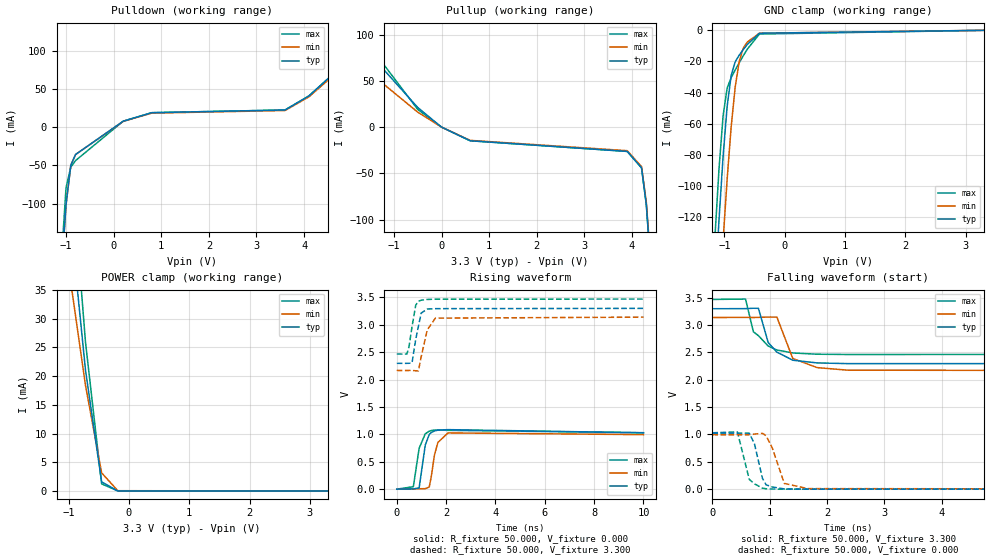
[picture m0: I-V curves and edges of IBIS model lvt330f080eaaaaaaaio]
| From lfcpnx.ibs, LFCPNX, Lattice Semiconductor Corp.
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[Model] lvt330f080eaaaaaaaio
Model_type I/O
Polarity   Non-Inverting
Enable   Active-Low
Vinl =  0.800V
Vinh =  2.000V
Vmeas =  1.650V
Cref =  0.0F
Rref =  1.000M
Vref =  0.0V
C_comp   5.000pF   4.000pF   5.500pF
[Temperature Range]   25.000   0.125k   -40.000
[Voltage Range]   3.300V   3.140V   3.470V
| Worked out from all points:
|   slope of the pulldown table from 0 to 0.495 V, typ, clamps not added: 31.5 ohm
|   slope of the pullup table from 0 to 0.495 V, typ, clamps not added: 39 ohm
|   GND clamp passes 1 mA (typ) near -0.37 V on its own axis
|   POWER clamp passes 1 mA (typ) near -0.42 V on its own axis
|   rising waveform, R_fixture 50.000, V_fixture 0.000: 20-80 % time 189ps typ, 233ps min, 215ps max; typ from 0 V to 1.03 V
|   rising waveform, R_fixture 50.000, V_fixture 3.300: 20-80 % time 231ps typ, 297ps min, 205ps max; typ from 2.3 V to 3.3 V
|   falling waveform, R_fixture 50.000, V_fixture 3.300: 20-80 % time 274ps typ, 223ps min, 282ps max; typ from 3.3 V to 2.3 V
|   falling waveform, R_fixture 50.000, V_fixture 0.000: 20-80 % time 135ps typ, 175ps min, 139ps max; typ from 1.02 V to 0 V
[GND_clamp]
|Voltage   I(typ)   I(min)   I(max)
-3.3V     -1.887A    -1.873A    -1.902A
-1.156V   -166.9mA   -224mA     -132.1mA
-1.089V   -121.5mA   -178.4mA   -88.64mA
-1.022V   -81.05mA   -135.2mA   -54.94mA
-955mV    -48.98mA   -95.79mA   -37.15mA
-888mV    -28.98mA   -62.05mA   -30.42mA
-821mV    -20.23mA   -36.35mA   -25.49mA
-754mV    -15.89mA   -19.89mA   -20.81mA
-687mV    -12.34mA   -11.44mA   -16.31mA
-620mV    -9.094mA   -7.515mA   -12.09mA
-419mV    -1.869mA   -1.836mA   -2.383mA
3.3V      0A         0A         0A
[POWER_clamp]
|Voltage   I(typ)   I(min)   I(max)
-3.3V     170.3mA    115.9mA    227.4mA
-2.998V   139.6mA    100.3mA    196.3mA
-2.797V   125.9mA    92.2mA     179.4mA
-2.596V   123.5mA    86.45mA    171.5mA
-1.993V   123.5mA    84.93mA    171.5mA
-1.792V   123.5mA    84.93mA    159.6mA
-1.658V   116.4mA    83.68mA    147.1mA
-1.457V   98.28mA    72.65mA    124.1mA
-720mV    21.08mA    18.41mA    25.96mA
-452mV    1.573mA    3.148mA    1.229mA
-184mV    5.589uA    37.85uA    1.612uA
3.3V      0A         0A         0A
[Pulldown]
|Voltage   I(typ)   I(min)   I(max)
-3.3V     -3.025A    -3.025A    -3.918A
-1.1V     -192.9mA   -192.9mA   -175.3mA
-1V       -101.2mA   -101.2mA   -78.95mA
-900mV    -49.86mA   -49.86mA   -52.21mA
-800mV    -35.81mA   -35.81mA   -43.74mA
200mV     7.775mA    7.542mA    7.775mA
800mV     18.91mA    18.34mA    18.91mA
3.6V      22.45mA    21.77mA    22.45mA
4.1V      40.8mA     39.58mA    40.8mA
5.4V      113.7mA    110.3mA    113.7mA
6.1V      131.6mA    127.7mA    131.6mA
6.6V      184.5mA    179mA      184.5mA
[Pullup]
|Voltage   I(typ)   I(min)   I(max)
-3.3V     161.3mA    100.5mA    206.1mA
-2.7V     107.3mA    82.8mA     139.1mA
-2.1V     105.4mA    77.74mA    116.8mA
-1.8V     95.7mA     71.14mA    107.4mA
-500mV    21.21mA    16.16mA    19.08mA
0V        28.62nA    228.6nA    28.62nA
600mV     -14.73mA   -14.29mA   -14.73mA
3.9V      -26.24mA   -25.45mA   -26.24mA
4.2V      -44.05mA   -42.73mA   -44.05mA
4.3V      -83.6mA    -81.1mA    -83.6mA
4.4V      -155.9mA   -151.2mA   -155.9mA
6.6V      -2.415A    -2.343A    -2.415A
[Ramp]
| variable   typ   min   max
dV/dt_r   0.619/0.189n   0.598/0.239n   0.634/0.215n
dV/dt_f   0.602/0.274n   0.584/0.222n   0.602/0.283n
R_load = 50.000
[Rising Waveform]
R_fixture = 50.000
V_fixture = 0.000
V_fixture_min = 0.000
V_fixture_max = 0.000
|  time   V(typ)   V(min)   V(max)
0s        488.9uV    1.198mV    488.9uV
672ps     5.302mV    1.318mV    45.99mV
906ps     23.45mV    8.626mV    746.7mV
1.155ns   806.3mV    9.222mV    1.011V
1.316ns   998.5mV    38.7mV     1.059V
1.396ns   1.034V     225.5mV    1.07V
1.526ns   1.063V     621.8mV    1.078V
1.666ns   1.077V     852.9mV    1.081V
2.076ns   1.087V     1.027V     1.074V
10ns      1.029V     995.8mV    1.031V
[Rising Waveform]
R_fixture = 50.000
V_fixture = 3.300
V_fixture_min = 3.140
V_fixture_max = 3.470
|  time   V(typ)   V(min)   V(max)
0s        2.297V     2.167V     2.467V
409ps     2.297V     2.166V     2.466V
497ps     2.298V     2.167V     2.603V
618ps     2.305V     2.168V     2.966V
768ps     2.735V     2.161V     3.359V
876ps     2.969V     2.159V     3.429V
988ps     3.213V     2.413V     3.449V
1.236ns   3.288V     2.909V     3.463V
1.566ns   3.295V     3.122V     3.468V
10ns      3.3V       3.14V      3.47V
[Falling Waveform]
R_fixture = 50.000
V_fixture = 3.300
V_fixture_min = 3.140
V_fixture_max = 3.470
|  time   V(typ)   V(min)   V(max)
0s        3.3V       3.14V      3.47V
579ps     3.302V     3.141V     3.477V
716ps     3.309V     3.14V      2.878V
804ps     3.307V     3.142V     2.807V
974ps     2.682V     3.148V     2.618V
1.126ns   2.507V     3.147V     2.545V
1.404ns   2.358V     2.389V     2.491V
1.829ns   2.309V     2.223V     2.468V
2.368ns   2.296V     2.176V     2.463V
10ns      2.297V     2.167V     2.467V
[Falling Waveform]
R_fixture = 50.000
V_fixture = 0.000
V_fixture_min = 0.000
V_fixture_max = 0.000
|  time   V(typ)   V(min)   V(max)
0s        1.024V     995.8mV    1.031V
437ps     1.024V     995.3mV    1.047V
644ps     1.024V     995.7mV    177.8mV
735ps     827.8mV    1.007V     97.26mV
874ps     198.8mV    1.021V     18.01mV
936ps     80.74mV    978.4mV    7.393mV
1.042ns   39.99mV    763.6mV    1.796mV
1.256ns   3.849mV    104.5mV    -164.9uV
1.666ns   265.6uV    9.589mV    -511.1uV
10ns      342.9uV    1.198mV    488.9uV
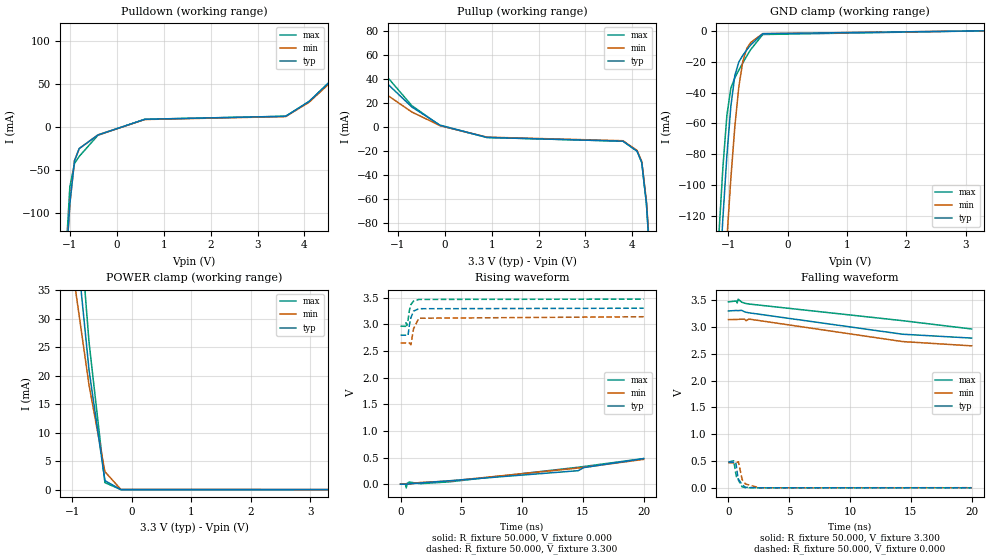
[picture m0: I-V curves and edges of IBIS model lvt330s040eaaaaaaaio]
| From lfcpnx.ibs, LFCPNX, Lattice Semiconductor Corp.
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[Model] lvt330s040eaaaaaaaio
Model_type I/O
Polarity   Non-Inverting
Enable   Active-Low
Vinl =  0.800V
Vinh =  2.000V
Vmeas =  1.650V
Cref =  0.0F
Rref =  1.000M
Vref =  0.0V
C_comp   5.000pF   4.000pF   5.500pF
[Temperature Range]   25.000   0.125k   -40.000
[Voltage Range]   3.300V   3.140V   3.470V
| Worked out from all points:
|   slope of the pulldown table from 0 to 0.495 V, typ, clamps not added: 60 ohm
|   slope of the pullup table from 0 to 0.495 V, typ, clamps not added: 81.7 ohm
|   GND clamp passes 1 mA (typ) near -0.37 V on its own axis
|   POWER clamp passes 1 mA (typ) near -0.42 V on its own axis
|   rising waveform, R_fixture 50.000, V_fixture 0.000: 20-80 % time 10.6ns typ, 11.1ns min, 10.8ns max; typ from 0.001 V to 0.481 V
|   rising waveform, R_fixture 50.000, V_fixture 3.300: 20-80 % time 278ps typ, 325ps min, 243ps max; typ from 2.79 V to 3.3 V
|   falling waveform, R_fixture 50.000, V_fixture 3.300: 20-80 % time 9.24ns typ, 8.7ns min, 11.8ns max; typ from 3.3 V to 2.79 V
|   falling waveform, R_fixture 50.000, V_fixture 0.000: 20-80 % time 340ps typ, 298ps min, 354ps max; typ from 0.481 V to 0.001 V
[GND_clamp]
|Voltage   I(typ)   I(min)   I(max)
-3.3V     -1.887A    -1.873A    -1.902A
-1.156V   -166.9mA   -224mA     -132.1mA
-1.089V   -121.5mA   -178.4mA   -88.64mA
-1.022V   -81.05mA   -135.2mA   -54.94mA
-955mV    -48.98mA   -95.79mA   -37.15mA
-888mV    -28.98mA   -62.05mA   -30.42mA
-821mV    -20.23mA   -36.35mA   -25.49mA
-754mV    -15.89mA   -19.89mA   -20.81mA
-687mV    -12.34mA   -11.44mA   -16.31mA
-620mV    -9.094mA   -7.515mA   -12.09mA
-419mV    -1.869mA   -1.836mA   -2.383mA
3.3V      0A         0A         0A
[POWER_clamp]
|Voltage   I(typ)   I(min)   I(max)
-3.3V     170.3mA    115.9mA    227.4mA
-2.998V   139.6mA    100.3mA    196.3mA
-2.797V   125.9mA    92.2mA     179.4mA
-2.596V   123.5mA    86.45mA    171.5mA
-1.993V   123.5mA    84.93mA    171.5mA
-1.792V   123.5mA    84.93mA    159.6mA
-1.658V   116.4mA    83.68mA    147.1mA
-1.457V   98.28mA    72.65mA    124.1mA
-720mV    21.08mA    18.41mA    25.96mA
-452mV    1.573mA    3.148mA    1.229mA
-184mV    5.589uA    37.85uA    1.612uA
3.3V      0A         0A         0A
[Pulldown]
|Voltage   I(typ)   I(min)   I(max)
-3.3V     -2.819A    -2.819A    -3.761A
-1.1V     -176.5mA   -176.5mA   -165mA
-1V       -89.5mA    -89.5mA    -70.05mA
-900mV    -39.31mA   -39.31mA   -42.55mA
-800mV    -25.23mA   -25.23mA   -34.36mA
-400mV    -9.281mA   -9.281mA   -9.631mA
600mV     8.924mA    8.657mA    8.924mA
3.6V      12.44mA    12.06mA    12.44mA
4.1V      29.71mA    28.82mA    29.71mA
5.4V      97.6mA     94.7mA     97.6mA
6.2V      121.3mA    117.7mA    121.3mA
6.6V      164mA      159.1mA    164mA
[Pullup]
|Voltage   I(typ)   I(min)   I(max)
-3.3V     109.3mA    67.7mA     140.2mA
-3V       86.1mA     60.5mA     117.8mA
-2V       65.1mA     47.62mA    77.3mA
-700mV    16.69mA    12.48mA    17.82mA
-100mV    1.509mA    1.116mA    1.148mA
900mV     -8.797mA   -8.533mA   -8.797mA
3.8V      -11.91mA   -11.55mA   -11.91mA
4.1V      -20.24mA   -19.64mA   -20.24mA
4.2V      -29.72mA   -28.83mA   -29.72mA
4.3V      -64.2mA    -62.3mA    -64.2mA
4.4V      -124.9mA   -121.2mA   -124.9mA
6.6V      -1.98A     -1.92A     -1.98A
[Ramp]
| variable   typ   min   max
dV/dt_r   0.288/10.429n   0.278/11.102n   0.288/10.769n
dV/dt_f   0.304/9.264n   0.295/8.716n   0.304/11.811n
R_load = 50.000
[Rising Waveform]
R_fixture = 50.000
V_fixture = 0.000
V_fixture_min = 0.000
V_fixture_max = 0.000
|  time   V(typ)   V(min)   V(max)
0s        707.6uV    2.066mV    707.6uV
395ps     834.9uV    1.474mV    3.679mV
474ps     984.1uV    1.992mV    -67.5mV
548ps     2.012mV    2.189mV    18.51mV
716ps     6.953mV    2.83mV     41.63mV
1.616ns   23.71mV    33.92mV    10.96mV
4.056ns   66.05mV    60.85mV    45.64mV
14.61ns   254.4mV    303.7mV    318.9mV
15.09ns   313.3mV    317.3mV    333.4mV
20ns      481mV      466.2mV    481.4mV
[Rising Waveform]
R_fixture = 50.000
V_fixture = 3.300
V_fixture_min = 3.140
V_fixture_max = 3.470
|  time   V(typ)   V(min)   V(max)
0s        2.794V     2.649V     2.964V
403ps     2.794V     2.648V     2.959V
454ps     2.794V     2.649V     3.028V
517ps     2.793V     2.649V     2.975V
617ps     2.788V     2.649V     3.071V
727ps     2.982V     2.65V      3.258V
856ps     3.123V     2.615V     3.369V
1.072ns   3.246V     2.915V     3.434V
1.506ns   3.29V      3.112V     3.464V
20ns      3.3V       3.14V      3.47V
[Falling Waveform]
R_fixture = 50.000
V_fixture = 3.300
V_fixture_min = 3.140
V_fixture_max = 3.470
|  time   V(typ)   V(min)   V(max)
0s        3.3V       3.14V      3.47V
669ps     3.31V      3.141V     3.487V
718ps     3.308V     3.141V     3.45V
799ps     3.306V     3.143V     3.521V
1.088ns   3.312V     3.147V     3.465V
1.339ns   3.283V     3.146V     3.445V
1.446ns   3.276V     3.118V     3.439V
1.686ns   3.266V     3.149V     3.43V
14.32ns   2.866V     2.729V     3.119V
20ns      2.794V     2.649V     2.964V
[Falling Waveform]
R_fixture = 50.000
V_fixture = 0.000
V_fixture_min = 0.000
V_fixture_max = 0.000
|  time   V(typ)   V(min)   V(max)
0s        481mV      466.2mV    481.4mV
433ps     476.6mV    465.6mV    503.8mV
587ps     485.1mV    465.4mV    290.4mV
653ps     399.2mV    466.5mV    208.5mV
750ps     240.2mV    480.1mV    208.8mV
826ps     160.9mV    486.9mV    140.3mV
1.124ns   57.76mV    154.8mV    18.67mV
1.398ns   9.89mV     70.36mV    1.886mV
2.569ns   -5.161uV   372.8uV    -949.1uV
20ns      707.6uV    2.066mV    707.6uV
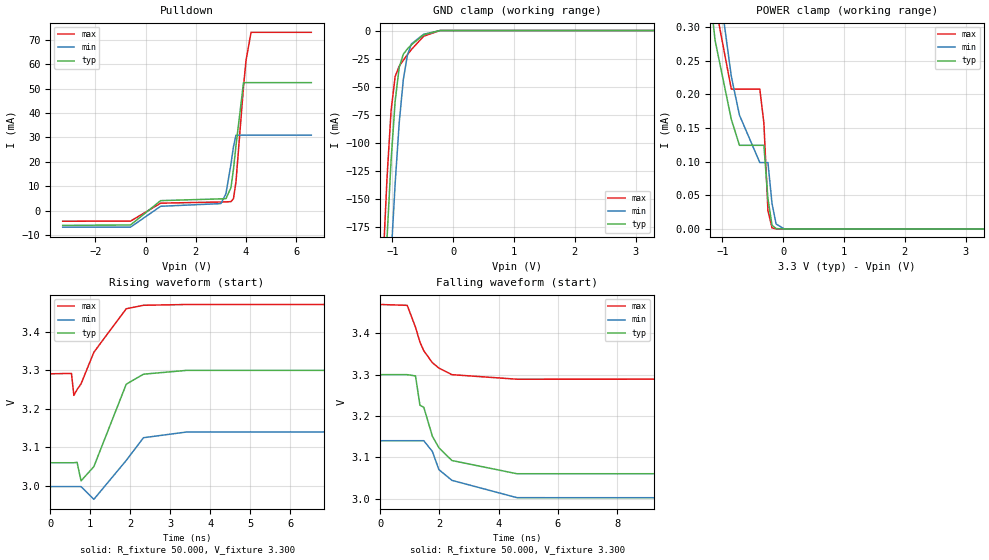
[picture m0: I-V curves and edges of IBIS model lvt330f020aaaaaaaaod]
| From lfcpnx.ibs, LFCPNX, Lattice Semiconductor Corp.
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[Model] lvt330f020aaaaaaaaod
Model_type I/O_open_drain
Polarity   Non-Inverting
Enable   Active-Low
Vinl =  0.800V
Vinh =  2.000V
Vmeas =  1.650V
Cref =  0.0F
Rref = 10.00k
Vref = 3.30V
C_comp   5.000pF   4.000pF   5.500pF
[Temperature Range]   25.000   0.125k   -40.000
[Voltage Range]   3.300V   3.140V   3.470V
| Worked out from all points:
|   slope of the pulldown table from 0 to 0.495 V, typ, clamps not added: 109 ohm
|   GND clamp passes 1 mA (typ) near -0.37 V on its own axis
|   POWER clamp passes 1 mA (typ) near -1.97 V on its own axis
|   rising waveform, R_fixture 50.000, V_fixture 3.300: 20-80 % time 481ps typ, 398ps min, 476ps max; typ from 3.06 V to 3.3 V
|   falling waveform, R_fixture 50.000, V_fixture 3.300: 20-80 % time 877ps typ, 983ps min, 662ps max; typ from 3.3 V to 3.06 V
[Pulldown]
|Voltage   I(typ)   I(min)   I(max)
-3.3V     -6.1mA     -6.828mA   -4.397mA
-600mV    -5.938mA   -6.828mA   -4.356mA
600mV     4.055mA    1.736mA    3.013mA
3V        4.784mA    2.841mA    3.498mA
3.2V      4.869mA    6.91mA     3.547mA
3.4V      9.372mA    19.03mA    3.637mA
3.5V      16.94mA    26.16mA    4.859mA
3.6V      26.54mA    30.91mA    11.78mA
3.9V      52.48mA    30.91mA    50.88mA
4V        52.48mA    30.91mA    61.61mA
4.2V      52.48mA    30.91mA    73.11mA
6.6V      52.48mA    30.91mA    73.11mA
[GND_clamp]
|Voltage   I(typ)   I(min)   I(max)
-3.3V     -3.196A    -3.085A    -3.285A
-1.156V   -263.4mA   -349.2mA   -208.8mA
-1.089V   -185mA     -273mA     -131.1mA
-1.022V   -115.6mA   -200.9mA   -71.22mA
-955mV    -62.66mA   -135.8mA   -40.8mA
-888mV    -32.65mA   -81.84mA   -31.68mA
-821mV    -21.14mA   -43.74mA   -26.44mA
-754mV    -16.35mA   -21.98mA   -21.55mA
-687mV    -12.66mA   -11.95mA   -16.87mA
-486mV    -3.804mA   -3.298mA   -5.059mA
-218mV    -16.55uA   -69.58uA   -6.785uA
3.3V      0A         0A         0A
[POWER_clamp]
|Voltage   I(typ)   I(min)   I(max)
-3.3V     35.46mA    6.588mA    71.29mA
-1.256V   395.7uA    489.5uA    429.4uA
-1.122V   280.6uA    406.7uA    335.7uA
-854mV    162.9uA    226.8uA    207.8uA
-720mV    124.3uA    169.1uA    207.8uA
-385mV    124.3uA    98.63uA    207.8uA
-318mV    124.3uA    98.63uA    157.6uA
-251mV    44.78uA    98.63uA    27.33uA
-184mV    5.589uA    37.86uA    1.613uA
-117mV    514.3nA    7.403uA    125nA
17mV      25.29nA    128.2nA    39.1nA
3.3V      0A         0A         0A
[Ramp]
| variable   typ   min   max
dV/dt_r   0.144/0.483n   85.097m/0.400n   0.107/0.480n
dV/dt_f   0.144/0.877n   85.101m/0.983n   0.107/0.673n
R_load = 50.000
[Rising Waveform]
R_fixture= 50.000
V_fixture= 3.300
V_fixture_min= 3.140
V_fixture_max= 3.470
|time   V(typ)   V(min)   V(max)
0s        3.06V      2.998V     3.291V
530ps     3.06V      2.998V     3.292V
590ps     3.06V      2.998V     3.235V
670ps     3.061V     2.998V     3.25V
770ps     3.013V     2.998V     3.265V
1.09ns    3.05V      2.965V     3.347V
1.9ns     3.264V     3.066V     3.46V
2.33ns    3.29V      3.125V     3.469V
3.42ns    3.3V       3.14V      3.471V
200ns     3.3V       3.14V      3.47V
[Falling Waveform]
R_fixture= 50.000
V_fixture= 3.300
V_fixture_min= 3.140
V_fixture_max= 3.470
|time   V(typ)   V(min)   V(max)
0s        3.3V       3.14V      3.47V
910ps     3.3V       3.14V      3.468V
1.19ns    3.297V     3.14V      3.415V
1.34ns    3.226V     3.14V      3.379V
1.47ns    3.221V     3.14V      3.358V
1.76ns    3.151V     3.114V     3.329V
1.98ns    3.123V     3.07V      3.316V
2.42ns    3.092V     3.044V     3.3V
4.62ns    3.06V      3.002V     3.289V
200ns     3.06V      2.998V     3.291V
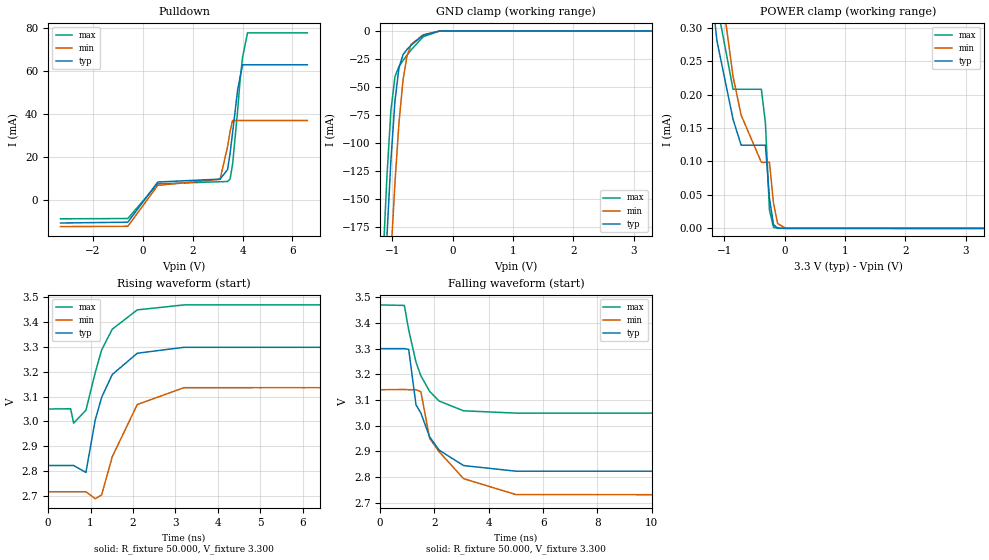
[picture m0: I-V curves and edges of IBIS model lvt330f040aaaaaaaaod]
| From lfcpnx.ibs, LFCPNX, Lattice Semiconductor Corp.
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[Model] lvt330f040aaaaaaaaod
Model_type I/O_open_drain
Polarity   Non-Inverting
Enable   Active-Low
Vinl =  0.800V
Vinh =  2.000V
Vmeas =  1.650V
Cref =  0.0F
Rref = 10.00k
Vref = 3.30V
C_comp   5.000pF   4.000pF   5.500pF
[Temperature Range]   25.000   0.125k   -40.000
[Voltage Range]   3.300V   3.140V   3.470V
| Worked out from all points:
|   slope of the pulldown table from 0 to 0.495 V, typ, clamps not added: 58.8 ohm
|   GND clamp passes 1 mA (typ) near -0.37 V on its own axis
|   POWER clamp passes 1 mA (typ) near -1.97 V on its own axis
|   rising waveform, R_fixture 50.000, V_fixture 3.300: 20-80 % time 553ps typ, 632ps min, 530ps max; typ from 2.82 V to 3.3 V
|   falling waveform, R_fixture 50.000, V_fixture 3.300: 20-80 % time 932ps typ, 1.33ns min, 830ps max; typ from 3.3 V to 2.82 V
[Pulldown]
|Voltage   I(typ)   I(min)   I(max)
-3.3V     -10.75mA   -12.42mA   -8.803mA
-600mV    -10.38mA   -12.29mA   -8.676mA
600mV     8.285mA    6.713mA    7.445mA
3.1V      9.636mA    9.533mA    8.415mA
3.4V      14.05mA    24.72mA    8.529mA
3.5V      21.55mA    31.81mA    9.666mA
3.6V      31.11mA    36.84mA    16.44mA
3.8V      50.78mA    36.84mA    40.96mA
3.9V      56.98mA    36.84mA    55.4mA
4V        62.74mA    36.84mA    66.09mA
4.2V      62.74mA    36.84mA    77.58mA
6.6V      62.74mA    36.84mA    77.58mA
[GND_clamp]
|Voltage   I(typ)   I(min)   I(max)
-3.3V     -3.196A    -3.085A    -3.285A
-1.156V   -263.4mA   -349.2mA   -208.8mA
-1.089V   -185mA     -273mA     -131.1mA
-1.022V   -115.6mA   -200.9mA   -71.22mA
-955mV    -62.66mA   -135.8mA   -40.8mA
-888mV    -32.65mA   -81.84mA   -31.68mA
-821mV    -21.14mA   -43.74mA   -26.44mA
-754mV    -16.35mA   -21.98mA   -21.55mA
-687mV    -12.66mA   -11.95mA   -16.87mA
-486mV    -3.804mA   -3.298mA   -5.059mA
-218mV    -16.55uA   -69.58uA   -6.785uA
3.3V      0A         0A         0A
[POWER_clamp]
|Voltage   I(typ)   I(min)   I(max)
-3.3V     35.46mA    6.588mA    71.29mA
-1.256V   395.7uA    489.5uA    429.4uA
-1.122V   280.6uA    406.7uA    335.7uA
-854mV    162.9uA    226.8uA    207.8uA
-720mV    124.3uA    169.1uA    207.8uA
-385mV    124.3uA    98.63uA    207.8uA
-318mV    124.3uA    98.63uA    157.6uA
-251mV    44.78uA    98.63uA    27.33uA
-184mV    5.589uA    37.86uA    1.613uA
-117mV    514.3nA    7.403uA    125nA
17mV      25.29nA    128.2nA    39.1nA
3.3V      0A         0A         0A
[Ramp]
| variable   typ   min   max
dV/dt_r   0.287/0.551n   0.254/0.629n   0.252/0.533n
dV/dt_f   0.287/0.938n   0.254/1.339n   0.252/0.833n
R_load = 50.000
[Rising Waveform]
R_fixture= 50.000
V_fixture= 3.300
V_fixture_min= 3.140
V_fixture_max= 3.470
|time   V(typ)   V(min)   V(max)
0s        2.822V     2.716V     3.05V
530ps     2.822V     2.716V     3.051V
600ps     2.822V     2.716V     2.993V
890ps     2.794V     2.716V     3.045V
1.11ns    3.006V     2.688V     3.197V
1.26ns    3.097V     2.703V     3.288V
1.51ns    3.189V     2.857V     3.372V
2.1ns     3.275V     3.068V     3.45V
3.2ns     3.299V     3.136V     3.47V
200ns     3.3V       3.14V      3.47V
[Falling Waveform]
R_fixture= 50.000
V_fixture= 3.300
V_fixture_min= 3.140
V_fixture_max= 3.470
|time   V(typ)   V(min)   V(max)
0s        3.3V       3.14V      3.47V
890ps     3.3V       3.141V     3.468V
1.05ns    3.297V     3.14V      3.373V
1.32ns    3.081V     3.14V      3.247V
1.5ns     3.049V     3.132V     3.194V
1.82ns    2.957V     2.951V     3.134V
2.17ns    2.905V     2.899V     3.096V
3.07ns    2.845V     2.794V     3.058V
5ns       2.823V     2.732V     3.049V
200ns     2.822V     2.716V     3.05V
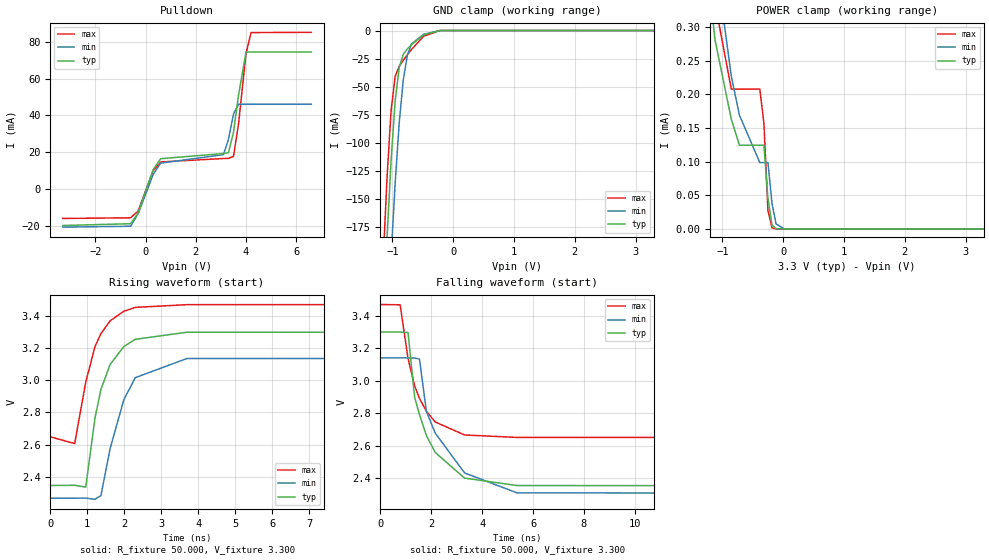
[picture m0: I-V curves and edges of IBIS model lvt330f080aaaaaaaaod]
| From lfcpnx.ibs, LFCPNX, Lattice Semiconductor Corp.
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[Model] lvt330f080aaaaaaaaod
Model_type I/O_open_drain
Polarity   Non-Inverting
Enable   Active-Low
Vinl =  0.800V
Vinh =  2.000V
Vmeas =  1.650V
Cref =  0.0F
Rref = 10.00k
Vref = 3.30V
C_comp   5.000pF   4.000pF   5.500pF
[Temperature Range]   25.000   0.125k   -40.000
[Voltage Range]   3.300V   3.140V   3.470V
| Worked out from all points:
|   slope of the pulldown table from 0 to 0.495 V, typ, clamps not added: 31.5 ohm
|   GND clamp passes 1 mA (typ) near -0.37 V on its own axis
|   POWER clamp passes 1 mA (typ) near -1.97 V on its own axis
|   rising waveform, R_fixture 50.000, V_fixture 3.300: 20-80 % time 554ps typ, 641ps min, 608ps max; typ from 2.35 V to 3.3 V
|   falling waveform, R_fixture 50.000, V_fixture 3.300: 20-80 % time 1.06ns typ, 1.55ns min, 918ps max; typ from 3.3 V to 2.35 V
[Pulldown]
|Voltage   I(typ)   I(min)   I(max)
-3.3V     -19.92mA   -20.81mA   -16.08mA
-600mV    -18.94mA   -20.31mA   -15.72mA
-300mV    -13.23mA   -13.68mA   -12.11mA
300mV     10.36mA    7.766mA    9.808mA
600mV     16.42mA    13.99mA    14.64mA
3.1V      19.21mA    18.6mA     16.51mA
3.3V      19.71mA    26.92mA    16.57mA
3.5V      30.71mA    40.56mA    17.63mA
3.7V      50.79mA    46mA       35.14mA
4V        74.37mA    46mA       73.51mA
4.2V      74.37mA    46mA       84.98mA
6.6V      74.37mA    46mA       85.11mA
[GND_clamp]
|Voltage   I(typ)   I(min)   I(max)
-3.3V     -3.196A    -3.085A    -3.285A
-1.156V   -263.4mA   -349.2mA   -208.8mA
-1.089V   -185mA     -273mA     -131.1mA
-1.022V   -115.6mA   -200.9mA   -71.22mA
-955mV    -62.66mA   -135.8mA   -40.8mA
-888mV    -32.65mA   -81.84mA   -31.68mA
-821mV    -21.14mA   -43.74mA   -26.44mA
-754mV    -16.35mA   -21.98mA   -21.55mA
-687mV    -12.66mA   -11.95mA   -16.87mA
-486mV    -3.804mA   -3.298mA   -5.059mA
-218mV    -16.55uA   -69.58uA   -6.785uA
3.3V      0A         0A         0A
[POWER_clamp]
|Voltage   I(typ)   I(min)   I(max)
-3.3V     35.46mA    6.588mA    71.29mA
-1.256V   395.9uA    489.5uA    429.4uA
-1.122V   280.8uA    406.7uA    335.7uA
-854mV    163uA      226.8uA    207.8uA
-720mV    124.4uA    169.1uA    207.8uA
-385mV    124.4uA    98.63uA    207.8uA
-318mV    124.4uA    98.63uA    157.6uA
-251mV    44.78uA    98.63uA    27.33uA
-184mV    5.589uA    37.86uA    1.613uA
-117mV    514.3nA    7.403uA    125nA
17mV      25.29nA    128.2nA    39.1nA
3.3V      0A         0A         0A
[Ramp]
| variable   typ   min   max
dV/dt_r   0.572/0.555n   0.523/0.639n   0.493/0.609n
dV/dt_f   0.572/1.070n   0.523/1.557n   0.493/0.921n
R_load = 50.000
[Rising Waveform]
R_fixture= 50.000
V_fixture= 3.300
V_fixture_min= 3.140
V_fixture_max= 3.470
|time   V(typ)   V(min)   V(max)
0s        2.347V     2.268V     2.649V
660ps     2.348V     2.268V     2.607V
960ps     2.337V     2.269V     2.988V
1.21ns    2.766V     2.261V     3.209V
1.37ns    2.943V     2.284V     3.289V
1.62ns    3.098V     2.577V     3.369V
1.99ns    3.209V     2.879V     3.428V
2.3ns     3.254V     3.016V     3.452V
3.7ns     3.298V     3.135V     3.469V
200ns     3.3V       3.14V      3.47V
[Falling Waveform]
R_fixture= 50.000
V_fixture= 3.300
V_fixture_min= 3.140
V_fixture_max= 3.470
|time   V(typ)   V(min)   V(max)
0s        3.3V       3.14V      3.47V
780ps     3.3V       3.141V     3.468V
1.09ns    3.297V     3.14V      3.137V
1.35ns    2.897V     3.14V      2.968V
1.54ns    2.791V     3.133V     2.891V
1.81ns    2.662V     2.811V     2.811V
2.16ns    2.557V     2.676V     2.745V
3.31ns    2.399V     2.431V     2.665V
5.37ns    2.353V     2.308V     2.65V
200ns     2.347V     2.268V     2.649V
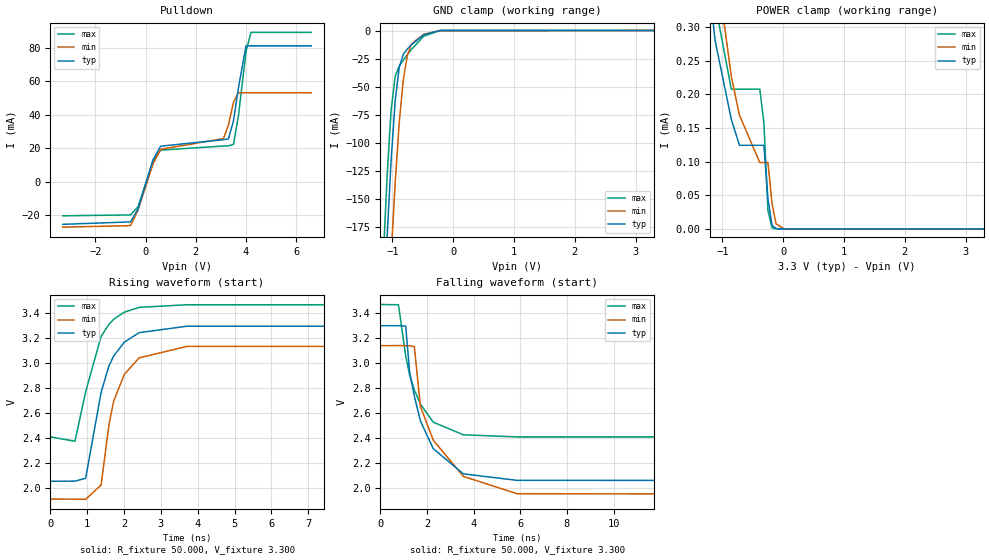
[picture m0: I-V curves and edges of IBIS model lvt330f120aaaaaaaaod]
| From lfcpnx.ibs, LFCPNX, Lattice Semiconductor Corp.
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[Model] lvt330f120aaaaaaaaod
Model_type I/O_open_drain
Polarity   Non-Inverting
Enable   Active-Low
Vinl =  0.800V
Vinh =  2.000V
Vmeas =  1.650V
Cref =  0.0F
Rref = 10.00k
Vref = 3.30V
C_comp   5.000pF   4.000pF   5.500pF
[Temperature Range]   25.000   0.125k   -40.000
[Voltage Range]   3.300V   3.140V   3.470V
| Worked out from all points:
|   slope of the pulldown table from 0 to 0.495 V, typ, clamps not added: 24.7 ohm
|   GND clamp passes 1 mA (typ) near -0.37 V on its own axis
|   POWER clamp passes 1 mA (typ) near -1.97 V on its own axis
|   rising waveform, R_fixture 50.000, V_fixture 3.300: 20-80 % time 609ps typ, 520ps min, 631ps max; typ from 2.05 V to 3.3 V
|   falling waveform, R_fixture 50.000, V_fixture 3.300: 20-80 % time 1.12ns typ, 1.56ns min, 970ps max; typ from 3.3 V to 2.05 V
[Pulldown]
|Voltage   I(typ)   I(min)   I(max)
-3.3V     -25.53mA   -27.22mA   -20.43mA
-600mV    -24.06mA   -26.3mA    -19.89mA
-300mV    -16.33mA   -16.99mA   -14.99mA
300mV     13.22mA    10.79mA    12.5mA
600mV     21.26mA    19.4mA     18.89mA
3.1V      25.16mA    25.81mA    21.38mA
3.3V      25.62mA    33.97mA    21.44mA
3.5V      36.41mA    47.57mA    22.42mA
3.7V      56.4mA     53.26mA    39.7mA
4V        81.32mA    53.26mA    77.97mA
4.2V      81.32mA    53.26mA    89.43mA
6.6V      81.32mA    53.26mA    89.43mA
[GND_clamp]
|Voltage   I(typ)   I(min)   I(max)
-3.3V     -3.196A    -3.085A    -3.285A
-1.156V   -263.4mA   -349.2mA   -208.8mA
-1.089V   -185mA     -273mA     -131.1mA
-1.022V   -115.6mA   -200.9mA   -71.22mA
-955mV    -62.66mA   -135.8mA   -40.8mA
-888mV    -32.65mA   -81.84mA   -31.68mA
-821mV    -21.14mA   -43.74mA   -26.44mA
-754mV    -16.35mA   -21.98mA   -21.55mA
-687mV    -12.66mA   -11.95mA   -16.87mA
-486mV    -3.804mA   -3.298mA   -5.059mA
-218mV    -16.55uA   -69.58uA   -6.785uA
3.3V      0A         0A         0A
[POWER_clamp]
|Voltage   I(typ)   I(min)   I(max)
-3.3V     35.46mA    6.588mA    71.29mA
-1.256V   395.7uA    489.5uA    429.4uA
-1.122V   280.6uA    406.7uA    335.7uA
-854mV    162.9uA    226.8uA    207.8uA
-720mV    124.3uA    169.1uA    207.8uA
-385mV    124.3uA    98.63uA    207.8uA
-318mV    124.3uA    98.63uA    157.6uA
-251mV    44.78uA    98.63uA    27.33uA
-184mV    5.589uA    37.86uA    1.613uA
-117mV    514.3nA    7.403uA    125nA
17mV      25.29nA    128.2nA    39.1nA
3.3V      0A         0A         0A
[Ramp]
| variable   typ   min   max
dV/dt_r   0.749/0.610n   0.739/0.520n   0.638/0.630n
dV/dt_f   0.749/1.123n   0.739/1.556n   0.637/0.973n
R_load = 50.000
[Rising Waveform]
R_fixture= 50.000
V_fixture= 3.300
V_fixture_min= 3.140
V_fixture_max= 3.470
|time   V(typ)   V(min)   V(max)
0s        2.052V     1.909V     2.408V
670ps     2.053V     1.908V     2.373V
960ps     2.076V     1.907V     2.77V
1.38ns    2.766V     2.022V     3.215V
1.59ns    2.976V     2.501V     3.31V
1.72ns    3.057V     2.695V     3.351V
2.01ns    3.168V     2.91V      3.409V
2.41ns    3.244V     3.042V     3.447V
3.71ns    3.296V     3.134V     3.468V
200ns     3.3V       3.14V      3.47V
[Falling Waveform]
R_fixture= 50.000
V_fixture= 3.300
V_fixture_min= 3.140
V_fixture_max= 3.470
|time   V(typ)   V(min)   V(max)
0s        3.3V       3.14V      3.47V
780ps     3.3V       3.141V     3.468V
1.09ns    3.297V     3.14V      3.057V
1.26ns    2.924V     3.14V      2.904V
1.46ns    2.736V     3.132V     2.785V
1.72ns    2.537V     2.653V     2.672V
2.27ns    2.315V     2.383V     2.527V
3.56ns    2.113V     2.093V     2.426V
5.86ns    2.061V     1.954V     2.409V
200ns     2.052V     1.909V     2.408V
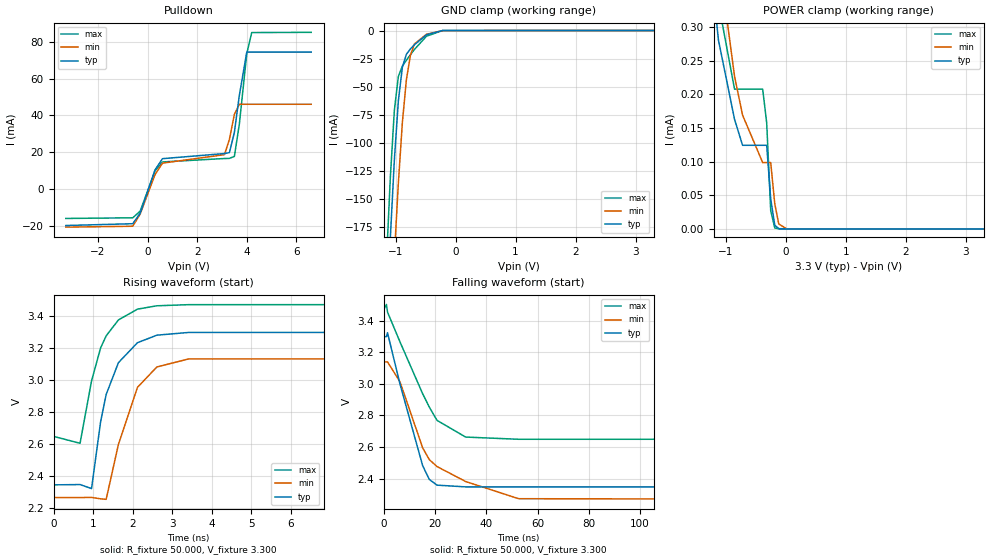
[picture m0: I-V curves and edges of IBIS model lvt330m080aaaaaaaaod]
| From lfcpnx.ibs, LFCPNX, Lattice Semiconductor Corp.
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[Model] lvt330m080aaaaaaaaod
Model_type I/O_open_drain
Polarity   Non-Inverting
Enable   Active-Low
Vinl =  0.800V
Vinh =  2.000V
Vmeas =  1.650V
Cref =  0.0F
Rref = 10.00k
Vref = 3.30V
C_comp   5.000pF   4.000pF   5.500pF
[Temperature Range]   25.000   0.125k   -40.000
[Voltage Range]   3.300V   3.140V   3.470V
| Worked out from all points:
|   slope of the pulldown table from 0 to 0.495 V, typ, clamps not added: 31.5 ohm
|   GND clamp passes 1 mA (typ) near -0.37 V on its own axis
|   POWER clamp passes 1 mA (typ) near -1.97 V on its own axis
|   rising waveform, R_fixture 50.000, V_fixture 3.300: 20-80 % time 553ps typ, 635ps min, 601ps max; typ from 2.35 V to 3.3 V
|   falling waveform, R_fixture 50.000, V_fixture 3.300: 20-80 % time 9.41ns typ, 17.1ns min, 13.8ns max; typ from 3.3 V to 2.35 V
[Pulldown]
|Voltage   I(typ)   I(min)   I(max)
-3.3V     -19.92mA   -20.81mA   -16.08mA
-600mV    -18.94mA   -20.31mA   -15.72mA
-300mV    -13.23mA   -13.68mA   -12.11mA
300mV     10.36mA    7.766mA    9.808mA
600mV     16.42mA    13.99mA    14.64mA
3.1V      19.21mA    18.6mA     16.51mA
3.3V      19.71mA    26.92mA    16.57mA
3.5V      30.71mA    40.56mA    17.63mA
3.7V      50.79mA    46mA       35.14mA
4V        74.37mA    46mA       73.51mA
4.2V      74.37mA    46mA       84.98mA
6.6V      74.37mA    46mA       85.11mA
[GND_clamp]
|Voltage   I(typ)   I(min)   I(max)
-3.3V     -3.196A    -3.085A    -3.285A
-1.156V   -263.4mA   -349.2mA   -208.8mA
-1.089V   -185mA     -273mA     -131.1mA
-1.022V   -115.6mA   -200.9mA   -71.22mA
-955mV    -62.66mA   -135.8mA   -40.8mA
-888mV    -32.65mA   -81.84mA   -31.68mA
-821mV    -21.14mA   -43.74mA   -26.44mA
-754mV    -16.35mA   -21.98mA   -21.55mA
-687mV    -12.66mA   -11.95mA   -16.87mA
-486mV    -3.804mA   -3.298mA   -5.059mA
-218mV    -16.55uA   -69.58uA   -6.785uA
3.3V      0A         0A         0A
[POWER_clamp]
|Voltage   I(typ)   I(min)   I(max)
-3.3V     35.46mA    6.588mA    71.29mA
-1.256V   395.7uA    489.5uA    429.4uA
-1.122V   280.6uA    406.7uA    335.7uA
-854mV    162.9uA    226.8uA    207.8uA
-720mV    124.3uA    169.1uA    207.8uA
-385mV    124.3uA    98.63uA    207.8uA
-318mV    124.3uA    98.63uA    157.6uA
-251mV    44.78uA    98.63uA    27.33uA
-184mV    5.589uA    37.86uA    1.613uA
-117mV    514.3nA    7.403uA    125nA
17mV      25.29nA    128.2nA    39.1nA
3.3V      0A         0A         0A
[Ramp]
| variable   typ   min   max
dV/dt_r   0.572/0.555n   0.523/0.635n   0.493/0.603n
dV/dt_f   0.572/9.521n   0.523/17.002n   0.493/13.795n
R_load = 50.000
[Rising Waveform]
R_fixture= 50.000
V_fixture= 3.300
V_fixture_min= 3.140
V_fixture_max= 3.470
|time   V(typ)   V(min)   V(max)
0s        2.347V     2.268V     2.649V
670ps     2.349V     2.268V     2.606V
960ps     2.324V     2.269V     2.994V
1.19ns    2.741V     2.26V      3.2V
1.33ns    2.91V      2.257V     3.275V
1.64ns    3.108V     2.6V       3.374V
2.12ns    3.232V     2.954V     3.441V
2.61ns    3.279V     3.081V     3.462V
3.41ns    3.296V     3.131V     3.469V
200ns     3.3V       3.14V      3.47V
[Falling Waveform]
R_fixture= 50.000
V_fixture= 3.300
V_fixture_min= 3.140
V_fixture_max= 3.470
|time   V(typ)   V(min)   V(max)
0s        3.3V       3.14V      3.47V
1.09ns    3.3V       3.14V      3.504V
1.5ns     3.325V     3.14V      3.456V
6.36ns    3V         3.014V     3.267V
15.2ns    2.482V     2.595V     2.938V
17.8ns    2.394V     2.52V      2.853V
20.8ns    2.358V     2.476V     2.769V
31.97ns   2.347V     2.381V     2.663V
52.63ns   2.347V     2.272V     2.649V
200ns     2.347V     2.268V     2.649V
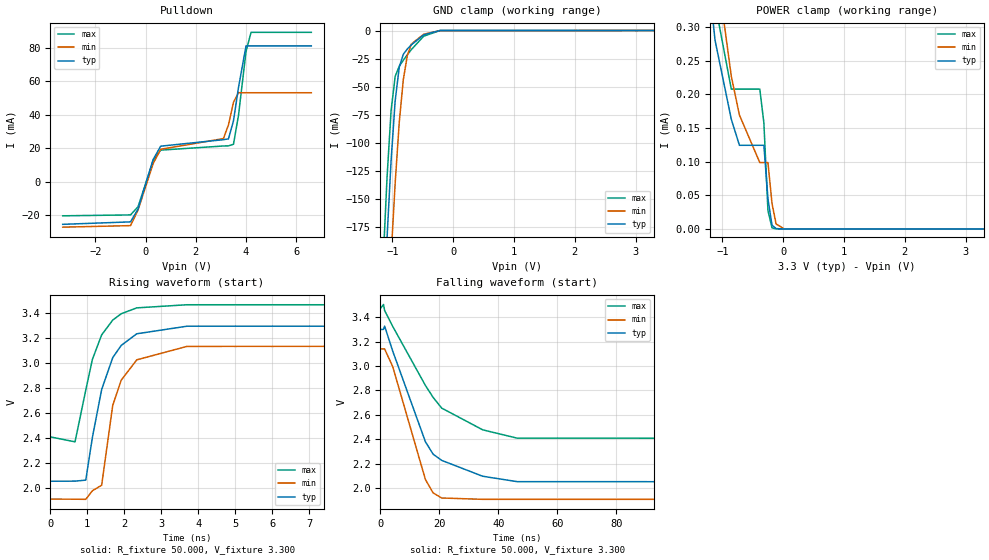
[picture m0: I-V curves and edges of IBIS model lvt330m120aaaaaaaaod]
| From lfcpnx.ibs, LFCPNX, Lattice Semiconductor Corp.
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[Model] lvt330m120aaaaaaaaod
Model_type I/O_open_drain
Polarity   Non-Inverting
Enable   Active-Low
Vinl =  0.800V
Vinh =  2.000V
Vmeas =  1.650V
Cref =  0.0F
Rref = 10.00k
Vref = 3.30V
C_comp   5.000pF   4.000pF   5.500pF
[Temperature Range]   25.000   0.125k   -40.000
[Voltage Range]   3.300V   3.140V   3.470V
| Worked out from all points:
|   slope of the pulldown table from 0 to 0.495 V, typ, clamps not added: 24.7 ohm
|   GND clamp passes 1 mA (typ) near -0.37 V on its own axis
|   POWER clamp passes 1 mA (typ) near -1.97 V on its own axis
|   rising waveform, R_fixture 50.000, V_fixture 3.300: 20-80 % time 605ps typ, 516ps min, 621ps max; typ from 2.05 V to 3.3 V
|   falling waveform, R_fixture 50.000, V_fixture 3.300: 20-80 % time 11.9ns typ, 8.5ns min, 16.9ns max; typ from 3.3 V to 2.05 V
[Pulldown]
|Voltage   I(typ)   I(min)   I(max)
-3.3V     -25.53mA   -27.22mA   -20.43mA
-600mV    -24.06mA   -26.3mA    -19.89mA
-300mV    -16.33mA   -16.99mA   -14.99mA
300mV     13.22mA    10.79mA    12.5mA
600mV     21.26mA    19.4mA     18.89mA
3.1V      25.16mA    25.81mA    21.38mA
3.3V      25.62mA    33.97mA    21.44mA
3.5V      36.41mA    47.56mA    22.42mA
3.7V      56.4mA     53.26mA    39.7mA
4V        81.32mA    53.26mA    77.97mA
4.2V      81.32mA    53.26mA    89.43mA
6.6V      81.32mA    53.26mA    89.43mA
[GND_clamp]
|Voltage   I(typ)   I(min)   I(max)
-3.3V     -3.196A    -3.085A    -3.285A
-1.156V   -263.4mA   -349.2mA   -208.8mA
-1.089V   -185mA     -273mA     -131.1mA
-1.022V   -115.6mA   -200.9mA   -71.22mA
-955mV    -62.66mA   -135.8mA   -40.8mA
-888mV    -32.65mA   -81.84mA   -31.68mA
-821mV    -21.14mA   -43.74mA   -26.44mA
-754mV    -16.35mA   -21.98mA   -21.55mA
-687mV    -12.66mA   -11.95mA   -16.87mA
-486mV    -3.804mA   -3.298mA   -5.059mA
-218mV    -16.55uA   -69.58uA   -6.785uA
3.3V      0A         0A         0A
[POWER_clamp]
|Voltage   I(typ)   I(min)   I(max)
-3.3V     35.46mA    6.588mA    71.29mA
-1.256V   395.7uA    489.5uA    429.4uA
-1.122V   280.6uA    406.7uA    335.7uA
-854mV    162.9uA    226.8uA    207.8uA
-720mV    124.3uA    169.1uA    207.8uA
-385mV    124.3uA    98.63uA    207.8uA
-318mV    124.3uA    98.63uA    157.6uA
-251mV    44.78uA    98.63uA    27.33uA
-184mV    5.589uA    37.86uA    1.613uA
-117mV    514.3nA    7.403uA    125nA
17mV      25.29nA    128.2nA    39.1nA
3.3V      0A         0A         0A
[Ramp]
| variable   typ   min   max
dV/dt_r   0.749/0.605n   0.739/0.520n   0.638/0.621n
dV/dt_f   0.749/12.049n   0.739/8.642n   0.637/16.948n
R_load = 50.000
[Rising Waveform]
R_fixture= 50.000
V_fixture= 3.300
V_fixture_min= 3.140
V_fixture_max= 3.470
|time   V(typ)   V(min)   V(max)
0s        2.052V     1.909V     2.408V
670ps     2.053V     1.908V     2.368V
960ps     2.061V     1.907V     2.783V
1.14ns    2.404V     1.976V     3.03V
1.39ns    2.788V     2.02V      3.226V
1.69ns    3.044V     2.661V     3.345V
1.92ns    3.142V     2.863V     3.396V
2.34ns    3.235V     3.026V     3.443V
3.7ns     3.296V     3.134V     3.468V
200ns     3.3V       3.14V      3.47V
[Falling Waveform]
R_fixture= 50.000
V_fixture= 3.300
V_fixture_min= 3.140
V_fixture_max= 3.470
|time   V(typ)   V(min)   V(max)
0s        3.3V       3.14V      3.47V
1.09ns    3.3V       3.14V      3.504V
1.47ns    3.327V     3.14V      3.455V
4.21ns    3.123V     2.996V     3.325V
15.3ns    2.38V      2.071V     2.841V
17.9ns    2.279V     1.962V     2.744V
20.8ns    2.228V     1.92V      2.656V
34.7ns    2.098V     1.909V     2.478V
46.34ns   2.054V     1.909V     2.41V
200ns     2.052V     1.909V     2.408V
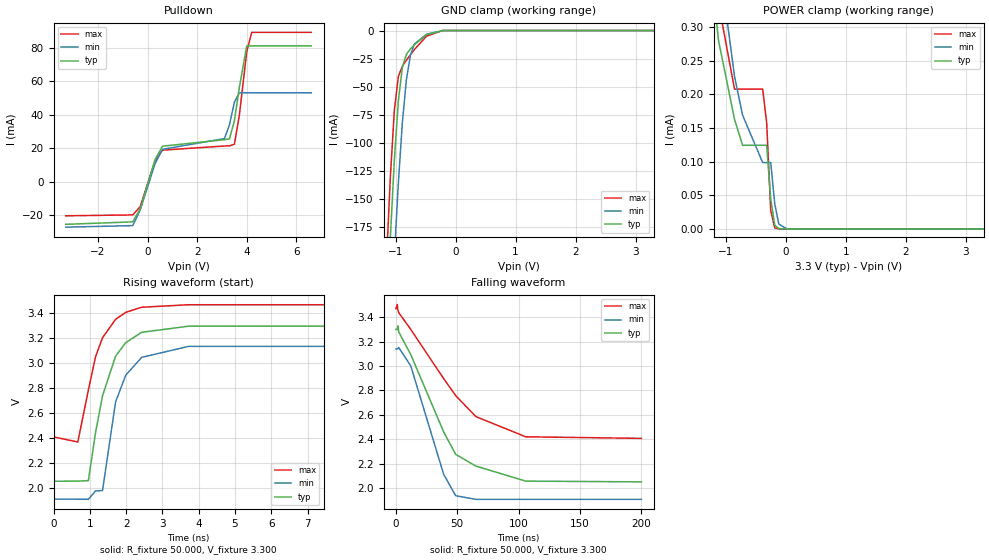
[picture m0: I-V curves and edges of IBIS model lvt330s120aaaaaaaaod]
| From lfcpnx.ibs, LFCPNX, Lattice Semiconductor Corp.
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[Model] lvt330s120aaaaaaaaod
Model_type I/O_open_drain
Polarity   Non-Inverting
Enable   Active-Low
Vinl =  0.800V
Vinh =  2.000V
Vmeas =  1.650V
Cref =  0.0F
Rref = 10.00k
Vref = 3.30V
C_comp   5.000pF   4.000pF   5.500pF
[Temperature Range]   25.000   0.125k   -40.000
[Voltage Range]   3.300V   3.140V   3.470V
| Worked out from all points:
|   slope of the pulldown table from 0 to 0.495 V, typ, clamps not added: 24.7 ohm
|   GND clamp passes 1 mA (typ) near -0.37 V on its own axis
|   POWER clamp passes 1 mA (typ) near -1.97 V on its own axis
|   rising waveform, R_fixture 50.000, V_fixture 3.300: 20-80 % time 606ps typ, 516ps min, 621ps max; typ from 2.05 V to 3.3 V
|   falling waveform, R_fixture 50.000, V_fixture 3.300: 20-80 % time 33ns typ, 21.8ns min, 45.5ns max; typ from 3.3 V to 2.05 V
[Pulldown]
|Voltage   I(typ)   I(min)   I(max)
-3.3V     -25.53mA   -27.22mA   -20.43mA
-600mV    -24.06mA   -26.3mA    -19.89mA
-300mV    -16.33mA   -16.99mA   -14.99mA
300mV     13.22mA    10.79mA    12.5mA
600mV     21.26mA    19.39mA    18.89mA
3.1V      25.16mA    25.81mA    21.38mA
3.3V      25.62mA    33.97mA    21.44mA
3.5V      36.4mA     47.56mA    22.42mA
3.7V      56.4mA     53.25mA    39.7mA
4V        81.32mA    53.25mA    77.97mA
4.2V      81.32mA    53.25mA    89.43mA
6.6V      81.32mA    53.25mA    89.43mA
[GND_clamp]
|Voltage   I(typ)   I(min)   I(max)
-3.3V     -3.196A    -3.085A    -3.285A
-1.156V   -263.4mA   -349.2mA   -208.8mA
-1.089V   -185mA     -273mA     -131.1mA
-1.022V   -115.6mA   -200.9mA   -71.22mA
-955mV    -62.66mA   -135.8mA   -40.8mA
-888mV    -32.65mA   -81.84mA   -31.68mA
-821mV    -21.14mA   -43.74mA   -26.44mA
-754mV    -16.35mA   -21.98mA   -21.55mA
-687mV    -12.66mA   -11.95mA   -16.87mA
-486mV    -3.804mA   -3.298mA   -5.059mA
-218mV    -16.55uA   -69.58uA   -6.785uA
3.3V      0A         0A         0A
[POWER_clamp]
|Voltage   I(typ)   I(min)   I(max)
-3.3V     35.46mA    6.588mA    71.29mA
-1.256V   395.7uA    489.5uA    429.4uA
-1.122V   280.6uA    406.7uA    335.7uA
-854mV    162.9uA    226.8uA    207.8uA
-720mV    124.3uA    169.1uA    207.8uA
-385mV    124.3uA    98.63uA    207.8uA
-318mV    124.3uA    98.63uA    157.6uA
-251mV    44.78uA    98.63uA    27.33uA
-184mV    5.589uA    37.86uA    1.613uA
-117mV    514.3nA    7.403uA    125nA
17mV      25.29nA    128.2nA    39.1nA
3.3V      0A         0A         0A
[Ramp]
| variable   typ   min   max
dV/dt_r   0.749/0.605n   0.739/0.521n   0.637/0.621n
dV/dt_f   0.749/33.231n   0.739/21.831n   0.637/46.124n
R_load = 50.000
[Rising Waveform]
R_fixture= 50.000
V_fixture= 3.300
V_fixture_min= 3.140
V_fixture_max= 3.470
|time   V(typ)   V(min)   V(max)
0s        2.052V     1.909V     2.408V
670ps     2.053V     1.908V     2.367V
960ps     2.057V     1.907V     2.784V
1.16ns    2.446V     1.975V     3.053V
1.35ns    2.737V     1.977V     3.203V
1.71ns    3.055V     2.688V     3.351V
1.99ns    3.164V     2.903V     3.407V
2.43ns    3.247V     3.046V     3.448V
3.72ns    3.296V     3.134V     3.468V
200ns     3.3V       3.14V      3.47V
[Falling Waveform]
R_fixture= 50.000
V_fixture= 3.300
V_fixture_min= 3.140
V_fixture_max= 3.470
|time   V(typ)   V(min)   V(max)
0s        3.3V       3.14V      3.47V
1.09ns    3.3V       3.14V      3.504V
1.48ns    3.329V     3.14V      3.462V
2.3ns     3.279V     3.152V     3.437V
12.1ns    3.094V     3.001V     3.3V
38.9ns    2.461V     2.114V     2.897V
48.72ns   2.277V     1.938V     2.758V
65.19ns   2.181V     1.909V     2.586V
105.8ns   2.058V     1.909V     2.421V
200ns     2.052V     1.909V     2.408V
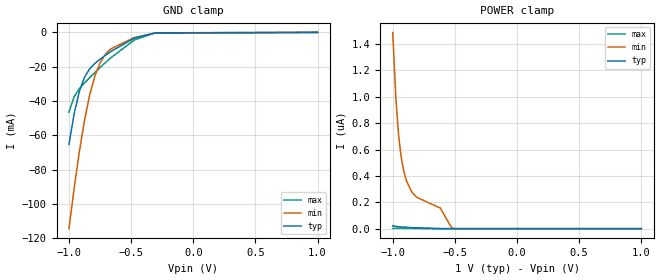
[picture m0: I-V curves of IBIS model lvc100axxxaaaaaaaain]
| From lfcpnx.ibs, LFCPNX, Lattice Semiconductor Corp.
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|Model lvc100axxxaaaaaaaain
[Model] lvc100axxxaaaaaaaain
Model_type Input
Polarity   Non-Inverting
Enable   Active-High
Vinl =  0.350V
Vinh =  0.650V
C_comp   5.000pF   4.000pF   5.500pF
[Temperature Range]   25.000   0.125k   -40.000
[Voltage Range]   1.000V   0.950V   1.050V
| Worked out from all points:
|   GND clamp passes 1 mA (typ) near -0.37 V on its own axis
[GND_clamp]
|Voltage   I(typ)   I(min)   I(max)
-1V       -65.29mA   -114.4mA   -46.53mA
-958mV    -47.33mA   -90.74mA   -37.49mA
-916mV    -34.35mA   -69.33mA   -32.76mA
-874mV    -25.96mA   -50.88mA   -29.34mA
-832mV    -21.09mA   -36.06mA   -26.28mA
-790mV    -18.03mA   -25.11mA   -23.3mA
-748mV    -15.55mA   -17.6mA    -20.39mA
-706mV    -13.31mA   -12.71mA   -17.56mA
-664mV    -11.19mA   -9.645mA   -14.83mA
-475mV    -3.389mA   -2.995mA   -4.475mA
-307mV    -272.9uA   -446.7uA   -266.9uA
1V        0A         0A         0A
[POWER_clamp]
|Voltage   I(typ)   I(min)   I(max)
-1V       21.59nA    1.488uA    2.331nA
-974mV    16.87nA    978.8nA    2.331nA
-953mV    14.48nA    712.4nA    2.331nA
-932mV    12.9nA     543.4nA    2.331nA
-911mV    11.73nA    435.4nA    2.036nA
-890mV    10.67nA    364.2nA    1.767nA
-848mV    6.947nA    279.9nA    1.531nA
-806mV    6.283nA    236.9nA    1.371nA
-617mV    0A         156nA      0A
-533mV    0A         17.85nA    0A
-512mV    0A         0A         0A
1V        0A         0A         0A
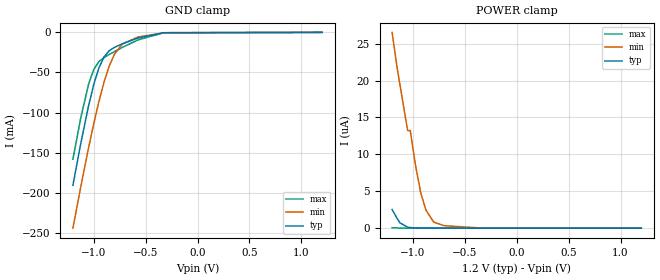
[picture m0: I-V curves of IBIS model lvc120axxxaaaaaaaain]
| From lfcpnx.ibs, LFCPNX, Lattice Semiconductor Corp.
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|Model lvc120axxxaaaaaaaain
[Model] lvc120axxxaaaaaaaain
Model_type Input
Polarity   Non-Inverting
Enable   Active-High
Vinl =  0.420V
Vinh =  0.780V
C_comp   5.000pF   4.000pF   5.500pF
[Temperature Range]   25.000   0.125k   -40.000
[Voltage Range]   1.200V   1.140V   1.260V
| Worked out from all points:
|   GND clamp passes 1 mA (typ) near -0.37 V on its own axis
[GND_clamp]
|Voltage   I(typ)   I(min)   I(max)
-1.2V     -190.9mA   -244.3mA   -158.3mA
-1.125V   -139.1mA   -193.3mA   -107.1mA
-1.05V    -92.03mA   -144.7mA   -65.21mA
-1V       -65.29mA   -114.4mA   -46.54mA
-950mV    -44.47mA   -86.47mA   -36.37mA
-900mV    -30.66mA   -61.91mA   -31.37mA
-850mV    -22.86mA   -41.94mA   -27.58mA
-800mV    -18.69mA   -27.38mA   -24.01mA
-725mV    -14.31mA   -14.65mA   -18.84mA
-575mV    -7.105mA   -5.826mA   -9.469mA
-325mV    -411.3uA   -593.4uA   -433.8uA
1.2V      0A         0A         0A
[POWER_clamp]
|Voltage   I(typ)   I(min)   I(max)
-1.2V     2.524uA    26.52uA    60.55nA
-1.15V    1.275uA    21.56uA    25.67nA
-1.125V   727.4nA    19.49uA    13.64nA
-1.05V    128.5nA    13.22uA    5.223nA
-1.025V   76.57nA    13.22uA    5.223nA
-975mV    32.93nA    8.539uA    5.223nA
-925mV    19.45nA    4.838uA    5.223nA
-875mV    19.45nA    2.468uA    3.5nA
-800mV    19.45nA    827.1nA    1.692nA
-700mV    10.45nA    333.9nA    1.692nA
-325mV    0A         0A         0A
1.2V      0A         0A         0A
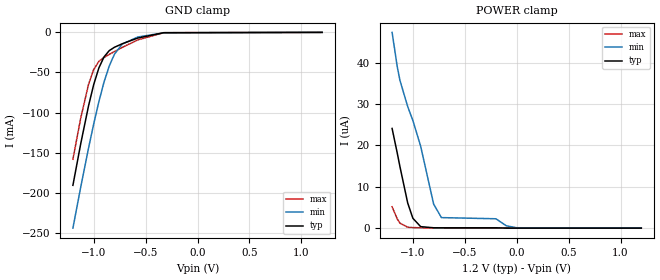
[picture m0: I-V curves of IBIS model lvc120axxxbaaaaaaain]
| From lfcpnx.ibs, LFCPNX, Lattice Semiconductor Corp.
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|Model lvc120axxxbaaaaaaain
[Model] lvc120axxxbaaaaaaain
Model_type Input
Polarity   Non-Inverting
Enable   Active-High
Vinl =  0.420V
Vinh =  0.780V
C_comp   5.000pF   4.000pF   5.500pF
[Temperature Range]   25.000   0.125k   -40.000
[Voltage Range]   1.200V   1.140V   1.260V
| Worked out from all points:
|   GND clamp passes 1 mA (typ) near -0.37 V on its own axis
[GND_clamp]
|Voltage   I(typ)   I(min)   I(max)
-1.2V     -190.8mA   -244.2mA   -158.3mA
-1.125V   -139.1mA   -193.2mA   -107.1mA
-1.05V    -91.98mA   -144.7mA   -65.1mA
-1V       -65.23mA   -114.4mA   -46.39mA
-950mV    -44.39mA   -86.42mA   -36.2mA
-900mV    -30.57mA   -61.86mA   -31.24mA
-850mV    -22.75mA   -41.88mA   -27.47mA
-800mV    -18.58mA   -27.31mA   -23.91mA
-725mV    -14.24mA   -14.57mA   -18.75mA
-575mV    -7.057mA   -5.776mA   -9.405mA
-325mV    -407.1uA   -583.9uA   -420.7uA
1.2V      0A         0A         0A
[POWER_clamp]
|Voltage   I(typ)   I(min)   I(max)
-1.2V     24.08uA    47.28uA    5.158uA
-1.15V    18.09uA    38.94uA    2.209uA
-1.125V   14.92uA    35.74uA    1.224uA
-1.05V    6.097uA    29.38uA    214nA
-1V       2.383uA    26uA       133.7nA
-925mV    359.9nA    19.8uA     85.67nA
-800mV    86.14nA    5.822uA    43.59nA
-725mV    82.4nA     2.543uA    39.97nA
-200mV    82.4nA     2.262uA    3.424nA
-100mV    6.781nA    564.2nA    331.9pA
0V        3.203nA    95.23nA    267.8pA
1.2V      0A         0A         0A
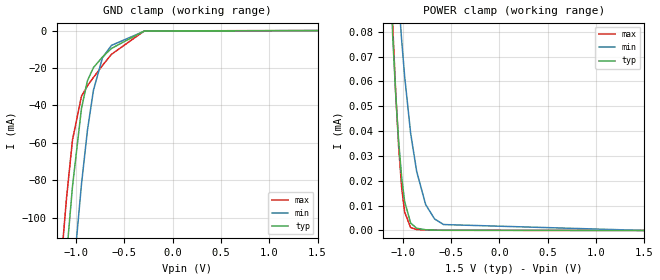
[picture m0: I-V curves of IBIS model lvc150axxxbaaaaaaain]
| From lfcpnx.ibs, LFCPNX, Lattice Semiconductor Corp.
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|Model lvc150axxxbaaaaaaain
[Model] lvc150axxxbaaaaaaain
Model_type Input
Polarity   Non-Inverting
Enable   Active-High
Vinl =  0.375V
Vinh =  1.125V
C_comp   5.000pF   4.000pF   5.500pF
[Temperature Range]   25.000   0.125k   -40.000
[Voltage Range]   1.500V   1.430V   1.580V
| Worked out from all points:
|   GND clamp passes 1 mA (typ) near -0.37 V on its own axis
[GND_clamp]
|Voltage   I(typ)   I(min)   I(max)
-1.5V     -416.3mA   -460.6mA   -390mA
-1.159V   -162.1mA   -216.1mA   -129.5mA
-1.128V   -141mA     -195.2mA   -108.9mA
-1.097V   -120.7mA   -174.8mA   -89.83mA
-1.035V   -83.41mA   -135.4mA   -58.52mA
-942mV    -41.65mA   -82.21mA   -35.1mA
-880mV    -26.75mA   -53.22mA   -29.54mA
-818mV    -19.78mA   -31.88mA   -25.05mA
-725mV    -14.16mA   -14.53mA   -18.66mA
-632mV    -9.547mA   -7.912mA   -12.7mA
-291mV    -178.2uA   -331.1uA   -151.3uA
1.5V      0A         0A         0A
[POWER_clamp]
|Voltage   I(typ)   I(min)   I(max)
-1.5V     548.1uA    538.3uA    707.6uA
-1.104V   78.51uA    131.5uA    82.99uA
-1.073V   54.93uA    111.5uA    55.72uA
-1.042V   35.78uA    93.15uA    33.51uA
-1.011V   21.35uA    76.53uA    17.25uA
-980mV    11.61uA    61.87uA    7.385uA
-918mV    2.956uA    39.08uA    1.129uA
-856mV    895.1nA    23.8uA     384.5nA
-763mV    287.4nA    10.43uA    204.2nA
-670mV    148.8nA    4.611uA    122.8nA
-577mV    102.4nA    2.382uA    73.01nA
1.5V      0A         0A         0A
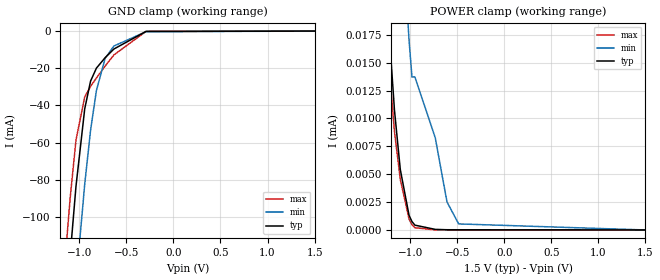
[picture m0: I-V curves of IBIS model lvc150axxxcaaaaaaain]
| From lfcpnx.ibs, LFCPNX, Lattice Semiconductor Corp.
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|Model lvc150axxxcaaaaaaain
[Model] lvc150axxxcaaaaaaain
Model_type Input
Polarity   Non-Inverting
Enable   Active-High
Vinl =  0.375V
Vinh =  1.125V
C_comp   5.000pF   4.000pF   5.500pF
[Temperature Range]   25.000   0.125k   -40.000
[Voltage Range]   1.500V   1.430V   1.580V
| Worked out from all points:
|   GND clamp passes 1 mA (typ) near -0.37 V on its own axis
[GND_clamp]
|Voltage   I(typ)   I(min)   I(max)
-1.5V     -416.3mA   -460.6mA   -390mA
-1.159V   -162.1mA   -216.1mA   -129.6mA
-1.128V   -141.1mA   -195.3mA   -109mA
-1.097V   -120.8mA   -174.8mA   -89.93mA
-1.035V   -83.48mA   -135.4mA   -58.66mA
-942mV    -41.76mA   -82.26mA   -35.32mA
-880mV    -26.88mA   -53.29mA   -29.74mA
-818mV    -19.92mA   -31.96mA   -25.23mA
-725mV    -14.28mA   -14.63mA   -18.8mA
-632mV    -9.633mA   -8.012mA   -12.81mA
-291mV    -181.2uA   -338.3uA   -163.3uA
1.5V      0A         0A         0A
[POWER_clamp]
|Voltage   I(typ)   I(min)   I(max)
-1.5V     341.9uA    354.3uA    93.22uA
-1.259V   23.26uA    233.1uA    19.29uA
-1.228V   18.43uA    54.17uA    15.15uA
-1.166V   10.74uA    40.45uA    8.83uA
-1.104V   5.42uA     30.03uA    4.534uA
-1.011V   1.312uA    17.01uA    973.3nA
-980mV    752.1nA    13.72uA    461.6nA
-949mV    431.7nA    13.72uA    200nA
-732mV    52.04nA    8.245uA    6.282nA
-608mV    20.6nA     2.515uA    6.282nA
-484mV    18.16nA    543.3nA    1.662nA
1.5V      0A         0A         0A
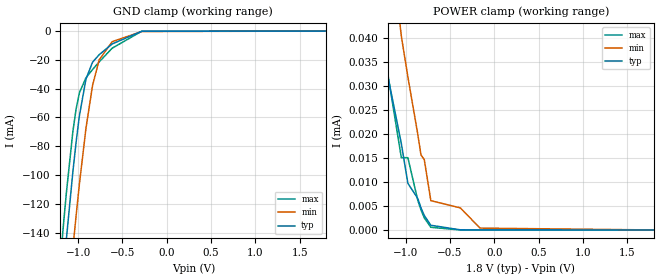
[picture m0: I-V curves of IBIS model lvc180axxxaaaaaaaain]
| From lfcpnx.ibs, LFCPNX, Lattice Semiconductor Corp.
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|Model lvc180axxxaaaaaaaain
[Model] lvc180axxxaaaaaaaain
Model_type Input
Polarity   Non-Inverting
Enable   Active-High
Vinl =  0.630V
Vinh =  1.170V
C_comp   5.000pF   4.000pF   5.500pF
[Temperature Range]   25.000   0.125k   -40.000
[Voltage Range]   1.800V   1.710V   1.890V
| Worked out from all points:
|   GND clamp passes 1 mA (typ) near -0.37 V on its own axis
[GND_clamp]
|Voltage   I(typ)   I(min)   I(max)
-1.8V     -652.3mA   -685.9mA   -633.8mA
-1.171V   -170.5mA   -224.3mA   -137.9mA
-1.134V   -145.1mA   -199.3mA   -112.9mA
-1.06V    -97.91mA   -151mA     -69.95mA
-1.023V   -76.98mA   -128.1mA   -54.07mA
-986mV    -58.78mA   -106.3mA   -42.86mA
-912mV    -33.37mA   -67.44mA   -32.41mA
-838mV    -21.65mA   -37.94mA   -26.72mA
-764mV    -16.46mA   -20.11mA   -21.5mA
-616mV    -8.914mA   -7.355mA   -11.86mA
-283mV    -145.5uA   -292.8uA   -123.1uA
1.8V      0A         0A         0A
[POWER_clamp]
|Voltage   I(typ)   I(min)   I(max)
-1.8V     142.4uA    1.634mA    133.9uA
-1.308V   42.14uA    84.88uA    43.83uA
-1.271V   38.47uA    77.3uA     40.47uA
-1.049V   18uA       40.4uA     15.06uA
-975mV    9.72uA     31.88uA    15.06uA
-864mV    6.581uA    20.03uA    6.229uA
-827mV    4.624uA    15.62uA    4.184uA
-790mV    3.018uA    14.67uA    2.521uA
-716mV    977.7nA    6.105uA    559.9nA
-383mV    28.79nA    4.603uA    3.535nA
-161mV    13.99nA    386.6nA    1.391nA
1.8V      0A         0A         0A
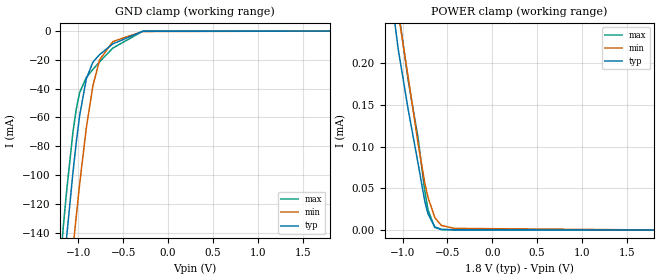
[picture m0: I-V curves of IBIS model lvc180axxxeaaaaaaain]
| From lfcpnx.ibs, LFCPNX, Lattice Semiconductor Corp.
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|Model lvc180axxxeaaaaaaain
[Model] lvc180axxxeaaaaaaain
Model_type Input
Polarity   Non-Inverting
Enable   Active-High
Vinl =  0.630V
Vinh =  1.170V
C_comp   5.000pF   4.000pF   5.500pF
[Temperature Range]   25.000   0.125k   -40.000
[Voltage Range]   1.800V   1.710V   1.890V
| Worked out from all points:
|   GND clamp passes 1 mA (typ) near -0.37 V on its own axis
|   POWER clamp passes 1 mA (typ) near -1.56 V on its own axis
[GND_clamp]
|Voltage   I(typ)   I(min)   I(max)
-1.8V     -652.3mA   -685.9mA   -633.8mA
-1.171V   -170.4mA   -224.3mA   -137.8mA
-1.134V   -145.1mA   -199.2mA   -112.9mA
-1.06V    -97.86mA   -151mA     -69.84mA
-1.023V   -76.92mA   -128.1mA   -53.94mA
-986mV    -58.71mA   -106.3mA   -42.7mA
-912mV    -33.28mA   -67.39mA   -32.22mA
-838mV    -21.54mA   -37.88mA   -26.6mA
-764mV    -16.38mA   -20.04mA   -21.4mA
-616mV    -8.858mA   -7.274mA   -11.79mA
-283mV    -142.7uA   -286.3uA   -113.6uA
1.8V      0A         0A         0A
[POWER_clamp]
|Voltage   I(typ)   I(min)   I(max)
-1.8V     1.554mA    1.148mA    2.094mA
-1.123V   284.8uA    318.9uA    338.4uA
-1.086V   248.6uA    289.4uA    300.3uA
-1.049V   217.4uA    261.6uA    266uA
-938mV    145uA      183.8uA    180.1uA
-827mV    79.82uA    103.7uA    110.3uA
-753mV    34.74uA    56.72uA    47.26uA
-716mV    19.14uA    38.85uA    24.03uA
-642mV    3.76uA     15.15uA    3.031uA
-568mV    706.6nA    5.347uA    491.7nA
-420mV    172.8nA    1.883uA    168.2nA
1.8V      0A         0A         0A
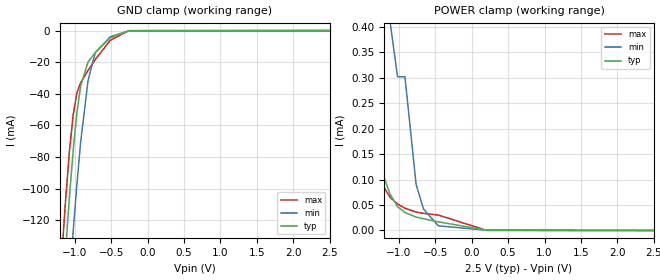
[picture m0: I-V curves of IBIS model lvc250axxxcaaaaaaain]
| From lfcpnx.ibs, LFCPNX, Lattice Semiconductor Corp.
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|Model lvc250axxxcaaaaaaain
[Model] lvc250axxxcaaaaaaain
Model_type Input
Polarity   Non-Inverting
Enable   Active-High
Vinl =  0.700V
Vinh =  1.700V
C_comp   5.000pF   4.000pF   5.500pF
[Temperature Range]   25.000   0.125k   -40.000
[Voltage Range]   2.500V   2.380V   2.630V
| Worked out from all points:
|   GND clamp passes 1 mA (typ) near -0.37 V on its own axis
[GND_clamp]
|Voltage   I(typ)   I(min)   I(max)
-2.5V     -1.215A    -1.224A    -1.214A
-1.174V   -172.5mA   -226.4mA   -139.9mA
-1.123V   -137.8mA   -191.9mA   -105.9mA
-1.072V   -105.1mA   -158.6mA   -76.04mA
-1.021V   -75.92mA   -126.9mA   -53.34mA
-970mV    -51.97mA   -97.29mA   -39.48mA
-919mV    -35.11mA   -70.77mA   -33.03mA
-817mV    -19.88mA   -31.71mA   -25.21mA
-715mV    -13.78mA   -13.58mA   -18.16mA
-511mV    -4.597mA   -3.899mA   -6.109mA
-256mV    -63.68uA   -169.7uA   -45.7uA
2.5V      0A         0A         0A
[POWER_clamp]
|Voltage   I(typ)   I(min)   I(max)
-2.5V     814.9uA    2.966mA    966.4uA
-1.886V   402.3uA    2.034mA    453.8uA
-1.784V   347.7uA    1.898mA    385.3uA
-1.223V   111.1uA    542.9uA    89.01uA
-1.121V   71.3uA     409.6uA    65.31uA
-1.019V   46.94uA    302.1uA    52.17uA
-917mV    35.26uA    302.1uA    43.61uA
-764mV    26.4uA     90.67uA    36.35uA
-662mV    23.03uA    42.2uA     33.46uA
-458mV    17uA       9.1uA      30.27uA
205mV     405.5nA    495.7nA    145.2nA
2.5V      0A         0A         0A
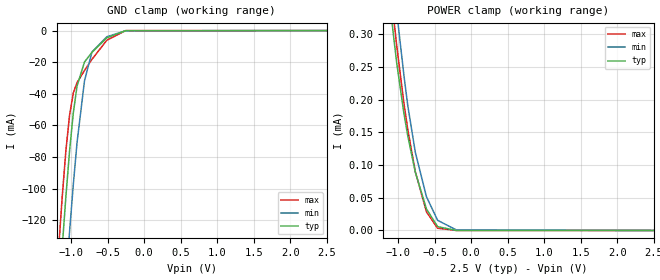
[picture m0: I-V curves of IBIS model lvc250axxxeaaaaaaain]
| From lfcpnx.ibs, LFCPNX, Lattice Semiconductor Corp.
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|Model lvc250axxxeaaaaaaain
[Model] lvc250axxxeaaaaaaain
Model_type Input
Polarity   Non-Inverting
Enable   Active-High
Vinl =  0.700V
Vinh =  1.700V
C_comp   5.000pF   4.000pF   5.500pF
[Temperature Range]   25.000   0.125k   -40.000
[Voltage Range]   2.500V   2.380V   2.630V
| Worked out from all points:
|   GND clamp passes 1 mA (typ) near -0.37 V on its own axis
|   POWER clamp passes 1 mA (typ) near -1.55 V on its own axis
[GND_clamp]
|Voltage   I(typ)   I(min)   I(max)
-2.5V     -1.215A    -1.224A    -1.214A
-1.174V   -172.5mA   -226.4mA   -139.9mA
-1.123V   -137.8mA   -191.9mA   -105.8mA
-1.072V   -105.1mA   -158.6mA   -76.01mA
-1.021V   -75.9mA    -126.9mA   -53.29mA
-970mV    -51.94mA   -97.28mA   -39.42mA
-919mV    -35.08mA   -70.75mA   -32.96mA
-817mV    -19.84mA   -31.68mA   -25.2mA
-715mV    -13.77mA   -13.54mA   -18.16mA
-511mV    -4.595mA   -3.896mA   -6.102mA
-256mV    -62.28uA   -167.8uA   -38.13uA
2.5V      0A         0A         0A
[POWER_clamp]
|Voltage   I(typ)   I(min)   I(max)
-2.5V     2.999mA    2.874mA    3.804mA
-1.172V   428.2uA    481.5uA    457.9uA
-1.121V   362.3uA    433.3uA    393.9uA
-1.07V    305.8uA    385uA      336.1uA
-1.019V   257.2uA    335.3uA    283.6uA
-917mV    177.4uA    235uA      192.6uA
-866mV    144.3uA    190.6uA    154uA
-764mV    89.39uA    120.1uA    90.33uA
-611mV    32.96uA    51.71uA    28.47uA
-458mV    5.876uA    15.5uA     3.488uA
-203mV    36nA       915.5nA    20.37nA
2.5V      0A         0A         0A
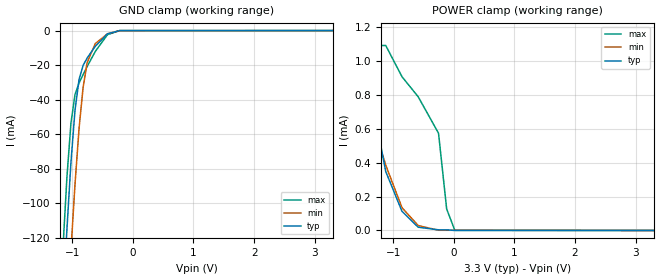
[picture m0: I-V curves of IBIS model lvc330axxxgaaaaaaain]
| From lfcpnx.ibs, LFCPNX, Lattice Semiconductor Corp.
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|Model lvc330axxxgaaaaaaain
[Model] lvc330axxxgaaaaaaain
Model_type Input
Polarity   Non-Inverting
Enable   Active-High
Vinl =  0.800V
Vinh =  2.000V
C_comp   5.000pF   4.000pF   5.500pF
[Temperature Range]   25.000   0.125k   -40.000
[Voltage Range]   3.300V   3.140V   3.470V
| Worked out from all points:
|   GND clamp passes 1 mA (typ) near -0.37 V on its own axis
|   POWER clamp passes 1 mA (typ) near -1.47 V on its own axis
[GND_clamp]
|Voltage   I(typ)   I(min)   I(max)
-3.3V     -1.865A    -1.847A    -1.883A
-1.156V   -160.1mA   -214.1mA   -127.6mA
-1.089V   -115.7mA   -169.6mA   -85.35mA
-1.022V   -76.45mA   -127.5mA   -53.7mA
-955mV    -46.24mA   -89.13mA   -37.05mA
-888mV    -28.3mA    -56.66mA   -30.41mA
-821mV    -20.19mA   -32.82mA   -25.49mA
-754mV    -15.89mA   -18.49mA   -20.81mA
-620mV    -9.094mA   -7.515mA   -12.09mA
-419mV    -1.868mA   -1.846mA   -2.383mA
-218mV    -16.48uA   -78.61uA   -6.639uA
3.3V      0A         0A         0A
[POWER_clamp]
|Voltage   I(typ)   I(min)   I(max)
-3.3V     37.53mA    9.364mA    73.7mA
-1.792V   1.823mA    1.318mA    2.466mA
-1.591V   1.29mA     991.8uA    1.714mA
-1.457V   981.8uA    795.4uA    1.299mA
-1.39V    843.7uA    703.6uA    1.091mA
-1.122V   347.7uA    385.2uA    1.091mA
-854mV    112.9uA    134.5uA    907uA
-586mV    19.15uA    28.85uA    788.2uA
-251mV    3.861uA    1.254uA    573.3uA
-117mV    3.861uA    1.254uA    126.7uA
17mV      69.96nA    1.254uA    1.636uA
3.3V      0A         0A         0A
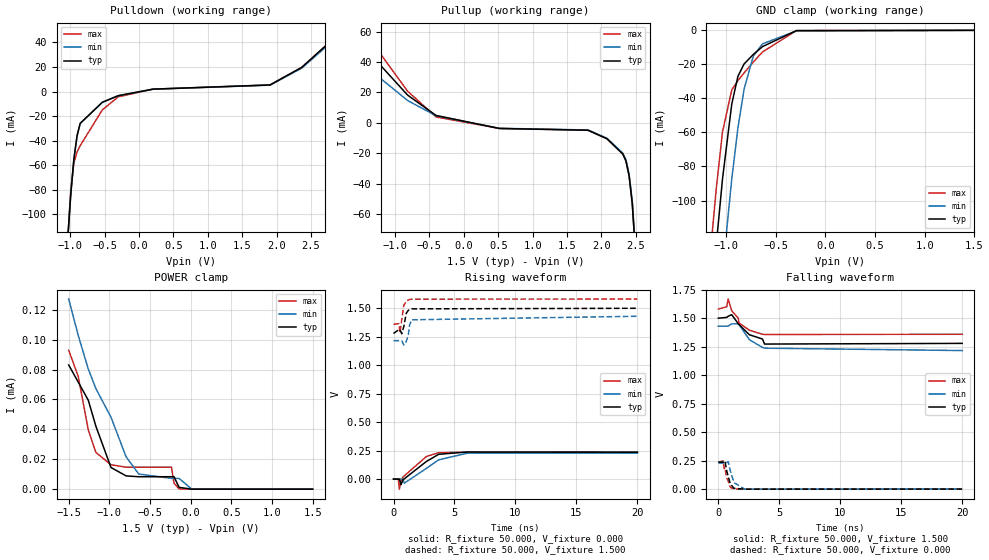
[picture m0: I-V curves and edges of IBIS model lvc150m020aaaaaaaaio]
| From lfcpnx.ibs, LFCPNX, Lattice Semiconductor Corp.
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[Model] lvc150m020aaaaaaaaio
Model_type I/O
Polarity   Non-Inverting
Enable   Active-Low
Vinl =  0.375V
Vinh =  1.125V
Vmeas =  0.750V
Cref =  0.0F
Rref =  1.000M
Vref =  0.0V
C_comp   5.000pF   4.000pF   5.500pF
[Temperature Range]   25.000   0.125k   -40.000
[Voltage Range]   1.500V   1.430V   1.580V
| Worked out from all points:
|   slope of the pulldown table from 0 to 0.225 V, typ, clamps not added: 104 ohm
|   slope of the pullup table from 0 to 0.225 V, typ, clamps not added: 113 ohm
|   GND clamp passes 1 mA (typ) near -0.37 V on its own axis
|   rising waveform, R_fixture 50.000, V_fixture 0.000: 20-80 % time 1.55ns typ, 1.9ns min, 1.48ns max; typ from 0 V to 0.236 V
|   rising waveform, R_fixture 50.000, V_fixture 1.500: 20-80 % time 225ps typ, 228ps min, 206ps max; typ from 1.28 V to 1.5 V
|   falling waveform, R_fixture 50.000, V_fixture 1.500: 20-80 % time 1.72ns typ, 1.24ns min, 1.13ns max; typ from 1.5 V to 1.28 V
|   falling waveform, R_fixture 50.000, V_fixture 0.000: 20-80 % time 381ps typ, 376ps min, 376ps max; typ from 0.236 V to 0 V
[GND_clamp]
|Voltage   I(typ)   I(min)   I(max)
-1.5V     -426.4mA   -473.4mA   -397.9mA
-1.159V   -167.8mA   -224.7mA   -133.2mA
-1.128V   -146.3mA   -203.3mA   -112.2mA
-1.097V   -125.6mA   -182.4mA   -92.52mA
-1.035V   -87.33mA   -142.1mA   -59.66mA
-942mV    -43.38mA   -87.52mA   -35.08mA
-880mV    -27.07mA   -57.47mA   -29.54mA
-818mV    -19.78mA   -34.65mA   -25.05mA
-725mV    -14.16mA   -15.11mA   -18.65mA
-632mV    -9.546mA   -7.937mA   -12.69mA
-291mV    -178.2uA   -331.3uA   -151.3uA
1.5V      0A         0A         0A
[POWER_clamp]
|Voltage   I(typ)   I(min)   I(max)
-1.5V     83.04uA    127.1uA    92.85uA
-1.383V   71.55uA    102.8uA    75.37uA
-1.259V   59.42uA    80.29uA    39.53uA
-1.166V   42.09uA    67.25uA    24.57uA
-980mV    14.48uA    48.12uA    16.31uA
-794mV    8.868uA    21.59uA    14.7uA
-639mV    8.318uA    10.13uA    14.7uA
-236mV    8.318uA    7.207uA    14.7uA
-205mV    8.318uA    7.207uA    4.033uA
-143mV    1.253uA    7.207uA    225nA
12mV      3.591nA    119.8nA    333.5pA
1.5V      0A         0A         0A
[Pulldown]
|Voltage   I(typ)   I(min)   I(max)
-1.5V     -652.2mA   -652.2mA   -999mA
-1.04V    -122.4mA   -122.4mA   -124.8mA
-994mV    -84.5mA    -84.5mA    -80.91mA
-948mV    -55.33mA   -55.33mA   -58.34mA
-902mV    -36.2mA    -36.2mA    -49.34mA
-856mV    -25.95mA   -25.95mA   -44.08mA
-534mV    -8.758mA   -8.758mA   -14.93mA
-304mV    -3.384mA   -3.384mA   -4.335mA
202mV     1.974mA    1.915mA    1.974mA
1.904V    5.384mA    5.223mA    5.384mA
2.364V    19.67mA    19.08mA    19.67mA
3V        51.84mA    50.28mA    51.84mA
[Pullup]
|Voltage   I(typ)   I(min)   I(max)
-1.5V     52.08mA    39.77mA    63.11mA
-818mV    18.17mA    14.6mA     20.75mA
-404mV    4.77mA     4.559mA    3.77mA
516mV     -3.782mA   -3.668mA   -3.782mA
1.804V    -4.928mA   -4.781mA   -4.928mA
2.08V     -10.53mA   -10.21mA   -10.53mA
2.31V     -20.54mA   -19.93mA   -20.54mA
2.356V    -25.06mA   -24.31mA   -25.06mA
2.402V    -34.81mA   -33.76mA   -34.81mA
2.448V    -53.02mA   -51.42mA   -53.02mA
2.54V     -117mA     -113.5mA   -117mA
3V        -622.5mA   -603.8mA   -622.5mA
[Ramp]
| variable   typ   min   max
dV/dt_r   0.142/1.595n   0.137/1.942n   0.141/1.516n
dV/dt_f   0.132/1.282n   0.128/1.486n   0.133/1.305n
R_load = 50.000
[Rising Waveform]
R_fixture = 50.000
V_fixture = 0.000
V_fixture_min = 0.000
V_fixture_max = 0.000
|  time   V(typ)   V(min)   V(max)
0s        33.82uV    750.8uV    1.217mV
390ps     14.96uV    576.6uV    3.108mV
482ps     116.7uV    710.2uV    -88.21mV
616ps     -48.93mV   798uV      -11.22mV
784ps     -4.554mV   -1.932mV   19.28mV
884ps     2.896mV    -35.96mV   28.85mV
2.698ns   155.2mV    94.69mV    198.6mV
3.705ns   218mV      169.4mV    232.1mV
6.07ns    238.1mV    228mV      237.1mV
20ns      236.3mV    229.1mV    236.5mV
[Rising Waveform]
R_fixture = 50.000
V_fixture = 1.500
V_fixture_min = 1.430
V_fixture_max = 1.580
|  time   V(typ)   V(min)   V(max)
0s        1.279V     1.216V     1.359V
446ps     1.313V     1.216V     1.365V
527ps     1.314V     1.216V     1.284V
675ps     1.276V     1.216V     1.399V
844ps     1.339V     1.177V     1.525V
1.045ns   1.456V     1.209V     1.562V
1.204ns   1.481V     1.26V      1.573V
1.324ns   1.489V     1.355V     1.577V
1.494ns   1.495V     1.399V     1.58V
20ns      1.5V       1.43V      1.581V
[Falling Waveform]
R_fixture = 50.000
V_fixture = 1.500
V_fixture_min = 1.430
V_fixture_max = 1.580
|  time   V(typ)   V(min)   V(max)
0s        1.5V       1.43V      1.581V
688ps     1.507V     1.43V      1.6V
806ps     1.517V     1.431V     1.668V
1.098ns   1.531V     1.45V      1.566V
1.653ns   1.449V     1.451V     1.498V
1.682ns   1.446V     1.447V     1.459V
2.543ns   1.355V     1.312V     1.395V
3.625ns   1.317V     1.243V     1.359V
3.792ns   1.273V     1.237V     1.357V
20ns      1.279V     1.216V     1.359V
[Falling Waveform]
R_fixture = 50.000
V_fixture = 0.000
V_fixture_min = 0.000
V_fixture_max = 0.000
|  time   V(typ)   V(min)   V(max)
0s        236.3mV    229.1mV    236.5mV
397ps     236mV      228.9mV    247mV
490ps     245mV      229mV      179.9mV
537ps     248.3mV    229mV      188.3mV
678ps     166.1mV    231.3mV    98.87mV
808ps     111.1mV    241.7mV    71.35mV
978ps     48.42mV    164.5mV    16.01mV
1.28ns    6.725mV    57.64mV    98.75uV
2.138ns   -749.2uV   381.8uV    -510.6uV
20ns      33.82uV    750.8uV    1.217mV
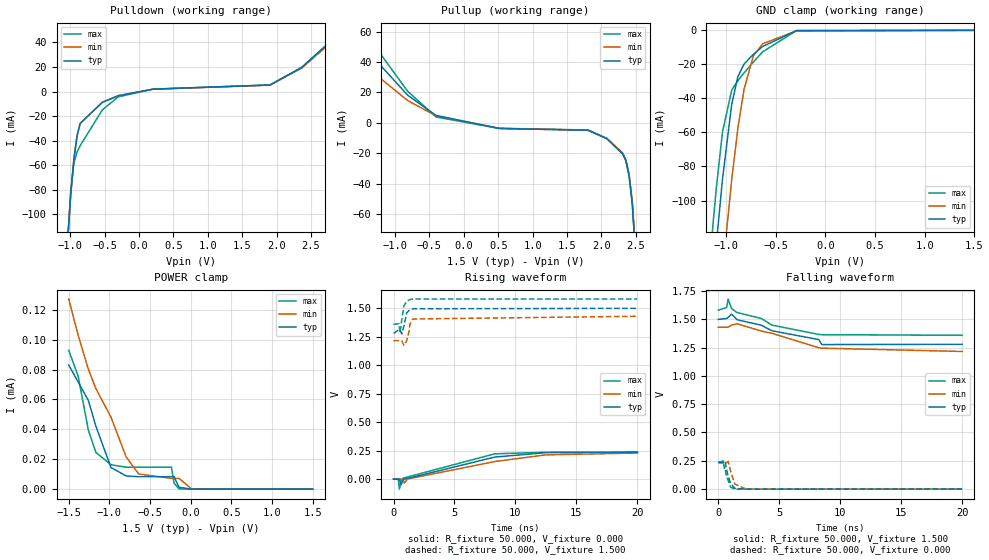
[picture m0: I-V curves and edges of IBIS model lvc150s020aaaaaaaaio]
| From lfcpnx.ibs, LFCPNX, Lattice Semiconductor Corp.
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[Model] lvc150s020aaaaaaaaio
Model_type I/O
Polarity   Non-Inverting
Enable   Active-Low
Vinl =  0.375V
Vinh =  1.125V
Vmeas =  0.750V
Cref =  0.0F
Rref =  1.000M
Vref =  0.0V
C_comp   5.000pF   4.000pF   5.500pF
[Temperature Range]   25.000   0.125k   -40.000
[Voltage Range]   1.500V   1.430V   1.580V
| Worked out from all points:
|   slope of the pulldown table from 0 to 0.225 V, typ, clamps not added: 104 ohm
|   slope of the pullup table from 0 to 0.225 V, typ, clamps not added: 113 ohm
|   GND clamp passes 1 mA (typ) near -0.37 V on its own axis
|   rising waveform, R_fixture 50.000, V_fixture 0.000: 20-80 % time 4.36ns typ, 5.38ns min, 3.84ns max; typ from 0 V to 0.236 V
|   rising waveform, R_fixture 50.000, V_fixture 1.500: 20-80 % time 243ps typ, 243ps min, 225ps max; typ from 1.28 V to 1.5 V
|   falling waveform, R_fixture 50.000, V_fixture 1.500: 20-80 % time 4.8ns typ, 3.85ns min, 3.83ns max; typ from 1.5 V to 1.28 V
|   falling waveform, R_fixture 50.000, V_fixture 0.000: 20-80 % time 422ps typ, 384ps min, 321ps max; typ from 0.236 V to 0 V
[GND_clamp]
|Voltage   I(typ)   I(min)   I(max)
-1.5V     -426.4mA   -473.4mA   -397.9mA
-1.159V   -167.8mA   -224.7mA   -133.2mA
-1.128V   -146.3mA   -203.3mA   -112.2mA
-1.097V   -125.6mA   -182.4mA   -92.52mA
-1.035V   -87.33mA   -142.1mA   -59.66mA
-942mV    -43.38mA   -87.52mA   -35.08mA
-880mV    -27.07mA   -57.47mA   -29.54mA
-818mV    -19.78mA   -34.65mA   -25.05mA
-725mV    -14.16mA   -15.11mA   -18.65mA
-632mV    -9.546mA   -7.937mA   -12.69mA
-291mV    -178.2uA   -331.3uA   -151.3uA
1.5V      0A         0A         0A
[POWER_clamp]
|Voltage   I(typ)   I(min)   I(max)
-1.5V     83.04uA    127.1uA    92.85uA
-1.383V   71.55uA    102.8uA    75.37uA
-1.259V   59.42uA    80.29uA    39.53uA
-1.166V   42.09uA    67.25uA    24.57uA
-980mV    14.48uA    48.12uA    16.31uA
-794mV    8.868uA    21.59uA    14.7uA
-639mV    8.318uA    10.13uA    14.7uA
-236mV    8.318uA    7.207uA    14.7uA
-205mV    8.318uA    7.207uA    4.033uA
-143mV    1.253uA    7.207uA    225nA
12mV      3.591nA    119.8nA    333.5pA
1.5V      0A         0A         0A
[Pulldown]
|Voltage   I(typ)   I(min)   I(max)
-1.5V     -652.2mA   -652.2mA   -999mA
-1.04V    -122.4mA   -122.4mA   -124.8mA
-994mV    -84.5mA    -84.5mA    -80.91mA
-948mV    -55.33mA   -55.33mA   -58.34mA
-902mV    -36.2mA    -36.2mA    -49.34mA
-856mV    -25.95mA   -25.95mA   -44.08mA
-534mV    -8.758mA   -8.758mA   -14.93mA
-304mV    -3.384mA   -3.384mA   -4.335mA
202mV     1.974mA    1.915mA    1.974mA
1.904V    5.384mA    5.223mA    5.384mA
2.364V    19.67mA    19.08mA    19.67mA
3V        51.84mA    50.28mA    51.84mA
[Pullup]
|Voltage   I(typ)   I(min)   I(max)
-1.5V     52.08mA    39.77mA    63.11mA
-818mV    18.17mA    14.6mA     20.75mA
-404mV    4.77mA     4.559mA    3.77mA
516mV     -3.782mA   -3.668mA   -3.782mA
1.804V    -4.928mA   -4.781mA   -4.928mA
2.08V     -10.53mA   -10.21mA   -10.53mA
2.31V     -20.54mA   -19.93mA   -20.54mA
2.356V    -25.06mA   -24.31mA   -25.06mA
2.402V    -34.81mA   -33.76mA   -34.81mA
2.448V    -53.02mA   -51.42mA   -53.02mA
2.54V     -117mA     -113.5mA   -117mA
3V        -622.5mA   -603.8mA   -622.5mA
[Ramp]
| variable   typ   min   max
dV/dt_r   0.142/4.376n   0.137/5.392n   0.141/3.839n
dV/dt_f   0.132/4.046n   0.128/4.463n   0.133/4.421n
R_load = 50.000
[Rising Waveform]
R_fixture = 50.000
V_fixture = 0.000
V_fixture_min = 0.000
V_fixture_max = 0.000
|  time   V(typ)   V(min)   V(max)
0s        33.82uV    750.8uV    1.217mV
390ps     14.96uV    575.7uV    3.108mV
482ps     116.7uV    710uV      -88.07mV
617ps     -48.91mV   799.3uV    -12.89mV
795ps     -3.649mV   -5.2mV     8.069mV
884ps     1.09mV     -36.1mV    11.39mV
1.134ns   5.412mV    669.3uV    18.47mV
8.3ns     193.6mV    154.5mV    222.2mV
12.48ns   232.3mV    213.1mV    236.2mV
20ns      236.3mV    229.1mV    236.5mV
[Rising Waveform]
R_fixture = 50.000
V_fixture = 1.500
V_fixture_min = 1.430
V_fixture_max = 1.580
|  time   V(typ)   V(min)   V(max)
0s        1.279V     1.216V     1.359V
446ps     1.313V     1.216V     1.365V
527ps     1.314V     1.216V     1.284V
675ps     1.275V     1.216V     1.396V
854ps     1.345V     1.174V     1.522V
1.078ns   1.459V     1.215V     1.561V
1.304ns   1.485V     1.312V     1.575V
1.334ns   1.487V     1.357V     1.576V
1.574ns   1.495V     1.406V     1.581V
20ns      1.5V       1.43V      1.581V
[Falling Waveform]
R_fixture = 50.000
V_fixture = 1.500
V_fixture_min = 1.430
V_fixture_max = 1.580
|  time   V(typ)   V(min)   V(max)
0s        1.5V       1.43V      1.581V
688ps     1.507V     1.43V      1.604V
805ps     1.517V     1.431V     1.679V
1.088ns   1.546V     1.449V     1.595V
1.543ns   1.496V     1.461V     1.56V
3.532ns   1.448V     1.396V     1.507V
4.387ns   1.399V     1.377V     1.449V
8.241ns   1.321V     1.249V     1.366V
8.49ns    1.277V     1.245V     1.364V
20ns      1.279V     1.216V     1.359V
[Falling Waveform]
R_fixture = 50.000
V_fixture = 0.000
V_fixture_min = 0.000
V_fixture_max = 0.000
|  time   V(typ)   V(min)   V(max)
0s        236.3mV    229.1mV    236.5mV
397ps     235.9mV    228.9mV    248.5mV
495ps     246.6mV    229mV      184mV
545ps     249.1mV    228.9mV    191.8mV
675ps     173.6mV    231.1mV    105.1mV
808ps     115mV      244.2mV    79.55mV
998ps     54.89mV    161.8mV    17.97mV
1.348ns   6.169mV    44.98mV    -69.51uV
2.268ns   -975.2uV   148.4uV    -825.5uV
20ns      33.82uV    750.8uV    1.217mV
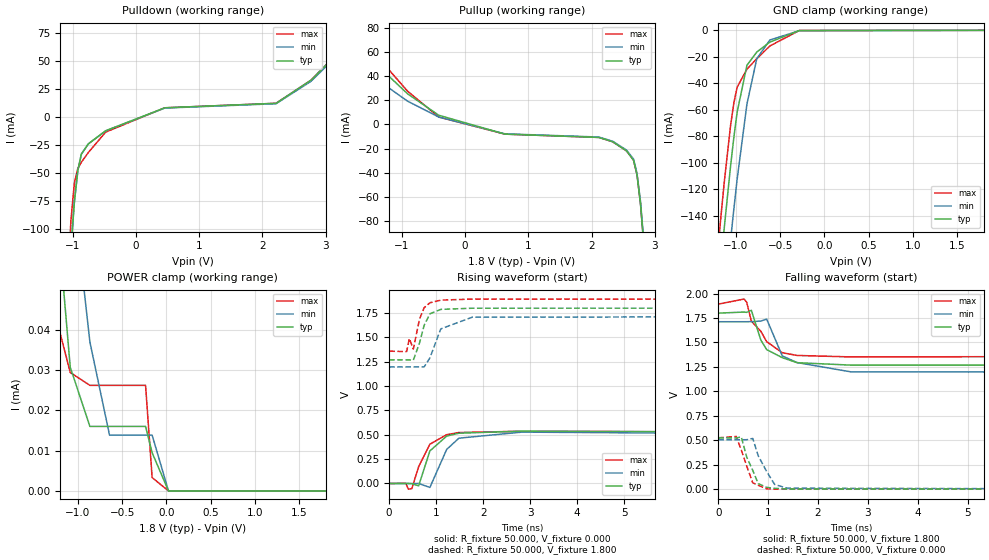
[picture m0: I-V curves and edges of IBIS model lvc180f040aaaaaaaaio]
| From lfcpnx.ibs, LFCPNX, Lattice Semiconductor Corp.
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[Model] lvc180f040aaaaaaaaio
Model_type I/O
Polarity   Non-Inverting
Enable   Active-Low
Vinl =  0.630V
Vinh =  1.170V
Vmeas =  0.900V
Cref =  0.0F
Rref =  1.000M
Vref =  0.0V
C_comp   5.000pF   4.000pF   5.500pF
[Temperature Range]   25.000   0.125k   -40.000
[Voltage Range]   1.800V   1.710V   1.890V
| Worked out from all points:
|   slope of the pulldown table from 0 to 0.27 V, typ, clamps not added: 46.9 ohm
|   slope of the pullup table from 0 to 0.27 V, typ, clamps not added: 66.8 ohm
|   GND clamp passes 1 mA (typ) near -0.37 V on its own axis
|   rising waveform, R_fixture 50.000, V_fixture 0.000: 20-80 % time 281ps typ, 290ps min, 311ps max; typ from 0 V to 0.523 V
|   rising waveform, R_fixture 50.000, V_fixture 1.800: 20-80 % time 199ps typ, 247ps min, 162ps max; typ from 1.27 V to 1.8 V
|   falling waveform, R_fixture 50.000, V_fixture 1.800: 20-80 % time 449ps typ, 311ps min, 414ps max; typ from 1.8 V to 1.27 V
|   falling waveform, R_fixture 50.000, V_fixture 0.000: 20-80 % time 224ps typ, 282ps min, 206ps max; typ from 0.523 V to 0 V
[GND_clamp]
|Voltage   I(typ)   I(min)   I(max)
-1.8V     -665.5mA   -701.9mA   -644.7mA
-1.208V   -203.2mA   -259.3mA   -168.6mA
-1.171V   -176.5mA   -233.3mA   -141.8mA
-1.134V   -150.7mA   -207.7mA   -116.3mA
-1.06V    -102.3mA   -158.3mA   -71.8mA
-1.023V   -80.78mA   -134.8mA   -54.83mA
-986mV    -61.78mA   -112.4mA   -42.93mA
-875mV    -26.33mA   -55.53mA   -29.29mA
-764mV    -16.38mA   -21.41mA   -21.4mA
-616mV    -8.858mA   -7.288mA   -11.79mA
-283mV    -142.7uA   -287uA     -113.6uA
1.8V      1.806nA    0A         -451.7pA
[POWER_clamp]
|Voltage   I(typ)   I(min)   I(max)
-1.8V     186.1uA    259.3uA    183.5uA
-1.382V   94.44uA    136.9uA    91.49uA
-1.345V   89.56uA    127.8uA    77.5uA
-1.308V   84.02uA    119.2uA    62.8uA
-1.234V   68.87uA    103.6uA    41.99uA
-1.086V   30.66uA    80.57uA    29.36uA
-864mV    15.99uA    36.92uA    26.17uA
-642mV    15.99uA    13.83uA    26.17uA
-235mV    15.99uA    13.83uA    26.17uA
-161mV    9.477uA    13.83uA    3.316uA
24mV      0A         0A         261.1pA
1.8V      0A         0A         0A
[Pulldown]
|Voltage   I(typ)   I(min)   I(max)
-1.8V     -1.035A    -1.035A    -1.293A
-1.085V   -169.1mA   -169.1mA   -149.3mA
-1.03V    -117.3mA   -117.3mA   -92.67mA
-975mV    -75.6mA    -75.6mA    -58.7mA
-920mV    -47.57mA   -47.57mA   -45.7mA
-865mV    -33.08mA   -33.08mA   -40.28mA
-755mV    -23.91mA   -23.91mA   -31.62mA
-480mV    -12.22mA   -12.22mA   -13.37mA
455mV     8.3mA      8.051mA    8.3mA
2.215V    12.31mA    11.94mA    12.31mA
2.765V    32.84mA    31.85mA    32.84mA
3.6V      80.37mA    77.96mA    80.37mA
[Pullup]
|Voltage   I(typ)   I(min)   I(max)
-1.8V     69.64mA    52.58mA    81.3mA
-910mV    25.55mA    19.41mA    27.74mA
-415mV    7.654mA    6.149mA    6.163mA
630mV     -8.033mA   -7.792mA   -8.033mA
2.115V    -10.77mA   -10.45mA   -10.77mA
2.335V    -14.38mA   -13.95mA   -14.38mA
2.555V    -22.02mA   -21.36mA   -22.02mA
2.665V    -29.69mA   -28.8mA    -29.69mA
2.72V     -41.99mA   -40.73mA   -41.99mA
2.775V    -65.96mA   -63.98mA   -65.96mA
2.83V     -101.9mA   -98.8mA    -101.9mA
3.6V      -893.2mA   -866.4mA   -893.2mA
[Ramp]
| variable   typ   min   max
dV/dt_r   0.314/0.280n   0.310/0.291n   0.315/0.315n
dV/dt_f   0.319/0.451n   0.309/0.311n   0.320/0.417n
R_load = 50.000
[Rising Waveform]
R_fixture = 50.000
V_fixture = 0.000
V_fixture_min = 0.000
V_fixture_max = 0.000
|  time   V(typ)   V(min)   V(max)
0s        56.24uV    -512.3uV   108.6uV
354ps     176.9nV    -777.7uV   1.71mV
407ps     201.1uV    -814.5uV   -58.47mV
482ps     -2.363mV   -582.1uV   -53.51mV
627ps     -24.06mV   -282.3uV   172.8mV
866ps     333.9mV    -40.81mV   403.3mV
1.224ns   486.7mV    349.9mV    500.9mV
1.484ns   515.8mV    465.1mV    523mV
2.825ns   537.5mV    527.1mV    536mV
10ns      522.7mV    504.7mV    524.5mV
[Rising Waveform]
R_fixture = 50.000
V_fixture = 1.800
V_fixture_min = 1.710
V_fixture_max = 1.890
|  time   V(typ)   V(min)   V(max)
0s        1.269V     1.196V     1.358V
371ps     1.269V     1.196V     1.354V
429ps     1.269V     1.196V     1.487V
514ps     1.266V     1.196V     1.381V
647ps     1.444V     1.197V     1.69V
744ps     1.623V     1.197V     1.804V
867ps     1.742V     1.289V     1.855V
1.098ns   1.787V     1.587V     1.882V
1.768ns   1.799V     1.707V     1.893V
10ns      1.8V       1.712V     1.892V
[Falling Waveform]
R_fixture = 50.000
V_fixture = 1.800
V_fixture_min = 1.710
V_fixture_max = 1.890
|  time   V(typ)   V(min)   V(max)
0s        1.8V       1.712V     1.892V
519ps     1.811V     1.712V     1.944V
571ps     1.808V     1.712V     1.912V
665ps     1.829V     1.713V     1.718V
855ps     1.524V     1.719V     1.614V
972ps     1.427V     1.739V     1.508V
1.285ns   1.344V     1.362V     1.395V
1.582ns   1.293V     1.294V     1.367V
2.662ns   1.268V     1.199V     1.352V
10ns      1.269V     1.196V     1.358V
[Falling Waveform]
R_fixture = 50.000
V_fixture = 0.000
V_fixture_min = 0.000
V_fixture_max = 0.000
|  time   V(typ)   V(min)   V(max)
0s        522.7mV    504.7mV    524.5mV
360ps     522.4mV    504.3mV    538.2mV
463ps     533.5mV    504.4mV    399.1mV
572ps     326.4mV    504.7mV    234.9mV
693ps     190.9mV    517.7mV    63.85mV
803ps     55.08mV    340.2mV    38.04mV
973ps     17.12mV    178.1mV    2.295mV
1.132ns   7.228mV    46.76mV    -963.9uV
1.382ns   -163.9uV   8.685mV    -1.301mV
10ns      56.24uV    -512.3uV   108.6uV
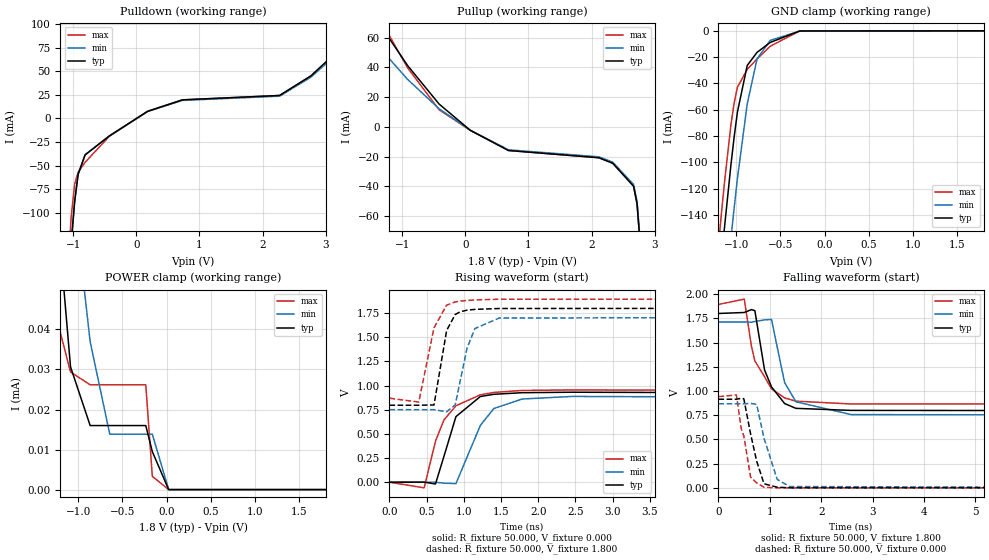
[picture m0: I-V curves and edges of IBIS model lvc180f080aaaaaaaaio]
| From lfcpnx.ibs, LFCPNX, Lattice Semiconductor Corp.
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[Model] lvc180f080aaaaaaaaio
Model_type I/O
Polarity   Non-Inverting
Enable   Active-Low
Vinl =  0.630V
Vinh =  1.170V
Vmeas =  0.900V
Cref =  0.0F
Rref =  1.000M
Vref =  0.0V
C_comp   5.000pF   4.000pF   5.500pF
[Temperature Range]   25.000   0.125k   -40.000
[Voltage Range]   1.800V   1.710V   1.890V
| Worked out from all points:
|   slope of the pulldown table from 0 to 0.27 V, typ, clamps not added: 25.1 ohm
|   slope of the pullup table from 0 to 0.27 V, typ, clamps not added: 36.3 ohm
|   GND clamp passes 1 mA (typ) near -0.37 V on its own axis
|   rising waveform, R_fixture 50.000, V_fixture 0.000: 20-80 % time 227ps typ, 289ps min, 291ps max; typ from 0 V to 0.915 V
|   rising waveform, R_fixture 50.000, V_fixture 1.800: 20-80 % time 130ps typ, 175ps min, 166ps max; typ from 0.796 V to 1.8 V
|   falling waveform, R_fixture 50.000, V_fixture 1.800: 20-80 % time 328ps typ, 278ps min, 385ps max; typ from 1.8 V to 0.796 V
|   falling waveform, R_fixture 50.000, V_fixture 0.000: 20-80 % time 210ps typ, 271ps min, 184ps max; typ from 0.915 V to 0 V
[GND_clamp]
|Voltage   I(typ)   I(min)   I(max)
-1.8V     -665.5mA   -701.9mA   -644.7mA
-1.208V   -203.2mA   -259.3mA   -168.6mA
-1.171V   -176.5mA   -233.3mA   -141.8mA
-1.134V   -150.7mA   -207.7mA   -116.3mA
-1.06V    -102.3mA   -158.3mA   -71.8mA
-1.023V   -80.78mA   -134.8mA   -54.83mA
-986mV    -61.78mA   -112.4mA   -42.93mA
-875mV    -26.33mA   -55.53mA   -29.29mA
-764mV    -16.38mA   -21.41mA   -21.4mA
-616mV    -8.858mA   -7.288mA   -11.79mA
-283mV    -142.7uA   -287uA     -113.6uA
1.8V      1.806nA    0A         -451.7pA
[POWER_clamp]
|Voltage   I(typ)   I(min)   I(max)
-1.8V     186.1uA    259.3uA    183.5uA
-1.382V   94.44uA    136.9uA    91.49uA
-1.345V   89.56uA    127.8uA    77.5uA
-1.308V   84.02uA    119.2uA    62.8uA
-1.234V   68.87uA    103.6uA    41.99uA
-1.086V   30.66uA    80.57uA    29.36uA
-864mV    15.99uA    36.92uA    26.17uA
-642mV    15.99uA    13.83uA    26.17uA
-235mV    15.99uA    13.83uA    26.17uA
-161mV    9.477uA    13.83uA    3.316uA
24mV      0A         0A         261.1pA
1.8V      0A         0A         0A
[Pulldown]
|Voltage   I(typ)   I(min)   I(max)
-1.8V     -1.123A    -1.123A    -1.379A
-1.085V   -187mA     -187mA     -163mA
-1.03V    -131.9mA   -131.9mA   -104mA
-975mV    -88.04mA   -88.04mA   -69.67mA
-920mV    -59.22mA   -59.22mA   -56.86mA
-810mV    -38.63mA   -38.63mA   -46.55mA
-425mV    -18.55mA   -18.55mA   -18.85mA
180mV     7.522mA    7.296mA    7.522mA
730mV     19.66mA    19.07mA    19.66mA
2.27V     24.3mA     23.57mA    24.3mA
2.765V    45.03mA    43.68mA    45.03mA
3.6V      96.4mA     93.5mA     96.4mA
[Pullup]
|Voltage   I(typ)   I(min)   I(max)
-1.8V     97mA       74.36mA    106.2mA
-1.68V    89.47mA    68.72mA    97.1mA
-910mV    41.1mA     31.86mA    39.59mA
-415mV    15.43mA    12.27mA    11.56mA
80mV      -2.292mA   -2.223mA   -2.292mA
685mV     -15.85mA   -15.38mA   -15.85mA
2.115V    -20.71mA   -20.09mA   -20.71mA
2.335V    -24.39mA   -23.66mA   -24.39mA
2.665V    -39.85mA   -38.65mA   -39.85mA
2.72V     -51.63mA   -50.09mA   -51.63mA
2.83V     -111.9mA   -108.5mA   -111.9mA
3.6V      -942.2mA   -913.9mA   -942.2mA
[Ramp]
| variable   typ   min   max
dV/dt_r   0.549/0.227n   0.517/0.288n   0.565/0.291n
dV/dt_f   0.602/0.326n   0.576/0.278n   0.614/0.387n
R_load = 50.000
[Rising Waveform]
R_fixture = 50.000
V_fixture = 0.000
V_fixture_min = 0.000
V_fixture_max = 0.000
|  time   V(typ)   V(min)   V(max)
0s        66.63uV    -485.3uV   428.6uV
466ps     1.261mV    -537.8uV   -58.18mV
619ps     -18.33mV   -250.8uV   423.9mV
734ps     270.9mV    -9.504mV   645.6mV
894ps     678.2mV    -14.32mV   790.7mV
1.222ns   886.2mV    586.8mV    903.9mV
1.404ns   909.1mV    762.2mV    928.4mV
1.784ns   925.6mV    860.5mV    949mV
2.454ns   930.6mV    886.8mV    954.3mV
10ns      914.5mV    866.9mV    941.3mV
[Rising Waveform]
R_fixture = 50.000
V_fixture = 1.800
V_fixture_min = 1.710
V_fixture_max = 1.890
|  time   V(typ)   V(min)   V(max)
0s        796mV      750.1mV    868.6mV
394ps     796.1mV    749.7mV    828.8mV
599ps     798.8mV    750.3mV    1.596V
769ps     1.569V     728.2mV    1.831V
884ps     1.734V     799.4mV    1.864V
954ps     1.763V     1.057V     1.873V
1.044ns   1.779V     1.388V     1.879V
1.15ns    1.787V     1.589V     1.885V
1.474ns   1.796V     1.697V     1.892V
10ns      1.8V       1.712V     1.893V
[Falling Waveform]
R_fixture = 50.000
V_fixture = 1.800
V_fixture_min = 1.710
V_fixture_max = 1.890
|  time   V(typ)   V(min)   V(max)
0s        1.8V       1.712V     1.893V
502ps     1.81V      1.712V     1.948V
642ps     1.84V      1.71V      1.46V
708ps     1.829V     1.717V     1.311V
897ps     1.216V     1.734V     1.146V
1.032ns   1.042V     1.738V     1.022V
1.287ns   870.1mV    1.086V     928.2mV
1.507ns   820.4mV    888.3mV    894.6mV
2.582ns   799.2mV    756.2mV    865.5mV
10ns      796mV      750.1mV    868.6mV
[Falling Waveform]
R_fixture = 50.000
V_fixture = 0.000
V_fixture_min = 0.000
V_fixture_max = 0.000
|  time   V(typ)   V(min)   V(max)
0s        914.5mV    866.9mV    941.3mV
349ps     914.4mV    866.7mV    959mV
440ps     924mV      866.8mV    618mV
493ps     919.6mV    866.7mV    534.8mV
625ps     556.8mV    872mV      110.6mV
743ps     275.9mV    861.7mV    50.68mV
887ps     41.44mV    510.6mV    5.746mV
1.143ns   6.087mV    87.09mV    -293.8uV
1.383ns   454.4uV    13.23mV    -486.8uV
10ns      66.63uV    -485.3uV   428.6uV
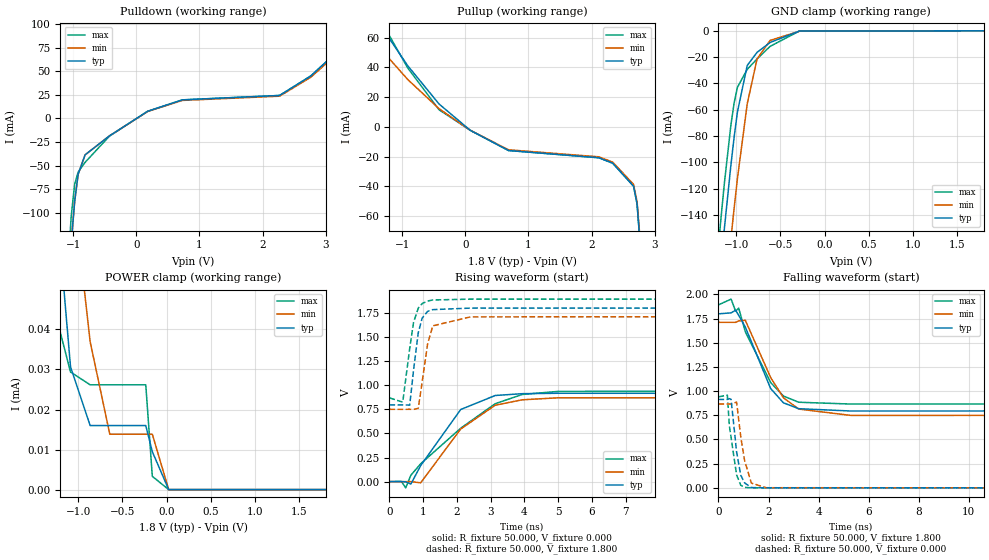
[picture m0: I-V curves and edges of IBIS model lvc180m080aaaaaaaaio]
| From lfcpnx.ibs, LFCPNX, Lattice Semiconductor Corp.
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[Model] lvc180m080aaaaaaaaio
Model_type I/O
Polarity   Non-Inverting
Enable   Active-Low
Vinl =  0.630V
Vinh =  1.170V
Vmeas =  0.900V
Cref =  0.0F
Rref =  1.000M
Vref =  0.0V
C_comp   5.000pF   4.000pF   5.500pF
[Temperature Range]   25.000   0.125k   -40.000
[Voltage Range]   1.800V   1.710V   1.890V
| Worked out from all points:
|   slope of the pulldown table from 0 to 0.27 V, typ, clamps not added: 25.1 ohm
|   slope of the pullup table from 0 to 0.27 V, typ, clamps not added: 36.3 ohm
|   GND clamp passes 1 mA (typ) near -0.37 V on its own axis
|   rising waveform, R_fixture 50.000, V_fixture 0.000: 20-80 % time 1.11ns typ, 1.28ns min, 1.93ns max; typ from 0 V to 0.915 V
|   rising waveform, R_fixture 50.000, V_fixture 1.800: 20-80 % time 215ps typ, 245ps min, 255ps max; typ from 0.796 V to 1.8 V
|   falling waveform, R_fixture 50.000, V_fixture 1.800: 20-80 % time 997ps typ, 1.13ns min, 1.14ns max; typ from 1.8 V to 0.796 V
|   falling waveform, R_fixture 50.000, V_fixture 0.000: 20-80 % time 278ps typ, 308ps min, 261ps max; typ from 0.915 V to 0 V
[GND_clamp]
|Voltage   I(typ)   I(min)   I(max)
-1.8V     -665.5mA   -701.9mA   -644.7mA
-1.208V   -203.2mA   -259.3mA   -168.6mA
-1.171V   -176.5mA   -233.3mA   -141.8mA
-1.134V   -150.7mA   -207.7mA   -116.3mA
-1.06V    -102.3mA   -158.3mA   -71.8mA
-1.023V   -80.78mA   -134.8mA   -54.83mA
-986mV    -61.78mA   -112.4mA   -42.93mA
-875mV    -26.33mA   -55.53mA   -29.29mA
-764mV    -16.38mA   -21.41mA   -21.4mA
-616mV    -8.858mA   -7.288mA   -11.79mA
-283mV    -142.7uA   -287uA     -113.6uA
1.8V      1.806nA    0A         -451.7pA
[POWER_clamp]
|Voltage   I(typ)   I(min)   I(max)
-1.8V     186.1uA    259.3uA    183.5uA
-1.382V   94.44uA    136.9uA    91.49uA
-1.345V   89.56uA    127.8uA    77.5uA
-1.308V   84.02uA    119.2uA    62.8uA
-1.234V   68.87uA    103.6uA    41.99uA
-1.086V   30.66uA    80.57uA    29.36uA
-864mV    15.99uA    36.92uA    26.17uA
-642mV    15.99uA    13.83uA    26.17uA
-235mV    15.99uA    13.83uA    26.17uA
-161mV    9.477uA    13.83uA    3.316uA
24mV      0A         0A         261.1pA
1.8V      0A         0A         0A
[Pulldown]
|Voltage   I(typ)   I(min)   I(max)
-1.8V     -1.123A    -1.123A    -1.379A
-1.085V   -187mA     -187mA     -163mA
-1.03V    -131.9mA   -131.9mA   -104mA
-975mV    -88.04mA   -88.04mA   -69.67mA
-920mV    -59.22mA   -59.22mA   -56.86mA
-810mV    -38.63mA   -38.63mA   -46.55mA
-425mV    -18.55mA   -18.55mA   -18.85mA
180mV     7.522mA    7.296mA    7.522mA
730mV     19.66mA    19.07mA    19.66mA
2.27V     24.3mA     23.57mA    24.3mA
2.765V    45.03mA    43.68mA    45.03mA
3.6V      96.4mA     93.5mA     96.4mA
[Pullup]
|Voltage   I(typ)   I(min)   I(max)
-1.8V     97mA       74.36mA    106.2mA
-1.68V    89.47mA    68.72mA    97.1mA
-910mV    41.1mA     31.86mA    39.59mA
-415mV    15.43mA    12.27mA    11.56mA
80mV      -2.292mA   -2.223mA   -2.292mA
685mV     -15.85mA   -15.38mA   -15.85mA
2.115V    -20.71mA   -20.09mA   -20.71mA
2.335V    -24.39mA   -23.66mA   -24.39mA
2.665V    -39.85mA   -38.65mA   -39.85mA
2.72V     -51.63mA   -50.09mA   -51.63mA
2.83V     -111.9mA   -108.5mA   -111.9mA
3.6V      -942.2mA   -913.9mA   -942.2mA
[Ramp]
| variable   typ   min   max
dV/dt_r   0.549/1.109n   0.513/1.282n   0.565/1.934n
dV/dt_f   0.602/0.994n   0.576/1.126n   0.614/1.145n
R_load = 50.000
[Rising Waveform]
R_fixture = 50.000
V_fixture = 0.000
V_fixture_min = 0.000
V_fixture_max = 0.000
|  time   V(typ)   V(min)   V(max)
0s        66.63uV    -485.3uV   428.6uV
355ps     61.17uV    -769.4uV   2.147mV
480ps     -1.959mV   -507.1uV   -64.87mV
634ps     -25.77mV   -238.6uV   66.11mV
924ps     165.7mV    -12.63mV   184.8mV
2.111ns   747.8mV    545.5mV    553.9mV
3.134ns   893.3mV    792.5mV    807.8mV
3.931ns   912.1mV    848.5mV    903.8mV
5.01ns    916.6mV    869.7mV    936mV
20ns      914.5mV    866.9mV    941.3mV
[Rising Waveform]
R_fixture = 50.000
V_fixture = 1.800
V_fixture_min = 1.710
V_fixture_max = 1.890
|  time   V(typ)   V(min)   V(max)
0s        796mV      750.1mV    868.6mV
393ps     796.1mV    749.7mV    824.2mV
600ps     793.3mV    750.3mV    1.382V
713ps     1.155V     748.9mV    1.651V
853ps     1.544V     760.1mV    1.799V
970ps     1.697V     1.036V     1.847V
1.13ns    1.766V     1.427V     1.873V
1.284ns   1.784V     1.616V     1.884V
2.403ns   1.8V       1.709V     1.893V
20ns      1.8V       1.712V     1.893V
[Falling Waveform]
R_fixture = 50.000
V_fixture = 1.800
V_fixture_min = 1.710
V_fixture_max = 1.890
|  time   V(typ)   V(min)   V(max)
0s        1.8V       1.712V     1.893V
505ps     1.81V      1.712V     1.952V
684ps     1.837V     1.712V     1.827V
807ps     1.784V     1.727V     1.859V
1.072ns   1.663V     1.733V     1.614V
2.083ns   1.027V     1.141V     1.089V
2.594ns   879.3mV    931.6mV    949.4mV
3.202ns   818.6mV    814.8mV    885.3mV
5.297ns   794.4mV    748.6mV    866.4mV
20ns      796mV      750.1mV    868.6mV
[Falling Waveform]
R_fixture = 50.000
V_fixture = 0.000
V_fixture_min = 0.000
V_fixture_max = 0.000
|  time   V(typ)   V(min)   V(max)
0s        914.5mV    866.9mV    941.3mV
354ps     914.3mV    866.7mV    958.2mV
434ps     922.3mV    866.8mV    642.2mV
502ps     915.7mV    866.7mV    521.9mV
723ps     372.8mV    886.2mV    133.9mV
887ps     132.1mV    532.9mV    27.42mV
1.042ns   51.01mV    283.1mV    4.015mV
1.313ns   2.605mV    48.97mV    23.75uV
1.903ns   157.2uV    875.7uV    -155.6uV
20ns      66.63uV    -485.3uV   428.6uV
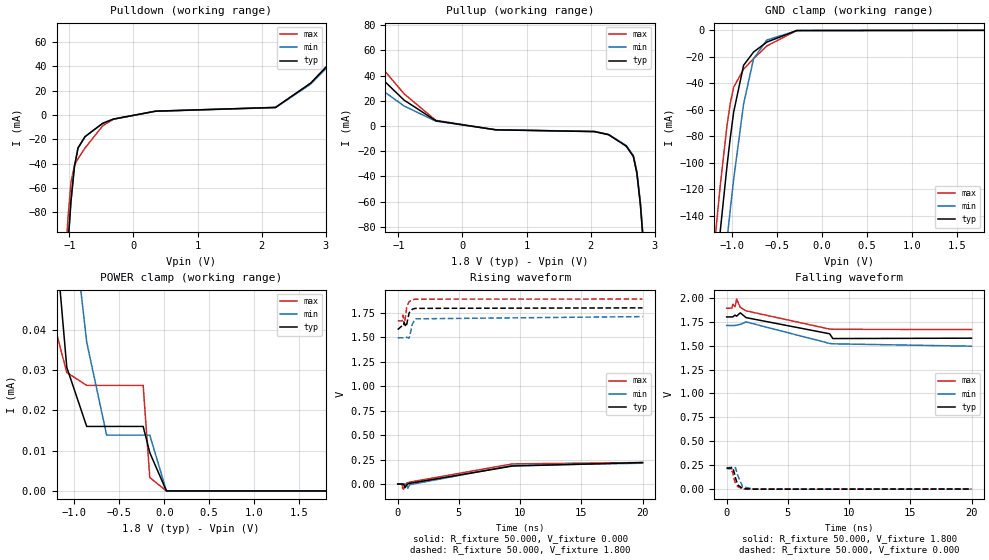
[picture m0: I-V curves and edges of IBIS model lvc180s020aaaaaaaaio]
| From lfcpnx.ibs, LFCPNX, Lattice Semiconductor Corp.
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[Model] lvc180s020aaaaaaaaio
Model_type I/O
Polarity   Non-Inverting
Enable   Active-Low
Vinl =  0.630V
Vinh =  1.170V
Vmeas =  0.900V
Cref =  0.0F
Rref =  1.000M
Vref =  0.0V
C_comp   5.000pF   4.000pF   5.500pF
[Temperature Range]   25.000   0.125k   -40.000
[Voltage Range]   1.800V   1.710V   1.890V
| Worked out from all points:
|   slope of the pulldown table from 0 to 0.27 V, typ, clamps not added: 107 ohm
|   slope of the pullup table from 0 to 0.27 V, typ, clamps not added: 152 ohm
|   GND clamp passes 1 mA (typ) near -0.37 V on its own axis
|   rising waveform, R_fixture 50.000, V_fixture 0.000: 20-80 % time 5.47ns typ, 4.91ns min, 5.21ns max; typ from 0 V to 0.22 V
|   rising waveform, R_fixture 50.000, V_fixture 1.800: 20-80 % time 243ps typ, 239ps min, 206ps max; typ from 1.58 V to 1.8 V
|   falling waveform, R_fixture 50.000, V_fixture 1.800: 20-80 % time 5.28ns typ, 3.94ns min, 3.91ns max; typ from 1.8 V to 1.58 V
|   falling waveform, R_fixture 50.000, V_fixture 0.000: 20-80 % time 323ps typ, 359ps min, 330ps max; typ from 0.22 V to 0 V
[GND_clamp]
|Voltage   I(typ)   I(min)   I(max)
-1.8V     -665.5mA   -701.9mA   -644.7mA
-1.208V   -203.2mA   -259.3mA   -168.6mA
-1.171V   -176.5mA   -233.3mA   -141.8mA
-1.134V   -150.7mA   -207.7mA   -116.3mA
-1.06V    -102.3mA   -158.3mA   -71.8mA
-1.023V   -80.78mA   -134.8mA   -54.83mA
-986mV    -61.78mA   -112.4mA   -42.93mA
-875mV    -26.33mA   -55.53mA   -29.29mA
-764mV    -16.38mA   -21.41mA   -21.4mA
-616mV    -8.858mA   -7.288mA   -11.79mA
-283mV    -142.7uA   -287uA     -113.6uA
1.8V      1.806nA    0A         -451.7pA
[POWER_clamp]
|Voltage   I(typ)   I(min)   I(max)
-1.8V     186.1uA    259.3uA    183.5uA
-1.382V   94.44uA    136.9uA    91.49uA
-1.345V   89.56uA    127.8uA    77.5uA
-1.308V   84.02uA    119.2uA    62.8uA
-1.234V   68.87uA    103.6uA    41.99uA
-1.086V   30.66uA    80.57uA    29.36uA
-864mV    15.99uA    36.92uA    26.17uA
-642mV    15.99uA    13.83uA    26.17uA
-235mV    15.99uA    13.83uA    26.17uA
-161mV    9.477uA    13.83uA    3.316uA
24mV      0A         0A         261.1pA
1.8V      0A         0A         0A
[Pulldown]
|Voltage   I(typ)   I(min)   I(max)
-1.8V     -1.023A    -1.023A    -1.31A
-1.03V    -113.2mA   -113.2mA   -90.97mA
-975mV    -71.04mA   -71.04mA   -55.48mA
-920mV    -42.35mA   -42.35mA   -41.66mA
-865mV    -27.27mA   -27.27mA   -36.05mA
-755mV    -17.88mA   -17.88mA   -27.26mA
-480mV    -6.982mA   -6.982mA   -9.028mA
-315mV    -3.511mA   -3.511mA   -3.643mA
345mV     3.015mA    2.925mA    3.015mA
2.215V    6.102mA    5.919mA    6.102mA
2.765V    26.08mA    25.3mA     26.08mA
3.6V      72.13mA    69.96mA    72.13mA
[Pullup]
|Voltage   I(typ)   I(min)   I(max)
-1.8V     64.13mA    48.54mA    78.9mA
-910mV    20.55mA    15.86mA    25.57mA
-415mV    4.154mA    3.826mA    4.468mA
520mV     -3.053mA   -2.961mA   -3.053mA
2.06V     -4.457mA   -4.323mA   -4.457mA
2.28V     -6.921mA   -6.713mA   -6.921mA
2.555V    -16.01mA   -15.53mA   -16.01mA
2.665V    -24.11mA   -23.39mA   -24.11mA
2.72V     -37.19mA   -36.07mA   -37.19mA
2.775V    -62.11mA   -60.25mA   -62.11mA
2.83V     -98.7mA    -95.7mA    -98.7mA
3.6V      -890.9mA   -864.2mA   -890.9mA
[Ramp]
| variable   typ   min   max
dV/dt_r   0.132/5.478n   0.128/4.907n   0.132/5.203n
dV/dt_f   0.133/4.050n   0.130/4.479n   0.133/4.437n
R_load = 50.000
[Rising Waveform]
R_fixture = 50.000
V_fixture = 0.000
V_fixture_min = 0.000
V_fixture_max = 0.000
|  time   V(typ)   V(min)   V(max)
0s        42.3uV     -225.7uV   288.9uV
354ps     -15.16uV   -355.1uV   1.497mV
407ps     97.38uV    -388.3uV   -45.75mV
478ps     -1.262mV   -282.6uV   -51.84mV
596ps     -36.81mV   -159uV     -10.21mV
705ps     -12.08mV   -60.04uV   8.118mV
824ps     1.786mV    -41.5mV    14.73mV
984ps     8.087mV    -5.929mV   20.17mV
9.376ns   184.3mV    191mV      206.3mV
20ns      220.1mV    213.4mV    220.2mV
[Rising Waveform]
R_fixture = 50.000
V_fixture = 1.800
V_fixture_min = 1.710
V_fixture_max = 1.890
|  time   V(typ)   V(min)   V(max)
0s        1.578V     1.494V     1.668V
363ps     1.618V     1.494V     1.667V
444ps     1.619V     1.494V     1.726V
530ps     1.649V     1.494V     1.626V
676ps     1.608V     1.494V     1.75V
734ps     1.632V     1.501V     1.813V
934ps     1.75V      1.491V     1.864V
1.204ns   1.787V     1.637V     1.884V
1.434ns   1.795V     1.688V     1.889V
20ns      1.8V       1.711V     1.89V
[Falling Waveform]
R_fixture = 50.000
V_fixture = 1.800
V_fixture_min = 1.710
V_fixture_max = 1.890
|  time   V(typ)   V(min)   V(max)
0s        1.8V       1.711V     1.89V
435ps     1.8V       1.711V     1.893V
501ps     1.801V     1.711V     1.933V
681ps     1.819V     1.711V     1.906V
811ps     1.808V     1.714V     1.987V
1.109ns   1.843V     1.722V     1.9V
1.581ns   1.793V     1.748V     1.864V
8.408ns   1.624V     1.523V     1.673V
8.67ns    1.574V     1.519V     1.671V
20ns      1.578V     1.494V     1.668V
[Falling Waveform]
R_fixture = 50.000
V_fixture = 0.000
V_fixture_min = 0.000
V_fixture_max = 0.000
|  time   V(typ)   V(min)   V(max)
0s        220.1mV    213.4mV    220.2mV
367ps     219.9mV    213.3mV    227.2mV
444ps     226.3mV    213.3mV    178.4mV
492ps     226.3mV    213.3mV    181.2mV
623ps     169.5mV    215.8mV    91.62mV
717ps     116.1mV    225.3mV    65.26mV
908ps     42.54mV    141.1mV    24.12mV
1.303ns   5.931mV    24.47mV    -180.5uV
2.197ns   -983.4uV   -984.7uV   -1.151mV
20ns      42.3uV     -225.7uV   288.9uV
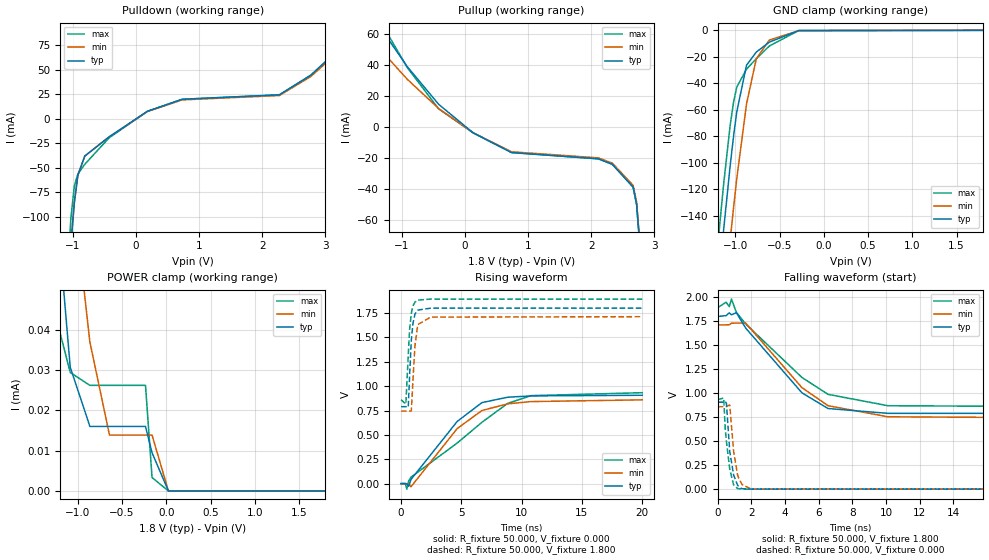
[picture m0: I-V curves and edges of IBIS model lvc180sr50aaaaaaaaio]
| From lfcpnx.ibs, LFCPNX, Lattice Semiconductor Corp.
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[Model] lvc180sr50aaaaaaaaio
Model_type I/O
Polarity   Non-Inverting
Enable   Active-Low
Vinl =  0.630V
Vinh =  1.170V
Vmeas =  0.900V
Cref =  0.0F
Rref =  1.000M
Vref =  0.0V
C_comp   5.000pF   4.000pF   5.500pF
[Temperature Range]   25.000   0.125k   -40.000
[Voltage Range]   1.800V   1.710V   1.890V
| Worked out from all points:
|   slope of the pulldown table from 0 to 0.27 V, typ, clamps not added: 25 ohm
|   slope of the pullup table from 0 to 0.27 V, typ, clamps not added: 36.9 ohm
|   GND clamp passes 1 mA (typ) near -0.37 V on its own axis
|   rising waveform, R_fixture 50.000, V_fixture 0.000: 20-80 % time 3.66ns typ, 3.83ns min, 5.66ns max; typ from 0 V to 0.906 V
|   rising waveform, R_fixture 50.000, V_fixture 1.800: 20-80 % time 266ps typ, 284ps min, 278ps max; typ from 0.789 V to 1.8 V
|   falling waveform, R_fixture 50.000, V_fixture 1.800: 20-80 % time 3.02ns typ, 3.23ns min, 3.87ns max; typ from 1.8 V to 0.789 V
|   falling waveform, R_fixture 50.000, V_fixture 0.000: 20-80 % time 323ps typ, 325ps min, 342ps max; typ from 0.906 V to 0 V
[GND_clamp]
|Voltage   I(typ)   I(min)   I(max)
-1.8V     -665.5mA   -701.9mA   -644.7mA
-1.208V   -203.2mA   -259.3mA   -168.6mA
-1.171V   -176.5mA   -233.3mA   -141.8mA
-1.134V   -150.7mA   -207.7mA   -116.3mA
-1.06V    -102.3mA   -158.3mA   -71.8mA
-1.023V   -80.78mA   -134.8mA   -54.83mA
-986mV    -61.78mA   -112.4mA   -42.93mA
-875mV    -26.33mA   -55.53mA   -29.29mA
-764mV    -16.38mA   -21.41mA   -21.4mA
-616mV    -8.858mA   -7.288mA   -11.79mA
-283mV    -142.7uA   -287uA     -113.6uA
1.8V      1.806nA    0A         -451.7pA
[POWER_clamp]
|Voltage   I(typ)   I(min)   I(max)
-1.8V     186.1uA    259.3uA    183.5uA
-1.382V   94.44uA    136.9uA    91.5uA
-1.345V   89.56uA    127.8uA    77.5uA
-1.308V   84.02uA    119.2uA    62.8uA
-1.234V   68.87uA    103.6uA    41.99uA
-1.086V   30.66uA    80.57uA    29.36uA
-864mV    15.99uA    36.92uA    26.17uA
-642mV    15.99uA    13.83uA    26.17uA
-235mV    15.99uA    13.83uA    26.17uA
-161mV    9.477uA    13.83uA    3.316uA
24mV      0A         0A         261.1pA
1.8V      0A         0A         0A
[Pulldown]
|Voltage   I(typ)   I(min)   I(max)
-1.8V     -1.08A     -1.08A     -1.33A
-1.085V   -180.2mA   -180.2mA   -157.9mA
-1.03V    -127.4mA   -127.4mA   -101.4mA
-975mV    -85.32mA   -85.32mA   -68.58mA
-920mV    -57.77mA   -57.77mA   -56.42mA
-810mV    -38.12mA   -38.12mA   -46.5mA
-425mV    -18.55mA   -18.55mA   -19.56mA
180mV     7.533mA    7.307mA    7.533mA
730mV     19.82mA    19.22mA    19.82mA
2.27V     24.38mA    23.65mA    24.38mA
2.765V    44.29mA    42.96mA    44.29mA
3.6V      93.7mA     90.9mA     93.7mA
[Pullup]
|Voltage   I(typ)   I(min)   I(max)
-1.8V     91.5mA     70.91mA    100.9mA
-1.68V    84.4mA     65.64mA    92.4mA
-910mV    39.09mA    30.91mA    38.48mA
-415mV    14.81mA    12.09mA    11.85mA
135mV     -3.76mA    -3.647mA   -3.76mA
740mV     -16.41mA   -15.92mA   -16.41mA
2.115V    -20.46mA   -19.85mA   -20.46mA
2.335V    -23.98mA   -23.26mA   -23.98mA
2.665V    -38.74mA   -37.57mA   -38.74mA
2.72V     -49.95mA   -48.45mA   -49.95mA
2.83V     -107.4mA   -104.1mA   -107.4mA
3.6V      -902.3mA   -875.2mA   -902.3mA
[Ramp]
| variable   typ   min   max
dV/dt_r   0.544/3.664n   0.533/3.830n   0.561/5.668n
dV/dt_f   0.606/3.024n   0.580/3.238n   0.618/3.871n
R_load = 50.000
[Rising Waveform]
R_fixture = 50.000
V_fixture = 0.000
V_fixture_min = 0.000
V_fixture_max = 0.000
|  time   V(typ)   V(min)   V(max)
0s        66.03uV    -537.3uV   750.2uV
351ps     55.25uV    -847uV     2.818mV
480ps     -1.887mV   -564.7uV   -56.64mV
634ps     -27.09mV   -255.6uV   27.17mV
824ps     42.32mV    -31.89mV   66.31mV
4.662ns   638.5mV    565.5mV    416.9mV
6.71ns    831.3mV    750.1mV    629.4mV
8.84ns    886.2mV    818.5mV    823.1mV
10.76ns   899.7mV    841.5mV    902.4mV
20ns      906.4mV    859.4mV    932.6mV
[Rising Waveform]
R_fixture = 50.000
V_fixture = 1.800
V_fixture_min = 1.710
V_fixture_max = 1.890
|  time   V(typ)   V(min)   V(max)
0s        789.2mV    744.2mV    861.1mV
401ps     789.4mV    743.7mV    815.2mV
600ps     783.6mV    744.4mV    1.316V
714ps     1.112V     743.1mV    1.583V
853ps     1.471V     745.6mV    1.748V
984ps     1.64V      1.045V     1.821V
1.154ns   1.739V     1.411V     1.861V
1.384ns   1.78V      1.631V     1.882V
2.463ns   1.8V       1.708V     1.893V
20ns      1.8V       1.712V     1.892V
[Falling Waveform]
R_fixture = 50.000
V_fixture = 1.800
V_fixture_min = 1.710
V_fixture_max = 1.890
|  time   V(typ)   V(min)   V(max)
0s        1.8V       1.712V     1.892V
494ps     1.808V     1.712V     1.948V
684ps     1.837V     1.713V     1.902V
814ps     1.817V     1.729V     1.981V
1.105ns   1.839V     1.731V     1.842V
1.661ns   1.678V     1.73V      1.721V
5ns       1.004V     1.058V     1.164V
6.554ns   839.9mV    869.2mV    987.7mV
10.12ns   789.9mV    753.8mV    869.1mV
20ns      789.2mV    744.2mV    861.1mV
[Falling Waveform]
R_fixture = 50.000
V_fixture = 0.000
V_fixture_min = 0.000
V_fixture_max = 0.000
|  time   V(typ)   V(min)   V(max)
0s        906.4mV    859.4mV    932.6mV
354ps     906.1mV    859.1mV    949.4mV
441ps     915.9mV    859.3mV    634.8mV
514ps     893.7mV    859.2mV    499.3mV
711ps     392.8mV    876.8mV    208mV
941ps     148mV      395mV      44.67mV
1.182ns   37.98mV    141.6mV    5.471mV
1.432ns   4.512mV    49.14mV    585.3uV
1.971ns   60.21uV    1.921mV    -51.46uV
20ns      66.03uV    -537.3uV   750.2uV
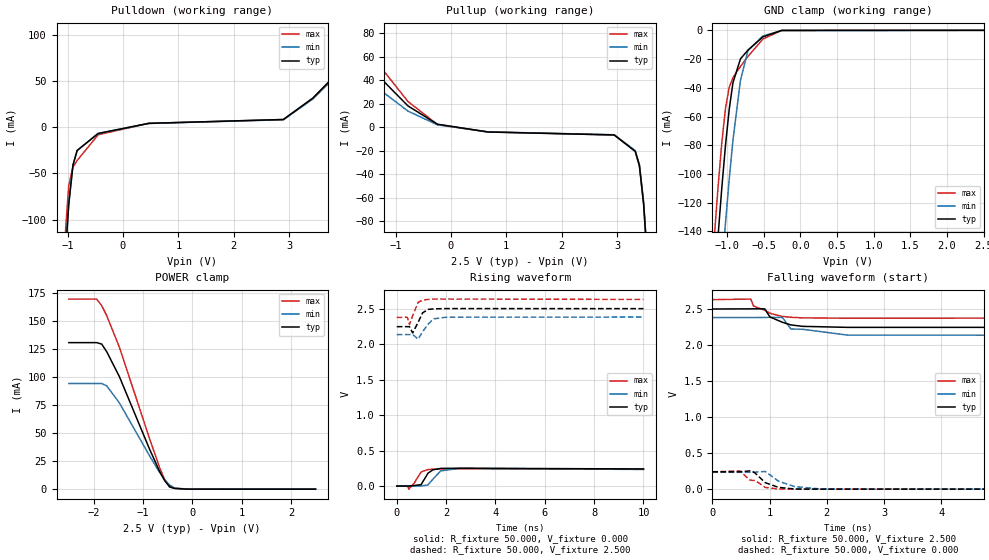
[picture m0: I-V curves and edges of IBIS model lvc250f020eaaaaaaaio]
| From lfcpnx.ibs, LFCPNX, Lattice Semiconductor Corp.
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[Model] lvc250f020eaaaaaaaio
Model_type I/O
Polarity   Non-Inverting
Enable   Active-Low
Vinl =  0.700V
Vinh =  1.700V
Vmeas =  1.250V
Cref =  0.0F
Rref =  1.000M
Vref =  0.0V
C_comp   5.000pF   4.000pF   5.500pF
[Temperature Range]   25.000   0.125k   -40.000
[Voltage Range]   2.500V   2.380V   2.630V
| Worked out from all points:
|   slope of the pulldown table from 0 to 0.375 V, typ, clamps not added: 103 ohm
|   slope of the pullup table from 0 to 0.375 V, typ, clamps not added: 135 ohm
|   GND clamp passes 1 mA (typ) near -0.37 V on its own axis
|   POWER clamp passes 1 mA (typ) near -0.40 V on its own axis
|   rising waveform, R_fixture 50.000, V_fixture 0.000: 20-80 % time 250ps typ, 288ps min, 245ps max; typ from 0 V to 0.24 V
|   rising waveform, R_fixture 50.000, V_fixture 2.500: 20-80 % time 218ps typ, 297ps min, 169ps max; typ from 2.25 V to 2.5 V
|   falling waveform, R_fixture 50.000, V_fixture 2.500: 20-80 % time 326ps typ, 485ps min, 355ps max; typ from 2.5 V to 2.25 V
|   falling waveform, R_fixture 50.000, V_fixture 0.000: 20-80 % time 295ps typ, 350ps min, 278ps max; typ from 0.24 V to 0 V
[GND_clamp]
|Voltage   I(typ)   I(min)   I(max)
-2.5V     -1.233A    -1.246A    -1.23A
-1.174V   -179.1mA   -235.9mA   -144.4mA
-1.123V   -143.6mA   -200.7mA   -109.5mA
-1.072V   -110.2mA   -166.6mA   -78.57mA
-1.021V   -80.08mA   -134.1mA   -54.34mA
-970mV    -54.89mA   -103.7mA   -39.63mA
-919mV    -36.41mA   -76.3mA    -32.99mA
-817mV    -19.89mA   -34.81mA   -25.2mA
-715mV    -13.78mA   -14.11mA   -18.16mA
-511mV    -4.596mA   -3.904mA   -6.102mA
-256mV    -63.21uA   -177.9uA   -38.32uA
2.5V      -23.56nA   0A         -150.9nA
[POWER_clamp]
|Voltage   I(typ)   I(min)   I(max)
-2.5V     130.9mA    94.41mA    169.8mA
-1.937V   130.9mA    94.41mA    169.8mA
-1.835V   129.6mA    94.41mA    163.9mA
-1.733V   122.8mA    92.29mA    155mA
-1.478V   100.7mA    77.18mA    127mA
-866mV    35.87mA    29.9mA     45.33mA
-662mV    16.03mA    15.02mA    19.46mA
-560mV    7.73mA     8.668mA    8.662mA
-458mV    2.143mA    3.687mA    1.896mA
-356mV    647.1uA    1.015mA    754.8uA
-101mV    23.95uA    66.65uA    14.28uA
2.5V      0A         0A         0A
[Pulldown]
|Voltage   I(typ)   I(min)   I(max)
-2.5V     -2.133A    -2.133A    -2.742A
-1.056V   -153.2mA   -153.2mA   -127.1mA
-980mV    -83.55mA   -83.55mA   -63.14mA
-904mV    -41.24mA   -41.24mA   -43.39mA
-828mV    -25.25mA   -25.25mA   -36.06mA
-448mV    -6.819mA   -6.819mA   -8.226mA
464mV     4.094mA    3.971mA    4.094mA
2.896V    8.243mA    7.995mA    8.243mA
3.428V    31.33mA    30.39mA    31.33mA
4.568V    100.7mA    97.7mA     100.7mA
4.796V    109.3mA    106mA      109.3mA
5V        113.2mA    109.8mA    113.2mA
[Pullup]
|Voltage   I(typ)   I(min)   I(max)
-2.5V     86.2mA     66.76mA    107.5mA
-2.22V    82.8mA     62.52mA    103.2mA
-1.84V    68.85mA    51.8mA     85mA
-776mV    18.05mA    13.65mA    21.79mA
-244mV    2.496mA    1.95mA     2.315mA
668mV     -4.11mA    -3.987mA   -4.11mA
2.948V    -6.657mA   -6.457mA   -6.657mA
3.328V    -20.53mA   -19.92mA   -20.53mA
3.404V    -32.88mA   -31.89mA   -32.88mA
3.48V     -65.7mA    -63.73mA   -65.7mA
3.556V    -120mA     -116.4mA   -120mA
5V        -1.665A    -1.615A    -1.665A
[Ramp]
| variable   typ   min   max
dV/dt_r   0.144/0.256n   0.142/0.294n   0.144/0.251n
dV/dt_f   0.152/0.325n   0.143/0.493n   0.153/0.355n
R_load = 50.000
[Rising Waveform]
R_fixture = 50.000
V_fixture = 0.000
V_fixture_min = 0.000
V_fixture_max = 0.000
|  time   V(typ)   V(min)   V(max)
0s        57.57uV    336.8uV    159.8uV
434ps     72.86uV    164.9uV    2.234mV
487ps     102.9uV    269.6uV    -44.25mV
705ps     6.996mV    301.1uV    40.89mV
986ps     19.87mV    584.2uV    198.6mV
1.265ns   180.9mV    15.79mV    232.6mV
1.464ns   228.3mV    96.56mV    237.8mV
1.784ns   248.5mV    213.8mV    240.1mV
2.554ns   251.2mV    249.2mV    241.7mV
10ns      240.5mV    233.7mV    240.5mV
[Rising Waveform]
R_fixture = 50.000
V_fixture = 2.500
V_fixture_min = 2.380
V_fixture_max = 2.630
|  time   V(typ)   V(min)   V(max)
0s        2.246V     2.134V     2.376V
425ps     2.246V     2.134V     2.379V
515ps     2.246V     2.134V     2.275V
644ps     2.157V     2.135V     2.401V
865ps     2.307V     2.071V     2.59V
1.046ns   2.441V     2.173V     2.62V
1.275ns   2.489V     2.284V     2.631V
1.495ns   2.497V     2.356V     2.634V
1.996ns   2.501V     2.379V     2.635V
10ns      2.5V       2.381V     2.63V
[Falling Waveform]
R_fixture = 50.000
V_fixture = 2.500
V_fixture_min = 2.380
V_fixture_max = 2.630
|  time   V(typ)   V(min)   V(max)
0s        2.5V       2.381V     2.63V
670ps     2.502V     2.381V     2.638V
720ps     2.503V     2.381V     2.541V
915ps     2.502V     2.383V     2.483V
1.005ns   2.39V      2.384V     2.441V
1.222ns   2.316V     2.383V     2.397V
1.372ns   2.279V     2.222V     2.385V
1.582ns   2.259V     2.218V     2.377V
2.37ns    2.245V     2.137V     2.372V
10ns      2.246V     2.134V     2.376V
[Falling Waveform]
R_fixture = 50.000
V_fixture = 0.000
V_fixture_min = 0.000
V_fixture_max = 0.000
|  time   V(typ)   V(min)   V(max)
0s        240.5mV    233.7mV    240.5mV
487ps     239.7mV    233.6mV    251.6mV
647ps     252.3mV    233.3mV    127.6mV
684ps     252.2mV    233.4mV    121.4mV
747ps     222.1mV    235.2mV    119.8mV
924ps     88.99mV    244.1mV    23.14mV
1.155ns   23.86mV    109.7mV    1.621mV
1.434ns   1.319mV    35.21mV    -1.066mV
1.894ns   -595.3uV   1.097mV    -1.1mV
10ns      57.57uV    336.8uV    159.8uV
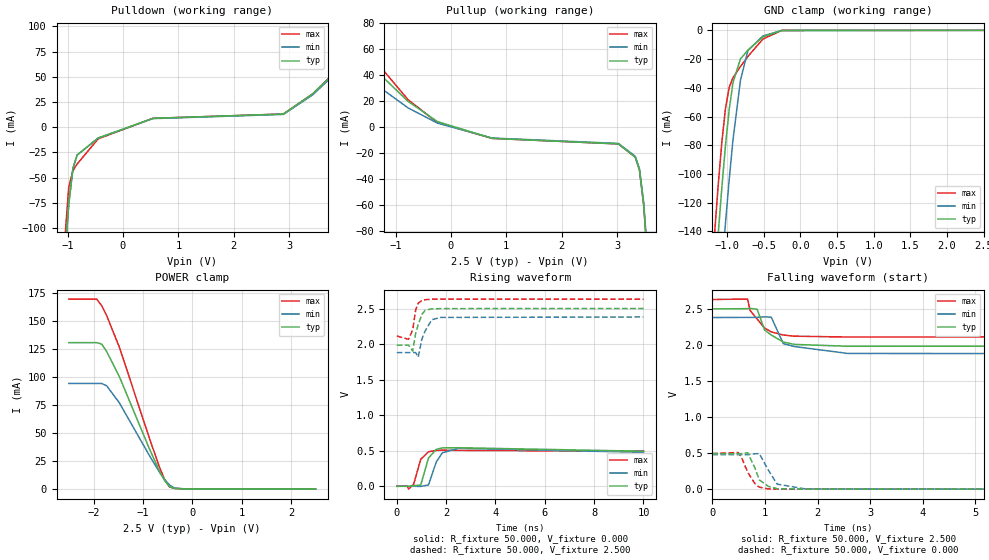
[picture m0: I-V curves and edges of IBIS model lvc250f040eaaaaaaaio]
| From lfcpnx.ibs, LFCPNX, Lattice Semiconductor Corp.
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[Model] lvc250f040eaaaaaaaio
Model_type I/O
Polarity   Non-Inverting
Enable   Active-Low
Vinl =  0.700V
Vinh =  1.700V
Vmeas =  1.250V
Cref =  0.0F
Rref =  1.000M
Vref =  0.0V
C_comp   5.000pF   4.000pF   5.500pF
[Temperature Range]   25.000   0.125k   -40.000
[Voltage Range]   2.500V   2.380V   2.630V
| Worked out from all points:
|   slope of the pulldown table from 0 to 0.375 V, typ, clamps not added: 52.7 ohm
|   slope of the pullup table from 0 to 0.375 V, typ, clamps not added: 69.7 ohm
|   GND clamp passes 1 mA (typ) near -0.37 V on its own axis
|   POWER clamp passes 1 mA (typ) near -0.40 V on its own axis
|   rising waveform, R_fixture 50.000, V_fixture 0.000: 20-80 % time 228ps typ, 265ps min, 242ps max; typ from 0 V to 0.492 V
|   rising waveform, R_fixture 50.000, V_fixture 2.500: 20-80 % time 262ps typ, 325ps min, 146ps max; typ from 1.98 V to 2.5 V
|   falling waveform, R_fixture 50.000, V_fixture 2.500: 20-80 % time 306ps typ, 212ps min, 324ps max; typ from 2.5 V to 1.98 V
|   falling waveform, R_fixture 50.000, V_fixture 0.000: 20-80 % time 162ps typ, 211ps min, 205ps max; typ from 0.492 V to 0 V
[GND_clamp]
|Voltage   I(typ)   I(min)   I(max)
-2.5V     -1.233A    -1.246A    -1.23A
-1.174V   -179.1mA   -235.9mA   -144.4mA
-1.123V   -143.6mA   -200.7mA   -109.5mA
-1.072V   -110.2mA   -166.6mA   -78.57mA
-1.021V   -80.08mA   -134.1mA   -54.34mA
-970mV    -54.89mA   -103.7mA   -39.63mA
-919mV    -36.41mA   -76.3mA    -32.99mA
-817mV    -19.89mA   -34.81mA   -25.2mA
-715mV    -13.78mA   -14.11mA   -18.16mA
-511mV    -4.596mA   -3.904mA   -6.102mA
-256mV    -63.21uA   -177.9uA   -38.32uA
2.5V      -23.56nA   0A         -150.9nA
[POWER_clamp]
|Voltage   I(typ)   I(min)   I(max)
-2.5V     130.9mA    94.41mA    169.8mA
-1.937V   130.9mA    94.41mA    169.8mA
-1.835V   129.6mA    94.41mA    163.9mA
-1.733V   122.8mA    92.29mA    155mA
-1.478V   100.7mA    77.18mA    127mA
-866mV    35.87mA    29.9mA     45.33mA
-662mV    16.03mA    15.02mA    19.46mA
-560mV    7.73mA     8.668mA    8.662mA
-458mV    2.143mA    3.687mA    1.896mA
-356mV    647.1uA    1.015mA    754.8uA
-101mV    23.95uA    66.65uA    14.28uA
2.5V      0A         0A         0A
[Pulldown]
|Voltage   I(typ)   I(min)   I(max)
-2.5V     -1.868A    -1.868A    -2.434A
-1.056V   -136.7mA   -136.7mA   -115.2mA
-980mV    -76.7mA    -76.7mA    -59.83mA
-904mV    -40.93mA   -40.93mA   -43.08mA
-828mV    -27.68mA   -27.68mA   -36.64mA
-448mV    -10.81mA   -10.81mA   -11.6mA
540mV     8.73mA     8.468mA    8.73mA
2.896V    13.01mA    12.62mA    13.01mA
3.428V    33.12mA    32.13mA    33.12mA
4.568V    93.8mA     91mA       93.8mA
4.72V     99.4mA     96.4mA     99.4mA
5V        105mA      101.8mA    105mA
[Pullup]
|Voltage   I(typ)   I(min)   I(max)
-2.5V     75.5mA     58.83mA    92.7mA
-2.22V    74.5mA     56.29mA    90.2mA
-1.84V    63.7mA     47.92mA    75.2mA
-776mV    19.95mA    14.88mA    21.25mA
-244mV    4.29mA     3.122mA    3.448mA
744mV     -8.658mA   -8.398mA   -8.658mA
3.024V    -12.92mA   -12.53mA   -12.92mA
3.328V    -23.07mA   -22.38mA   -23.07mA
3.404V    -32.83mA   -31.85mA   -32.83mA
3.48V     -59.56mA   -57.78mA   -59.56mA
3.556V    -104.9mA   -101.8mA   -104.9mA
5V        -1.421A    -1.378A    -1.421A
[Ramp]
| variable   typ   min   max
dV/dt_r   0.295/0.228n   0.286/0.265n   0.296/0.242n
dV/dt_f   0.309/0.309n   0.297/0.213n   0.310/0.324n
R_load = 50.000
[Rising Waveform]
R_fixture = 50.000
V_fixture = 0.000
V_fixture_min = 0.000
V_fixture_max = 0.000
|  time   V(typ)   V(min)   V(max)
0s        57.33uV    -144.2uV   134uV
434ps     110.5uV    -371.6uV   2.088mV
477ps     154.3uV    -222uV     -40.68mV
686ps     7.391mV    -99.61uV   30.39mV
970ps     16.91mV    -2.428mV   379.2mV
1.285ns   396.7mV    18.77mV    485.6mV
1.599ns   518.5mV    339.8mV    504.7mV
1.845ns   540.7mV    471mV      507.3mV
2.504ns   542.2mV    533.5mV    504.8mV
10ns      492.3mV    477.6mV    492.8mV
[Rising Waveform]
R_fixture = 50.000
V_fixture = 2.500
V_fixture_min = 2.380
V_fixture_max = 2.630
|  time   V(typ)   V(min)   V(max)
0s        1.984V     1.88V      2.114V
477ps     1.985V     1.88V      2.067V
646ps     1.903V     1.881V     2.201V
766ps     2.155V     1.88V      2.482V
869ps     2.275V     1.817V     2.576V
1.019ns   2.418V     2.072V     2.614V
1.15ns    2.476V     2.185V     2.624V
1.419ns   2.495V     2.343V     2.631V
1.779ns   2.499V     2.375V     2.633V
10ns      2.5V       2.381V     2.631V
[Falling Waveform]
R_fixture = 50.000
V_fixture = 2.500
V_fixture_min = 2.380
V_fixture_max = 2.630
|  time   V(typ)   V(min)   V(max)
0s        2.5V       2.381V     2.631V
668ps     2.504V     2.382V     2.637V
716ps     2.508V     2.382V     2.481V
852ps     2.495V     2.384V     2.359V
992ps     2.209V     2.39V      2.235V
1.119ns   2.138V     2.386V     2.181V
1.349ns   2.04V      2.018V     2.138V
1.56ns    2.008V     1.978V     2.122V
2.579ns   1.982V     1.882V     2.11V
10ns      1.984V     1.88V      2.114V
[Falling Waveform]
R_fixture = 50.000
V_fixture = 0.000
V_fixture_min = 0.000
V_fixture_max = 0.000
|  time   V(typ)   V(min)   V(max)
0s        492.3mV    477.6mV    492.8mV
488ps     491.6mV    477.5mV    509mV
548ps     491.9mV    477.5mV    449.8mV
672ps     504.6mV    477.3mV    232.7mV
811ps     290.6mV    490.4mV    73.93mV
892ps     128.7mV    492.5mV    27.22mV
1.062ns   38.76mV    265.8mV    3.625mV
1.232ns   5.797mV    68.93mV    115.7uV
1.772ns   -112.8uV   2.518mV    -669.7uV
10ns      57.33uV    -144.2uV   134uV
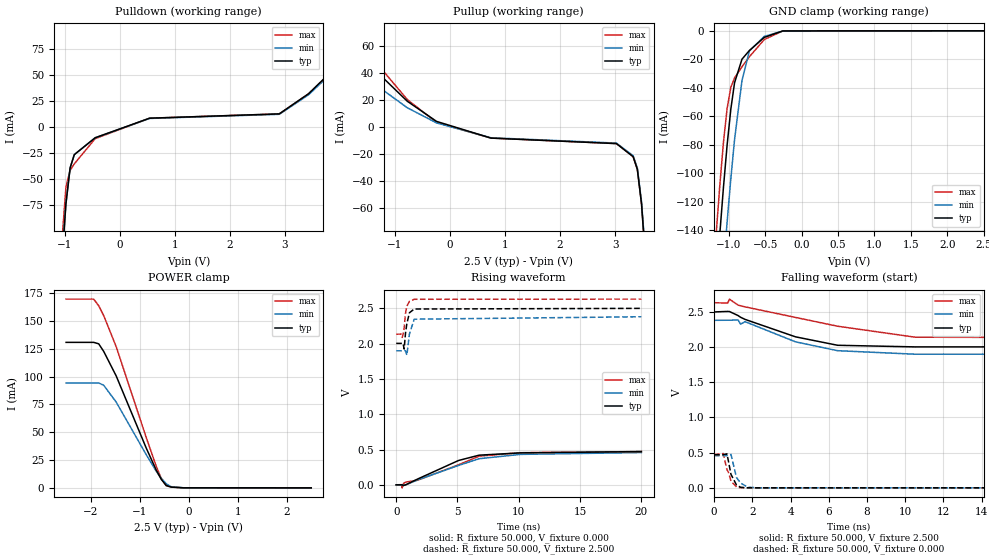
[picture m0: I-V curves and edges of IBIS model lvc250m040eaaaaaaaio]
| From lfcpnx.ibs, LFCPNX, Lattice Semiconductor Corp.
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[Model] lvc250m040eaaaaaaaio
Model_type I/O
Polarity   Non-Inverting
Enable   Active-Low
Vinl =  0.700V
Vinh =  1.700V
Vmeas =  1.250V
Cref =  0.0F
Rref =  1.000M
Vref =  0.0V
C_comp   5.000pF   4.000pF   5.500pF
[Temperature Range]   25.000   0.125k   -40.000
[Voltage Range]   2.500V   2.380V   2.630V
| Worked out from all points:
|   slope of the pulldown table from 0 to 0.375 V, typ, clamps not added: 54.8 ohm
|   slope of the pullup table from 0 to 0.375 V, typ, clamps not added: 72.8 ohm
|   GND clamp passes 1 mA (typ) near -0.37 V on its own axis
|   POWER clamp passes 1 mA (typ) near -0.40 V on its own axis
|   rising waveform, R_fixture 50.000, V_fixture 0.000: 20-80 % time 3.65ns typ, 4.48ns min, 4.05ns max; typ from 0 V to 0.471 V
|   rising waveform, R_fixture 50.000, V_fixture 2.500: 20-80 % time 273ps typ, 326ps min, 218ps max; typ from 2 V to 2.5 V
|   falling waveform, R_fixture 50.000, V_fixture 2.500: 20-80 % time 3.24ns typ, 3.34ns min, 5.31ns max; typ from 2.5 V to 2 V
|   falling waveform, R_fixture 50.000, V_fixture 0.000: 20-80 % time 304ps typ, 319ps min, 303ps max; typ from 0.471 V to 0 V
[GND_clamp]
|Voltage   I(typ)   I(min)   I(max)
-2.5V     -1.233A    -1.246A    -1.23A
-1.174V   -179.1mA   -235.9mA   -144.4mA
-1.123V   -143.6mA   -200.7mA   -109.5mA
-1.072V   -110.2mA   -166.6mA   -78.57mA
-1.021V   -80.08mA   -134.1mA   -54.34mA
-970mV    -54.89mA   -103.7mA   -39.63mA
-919mV    -36.41mA   -76.3mA    -32.99mA
-817mV    -19.89mA   -34.81mA   -25.2mA
-715mV    -13.78mA   -14.11mA   -18.16mA
-511mV    -4.596mA   -3.904mA   -6.102mA
-256mV    -63.21uA   -177.9uA   -38.32uA
2.5V      -23.56nA   0A         -150.9nA
[POWER_clamp]
|Voltage   I(typ)   I(min)   I(max)
-2.5V     130.9mA    94.41mA    169.8mA
-1.937V   130.9mA    94.41mA    169.8mA
-1.835V   129.6mA    94.41mA    163.9mA
-1.733V   122.8mA    92.29mA    155mA
-1.478V   100.7mA    77.18mA    127mA
-866mV    35.87mA    29.9mA     45.33mA
-662mV    16.03mA    15.02mA    19.46mA
-560mV    7.73mA     8.668mA    8.662mA
-458mV    2.143mA    3.687mA    1.896mA
-356mV    647.1uA    1.015mA    754.8uA
-101mV    23.95uA    66.65uA    14.28uA
2.5V      0A         0A         0A
[Pulldown]
|Voltage   I(typ)   I(min)   I(max)
-2.5V     -1.797A    -1.797A    -2.358A
-1.056V   -131.5mA   -131.5mA   -111.6mA
-980mV    -73.79mA   -73.79mA   -57.97mA
-904mV    -39.38mA   -39.38mA   -41.75mA
-828mV    -26.63mA   -26.63mA   -35.5mA
-448mV    -10.4mA    -10.4mA    -11.24mA
540mV     8.398mA    8.146mA    8.398mA
2.896V    12.52mA    12.14mA    12.52mA
3.428V    31.86mA    30.9mA     31.86mA
4.568V    90.2mA     87.5mA     90.2mA
4.72V     95.6mA     92.7mA     95.6mA
5V        101mA      98mA       101mA
[Pullup]
|Voltage   I(typ)   I(min)   I(max)
-2.5V     72.2mA     56.29mA    88.7mA
-2.144V   70mA       52.74mA    84.1mA
-1.84V    61mA       45.84mA    71.9mA
-776mV    19.08mA    14.23mA    20.33mA
-244mV    4.104mA    2.987mA    3.299mA
744mV     -8.283mA   -8.035mA   -8.283mA
3.024V    -12.36mA   -11.99mA   -12.36mA
3.328V    -22.07mA   -21.41mA   -22.07mA
3.404V    -31.41mA   -30.47mA   -31.41mA
3.48V     -56.99mA   -55.28mA   -56.99mA
3.556V    -100.3mA   -97.3mA    -100.3mA
5V        -1.359A    -1.318A    -1.359A
[Ramp]
| variable   typ   min   max
dV/dt_r   0.283/3.655n   0.274/4.514n   0.291/4.056n
dV/dt_f   0.298/3.245n   0.295/3.345n   0.298/5.313n
R_load = 50.000
[Rising Waveform]
R_fixture = 50.000
V_fixture = 0.000
V_fixture_min = 0.000
V_fixture_max = 0.000
|  time   V(typ)   V(min)   V(max)
0s        55.81uV    -180.2uV   158.6uV
434ps     110uV      -404.9uV   2.261mV
486ps     143uV      -237.9uV   -42.96mV
588ps     -10.37mV   -127.1uV   19.51mV
775ps     708.8uV    -2.164mV   39.13mV
1.745ns   81.96mV    69.52mV    65.14mV
5.09ns    345.3mV    275mV      284.2mV
6.77ns    420.4mV    370.3mV    406.7mV
10.15ns   452.8mV    431.4mV    455.3mV
20ns      471.1mV    457.1mV    471.6mV
[Rising Waveform]
R_fixture = 50.000
V_fixture = 2.500
V_fixture_min = 2.380
V_fixture_max = 2.630
|  time   V(typ)   V(min)   V(max)
0s        2.004V     1.899V     2.134V
425ps     2.004V     1.899V     2.136V
487ps     2.004V     1.899V     2.089V
557ps     2.004V     1.899V     2.125V
648ps     1.924V     1.9V       2.224V
761ps     2.154V     1.9V       2.431V
869ps     2.282V     1.835V     2.531V
1.079ns   2.438V     2.137V     2.6V
1.468ns   2.491V     2.347V     2.629V
20ns      2.5V       2.381V     2.631V
[Falling Waveform]
R_fixture = 50.000
V_fixture = 2.500
V_fixture_min = 2.380
V_fixture_max = 2.630
|  time   V(typ)   V(min)   V(max)
0s        2.5V       2.381V     2.631V
714ps     2.507V     2.382V     2.626V
804ps     2.506V     2.382V     2.682V
1.252ns   2.449V     2.386V     2.598V
1.389ns   2.424V     2.326V     2.587V
1.621ns   2.394V     2.362V     2.572V
4.261ns   2.146V     2.075V     2.422V
6.463ns   2.026V     1.949V     2.297V
10.52ns   2.003V     1.899V     2.141V
20ns      2.004V     1.899V     2.134V
[Falling Waveform]
R_fixture = 50.000
V_fixture = 0.000
V_fixture_min = 0.000
V_fixture_max = 0.000
|  time   V(typ)   V(min)   V(max)
0s        471.1mV    457.1mV    471.6mV
487ps     470.4mV    456.9mV    487.6mV
672ps     483.4mV    456.8mV    257.2mV
748ps     384.1mV    460.1mV    225.1mV
884ps     191.6mV    474.8mV    95.32mV
1.172ns   40.67mV    147.6mV    11.51mV
1.384ns   7.514mV    67.73mV    1.779mV
1.764ns   392.6uV    9.166mV    -736.4uV
2.251ns   -178.9uV   -12.61uV   -678.8uV
20ns      55.81uV    -180.2uV   158.6uV
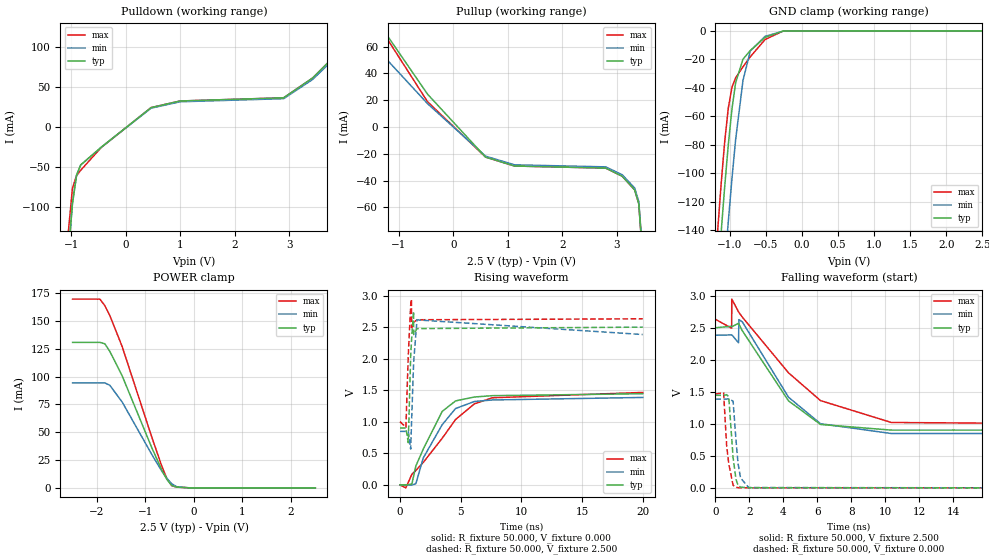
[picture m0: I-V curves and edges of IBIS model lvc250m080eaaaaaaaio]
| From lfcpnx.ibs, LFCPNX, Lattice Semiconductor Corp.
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[Model] lvc250m080eaaaaaaaio
Model_type I/O
Polarity   Non-Inverting
Enable   Active-Low
Vinl =  0.700V
Vinh =  1.700V
Vmeas =  1.250V
Cref =  0.0F
Rref =  1.000M
Vref =  0.0V
C_comp   5.000pF   4.000pF   5.500pF
[Temperature Range]   25.000   0.125k   -40.000
[Voltage Range]   2.500V   2.380V   2.630V
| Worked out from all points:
|   slope of the pulldown table from 0 to 0.375 V, typ, clamps not added: 18.1 ohm
|   slope of the pullup table from 0 to 0.375 V, typ, clamps not added: 23.8 ohm
|   GND clamp passes 1 mA (typ) near -0.37 V on its own axis
|   POWER clamp passes 1 mA (typ) near -0.40 V on its own axis
|   rising waveform, R_fixture 50.000, V_fixture 0.000: 20-80 % time 2.16ns typ, 2.44ns min, 3.67ns max; typ from 0 V to 1.45 V
|   rising waveform, R_fixture 50.000, V_fixture 2.500: 20-80 % time 160ps typ, 186ps min, 172ps max; typ from 0.901 V to 2.5 V
|   falling waveform, R_fixture 50.000, V_fixture 2.500: 20-80 % time 2.57ns typ, 2.59ns min, 3.75ns max; typ from 2.5 V to 0.901 V
|   falling waveform, R_fixture 50.000, V_fixture 0.000: 20-80 % time 246ps typ, 258ps min, 268ps max; typ from 1.45 V to 0 V
[GND_clamp]
|Voltage   I(typ)   I(min)   I(max)
-2.5V     -1.233A    -1.246A    -1.23A
-1.174V   -179.1mA   -235.9mA   -144.4mA
-1.123V   -143.6mA   -200.7mA   -109.5mA
-1.072V   -110.2mA   -166.6mA   -78.57mA
-1.021V   -80.08mA   -134.1mA   -54.34mA
-970mV    -54.89mA   -103.7mA   -39.63mA
-919mV    -36.41mA   -76.3mA    -32.99mA
-817mV    -19.89mA   -34.81mA   -25.2mA
-715mV    -13.78mA   -14.11mA   -18.16mA
-511mV    -4.596mA   -3.904mA   -6.102mA
-256mV    -63.21uA   -177.9uA   -38.32uA
2.5V      -23.56nA   0A         -150.9nA
[POWER_clamp]
|Voltage   I(typ)   I(min)   I(max)
-2.5V     130.9mA    94.41mA    169.8mA
-1.937V   130.9mA    94.41mA    169.8mA
-1.835V   129.6mA    94.41mA    163.9mA
-1.733V   122.8mA    92.29mA    155mA
-1.478V   100.7mA    77.18mA    127mA
-866mV    35.87mA    29.9mA     45.33mA
-662mV    16.03mA    15.02mA    19.46mA
-560mV    7.73mA     8.668mA    8.662mA
-458mV    2.143mA    3.687mA    1.896mA
-356mV    647.1uA    1.015mA    754.8uA
-101mV    23.95uA    66.65uA    14.28uA
2.5V      0A         0A         0A
[Pulldown]
|Voltage   I(typ)   I(min)   I(max)
-2.5V     -2.07A     -2.07A     -2.62A
-1.056V   -159.5mA   -159.5mA   -132.1mA
-980mV    -96.2mA    -96.2mA    -76.81mA
-904mV    -60.38mA   -60.38mA   -61.04mA
-828mV    -47.63mA   -47.63mA   -54.22mA
-448mV    -25.25mA   -25.25mA   -25.53mA
464mV     24.25mA    23.53mA    24.25mA
996mV     32.5mA     31.53mA    32.5mA
2.896V    36.5mA     35.41mA    36.5mA
3.428V    61.28mA    59.44mA    61.28mA
4.34V     123.3mA    119.6mA    123.3mA
5V        151.4mA    146.9mA    151.4mA
[Pullup]
|Voltage   I(typ)   I(min)   I(max)
-2.5V     108.7mA    81.9mA     123.6mA
-1.992V   106.8mA    79.5mA     113.9mA
-1.536V   87.4mA     64.19mA    86.3mA
-472mV    24.44mA    17.38mA    18.79mA
592mV     -22.51mA   -21.83mA   -22.51mA
1.124V    -29.18mA   -28.3mA    -29.18mA
2.796V    -30.74mA   -29.82mA   -30.74mA
3.1V      -36.78mA   -35.68mA   -36.78mA
3.328V    -46.98mA   -45.57mA   -46.98mA
3.404V    -57.33mA   -55.61mA   -57.33mA
3.556V    -142.2mA   -137.9mA   -142.2mA
5V        -1.817A    -1.762A    -1.817A
[Ramp]
| variable   typ   min   max
dV/dt_r   0.867/2.166n   0.832/2.491n   0.879/3.674n
dV/dt_f   0.949/2.995n   0.921/2.987n   0.977/4.337n
R_load = 50.000
[Rising Waveform]
R_fixture = 50.000
V_fixture = 0.000
V_fixture_min = 0.000
V_fixture_max = 0.000
|  time   V(typ)   V(min)   V(max)
0s        64.19uV    -979.5uV   -305.7uV
479ps     184.7uV    -985.6uV   -46.97mV
976ps     13.97mV    -3.56mV    167.9mV
1.304ns   300.4mV    19.25mV    228.8mV
1.915ns   567.6mV    427.3mV    356.5mV
3.474ns   1.165V     953.9mV    739.1mV
4.575ns   1.331V     1.21V      1.036V
6.13ns    1.393V     1.322V     1.285V
7.616ns   1.414V     1.346V     1.381V
20ns      1.445V     1.386V     1.465V
[Rising Waveform]
R_fixture = 50.000
V_fixture = 2.500
V_fixture_min = 2.380
V_fixture_max = 2.630
|  time   V(typ)   V(min)   V(max)
0s        901.2mV    848.2mV    1.003V
483ps     901.4mV    847.9mV    911.5mV
678ps     668.5mV    848.5mV    2.048V
877ps     2.037V     567.7mV    2.846V
947ps     2.292V     980.3mV    2.944V
957ps     2.321V     1.041V     2.492V
1.116ns   2.748V     1.92V      2.575V
1.127ns   2.382V     1.96V      2.578V
1.397ns   2.477V     2.615V     2.617V
20ns      2.5V       2.383V     2.632V
[Falling Waveform]
R_fixture = 50.000
V_fixture = 2.500
V_fixture_min = 2.380
V_fixture_max = 2.630
|  time   V(typ)   V(min)   V(max)
0s        2.5V       2.383V     2.632V
958ps     2.522V     2.388V     2.493V
968ps     2.515V     2.389V     2.947V
1.365ns   2.57V      2.265V     2.748V
1.384ns   2.559V     2.627V     2.74V
1.584ns   2.454V     2.593V     2.667V
4.306ns   1.358V     1.415V     1.796V
6.189ns   989.3mV    1.001V     1.362V
10.36ns   901mV      847.7mV    1.02V
20ns      901.2mV    848.2mV    1.003V
[Falling Waveform]
R_fixture = 50.000
V_fixture = 0.000
V_fixture_min = 0.000
V_fixture_max = 0.000
|  time   V(typ)   V(min)   V(max)
0s        1.445V     1.386V     1.465V
486ps     1.444V     1.386V     1.484V
661ps     1.455V     1.386V     672.9mV
788ps     1.422V     1.39V      376.7mV
1.044ns   475mV      1.353V     40.98mV
1.214ns   132.3mV    746.2mV    8.106mV
1.334ns   40.6mV     383.3mV    2.36mV
1.485ns   10.31mV    152.4mV    100uV
1.964ns   722.8uV    3.967mV    -702.9uV
20ns      64.19uV    -979.5uV   -305.7uV
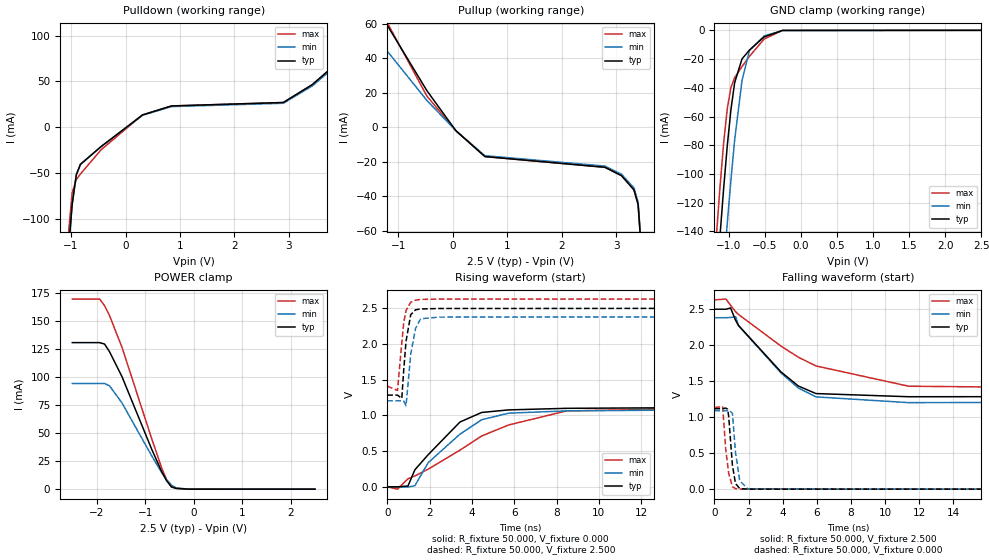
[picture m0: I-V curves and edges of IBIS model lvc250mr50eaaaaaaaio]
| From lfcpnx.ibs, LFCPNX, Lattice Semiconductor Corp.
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[Model] lvc250mr50eaaaaaaaio
Model_type I/O
Polarity   Non-Inverting
Enable   Active-Low
Vinl =  0.700V
Vinh =  1.700V
Vmeas =  1.250V
Cref =  0.0F
Rref =  1.000M
Vref =  0.0V
C_comp   5.000pF   4.000pF   5.500pF
[Temperature Range]   25.000   0.125k   -40.000
[Voltage Range]   2.500V   2.380V   2.630V
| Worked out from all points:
|   slope of the pulldown table from 0 to 0.375 V, typ, clamps not added: 24.3 ohm
|   slope of the pullup table from 0 to 0.375 V, typ, clamps not added: 31.3 ohm
|   GND clamp passes 1 mA (typ) near -0.37 V on its own axis
|   POWER clamp passes 1 mA (typ) near -0.40 V on its own axis
|   rising waveform, R_fixture 50.000, V_fixture 0.000: 20-80 % time 2.11ns typ, 2.43ns min, 4.34ns max; typ from 0 V to 1.12 V
|   rising waveform, R_fixture 50.000, V_fixture 2.500: 20-80 % time 247ps typ, 289ps min, 258ps max; typ from 1.28 V to 2.5 V
|   falling waveform, R_fixture 50.000, V_fixture 2.500: 20-80 % time 2.91ns typ, 2.83ns min, 5.03ns max; typ from 2.5 V to 1.28 V
|   falling waveform, R_fixture 50.000, V_fixture 0.000: 20-80 % time 242ps typ, 254ps min, 273ps max; typ from 1.12 V to 0 V
[GND_clamp]
|Voltage   I(typ)   I(min)   I(max)
-2.5V     -1.233A    -1.246A    -1.23A
-1.174V   -179.1mA   -235.9mA   -144.4mA
-1.123V   -143.6mA   -200.7mA   -109.5mA
-1.072V   -110.2mA   -166.6mA   -78.57mA
-1.021V   -80.08mA   -134.1mA   -54.34mA
-970mV    -54.89mA   -103.7mA   -39.63mA
-919mV    -36.41mA   -76.3mA    -32.99mA
-817mV    -19.89mA   -34.81mA   -25.2mA
-715mV    -13.78mA   -14.11mA   -18.16mA
-511mV    -4.596mA   -3.904mA   -6.102mA
-256mV    -63.21uA   -177.9uA   -38.32uA
2.5V      -23.56nA   0A         -150.9nA
[POWER_clamp]
|Voltage   I(typ)   I(min)   I(max)
-2.5V     130.9mA    94.41mA    169.8mA
-1.937V   130.9mA    94.41mA    169.8mA
-1.835V   129.6mA    94.41mA    163.9mA
-1.733V   122.8mA    92.29mA    155mA
-1.478V   100.7mA    77.18mA    127mA
-866mV    35.87mA    29.9mA     45.33mA
-662mV    16.03mA    15.02mA    19.46mA
-560mV    7.73mA     8.668mA    8.662mA
-458mV    2.143mA    3.687mA    1.896mA
-356mV    647.1uA    1.015mA    754.8uA
-101mV    23.95uA    66.65uA    14.28uA
2.5V      0A         0A         0A
[Pulldown]
|Voltage   I(typ)   I(min)   I(max)
-2.5V     -1.843A    -1.843A    -2.4A
-1.056V   -141.1mA   -141.1mA   -121.9mA
-980mV    -84.5mA    -84.5mA    -71.68mA
-904mV    -52.18mA   -52.18mA   -57.43mA
-828mV    -40.67mA   -40.67mA   -51.18mA
-448mV    -21.22mA   -21.22mA   -24.67mA
312mV     13.36mA    12.96mA    13.36mA
844mV     23.15mA    22.45mA    23.15mA
2.896V    26.91mA    26.1mA     26.91mA
3.428V    46.46mA    45.06mA    46.46mA
4.644V    109.3mA    106mA      109.3mA
5V        117.5mA    114mA      117.5mA
[Pullup]
|Voltage   I(typ)   I(min)   I(max)
-2.5V     97.92mA    74.3mA     113.9mA
-1.84V    90.8mA     68.13mA    97.7mA
-1.688V   84.5mA     63.28mA    89.2mA
-472mV    21.14mA    15.46mA    17.98mA
60mV      -2.1mA     -2.037mA   -2.1mA
592mV     -17.07mA   -16.56mA   -17.07mA
2.796V    -23.3mA    -22.6mA    -23.3mA
3.1V      -28.17mA   -27.33mA   -28.17mA
3.328V    -36.4mA    -35.3mA    -36.4mA
3.404V    -44.88mA   -43.53mA   -44.88mA
3.556V    -113.7mA   -110.3mA   -113.7mA
5V        -1.462A    -1.418A    -1.462A
[Ramp]
| variable   typ   min   max
dV/dt_r   0.677/2.111n   0.654/2.454n   0.680/4.340n
dV/dt_f   0.728/2.909n   0.711/2.829n   0.754/5.030n
R_load = 50.000
[Rising Waveform]
R_fixture = 50.000
V_fixture = 0.000
V_fixture_min = 0.000
V_fixture_max = 0.000
|  time   V(typ)   V(min)   V(max)
0s        62.93uV    -264.9uV   1.024mV
479ps     177.4uV    -273.6uV   -31.99mV
977ps     12.17mV    -2.565mV   113.2mV
1.305ns   239.4mV    16.36mV    152.8mV
1.934ns   451mV      339.5mV    247.8mV
3.435ns   908.3mV    738.2mV    514.5mV
4.46ns    1.042V     939.8mV    712.3mV
5.73ns    1.078V     1.032V     866.6mV
8.459ns   1.1V       1.064V     1.063V
20ns      1.118V     1.09V      1.134V
[Rising Waveform]
R_fixture = 50.000
V_fixture = 2.500
V_fixture_min = 2.380
V_fixture_max = 2.630
|  time   V(typ)   V(min)   V(max)
0s        1.285V     1.206V     1.411V
483ps     1.285V     1.205V     1.35V
687ps     1.239V     1.206V     2.021V
777ps     1.634V     1.203V     2.298V
887ps     2.039V     1.135V     2.47V
1.108ns   2.411V     1.857V     2.586V
1.337ns   2.48V      2.221V     2.615V
1.577ns   2.491V     2.354V     2.625V
2.437ns   2.498V     2.377V     2.63V
20ns      2.5V       2.381V     2.63V
[Falling Waveform]
R_fixture = 50.000
V_fixture = 2.500
V_fixture_min = 2.380
V_fixture_max = 2.630
|  time   V(typ)   V(min)   V(max)
0s        2.5V       2.381V     2.63V
679ps     2.5V       2.382V     2.641V
949ps     2.518V     2.385V     2.554V
1.244ns   2.344V     2.396V     2.464V
1.414ns   2.274V     2.271V     2.427V
3.904ns   1.628V     1.614V     1.987V
4.919ns   1.433V     1.405V     1.833V
5.95ns    1.328V     1.282V     1.712V
11.38ns   1.284V     1.202V     1.43V
20ns      1.285V     1.206V     1.411V
[Falling Waveform]
R_fixture = 50.000
V_fixture = 0.000
V_fixture_min = 0.000
V_fixture_max = 0.000
|  time   V(typ)   V(min)   V(max)
0s        1.118V     1.09V      1.134V
486ps     1.118V     1.09V      1.146V
661ps     1.127V     1.09V      560.2mV
778ps     1.11V      1.092V     333.8mV
838ps     1.011V     1.099V     220mV
1.055ns   332.4mV    1.054V     34.32mV
1.235ns   79.63mV    516mV      7.283mV
1.484ns   7.978mV    117.2mV    1.57mV
1.955ns   648uV      3.692mV    726.9uV
20ns      62.93uV    -264.9uV   1.024mV
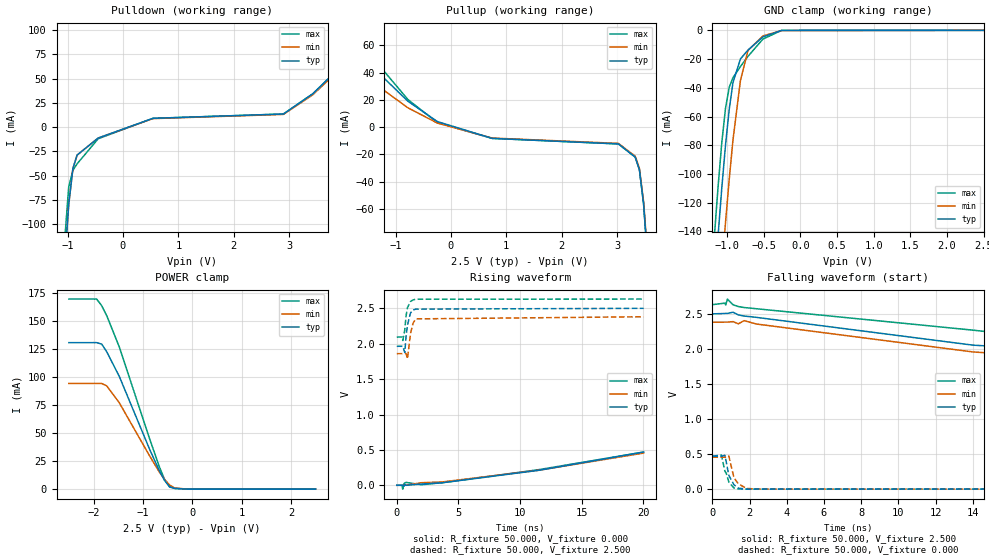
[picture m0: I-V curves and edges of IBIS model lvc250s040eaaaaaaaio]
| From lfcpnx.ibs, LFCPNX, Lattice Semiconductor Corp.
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[Model] lvc250s040eaaaaaaaio
Model_type I/O
Polarity   Non-Inverting
Enable   Active-Low
Vinl =  0.700V
Vinh =  1.700V
Vmeas =  1.250V
Cref =  0.0F
Rref =  1.000M
Vref =  0.0V
C_comp   5.000pF   4.000pF   5.500pF
[Temperature Range]   25.000   0.125k   -40.000
[Voltage Range]   2.500V   2.380V   2.630V
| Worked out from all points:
|   slope of the pulldown table from 0 to 0.375 V, typ, clamps not added: 50.7 ohm
|   slope of the pullup table from 0 to 0.375 V, typ, clamps not added: 73.2 ohm
|   GND clamp passes 1 mA (typ) near -0.37 V on its own axis
|   POWER clamp passes 1 mA (typ) near -0.40 V on its own axis
|   rising waveform, R_fixture 50.000, V_fixture 0.000: 20-80 % time 10.1ns typ, 10.7ns min, 11.1ns max; typ from 0 V to 0.469 V
|   rising waveform, R_fixture 50.000, V_fixture 2.500: 20-80 % time 282ps typ, 328ps min, 237ps max; typ from 1.96 V to 2.5 V
|   falling waveform, R_fixture 50.000, V_fixture 2.500: 20-80 % time 9.19ns typ, 8.71ns min, 11.8ns max; typ from 2.5 V to 1.96 V
|   falling waveform, R_fixture 50.000, V_fixture 0.000: 20-80 % time 337ps typ, 365ps min, 312ps max; typ from 0.469 V to 0 V
[GND_clamp]
|Voltage   I(typ)   I(min)   I(max)
-2.5V     -1.233A    -1.246A    -1.23A
-1.174V   -179.1mA   -235.9mA   -144.4mA
-1.123V   -143.6mA   -200.7mA   -109.5mA
-1.072V   -110.2mA   -166.6mA   -78.57mA
-1.021V   -80.08mA   -134.1mA   -54.34mA
-970mV    -54.89mA   -103.7mA   -39.63mA
-919mV    -36.41mA   -76.3mA    -32.99mA
-817mV    -19.89mA   -34.81mA   -25.2mA
-715mV    -13.78mA   -14.11mA   -18.16mA
-511mV    -4.596mA   -3.904mA   -6.102mA
-256mV    -63.21uA   -177.9uA   -38.32uA
2.5V      -23.56nA   0A         -150.9nA
[POWER_clamp]
|Voltage   I(typ)   I(min)   I(max)
-2.5V     130.9mA    94.41mA    169.8mA
-1.937V   130.9mA    94.41mA    169.8mA
-1.835V   129.6mA    94.41mA    163.9mA
-1.733V   122.8mA    92.29mA    155mA
-1.478V   100.7mA    77.18mA    127mA
-866mV    35.87mA    29.9mA     45.33mA
-662mV    16.03mA    15.02mA    19.46mA
-560mV    7.73mA     8.668mA    8.662mA
-458mV    2.143mA    3.687mA    1.896mA
-356mV    647.1uA    1.015mA    754.8uA
-101mV    23.95uA    66.65uA    14.28uA
2.5V      0A         0A         0A
[Pulldown]
|Voltage   I(typ)   I(min)   I(max)
-2.5V     -1.943A    -1.943A    -2.512A
-1.056V   -142.2mA   -142.2mA   -118.9mA
-980mV    -79.77mA   -79.77mA   -61.74mA
-904mV    -42.57mA   -42.57mA   -44.46mA
-828mV    -28.79mA   -28.79mA   -37.81mA
-448mV    -11.24mA   -11.24mA   -11.97mA
540mV     9.079mA    8.807mA    9.079mA
2.896V    13.53mA    13.13mA    13.53mA
3.428V    34.44mA    33.41mA    34.44mA
4.568V    97.6mA     94.7mA     97.6mA
4.72V     103.4mA    100.3mA    103.4mA
5V        109.2mA    105.9mA    109.2mA
[Pullup]
|Voltage   I(typ)   I(min)   I(max)
-2.5V     71.9mA     56.02mA    88.3mA
-2.22V    70.9mA     53.6mA     85.9mA
-1.84V    60.7mA     45.63mA    71.6mA
-776mV    18.99mA    14.17mA    20.23mA
-244mV    4.085mA    2.973mA    3.283mA
744mV     -8.244mA   -7.997mA   -8.244mA
3.024V    -12.3mA    -11.93mA   -12.3mA
3.328V    -21.97mA   -21.31mA   -21.97mA
3.404V    -31.26mA   -30.33mA   -31.26mA
3.48V     -56.72mA   -55.02mA   -56.72mA
3.556V    -99.9mA    -96.9mA    -99.9mA
5V        -1.353A    -1.312A    -1.353A
[Ramp]
| variable   typ   min   max
dV/dt_r   0.281/10.134n   0.273/10.740n   0.282/11.110n
dV/dt_f   0.322/9.225n   0.313/8.722n   0.322/11.833n
R_load = 50.000
[Rising Waveform]
R_fixture = 50.000
V_fixture = 0.000
V_fixture_min = 0.000
V_fixture_max = 0.000
|  time   V(typ)   V(min)   V(max)
0s        58.25uV    -109.7uV   105.9uV
434ps     122.2uV    -418uV     2.777mV
478ps     175.7uV    -212uV     -54.92mV
588ps     -12.25mV   -36.77uV   24.52mV
659ps     11.89mV    44.7uV     32.6mV
754ps     -315.5uV   564.1uV    40.89mV
1.987ns   17.8mV     36.16mV    7.161mV
3.664ns   34.85mV    46.51mV    36.22mV
11.55ns   212.5mV    213.4mV    221.9mV
20ns      468.9mV    454.9mV    469.3mV
[Rising Waveform]
R_fixture = 50.000
V_fixture = 2.500
V_fixture_min = 2.380
V_fixture_max = 2.630
|  time   V(typ)   V(min)   V(max)
0s        1.964V     1.86V      2.094V
425ps     1.964V     1.86V      2.096V
487ps     1.964V     1.86V      2.045V
648ps     1.876V     1.861V     2.192V
751ps     2.104V     1.863V     2.391V
869ps     2.264V     1.788V     2.511V
1.112ns   2.435V     2.144V     2.597V
1.323ns   2.476V     2.292V     2.619V
1.539ns   2.489V     2.351V     2.629V
20ns      2.5V       2.381V     2.631V
[Falling Waveform]
R_fixture = 50.000
V_fixture = 2.500
V_fixture_min = 2.380
V_fixture_max = 2.630
|  time   V(typ)   V(min)   V(max)
0s        2.5V       2.381V     2.631V
677ps     2.505V     2.382V     2.653V
717ps     2.508V     2.382V     2.626V
807ps     2.507V     2.382V     2.711V
1.116ns   2.523V     2.389V     2.629V
1.399ns   2.485V     2.358V     2.604V
1.709ns   2.469V     2.403V     2.59V
2.369ns   2.45V      2.355V     2.573V
14.03ns   2.053V     1.956V     2.267V
20ns      1.964V     1.86V      2.094V
[Falling Waveform]
R_fixture = 50.000
V_fixture = 0.000
V_fixture_min = 0.000
V_fixture_max = 0.000
|  time   V(typ)   V(min)   V(max)
0s        468.9mV    454.9mV    469.3mV
487ps     468.2mV    454.8mV    485.8mV
672ps     482.5mV    454.6mV    256.8mV
747ps     386.4mV    457.9mV    227.3mV
884ps     197mV      473.5mV    101mV
1.161ns   61.28mV    160.9mV    15.59mV
1.404ns   12.6mV     75mV       2.214mV
1.824ns   715.5uV    10.38mV    -917.8uV
2.364ns   -288.5uV   62.2uV     -876.4uV
20ns      58.25uV    -109.7uV   105.9uV
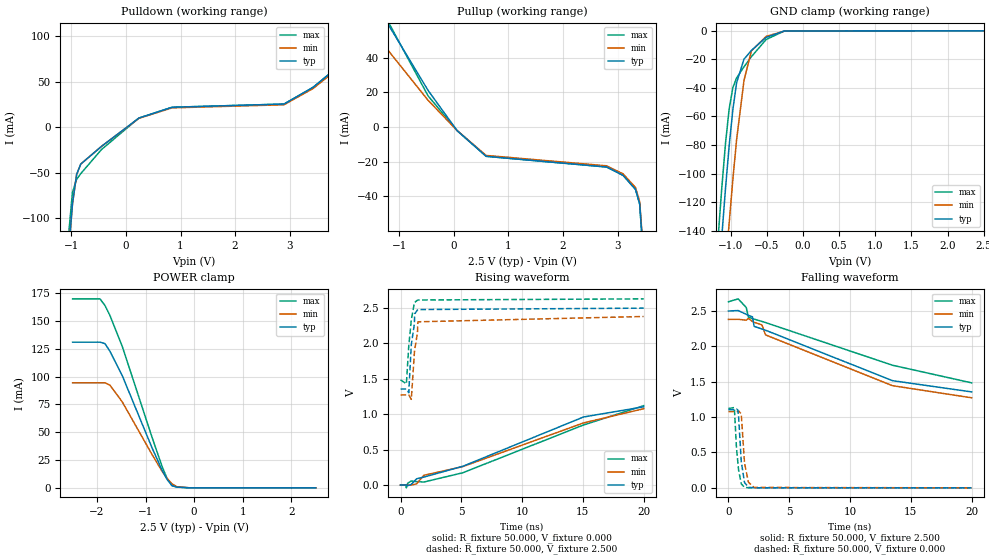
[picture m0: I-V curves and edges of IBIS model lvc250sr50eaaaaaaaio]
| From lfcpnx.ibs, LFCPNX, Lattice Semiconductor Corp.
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[Model] lvc250sr50eaaaaaaaio
Model_type I/O
Polarity   Non-Inverting
Enable   Active-Low
Vinl =  0.700V
Vinh =  1.700V
Vmeas =  1.250V
Cref =  0.0F
Rref =  1.000M
Vref =  0.0V
C_comp   5.000pF   4.000pF   5.500pF
[Temperature Range]   25.000   0.125k   -40.000
[Voltage Range]   2.500V   2.380V   2.630V
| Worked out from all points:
|   slope of the pulldown table from 0 to 0.375 V, typ, clamps not added: 25.8 ohm
|   slope of the pullup table from 0 to 0.375 V, typ, clamps not added: 31.6 ohm
|   GND clamp passes 1 mA (typ) near -0.37 V on its own axis
|   POWER clamp passes 1 mA (typ) near -0.40 V on its own axis
|   rising waveform, R_fixture 50.000, V_fixture 0.000: 20-80 % time 9.37ns typ, 10.6ns min, 9.7ns max; typ from 0 V to 1.11 V
|   rising waveform, R_fixture 50.000, V_fixture 2.500: 20-80 % time 364ps typ, 401ps min, 418ps max; typ from 1.36 V to 2.5 V
|   falling waveform, R_fixture 50.000, V_fixture 2.500: 20-80 % time 10ns typ, 9.58ns min, 12ns max; typ from 2.5 V to 1.36 V
|   falling waveform, R_fixture 50.000, V_fixture 0.000: 20-80 % time 277ps typ, 297ps min, 292ps max; typ from 1.11 V to 0 V
[GND_clamp]
|Voltage   I(typ)   I(min)   I(max)
-2.5V     -1.233A    -1.246A    -1.23A
-1.174V   -179.1mA   -235.9mA   -144.4mA
-1.123V   -143.6mA   -200.7mA   -109.5mA
-1.072V   -110.2mA   -166.6mA   -78.57mA
-1.021V   -80.08mA   -134.1mA   -54.34mA
-970mV    -54.89mA   -103.7mA   -39.63mA
-919mV    -36.41mA   -76.3mA    -32.99mA
-817mV    -19.89mA   -34.81mA   -25.2mA
-715mV    -13.78mA   -14.11mA   -18.16mA
-511mV    -4.596mA   -3.904mA   -6.102mA
-256mV    -63.21uA   -177.9uA   -38.32uA
2.5V      -23.56nA   0A         -150.9nA
[POWER_clamp]
|Voltage   I(typ)   I(min)   I(max)
-2.5V     130.9mA    94.41mA    169.8mA
-1.937V   130.9mA    94.41mA    169.8mA
-1.835V   129.6mA    94.41mA    163.9mA
-1.733V   122.8mA    92.29mA    155mA
-1.478V   100.7mA    77.18mA    127mA
-866mV    35.87mA    29.9mA     45.33mA
-662mV    16.03mA    15.02mA    19.46mA
-560mV    7.73mA     8.668mA    8.662mA
-458mV    2.143mA    3.687mA    1.896mA
-356mV    647.1uA    1.015mA    754.8uA
-101mV    23.95uA    66.65uA    14.28uA
2.5V      0A         0A         0A
[Pulldown]
|Voltage   I(typ)   I(min)   I(max)
-2.5V     -1.843A    -1.843A    -2.4A
-1.056V   -141.1mA   -141.1mA   -121.9mA
-980mV    -84.5mA    -84.5mA    -71.68mA
-904mV    -52.18mA   -52.18mA   -57.43mA
-828mV    -40.67mA   -40.67mA   -51.18mA
-448mV    -21.22mA   -21.22mA   -24.67mA
236mV     9.883mA    9.587mA    9.883mA
844mV     21.76mA    21.1mA     21.76mA
2.896V    25.29mA    24.53mA    25.29mA
3.428V    43.67mA    42.36mA    43.67mA
4.568V    99.9mA     96.9mA     99.9mA
5V        110.4mA    107.1mA    110.4mA
[Pullup]
|Voltage   I(typ)   I(min)   I(max)
-2.5V     97.92mA    74.3mA     113.9mA
-2.068V   97.1mA     73.2mA     108.5mA
-1.688V   84.5mA     63.28mA    89.2mA
-472mV    21.14mA    15.46mA    17.98mA
60mV      -2.076mA   -2.014mA   -2.076mA
592mV     -16.88mA   -16.37mA   -16.88mA
2.796V    -23.04mA   -22.35mA   -23.04mA
3.1V      -27.85mA   -27.02mA   -27.85mA
3.328V    -35.98mA   -34.9mA    -35.98mA
3.404V    -44.37mA   -43.04mA   -44.37mA
3.556V    -112.4mA   -109mA     -112.4mA
5V        -1.445A    -1.402A    -1.445A
[Ramp]
| variable   typ   min   max
dV/dt_r   0.669/9.369n   0.647/10.550n   0.672/9.703n
dV/dt_f   0.686/8.733n   0.698/8.218n   0.688/10.584n
R_load = 50.000
[Rising Waveform]
R_fixture = 50.000
V_fixture = 0.000
V_fixture_min = 0.000
V_fixture_max = 0.000
|  time   V(typ)   V(min)   V(max)
0s        62.93uV    50.33uV    1.293mV
436ps     146uV      -130.4uV   3.131mV
478ps     181.3uV    38.81uV    -39.95mV
586ps     -9.085mV   138.5uV    23.37mV
875ps     6.972mV    -1.451mV   56.52mV
1.324ns   88.19mV    16.73mV    48.33mV
1.924ns   112.3mV    137.3mV    42.1mV
5.13ns    265.1mV    260.5mV    173.6mV
15.05ns   961.1mV    877.4mV    848mV
20ns      1.105V     1.078V     1.121V
[Rising Waveform]
R_fixture = 50.000
V_fixture = 2.500
V_fixture_min = 2.380
V_fixture_max = 2.630
|  time   V(typ)   V(min)   V(max)
0s        1.356V     1.273V     1.484V
483ps     1.356V     1.273V     1.431V
678ps     1.305V     1.273V     1.964V
887ps     1.983V     1.21V      2.333V
1.144ns   2.28V      1.879V     2.577V
1.158ns   2.416V     1.903V     2.58V
1.395ns   2.474V     2.152V     2.611V
1.418ns   2.476V     2.292V     2.612V
1.445ns   2.479V     2.306V     2.614V
20ns      2.499V     2.381V     2.63V
[Falling Waveform]
R_fixture = 50.000
V_fixture = 2.500
V_fixture_min = 2.380
V_fixture_max = 2.630
|  time   V(typ)   V(min)   V(max)
0s        2.499V     2.381V     2.63V
800ps     2.506V     2.382V     2.671V
1.464ns   2.453V     2.37V      2.549V
1.644ns   2.438V     2.394V     2.411V
1.974ns   2.417V     2.352V     2.393V
2.114ns   2.282V     2.34V      2.385V
2.758ns   2.245V     2.303V     2.352V
3.05ns    2.228V     2.162V     2.336V
13.49ns   1.515V     1.444V     1.733V
20ns      1.356V     1.273V     1.484V
[Falling Waveform]
R_fixture = 50.000
V_fixture = 0.000
V_fixture_min = 0.000
V_fixture_max = 0.000
|  time   V(typ)   V(min)   V(max)
0s        1.105V     1.078V     1.121V
486ps     1.105V     1.078V     1.135V
661ps     1.115V     1.078V     565.9mV
778ps     1.099V     1.081V     355mV
838ps     1.003V     1.088V     247.3mV
1.055ns   372.3mV    1.045V     56.95mV
1.321ns   76.37mV    352.9mV    8.174mV
1.644ns   8.043mV    79.83mV    1.493mV
2.112ns   653.4uV    5.399mV    839.7uV
20ns      62.93uV    50.33uV    1.293mV
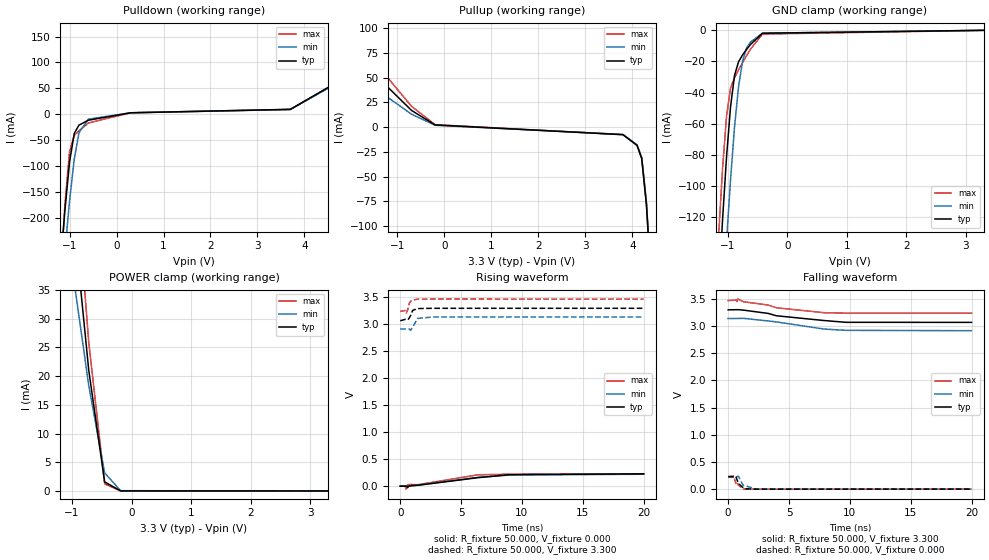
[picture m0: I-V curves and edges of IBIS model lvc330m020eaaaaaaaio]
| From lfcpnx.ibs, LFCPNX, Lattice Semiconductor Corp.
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[Model] lvc330m020eaaaaaaaio
Model_type I/O
Polarity   Non-Inverting
Enable   Active-Low
Vinl =  0.800V
Vinh =  2.000V
Vmeas =  1.650V
Cref =  0.0F
Rref =  1.000M
Vref =  0.0V
C_comp   5.000pF   4.000pF   5.500pF
[Temperature Range]   25.000   0.125k   -40.000
[Voltage Range]   3.300V   3.140V   3.470V
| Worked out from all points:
|   slope of the pulldown table from 0 to 0.495 V, typ, clamps not added: 128 ohm
|   slope of the pullup table from 0 to 0.495 V, typ, clamps not added: 157 ohm
|   GND clamp passes 1 mA (typ) near -0.37 V on its own axis
|   POWER clamp passes 1 mA (typ) near -0.42 V on its own axis
|   rising waveform, R_fixture 50.000, V_fixture 0.000: 20-80 % time 4.54ns typ, 4.56ns min, 3.49ns max; typ from 0.001 V to 0.23 V
|   rising waveform, R_fixture 50.000, V_fixture 3.300: 20-80 % time 270ps typ, 270ps min, 193ps max; typ from 3.07 V to 3.3 V
|   falling waveform, R_fixture 50.000, V_fixture 3.300: 20-80 % time 4.48ns typ, 3.97ns min, 3.96ns max; typ from 3.3 V to 3.07 V
|   falling waveform, R_fixture 50.000, V_fixture 0.000: 20-80 % time 424ps typ, 568ps min, 378ps max; typ from 0.23 V to 0.001 V
[GND_clamp]
|Voltage   I(typ)   I(min)   I(max)
-3.3V     -1.887A    -1.873A    -1.902A
-1.156V   -166.9mA   -224mA     -132.1mA
-1.089V   -121.5mA   -178.4mA   -88.64mA
-1.022V   -81.05mA   -135.2mA   -54.94mA
-955mV    -48.98mA   -95.79mA   -37.15mA
-888mV    -28.98mA   -62.05mA   -30.42mA
-821mV    -20.23mA   -36.35mA   -25.49mA
-754mV    -15.89mA   -19.89mA   -20.81mA
-687mV    -12.34mA   -11.44mA   -16.31mA
-620mV    -9.094mA   -7.515mA   -12.09mA
-419mV    -1.869mA   -1.836mA   -2.383mA
3.3V      0A         0A         0A
[POWER_clamp]
|Voltage   I(typ)   I(min)   I(max)
-3.3V     170.3mA    115.9mA    227.4mA
-2.998V   139.6mA    100.3mA    196.3mA
-2.797V   125.9mA    92.2mA     179.4mA
-2.596V   123.5mA    86.45mA    171.5mA
-1.993V   123.5mA    84.93mA    171.5mA
-1.792V   123.5mA    84.93mA    159.6mA
-1.658V   116.4mA    83.68mA    147.1mA
-1.457V   98.28mA    72.65mA    124.1mA
-720mV    21.08mA    18.41mA    25.96mA
-452mV    1.573mA    3.148mA    1.229mA
-184mV    5.589uA    37.85uA    1.612uA
3.3V      0A         0A         0A
[Pulldown]
|Voltage   I(typ)   I(min)   I(max)
-3.3V     -3.023A    -2.882A    -4.076A
-1.2V     -299.4mA   -373.4mA   -326mA
-1.1V     -186.9mA   -266.3mA   -176.8mA
-1V       -92.5mA    -167.9mA   -72.23mA
-900mV    -37.01mA   -86.9mA    -41.16mA
-800mV    -21.11mA   -36.05mA   -32.24mA
-600mV    -11.54mA   -9.523mA   -16.85mA
300mV     2.82mA     2.735mA    2.82mA
3.7V      9.428mA    9.145mA    9.428mA
5.3V      93.4mA     90.7mA     93.4mA
6.1V      115.7mA    112.2mA    115.7mA
6.6V      168.4mA    163.3mA    168.4mA
[Pullup]
|Voltage   I(typ)   I(min)   I(max)
-3.3V     139.8mA    86.3mA     180mA
-2.9V     101.3mA    74.5mA     141.2mA
-2.7V     91.2mA     69.71mA    121.2mA
-2.1V     82mA       60.12mA    100.7mA
-700mV    16.87mA    13.06mA    20.99mA
-200mV    2.224mA    1.901mA    2.518mA
3.8V      -7.608mA   -7.38mA    -7.608mA
4.1V      -18.4mA    -17.85mA   -18.4mA
4.2V      -31.66mA   -30.71mA   -31.66mA
4.3V      -78.1mA    -75.8mA    -78.1mA
4.4V      -157.4mA   -152.7mA   -157.4mA
6.6V      -2.541A    -2.465A    -2.541A
[Ramp]
| variable   typ   min   max
dV/dt_r   0.137/4.537n   0.132/4.570n   0.137/3.489n
dV/dt_f   0.139/4.121n   0.140/4.439n   0.139/4.430n
R_load = 50.000
[Rising Waveform]
R_fixture = 50.000
V_fixture = 0.000
V_fixture_min = 0.000
V_fixture_max = 0.000
|  time   V(typ)   V(min)   V(max)
0s        974.6uV    2.808mV    974.6uV
395ps     1.014mV    2.541mV    3.245mV
474ps     1.094mV    2.743mV    -54mV
551ps     18.37uV    2.846mV    10.16mV
600ps     -28.6mV    2.882mV    23.28mV
694ps     4.479mV    2.82mV     32.36mV
1.471ns   19.01mV    22.34mV    28.71mV
6.379ns   159mV      165.3mV    212.4mV
9.019ns   214.7mV    208.7mV    223.8mV
20ns      230mV      223mV      230mV
[Rising Waveform]
R_fixture = 50.000
V_fixture = 3.300
V_fixture_min = 3.140
V_fixture_max = 3.470
|  time   V(typ)   V(min)   V(max)
0s        3.069V     2.916V     3.239V
438ps     3.096V     2.916V     3.261V
500ps     3.096V     2.916V     3.213V
631ps     3.087V     2.917V     3.282V
730ps     3.117V     2.917V     3.386V
852ps     3.166V     2.891V     3.43V
1.022ns   3.261V     2.951V     3.453V
1.422ns   3.295V     3.112V     3.469V
2.752ns   3.3V       3.14V      3.471V
20ns      3.3V       3.14V      3.47V
[Falling Waveform]
R_fixture = 50.000
V_fixture = 3.300
V_fixture_min = 3.140
V_fixture_max = 3.470
|  time   V(typ)   V(min)   V(max)
0s        3.3V       3.14V      3.47V
670ps     3.302V     3.14V      3.48V
720ps     3.302V     3.14V      3.453V
800ps     3.303V     3.141V     3.498V
1.265ns   3.294V     3.143V     3.448V
3.287ns   3.234V     3.095V     3.388V
3.956ns   3.191V     3.078V     3.338V
7.877ns   3.103V     2.946V     3.247V
9.69ns    3.07V      2.922V     3.239V
20ns      3.069V     2.916V     3.239V
[Falling Waveform]
R_fixture = 50.000
V_fixture = 0.000
V_fixture_min = 0.000
V_fixture_max = 0.000
|  time   V(typ)   V(min)   V(max)
0s        230mV      223mV      230mV
440ps     229.7mV    222.7mV    240.8mV
596ps     241.2mV    222.5mV    132.5mV
650ps     221.4mV    222.9mV    101.4mV
750ps     159.3mV    231mV      126.2mV
840ps     106mV      238.6mV    74.79mV
1.241ns   22.21mV    65.97mV    3.745mV
1.412ns   6.578mV    61.12mV    468.3uV
2.312ns   -351.9uV   520.9uV    -691.9uV
20ns      974.6uV    2.808mV    974.6uV
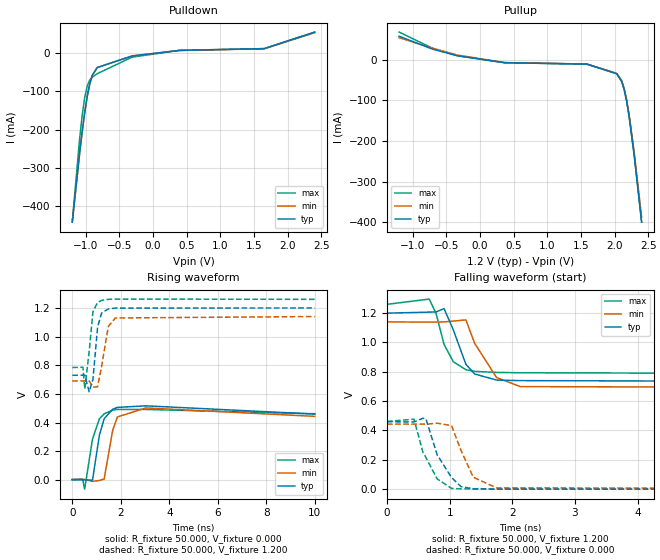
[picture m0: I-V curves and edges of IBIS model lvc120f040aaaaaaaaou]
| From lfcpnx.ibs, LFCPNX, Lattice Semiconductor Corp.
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[Model] lvc120f040aaaaaaaaou
Model_type Output
Polarity   Non-Inverting
Enable   Active-High
Vmeas =  0.600V
Cref =  0.0F
Rref =  1.000M
Vref =  0.0V
C_comp   5.000pF   4.000pF   5.500pF
[Temperature Range]   25.000   0.125k   -40.000
[Voltage Range]   1.200V   1.140V   1.260V
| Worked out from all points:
|   slope of the pulldown table from 0 to 0.18 V, typ, clamps not added: 45.6 ohm
|   slope of the pullup table from 0 to 0.18 V, typ, clamps not added: 43.3 ohm
|   rising waveform, R_fixture 50.000, V_fixture 0.000: 20-80 % time 246ps typ, 243ps min, 274ps max; typ from 0 V to 0.459 V
|   rising waveform, R_fixture 50.000, V_fixture 1.200: 20-80 % time 156ps typ, 259ps min, 149ps max; typ from 0.731 V to 1.2 V
|   falling waveform, R_fixture 50.000, V_fixture 1.200: 20-80 % time 264ps typ, 350ps min, 232ps max; typ from 1.2 V to 0.731 V
|   falling waveform, R_fixture 50.000, V_fixture 0.000: 20-80 % time 286ps typ, 251ps min, 271ps max; typ from 0.459 V to 0 V
[Pulldown]
|Voltage   I(typ)   I(min)   I(max)
-1.2V     -441.6mA   -441.6mA   -440.6mA
-1.089V   -258.3mA   -258.3mA   -220.2mA
-1.052V   -203.6mA   -203.6mA   -161.2mA
-1.015V   -154.4mA   -154.4mA   -115.5mA
-978mV    -112.8mA   -112.8mA   -85.62mA
-941mV    -80.57mA   -80.57mA   -70.15mA
-904mV    -58.3mA    -58.3mA    -62.79mA
-830mV    -37.55mA   -37.55mA   -53.63mA
-312mV    -7.356mA   -7.356mA   -10.35mA
391mV     7.266mA    7.048mA    7.266mA
1.649V    11.87mA    11.51mA    11.87mA
2.4V      55.07mA    53.42mA    55.07mA
[Pullup]
|Voltage   I(typ)   I(min)   I(max)
-1.2V     57.93mA    54.4mA     68.11mA
-708mV    26.38mA    28.5mA     28.67mA
-338mV    9.973mA    11.7mA     10.05mA
365mV     -7.17mA    -6.955mA   -7.17mA
1.586V    -10.69mA   -10.37mA   -10.69mA
2.03V     -34.23mA   -33.21mA   -34.23mA
2.104V    -52.91mA   -51.32mA   -52.91mA
2.141V    -73.01mA   -70.82mA   -73.01mA
2.178V    -102.1mA   -99.05mA   -102.1mA
2.215V    -139.7mA   -135.5mA   -139.7mA
2.289V    -233.6mA   -226.6mA   -233.6mA
2.4V      -399.4mA   -387.4mA   -399.4mA
[Ramp]
| variable   typ   min   max
dV/dt_r   0.275/0.246n   0.275/0.244n   0.275/0.276n
dV/dt_f   0.282/0.265n   0.267/0.351n   0.285/0.237n
R_load = 50.000
[Rising Waveform]
R_fixture = 50.000
V_fixture = 0.000
V_fixture_min = 0.000
V_fixture_max = 0.000
|  time   V(typ)   V(min)   V(max)
0s        37.02uV    2.187mV    2.165mV
430ps     71.45uV    2.079mV    4.903mV
510ps     14.78uV    2.196mV    -65.43mV
835ps     -2.479mV   -11.13mV   285.2mV
1.117ns   310.6mV    -4.695mV   425.2mV
1.313ns   426.1mV    4.965mV    460.6mV
1.667ns   492.6mV    345.5mV    486.3mV
1.857ns   505.5mV    438.6mV    491.4mV
3.03ns    516.5mV    501.8mV    491.2mV
10ns      458.9mV    442.9mV    461mV
[Rising Waveform]
R_fixture = 50.000
V_fixture = 1.200
V_fixture_min = 1.140
V_fixture_max = 1.260
|  time   V(typ)   V(min)   V(max)
0s        730.5mV    690.3mV    784.2mV
437ps     730.5mV    690.2mV    786mV
517ps     730.5mV    690.3mV    635.7mV
697ps     614.1mV    690.2mV    895.3mV
853ps     701.5mV    647.6mV    1.175V
1.043ns   1.065V     649.8mV    1.238V
1.207ns   1.164V     789.1mV    1.252V
1.487ns   1.193V     1.071V     1.26V
1.777ns   1.199V     1.13V      1.262V
10ns      1.2V       1.14V      1.26V
[Falling Waveform]
R_fixture = 50.000
V_fixture = 1.200
V_fixture_min = 1.140
V_fixture_max = 1.260
|  time   V(typ)   V(min)   V(max)
0s        1.2V       1.14V      1.26V
673ps     1.207V     1.139V     1.296V
783ps     1.208V     1.139V     1.198V
910ps     1.231V     1.14V      986.9mV
1.059ns   1.085V     1.146V     868.1mV
1.259ns   850.8mV    1.154V     814.1mV
1.399ns   784.7mV    994.1mV    802.8mV
1.749ns   743.4mV    760.5mV    795.5mV
2.129ns   739.6mV    698.7mV    793.3mV
10ns      730.5mV    690.3mV    784.2mV
[Falling Waveform]
R_fixture = 50.000
V_fixture = 0.000
V_fixture_min = 0.000
V_fixture_max = 0.000
|  time   V(typ)   V(min)   V(max)
0s        458.9mV    442.9mV    461mV
431ps     457.6mV    442.8mV    476.6mV
573ps     482.8mV    442.7mV    249.8mV
620ps     480.2mV    442.3mV    215.6mV
800ps     234.2mV    449.2mV    68.79mV
1.03ns    78.3mV     433mV      4.543mV
1.179ns   17.01mV    265.5mV    1.624mV
1.377ns   1.122mV    80.43mV    1.049mV
1.747ns   -887.5uV   8.022mV    1.054mV
10ns      37.02uV    2.187mV    2.165mV
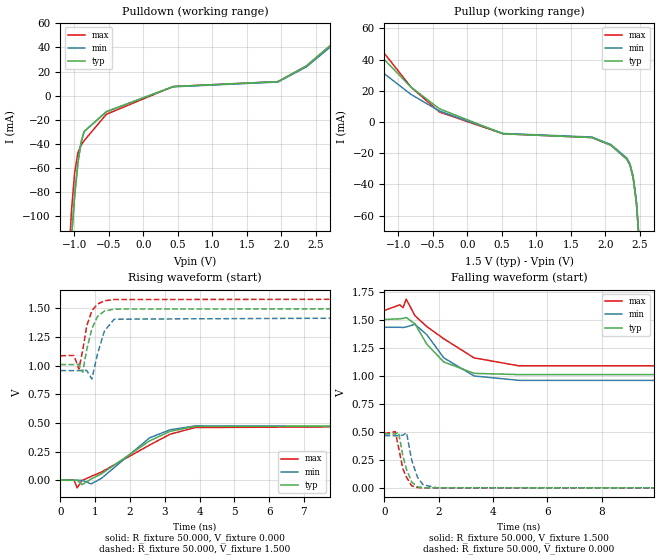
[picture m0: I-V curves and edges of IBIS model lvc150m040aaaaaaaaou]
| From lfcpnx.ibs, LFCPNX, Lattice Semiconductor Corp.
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[Model] lvc150m040aaaaaaaaou
Model_type Output
Polarity   Non-Inverting
Enable   Active-High
Vmeas =  0.750V
Cref =  0.0F
Rref =  1.000M
Vref =  0.0V
C_comp   5.000pF   4.000pF   5.500pF
[Temperature Range]   25.000   0.125k   -40.000
[Voltage Range]   1.500V   1.430V   1.580V
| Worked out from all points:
|   slope of the pulldown table from 0 to 0.225 V, typ, clamps not added: 48.6 ohm
|   slope of the pullup table from 0 to 0.225 V, typ, clamps not added: 58 ohm
|   rising waveform, R_fixture 50.000, V_fixture 0.000: 20-80 % time 1.4ns typ, 1.12ns min, 1.68ns max; typ from 0 V to 0.481 V
|   rising waveform, R_fixture 50.000, V_fixture 1.500: 20-80 % time 276ps typ, 288ps min, 248ps max; typ from 1.01 V to 1.5 V
|   falling waveform, R_fixture 50.000, V_fixture 1.500: 20-80 % time 1.02ns typ, 1.05ns min, 1.75ns max; typ from 1.5 V to 1.01 V
|   falling waveform, R_fixture 50.000, V_fixture 0.000: 20-80 % time 283ps typ, 298ps min, 319ps max; typ from 0.481 V to 0 V
[Pulldown]
|Voltage   I(typ)   I(min)   I(max)
-1.5V     -615.2mA   -615.2mA   -743.9mA
-1.086V   -159.1mA   -159.1mA   -141.6mA
-1.04V    -117.9mA   -117.9mA   -95.39mA
-994mV    -82.8mA    -82.8mA    -63.6mA
-948mV    -56.07mA   -56.07mA   -47.52mA
-902mV    -38.79mA   -38.79mA   -41.1mA
-856mV    -29.67mA   -29.67mA   -37.24mA
-534mV    -13.27mA   -13.27mA   -15.4mA
432mV     7.547mA    7.32mA     7.547mA
1.95V     11.62mA    11.28mA    11.62mA
2.364V    24.62mA    23.88mA    24.62mA
3V        55.78mA    54.1mA     55.78mA
[Pullup]
|Voltage   I(typ)   I(min)   I(max)
-1.5V     53.63mA    41.21mA    60.73mA
-818mV    22.45mA    17.76mA    22.46mA
-404mV    8.467mA    7.042mA    6.425mA
516mV     -7.537mA   -7.311mA   -7.537mA
1.804V    -9.941mA   -9.642mA   -9.941mA
2.08V     -14.9mA    -14.45mA   -14.9mA
2.31V     -23.81mA   -23.09mA   -23.81mA
2.356V    -27.64mA   -26.81mA   -27.64mA
2.402V    -35.88mA   -34.81mA   -35.88mA
2.448V    -51.56mA   -50.02mA   -51.56mA
2.54V     -107.9mA   -104.7mA   -107.9mA
3V        -561.8mA   -544.9mA   -561.8mA
[Ramp]
| variable   typ   min   max
dV/dt_r   0.289/1.410n   0.279/1.145n   0.287/1.713n
dV/dt_f   0.294/1.016n   0.285/1.052n   0.296/1.752n
R_load = 50.000
[Rising Waveform]
R_fixture = 50.000
V_fixture = 0.000
V_fixture_min = 0.000
V_fixture_max = 0.000
|  time   V(typ)   V(min)   V(max)
0s        47.12uV    -564uV     138.4uV
390ps     56.83uV    -866.2uV   1.651mV
481ps     214.3uV    -600.4uV   -66.85mV
620ps     -38.64mV   -467uV     -2.971mV
885ps     10.43mV    -32.25mV   33.24mV
1.174ns   55.17mV    15.24mV    70.44mV
2.562ns   343.1mV    370mV      306.7mV
3.152ns   426.9mV    440.3mV    401.5mV
3.871ns   469.2mV    474.1mV    459.8mV
20ns      481.4mV    464.8mV    483.4mV
[Rising Waveform]
R_fixture = 50.000
V_fixture = 1.500
V_fixture_min = 1.430
V_fixture_max = 1.580
|  time   V(typ)   V(min)   V(max)
0s        1.01V      957.2mV    1.087V
390ps     1.01V      956.9mV    1.089V
530ps     1.012V     957.2mV    969.8mV
640ps     942.8mV    957.3mV    1.134V
754ps     1.139V     959mV      1.346V
904ps     1.323V     883.3mV    1.479V
1.064ns   1.429V     1.101V     1.538V
1.265ns   1.477V     1.303V     1.566V
1.545ns   1.494V     1.406V     1.578V
20ns      1.5V       1.431V     1.581V
[Falling Waveform]
R_fixture = 50.000
V_fixture = 1.500
V_fixture_min = 1.430
V_fixture_max = 1.580
|  time   V(typ)   V(min)   V(max)
0s        1.5V       1.431V     1.581V
562ps     1.507V     1.431V     1.631V
686ps     1.51V      1.429V     1.606V
800ps     1.518V     1.434V     1.682V
1.124ns   1.461V     1.457V     1.534V
1.56ns    1.28V      1.365V     1.437V
2.183ns   1.122V     1.159V     1.329V
3.303ns   1.02V      996.7mV    1.158V
4.961ns   1.009V     957.7mV    1.087V
20ns      1.01V      957.2mV    1.087V
[Falling Waveform]
R_fixture = 50.000
V_fixture = 0.000
V_fixture_min = 0.000
V_fixture_max = 0.000
|  time   V(typ)   V(min)   V(max)
0s        481.4mV    464.8mV    483.4mV
397ps     480.8mV    464.5mV    500.1mV
516ps     496.3mV    464.6mV    362.1mV
680ps     282mV      469.2mV    167.4mV
813ps     161.7mV    490mV      92.73mV
1.004ns   51.26mV    244.6mV    16.98mV
1.213ns   8.558mV    94.72mV    1.807mV
1.423ns   900.6uV    26.79mV    -650uV
1.923ns   -165.3uV   405uV      -899.4uV
20ns      47.12uV    -564uV     138.4uV
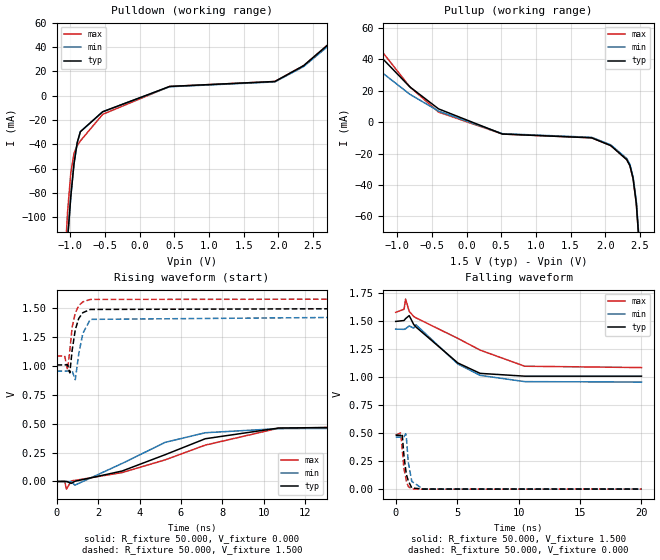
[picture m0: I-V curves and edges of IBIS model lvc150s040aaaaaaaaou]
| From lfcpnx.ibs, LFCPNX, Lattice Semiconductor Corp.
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[Model] lvc150s040aaaaaaaaou
Model_type Output
Polarity   Non-Inverting
Enable   Active-High
Vmeas =  0.750V
Cref =  0.0F
Rref =  1.000M
Vref =  0.0V
C_comp   5.000pF   4.000pF   5.500pF
[Temperature Range]   25.000   0.125k   -40.000
[Voltage Range]   1.500V   1.430V   1.580V
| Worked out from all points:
|   slope of the pulldown table from 0 to 0.225 V, typ, clamps not added: 48.6 ohm
|   slope of the pullup table from 0 to 0.225 V, typ, clamps not added: 58 ohm
|   rising waveform, R_fixture 50.000, V_fixture 0.000: 20-80 % time 4.19ns typ, 3.37ns min, 4.77ns max; typ from 0 V to 0.481 V
|   rising waveform, R_fixture 50.000, V_fixture 1.500: 20-80 % time 309ps typ, 328ps min, 283ps max; typ from 1.01 V to 1.5 V
|   falling waveform, R_fixture 50.000, V_fixture 1.500: 20-80 % time 3.18ns typ, 3.37ns min, 5.31ns max; typ from 1.5 V to 1.01 V
|   falling waveform, R_fixture 50.000, V_fixture 0.000: 20-80 % time 322ps typ, 318ps min, 331ps max; typ from 0.481 V to 0 V
[Pulldown]
|Voltage   I(typ)   I(min)   I(max)
-1.5V     -615.2mA   -615.2mA   -743.9mA
-1.086V   -159.1mA   -159.1mA   -141.6mA
-1.04V    -117.9mA   -117.9mA   -95.39mA
-994mV    -82.8mA    -82.8mA    -63.6mA
-948mV    -56.07mA   -56.07mA   -47.52mA
-902mV    -38.79mA   -38.79mA   -41.1mA
-856mV    -29.67mA   -29.67mA   -37.24mA
-534mV    -13.27mA   -13.27mA   -15.4mA
432mV     7.547mA    7.32mA     7.547mA
1.95V     11.62mA    11.28mA    11.62mA
2.364V    24.62mA    23.88mA    24.62mA
3V        55.78mA    54.1mA     55.78mA
[Pullup]
|Voltage   I(typ)   I(min)   I(max)
-1.5V     53.63mA    41.21mA    60.73mA
-818mV    22.45mA    17.76mA    22.46mA
-404mV    8.467mA    7.042mA    6.425mA
516mV     -7.537mA   -7.311mA   -7.537mA
1.804V    -9.941mA   -9.642mA   -9.941mA
2.08V     -14.9mA    -14.45mA   -14.9mA
2.31V     -23.81mA   -23.09mA   -23.81mA
2.356V    -27.64mA   -26.81mA   -27.64mA
2.402V    -35.88mA   -34.81mA   -35.88mA
2.448V    -51.56mA   -50.02mA   -51.56mA
2.54V     -107.9mA   -104.7mA   -107.9mA
3V        -561.8mA   -544.9mA   -561.8mA
[Ramp]
| variable   typ   min   max
dV/dt_r   0.289/4.203n   0.279/3.402n   0.287/4.772n
dV/dt_f   0.294/3.184n   0.285/3.387n   0.296/5.306n
R_load = 50.000
[Rising Waveform]
R_fixture = 50.000
V_fixture = 0.000
V_fixture_min = 0.000
V_fixture_max = 0.000
|  time   V(typ)   V(min)   V(max)
0s        47.12uV    -564uV     138.4uV
390ps     56.86uV    -866.7uV   1.65mV
481ps     214.2uV    -599.1uV   -66.69mV
712ps     -16.46mV   -394uV     5.226mV
884ps     1.537mV    -32.24mV   9.374mV
3.162ns   90.52mV    156.2mV    77.18mV
5.24ns    232.4mV    339.2mV    187.5mV
7.17ns    370.3mV    422.4mV    315.2mV
10.7ns    463mV      458.1mV    461.7mV
20ns      481.4mV    464.8mV    483.4mV
[Rising Waveform]
R_fixture = 50.000
V_fixture = 1.500
V_fixture_min = 1.430
V_fixture_max = 1.580
|  time   V(typ)   V(min)   V(max)
0s        1.01V      957.2mV    1.087V
390ps     1.01V      956.9mV    1.089V
530ps     1.012V     957.2mV    968.6mV
640ps     941mV      957.3mV    1.133V
754ps     1.138V     959mV      1.337V
904ps     1.315V     881.6mV    1.461V
1.071ns   1.413V     1.106V     1.524V
1.269ns   1.463V     1.284V     1.557V
1.629ns   1.491V     1.405V     1.578V
20ns      1.5V       1.431V     1.581V
[Falling Waveform]
R_fixture = 50.000
V_fixture = 1.500
V_fixture_min = 1.430
V_fixture_max = 1.580
|  time   V(typ)   V(min)   V(max)
0s        1.5V       1.431V     1.581V
680ps     1.508V     1.429V     1.609V
806ps     1.525V     1.434V     1.7V
1.1ns     1.552V     1.46V      1.59V
1.463ns   1.473V     1.44V      1.545V
1.65ns    1.45V      1.47V      1.532V
5.06ns    1.128V     1.119V     1.348V
6.875ns   1.035V     1.017V     1.243V
10.5ns    1.01V      961.3mV    1.099V
20ns      1.01V      957.2mV    1.087V
[Falling Waveform]
R_fixture = 50.000
V_fixture = 0.000
V_fixture_min = 0.000
V_fixture_max = 0.000
|  time   V(typ)   V(min)   V(max)
0s        481.4mV    464.8mV    483.4mV
397ps     480.7mV    464.5mV    501.9mV
526ps     494.4mV    464.6mV    364.3mV
670ps     300.2mV    467.4mV    184.1mV
814ps     174.4mV    494.7mV    107.1mV
874ps     129.1mV    453.6mV    69.54mV
1.024ns   73.15mV    239.7mV    22.51mV
1.31ns    9.743mV    68.36mV    1.514mV
2.23ns    -383.2uV   -546.5uV   -1.129mV
20ns      47.12uV    -564uV     138.4uV
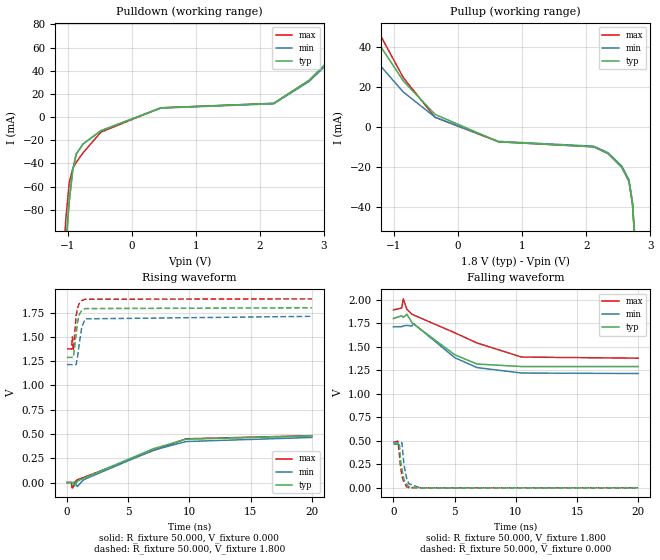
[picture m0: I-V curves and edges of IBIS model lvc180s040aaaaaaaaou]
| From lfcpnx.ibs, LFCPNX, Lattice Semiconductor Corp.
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[Model] lvc180s040aaaaaaaaou
Model_type Output
Polarity   Non-Inverting
Enable   Active-High
Vmeas =  0.900V
Cref =  0.0F
Rref =  1.000M
Vref =  0.0V
C_comp   5.000pF   4.000pF   5.500pF
[Temperature Range]   25.000   0.125k   -40.000
[Voltage Range]   1.800V   1.710V   1.890V
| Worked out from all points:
|   slope of the pulldown table from 0 to 0.27 V, typ, clamps not added: 48.7 ohm
|   slope of the pullup table from 0 to 0.27 V, typ, clamps not added: 72.3 ohm
|   rising waveform, R_fixture 50.000, V_fixture 0.000: 20-80 % time 5.14ns typ, 5.06ns min, 5.46ns max; typ from 0 V to 0.481 V
|   rising waveform, R_fixture 50.000, V_fixture 1.800: 20-80 % time 317ps typ, 338ps min, 247ps max; typ from 1.29 V to 1.8 V
|   falling waveform, R_fixture 50.000, V_fixture 1.800: 20-80 % time 3.23ns typ, 3.42ns min, 5.34ns max; typ from 1.8 V to 1.29 V
|   falling waveform, R_fixture 50.000, V_fixture 0.000: 20-80 % time 309ps typ, 328ps min, 349ps max; typ from 0.481 V to 0 V
[Pulldown]
|Voltage   I(typ)   I(min)   I(max)
-1.8V     -995.9mA   -995.9mA   -1.252A
-1.085V   -162.7mA   -162.7mA   -144.5mA
-1.03V    -112.8mA   -112.8mA   -89.71mA
-975mV    -72.73mA   -72.73mA   -56.82mA
-920mV    -45.76mA   -45.76mA   -44.24mA
-865mV    -31.82mA   -31.82mA   -38.99mA
-755mV    -23mA      -23mA      -30.61mA
-480mV    -11.76mA   -11.76mA   -12.95mA
455mV     7.985mA    7.745mA    7.985mA
2.215V    11.84mA    11.48mA    11.84mA
2.765V    31.59mA    30.64mA    31.59mA
3.6V      77.31mA    74.99mA    77.31mA
[Pullup]
|Voltage   I(typ)   I(min)   I(max)
-1.8V     69.64mA    52.58mA    81.3mA
-1.735V   66.34mA    50.11mA    77.3mA
-855mV    23.18mA    17.63mA    24.82mA
-360mV    6.378mA    4.991mA    4.895mA
630mV     -7.391mA   -7.169mA   -7.391mA
2.115V    -9.908mA   -9.611mA   -9.908mA
2.335V    -13.23mA   -12.83mA   -13.23mA
2.555V    -20.26mA   -19.65mA   -20.26mA
2.665V    -27.31mA   -26.49mA   -27.31mA
2.72V     -38.63mA   -37.47mA   -38.63mA
2.83V     -93.7mA    -90.9mA    -93.7mA
3.6V      -821.7mA   -797.1mA   -821.7mA
[Ramp]
| variable   typ   min   max
dV/dt_r   0.289/5.142n   0.279/5.063n   0.291/5.456n
dV/dt_f   0.306/3.233n   0.292/3.426n   0.308/5.337n
R_load = 50.000
[Rising Waveform]
R_fixture = 50.000
V_fixture = 0.000
V_fixture_min = 0.000
V_fixture_max = 0.000
|  time   V(typ)   V(min)   V(max)
0s        55.76uV    -564.8uV   143.9uV
354ps     -420nV     -834.2uV   1.606mV
407ps     201.3uV    -871.5uV   -53.55mV
481ps     -1.77mV    -638uV     -54.74mV
609ps     -35.92mV   -368.2uV   -460.2uV
844ps     14.13mV    -41.7mV    28.53mV
1.355ns   43.91mV    29mV       52.36mV
7ns       345.3mV    331.5mV    326.3mV
9.719ns   446.7mV    422.3mV    450.6mV
20ns      480.9mV    464.3mV    482.5mV
[Rising Waveform]
R_fixture = 50.000
V_fixture = 1.800
V_fixture_min = 1.710
V_fixture_max = 1.890
|  time   V(typ)   V(min)   V(max)
0s        1.289V     1.215V     1.378V
371ps     1.289V     1.215V     1.375V
429ps     1.289V     1.215V     1.501V
520ps     1.29V      1.215V     1.362V
744ps     1.527V     1.215V     1.716V
859ps     1.652V     1.291V     1.798V
998ps     1.73V      1.427V     1.845V
1.214ns   1.775V     1.608V     1.875V
1.504ns   1.792V     1.686V     1.888V
20ns      1.8V       1.712V     1.892V
[Falling Waveform]
R_fixture = 50.000
V_fixture = 1.800
V_fixture_min = 1.710
V_fixture_max = 1.890
|  time   V(typ)   V(min)   V(max)
0s        1.8V       1.712V     1.892V
674ps     1.829V     1.713V     1.912V
811ps     1.812V     1.721V     2.009V
1.1ns     1.846V     1.727V     1.898V
1.492ns   1.761V     1.72V      1.848V
1.652ns   1.741V     1.745V     1.837V
5.003ns   1.415V     1.384V     1.649V
6.83ns    1.316V     1.278V     1.54V
10.47ns   1.289V     1.22V      1.39V
20ns      1.289V     1.215V     1.378V
[Falling Waveform]
R_fixture = 50.000
V_fixture = 0.000
V_fixture_min = 0.000
V_fixture_max = 0.000
|  time   V(typ)   V(min)   V(max)
0s        480.9mV    464.3mV    482.5mV
367ps     480.5mV    463.9mV    496.8mV
472ps     488.2mV    464.1mV    373.3mV
580ps     295.4mV    464.4mV    225.3mV
694ps     197mV      480.1mV    124.7mV
872ps     80.55mV    233.3mV    55.26mV
1.082ns   39.62mV    102.3mV    10.01mV
1.262ns   9.259mV    42.69mV    1.339mV
2.193ns   -442.4uV   -866.6uV   -1.267mV
20ns      55.76uV    -564.8uV   143.9uV
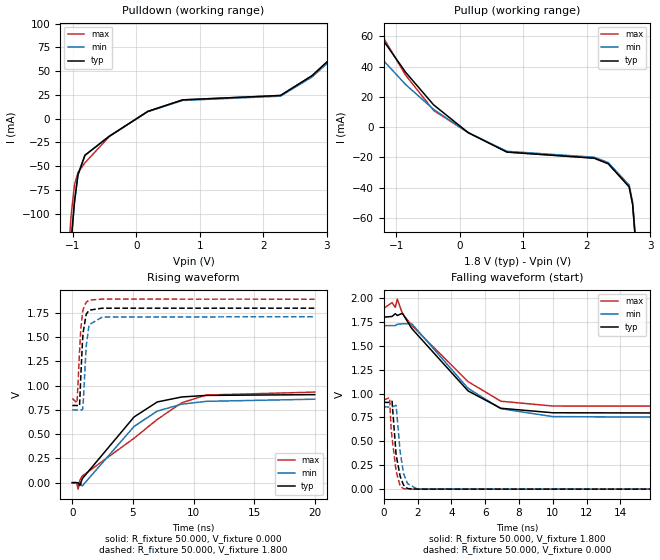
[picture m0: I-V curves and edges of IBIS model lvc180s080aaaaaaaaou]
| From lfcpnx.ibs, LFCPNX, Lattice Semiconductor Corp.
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|Model lvc180s080aaaaaaaaou
[Model] lvc180s080aaaaaaaaou
Model_type Output
Polarity   Non-Inverting
Enable   Active-High
Vmeas =  0.900V
Cref =  0.0F
Rref =  1.000M
Vref =  0.0V
C_comp   5.000pF   4.000pF   5.500pF
[Temperature Range]   25.000   0.125k   -40.000
[Voltage Range]   1.800V   1.710V   1.890V
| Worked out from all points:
|   slope of the pulldown table from 0 to 0.27 V, typ, clamps not added: 25.1 ohm
|   slope of the pullup table from 0 to 0.27 V, typ, clamps not added: 36.8 ohm
|   rising waveform, R_fixture 50.000, V_fixture 0.000: 20-80 % time 3.79ns typ, 4.1ns min, 5.83ns max; typ from 0 V to 0.908 V
|   rising waveform, R_fixture 50.000, V_fixture 1.800: 20-80 % time 267ps typ, 286ps min, 290ps max; typ from 0.796 V to 1.8 V
|   falling waveform, R_fixture 50.000, V_fixture 1.800: 20-80 % time 3.13ns typ, 3.18ns min, 3.55ns max; typ from 1.8 V to 0.796 V
|   falling waveform, R_fixture 50.000, V_fixture 0.000: 20-80 % time 324ps typ, 330ps min, 330ps max; typ from 0.908 V to 0 V
[Pulldown]
|Voltage   I(typ)   I(min)   I(max)
-1.8V     -1.123A    -1.123A    -1.379A
-1.085V   -187mA     -187mA     -163mA
-1.03V    -131.9mA   -131.9mA   -104mA
-975mV    -88.04mA   -88.04mA   -69.67mA
-920mV    -59.22mA   -59.22mA   -56.86mA
-810mV    -38.63mA   -38.63mA   -46.55mA
-425mV    -18.55mA   -18.55mA   -18.85mA
180mV     7.522mA    7.296mA    7.522mA
730mV     19.66mA    19.07mA    19.66mA
2.27V     24.3mA     23.57mA    24.3mA
2.765V    45.03mA    43.68mA    45.03mA
3.6V      96.4mA     93.5mA     96.4mA
[Pullup]
|Voltage   I(typ)   I(min)   I(max)
-1.8V     92.7mA     71.09mA    101.5mA
-1.735V   88.8mA     68.19mA    96.8mA
-855mV    36.27mA    28.13mA    34.32mA
-415mV    14.75mA    11.73mA    11.05mA
135mV     -3.78mA    -3.666mA   -3.78mA
740mV     -16.47mA   -15.97mA   -16.47mA
2.115V    -20.5mA    -19.88mA   -20.5mA
2.335V    -24.14mA   -23.41mA   -24.14mA
2.665V    -39.44mA   -38.25mA   -39.44mA
2.72V     -51.1mA    -49.57mA   -51.1mA
2.83V     -110.7mA   -107.4mA   -110.7mA
3.6V      -932.5mA   -904.6mA   -932.5mA
[Ramp]
| variable   typ   min   max
dV/dt_r   0.545/3.795n   0.512/4.120n   0.560/5.831n
dV/dt_f   0.602/3.125n   0.577/3.181n   0.614/3.556n
R_load = 50.000
[Rising Waveform]
R_fixture = 50.000
V_fixture = 0.000
V_fixture_min = 0.000
V_fixture_max = 0.000
|  time   V(typ)   V(min)   V(max)
0s        66.63uV    -485.3uV   428.6uV
355ps     61.52uV    -758.3uV   2.171mV
480ps     -1.914mV   -506.2uV   -66.96mV
634ps     -28.46mV   -249.5uV   27.42mV
824ps     40.97mV    -33.58mV   69.27mV
5.1ns     678.2mV    580.4mV    458.9mV
7.01ns    832.7mV    738.6mV    652.5mV
9.034ns   884.1mV    809.9mV    824.6mV
11.06ns   900.2mV    839mV      904mV
20ns      908.2mV    861.1mV    934.4mV
[Rising Waveform]
R_fixture = 50.000
V_fixture = 1.800
V_fixture_min = 1.710
V_fixture_max = 1.890
|  time   V(typ)   V(min)   V(max)
0s        796mV      750.1mV    868.6mV
393ps     796.1mV    749.7mV    822mV
600ps     792.6mV    750.3mV    1.349V
704ps     1.1V       751.2mV    1.586V
844ps     1.462V     751.5mV    1.75V
904ps     1.555V     826.2mV    1.79V
1.145ns   1.736V     1.405V     1.861V
1.384ns   1.779V     1.629V     1.883V
2.474ns   1.8V       1.708V     1.894V
20ns      1.8V       1.712V     1.892V
[Falling Waveform]
R_fixture = 50.000
V_fixture = 1.800
V_fixture_min = 1.710
V_fixture_max = 1.890
|  time   V(typ)   V(min)   V(max)
0s        1.8V       1.712V     1.892V
495ps     1.808V     1.712V     1.953V
685ps     1.837V     1.712V     1.903V
804ps     1.818V     1.726V     1.99V
1.107ns   1.841V     1.731V     1.839V
1.657ns   1.682V     1.732V     1.713V
4.985ns   1.029V     1.056V     1.126V
6.927ns   846.6mV    841.9mV    920.3mV
10ns      799.4mV    759.3mV    870mV
20ns      796mV      750.1mV    868.6mV
[Falling Waveform]
R_fixture = 50.000
V_fixture = 0.000
V_fixture_min = 0.000
V_fixture_max = 0.000
|  time   V(typ)   V(min)   V(max)
0s        908.2mV    861.1mV    934.4mV
349ps     907.9mV    860.9mV    956.2mV
434ps     915.9mV    860.9mV    639.5mV
493ps     919.7mV    860.9mV    536.3mV
733ps     359.7mV    877.2mV    188.4mV
974ps     132.8mV    388.5mV    30.77mV
1.173ns   42.03mV    162.1mV    4.979mV
1.415ns   5.455mV    56.42mV    51.32uV
1.972ns   39.8uV     2.083mV    -551.5uV
20ns      66.63uV    -485.3uV   428.6uV
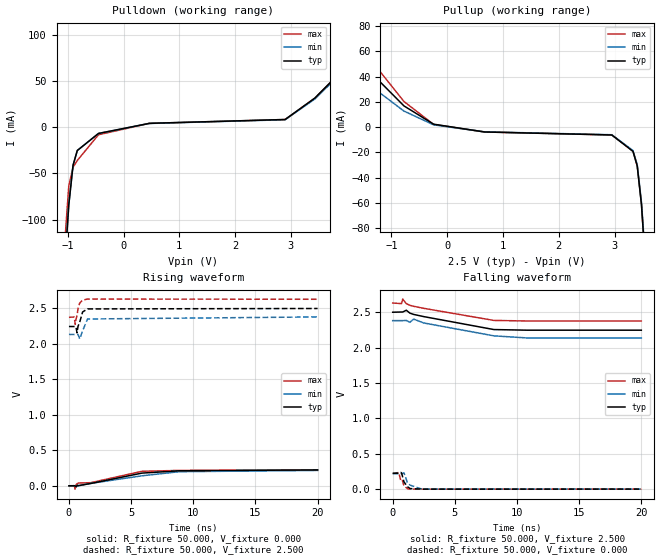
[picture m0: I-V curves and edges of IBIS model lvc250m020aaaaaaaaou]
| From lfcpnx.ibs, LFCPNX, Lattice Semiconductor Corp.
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[Model] lvc250m020aaaaaaaaou
Model_type Output
Polarity   Non-Inverting
Enable   Active-High
Vmeas =  1.250V
Cref =  0.0F
Rref =  1.000M
Vref =  0.0V
C_comp   5.000pF   4.000pF   5.500pF
[Temperature Range]   25.000   0.125k   -40.000
[Voltage Range]   2.500V   2.380V   2.630V
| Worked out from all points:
|   slope of the pulldown table from 0 to 0.375 V, typ, clamps not added: 103 ohm
|   slope of the pullup table from 0 to 0.375 V, typ, clamps not added: 145 ohm
|   rising waveform, R_fixture 50.000, V_fixture 0.000: 20-80 % time 3.61ns typ, 4.57ns min, 3.04ns max; typ from 0 V to 0.224 V
|   rising waveform, R_fixture 50.000, V_fixture 2.500: 20-80 % time 243ps typ, 302ps min, 209ps max; typ from 2.25 V to 2.5 V
|   falling waveform, R_fixture 50.000, V_fixture 2.500: 20-80 % time 4.11ns typ, 4.45ns min, 4.41ns max; typ from 2.5 V to 2.25 V
|   falling waveform, R_fixture 50.000, V_fixture 0.000: 20-80 % time 364ps typ, 460ps min, 341ps max; typ from 0.224 V to 0 V
[Pulldown]
|Voltage   I(typ)   I(min)   I(max)
-2.5V     -2.133A    -2.133A    -2.742A
-1.056V   -153.2mA   -153.2mA   -127.1mA
-980mV    -83.55mA   -83.55mA   -63.14mA
-904mV    -41.24mA   -41.24mA   -43.39mA
-828mV    -25.25mA   -25.25mA   -36.06mA
-448mV    -6.819mA   -6.819mA   -8.226mA
464mV     4.094mA    3.971mA    4.094mA
2.896V    8.243mA    7.995mA    8.243mA
3.428V    31.33mA    30.39mA    31.33mA
4.568V    100.7mA    97.7mA     100.7mA
4.796V    109.3mA    106mA      109.3mA
5V        113.2mA    109.8mA    113.2mA
[Pullup]
|Voltage   I(typ)   I(min)   I(max)
-2.5V     80.2mA     62.08mA    100mA
-2.22V    77mA       58.13mA    96mA
-1.84V    64.02mA    48.16mA    79mA
-776mV    16.78mA    12.7mA     20.26mA
-244mV    2.321mA    1.813mA    2.153mA
668mV     -3.822mA   -3.707mA   -3.822mA
2.948V    -6.19mA    -6.005mA   -6.19mA
3.328V    -19.09mA   -18.52mA   -19.09mA
3.404V    -30.57mA   -29.66mA   -30.57mA
3.48V     -61.09mA   -59.26mA   -61.09mA
3.556V    -111.5mA   -108.2mA   -111.5mA
5V        -1.548A    -1.502A    -1.548A
[Ramp]
| variable   typ   min   max
dV/dt_r   0.134/3.609n   0.134/4.601n   0.139/3.045n
dV/dt_f   0.152/4.110n   0.142/4.459n   0.153/4.415n
R_load = 50.000
[Rising Waveform]
R_fixture = 50.000
V_fixture = 0.000
V_fixture_min = 0.000
V_fixture_max = 0.000
|  time   V(typ)   V(min)   V(max)
0s        57.57uV    7.968uV    153.9uV
434ps     71.13uV    -159.9uV   2.384mV
486ps     99.73uV    -58.94uV   -47.58mV
598ps     -14.38mV   31.07uV    20.99mV
667ps     9.797mV    65.67uV    30.94mV
765ps     2.681mV    -540.8uV   39.46mV
1.765ns   32.96mV    34.22mV    44.06mV
5.88ns    179mV      141.1mV    204.6mV
8.89ns    211.7mV    198.9mV    216.7mV
20ns      223.6mV    216.8mV    223.7mV
[Rising Waveform]
R_fixture = 50.000
V_fixture = 2.500
V_fixture_min = 2.380
V_fixture_max = 2.630
|  time   V(typ)   V(min)   V(max)
0s        2.246V     2.134V     2.376V
425ps     2.246V     2.134V     2.379V
505ps     2.246V     2.134V     2.275V
566ps     2.24V      2.134V     2.345V
647ps     2.157V     2.134V     2.405V
731ps     2.25V      2.135V     2.498V
865ps     2.307V     2.07V      2.576V
1.098ns   2.451V     2.186V     2.619V
1.495ns   2.494V     2.352V     2.633V
20ns      2.5V       2.381V     2.63V
[Falling Waveform]
R_fixture = 50.000
V_fixture = 2.500
V_fixture_min = 2.380
V_fixture_max = 2.630
|  time   V(typ)   V(min)   V(max)
0s        2.5V       2.381V     2.63V
714ps     2.503V     2.381V     2.622V
804ps     2.503V     2.381V     2.686V
1.095ns   2.528V     2.384V     2.621V
1.385ns   2.487V     2.357V     2.598V
1.682ns   2.469V     2.403V     2.584V
2.501ns   2.438V     2.348V     2.555V
8.14ns    2.255V     2.166V     2.384V
10.86ns   2.246V     2.136V     2.376V
20ns      2.246V     2.134V     2.376V
[Falling Waveform]
R_fixture = 50.000
V_fixture = 0.000
V_fixture_min = 0.000
V_fixture_max = 0.000
|  time   V(typ)   V(min)   V(max)
0s        223.6mV    216.8mV    223.7mV
487ps     223mV      216.7mV    234.1mV
647ps     234.8mV    216.5mV    122.6mV
694ps     232.5mV    216.7mV    129.8mV
757ps     199.9mV    218.9mV    133.8mV
904ps     102.9mV    230.6mV    48.31mV
1.194ns   32.75mV    85.2mV     4.975mV
1.405ns   7.179mV    55.8mV     3.432uV
2.355ns   -582.3uV   -593.8uV   -985.6uV
20ns      57.57uV    7.968uV    153.9uV
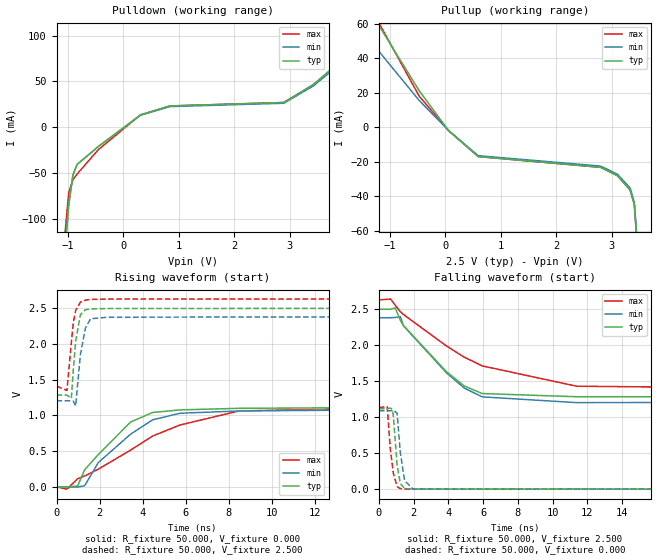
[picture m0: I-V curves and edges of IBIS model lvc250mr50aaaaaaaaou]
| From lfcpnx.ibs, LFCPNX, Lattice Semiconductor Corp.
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[Model] lvc250mr50aaaaaaaaou
Model_type Output
Polarity   Non-Inverting
Enable   Active-High
Vmeas =  1.250V
Cref =  0.0F
Rref =  1.000M
Vref =  0.0V
C_comp   5.000pF   4.000pF   5.500pF
[Temperature Range]   25.000   0.125k   -40.000
[Voltage Range]   2.500V   2.380V   2.630V
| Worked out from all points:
|   slope of the pulldown table from 0 to 0.375 V, typ, clamps not added: 24.3 ohm
|   slope of the pullup table from 0 to 0.375 V, typ, clamps not added: 31.3 ohm
|   rising waveform, R_fixture 50.000, V_fixture 0.000: 20-80 % time 2.11ns typ, 2.43ns min, 4.34ns max; typ from 0 V to 1.12 V
|   rising waveform, R_fixture 50.000, V_fixture 2.500: 20-80 % time 247ps typ, 289ps min, 258ps max; typ from 1.28 V to 2.5 V
|   falling waveform, R_fixture 50.000, V_fixture 2.500: 20-80 % time 2.91ns typ, 2.83ns min, 5.03ns max; typ from 2.5 V to 1.28 V
|   falling waveform, R_fixture 50.000, V_fixture 0.000: 20-80 % time 242ps typ, 254ps min, 273ps max; typ from 1.12 V to 0 V
[Pulldown]
|Voltage   I(typ)   I(min)   I(max)
-2.5V     -1.843A    -1.843A    -2.4A
-1.056V   -141.1mA   -141.1mA   -121.9mA
-980mV    -84.5mA    -84.5mA    -71.68mA
-904mV    -52.18mA   -52.18mA   -57.43mA
-828mV    -40.67mA   -40.67mA   -51.18mA
-448mV    -21.22mA   -21.22mA   -24.67mA
312mV     13.36mA    12.96mA    13.36mA
844mV     23.15mA    22.45mA    23.15mA
2.896V    26.91mA    26.1mA     26.91mA
3.428V    46.46mA    45.06mA    46.46mA
4.644V    109.3mA    106mA      109.3mA
5V        117.5mA    114mA      117.5mA
[Pullup]
|Voltage   I(typ)   I(min)   I(max)
-2.5V     97.92mA    74.3mA     113.9mA
-1.84V    90.8mA     68.13mA    97.7mA
-1.688V   84.5mA     63.28mA    89.2mA
-472mV    21.14mA    15.46mA    17.98mA
60mV      -2.1mA     -2.037mA   -2.1mA
592mV     -17.07mA   -16.56mA   -17.07mA
2.796V    -23.3mA    -22.6mA    -23.3mA
3.1V      -28.17mA   -27.33mA   -28.17mA
3.328V    -36.4mA    -35.3mA    -36.4mA
3.404V    -44.88mA   -43.53mA   -44.88mA
3.556V    -113.7mA   -110.3mA   -113.7mA
5V        -1.462A    -1.418A    -1.462A
[Ramp]
| variable   typ   min   max
dV/dt_r   0.677/2.111n   0.653/2.454n   0.680/4.340n
dV/dt_f   0.728/2.909n   0.711/2.829n   0.754/5.030n
R_load = 50.000
[Rising Waveform]
R_fixture = 50.000
V_fixture = 0.000
V_fixture_min = 0.000
V_fixture_max = 0.000
|  time   V(typ)   V(min)   V(max)
0s        62.93uV    -430.5uV   1.022mV
479ps     177.4uV    -439.2uV   -31.99mV
977ps     12.17mV    -2.73mV    113.2mV
1.305ns   239.4mV    16.19mV    152.8mV
1.934ns   451mV      339.2mV    247.8mV
3.435ns   908.3mV    737.8mV    514.5mV
4.46ns    1.042V     939.4mV    712.3mV
5.73ns    1.078V     1.031V     866.6mV
8.459ns   1.1V       1.063V     1.063V
20ns      1.118V     1.089V     1.134V
[Rising Waveform]
R_fixture = 50.000
V_fixture = 2.500
V_fixture_min = 2.380
V_fixture_max = 2.630
|  time   V(typ)   V(min)   V(max)
0s        1.285V     1.205V     1.411V
483ps     1.285V     1.205V     1.35V
687ps     1.239V     1.205V     2.021V
777ps     1.634V     1.202V     2.298V
887ps     2.039V     1.134V     2.47V
1.108ns   2.411V     1.856V     2.586V
1.337ns   2.48V      2.221V     2.615V
1.577ns   2.491V     2.354V     2.625V
2.437ns   2.498V     2.377V     2.63V
20ns      2.5V       2.381V     2.63V
[Falling Waveform]
R_fixture = 50.000
V_fixture = 2.500
V_fixture_min = 2.380
V_fixture_max = 2.630
|  time   V(typ)   V(min)   V(max)
0s        2.5V       2.381V     2.63V
679ps     2.5V       2.382V     2.641V
949ps     2.518V     2.385V     2.554V
1.244ns   2.344V     2.396V     2.464V
1.414ns   2.274V     2.271V     2.427V
3.904ns   1.628V     1.613V     1.987V
4.919ns   1.433V     1.404V     1.833V
5.95ns    1.328V     1.282V     1.712V
11.38ns   1.284V     1.202V     1.43V
20ns      1.285V     1.205V     1.411V
[Falling Waveform]
R_fixture = 50.000
V_fixture = 0.000
V_fixture_min = 0.000
V_fixture_max = 0.000
|  time   V(typ)   V(min)   V(max)
0s        1.118V     1.089V     1.134V
486ps     1.118V     1.089V     1.146V
661ps     1.127V     1.089V     560.2mV
778ps     1.11V      1.092V     333.8mV
838ps     1.011V     1.098V     220mV
1.055ns   332.4mV    1.054V     34.32mV
1.235ns   79.63mV    515.7mV    7.281mV
1.484ns   7.978mV    117mV      1.567mV
1.955ns   648uV      3.526mV    724.4uV
20ns      62.93uV    -430.5uV   1.022mV
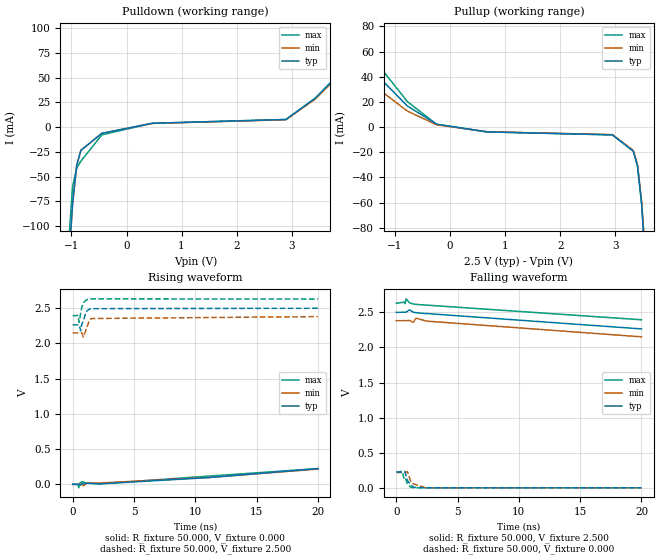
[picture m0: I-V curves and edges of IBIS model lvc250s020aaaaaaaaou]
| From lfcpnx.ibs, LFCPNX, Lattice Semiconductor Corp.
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[Model] lvc250s020aaaaaaaaou
Model_type Output
Polarity   Non-Inverting
Enable   Active-High
Vmeas =  1.250V
Cref =  0.0F
Rref =  1.000M
Vref =  0.0V
C_comp   5.000pF   4.000pF   5.500pF
[Temperature Range]   25.000   0.125k   -40.000
[Voltage Range]   2.500V   2.380V   2.630V
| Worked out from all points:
|   slope of the pulldown table from 0 to 0.375 V, typ, clamps not added: 111 ohm
|   slope of the pullup table from 0 to 0.375 V, typ, clamps not added: 145 ohm
|   rising waveform, R_fixture 50.000, V_fixture 0.000: 20-80 % time 10.8ns typ, 11.3ns min, 10.3ns max; typ from 0 V to 0.224 V
|   rising waveform, R_fixture 50.000, V_fixture 2.500: 20-80 % time 254ps typ, 308ps min, 222ps max; typ from 2.26 V to 2.5 V
|   falling waveform, R_fixture 50.000, V_fixture 2.500: 20-80 % time 10.7ns typ, 10.2ns min, 11.5ns max; typ from 2.5 V to 2.26 V
|   falling waveform, R_fixture 50.000, V_fixture 0.000: 20-80 % time 379ps typ, 499ps min, 353ps max; typ from 0.224 V to 0 V
[Pulldown]
|Voltage   I(typ)   I(min)   I(max)
-2.5V     -1.982A    -1.982A    -2.608A
-1.056V   -142.3mA   -142.3mA   -120.9mA
-980mV    -77.62mA   -77.62mA   -60.04mA
-904mV    -38.32mA   -38.32mA   -41.27mA
-828mV    -23.46mA   -23.46mA   -34.29mA
-448mV    -6.335mA   -6.335mA   -7.822mA
464mV     3.803mA    3.689mA    3.803mA
2.896V    7.658mA    7.428mA    7.658mA
3.428V    29.11mA    28.24mA    29.11mA
4.568V    93.6mA     90.8mA     93.6mA
4.796V    101.5mA    98.5mA     101.5mA
5V        105.2mA    102mA      105.2mA
[Pullup]
|Voltage   I(typ)   I(min)   I(max)
-2.5V     80.2mA     62.08mA    100mA
-2.22V    77mA       58.13mA    96mA
-1.84V    64.02mA    48.16mA    79mA
-776mV    16.78mA    12.7mA     20.26mA
-244mV    2.321mA    1.813mA    2.153mA
668mV     -3.822mA   -3.707mA   -3.822mA
2.948V    -6.19mA    -6.005mA   -6.19mA
3.328V    -19.09mA   -18.52mA   -19.09mA
3.404V    -30.57mA   -29.66mA   -30.57mA
3.48V     -61.09mA   -59.26mA   -61.09mA
3.556V    -111.5mA   -108.2mA   -111.5mA
5V        -1.548A    -1.502A    -1.548A
[Ramp]
| variable   typ   min   max
dV/dt_r   0.134/10.814n   0.130/11.291n   0.133/10.332n
dV/dt_f   0.141/10.704n   0.138/10.193n   0.142/11.462n
R_load = 50.000
[Rising Waveform]
R_fixture = 50.000
V_fixture = 0.000
V_fixture_min = 0.000
V_fixture_max = 0.000
|  time   V(typ)   V(min)   V(max)
0s        57.57uV    -153.7uV   207.6uV
434ps     73.42uV    -388.4uV   2.547mV
487ps     104.5uV    -245.5uV   -49.45mV
587ps     -14.09mV   -129.5uV   18.31mV
735ps     3.713mV    835.5uV    36.54mV
845ps     10.74mV    -19.15mV   33.77mV
1.154ns   15.81mV    16.53mV    17.9mV
2.188ns   6.472mV    19.36mV    7.793mV
11.11ns   96.83mV    97.69mV    117.3mV
20ns      223.6mV    216.8mV    223.7mV
[Rising Waveform]
R_fixture = 50.000
V_fixture = 2.500
V_fixture_min = 2.380
V_fixture_max = 2.630
|  time   V(typ)   V(min)   V(max)
0s        2.264V     2.151V     2.394V
425ps     2.264V     2.151V     2.397V
515ps     2.264V     2.151V     2.3V
648ps     2.181V     2.151V     2.422V
733ps     2.268V     2.153V     2.506V
868ps     2.323V     2.092V     2.577V
1.096ns   2.451V     2.199V     2.617V
1.325ns   2.485V     2.312V     2.63V
1.505ns   2.494V     2.354V     2.633V
20ns      2.5V       2.381V     2.63V
[Falling Waveform]
R_fixture = 50.000
V_fixture = 2.500
V_fixture_min = 2.380
V_fixture_max = 2.630
|  time   V(typ)   V(min)   V(max)
0s        2.5V       2.381V     2.63V
675ps     2.502V     2.381V     2.645V
714ps     2.503V     2.381V     2.623V
804ps     2.503V     2.381V     2.692V
1.085ns   2.536V     2.385V     2.635V
1.382ns   2.502V     2.356V     2.619V
1.592ns   2.495V     2.414V     2.614V
1.709ns   2.492V     2.413V     2.612V
2.462ns   2.483V     2.375V     2.603V
20ns      2.264V     2.151V     2.394V
[Falling Waveform]
R_fixture = 50.000
V_fixture = 0.000
V_fixture_min = 0.000
V_fixture_max = 0.000
|  time   V(typ)   V(min)   V(max)
0s        223.6mV    216.8mV    223.7mV
487ps     223mV      216.7mV    234.4mV
647ps     235.2mV    216.5mV    123mV
698ps     231.9mV    216.7mV    132.2mV
757ps     200.7mV    218.9mV    136.9mV
904ps     103.5mV    231.1mV    52.64mV
1.194ns   37.52mV    85.49mV    6.42mV
1.435ns   7.762mV    52.39mV    99.88uV
2.424ns   -693.6uV   -853.7uV   -1.074mV
20ns      57.57uV    -153.7uV   207.6uV
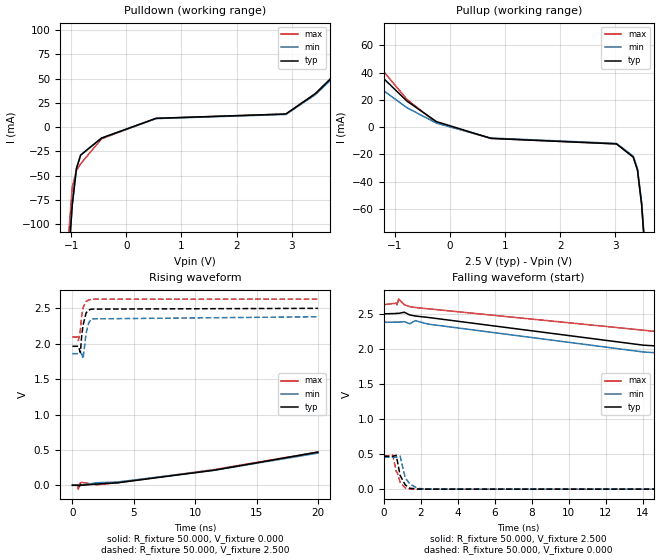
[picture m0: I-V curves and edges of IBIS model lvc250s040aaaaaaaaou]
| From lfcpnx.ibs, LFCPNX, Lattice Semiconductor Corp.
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[Model] lvc250s040aaaaaaaaou
Model_type Output
Polarity   Non-Inverting
Enable   Active-High
Vmeas =  1.250V
Cref =  0.0F
Rref =  1.000M
Vref =  0.0V
C_comp   5.000pF   4.000pF   5.500pF
[Temperature Range]   25.000   0.125k   -40.000
[Voltage Range]   2.500V   2.380V   2.630V
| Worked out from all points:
|   slope of the pulldown table from 0 to 0.375 V, typ, clamps not added: 50.7 ohm
|   slope of the pullup table from 0 to 0.375 V, typ, clamps not added: 73.2 ohm
|   rising waveform, R_fixture 50.000, V_fixture 0.000: 20-80 % time 10.1ns typ, 10.7ns min, 11.1ns max; typ from 0 V to 0.469 V
|   rising waveform, R_fixture 50.000, V_fixture 2.500: 20-80 % time 282ps typ, 328ps min, 237ps max; typ from 1.96 V to 2.5 V
|   falling waveform, R_fixture 50.000, V_fixture 2.500: 20-80 % time 9.19ns typ, 8.71ns min, 11.8ns max; typ from 2.5 V to 1.96 V
|   falling waveform, R_fixture 50.000, V_fixture 0.000: 20-80 % time 337ps typ, 365ps min, 312ps max; typ from 0.469 V to 0 V
[Pulldown]
|Voltage   I(typ)   I(min)   I(max)
-2.5V     -1.943A    -1.943A    -2.512A
-1.056V   -142.2mA   -142.2mA   -118.9mA
-980mV    -79.77mA   -79.77mA   -61.74mA
-904mV    -42.57mA   -42.57mA   -44.46mA
-828mV    -28.79mA   -28.79mA   -37.81mA
-448mV    -11.24mA   -11.24mA   -11.97mA
540mV     9.079mA    8.807mA    9.079mA
2.896V    13.53mA    13.13mA    13.53mA
3.428V    34.44mA    33.41mA    34.44mA
4.568V    97.6mA     94.7mA     97.6mA
4.72V     103.4mA    100.3mA    103.4mA
5V        109.2mA    105.9mA    109.2mA
[Pullup]
|Voltage   I(typ)   I(min)   I(max)
-2.5V     71.9mA     56.02mA    88.3mA
-2.22V    70.9mA     53.6mA     85.9mA
-1.84V    60.7mA     45.63mA    71.6mA
-776mV    18.99mA    14.17mA    20.23mA
-244mV    4.085mA    2.973mA    3.283mA
744mV     -8.244mA   -7.997mA   -8.244mA
3.024V    -12.3mA    -11.93mA   -12.3mA
3.328V    -21.97mA   -21.31mA   -21.97mA
3.404V    -31.26mA   -30.33mA   -31.26mA
3.48V     -56.72mA   -55.02mA   -56.72mA
3.556V    -99.9mA    -96.9mA    -99.9mA
5V        -1.353A    -1.312A    -1.353A
[Ramp]
| variable   typ   min   max
dV/dt_r   0.281/10.134n   0.273/10.740n   0.282/11.110n
dV/dt_f   0.322/9.225n   0.313/8.722n   0.322/11.833n
R_load = 50.000
[Rising Waveform]
R_fixture = 50.000
V_fixture = 0.000
V_fixture_min = 0.000
V_fixture_max = 0.000
|  time   V(typ)   V(min)   V(max)
0s        58.25uV    -361.3uV   101.6uV
434ps     122.2uV    -669.5uV   2.773mV
478ps     175.7uV    -463.6uV   -54.92mV
588ps     -12.25mV   -288.5uV   24.52mV
659ps     11.89mV    -207uV     32.6mV
754ps     -315.5uV   312.1uV    40.88mV
1.987ns   17.8mV     35.89mV    7.157mV
3.664ns   34.85mV    46.23mV    36.21mV
11.55ns   212.5mV    213mV      221.9mV
20ns      468.9mV    454.4mV    469.3mV
[Rising Waveform]
R_fixture = 50.000
V_fixture = 2.500
V_fixture_min = 2.380
V_fixture_max = 2.630
|  time   V(typ)   V(min)   V(max)
0s        1.964V     1.86V      2.094V
425ps     1.964V     1.859V     2.096V
487ps     1.964V     1.86V      2.045V
648ps     1.876V     1.86V      2.192V
751ps     2.104V     1.862V     2.391V
869ps     2.264V     1.788V     2.511V
1.112ns   2.435V     2.144V     2.597V
1.323ns   2.476V     2.291V     2.619V
1.539ns   2.489V     2.351V     2.629V
20ns      2.5V       2.381V     2.631V
[Falling Waveform]
R_fixture = 50.000
V_fixture = 2.500
V_fixture_min = 2.380
V_fixture_max = 2.630
|  time   V(typ)   V(min)   V(max)
0s        2.5V       2.381V     2.631V
677ps     2.505V     2.382V     2.653V
717ps     2.508V     2.382V     2.626V
807ps     2.507V     2.382V     2.711V
1.116ns   2.523V     2.389V     2.629V
1.399ns   2.485V     2.358V     2.604V
1.709ns   2.469V     2.403V     2.59V
2.369ns   2.45V      2.355V     2.573V
14.03ns   2.053V     1.956V     2.267V
20ns      1.964V     1.86V      2.094V
[Falling Waveform]
R_fixture = 50.000
V_fixture = 0.000
V_fixture_min = 0.000
V_fixture_max = 0.000
|  time   V(typ)   V(min)   V(max)
0s        468.9mV    454.4mV    469.3mV
487ps     468.2mV    454.3mV    485.8mV
672ps     482.5mV    454.1mV    256.7mV
747ps     386.4mV    457.4mV    227.3mV
884ps     197mV      472.9mV    101mV
1.161ns   61.28mV    160.6mV    15.58mV
1.404ns   12.6mV     74.71mV    2.21mV
1.824ns   715.5uV    10.12mV    -922.1uV
2.364ns   -288.5uV   -189.5uV   -880.7uV
20ns      58.25uV    -361.3uV   101.6uV
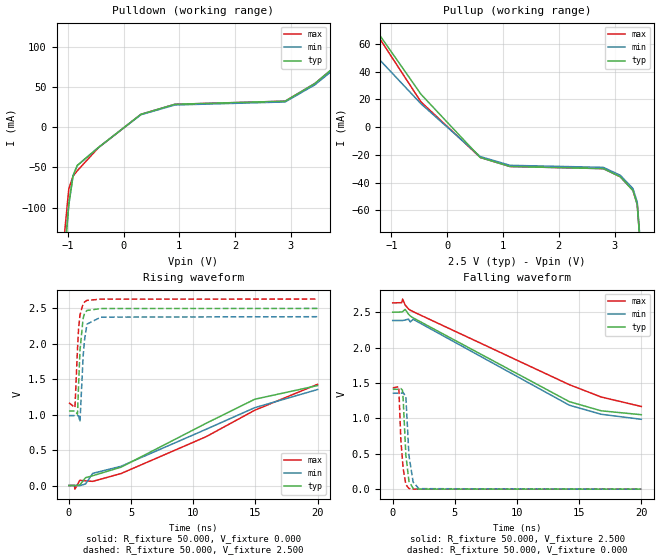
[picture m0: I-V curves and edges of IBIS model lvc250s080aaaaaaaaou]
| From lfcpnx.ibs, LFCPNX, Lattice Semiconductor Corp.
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[Model] lvc250s080aaaaaaaaou
Model_type Output
Polarity   Non-Inverting
Enable   Active-High
Vmeas =  1.250V
Cref =  0.0F
Rref =  1.000M
Vref =  0.0V
C_comp   5.000pF   4.000pF   5.500pF
[Temperature Range]   25.000   0.125k   -40.000
[Voltage Range]   2.500V   2.380V   2.630V
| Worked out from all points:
|   slope of the pulldown table from 0 to 0.375 V, typ, clamps not added: 20.3 ohm
|   slope of the pullup table from 0 to 0.375 V, typ, clamps not added: 24.5 ohm
|   rising waveform, R_fixture 50.000, V_fixture 0.000: 20-80 % time 9.28ns typ, 10.6ns min, 10ns max; typ from 0 V to 1.41 V
|   rising waveform, R_fixture 50.000, V_fixture 2.500: 20-80 % time 263ps typ, 298ps min, 275ps max; typ from 1.05 V to 2.5 V
|   falling waveform, R_fixture 50.000, V_fixture 2.500: 20-80 % time 8.81ns typ, 8.29ns min, 10.6ns max; typ from 2.5 V to 1.05 V
|   falling waveform, R_fixture 50.000, V_fixture 0.000: 20-80 % time 281ps typ, 298ps min, 288ps max; typ from 1.41 V to 0 V
[Pulldown]
|Voltage   I(typ)   I(min)   I(max)
-2.5V     -2.07A     -2.07A     -2.62A
-1.056V   -159.5mA   -159.5mA   -132.1mA
-980mV    -96.2mA    -96.2mA    -76.81mA
-904mV    -60.38mA   -60.38mA   -61.04mA
-828mV    -47.63mA   -47.63mA   -54.22mA
-448mV    -25.25mA   -25.25mA   -25.53mA
312mV     15.95mA    15.47mA    15.95mA
920mV     28.42mA    27.56mA    28.42mA
2.896V    32.3mA     31.33mA    32.3mA
3.428V    54.23mA    52.6mA     54.23mA
4.644V    124.9mA    121.2mA    124.9mA
5V        134mA      130mA      134mA
[Pullup]
|Voltage   I(typ)   I(min)   I(max)
-2.5V     105.7mA    79.6mA     120.1mA
-1.992V   103.8mA    77.3mA     110.7mA
-1.536V   85mA       62.39mA    83.9mA
-472mV    23.75mA    16.9mA     18.26mA
592mV     -21.87mA   -21.22mA   -21.87mA
1.124V    -28.36mA   -27.51mA   -28.36mA
2.796V    -29.88mA   -28.99mA   -29.88mA
3.1V      -35.75mA   -34.68mA   -35.75mA
3.328V    -45.66mA   -44.29mA   -45.66mA
3.404V    -55.72mA   -54.05mA   -55.72mA
3.556V    -138.2mA   -134.1mA   -138.2mA
5V        -1.766A    -1.713A    -1.766A
[Ramp]
| variable   typ   min   max
dV/dt_r   0.847/9.273n   0.813/10.559n   0.857/10.016n
dV/dt_f   0.868/8.811n   0.837/8.301n   0.878/10.585n
R_load = 50.000
[Rising Waveform]
R_fixture = 50.000
V_fixture = 0.000
V_fixture_min = 0.000
V_fixture_max = 0.000
|  time   V(typ)   V(min)   V(max)
0s        64.19uV    -418.3uV   347.1uV
436ps     151.5uV    -603.6uV   2.676mV
479ps     187.8uV    -424.7uV   -51.51mV
874ps     8.061mV    -2.062mV   74.2mV
1.334ns   110.4mV    21.76mV    65.41mV
1.914ns   138.3mV    171.9mV    58.59mV
4.194ns   259.4mV    271.6mV    169.3mV
11.03ns   877.9mV    793.5mV    688.8mV
14.95ns   1.218V     1.099V     1.063V
20ns      1.411V     1.355V     1.429V
[Rising Waveform]
R_fixture = 50.000
V_fixture = 2.500
V_fixture_min = 2.380
V_fixture_max = 2.630
|  time   V(typ)   V(min)   V(max)
0s        1.052V     986.9mV    1.168V
483ps     1.052V     986.7mV    1.101V
688ps     1.007V     987.1mV    1.935V
777ps     1.435V     984.2mV    2.221V
887ps     1.908V     899.4mV    2.408V
1.139ns   2.36V      1.82V      2.565V
1.257ns   2.433V     2.059V     2.591V
1.447ns   2.471V     2.278V     2.613V
2.567ns   2.498V     2.377V     2.631V
20ns      2.5V       2.383V     2.632V
[Falling Waveform]
R_fixture = 50.000
V_fixture = 2.500
V_fixture_min = 2.380
V_fixture_max = 2.630
|  time   V(typ)   V(min)   V(max)
0s        2.5V       2.383V     2.632V
721ps     2.503V     2.383V     2.635V
800ps     2.509V     2.383V     2.686V
998ps     2.54V      2.39V      2.603V
1.274ns   2.472V     2.403V     2.546V
1.414ns   2.447V     2.362V     2.529V
1.644ns   2.42V      2.4V       2.508V
14.21ns   1.236V     1.186V     1.476V
16.77ns   1.107V     1.058V     1.302V
20ns      1.052V     986.9mV    1.168V
[Falling Waveform]
R_fixture = 50.000
V_fixture = 0.000
V_fixture_min = 0.000
V_fixture_max = 0.000
|  time   V(typ)   V(min)   V(max)
0s        1.411V     1.355V     1.429V
486ps     1.411V     1.355V     1.449V
657ps     1.421V     1.355V     685.4mV
778ps     1.4V       1.358V     428.4mV
838ps     1.285V     1.367V     297.2mV
1.058ns   482.1mV    1.304V     63.92mV
1.308ns   110.5mV    473.6mV    9.182mV
1.644ns   10.41mV    100.6mV    402uV
2.104ns   775.5uV    6.737mV    -244uV
20ns      64.19uV    -418.3uV   347.1uV
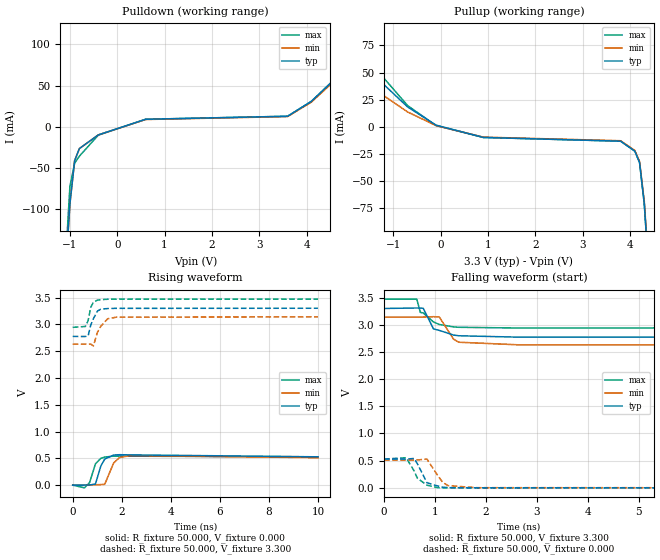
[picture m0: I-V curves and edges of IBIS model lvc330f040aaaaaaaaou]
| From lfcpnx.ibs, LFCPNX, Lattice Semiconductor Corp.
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[Model] lvc330f040aaaaaaaaou
Model_type Output
Polarity   Non-Inverting
Enable   Active-High
Vmeas =  1.650V
Cref =  0.0F
Rref =  1.000M
Vref =  0.0V
C_comp   5.000pF   4.000pF   5.500pF
[Temperature Range]   25.000   0.125k   -40.000
[Voltage Range]   3.300V   3.140V   3.470V
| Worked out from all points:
|   slope of the pulldown table from 0 to 0.495 V, typ, clamps not added: 57.8 ohm
|   slope of the pullup table from 0 to 0.495 V, typ, clamps not added: 74.3 ohm
|   rising waveform, R_fixture 50.000, V_fixture 0.000: 20-80 % time 214ps typ, 246ps min, 234ps max; typ from 0.001 V to 0.529 V
|   rising waveform, R_fixture 50.000, V_fixture 3.300: 20-80 % time 265ps typ, 329ps min, 159ps max; typ from 2.77 V to 3.3 V
|   falling waveform, R_fixture 50.000, V_fixture 3.300: 20-80 % time 297ps typ, 204ps min, 296ps max; typ from 3.3 V to 2.77 V
|   falling waveform, R_fixture 50.000, V_fixture 0.000: 20-80 % time 168ps typ, 215ps min, 246ps max; typ from 0.529 V to 0.001 V
[Pulldown]
|Voltage   I(typ)   I(min)   I(max)
-3.3V     -2.931A    -2.931A    -3.873A
-1.1V     -183.5mA   -183.5mA   -169.9mA
-1V       -93mA      -93mA      -72.14mA
-900mV    -40.86mA   -40.86mA   -43.82mA
-800mV    -26.23mA   -26.23mA   -35.39mA
-400mV    -9.648mA   -9.648mA   -9.919mA
600mV     9.277mA    8.999mA    9.277mA
3.6V      12.93mA    12.54mA    12.93mA
4.1V      30.88mA    29.96mA    30.88mA
5.4V      101.5mA    98.5mA     101.5mA
6.2V      126.1mA    122.3mA    126.1mA
6.6V      170.5mA    165.4mA    170.5mA
[Pullup]
|Voltage   I(typ)   I(min)   I(max)
-3.3V     120.2mA    74.4mA     154.2mA
-3V       94.6mA     66.6mA     129.5mA
-2V       71.5mA     52.35mA    84.9mA
-700mV    18.35mA    13.73mA    19.59mA
-100mV    1.659mA    1.227mA    1.262mA
900mV     -9.672mA   -9.382mA   -9.672mA
3.8V      -13.09mA   -12.7mA    -13.09mA
4.1V      -22.26mA   -21.59mA   -22.26mA
4.2V      -32.68mA   -31.7mA    -32.68mA
4.3V      -70.6mA    -68.5mA    -70.6mA
4.4V      -137.3mA   -133.2mA   -137.3mA
6.6V      -2.177A    -2.111A    -2.177A
[Ramp]
| variable   typ   min   max
dV/dt_r   0.317/0.218n   0.306/0.253n   0.317/0.238n
dV/dt_f   0.316/0.297n   0.296/0.206n   0.316/0.299n
R_load = 50.000
[Rising Waveform]
R_fixture = 50.000
V_fixture = 0.000
V_fixture_min = 0.000
V_fixture_max = 0.000
|  time   V(typ)   V(min)   V(max)
0s        693.3uV    2.025mV    693.3uV
479ps     904uV      1.983mV    -49.98mV
688ps     3.465mV    2.112mV    47.99mV
926ps     21.68mV    7.432mV    397.1mV
1.146ns   357.2mV    10.83mV    499.9mV
1.306ns   486.6mV    17.28mV    524.9mV
1.669ns   562mV      413.3mV    541.4mV
1.906ns   568.4mV    515mV      542.7mV
2.356ns   565.1mV    552.8mV    540.6mV
10ns      528.7mV    512.4mV    529.1mV
[Rising Waveform]
R_fixture = 50.000
V_fixture = 3.300
V_fixture_min = 3.140
V_fixture_max = 3.470
|  time   V(typ)   V(min)   V(max)
0s        2.774V     2.63V      2.944V
517ps     2.773V     2.63V      2.96V
628ps     2.782V     2.63V      3.068V
736ps     2.988V     2.631V     3.316V
846ps     3.107V     2.597V     3.415V
1.006ns   3.246V     2.85V      3.45V
1.146ns   3.283V     2.964V     3.46V
1.426ns   3.295V     3.104V     3.468V
1.776ns   3.298V     3.133V     3.47V
10ns      3.3V       3.14V      3.47V
[Falling Waveform]
R_fixture = 50.000
V_fixture = 3.300
V_fixture_min = 3.140
V_fixture_max = 3.470
|  time   V(typ)   V(min)   V(max)
0s        3.3V       3.14V      3.47V
643ps     3.309V     3.141V     3.472V
713ps     3.308V     3.141V     3.228V
769ps     3.304V     3.142V     3.218V
970ps     2.925V     3.149V     3.052V
1.084ns   2.897V     3.144V     3.006V
1.364ns   2.811V     2.736V     2.961V
1.464ns   2.798V     2.679V     2.954V
2.646ns   2.772V     2.631V     2.94V
10ns      2.774V     2.63V      2.944V
[Falling Waveform]
R_fixture = 50.000
V_fixture = 0.000
V_fixture_min = 0.000
V_fixture_max = 0.000
|  time   V(typ)   V(min)   V(max)
0s        528.7mV    512.4mV    529.1mV
434ps     528.2mV    511.8mV    553.5mV
592ps     540.5mV    511.6mV    310.2mV
654ps     444.7mV    512.8mV    176.9mV
842ps     93.92mV    528.7mV    48.96mV
1.045ns   35.94mV    238.6mV    4.025mV
1.152ns   12.07mV    99.77mV    769.3uV
1.256ns   3.956mV    40.14mV    -275.9uV
1.826ns   139.5uV    2.479mV    -755.3uV
10ns      693.3uV    2.025mV    693.3uV
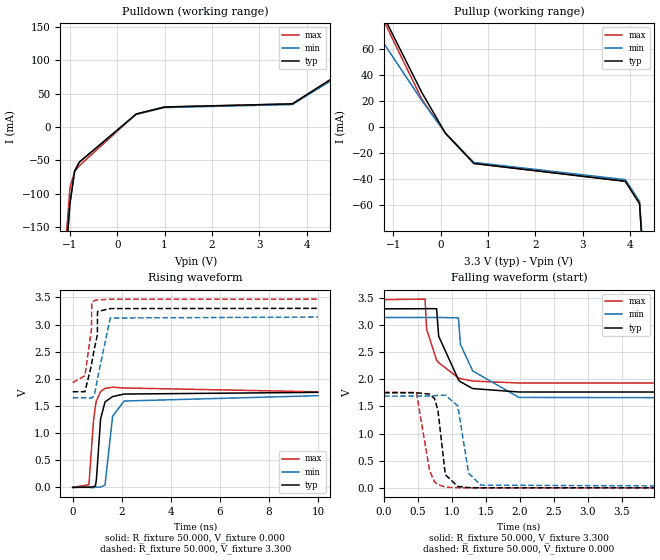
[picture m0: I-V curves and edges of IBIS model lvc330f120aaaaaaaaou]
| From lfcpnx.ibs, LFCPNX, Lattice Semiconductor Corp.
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[Model] lvc330f120aaaaaaaaou
Model_type Output
Polarity   Non-Inverting
Enable   Active-High
Vmeas =  1.650V
Cref =  0.0F
Rref =  1.000M
Vref =  0.0V
C_comp   5.000pF   4.000pF   5.500pF
[Temperature Range]   25.000   0.125k   -40.000
[Voltage Range]   3.300V   3.140V   3.470V
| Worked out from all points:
|   slope of the pulldown table from 0 to 0.495 V, typ, clamps not added: 22 ohm
|   slope of the pullup table from 0 to 0.495 V, typ, clamps not added: 22.6 ohm
|   rising waveform, R_fixture 50.000, V_fixture 0.000: 20-80 % time 189ps typ, 251ps min, 174ps max; typ from 0 V to 1.75 V
|   rising waveform, R_fixture 50.000, V_fixture 3.300: 20-80 % time 290ps typ, 396ps min, 220ps max; typ from 1.76 V to 3.3 V
|   falling waveform, R_fixture 50.000, V_fixture 3.300: 20-80 % time 234ps typ, 281ps min, 222ps max; typ from 3.3 V to 1.76 V
|   falling waveform, R_fixture 50.000, V_fixture 0.000: 20-80 % time 90.5ps typ, 118ps min, 122ps max; typ from 1.75 V to 0 V
[Pulldown]
|Voltage   I(typ)   I(min)   I(max)
-3.3V     -3.149A    -3.149A    -4.032A
-1.1V     -207.3mA   -207.3mA   -186.1mA
-1V       -114.9mA   -114.9mA   -91.33mA
-900mV    -65.88mA   -65.88mA   -66.67mA
-800mV    -52.62mA   -52.62mA   -57.94mA
400mV     19.3mA     18.72mA    19.3mA
1V        29.84mA    28.94mA    29.84mA
3.7V      34.51mA    33.48mA    34.51mA
5.3V      106.6mA    103.4mA    106.6mA
6.1V      125.5mA    121.7mA    125.5mA
6.4V      149.6mA    145.1mA    149.6mA
6.6V      170.1mA    165mA      170.1mA
[Pullup]
|Voltage   I(typ)   I(min)   I(max)
-3.3V     173.5mA    109mA      220.2mA
-2.9V     127.5mA    95.5mA     173.1mA
-2.6V     115.3mA    89.3mA     137.7mA
-1.8V     115.3mA    88.3mA     125.3mA
-1.5V     106.3mA    80.61mA    103.8mA
-400mV    26.44mA    20.22mA    21.27mA
100mV     -4.967mA   -4.818mA   -4.967mA
700mV     -28.11mA   -27.27mA   -28.11mA
3.9V      -41.84mA   -40.58mA   -41.84mA
4.2V      -59.09mA   -57.32mA   -59.09mA
4.4V      -170.2mA   -165.1mA   -170.2mA
6.6V      -2.549A    -2.472A    -2.549A
[Ramp]
| variable   typ   min   max
dV/dt_r   1.051/0.188n   1.042/0.252n   1.057/0.173n
dV/dt_f   0.922/0.258n   0.894/0.280n   0.905/0.268n
R_load = 50.000
[Rising Waveform]
R_fixture = 50.000
V_fixture = 0.000
V_fixture_min = 0.000
V_fixture_max = 0.000
|  time   V(typ)   V(min)   V(max)
0s        336.5uV    1.162mV    390.3uV
661ps     6.761mV    1.318mV    51.1mV
839ps     10.17mV    -7.738mV   1.181V
925ps     28.57mV    8.978mV    1.506V
965ps     137.8mV    4.899mV    1.594V
1.136ns   1.258V     5.912mV    1.768V
1.318ns   1.577V     43.46mV    1.825V
1.627ns   1.674V     1.31V      1.847V
2.095ns   1.721V     1.592V     1.833V
10ns      1.752V     1.691V     1.762V
[Rising Waveform]
R_fixture = 50.000
V_fixture = 3.300
V_fixture_min = 3.140
V_fixture_max = 3.470
|  time   V(typ)   V(min)   V(max)
0s        1.764V     1.651V     1.933V
498ps     1.764V     1.651V     2.059V
766ps     2.256V     1.647V     2.923V
776ps     2.292V     1.645V     3.398V
886ps     2.566V     1.709V     3.444V
1.006ns   2.809V     1.983V     3.455V
1.011ns   3.23V      1.998V     3.455V
1.021ns   3.242V     2.03V      3.456V
1.531ns   3.296V     3.122V     3.468V
10ns      3.3V       3.14V      3.47V
[Falling Waveform]
R_fixture = 50.000
V_fixture = 3.300
V_fixture_min = 3.140
V_fixture_max = 3.470
|  time   V(typ)   V(min)   V(max)
0s        3.3V       3.14V      3.47V
604ps     3.302V     3.141V     3.479V
628ps     3.304V     3.141V     2.922V
774ps     3.302V     3.14V      2.354V
805ps     2.795V     3.141V     2.308V
1.096ns   1.993V     3.134V     2.026V
1.125ns   1.956V     2.647V     2.015V
1.306ns   1.83V      2.155V     1.969V
1.986ns   1.767V     1.667V     1.933V
10ns      1.764V     1.651V     1.933V
[Falling Waveform]
R_fixture = 50.000
V_fixture = 0.000
V_fixture_min = 0.000
V_fixture_max = 0.000
|  time   V(typ)   V(min)   V(max)
0s        1.752V     1.691V     1.762V
477ps     1.753V     1.692V     1.759V
672ps     1.728V     1.692V     311.6mV
744ps     1.645V     1.698V     111.7mV
794ps     1.429V     1.706V     61.59mV
903ps     243.6mV    1.71V      12.64mV
1.086ns   25.89mV    1.512V     1.582mV
1.246ns   5mV        268mV      383.2uV
1.426ns   1.516mV    50.2mV     -67.51uV
10ns      336.5uV    1.162mV    390.3uV
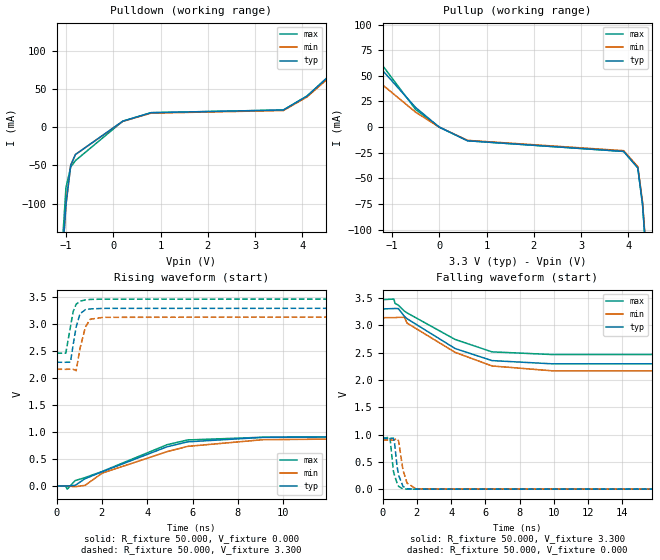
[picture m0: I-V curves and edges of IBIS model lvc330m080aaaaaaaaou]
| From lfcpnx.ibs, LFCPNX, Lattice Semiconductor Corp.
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|Model lvc330m080aaaaaaaaou
[Model] lvc330m080aaaaaaaaou
Model_type Output
Polarity   Non-Inverting
Enable   Active-High
Vmeas =  1.650V
Cref =  0.0F
Rref =  1.000M
Vref =  0.0V
C_comp   5.000pF   4.000pF   5.500pF
[Temperature Range]   25.000   0.125k   -40.000
[Voltage Range]   3.300V   3.140V   3.470V
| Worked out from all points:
|   slope of the pulldown table from 0 to 0.495 V, typ, clamps not added: 31.5 ohm
|   slope of the pullup table from 0 to 0.495 V, typ, clamps not added: 43.2 ohm
|   rising waveform, R_fixture 50.000, V_fixture 0.000: 20-80 % time 3.47ns typ, 3.91ns min, 3.27ns max; typ from 0 V to 0.929 V
|   rising waveform, R_fixture 50.000, V_fixture 3.300: 20-80 % time 248ps typ, 295ps min, 236ps max; typ from 2.3 V to 3.3 V
|   falling waveform, R_fixture 50.000, V_fixture 3.300: 20-80 % time 3.22ns typ, 3.2ns min, 3.51ns max; typ from 3.3 V to 2.3 V
|   falling waveform, R_fixture 50.000, V_fixture 0.000: 20-80 % time 273ps typ, 284ps min, 288ps max; typ from 0.929 V to 0 V
[Pulldown]
|Voltage   I(typ)   I(min)   I(max)
-3.3V     -3.025A    -3.025A    -3.918A
-1.1V     -192.9mA   -192.9mA   -175.3mA
-1V       -101.2mA   -101.2mA   -78.95mA
-900mV    -49.86mA   -49.86mA   -52.21mA
-800mV    -35.81mA   -35.81mA   -43.74mA
200mV     7.775mA    7.542mA    7.775mA
800mV     18.91mA    18.34mA    18.91mA
3.6V      22.45mA    21.77mA    22.45mA
4.1V      40.8mA     39.58mA    40.8mA
5.4V      113.7mA    110.3mA    113.7mA
6.1V      131.6mA    127.7mA    131.6mA
6.6V      184.5mA    179mA      184.5mA
[Pullup]
|Voltage   I(typ)   I(min)   I(max)
-3.3V     145.5mA    90.7mA     185.8mA
-2.7V     96.8mA     74.7mA     125.4mA
-2.1V     95.1mA     70.11mA    105.4mA
-1.8V     86.3mA     64.15mA    96.9mA
-500mV    19.13mA    14.57mA    17.21mA
0V        28.62nA    228.6nA    28.62nA
600mV     -13.29mA   -12.89mA   -13.29mA
3.9V      -23.67mA   -22.96mA   -23.67mA
4.2V      -39.73mA   -38.54mA   -39.73mA
4.3V      -75.4mA    -73.1mA    -75.4mA
4.4V      -140.5mA   -136.3mA   -140.5mA
6.6V      -2.178A    -2.113A    -2.178A
[Ramp]
| variable   typ   min   max
dV/dt_r   0.558/3.474n   0.540/3.936n   0.559/3.276n
dV/dt_f   0.602/3.253n   0.584/3.212n   0.602/3.516n
R_load = 50.000
[Rising Waveform]
R_fixture = 50.000
V_fixture = 0.000
V_fixture_min = 0.000
V_fixture_max = 0.000
|  time   V(typ)   V(min)   V(max)
0s        488.9uV    1.198mV    488.9uV
395ps     637.6uV    952.2uV    3.238mV
475ps     718.1uV    1.204mV    -58.62mV
816ps     11.39mV    -13.02mV   99.9mV
1.256ns   135.1mV    11.8mV     155.5mV
2.016ns   265mV      239.2mV    270.5mV
4.885ns   729.4mV    638.7mV    767.7mV
5.78ns    819.5mV    735.4mV    854.8mV
9.109ns   902.9mV    859.8mV    905.4mV
20ns      929.1mV    899.7mV    931mV
[Rising Waveform]
R_fixture = 50.000
V_fixture = 3.300
V_fixture_min = 3.140
V_fixture_max = 3.470
|  time   V(typ)   V(min)   V(max)
0s        2.297V     2.167V     2.467V
409ps     2.297V     2.166V     2.466V
616ps     2.299V     2.168V     2.961V
734ps     2.622V     2.168V     3.237V
866ps     2.953V     2.141V     3.375V
1.036ns   3.197V     2.555V     3.43V
1.276ns   3.274V     2.953V     3.455V
1.486ns   3.287V     3.096V     3.463V
2.077ns   3.297V     3.131V     3.469V
20ns      3.3V       3.14V      3.47V
[Falling Waveform]
R_fixture = 50.000
V_fixture = 3.300
V_fixture_min = 3.140
V_fixture_max = 3.470
|  time   V(typ)   V(min)   V(max)
0s        3.3V       3.14V      3.47V
666ps     3.307V     3.141V     3.481V
726ps     3.309V     3.14V      3.403V
924ps     3.306V     3.147V     3.369V
1.275ns   3.165V     3.146V     3.261V
1.436ns   3.12V      3.04V      3.227V
4.236ns   2.575V     2.505V     2.741V
6.39ns    2.354V     2.256V     2.514V
9.897ns   2.295V     2.167V     2.465V
20ns      2.297V     2.167V     2.467V
[Falling Waveform]
R_fixture = 50.000
V_fixture = 0.000
V_fixture_min = 0.000
V_fixture_max = 0.000
|  time   V(typ)   V(min)   V(max)
0s        929.1mV    899.7mV    931mV
432ps     928.7mV    899.2mV    951mV
635ps     935.9mV    899.2mV    328.3mV
704ps     834.8mV    904.4mV    247.5mV
846ps     423.4mV    926.9mV    115mV
936ps     256.3mV    884.1mV    51.1mV
1.193ns   51.59mV    350.2mV    4.707mV
1.432ns   6.847mV    110.5mV    217.4uV
1.966ns   398.9uV    3.886mV    -527.1uV
20ns      488.9uV    1.198mV    488.9uV
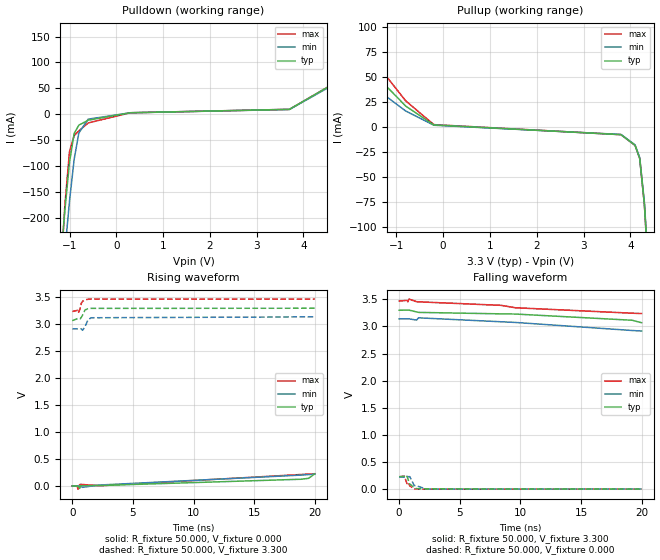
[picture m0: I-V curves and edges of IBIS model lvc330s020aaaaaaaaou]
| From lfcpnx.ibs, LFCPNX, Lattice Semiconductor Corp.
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|Model lvc330s020aaaaaaaaou
[Model] lvc330s020aaaaaaaaou
Model_type Output
Polarity   Non-Inverting
Enable   Active-High
Vmeas =  1.650V
Cref =  0.0F
Rref =  1.000M
Vref =  0.0V
C_comp   5.000pF   4.000pF   5.500pF
[Temperature Range]   25.000   0.125k   -40.000
[Voltage Range]   3.300V   3.140V   3.470V
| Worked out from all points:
|   slope of the pulldown table from 0 to 0.495 V, typ, clamps not added: 128 ohm
|   slope of the pullup table from 0 to 0.495 V, typ, clamps not added: 158 ohm
|   rising waveform, R_fixture 50.000, V_fixture 0.000: 20-80 % time 12.3ns typ, 11.2ns min, 10.8ns max; typ from 0.001 V to 0.227 V
|   rising waveform, R_fixture 50.000, V_fixture 3.300: 20-80 % time 308ps typ, 269ps min, 201ps max; typ from 3.07 V to 3.3 V
|   falling waveform, R_fixture 50.000, V_fixture 3.300: 20-80 % time 16.5ns typ, 9.07ns min, 10.1ns max; typ from 3.3 V to 3.07 V
|   falling waveform, R_fixture 50.000, V_fixture 0.000: 20-80 % time 433ps typ, 586ps min, 391ps max; typ from 0.227 V to 0.001 V
[Pulldown]
|Voltage   I(typ)   I(min)   I(max)
-3.3V     -3.023A    -2.882A    -4.076A
-1.2V     -299.4mA   -373.4mA   -326mA
-1.1V     -186.9mA   -266.3mA   -176.8mA
-1V       -92.5mA    -167.9mA   -72.23mA
-900mV    -37.01mA   -86.9mA    -41.16mA
-800mV    -21.11mA   -36.05mA   -32.24mA
-600mV    -11.54mA   -9.523mA   -16.85mA
300mV     2.818mA    2.733mA    2.818mA
3.7V      9.422mA    9.139mA    9.422mA
5.3V      93.3mA     90.5mA     93.3mA
6.1V      115.6mA    112.2mA    115.6mA
6.6V      168.3mA    163.3mA    168.3mA
[Pullup]
|Voltage   I(typ)   I(min)   I(max)
-3.3V     139.8mA    86.3mA     180mA
-2.9V     101.3mA    74.5mA     141.2mA
-2.7V     91.2mA     69.71mA    121.2mA
-2V       78.6mA     57.94mA    97.4mA
-800mV    21.01mA    16.14mA    26.23mA
-200mV    2.224mA    1.901mA    2.518mA
3.8V      -7.525mA   -7.299mA   -7.525mA
4.1V      -18.2mA    -17.66mA   -18.2mA
4.2V      -31.31mA   -30.37mA   -31.31mA
4.3V      -77.3mA    -75mA      -77.3mA
4.4V      -155.6mA   -151mA     -155.6mA
6.6V      -2.513A    -2.438A    -2.513A
[Ramp]
| variable   typ   min   max
dV/dt_r   0.136/10.320n   0.131/11.213n   0.136/10.796n
dV/dt_f   0.138/10.696n   0.134/10.128n   0.139/11.426n
R_load = 50.000
[Rising Waveform]
R_fixture = 50.000
V_fixture = 0.000
V_fixture_min = 0.000
V_fixture_max = 0.000
|  time   V(typ)   V(min)   V(max)
0s        978.4uV    2.777mV    974.6uV
395ps     1.028mV    2.399mV    3.382mV
474ps     1.15mV     2.686mV    -57.42mV
605ps     -43.88mV   2.886mV    25.48mV
693ps     6.116mV    2.778mV    33.22mV
823ps     10.02mV    -23.42mV   29.09mV
2.297ns   10.54mV    19.74mV    6.25mV
18.86ns   126.7mV    203.9mV    214.4mV
19.5ns    143.8mV    213.2mV    222.6mV
20ns      227.4mV    220.6mV    227.5mV
[Rising Waveform]
R_fixture = 50.000
V_fixture = 3.300
V_fixture_min = 3.140
V_fixture_max = 3.470
|  time   V(typ)   V(min)   V(max)
0s        3.069V     2.916V     3.239V
438ps     3.108V     2.916V     3.261V
507ps     3.108V     2.917V     3.215V
631ps     3.1V       2.917V     3.282V
743ps     3.13V      2.917V     3.391V
852ps     3.173V     2.891V     3.428V
1.051ns   3.268V     2.957V     3.454V
1.292ns   3.29V      3.082V     3.466V
1.547ns   3.297V     3.123V     3.47V
20ns      3.3V       3.14V      3.47V
[Falling Waveform]
R_fixture = 50.000
V_fixture = 3.300
V_fixture_min = 3.140
V_fixture_max = 3.470
|  time   V(typ)   V(min)   V(max)
0s        3.3V       3.14V      3.47V
671ps     3.302V     3.141V     3.481V
721ps     3.302V     3.141V     3.455V
802ps     3.303V     3.142V     3.506V
1.429ns   3.269V     3.118V     3.458V
1.599ns   3.26V      3.16V      3.455V
8.417ns   3.233V     3.087V     3.39V
9.565ns   3.23V      3.075V     3.346V
19.23ns   3.115V     2.926V     3.245V
20ns      3.069V     2.916V     3.239V
[Falling Waveform]
R_fixture = 50.000
V_fixture = 0.000
V_fixture_min = 0.000
V_fixture_max = 0.000
|  time   V(typ)   V(min)   V(max)
0s        227.4mV    220.6mV    227.5mV
433ps     237.8mV    220.3mV    239.4mV
577ps     258.5mV    220.1mV    143.9mV
649ps     236.1mV    220.4mV    100.8mV
759ps     163.2mV    229.7mV    125.5mV
877ps     93.8mV     229.8mV    61.15mV
1.239ns   28.69mV    66.64mV    4.887mV
1.421ns   8.792mV    62.65mV    766.3uV
2.261ns   5.129mV    823.2uV    -880.9uV
20ns      978.4uV    2.777mV    974.6uV
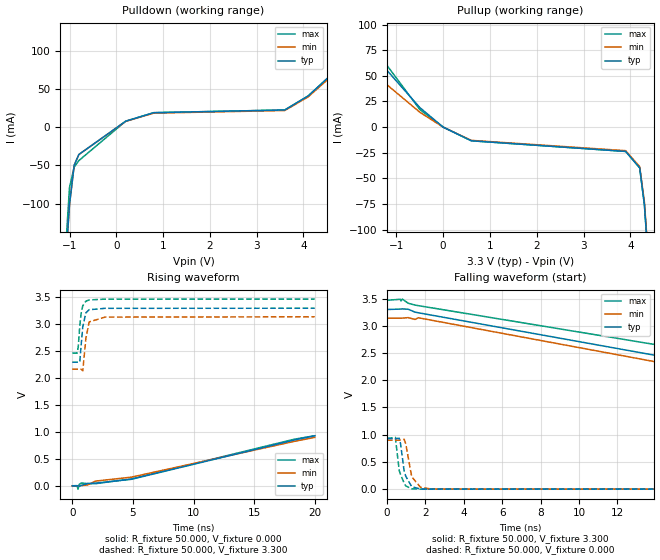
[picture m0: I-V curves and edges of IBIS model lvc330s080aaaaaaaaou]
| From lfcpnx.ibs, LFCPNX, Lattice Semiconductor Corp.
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[Model] lvc330s080aaaaaaaaou
Model_type Output
Polarity   Non-Inverting
Enable   Active-High
Vmeas =  1.650V
Cref =  0.0F
Rref =  1.000M
Vref =  0.0V
C_comp   5.000pF   4.000pF   5.500pF
[Temperature Range]   25.000   0.125k   -40.000
[Voltage Range]   3.300V   3.140V   3.470V
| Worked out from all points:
|   slope of the pulldown table from 0 to 0.495 V, typ, clamps not added: 31.5 ohm
|   slope of the pullup table from 0 to 0.495 V, typ, clamps not added: 43.2 ohm
|   rising waveform, R_fixture 50.000, V_fixture 0.000: 20-80 % time 10.1ns typ, 10.8ns min, 10.1ns max; typ from 0 V to 0.929 V
|   rising waveform, R_fixture 50.000, V_fixture 3.300: 20-80 % time 265ps typ, 295ps min, 259ps max; typ from 2.3 V to 3.3 V
|   falling waveform, R_fixture 50.000, V_fixture 3.300: 20-80 % time 9.12ns typ, 8.53ns min, 10.2ns max; typ from 3.3 V to 2.3 V
|   falling waveform, R_fixture 50.000, V_fixture 0.000: 20-80 % time 306ps typ, 322ps min, 315ps max; typ from 0.929 V to 0 V
[Pulldown]
|Voltage   I(typ)   I(min)   I(max)
-3.3V     -3.025A    -3.025A    -3.918A
-1.1V     -192.9mA   -192.9mA   -175.3mA
-1V       -101.2mA   -101.2mA   -78.95mA
-900mV    -49.86mA   -49.86mA   -52.21mA
-800mV    -35.81mA   -35.81mA   -43.74mA
200mV     7.775mA    7.542mA    7.775mA
800mV     18.91mA    18.34mA    18.91mA
3.6V      22.45mA    21.77mA    22.45mA
4.1V      40.8mA     39.58mA    40.8mA
5.4V      113.7mA    110.3mA    113.7mA
6.1V      131.6mA    127.7mA    131.6mA
6.6V      184.5mA    179mA      184.5mA
[Pullup]
|Voltage   I(typ)   I(min)   I(max)
-3.3V     145.5mA    90.7mA     185.8mA
-2.7V     96.8mA     74.7mA     125.4mA
-2.1V     95.1mA     70.11mA    105.4mA
-1.8V     86.3mA     64.15mA    96.9mA
-500mV    19.13mA    14.57mA    17.21mA
0V        28.62nA    228.6nA    28.62nA
600mV     -13.29mA   -12.89mA   -13.29mA
3.9V      -23.67mA   -22.96mA   -23.67mA
4.2V      -39.73mA   -38.54mA   -39.73mA
4.3V      -75.4mA    -73.1mA    -75.4mA
4.4V      -140.5mA   -136.3mA   -140.5mA
6.6V      -2.178A    -2.113A    -2.178A
[Ramp]
| variable   typ   min   max
dV/dt_r   0.558/10.154n   0.540/10.738n   0.559/10.105n
dV/dt_f   0.602/9.145n   0.584/8.567n   0.602/10.251n
R_load = 50.000
[Rising Waveform]
R_fixture = 50.000
V_fixture = 0.000
V_fixture_min = 0.000
V_fixture_max = 0.000
|  time   V(typ)   V(min)   V(max)
0s        488.9uV    1.198mV    488.9uV
395ps     658.9uV    831.3uV    3.42mV
476ps     748.1uV    1.21mV     -62.3mV
567ps     -8.091mV   1.352mV    25.37mV
756ps     7.909mV    3.31mV     52.67mV
1.276ns   44.04mV    15.94mV    39.37mV
1.915ns   50.23mV    87.65mV    39.47mV
4.871ns   120.6mV    160.8mV    128.3mV
18.34ns   852.8mV    827.3mV    867.3mV
20ns      929.1mV    899.7mV    931mV
[Rising Waveform]
R_fixture = 50.000
V_fixture = 3.300
V_fixture_min = 3.140
V_fixture_max = 3.470
|  time   V(typ)   V(min)   V(max)
0s        2.297V     2.167V     2.467V
409ps     2.297V     2.166V     2.466V
495ps     2.298V     2.167V     2.59V
617ps     2.297V     2.168V     2.964V
732ps     2.615V     2.168V     3.208V
866ps     2.954V     2.137V     3.345V
1.122ns   3.215V     2.737V     3.43V
1.393ns   3.272V     3.045V     3.454V
2.705ns   3.298V     3.135V     3.469V
20ns      3.3V       3.14V      3.47V
[Falling Waveform]
R_fixture = 50.000
V_fixture = 3.300
V_fixture_min = 3.140
V_fixture_max = 3.470
|  time   V(typ)   V(min)   V(max)
0s        3.3V       3.14V      3.47V
688ps     3.308V     3.14V      3.488V
728ps     3.309V     3.14V      3.458V
798ps     3.311V     3.142V     3.492V
1.104ns   3.305V     3.151V     3.415V
1.456ns   3.252V     3.118V     3.382V
1.635ns   3.24V      3.148V     3.371V
14.38ns   2.432V     2.313V     2.632V
17.15ns   2.336V     2.218V     2.518V
20ns      2.297V     2.167V     2.467V
[Falling Waveform]
R_fixture = 50.000
V_fixture = 0.000
V_fixture_min = 0.000
V_fixture_max = 0.000
|  time   V(typ)   V(min)   V(max)
0s        929.1mV    899.7mV    931mV
432ps     928.7mV    899.2mV    951mV
635ps     936mV      899.2mV    340.2mV
704ps     834.9mV    904.4mV    270.4mV
894ps     325.7mV    914.7mV    106.7mV
976ps     235.8mV    831.3mV    58.85mV
1.286ns   44.1mV     226.5mV    5.371mV
1.736ns   2.356mV    37.35mV    -635.9uV
2.289ns   60.46uV    1.945mV    -757.1uV
20ns      488.9uV    1.198mV    488.9uV
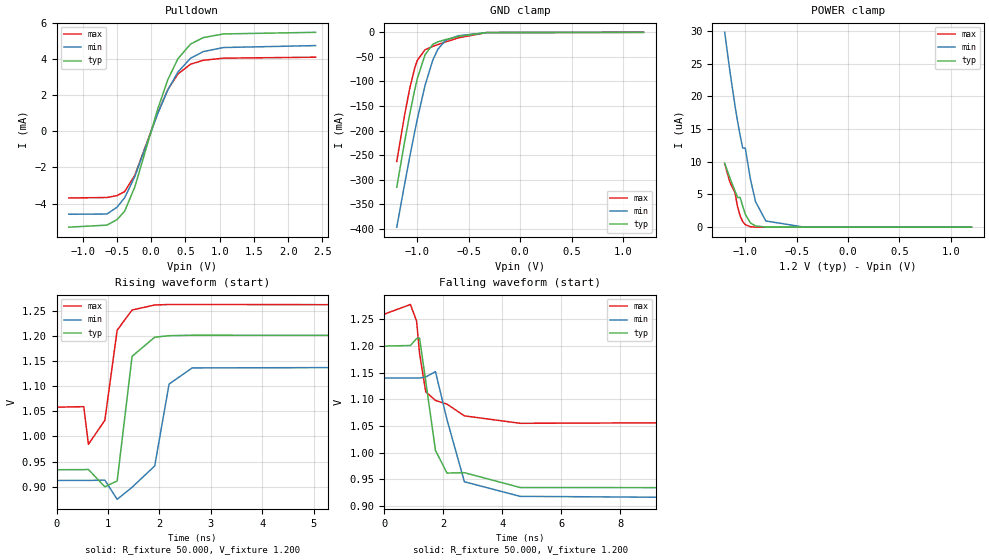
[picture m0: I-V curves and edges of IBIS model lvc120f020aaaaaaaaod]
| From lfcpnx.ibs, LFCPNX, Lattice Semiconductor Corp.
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[Model] lvc120f020aaaaaaaaod
Model_type I/O_open_drain
Polarity   Non-Inverting
Enable   Active-Low
Vinl =  0.420V
Vinh =  0.780V
Vmeas =  0.600V
Cref =  0.0F
Rref =  1.000M
Vref =  0.0V
C_comp   5.000pF   4.000pF   5.500pF
[Temperature Range]   25.000   0.125k   -40.000
[Voltage Range]   1.200V   1.140V   1.260V
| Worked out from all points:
|   slope of the pulldown table from 0 to 0.18 V, typ, clamps not added: 82 ohm
|   GND clamp passes 1 mA (typ) near -0.37 V on its own axis
|   rising waveform, R_fixture 50.000, V_fixture 1.200: 20-80 % time 147ps typ, 223ps min, 189ps max; typ from 0.934 V to 1.2 V
|   falling waveform, R_fixture 50.000, V_fixture 1.200: 20-80 % time 455ps typ, 595ps min, 472ps max; typ from 1.2 V to 0.934 V
[Pulldown]
|Voltage   I(typ)   I(min)   I(max)
-1.2V     -5.304mA   -4.589mA   -3.689mA
-645mV    -5.193mA   -4.579mA   -3.665mA
-497mV    -4.885mA   -4.199mA   -3.558mA
-386mV    -4.42mA    -3.677mA   -3.338mA
-238mV    -3.087mA   -2.512mA   -2.436mA
95mV      1.21mA     963.4uA    990uA
243mV     2.844mA    2.282mA    2.298mA
391mV     4.013mA    3.279mA    3.168mA
576mV     4.825mA    4.039mA    3.711mA
761mV     5.181mA    4.409mA    3.927mA
1.057V    5.385mA    4.633mA    4.045mA
2.4V      5.474mA    4.74mA     4.098mA
[GND_clamp]
|Voltage   I(typ)   I(min)   I(max)
-1.2V     -315.4mA   -396.6mA   -262.8mA
-1.125V   -224.2mA   -310.4mA   -169.7mA
-1.075V   -167.6mA   -254.9mA   -115.2mA
-1.025V   -116.7mA   -201.7mA   -72.28mA
-1V       -94.37mA   -176.3mA   -57.02mA
-925mV    -45.51mA   -108mA     -35.44mA
-850mV    -24.46mA   -56.69mA   -28.64mA
-800mV    -19.33mA   -34.4mA    -24.9mA
-725mV    -14.7mA    -16.27mA   -19.51mA
-600mV    -8.382mA   -6.838mA   -11.25mA
-325mV    -419.5uA   -603.2uA   -451.4uA
1.2V      0A         0A         0A
[POWER_clamp]
|Voltage   I(typ)   I(min)   I(max)
-1.2V     9.784uA    29.78uA    9.705uA
-1.15V    7.557uA    23.92uA    6.902uA
-1.1V     5.547uA    18.58uA    5.27uA
-1.075V   4.536uA    16.2uA     3.145uA
-1.05V    4.536uA    14.04uA    1.723uA
-1.025V   3.208uA    12.09uA    859.7nA
-1V       1.992uA    12.09uA    392.6nA
-950mV    645.9nA    7.363uA    69.77nA
-900mV    183.2nA    3.898uA    12.64nA
-800mV    21.08nA    947nA      1.102nA
-425mV    0A         0A         0A
1.2V      0A         0A         0A
[Ramp]
| variable   typ   min   max
dV/dt_r   0.161/37.864n   0.138/0.327n   0.123/22.577n
dV/dt_f   0.160/0.316n   0.137/0.390n   0.121/0.305n
R_load = 50.000
[Rising Waveform]
R_fixture= 50.000
V_fixture= 1.200
V_fixture_min= 1.140
V_fixture_max= 1.260
|time   V(typ)   V(min)   V(max)
0s        933.7mV    912.4mV    1.058V
530ps     933.9mV    912.5mV    1.059V
620ps     934.3mV    912.4mV    984.1mV
940ps     899.8mV    913.1mV    1.032V
1.18ns    911.5mV    874.9mV    1.211V
1.47ns    1.159V     898.9mV    1.251V
1.91ns    1.197V     941.2mV    1.261V
2.19ns    1.2V       1.104V     1.262V
2.64ns    1.201V     1.136V     1.262V
20ns      1.2V       1.14V      1.26V
[Falling Waveform]
R_fixture= 50.000
V_fixture= 1.200
V_fixture_min= 1.140
V_fixture_max= 1.260
|time   V(typ)   V(min)   V(max)
0s        1.2V       1.14V      1.26V
880ps     1.201V     1.14V      1.278V
1.09ns    1.214V     1.14V      1.247V
1.19ns    1.215V     1.14V      1.186V
1.4ns     1.134V     1.142V     1.114V
1.73ns    1.004V     1.152V     1.098V
2.12ns    961.6mV    1.062V     1.091V
2.71ns    962.3mV    945.3mV    1.069V
4.6ns     934.5mV    917.9mV    1.055V
20ns      933.7mV    912.3mV    1.058V
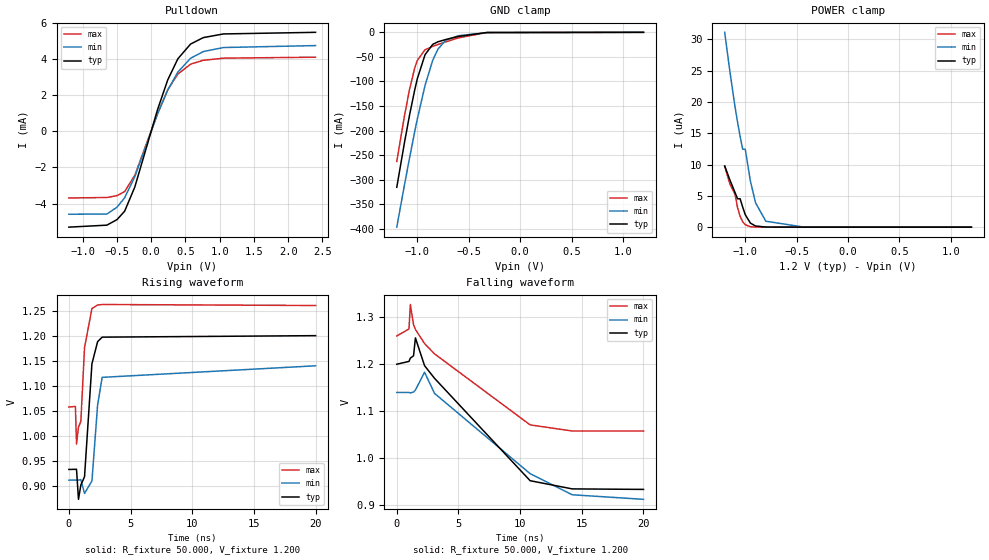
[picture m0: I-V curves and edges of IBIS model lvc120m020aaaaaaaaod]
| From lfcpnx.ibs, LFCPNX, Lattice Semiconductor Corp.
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|Model lvc120m020aaaaaaaaod
[Model] lvc120m020aaaaaaaaod
Model_type I/O_open_drain
Polarity   Non-Inverting
Enable   Active-Low
Vinl =  0.420V
Vinh =  0.780V
Vmeas =  0.600V
Cref =  0.0F
Rref =  1.000M
Vref =  0.0V
C_comp   5.000pF   4.000pF   5.500pF
[Temperature Range]   25.000   0.125k   -40.000
[Voltage Range]   1.200V   1.140V   1.260V
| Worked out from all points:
|   slope of the pulldown table from 0 to 0.18 V, typ, clamps not added: 82 ohm
|   GND clamp passes 1 mA (typ) near -0.37 V on its own axis
|   rising waveform, R_fixture 50.000, V_fixture 1.200: 20-80 % time 466ps typ, 430ps min, 365ps max; typ from 0.934 V to 1.2 V
|   falling waveform, R_fixture 50.000, V_fixture 1.200: 20-80 % time 5.25ns typ, 5.98ns min, 5.8ns max; typ from 1.2 V to 0.934 V
[Pulldown]
|Voltage   I(typ)   I(min)   I(max)
-1.2V     -5.304mA   -4.589mA   -3.689mA
-645mV    -5.193mA   -4.579mA   -3.664mA
-497mV    -4.885mA   -4.198mA   -3.558mA
-386mV    -4.42mA    -3.677mA   -3.338mA
-238mV    -3.087mA   -2.512mA   -2.436mA
95mV      1.21mA     963.4uA    990uA
243mV     2.844mA    2.282mA    2.298mA
391mV     4.013mA    3.278mA    3.168mA
576mV     4.825mA    4.039mA    3.711mA
761mV     5.181mA    4.408mA    3.927mA
1.057V    5.385mA    4.633mA    4.045mA
2.4V      5.474mA    4.741mA    4.098mA
[GND_clamp]
|Voltage   I(typ)   I(min)   I(max)
-1.2V     -315.4mA   -396.6mA   -262.8mA
-1.125V   -224.2mA   -310.4mA   -169.7mA
-1.075V   -167.6mA   -254.9mA   -115.2mA
-1.025V   -116.7mA   -201.7mA   -72.28mA
-1V       -94.37mA   -176.3mA   -57.02mA
-925mV    -45.51mA   -108mA     -35.44mA
-850mV    -24.46mA   -56.69mA   -28.64mA
-800mV    -19.33mA   -34.4mA    -24.9mA
-725mV    -14.7mA    -16.27mA   -19.51mA
-600mV    -8.382mA   -6.838mA   -11.25mA
-325mV    -419.5uA   -603.2uA   -451.4uA
1.2V      0A         0A         0A
[POWER_clamp]
|Voltage   I(typ)   I(min)   I(max)
-1.2V     9.784uA    31.12uA    9.705uA
-1.15V    7.557uA    24.91uA    6.902uA
-1.1V     5.547uA    19.28uA    5.27uA
-1.075V   4.536uA    16.78uA    3.145uA
-1.05V    4.536uA    14.51uA    1.723uA
-1.025V   3.208uA    12.45uA    859.7nA
-1V       1.992uA    12.45uA    392.6nA
-950mV    645.9nA    7.363uA    69.77nA
-900mV    183.2nA    3.898uA    12.8nA
-800mV    21.08nA    947nA      1.102nA
-425mV    0A         0A         0A
1.2V      0A         0A         0A
[Ramp]
| variable   typ   min   max
dV/dt_r   0.161/37.743n   0.138/0.331n   0.123/22.526n
dV/dt_f   0.160/17.655n   0.137/20.001n   0.121/19.358n
R_load = 50.000
[Rising Waveform]
R_fixture = 50.000
V_fixture = 1.200
V_fixture_min = 1.140
V_fixture_max = 1.260
|  time   V(typ)   V(min)   V(max)
0s        933.7mV    912.4mV    1.058V
530ps     933.9mV    912.5mV    1.059V
620ps     934.2mV    912.4mV    984.1mV
780ps     874.2mV    912.5mV    1.018V
970ps     902.5mV    913.5mV    1.029V
1.27ns    919.2mV    886mV      1.176V
1.87ns    1.144V     910.7mV    1.254V
2.33ns    1.188V     1.062V     1.261V
2.7ns     1.197V     1.117V     1.262V
20ns      1.2V       1.14V      1.26V
[Falling Waveform]
R_fixture= 50.000
V_fixture= 1.200
V_fixture_min= 1.140
V_fixture_max= 1.260
|time   V(typ)   V(min)   V(max)
0s        1.2V       1.14V      1.26V
990ps     1.206V     1.14V      1.275V
1.1ns     1.213V     1.139V     1.327V
1.36ns    1.218V     1.141V     1.284V
1.51ns    1.256V     1.145V     1.274V
2.25ns    1.197V     1.183V     1.244V
3.06ns    1.17V      1.138V     1.222V
10.81ns   952.3mV    967.3mV    1.071V
14.22ns   934.9mV    922.4mV    1.058V
20ns      933.8mV    912.7mV    1.058V
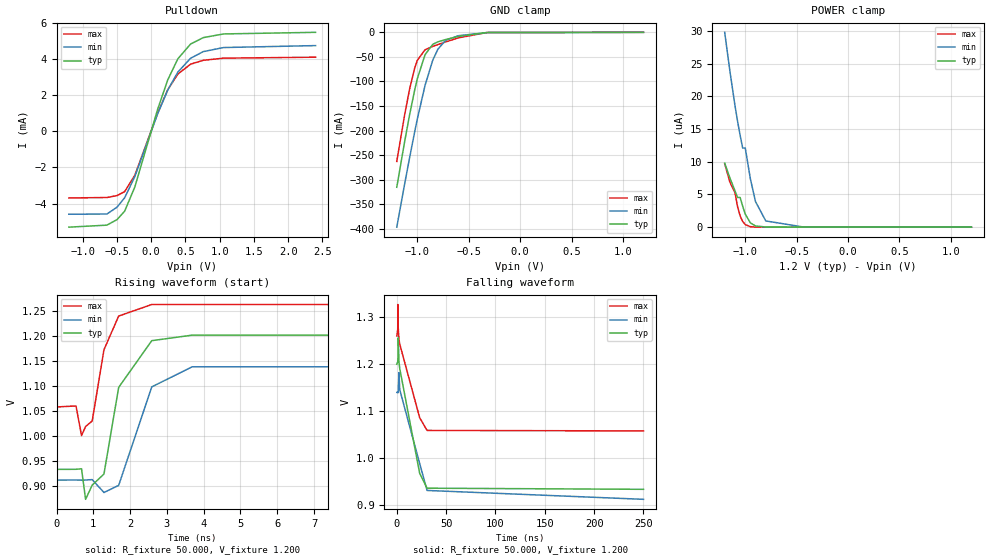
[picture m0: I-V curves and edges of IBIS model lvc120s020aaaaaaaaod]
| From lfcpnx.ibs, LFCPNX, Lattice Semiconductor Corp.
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|Model lvc120s020aaaaaaaaod
[Model] lvc120s020aaaaaaaaod
Model_type I/O_open_drain
Polarity   Non-Inverting
Enable   Active-Low
Vinl =  0.420V
Vinh =  0.780V
Vmeas =  0.600V
Cref =  0.0F
Rref =  1.000M
Vref =  0.0V
C_comp   5.000pF   4.000pF   5.500pF
[Temperature Range]   25.000   0.125k   -40.000
[Voltage Range]   1.200V   1.140V   1.260V
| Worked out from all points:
|   slope of the pulldown table from 0 to 0.18 V, typ, clamps not added: 82 ohm
|   GND clamp passes 1 mA (typ) near -0.37 V on its own axis
|   rising waveform, R_fixture 50.000, V_fixture 1.200: 20-80 % time 532ps typ, 503ps min, 415ps max; typ from 0.934 V to 1.2 V
|   falling waveform, R_fixture 50.000, V_fixture 1.200: 20-80 % time 13.5ns typ, 15.3ns min, 14.9ns max; typ from 1.2 V to 0.934 V
[Pulldown]
|Voltage   I(typ)   I(min)   I(max)
-1.2V     -5.304mA   -4.589mA   -3.689mA
-645mV    -5.193mA   -4.578mA   -3.664mA
-497mV    -4.885mA   -4.198mA   -3.558mA
-386mV    -4.42mA    -3.677mA   -3.338mA
-238mV    -3.087mA   -2.512mA   -2.436mA
95mV      1.21mA     963.3uA    990uA
243mV     2.844mA    2.281mA    2.298mA
391mV     4.013mA    3.278mA    3.168mA
576mV     4.825mA    4.038mA    3.711mA
761mV     5.181mA    4.407mA    3.927mA
1.057V    5.385mA    4.632mA    4.045mA
2.4V      5.474mA    4.74mA     4.098mA
[GND_clamp]
|Voltage   I(typ)   I(min)   I(max)
-1.2V     -315.4mA   -396.6mA   -262.8mA
-1.125V   -224.2mA   -310.4mA   -169.7mA
-1.075V   -167.6mA   -254.9mA   -115.2mA
-1.025V   -116.7mA   -201.7mA   -72.28mA
-1V       -94.37mA   -176.3mA   -57.02mA
-925mV    -45.51mA   -108mA     -35.44mA
-850mV    -24.46mA   -56.69mA   -28.64mA
-800mV    -19.33mA   -34.4mA    -24.9mA
-725mV    -14.7mA    -16.27mA   -19.51mA
-600mV    -8.382mA   -6.838mA   -11.25mA
-325mV    -419.5uA   -603.2uA   -451.4uA
1.2V      0A         0A         0A
[POWER_clamp]
|Voltage   I(typ)   I(min)   I(max)
-1.2V     9.784uA    29.78uA    9.705uA
-1.15V    7.557uA    23.92uA    6.902uA
-1.1V     5.547uA    18.58uA    5.27uA
-1.075V   4.536uA    16.2uA     3.145uA
-1.05V    4.536uA    14.04uA    1.723uA
-1.025V   3.208uA    12.09uA    859.7nA
-1V       1.992uA    12.09uA    392.6nA
-950mV    645.9nA    7.363uA    69.77nA
-900mV    183.2nA    3.898uA    12.8nA
-800mV    21.08nA    947nA      1.102nA
-425mV    0A         0A         0A
1.2V      0A         0A         0A
[Ramp]
| variable   typ   min   max
dV/dt_r   0.161/37.720n   0.138/0.335n   0.123/22.475n
dV/dt_f   0.160/45.851n   0.137/51.867n   0.121/50.511n
R_load = 50.000
[Rising Waveform]
R_fixture= 50.000
V_fixture= 1.200
V_fixture_min= 1.140
V_fixture_max= 1.260
|time   V(typ)   V(min)   V(max)
0s        933.7mV    912.4mV    1.058V
530ps     933.9mV    912.5mV    1.06V
680ps     934.9mV    912.3mV    1.001V
790ps     874.1mV    912.5mV    1.019V
970ps     902.4mV    913.4mV    1.03V
1.29ns    924.5mV    887.7mV    1.172V
1.69ns    1.097V     901.9mV    1.239V
2.59ns    1.19V      1.098V     1.262V
3.69ns    1.201V     1.138V     1.262V
250ns     1.2V       1.14V      1.26V
[Falling Waveform]
R_fixture= 50.000
V_fixture= 1.200
V_fixture_min= 1.140
V_fixture_max= 1.260
|time   V(typ)   V(min)   V(max)
0s        1.2V       1.14V      1.26V
980ps     1.205V     1.14V      1.274V
1.11ns    1.213V     1.139V     1.327V
1.34ns    1.216V     1.14V      1.287V
1.51ns    1.256V     1.145V     1.276V
2.23ns    1.205V     1.182V     1.253V
2.97ns    1.191V     1.146V     1.243V
23.2ns    967.7mV    988.6mV    1.086V
30.7ns    936.1mV    931.3mV    1.059V
250ns     933.7mV    912.4mV    1.058V
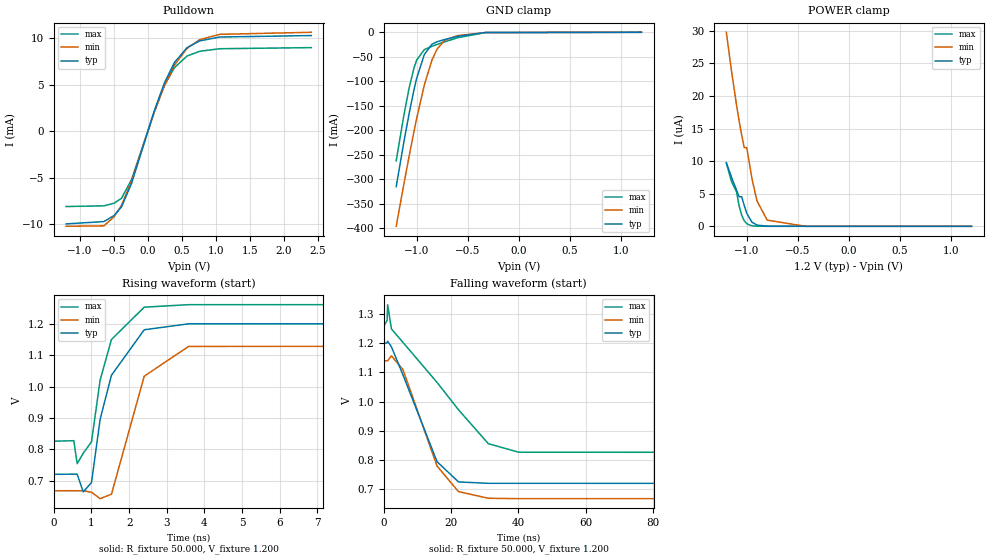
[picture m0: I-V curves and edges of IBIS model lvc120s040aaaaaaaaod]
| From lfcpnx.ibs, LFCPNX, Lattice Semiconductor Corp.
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|Model lvc120s040aaaaaaaaod
[Model] lvc120s040aaaaaaaaod
Model_type I/O_open_drain
Polarity   Non-Inverting
Enable   Active-Low
Vinl =  0.420V
Vinh =  0.780V
Vmeas =  0.600V
Cref =  0.0F
Rref =  1.000M
Vref =  0.0V
C_comp   5.000pF   4.000pF   5.500pF
[Temperature Range]   25.000   0.125k   -40.000
[Voltage Range]   1.200V   1.140V   1.260V
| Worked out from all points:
|   slope of the pulldown table from 0 to 0.18 V, typ, clamps not added: 45.2 ohm
|   GND clamp passes 1 mA (typ) near -0.37 V on its own axis
|   rising waveform, R_fixture 50.000, V_fixture 1.200: 20-80 % time 641ps typ, 758ps min, 522ps max; typ from 0.721 V to 1.2 V
|   falling waveform, R_fixture 50.000, V_fixture 1.200: 20-80 % time 9.68ns typ, 9.52ns min, 18.2ns max; typ from 1.2 V to 0.721 V
[Pulldown]
|Voltage   I(typ)   I(min)   I(max)
-1.2V     -9.962mA   -10.22mA   -8.095mA
-645mV    -9.711mA   -10.17mA   -8.018mA
-497mV    -9.07mA    -9.211mA   -7.744mA
-386mV    -8.128mA   -7.961mA   -7.209mA
-238mV    -5.598mA   -5.347mA   -5.183mA
95mV      2.188mA    2.044mA    2.096mA
243mV     5.18mA     4.881mA    4.907mA
391mV     7.388mA    7.108mA    6.837mA
576mV     8.988mA    8.912mA    8.087mA
761mV     9.714mA    9.844mA    8.596mA
1.057V    10.13mA    10.42mA    8.873mA
2.4V      10.29mA    10.64mA    8.992mA
[GND_clamp]
|Voltage   I(typ)   I(min)   I(max)
-1.2V     -315.4mA   -396.6mA   -262.8mA
-1.125V   -224.2mA   -310.4mA   -169.7mA
-1.075V   -167.6mA   -254.9mA   -115.2mA
-1.025V   -116.7mA   -201.7mA   -72.28mA
-1V       -94.37mA   -176.3mA   -57.02mA
-925mV    -45.51mA   -108mA     -35.44mA
-850mV    -24.46mA   -56.69mA   -28.64mA
-800mV    -19.33mA   -34.4mA    -24.9mA
-725mV    -14.7mA    -16.27mA   -19.51mA
-600mV    -8.382mA   -6.838mA   -11.25mA
-325mV    -419.5uA   -603.2uA   -451.4uA
1.2V      0A         0A         0A
[POWER_clamp]
|Voltage   I(typ)   I(min)   I(max)
-1.2V     9.784uA    29.78uA    9.705uA
-1.15V    7.557uA    23.92uA    6.902uA
-1.1V     5.547uA    18.58uA    5.27uA
-1.075V   4.536uA    16.2uA     3.145uA
-1.05V    4.536uA    14.04uA    1.723uA
-1.025V   3.208uA    12.09uA    859.7nA
-1V       1.992uA    12.09uA    392.6nA
-950mV    645.9nA    7.363uA    69.77nA
-900mV    183.2nA    3.898uA    12.64nA
-800mV    21.08nA    947nA      1.102nA
-425mV    0A         0A         0A
1.2V      0A         0A         0A
[Ramp]
| variable   typ   min   max
dV/dt_r   0.289/0.261n   0.285/0.280n   0.262/22.567n
dV/dt_f   0.288/33.377n   0.284/33.127n   0.261/63.340n
R_load = 50.000
[Rising Waveform]
R_fixture= 50.000
V_fixture= 1.200
V_fixture_min= 1.140
V_fixture_max= 1.260
|time   V(typ)   V(min)   V(max)
0s        720.6mV    668.1mV    825.9mV
530ps     721mV      668.2mV    827.6mV
620ps     721.1mV    668mV      754.4mV
780ps     664.5mV    668.2mV    787.5mV
1ns       694.3mV    663.4mV    824mV
1.23ns    896.2mV    642.8mV    1.021V
1.53ns    1.036V     657mV      1.15V
2.4ns     1.181V     1.033V     1.253V
3.58ns    1.2V       1.128V     1.261V
250ns     1.2V       1.14V      1.26V
[Falling Waveform]
R_fixture= 50.000
V_fixture= 1.200
V_fixture_min= 1.140
V_fixture_max= 1.260
|time   V(typ)   V(min)   V(max)
0s        1.2V       1.14V      1.26V
950ps     1.201V     1.14V      1.278V
1.1ns     1.207V     1.14V      1.332V
2.22ns    1.188V     1.157V     1.249V
5.65ns    1.092V     1.11V      1.203V
15.8ns    794.9mV    779.9mV    1.066V
22.2ns    725.4mV    692.2mV    972.2mV
31.09ns   720.7mV    669.5mV    856.2mV
40.14ns   720.7mV    668.2mV    827.1mV
250ns     720.6mV    668.1mV    825.9mV
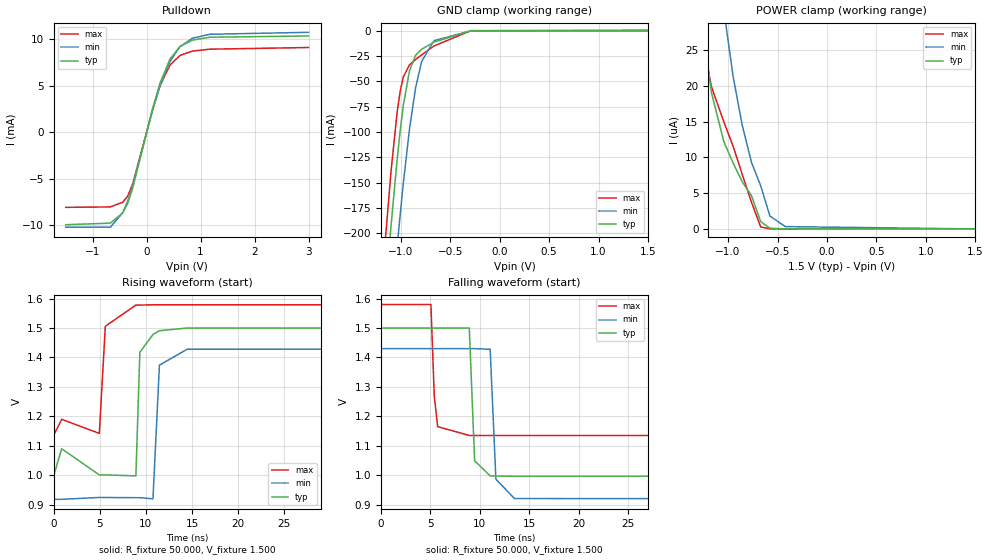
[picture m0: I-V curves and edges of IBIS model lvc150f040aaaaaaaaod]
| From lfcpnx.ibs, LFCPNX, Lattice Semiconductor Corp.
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[Model] lvc150f040aaaaaaaaod
Model_type I/O_open_drain
Polarity   Non-Inverting
Enable   Active-Low
Vinl =  0.375V
Vinh =  1.125V
Vmeas =  0.750V
Cref =  0.0F
Rref =  1.000M
Vref =  0.0V
C_comp   5.000pF   4.000pF   5.500pF
[Temperature Range]   25.000   0.125k   -40.000
[Voltage Range]   1.500V   1.430V   1.580V
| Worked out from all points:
|   slope of the pulldown table from 0 to 0.225 V, typ, clamps not added: 46.4 ohm
|   GND clamp passes 1 mA (typ) near -0.37 V on its own axis
|   rising waveform, R_fixture 50.000, V_fixture 1.500: 20-80 % time 272ps typ, 377ps min, 326ps max; typ from 0.996 V to 1.5 V
|   falling waveform, R_fixture 50.000, V_fixture 1.500: 20-80 % time 259ps typ, 335ps min, 283ps max; typ from 1.5 V to 0.996 V
[Pulldown]
|Voltage   I(typ)   I(min)   I(max)
-1.5V     -9.959mA   -10.22mA   -8.095mA
-672mV    -9.786mA   -10.22mA   -8.043mA
-442mV    -8.681mA   -8.665mA   -7.536mA
-350mV    -7.654mA   -7.425mA   -6.885mA
-258mV    -6.025mA   -5.762mA   -5.557mA
110mV     2.518mA    2.354mA    2.412mA
248mV     5.268mA    4.969mA    4.987mA
432mV     7.845mA    7.602mA    7.208mA
616mV     9.2mA      9.178mA    8.239mA
846mV     9.89mA     10.09mA    8.712mA
1.168V    10.2mA     10.52mA    8.917mA
3V        10.34mA    10.73mA    9.098mA
[GND_clamp]
|Voltage   I(typ)   I(min)   I(max)
-1.5V     -708.3mA   -763.4mA   -675.9mA
-1.159V   -265.1mA   -350.4mA   -211mA
-1.097V   -192.2mA   -279.7mA   -138.3mA
-1.035V   -126.5mA   -212.4mA   -79.79mA
-1.004V   -97.99mA   -180.6mA   -59.26mA
-973mV    -73.59mA   -150.5mA   -45.64mA
-911mV    -39.79mA   -97.15mA   -33.84mA
-849mV    -24.33mA   -56.34mA   -28.56mA
-787mV    -18.41mA   -30.2mA    -23.94mA
-663mV    -11.42mA   -9.983mA   -15.26mA
-291mV    -183uA     -342.4uA   -164.8uA
1.5V      0A         0A         0A
[POWER_clamp]
|Voltage   I(typ)   I(min)   I(max)
-1.5V     59.32uA    98.32uA    59.13uA
-1.321V   34.73uA    66.64uA    31.85uA
-1.29V    31.3uA     61.54uA    28.52uA
-1.166V   18.95uA    42.82uA    19.79uA
-1.042V   12.18uA    30.57uA    14.95uA
-949mV    9.218uA    21.32uA    11.56uA
-856mV    6.569uA    14.45uA    7.618uA
-763mV    4.659uA    9.303uA    3.739uA
-670mV    1.028uA    6.028uA    280.6nA
-577mV    100.2nA    1.816uA    11.26nA
-422mV    7.758nA    331.2nA    690.6pA
1.5V      0A         0A         0A
[Ramp]
| variable   typ   min   max
dV/dt_r   0.302/0.273n   0.307/0.387n   0.267/4.873n
dV/dt_f   0.302/0.264n   0.307/0.331n   0.267/0.284n
R_load = 50.000
[Rising Waveform]
R_fixture= 50.000
V_fixture= 1.500
V_fixture_min= 1.430
V_fixture_max= 1.580
|time   V(typ)   V(min)   V(max)
0s        996mV      918.1mV    1.135V
880ps     1.09V      918.1mV    1.19V
4.96ns    1.001V     924.5mV    1.142V
5.61ns    1.001V     924.3mV    1.506V
8.92ns    997.8mV    923.7mV    1.578V
9.35ns    1.418V     923.7mV    1.578V
10.77ns   1.478V     919.8mV    1.579V
11.47ns   1.491V     1.374V     1.579V
14.47ns   1.5V       1.428V     1.579V
200ns     1.5V       1.43V      1.58V
[Falling Waveform]
R_fixture= 50.000
V_fixture= 1.500
V_fixture_min= 1.430
V_fixture_max= 1.580
|time   V(typ)   V(min)   V(max)
0s        1.5V       1.43V      1.58V
5.06ns    1.5V       1.43V      1.58V
5.4ns     1.5V       1.43V      1.268V
5.74ns    1.5V       1.43V      1.165V
8.94ns    1.5V       1.43V      1.135V
9.48ns    1.049V     1.43V      1.135V
11.05ns   997.8mV    1.428V     1.135V
11.63ns   997.2mV    986.3mV    1.135V
13.51ns   996.4mV    920.7mV    1.135V
200ns     996mV      918mV      1.135V
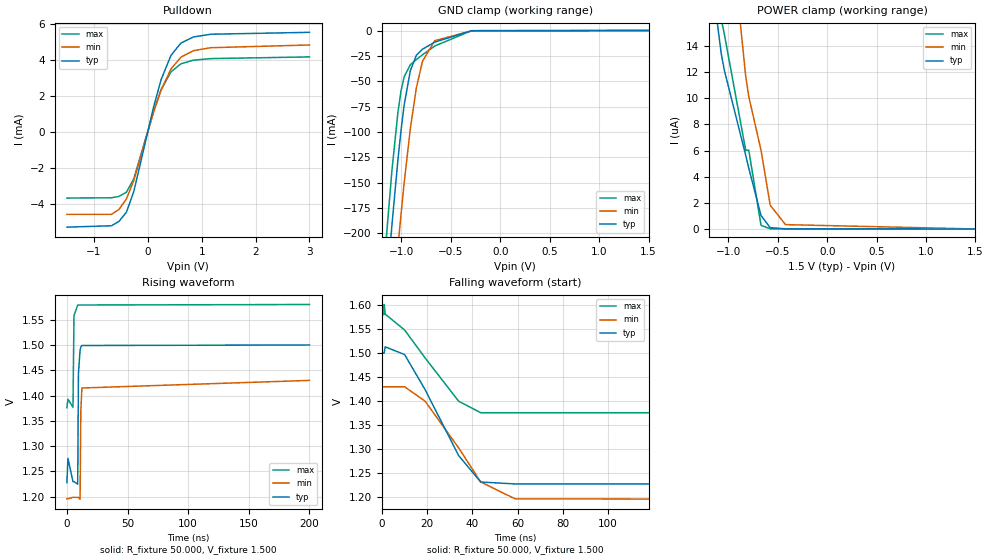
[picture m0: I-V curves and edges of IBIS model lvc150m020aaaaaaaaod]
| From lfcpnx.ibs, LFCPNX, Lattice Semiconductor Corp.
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[Model] lvc150m020aaaaaaaaod
Model_type I/O_open_drain
Polarity   Non-Inverting
Enable   Active-Low
Vinl =  0.375V
Vinh =  1.125V
Vmeas =  0.750V
Cref =  0.0F
Rref =  1.000M
Vref =  0.0V
C_comp   5.000pF   4.000pF   5.500pF
[Temperature Range]   25.000   0.125k   -40.000
[Voltage Range]   1.500V   1.430V   1.580V
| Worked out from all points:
|   slope of the pulldown table from 0 to 0.225 V, typ, clamps not added: 84.5 ohm
|   GND clamp passes 1 mA (typ) near -0.37 V on its own axis
|   rising waveform, R_fixture 50.000, V_fixture 1.500: 20-80 % time 402ps typ, 430ps min, 435ps max; typ from 1.23 V to 1.5 V
|   falling waveform, R_fixture 50.000, V_fixture 1.500: 20-80 % time 17.7ns typ, 19.9ns min, 19.4ns max; typ from 1.5 V to 1.23 V
[Pulldown]
|Voltage   I(typ)   I(min)   I(max)
-1.5V     -5.306mA   -4.593mA   -3.688mA
-672mV    -5.228mA   -4.593mA   -3.673mA
-534mV    -4.985mA   -4.325mA   -3.596mA
-396mV    -4.477mA   -3.736mA   -3.367mA
-258mV    -3.318mA   -2.702mA   -2.608mA
110mV     1.392mA    1.109mA    1.138mA
248mV     2.892mA    2.321mA    2.334mA
432mV     4.249mA    3.491mA    3.33mA
616mV     4.929mA    4.145mA    3.774mA
846mV     5.266mA    4.502mA    3.975mA
1.168V    5.418mA    4.669mA    4.063mA
3V        5.524mA    4.821mA    4.158mA
[GND_clamp]
|Voltage   I(typ)   I(min)   I(max)
-1.5V     -708.3mA   -763.4mA   -675.9mA
-1.159V   -265.1mA   -350.4mA   -211mA
-1.097V   -192.2mA   -279.7mA   -138.3mA
-1.035V   -126.5mA   -212.4mA   -79.79mA
-1.004V   -97.99mA   -180.6mA   -59.26mA
-973mV    -73.59mA   -150.5mA   -45.64mA
-911mV    -39.79mA   -97.15mA   -33.84mA
-849mV    -24.33mA   -56.34mA   -28.56mA
-787mV    -18.41mA   -30.2mA    -23.94mA
-663mV    -11.42mA   -9.983mA   -15.26mA
-291mV    -183uA     -342.4uA   -164.8uA
1.5V      0A         0A         0A
[POWER_clamp]
|Voltage   I(typ)   I(min)   I(max)
-1.5V     59.32uA    98.32uA    59.13uA
-1.29V    31.3uA     61.54uA    28.52uA
-1.259V   27.72uA    56.58uA    25.68uA
-1.166V   18.95uA    42.82uA    19.79uA
-1.073V   13.45uA    31.2uA     16.06uA
-1.042V   12.18uA    27.88uA    14.95uA
-825mV    5.639uA    11.69uA    6.03uA
-794mV    4.659uA    10.14uA    6.03uA
-670mV    1.028uA    6.028uA    280.6nA
-577mV    100.2nA    1.816uA    11.26nA
-422mV    7.758nA    331.2nA    690.7pA
1.5V      0A         0A         0A
[Ramp]
| variable   typ   min   max
dV/dt_r   0.163/0.404n   0.140/0.437n   0.123/0.439n
dV/dt_f   0.163/17.726n   0.140/20.016n   0.123/19.383n
R_load = 50.000
[Rising Waveform]
R_fixture= 50.000
V_fixture= 1.500
V_fixture_min= 1.430
V_fixture_max= 1.580
|time   V(typ)   V(min)   V(max)
0s        1.228V     1.196V     1.376V
850ps     1.276V     1.196V     1.393V
5ns       1.23V      1.199V     1.377V
5.85ns    1.23V      1.199V     1.558V
8.91ns    1.225V     1.199V     1.579V
9.52ns    1.444V     1.199V     1.579V
10.87ns   1.49V      1.195V     1.579V
11.46ns   1.496V     1.369V     1.579V
12.37ns   1.499V     1.415V     1.579V
200ns     1.5V       1.43V      1.58V
[Falling Waveform]
R_fixture= 50.000
V_fixture= 1.500
V_fixture_min= 1.430
V_fixture_max= 1.580
|time   V(typ)   V(min)   V(max)
0s        1.5V       1.43V      1.58V
960ps     1.5V       1.43V      1.58V
1.08ns    1.5V       1.43V      1.601V
1.53ns    1.513V     1.43V      1.581V
10.1ns    1.497V     1.43V      1.548V
19.15ns   1.424V     1.4V       1.49V
33.95ns   1.287V     1.303V     1.4V
43.7ns    1.232V     1.232V     1.376V
58.88ns   1.228V     1.197V     1.376V
200ns     1.228V     1.196V     1.376V
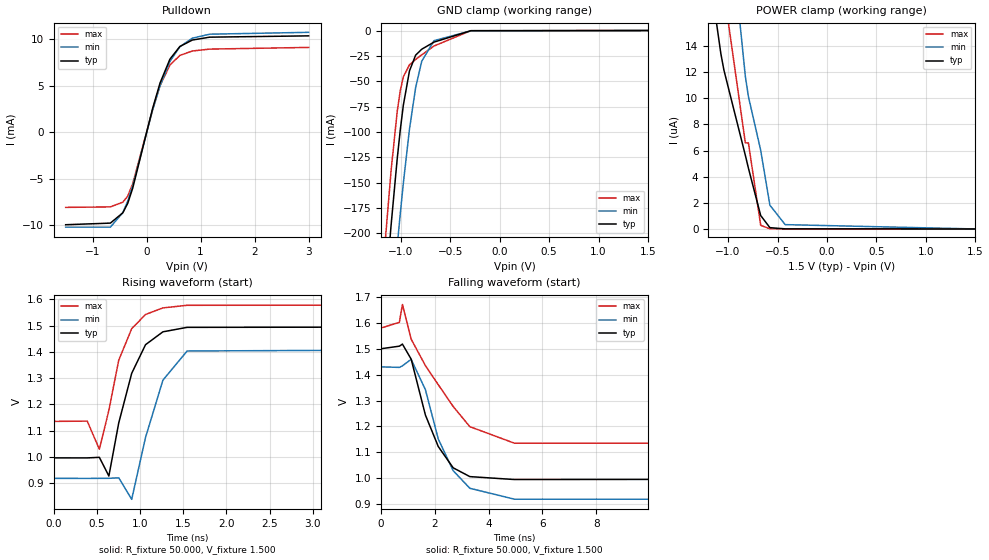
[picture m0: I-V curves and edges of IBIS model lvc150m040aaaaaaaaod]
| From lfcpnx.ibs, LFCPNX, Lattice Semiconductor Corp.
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[Model] lvc150m040aaaaaaaaod
Model_type I/O_open_drain
Polarity   Non-Inverting
Enable   Active-Low
Vinl =  0.375V
Vinh =  1.125V
Vmeas =  0.750V
Cref =  0.0F
Rref =  1.000M
Vref =  0.0V
C_comp   5.000pF   4.000pF   5.500pF
[Temperature Range]   25.000   0.125k   -40.000
[Voltage Range]   1.500V   1.430V   1.580V
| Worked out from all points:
|   slope of the pulldown table from 0 to 0.225 V, typ, clamps not added: 46.4 ohm
|   GND clamp passes 1 mA (typ) near -0.37 V on its own axis
|   rising waveform, R_fixture 50.000, V_fixture 1.500: 20-80 % time 276ps typ, 288ps min, 247ps max; typ from 0.996 V to 1.5 V
|   falling waveform, R_fixture 50.000, V_fixture 1.500: 20-80 % time 1.02ns typ, 1.05ns min, 1.75ns max; typ from 1.5 V to 0.996 V
[Pulldown]
|Voltage   I(typ)   I(min)   I(max)
-1.5V     -9.959mA   -10.22mA   -8.095mA
-672mV    -9.786mA   -10.22mA   -8.043mA
-442mV    -8.681mA   -8.664mA   -7.536mA
-350mV    -7.654mA   -7.425mA   -6.885mA
-258mV    -6.025mA   -5.762mA   -5.557mA
110mV     2.518mA    2.353mA    2.412mA
248mV     5.268mA    4.968mA    4.987mA
432mV     7.845mA    7.601mA    7.208mA
616mV     9.2mA      9.177mA    8.239mA
846mV     9.89mA     10.09mA    8.712mA
1.168V    10.2mA     10.52mA    8.917mA
3V        10.34mA    10.72mA    9.098mA
[GND_clamp]
|Voltage   I(typ)   I(min)   I(max)
-1.5V     -708.3mA   -763.4mA   -675.9mA
-1.159V   -265.1mA   -350.4mA   -211mA
-1.097V   -192.2mA   -279.7mA   -138.3mA
-1.035V   -126.5mA   -212.4mA   -79.79mA
-1.004V   -97.99mA   -180.6mA   -59.26mA
-973mV    -73.59mA   -150.5mA   -45.64mA
-911mV    -39.79mA   -97.15mA   -33.84mA
-849mV    -24.33mA   -56.34mA   -28.56mA
-787mV    -18.41mA   -30.2mA    -23.94mA
-663mV    -11.42mA   -9.983mA   -15.26mA
-291mV    -183uA     -342.4uA   -164.8uA
1.5V      0A         0A         0A
[POWER_clamp]
|Voltage   I(typ)   I(min)   I(max)
-1.5V     59.32uA    98.32uA    59.13uA
-1.29V    31.3uA     61.54uA    28.52uA
-1.259V   27.72uA    56.58uA    25.68uA
-1.135V   16.77uA    38.68uA    18.43uA
-1.073V   13.45uA    31.2uA     18.43uA
-1.042V   12.18uA    27.88uA    18.25uA
-825mV    5.639uA    11.69uA    6.592uA
-794mV    4.659uA    10.14uA    6.592uA
-670mV    1.028uA    6.028uA    280.6nA
-577mV    100.2nA    1.816uA    11.26nA
-422mV    7.758nA    331.2nA    690.6pA
1.5V      0A         0A         0A
[Ramp]
| variable   typ   min   max
dV/dt_r   0.302/0.271n   0.307/0.361n   0.267/4.860n
dV/dt_f   0.302/11.806n   0.307/12.699n   0.267/24.159n
R_load = 50.000
[Rising Waveform]
R_fixture = 50.000
V_fixture = 1.500
V_fixture_min = 1.430
V_fixture_max = 1.580
|  time   V(typ)   V(min)   V(max)
0s        996.1mV    918.2mV    1.135V
390ps     996mV      917.9mV    1.136V
530ps     998.2mV    918.2mV    1.029V
640ps     927mV      918.3mV    1.177V
754ps     1.129V     920.2mV    1.368V
904ps     1.318V     838.3mV    1.488V
1.064ns   1.427V     1.074V     1.542V
1.265ns   1.476V     1.292V     1.567V
1.545ns   1.493V     1.403V     1.577V
20ns      1.5V       1.43V      1.58V
[Falling Waveform]
R_fixture = 50.000
V_fixture = 1.500
V_fixture_min = 1.430
V_fixture_max = 1.580
|  time   V(typ)   V(min)   V(max)
0s        1.5V       1.43V      1.58V
686ps     1.51V      1.428V     1.602V
800ps     1.518V     1.434V     1.671V
1.124ns   1.46V      1.459V     1.537V
1.653ns   1.244V     1.342V     1.435V
2.132ns   1.122V     1.151V     1.361V
2.684ns   1.04V      1.029V     1.277V
3.303ns   1.006V     960.9mV    1.199V
4.961ns   994.7mV    918.7mV    1.135V
20ns      996.1mV    918.2mV    1.135V
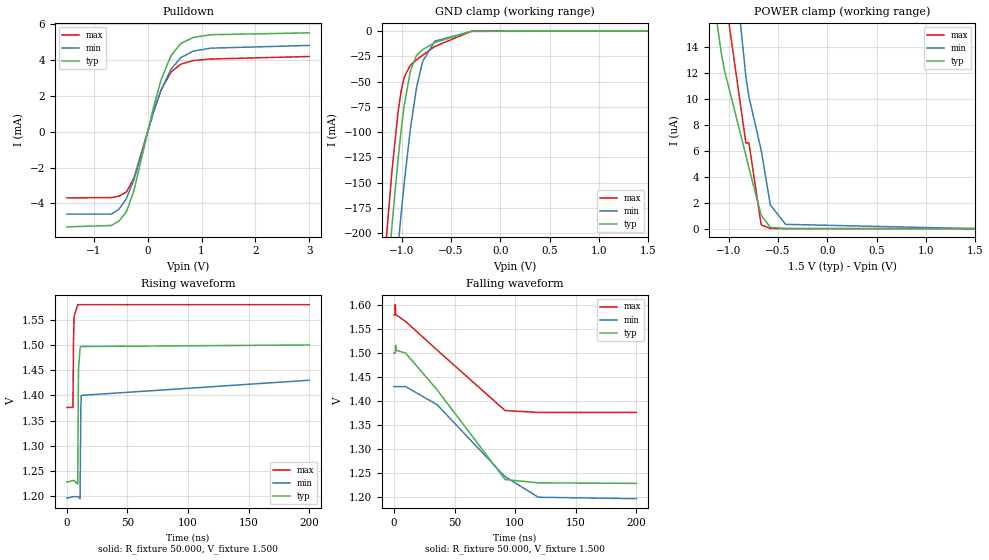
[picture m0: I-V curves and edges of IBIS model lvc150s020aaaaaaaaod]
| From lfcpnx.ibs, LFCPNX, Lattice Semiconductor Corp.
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|Model lvc150s020aaaaaaaaod
[Model] lvc150s020aaaaaaaaod
Model_type I/O_open_drain
Polarity   Non-Inverting
Enable   Active-Low
Vinl =  0.375V
Vinh =  1.125V
Vmeas =  0.750V
Cref =  0.0F
Rref =  1.000M
Vref =  0.0V
C_comp   5.000pF   4.000pF   5.500pF
[Temperature Range]   25.000   0.125k   -40.000
[Voltage Range]   1.500V   1.430V   1.580V
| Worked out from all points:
|   slope of the pulldown table from 0 to 0.225 V, typ, clamps not added: 84.5 ohm
|   GND clamp passes 1 mA (typ) near -0.37 V on its own axis
|   rising waveform, R_fixture 50.000, V_fixture 1.500: 20-80 % time 380ps typ, 433ps min, 514ps max; typ from 1.23 V to 1.5 V
|   falling waveform, R_fixture 50.000, V_fixture 1.500: 20-80 % time 46ns typ, 51.7ns min, 50.6ns max; typ from 1.5 V to 1.23 V
[Pulldown]
|Voltage   I(typ)   I(min)   I(max)
-1.5V     -5.306mA   -4.592mA   -3.688mA
-672mV    -5.228mA   -4.592mA   -3.673mA
-534mV    -4.985mA   -4.325mA   -3.596mA
-396mV    -4.477mA   -3.736mA   -3.367mA
-258mV    -3.318mA   -2.701mA   -2.608mA
110mV     1.392mA    1.108mA    1.138mA
248mV     2.892mA    2.321mA    2.334mA
432mV     4.248mA    3.49mA     3.33mA
616mV     4.929mA    4.144mA    3.774mA
846mV     5.266mA    4.501mA    3.975mA
1.168V    5.418mA    4.668mA    4.063mA
3V        5.524mA    4.82mA     4.204mA
[GND_clamp]
|Voltage   I(typ)   I(min)   I(max)
-1.5V     -708.3mA   -763.4mA   -675.9mA
-1.159V   -265.1mA   -350.4mA   -211mA
-1.097V   -192.2mA   -279.7mA   -138.3mA
-1.035V   -126.5mA   -212.4mA   -79.79mA
-1.004V   -97.99mA   -180.6mA   -59.26mA
-973mV    -73.59mA   -150.5mA   -45.64mA
-911mV    -39.79mA   -97.15mA   -33.84mA
-849mV    -24.33mA   -56.34mA   -28.56mA
-787mV    -18.41mA   -30.2mA    -23.94mA
-663mV    -11.42mA   -9.983mA   -15.26mA
-291mV    -183uA     -342.4uA   -164.8uA
1.5V      0A         0A         0A
[POWER_clamp]
|Voltage   I(typ)   I(min)   I(max)
-1.5V     59.32uA    98.32uA    59.13uA
-1.29V    31.3uA     61.54uA    28.52uA
-1.259V   27.72uA    56.58uA    25.68uA
-1.135V   16.77uA    38.68uA    18.43uA
-1.073V   13.45uA    31.2uA     18.43uA
-1.042V   12.18uA    27.88uA    18.25uA
-825mV    5.639uA    11.69uA    6.592uA
-794mV    4.659uA    10.14uA    6.592uA
-670mV    1.028uA    6.028uA    280.6nA
-577mV    100.2nA    1.816uA    11.26nA
-422mV    7.758nA    331.2nA    690.6pA
1.5V      0A         0A         0A
[Ramp]
| variable   typ   min   max
dV/dt_r   0.163/0.380n   0.140/0.440n   0.123/0.440n
dV/dt_f   0.163/46.101n   0.140/51.911n   0.123/50.684n
R_load = 50.000
[Rising Waveform]
R_fixture= 50.000
V_fixture= 1.500
V_fixture_min= 1.430
V_fixture_max= 1.580
|time   V(typ)   V(min)   V(max)
0s        1.228V     1.196V     1.376V
5ns       1.231V     1.199V     1.376V
5.44ns    1.231V     1.199V     1.507V
5.97ns    1.231V     1.199V     1.557V
8.91ns    1.224V     1.199V     1.58V
9.57ns    1.451V     1.199V     1.58V
10.87ns   1.494V     1.195V     1.58V
11.47ns   1.497V     1.371V     1.58V
11.86ns   1.497V     1.4V       1.58V
200ns     1.5V       1.43V      1.58V
[Falling Waveform]
R_fixture= 50.000
V_fixture= 1.500
V_fixture_min= 1.430
V_fixture_max= 1.580
|time   V(typ)   V(min)   V(max)
0s        1.5V       1.43V      1.58V
960ps     1.5V       1.43V      1.58V
1.08ns    1.5V       1.43V      1.601V
1.49ns    1.516V     1.43V      1.581V
1.63ns    1.506V     1.43V      1.58V
9.63ns    1.5V       1.43V      1.566V
35.71ns   1.423V     1.392V     1.506V
91.68ns   1.236V     1.242V     1.38V
119.2ns   1.229V     1.199V     1.376V
200ns     1.228V     1.196V     1.376V
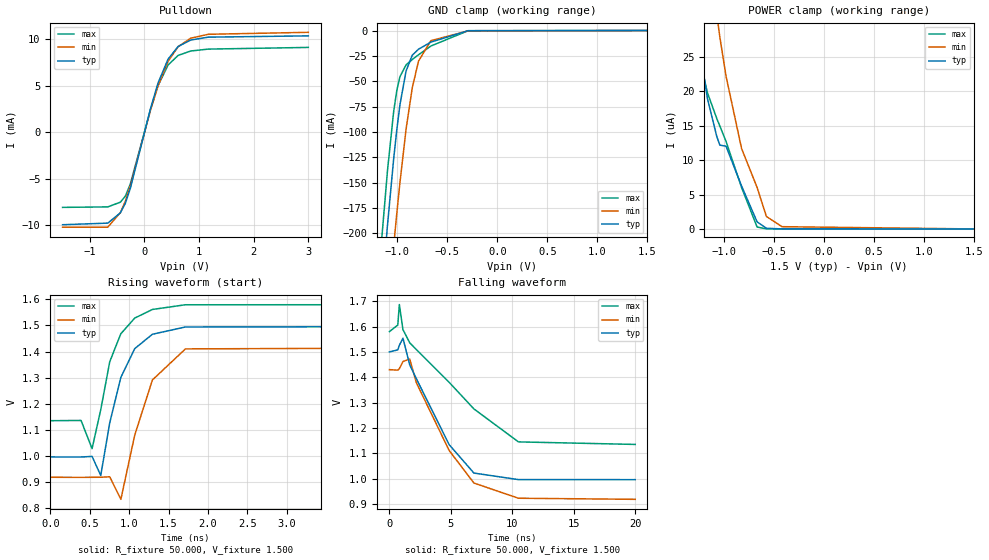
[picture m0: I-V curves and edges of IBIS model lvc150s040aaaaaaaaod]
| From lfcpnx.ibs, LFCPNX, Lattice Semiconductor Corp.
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[Model] lvc150s040aaaaaaaaod
Model_type I/O_open_drain
Polarity   Non-Inverting
Enable   Active-Low
Vinl =  0.375V
Vinh =  1.125V
Vmeas =  0.750V
Cref =  0.0F
Rref =  1.000M
Vref =  0.0V
C_comp   5.000pF   4.000pF   5.500pF
[Temperature Range]   25.000   0.125k   -40.000
[Voltage Range]   1.500V   1.430V   1.580V
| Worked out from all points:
|   slope of the pulldown table from 0 to 0.225 V, typ, clamps not added: 46.4 ohm
|   GND clamp passes 1 mA (typ) near -0.37 V on its own axis
|   rising waveform, R_fixture 50.000, V_fixture 1.500: 20-80 % time 309ps typ, 328ps min, 283ps max; typ from 0.996 V to 1.5 V
|   falling waveform, R_fixture 50.000, V_fixture 1.500: 20-80 % time 3.18ns typ, 3.37ns min, 5.31ns max; typ from 1.5 V to 0.996 V
[Pulldown]
|Voltage   I(typ)   I(min)   I(max)
-1.5V     -9.959mA   -10.22mA   -8.095mA
-672mV    -9.786mA   -10.22mA   -8.042mA
-442mV    -8.681mA   -8.663mA   -7.536mA
-350mV    -7.654mA   -7.424mA   -6.885mA
-258mV    -6.025mA   -5.761mA   -5.557mA
110mV     2.518mA    2.353mA    2.412mA
248mV     5.268mA    4.967mA    4.987mA
432mV     7.845mA    7.6mA      7.208mA
616mV     9.199mA    9.174mA    8.238mA
846mV     9.89mA     10.09mA    8.712mA
1.168V    10.2mA     10.51mA    8.917mA
3V        10.34mA    10.72mA    9.098mA
[GND_clamp]
|Voltage   I(typ)   I(min)   I(max)
-1.5V     -708.3mA   -763.4mA   -675.9mA
-1.159V   -265.1mA   -350.4mA   -211mA
-1.097V   -192.2mA   -279.7mA   -138.3mA
-1.035V   -126.5mA   -212.4mA   -79.79mA
-1.004V   -97.99mA   -180.6mA   -59.26mA
-973mV    -73.59mA   -150.5mA   -45.64mA
-911mV    -39.79mA   -97.15mA   -33.84mA
-849mV    -24.33mA   -56.34mA   -28.56mA
-787mV    -18.41mA   -30.2mA    -23.94mA
-663mV    -11.42mA   -9.983mA   -15.26mA
-291mV    -183uA     -342.4uA   -164.8uA
1.5V      0A         0A         0A
[POWER_clamp]
|Voltage   I(typ)   I(min)   I(max)
-1.5V     59.32uA    98.32uA    59.13uA
-1.29V    31.3uA     61.54uA    28.52uA
-1.259V   27.72uA    56.58uA    25.68uA
-1.166V   18.95uA    42.82uA    19.79uA
-1.073V   13.45uA    31.2uA     16.06uA
-1.042V   12.18uA    27.88uA    14.95uA
-980mV    12.02uA    22.18uA    12.71uA
-825mV    6.239uA    11.69uA    6.03uA
-670mV    1.028uA    6.028uA    280.6nA
-577mV    100.2nA    1.816uA    11.26nA
-422mV    7.758nA    331.2nA    690.7pA
1.5V      0A         0A         0A
[Ramp]
| variable   typ   min   max
dV/dt_r   0.302/0.271n   0.307/0.365n   0.267/4.892n
dV/dt_f   0.302/34.234n   0.307/35.148n   0.267/63.309n
R_load = 50.000
[Rising Waveform]
R_fixture = 50.000
V_fixture = 1.500
V_fixture_min = 1.430
V_fixture_max = 1.580
|  time   V(typ)   V(min)   V(max)
0s        996.1mV    918.4mV    1.135V
390ps     996mV      918mV      1.136V
530ps     998.2mV    918.3mV    1.028V
640ps     925.1mV    918.5mV    1.177V
754ps     1.127V     920.3mV    1.361V
895ps     1.301V     833.9mV    1.468V
1.071ns   1.411V     1.08V      1.528V
1.295ns   1.466V     1.291V     1.561V
1.714ns   1.494V     1.41V      1.579V
20ns      1.5V       1.43V      1.58V
[Falling Waveform]
R_fixture = 50.000
V_fixture = 1.500
V_fixture_min = 1.430
V_fixture_max = 1.580
|  time   V(typ)   V(min)   V(max)
0s        1.5V       1.43V      1.58V
680ps     1.508V     1.428V     1.606V
806ps     1.526V     1.434V     1.687V
1.1ns     1.554V     1.462V     1.588V
1.65ns    1.449V     1.472V     1.536V
2.194ns   1.394V     1.378V     1.509V
4.86ns    1.134V     1.111V     1.38V
6.875ns   1.022V     982.7mV    1.275V
10.5ns    996.2mV    922.7mV    1.145V
20ns      996.1mV    918.4mV    1.135V
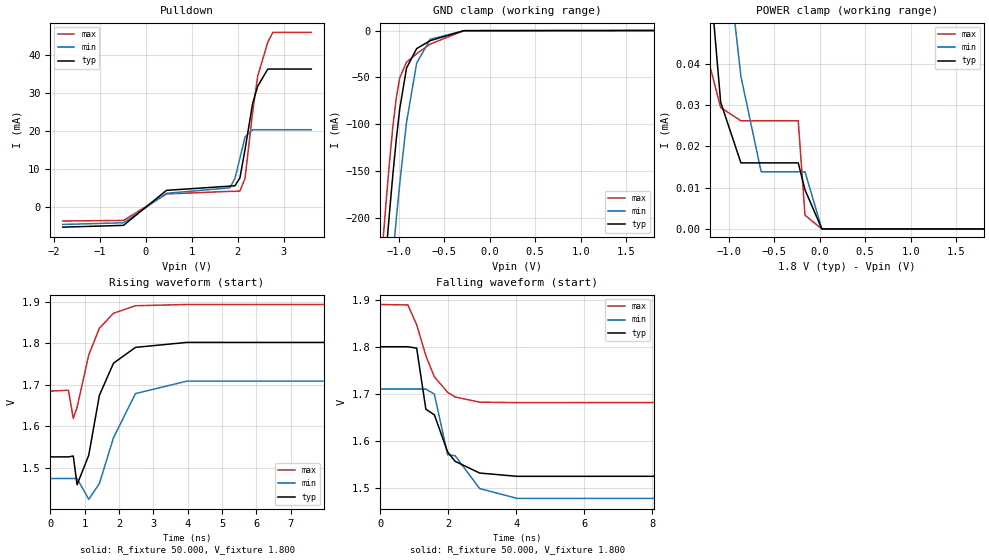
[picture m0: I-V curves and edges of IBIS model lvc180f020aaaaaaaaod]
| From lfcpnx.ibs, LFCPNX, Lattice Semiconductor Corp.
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|Model lvc180f020aaaaaaaaod
[Model] lvc180f020aaaaaaaaod
Model_type I/O_open_drain
Polarity   Non-Inverting
Enable   Active-Low
Vinl =  0.630V
Vinh =  1.170V
Vmeas =  0.900V
Cref =  0.0F
Rref = 10.00k
Vref = 1.80V
C_comp   5.000pF   4.000pF   5.500pF
[Temperature Range]   25.000   0.125k   -40.000
[Voltage Range]   1.800V   1.710V   1.890V
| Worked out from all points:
|   slope of the pulldown table from 0 to 0.27 V, typ, clamps not added: 87.4 ohm
|   GND clamp passes 1 mA (typ) near -0.37 V on its own axis
|   rising waveform, R_fixture 50.000, V_fixture 1.800: 20-80 % time 565ps typ, 578ps min, 542ps max; typ from 1.53 V to 1.8 V
|   falling waveform, R_fixture 50.000, V_fixture 1.800: 20-80 % time 777ps typ, 916ps min, 537ps max; typ from 1.8 V to 1.53 V
[Pulldown]
|Voltage   I(typ)   I(min)   I(max)
-1.8V     -5.304mA   -4.596mA   -3.689mA
-480mV    -4.834mA   -4.152mA   -3.535mA
455mV     4.364mA    3.581mA    3.408mA
1.83V     5.465mA    5.015mA    4.098mA
1.94V     5.548mA    7.447mA    4.098mA
2.05V     7.66mA     12.83mA    4.171mA
2.16V     15.07mA    18.38mA    7.503mA
2.325V    27.18mA    20.28mA    24.86mA
2.435V    31.69mA    20.28mA    34.3mA
2.655V    36.21mA    20.28mA    43.29mA
2.765V    36.21mA    20.28mA    45.85mA
3.6V      36.21mA    20.28mA    45.85mA
[GND_clamp]
|Voltage   I(typ)   I(min)   I(max)
-1.8V     -1.116A    -1.143A    -1.105A
-1.171V   -280mA     -364.7mA   -226.1mA
-1.134V   -235.4mA   -321.9mA   -180.7mA
-1.097V   -192.5mA   -280mA     -138.5mA
-1.06V    -152mA     -239.3mA   -101.1mA
-1.023V   -115.2mA   -200.2mA   -71.04mA
-986mV    -83.38mA   -163.2mA   -50.46mA
-912mV    -40.17mA   -98.13mA   -33.79mA
-801mV    -19.32mA   -34.94mA   -24.84mA
-653mV    -10.85mA   -9.3mA     -14.51mA
-283mV    -143.1uA   -288.3uA   -113.9uA
1.8V      0A         0A         0A
[POWER_clamp]
|Voltage   I(typ)   I(min)   I(max)
-1.8V     186.1uA    259.4uA    183.5uA
-1.382V   94.45uA    136.9uA    91.51uA
-1.345V   89.56uA    127.8uA    77.52uA
-1.308V   84.02uA    119.2uA    62.81uA
-1.234V   68.87uA    103.7uA    42uA
-1.086V   30.66uA    80.58uA    29.36uA
-864mV    15.99uA    36.93uA    26.17uA
-642mV    15.99uA    13.83uA    26.17uA
-235mV    15.99uA    13.83uA    26.17uA
-161mV    9.478uA    13.83uA    3.316uA
24mV      0A         0A         323.9pA
1.8V      0A         0A         0A
[Ramp]
| variable   typ   min   max
dV/dt_r   0.164/0.566n   0.141/0.581n   0.123/0.546n
dV/dt_f   0.164/0.781n   0.141/0.922n   0.123/0.764n
R_load = 50.000
[Rising Waveform]
R_fixture= 50.000
V_fixture= 1.800
V_fixture_min= 1.710
V_fixture_max= 1.890
|time   V(typ)   V(min)   V(max)
0s        1.527V     1.475V     1.685V
530ps     1.527V     1.475V     1.687V
670ps     1.529V     1.475V     1.619V
780ps     1.46V      1.475V     1.646V
1.12ns    1.531V     1.425V     1.772V
1.43ns    1.675V     1.463V     1.836V
1.84ns    1.752V     1.573V     1.872V
2.48ns    1.79V      1.679V     1.89V
3.98ns    1.802V     1.709V     1.893V
200ns     1.8V       1.71V      1.89V
[Falling Waveform]
R_fixture= 50.000
V_fixture= 1.800
V_fixture_min= 1.710
V_fixture_max= 1.890
|time   V(typ)   V(min)   V(max)
0s        1.8V       1.71V      1.89V
810ps     1.8V       1.71V      1.889V
1.07ns    1.797V     1.71V      1.847V
1.34ns    1.667V     1.71V      1.781V
1.59ns    1.655V     1.699V     1.736V
1.98ns    1.576V     1.57V      1.703V
2.2ns     1.556V     1.568V     1.693V
2.92ns    1.531V     1.498V     1.682V
4.02ns    1.524V     1.477V     1.681V
200ns     1.527V     1.475V     1.685V
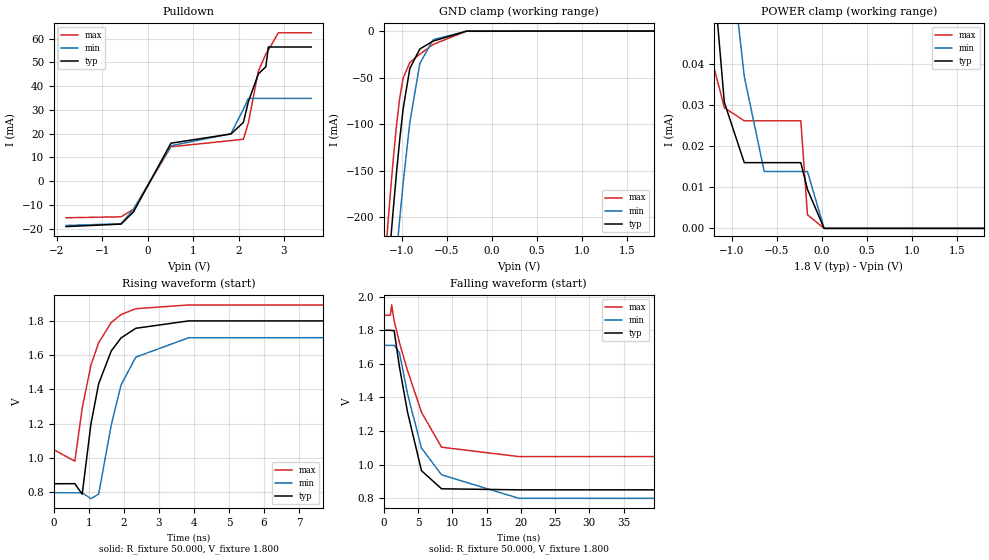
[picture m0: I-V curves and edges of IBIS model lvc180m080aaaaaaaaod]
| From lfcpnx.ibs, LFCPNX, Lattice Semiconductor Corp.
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[Model] lvc180m080aaaaaaaaod
Model_type I/O_open_drain
Polarity   Non-Inverting
Enable   Active-Low
Vinl =  0.630V
Vinh =  1.170V
Vmeas =  0.900V
Cref =  0.0F
Rref = 10.00k
Vref = 1.80V
C_comp   5.000pF   4.000pF   5.500pF
[Temperature Range]   25.000   0.125k   -40.000
[Voltage Range]   1.800V   1.710V   1.890V
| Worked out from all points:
|   slope of the pulldown table from 0 to 0.27 V, typ, clamps not added: 26.3 ohm
|   GND clamp passes 1 mA (typ) near -0.37 V on its own axis
|   rising waveform, R_fixture 50.000, V_fixture 1.800: 20-80 % time 635ps typ, 703ps min, 655ps max; typ from 0.85 V to 1.8 V
|   falling waveform, R_fixture 50.000, V_fixture 1.800: 20-80 % time 2.75ns typ, 4.31ns min, 4.14ns max; typ from 1.8 V to 0.85 V
[Pulldown]
|Voltage   I(typ)   I(min)   I(max)
-1.8V     -19.09mA   -18.61mA   -15.37mA
-590mV    -18.04mA   -17.89mA   -14.98mA
-315mV    -12.91mA   -11.86mA   -11.8mA
510mV     16.01mA    14.93mA    14.49mA
1.83V     19.86mA    19.99mA    17.09mA
2.105V    24.72mA    30.28mA    17.66mA
2.215V    33.46mA    34.85mA    24.58mA
2.435V    45.16mA    34.85mA    46.27mA
2.6V      48.16mA    34.85mA    53.54mA
2.655V    56.47mA    34.85mA    55.18mA
2.875V    56.47mA    34.85mA    62.44mA
3.6V      56.47mA    34.85mA    62.44mA
[GND_clamp]
|Voltage   I(typ)   I(min)   I(max)
-1.8V     -1.116A    -1.143A    -1.105A
-1.171V   -280mA     -364.7mA   -226.1mA
-1.134V   -235.4mA   -321.9mA   -180.7mA
-1.097V   -192.5mA   -280mA     -138.5mA
-1.06V    -152mA     -239.3mA   -101.1mA
-1.023V   -115.2mA   -200.2mA   -71.04mA
-986mV    -83.38mA   -163.2mA   -50.46mA
-912mV    -40.17mA   -98.13mA   -33.79mA
-801mV    -19.32mA   -34.94mA   -24.84mA
-653mV    -10.85mA   -9.3mA     -14.51mA
-283mV    -143.1uA   -288.3uA   -113.9uA
1.8V      0A         0A         0A
[POWER_clamp]
|Voltage   I(typ)   I(min)   I(max)
-1.8V     186.1uA    259.4uA    183.5uA
-1.382V   94.45uA    136.9uA    91.51uA
-1.345V   89.56uA    127.8uA    77.52uA
-1.308V   84.02uA    119.2uA    62.81uA
-1.234V   68.87uA    103.7uA    42uA
-1.086V   30.66uA    80.58uA    29.36uA
-864mV    15.99uA    36.93uA    26.17uA
-642mV    15.99uA    13.83uA    26.17uA
-235mV    15.99uA    13.83uA    26.17uA
-161mV    9.478uA    13.83uA    3.316uA
24mV      0A         0A         323.9pA
1.8V      0A         0A         0A
[Ramp]
| variable   typ   min   max
dV/dt_r   0.570/0.634n   0.548/0.704n   0.505/0.655n
dV/dt_f   0.570/2.740n   0.548/4.299n   0.505/4.138n
R_load = 50.000
[Rising Waveform]
R_fixture= 50.000
V_fixture= 1.800
V_fixture_min= 1.710
V_fixture_max= 1.890
|time   V(typ)   V(min)   V(max)
0s        849.9mV    797.2mV    1.048V
600ps     850.4mV    797.1mV    981.3mV
810ps     789.2mV    797.4mV    1.29V
1.06ns    1.198V     762.9mV    1.541V
1.28ns    1.432V     789.9mV    1.671V
1.64ns    1.623V     1.192V     1.789V
1.92ns    1.699V     1.425V     1.835V
2.34ns    1.755V     1.587V     1.869V
3.85ns    1.798V     1.7V       1.891V
200ns     1.8V       1.71V      1.89V
[Falling Waveform]
R_fixture= 50.000
V_fixture= 1.800
V_fixture_min= 1.710
V_fixture_max= 1.890
|time   V(typ)   V(min)   V(max)
0s        1.8V       1.71V      1.89V
940ps     1.8V       1.71V      1.89V
1.13ns    1.799V     1.71V      1.951V
1.49ns    1.798V     1.71V      1.856V
2.26ns    1.583V     1.667V     1.726V
3.44ns    1.314V     1.423V     1.561V
5.48ns    964.2mV    1.099V     1.312V
8.41ns    856.2mV    939.6mV    1.104V
19.7ns    850mV      799.5mV    1.048V
200ns     849.9mV    797.2mV    1.048V
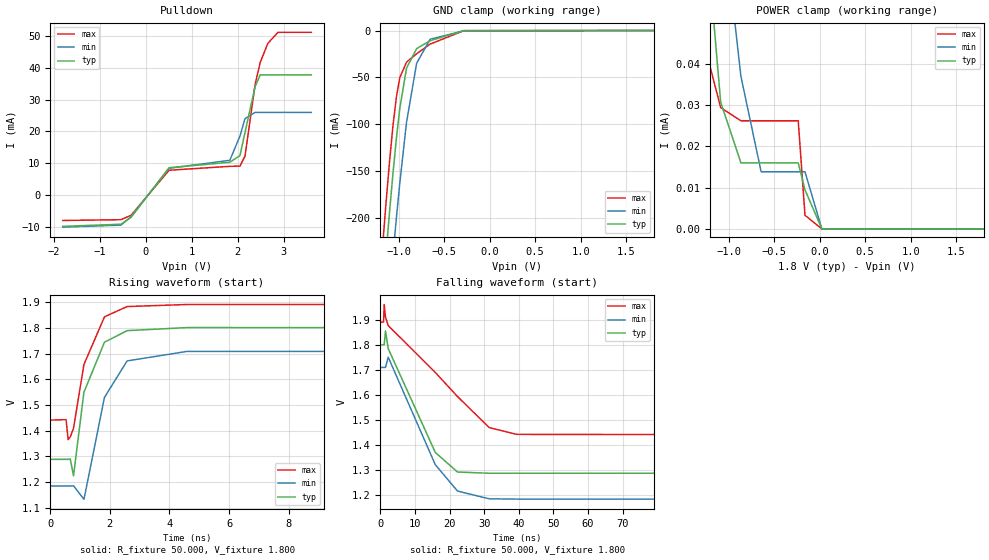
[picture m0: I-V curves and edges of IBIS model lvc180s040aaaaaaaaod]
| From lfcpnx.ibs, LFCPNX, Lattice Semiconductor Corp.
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[Model] lvc180s040aaaaaaaaod
Model_type I/O_open_drain
Polarity   Non-Inverting
Enable   Active-Low
Vinl =  0.630V
Vinh =  1.170V
Vmeas =  0.900V
Cref =  0.0F
Rref = 10.00k
Vref = 1.80V
C_comp   5.000pF   4.000pF   5.500pF
[Temperature Range]   25.000   0.125k   -40.000
[Voltage Range]   1.800V   1.710V   1.890V
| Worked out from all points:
|   slope of the pulldown table from 0 to 0.27 V, typ, clamps not added: 47.9 ohm
|   GND clamp passes 1 mA (typ) near -0.37 V on its own axis
|   rising waveform, R_fixture 50.000, V_fixture 1.800: 20-80 % time 617ps typ, 711ps min, 584ps max; typ from 1.29 V to 1.8 V
|   falling waveform, R_fixture 50.000, V_fixture 1.800: 20-80 % time 9.9ns typ, 10.4ns min, 18.5ns max; typ from 1.8 V to 1.29 V
[Pulldown]
|Voltage   I(typ)   I(min)   I(max)
-1.8V     -9.951mA   -10.2mA    -8.096mA
-535mV    -9.284mA   -9.549mA   -7.845mA
-315mV    -7.107mA   -6.858mA   -6.464mA
510mV     8.544mA    8.371mA    7.755mA
1.83V     10.28mA    10.89mA    8.991mA
2.05V     12.37mA    18.55mA    9.057mA
2.16V     19.68mA    24.04mA    12.22mA
2.38V     34.2mA     26.02mA    34.88mA
2.49V     37.85mA    26.02mA    41.76mA
2.655V    37.85mA    26.02mA    47.77mA
2.875V    37.85mA    26.02mA    51.27mA
3.6V      37.85mA    26.02mA    51.27mA
[GND_clamp]
|Voltage   I(typ)   I(min)   I(max)
-1.8V     -1.116A    -1.143A    -1.105A
-1.171V   -280mA     -364.7mA   -226.1mA
-1.134V   -235.4mA   -321.9mA   -180.7mA
-1.097V   -192.5mA   -280mA     -138.5mA
-1.06V    -152mA     -239.3mA   -101.1mA
-1.023V   -115.2mA   -200.2mA   -71.04mA
-986mV    -83.38mA   -163.2mA   -50.46mA
-912mV    -40.17mA   -98.13mA   -33.79mA
-801mV    -19.32mA   -34.94mA   -24.84mA
-653mV    -10.85mA   -9.3mA     -14.51mA
-283mV    -143.1uA   -288.3uA   -113.9uA
1.8V      0A         0A         0A
[POWER_clamp]
|Voltage   I(typ)   I(min)   I(max)
-1.8V     186.1uA    259.4uA    183.5uA
-1.382V   94.45uA    136.9uA    91.51uA
-1.345V   89.56uA    127.8uA    77.52uA
-1.308V   84.02uA    119.2uA    62.81uA
-1.234V   68.87uA    103.7uA    42uA
-1.086V   30.66uA    80.58uA    29.36uA
-864mV    15.99uA    36.93uA    26.17uA
-642mV    15.99uA    13.83uA    26.17uA
-235mV    15.99uA    13.83uA    26.17uA
-161mV    9.478uA    13.83uA    3.316uA
24mV      0A         0A         323.9pA
1.8V      0A         0A         0A
[Ramp]
| variable   typ   min   max
dV/dt_r   0.307/0.616n   0.315/0.712n   0.269/0.583n
dV/dt_f   0.307/9.948n   0.315/10.463n   0.269/18.468n
R_load = 50.000
[Rising Waveform]
R_fixture= 50.000
V_fixture= 1.800
V_fixture_min= 1.710
V_fixture_max= 1.890
|time   V(typ)   V(min)   V(max)
0s        1.288V     1.184V     1.441V
530ps     1.288V     1.184V     1.443V
600ps     1.288V     1.184V     1.365V
670ps     1.29V      1.184V     1.375V
780ps     1.224V     1.185V     1.409V
1.13ns    1.55V      1.132V     1.658V
1.82ns    1.745V     1.53V      1.844V
2.58ns    1.79V      1.672V     1.884V
4.59ns    1.802V     1.709V     1.892V
200ns     1.8V       1.71V      1.89V
[Falling Waveform]
R_fixture= 50.000
V_fixture= 1.800
V_fixture_min= 1.710
V_fixture_max= 1.890
|time   V(typ)   V(min)   V(max)
0s        1.8V       1.71V      1.89V
950ps     1.8V       1.71V      1.891V
1.13ns    1.8V       1.71V      1.961V
1.51ns    1.855V     1.71V      1.911V
2.29ns    1.785V     1.751V     1.877V
15.9ns    1.371V     1.322V     1.69V
22.3ns    1.293V     1.217V     1.594V
31.48ns   1.288V     1.186V     1.47V
39.5ns    1.288V     1.185V     1.443V
200ns     1.288V     1.184V     1.441V
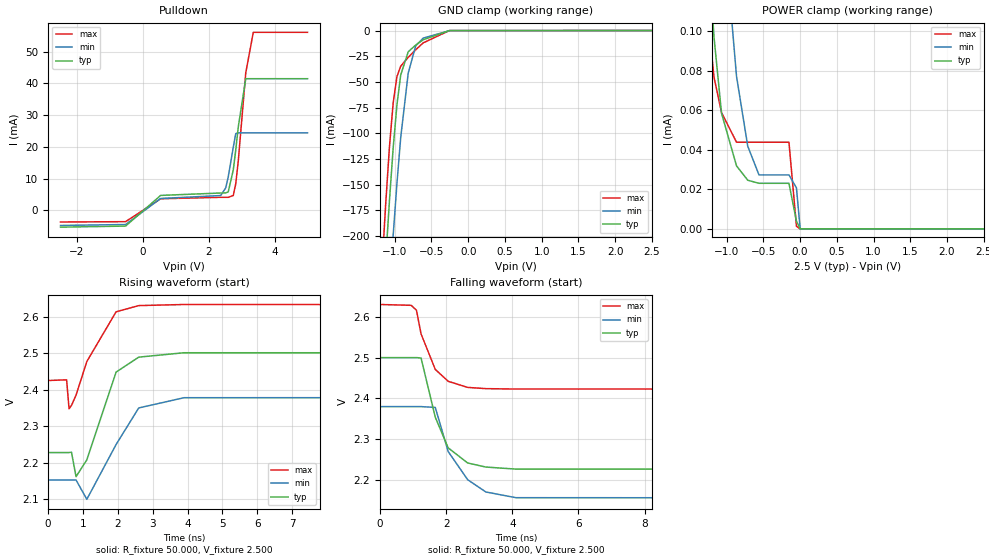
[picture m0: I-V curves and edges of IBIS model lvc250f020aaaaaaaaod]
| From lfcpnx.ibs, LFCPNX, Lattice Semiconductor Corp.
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[Model] lvc250f020aaaaaaaaod
Model_type I/O_open_drain
Polarity   Non-Inverting
Enable   Active-Low
Vinl =  0.700V
Vinh =  1.700V
Vmeas =  1.250V
Cref =  0.0F
Rref = 10.00k
Vref = 2.50V
C_comp   5.000pF   4.000pF   5.500pF
[Temperature Range]   25.000   0.125k   -40.000
[Voltage Range]   2.500V   2.380V   2.630V
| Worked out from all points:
|   slope of the pulldown table from 0 to 0.375 V, typ, clamps not added: 96.1 ohm
|   GND clamp passes 1 mA (typ) near -0.37 V on its own axis
|   rising waveform, R_fixture 50.000, V_fixture 2.500: 20-80 % time 543ps typ, 584ps min, 526ps max; typ from 2.23 V to 2.5 V
|   falling waveform, R_fixture 50.000, V_fixture 2.500: 20-80 % time 667ps typ, 856ps min, 550ps max; typ from 2.5 V to 2.23 V
[Pulldown]
|Voltage   I(typ)   I(min)   I(max)
-2.5V     -5.323mA   -4.785mA   -3.693mA
-524mV    -4.982mA   -4.494mA   -3.592mA
540mV     4.69mA     3.724mA    3.631mA
2.364V    5.449mA    4.651mA    4.093mA
2.516V    5.475mA    7.085mA    4.094mA
2.592V    5.808mA    10.53mA    4.095mA
2.744V    12.67mA    19.82mA    4.649mA
2.82V     19.03mA    24.18mA    8.358mA
2.896V    26.26mA    24.42mA    15.48mA
3.124V    41.51mA    24.42mA    43.36mA
3.352V    41.51mA    24.42mA    56.14mA
5V        41.51mA    24.42mA    56.14mA
[GND_clamp]
|Voltage   I(typ)   I(min)   I(max)
-2.5V     -2.083A    -2.046A    -2.12A
-1.174V   -284.5mA   -369.1mA   -230.6mA
-1.123V   -223.1mA   -310.2mA   -168.4mA
-1.072V   -165.5mA   -253.2mA   -113.1mA
-1.021V   -114mA     -199mA     -70.14mA
-970mV    -72.1mA    -148.7mA   -44.84mA
-919mV    -43.36mA   -104.3mA   -34.74mA
-817mV    -20.74mA   -41.58mA   -26.14mA
-715mV    -14.15mA   -15.01mA   -18.79mA
-613mV    -8.979mA   -7.374mA   -12.03mA
-256mV    -63.28uA   -178.3uA   -38.35uA
2.5V      0A         0A         0A
[POWER_clamp]
|Voltage   I(typ)   I(min)   I(max)
-2.5V     883.5uA    947.3uA    1.04mA
-1.376V   201.4uA    282.2uA    185.4uA
-1.274V   155.2uA    239.1uA    113.4uA
-1.172V   96.76uA    201.8uA    76.65uA
-1.07V    58.5uA     166.3uA    58.8uA
-866mV    31.91uA    77.15uA    43.85uA
-713mV    24.63uA    41.8uA     43.85uA
-560mV    23.08uA    27.31uA    43.85uA
-152mV    23.08uA    27.31uA    43.85uA
-50mV     3.959uA    20.74uA    1.391uA
1mV       0A         1.294nA    0A
2.5V      0A         0A         0A
[Ramp]
| variable   typ   min   max
dV/dt_r   0.163/0.546n   0.136/0.588n   0.123/0.529n
dV/dt_f   0.163/0.672n   0.136/0.858n   0.123/0.556n
R_load = 50.000
[Rising Waveform]
R_fixture= 50.000
V_fixture= 2.500
V_fixture_min= 2.380
V_fixture_max= 2.630
|time   V(typ)   V(min)   V(max)
0s        2.228V     2.153V     2.425V
530ps     2.228V     2.153V     2.427V
600ps     2.228V     2.153V     2.348V
670ps     2.229V     2.153V     2.357V
800ps     2.162V     2.153V     2.385V
1.11ns    2.208V     2.1V       2.477V
1.95ns    2.448V     2.25V      2.613V
2.6ns     2.489V     2.35V      2.63V
3.9ns     2.501V     2.378V     2.633V
200ns     2.5V       2.38V      2.63V
[Falling Waveform]
R_fixture= 50.000
V_fixture= 2.500
V_fixture_min= 2.380
V_fixture_max= 2.630
|time   V(typ)   V(min)   V(max)
0s        2.5V       2.38V      2.63V
940ps     2.5V       2.38V      2.628V
1.1ns     2.5V       2.38V      2.616V
1.24ns    2.499V     2.38V      2.558V
1.67ns    2.354V     2.378V     2.471V
2.06ns    2.279V     2.27V      2.442V
2.65ns    2.242V     2.201V     2.427V
3.2ns     2.232V     2.171V     2.424V
4.11ns    2.227V     2.157V     2.423V
200ns     2.228V     2.153V     2.425V
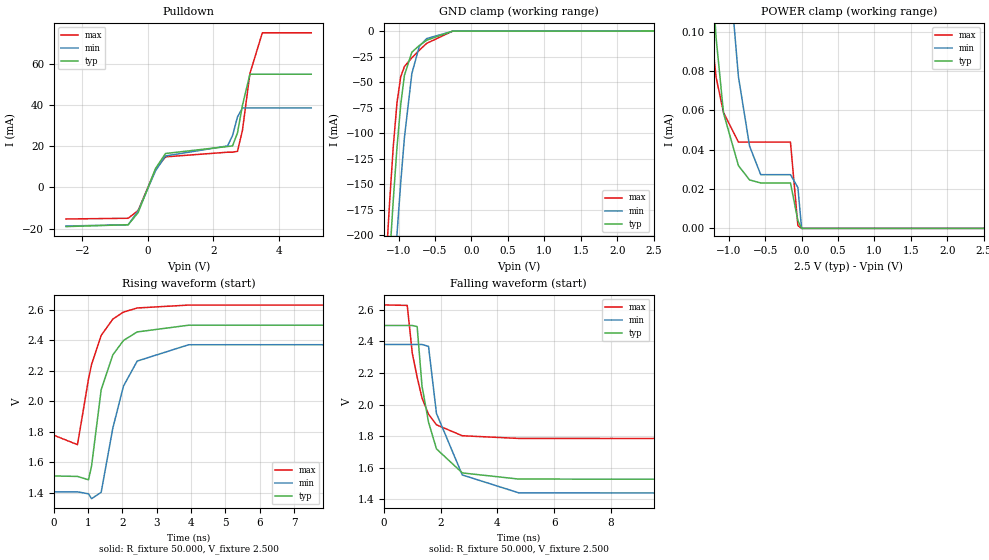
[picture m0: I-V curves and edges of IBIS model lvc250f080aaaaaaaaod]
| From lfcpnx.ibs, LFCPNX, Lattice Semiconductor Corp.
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[Model] lvc250f080aaaaaaaaod
Model_type I/O_open_drain
Polarity   Non-Inverting
Enable   Active-Low
Vinl =  0.700V
Vinh =  1.700V
Vmeas =  1.250V
Cref =  0.0F
Rref = 10.00k
Vref = 2.50V
C_comp   5.000pF   4.000pF   5.500pF
[Temperature Range]   25.000   0.125k   -40.000
[Voltage Range]   2.500V   2.380V   2.630V
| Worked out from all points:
|   slope of the pulldown table from 0 to 0.375 V, typ, clamps not added: 28.4 ohm
|   GND clamp passes 1 mA (typ) near -0.37 V on its own axis
|   rising waveform, R_fixture 50.000, V_fixture 2.500: 20-80 % time 561ps typ, 656ps min, 607ps max; typ from 1.51 V to 2.5 V
|   falling waveform, R_fixture 50.000, V_fixture 2.500: 20-80 % time 637ps typ, 864ps min, 631ps max; typ from 2.5 V to 1.51 V
[Pulldown]
|Voltage   I(typ)   I(min)   I(max)
-2.5V     -19.07mA   -18.79mA   -15.38mA
-600mV    -18.15mA   -18.19mA   -15.02mA
-296mV    -12.29mA   -11.42mA   -11.28mA
236mV     9.129mA    8.011mA    8.694mA
540mV     16.45mA    15.25mA    14.82mA
2.44V     19.85mA    20.13mA    17.08mA
2.592V    20.13mA    25.16mA    17.09mA
2.744V    26.51mA    34.27mA    17.51mA
2.896V    39.9mA     38.58mA    27.75mA
3.124V    54.98mA    38.58mA    55.37mA
3.504V    54.98mA    38.58mA    75.1mA
5V        54.98mA    38.58mA    75.1mA
[GND_clamp]
|Voltage   I(typ)   I(min)   I(max)
-2.5V     -2.083A    -2.046A    -2.12A
-1.174V   -284.5mA   -369.1mA   -230.6mA
-1.123V   -223.1mA   -310.2mA   -168.4mA
-1.072V   -165.5mA   -253.2mA   -113.1mA
-1.021V   -114mA     -199mA     -70.14mA
-970mV    -72.1mA    -148.7mA   -44.84mA
-919mV    -43.36mA   -104.3mA   -34.74mA
-817mV    -20.74mA   -41.58mA   -26.14mA
-715mV    -14.15mA   -15.01mA   -18.79mA
-613mV    -8.979mA   -7.374mA   -12.03mA
-256mV    -63.28uA   -178.3uA   -38.35uA
2.5V      0A         0A         0A
[POWER_clamp]
|Voltage   I(typ)   I(min)   I(max)
-2.5V     883.5uA    947.3uA    1.04mA
-1.376V   201.4uA    282.2uA    185.5uA
-1.274V   155.2uA    239.1uA    113.4uA
-1.172V   96.76uA    201.8uA    76.69uA
-1.07V    58.5uA     166.3uA    58.84uA
-866mV    31.91uA    77.15uA    43.87uA
-713mV    24.63uA    41.8uA     43.87uA
-560mV    23.08uA    27.31uA    43.87uA
-152mV    23.08uA    27.31uA    43.87uA
-50mV     3.959uA    20.74uA    1.391uA
1mV       0A         1.294nA    0A
2.5V      0A         0A         0A
[Ramp]
| variable   typ   min   max
dV/dt_r   0.595/0.561n   0.585/0.656n   0.512/0.608n
dV/dt_f   0.595/0.640n   0.585/0.865n   0.512/0.635n
R_load = 50.000
[Rising Waveform]
R_fixture= 50.000
V_fixture= 2.500
V_fixture_min= 2.380
V_fixture_max= 2.630
|time   V(typ)   V(min)   V(max)
0s        1.509V     1.405V     1.776V
690ps     1.506V     1.405V     1.714V
1.01ns    1.484V     1.392V     2.143V
1.1ns     1.574V     1.36V      2.24V
1.38ns    2.074V     1.402V     2.43V
1.72ns    2.303V     1.823V     2.537V
2.03ns    2.397V     2.098V     2.583V
2.43ns    2.453V     2.262V     2.61V
3.93ns    2.497V     2.369V     2.629V
200ns     2.5V       2.38V      2.63V
[Falling Waveform]
R_fixture= 50.000
V_fixture= 2.500
V_fixture_min= 2.380
V_fixture_max= 2.630
|time   V(typ)   V(min)   V(max)
0s        2.5V       2.38V      2.63V
820ps     2.5V       2.38V      2.627V
1ns       2.5V       2.38V      2.323V
1.17ns    2.493V     2.38V      2.173V
1.34ns    2.118V     2.38V      2.042V
1.57ns    1.889V     2.368V     1.939V
1.85ns    1.72V      1.944V     1.872V
2.76ns    1.568V     1.555V     1.803V
4.75ns    1.529V     1.442V     1.786V
200ns     1.509V     1.405V     1.776V
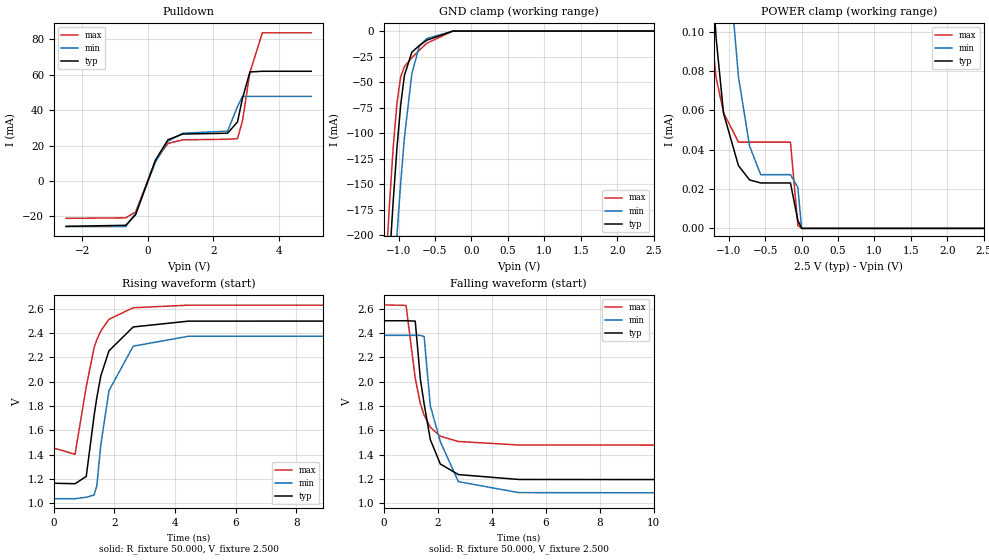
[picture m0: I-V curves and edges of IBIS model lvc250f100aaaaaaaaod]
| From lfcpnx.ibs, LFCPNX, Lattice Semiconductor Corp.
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[Model] lvc250f100aaaaaaaaod
Model_type I/O_open_drain
Polarity   Non-Inverting
Enable   Active-Low
Vinl =  0.700V
Vinh =  1.700V
Vmeas =  1.250V
Cref =  0.0F
Rref = 10.00k
Vref = 2.50V
C_comp   5.000pF   4.000pF   5.500pF
[Temperature Range]   25.000   0.125k   -40.000
[Voltage Range]   2.500V   2.380V   2.630V
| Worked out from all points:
|   slope of the pulldown table from 0 to 0.375 V, typ, clamps not added: 21.6 ohm
|   GND clamp passes 1 mA (typ) near -0.37 V on its own axis
|   rising waveform, R_fixture 50.000, V_fixture 2.500: 20-80 % time 618ps typ, 567ps min, 620ps max; typ from 1.17 V to 2.5 V
|   falling waveform, R_fixture 50.000, V_fixture 2.500: 20-80 % time 572ps typ, 782ps min, 616ps max; typ from 2.5 V to 1.17 V
[Pulldown]
|Voltage   I(typ)   I(min)   I(max)
-2.5V     -25.71mA   -25.85mA   -21.18mA
-676mV    -25.12mA   -25.85mA   -20.89mA
-372mV    -19.11mA   -18.27mA   -17.57mA
236mV     11.85mA    10.67mA    11.57mA
616mV     23.26mA    22.44mA    21.17mA
1.072V    26.51mA    26.97mA    23.23mA
2.44V     26.96mA    28.15mA    23.55mA
2.744V    33.36mA    42.02mA    23.93mA
2.896V    46.65mA    47.8mA     33.86mA
3.124V    61.63mA    47.8mA     61.35mA
3.504V    62.02mA    47.8mA     83.77mA
5V        62.02mA    47.8mA     83.77mA
[GND_clamp]
|Voltage   I(typ)   I(min)   I(max)
-2.5V     -2.083A    -2.046A    -2.12A
-1.174V   -284.5mA   -369.1mA   -230.6mA
-1.123V   -223.1mA   -310.2mA   -168.4mA
-1.072V   -165.5mA   -253.2mA   -113.1mA
-1.021V   -114mA     -199mA     -70.14mA
-970mV    -72.1mA    -148.7mA   -44.84mA
-919mV    -43.36mA   -104.3mA   -34.74mA
-817mV    -20.74mA   -41.58mA   -26.14mA
-715mV    -14.15mA   -15.01mA   -18.79mA
-613mV    -8.979mA   -7.374mA   -12.03mA
-256mV    -63.28uA   -178.3uA   -38.35uA
2.5V      0A         0A         0A
[POWER_clamp]
|Voltage   I(typ)   I(min)   I(max)
-2.5V     883.5uA    947.3uA    1.04mA
-1.376V   201.4uA    282.2uA    185.4uA
-1.274V   155.2uA    239.1uA    113.4uA
-1.172V   96.76uA    201.8uA    76.65uA
-1.07V    58.5uA     166.3uA    58.8uA
-866mV    31.91uA    77.15uA    43.85uA
-713mV    24.63uA    41.8uA     43.85uA
-560mV    23.08uA    27.31uA    43.85uA
-152mV    23.08uA    27.31uA    43.85uA
-50mV     3.959uA    20.74uA    1.391uA
1mV       0A         1.294nA    0A
2.5V      0A         0A         0A
[Ramp]
| variable   typ   min   max
dV/dt_r   0.801/0.617n   0.805/0.571n   0.706/0.621n
dV/dt_f   0.801/0.575n   0.805/0.783n   0.706/0.620n
R_load = 50.000
[Rising Waveform]
R_fixture= 50.000
V_fixture= 2.500
V_fixture_min= 2.380
V_fixture_max= 2.630
|time   V(typ)   V(min)   V(max)
0s        1.165V     1.038V     1.454V
700ps     1.161V     1.038V     1.403V
1.07ns    1.221V     1.05V      1.958V
1.33ns    1.722V     1.068V     2.279V
1.42ns    1.87V      1.145V     2.344V
1.55ns    2.046V     1.48V      2.416V
1.82ns    2.253V     1.926V     2.512V
2.62ns    2.449V     2.291V     2.607V
4.45ns    2.497V     2.373V     2.628V
200ns     2.5V       2.38V      2.63V
[Falling Waveform]
R_fixture= 50.000
V_fixture= 2.500
V_fixture_min= 2.380
V_fixture_max= 2.630
|time   V(typ)   V(min)   V(max)
0s        2.5V       2.38V      2.63V
820ps     2.5V       2.38V      2.626V
1.16ns    2.497V     2.38V      2.028V
1.35ns    2.021V     2.38V      1.819V
1.49ns    1.817V     2.37V      1.724V
1.72ns    1.523V     1.8V       1.625V
2.09ns    1.323V     1.507V     1.551V
2.76ns    1.236V     1.178V     1.508V
5ns       1.196V     1.088V     1.479V
200ns     1.165V     1.038V     1.454V
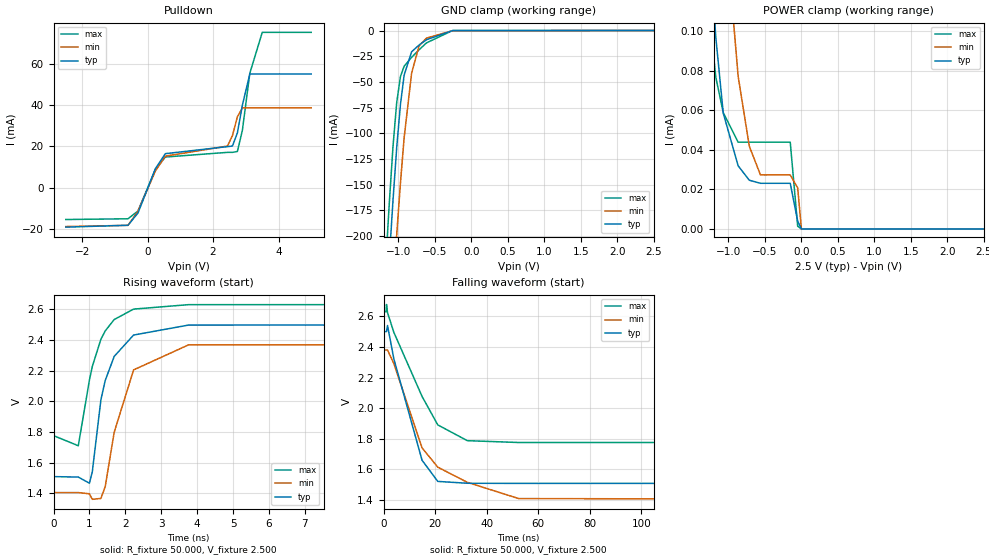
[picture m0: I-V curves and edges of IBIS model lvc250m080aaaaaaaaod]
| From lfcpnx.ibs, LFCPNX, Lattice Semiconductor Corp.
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[Model] lvc250m080aaaaaaaaod
Model_type I/O_open_drain
Polarity   Non-Inverting
Enable   Active-Low
Vinl =  0.700V
Vinh =  1.700V
Vmeas =  1.250V
Cref =  0.0F
Rref = 10.00k
Vref = 2.50V
C_comp   5.000pF   4.000pF   5.500pF
[Temperature Range]   25.000   0.125k   -40.000
[Voltage Range]   2.500V   2.380V   2.630V
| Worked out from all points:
|   slope of the pulldown table from 0 to 0.375 V, typ, clamps not added: 28.4 ohm
|   GND clamp passes 1 mA (typ) near -0.37 V on its own axis
|   rising waveform, R_fixture 50.000, V_fixture 2.500: 20-80 % time 562ps typ, 651ps min, 600ps max; typ from 1.51 V to 2.5 V
|   falling waveform, R_fixture 50.000, V_fixture 2.500: 20-80 % time 9.68ns typ, 16.5ns min, 14.1ns max; typ from 2.5 V to 1.51 V
[Pulldown]
|Voltage   I(typ)   I(min)   I(max)
-2.5V     -19.07mA   -18.79mA   -15.38mA
-600mV    -18.15mA   -18.19mA   -15.02mA
-296mV    -12.29mA   -11.42mA   -11.28mA
236mV     9.129mA    8.011mA    8.694mA
540mV     16.45mA    15.25mA    14.82mA
2.44V     19.85mA    20.13mA    17.08mA
2.592V    20.13mA    25.16mA    17.09mA
2.744V    26.51mA    34.27mA    17.51mA
2.896V    39.9mA     38.58mA    27.75mA
3.124V    54.98mA    38.58mA    55.37mA
3.504V    54.98mA    38.58mA    75.1mA
5V        54.98mA    38.58mA    75.1mA
[GND_clamp]
|Voltage   I(typ)   I(min)   I(max)
-2.5V     -2.083A    -2.046A    -2.12A
-1.174V   -284.5mA   -369.1mA   -230.6mA
-1.123V   -223.1mA   -310.2mA   -168.4mA
-1.072V   -165.5mA   -253.2mA   -113.1mA
-1.021V   -114mA     -199mA     -70.14mA
-970mV    -72.1mA    -148.7mA   -44.84mA
-919mV    -43.36mA   -104.3mA   -34.74mA
-817mV    -20.74mA   -41.58mA   -26.14mA
-715mV    -14.15mA   -15.01mA   -18.79mA
-613mV    -8.979mA   -7.374mA   -12.03mA
-256mV    -63.28uA   -178.3uA   -38.35uA
2.5V      0A         0A         0A
[POWER_clamp]
|Voltage   I(typ)   I(min)   I(max)
-2.5V     883.5uA    947.3uA    1.04mA
-1.376V   201.4uA    282.2uA    185.4uA
-1.274V   155.2uA    239.1uA    113.4uA
-1.172V   96.76uA    201.8uA    76.65uA
-1.07V    58.5uA     166.3uA    58.8uA
-866mV    31.91uA    77.15uA    43.85uA
-713mV    24.63uA    41.8uA     43.85uA
-560mV    23.08uA    27.31uA    43.85uA
-152mV    23.08uA    27.31uA    43.85uA
-50mV     3.959uA    20.74uA    1.391uA
1mV       0A         1.294nA    0A
2.5V      0A         0A         0A
[Ramp]
| variable   typ   min   max
dV/dt_r   0.595/0.562n   0.585/0.651n   0.512/0.600n
dV/dt_f   0.595/9.750n   0.585/16.410n   0.512/14.137n
R_load = 50.000
[Rising Waveform]
R_fixture= 50.000
V_fixture= 2.500
V_fixture_min= 2.380
V_fixture_max= 2.630
|time   V(typ)   V(min)   V(max)
0s        1.509V     1.405V     1.776V
690ps     1.506V     1.405V     1.71V
1ns       1.466V     1.397V     2.138V
1.08ns    1.54V      1.361V     2.226V
1.32ns    2.01V      1.367V     2.404V
1.44ns    2.135V     1.444V     2.458V
1.69ns    2.292V     1.798V     2.532V
2.23ns    2.431V     2.204V     2.6V
3.76ns    2.496V     2.367V     2.629V
200ns     2.5V       2.38V      2.63V
[Falling Waveform]
R_fixture= 50.000
V_fixture= 2.500
V_fixture_min= 2.380
V_fixture_max= 2.630
|time   V(typ)   V(min)   V(max)
0s        2.5V       2.38V      2.63V
960ps     2.5V       2.38V      2.63V
1.11ns    2.5V       2.38V      2.677V
1.5ns     2.54V      2.38V      2.624V
3.96ns    2.322V     2.291V     2.495V
14.9ns    1.66V      1.741V     2.077V
21ns      1.522V     1.615V     1.891V
32.46ns   1.51V      1.516V     1.788V
52.37ns   1.509V     1.41V      1.776V
200ns     1.509V     1.405V     1.776V
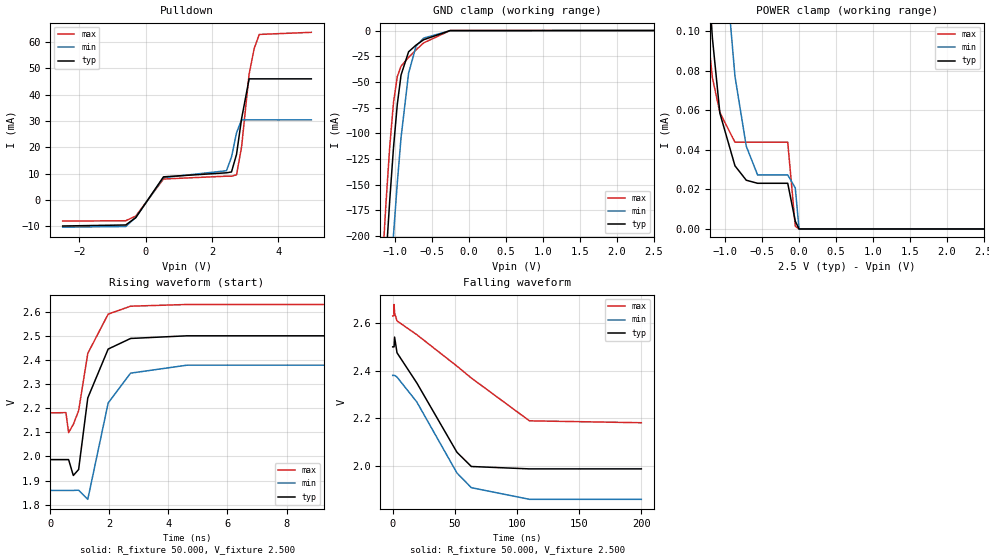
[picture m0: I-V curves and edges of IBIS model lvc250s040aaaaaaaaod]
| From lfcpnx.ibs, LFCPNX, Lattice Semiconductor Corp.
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[Model] lvc250s040aaaaaaaaod
Model_type I/O_open_drain
Polarity   Non-Inverting
Enable   Active-Low
Vinl =  0.700V
Vinh =  1.700V
Vmeas =  1.250V
Cref =  0.0F
Rref = 10.00k
Vref = 2.50V
C_comp   5.000pF   4.000pF   5.500pF
[Temperature Range]   25.000   0.125k   -40.000
[Voltage Range]   2.500V   2.380V   2.630V
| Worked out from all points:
|   slope of the pulldown table from 0 to 0.375 V, typ, clamps not added: 52.3 ohm
|   GND clamp passes 1 mA (typ) near -0.37 V on its own axis
|   rising waveform, R_fixture 50.000, V_fixture 2.500: 20-80 % time 573ps typ, 679ps min, 549ps max; typ from 1.99 V to 2.5 V
|   falling waveform, R_fixture 50.000, V_fixture 2.500: 20-80 % time 33.8ns typ, 34.1ns min, 63.3ns max; typ from 2.5 V to 1.99 V
[Pulldown]
|Voltage   I(typ)   I(min)   I(max)
-2.5V     -9.968mA   -10.41mA   -8.099mA
-600mV    -9.584mA   -10.17mA   -7.969mA
-296mV    -6.793mA   -6.699mA   -6.199mA
540mV     8.739mA    8.437mA    7.912mA
2.44V     10.27mA    11.06mA    8.988mA
2.592V    10.6mA     16.27mA    8.989mA
2.744V    17.3mA     25.49mA    9.493mA
2.896V    30.83mA    30.42mA    20.1mA
3.124V    46.02mA    30.42mA    47.88mA
3.276V    46.02mA    30.42mA    57.54mA
3.428V    46.02mA    30.42mA    62.93mA
5V        46.02mA    30.42mA    63.73mA
[GND_clamp]
|Voltage   I(typ)   I(min)   I(max)
-2.5V     -2.083A    -2.046A    -2.12A
-1.174V   -284.5mA   -369.1mA   -230.6mA
-1.123V   -223.1mA   -310.2mA   -168.4mA
-1.072V   -165.5mA   -253.2mA   -113.1mA
-1.021V   -114mA     -199mA     -70.14mA
-970mV    -72.1mA    -148.7mA   -44.84mA
-919mV    -43.36mA   -104.3mA   -34.74mA
-817mV    -20.74mA   -41.58mA   -26.14mA
-715mV    -14.15mA   -15.01mA   -18.79mA
-613mV    -8.979mA   -7.374mA   -12.03mA
-256mV    -63.28uA   -178.3uA   -38.35uA
2.5V      0A         0A         0A
[POWER_clamp]
|Voltage   I(typ)   I(min)   I(max)
-2.5V     883.5uA    947.3uA    1.04mA
-1.376V   201.4uA    282.2uA    185.4uA
-1.274V   155.2uA    239.1uA    113.4uA
-1.172V   96.76uA    201.8uA    76.65uA
-1.07V    58.5uA     166.3uA    58.8uA
-866mV    31.91uA    77.15uA    43.85uA
-713mV    24.63uA    41.8uA     43.85uA
-560mV    23.08uA    27.31uA    43.85uA
-152mV    23.08uA    27.31uA    43.85uA
-50mV     3.959uA    20.74uA    1.391uA
1mV       0A         1.294nA    0A
2.5V      0A         0A         0A
[Ramp]
| variable   typ   min   max
dV/dt_r   0.308/0.570n   0.312/0.679n   0.270/0.554n
dV/dt_f   0.308/33.939n   0.312/34.763n   0.270/63.363n
R_load = 50.000
[Rising Waveform]
R_fixture= 50.000
V_fixture= 2.500
V_fixture_min= 2.380
V_fixture_max= 2.630
|time   V(typ)   V(min)   V(max)
0s        1.987V     1.859V     2.181V
530ps     1.987V     1.859V     2.182V
620ps     1.987V     1.859V     2.099V
780ps     1.921V     1.859V     2.133V
960ps     1.946V     1.86V      2.19V
1.27ns    2.243V     1.822V     2.428V
1.96ns    2.446V     2.222V     2.591V
2.72ns    2.49V      2.346V     2.624V
4.63ns    2.501V     2.379V     2.631V
200ns     2.5V       2.38V      2.63V
[Falling Waveform]
R_fixture= 50.000
V_fixture= 2.500
V_fixture_min= 2.380
V_fixture_max= 2.630
|time   V(typ)   V(min)   V(max)
0s        2.5V       2.38V      2.63V
970ps     2.5V       2.38V      2.631V
1.1ns     2.5V       2.38V      2.678V
1.51ns    2.541V     2.38V      2.643V
3.47ns    2.475V     2.373V     2.609V
19.42ns   2.348V     2.268V     2.551V
51.65ns   2.057V     1.97V      2.419V
63.24ns   1.997V     1.908V     2.369V
110ns     1.987V     1.859V     2.189V
200ns     1.987V     1.859V     2.181V
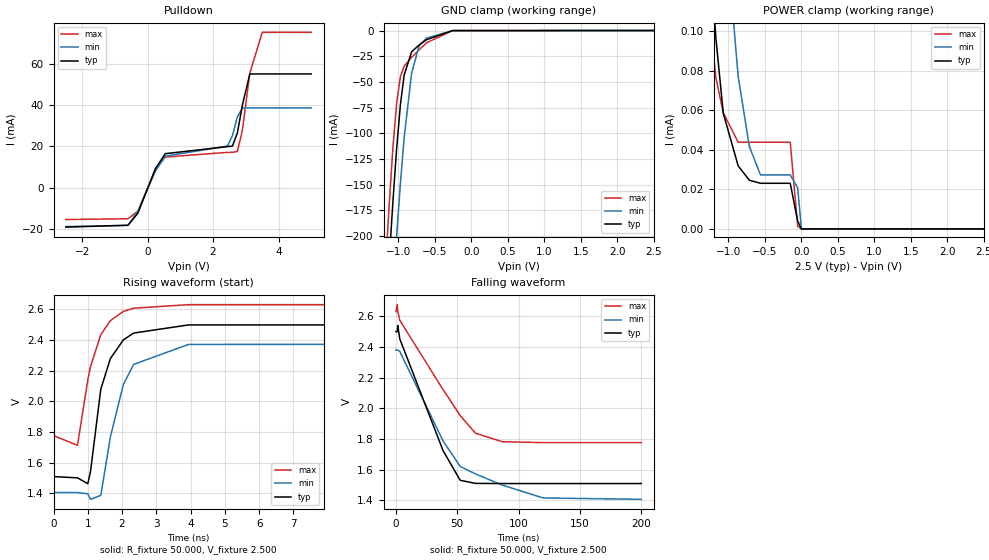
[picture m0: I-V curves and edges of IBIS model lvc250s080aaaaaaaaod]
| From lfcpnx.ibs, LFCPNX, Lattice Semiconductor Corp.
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[Model] lvc250s080aaaaaaaaod
Model_type I/O_open_drain
Polarity   Non-Inverting
Enable   Active-Low
Vinl =  0.700V
Vinh =  1.700V
Vmeas =  1.250V
Cref =  0.0F
Rref = 10.00k
Vref = 2.50V
C_comp   5.000pF   4.000pF   5.500pF
[Temperature Range]   25.000   0.125k   -40.000
[Voltage Range]   2.500V   2.380V   2.630V
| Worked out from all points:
|   slope of the pulldown table from 0 to 0.375 V, typ, clamps not added: 28.4 ohm
|   GND clamp passes 1 mA (typ) near -0.37 V on its own axis
|   rising waveform, R_fixture 50.000, V_fixture 2.500: 20-80 % time 560ps typ, 650ps min, 598ps max; typ from 1.51 V to 2.5 V
|   falling waveform, R_fixture 50.000, V_fixture 2.500: 20-80 % time 27.9ns typ, 40.1ns min, 40.2ns max; typ from 2.5 V to 1.51 V
[Pulldown]
|Voltage   I(typ)   I(min)   I(max)
-2.5V     -19.07mA   -18.79mA   -15.38mA
-600mV    -18.15mA   -18.19mA   -15.02mA
-296mV    -12.29mA   -11.42mA   -11.28mA
236mV     9.129mA    8.01mA     8.694mA
540mV     16.45mA    15.25mA    14.82mA
2.44V     19.85mA    20.13mA    17.08mA
2.592V    20.13mA    25.15mA    17.09mA
2.744V    26.51mA    34.26mA    17.51mA
2.896V    39.9mA     38.57mA    27.75mA
3.124V    54.98mA    38.57mA    55.37mA
3.504V    54.98mA    38.57mA    75.1mA
5V        54.98mA    38.57mA    75.1mA
[GND_clamp]
|Voltage   I(typ)   I(min)   I(max)
-2.5V     -2.083A    -2.046A    -2.12A
-1.174V   -284.5mA   -369.1mA   -230.6mA
-1.123V   -223.1mA   -310.2mA   -168.4mA
-1.072V   -165.5mA   -253.2mA   -113.1mA
-1.021V   -114mA     -199mA     -70.14mA
-970mV    -72.1mA    -148.7mA   -44.84mA
-919mV    -43.36mA   -104.3mA   -34.74mA
-817mV    -20.74mA   -41.58mA   -26.14mA
-715mV    -14.15mA   -15.01mA   -18.79mA
-613mV    -8.979mA   -7.374mA   -12.03mA
-256mV    -63.28uA   -178.3uA   -38.35uA
2.5V      0A         0A         0A
[POWER_clamp]
|Voltage   I(typ)   I(min)   I(max)
-2.5V     883.5uA    947.3uA    1.04mA
-1.376V   201.4uA    282.2uA    185.4uA
-1.274V   155.2uA    239.1uA    113.4uA
-1.172V   96.76uA    201.8uA    76.65uA
-1.07V    58.5uA     166.3uA    58.8uA
-866mV    31.91uA    77.15uA    43.85uA
-713mV    24.63uA    41.8uA     43.85uA
-560mV    23.08uA    27.31uA    43.85uA
-152mV    23.08uA    27.31uA    43.85uA
-50mV     3.959uA    20.74uA    1.391uA
1mV       0A         1.294nA    0A
2.5V      0A         0A         0A
[Ramp]
| variable   typ   min   max
dV/dt_r   0.595/0.563n   0.585/0.651n   0.512/0.599n
dV/dt_f   0.595/27.970n   0.585/39.614n   0.512/40.204n
R_load = 50.000
[Rising Waveform]
R_fixture= 50.000
V_fixture= 2.500
V_fixture_min= 2.380
V_fixture_max= 2.630
|time   V(typ)   V(min)   V(max)
0s        1.509V     1.406V     1.776V
700ps     1.501V     1.405V     1.713V
1ns       1.463V     1.397V     2.139V
1.08ns    1.542V     1.361V     2.227V
1.38ns    2.079V     1.387V     2.433V
1.66ns    2.278V     1.768V     2.525V
2.04ns    2.4V       2.11V      2.585V
2.34ns    2.444V     2.24V      2.606V
3.94ns    2.497V     2.37V      2.629V
200ns     2.5V       2.38V      2.63V
[Falling Waveform]
R_fixture= 50.000
V_fixture= 2.500
V_fixture_min= 2.380
V_fixture_max= 2.630
|time   V(typ)   V(min)   V(max)
0s        2.5V       2.38V      2.63V
1.1ns     2.5V       2.38V      2.677V
1.49ns    2.54V      2.38V      2.634V
3.13ns    2.453V     2.371V     2.574V
38.46ns   1.723V     1.786V     2.121V
52.41ns   1.53V      1.62V      1.952V
64.87ns   1.51V      1.572V     1.837V
86.57ns   1.509V     1.499V     1.782V
119.9ns   1.509V     1.415V     1.776V
200ns     1.509V     1.406V     1.776V
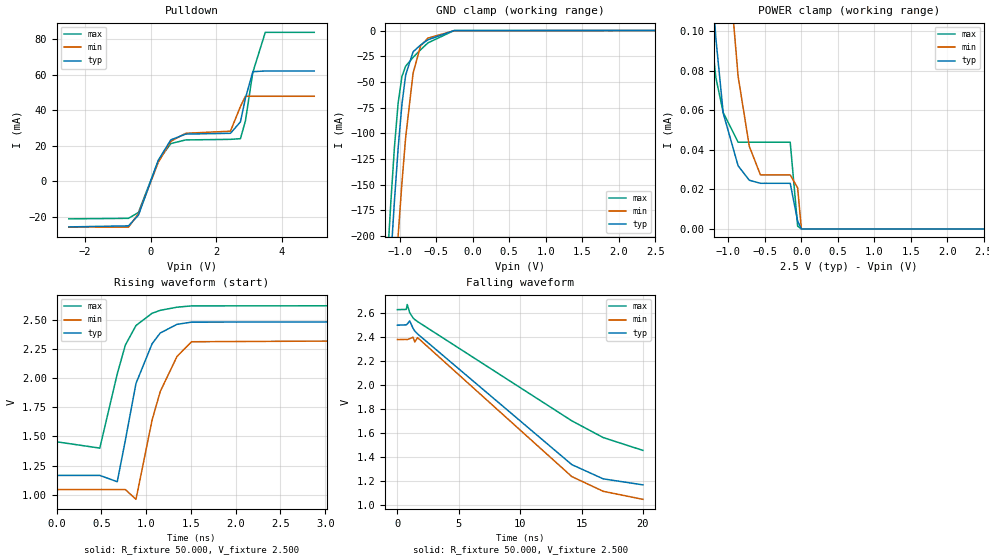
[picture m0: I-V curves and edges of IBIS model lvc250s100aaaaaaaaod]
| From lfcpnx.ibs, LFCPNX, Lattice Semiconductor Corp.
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[Model] lvc250s100aaaaaaaaod
Model_type I/O_open_drain
Polarity   Non-Inverting
Enable   Active-Low
Vinl =  0.700V
Vinh =  1.700V
Vmeas =  1.250V
Cref =  0.0F
Rref = 10.00k
Vref = 2.50V
C_comp   5.000pF   4.000pF   5.500pF
[Temperature Range]   25.000   0.125k   -40.000
[Voltage Range]   2.500V   2.380V   2.630V
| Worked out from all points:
|   slope of the pulldown table from 0 to 0.375 V, typ, clamps not added: 21.6 ohm
|   GND clamp passes 1 mA (typ) near -0.37 V on its own axis
|   rising waveform, R_fixture 50.000, V_fixture 2.500: 20-80 % time 263ps typ, 298ps min, 275ps max; typ from 1.17 V to 2.5 V
|   falling waveform, R_fixture 50.000, V_fixture 2.500: 20-80 % time 8.81ns typ, 8.29ns min, 10.6ns max; typ from 2.5 V to 1.17 V
[Pulldown]
|Voltage   I(typ)   I(min)   I(max)
-2.5V     -25.71mA   -25.85mA   -21.18mA
-676mV    -25.12mA   -25.85mA   -20.89mA
-372mV    -19.11mA   -18.27mA   -17.57mA
236mV     11.85mA    10.67mA    11.57mA
616mV     23.26mA    22.44mA    21.17mA
1.072V    26.51mA    26.97mA    23.23mA
2.44V     26.96mA    28.14mA    23.55mA
2.744V    33.36mA    42.02mA    23.93mA
2.896V    46.65mA    47.79mA    33.86mA
3.124V    61.63mA    47.79mA    61.35mA
3.504V    62.02mA    47.79mA    83.77mA
5V        62.02mA    47.79mA    83.77mA
[GND_clamp]
|Voltage   I(typ)   I(min)   I(max)
-2.5V     -2.083A    -2.046A    -2.12A
-1.174V   -284.5mA   -369.1mA   -230.6mA
-1.123V   -223.1mA   -310.2mA   -168.4mA
-1.072V   -165.5mA   -253.2mA   -113.1mA
-1.021V   -114mA     -199mA     -70.14mA
-970mV    -72.1mA    -148.7mA   -44.84mA
-919mV    -43.36mA   -104.3mA   -34.74mA
-817mV    -20.74mA   -41.58mA   -26.14mA
-715mV    -14.15mA   -15.01mA   -18.79mA
-613mV    -8.979mA   -7.374mA   -12.03mA
-256mV    -63.28uA   -178.3uA   -38.35uA
2.5V      0A         0A         0A
[POWER_clamp]
|Voltage   I(typ)   I(min)   I(max)
-2.5V     883.5uA    947.3uA    1.04mA
-1.376V   201.4uA    282.2uA    185.4uA
-1.274V   155.2uA    239.1uA    113.4uA
-1.172V   96.76uA    201.8uA    76.65uA
-1.07V    58.5uA     166.3uA    58.8uA
-866mV    31.91uA    77.15uA    43.85uA
-713mV    24.63uA    41.8uA     43.85uA
-560mV    23.08uA    27.31uA    43.85uA
-152mV    23.08uA    27.31uA    43.85uA
-50mV     3.959uA    20.74uA    1.391uA
1mV       0A         1.294nA    0A
2.5V      0A         0A         0A
[Ramp]
| variable   typ   min   max
dV/dt_r   0.801/0.613n   0.805/0.565n   0.706/0.610n
dV/dt_f   0.801/34.433n   0.805/23.436n   0.706/48.243n
R_load = 50.000
[Rising Waveform]
R_fixture = 50.000
V_fixture = 2.500
V_fixture_min = 2.380
V_fixture_max = 2.630
|  time   V(typ)   V(min)   V(max)
0s        1.166V     1.045V     1.454V
483ps     1.166V     1.045V     1.4V
678ps     1.112V     1.045V     2.036V
768ps     1.466V     1.045V     2.282V
887ps     1.954V     961.1mV    2.45V
1.067ns   2.294V     1.641V     2.555V
1.158ns   2.386V     1.885V     2.58V
1.345ns   2.46V      2.185V     2.607V
1.507ns   2.479V     2.311V     2.618V
20ns      2.5V       2.38V      2.63V
[Falling Waveform]
R_fixture = 50.000
V_fixture = 2.500
V_fixture_min = 2.380
V_fixture_max = 2.630
|  time   V(typ)   V(min)   V(max)
0s        2.5V       2.38V      2.63V
721ps     2.503V     2.381V     2.632V
800ps     2.509V     2.38V      2.673V
998ps     2.537V     2.387V     2.606V
1.274ns   2.474V     2.4V       2.561V
1.414ns   2.451V     2.36V      2.547V
1.644ns   2.427V     2.396V     2.53V
14.21ns   1.335V     1.235V     1.701V
16.77ns   1.216V     1.112V     1.561V
20ns      1.166V     1.045V     1.454V
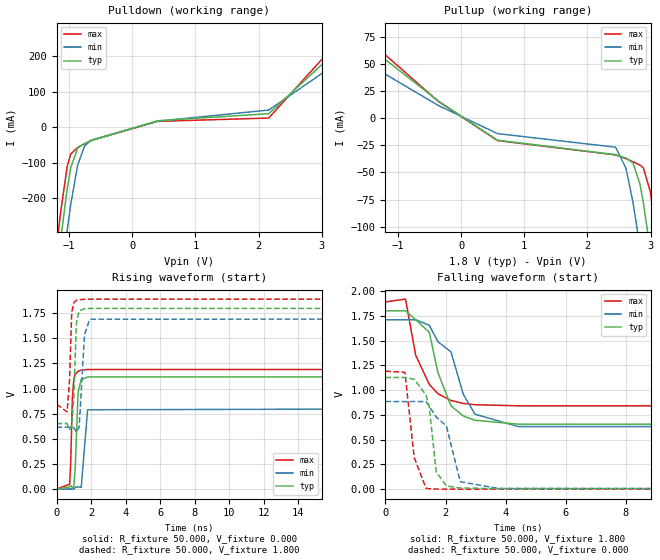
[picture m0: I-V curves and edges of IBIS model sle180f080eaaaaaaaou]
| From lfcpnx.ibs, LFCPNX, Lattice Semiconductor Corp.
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|Model sle180f080eaaaaaaaou
[Model] sle180f080eaaaaaaaou
Model_type Output
Polarity   Non-Inverting
Enable   Active-High
Vmeas =  0.900V
Cref =  0.0F
Rref =  1.000M
Vref =  0.0V
C_comp   5.000pF   4.000pF   5.500pF
[Temperature Range]   25.000   0.125k   -40.000
[Voltage Range]   1.800V   1.710V   1.890V
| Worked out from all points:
|   slope of the pulldown table from 0 to 0.27 V, typ, clamps not added: 20.4 ohm
|   slope of the pullup table from 0 to 0.27 V, typ, clamps not added: 25.3 ohm
|   rising waveform, R_fixture 50.000, V_fixture 0.000: 20-80 % time 143ps typ, 190ps min, 114ps max; typ from 0 V to 1.13 V
|   rising waveform, R_fixture 50.000, V_fixture 1.800: 20-80 % time 135ps typ, 169ps min, 103ps max; typ from 0.651 V to 1.8 V
|   falling waveform, R_fixture 50.000, V_fixture 1.800: 20-80 % time 620ps typ, 1.05ns min, 669ps max; typ from 1.8 V to 0.651 V
|   falling waveform, R_fixture 50.000, V_fixture 0.000: 20-80 % time 246ps typ, 551ps min, 290ps max; typ from 1.13 V to 0 V
[Pulldown]
|Voltage   I(typ)   I(min)   I(max)
-1.8V     -1.453A    -1.526A    -1.407A
-1.195V   -410.7mA   -532.7mA   -332.7mA
-1.14V    -324.5mA   -448.2mA   -246.4mA
-1.03V    -171.6mA   -288.8mA   -109.4mA
-975mV    -114.3mA   -217.4mA   -75.6mA
-865mV    -58.51mA   -106.6mA   -57.09mA
-755mV    -45.79mA   -52.77mA   -46.73mA
-645mV    -37.44mA   -36.2mA    -36.95mA
400mV     17.91mA    16.79mA    16.23mA
2.16V     37.85mA    48.01mA    25.58mA
3.37V     236.2mA    195.9mA    262.7mA
3.6V      265.9mA    213.4mA    300mA
[Pullup]
|Voltage   I(typ)   I(min)   I(max)
-1.8V     73.3mA     54.1mA     84.1mA
-1.295V   58.3mA     43.8mA     63.2mA
-360mV    15.84mA    11.66mA    15.32mA
575mV     -20.27mA   -14.21mA   -20.67mA
2.445V    -33.69mA   -26.75mA   -33.81mA
2.61V     -36.8mA    -46.2mA    -37.4mA
2.72V     -41.2mA    -77.4mA    -40.1mA
2.83V     -60.6mA    -118mA     -43.2mA
2.885V    -78mA      -140mA     -45.8mA
2.995V    -121.6mA   -186mA     -67.6mA
3.16V     -195.6mA   -257.3mA   -136.6mA
3.6V      -405.1mA   -453.4mA   -354.5mA
[Ramp]
| variable   typ   min   max
dV/dt_r   0.676/0.150n   0.531/0.194n   0.715/0.122n
dV/dt_f   0.689/0.623n   0.657/1.050n   0.628/0.671n
R_load = 50.000
[Rising Waveform]
R_fixture = 50.000
V_fixture = 0.000
V_fixture_min = 0.000
V_fixture_max = 0.000
|  time   V(typ)   V(min)   V(max)
0s        87.6uV     444.9uV    43.64uV
760ps     21.26mV    448.2uV    48.36mV
820ps     35.43mV    610.3uV    258.7mV
920ps     14.82mV    648.3uV    913mV
1ns       19.88mV    -1.24mV    1.095V
1.08ns    206.9mV    16.87mV    1.14V
1.25ns    966mV      21.19mV    1.172V
1.43ns    1.088V     16.75mV    1.183V
1.8ns     1.115V     788.4mV    1.189V
200ns     1.127V     884.8mV    1.191V
[Rising Waveform]
R_fixture = 50.000
V_fixture = 1.800
V_fixture_min = 1.710
V_fixture_max = 1.890
|  time   V(typ)   V(min)   V(max)
0s        651mV      615mV      843.6mV
610ps     652.2mV    615mV      768.3mV
750ps     592.6mV    614.9mV    1.067V
880ps     634.1mV    615.7mV    1.756V
1ns       910.5mV    610.3mV    1.854V
1.15ns    1.654V     566.4mV    1.878V
1.31ns    1.773V     615.1mV    1.884V
1.62ns    1.794V     1.534V     1.888V
1.92ns    1.797V     1.689V     1.889V
200ns     1.8V       1.71V      1.89V
[Falling Waveform]
R_fixture = 50.000
V_fixture = 1.800
V_fixture_min = 1.710
V_fixture_max = 1.890
|  time   V(typ)   V(min)   V(max)
0s        1.8V       1.71V      1.89V
670ps     1.8V       1.71V      1.919V
1.01ns    1.71V      1.71V      1.35V
1.46ns    1.584V     1.655V     1.058V
1.75ns    1.174V     1.487V     962.3mV
2.18ns    842mV      1.387V     895.3mV
2.59ns    738.8mV    958.5mV    865.8mV
2.98ns    695.6mV    756.8mV    852.4mV
4.41ns    656.2mV    632.4mV    841.5mV
200ns     651mV      615mV      843.6mV
[Falling Waveform]
R_fixture = 50.000
V_fixture = 0.000
V_fixture_min = 0.000
V_fixture_max = 0.000
|  time   V(typ)   V(min)   V(max)
0s        1.127V     884.8mV    1.191V
650ps     1.128V     884.7mV    1.18V
960ps     1.11V      885mV      318.7mV
1.35ns    951.4mV    883.6mV    9.998mV
1.46ns    829.4mV    837mV      4.511mV
1.69ns    175.1mV    728.8mV    737.7uV
2.03ns    31.84mV    637.1mV    116.7uV
2.49ns    12mV       75.01mV    111.8uV
3.75ns    5.244mV    8.007mV    551.4uV
200ns     87.6uV     444.9uV    43.64uV
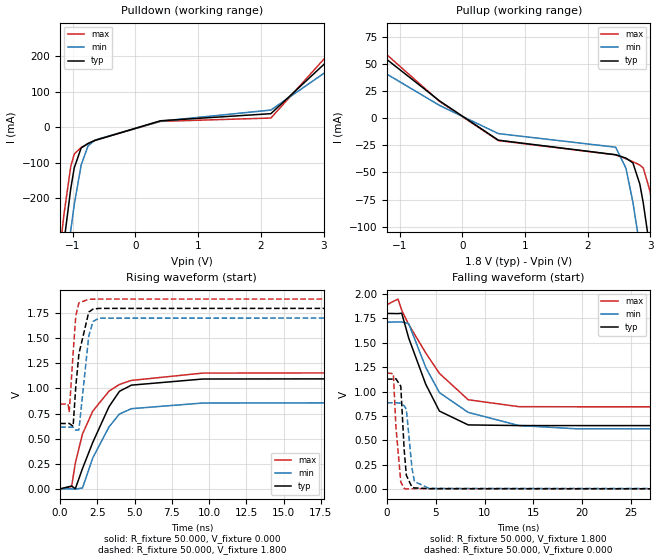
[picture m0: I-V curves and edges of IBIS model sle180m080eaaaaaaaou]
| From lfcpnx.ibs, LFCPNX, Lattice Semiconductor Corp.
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[Model] sle180m080eaaaaaaaou
Model_type Output
Polarity   Non-Inverting
Enable   Active-High
Vmeas =  0.900V
Cref =  0.0F
Rref =  1.000M
Vref =  0.0V
C_comp   5.000pF   4.000pF   5.500pF
[Temperature Range]   25.000   0.125k   -40.000
[Voltage Range]   1.800V   1.710V   1.890V
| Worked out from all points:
|   slope of the pulldown table from 0 to 0.27 V, typ, clamps not added: 20.4 ohm
|   slope of the pullup table from 0 to 0.27 V, typ, clamps not added: 25.3 ohm
|   rising waveform, R_fixture 50.000, V_fixture 0.000: 20-80 % time 2.05ns typ, 1.84ns min, 2.13ns max; typ from 0 V to 1.13 V
|   rising waveform, R_fixture 50.000, V_fixture 1.800: 20-80 % time 532ps typ, 438ps min, 265ps max; typ from 0.651 V to 1.8 V
|   falling waveform, R_fixture 50.000, V_fixture 1.800: 20-80 % time 2.72ns typ, 4.2ns min, 4.17ns max; typ from 1.8 V to 0.651 V
|   falling waveform, R_fixture 50.000, V_fixture 0.000: 20-80 % time 362ps typ, 417ps min, 456ps max; typ from 1.13 V to 0 V
[Pulldown]
|Voltage   I(typ)   I(min)   I(max)
-1.8V     -1.453A    -1.526A    -1.407A
-1.195V   -410.7mA   -532.7mA   -332.7mA
-1.14V    -324.5mA   -448.2mA   -246.4mA
-1.03V    -171.6mA   -288.8mA   -109.4mA
-975mV    -114.3mA   -217.4mA   -75.6mA
-865mV    -58.51mA   -106.6mA   -57.09mA
-755mV    -45.79mA   -52.77mA   -46.73mA
-645mV    -37.44mA   -36.2mA    -36.95mA
400mV     17.91mA    16.79mA    16.23mA
2.16V     37.85mA    48.01mA    25.58mA
3.37V     236.2mA    195.9mA    262.7mA
3.6V      265.9mA    213.4mA    300mA
[Pullup]
|Voltage   I(typ)   I(min)   I(max)
-1.8V     73.3mA     54.1mA     84.1mA
-1.295V   58.3mA     43.8mA     63.2mA
-360mV    15.84mA    11.66mA    15.32mA
575mV     -20.27mA   -14.21mA   -20.67mA
2.445V    -33.69mA   -26.75mA   -33.81mA
2.61V     -36.8mA    -46.2mA    -37.4mA
2.72V     -41.2mA    -77.4mA    -40.1mA
2.83V     -60.6mA    -118mA     -43.2mA
2.885V    -78mA      -140mA     -45.8mA
2.995V    -121.6mA   -186mA     -67.6mA
3.16V     -195.6mA   -257.3mA   -136.6mA
3.6V      -405.1mA   -453.4mA   -354.5mA
[Ramp]
| variable   typ   min   max
dV/dt_r   0.676/2.048n   0.531/1.846n   0.715/2.133n
dV/dt_f   0.689/2.726n   0.657/4.205n   0.628/4.172n
R_load = 50.000
[Rising Waveform]
R_fixture = 50.000
V_fixture = 0.000
V_fixture_min = 0.000
V_fixture_max = 0.000
|  time   V(typ)   V(min)   V(max)
0s        87.6uV     444.9uV    43.64uV
770ps     28.43mV    474.7uV    24.15mV
1.02ns    1.74mV     -2.62mV    259.2mV
1.5ns     202.9mV    10mV       547.2mV
2.19ns    463.5mV    308.4mV    774.4mV
3.28ns    818.9mV    617.7mV    973.7mV
3.98ns    971.6mV    745.6mV    1.04V
4.78ns    1.033V     798.7mV    1.08V
9.57ns    1.094V     855mV      1.153V
200ns     1.127V     884.8mV    1.191V
[Rising Waveform]
R_fixture = 50.000
V_fixture = 1.800
V_fixture_min = 1.710
V_fixture_max = 1.890
|  time   V(typ)   V(min)   V(max)
0s        651mV      615mV      843.6mV
530ps     651.3mV    615.1mV    845.5mV
610ps     652.2mV    614.9mV    763.9mV
870ps     622.9mV    615.6mV    1.352V
1.05ns    1.02V      583.9mV    1.724V
1.26ns    1.345V     588.4mV    1.853V
1.92ns    1.76V      1.523V     1.888V
2.21ns    1.79V      1.667V     1.889V
2.61ns    1.797V     1.7V       1.89V
200ns     1.8V       1.71V      1.89V
[Falling Waveform]
R_fixture = 50.000
V_fixture = 1.800
V_fixture_min = 1.710
V_fixture_max = 1.890
|  time   V(typ)   V(min)   V(max)
0s        1.8V       1.71V      1.89V
1.12ns    1.798V     1.713V     1.947V
1.51ns    1.802V     1.713V     1.831V
2.22ns    1.548V     1.695V     1.687V
3.97ns    1.074V     1.247V     1.395V
5.37ns    799.8mV    988.8mV    1.186V
8.32ns    658.1mV    786.5mV    915.9mV
13.5ns    651.5mV    652mV      845.2mV
19.5ns    651.2mV    617.9mV    843.7mV
200ns     651mV      615mV      843.6mV
[Falling Waveform]
R_fixture = 50.000
V_fixture = 0.000
V_fixture_min = 0.000
V_fixture_max = 0.000
|  time   V(typ)   V(min)   V(max)
0s        1.127V     884.8mV    1.191V
650ps     1.127V     884.7mV    1.182V
910ps     1.131V     885mV      640.9mV
1.41ns    1.054V     880.3mV    74.17mV
1.76ns    399.7mV    853.2mV    7.357mV
1.98ns    142.3mV    818.5mV    2.532mV
2.56ns    19.62mV    214mV      4.428mV
2.81ns    13.11mV    77.9mV     6.01mV
4.31ns    4.854mV    8.092mV    4.984mV
200ns     87.6uV     444.9uV    43.64uV
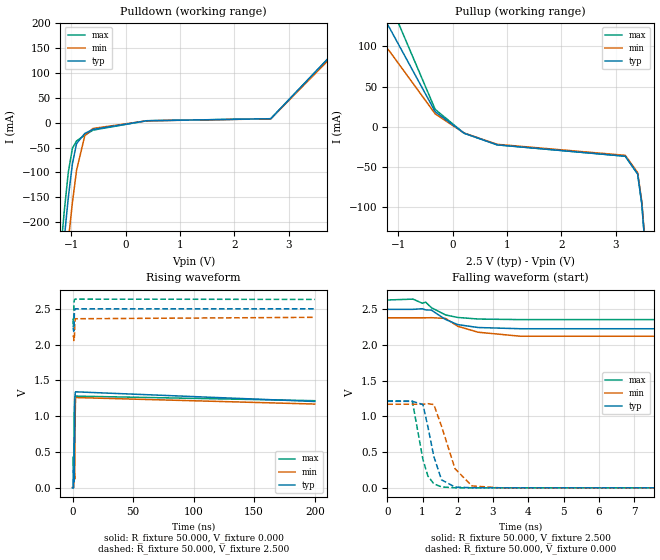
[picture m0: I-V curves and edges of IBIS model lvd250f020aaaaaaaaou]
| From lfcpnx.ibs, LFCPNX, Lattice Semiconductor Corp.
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|Model lvd250f020aaaaaaaaou
[Model] lvd250f020aaaaaaaaou
Model_type Output
Polarity   Non-Inverting
Enable   Active-High
Vmeas =  1.250V
Cref =  0.0F
Rref =  1.000M
Vref =  0.0V
C_comp   5.000pF   4.000pF   5.500pF
[Temperature Range]   25.000   0.125k   -40.000
[Voltage Range]   2.500V   2.380V   2.630V
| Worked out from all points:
|   slope of the pulldown table from 0 to 0.375 V, typ, clamps not added: 96.1 ohm
|   slope of the pullup table from 0 to 0.375 V, typ, clamps not added: 28.8 ohm
|   rising waveform, R_fixture 50.000, V_fixture 0.000: 20-80 % time 236ps typ, 271ps min, 287ps max; typ from 0.001 V to 1.21 V
|   rising waveform, R_fixture 50.000, V_fixture 2.500: 20-80 % time 168ps typ, 228ps min, 186ps max; typ from 2.23 V to 2.5 V
|   falling waveform, R_fixture 50.000, V_fixture 2.500: 20-80 % time 696ps typ, 865ps min, 581ps max; typ from 2.5 V to 2.23 V
|   falling waveform, R_fixture 50.000, V_fixture 0.000: 20-80 % time 318ps typ, 464ps min, 285ps max; typ from 1.21 V to 0.001 V
[Pulldown]
|Voltage   I(typ)   I(min)   I(max)
-2.5V     -2.085A    -2.048A    -2.121A
-1.208V   -328.9mA   -411.4mA   -275.6mA
-1.132V   -236mA     -322.8mA   -180.6mA
-1.056V   -151.3mA   -238.4mA   -100.1mA
-980mV    -82.88mA   -161mA     -51.45mA
-904mV    -42.13mA   -96.03mA   -36.78mA
-752mV    -21.55mA   -25.93mA   -25.1mA
-600mV    -13.52mA   -11.55mA   -14.88mA
388mV     3.97mA     3.851mA    3.97mA
2.668V    8.053mA    7.811mA    8.053mA
4.112V    174.1mA    168.9mA    174.1mA
5V        192.3mA    186.5mA    192.3mA
[Pullup]
|Voltage   I(typ)   I(min)   I(max)
-2.5V     187.4mA    139.6mA    231.6mA
-1.84V    183.8mA    137.8mA    227.4mA
-1.46V    156.9mA    119mA      196mA
-1.156V   122.6mA    93.72mA    154.4mA
-320mV    18.94mA    16.29mA    21.79mA
212mV     -7.802mA   -7.568mA   -7.802mA
820mV     -22.24mA   -21.58mA   -22.24mA
3.176V    -36.35mA   -35.26mA   -36.35mA
3.404V    -58.44mA   -56.69mA   -58.44mA
3.48V     -95.35mA   -92.49mA   -95.35mA
3.556V    -160.8mA   -156mA     -160.8mA
5V        -2.091A    -2.029A    -2.091A
[Ramp]
| variable   typ   min   max
dV/dt_r   0.723/0.837n   0.698/0.988n   0.730/0.695n
dV/dt_f   0.163/0.697n   0.159/0.871n   0.164/0.589n
R_load = 50.000
[Rising Waveform]
R_fixture = 50.000
V_fixture = 0.000
V_fixture_min = 0.000
V_fixture_max = 0.000
|  time   V(typ)   V(min)   V(max)
0s        704.3uV    7.036mV    151.9uV
570ps     811.1uV    7.115mV    1.896mV
680ps     1.329mV    6.854mV    434.7mV
830ps     246.7mV    7.132mV    310.3mV
990ps     193.6mV    5.122mV    206.7mV
1.36ns    88.11mV    217.9mV    1.039V
1.78ns    1.138V     122.7mV    1.255V
2.19ns    1.326V     1.024V     1.284V
2.48ns    1.341V     1.261V     1.281V
200ns     1.206V     1.17V      1.217V
[Rising Waveform]
R_fixture = 50.000
V_fixture = 2.500
V_fixture_min = 2.380
V_fixture_max = 2.630
|  time   V(typ)   V(min)   V(max)
0s        2.228V     2.116V     2.358V
540ps     2.228V     2.116V     2.358V
630ps     2.228V     2.116V     2.25V
930ps     2.187V     2.116V     2.333V
1.09ns    2.205V     2.056V     2.528V
1.24ns    2.223V     2.074V     2.594V
1.54ns    2.459V     2.105V     2.626V
1.96ns    2.496V     2.32V      2.634V
2.18ns    2.499V     2.361V     2.635V
200ns     2.5V       2.381V     2.631V
[Falling Waveform]
R_fixture = 50.000
V_fixture = 2.500
V_fixture_min = 2.380
V_fixture_max = 2.630
|  time   V(typ)   V(min)   V(max)
0s        2.5V       2.381V     2.631V
730ps     2.5V       2.381V     2.643V
990ps     2.508V     2.381V     2.586V
1.09ns    2.492V     2.381V     2.6V
1.25ns    2.489V     2.383V     2.523V
1.65ns    2.358V     2.373V     2.422V
2ns       2.286V     2.262V     2.386V
2.58ns    2.245V     2.179V     2.364V
3.78ns    2.228V     2.123V     2.356V
200ns     2.228V     2.116V     2.358V
[Falling Waveform]
R_fixture = 50.000
V_fixture = 0.000
V_fixture_min = 0.000
V_fixture_max = 0.000
|  time   V(typ)   V(min)   V(max)
0s        1.211V     1.17V      1.217V
710ps     1.211V     1.17V      1.214V
1.01ns    1.167V     1.17V      396.2mV
1.15ns    857.8mV    1.178V     166.3mV
1.32ns    437.7mV    1.166V     54.08mV
1.54ns    110.2mV    859mV      11.83mV
1.92ns    9.534mV    267.5mV    -417.5uV
2.4ns     389.2uV    25.89mV    -1.566mV
3.18ns    -404.3uV   -599.2uV   -1.253mV
200ns     704.5uV    7.036mV    151.9uV
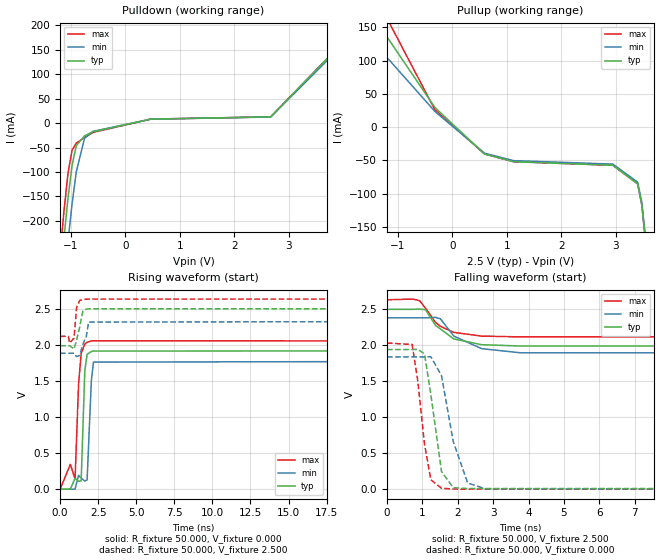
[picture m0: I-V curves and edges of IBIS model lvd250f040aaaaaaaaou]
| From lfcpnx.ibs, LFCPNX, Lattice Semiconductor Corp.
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[Model] lvd250f040aaaaaaaaou
Model_type Output
Polarity   Non-Inverting
Enable   Active-High
Vmeas =  1.250V
Cref =  0.0F
Rref =  1.000M
Vref =  0.0V
C_comp   5.000pF   4.000pF   5.500pF
[Temperature Range]   25.000   0.125k   -40.000
[Voltage Range]   2.500V   2.380V   2.630V
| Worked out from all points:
|   slope of the pulldown table from 0 to 0.375 V, typ, clamps not added: 52.3 ohm
|   slope of the pullup table from 0 to 0.375 V, typ, clamps not added: 13.2 ohm
|   rising waveform, R_fixture 50.000, V_fixture 0.000: 20-80 % time 154ps typ, 188ps min, 208ps max; typ from 0.001 V to 1.93 V
|   rising waveform, R_fixture 50.000, V_fixture 2.500: 20-80 % time 311ps typ, 383ps min, 114ps max; typ from 1.99 V to 2.5 V
|   falling waveform, R_fixture 50.000, V_fixture 2.500: 20-80 % time 658ps typ, 802ps min, 631ps max; typ from 2.5 V to 1.99 V
|   falling waveform, R_fixture 50.000, V_fixture 0.000: 20-80 % time 309ps typ, 504ps min, 275ps max; typ from 1.94 V to 0.001 V
[Pulldown]
|Voltage   I(typ)   I(min)   I(max)
-2.5V     -2.087A    -2.05A     -2.122A
-1.208V   -330.7mA   -414.1mA   -277.2mA
-1.132V   -238.1mA   -325.6mA   -182.4mA
-1.056V   -153.6mA   -241.4mA   -102.6mA
-980mV    -86mA      -164.4mA   -55.18mA
-904mV    -46.21mA   -100mA     -41.14mA
-752mV    -26.2mA    -31.37mA   -29.5mA
-600mV    -17.96mA   -17.01mA   -19.2mA
464mV     8.134mA    7.89mA     8.134mA
2.668V    12.76mA    12.38mA    12.76mA
4.112V    178.7mA    173.3mA    178.7mA
5V        197.1mA    191.2mA    197.1mA
[Pullup]
|Voltage   I(typ)   I(min)   I(max)
-2.5V     189.4mA    141.7mA    232mA
-1.84V    186.8mA    140.8mA    228.1mA
-1.384V   155.4mA    119.1mA    188.3mA
-1.156V   130.2mA    100.6mA    156.5mA
-320mV    29.46mA    23.51mA    26.02mA
592mV     -40.38mA   -39.17mA   -40.38mA
1.124V    -51.9mA    -50.35mA   -51.9mA
2.948V    -57.25mA   -55.53mA   -57.25mA
3.404V    -85.21mA   -82.65mA   -85.21mA
3.48V     -116.2mA   -112.7mA   -116.2mA
3.556V    -176.5mA   -171.2mA   -176.5mA
5V        -2.101A    -2.038A    -2.101A
[Ramp]
| variable   typ   min   max
dV/dt_r   1.158/0.155n   1.103/0.189n   1.219/0.211n
dV/dt_f   0.308/0.662n   0.313/0.805n   0.310/0.626n
R_load = 50.000
[Rising Waveform]
R_fixture = 50.000
V_fixture = 0.000
V_fixture_min = 0.000
V_fixture_max = 0.000
|  time   V(typ)   V(min)   V(max)
0s        531.4uV    878.7uV    348.5uV
670ps     1.336mV    603.3uV    344.7mV
980ps     151.8mV    327.6uV    141.3mV
1.21ns    110mV      192.6mV    1.456V
1.38ns    115.9mV    152.5mV    1.878V
1.62ns    1.643V     113.4mV    2.01V
1.77ns    1.866V     127.6mV    2.035V
2.05ns    1.907V     1.506V     2.052V
2.19ns    1.913V     1.76V      2.055V
200ns     1.931V     1.839V     2.032V
[Rising Waveform]
R_fixture = 50.000
V_fixture = 2.500
V_fixture_min = 2.380
V_fixture_max = 2.630
|  time   V(typ)   V(min)   V(max)
0s        1.987V     1.882V     2.117V
540ps     1.987V     1.882V     2.117V
620ps     1.987V     1.882V     2.024V
910ps     1.942V     1.883V     2.093V
1.08ns    2.065V     1.836V     2.516V
1.28ns    2.243V     1.853V     2.612V
1.49ns    2.465V     2.005V     2.628V
1.72ns    2.494V     2.118V     2.632V
1.87ns    2.498V     2.314V     2.633V
200ns     2.5V       2.382V     2.633V
[Falling Waveform]
R_fixture = 50.000
V_fixture = 2.500
V_fixture_min = 2.380
V_fixture_max = 2.630
|  time   V(typ)   V(min)   V(max)
0s        2.5V       2.382V     2.633V
730ps     2.5V       2.382V     2.643V
920ps     2.504V     2.382V     2.621V
1.09ns    2.495V     2.382V     2.514V
1.37ns    2.277V     2.389V     2.319V
1.51ns    2.227V     2.368V     2.264V
1.89ns    2.088V     2.128V     2.18V
2.67ns    2.009V     1.954V     2.128V
3.77ns    1.99V      1.896V     2.117V
200ns     1.987V     1.882V     2.117V
[Falling Waveform]
R_fixture = 50.000
V_fixture = 0.000
V_fixture_min = 0.000
V_fixture_max = 0.000
|  time   V(typ)   V(min)   V(max)
0s        1.941V     1.839V     2.032V
710ps     1.941V     1.839V     2.011V
870ps     1.944V     1.839V     1.502V
1.06ns    1.881V     1.839V     622.8mV
1.24ns    1.312V     1.841V     130.1mV
1.54ns    245.8mV    1.579V     12.98mV
1.87ns    20.74mV    665.2mV    1.572mV
2.28ns    8.326mV    85.14mV    86.95uV
2.8ns     8.377mV    2.445mV    -21.68uV
200ns     531.9uV    878.7uV    348.5uV
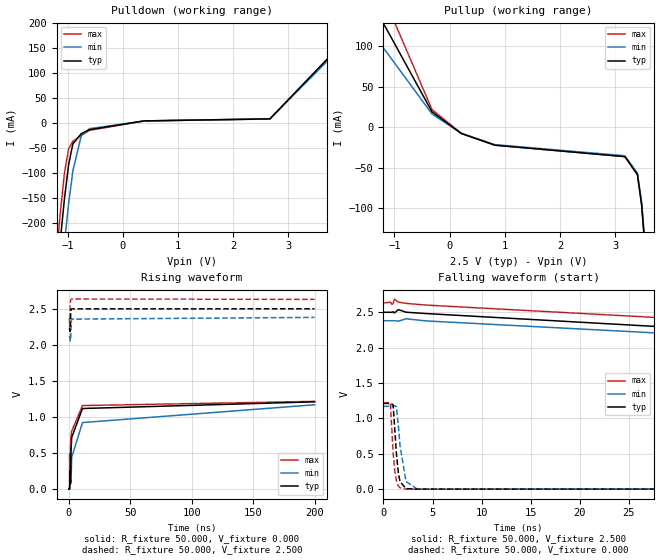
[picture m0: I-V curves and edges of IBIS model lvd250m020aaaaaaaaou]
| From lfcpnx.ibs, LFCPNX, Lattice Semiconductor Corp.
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[Model] lvd250m020aaaaaaaaou
Model_type Output
Polarity   Non-Inverting
Enable   Active-High
Vmeas =  1.250V
Cref =  0.0F
Rref =  1.000M
Vref =  0.0V
C_comp   5.000pF   4.000pF   5.500pF
[Temperature Range]   25.000   0.125k   -40.000
[Voltage Range]   2.500V   2.380V   2.630V
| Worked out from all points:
|   slope of the pulldown table from 0 to 0.375 V, typ, clamps not added: 96.1 ohm
|   slope of the pullup table from 0 to 0.375 V, typ, clamps not added: 28.8 ohm
|   rising waveform, R_fixture 50.000, V_fixture 0.000: 20-80 % time 5.04ns typ, 9.61ns min, 3.52ns max; typ from 0.001 V to 1.21 V
|   rising waveform, R_fixture 50.000, V_fixture 2.500: 20-80 % time 205ps typ, 276ps min, 214ps max; typ from 2.23 V to 2.5 V
|   falling waveform, R_fixture 50.000, V_fixture 2.500: 20-80 % time 17.8ns typ, 19.6ns min, 19.5ns max; typ from 2.5 V to 2.23 V
|   falling waveform, R_fixture 50.000, V_fixture 0.000: 20-80 % time 402ps typ, 600ps min, 357ps max; typ from 1.21 V to 0.001 V
[Pulldown]
|Voltage   I(typ)   I(min)   I(max)
-2.5V     -2.085A    -2.048A    -2.121A
-1.208V   -328.9mA   -411.4mA   -275.6mA
-1.132V   -236mA     -322.8mA   -180.6mA
-1.056V   -151.3mA   -238.4mA   -100.1mA
-980mV    -82.88mA   -161mA     -51.45mA
-904mV    -42.13mA   -96.03mA   -36.78mA
-752mV    -21.55mA   -25.93mA   -25.1mA
-600mV    -13.52mA   -11.55mA   -14.88mA
388mV     3.97mA     3.851mA    3.97mA
2.668V    8.053mA    7.811mA    8.053mA
4.112V    174.1mA    168.9mA    174.1mA
5V        192.3mA    186.5mA    192.3mA
[Pullup]
|Voltage   I(typ)   I(min)   I(max)
-2.5V     187.4mA    139.6mA    231.6mA
-1.84V    183.8mA    137.8mA    227.4mA
-1.46V    156.9mA    119mA      196mA
-1.156V   122.6mA    93.72mA    154.4mA
-320mV    18.94mA    16.29mA    21.79mA
212mV     -7.802mA   -7.568mA   -7.802mA
820mV     -22.24mA   -21.58mA   -22.24mA
3.176V    -36.35mA   -35.26mA   -36.35mA
3.404V    -58.44mA   -56.69mA   -58.44mA
3.48V     -95.35mA   -92.49mA   -95.35mA
3.556V    -160.8mA   -156mA     -160.8mA
5V        -2.091A    -2.029A    -2.091A
[Ramp]
| variable   typ   min   max
dV/dt_r   0.726/5.753n   0.698/10.480n   0.730/4.019n
dV/dt_f   0.163/17.826n   0.159/19.839n   0.164/19.520n
R_load = 50.000
[Rising Waveform]
R_fixture = 50.000
V_fixture = 0.000
V_fixture_min = 0.000
V_fixture_max = 0.000
|  time   V(typ)   V(min)   V(max)
0s        733.4uV    7.04mV     151.9uV
570ps     846.2uV    7.12mV     1.278mV
680ps     1.393mV    6.854mV    491.8mV
830ps     261mV      7.137mV    349.9mV
1.04ns    172.5mV    25.87mV    188.7mV
1.4ns     75.4mV     204.6mV    597.8mV
1.83ns    551.2mV    104.6mV    740.1mV
2.31ns    715mV      437.6mV    802.4mV
11.1ns    1.118V     923.1mV    1.159V
200ns     1.211V     1.17V      1.217V
[Rising Waveform]
R_fixture = 50.000
V_fixture = 2.500
V_fixture_min = 2.380
V_fixture_max = 2.630
|  time   V(typ)   V(min)   V(max)
0s        2.228V     2.116V     2.358V
540ps     2.228V     2.116V     2.358V
630ps     2.228V     2.116V     2.25V
930ps     2.187V     2.116V     2.333V
1.11ns    2.204V     2.054V     2.527V
1.27ns    2.233V     2.077V     2.591V
1.56ns    2.451V     2.105V     2.624V
1.94ns    2.493V     2.298V     2.633V
2.24ns    2.499V     2.357V     2.635V
200ns     2.5V       2.381V     2.631V
[Falling Waveform]
R_fixture = 50.000
V_fixture = 2.500
V_fixture_min = 2.380
V_fixture_max = 2.630
|  time   V(typ)   V(min)   V(max)
0s        2.5V       2.381V     2.631V
720ps     2.5V       2.381V     2.643V
860ps     2.5V       2.381V     2.612V
990ps     2.508V     2.381V     2.623V
1.12ns    2.49V      2.381V     2.687V
1.52ns    2.538V     2.374V     2.644V
2.3ns     2.501V     2.408V     2.626V
4.34ns    2.482V     2.378V     2.602V
36.51ns   2.231V     2.144V     2.361V
200ns     2.228V     2.116V     2.358V
[Falling Waveform]
R_fixture = 50.000
V_fixture = 0.000
V_fixture_min = 0.000
V_fixture_max = 0.000
|  time   V(typ)   V(min)   V(max)
0s        1.211V     1.17V      1.217V
700ps     1.211V     1.17V      1.225V
990ps     1.193V     1.17V      512.3mV
1.15ns    861.1mV    1.179V     263.8mV
1.33ns    493.2mV    1.163V     114.9mV
1.53ns    220.2mV    879.9mV    43mV
1.69ns    106.9mV    614.3mV    18.7mV
2.3ns     6.696mV    107.4mV    -1.098mV
3.44ns    -449.5uV   -108.2uV   -1.47mV
200ns     704.6uV    7.04mV     151.9uV
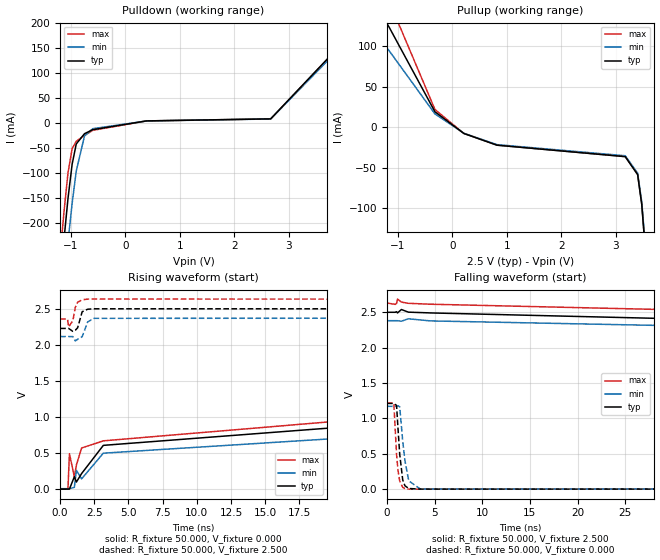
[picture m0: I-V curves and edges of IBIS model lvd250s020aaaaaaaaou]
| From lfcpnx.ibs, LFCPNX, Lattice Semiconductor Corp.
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[Model] lvd250s020aaaaaaaaou
Model_type Output
Polarity   Non-Inverting
Enable   Active-High
Vmeas =  1.250V
Cref =  0.0F
Rref =  1.000M
Vref =  0.0V
C_comp   5.000pF   4.000pF   5.500pF
[Temperature Range]   25.000   0.125k   -40.000
[Voltage Range]   2.500V   2.380V   2.630V
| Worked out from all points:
|   slope of the pulldown table from 0 to 0.375 V, typ, clamps not added: 96.1 ohm
|   slope of the pullup table from 0 to 0.375 V, typ, clamps not added: 28.8 ohm
|   rising waveform, R_fixture 50.000, V_fixture 0.000: 20-80 % time 25.4ns typ, 40.1ns min, 18.5ns max; typ from 0.001 V to 1.21 V
|   rising waveform, R_fixture 50.000, V_fixture 2.500: 20-80 % time 217ps typ, 290ps min, 224ps max; typ from 2.23 V to 2.5 V
|   falling waveform, R_fixture 50.000, V_fixture 2.500: 20-80 % time 46ns typ, 50.5ns min, 50.6ns max; typ from 2.5 V to 2.23 V
|   falling waveform, R_fixture 50.000, V_fixture 0.000: 20-80 % time 402ps typ, 598ps min, 357ps max; typ from 1.21 V to 0.001 V
[Pulldown]
|Voltage   I(typ)   I(min)   I(max)
-2.5V     -2.085A    -2.048A    -2.121A
-1.208V   -328.9mA   -411.4mA   -275.6mA
-1.132V   -236mA     -322.8mA   -180.6mA
-1.056V   -151.3mA   -238.4mA   -100.1mA
-980mV    -82.88mA   -161mA     -51.45mA
-904mV    -42.13mA   -96.03mA   -36.78mA
-752mV    -21.55mA   -25.93mA   -25.1mA
-600mV    -13.52mA   -11.55mA   -14.88mA
388mV     3.97mA     3.851mA    3.97mA
2.668V    8.053mA    7.811mA    8.053mA
4.112V    174.1mA    168.9mA    174.1mA
5V        192.3mA    186.5mA    192.3mA
[Pullup]
|Voltage   I(typ)   I(min)   I(max)
-2.5V     187.4mA    139.6mA    231.6mA
-1.84V    183.8mA    137.8mA    227.4mA
-1.46V    156.9mA    119mA      196mA
-1.156V   122.6mA    93.72mA    154.4mA
-320mV    18.94mA    16.29mA    21.79mA
212mV     -7.802mA   -7.568mA   -7.802mA
820mV     -22.24mA   -21.58mA   -22.24mA
3.176V    -36.35mA   -35.26mA   -36.35mA
3.404V    -58.44mA   -56.69mA   -58.44mA
3.48V     -95.35mA   -92.49mA   -95.35mA
3.556V    -160.8mA   -156mA     -160.8mA
5V        -2.091A    -2.029A    -2.091A
[Ramp]
| variable   typ   min   max
dV/dt_r   0.726/26.132n   0.698/41.082n   0.730/19.062n
dV/dt_f   0.163/46.010n   0.159/51.582n   0.164/50.583n
R_load = 50.000
[Rising Waveform]
R_fixture = 50.000
V_fixture = 0.000
V_fixture_min = 0.000
V_fixture_max = 0.000
|  time   V(typ)   V(min)   V(max)
0s        733.4uV    7.04mV     151.9uV
570ps     846.4uV    7.12mV     2.099mV
680ps     1.394mV    6.854mV    492.2mV
1.04ns    172.9mV    25.93mV    170.2mV
1.19ns    99.11mV    262mV      335.9mV
1.57ns    216.4mV    143.2mV    570.4mV
3.16ns    607.4mV    499.2mV    670mV
33.15ns   1.042V     857.2mV    1.147V
74.52ns   1.188V     1.129V     1.196V
200ns     1.211V     1.17V      1.217V
[Rising Waveform]
R_fixture = 50.000
V_fixture = 2.500
V_fixture_min = 2.380
V_fixture_max = 2.630
|  time   V(typ)   V(min)   V(max)
0s        2.228V     2.116V     2.358V
540ps     2.228V     2.116V     2.358V
620ps     2.228V     2.116V     2.249V
930ps     2.187V     2.116V     2.334V
1.11ns    2.203V     2.054V     2.521V
1.28ns    2.237V     2.078V     2.591V
1.61ns    2.459V     2.112V     2.625V
2.01ns    2.494V     2.317V     2.634V
2.44ns    2.5V       2.368V     2.635V
200ns     2.5V       2.381V     2.631V
[Falling Waveform]
R_fixture = 50.000
V_fixture = 2.500
V_fixture_min = 2.380
V_fixture_max = 2.630
|  time   V(typ)   V(min)   V(max)
0s        2.5V       2.381V     2.631V
860ps     2.5V       2.381V     2.612V
990ps     2.508V     2.381V     2.623V
1.1ns     2.491V     2.381V     2.687V
1.51ns    2.539V     2.374V     2.644V
2.24ns    2.502V     2.408V     2.627V
4.57ns    2.491V     2.378V     2.614V
83.06ns   2.237V     2.168V     2.371V
111.8ns   2.228V     2.119V     2.358V
200ns     2.228V     2.116V     2.358V
[Falling Waveform]
R_fixture = 50.000
V_fixture = 0.000
V_fixture_min = 0.000
V_fixture_max = 0.000
|  time   V(typ)   V(min)   V(max)
0s        1.211V     1.17V      1.217V
710ps     1.211V     1.17V      1.218V
1ns       1.183V     1.17V      493.4mV
1.15ns    862.3mV    1.179V     263.8mV
1.33ns    494mV      1.163V     114.9mV
1.65ns    128.3mV    674.8mV    23.91mV
1.88ns    46.86mV    403.1mV    6.488mV
2.28ns    7.788mV    116.2mV    -944.1uV
3.5ns     -455uV     -207.8uV   -1.486mV
200ns     704.6uV    7.04mV     151.9uV
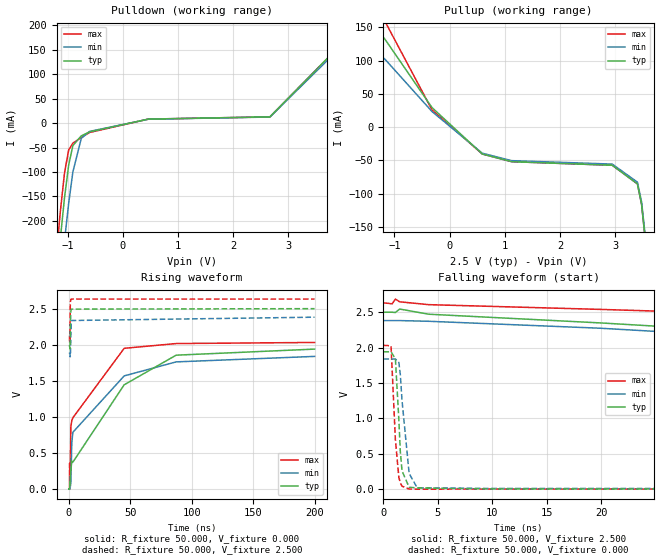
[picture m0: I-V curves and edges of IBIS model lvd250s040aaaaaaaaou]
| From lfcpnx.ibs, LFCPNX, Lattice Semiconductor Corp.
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[Model] lvd250s040aaaaaaaaou
Model_type Output
Polarity   Non-Inverting
Enable   Active-High
Vmeas =  1.250V
Cref =  0.0F
Rref =  1.000M
Vref =  0.0V
C_comp   5.000pF   4.000pF   5.500pF
[Temperature Range]   25.000   0.125k   -40.000
[Voltage Range]   2.500V   2.380V   2.630V
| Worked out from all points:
|   slope of the pulldown table from 0 to 0.375 V, typ, clamps not added: 52.3 ohm
|   slope of the pullup table from 0 to 0.375 V, typ, clamps not added: 13.2 ohm
|   rising waveform, R_fixture 50.000, V_fixture 0.000: 20-80 % time 42.6ns typ, 34ns min, 25.1ns max; typ from 0.001 V to 1.94 V
|   rising waveform, R_fixture 50.000, V_fixture 2.500: 20-80 % time 362ps typ, 420ps min, 166ps max; typ from 1.99 V to 2.5 V
|   falling waveform, R_fixture 50.000, V_fixture 2.500: 20-80 % time 33.9ns typ, 34ns min, 63.3ns max; typ from 2.5 V to 1.99 V
|   falling waveform, R_fixture 50.000, V_fixture 0.000: 20-80 % time 408ps typ, 636ps min, 378ps max; typ from 1.94 V to 0.001 V
[Pulldown]
|Voltage   I(typ)   I(min)   I(max)
-2.5V     -2.087A    -2.05A     -2.122A
-1.208V   -330.7mA   -414.1mA   -277.2mA
-1.132V   -238.1mA   -325.6mA   -182.4mA
-1.056V   -153.6mA   -241.4mA   -102.6mA
-980mV    -86mA      -164.4mA   -55.18mA
-904mV    -46.21mA   -100mA     -41.14mA
-752mV    -26.2mA    -31.37mA   -29.5mA
-600mV    -17.96mA   -17.01mA   -19.2mA
464mV     8.134mA    7.89mA     8.134mA
2.668V    12.76mA    12.38mA    12.76mA
4.112V    178.7mA    173.3mA    178.7mA
5V        197.1mA    191.2mA    197.1mA
[Pullup]
|Voltage   I(typ)   I(min)   I(max)
-2.5V     189.4mA    141.7mA    232mA
-1.84V    186.8mA    140.8mA    228.1mA
-1.384V   155.4mA    119.1mA    188.3mA
-1.156V   130.2mA    100.6mA    156.5mA
-320mV    29.46mA    23.51mA    26.02mA
592mV     -40.38mA   -39.17mA   -40.38mA
1.124V    -51.9mA    -50.35mA   -51.9mA
2.948V    -57.25mA   -55.53mA   -57.25mA
3.404V    -85.21mA   -82.65mA   -85.21mA
3.48V     -116.2mA   -112.7mA   -116.2mA
3.556V    -176.5mA   -171.2mA   -176.5mA
5V        -2.101A    -2.038A    -2.101A
[Ramp]
| variable   typ   min   max
dV/dt_r   1.152/48.065n   1.103/34.028n   1.219/24.825n
dV/dt_f   0.308/34.177n   0.312/34.805n   0.310/63.354n
R_load = 50.000
[Rising Waveform]
R_fixture = 50.000
V_fixture = 0.000
V_fixture_min = 0.000
V_fixture_max = 0.000
|  time   V(typ)   V(min)   V(max)
0s        571.8uV    878.3uV    348.5uV
570ps     742.5uV    911uV      1.708mV
670ps     1.384mV    601.6uV    358.2mV
1.03ns    132.1mV    7.335mV    110mV
1.7ns     272.9mV    97.64mV    869.3mV
2.41ns    390.9mV    641.9mV    947.3mV
3.3ns     374.8mV    788.3mV    989.6mV
45.06ns   1.446V     1.569V     1.951V
87.36ns   1.856V     1.763V     2.017V
200ns     1.94V      1.839V     2.032V
[Rising Waveform]
R_fixture = 50.000
V_fixture = 2.500
V_fixture_min = 2.380
V_fixture_max = 2.630
|  time   V(typ)   V(min)   V(max)
0s        1.987V     1.882V     2.117V
540ps     1.987V     1.882V     2.117V
620ps     1.987V     1.882V     2.023V
900ps     1.941V     1.883V     2.093V
970ps     1.946V     1.883V     2.155V
1.11ns    2.1V       1.833V     2.475V
1.28ns    2.242V     1.847V     2.588V
1.57ns    2.452V     2.046V     2.625V
2ns       2.494V     2.336V     2.633V
200ns     2.5V       2.382V     2.633V
[Falling Waveform]
R_fixture = 50.000
V_fixture = 2.500
V_fixture_min = 2.380
V_fixture_max = 2.630
|  time   V(typ)   V(min)   V(max)
0s        2.5V       2.382V     2.633V
800ps     2.5V       2.382V     2.619V
1.1ns     2.496V     2.382V     2.686V
1.49ns    2.545V     2.382V     2.647V
4.16ns    2.472V     2.372V     2.607V
19.9ns    2.349V     2.274V     2.54V
52.44ns   2.056V     1.986V     2.387V
63.78ns   1.997V     1.928V     2.331V
110.1ns   1.987V     1.882V     2.126V
200ns     1.987V     1.882V     2.117V
[Falling Waveform]
R_fixture = 50.000
V_fixture = 0.000
V_fixture_min = 0.000
V_fixture_max = 0.000
|  time   V(typ)   V(min)   V(max)
0s        1.941V     1.839V     2.032V
700ps     1.941V     1.839V     2.026V
1.1ns     1.841V     1.839V     699.5mV
1.42ns    973.6mV    1.79V      163.1mV
1.55ns    534mV      1.621V     88.49mV
1.71ns    257.2mV    1.25V      42.05mV
2.36ns    27.48mV    221.8mV    1.804mV
3.1ns     17.32mV    19.57mV    163.8uV
9.42ns    3.757mV    10.98mV    2.388mV
200ns     531.9uV    878.3uV    348.5uV
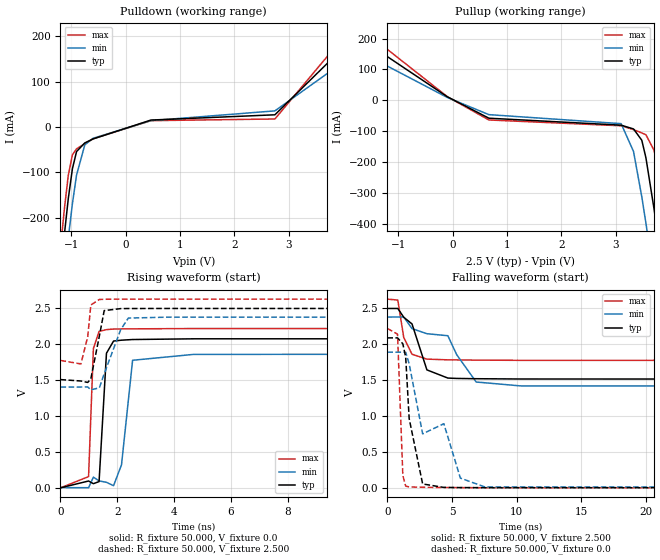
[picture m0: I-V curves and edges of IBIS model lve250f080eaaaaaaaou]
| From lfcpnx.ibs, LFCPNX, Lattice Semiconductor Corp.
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[Model] lve250f080eaaaaaaaou
Model_type Output
Polarity   Non-Inverting
Enable   Active-High
Vmeas =  1.250V
Cref =  0.0F
Rref =  1.000M
Vref =  0.0V
C_comp   5.000pF   4.000pF   5.500pF
[Temperature Range]   25.000   0.125k   -40.000
[Voltage Range]   2.500V   2.380V   2.630V
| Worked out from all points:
|   slope of the pulldown table from 0 to 0.375 V, typ, clamps not added: 28.4 ohm
|   slope of the pullup table from 0 to 0.375 V, typ, clamps not added: 9.65 ohm
|   rising waveform, R_fixture 50.000, V_fixture 0.0: 20-80 % time 136ps typ, 230ps min, 100ps max; typ from 0 V to 2.09 V
|   rising waveform, R_fixture 50.000, V_fixture 2.500: 20-80 % time 262ps typ, 562ps min, 189ps max; typ from 1.51 V to 2.5 V
|   falling waveform, R_fixture 50.000, V_fixture 2.500: 20-80 % time 1.28ns typ, 3.84ns min, 629ps max; typ from 2.5 V to 1.51 V
|   falling waveform, R_fixture 50.000, V_fixture 0.0: 20-80 % time 802ps typ, 2.95ns min, 252ps max; typ from 2.09 V to 0 V
[Pulldown]
|Voltage   I(typ)   I(min)   I(max)
-2.5V     -2.09A     -2.054A    -2.124A
-1.208V   -334.4mA   -418.2mA   -279.9mA
-1.132V   -242.1mA   -329.9mA   -185.5mA
-1.056V   -158.5mA   -246mA     -106.9mA
-980mV    -92.29mA   -169.5mA   -61.46mA
-904mV    -54.37mA   -106.2mA   -48.38mA
-752mV    -35.3mA    -39.58mA   -36.74mA
-600mV    -26.52mA   -25.04mA   -26.25mA
464mV     15.18mA    13.86mA    13.87mA
2.744V    26.8mA     35.45mA    17.54mA
4.112V    187.9mA    152.6mA    213.6mA
5V        206.7mA    158.7mA    248.4mA
[Pullup]
|Voltage   I(typ)   I(min)   I(max)
-2.5V     194.2mA    148.2mA    234mA
-1.536V   181.3mA    142mA      211.9mA
-92mV     10.98mA    8.759mA    11.26mA
668mV     -58.06mA   -46.51mA   -63.83mA
3.1V      -80.66mA   -75.75mA   -82.66mA
3.328V    -92.94mA   -166mA     -95.03mA
3.48V     -129.5mA   -312.9mA   -105.9mA
3.556V    -186.4mA   -398.4mA   -111.8mA
3.708V    -355.1mA   -579.2mA   -163mA
3.784V    -450.5mA   -672.4mA   -238.3mA
3.936V    -649.5mA   -861.8mA   -431.6mA
5V        -2.107A    -2.224A    -1.953A
[Ramp]
| variable   typ   min   max
dV/dt_r   1.252/0.141n   1.132/0.232n   1.333/0.109n
dV/dt_f   0.595/1.289n   0.585/3.846n   0.512/0.630n
R_load = 50.000
[Rising Waveform]
R_fixture= 50.000
V_fixture= 0.0
V_fixture_min= 0.0
V_fixture_max= 0.0
|time   V(typ)   V(min)   V(max)
0s        369.2uV    3.659mV    105.5uV
990ps     95.65mV    2.224mV    156.9mV
1.16ns    58.41mV    149.7mV    1.943V
1.36ns    87.56mV    97.16mV    2.18V
1.62ns    1.876V     77.53mV    2.205V
1.87ns    2.046V     29.96mV    2.213V
2.15ns    2.058V     322mV      2.215V
2.54ns    2.067V     1.778V     2.216V
4.69ns    2.077V     1.86V      2.22V
200ns     2.088V     1.889V     2.222V
[Rising Waveform]
R_fixture= 50.000
V_fixture= 2.500
V_fixture_min= 2.380
V_fixture_max= 2.630
|time   V(typ)   V(min)   V(max)
0s        1.509V     1.405V     1.776V
720ps     1.489V     1.405V     1.727V
960ps     1.469V     1.407V     2.106V
1.07ns    1.52V      1.366V     2.549V
1.37ns    2.115V     1.394V     2.625V
1.54ns    2.47V      1.589V     2.628V
2.12ns    2.498V     2.204V     2.63V
2.39ns    2.499V     2.366V     2.63V
3.81ns    2.5V       2.379V     2.63V
200ns     2.5V       2.38V      2.63V
[Falling Waveform]
R_fixture= 50.000
V_fixture= 2.500
V_fixture_min= 2.380
V_fixture_max= 2.630
|time   V(typ)   V(min)   V(max)
0s        2.5V       2.38V      2.63V
810ps     2.5V       2.381V     2.617V
1.27ns    2.377V     2.381V     2.095V
1.91ns    2.284V     2.219V     1.862V
3.06ns    1.644V     2.148V     1.794V
4.68ns    1.53V      2.12V      1.784V
5.36ns    1.525V     1.857V     1.783V
6.87ns    1.521V     1.475V     1.78V
10.3ns    1.517V     1.421V     1.777V
200ns     1.509V     1.405V     1.776V
[Falling Waveform]
R_fixture= 50.000
V_fixture= 0.0
V_fixture_min= 0.0
V_fixture_max= 0.0
|time   V(typ)   V(min)   V(max)
0s        2.09V      1.891V     2.222V
790ps     2.09V      1.891V     2.142V
1.2ns     2.007V     1.891V     170.6mV
1.42ns    1.821V     1.888V     24.94mV
1.69ns    963.8mV    1.728V     12.8mV
2.73ns    54.64mV    752.7mV    8.185mV
4.37ns    6.167mV    894.1mV    5.032mV
5.65ns    4.013mV    135.6mV    3.466mV
7.55ns    2.693mV    12.6mV     1.981mV
200ns     369.6uV    3.659mV    105.7uV
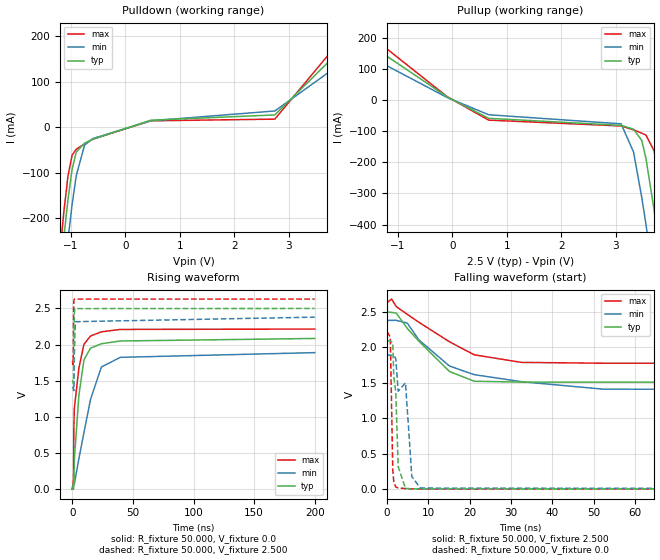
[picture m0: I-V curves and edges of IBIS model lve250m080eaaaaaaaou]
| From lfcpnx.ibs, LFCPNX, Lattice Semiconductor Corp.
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|Model lve250m080eaaaaaaaou
[Model] lve250m080eaaaaaaaou
Model_type Output
Polarity   Non-Inverting
Enable   Active-High
Vmeas =  1.250V
Cref =  0.0F
Rref =  1.000M
Vref =  0.0V
C_comp   5.000pF   4.000pF   5.500pF
[Temperature Range]   25.000   0.125k   -40.000
[Voltage Range]   2.500V   2.380V   2.630V
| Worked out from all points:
|   slope of the pulldown table from 0 to 0.375 V, typ, clamps not added: 28.4 ohm
|   slope of the pullup table from 0 to 0.375 V, typ, clamps not added: 9.65 ohm
|   rising waveform, R_fixture 50.000, V_fixture 0.0: 20-80 % time 6.45ns typ, 14.4ns min, 5.09ns max; typ from 0 V to 2.08 V
|   rising waveform, R_fixture 50.000, V_fixture 2.500: 20-80 % time 354ps typ, 646ps min, 234ps max; typ from 1.51 V to 2.5 V
|   falling waveform, R_fixture 50.000, V_fixture 2.500: 20-80 % time 9.79ns typ, 16.2ns min, 14.1ns max; typ from 2.5 V to 1.51 V
|   falling waveform, R_fixture 50.000, V_fixture 0.0: 20-80 % time 1.04ns typ, 1.27ns min, 377ps max; typ from 2.09 V to 0 V
[Pulldown]
|Voltage   I(typ)   I(min)   I(max)
-2.5V     -2.09A     -2.054A    -2.124A
-1.208V   -334.4mA   -418.2mA   -279.9mA
-1.132V   -242.1mA   -329.9mA   -185.5mA
-1.056V   -158.5mA   -246mA     -106.9mA
-980mV    -92.29mA   -169.5mA   -61.46mA
-904mV    -54.37mA   -106.2mA   -48.38mA
-752mV    -35.3mA    -39.58mA   -36.74mA
-600mV    -26.52mA   -25.04mA   -26.25mA
464mV     15.18mA    13.86mA    13.87mA
2.744V    26.8mA     35.45mA    17.54mA
4.112V    187.9mA    152.6mA    213.6mA
5V        206.7mA    158.7mA    248.4mA
[Pullup]
|Voltage   I(typ)   I(min)   I(max)
-2.5V     194.2mA    148.2mA    234mA
-1.536V   181.3mA    142mA      211.9mA
-92mV     10.98mA    8.759mA    11.26mA
668mV     -58.06mA   -46.51mA   -63.83mA
3.1V      -80.66mA   -75.75mA   -82.66mA
3.328V    -92.94mA   -166mA     -95.03mA
3.48V     -129.5mA   -312.9mA   -105.9mA
3.556V    -186.4mA   -398.4mA   -111.8mA
3.708V    -355.1mA   -579.2mA   -163mA
3.784V    -450.5mA   -672.4mA   -238.3mA
3.936V    -649.5mA   -861.8mA   -431.6mA
5V        -2.107A    -2.224A    -1.953A
[Ramp]
| variable   typ   min   max
dV/dt_r   1.251/6.428n   1.131/14.378n   1.329/5.081n
dV/dt_f   0.595/9.884n   0.585/16.042n   0.512/14.171n
R_load = 50.000
[Rising Waveform]
R_fixture= 50.000
V_fixture= 0.0
V_fixture_min= 0.0
V_fixture_max= 0.0
|time   V(typ)   V(min)   V(max)
0s        369.2uV    3.659mV    105.5uV
1.01ns    86.19mV    1.606mV    131.3mV
1.3ns     59.88mV    111.7mV    838.8mV
1.69ns    402.7mV    71.37mV    1.118V
5.46ns    1.3V       422.3mV    1.676V
9.62ns    1.789V     783mV      2.004V
15ns      1.95V      1.238V     2.118V
24ns      2.012V     1.69V      2.177V
39.6ns    2.05V      1.824V     2.21V
200ns     2.085V     1.889V     2.215V
[Rising Waveform]
R_fixture= 50.000
V_fixture= 2.500
V_fixture_min= 2.380
V_fixture_max= 2.630
|time   V(typ)   V(min)   V(max)
0s        1.509V     1.405V     1.776V
720ps     1.489V     1.405V     1.722V
960ps     1.461V     1.407V     2.095V
1.05ns    1.492V     1.374V     2.376V
1.16ns    1.71V      1.364V     2.56V
1.35ns    2.042V     1.372V     2.613V
1.7ns     2.434V     1.798V     2.628V
2.17ns    2.493V     2.174V     2.63V
2.62ns    2.498V     2.317V     2.63V
200ns     2.5V       2.38V      2.63V
[Falling Waveform]
R_fixture= 50.000
V_fixture= 2.500
V_fixture_min= 2.380
V_fixture_max= 2.630
|time   V(typ)   V(min)   V(max)
0s        2.5V       2.38V      2.63V
1.11ns    2.493V     2.38V      2.681V
2.25ns    2.482V     2.381V     2.574V
4.92ns    2.265V     2.341V     2.465V
7.66ns    2.09V      2.108V     2.356V
15.1ns    1.66V      1.737V     2.079V
21.1ns    1.522V     1.615V     1.895V
32.52ns   1.51V      1.516V     1.788V
52.41ns   1.509V     1.41V      1.776V
200ns     1.509V     1.405V     1.776V
[Falling Waveform]
R_fixture= 50.000
V_fixture= 0.0
V_fixture_min= 0.0
V_fixture_max= 0.0
|time   V(typ)   V(min)   V(max)
0s        2.09V      1.891V     2.222V
790ps     2.09V      1.891V     2.145V
1.39ns    2.064V     1.89V      267.6mV
1.64ns    1.589V     1.889V     98.14mV
2.12ns    1.37V      1.84V      29.68mV
2.7ns     318.9mV    1.381V     17.82mV
4.47ns    10.61mV    1.5V       8.272mV
6ns       5.539mV    178.5mV    4.764mV
8.07ns    3.226mV    15.51mV    2.348mV
200ns     369.6uV    3.659mV    105.7uV
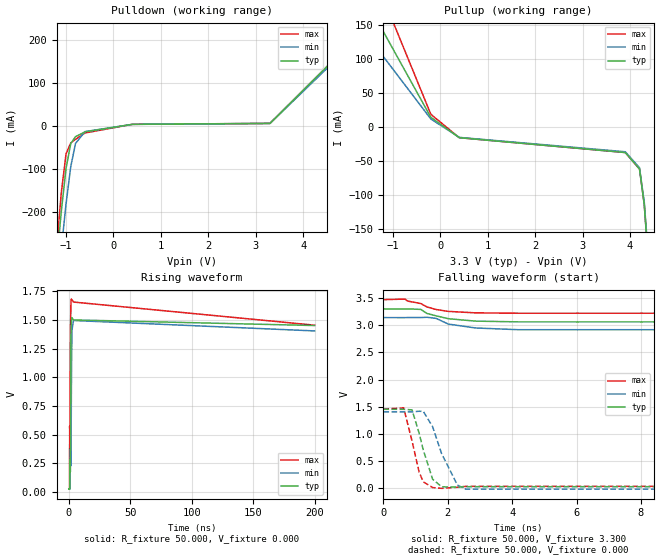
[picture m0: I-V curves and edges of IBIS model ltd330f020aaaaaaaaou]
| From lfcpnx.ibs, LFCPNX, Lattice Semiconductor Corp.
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|Model ltd330f020aaaaaaaaou
[Model] ltd330f020aaaaaaaaou
Model_type Output
Polarity   Non-Inverting
Enable   Active-High
Vmeas =  1.650V
Cref =  0.0F
Rref =  1.000M
Vref =  0.0V
C_comp   5.000pF   4.000pF   5.500pF
[Temperature Range]   25.000   0.125k   -40.000
[Voltage Range]   3.300V   3.140V   3.470V
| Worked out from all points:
|   slope of the pulldown table from 0 to 0.495 V, typ, clamps not added: 109 ohm
|   slope of the pullup table from 0 to 0.495 V, typ, clamps not added: 26.9 ohm
|   rising waveform, R_fixture 50.000, V_fixture 0.000: 20-80 % time 265ps typ, 338ps min, 579ps max; typ from 0.025 V to 1.45 V
|   falling waveform, R_fixture 50.000, V_fixture 3.300: 20-80 % time 891ps typ, 991ps min, 687ps max; typ from 3.3 V to 3.06 V
|   falling waveform, R_fixture 50.000, V_fixture 0.000: 20-80 % time 398ps typ, 587ps min, 321ps max; typ from 1.45 V to 0.025 V
[Pulldown]
|Voltage   I(typ)   I(min)   I(max)
-3.3V     -3.198A    -3.088A    -3.549A
-1.2V     -320.1mA   -403.9mA   -287.6mA
-1.1V     -200.2mA   -288.6mA   -156.7mA
-1V       -99.68mA   -182.4mA   -65.99mA
-900mV    -41.7mA    -95.18mA   -40.08mA
-800mV    -25.46mA   -41.35mA   -31.63mA
-600mV    -14.31mA   -13.67mA   -16.83mA
400mV     3.234mA    3.137mA    3.234mA
3.3V      5.419mA    5.256mA    5.419mA
5V        192.3mA    186.5mA    192.3mA
6.3V      201.8mA    195.7mA    201.8mA
6.6V      230.5mA    223.6mA    230.5mA
[Pullup]
|Voltage   I(typ)   I(min)   I(max)
-3.3V     225.4mA    159.1mA    312.7mA
-3.1V     202.4mA    147.4mA    288.4mA
-2.7V     172mA      129.2mA    248.8mA
-1.5V     172mA      124.8mA    232.2mA
-1.3V     152.6mA    112.6mA    206mA
-200mV    14.46mA    11.99mA    18.87mA
400mV     -15.49mA   -15.03mA   -15.49mA
3.9V      -37.26mA   -36.14mA   -37.26mA
4.2V      -61.49mA   -59.65mA   -61.49mA
4.3V      -113.5mA   -110.1mA   -113.5mA
4.4V      -210.4mA   -204.1mA   -210.4mA
6.6V      -3.205A    -3.109A    -3.205A
[Ramp]
| variable   typ   min   max
dV/dt_r   0.856/0.272n   0.828/1.071n   0.858/0.634n
dV/dt_f   0.144/0.899n   0.139/0.993n   0.150/0.841n
R_load = 50.000
[Rising Waveform]
R_fixture = 50.000
V_fixture = 0.000
V_fixture_min = 0.000
V_fixture_max = 0.000
|  time   V(typ)   V(min)   V(max)
0s        25.4mV     24.93mV    25.4mV
560ps     25.53mV    25.01mV    26.51mV
700ps     23.99mV    24.63mV    575mV
950ps     286.2mV    25.43mV    416.3mV
1.27ns    175.3mV    372.7mV    1.376V
1.8ns     1.41V      229.4mV    1.678V
2.09ns    1.498V     907.7mV    1.683V
2.5ns     1.521V     1.407V     1.677V
3.78ns    1.501V     1.496V     1.657V
200ns     1.452V     1.405V     1.455V
[Falling Waveform]
R_fixture = 50.000
V_fixture = 3.300
V_fixture_min = 3.140
V_fixture_max = 3.470
|  time   V(typ)   V(min)   V(max)
0s        3.3V       3.14V      3.47V
670ps     3.3V       3.139V     3.481V
750ps     3.3V       3.141V     3.444V
1.16ns    3.291V     3.141V     3.399V
1.35ns    3.217V     3.146V     3.337V
1.64ns    3.172V     3.125V     3.288V
2.02ns    3.119V     3.02V      3.254V
2.86ns    3.075V     2.949V     3.227V
4.2ns     3.061V     2.917V     3.22V
200ns     3.06V      2.909V     3.221V
[Falling Waveform]
R_fixture = 50.000
V_fixture = 0.000
V_fixture_min = 0.000
V_fixture_max = 0.000
|  time   V(typ)   V(min)   V(max)
0s        1.452V     1.405V     1.455V
630ps     1.452V     1.405V     1.478V
890ps     1.441V     1.405V     865.9mV
1.11ns    1.012V     1.416V     294.7mV
1.24ns    699.4mV    1.413V     116.1mV
1.53ns    164.6mV    1.131V     11.27mV
1.81ns    25.39mV    634mV      -4.001mV
2.3ns     17.99mV    57.15mV    16.91mV
2.56ns    26.97mV    -18.44mV   33.52mV
200ns     25.15mV    24.93mV    25.4mV
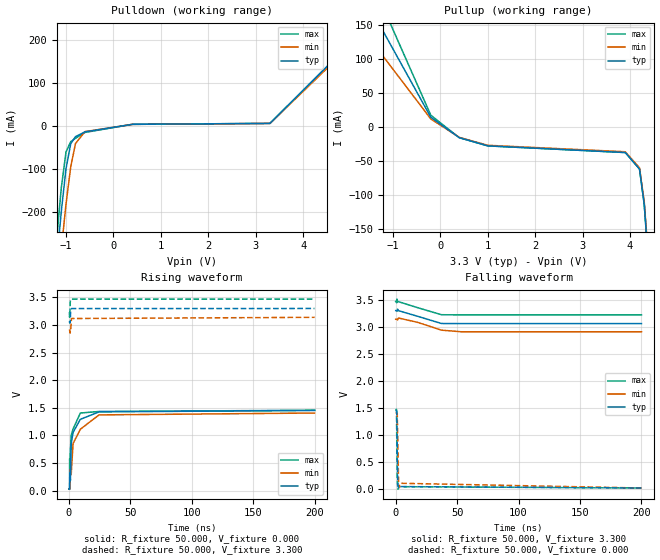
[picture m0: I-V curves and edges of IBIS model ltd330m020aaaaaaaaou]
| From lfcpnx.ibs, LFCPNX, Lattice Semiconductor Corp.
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[Model] ltd330m020aaaaaaaaou
Model_type Output
Polarity   Non-Inverting
Enable   Active-High
Vmeas =  1.650V
Cref =  0.0F
Rref =  1.000M
Vref =  0.0V
C_comp   5.000pF   4.000pF   5.500pF
[Temperature Range]   25.000   0.125k   -40.000
[Voltage Range]   3.300V   3.140V   3.470V
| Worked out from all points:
|   slope of the pulldown table from 0 to 0.495 V, typ, clamps not added: 109 ohm
|   slope of the pullup table from 0 to 0.495 V, typ, clamps not added: 26.9 ohm
|   rising waveform, R_fixture 50.000, V_fixture 0.000: 20-80 % time 4.88ns typ, 8ns min, 3.83ns max; typ from 0.025 V to 1.45 V
|   rising waveform, R_fixture 50.000, V_fixture 3.300: 20-80 % time 205ps typ, 288ps min, 211ps max; typ from 3.06 V to 3.3 V
|   falling waveform, R_fixture 50.000, V_fixture 3.300: 20-80 % time 16.6ns typ, 19.3ns min, 18.2ns max; typ from 3.3 V to 3.06 V
|   falling waveform, R_fixture 50.000, V_fixture 0.000: 20-80 % time 480ps typ, 680ps min, 393ps max; typ from 1.45 V to 0.025 V
[Pulldown]
|Voltage   I(typ)   I(min)   I(max)
-3.3V     -3.198A    -3.088A    -3.286A
-1.2V     -320.1mA   -403.9mA   -266.3mA
-1.1V     -200.2mA   -288.6mA   -145.1mA
-1V       -99.68mA   -182.4mA   -61.1mA
-900mV    -41.7mA    -95.18mA   -37.11mA
-800mV    -25.46mA   -41.35mA   -29.28mA
-600mV    -14.31mA   -13.67mA   -15.59mA
400mV     3.234mA    3.137mA    3.234mA
3.3V      5.419mA    5.256mA    5.419mA
5V        192.3mA    186.5mA    192.3mA
6.3V      201.8mA    195.7mA    201.8mA
6.6V      230.5mA    223.6mA    230.5mA
[Pullup]
|Voltage   I(typ)   I(min)   I(max)
-3.3V     225.4mA    159.1mA    289.5mA
-2.6V     172mA      126.4mA    227.2mA
-1.5V     172mA      124.8mA    215mA
-1.3V     152.6mA    112.6mA    190.7mA
-200mV    14.46mA    11.99mA    17.47mA
400mV     -15.49mA   -15.03mA   -15.49mA
1V        -27.48mA   -26.65mA   -27.48mA
3.9V      -37.26mA   -36.14mA   -37.26mA
4.2V      -61.49mA   -59.65mA   -61.49mA
4.3V      -113.5mA   -110.1mA   -113.5mA
4.4V      -210.4mA   -204.1mA   -210.4mA
6.6V      -3.205A    -3.109A    -3.205A
[Ramp]
| variable   typ   min   max
dV/dt_r   0.842/5.486n   0.828/8.917n   0.858/3.822n
dV/dt_f   0.144/16.628n   0.139/19.850n   0.150/18.188n
R_load = 50.000
[Rising Waveform]
R_fixture = 50.000
V_fixture = 0.000
V_fixture_min = 0.000
V_fixture_max = 0.000
|  time   V(typ)   V(min)   V(max)
0s        25.4mV     24.93mV    25.4mV
560ps     25.54mV    25.02mV    26.54mV
690ps     24.52mV    24.63mV    578.5mV
850ps     319.7mV    25.29mV    486.4mV
1.29ns    181.6mV    381.5mV    734.9mV
1.93ns    844.2mV    288.4mV    999.9mV
3.45ns    1.052V     851.1mV    1.114V
9.37ns    1.291V     1.111V     1.405V
24.6ns    1.426V     1.371V     1.433V
200ns     1.452V     1.405V     1.455V
[Rising Waveform]
R_fixture = 50.000
V_fixture = 3.300
V_fixture_min = 3.140
V_fixture_max = 3.470
|  time   V(typ)   V(min)   V(max)
0s        3.06V      2.909V     3.221V
530ps     3.06V      2.909V     3.223V
610ps     3.06V      2.909V     3.142V
910ps     3.034V     2.909V     3.213V
1.08ns    3.046V     2.854V     3.375V
1.23ns    3.077V     2.882V     3.433V
1.4ns     3.219V     2.892V     3.456V
1.54ns    3.269V     2.905V     3.464V
2.18ns    3.299V     3.118V     3.471V
200ns     3.3V       3.14V      3.47V
[Falling Waveform]
R_fixture = 50.000
V_fixture = 3.300
V_fixture_min = 3.140
V_fixture_max = 3.470
|  time   V(typ)   V(min)   V(max)
0s        3.3V       3.14V      3.47V
680ps     3.3V       3.139V     3.48V
770ps     3.3V       3.141V     3.443V
1.08ns    3.289V     3.14V      3.513V
1.49ns    3.328V     3.126V     3.472V
2.24ns    3.299V     3.164V     3.465V
18ns      3.194V     3.082V     3.353V
37.24ns   3.062V     2.939V     3.224V
53.38ns   3.06V      2.909V     3.221V
200ns     3.06V      2.909V     3.221V
[Falling Waveform]
R_fixture = 50.000
V_fixture = 0.000
V_fixture_min = 0.000
V_fixture_max = 0.000
|  time   V(typ)   V(min)   V(max)
0s        1.452V     1.405V     1.455V
630ps     1.452V     1.405V     1.479V
880ps     1.449V     1.406V     915.8mV
1.26ns    741.9mV    1.407V     205.3mV
1.58ns    239.4mV    1.054V     39.38mV
1.91ns    55.78mV    666.7mV    3.847mV
2.34ns    32.57mV    138.2mV    26.71mV
2.7ns     46.01mV    30.29mV    53.87mV
4.83ns    51.3mV     112.1mV    49.63mV
200ns     25.15mV    24.93mV    25.4mV
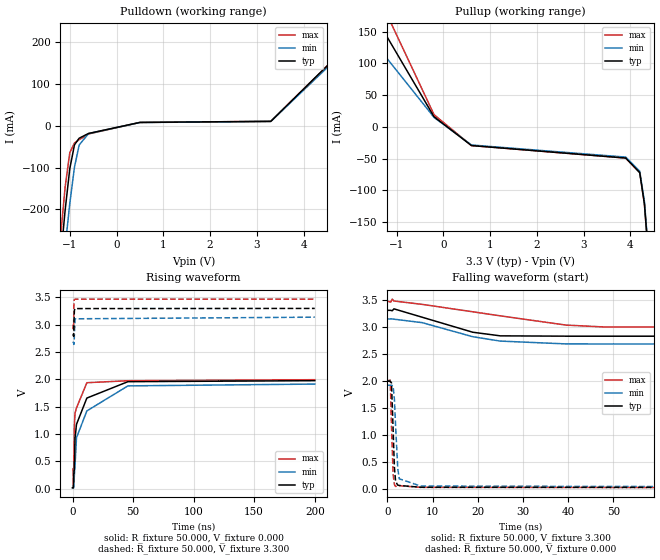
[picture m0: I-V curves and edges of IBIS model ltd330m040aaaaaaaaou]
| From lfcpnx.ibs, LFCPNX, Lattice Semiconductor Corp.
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[Model] ltd330m040aaaaaaaaou
Model_type Output
Polarity   Non-Inverting
Enable   Active-High
Vmeas =  1.650V
Cref =  0.0F
Rref =  1.000M
Vref =  0.0V
C_comp   5.000pF   4.000pF   5.500pF
[Temperature Range]   25.000   0.125k   -40.000
[Voltage Range]   3.300V   3.140V   3.470V
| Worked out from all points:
|   slope of the pulldown table from 0 to 0.495 V, typ, clamps not added: 58.8 ohm
|   slope of the pullup table from 0 to 0.495 V, typ, clamps not added: 19.5 ohm
|   rising waveform, R_fixture 50.000, V_fixture 0.000: 20-80 % time 8.61ns typ, 12.9ns min, 4.03ns max; typ from 0.019 V to 1.98 V
|   rising waveform, R_fixture 50.000, V_fixture 3.300: 20-80 % time 337ps typ, 467ps min, 150ps max; typ from 2.82 V to 3.3 V
|   falling waveform, R_fixture 50.000, V_fixture 3.300: 20-80 % time 11.4ns typ, 12.2ns min, 23.1ns max; typ from 3.3 V to 2.82 V
|   falling waveform, R_fixture 50.000, V_fixture 0.000: 20-80 % time 462ps typ, 671ps min, 403ps max; typ from 1.99 V to 0.019 V
[Pulldown]
|Voltage   I(typ)   I(min)   I(max)
-3.3V     -3.199A    -3.09A     -3.287A
-1.2V     -321.9mA   -406.6mA   -267.9mA
-1.1V     -202.3mA   -291.4mA   -147.1mA
-1V       -102.6mA   -185.6mA   -64.5mA
-900mV    -45.82mA   -99.21mA   -41.48mA
-800mV    -30.11mA   -46.44mA   -33.69mA
-600mV    -18.75mA   -19.13mA   -19.91mA
500mV     7.634mA    7.405mA    7.634mA
3.3V      10.2mA     9.896mA    10.2mA
5V        196.9mA    191mA      196.9mA
6.3V      206.6mA    200.4mA    206.6mA
6.6V      235mA      227.9mA    235mA
[Pullup]
|Voltage   I(typ)   I(min)   I(max)
-3.3V     225.4mA    159.2mA    289.5mA
-3V       191.7mA    142.3mA    256.1mA
-2.6V     172mA      126.6mA    227.2mA
-1.5V     172mA      125.1mA    215.9mA
-1.3V     153.8mA    116.5mA    191.8mA
-200mV    15.97mA    14.98mA    19.28mA
600mV     -29.35mA   -28.47mA   -29.35mA
3.9V      -49.03mA   -47.55mA   -49.03mA
4.2V      -72.01mA   -69.85mA   -72.01mA
4.3V      -121mA     -117.4mA   -121mA
4.4V      -215.8mA   -209.3mA   -215.8mA
6.6V      -3.209A    -3.112A    -3.209A
[Ramp]
| variable   typ   min   max
dV/dt_r   1.175/8.616n   1.196/12.969n   1.169/4.030n
dV/dt_f   0.287/11.473n   0.277/12.250n   0.288/23.130n
R_load = 50.000
[Rising Waveform]
R_fixture = 50.000
V_fixture = 0.000
V_fixture_min = 0.000
V_fixture_max = 0.000
|  time   V(typ)   V(min)   V(max)
0s        18.98mV    18.96mV    17.33mV
560ps     19.31mV    18.99mV    18.21mV
680ps     19.25mV    18.63mV    375.8mV
960ps     249.3mV    19.16mV    230.2mV
1.45ns    354.9mV    233.2mV    1.126V
2.04ns    923.2mV    436mV      1.385V
3.25ns    1.18V      933.4mV    1.479V
11.8ns    1.66V      1.425V     1.941V
45.74ns   1.96V      1.883V     1.977V
200ns     1.978V     1.916V     1.996V
[Rising Waveform]
R_fixture = 50.000
V_fixture = 3.300
V_fixture_min = 3.140
V_fixture_max = 3.470
|  time   V(typ)   V(min)   V(max)
0s        2.822V     2.678V     2.99V
530ps     2.822V     2.678V     2.992V
600ps     2.822V     2.678V     2.925V
880ps     2.79V      2.678V     2.982V
940ps     2.808V     2.679V     3.039V
1.08ns    2.972V     2.642V     3.341V
1.28ns    3.125V     2.661V     3.441V
1.52ns    3.265V     2.83V      3.463V
2.07ns    3.297V     3.11V      3.47V
200ns     3.3V       3.14V      3.47V
[Falling Waveform]
R_fixture = 50.000
V_fixture = 3.300
V_fixture_min = 3.140
V_fixture_max = 3.470
|  time   V(typ)   V(min)   V(max)
0s        3.3V       3.14V      3.47V
760ps     3.3V       3.141V     3.451V
1.08ns    3.292V     3.141V     3.507V
1.47ns    3.327V     3.136V     3.472V
7.72ns    3.172V     3.072V     3.41V
18.9ns    2.895V     2.812V     3.273V
25ns      2.828V     2.731V     3.198V
39.52ns   2.822V     2.679V     3.027V
48ns      2.822V     2.678V     2.992V
200ns     2.822V     2.678V     2.99V
[Falling Waveform]
R_fixture = 50.000
V_fixture = 0.000
V_fixture_min = 0.000
V_fixture_max = 0.000
|  time   V(typ)   V(min)   V(max)
0s        1.99V      1.916V     1.996V
640ps     1.99V      1.915V     2.01V
910ps     1.961V     1.916V     1.188V
1.28ns    1.106V     1.9V       272.7mV
1.56ns    402.6mV    1.663V     80.14mV
1.83ns    136.9mV    1.163V     42.88mV
2.32ns    66.57mV    364.4mV    53.2mV
2.65ns    61.9mV     184.1mV    56.76mV
7.37ns    27.55mV    50.35mV    26.64mV
200ns     18.98mV    18.96mV    17.12mV
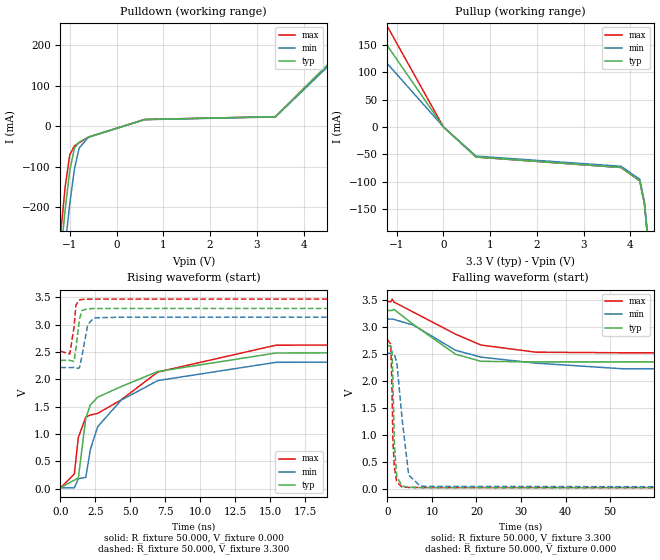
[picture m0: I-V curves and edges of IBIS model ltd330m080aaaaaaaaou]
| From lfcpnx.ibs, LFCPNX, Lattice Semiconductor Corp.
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[Model] ltd330m080aaaaaaaaou
Model_type Output
Polarity   Non-Inverting
Enable   Active-High
Vmeas =  1.650V
Cref =  0.0F
Rref =  1.000M
Vref =  0.0V
C_comp   5.000pF   4.000pF   5.500pF
[Temperature Range]   25.000   0.125k   -40.000
[Voltage Range]   3.300V   3.140V   3.470V
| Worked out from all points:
|   slope of the pulldown table from 0 to 0.495 V, typ, clamps not added: 31.5 ohm
|   slope of the pullup table from 0 to 0.495 V, typ, clamps not added: 11.4 ohm
|   rising waveform, R_fixture 50.000, V_fixture 0.000: 20-80 % time 5.08ns typ, 5.29ns min, 6.4ns max; typ from 0.013 V to 2.63 V
|   rising waveform, R_fixture 50.000, V_fixture 3.300: 20-80 % time 271ps typ, 398ps min, 255ps max; typ from 2.35 V to 3.3 V
|   falling waveform, R_fixture 50.000, V_fixture 3.300: 20-80 % time 9.58ns typ, 17.1ns min, 13.8ns max; typ from 3.3 V to 2.35 V
|   falling waveform, R_fixture 50.000, V_fixture 0.000: 20-80 % time 496ps typ, 1.93ns min, 496ps max; typ from 2.64 V to 0.013 V
[Pulldown]
|Voltage   I(typ)   I(min)   I(max)
-3.3V     -3.202A    -3.094A    -3.289A
-1.2V     -325.6mA   -410.7mA   -270.5mA
-1.1V     -206.6mA   -295.8mA   -150.6mA
-1V       -108.4mA   -190.7mA   -70.24mA
-900mV    -54.05mA   -105.4mA   -48.72mA
-800mV    -39.28mA   -54.19mA   -40.96mA
-600mV    -27.31mA   -27.15mA   -26.95mA
600mV     16.42mA    15.92mA    16.42mA
3.4V      23.34mA    22.64mA    23.34mA
5V        206.2mA    200mA      206.2mA
6.3V      216.2mA    209.7mA    216.2mA
6.6V      244mA      236.7mA    244mA
[Pullup]
|Voltage   I(typ)   I(min)   I(max)
-3.3V     225.6mA    159.7mA    289.7mA
-3.1V     202.7mA    148mA      267.2mA
-2.6V     172.3mA    127.2mA    227.5mA
-1.5V     172.3mA    125.7mA    221.3mA
-1.3V     160.6mA    125.2mA    198.8mA
0V        28.05nA    235.1nA    28.05nA
700mV     -54.91mA   -53.26mA   -54.91mA
3.8V      -74.02mA   -71.8mA    -74.02mA
4.2V      -98.35mA   -95.4mA    -98.35mA
4.3V      -140.1mA   -135.9mA   -140.1mA
4.4V      -229.4mA   -222.5mA   -229.4mA
6.6V      -3.218A    -3.121A    -3.218A
[Ramp]
| variable   typ   min   max
dV/dt_r   1.569/5.088n   1.495/5.287n   1.649/6.386n
dV/dt_f   0.572/9.650n   0.554/17.012n   0.572/13.848n
R_load = 50.000
[Rising Waveform]
R_fixture = 50.000
V_fixture = 0.000
V_fixture_min = 0.000
V_fixture_max = 0.000
|  time   V(typ)   V(min)   V(max)
0s        13.18mV    13.25mV    13.38mV
990ps     153.2mV    12.3mV     262.7mV
1.28ns    194.6mV    179.9mV    938.1mV
1.81ns    1.288V     203.8mV    1.308V
2.14ns    1.532V     718mV      1.347V
2.66ns    1.673V     1.132V     1.376V
4.34ns    1.868V     1.619V     1.625V
6.96ns    2.144V     1.978V     2.135V
15.4ns    2.483V     2.312V     2.626V
200ns     2.628V     2.505V     2.762V
[Rising Waveform]
R_fixture = 50.000
V_fixture = 3.300
V_fixture_min = 3.140
V_fixture_max = 3.470
|  time   V(typ)   V(min)   V(max)
0s        2.347V     2.217V     2.516V
670ps     2.349V     2.216V     2.465V
970ps     2.327V     2.217V     2.959V
1.11ns    2.577V     2.199V     3.364V
1.36ns    3.1V       2.211V     3.454V
1.54ns    3.262V     2.433V     3.464V
1.95ns    3.294V     3.002V     3.469V
2.38ns    3.298V     3.127V     3.47V
4.38ns    3.3V       3.139V     3.47V
200ns     3.3V       3.14V      3.47V
[Falling Waveform]
R_fixture = 50.000
V_fixture = 3.300
V_fixture_min = 3.140
V_fixture_max = 3.470
|  time   V(typ)   V(min)   V(max)
0s        3.3V       3.14V      3.47V
740ps     3.3V       3.141V     3.458V
1.1ns     3.302V     3.141V     3.51V
1.49ns    3.32V      3.134V     3.456V
5.87ns    3.039V     3.027V     3.268V
15.3ns    2.489V     2.562V     2.861V
21ns      2.358V     2.435V     2.659V
33.33ns   2.347V     2.324V     2.527V
52.68ns   2.347V     2.22V      2.516V
200ns     2.347V     2.217V     2.516V
[Falling Waveform]
R_fixture = 50.000
V_fixture = 0.000
V_fixture_min = 0.000
V_fixture_max = 0.000
|  time   V(typ)   V(min)   V(max)
0s        2.643V     2.505V     2.762V
780ps     2.647V     2.506V     2.674V
1.06ns    2.524V     2.505V     1.809V
1.24ns    2.059V     2.505V     912.5mV
1.58ns    812.5mV    2.481V     394.9mV
2.13ns    221.3mV    2.341V     119.3mV
3.31ns    44.53mV    1.291V     29.98mV
4.79ns    24.62mV    250mV      21.42mV
7.47ns    18.16mV    41.44mV    18.12mV
200ns     13.18mV    13.25mV    13.38mV
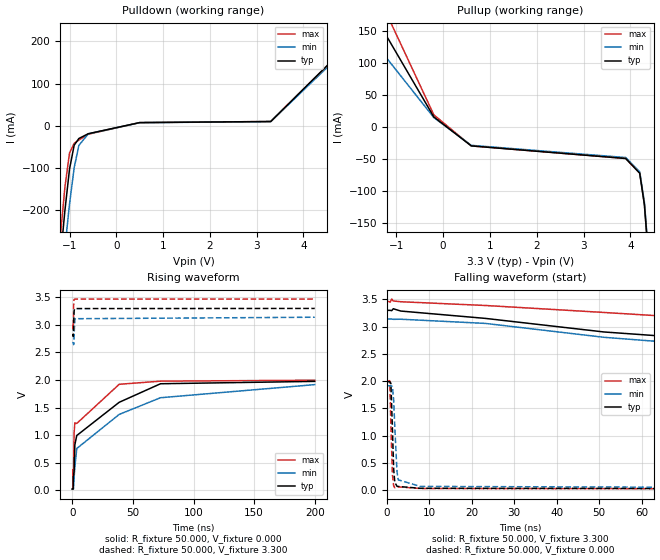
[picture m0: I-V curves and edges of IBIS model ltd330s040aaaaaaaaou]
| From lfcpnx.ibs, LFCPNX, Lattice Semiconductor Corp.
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[Model] ltd330s040aaaaaaaaou
Model_type Output
Polarity   Non-Inverting
Enable   Active-High
Vmeas =  1.650V
Cref =  0.0F
Rref =  1.000M
Vref =  0.0V
C_comp   5.000pF   4.000pF   5.500pF
[Temperature Range]   25.000   0.125k   -40.000
[Voltage Range]   3.300V   3.140V   3.470V
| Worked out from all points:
|   slope of the pulldown table from 0 to 0.495 V, typ, clamps not added: 58.8 ohm
|   slope of the pullup table from 0 to 0.495 V, typ, clamps not added: 19.5 ohm
|   rising waveform, R_fixture 50.000, V_fixture 0.000: 20-80 % time 36.3ns typ, 50.6ns min, 20.3ns max; typ from 0.019 V to 1.98 V
|   rising waveform, R_fixture 50.000, V_fixture 3.300: 20-80 % time 351ps typ, 473ps min, 162ps max; typ from 2.82 V to 3.3 V
|   falling waveform, R_fixture 50.000, V_fixture 3.300: 20-80 % time 32.1ns typ, 30.7ns min, 60.1ns max; typ from 3.3 V to 2.82 V
|   falling waveform, R_fixture 50.000, V_fixture 0.000: 20-80 % time 463ps typ, 672ps min, 403ps max; typ from 1.99 V to 0.019 V
[Pulldown]
|Voltage   I(typ)   I(min)   I(max)
-3.3V     -3.199A    -3.09A     -3.287A
-1.2V     -321.9mA   -406.6mA   -267.9mA
-1.1V     -202.3mA   -291.4mA   -147.1mA
-1V       -102.6mA   -185.6mA   -64.5mA
-900mV    -45.82mA   -99.21mA   -41.48mA
-800mV    -30.11mA   -46.43mA   -33.69mA
-600mV    -18.75mA   -19.13mA   -19.91mA
500mV     7.634mA    7.405mA    7.634mA
3.3V      10.2mA     9.896mA    10.2mA
5V        196.9mA    191mA      196.9mA
6.3V      206.6mA    200.4mA    206.6mA
6.6V      235mA      227.9mA    235mA
[Pullup]
|Voltage   I(typ)   I(min)   I(max)
-3.3V     225.4mA    159.2mA    289.5mA
-3V       191.7mA    142.3mA    256.1mA
-2.6V     172mA      126.6mA    227.2mA
-1.5V     172mA      125.1mA    215.9mA
-1.3V     153.8mA    116.5mA    191.8mA
-200mV    15.97mA    14.98mA    19.28mA
600mV     -29.35mA   -28.47mA   -29.35mA
3.9V      -49.03mA   -47.55mA   -49.03mA
4.2V      -72.01mA   -69.85mA   -72.01mA
4.3V      -121mA     -117.4mA   -121mA
4.4V      -215.8mA   -209.3mA   -215.8mA
6.6V      -3.209A    -3.112A    -3.209A
[Ramp]
| variable   typ   min   max
dV/dt_r   1.174/36.367n   1.192/50.762n   1.169/20.269n
dV/dt_f   0.287/32.212n   0.277/31.637n   0.288/60.120n
R_load = 50.000
[Rising Waveform]
R_fixture = 50.000
V_fixture = 0.000
V_fixture_min = 0.000
V_fixture_max = 0.000
|  time   V(typ)   V(min)   V(max)
0s        18.98mV    18.96mV    17.33mV
560ps     19.31mV    18.99mV    18.21mV
680ps     19.26mV    18.63mV    376mV
990ps     260.4mV    17.68mV    236.5mV
1.5ns     339.2mV    230.4mV    1.036V
2.12ns    823.7mV    414.2mV    1.222V
3.71ns    991.8mV    755.8mV    1.211V
38.69ns   1.595V     1.375V     1.922V
72.78ns   1.932V     1.678V     1.979V
200ns     1.975V     1.916V     1.996V
[Rising Waveform]
R_fixture = 50.000
V_fixture = 3.300
V_fixture_min = 3.140
V_fixture_max = 3.470
|  time   V(typ)   V(min)   V(max)
0s        2.822V     2.678V     2.99V
530ps     2.822V     2.678V     2.992V
600ps     2.822V     2.678V     2.925V
880ps     2.789V     2.678V     2.983V
940ps     2.808V     2.679V     3.036V
1.09ns    2.981V     2.643V     3.338V
1.28ns    3.121V     2.66V      3.437V
1.54ns    3.264V     2.839V     3.463V
2.12ns    3.297V     3.113V     3.47V
200ns     3.3V       3.14V      3.47V
[Falling Waveform]
R_fixture = 50.000
V_fixture = 3.300
V_fixture_min = 3.140
V_fixture_max = 3.470
|  time   V(typ)   V(min)   V(max)
0s        3.3V       3.14V      3.47V
760ps     3.3V       3.141V     3.451V
1.1ns     3.294V     3.141V     3.507V
1.48ns    3.329V     3.135V     3.472V
3.24ns    3.287V     3.137V     3.458V
23.2ns    3.152V     3.06V      3.389V
51.14ns   2.903V     2.805V     3.261V
63.95ns   2.832V     2.728V     3.2V
110.8ns   2.822V     2.678V     2.998V
200ns     2.822V     2.678V     2.99V
[Falling Waveform]
R_fixture = 50.000
V_fixture = 0.000
V_fixture_min = 0.000
V_fixture_max = 0.000
|  time   V(typ)   V(min)   V(max)
0s        1.99V      1.916V     1.996V
640ps     1.99V      1.915V     2.01V
910ps     1.961V     1.916V     1.188V
1.27ns    1.129V     1.902V     285.2mV
1.57ns    385.9mV    1.646V     76.7mV
1.82ns    145.9mV    1.18V      44.59mV
2.35ns    69.94mV    335.3mV    55.59mV
2.66ns    66.32mV    187.7mV    58.93mV
7.86ns    32.93mV    67.66mV    29.41mV
200ns     18.98mV    18.96mV    17.12mV
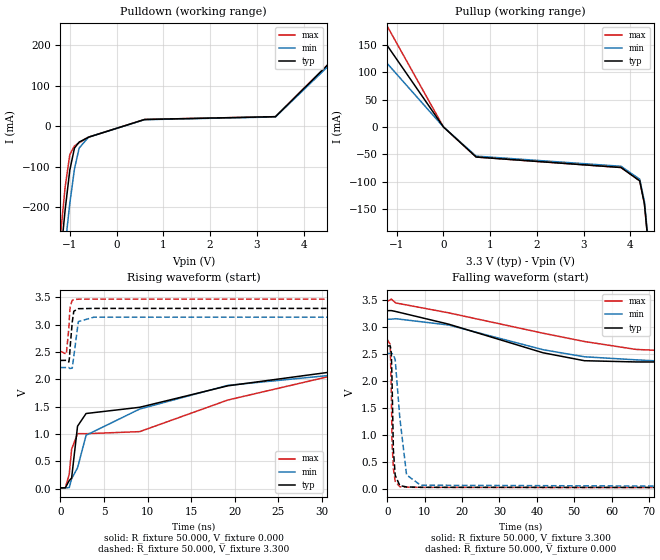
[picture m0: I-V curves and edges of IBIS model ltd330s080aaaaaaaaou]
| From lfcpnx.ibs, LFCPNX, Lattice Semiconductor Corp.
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[Model] ltd330s080aaaaaaaaou
Model_type Output
Polarity   Non-Inverting
Enable   Active-High
Vmeas =  1.650V
Cref =  0.0F
Rref =  1.000M
Vref =  0.0V
C_comp   5.000pF   4.000pF   5.500pF
[Temperature Range]   25.000   0.125k   -40.000
[Voltage Range]   3.300V   3.140V   3.470V
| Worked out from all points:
|   slope of the pulldown table from 0 to 0.495 V, typ, clamps not added: 31.5 ohm
|   slope of the pullup table from 0 to 0.495 V, typ, clamps not added: 11.4 ohm
|   rising waveform, R_fixture 50.000, V_fixture 0.000: 20-80 % time 24.5ns typ, 21.4ns min, 29.7ns max; typ from 0.013 V to 2.63 V
|   rising waveform, R_fixture 50.000, V_fixture 3.300: 20-80 % time 289ps typ, 420ps min, 274ps max; typ from 2.35 V to 3.3 V
|   falling waveform, R_fixture 50.000, V_fixture 3.300: 20-80 % time 27.2ns typ, 40.9ns min, 39.2ns max; typ from 3.3 V to 2.35 V
|   falling waveform, R_fixture 50.000, V_fixture 0.000: 20-80 % time 505ps typ, 2.08ns min, 498ps max; typ from 2.64 V to 0.013 V
[Pulldown]
|Voltage   I(typ)   I(min)   I(max)
-3.3V     -3.202A    -3.094A    -3.289A
-1.2V     -325.6mA   -410.7mA   -270.5mA
-1.1V     -206.6mA   -295.8mA   -150.6mA
-1V       -108.4mA   -190.7mA   -70.24mA
-900mV    -54.05mA   -105.4mA   -48.72mA
-800mV    -39.28mA   -54.19mA   -40.96mA
-600mV    -27.31mA   -27.15mA   -26.95mA
600mV     16.42mA    15.92mA    16.42mA
3.4V      23.34mA    22.64mA    23.34mA
5V        206.2mA    200mA      206.2mA
6.3V      216.2mA    209.7mA    216.2mA
6.6V      244mA      236.7mA    244mA
[Pullup]
|Voltage   I(typ)   I(min)   I(max)
-3.3V     225.6mA    159.7mA    289.7mA
-3.1V     202.7mA    148mA      267.2mA
-2.6V     172.3mA    127.2mA    227.5mA
-1.5V     172.3mA    125.7mA    221.3mA
-1.3V     160.6mA    125.2mA    198.8mA
0V        28.05nA    235.1nA    28.05nA
700mV     -54.91mA   -53.26mA   -54.91mA
3.8V      -74.02mA   -71.8mA    -74.02mA
4.2V      -98.35mA   -95.4mA    -98.35mA
4.3V      -140.1mA   -135.9mA   -140.1mA
4.4V      -229.4mA   -222.5mA   -229.4mA
6.6V      -3.218A    -3.121A    -3.218A
[Ramp]
| variable   typ   min   max
dV/dt_r   1.568/24.424n   1.495/21.478n   1.649/29.663n
dV/dt_f   0.572/27.275n   0.554/40.741n   0.572/39.237n
R_load = 50.000
[Rising Waveform]
R_fixture = 50.000
V_fixture = 0.000
V_fixture_min = 0.000
V_fixture_max = 0.000
|  time   V(typ)   V(min)   V(max)
0s        13.18mV    13.25mV    13.38mV
560ps     13.46mV    13.31mV    14.84mV
1.01ns    147.9mV    17.83mV    264mV
1.28ns    191.6mV    181.1mV    719.8mV
1.96ns    1.143V     379.1mV    1.006V
2.94ns    1.375V     976.9mV    1.005V
9.09ns    1.489V     1.457V     1.043V
19.2ns    1.882V     1.891V     1.622V
43.13ns   2.394V     2.264V     2.511V
200ns     2.626V     2.505V     2.762V
[Rising Waveform]
R_fixture = 50.000
V_fixture = 3.300
V_fixture_min = 3.140
V_fixture_max = 3.470
|  time   V(typ)   V(min)   V(max)
0s        2.347V     2.217V     2.516V
670ps     2.349V     2.216V     2.463V
960ps     2.318V     2.218V     2.93V
1.03ns    2.391V     2.201V     3.152V
1.12ns    2.605V     2.201V     3.342V
1.35ns    3.045V     2.205V     3.447V
1.53ns    3.248V     2.418V     3.461V
2.05ns    3.295V     3.058V     3.469V
3.82ns    3.3V       3.139V     3.47V
200ns     3.3V       3.14V      3.47V
[Falling Waveform]
R_fixture = 50.000
V_fixture = 3.300
V_fixture_min = 3.140
V_fixture_max = 3.470
|  time   V(typ)   V(min)   V(max)
0s        3.3V       3.14V      3.47V
1.08ns    3.3V       3.141V     3.513V
2.21ns    3.284V     3.15V      3.443V
16.4ns    3.049V     3.033V     3.259V
41.67ns   2.518V     2.575V     2.881V
52.73ns   2.371V     2.444V     2.727V
66.58ns   2.348V     2.387V     2.58V
85.06ns   2.347V     2.322V     2.524V
120.9ns   2.347V     2.226V     2.516V
200ns     2.347V     2.217V     2.516V
[Falling Waveform]
R_fixture = 50.000
V_fixture = 0.000
V_fixture_min = 0.000
V_fixture_max = 0.000
|  time   V(typ)   V(min)   V(max)
0s        2.643V     2.505V     2.762V
780ps     2.647V     2.506V     2.674V
1.06ns    2.524V     2.505V     1.819V
1.26ns    2.009V     2.505V     864.6mV
1.62ns    719.5mV    2.481V     367.4mV
2.11ns    246.1mV    2.389V     134.7mV
3.34ns    54.61mV    1.314V     33.91mV
5.15ns    30.43mV    253mV      24.96mV
8.91ns    23.52mV    62.07mV    22.09mV
200ns     13.18mV    13.25mV    13.38mV
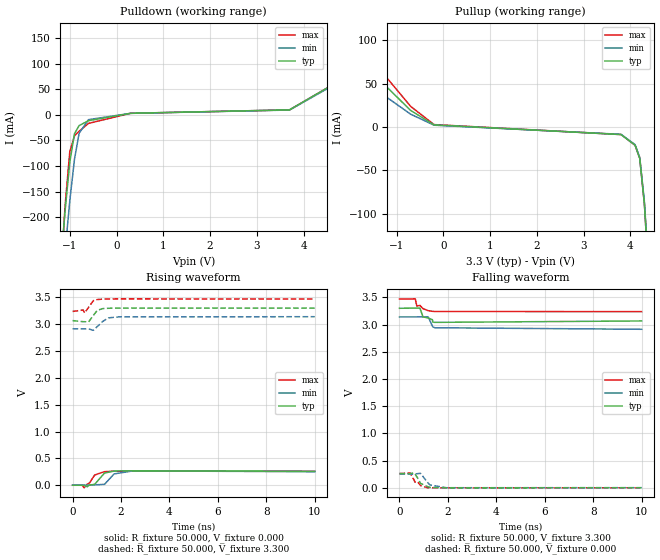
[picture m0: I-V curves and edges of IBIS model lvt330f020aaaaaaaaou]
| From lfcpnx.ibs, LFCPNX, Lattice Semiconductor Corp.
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|Model lvt330f020aaaaaaaaou
[Model] lvt330f020aaaaaaaaou
Model_type Output
Polarity   Non-Inverting
Enable   Active-High
Vmeas =  1.650V
Cref =  0.0F
Rref =  1.000M
Vref =  0.0V
C_comp   5.000pF   4.000pF   5.500pF
[Temperature Range]   25.000   0.125k   -40.000
[Voltage Range]   3.300V   3.140V   3.470V
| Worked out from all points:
|   slope of the pulldown table from 0 to 0.495 V, typ, clamps not added: 127 ohm
|   slope of the pullup table from 0 to 0.495 V, typ, clamps not added: 138 ohm
|   rising waveform, R_fixture 50.000, V_fixture 0.000: 20-80 % time 254ps typ, 268ps min, 250ps max; typ from 0.001 V to 0.261 V
|   rising waveform, R_fixture 50.000, V_fixture 3.300: 20-80 % time 228ps typ, 326ps min, 175ps max; typ from 3.07 V to 3.3 V
|   falling waveform, R_fixture 50.000, V_fixture 3.300: 20-80 % time 316ps typ, 113ps min, 325ps max; typ from 3.3 V to 3.07 V
|   falling waveform, R_fixture 50.000, V_fixture 0.000: 20-80 % time 354ps typ, 267ps min, 316ps max; typ from 0.261 V to 0.001 V
[Pulldown]
|Voltage   I(typ)   I(min)   I(max)
-3.3V     -3.023A    -2.882A    -4.076A
-1.2V     -299.4mA   -373.4mA   -326mA
-1.1V     -186.9mA   -266.3mA   -176.8mA
-1V       -92.5mA    -167.9mA   -72.23mA
-900mV    -37.01mA   -86.9mA    -41.16mA
-800mV    -21.11mA   -36.05mA   -32.24mA
-600mV    -11.54mA   -9.523mA   -16.85mA
300mV     2.85mA     2.764mA    2.85mA
3.7V      9.528mA    9.243mA    9.528mA
5.3V      94.4mA     91.6mA     94.4mA
6.1V      116.9mA    113.4mA    116.9mA
6.6V      170.2mA    165.1mA    170.2mA
[Pullup]
|Voltage   I(typ)   I(min)   I(max)
-3.3V     158.5mA    97.7mA     204mA
-2.9V     114.8mA    84.4mA     160mA
-2.7V     103.4mA    79.01mA    137.4mA
-2.1V     93mA       68.14mA    114.2mA
-700mV    19.13mA    14.81mA    23.79mA
-200mV    2.521mA    2.155mA    2.855mA
3.8V      -8.624mA   -8.365mA   -8.624mA
4.1V      -20.86mA   -20.24mA   -20.86mA
4.2V      -35.88mA   -34.81mA   -35.88mA
4.3V      -88.6mA    -85.9mA    -88.6mA
4.4V      -178.3mA   -173mA     -178.3mA
6.6V      -2.881A    -2.794A    -2.881A
[Ramp]
| variable   typ   min   max
dV/dt_r   0.156/0.256n   0.150/0.277n   0.156/0.254n
dV/dt_f   0.140/0.317n   0.141/0.117n   0.140/0.324n
R_load = 50.000
[Rising Waveform]
R_fixture = 50.000
V_fixture = 0.000
V_fixture_min = 0.000
V_fixture_max = 0.000
|  time   V(typ)   V(min)   V(max)
0s        974.6uV    2.808mV    974.6uV
395ps     1.011mV    2.543mV    3.01mV
478ps     1.088mV    2.751mV    -47.37mV
605ps     -26.6mV    2.884mV    21.56mV
696ps     4.413mV    2.843mV    41.88mV
913ps     17.84mV    7.737mV    191.8mV
1.318ns   227.7mV    18.06mV    254.2mV
1.718ns   266.6mV    212.4mV    262.5mV
2.488ns   270.3mV    268.3mV    263.9mV
10ns      260.7mV    252.8mV    260.7mV
[Rising Waveform]
R_fixture = 50.000
V_fixture = 3.300
V_fixture_min = 3.140
V_fixture_max = 3.470
|  time   V(typ)   V(min)   V(max)
0s        3.067V     2.914V     3.238V
438ps     3.047V     2.913V     3.264V
497ps     3.047V     2.914V     3.208V
658ps     3.041V     2.914V     3.313V
858ps     3.162V     2.886V     3.438V
1.018ns   3.257V     2.956V     3.459V
1.248ns   3.291V     3.052V     3.468V
1.478ns   3.297V     3.118V     3.471V
1.907ns   3.3V       3.136V     3.472V
10ns      3.3V       3.14V      3.47V
[Falling Waveform]
R_fixture = 50.000
V_fixture = 3.300
V_fixture_min = 3.140
V_fixture_max = 3.470
|  time   V(typ)   V(min)   V(max)
0s        3.3V       3.14V      3.47V
654ps     3.303V     3.14V      3.473V
718ps     3.303V     3.141V     3.341V
845ps     3.301V     3.142V     3.353V
974ps     3.142V     3.143V     3.293V
1.188ns   3.122V     3.141V     3.256V
1.365ns   3.089V     2.969V     3.244V
1.378ns   3.047V     2.959V     3.244V
1.458ns   3.041V     2.942V     3.241V
10ns      3.067V     2.914V     3.238V
[Falling Waveform]
R_fixture = 50.000
V_fixture = 0.000
V_fixture_min = 0.000
V_fixture_max = 0.000
|  time   V(typ)   V(min)   V(max)
0s        260.7mV    252.8mV    260.7mV
434ps     260.3mV    252.4mV    274.2mV
595ps     273.5mV    252.1mV    150.1mV
644ps     254.4mV    252.5mV    103.8mV
744ps     184.8mV    260.9mV    114.4mV
871ps     81.68mV    265mV      40.71mV
1.161ns   22.21mV    99.2mV     2.172mV
1.261ns   8.519mV    52.22mV    397.9uV
1.931ns   -388.5uV   1.553mV    -744uV
10ns      974.6uV    2.808mV    974.6uV
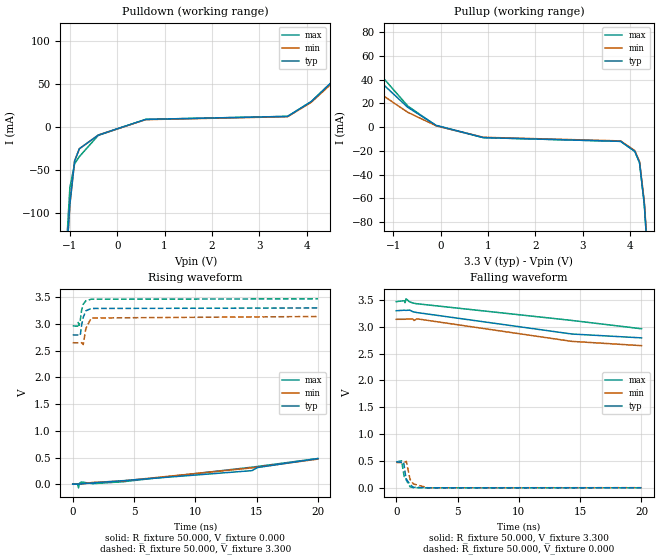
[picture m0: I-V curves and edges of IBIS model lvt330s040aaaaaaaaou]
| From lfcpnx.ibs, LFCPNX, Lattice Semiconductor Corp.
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|Model lvt330s040aaaaaaaaou
[Model] lvt330s040aaaaaaaaou
Model_type Output
Polarity   Non-Inverting
Enable   Active-High
Vmeas =  1.650V
Cref =  0.0F
Rref =  1.000M
Vref =  0.0V
C_comp   5.000pF   4.000pF   5.500pF
[Temperature Range]   25.000   0.125k   -40.000
[Voltage Range]   3.300V   3.140V   3.470V
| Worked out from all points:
|   slope of the pulldown table from 0 to 0.495 V, typ, clamps not added: 60 ohm
|   slope of the pullup table from 0 to 0.495 V, typ, clamps not added: 80.9 ohm
|   rising waveform, R_fixture 50.000, V_fixture 0.000: 20-80 % time 10.6ns typ, 11.1ns min, 10.8ns max; typ from 0.001 V to 0.481 V
|   rising waveform, R_fixture 50.000, V_fixture 3.300: 20-80 % time 278ps typ, 325ps min, 243ps max; typ from 2.79 V to 3.3 V
|   falling waveform, R_fixture 50.000, V_fixture 3.300: 20-80 % time 9.24ns typ, 8.7ns min, 11.8ns max; typ from 3.3 V to 2.79 V
|   falling waveform, R_fixture 50.000, V_fixture 0.000: 20-80 % time 340ps typ, 298ps min, 354ps max; typ from 0.481 V to 0.001 V
[Pulldown]
|Voltage   I(typ)   I(min)   I(max)
-3.3V     -2.819A    -2.819A    -3.761A
-1.1V     -176.5mA   -176.5mA   -165mA
-1V       -89.5mA    -89.5mA    -70.05mA
-900mV    -39.31mA   -39.31mA   -42.55mA
-800mV    -25.23mA   -25.23mA   -34.36mA
-400mV    -9.281mA   -9.281mA   -9.631mA
600mV     8.924mA    8.657mA    8.924mA
3.6V      12.44mA    12.06mA    12.44mA
4.1V      29.71mA    28.82mA    29.71mA
5.4V      97.6mA     94.7mA     97.6mA
6.2V      121.3mA    117.7mA    121.3mA
6.6V      164mA      159.1mA    164mA
[Pullup]
|Voltage   I(typ)   I(min)   I(max)
-3.3V     109.3mA    67.7mA     140.2mA
-3V       86.1mA     60.5mA     117.8mA
-2V       65.1mA     47.62mA    77.3mA
-700mV    16.69mA    12.48mA    17.82mA
-100mV    1.509mA    1.116mA    1.148mA
900mV     -8.885mA   -8.618mA   -8.885mA
3.8V      -12.03mA   -11.67mA   -12.03mA
4.1V      -20.45mA   -19.83mA   -20.45mA
4.2V      -30.02mA   -29.12mA   -30.02mA
4.3V      -64.8mA    -62.9mA    -64.8mA
4.4V      -126.1mA   -122.4mA   -126.1mA
6.6V      -2A        -1.94A     -2A
[Ramp]
| variable   typ   min   max
dV/dt_r   0.291/10.429n   0.281/11.102n   0.291/10.769n
dV/dt_f   0.304/9.264n   0.295/8.716n   0.304/11.811n
R_load = 50.000
[Rising Waveform]
R_fixture = 50.000
V_fixture = 0.000
V_fixture_min = 0.000
V_fixture_max = 0.000
|  time   V(typ)   V(min)   V(max)
0s        707.6uV    2.066mV    707.6uV
395ps     834.9uV    1.468mV    3.679mV
474ps     984.1uV    1.991mV    -67.5mV
548ps     2.012mV    2.19mV     18.51mV
716ps     6.953mV    2.838mV    41.63mV
1.616ns   23.71mV    34.24mV    10.96mV
4.056ns   66.05mV    61.44mV    45.64mV
14.61ns   254.4mV    306.8mV    318.9mV
15.09ns   313.3mV    320.4mV    333.4mV
20ns      481mV      470.8mV    481.4mV
[Rising Waveform]
R_fixture = 50.000
V_fixture = 3.300
V_fixture_min = 3.140
V_fixture_max = 3.470
|  time   V(typ)   V(min)   V(max)
0s        2.794V     2.649V     2.964V
403ps     2.794V     2.648V     2.959V
454ps     2.794V     2.649V     3.028V
517ps     2.793V     2.649V     2.975V
617ps     2.788V     2.649V     3.071V
727ps     2.982V     2.65V      3.258V
856ps     3.123V     2.615V     3.369V
1.072ns   3.246V     2.915V     3.434V
1.506ns   3.29V      3.112V     3.464V
20ns      3.3V       3.14V      3.47V
[Falling Waveform]
R_fixture = 50.000
V_fixture = 3.300
V_fixture_min = 3.140
V_fixture_max = 3.470
|  time   V(typ)   V(min)   V(max)
0s        3.3V       3.14V      3.47V
669ps     3.31V      3.141V     3.487V
718ps     3.308V     3.141V     3.45V
799ps     3.306V     3.143V     3.521V
1.088ns   3.312V     3.147V     3.465V
1.339ns   3.283V     3.146V     3.445V
1.446ns   3.276V     3.118V     3.439V
1.686ns   3.266V     3.149V     3.43V
14.32ns   2.866V     2.729V     3.119V
20ns      2.794V     2.649V     2.964V
[Falling Waveform]
R_fixture = 50.000
V_fixture = 0.000
V_fixture_min = 0.000
V_fixture_max = 0.000
|  time   V(typ)   V(min)   V(max)
0s        481mV      470.8mV    481.4mV
433ps     476.6mV    470.3mV    503.8mV
587ps     485.1mV    470.1mV    290.4mV
653ps     399.2mV    471.1mV    208.5mV
750ps     240.2mV    484.9mV    208.8mV
826ps     160.9mV    491.8mV    140.3mV
1.124ns   57.76mV    156.3mV    18.67mV
1.398ns   9.89mV     71.04mV    1.886mV
2.569ns   -5.161uV   355.9uV    -949.1uV
20ns      707.6uV    2.066mV    707.6uV
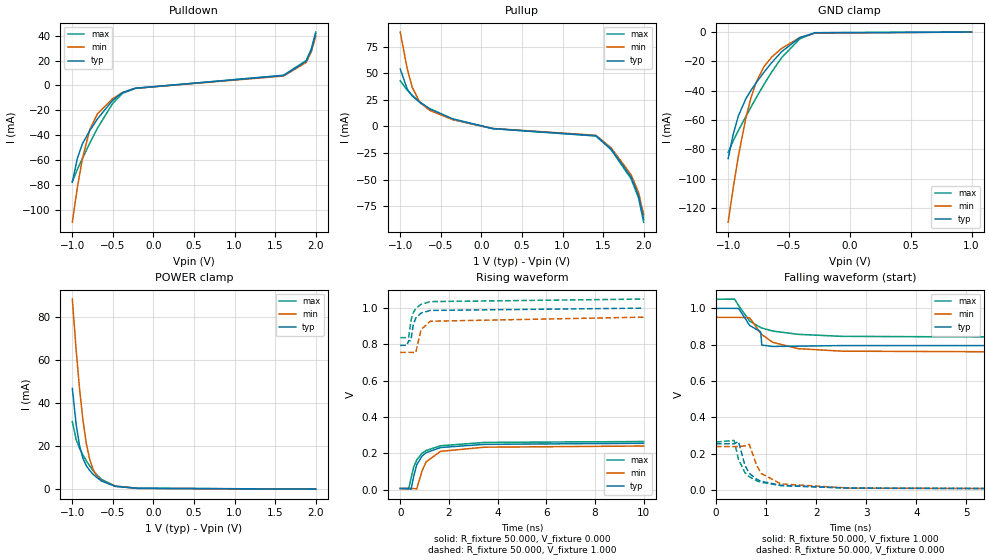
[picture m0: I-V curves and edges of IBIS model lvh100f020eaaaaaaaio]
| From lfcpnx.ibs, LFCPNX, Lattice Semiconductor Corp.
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[Model] lvh100f020eaaaaaaaio
Model_type I/O
Polarity   Non-Inverting
Enable   Active-Low
Vinl =  0.350V
Vinh =  0.650V
Vmeas =  0.500V
Cref =  0.0F
Rref =  1.000M
Vref =  0.0V
C_comp   5.000pF   4.000pF   5.500pF
[Temperature Range]   25.000   0.125k   -40.000
[Voltage Range]   1.000V   0.950V   1.050V
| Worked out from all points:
|   slope of the pulldown table from 0 to 0.15 V, typ, clamps not added: 112 ohm
|   slope of the pullup table from 0 to 0.15 V, typ, clamps not added: 70.6 ohm
|   GND clamp passes 1 mA (typ) near -0.32 V on its own axis
|   POWER clamp passes 1 mA (typ) near -0.46 V on its own axis
|   rising waveform, R_fixture 50.000, V_fixture 0.000: 20-80 % time 556ps typ, 572ps min, 594ps max; typ from 0.006 V to 0.255 V
|   rising waveform, R_fixture 50.000, V_fixture 1.000: 20-80 % time 262ps typ, 317ps min, 313ps max; typ from 0.795 V to 1 V
|   falling waveform, R_fixture 50.000, V_fixture 1.000: 20-80 % time 367ps typ, 552ps min, 590ps max; typ from 1 V to 0.795 V
|   falling waveform, R_fixture 50.000, V_fixture 0.000: 20-80 % time 330ps typ, 348ps min, 350ps max; typ from 0.255 V to 0.006 V
[GND_clamp]
|Voltage   I(typ)   I(min)   I(max)
-1V       -86.39mA   -129.8mA   -82.1mA
-958mV    -69.62mA   -106.1mA   -74.12mA
-916mV    -57.21mA   -84.7mA    -67.22mA
-853mV    -45.26mA   -58.07mA   -57.38mA
-811mV    -39.58mA   -44.43mA   -50.99mA
-769mV    -34.5mA    -34.04mA   -44.75mA
-706mV    -27.42mA   -23.61mA   -35.76mA
-643mV    -20.91mA   -17.14mA   -27.32mA
-559mV    -13.28mA   -11.04mA   -17.29mA
-412mV    -3.804mA   -3.723mA   -4.655mA
-286mV    -477.7uA   -703.7uA   -396.2uA
1V        0A         0A         0A
[POWER_clamp]
|Voltage   I(typ)   I(min)   I(max)
-1V       46.74mA    88.29mA    31.25mA
-953mV    29.96mA    64.69mA    22.99mA
-911mV    20.02mA    46.58mA    18.81mA
-869mV    14.14mA    31.9mA     15.73mA
-827mV    10.71mA    20.96mA    13.03mA
-785mV    8.459mA    13.56mA    10.59mA
-743mV    6.733mA    8.952mA    8.425mA
-701mV    5.305mA    6.142mA    6.561mA
-638mV    3.604mA    3.771mA    4.35mA
-470mV    1.11mA     1.202mA    1.272mA
-197mV    214.8uA    168.4uA    281.4uA
2V        -171.9uA   -171.2uA   -177.1uA
[Pulldown]
|Voltage   I(typ)   I(min)   I(max)
-1V       -77.67mA   -109.7mA   -77.1mA
-938mV    -58.53mA   -81.92mA   -67.33mA
-876mV    -46.89mA   -58.86mA   -58.63mA
-783mV    -36mA      -35.1mA    -46.09mA
-690mV    -26.86mA   -22.73mA   -34.26mA
-504mV    -11.96mA   -10.67mA   -14.5mA
-380mV    -5.675mA   -5.627mA   -6.286mA
-225mV    -2.256mA   -2.289mA   -2.368mA
1.604V    7.952mA    7.555mA    8.191mA
1.883V    19.44mA    18.47mA    20.03mA
1.945V    28.4mA     26.98mA    29.25mA
2V        41.56mA    39.48mA    42.8mA
[Pullup]
|Voltage   I(typ)   I(min)   I(max)
-1V       54.04mA    88.72mA    42.94mA
-914mV    35.21mA    54.31mA    34.1mA
-852mV    28.59mA    36.79mA    29.36mA
-759mV    22.7mA     22.67mA    23.02mA
-635mV    16.68mA    15.09mA    16.17mA
-356mV    7.228mA    6.497mA    6.54mA
140mV     -2.013mA   -1.912mA   -2.073mA
1.411V    -8.732mA   -8.296mA   -8.994mA
1.597V    -21.07mA   -20.01mA   -21.7mA
1.845V    -47.73mA   -45.34mA   -49.16mA
1.938V    -65.56mA   -62.28mA   -67.52mA
2V        -87.4mA    -83.03mA   -90.02mA
[Ramp]
| variable   typ   min   max
dV/dt_r   0.151/0.565n   0.141/0.577n   0.155/0.602n
dV/dt_f   0.123/0.532n   0.117/0.548n   0.128/0.585n
R_load = 50.000
[Rising Waveform]
R_fixture = 50.000
V_fixture = 0.000
V_fixture_min = 0.000
V_fixture_max = 0.000
|  time   V(typ)   V(min)   V(max)
0s        6.149mV    5.918mV    6.362mV
345ps     6.418mV    6.026mV    3.527mV
446ps     2.401mV    5.953mV    63.26mV
548ps     70.42mV    6.272mV    122.2mV
675ps     136.6mV    2.815mV    163.3mV
895ps     184.7mV    102.9mV    199.9mV
1.065ns   203.7mV    153.2mV    215.8mV
1.656ns   231.8mV    210.8mV    241.7mV
3.469ns   249.5mV    233.8mV    260mV
10ns      255.2mV    240.2mV    265mV
[Rising Waveform]
R_fixture = 50.000
V_fixture = 1.000
V_fixture_min = 0.950
V_fixture_max = 1.050
|  time   V(typ)   V(min)   V(max)
0s        794.7mV    756.1mV    837.4mV
273ps     794.8mV    756.3mV    837.6mV
346ps     820.3mV    756.2mV    839.4mV
430ps     820.6mV    756.2mV    919.9mV
465ps     846.8mV    756.2mV    944.3mV
534ps     907.3mV    755.9mV    973.9mV
635ps     944.6mV    755mV      997.6mV
855ps     972.8mV    881.6mV    1.021V
1.234ns   987.4mV    927.8mV    1.036V
10ns      1V         950.4mV    1.05V
[Falling Waveform]
R_fixture = 50.000
V_fixture = 1.000
V_fixture_min = 0.950
V_fixture_max = 1.050
|  time   V(typ)   V(min)   V(max)
0s        1V         950.4mV    1.05V
370ps     999.8mV    950.3mV    1.051V
452ps     999.6mV    950.4mV    1.015V
673ps     905.8mV    948.3mV    929.8mV
893ps     870.7mV    862.4mV    894.2mV
914ps     798mV      856.1mV    892mV
1.134ns   790.4mV    812.9mV    875.1mV
1.641ns   792.1mV    778.3mV    857.1mV
2.514ns   795.4mV    764.6mV    846mV
10ns      794.7mV    756.1mV    837.4mV
[Falling Waveform]
R_fixture = 50.000
V_fixture = 0.000
V_fixture_min = 0.000
V_fixture_max = 0.000
|  time   V(typ)   V(min)   V(max)
0s        255.2mV    240.2mV    265mV
362ps     255.3mV    239.9mV    273.7mV
449ps     267.6mV    240.1mV    169.9mV
577ps     137.9mV    243.8mV    97.02mV
664ps     93.41mV    252.4mV    74.32mV
814ps     59.94mV    136mV      52mV
904ps     48.9mV     92.05mV    43.79mV
1.297ns   26.69mV    34.69mV    25.8mV
2.673ns   11.72mV    11.71mV    11.16mV
10ns      6.149mV    5.918mV    6.362mV
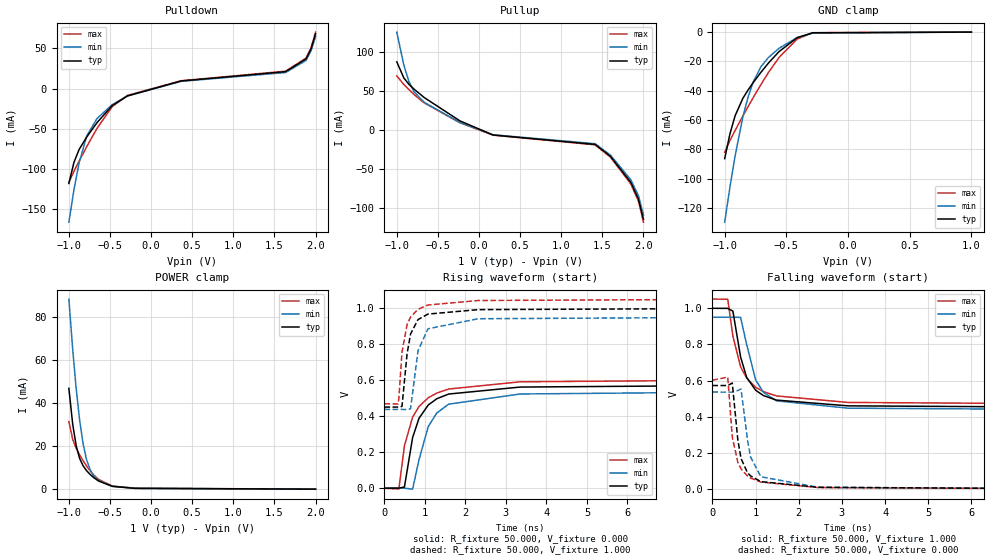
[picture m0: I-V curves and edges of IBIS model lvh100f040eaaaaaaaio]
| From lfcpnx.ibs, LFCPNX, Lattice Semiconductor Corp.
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[Model] lvh100f040eaaaaaaaio
Model_type I/O
Polarity   Non-Inverting
Enable   Active-Low
Vinl =  0.350V
Vinh =  0.650V
Vmeas =  0.500V
Cref =  0.0F
Rref =  1.000M
Vref =  0.0V
C_comp   5.000pF   4.000pF   5.500pF
[Temperature Range]   25.000   0.125k   -40.000
[Voltage Range]   1.000V   0.950V   1.050V
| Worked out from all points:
|   slope of the pulldown table from 0 to 0.15 V, typ, clamps not added: 34.6 ohm
|   slope of the pullup table from 0 to 0.15 V, typ, clamps not added: 26.2 ohm
|   GND clamp passes 1 mA (typ) near -0.32 V on its own axis
|   POWER clamp passes 1 mA (typ) near -0.46 V on its own axis
|   rising waveform, R_fixture 50.000, V_fixture 0.000: 20-80 % time 496ps typ, 533ps min, 542ps max; typ from 0 V to 0.573 V
|   rising waveform, R_fixture 50.000, V_fixture 1.000: 20-80 % time 210ps typ, 247ps min, 226ps max; typ from 0.451 V to 1 V
|   falling waveform, R_fixture 50.000, V_fixture 1.000: 20-80 % time 403ps typ, 408ps min, 468ps max; typ from 1 V to 0.451 V
|   falling waveform, R_fixture 50.000, V_fixture 0.000: 20-80 % time 229ps typ, 255ps min, 244ps max; typ from 0.573 V to 0 V
[GND_clamp]
|Voltage   I(typ)   I(min)   I(max)
-1V       -86.39mA   -129.8mA   -82.1mA
-958mV    -69.62mA   -106.1mA   -74.12mA
-916mV    -57.21mA   -84.7mA    -67.22mA
-853mV    -45.26mA   -58.07mA   -57.38mA
-811mV    -39.58mA   -44.43mA   -50.99mA
-769mV    -34.5mA    -34.04mA   -44.75mA
-706mV    -27.42mA   -23.61mA   -35.76mA
-643mV    -20.91mA   -17.14mA   -27.32mA
-559mV    -13.28mA   -11.04mA   -17.29mA
-412mV    -3.804mA   -3.723mA   -4.655mA
-286mV    -477.7uA   -703.7uA   -396.2uA
1V        0A         0A         0A
[POWER_clamp]
|Voltage   I(typ)   I(min)   I(max)
-1V       46.74mA    88.29mA    31.25mA
-953mV    29.96mA    64.69mA    22.99mA
-911mV    20.02mA    46.58mA    18.81mA
-869mV    14.14mA    31.9mA     15.73mA
-827mV    10.71mA    20.96mA    13.03mA
-785mV    8.459mA    13.56mA    10.59mA
-743mV    6.733mA    8.952mA    8.425mA
-701mV    5.305mA    6.142mA    6.561mA
-638mV    3.604mA    3.771mA    4.35mA
-470mV    1.11mA     1.202mA    1.272mA
-197mV    214.8uA    168.4uA    281.4uA
2V        -171.9uA   -171.2uA   -177.1uA
[Pulldown]
|Voltage   I(typ)   I(min)   I(max)
-1V       -118.4mA   -166.7mA   -117mA
-938mV    -92.07mA   -126.1mA   -103.2mA
-876mV    -76.13mA   -92.99mA   -90.66mA
-783mV    -60.46mA   -59.19mA   -72.49mA
-659mV    -42.67mA   -37.52mA   -49.88mA
-473mV    -21.27mA   -20.11mA   -22.48mA
-287mV    -9.194mA   -9.165mA   -8.478mA
364mV     9.452mA    8.98mA     9.736mA
1.635V    21.06mA    20.01mA    21.69mA
1.883V    36.89mA    35.04mA    37.99mA
1.945V    49.53mA    47.05mA    51.01mA
2V        68.4mA     64.98mA    70.45mA
[Pullup]
|Voltage   I(typ)   I(min)   I(max)
-1V       87.31mA    125.4mA    69.34mA
-914mV    66.65mA    82.99mA    58.26mA
-852mV    58.48mA    61.88mA    51.68mA
-790mV    52.34mA    48.88mA    45.52mA
-666mV    41.58mA    35.46mA    34.69mA
-232mV    11.7mA     9.634mA    9.279mA
171mV     -6.377mA   -6.059mA   -6.569mA
1.411V    -18.41mA   -17.49mA   -18.96mA
1.597V    -33.62mA   -31.94mA   -34.63mA
1.845V    -66.87mA   -63.52mA   -68.87mA
1.938V    -88.23mA   -83.82mA   -90.87mA
2V        -114.5mA   -108.8mA   -118mA
[Ramp]
| variable   typ   min   max
dV/dt_r   0.345/0.491n   0.323/0.534n   0.363/0.551n
dV/dt_f   0.327/0.404n   0.305/0.408n   0.346/0.474n
R_load = 50.000
[Rising Waveform]
R_fixture = 50.000
V_fixture = 0.000
V_fixture_min = 0.000
V_fixture_max = 0.000
|  time   V(typ)   V(min)   V(max)
0s        21.62uV    62.96uV    -269.4uV
356ps     673.8uV    120.9uV    -4.097mV
493ps     6.372mV    343.8uV    235.5mV
695ps     281mV      -5.183mV   395.2mV
853ps     388.6mV    158.4mV    454mV
1.082ns   462.5mV    342.9mV    502.6mV
1.293ns   497.3mV    418mV      528.8mV
1.585ns   523.3mV    467mV      551.1mV
3.35ns    562.1mV    523.6mV    591.3mV
10ns      573mV      536.7mV    602.2mV
[Rising Waveform]
R_fixture = 50.000
V_fixture = 1.000
V_fixture_min = 0.950
V_fixture_max = 1.050
|  time   V(typ)   V(min)   V(max)
0s        450.7mV    438mV      469.5mV
336ps     451mV      438.1mV    468.1mV
355ps     450.7mV    438.1mV    496.1mV
433ps     454.8mV    438.1mV    755.3mV
559ps     747.6mV    436.6mV    909.4mV
645ps     857.3mV    441.7mV    951.2mV
829ps     937mV      764.4mV    994.2mV
1.075ns   967.6mV    885.9mV    1.018V
2.317ns   992.3mV    941.8mV    1.043V
10ns      999.9mV    950.8mV    1.051V
[Falling Waveform]
R_fixture = 50.000
V_fixture = 1.000
V_fixture_min = 0.950
V_fixture_max = 1.050
|  time   V(typ)   V(min)   V(max)
0s        999.9mV    950.8mV    1.051V
356ps     999.5mV    950.7mV    1.05V
475ps     984.4mV    950.8mV    847mV
654ps     730.5mV    949.6mV    675.8mV
795ps     617.2mV    798.2mV    613.6mV
1.004ns   546.5mV    603.4mV    563.3mV
1.184ns   517.1mV    534.7mV    538.9mV
1.484ns   492.3mV    488.1mV    515.4mV
3.142ns   460.5mV    447.5mV    479.3mV
10ns      450.7mV    438mV      469.5mV
[Falling Waveform]
R_fixture = 50.000
V_fixture = 0.000
V_fixture_min = 0.000
V_fixture_max = 0.000
|  time   V(typ)   V(min)   V(max)
0s        573mV      536.7mV    602.2mV
356ps     572.8mV    536.3mV    619.3mV
461ps     586.7mV    536.4mV    288.4mV
590ps     271.8mV    545.4mV    147.1mV
664ps     169mV      553.7mV    112.1mV
814ps     90.53mV    271.1mV    72.48mV
884ps     72.89mV    178mV      61.35mV
1.124ns   41.35mV    68.25mV    38.83mV
2.453ns   9.833mV    10.03mV    8.633mV
10ns      21.62uV    62.96uV    -269.4uV
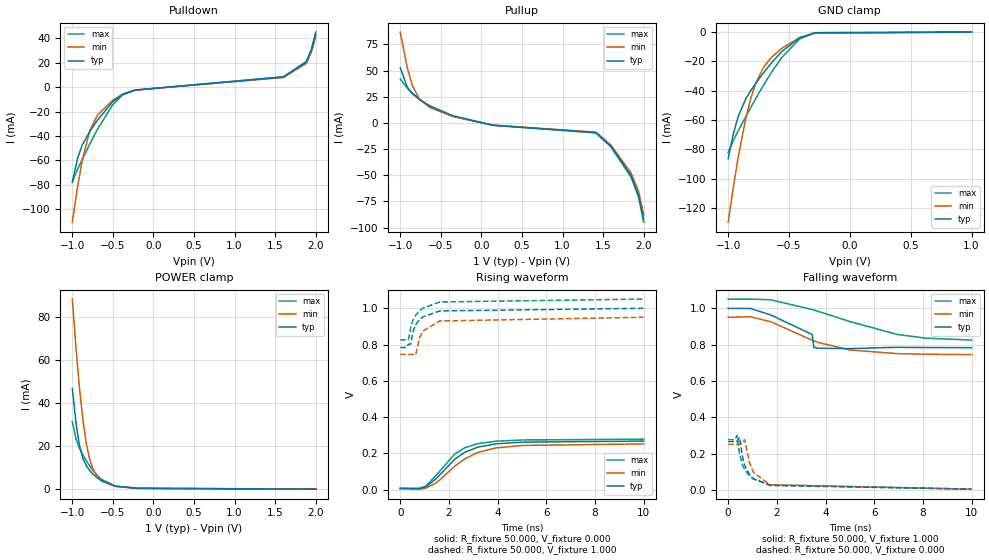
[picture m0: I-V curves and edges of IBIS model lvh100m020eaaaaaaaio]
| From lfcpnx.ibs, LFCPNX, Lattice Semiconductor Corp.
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[Model] lvh100m020eaaaaaaaio
Model_type I/O
Polarity   Non-Inverting
Enable   Active-Low
Vinl =  0.350V
Vinh =  0.650V
Vmeas =  0.500V
Cref =  0.0F
Rref =  1.000M
Vref =  0.0V
C_comp   5.000pF   4.000pF   5.500pF
[Temperature Range]   25.000   0.125k   -40.000
[Voltage Range]   1.000V   0.950V   1.050V
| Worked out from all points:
|   slope of the pulldown table from 0 to 0.15 V, typ, clamps not added: 107 ohm
|   slope of the pullup table from 0 to 0.15 V, typ, clamps not added: 67.4 ohm
|   GND clamp passes 1 mA (typ) near -0.32 V on its own axis
|   POWER clamp passes 1 mA (typ) near -0.46 V on its own axis
|   rising waveform, R_fixture 50.000, V_fixture 0.000: 20-80 % time 1.33ns typ, 1.5ns min, 1.17ns max; typ from 0.006 V to 0.267 V
|   rising waveform, R_fixture 50.000, V_fixture 1.000: 20-80 % time 519ps typ, 523ps min, 587ps max; typ from 0.783 V to 1 V
|   falling waveform, R_fixture 50.000, V_fixture 1.000: 20-80 % time 1.62ns typ, 2.32ns min, 3.3ns max; typ from 1 V to 0.783 V
|   falling waveform, R_fixture 50.000, V_fixture 0.000: 20-80 % time 532ps typ, 525ps min, 613ps max; typ from 0.267 V to 0.006 V
[GND_clamp]
|Voltage   I(typ)   I(min)   I(max)
-1V       -86.39mA   -129.8mA   -82.1mA
-958mV    -69.62mA   -106.1mA   -74.12mA
-916mV    -57.21mA   -84.7mA    -67.22mA
-853mV    -45.26mA   -58.07mA   -57.38mA
-811mV    -39.58mA   -44.43mA   -50.99mA
-769mV    -34.5mA    -34.04mA   -44.75mA
-706mV    -27.42mA   -23.61mA   -35.76mA
-643mV    -20.91mA   -17.14mA   -27.32mA
-559mV    -13.28mA   -11.04mA   -17.29mA
-412mV    -3.804mA   -3.723mA   -4.655mA
-286mV    -477.7uA   -703.7uA   -396.2uA
1V        0A         0A         0A
[POWER_clamp]
|Voltage   I(typ)   I(min)   I(max)
-1V       46.74mA    88.29mA    31.25mA
-953mV    29.96mA    64.69mA    22.99mA
-911mV    20.02mA    46.58mA    18.81mA
-869mV    14.14mA    31.9mA     15.73mA
-827mV    10.71mA    20.96mA    13.03mA
-785mV    8.459mA    13.56mA    10.59mA
-743mV    6.733mA    8.952mA    8.425mA
-701mV    5.305mA    6.142mA    6.561mA
-638mV    3.604mA    3.771mA    4.35mA
-470mV    1.11mA     1.202mA    1.272mA
-197mV    214.8uA    168.4uA    281.4uA
2V        -171.9uA   -171.2uA   -177.1uA
[Pulldown]
|Voltage   I(typ)   I(min)   I(max)
-1V       -78.05mA   -110.7mA   -77.47mA
-938mV    -58.82mA   -82.64mA   -67.66mA
-876mV    -47.13mA   -59.37mA   -58.92mA
-783mV    -36.18mA   -35.41mA   -46.31mA
-690mV    -27mA      -22.92mA   -34.43mA
-504mV    -12.02mA   -10.77mA   -14.57mA
-380mV    -5.703mA   -5.676mA   -6.316mA
-225mV    -2.268mA   -2.309mA   -2.379mA
1.604V    8.407mA    7.987mA    8.659mA
1.883V    20.55mA    19.53mA    21.17mA
1.945V    30.02mA    28.52mA    30.92mA
2V        43.93mA    41.74mA    45.25mA
[Pullup]
|Voltage   I(typ)   I(min)   I(max)
-1V       52.89mA    86.84mA    42.03mA
-914mV    34.47mA    53.16mA    33.37mA
-852mV    27.99mA    36.01mA    28.73mA
-759mV    22.22mA    22.19mA    22.53mA
-635mV    16.33mA    14.77mA    15.82mA
-356mV    7.075mA    6.36mA     6.402mA
140mV     -2.119mA   -2.013mA   -2.182mA
1.411V    -9.193mA   -8.733mA   -9.468mA
1.597V    -22.18mA   -21.07mA   -22.84mA
1.845V    -50.24mA   -47.73mA   -51.75mA
1.938V    -69.01mA   -65.56mA   -71.08mA
2V        -92.01mA   -87.41mA   -94.77mA
[Ramp]
| variable   typ   min   max
dV/dt_r   0.151/1.333n   0.148/1.513n   0.163/1.189n
dV/dt_f   0.130/2.036n   0.123/2.409n   0.135/3.308n
R_load = 50.000
[Rising Waveform]
R_fixture = 50.000
V_fixture = 0.000
V_fixture_min = 0.000
V_fixture_max = 0.000
|  time   V(typ)   V(min)   V(max)
0s        5.967mV    5.746mV    6.173mV
784ps     5.458mV    1.853mV    6.362mV
1.055ns   14.33mV    7.815mV    18.43mV
1.485ns   60.66mV    36.7mV     79.88mV
2.244ns   167.7mV    128.9mV    196.6mV
2.662ns   206.1mV    170.3mV    231.2mV
3.189ns   233.9mV    204.6mV    253.4mV
3.933ns   251.9mV    229.5mV    266.6mV
4.991ns   261.1mV    243mV      273.2mV
10ns      267.5mV    251.8mV    277.9mV
[Rising Waveform]
R_fixture = 50.000
V_fixture = 1.000
V_fixture_min = 0.950
V_fixture_max = 1.050
|  time   V(typ)   V(min)   V(max)
0s        783.5mV    745.6mV    825.6mV
263ps     783.6mV    745.9mV    825.8mV
336ps     801.6mV    745.7mV    825.8mV
435ps     803.4mV    745.7mV    895.2mV
519ps     869.7mV    745.6mV    932.9mV
632ps     909.5mV    743.2mV    961.3mV
795ps     937.7mV    838.1mV    986.4mV
934ps     952.7mV    874.3mV    1.001V
1.622ns   985.5mV    930.1mV    1.035V
10ns      1V         950.6mV    1.051V
[Falling Waveform]
R_fixture = 50.000
V_fixture = 1.000
V_fixture_min = 0.950
V_fixture_max = 1.050
|  time   V(typ)   V(min)   V(max)
0s        1V         950.6mV    1.051V
904ps     999.5mV    954.2mV    1.051V
1.744ns   964mV      926.8mV    1.047V
3.45ns    856.2mV    824.6mV    993.8mV
3.522ns   784.8mV    820.9mV    990.8mV
3.691ns   780.8mV    812.8mV    983.7mV
5ns       778.6mV    771mV      927.4mV
6.944ns   785.7mV    751.1mV    856.4mV
8.137ns   784.3mV    747.6mV    835.9mV
10ns      783.5mV    745.6mV    825.6mV
[Falling Waveform]
R_fixture = 50.000
V_fixture = 0.000
V_fixture_min = 0.000
V_fixture_max = 0.000
|  time   V(typ)   V(min)   V(max)
0s        267.5mV    251.8mV    277.9mV
283ps     267.4mV    251.4mV    277.4mV
362ps     267.5mV    251.4mV    300.9mV
466ps     291.7mV    251.5mV    202.1mV
586ps     185.6mV    259.3mV    140mV
676ps     137mV      278.1mV    113.8mV
874ps     86.36mV    153.2mV    78.91mV
1.036ns   63.35mV    98.01mV    62.03mV
1.724ns   25.64mV    30.1mV     29.27mV
10ns      5.967mV    5.746mV    6.173mV
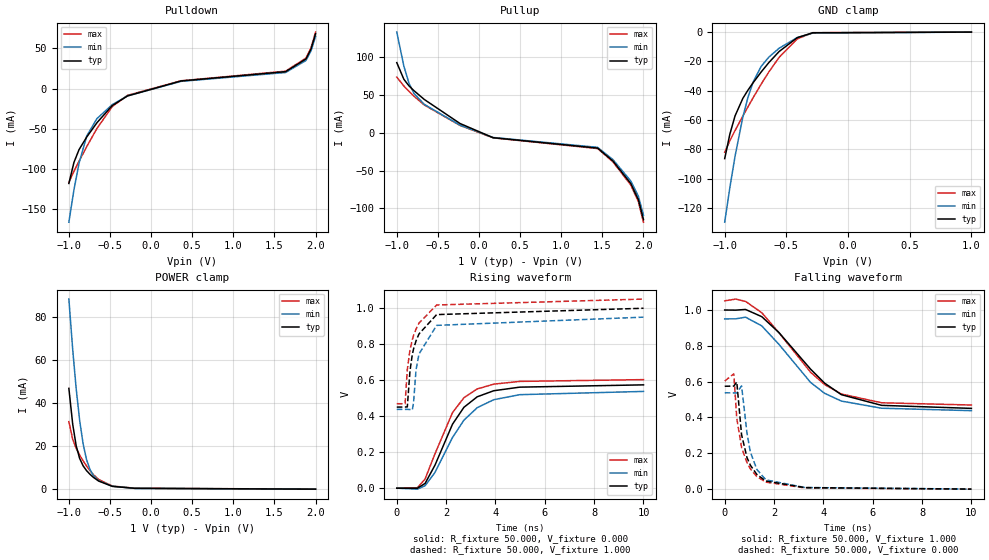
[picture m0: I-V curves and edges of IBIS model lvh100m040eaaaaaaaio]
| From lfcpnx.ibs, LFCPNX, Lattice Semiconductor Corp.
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[Model] lvh100m040eaaaaaaaio
Model_type I/O
Polarity   Non-Inverting
Enable   Active-Low
Vinl =  0.350V
Vinh =  0.650V
Vmeas =  0.500V
Cref =  0.0F
Rref =  1.000M
Vref =  0.0V
C_comp   5.000pF   4.000pF   5.500pF
[Temperature Range]   25.000   0.125k   -40.000
[Voltage Range]   1.000V   0.950V   1.050V
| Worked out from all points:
|   slope of the pulldown table from 0 to 0.15 V, typ, clamps not added: 34.6 ohm
|   slope of the pullup table from 0 to 0.15 V, typ, clamps not added: 26 ohm
|   GND clamp passes 1 mA (typ) near -0.32 V on its own axis
|   POWER clamp passes 1 mA (typ) near -0.46 V on its own axis
|   rising waveform, R_fixture 50.000, V_fixture 0.000: 20-80 % time 1.28ns typ, 1.47ns min, 1.22ns max; typ from 0 V to 0.574 V
|   rising waveform, R_fixture 50.000, V_fixture 1.000: 20-80 % time 550ps typ, 509ps min, 584ps max; typ from 0.451 V to 1 V
|   falling waveform, R_fixture 50.000, V_fixture 1.000: 20-80 % time 2.25ns typ, 2.03ns min, 2.19ns max; typ from 1 V to 0.451 V
|   falling waveform, R_fixture 50.000, V_fixture 0.000: 20-80 % time 544ps typ, 498ps min, 565ps max; typ from 0.574 V to 0 V
[GND_clamp]
|Voltage   I(typ)   I(min)   I(max)
-1V       -86.39mA   -129.8mA   -82.1mA
-958mV    -69.62mA   -106.1mA   -74.12mA
-916mV    -57.21mA   -84.7mA    -67.22mA
-853mV    -45.26mA   -58.07mA   -57.38mA
-811mV    -39.58mA   -44.43mA   -50.99mA
-769mV    -34.5mA    -34.04mA   -44.75mA
-706mV    -27.42mA   -23.61mA   -35.76mA
-643mV    -20.91mA   -17.14mA   -27.32mA
-559mV    -13.28mA   -11.04mA   -17.29mA
-412mV    -3.804mA   -3.723mA   -4.655mA
-286mV    -477.7uA   -703.7uA   -396.2uA
1V        0A         0A         0A
[POWER_clamp]
|Voltage   I(typ)   I(min)   I(max)
-1V       46.74mA    88.29mA    31.25mA
-953mV    29.96mA    64.69mA    22.99mA
-911mV    20.02mA    46.58mA    18.81mA
-869mV    14.14mA    31.9mA     15.73mA
-827mV    10.71mA    20.96mA    13.03mA
-785mV    8.459mA    13.56mA    10.59mA
-743mV    6.733mA    8.952mA    8.425mA
-701mV    5.305mA    6.142mA    6.561mA
-638mV    3.604mA    3.771mA    4.35mA
-470mV    1.11mA     1.202mA    1.272mA
-197mV    214.8uA    168.4uA    281.4uA
2V        -171.9uA   -171.2uA   -177.1uA
[Pulldown]
|Voltage   I(typ)   I(min)   I(max)
-1V       -118.4mA   -166.7mA   -117mA
-938mV    -92.07mA   -126.1mA   -103.2mA
-876mV    -76.13mA   -92.99mA   -90.66mA
-783mV    -60.46mA   -59.19mA   -72.49mA
-659mV    -42.67mA   -37.52mA   -49.88mA
-473mV    -21.27mA   -20.11mA   -22.48mA
-287mV    -9.194mA   -9.165mA   -8.478mA
364mV     9.452mA    8.98mA     9.736mA
1.635V    21.06mA    20.01mA    21.69mA
1.883V    36.89mA    35.04mA    37.99mA
1.945V    49.53mA    47.05mA    51.01mA
2V        68.4mA     64.98mA    70.45mA
[Pullup]
|Voltage   I(typ)   I(min)   I(max)
-1V       93.11mA    133.6mA    73.95mA
-914mV    71.08mA    88.51mA    62.13mA
-852mV    62.37mA    66mA       55.11mA
-790mV    55.82mA    52.13mA    48.55mA
-666mV    44.34mA    37.82mA    36.99mA
-232mV    12.48mA    10.27mA    9.896mA
171mV     -6.399mA   -6.079mA   -6.591mA
1.442V    -20.2mA    -19.19mA   -20.81mA
1.628V    -37.23mA   -35.37mA   -38.34mA
1.845V    -67.09mA   -63.73mA   -69.1mA
1.938V    -88.52mA   -84.09mA   -91.17mA
2V        -114.9mA   -109.2mA   -118.4mA
[Ramp]
| variable   typ   min   max
dV/dt_r   0.346/1.289n   0.323/1.487n   0.363/1.225n
dV/dt_f   0.327/2.344n   0.305/2.071n   0.346/2.247n
R_load = 50.000
[Rising Waveform]
R_fixture = 50.000
V_fixture = 0.000
V_fixture_min = 0.000
V_fixture_max = 0.000
|  time   V(typ)   V(min)   V(max)
0s        21.62uV    59.92uV    -269.4uV
837ps     -107uV     -5.361mV   2.623mV
1.147ns   26.51mV    13.79mV    51.11mV
1.548ns   128mV      87.46mV    191.2mV
2.258ns   355.5mV    281.7mV    419.6mV
2.721ns   449.5mV    378.1mV    502.8mV
3.261ns   508mV      447.5mV    551.6mV
3.93ns    541.6mV    491.7mV    578.2mV
4.981ns   561.5mV    519.7mV    593.4mV
10ns      574.3mV    537.8mV    603.4mV
[Rising Waveform]
R_fixture = 50.000
V_fixture = 1.000
V_fixture_min = 0.950
V_fixture_max = 1.050
|  time   V(typ)   V(min)   V(max)
0s        450.7mV    438mV      469.5mV
336ps     451.1mV    438.1mV    469.2mV
427ps     451.9mV    438.1mV    659mV
534ps     650.5mV    437.3mV    768.6mV
630ps     743.5mV    434.7mV    825.5mV
681ps     774.4mV    477mV      848.4mV
781ps     819.3mV    658.6mV    884.3mV
901ps     857.4mV    745.9mV    917.5mV
1.615ns   964.7mV    904.8mV    1.018V
10ns      999.9mV    950.5mV    1.051V
[Falling Waveform]
R_fixture = 50.000
V_fixture = 1.000
V_fixture_min = 0.950
V_fixture_max = 1.050
|  time   V(typ)   V(min)   V(max)
0s        999.9mV    950.5mV    1.051V
449ps     999.2mV    950.6mV    1.061V
844ps     1.003V     960mV      1.048V
1.501ns   962.9mV    911.5mV    985mV
2.2ns     873.8mV    807.9mV    872.7mV
3.481ns   669.8mV    595.6mV    652.6mV
4.051ns   591.5mV    534.7mV    583.4mV
4.73ns    527.2mV    491.5mV    531mV
6.36ns    467.6mV    451.6mV    482mV
10ns      450.7mV    438mV      469.5mV
[Falling Waveform]
R_fixture = 50.000
V_fixture = 0.000
V_fixture_min = 0.000
V_fixture_max = 0.000
|  time   V(typ)   V(min)   V(max)
0s        574.3mV    537.8mV    603.4mV
369ps     575.1mV    537.3mV    643.6mV
490ps     597.9mV    536.8mV    394.5mV
684ps     303.5mV    576.4mV    232.7mV
904ps     175.7mV    311.7mV    147.3mV
1.041ns   133.4mV    206.7mV    112.9mV
1.304ns   81.53mV    109.5mV    70.15mV
1.671ns   44.97mV    51.7mV     38.92mV
3.251ns   8.542mV    8.873mV    6.532mV
10ns      21.62uV    59.92uV    -269.4uV
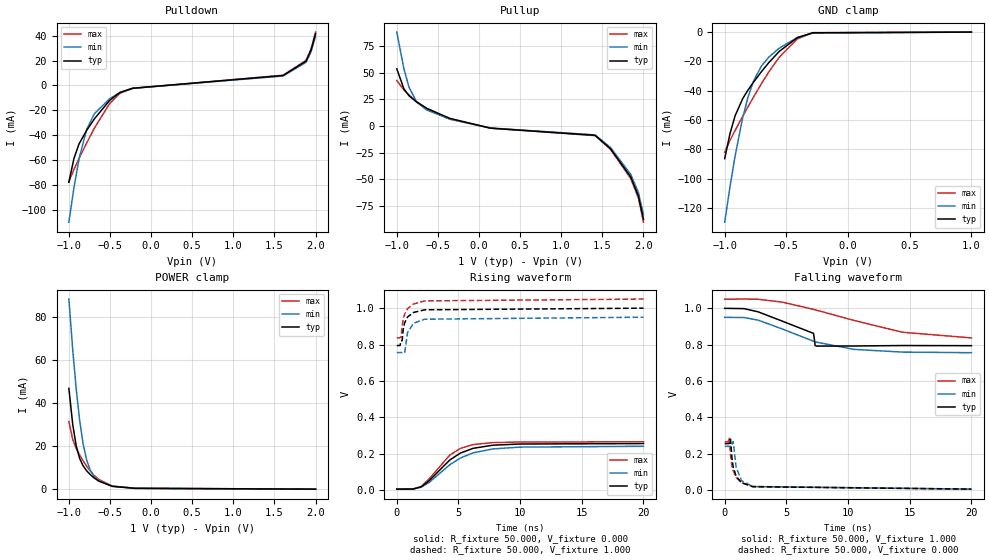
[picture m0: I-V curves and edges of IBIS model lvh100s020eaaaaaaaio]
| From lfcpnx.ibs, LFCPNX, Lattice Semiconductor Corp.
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[Model] lvh100s020eaaaaaaaio
Model_type I/O
Polarity   Non-Inverting
Enable   Active-Low
Vinl =  0.350V
Vinh =  0.650V
Vmeas =  0.500V
Cref =  0.0F
Rref =  1.000M
Vref =  0.0V
C_comp   5.000pF   4.000pF   5.500pF
[Temperature Range]   25.000   0.125k   -40.000
[Voltage Range]   1.000V   0.950V   1.050V
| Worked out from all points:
|   slope of the pulldown table from 0 to 0.15 V, typ, clamps not added: 112 ohm
|   slope of the pullup table from 0 to 0.15 V, typ, clamps not added: 70.3 ohm
|   GND clamp passes 1 mA (typ) near -0.32 V on its own axis
|   POWER clamp passes 1 mA (typ) near -0.46 V on its own axis
|   rising waveform, R_fixture 50.000, V_fixture 0.000: 20-80 % time 2.54ns typ, 2.91ns min, 2.16ns max; typ from 0.006 V to 0.256 V
|   rising waveform, R_fixture 50.000, V_fixture 1.000: 20-80 % time 512ps typ, 548ps min, 614ps max; typ from 0.795 V to 1 V
|   falling waveform, R_fixture 50.000, V_fixture 1.000: 20-80 % time 3.64ns typ, 4.79ns min, 7.14ns max; typ from 1 V to 0.795 V
|   falling waveform, R_fixture 50.000, V_fixture 0.000: 20-80 % time 571ps typ, 561ps min, 616ps max; typ from 0.256 V to 0.006 V
[GND_clamp]
|Voltage   I(typ)   I(min)   I(max)
-1V       -86.39mA   -129.8mA   -82.1mA
-958mV    -69.62mA   -106.1mA   -74.12mA
-916mV    -57.21mA   -84.7mA    -67.22mA
-853mV    -45.26mA   -58.07mA   -57.38mA
-811mV    -39.58mA   -44.43mA   -50.99mA
-769mV    -34.5mA    -34.04mA   -44.75mA
-706mV    -27.42mA   -23.61mA   -35.76mA
-643mV    -20.91mA   -17.14mA   -27.32mA
-559mV    -13.28mA   -11.04mA   -17.29mA
-412mV    -3.804mA   -3.723mA   -4.655mA
-286mV    -477.7uA   -703.7uA   -396.2uA
1V        0A         0A         0A
[POWER_clamp]
|Voltage   I(typ)   I(min)   I(max)
-1V       46.74mA    88.29mA    31.25mA
-953mV    29.96mA    64.69mA    22.99mA
-911mV    20.02mA    46.58mA    18.81mA
-869mV    14.14mA    31.9mA     15.73mA
-827mV    10.71mA    20.96mA    13.03mA
-785mV    8.459mA    13.56mA    10.59mA
-743mV    6.733mA    8.952mA    8.425mA
-701mV    5.305mA    6.142mA    6.561mA
-638mV    3.604mA    3.771mA    4.35mA
-470mV    1.11mA     1.202mA    1.272mA
-197mV    214.8uA    168.4uA    281.4uA
2V        -171.9uA   -171.2uA   -177.1uA
[Pulldown]
|Voltage   I(typ)   I(min)   I(max)
-1V       -77.67mA   -109.7mA   -77.1mA
-938mV    -58.53mA   -81.92mA   -67.33mA
-876mV    -46.89mA   -58.86mA   -58.63mA
-783mV    -36mA      -35.1mA    -46.09mA
-690mV    -26.86mA   -22.73mA   -34.26mA
-504mV    -11.96mA   -10.67mA   -14.5mA
-380mV    -5.675mA   -5.626mA   -6.286mA
-225mV    -2.256mA   -2.289mA   -2.368mA
1.604V    7.952mA    7.554mA    8.191mA
1.883V    19.44mA    18.47mA    20.03mA
1.945V    28.4mA     26.98mA    29.25mA
2V        41.56mA    39.48mA    42.8mA
[Pullup]
|Voltage   I(typ)   I(min)   I(max)
-1V       53.82mA    88.35mA    42.77mA
-914mV    35.07mA    54.09mA    33.96mA
-852mV    28.48mA    36.64mA    29.23mA
-759mV    22.61mA    22.58mA    22.92mA
-635mV    16.61mA    15.03mA    16.1mA
-356mV    7.199mA    6.471mA    6.513mA
140mV     -2.023mA   -1.922mA   -2.084mA
1.411V    -8.779mA   -8.34mA    -9.042mA
1.597V    -21.18mA   -20.12mA   -21.81mA
1.845V    -47.98mA   -45.58mA   -49.42mA
1.938V    -65.9mA    -62.61mA   -67.88mA
2V        -87.86mA   -83.47mA   -90.5mA
[Ramp]
| variable   typ   min   max
dV/dt_r   0.152/2.514n   0.141/2.889n   0.156/2.208n
dV/dt_f   0.123/4.122n   0.117/4.816n   0.128/7.146n
R_load = 50.000
[Rising Waveform]
R_fixture = 50.000
V_fixture = 0.000
V_fixture_min = 0.000
V_fixture_max = 0.000
|  time   V(typ)   V(min)   V(max)
0s        6.149mV    5.918mV    6.362mV
1.325ns   6.647mV    6.245mV    6.88mV
1.979ns   18.85mV    16.61mV    20.73mV
2.6ns     50.69mV    41.63mV    60.52mV
4.301ns   166.3mV    140.1mV    193.3mV
5.159ns   204.3mV    177.1mV    229.7mV
6.191ns   230.3mV    205.4mV    250.8mV
7.787ns   247.3mV    226.9mV    261.6mV
9.95ns    253.9mV    236.9mV    264.9mV
20ns      256.4mV    241.4mV    266.3mV
[Rising Waveform]
R_fixture = 50.000
V_fixture = 1.000
V_fixture_min = 0.950
V_fixture_max = 1.050
|  time   V(typ)   V(min)   V(max)
0s        794.7mV    756.1mV    837.4mV
263ps     794.9mV    756.3mV    837.6mV
346ps     820.4mV    756.2mV    839.7mV
433ps     821.3mV    756.2mV    902mV
523ps     884mV      756mV      940.2mV
640ps     919.8mV    754.7mV    967.3mV
869ps     951mV      865.3mV    996.7mV
1.353ns   976.4mV    917mV      1.023V
2.264ns   991mV      939.4mV    1.04V
20ns      1V         950.4mV    1.05V
[Falling Waveform]
R_fixture = 50.000
V_fixture = 1.000
V_fixture_min = 0.950
V_fixture_max = 1.050
|  time   V(typ)   V(min)   V(max)
0s        1V         950.4mV    1.05V
1.564ns   998.4mV    949.5mV    1.051V
2.71ns    980.8mV    935.2mV    1.05V
4.681ns   929.2mV    886.2mV    1.034V
7.205ns   862.3mV    819.1mV    994.3mV
7.335ns   795mV      816.3mV    991.9mV
7.465ns   792.5mV    813.7mV    989.5mV
10.47ns   793mV      774.4mV    933.7mV
14.39ns   795.5mV    759.5mV    868.7mV
20ns      794.7mV    756.1mV    837.4mV
[Falling Waveform]
R_fixture = 50.000
V_fixture = 0.000
V_fixture_min = 0.000
V_fixture_max = 0.000
|  time   V(typ)   V(min)   V(max)
0s        256.4mV    241.4mV    266.3mV
283ps     256.4mV    241mV      265.9mV
369ps     257.1mV    241mV      289.5mV
470ps     280.7mV    241mV      192.6mV
593ps     174.7mV    250.6mV    133.1mV
684ps     129.7mV    267.8mV    108.3mV
929ps     76.6mV     126mV      70.2mV
1.36ns    41.68mV    53.06mV    41.35mV
2.274ns   19.42mV    20.32mV    20.65mV
20ns      6.149mV    5.918mV    6.362mV
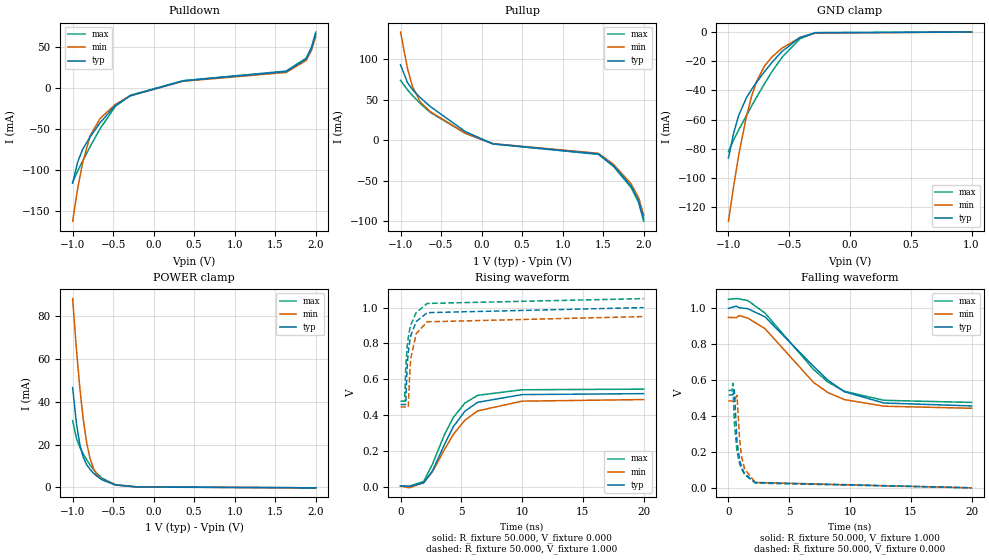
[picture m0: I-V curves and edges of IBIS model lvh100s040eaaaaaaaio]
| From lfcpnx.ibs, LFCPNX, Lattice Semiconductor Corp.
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[Model] lvh100s040eaaaaaaaio
Model_type I/O
Polarity   Non-Inverting
Enable   Active-Low
Vinl =  0.350V
Vinh =  0.650V
Vmeas =  0.500V
Cref =  0.0F
Rref =  1.000M
Vref =  0.0V
C_comp   5.000pF   4.000pF   5.500pF
[Temperature Range]   25.000   0.125k   -40.000
[Voltage Range]   1.000V   0.950V   1.050V
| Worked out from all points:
|   slope of the pulldown table from 0 to 0.15 V, typ, clamps not added: 35.4 ohm
|   slope of the pullup table from 0 to 0.15 V, typ, clamps not added: 30.4 ohm
|   GND clamp passes 1 mA (typ) near -0.32 V on its own axis
|   POWER clamp passes 1 mA (typ) near -0.46 V on its own axis
|   rising waveform, R_fixture 50.000, V_fixture 0.000: 20-80 % time 2.46ns typ, 2.83ns min, 2.32ns max; typ from 0.003 V to 0.519 V
|   rising waveform, R_fixture 50.000, V_fixture 1.000: 20-80 % time 572ps typ, 545ps min, 614ps max; typ from 0.458 V to 1 V
|   falling waveform, R_fixture 50.000, V_fixture 1.000: 20-80 % time 4.79ns typ, 4.26ns min, 4.61ns max; typ from 1 V to 0.458 V
|   falling waveform, R_fixture 50.000, V_fixture 0.000: 20-80 % time 570ps typ, 558ps min, 612ps max; typ from 0.519 V to 0.003 V
[GND_clamp]
|Voltage   I(typ)   I(min)   I(max)
-1V       -86.39mA   -129.8mA   -82.1mA
-958mV    -69.62mA   -106.1mA   -74.12mA
-916mV    -57.21mA   -84.7mA    -67.22mA
-853mV    -45.26mA   -58.07mA   -57.38mA
-811mV    -39.58mA   -44.43mA   -50.99mA
-769mV    -34.5mA    -34.04mA   -44.75mA
-706mV    -27.42mA   -23.61mA   -35.76mA
-643mV    -20.91mA   -17.14mA   -27.32mA
-559mV    -13.28mA   -11.04mA   -17.29mA
-412mV    -3.804mA   -3.723mA   -4.655mA
-286mV    -477.7uA   -703.7uA   -396.2uA
1V        0A         0A         0A
[POWER_clamp]
|Voltage   I(typ)   I(min)   I(max)
-1V       46.74mA    88.29mA    31.25mA
-953mV    29.96mA    64.69mA    22.99mA
-911mV    20.02mA    46.58mA    18.81mA
-869mV    14.14mA    31.9mA     15.73mA
-827mV    10.71mA    20.96mA    13.03mA
-785mV    8.459mA    13.56mA    10.59mA
-743mV    6.733mA    8.952mA    8.425mA
-701mV    5.305mA    6.142mA    6.561mA
-638mV    3.604mA    3.771mA    4.35mA
-470mV    1.11mA     1.202mA    1.272mA
-197mV    214.8uA    168.4uA    281.4uA
2V        -171.9uA   -171.2uA   -177.1uA
[Pulldown]
|Voltage   I(typ)   I(min)   I(max)
-1V       -115.6mA   -162mA     -114.4mA
-938mV    -89.86mA   -122.5mA   -100.9mA
-876mV    -74.31mA   -90.37mA   -88.63mA
-783mV    -59mA      -57.52mA   -70.87mA
-659mV    -41.64mA   -36.46mA   -48.76mA
-473mV    -20.76mA   -19.54mA   -21.98mA
-287mV    -8.973mA   -8.905mA   -8.289mA
364mV     9.225mA    8.764mA    9.502mA
1.635V    20.55mA    19.53mA    21.17mA
1.883V    36mA       34.2mA     37.08mA
1.945V    48.34mA    45.92mA    49.79mA
2V        66.76mA    63.42mA    68.76mA
[Pullup]
|Voltage   I(typ)   I(min)   I(max)
-1V       93.11mA    133.6mA    73.95mA
-914mV    71.08mA    88.51mA    62.13mA
-852mV    62.37mA    66mA       55.11mA
-759mV    52.81mA    47.45mA    45.45mA
-635mV    41.68mA    35.34mA    34.45mA
-201mV    10.63mA    8.725mA    8.452mA
140mV     -4.601mA   -4.371mA   -4.739mA
1.442V    -17.12mA   -16.26mA   -17.63mA
1.628V    -31.55mA   -29.97mA   -32.49mA
1.845V    -56.85mA   -54.01mA   -58.56mA
1.938V    -75.02mA   -71.27mA   -77.27mA
2V        -97.38mA   -92.51mA   -100.3mA
[Ramp]
| variable   typ   min   max
dV/dt_r   0.298/2.439n   0.290/2.812n   0.325/2.332n
dV/dt_f   0.321/4.811n   0.300/4.274n   0.340/4.620n
R_load = 50.000
[Rising Waveform]
R_fixture = 50.000
V_fixture = 0.000
V_fixture_min = 0.000
V_fixture_max = 0.000
|  time   V(typ)   V(min)   V(max)
0s        3.471mV    3.33mV     3.303mV
725ps     1.45mV     -6.898mV   1.865mV
1.901ns   20.79mV    22.52mV    28.83mV
2.62ns    87.09mV    82.3mV     124mV
3.624ns   236.6mV    208.1mV    291.9mV
4.351ns   335.7mV    292.3mV    387.3mV
5.3ns     421.4mV    371.3mV    466.9mV
6.35ns    470.9mV    422.9mV    509.8mV
9.999ns   513.9mV    477.3mV    540.9mV
20ns      519.2mV    486.1mV    544.2mV
[Rising Waveform]
R_fixture = 50.000
V_fixture = 1.000
V_fixture_min = 0.950
V_fixture_max = 1.050
|  time   V(typ)   V(min)   V(max)
0s        458.1mV    445mV      477.5mV
336ps     458.5mV    445.1mV    477.1mV
426ps     458.9mV    445.2mV    662.5mV
538ps     660.8mV    444.1mV    775mV
636ps     751.3mV    443.4mV    831mV
768ps     817mV      647mV      881.4mV
845ps     843.1mV    716.6mV    902.8mV
1.288ns   921.4mV    853.9mV    971.7mV
2.195ns   971.5mV    920.6mV    1.023V
20ns      999.9mV    949.6mV    1.05V
[Falling Waveform]
R_fixture = 50.000
V_fixture = 1.000
V_fixture_min = 0.950
V_fixture_max = 1.050
|  time   V(typ)   V(min)   V(max)
0s        999.9mV    949.6mV    1.05V
643ps     1.012V     948.4mV    1.054V
894ps     1.003V     959.8mV    1.052V
1.591ns   998.1mV    946mV      1.043V
3.003ns   952.8mV    887.4mV    974.1mV
6.985ns   679mV      589.6mV    661.7mV
8.166ns   601.9mV    532.8mV    591.3mV
9.535ns   537.1mV    493.4mV    539.3mV
12.79ns   474.3mV    456.6mV    489.2mV
20ns      458.1mV    445mV      477.5mV
[Falling Waveform]
R_fixture = 50.000
V_fixture = 0.000
V_fixture_min = 0.000
V_fixture_max = 0.000
|  time   V(typ)   V(min)   V(max)
0s        519.2mV    486.1mV    544.2mV
283ps     519.2mV    485.8mV    543.6mV
370ps     520.2mV    485.6mV    583.4mV
482ps     547.5mV    485.3mV    370.3mV
704ps     261.3mV    516.7mV    204.7mV
914ps     159.5mV    276.9mV    138.6mV
1.072ns   119.9mV    179.7mV    108.9mV
1.334ns   81.91mV    107mV      77.09mV
2.214ns   33.28mV    32.81mV    29.54mV
20ns      3.471mV    3.33mV     3.303mV
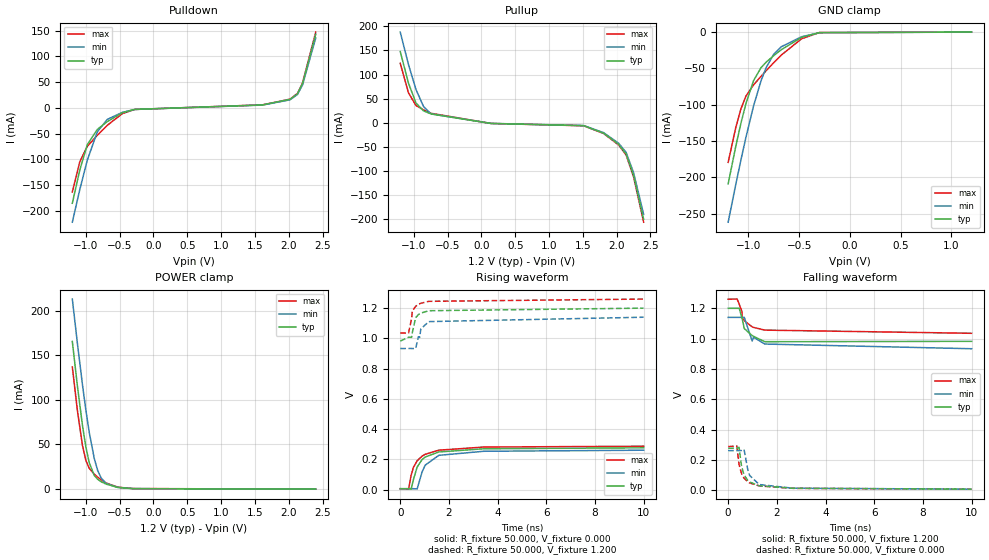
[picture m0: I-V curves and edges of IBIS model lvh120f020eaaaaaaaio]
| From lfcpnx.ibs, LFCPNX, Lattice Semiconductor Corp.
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[Model] lvh120f020eaaaaaaaio
Model_type I/O
Polarity   Non-Inverting
Enable   Active-Low
Vinl =  0.420V
Vinh =  0.780V
Vmeas =  0.600V
Cref =  0.0F
Rref =  1.000M
Vref =  0.0V
C_comp   5.000pF   4.000pF   5.500pF
[Temperature Range]   25.000   0.125k   -40.000
[Voltage Range]   1.200V   1.140V   1.260V
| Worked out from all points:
|   slope of the pulldown table from 0 to 0.18 V, typ, clamps not added: 111 ohm
|   slope of the pullup table from 0 to 0.18 V, typ, clamps not added: 83.3 ohm
|   GND clamp passes 1 mA (typ) near -0.32 V on its own axis
|   POWER clamp passes 1 mA (typ) near -0.45 V on its own axis
|   rising waveform, R_fixture 50.000, V_fixture 0.000: 20-80 % time 558ps typ, 540ps min, 580ps max; typ from 0.006 V to 0.277 V
|   rising waveform, R_fixture 50.000, V_fixture 1.200: 20-80 % time 257ps typ, 328ps min, 261ps max; typ from 0.982 V to 1.2 V
|   falling waveform, R_fixture 50.000, V_fixture 1.200: 20-80 % time 384ps typ, 574ps min, 478ps max; typ from 1.2 V to 0.982 V
|   falling waveform, R_fixture 50.000, V_fixture 0.000: 20-80 % time 333ps typ, 335ps min, 346ps max; typ from 0.277 V to 0.006 V
[GND_clamp]
|Voltage   I(typ)   I(min)   I(max)
-1.2V     -208.9mA   -261.7mA   -179.3mA
-1.125V   -157.4mA   -209.8mA   -131.5mA
-1.075V   -126mA     -176.6mA   -106.1mA
-1.025V   -98.42mA   -145mA     -88.28mA
-950mV    -66.96mA   -101.9mA   -72.76mA
-875mV    -48.78mA   -66.64mA   -60.78mA
-825mV    -41.38mA   -48.67mA   -53.1mA
-750mV    -32.3mA    -30.34mA   -41.99mA
-675mV    -24.14mA   -20.11mA   -31.53mA
-475mV    -7.155mA   -6.375mA   -9.116mA
-300mV    -673.7uA   -900.4uA   -619.4uA
1.2V      0A         0A         0A
[POWER_clamp]
|Voltage   I(typ)   I(min)   I(max)
-1.2V     165.7mA    213.3mA    137.1mA
-1.125V   115.8mA    163.7mA    88.19mA
-1.05V    71.42mA    117.1mA    48.87mA
-1V       47.37mA    88.79mA    32.13mA
-950mV    29.54mA    63.68mA    23.24mA
-875mV    15.17mA    34.1mA     16.62mA
-825mV    10.91mA    20.81mA    13.34mA
-775mV    8.283mA    12.48mA    10.42mA
-700mV    5.463mA    6.247mA    6.777mA
-525mV    1.711mA    1.811mA    1.978mA
-300mV    395.7uA    364.9uA    500.6uA
2.4V      -178.9uA   -186.1uA   -181.3uA
[Pulldown]
|Voltage   I(typ)   I(min)   I(max)
-1.2V     -185.3mA   -222.1mA   -163.3mA
-1.089V   -120.6mA   -158.4mA   -104.5mA
-978mV    -71.42mA   -101.4mA   -74.7mA
-830mV    -41.93mA   -46.38mA   -53.32mA
-682mV    -26.66mA   -22.43mA   -33.9mA
-460mV    -9.51mA    -8.803mA   -11.2mA
-275mV    -3.015mA   -3.114mA   -3.102mA
1.612V    5.611mA    5.331mA    5.78mA
2.019V    16.35mA    15.54mA    16.84mA
2.13V     27.3mA     25.94mA    28.12mA
2.204V    46.58mA    44.25mA    47.97mA
2.4V      142.8mA    135.7mA    147.1mA
[Pullup]
|Voltage   I(typ)   I(min)   I(max)
-1.2V     147.9mA    188.3mA    123.4mA
-1.078V   81.98mA    120.7mA    61.86mA
-967mV    40.71mA    68.74mA    35.5mA
-856mV    24.43mA    33.62mA    26.44mA
-745mV    18mA       18.14mA    19.39mA
143mV     -1.765mA   -1.677mA   -1.818mA
1.512V    -6.404mA   -6.084mA   -6.596mA
1.808V    -22.05mA   -20.95mA   -22.71mA
2.03V     -45.24mA   -42.98mA   -46.59mA
2.141V    -65.38mA   -62.11mA   -67.34mA
2.252V    -110.3mA   -104.8mA   -113.6mA
2.4V      -201.2mA   -191.1mA   -207.2mA
[Ramp]
| variable   typ   min   max
dV/dt_r   0.168/0.561n   0.149/0.547n   0.166/0.579n
dV/dt_f   0.131/0.556n   0.124/0.571n   0.135/0.621n
R_load = 50.000
[Rising Waveform]
R_fixture = 50.000
V_fixture = 0.000
V_fixture_min = 0.000
V_fixture_max = 0.000
|  time   V(typ)   V(min)   V(max)
0s        6.154mV    6.21mV     6.305mV
346ps     6.354mV    6.322mV    4.132mV
445ps     3.24mV     6.26mV     94.06mV
543ps     67.11mV    6.438mV    148.2mV
694ps     149mV      4.647mV    190.7mV
895ps     198.4mV    115.8mV    221.4mV
1.024ns   215.8mV    161.8mV    233.8mV
1.584ns   249.1mV    226.9mV    261mV
3.44ns    270.3mV    253.8mV    281.7mV
10ns      276.6mV    260.8mV    287.1mV
[Rising Waveform]
R_fixture = 50.000
V_fixture = 1.200
V_fixture_min = 1.140
V_fixture_max = 1.260
|  time   V(typ)   V(min)   V(max)
0s        981.9mV    933.1mV    1.035V
343ps     1.008V     933.2mV    1.036V
467ps     1.007V     933.2mV    1.133V
498ps     1.039V     933.1mV    1.182V
634ps     1.137V     933mV      1.212V
745ps     1.157V     1.011V     1.225V
798ps     1.163V     1.006V     1.229V
844ps     1.167V     1.062V     1.232V
1.173ns   1.183V     1.111V     1.245V
10ns      1.2V       1.14V      1.26V
[Falling Waveform]
R_fixture = 50.000
V_fixture = 1.200
V_fixture_min = 1.140
V_fixture_max = 1.260
|  time   V(typ)   V(min)   V(max)
0s        1.2V       1.14V      1.26V
370ps     1.2V       1.14V      1.261V
454ps     1.2V       1.14V      1.227V
564ps     1.138V     1.14V      1.181V
574ps     1.133V     1.14V      1.141V
663ps     1.066V     1.14V      1.118V
985ps     1.02V      984.3mV    1.078V
1.043ns   1.015V     1.009V     1.074V
1.503ns   979.6mV    964.2mV    1.056V
10ns      981.9mV    933.1mV    1.035V
[Falling Waveform]
R_fixture = 50.000
V_fixture = 0.000
V_fixture_min = 0.000
V_fixture_max = 0.000
|  time   V(typ)   V(min)   V(max)
0s        276.6mV    260.8mV    287.1mV
356ps     276.4mV    260.5mV    291.3mV
446ps     282.5mV    260.7mV    170.6mV
548ps     160mV      261.3mV    109.4mV
653ps     100.1mV    268.1mV    78.8mV
803ps     64.21mV    137.8mV    55.12mV
883ps     53.35mV    96.76mV    47.24mV
1.278ns   28.52mV    36.72mV    27.44mV
2.673ns   12.16mV    12.32mV    11.45mV
10ns      6.154mV    6.21mV     6.305mV
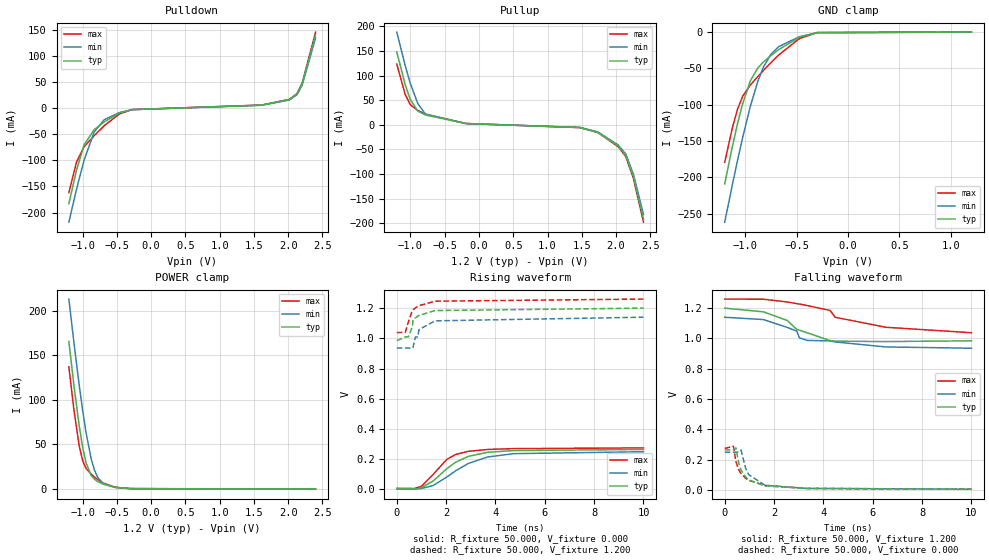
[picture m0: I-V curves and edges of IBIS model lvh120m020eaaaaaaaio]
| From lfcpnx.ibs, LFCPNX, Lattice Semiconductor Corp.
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[Model] lvh120m020eaaaaaaaio
Model_type I/O
Polarity   Non-Inverting
Enable   Active-Low
Vinl =  0.420V
Vinh =  0.780V
Vmeas =  0.600V
Cref =  0.0F
Rref =  1.000M
Vref =  0.0V
C_comp   5.000pF   4.000pF   5.500pF
[Temperature Range]   25.000   0.125k   -40.000
[Voltage Range]   1.200V   1.140V   1.260V
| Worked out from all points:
|   slope of the pulldown table from 0 to 0.18 V, typ, clamps not added: 113 ohm
|   slope of the pullup table from 0 to 0.18 V, typ, clamps not added: 87.1 ohm
|   GND clamp passes 1 mA (typ) near -0.32 V on its own axis
|   POWER clamp passes 1 mA (typ) near -0.45 V on its own axis
|   rising waveform, R_fixture 50.000, V_fixture 0.000: 20-80 % time 1.31ns typ, 1.57ns min, 962ps max; typ from 0.006 V to 0.265 V
|   rising waveform, R_fixture 50.000, V_fixture 1.200: 20-80 % time 464ps typ, 529ps min, 475ps max; typ from 0.985 V to 1.2 V
|   falling waveform, R_fixture 50.000, V_fixture 1.200: 20-80 % time 1.63ns typ, 1.47ns min, 2.85ns max; typ from 1.2 V to 0.985 V
|   falling waveform, R_fixture 50.000, V_fixture 0.000: 20-80 % time 537ps typ, 516ps min, 607ps max; typ from 0.265 V to 0.006 V
[GND_clamp]
|Voltage   I(typ)   I(min)   I(max)
-1.2V     -208.9mA   -261.7mA   -179.3mA
-1.125V   -157.4mA   -209.8mA   -131.5mA
-1.075V   -126mA     -176.6mA   -106.1mA
-1.025V   -98.42mA   -145mA     -88.28mA
-950mV    -66.96mA   -101.9mA   -72.76mA
-875mV    -48.78mA   -66.64mA   -60.78mA
-825mV    -41.38mA   -48.67mA   -53.1mA
-750mV    -32.3mA    -30.34mA   -41.99mA
-675mV    -24.14mA   -20.11mA   -31.53mA
-475mV    -7.155mA   -6.375mA   -9.116mA
-300mV    -673.7uA   -900.4uA   -619.4uA
1.2V      0A         0A         0A
[POWER_clamp]
|Voltage   I(typ)   I(min)   I(max)
-1.2V     165.7mA    213.3mA    137.1mA
-1.125V   115.8mA    163.7mA    88.19mA
-1.05V    71.42mA    117.1mA    48.87mA
-1V       47.37mA    88.79mA    32.13mA
-950mV    29.54mA    63.68mA    23.24mA
-875mV    15.17mA    34.1mA     16.62mA
-825mV    10.91mA    20.81mA    13.34mA
-775mV    8.283mA    12.48mA    10.42mA
-700mV    5.463mA    6.247mA    6.777mA
-525mV    1.711mA    1.811mA    1.978mA
-300mV    395.7uA    364.9uA    500.6uA
2.4V      -178.9uA   -186.1uA   -181.3uA
[Pulldown]
|Voltage   I(typ)   I(min)   I(max)
-1.2V     -182.9mA   -218.3mA   -161.8mA
-1.089V   -119mA     -155.7mA   -103.5mA
-978mV    -70.5mA    -99.7mA    -73.97mA
-830mV    -41.39mA   -45.59mA   -52.8mA
-682mV    -26.31mA   -22.05mA   -33.57mA
-460mV    -9.387mA   -8.653mA   -11.09mA
-275mV    -2.976mA   -3.061mA   -3.072mA
1.612V    5.539mA    5.262mA    5.705mA
2.019V    16.14mA    15.34mA    16.63mA
2.13V     26.95mA    25.6mA     27.76mA
2.204V    45.98mA    43.68mA    47.36mA
2.4V      141mA      133.9mA    145.2mA
[Pullup]
|Voltage   I(typ)   I(min)   I(max)
-1.2V     147.9mA    188.3mA    123.4mA
-1.078V   81.98mA    120.7mA    61.86mA
-1.004V   51.59mA    84.61mA    40.82mA
-893mV    27.85mA    43mA       29.06mA
-782mV    19.86mA    21.61mA    21.61mA
-190mV    2.572mA    2.372mA    2.456mA
1.475V    -5.673mA   -5.39mA    -5.843mA
1.734V    -15.38mA   -14.62mA   -15.85mA
2.03V     -43.2mA    -41.04mA   -44.5mA
2.141V    -62.44mA   -59.32mA   -64.31mA
2.252V    -105.4mA   -100.1mA   -108.6mA
2.4V      -192.2mA   -182.6mA   -198mA
[Ramp]
| variable   typ   min   max
dV/dt_r   0.155/1.318n   0.149/1.595n   0.166/1.021n
dV/dt_f   0.129/2.068n   0.123/2.485n   0.133/3.372n
R_load = 50.000
[Rising Waveform]
R_fixture = 50.000
V_fixture = 0.000
V_fixture_min = 0.000
V_fixture_max = 0.000
|  time   V(typ)   V(min)   V(max)
0s        6.178mV    6.226mV    6.334mV
695ps     5.353mV    2.131mV    6.266mV
995ps     11.65mV    6.315mV    20.06mV
1.476ns   56.37mV    26.41mV    99.81mV
2.029ns   138mV      82.85mV    199.7mV
2.39ns    180.6mV    124.3mV    231.9mV
2.903ns   219.5mV    172.7mV    252.7mV
3.684ns   246.1mV    215.1mV    264.8mV
4.731ns   257.7mV    237.1mV    270.5mV
10ns      265mV      249.9mV    275.1mV
[Rising Waveform]
R_fixture = 50.000
V_fixture = 1.200
V_fixture_min = 1.140
V_fixture_max = 1.260
|  time   V(typ)   V(min)   V(max)
0s        984.7mV    935.7mV    1.038V
346ps     1.01V      935.8mV    1.04V
475ps     1.011V     936mV      1.111V
635ps     1.079V     933.6mV    1.186V
655ps     1.118V     938.4mV    1.189V
755ps     1.135V     1.009V     1.202V
855ps     1.147V     1.01V      1.212V
901ps     1.152V     1.058V     1.216V
1.551ns   1.184V     1.116V     1.246V
10ns      1.2V       1.14V      1.26V
[Falling Waveform]
R_fixture = 50.000
V_fixture = 1.200
V_fixture_min = 1.140
V_fixture_max = 1.260
|  time   V(typ)   V(min)   V(max)
0s        1.2V       1.14V      1.26V
1.563ns   1.176V     1.125V     1.259V
2.534ns   1.119V     1.073V     1.241V
2.92ns    1.06V      1.049V     1.23V
3.031ns   1.054V     1.004V     1.227V
3.351ns   1.037V     987.1mV    1.217V
4.267ns   986.4mV    983.8mV    1.185V
4.479ns   982.5mV    977mV      1.14V
6.525ns   979.5mV    944.3mV    1.074V
10ns      984.7mV    935.7mV    1.038V
[Falling Waveform]
R_fixture = 50.000
V_fixture = 0.000
V_fixture_min = 0.000
V_fixture_max = 0.000
|  time   V(typ)   V(min)   V(max)
0s        265mV      249.9mV    275.1mV
356ps     264.6mV    249.7mV    289.1mV
454ps     278.9mV    249.9mV    188mV
563ps     182mV      251.7mV    136.2mV
663ps     132.2mV    263.9mV    108.8mV
843ps     87.29mV    146.9mV    78.27mV
973ps     67.84mV    101.8mV    64.32mV
1.633ns   27.38mV    32.23mV    30.94mV
3.31ns    10.72mV    11.31mV    11.04mV
10ns      6.178mV    6.226mV    6.334mV
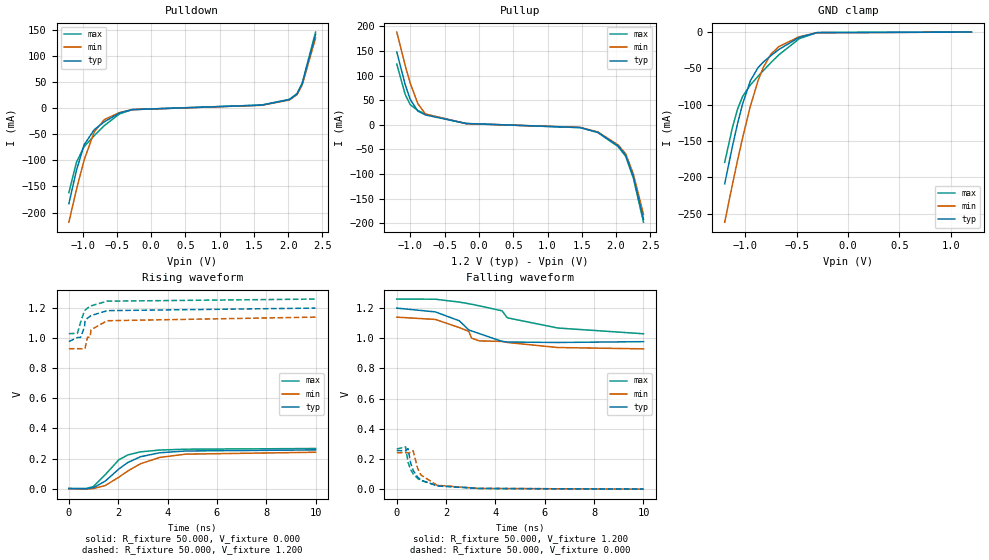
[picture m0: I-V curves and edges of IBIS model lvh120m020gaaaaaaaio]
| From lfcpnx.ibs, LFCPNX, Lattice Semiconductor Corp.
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[Model] lvh120m020gaaaaaaaio
Model_type I/O
Polarity   Non-Inverting
Enable   Active-Low
Vinl =  0.420V
Vinh =  0.780V
Vmeas =  0.600V
Cref =  0.0F
Rref =  1.000M
Vref =  0.0V
C_comp   5.000pF   4.000pF   5.500pF
[Temperature Range]   25.000   0.125k   -40.000
[Voltage Range]   1.200V   1.140V   1.260V
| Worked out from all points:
|   slope of the pulldown table from 0 to 0.18 V, typ, clamps not added: 113 ohm
|   slope of the pullup table from 0 to 0.18 V, typ, clamps not added: 87.1 ohm
|   GND clamp passes 1 mA (typ) near -0.32 V on its own axis
|   rising waveform, R_fixture 50.000, V_fixture 0.000: 20-80 % time 1.31ns typ, 1.57ns min, 962ps max; typ from 0 V to 0.257 V
|   rising waveform, R_fixture 50.000, V_fixture 1.200: 20-80 % time 464ps typ, 529ps min, 475ps max; typ from 0.978 V to 1.2 V
|   falling waveform, R_fixture 50.000, V_fixture 1.200: 20-80 % time 1.63ns typ, 1.47ns min, 2.85ns max; typ from 1.2 V to 0.978 V
|   falling waveform, R_fixture 50.000, V_fixture 0.000: 20-80 % time 537ps typ, 516ps min, 607ps max; typ from 0.255 V to 0 V
[GND_clamp]
|Voltage   I(typ)   I(min)   I(max)
-1.2V     -208.9mA   -261.7mA   -179.3mA
-1.125V   -157.4mA   -209.8mA   -131.5mA
-1.075V   -126mA     -176.6mA   -106.1mA
-1.025V   -98.42mA   -145mA     -88.28mA
-950mV    -66.96mA   -101.9mA   -72.76mA
-875mV    -48.78mA   -66.64mA   -60.78mA
-825mV    -41.38mA   -48.67mA   -53.1mA
-750mV    -32.3mA    -30.34mA   -41.99mA
-675mV    -24.14mA   -20.11mA   -31.53mA
-475mV    -7.155mA   -6.375mA   -9.116mA
-300mV    -673.7uA   -900.4uA   -619.4uA
1.2V      0A         0A         0A
[Pulldown]
|Voltage   I(typ)   I(min)   I(max)
-1.2V     -182.9mA   -218.3mA   -161.8mA
-1.089V   -119mA     -155.7mA   -103.5mA
-978mV    -70.5mA    -99.7mA    -73.97mA
-830mV    -41.39mA   -45.59mA   -52.8mA
-682mV    -26.31mA   -22.05mA   -33.57mA
-460mV    -9.387mA   -8.653mA   -11.09mA
-275mV    -2.976mA   -3.061mA   -3.072mA
1.612V    5.539mA    5.262mA    5.705mA
2.019V    16.14mA    15.34mA    16.63mA
2.13V     26.95mA    25.6mA     27.76mA
2.204V    45.98mA    43.68mA    47.36mA
2.4V      141mA      133.9mA    145.2mA
[Pullup]
|Voltage   I(typ)   I(min)   I(max)
-1.2V     147.9mA    188.3mA    123.4mA
-1.078V   81.98mA    120.7mA    61.86mA
-1.004V   51.59mA    84.61mA    40.82mA
-893mV    27.85mA    43mA       29.06mA
-782mV    19.86mA    21.61mA    21.61mA
-190mV    2.572mA    2.372mA    2.456mA
1.475V    -5.673mA   -5.39mA    -5.843mA
1.734V    -15.38mA   -14.62mA   -15.85mA
2.03V     -43.2mA    -41.04mA   -44.5mA
2.141V    -62.44mA   -59.32mA   -64.31mA
2.252V    -105.4mA   -100.1mA   -108.6mA
2.4V      -192.2mA   -182.6mA   -198mA
[Ramp]
| variable   typ   min   max
dV/dt_r   0.154/1.318n   0.149/1.595n   0.166/1.021n
dV/dt_f   0.133/2.068n   0.126/2.485n   0.138/3.372n
R_load = 50.000
[Rising Waveform]
R_fixture = 50.000
V_fixture = 0.000
V_fixture_min = 0.000
V_fixture_max = 0.000
|  time   V(typ)   V(min)   V(max)
0s        24.31uV    222uV      303.3uV
695ps     -795.8uV   -3.834mV   235.8uV
995ps     5.459mV    310.3uV    13.9mV
1.476ns   49.89mV    20.22mV    92.86mV
2.029ns   130.9mV    76.12mV    191.8mV
2.39ns    173.3mV    117.2mV    223.6mV
2.903ns   211.9mV    165.1mV    244.3mV
3.684ns   238.3mV    207.1mV    256.2mV
4.731ns   249.9mV    228.9mV    261.9mV
10ns      257.2mV    241.6mV    266.4mV
[Rising Waveform]
R_fixture = 50.000
V_fixture = 1.200
V_fixture_min = 1.140
V_fixture_max = 1.260
|  time   V(typ)   V(min)   V(max)
0s        977.7mV    930mV      1.03V
346ps     1.004V     930.1mV    1.032V
475ps     1.005V     930.3mV    1.106V
635ps     1.075V     927.9mV    1.183V
655ps     1.116V     932.8mV    1.186V
755ps     1.133V     1.006V     1.2V
855ps     1.145V     1.006V     1.211V
901ps     1.15V      1.056V     1.215V
1.551ns   1.183V     1.116V     1.246V
10ns      1.2V       1.14V      1.26V
[Falling Waveform]
R_fixture = 50.000
V_fixture = 1.200
V_fixture_min = 1.140
V_fixture_max = 1.260
|  time   V(typ)   V(min)   V(max)
0s        1.2V       1.14V      1.26V
1.563ns   1.175V     1.125V     1.259V
2.534ns   1.116V     1.071V     1.24V
2.92ns    1.055V     1.046V     1.229V
3.031ns   1.049V     1.001V     1.226V
3.351ns   1.031V     982.8mV    1.215V
4.267ns   979.4mV    979.4mV    1.182V
4.479ns   975.4mV    972.4mV    1.136V
6.525ns   972.3mV    938.9mV    1.068V
10ns      977.7mV    930mV      1.03V
[Falling Waveform]
R_fixture = 50.000
V_fixture = 0.000
V_fixture_min = 0.000
V_fixture_max = 0.000
|  time   V(typ)   V(min)   V(max)
0s        255.5mV    241.6mV    266.4mV
356ps     255mV      241.4mV    280.3mV
454ps     269.1mV    241.6mV    180.2mV
563ps     173.7mV    243.4mV    128.9mV
663ps     124.6mV    255.5mV    101.7mV
843ps     80.36mV    139.5mV    71.53mV
973ps     61.21mV    94.88mV    57.71mV
1.633ns   21.35mV    25.98mV    24.67mV
3.31ns    4.941mV    5.263mV    4.967mV
10ns      467.9uV    222uV      303.3uV
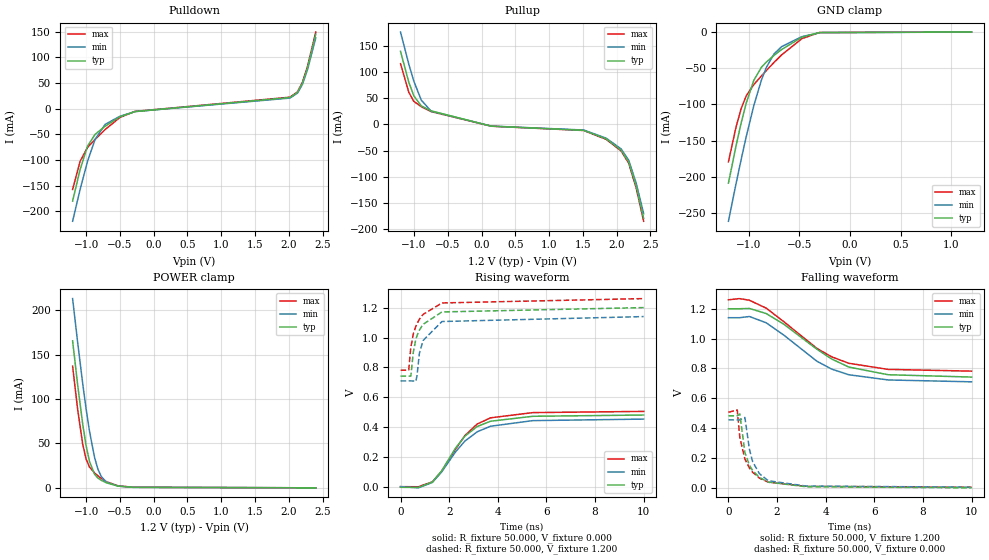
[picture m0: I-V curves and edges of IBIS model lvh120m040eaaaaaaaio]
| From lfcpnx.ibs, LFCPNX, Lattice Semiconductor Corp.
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[Model] lvh120m040eaaaaaaaio
Model_type I/O
Polarity   Non-Inverting
Enable   Active-Low
Vinl =  0.420V
Vinh =  0.780V
Vmeas =  0.600V
Cref =  0.0F
Rref =  1.000M
Vref =  0.0V
C_comp   5.000pF   4.000pF   5.500pF
[Temperature Range]   25.000   0.125k   -40.000
[Voltage Range]   1.200V   1.140V   1.260V
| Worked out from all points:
|   slope of the pulldown table from 0 to 0.18 V, typ, clamps not added: 51.8 ohm
|   slope of the pullup table from 0 to 0.18 V, typ, clamps not added: 44.8 ohm
|   GND clamp passes 1 mA (typ) near -0.32 V on its own axis
|   POWER clamp passes 1 mA (typ) near -0.45 V on its own axis
|   rising waveform, R_fixture 50.000, V_fixture 0.000: 20-80 % time 1.33ns typ, 1.44ns min, 1.34ns max; typ from 0 V to 0.483 V
|   rising waveform, R_fixture 50.000, V_fixture 1.200: 20-80 % time 551ps typ, 510ps min, 599ps max; typ from 0.742 V to 1.2 V
|   falling waveform, R_fixture 50.000, V_fixture 1.200: 20-80 % time 2.42ns typ, 2.2ns min, 2.36ns max; typ from 1.2 V to 0.742 V
|   falling waveform, R_fixture 50.000, V_fixture 0.000: 20-80 % time 543ps typ, 498ps min, 567ps max; typ from 0.483 V to 0 V
[GND_clamp]
|Voltage   I(typ)   I(min)   I(max)
-1.2V     -208.9mA   -261.7mA   -179.3mA
-1.125V   -157.4mA   -209.8mA   -131.5mA
-1.075V   -126mA     -176.6mA   -106.1mA
-1.025V   -98.42mA   -145mA     -88.28mA
-950mV    -66.96mA   -101.9mA   -72.76mA
-875mV    -48.78mA   -66.64mA   -60.78mA
-825mV    -41.38mA   -48.67mA   -53.1mA
-750mV    -32.3mA    -30.34mA   -41.99mA
-675mV    -24.14mA   -20.11mA   -31.53mA
-475mV    -7.155mA   -6.375mA   -9.116mA
-300mV    -673.7uA   -900.4uA   -619.4uA
1.2V      0A         0A         0A
[POWER_clamp]
|Voltage   I(typ)   I(min)   I(max)
-1.2V     165.7mA    213.3mA    137.1mA
-1.125V   115.8mA    163.7mA    88.19mA
-1.05V    71.42mA    117.1mA    48.87mA
-1V       47.37mA    88.79mA    32.13mA
-950mV    29.54mA    63.68mA    23.24mA
-875mV    15.17mA    34.1mA     16.62mA
-825mV    10.91mA    20.81mA    13.34mA
-775mV    8.283mA    12.48mA    10.42mA
-700mV    5.463mA    6.247mA    6.777mA
-525mV    1.711mA    1.811mA    1.978mA
-300mV    395.7uA    364.9uA    500.6uA
2.4V      -178.9uA   -186.1uA   -181.3uA
[Pulldown]
|Voltage   I(typ)   I(min)   I(max)
-1.2V     -180.2mA   -219.5mA   -157.6mA
-1.089V   -118.7mA   -157.5mA   -102.6mA
-978mV    -72.85mA   -102.3mA   -75.46mA
-867mV    -50.28mA   -60.01mA   -59.99mA
-719mV    -34.47mA   -30.88mA   -40.86mA
-497mV    -15.93mA   -14.83mA   -17.14mA
-275mV    -5.882mA   -5.85mA    -5.411mA
2.019V    21.52mA    20.44mA    22.16mA
2.13V     31.72mA    30.13mA    32.67mA
2.204V    49.93mA    47.44mA    51.43mA
2.278V    79.85mA    75.86mA    82.25mA
2.4V      144.7mA    137.5mA    149mA
[Pullup]
|Voltage   I(typ)   I(min)   I(max)
-1.2V     139.7mA    176.6mA    116.1mA
-1.078V   80.9mA     115.4mA    61.64mA
-1.004V   54.85mA    83mA       44.23mA
-893mV    35.47mA    46.56mA    33.97mA
-745mV    25.91mA    25.06mA    24.48mA
143mV     -3.287mA   -3.123mA   -3.386mA
1.512V    -11.26mA   -10.7mA    -11.6mA
1.845V    -27.67mA   -26.29mA   -28.5mA
2.067V    -49.35mA   -46.88mA   -50.83mA
2.178V    -71.98mA   -68.38mA   -74.14mA
2.289V    -118mA     -112.1mA   -121.5mA
2.4V      -179.7mA   -170.7mA   -185.1mA
[Ramp]
| variable   typ   min   max
dV/dt_r   0.289/1.340n   0.271/1.463n   0.300/1.363n
dV/dt_f   0.275/2.515n   0.258/2.303n   0.287/2.448n
R_load = 50.000
[Rising Waveform]
R_fixture = 50.000
V_fixture = 0.000
V_fixture_min = 0.000
V_fixture_max = 0.000
|  time   V(typ)   V(min)   V(max)
0s        32.99uV    4.519mV    4.157mV
735ps     -1.145mV   -3.682mV   3.468mV
1.308ns   35.06mV    32.04mV    36.29mV
1.688ns   109mV      101.6mV    106.1mV
2.268ns   262.7mV    237.6mV    256.2mV
2.65ns    341.9mV    308.9mV    345.8mV
3.15ns    405.4mV    370.3mV    421.9mV
3.7ns     441.1mV    407.7mV    463.7mV
5.44ns    474.1mV    445.2mV    498.7mV
10ns      482.6mV    455.4mV    506.8mV
[Rising Waveform]
R_fixture = 50.000
V_fixture = 1.200
V_fixture_min = 1.140
V_fixture_max = 1.260
|  time   V(typ)   V(min)   V(max)
0s        742.2mV    710.4mV    782mV
336ps     742.5mV    710.5mV    782.1mV
423ps     742.4mV    710.6mV    934.5mV
528ps     904.6mV    709.7mV    1.025V
625ps     984.8mV    706.6mV    1.073V
675ps     1.011V     740.7mV    1.092V
775ps     1.049V     893.1mV    1.122V
925ps     1.088V     979.5mV    1.154V
1.704ns   1.171V     1.107V     1.231V
10ns      1.2V       1.14V      1.26V
[Falling Waveform]
R_fixture = 50.000
V_fixture = 1.200
V_fixture_min = 1.140
V_fixture_max = 1.260
|  time   V(typ)   V(min)   V(max)
0s        1.2V       1.14V      1.26V
450ps     1.2V       1.14V      1.268V
863ps     1.202V     1.148V     1.257V
1.553ns   1.168V     1.106V     1.204V
2.28ns    1.096V     1.023V     1.113V
3.635ns   929.3mV    848.7mV    934.6mV
4.244ns   863.5mV    795.7mV    878mV
4.948ns   809.4mV    757.8mV    834.8mV
6.57ns    757.9mV    722.9mV    793.6mV
10ns      742.2mV    710.4mV    782mV
[Falling Waveform]
R_fixture = 50.000
V_fixture = 0.000
V_fixture_min = 0.000
V_fixture_max = 0.000
|  time   V(typ)   V(min)   V(max)
0s        482.6mV    455.4mV    506.8mV
362ps     482.8mV    455.1mV    521.5mV
468ps     495.1mV    455.2mV    337.8mV
677ps     236.2mV    471.6mV    193.1mV
863ps     151mV      258.2mV    133.2mV
993ps     116.4mV    176.6mV    104.7mV
1.269ns   69.99mV    95.57mV    65.27mV
1.643ns   38.22mV    47.32mV    37.65mV
3.193ns   7.396mV    11.99mV    10.03mV
10ns      32.99uV    4.519mV    4.157mV
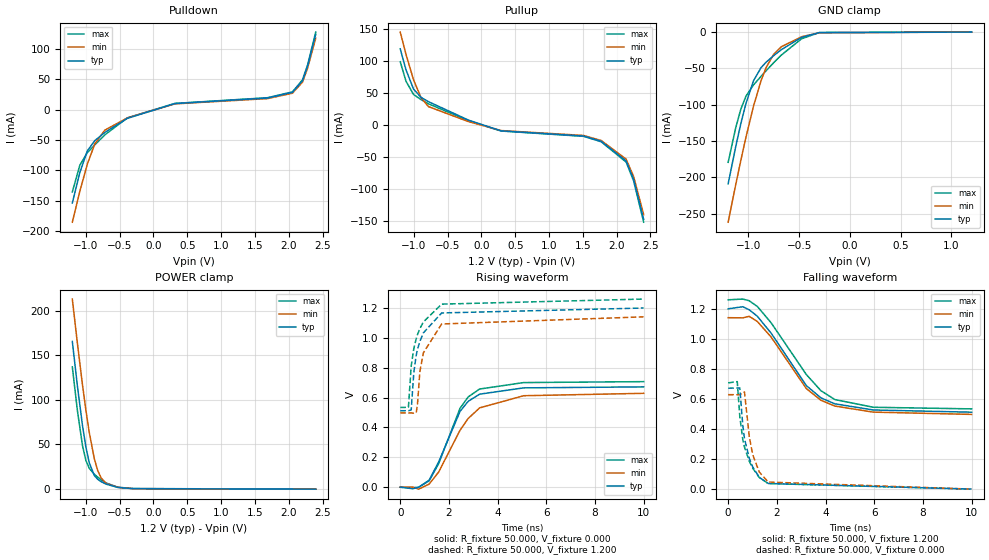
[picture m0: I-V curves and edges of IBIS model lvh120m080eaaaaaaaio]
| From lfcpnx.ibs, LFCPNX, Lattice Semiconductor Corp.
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[Model] lvh120m080eaaaaaaaio
Model_type I/O
Polarity   Non-Inverting
Enable   Active-Low
Vinl =  0.420V
Vinh =  0.780V
Vmeas =  0.600V
Cref =  0.0F
Rref =  1.000M
Vref =  0.0V
C_comp   5.000pF   4.000pF   5.500pF
[Temperature Range]   25.000   0.125k   -40.000
[Voltage Range]   1.200V   1.140V   1.260V
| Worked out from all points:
|   slope of the pulldown table from 0 to 0.18 V, typ, clamps not added: 30.5 ohm
|   slope of the pullup table from 0 to 0.18 V, typ, clamps not added: 28.8 ohm
|   GND clamp passes 1 mA (typ) near -0.32 V on its own axis
|   POWER clamp passes 1 mA (typ) near -0.45 V on its own axis
|   rising waveform, R_fixture 50.000, V_fixture 0.000: 20-80 % time 1.1ns typ, 1.38ns min, 1.06ns max; typ from 0 V to 0.672 V
|   rising waveform, R_fixture 50.000, V_fixture 1.200: 20-80 % time 536ps typ, 505ps min, 594ps max; typ from 0.512 V to 1.2 V
|   falling waveform, R_fixture 50.000, V_fixture 1.200: 20-80 % time 1.8ns typ, 1.73ns min, 1.92ns max; typ from 1.2 V to 0.512 V
|   falling waveform, R_fixture 50.000, V_fixture 0.000: 20-80 % time 502ps typ, 464ps min, 560ps max; typ from 0.672 V to 0 V
[GND_clamp]
|Voltage   I(typ)   I(min)   I(max)
-1.2V     -208.9mA   -261.7mA   -179.3mA
-1.125V   -157.4mA   -209.8mA   -131.5mA
-1.075V   -126mA     -176.6mA   -106.1mA
-1.025V   -98.42mA   -145mA     -88.28mA
-950mV    -66.96mA   -101.9mA   -72.76mA
-875mV    -48.78mA   -66.64mA   -60.78mA
-825mV    -41.38mA   -48.67mA   -53.1mA
-750mV    -32.3mA    -30.34mA   -41.99mA
-675mV    -24.14mA   -20.11mA   -31.53mA
-475mV    -7.155mA   -6.375mA   -9.116mA
-300mV    -673.7uA   -900.4uA   -619.4uA
1.2V      0A         0A         0A
[POWER_clamp]
|Voltage   I(typ)   I(min)   I(max)
-1.2V     165.7mA    213.3mA    137.1mA
-1.125V   115.8mA    163.7mA    88.19mA
-1.05V    71.42mA    117.1mA    48.87mA
-1V       47.37mA    88.79mA    32.13mA
-950mV    29.54mA    63.68mA    23.24mA
-875mV    15.17mA    34.1mA     16.62mA
-825mV    10.91mA    20.81mA    13.34mA
-775mV    8.283mA    12.48mA    10.42mA
-700mV    5.463mA    6.247mA    6.777mA
-525mV    1.711mA    1.811mA    1.978mA
-300mV    395.7uA    364.9uA    500.6uA
2.4V      -178.9uA   -186.1uA   -181.3uA
[Pulldown]
|Voltage   I(typ)   I(min)   I(max)
-1.2V     -153.9mA   -185.6mA   -135.8mA
-1.089V   -103.8mA   -134.7mA   -91.7mA
-978mV    -68.12mA   -90mA      -71.13mA
-867mV    -51.18mA   -56.52mA   -58.14mA
-719mV    -37.72mA   -33.97mA   -41.78mA
-386mV    -14.55mA   -13.79mA   -13.75mA
317mV     9.765mA    9.277mA    10.06mA
1.686V    18.86mA    17.91mA    19.42mA
2.056V    28.26mA    26.84mA    29.1mA
2.204V    47.45mA    45.08mA    48.87mA
2.278V    70.9mA     67.4mA     73mA
2.4V      123.8mA    117.6mA    127.5mA
[Pullup]
|Voltage   I(typ)   I(min)   I(max)
-1.2V     119.2mA    145.5mA    99mA
-1.115V   86.4mA     110.6mA    68.6mA
-1.004V   56.25mA    70.9mA     47.76mA
-893mV    43.25mA    42.77mA    39.77mA
-782mV    36.41mA    28.69mA    33.08mA
-190mV    7.514mA    5.174mA    6.587mA
291mV     -9.256mA   -8.793mA   -9.534mA
1.512V    -17.36mA   -16.49mA   -17.88mA
1.771V    -25.59mA   -24.31mA   -26.36mA
2.141V    -56.48mA   -53.66mA   -58.17mA
2.252V    -85.3mA    -81mA      -87.9mA
2.4V      -148mA     -140.6mA   -152.4mA
[Ramp]
| variable   typ   min   max
dV/dt_r   0.404/1.117n   0.383/1.394n   0.426/1.083n
dV/dt_f   0.410/1.839n   0.383/1.780n   0.433/1.960n
R_load = 50.000
[Rising Waveform]
R_fixture = 50.000
V_fixture = 0.000
V_fixture_min = 0.000
V_fixture_max = 0.000
|  time   V(typ)   V(min)   V(max)
0s        38.48uV    -137.9uV   -486uV
517ps     -10.63mV   221.7uV    -4.084mV
757ps     -761.6uV   -13.48mV   -262.2uV
1.187ns   46.68mV    20.5mV     42.23mV
1.576ns   168.1mV    100.6mV    156.9mV
2.457ns   507.7mV    381.4mV    528.4mV
2.791ns   574.9mV    460mV      604.4mV
3.26ns    622.9mV    531mV      657.3mV
5.07ns    665.1mV    612.5mV    700.5mV
10ns      671.8mV    628.6mV    706.9mV
[Rising Waveform]
R_fixture = 50.000
V_fixture = 1.200
V_fixture_min = 1.140
V_fixture_max = 1.260
|  time   V(typ)   V(min)   V(max)
0s        511.9mV    497.2mV    534mV
336ps     512.2mV    497.3mV    534.7mV
450ps     517.5mV    497.4mV    811.2mV
557ps     767.1mV    495.5mV    928mV
656ps     883.5mV    499.7mV    994.5mV
707ps     921.4mV    552.2mV    1.021V
807ps     977.1mV    775mV      1.062V
952ps     1.034V     900.1mV    1.107V
1.701ns   1.167V     1.093V     1.226V
10ns      1.2V       1.141V     1.26V
[Falling Waveform]
R_fixture = 50.000
V_fixture = 1.200
V_fixture_min = 1.140
V_fixture_max = 1.260
|  time   V(typ)   V(min)   V(max)
0s        1.2V       1.141V     1.26V
601ps     1.214V     1.14V      1.265V
861ps     1.194V     1.15V      1.254V
1.197ns   1.151V     1.116V     1.216V
1.761ns   1.039V     1.013V     1.108V
3.211ns   689.1mV    669.3mV    762.7mV
3.811ns   607.3mV    591.3mV    655mV
4.381ns   567.7mV    552.7mV    596.2mV
5.965ns   526.6mV    512.3mV    544.7mV
10ns      511.9mV    497.2mV    534mV
[Falling Waveform]
R_fixture = 50.000
V_fixture = 0.000
V_fixture_min = 0.000
V_fixture_max = 0.000
|  time   V(typ)   V(min)   V(max)
0s        671.8mV    628.6mV    706.9mV
374ps     672.7mV    628.2mV    715.5mV
478ps     673.1mV    628.1mV    483.3mV
598ps     430mV      638.8mV    333mV
670ps     335.8mV    647.1mV    279.9mV
871ps     203mV      345.5mV    184.1mV
1.011ns   147.1mV    228mV      138.8mV
1.277ns   78.23mV    114mV      77.63mV
1.647ns   37.42mV    46.79mV    36.86mV
10ns      38.48uV    -137.9uV   -486uV
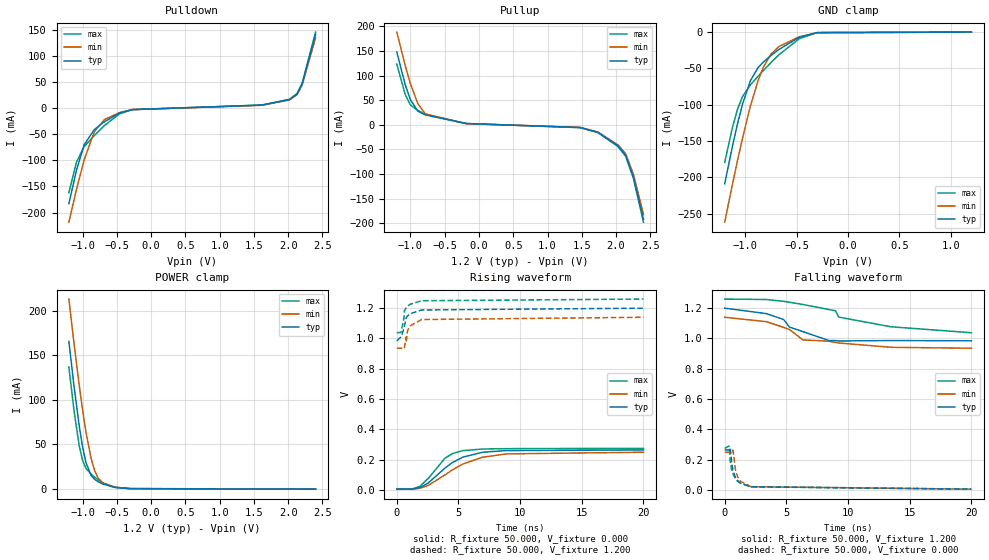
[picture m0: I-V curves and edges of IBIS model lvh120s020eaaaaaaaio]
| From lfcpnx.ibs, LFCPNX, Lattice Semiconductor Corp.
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[Model] lvh120s020eaaaaaaaio
Model_type I/O
Polarity   Non-Inverting
Enable   Active-Low
Vinl =  0.420V
Vinh =  0.780V
Vmeas =  0.600V
Cref =  0.0F
Rref =  1.000M
Vref =  0.0V
C_comp   5.000pF   4.000pF   5.500pF
[Temperature Range]   25.000   0.125k   -40.000
[Voltage Range]   1.200V   1.140V   1.260V
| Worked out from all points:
|   slope of the pulldown table from 0 to 0.18 V, typ, clamps not added: 113 ohm
|   slope of the pullup table from 0 to 0.18 V, typ, clamps not added: 87.1 ohm
|   GND clamp passes 1 mA (typ) near -0.32 V on its own axis
|   POWER clamp passes 1 mA (typ) near -0.45 V on its own axis
|   rising waveform, R_fixture 50.000, V_fixture 0.000: 20-80 % time 2.51ns typ, 3.16ns min, 1.7ns max; typ from 0.006 V to 0.265 V
|   rising waveform, R_fixture 50.000, V_fixture 1.200: 20-80 % time 477ps typ, 547ps min, 497ps max; typ from 0.985 V to 1.2 V
|   falling waveform, R_fixture 50.000, V_fixture 1.200: 20-80 % time 3.4ns typ, 4.96ns min, 6.19ns max; typ from 1.2 V to 0.985 V
|   falling waveform, R_fixture 50.000, V_fixture 0.000: 20-80 % time 571ps typ, 549ps min, 610ps max; typ from 0.265 V to 0.006 V
[GND_clamp]
|Voltage   I(typ)   I(min)   I(max)
-1.2V     -208.9mA   -261.7mA   -179.3mA
-1.125V   -157.4mA   -209.8mA   -131.5mA
-1.075V   -126mA     -176.6mA   -106.1mA
-1.025V   -98.42mA   -145mA     -88.28mA
-950mV    -66.96mA   -101.9mA   -72.76mA
-875mV    -48.78mA   -66.64mA   -60.78mA
-825mV    -41.38mA   -48.67mA   -53.1mA
-750mV    -32.3mA    -30.34mA   -41.99mA
-675mV    -24.14mA   -20.11mA   -31.53mA
-475mV    -7.155mA   -6.375mA   -9.116mA
-300mV    -673.7uA   -900.4uA   -619.4uA
1.2V      0A         0A         0A
[POWER_clamp]
|Voltage   I(typ)   I(min)   I(max)
-1.2V     165.7mA    213.3mA    137.1mA
-1.125V   115.8mA    163.7mA    88.19mA
-1.05V    71.42mA    117.1mA    48.87mA
-1V       47.37mA    88.79mA    32.13mA
-950mV    29.54mA    63.68mA    23.24mA
-875mV    15.17mA    34.1mA     16.62mA
-825mV    10.91mA    20.81mA    13.34mA
-775mV    8.283mA    12.48mA    10.42mA
-700mV    5.463mA    6.247mA    6.777mA
-525mV    1.711mA    1.811mA    1.978mA
-300mV    395.7uA    364.9uA    500.6uA
2.4V      -178.9uA   -186.1uA   -181.3uA
[Pulldown]
|Voltage   I(typ)   I(min)   I(max)
-1.2V     -182.9mA   -218.3mA   -161.8mA
-1.089V   -119mA     -155.7mA   -103.5mA
-978mV    -70.5mA    -99.7mA    -73.97mA
-830mV    -41.39mA   -45.59mA   -52.8mA
-682mV    -26.31mA   -22.05mA   -33.57mA
-460mV    -9.387mA   -8.653mA   -11.09mA
-275mV    -2.976mA   -3.061mA   -3.072mA
1.612V    5.539mA    5.262mA    5.705mA
2.019V    16.14mA    15.34mA    16.63mA
2.13V     26.95mA    25.6mA     27.76mA
2.204V    45.98mA    43.68mA    47.36mA
2.4V      141mA      133.9mA    145.2mA
[Pullup]
|Voltage   I(typ)   I(min)   I(max)
-1.2V     147.9mA    188.3mA    123.4mA
-1.078V   81.98mA    120.7mA    61.86mA
-1.004V   51.59mA    84.61mA    40.82mA
-893mV    27.85mA    43mA       29.06mA
-782mV    19.86mA    21.61mA    21.61mA
-190mV    2.572mA    2.372mA    2.456mA
1.475V    -5.673mA   -5.39mA    -5.843mA
1.734V    -15.38mA   -14.62mA   -15.85mA
2.03V     -43.2mA    -41.04mA   -44.5mA
2.141V    -62.44mA   -59.32mA   -64.31mA
2.252V    -105.4mA   -100.1mA   -108.6mA
2.4V      -192.2mA   -182.6mA   -198mA
[Ramp]
| variable   typ   min   max
dV/dt_r   0.155/2.498n   0.150/3.174n   0.167/1.768n
dV/dt_f   0.129/4.209n   0.123/4.974n   0.133/7.255n
R_load = 50.000
[Rising Waveform]
R_fixture = 50.000
V_fixture = 0.000
V_fixture_min = 0.000
V_fixture_max = 0.000
|  time   V(typ)   V(min)   V(max)
0s        6.178mV    6.226mV    6.334mV
1.275ns   6.925mV    6.487mV    7.936mV
1.87ns    16.24mV    12.07mV    24.55mV
2.578ns   48.63mV    32.18mV    79.38mV
3.911ns   145.9mV    100.7mV    210.9mV
4.49ns    180.8mV    132.4mV    240.2mV
5.33ns    216.9mV    171.3mV    260mV
6.945ns   249.7mV    216.9mV    270.8mV
8.925ns   260.9mV    238.9mV    273.5mV
20ns      265mV      249.9mV    275.1mV
[Rising Waveform]
R_fixture = 50.000
V_fixture = 1.200
V_fixture_min = 1.140
V_fixture_max = 1.260
|  time   V(typ)   V(min)   V(max)
0s        984.7mV    935.7mV    1.038V
345ps     1.01V      935.8mV    1.04V
595ps     1.069V     932.2mV    1.141V
605ps     1.072V     931.8mV    1.18V
755ps     1.135V     1.009V     1.202V
765ps     1.136V     978mV      1.203V
866ps     1.148V     1.05V      1.212V
1.064ns   1.163V     1.082V     1.225V
2.015ns   1.188V     1.125V     1.249V
20ns      1.2V       1.14V      1.26V
[Falling Waveform]
R_fixture = 50.000
V_fixture = 1.200
V_fixture_min = 1.140
V_fixture_max = 1.260
|  time   V(typ)   V(min)   V(max)
0s        1.2V       1.14V      1.26V
3.379ns   1.164V     1.111V     1.257V
4.781ns   1.125V     1.073V     1.245V
5.25ns    1.075V     1.059V     1.239V
6.351ns   1.045V     990.4mV    1.224V
8.448ns   986.3mV    982mV      1.191V
8.98ns    986.3mV    973.8mV    1.183V
9.239ns   983.8mV    970.3mV    1.141V
13.5ns    986.2mV    941.7mV    1.077V
20ns      984.7mV    935.7mV    1.038V
[Falling Waveform]
R_fixture = 50.000
V_fixture = 0.000
V_fixture_min = 0.000
V_fixture_max = 0.000
|  time   V(typ)   V(min)   V(max)
0s        265mV      249.9mV    275.1mV
356ps     264.6mV    249.7mV    290.6mV
454ps     280.4mV    249.9mV    189.2mV
562ps     184mV      251.6mV    137.3mV
673ps     129.4mV    263.4mV    107.1mV
874ps     83.4mV     134mV      74.93mV
1.043ns   62.8mV     88.47mV    58.89mV
1.273ns   46.02mV    58.43mV    44.96mV
2.123ns   21.54mV    22.68mV    22.66mV
20ns      6.178mV    6.226mV    6.334mV
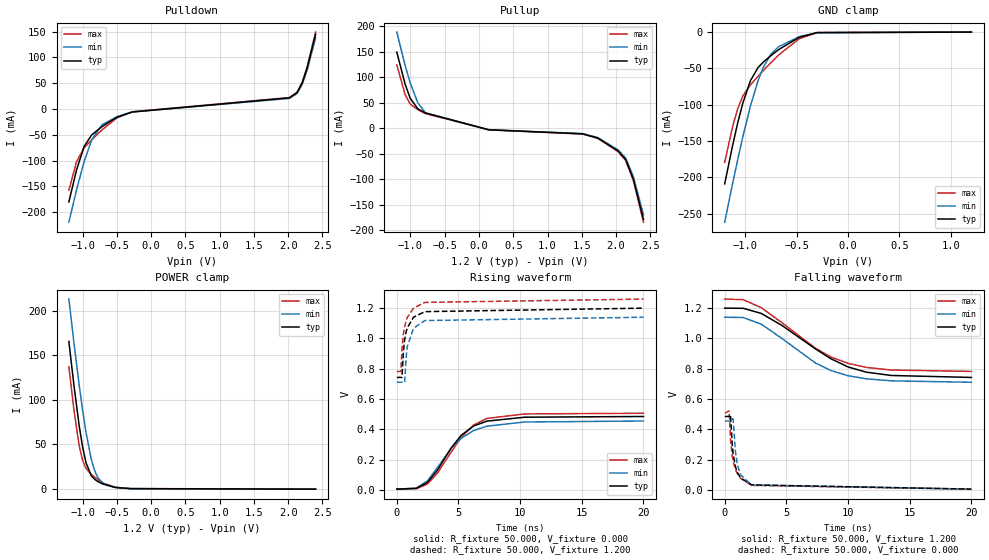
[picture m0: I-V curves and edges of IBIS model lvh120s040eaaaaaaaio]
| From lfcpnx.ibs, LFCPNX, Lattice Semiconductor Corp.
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[Model] lvh120s040eaaaaaaaio
Model_type I/O
Polarity   Non-Inverting
Enable   Active-Low
Vinl =  0.420V
Vinh =  0.780V
Vmeas =  0.600V
Cref =  0.0F
Rref =  1.000M
Vref =  0.0V
C_comp   5.000pF   4.000pF   5.500pF
[Temperature Range]   25.000   0.125k   -40.000
[Voltage Range]   1.200V   1.140V   1.260V
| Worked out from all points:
|   slope of the pulldown table from 0 to 0.18 V, typ, clamps not added: 51.8 ohm
|   slope of the pullup table from 0 to 0.18 V, typ, clamps not added: 44.9 ohm
|   GND clamp passes 1 mA (typ) near -0.32 V on its own axis
|   POWER clamp passes 1 mA (typ) near -0.45 V on its own axis
|   rising waveform, R_fixture 50.000, V_fixture 0.000: 20-80 % time 2.56ns typ, 2.79ns min, 2.63ns max; typ from 0.004 V to 0.484 V
|   rising waveform, R_fixture 50.000, V_fixture 1.200: 20-80 % time 569ps typ, 545ps min, 614ps max; typ from 0.742 V to 1.2 V
|   falling waveform, R_fixture 50.000, V_fixture 1.200: 20-80 % time 5.14ns typ, 4.6ns min, 4.94ns max; typ from 1.2 V to 0.742 V
|   falling waveform, R_fixture 50.000, V_fixture 0.000: 20-80 % time 563ps typ, 547ps min, 607ps max; typ from 0.484 V to 0.004 V
[GND_clamp]
|Voltage   I(typ)   I(min)   I(max)
-1.2V     -208.9mA   -261.7mA   -179.3mA
-1.125V   -157.4mA   -209.8mA   -131.5mA
-1.075V   -126mA     -176.6mA   -106.1mA
-1.025V   -98.42mA   -145mA     -88.28mA
-950mV    -66.96mA   -101.9mA   -72.76mA
-875mV    -48.78mA   -66.64mA   -60.78mA
-825mV    -41.38mA   -48.67mA   -53.1mA
-750mV    -32.3mA    -30.34mA   -41.99mA
-675mV    -24.14mA   -20.11mA   -31.53mA
-475mV    -7.155mA   -6.375mA   -9.116mA
-300mV    -673.7uA   -900.4uA   -619.4uA
1.2V      0A         0A         0A
[POWER_clamp]
|Voltage   I(typ)   I(min)   I(max)
-1.2V     165.7mA    213.3mA    137.1mA
-1.125V   115.8mA    163.7mA    88.19mA
-1.05V    71.42mA    117.1mA    48.87mA
-1V       47.37mA    88.79mA    32.13mA
-950mV    29.54mA    63.68mA    23.24mA
-875mV    15.17mA    34.1mA     16.62mA
-825mV    10.91mA    20.81mA    13.34mA
-775mV    8.283mA    12.48mA    10.42mA
-700mV    5.463mA    6.247mA    6.777mA
-525mV    1.711mA    1.811mA    1.978mA
-300mV    395.7uA    364.9uA    500.6uA
2.4V      -178.9uA   -186.1uA   -181.3uA
[Pulldown]
|Voltage   I(typ)   I(min)   I(max)
-1.2V     -180.2mA   -219.5mA   -157.6mA
-1.089V   -118.7mA   -157.5mA   -102.6mA
-978mV    -72.85mA   -102.3mA   -75.46mA
-867mV    -50.28mA   -60.01mA   -59.99mA
-719mV    -34.47mA   -30.88mA   -40.86mA
-497mV    -15.93mA   -14.83mA   -17.14mA
-275mV    -5.882mA   -5.85mA    -5.411mA
2.019V    21.52mA    20.44mA    22.16mA
2.13V     31.72mA    30.13mA    32.67mA
2.204V    49.93mA    47.44mA    51.43mA
2.278V    79.85mA    75.86mA    82.25mA
2.4V      144.7mA    137.5mA    149mA
[Pullup]
|Voltage   I(typ)   I(min)   I(max)
-1.2V     149.1mA    188.4mA    123.9mA
-1.078V   86.3mA     123.1mA    65.77mA
-1.004V   58.53mA    88.6mA     47.2mA
-893mV    37.85mA    49.68mA    36.25mA
-782mV    29.77mA    30.11mA    28.48mA
143mV     -3.278mA   -3.114mA   -3.376mA
1.512V    -11.23mA   -10.67mA   -11.56mA
1.734V    -19.5mA    -18.53mA   -20.09mA
2.03V     -44.92mA   -42.68mA   -46.27mA
2.141V    -61.82mA   -58.73mA   -63.67mA
2.252V    -100mA     -95mA      -103mA
2.4V      -179.1mA   -170.1mA   -184.5mA
[Ramp]
| variable   typ   min   max
dV/dt_r   0.288/2.573n   0.270/2.778n   0.301/2.658n
dV/dt_f   0.275/5.201n   0.258/4.617n   0.287/4.965n
R_load = 50.000
[Rising Waveform]
R_fixture = 50.000
V_fixture = 0.000
V_fixture_min = 0.000
V_fixture_max = 0.000
|  time   V(typ)   V(min)   V(max)
0s        4.45mV     4.519mV    4.157mV
1.585ns   9.495mV    11.23mV    6.903mV
2.478ns   48.39mV    59.11mV    37.88mV
3.275ns   127.2mV    144.2mV    107.7mV
4.391ns   274.2mV    271.9mV    246.9mV
5.23ns    360.8mV    340.9mV    347.3mV
6.234ns   421.6mV    391.3mV    428.5mV
7.305ns   453.6mV    420.4mV    471.4mV
10.37ns   479.5mV    447.9mV    501.2mV
20ns      484.3mV    454.4mV    505.6mV
[Rising Waveform]
R_fixture = 50.000
V_fixture = 1.200
V_fixture_min = 1.140
V_fixture_max = 1.260
|  time   V(typ)   V(min)   V(max)
0s        742.2mV    710.4mV    782mV
333ps     742.6mV    710.6mV    780.7mV
423ps     742.2mV    710.6mV    934.2mV
534ps     911.6mV    709.4mV    1.029V
635ps     990.5mV    708.9mV    1.077V
765ps     1.045V     882.7mV    1.119V
847ps     1.069V     944.1mV    1.138V
1.354ns   1.14V      1.067V     1.2V
2.273ns   1.177V     1.118V     1.238V
20ns      1.2V       1.14V      1.26V
[Falling Waveform]
R_fixture = 50.000
V_fixture = 1.200
V_fixture_min = 1.140
V_fixture_max = 1.260
|  time   V(typ)   V(min)   V(max)
0s        1.2V       1.14V      1.26V
1.506ns   1.199V     1.138V     1.256V
2.969ns   1.165V     1.094V     1.203V
4.673ns   1.084V     997.8mV    1.102V
7.353ns   931.1mV    837.8mV    935.2mV
8.594ns   866.5mV    788.2mV    878mV
10.01ns   811.2mV    753.2mV    835.1mV
11.47ns   777.3mV    733.2mV    808.7mV
13.5ns    755.2mV    719.7mV    791.2mV
20ns      742.2mV    710.4mV    782mV
[Falling Waveform]
R_fixture = 50.000
V_fixture = 0.000
V_fixture_min = 0.000
V_fixture_max = 0.000
|  time   V(typ)   V(min)   V(max)
0s        484.3mV    454.4mV    505.6mV
362ps     484.5mV    454.1mV    521.5mV
473ps     496mV      454.1mV    332mV
603ps     306.6mV    464.6mV    228.6mV
683ps     236mV      470.1mV    191mV
874ps     151.9mV    249.5mV    133.5mV
1.033ns   113.9mV    162.9mV    104.5mV
1.294ns   77.99mV    99.19mV    74.36mV
2.183ns   32.38mV    31.69mV    28.97mV
20ns      4.45mV     4.519mV    4.157mV
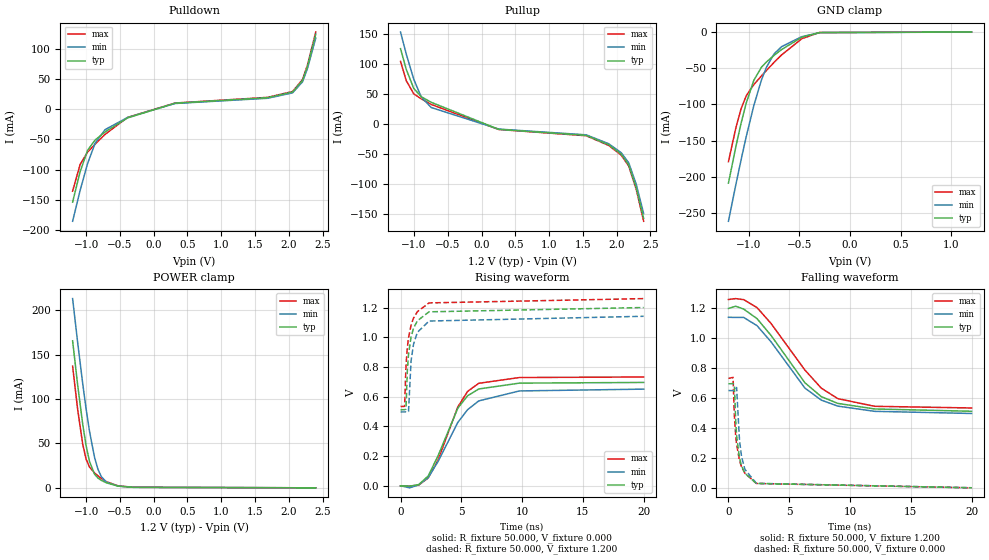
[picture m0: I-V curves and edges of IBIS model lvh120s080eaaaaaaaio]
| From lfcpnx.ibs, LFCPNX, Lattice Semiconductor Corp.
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[Model] lvh120s080eaaaaaaaio
Model_type I/O
Polarity   Non-Inverting
Enable   Active-Low
Vinl =  0.420V
Vinh =  0.780V
Vmeas =  0.600V
Cref =  0.0F
Rref =  1.000M
Vref =  0.0V
C_comp   5.000pF   4.000pF   5.500pF
[Temperature Range]   25.000   0.125k   -40.000
[Voltage Range]   1.200V   1.140V   1.260V
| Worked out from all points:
|   slope of the pulldown table from 0 to 0.18 V, typ, clamps not added: 30.5 ohm
|   slope of the pullup table from 0 to 0.18 V, typ, clamps not added: 27.2 ohm
|   GND clamp passes 1 mA (typ) near -0.32 V on its own axis
|   POWER clamp passes 1 mA (typ) near -0.45 V on its own axis
|   rising waveform, R_fixture 50.000, V_fixture 0.000: 20-80 % time 2.22ns typ, 2.74ns min, 2.13ns max; typ from 0 V to 0.696 V
|   rising waveform, R_fixture 50.000, V_fixture 1.200: 20-80 % time 569ps typ, 543ps min, 612ps max; typ from 0.512 V to 1.2 V
|   falling waveform, R_fixture 50.000, V_fixture 1.200: 20-80 % time 3.85ns typ, 3.69ns min, 4.12ns max; typ from 1.2 V to 0.512 V
|   falling waveform, R_fixture 50.000, V_fixture 0.000: 20-80 % time 561ps typ, 546ps min, 604ps max; typ from 0.696 V to 0 V
[GND_clamp]
|Voltage   I(typ)   I(min)   I(max)
-1.2V     -208.9mA   -261.7mA   -179.3mA
-1.125V   -157.4mA   -209.8mA   -131.5mA
-1.075V   -126mA     -176.6mA   -106.1mA
-1.025V   -98.42mA   -145mA     -88.28mA
-950mV    -66.96mA   -101.9mA   -72.76mA
-875mV    -48.78mA   -66.64mA   -60.78mA
-825mV    -41.38mA   -48.67mA   -53.1mA
-750mV    -32.3mA    -30.34mA   -41.99mA
-675mV    -24.14mA   -20.11mA   -31.53mA
-475mV    -7.155mA   -6.375mA   -9.116mA
-300mV    -673.7uA   -900.4uA   -619.4uA
1.2V      0A         0A         0A
[POWER_clamp]
|Voltage   I(typ)   I(min)   I(max)
-1.2V     165.7mA    213.3mA    137.1mA
-1.125V   115.8mA    163.7mA    88.19mA
-1.05V    71.42mA    117.1mA    48.87mA
-1V       47.37mA    88.79mA    32.13mA
-950mV    29.54mA    63.68mA    23.24mA
-875mV    15.17mA    34.1mA     16.62mA
-825mV    10.91mA    20.81mA    13.34mA
-775mV    8.283mA    12.48mA    10.42mA
-700mV    5.463mA    6.247mA    6.777mA
-525mV    1.711mA    1.811mA    1.978mA
-300mV    395.7uA    364.9uA    500.6uA
2.4V      -178.9uA   -186.1uA   -181.3uA
[Pulldown]
|Voltage   I(typ)   I(min)   I(max)
-1.2V     -153.9mA   -185.6mA   -135.8mA
-1.089V   -103.8mA   -134.7mA   -91.7mA
-978mV    -68.12mA   -90mA      -71.13mA
-867mV    -51.18mA   -56.52mA   -58.14mA
-719mV    -37.72mA   -33.97mA   -41.78mA
-386mV    -14.55mA   -13.79mA   -13.75mA
317mV     9.765mA    9.277mA    10.06mA
1.686V    18.86mA    17.91mA    19.42mA
2.056V    28.26mA    26.84mA    29.1mA
2.204V    47.45mA    45.08mA    48.87mA
2.278V    70.9mA     67.4mA     73mA
2.4V      123.8mA    117.6mA    127.5mA
[Pullup]
|Voltage   I(typ)   I(min)   I(max)
-1.2V     125.1mA    152.7mA    103.9mA
-1.115V   90.7mA     116.1mA    72mA
-1.004V   59.02mA    74.4mA     50.12mA
-893mV    45.38mA    44.88mA    41.74mA
-745mV    36.04mA    27.39mA    32.5mA
254mV     -8.827mA   -8.386mA   -9.092mA
1.549V    -18.85mA   -17.91mA   -19.42mA
1.882V    -34.47mA   -32.74mA   -35.5mA
2.067V    -50.02mA   -47.52mA   -51.52mA
2.178V    -67.56mA   -64.18mA   -69.59mA
2.289V    -104.9mA   -99.7mA    -108mA
2.4V      -156.7mA   -148.9mA   -161.4mA
[Ramp]
| variable   typ   min   max
dV/dt_r   0.419/2.229n   0.384/2.743n   0.441/2.141n
dV/dt_f   0.410/3.886n   0.383/3.715n   0.433/4.132n
R_load = 50.000
[Rising Waveform]
R_fixture = 50.000
V_fixture = 0.000
V_fixture_min = 0.000
V_fixture_max = 0.000
|  time   V(typ)   V(min)   V(max)
0s        38.48uV    -137.9uV   -486uV
756ps     -2.457mV   -13.65mV   -2.081mV
1.497ns   7.889mV    6.673mV    5.054mV
2.277ns   66.1mV     54.67mV    52.51mV
3.098ns   204.2mV    165.3mV    176.5mV
4.711ns   522.4mV    426.5mV    530.6mV
5.516ns   605.9mV    512.4mV    635.4mV
6.435ns   651.8mV    571.4mV    689.9mV
9.776ns   691.1mV    638.5mV    728.8mV
20ns      695.7mV    650.7mV    732.4mV
[Rising Waveform]
R_fixture = 50.000
V_fixture = 1.200
V_fixture_min = 1.140
V_fixture_max = 1.260
|  time   V(typ)   V(min)   V(max)
0s        511.9mV    497.2mV    534mV
336ps     512.2mV    497.3mV    534.6mV
449ps     516.9mV    497.5mV    809.6mV
557ps     767.3mV    495.4mV    928mV
657ps     884.7mV    500mV      995.2mV
867ps     1.002V     840.8mV    1.081V
1.069ns   1.06V      952.6mV    1.129V
1.387ns   1.111V     1.033V     1.172V
2.346ns   1.171V     1.109V     1.231V
20ns      1.2V       1.141V     1.26V
[Falling Waveform]
R_fixture = 50.000
V_fixture = 1.200
V_fixture_min = 1.140
V_fixture_max = 1.260
|  time   V(typ)   V(min)   V(max)
0s        1.2V       1.141V     1.26V
592ps     1.215V     1.14V      1.266V
1.252ns   1.196V     1.14V      1.259V
2.351ns   1.132V     1.085V     1.206V
3.509ns   1.019V     976.3mV    1.099V
6.29ns    702.7mV    667.2mV    787.8mV
7.64ns    609.7mV    586.5mV    666.5mV
8.993ns   564.7mV    546.5mV    596.6mV
12.02ns   527.4mV    511.5mV    545.2mV
20ns      511.9mV    497.2mV    534mV
[Falling Waveform]
R_fixture = 50.000
V_fixture = 0.000
V_fixture_min = 0.000
V_fixture_max = 0.000
|  time   V(typ)   V(min)   V(max)
0s        695.7mV    650.7mV    732.4mV
379ps     697.3mV    650.4mV    738.7mV
487ps     688.2mV    650mV      484.5mV
597ps     448.5mV    661.4mV    346.5mV
670ps     348.9mV    671.4mV    290.7mV
911ps     198.1mV    316.7mV    181.6mV
1.08ns    146mV      208mV      139.3mV
1.351ns   97.26mV    123.5mV    97.16mV
2.297ns   28.74mV    29.58mV    28.73mV
20ns      38.48uV    -137.9uV   -486uV
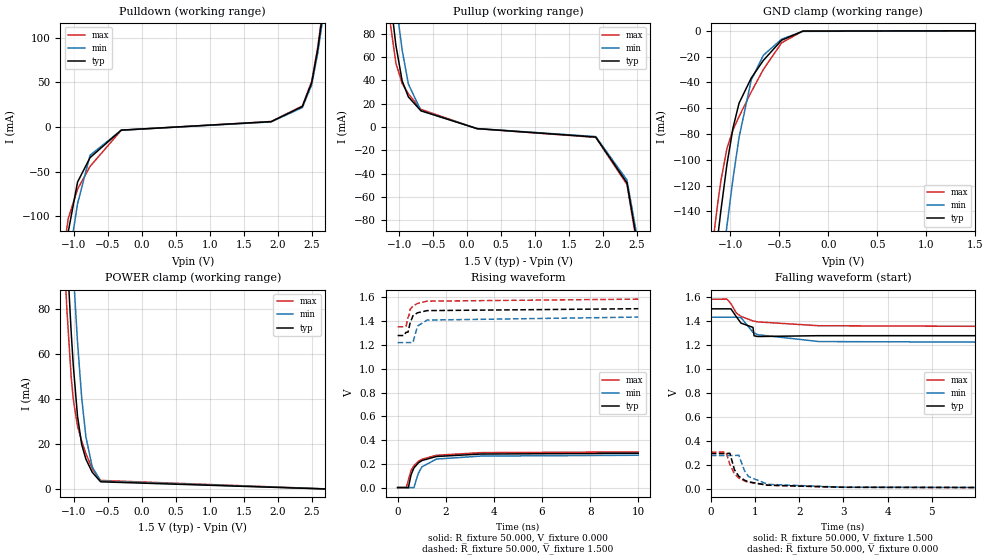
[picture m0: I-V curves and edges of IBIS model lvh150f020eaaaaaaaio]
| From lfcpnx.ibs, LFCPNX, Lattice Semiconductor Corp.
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[Model] lvh150f020eaaaaaaaio
Model_type I/O
Polarity   Non-Inverting
Enable   Active-Low
Vinl =  0.375V
Vinh =  1.125V
Vmeas =  0.750V
Cref =  0.0F
Rref =  1.000M
Vref =  0.0V
C_comp   5.000pF   4.000pF   5.500pF
[Temperature Range]   25.000   0.125k   -40.000
[Voltage Range]   1.500V   1.430V   1.580V
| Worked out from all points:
|   slope of the pulldown table from 0 to 0.225 V, typ, clamps not added: 112 ohm
|   slope of the pullup table from 0 to 0.225 V, typ, clamps not added: 106 ohm
|   GND clamp passes 1 mA (typ) near -0.32 V on its own axis
|   POWER clamp passes 1 mA (typ) near -0.45 V on its own axis
|   rising waveform, R_fixture 50.000, V_fixture 0.000: 20-80 % time 537ps typ, 524ps min, 586ps max; typ from 0.006 V to 0.293 V
|   rising waveform, R_fixture 50.000, V_fixture 1.500: 20-80 % time 266ps typ, 292ps min, 317ps max; typ from 1.28 V to 1.5 V
|   falling waveform, R_fixture 50.000, V_fixture 1.500: 20-80 % time 428ps typ, 519ps min, 533ps max; typ from 1.5 V to 1.28 V
|   falling waveform, R_fixture 50.000, V_fixture 0.000: 20-80 % time 325ps typ, 334ps min, 346ps max; typ from 0.293 V to 0.006 V
[GND_clamp]
|Voltage   I(typ)   I(min)   I(max)
-1.5V     -437mA     -482.5mA   -410.7mA
-1.159V   -180.3mA   -233.3mA   -152.2mA
-1.128V   -159.5mA   -212mA     -133.3mA
-1.097V   -139.6mA   -191.2mA   -116.5mA
-1.035V   -103.7mA   -151.3mA   -91.23mA
-973mV    -75.24mA   -114.6mA   -76.75mA
-911mV    -56.05mA   -82.58mA   -66.41mA
-787mV    -36.61mA   -38.2mA    -47.39mA
-663mV    -22.9mA    -18.92mA   -29.92mA
-477mV    -7.274mA   -6.461mA   -9.278mA
-260mV    -227.6uA   -429.8uA   -148.6uA
1.5V      0A         0A         0A
[POWER_clamp]
|Voltage   I(typ)   I(min)   I(max)
-1.5V     391.3mA    429.6mA    369.7mA
-1.166V   144.6mA    192.2mA    117.1mA
-1.135V   124.2mA    171.8mA    97.3mA
-1.104V   104.7mA    152mA      79.15mA
-1.042V   69.75mA    114.3mA    49.91mA
-1.011V   54.95mA    96.78mA    39.84mA
-949mV    32.47mA    65.46mA    28.02mA
-887mV    19.82mA    40.53mA    21.37mA
-825mV    13.31mA    23.23mA    15.79mA
-732mV    7.53mA     9.888mA    9.145mA
-608mV    3.278mA    3.592mA    3.895mA
3V        -183uA     -190.7uA   -185.3uA
[Pulldown]
|Voltage   I(typ)   I(min)   I(max)
-1.5V     -381.2mA   -398.5mA   -369.5mA
-1.224V   -198.4mA   -231.2mA   -177.7mA
-1.086V   -117.9mA   -153.6mA   -102.9mA
-948mV    -61.75mA   -86mA      -69.76mA
-764mV    -34.4mA    -31.77mA   -44.22mA
-304mV    -3.563mA   -3.619mA   -3.717mA
1.904V    5.917mA    5.621mA    6.094mA
2.364V    22.82mA    21.68mA    23.51mA
2.502V    49.56mA    47.08mA    51.05mA
2.594V    88.3mA     83.9mA     90.9mA
2.732V    165.2mA    156.9mA    170.2mA
3V        335.7mA    318.9mA    345.8mA
[Pullup]
|Voltage   I(typ)   I(min)   I(max)
-1.5V     341.5mA    374.7mA    322.6mA
-1.186V   141.4mA    182mA      117.9mA
-1.14V    115.3mA    155.9mA    92.8mA
-1.048V   69.93mA    107mA      54.61mA
-956mV    39.5mA     65.87mA    37.33mA
-864mV    25.74mA    36.76mA    28.41mA
-680mV    13.85mA    14.01mA    15.12mA
148mV     -1.462mA   -1.389mA   -1.506mA
1.896V    -8.693mA   -8.258mA   -8.954mA
2.356V    -47.92mA   -45.52mA   -49.35mA
2.586V    -126.5mA   -120.2mA   -130.3mA
3V        -409.3mA   -388.8mA   -421.6mA
[Ramp]
| variable   typ   min   max
dV/dt_r   0.172/0.547n   0.162/0.521n   0.173/0.588n
dV/dt_f   0.135/0.556n   0.128/0.590n   0.139/0.634n
R_load = 50.000
[Rising Waveform]
R_fixture = 50.000
V_fixture = 0.000
V_fixture_min = 0.000
V_fixture_max = 0.000
|  time   V(typ)   V(min)   V(max)
0s        6.269mV    6.403mV    6.427mV
361ps     6.531mV    6.49mV     5.041mV
444ps     3.728mV    6.451mV    68.57mV
558ps     112.6mV    6.606mV    148.1mV
676ps     169.6mV    5.374mV    189mV
856ps     211.5mV    123.6mV    224.4mV
1.008ns   231.7mV    178.7mV    242.5mV
1.608ns   265.6mV    244mV      275.6mV
3.442ns   286.1mV    269mV      297.8mV
10ns      292.6mV    276.2mV    303.9mV
[Rising Waveform]
R_fixture = 50.000
V_fixture = 1.500
V_fixture_min = 1.430
V_fixture_max = 1.580
|  time   V(typ)   V(min)   V(max)
0s        1.276V     1.217V     1.349V
258ps     1.276V     1.217V     1.349V
346ps     1.302V     1.217V     1.352V
434ps     1.305V     1.217V     1.427V
507ps     1.371V     1.217V     1.465V
517ps     1.378V     1.217V     1.494V
636ps     1.441V     1.217V     1.522V
827ps     1.466V     1.355V     1.544V
1.226ns   1.484V     1.405V     1.563V
10ns      1.5V       1.43V      1.58V
[Falling Waveform]
R_fixture = 50.000
V_fixture = 1.500
V_fixture_min = 1.430
V_fixture_max = 1.580
|  time   V(typ)   V(min)   V(max)
0s        1.5V       1.43V      1.58V
369ps     1.5V       1.43V      1.581V
457ps     1.5V       1.43V      1.543V
577ps     1.435V     1.43V      1.466V
684ps     1.381V     1.427V     1.437V
955ps     1.345V     1.304V     1.399V
980ps     1.275V     1.299V     1.397V
1.067ns   1.269V     1.284V     1.391V
2.446ns   1.276V     1.227V     1.359V
10ns      1.276V     1.217V     1.349V
[Falling Waveform]
R_fixture = 50.000
V_fixture = 0.000
V_fixture_min = 0.000
V_fixture_max = 0.000
|  time   V(typ)   V(min)   V(max)
0s        292.6mV    276.2mV    303.9mV
346ps     292.3mV    275.9mV    304.4mV
433ps     294.8mV    276.1mV    200.1mV
536ps     157.8mV    276.4mV    122.6mV
635ps     102.7mV    278.2mV    88.33mV
765ps     69.9mV     148.1mV    63.39mV
855ps     56.52mV    100.4mV    52.63mV
1.295ns   28.52mV    35.59mV    28.34mV
2.993ns   11.26mV    11.6mV     10.68mV
10ns      6.269mV    6.403mV    6.427mV
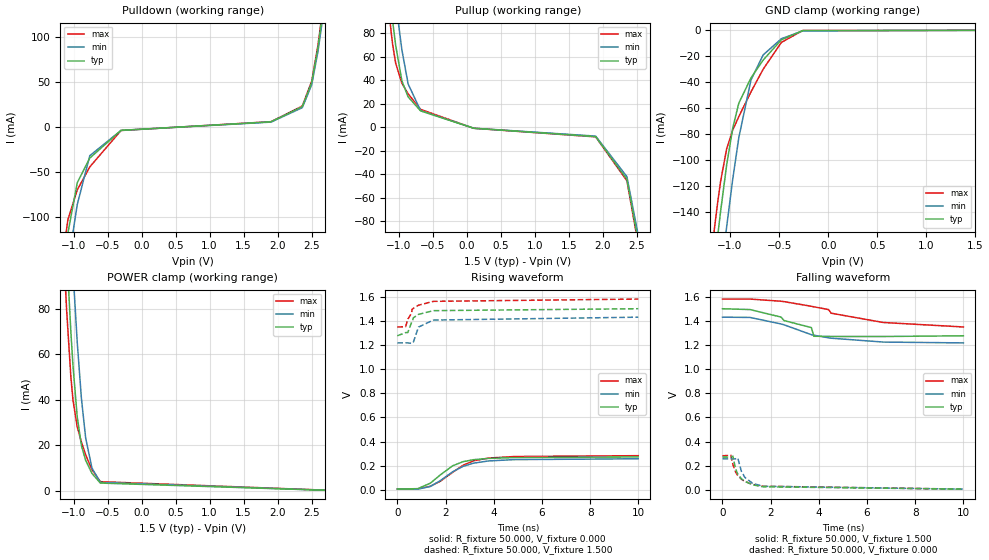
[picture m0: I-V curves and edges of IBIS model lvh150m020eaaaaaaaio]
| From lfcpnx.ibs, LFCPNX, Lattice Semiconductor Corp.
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[Model] lvh150m020eaaaaaaaio
Model_type I/O
Polarity   Non-Inverting
Enable   Active-Low
Vinl =  0.375V
Vinh =  1.125V
Vmeas =  0.750V
Cref =  0.0F
Rref =  1.000M
Vref =  0.0V
C_comp   5.000pF   4.000pF   5.500pF
[Temperature Range]   25.000   0.125k   -40.000
[Voltage Range]   1.500V   1.430V   1.580V
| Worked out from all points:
|   slope of the pulldown table from 0 to 0.225 V, typ, clamps not added: 112 ohm
|   slope of the pullup table from 0 to 0.225 V, typ, clamps not added: 114 ohm
|   GND clamp passes 1 mA (typ) near -0.32 V on its own axis
|   POWER clamp passes 1 mA (typ) near -0.45 V on its own axis
|   rising waveform, R_fixture 50.000, V_fixture 0.000: 20-80 % time 1.11ns typ, 1.27ns min, 1.27ns max; typ from 0.006 V to 0.272 V
|   rising waveform, R_fixture 50.000, V_fixture 1.500: 20-80 % time 440ps typ, 458ps min, 522ps max; typ from 1.28 V to 1.5 V
|   falling waveform, R_fixture 50.000, V_fixture 1.500: 20-80 % time 1.72ns typ, 2.2ns min, 3.05ns max; typ from 1.5 V to 1.28 V
|   falling waveform, R_fixture 50.000, V_fixture 0.000: 20-80 % time 533ps typ, 522ps min, 603ps max; typ from 0.272 V to 0.006 V
[GND_clamp]
|Voltage   I(typ)   I(min)   I(max)
-1.5V     -437mA     -482.5mA   -410.7mA
-1.159V   -180.3mA   -233.3mA   -152.2mA
-1.128V   -159.5mA   -212mA     -133.3mA
-1.097V   -139.6mA   -191.2mA   -116.5mA
-1.035V   -103.7mA   -151.3mA   -91.23mA
-973mV    -75.24mA   -114.6mA   -76.75mA
-911mV    -56.05mA   -82.58mA   -66.41mA
-787mV    -36.61mA   -38.2mA    -47.39mA
-663mV    -22.9mA    -18.92mA   -29.92mA
-477mV    -7.274mA   -6.461mA   -9.278mA
-260mV    -227.6uA   -429.8uA   -148.6uA
1.5V      0A         0A         0A
[POWER_clamp]
|Voltage   I(typ)   I(min)   I(max)
-1.5V     391.3mA    429.6mA    369.7mA
-1.166V   144.6mA    192.2mA    117.1mA
-1.135V   124.2mA    171.8mA    97.3mA
-1.104V   104.7mA    152mA      79.15mA
-1.042V   69.75mA    114.3mA    49.91mA
-1.011V   54.95mA    96.78mA    39.84mA
-949mV    32.47mA    65.46mA    28.02mA
-887mV    19.82mA    40.53mA    21.37mA
-825mV    13.31mA    23.23mA    15.79mA
-732mV    7.53mA     9.888mA    9.145mA
-608mV    3.278mA    3.592mA    3.895mA
3V        -183uA     -190.7uA   -185.3uA
[Pulldown]
|Voltage   I(typ)   I(min)   I(max)
-1.5V     -381.2mA   -398.5mA   -369.5mA
-1.224V   -198.4mA   -231.2mA   -177.7mA
-1.086V   -117.9mA   -153.6mA   -102.9mA
-948mV    -61.75mA   -86mA      -69.76mA
-764mV    -34.4mA    -31.77mA   -44.22mA
-304mV    -3.563mA   -3.619mA   -3.717mA
1.904V    5.917mA    5.621mA    6.094mA
2.364V    22.82mA    21.68mA    23.51mA
2.502V    49.56mA    47.08mA    51.05mA
2.594V    88.3mA     83.9mA     90.9mA
2.732V    165.2mA    156.9mA    170.2mA
3V        335.7mA    318.9mA    345.8mA
[Pullup]
|Voltage   I(typ)   I(min)   I(max)
-1.5V     341.5mA    374.7mA    322.6mA
-1.186V   141.4mA    182mA      117.9mA
-1.094V   91.2mA     130.7mA    71.23mA
-1.048V   69.93mA    107mA      54.61mA
-956mV    39.5mA     65.87mA    37.33mA
-864mV    25.74mA    36.76mA    28.41mA
-680mV    13.85mA    14.01mA    15.12mA
102mV     -952.9uA   -905.3uA   -981.5uA
1.896V    -8.049mA   -7.647mA   -8.291mA
2.356V    -44.37mA   -42.15mA   -45.7mA
2.586V    -117.1mA   -111.2mA   -120.6mA
3V        -379mA     -360mA     -390.4mA
[Ramp]
| variable   typ   min   max
dV/dt_r   0.160/1.150n   0.150/1.295n   0.173/1.302n
dV/dt_f   0.134/2.117n   0.128/2.528n   0.139/3.392n
R_load = 50.000
[Rising Waveform]
R_fixture = 50.000
V_fixture = 0.000
V_fixture_min = 0.000
V_fixture_max = 0.000
|  time   V(typ)   V(min)   V(max)
0s        6.269mV    6.403mV    6.427mV
848ps     9.48mV     5.281mV    7.621mV
1.367ns   54.37mV    27.52mV    28.91mV
1.777ns   122.2mV    75.04mV    69.87mV
2.297ns   199.2mV    149.5mV    144.7mV
2.729ns   233.1mV    194.2mV    203.7mV
3.16ns    249.5mV    220.6mV    239.7mV
3.781ns   260.1mV    239.1mV    263mV
4.868ns   266.9mV    250.1mV    275.7mV
10ns      272.3mV    257.1mV    282.7mV
[Rising Waveform]
R_fixture = 50.000
V_fixture = 1.500
V_fixture_min = 1.430
V_fixture_max = 1.580
|  time   V(typ)   V(min)   V(max)
0s        1.276V     1.217V     1.349V
343ps     1.302V     1.217V     1.351V
434ps     1.303V     1.217V     1.412V
596ps     1.389V     1.213V     1.465V
606ps     1.391V     1.213V     1.493V
626ps     1.396V     1.214V     1.497V
666ps     1.425V     1.224V     1.504V
877ps     1.453V     1.348V     1.529V
1.496ns   1.484V     1.406V     1.561V
10ns      1.5V       1.43V      1.58V
[Falling Waveform]
R_fixture = 50.000
V_fixture = 1.500
V_fixture_min = 1.430
V_fixture_max = 1.580
|  time   V(typ)   V(min)   V(max)
0s        1.5V       1.43V      1.58V
1.145ns   1.493V     1.428V     1.58V
2.427ns   1.431V     1.374V     1.562V
2.554ns   1.402V     1.367V     1.559V
3.691ns   1.344V     1.285V     1.52V
3.79ns    1.272V     1.281V     1.516V
4.401ns   1.272V     1.259V     1.493V
4.511ns   1.27V      1.256V     1.463V
6.674ns   1.27V      1.224V     1.386V
10ns      1.276V     1.217V     1.349V
[Falling Waveform]
R_fixture = 50.000
V_fixture = 0.000
V_fixture_min = 0.000
V_fixture_max = 0.000
|  time   V(typ)   V(min)   V(max)
0s        272.3mV    257.1mV    282.7mV
346ps     271.9mV    256.8mV    286.8mV
433ps     279.7mV    257mV      211.3mV
537ps     177.4mV    257.2mV    149.6mV
635ps     130.6mV    264.7mV    118.2mV
779ps     94.09mV    157.3mV    89.2mV
934ps     69.82mV    102.2mV    69.53mV
1.249ns   42.27mV    55.1mV     46.67mV
1.666ns   26.3mV     30.24mV    30.65mV
10ns      6.269mV    6.403mV    6.427mV
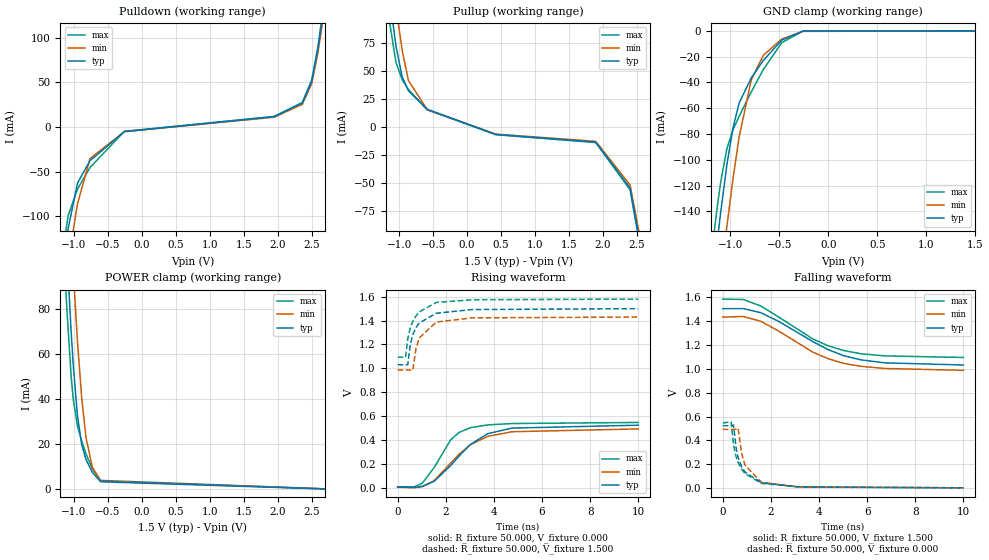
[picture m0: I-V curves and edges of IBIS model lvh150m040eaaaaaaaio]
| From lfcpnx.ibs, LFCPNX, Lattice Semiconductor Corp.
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[Model] lvh150m040eaaaaaaaio
Model_type I/O
Polarity   Non-Inverting
Enable   Active-Low
Vinl =  0.375V
Vinh =  1.125V
Vmeas =  0.750V
Cref =  0.0F
Rref =  1.000M
Vref =  0.0V
C_comp   5.000pF   4.000pF   5.500pF
[Temperature Range]   25.000   0.125k   -40.000
[Voltage Range]   1.500V   1.430V   1.580V
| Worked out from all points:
|   slope of the pulldown table from 0 to 0.225 V, typ, clamps not added: 54.3 ohm
|   slope of the pullup table from 0 to 0.225 V, typ, clamps not added: 56 ohm
|   GND clamp passes 1 mA (typ) near -0.32 V on its own axis
|   POWER clamp passes 1 mA (typ) near -0.45 V on its own axis
|   rising waveform, R_fixture 50.000, V_fixture 0.000: 20-80 % time 1.57ns typ, 1.57ns min, 1.04ns max; typ from 0.005 V to 0.524 V
|   rising waveform, R_fixture 50.000, V_fixture 1.500: 20-80 % time 551ps typ, 511ps min, 559ps max; typ from 1.03 V to 1.5 V
|   falling waveform, R_fixture 50.000, V_fixture 1.500: 20-80 % time 2.57ns typ, 2.39ns min, 2.45ns max; typ from 1.5 V to 1.03 V
|   falling waveform, R_fixture 50.000, V_fixture 0.000: 20-80 % time 546ps typ, 508ps min, 573ps max; typ from 0.524 V to 0.005 V
[GND_clamp]
|Voltage   I(typ)   I(min)   I(max)
-1.5V     -437mA     -482.5mA   -410.7mA
-1.159V   -180.3mA   -233.3mA   -152.2mA
-1.128V   -159.5mA   -212mA     -133.3mA
-1.097V   -139.6mA   -191.2mA   -116.5mA
-1.035V   -103.7mA   -151.3mA   -91.23mA
-973mV    -75.24mA   -114.6mA   -76.75mA
-911mV    -56.05mA   -82.58mA   -66.41mA
-787mV    -36.61mA   -38.2mA    -47.39mA
-663mV    -22.9mA    -18.92mA   -29.92mA
-477mV    -7.274mA   -6.461mA   -9.278mA
-260mV    -227.6uA   -429.8uA   -148.6uA
1.5V      0A         0A         0A
[POWER_clamp]
|Voltage   I(typ)   I(min)   I(max)
-1.5V     391.3mA    429.6mA    369.7mA
-1.166V   144.6mA    192.2mA    117.1mA
-1.135V   124.2mA    171.8mA    97.3mA
-1.104V   104.7mA    152mA      79.15mA
-1.042V   69.75mA    114.3mA    49.91mA
-1.011V   54.95mA    96.78mA    39.84mA
-949mV    32.47mA    65.46mA    28.02mA
-887mV    19.82mA    40.53mA    21.37mA
-825mV    13.31mA    23.23mA    15.79mA
-732mV    7.53mA     9.888mA    9.145mA
-608mV    3.278mA    3.592mA    3.895mA
3V        -183uA     -190.7uA   -185.3uA
[Pulldown]
|Voltage   I(typ)   I(min)   I(max)
-1.5V     -361.3mA   -385.8mA   -347.6mA
-1.224V   -189.2mA   -224.9mA   -168.3mA
-1.086V   -113.8mA   -150.3mA   -99.3mA
-948mV    -62.81mA   -86.1mA    -69.57mA
-764mV    -37.82mA   -35.45mA   -45.51mA
-258mV    -5.294mA   -5.21mA    -4.909mA
1.95V     11.47mA    10.89mA    11.81mA
2.364V    26.78mA    25.44mA    27.58mA
2.502V    51.05mA    48.49mA    52.58mA
2.594V    87.5mA     83.1mA     90.1mA
2.732V    160.8mA    152.8mA    165.6mA
3V        324.7mA    308.5mA    334.4mA
[Pullup]
|Voltage   I(typ)   I(min)   I(max)
-1.5V     334.2mA    366.8mA    315.2mA
-1.186V   140.5mA    179.9mA    117.2mA
-1.14V    115.6mA    154.7mA    93.3mA
-1.048V   72.68mA    107.9mA    57.95mA
-956mV    44.92mA    68.74mA    42.37mA
-864mV    32.38mA    41.6mA     33.55mA
-588mV    15.88mA    15.55mA    15.32mA
424mV     -6.746mA   -6.408mA   -6.948mA
1.896V    -13.58mA   -12.9mA    -13.99mA
2.402V    -54.62mA   -51.89mA   -56.26mA
2.586V    -116.3mA   -110.5mA   -119.8mA
3V        -369.7mA   -351.2mA   -380.8mA
[Ramp]
| variable   typ   min   max
dV/dt_r   0.311/1.614n   0.292/1.589n   0.332/1.100n
dV/dt_f   0.282/2.626n   0.266/2.486n   0.292/2.547n
R_load = 50.000
[Rising Waveform]
R_fixture = 50.000
V_fixture = 0.000
V_fixture_min = 0.000
V_fixture_max = 0.000
|  time   V(typ)   V(min)   V(max)
0s        4.644mV    4.758mV    4.325mV
696ps     3.275mV    -1.728mV   6.255mV
1.029ns   10.98mV    9.451mV    37.99mV
1.517ns   53.05mV    58.51mV    168.2mV
2.208ns   186mV      206.2mV    401.5mV
2.548ns   264mV      279.4mV    462.2mV
3.025ns   362mV      359.7mV    502.5mV
3.738ns   451.9mV    429.5mV    525.8mV
4.745ns   499.1mV    468.7mV    537.4mV
10ns      523.5mV    492.3mV    546.5mV
[Rising Waveform]
R_fixture = 50.000
V_fixture = 1.500
V_fixture_min = 1.430
V_fixture_max = 1.580
|  time   V(typ)   V(min)   V(max)
0s        1.03V      985.7mV    1.093V
333ps     1.03V      985.8mV    1.093V
419ps     1.029V     985.9mV    1.244V
527ps     1.198V     984.8mV    1.341V
626ps     1.28V      981.2mV    1.391V
768ps     1.343V     1.171V     1.44V
898ps     1.379V     1.254V     1.473V
1.607ns   1.462V     1.388V     1.552V
3.111ns   1.493V     1.423V     1.575V
10ns      1.5V       1.43V      1.58V
[Falling Waveform]
R_fixture = 50.000
V_fixture = 1.500
V_fixture_min = 1.430
V_fixture_max = 1.580
|  time   V(typ)   V(min)   V(max)
0s        1.5V       1.43V      1.58V
849ps     1.501V     1.435V     1.577V
1.578ns   1.467V     1.395V     1.523V
2.327ns   1.394V     1.313V     1.43V
3.739ns   1.226V     1.138V     1.248V
4.371ns   1.159V     1.083V     1.191V
5.02ns    1.108V     1.044V     1.151V
5.743ns   1.073V     1.019V     1.124V
6.735ns   1.048V     1.001V     1.106V
10ns      1.03V      985.7mV    1.093V
[Falling Waveform]
R_fixture = 50.000
V_fixture = 0.000
V_fixture_min = 0.000
V_fixture_max = 0.000
|  time   V(typ)   V(min)   V(max)
0s        523.5mV    492.3mV    546.5mV
346ps     523mV      492mV      555.2mV
444ps     529.3mV    492.2mV    367.1mV
547ps     348.1mV    493.3mV    268mV
637ps     256.7mV    502mV      216.3mV
787ps     179.1mV    288.4mV    159.4mV
927ps     135.9mV    192.4mV    123mV
1.607ns   46.21mV    50.54mV    41.74mV
3.169ns   12.53mV    12.71mV    10.72mV
10ns      4.644mV    4.758mV    4.325mV
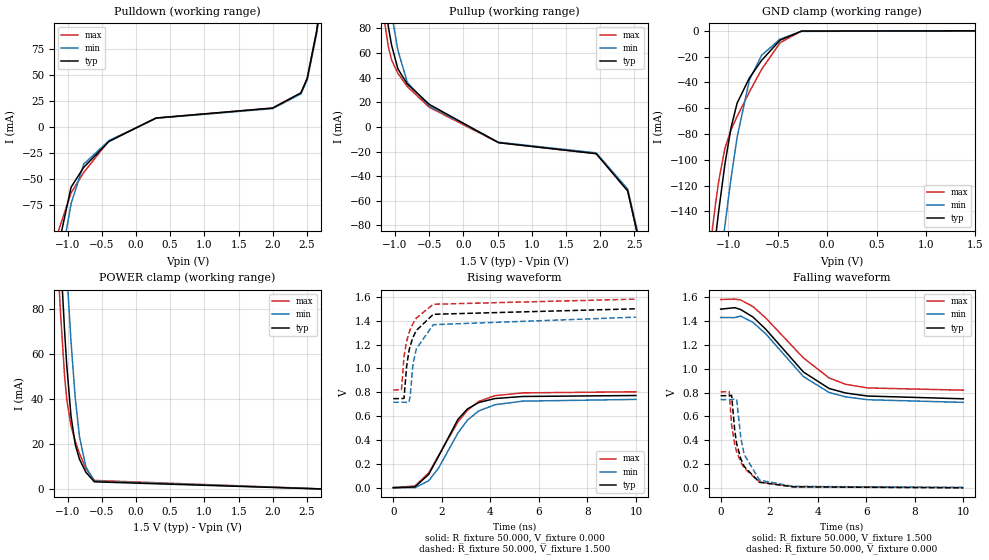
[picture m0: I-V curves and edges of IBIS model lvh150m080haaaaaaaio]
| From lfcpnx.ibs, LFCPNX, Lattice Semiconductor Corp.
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[Model] lvh150m080haaaaaaaio
Model_type I/O
Polarity   Non-Inverting
Enable   Active-Low
Vinl =  0.375V
Vinh =  1.125V
Vmeas =  0.750V
Cref =  0.0F
Rref =  1.000M
Vref =  0.0V
C_comp   5.000pF   4.000pF   5.500pF
[Temperature Range]   25.000   0.125k   -40.000
[Voltage Range]   1.500V   1.430V   1.580V
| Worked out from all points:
|   slope of the pulldown table from 0 to 0.225 V, typ, clamps not added: 33.4 ohm
|   slope of the pullup table from 0 to 0.225 V, typ, clamps not added: 34 ohm
|   GND clamp passes 1 mA (typ) near -0.32 V on its own axis
|   POWER clamp passes 1 mA (typ) near -0.45 V on its own axis
|   rising waveform, R_fixture 50.000, V_fixture 0.000: 20-80 % time 1.25ns typ, 1.36ns min, 1.45ns max; typ from 0 V to 0.774 V
|   rising waveform, R_fixture 50.000, V_fixture 1.500: 20-80 % time 538ps typ, 516ps min, 581ps max; typ from 0.747 V to 1.5 V
|   falling waveform, R_fixture 50.000, V_fixture 1.500: 20-80 % time 2.08ns typ, 1.99ns min, 2.24ns max; typ from 1.5 V to 0.747 V
|   falling waveform, R_fixture 50.000, V_fixture 0.000: 20-80 % time 512ps typ, 486ps min, 572ps max; typ from 0.774 V to 0 V
[GND_clamp]
|Voltage   I(typ)   I(min)   I(max)
-1.5V     -437mA     -482.5mA   -410.7mA
-1.159V   -180.3mA   -233.3mA   -152.2mA
-1.128V   -159.5mA   -212mA     -133.3mA
-1.097V   -139.6mA   -191.2mA   -116.5mA
-1.035V   -103.7mA   -151.3mA   -91.23mA
-973mV    -75.24mA   -114.6mA   -76.75mA
-911mV    -56.05mA   -82.58mA   -66.41mA
-787mV    -36.61mA   -38.2mA    -47.39mA
-663mV    -22.9mA    -18.92mA   -29.92mA
-477mV    -7.274mA   -6.461mA   -9.278mA
-260mV    -227.6uA   -429.8uA   -148.6uA
1.5V      0A         0A         0A
[POWER_clamp]
|Voltage   I(typ)   I(min)   I(max)
-1.5V     391.3mA    429.6mA    369.7mA
-1.166V   144.6mA    192.2mA    117.1mA
-1.135V   124.2mA    171.8mA    97.3mA
-1.104V   104.7mA    152mA      79.15mA
-1.042V   69.75mA    114.3mA    49.91mA
-1.011V   54.95mA    96.78mA    39.84mA
-949mV    32.47mA    65.46mA    28.02mA
-887mV    19.82mA    40.53mA    21.37mA
-825mV    13.31mA    23.23mA    15.79mA
-732mV    7.53mA     9.888mA    9.145mA
-608mV    3.278mA    3.592mA    3.895mA
3V        -183uA     -190.7uA   -185.3uA
[Pulldown]
|Voltage   I(typ)   I(min)   I(max)
-1.5V     -291.6mA   -309.8mA   -281.8mA
-1.27V    -176.2mA   -202.8mA   -160.3mA
-1.132V   -113.7mA   -142.2mA   -99.4mA
-948mV    -57.73mA   -73.5mA    -63.19mA
-764mV    -38.74mA   -35.69mA   -43.63mA
-396mV    -14.01mA   -13.16mA   -13.36mA
294mV     8.536mA    8.28mA     8.536mA
1.996V    18.06mA    17.52mA    18.06mA
2.41V     32.54mA    31.57mA    32.54mA
2.502V    46.35mA    44.96mA    46.35mA
2.64V     91.5mA     88.8mA     91.5mA
3V        261.8mA    253.9mA    261.8mA
[Pullup]
|Voltage   I(typ)   I(min)   I(max)
-1.5V     270.5mA    296.8mA    254.1mA
-1.186V   117.5mA    148.3mA    97.8mA
-1.094V   81mA       109.7mA    64.93mA
-1.048V   66.37mA    92mA       54.42mA
-956mV    47.16mA    62.34mA    43.5mA
-818mV    34.79mA    36.11mA    32.74mA
-496mV    18.28mA    17.11mA    15.93mA
516mV     -12.8mA    -12.42mA   -12.8mA
1.942V    -21.71mA   -21.06mA   -21.71mA
2.402V    -51.93mA   -50.37mA   -51.93mA
2.586V    -97.2mA    -94.3mA    -97.2mA
3V        -297.4mA   -288.5mA   -297.4mA
[Ramp]
| variable   typ   min   max
dV/dt_r   0.466/1.261n   0.443/1.390n   0.481/1.464n
dV/dt_f   0.447/2.122n   0.428/2.007n   0.456/2.313n
R_load = 50.000
[Rising Waveform]
R_fixture = 50.000
V_fixture = 0.000
V_fixture_min = 0.000
V_fixture_max = 0.000
|  time   V(typ)   V(min)   V(max)
0s        61.38uV    3.301mV    3.3mV
888ps     7.937mV    1.116mV    15.14mV
1.458ns   112.5mV    59.88mV    125.4mV
1.861ns   262.8mV    164.4mV    269.3mV
2.663ns   573.8mV    459.5mV    551.8mV
3.058ns   661.5mV    568.3mV    650.3mV
3.521ns   715.1mV    644.3mV    724.2mV
4.189ns   748.2mV    696.3mV    772.4mV
5.33ns    765.6mV    726.5mV    795.5mV
10ns      773.6mV    741.1mV    804.9mV
[Rising Waveform]
R_fixture = 50.000
V_fixture = 1.500
V_fixture_min = 1.430
V_fixture_max = 1.580
|  time   V(typ)   V(min)   V(max)
0s        747.4mV    717.5mV    819.9mV
336ps     747.7mV    717.6mV    822.5mV
441ps     750.2mV    717.8mV    1.1V
548ps     1.016V     715.5mV    1.227V
640ps     1.142V     715.3mV    1.295V
691ps     1.186V     760.5mV    1.324V
811ps     1.261V     1.039V     1.377V
950ps     1.319V     1.165V     1.423V
1.648ns   1.454V     1.367V     1.538V
10ns      1.5V       1.43V      1.581V
[Falling Waveform]
R_fixture = 50.000
V_fixture = 1.500
V_fixture_min = 1.430
V_fixture_max = 1.580
|  time   V(typ)   V(min)   V(max)
0s        1.5V       1.43V      1.581V
581ps     1.512V     1.429V     1.584V
821ps     1.497V     1.442V     1.577V
1.331ns   1.434V     1.389V     1.522V
1.861ns   1.331V     1.292V     1.425V
3.409ns   972.5mV    934.3mV    1.091V
4.47ns    834mV      800.3mV    922.7mV
5.148ns   796.3mV    763.8mV    869.3mV
6.054ns   770.7mV    739.8mV    838.7mV
10ns      747.4mV    717.5mV    819.9mV
[Falling Waveform]
R_fixture = 50.000
V_fixture = 0.000
V_fixture_min = 0.000
V_fixture_max = 0.000
|  time   V(typ)   V(min)   V(max)
0s        773.6mV    741.1mV    804.9mV
351ps     773.3mV    740.9mV    809mV
451ps     776.7mV    741mV      528.2mV
581ps     479.4mV    744.7mV    362mV
660ps     369.7mV    742.7mV    302mV
831ps     243.5mV    418.3mV    215.1mV
971ps     179.4mV    279.4mV    166mV
1.599ns   46.74mV    64.64mV    48.79mV
2.989ns   8.515mV    12.62mV    10.58mV
10ns      61.38uV    3.301mV    3.3mV
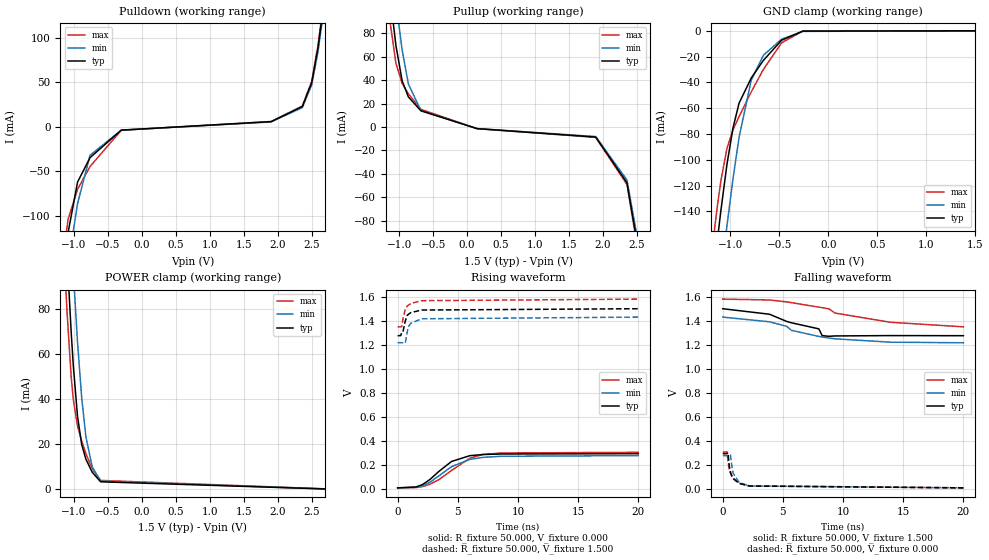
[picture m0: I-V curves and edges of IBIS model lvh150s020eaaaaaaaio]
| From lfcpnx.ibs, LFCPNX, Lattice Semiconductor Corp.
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[Model] lvh150s020eaaaaaaaio
Model_type I/O
Polarity   Non-Inverting
Enable   Active-Low
Vinl =  0.375V
Vinh =  1.125V
Vmeas =  0.750V
Cref =  0.0F
Rref =  1.000M
Vref =  0.0V
C_comp   5.000pF   4.000pF   5.500pF
[Temperature Range]   25.000   0.125k   -40.000
[Voltage Range]   1.500V   1.430V   1.580V
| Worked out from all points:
|   slope of the pulldown table from 0 to 0.225 V, typ, clamps not added: 112 ohm
|   slope of the pullup table from 0 to 0.225 V, typ, clamps not added: 106 ohm
|   GND clamp passes 1 mA (typ) near -0.32 V on its own axis
|   POWER clamp passes 1 mA (typ) near -0.45 V on its own axis
|   rising waveform, R_fixture 50.000, V_fixture 0.000: 20-80 % time 2.1ns typ, 2.46ns min, 2.5ns max; typ from 0.006 V to 0.291 V
|   rising waveform, R_fixture 50.000, V_fixture 1.500: 20-80 % time 455ps typ, 481ps min, 536ps max; typ from 1.27 V to 1.5 V
|   falling waveform, R_fixture 50.000, V_fixture 1.500: 20-80 % time 4.21ns typ, 4.55ns min, 6.63ns max; typ from 1.5 V to 1.27 V
|   falling waveform, R_fixture 50.000, V_fixture 0.000: 20-80 % time 562ps typ, 549ps min, 607ps max; typ from 0.291 V to 0.006 V
[GND_clamp]
|Voltage   I(typ)   I(min)   I(max)
-1.5V     -437mA     -482.5mA   -410.7mA
-1.159V   -180.3mA   -233.3mA   -152.2mA
-1.128V   -159.5mA   -212mA     -133.3mA
-1.097V   -139.6mA   -191.2mA   -116.5mA
-1.035V   -103.7mA   -151.3mA   -91.23mA
-973mV    -75.24mA   -114.6mA   -76.75mA
-911mV    -56.05mA   -82.58mA   -66.41mA
-787mV    -36.61mA   -38.2mA    -47.39mA
-663mV    -22.9mA    -18.92mA   -29.92mA
-477mV    -7.274mA   -6.461mA   -9.278mA
-260mV    -227.6uA   -429.8uA   -148.6uA
1.5V      0A         0A         0A
[POWER_clamp]
|Voltage   I(typ)   I(min)   I(max)
-1.5V     391.3mA    429.6mA    369.7mA
-1.166V   144.6mA    192.2mA    117.1mA
-1.135V   124.2mA    171.8mA    97.3mA
-1.104V   104.7mA    152mA      79.15mA
-1.042V   69.75mA    114.3mA    49.91mA
-1.011V   54.95mA    96.78mA    39.84mA
-949mV    32.47mA    65.46mA    28.02mA
-887mV    19.82mA    40.53mA    21.37mA
-825mV    13.31mA    23.23mA    15.79mA
-732mV    7.53mA     9.888mA    9.145mA
-608mV    3.278mA    3.592mA    3.895mA
3V        -183uA     -190.7uA   -185.3uA
[Pulldown]
|Voltage   I(typ)   I(min)   I(max)
-1.5V     -382mA     -398.8mA   -370.9mA
-1.224V   -198.8mA   -231.5mA   -178.5mA
-1.086V   -118.1mA   -153.7mA   -103.3mA
-948mV    -61.9mA    -86.2mA    -70.06mA
-764mV    -34.48mA   -31.79mA   -44.41mA
-304mV    -3.572mA   -3.622mA   -3.733mA
1.904V    5.931mA    5.634mA    6.109mA
2.364V    22.88mA    21.73mA    23.56mA
2.502V    49.68mA    47.19mA    51.17mA
2.594V    88.6mA     84.2mA     91.3mA
2.778V    193.8mA    184.1mA    199.6mA
3V        336.4mA    319.6mA    346.5mA
[Pullup]
|Voltage   I(typ)   I(min)   I(max)
-1.5V     340.1mA    373.1mA    321.3mA
-1.186V   140.8mA    181.2mA    117.4mA
-1.14V    114.9mA    155.2mA    92.3mA
-1.048V   69.63mA    106.6mA    54.37mA
-956mV    39.33mA    65.59mA    37.17mA
-864mV    25.63mA    36.6mA     28.29mA
-680mV    13.8mA     13.95mA    15.05mA
148mV     -1.455mA   -1.383mA   -1.499mA
1.896V    -8.656mA   -8.223mA   -8.916mA
2.356V    -47.71mA   -45.33mA   -49.14mA
2.586V    -125.9mA   -119.6mA   -129.7mA
3V        -407.5mA   -387.1mA   -419.7mA
[Ramp]
| variable   typ   min   max
dV/dt_r   0.171/2.142n   0.161/2.452n   0.173/2.555n
dV/dt_f   0.135/4.252n   0.128/5.059n   0.139/7.304n
R_load = 50.000
[Rising Waveform]
R_fixture = 50.000
V_fixture = 0.000
V_fixture_min = 0.000
V_fixture_max = 0.000
|  time   V(typ)   V(min)   V(max)
0s        6.265mV    6.395mV    6.428mV
1.528ns   13.71mV    11.02mV    8.857mV
2.087ns   34.92mV    24.67mV    17.24mV
2.681ns   75.61mV    52.83mV    36.11mV
3.448ns   144.9mV    107.8mV    76.31mV
4.48ns    226.4mV    183mV      151.1mV
6.001ns   274.7mV    243.8mV    254.1mV
7.104ns   284.3mV    260.7mV    284.8mV
8.605ns   288.6mV    269.6mV    297.3mV
20ns      291.4mV    275.1mV    302.6mV
[Rising Waveform]
R_fixture = 50.000
V_fixture = 1.500
V_fixture_min = 1.430
V_fixture_max = 1.580
|  time   V(typ)   V(min)   V(max)
0s        1.275V     1.216V     1.349V
257ps     1.276V     1.217V     1.349V
343ps     1.301V     1.216V     1.35V
434ps     1.303V     1.216V     1.411V
636ps     1.398V     1.214V     1.498V
786ps     1.442V     1.299V     1.52V
888ps     1.453V     1.35V      1.529V
1.116ns   1.468V     1.38V      1.544V
1.996ns   1.489V     1.416V     1.567V
20ns      1.5V       1.43V      1.58V
[Falling Waveform]
R_fixture = 50.000
V_fixture = 1.500
V_fixture_min = 1.430
V_fixture_max = 1.580
|  time   V(typ)   V(min)   V(max)
0s        1.5V       1.43V      1.58V
3.881ns   1.454V     1.391V     1.573V
5.316ns   1.394V     1.353V     1.557V
5.699ns   1.383V     1.32V      1.551V
7.986ns   1.332V     1.269V     1.513V
8.258ns   1.276V     1.264V     1.509V
8.815ns   1.27V      1.256V     1.499V
9.329ns   1.273V     1.249V     1.464V
13.93ns   1.276V     1.221V     1.387V
20ns      1.275V     1.216V     1.349V
[Falling Waveform]
R_fixture = 50.000
V_fixture = 0.000
V_fixture_min = 0.000
V_fixture_max = 0.000
|  time   V(typ)   V(min)   V(max)
0s        291.4mV    275.1mV    302.6mV
346ps     291mV      274.8mV    307.4mV
433ps     300.1mV    275mV      226.6mV
537ps     190.3mV    275.2mV    160.4mV
635ps     140mV      284mV      126.7mV
775ps     101.9mV    171.3mV    96.21mV
877ps     84.01mV    126mV      81.16mV
1.355ns   43.49mV    52.32mV    44.78mV
2.206ns   21.45mV    22.44mV    23.12mV
20ns      6.265mV    6.395mV    6.428mV
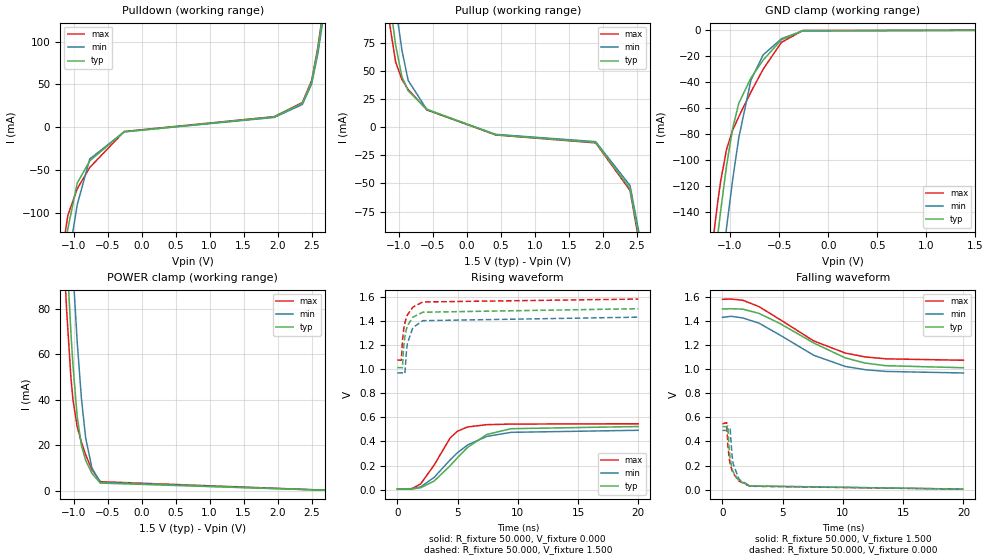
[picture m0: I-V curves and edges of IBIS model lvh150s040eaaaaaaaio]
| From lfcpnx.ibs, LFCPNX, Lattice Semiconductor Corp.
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[Model] lvh150s040eaaaaaaaio
Model_type I/O
Polarity   Non-Inverting
Enable   Active-Low
Vinl =  0.375V
Vinh =  1.125V
Vmeas =  0.750V
Cref =  0.0F
Rref =  1.000M
Vref =  0.0V
C_comp   5.000pF   4.000pF   5.500pF
[Temperature Range]   25.000   0.125k   -40.000
[Voltage Range]   1.500V   1.430V   1.580V
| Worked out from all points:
|   slope of the pulldown table from 0 to 0.225 V, typ, clamps not added: 52.2 ohm
|   slope of the pullup table from 0 to 0.225 V, typ, clamps not added: 56 ohm
|   GND clamp passes 1 mA (typ) near -0.32 V on its own axis
|   POWER clamp passes 1 mA (typ) near -0.45 V on its own axis
|   rising waveform, R_fixture 50.000, V_fixture 0.000: 20-80 % time 3.21ns typ, 3.19ns min, 1.97ns max; typ from 0.005 V to 0.524 V
|   rising waveform, R_fixture 50.000, V_fixture 1.500: 20-80 % time 568ps typ, 544ps min, 611ps max; typ from 1.01 V to 1.5 V
|   falling waveform, R_fixture 50.000, V_fixture 1.500: 20-80 % time 5.43ns typ, 4.98ns min, 5.14ns max; typ from 1.5 V to 1.01 V
|   falling waveform, R_fixture 50.000, V_fixture 0.000: 20-80 % time 559ps typ, 544ps min, 606ps max; typ from 0.524 V to 0.005 V
[GND_clamp]
|Voltage   I(typ)   I(min)   I(max)
-1.5V     -437mA     -482.5mA   -410.7mA
-1.159V   -180.3mA   -233.3mA   -152.2mA
-1.128V   -159.5mA   -212mA     -133.3mA
-1.097V   -139.6mA   -191.2mA   -116.5mA
-1.035V   -103.7mA   -151.3mA   -91.23mA
-973mV    -75.24mA   -114.6mA   -76.75mA
-911mV    -56.05mA   -82.58mA   -66.41mA
-787mV    -36.61mA   -38.2mA    -47.39mA
-663mV    -22.9mA    -18.92mA   -29.92mA
-477mV    -7.274mA   -6.461mA   -9.278mA
-260mV    -227.6uA   -429.8uA   -148.6uA
1.5V      0A         0A         0A
[POWER_clamp]
|Voltage   I(typ)   I(min)   I(max)
-1.5V     391.3mA    429.6mA    369.7mA
-1.166V   144.6mA    192.2mA    117.1mA
-1.135V   124.2mA    171.8mA    97.3mA
-1.104V   104.7mA    152mA      79.15mA
-1.042V   69.75mA    114.3mA    49.91mA
-1.011V   54.95mA    96.78mA    39.84mA
-949mV    32.47mA    65.46mA    28.02mA
-887mV    19.82mA    40.53mA    21.37mA
-825mV    13.31mA    23.23mA    15.79mA
-732mV    7.53mA     9.888mA    9.145mA
-608mV    3.278mA    3.592mA    3.895mA
3V        -183uA     -190.7uA   -185.3uA
[Pulldown]
|Voltage   I(typ)   I(min)   I(max)
-1.5V     -375.9mA   -405mA     -360mA
-1.224V   -196.9mA   -236.1mA   -174.2mA
-1.086V   -118.5mA   -157.8mA   -102.9mA
-948mV    -65.35mA   -90.4mA    -72.03mA
-764mV    -39.35mA   -37.22mA   -47.13mA
-258mV    -5.508mA   -5.47mA    -5.083mA
1.95V     11.93mA    11.34mA    12.29mA
2.364V    27.86mA    26.47mA    28.7mA
2.502V    53.11mA    50.46mA    54.71mA
2.594V    91mA       86.4mA     93.7mA
2.732V    167.3mA    158.9mA    172.3mA
3V        337.8mA    320.9mA    347.9mA
[Pullup]
|Voltage   I(typ)   I(min)   I(max)
-1.5V     334.2mA    366.8mA    315.2mA
-1.186V   140.5mA    179.9mA    117.2mA
-1.14V    115.6mA    154.7mA    93.3mA
-1.048V   72.68mA    107.9mA    57.95mA
-956mV    44.92mA    68.74mA    42.37mA
-864mV    32.38mA    41.6mA     33.55mA
-588mV    15.88mA    15.55mA    15.32mA
424mV     -6.746mA   -6.408mA   -6.948mA
1.896V    -13.58mA   -12.9mA    -13.99mA
2.402V    -54.62mA   -51.89mA   -56.26mA
2.586V    -116.3mA   -110.5mA   -119.8mA
3V        -369.7mA   -351.2mA   -380.8mA
[Ramp]
| variable   typ   min   max
dV/dt_r   0.311/3.231n   0.293/3.213n   0.333/2.014n
dV/dt_f   0.293/5.467n   0.277/4.991n   0.304/5.158n
R_load = 50.000
[Rising Waveform]
R_fixture = 50.000
V_fixture = 0.000
V_fixture_min = 0.000
V_fixture_max = 0.000
|  time   V(typ)   V(min)   V(max)
0s        4.554mV    4.705mV    4.207mV
1.227ns   5.329mV    6.233mV    9.196mV
1.946ns   16.1mV     23.79mV    48.74mV
3.051ns   70.72mV    101.5mV    203.4mV
4.381ns   198.4mV    246.6mV    428.5mV
4.989ns   264.6mV    306mV      484.4mV
5.83ns    350.4mV    370.6mV    519.9mV
7.435ns   457.8mV    441.6mV    539mV
9.441ns   505.4mV    475.3mV    543.7mV
20ns      523.5mV    492.3mV    546.5mV
[Rising Waveform]
R_fixture = 50.000
V_fixture = 1.500
V_fixture_min = 1.430
V_fixture_max = 1.580
|  time   V(typ)   V(min)   V(max)
0s        1.012V     968.4mV    1.074V
334ps     1.012V     968.5mV    1.073V
421ps     1.011V     968.6mV    1.233V
527ps     1.185V     967.4mV    1.331V
627ps     1.272V     963.5mV    1.383V
756ps     1.332V     1.146V     1.429V
837ps     1.358V     1.214V     1.449V
1.286ns   1.43V      1.343V     1.513V
2.116ns   1.471V     1.401V     1.556V
20ns      1.5V       1.43V      1.58V
[Falling Waveform]
R_fixture = 50.000
V_fixture = 1.500
V_fixture_min = 1.430
V_fixture_max = 1.580
|  time   V(typ)   V(min)   V(max)
0s        1.5V       1.43V      1.58V
727ps     1.502V     1.439V     1.582V
1.695ns   1.498V     1.425V     1.572V
3.031ns   1.463V     1.382V     1.519V
4.79ns    1.378V     1.282V     1.411V
7.583ns   1.217V     1.115V     1.234V
10.19ns   1.094V     1.023V     1.134V
11.83ns   1.051V     996mV      1.102V
13.55ns   1.029V     981.4mV    1.086V
20ns      1.012V     968.4mV    1.074V
[Falling Waveform]
R_fixture = 50.000
V_fixture = 0.000
V_fixture_min = 0.000
V_fixture_max = 0.000
|  time   V(typ)   V(min)   V(max)
0s        523.5mV    492.3mV    546.5mV
346ps     523mV      492mV      556.3mV
444ps     530mV      492.2mV    368mV
547ps     348.8mV    493.3mV    268.6mV
637ps     257.2mV    502.9mV    216.8mV
780ps     182.2mV    297.2mV    163mV
879ps     149.4mV    217.6mV    137.4mV
1.367ns   72.89mV    86.4mV     71.58mV
2.257ns   31.91mV    30.69mV    28.65mV
20ns      4.554mV    4.705mV    4.207mV
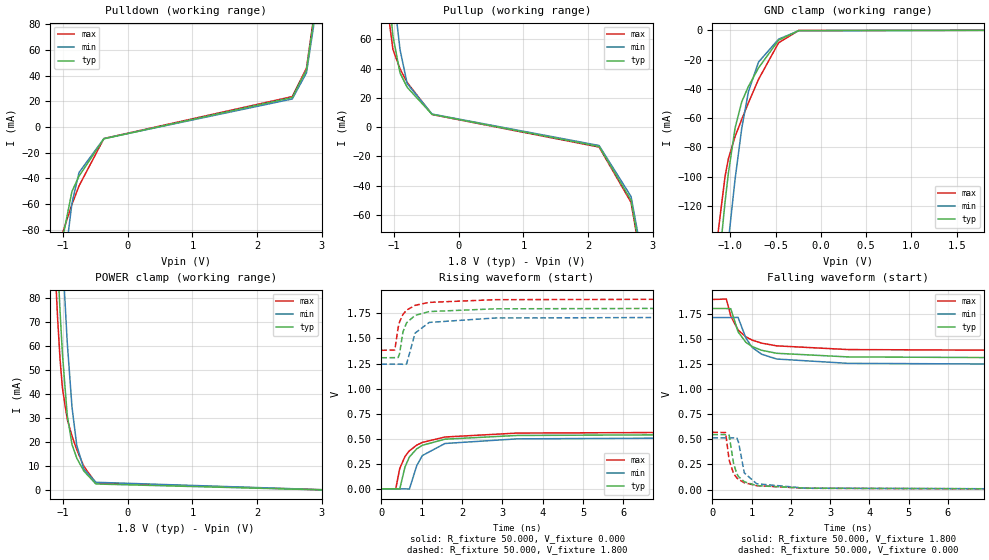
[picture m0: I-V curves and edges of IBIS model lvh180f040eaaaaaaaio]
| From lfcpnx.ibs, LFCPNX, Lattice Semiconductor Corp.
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[Model] lvh180f040eaaaaaaaio
Model_type I/O
Polarity   Non-Inverting
Enable   Active-Low
Vinl =  0.630V
Vinh =  1.170V
Vmeas =  0.900V
Cref =  0.0F
Rref =  1.000M
Vref =  0.0V
C_comp   5.000pF   4.000pF   5.500pF
[Temperature Range]   25.000   0.125k   -40.000
[Voltage Range]   1.800V   1.710V   1.890V
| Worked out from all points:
|   slope of the pulldown table from 0 to 0.27 V, typ, clamps not added: 53.8 ohm
|   slope of the pullup table from 0 to 0.27 V, typ, clamps not added: 67.5 ohm
|   GND clamp passes 1 mA (typ) near -0.32 V on its own axis
|   POWER clamp passes 1 mA (typ) near -0.38 V on its own axis
|   rising waveform, R_fixture 50.000, V_fixture 0.000: 20-80 % time 499ps typ, 474ps min, 552ps max; typ from 0.005 V to 0.547 V
|   rising waveform, R_fixture 50.000, V_fixture 1.800: 20-80 % time 258ps typ, 275ps min, 277ps max; typ from 1.31 V to 1.8 V
|   falling waveform, R_fixture 50.000, V_fixture 1.800: 20-80 % time 561ps typ, 554ps min, 608ps max; typ from 1.8 V to 1.31 V
|   falling waveform, R_fixture 50.000, V_fixture 0.000: 20-80 % time 224ps typ, 229ps min, 243ps max; typ from 0.547 V to 0.005 V
[GND_clamp]
|Voltage   I(typ)   I(min)   I(max)
-1.8V     -676.5mA   -711.8mA   -657.4mA
-1.171V   -188.8mA   -241.8mA   -160mA
-1.134V   -163.6mA   -216.3mA   -136.9mA
-1.06V    -117.6mA   -167.3mA   -100mA
-1.023V   -97.67mA   -144.1mA   -87.78mA
-949mV    -66.77mA   -101.8mA   -72.6mA
-875mV    -48.8mA    -66.89mA   -60.78mA
-801mV    -38.33mA   -41.86mA   -49.49mA
-690mV    -25.71mA   -21.72mA   -33.55mA
-468mV    -6.724mA   -6.036mA   -8.541mA
-246mV    -145.3uA   -325.1uA   -81.62uA
1.8V      0A         0A         0A
[POWER_clamp]
|Voltage   I(typ)   I(min)   I(max)
-1.8V     627.7mA    654.9mA    614.1mA
-1.16V    141.5mA    189mA      114.4mA
-1.123V   117.5mA    164.8mA    91.5mA
-1.086V   95.05mA    141.5mA    71.26mA
-1.049V   74.59mA    119.2mA    54.66mA
-1.012V   56.78mA    98.27mA    42.5mA
-938mV    31.33mA    61.69mA    29.59mA
-864mV    19.12mA    34.68mA    22.65mA
-790mV    13.42mA    18.68mA    16.91mA
-679mV    8.018mA    8.826mA    9.955mA
-494mV    2.695mA    3.4mA      3.109mA
3.6V      -185.9uA   -195.7uA   -188.2uA
[Pulldown]
|Voltage   I(typ)   I(min)   I(max)
-1.8V     -575.4mA   -586.4mA   -572mA
-1.195V   -177.9mA   -215.9mA   -156.2mA
-1.14V    -146.3mA   -184.9mA   -126.3mA
-1.03V    -92.1mA    -126.8mA   -85.63mA
-865mV    -50.17mA   -59.32mA   -60.26mA
-755mV    -38.12mA   -35.34mA   -45.76mA
-370mV    -9.091mA   -8.929mA   -8.869mA
2.545V    23.1mA     21.95mA    23.8mA
2.765V    44.6mA     42.37mA    45.94mA
2.875V    82.77mA    78.63mA    85.25mA
2.985V    139.6mA    132.6mA    143.8mA
3.6V      535.2mA    508.4mA    551.3mA
[Pullup]
|Voltage   I(typ)   I(min)   I(max)
-1.8V     534.2mA    557.6mA    522.2mA
-1.185V   140.4mA    179.7mA    117.9mA
-1.13V    110.7mA    149.4mA    89.8mA
-1.02V    62.09mA    94.5mA     52.97mA
-910mV    36.84mA    52.76mA    39.66mA
-800mV    27.16mA    29.72mA    30.5mA
-415mV    8.725mA    8.931mA    8.602mA
2.17V     -13.19mA   -12.53mA   -13.58mA
2.665V    -49.83mA   -47.34mA   -51.32mA
2.83V     -91.4mA    -86.8mA    -94.1mA
2.885V    -116.5mA   -110.7mA   -120mA
3.6V      -573.4mA   -544.7mA   -590.6mA
[Ramp]
| variable   typ   min   max
dV/dt_r   0.325/0.504n   0.306/0.476n   0.339/0.552n
dV/dt_f   0.296/0.559n   0.280/0.556n   0.305/0.601n
R_load = 50.000
[Rising Waveform]
R_fixture = 50.000
V_fixture = 0.000
V_fixture_min = 0.000
V_fixture_max = 0.000
|  time   V(typ)   V(min)   V(max)
0s        4.71mV     4.876mV    4.398mV
356ps     4.971mV    4.932mV    1.901mV
457ps     4.322mV    4.92mV     208mV
587ps     222.7mV    4.791mV    327.6mV
696ps     321.5mV    3.348mV    382.9mV
877ps     402.5mV    234.4mV    439.1mV
1.016ns   437.6mV    335.6mV    466.2mV
1.577ns   498.4mV    455.5mV    519.9mV
3.362ns   535.3mV    501.6mV    558.9mV
10ns      546.9mV    514.2mV    569.8mV
[Rising Waveform]
R_fixture = 50.000
V_fixture = 1.800
V_fixture_min = 1.710
V_fixture_max = 1.890
|  time   V(typ)   V(min)   V(max)
0s        1.307V     1.243V     1.381V
334ps     1.308V     1.244V     1.384V
419ps     1.31V      1.244V     1.611V
451ps     1.346V     1.244V     1.663V
537ps     1.565V     1.242V     1.738V
626ps     1.654V     1.245V     1.78V
837ps     1.728V     1.552V     1.828V
1.187ns   1.766V     1.658V     1.857V
2.82ns    1.793V     1.702V     1.884V
10ns      1.8V       1.71V      1.89V
[Falling Waveform]
R_fixture = 50.000
V_fixture = 1.800
V_fixture_min = 1.710
V_fixture_max = 1.890
|  time   V(typ)   V(min)   V(max)
0s        1.8V       1.71V      1.89V
356ps     1.8V       1.71V      1.894V
469ps     1.798V     1.71V      1.726V
655ps     1.569V     1.712V     1.587V
855ps     1.464V     1.506V     1.518V
1.015ns   1.422V     1.413V     1.486V
1.255ns   1.385V     1.346V     1.456V
1.639ns   1.355V     1.298V     1.429V
3.459ns   1.319V     1.255V     1.392V
10ns      1.307V     1.243V     1.381V
[Falling Waveform]
R_fixture = 50.000
V_fixture = 0.000
V_fixture_min = 0.000
V_fixture_max = 0.000
|  time   V(typ)   V(min)   V(max)
0s        546.9mV    514.2mV    569.8mV
336ps     546.5mV    513.9mV    567.4mV
428ps     542.4mV    514.1mV    294.5mV
539ps     262.5mV    514.3mV    160.4mV
625ps     156.1mV    512.3mV    115.7mV
665ps     130.2mV    474.4mV    101.6mV
815ps     77.62mV    165.8mV    68.3mV
1.129ns   39.68mV    58.3mV     39.29mV
2.395ns   14.06mV    14.01mV    13.05mV
10ns      4.71mV     4.876mV    4.398mV
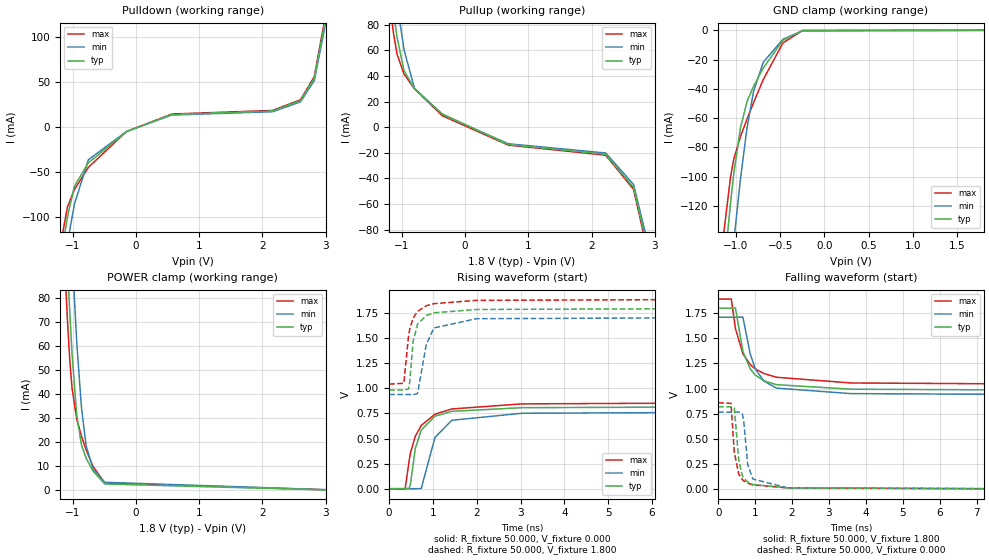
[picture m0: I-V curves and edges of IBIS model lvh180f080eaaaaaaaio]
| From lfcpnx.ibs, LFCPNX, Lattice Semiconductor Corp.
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[Model] lvh180f080eaaaaaaaio
Model_type I/O
Polarity   Non-Inverting
Enable   Active-Low
Vinl =  0.630V
Vinh =  1.170V
Vmeas =  0.900V
Cref =  0.0F
Rref =  1.000M
Vref =  0.0V
C_comp   5.000pF   4.000pF   5.500pF
[Temperature Range]   25.000   0.125k   -40.000
[Voltage Range]   1.800V   1.710V   1.890V
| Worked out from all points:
|   slope of the pulldown table from 0 to 0.27 V, typ, clamps not added: 32.7 ohm
|   slope of the pullup table from 0 to 0.27 V, typ, clamps not added: 41.7 ohm
|   GND clamp passes 1 mA (typ) near -0.32 V on its own axis
|   POWER clamp passes 1 mA (typ) near -0.38 V on its own axis
|   rising waveform, R_fixture 50.000, V_fixture 0.000: 20-80 % time 322ps typ, 360ps min, 428ps max; typ from 0 V to 0.819 V
|   rising waveform, R_fixture 50.000, V_fixture 1.800: 20-80 % time 159ps typ, 221ps min, 193ps max; typ from 0.983 V to 1.8 V
|   falling waveform, R_fixture 50.000, V_fixture 1.800: 20-80 % time 435ps typ, 422ps min, 527ps max; typ from 1.8 V to 0.983 V
|   falling waveform, R_fixture 50.000, V_fixture 0.000: 20-80 % time 141ps typ, 150ps min, 148ps max; typ from 0.819 V to 0 V
[GND_clamp]
|Voltage   I(typ)   I(min)   I(max)
-1.8V     -676.5mA   -711.8mA   -657.4mA
-1.171V   -188.8mA   -241.8mA   -160mA
-1.134V   -163.6mA   -216.3mA   -136.9mA
-1.06V    -117.6mA   -167.3mA   -100mA
-1.023V   -97.67mA   -144.1mA   -87.78mA
-949mV    -66.77mA   -101.8mA   -72.6mA
-875mV    -48.8mA    -66.89mA   -60.78mA
-801mV    -38.33mA   -41.86mA   -49.49mA
-690mV    -25.71mA   -21.72mA   -33.55mA
-468mV    -6.724mA   -6.036mA   -8.541mA
-246mV    -145.3uA   -325.1uA   -81.62uA
1.8V      0A         0A         0A
[POWER_clamp]
|Voltage   I(typ)   I(min)   I(max)
-1.8V     627.7mA    654.9mA    614.1mA
-1.16V    141.5mA    189mA      114.4mA
-1.123V   117.5mA    164.8mA    91.5mA
-1.086V   95.05mA    141.5mA    71.26mA
-1.049V   74.59mA    119.2mA    54.66mA
-1.012V   56.78mA    98.27mA    42.5mA
-938mV    31.33mA    61.69mA    29.59mA
-864mV    19.12mA    34.68mA    22.65mA
-790mV    13.42mA    18.68mA    16.91mA
-679mV    8.018mA    8.826mA    9.955mA
-494mV    2.695mA    3.4mA      3.109mA
3.6V      -185.9uA   -195.7uA   -188.2uA
[Pulldown]
|Voltage   I(typ)   I(min)   I(max)
-1.8V     -467.8mA   -473.5mA   -468.7mA
-1.195V   -147.3mA   -176.6mA   -130.8mA
-1.085V   -99.4mA    -128.3mA   -88.6mA
-975mV    -65.56mA   -85.7mA    -69.21mA
-755mV    -39.63mA   -36.22mA   -44.64mA
-150mV    -5.086mA   -4.689mA   -4.763mA
565mV     14.1mA     13.39mA    14.52mA
2.16V     17.98mA    17.08mA    18.52mA
2.6V      29.41mA    27.94mA    30.29mA
2.82V     54.39mA    51.67mA    56.02mA
2.985V    116mA      110.2mA    119.5mA
3.6V      435mA      413.3mA    448.1mA
[Pullup]
|Voltage   I(typ)   I(min)   I(max)
-1.8V     412.2mA    430.3mA    402mA
-1.185V   111.7mA    141.3mA    93.5mA
-1.13V    89.5mA     118.4mA    72.8mA
-1.075V   70.1mA     96.9mA     56.9mA
-965mV    44.06mA    60.4mA     41.47mA
-800mV    30.07mA    30.39mA    29.87mA
-360mV    10.32mA    9.758mA    8.902mA
685mV     -13.65mA   -12.97mA   -14.06mA
2.225V    -21.26mA   -20.2mA    -21.9mA
2.665V    -47.14mA   -44.79mA   -48.56mA
2.885V    -93.9mA    -89.2mA    -96.7mA
3.6V      -441.5mA   -419.4mA   -454.7mA
[Ramp]
| variable   typ   min   max
dV/dt_r   0.493/0.321n   0.462/0.360n   0.518/0.430n
dV/dt_f   0.490/0.436n   0.462/0.425n   0.509/0.532n
R_load = 50.000
[Rising Waveform]
R_fixture = 50.000
V_fixture = 0.000
V_fixture_min = 0.000
V_fixture_max = 0.000
|  time   V(typ)   V(min)   V(max)
0s        110.4uV    -89.57uV   -490.2uV
363ps     451.2uV    -69.02uV   -4.801mV
458ps     2.872mV    -48.08uV   283.4mV
489ps     56.15mV    17.34uV    360.7mV
598ps     401.8mV    -508uV     523.9mV
732ps     583.9mV    1.32mV     630mV
1.047ns   723.3mV    511.5mV    743.2mV
1.431ns   771.2mV    682.2mV    795.1mV
3.033ns   807.8mV    752.1mV    845.8mV
10ns      819.1mV    766.1mV    859.6mV
[Rising Waveform]
R_fixture = 50.000
V_fixture = 1.800
V_fixture_min = 1.710
V_fixture_max = 1.890
|  time   V(typ)   V(min)   V(max)
0s        983.4mV    939.4mV    1.043V
334ps     983.5mV    939.5mV    1.051V
441ps     993.3mV    939.7mV    1.516V
468ps     1.06V      939.7mV    1.589V
548ps     1.472V     937.2mV    1.702V
648ps     1.64V      948.4mV    1.768V
848ps     1.727V     1.439V     1.824V
1.022ns   1.754V     1.603V     1.845V
1.992ns   1.787V     1.695V     1.878V
10ns      1.8V       1.71V      1.891V
[Falling Waveform]
R_fixture = 50.000
V_fixture = 1.800
V_fixture_min = 1.710
V_fixture_max = 1.890
|  time   V(typ)   V(min)   V(max)
0s        1.8V       1.71V      1.891V
356ps     1.8V       1.71V      1.891V
466ps     1.804V     1.71V      1.599V
670ps     1.369V     1.711V     1.346V
870ps     1.195V     1.342V     1.239V
1.001ns   1.136V     1.198V     1.197V
1.24ns    1.077V     1.074V     1.15V
1.579ns   1.039V     1.005V     1.113V
3.597ns   994.2mV    950.1mV    1.056V
10ns      983.4mV    939.4mV    1.043V
[Falling Waveform]
R_fixture = 50.000
V_fixture = 0.000
V_fixture_min = 0.000
V_fixture_max = 0.000
|  time   V(typ)   V(min)   V(max)
0s        819.1mV    766.1mV    859.6mV
346ps     818.9mV    765.9mV    853.4mV
436ps     808.9mV    766mV      368.7mV
556ps     294mV      766.8mV    149.7mV
650ps     138.7mV    755mV      96.98mV
691ps     110.9mV    681.1mV    83.1mV
800ps     69.68mV    242mV      59.19mV
941ps     45.03mV    100.2mV    42.48mV
1.876ns   12.77mV    12.66mV    12.15mV
10ns      110.4uV    -89.57uV   -490.2uV
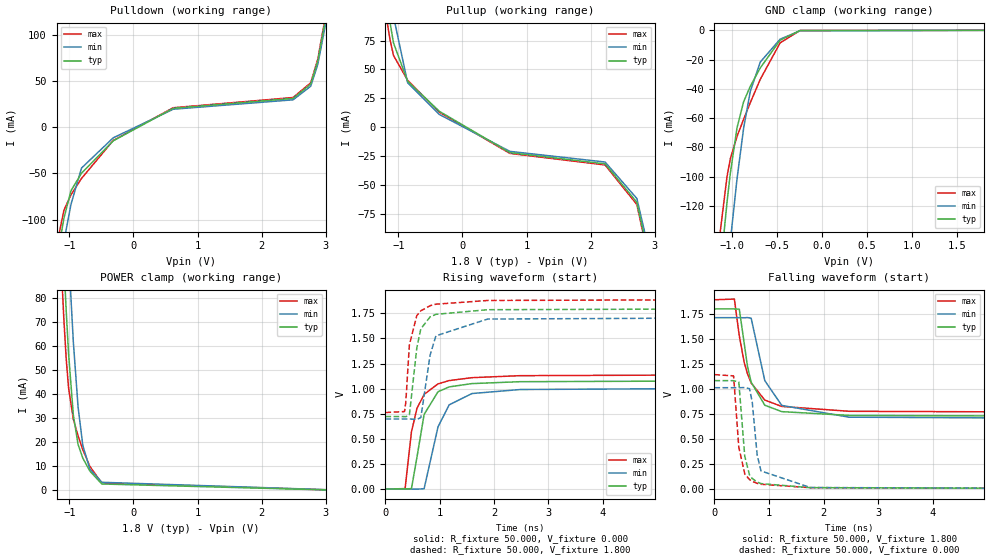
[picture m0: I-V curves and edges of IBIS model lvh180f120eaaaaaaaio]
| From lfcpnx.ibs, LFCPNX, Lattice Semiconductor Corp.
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[Model] lvh180f120eaaaaaaaio
Model_type I/O
Polarity   Non-Inverting
Enable   Active-Low
Vinl =  0.630V
Vinh =  1.170V
Vmeas =  0.900V
Cref =  0.0F
Rref =  1.000M
Vref =  0.0V
C_comp   5.000pF   4.000pF   5.500pF
[Temperature Range]   25.000   0.125k   -40.000
[Voltage Range]   1.800V   1.710V   1.890V
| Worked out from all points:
|   slope of the pulldown table from 0 to 0.27 V, typ, clamps not added: 23.9 ohm
|   slope of the pullup table from 0 to 0.27 V, typ, clamps not added: 27.3 ohm
|   GND clamp passes 1 mA (typ) near -0.32 V on its own axis
|   POWER clamp passes 1 mA (typ) near -0.38 V on its own axis
|   rising waveform, R_fixture 50.000, V_fixture 0.000: 20-80 % time 245ps typ, 320ps min, 266ps max; typ from 0 V to 1.08 V
|   rising waveform, R_fixture 50.000, V_fixture 1.800: 20-80 % time 155ps typ, 197ps min, 133ps max; typ from 0.722 V to 1.8 V
|   falling waveform, R_fixture 50.000, V_fixture 1.800: 20-80 % time 249ps typ, 350ps min, 320ps max; typ from 1.8 V to 0.722 V
|   falling waveform, R_fixture 50.000, V_fixture 0.000: 20-80 % time 101ps typ, 134ps min, 111ps max; typ from 1.08 V to 0 V
[GND_clamp]
|Voltage   I(typ)   I(min)   I(max)
-1.8V     -676.5mA   -711.8mA   -657.4mA
-1.171V   -188.8mA   -241.8mA   -160mA
-1.134V   -163.6mA   -216.3mA   -136.9mA
-1.06V    -117.6mA   -167.3mA   -100mA
-1.023V   -97.67mA   -144.1mA   -87.78mA
-949mV    -66.77mA   -101.8mA   -72.6mA
-875mV    -48.8mA    -66.89mA   -60.78mA
-801mV    -38.33mA   -41.86mA   -49.49mA
-690mV    -25.71mA   -21.72mA   -33.55mA
-468mV    -6.724mA   -6.036mA   -8.541mA
-246mV    -145.3uA   -325.1uA   -81.62uA
1.8V      0A         0A         0A
[POWER_clamp]
|Voltage   I(typ)   I(min)   I(max)
-1.8V     627.7mA    654.9mA    614.1mA
-1.16V    141.5mA    189mA      114.4mA
-1.123V   117.5mA    164.8mA    91.5mA
-1.086V   95.05mA    141.5mA    71.26mA
-1.049V   74.59mA    119.2mA    54.66mA
-1.012V   56.78mA    98.27mA    42.5mA
-938mV    31.33mA    61.69mA    29.59mA
-864mV    19.12mA    34.68mA    22.65mA
-790mV    13.42mA    18.68mA    16.91mA
-679mV    8.018mA    8.826mA    9.955mA
-494mV    2.695mA    3.4mA      3.109mA
3.6V      -185.9uA   -195.7uA   -188.2uA
[Pulldown]
|Voltage   I(typ)   I(min)   I(max)
-1.8V     -446.5mA   -453mA     -445.9mA
-1.195V   -143mA     -169.9mA   -127.2mA
-1.085V   -98.6mA    -123.8mA   -89.9mA
-975mV    -68.8mA    -83.6mA    -73.2mA
-810mV    -49.78mA   -44.19mA   -55.42mA
-315mV    -14.76mA   -11.51mA   -14.36mA
620mV     20.37mA    19.36mA    20.99mA
2.49V     31.09mA    29.54mA    32.02mA
2.765V    46.6mA     44.27mA    48mA
2.875V    71.6mA     68mA       73.7mA
2.985V    112.9mA    107.3mA    116.3mA
3.6V      415mA      394.2mA    427.4mA
[Pullup]
|Voltage   I(typ)   I(min)   I(max)
-1.8V     403.7mA    420.1mA    393.5mA
-1.24V    135.2mA    162.1mA    117.3mA
-1.185V   112.1mA    139mA      94.9mA
-1.13V    91mA       116.8mA    76mA
-1.075V   73mA       96mA       62.13mA
-855mV    39.82mA    38.56mA    40.66mA
-360mV    13.72mA    10.99mA    12.93mA
740mV     -22.11mA   -21mA      -22.77mA
2.225V    -31.84mA   -30.25mA   -32.8mA
2.72V     -65.09mA   -61.84mA   -67.04mA
2.885V    -106.4mA   -101.1mA   -109.6mA
3.6V      -483.4mA   -459.2mA   -497.9mA
[Ramp]
| variable   typ   min   max
dV/dt_r   0.651/0.244n   0.610/0.318n   0.688/0.269n
dV/dt_f   0.644/0.253n   0.605/0.355n   0.674/0.325n
R_load = 50.000
[Rising Waveform]
R_fixture = 50.000
V_fixture = 0.000
V_fixture_min = 0.000
V_fixture_max = 0.000
|  time   V(typ)   V(min)   V(max)
0s        101.1uV    -1.566mV   -180.2uV
361ps     645.1uV    -1.551mV   3.834mV
478ps     3.923mV    -1.458mV   569mV
578ps     312mV      -1.4mV     800.8mV
711ps     742.7mV    2.872mV    942.3mV
967ps     969mV      618.7mV    1.047V
1.172ns   1.017V     838.1mV    1.08V
1.592ns   1.05V      951mV      1.109V
2.479ns   1.069V     991mV      1.129V
10ns      1.084V     1.013V     1.144V
[Rising Waveform]
R_fixture = 50.000
V_fixture = 1.800
V_fixture_min = 1.710
V_fixture_max = 1.890
|  time   V(typ)   V(min)   V(max)
0s        721.7mV    697.4mV    761.9mV
351ps     721.3mV    697.5mV    771.3mV
373ps     719.7mV    697.5mV    859.4mV
440ps     738.6mV    697.7mV    1.436V
577ps     1.407V     692.8mV    1.728V
651ps     1.596V     711.5mV    1.775V
821ps     1.714V     1.333V     1.826V
928ps     1.74V      1.526V     1.841V
1.881ns   1.786V     1.693V     1.878V
10ns      1.8V       1.713V     1.892V
[Falling Waveform]
R_fixture = 50.000
V_fixture = 1.800
V_fixture_min = 1.710
V_fixture_max = 1.890
|  time   V(typ)   V(min)   V(max)
0s        1.8V       1.713V     1.892V
365ps     1.8V       1.713V     1.899V
455ps     1.798V     1.713V     1.531V
545ps     1.457V     1.712V     1.265V
604ps     1.228V     1.714V     1.154V
672ps     1.068V     1.708V     1.06V
922ps     837.7mV    1.083V     889.2mV
1.232ns   773.5mV    835.9mV    825.4mV
2.465ns   735.9mV    718.1mV    777mV
10ns      721.7mV    697.4mV    761.9mV
[Falling Waveform]
R_fixture = 50.000
V_fixture = 0.000
V_fixture_min = 0.000
V_fixture_max = 0.000
|  time   V(typ)   V(min)   V(max)
0s        1.084V     1.013V     1.144V
350ps     1.083V     1.013V     1.131V
446ps     1.07V      1.013V     417.4mV
555ps     327.2mV    1.014V     150mV
642ps     140.1mV    1.003V     94.39mV
692ps     104.6mV    868.8mV    76.71mV
782ps     69.54mV    339.4mV    56.8mV
852ps     54.1mV     180.8mV    47.13mV
1.754ns   13.65mV    15.02mV    13.16mV
10ns      101.1uV    -1.566mV   -180.2uV
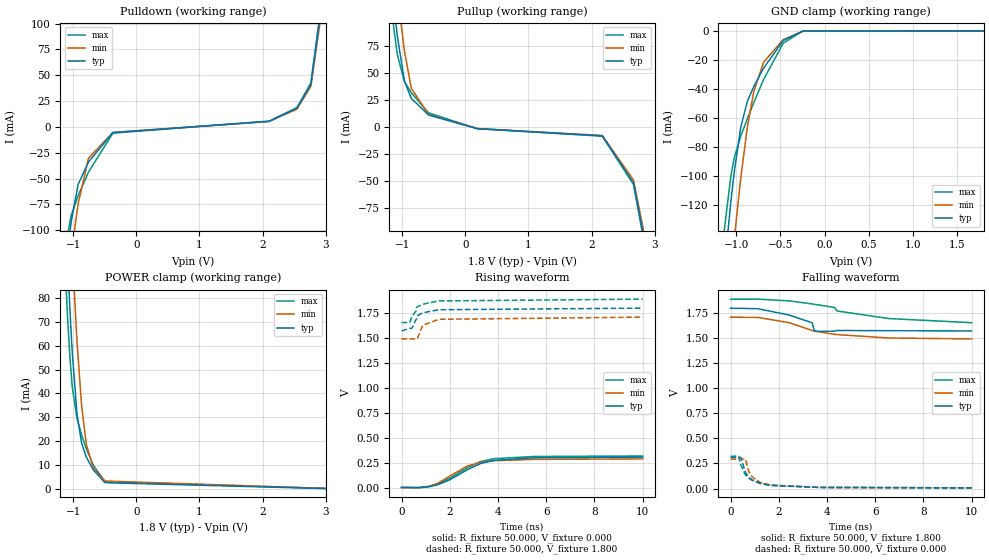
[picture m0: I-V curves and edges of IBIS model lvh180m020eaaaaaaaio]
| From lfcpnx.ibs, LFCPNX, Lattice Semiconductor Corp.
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[Model] lvh180m020eaaaaaaaio
Model_type I/O
Polarity   Non-Inverting
Enable   Active-Low
Vinl =  0.630V
Vinh =  1.170V
Vmeas =  0.900V
Cref =  0.0F
Rref =  1.000M
Vref =  0.0V
C_comp   5.000pF   4.000pF   5.500pF
[Temperature Range]   25.000   0.125k   -40.000
[Voltage Range]   1.800V   1.710V   1.890V
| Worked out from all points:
|   slope of the pulldown table from 0 to 0.27 V, typ, clamps not added: 114 ohm
|   slope of the pullup table from 0 to 0.27 V, typ, clamps not added: 125 ohm
|   GND clamp passes 1 mA (typ) near -0.32 V on its own axis
|   POWER clamp passes 1 mA (typ) near -0.38 V on its own axis
|   rising waveform, R_fixture 50.000, V_fixture 0.000: 20-80 % time 1.46ns typ, 1.27ns min, 1.44ns max; typ from 0.006 V to 0.31 V
|   rising waveform, R_fixture 50.000, V_fixture 1.800: 20-80 % time 438ps typ, 448ps min, 506ps max; typ from 1.57 V to 1.8 V
|   falling waveform, R_fixture 50.000, V_fixture 1.800: 20-80 % time 1.41ns typ, 2.17ns min, 3ns max; typ from 1.8 V to 1.57 V
|   falling waveform, R_fixture 50.000, V_fixture 0.000: 20-80 % time 534ps typ, 526ps min, 602ps max; typ from 0.31 V to 0.006 V
[GND_clamp]
|Voltage   I(typ)   I(min)   I(max)
-1.8V     -676.5mA   -711.8mA   -657.4mA
-1.171V   -188.8mA   -241.8mA   -160mA
-1.134V   -163.6mA   -216.3mA   -136.9mA
-1.06V    -117.6mA   -167.3mA   -100mA
-1.023V   -97.67mA   -144.1mA   -87.78mA
-949mV    -66.77mA   -101.8mA   -72.6mA
-875mV    -48.8mA    -66.89mA   -60.78mA
-801mV    -38.33mA   -41.86mA   -49.49mA
-690mV    -25.71mA   -21.72mA   -33.55mA
-468mV    -6.724mA   -6.036mA   -8.541mA
-246mV    -145.3uA   -325.1uA   -81.62uA
1.8V      0A         0A         0A
[POWER_clamp]
|Voltage   I(typ)   I(min)   I(max)
-1.8V     627.7mA    654.9mA    614.1mA
-1.16V    141.5mA    189mA      114.4mA
-1.123V   117.5mA    164.8mA    91.5mA
-1.086V   95.05mA    141.5mA    71.26mA
-1.049V   74.59mA    119.2mA    54.66mA
-1.012V   56.78mA    98.27mA    42.5mA
-938mV    31.33mA    61.69mA    29.59mA
-864mV    19.12mA    34.68mA    22.65mA
-790mV    13.42mA    18.68mA    16.91mA
-679mV    8.018mA    8.826mA    9.955mA
-494mV    2.695mA    3.4mA      3.109mA
3.6V      -185.9uA   -195.7uA   -188.2uA
[Pulldown]
|Voltage   I(typ)   I(min)   I(max)
-1.8V     -594.7mA   -582.9mA   -597.6mA
-1.14V    -149.2mA   -182.1mA   -130mA
-1.085V   -118.6mA   -152.1mA   -103.8mA
-1.03V    -91.8mA    -123.7mA   -85.71mA
-920mV    -55.62mA   -74.28mA   -66.5mA
-755mV    -33.8mA    -30.2mA    -43.57mA
-370mV    -5.436mA   -5.297mA   -6.016mA
2.105V    5.482mA    5.208mA    5.646mA
2.545V    18.18mA    17.27mA    18.72mA
2.765V    41.22mA    39.16mA    42.46mA
2.985V    140mA      133mA      144.2mA
3.6V      542.1mA    515mA      558.4mA
[Pullup]
|Voltage   I(typ)   I(min)   I(max)
-1.8V     556.2mA    580.5mA    544.4mA
-1.185V   144.1mA    185.3mA    121mA
-1.13V    112.6mA    153.6mA    91.2mA
-1.075V   84.2mA     123.5mA    67.08mA
-965mV    43.2mA     71.23mA    42.26mA
-855mV    26.46mA    36.03mA    31.86mA
-580mV    11mA       11.36mA    13.02mA
190mV     -1.578mA   -1.499mA   -1.625mA
2.17V     -8.31mA    -7.894mA   -8.559mA
2.665V    -51.98mA   -49.38mA   -53.54mA
2.83V     -103.2mA   -98mA      -106.3mA
3.6V      -669.1mA   -635.6mA   -689.2mA
[Ramp]
| variable   typ   min   max
dV/dt_r   0.182/1.489n   0.172/1.294n   0.189/1.457n
dV/dt_f   0.137/2.108n   0.130/2.538n   0.141/3.399n
R_load = 50.000
[Rising Waveform]
R_fixture = 50.000
V_fixture = 0.000
V_fixture_min = 0.000
V_fixture_max = 0.000
|  time   V(typ)   V(min)   V(max)
0s        6.429mV    6.572mV    6.57mV
736ps     6.044mV    2.625mV    6.731mV
1.127ns   13.28mV    15.11mV    17.21mV
1.467ns   31.22mV    43.41mV    40.12mV
1.988ns   81.75mV    118.4mV    97.51mV
2.731ns   184.3mV    221mV      203.6mV
3.259ns   244.2mV    256.8mV    264.2mV
3.821ns   277.6mV    273.8mV    294.5mV
5.476ns   303.2mV    287.3mV    316mV
10ns      310mV      292.4mV    321.6mV
[Rising Waveform]
R_fixture = 50.000
V_fixture = 1.800
V_fixture_min = 1.710
V_fixture_max = 1.890
|  time   V(typ)   V(min)   V(max)
0s        1.572V     1.493V     1.655V
343ps     1.598V     1.493V     1.657V
434ps     1.6V       1.494V     1.718V
606ps     1.688V     1.489V     1.773V
616ps     1.69V      1.489V     1.805V
636ps     1.694V     1.491V     1.809V
677ps     1.727V     1.507V     1.816V
877ps     1.753V     1.628V     1.839V
1.548ns   1.784V     1.688V     1.872V
10ns      1.8V       1.71V      1.89V
[Falling Waveform]
R_fixture = 50.000
V_fixture = 1.800
V_fixture_min = 1.710
V_fixture_max = 1.890
|  time   V(typ)   V(min)   V(max)
0s        1.8V       1.71V      1.89V
1.145ns   1.794V     1.707V     1.89V
2.434ns   1.731V     1.655V     1.872V
3.392ns   1.653V     1.576V     1.842V
3.469ns   1.573V     1.572V     1.839V
3.543ns   1.569V     1.569V     1.836V
4.309ns   1.57V      1.539V     1.807V
4.414ns   1.577V     1.536V     1.772V
6.561ns   1.575V     1.502V     1.696V
10ns      1.572V     1.493V     1.655V
[Falling Waveform]
R_fixture = 50.000
V_fixture = 0.000
V_fixture_min = 0.000
V_fixture_max = 0.000
|  time   V(typ)   V(min)   V(max)
0s        310mV      292.4mV    321.6mV
336ps     309.5mV    292.2mV    322.3mV
428ps     310mV      292.4mV    234.4mV
615ps     161.7mV    294.6mV    136.5mV
755ps     114.3mV    168.6mV    103.2mV
905ps     84.45mV    113.3mV    80.53mV
1.23ns    49.2mV     61.42mV    52.91mV
1.655ns   29.77mV    33.43mV    34.31mV
3.661ns   10.48mV    11.09mV    10.75mV
10ns      6.429mV    6.572mV    6.57mV
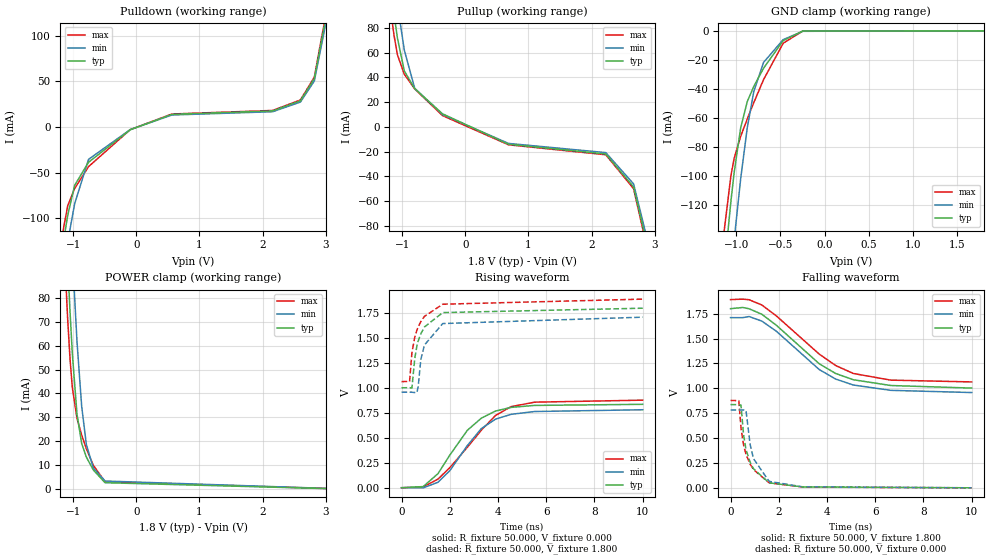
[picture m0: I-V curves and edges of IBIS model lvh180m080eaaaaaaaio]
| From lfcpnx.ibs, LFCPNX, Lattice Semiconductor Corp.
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[Model] lvh180m080eaaaaaaaio
Model_type I/O
Polarity   Non-Inverting
Enable   Active-Low
Vinl =  0.630V
Vinh =  1.170V
Vmeas =  0.900V
Cref =  0.0F
Rref =  1.000M
Vref =  0.0V
C_comp   5.000pF   4.000pF   5.500pF
[Temperature Range]   25.000   0.125k   -40.000
[Voltage Range]   1.800V   1.710V   1.890V
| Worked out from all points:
|   slope of the pulldown table from 0 to 0.27 V, typ, clamps not added: 33.5 ohm
|   slope of the pullup table from 0 to 0.27 V, typ, clamps not added: 40.5 ohm
|   GND clamp passes 1 mA (typ) near -0.32 V on its own axis
|   POWER clamp passes 1 mA (typ) near -0.38 V on its own axis
|   rising waveform, R_fixture 50.000, V_fixture 0.000: 20-80 % time 1.56ns typ, 1.52ns min, 1.89ns max; typ from 0 V to 0.836 V
|   rising waveform, R_fixture 50.000, V_fixture 1.800: 20-80 % time 531ps typ, 527ps min, 592ps max; typ from 1 V to 1.8 V
|   falling waveform, R_fixture 50.000, V_fixture 1.800: 20-80 % time 2.38ns typ, 2.27ns min, 2.45ns max; typ from 1.8 V to 1 V
|   falling waveform, R_fixture 50.000, V_fixture 0.000: 20-80 % time 525ps typ, 497ps min, 574ps max; typ from 0.836 V to 0 V
[GND_clamp]
|Voltage   I(typ)   I(min)   I(max)
-1.8V     -676.5mA   -711.8mA   -657.4mA
-1.171V   -188.8mA   -241.8mA   -160mA
-1.134V   -163.6mA   -216.3mA   -136.9mA
-1.06V    -117.6mA   -167.3mA   -100mA
-1.023V   -97.67mA   -144.1mA   -87.78mA
-949mV    -66.77mA   -101.8mA   -72.6mA
-875mV    -48.8mA    -66.89mA   -60.78mA
-801mV    -38.33mA   -41.86mA   -49.49mA
-690mV    -25.71mA   -21.72mA   -33.55mA
-468mV    -6.724mA   -6.036mA   -8.541mA
-246mV    -145.3uA   -325.1uA   -81.62uA
1.8V      0A         0A         0A
[POWER_clamp]
|Voltage   I(typ)   I(min)   I(max)
-1.8V     627.7mA    654.9mA    614.1mA
-1.16V    141.5mA    189mA      114.4mA
-1.123V   117.5mA    164.8mA    91.5mA
-1.086V   95.05mA    141.5mA    71.26mA
-1.049V   74.59mA    119.2mA    54.66mA
-1.012V   56.78mA    98.27mA    42.5mA
-938mV    31.33mA    61.69mA    29.59mA
-864mV    19.12mA    34.68mA    22.65mA
-790mV    13.42mA    18.68mA    16.91mA
-679mV    8.018mA    8.826mA    9.955mA
-494mV    2.695mA    3.4mA      3.109mA
3.6V      -185.9uA   -195.7uA   -188.2uA
[Pulldown]
|Voltage   I(typ)   I(min)   I(max)
-1.8V     -455.8mA   -464.1mA   -455.9mA
-1.195V   -143.5mA   -173.1mA   -127.2mA
-1.085V   -96.8mA    -125.7mA   -86.3mA
-975mV    -63.89mA   -84mA      -67.31mA
-755mV    -38.62mA   -35.5mA    -43.42mA
-95mV     -3.13mA    -2.89mA    -2.938mA
565mV     13.74mA    13.05mA    14.15mA
2.16V     17.52mA    16.65mA    18.05mA
2.6V      28.66mA    27.23mA    29.52mA
2.82V     53mA       50.35mA    54.59mA
2.985V    113.1mA    107.4mA    116.5mA
3.6V      423.8mA    402.6mA    436.5mA
[Pullup]
|Voltage   I(typ)   I(min)   I(max)
-1.8V     423.8mA    442.4mA    413.3mA
-1.185V   114.8mA    145.2mA    96mA
-1.13V    92.1mA     121.8mA    74.8mA
-1.075V   72.1mA     99.6mA     58.48mA
-965mV    45.28mA    62.08mA    42.62mA
-800mV    30.91mA    31.23mA    30.7mA
-360mV    10.61mA    10.03mA    9.151mA
685mV     -14.03mA   -13.33mA   -14.45mA
2.225V    -21.86mA   -20.76mA   -22.51mA
2.665V    -48.46mA   -46.04mA   -49.91mA
2.885V    -96.4mA    -91.6mA    -99.3mA
3.6V      -453.8mA   -431.1mA   -467.4mA
[Ramp]
| variable   typ   min   max
dV/dt_r   0.504/1.570n   0.471/1.567n   0.529/1.928n
dV/dt_f   0.479/2.463n   0.452/2.370n   0.497/2.551n
R_load = 50.000
[Rising Waveform]
R_fixture = 50.000
V_fixture = 0.000
V_fixture_min = 0.000
V_fixture_max = 0.000
|  time   V(typ)   V(min)   V(max)
0s        109.1uV    -50.23uV   -498.6uV
899ps     11.2mV     -1.538mV   7.638mV
1.512ns   140.7mV    54.59mV    86.45mV
2.002ns   326.5mV    170.7mV    200.6mV
2.729ns   575.5mV    422.6mV    405.1mV
3.311ns   697.6mV    593.1mV    577.4mV
3.898ns   768.8mV    687.7mV    724.1mV
4.541ns   805.3mV    735.7mV    812.7mV
5.52ns    825.2mV    764mV      857.8mV
10ns      836.2mV    781.8mV    877.9mV
[Rising Waveform]
R_fixture = 50.000
V_fixture = 1.800
V_fixture_min = 1.710
V_fixture_max = 1.890
|  time   V(typ)   V(min)   V(max)
0s        1.002V     957.3mV    1.064V
333ps     1.003V     957.4mV    1.065V
431ps     1V         957.5mV    1.353V
548ps     1.294V     954.2mV    1.508V
639ps     1.423V     954mV      1.581V
692ps     1.471V     1.016V     1.613V
798ps     1.542V     1.283V     1.665V
951ps     1.612V     1.431V     1.718V
1.709ns   1.756V     1.646V     1.84V
10ns      1.8V       1.71V      1.891V
[Falling Waveform]
R_fixture = 50.000
V_fixture = 1.800
V_fixture_min = 1.710
V_fixture_max = 1.890
|  time   V(typ)   V(min)   V(max)
0s        1.8V       1.71V      1.891V
502ps     1.812V     1.71V      1.896V
770ps     1.799V     1.721V     1.89V
1.298ns   1.744V     1.675V     1.837V
1.901ns   1.633V     1.573V     1.727V
3.68ns    1.246V     1.188V     1.343V
4.358ns   1.149V     1.093V     1.229V
5.09ns    1.086V     1.033V     1.149V
6.644ns   1.028V     979.4mV    1.082V
10ns      1.002V     957.3mV    1.064V
[Falling Waveform]
R_fixture = 50.000
V_fixture = 0.000
V_fixture_min = 0.000
V_fixture_max = 0.000
|  time   V(typ)   V(min)   V(max)
0s        836.2mV    781.8mV    877.9mV
343ps     835.8mV    781.6mV    875.5mV
433ps     831.4mV    781.8mV    603.2mV
541ps     530.8mV    782.1mV    428.2mV
641ps     384.7mV    776.9mV    336.1mV
811ps     256.9mV    436.4mV    237.8mV
951ps     191.8mV    293.2mV    183.4mV
1.599ns   49.92mV    64.81mV    49.67mV
2.989ns   9.162mV    9.755mV    7.477mV
10ns      109.1uV    -50.23uV   -498.6uV
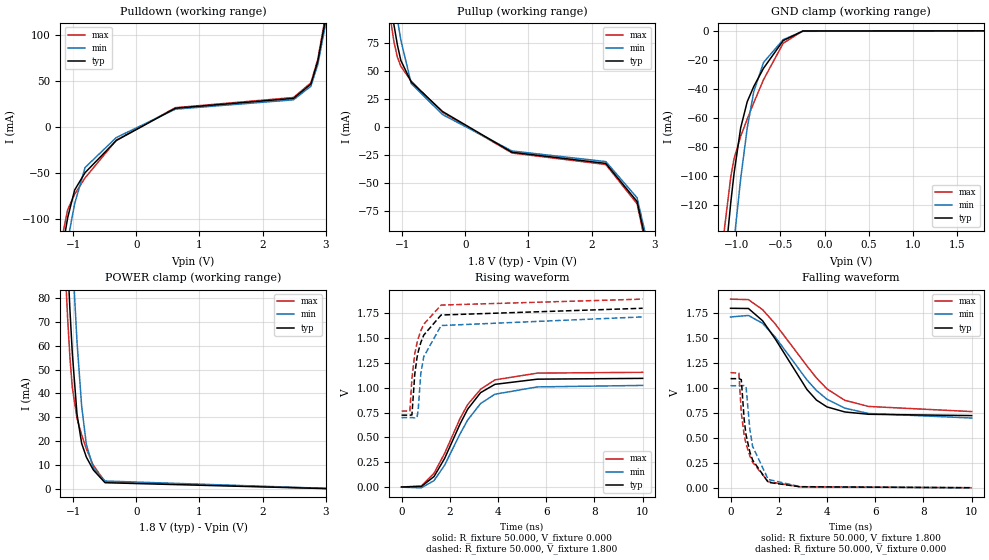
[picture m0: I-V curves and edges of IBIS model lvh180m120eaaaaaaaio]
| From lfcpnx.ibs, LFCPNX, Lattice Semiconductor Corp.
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[Model] lvh180m120eaaaaaaaio
Model_type I/O
Polarity   Non-Inverting
Enable   Active-Low
Vinl =  0.630V
Vinh =  1.170V
Vmeas =  0.900V
Cref =  0.0F
Rref =  1.000M
Vref =  0.0V
C_comp   5.000pF   4.000pF   5.500pF
[Temperature Range]   25.000   0.125k   -40.000
[Voltage Range]   1.800V   1.710V   1.890V
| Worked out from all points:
|   slope of the pulldown table from 0 to 0.27 V, typ, clamps not added: 23.9 ohm
|   slope of the pullup table from 0 to 0.27 V, typ, clamps not added: 26.8 ohm
|   GND clamp passes 1 mA (typ) near -0.32 V on its own axis
|   POWER clamp passes 1 mA (typ) near -0.38 V on its own axis
|   rising waveform, R_fixture 50.000, V_fixture 0.000: 20-80 % time 1.35ns typ, 1.44ns min, 1.46ns max; typ from 0 V to 1.09 V
|   rising waveform, R_fixture 50.000, V_fixture 1.800: 20-80 % time 545ps typ, 513ps min, 576ps max; typ from 0.723 V to 1.8 V
|   falling waveform, R_fixture 50.000, V_fixture 1.800: 20-80 % time 1.72ns typ, 2.05ns min, 2.23ns max; typ from 1.8 V to 0.723 V
|   falling waveform, R_fixture 50.000, V_fixture 0.000: 20-80 % time 505ps typ, 489ps min, 566ps max; typ from 1.09 V to 0 V
[GND_clamp]
|Voltage   I(typ)   I(min)   I(max)
-1.8V     -676.5mA   -711.8mA   -657.4mA
-1.171V   -188.8mA   -241.8mA   -160mA
-1.134V   -163.6mA   -216.3mA   -136.9mA
-1.06V    -117.6mA   -167.3mA   -100mA
-1.023V   -97.67mA   -144.1mA   -87.78mA
-949mV    -66.77mA   -101.8mA   -72.6mA
-875mV    -48.8mA    -66.89mA   -60.78mA
-801mV    -38.33mA   -41.86mA   -49.49mA
-690mV    -25.71mA   -21.72mA   -33.55mA
-468mV    -6.724mA   -6.036mA   -8.541mA
-246mV    -145.3uA   -325.1uA   -81.62uA
1.8V      0A         0A         0A
[POWER_clamp]
|Voltage   I(typ)   I(min)   I(max)
-1.8V     627.7mA    654.9mA    614.1mA
-1.16V    141.5mA    189mA      114.4mA
-1.123V   117.5mA    164.8mA    91.5mA
-1.086V   95.05mA    141.5mA    71.26mA
-1.049V   74.59mA    119.2mA    54.66mA
-1.012V   56.78mA    98.27mA    42.5mA
-938mV    31.33mA    61.69mA    29.59mA
-864mV    19.12mA    34.68mA    22.65mA
-790mV    13.42mA    18.68mA    16.91mA
-679mV    8.018mA    8.826mA    9.955mA
-494mV    2.695mA    3.4mA      3.109mA
3.6V      -185.9uA   -195.7uA   -188.2uA
[Pulldown]
|Voltage   I(typ)   I(min)   I(max)
-1.8V     -445.4mA   -451.9mA   -445.5mA
-1.195V   -142.7mA   -169.4mA   -127mA
-1.085V   -98.4mA    -123.5mA   -89.8mA
-975mV    -68.5mA    -83.4mA    -73.1mA
-810mV    -49.66mA   -44.08mA   -55.35mA
-315mV    -14.72mA   -11.48mA   -14.34mA
620mV     20.33mA    19.31mA    20.94mA
2.49V     31.02mA    29.46mA    31.95mA
2.765V    46.49mA    44.16mA    47.88mA
2.875V    71.4mA     67.8mA     73.5mA
2.985V    112.7mA    107.1mA    116.1mA
3.6V      414.1mA    393.4mA    426.5mA
[Pullup]
|Voltage   I(typ)   I(min)   I(max)
-1.8V     404.1mA    420.6mA    393.9mA
-1.24V    135.4mA    162.3mA    117.4mA
-1.13V    91.1mA     116.9mA    76mA
-1.075V   73.1mA     96.1mA     62.2mA
-1.02V    59.15mA    77.2mA     53.94mA
-855mV    39.87mA    38.6mA     40.71mA
-360mV    13.74mA    11mA       12.94mA
740mV     -22.53mA   -21.4mA    -23.2mA
2.225V    -32.45mA   -30.83mA   -33.42mA
2.72V     -66.33mA   -63.01mA   -68.32mA
2.885V    -108.4mA   -103mA     -111.7mA
3.6V      -492.6mA   -468mA     -507.4mA
[Ramp]
| variable   typ   min   max
dV/dt_r   0.658/1.362n   0.644/1.458n   0.694/1.480n
dV/dt_f   0.643/1.755n   0.605/2.076n   0.673/2.257n
R_load = 50.000
[Rising Waveform]
R_fixture = 50.000
V_fixture = 0.000
V_fixture_min = 0.000
V_fixture_max = 0.000
|  time   V(typ)   V(min)   V(max)
0s        101.8uV    -1.565mV   -169.2uV
819ps     4.995mV    -8.589mV   11.19mV
1.348ns   105.5mV    64.21mV    138.6mV
1.788ns   288.3mV    220.4mV    339.4mV
2.428ns   635.2mV    535.4mV    690.2mV
2.741ns   783.1mV    673.4mV    829.5mV
3.279ns   950.4mV    840.7mV    984.2mV
3.875ns   1.034V     934.6mV    1.079V
5.635ns   1.086V     1.008V     1.147V
10ns      1.094V     1.023V     1.155V
[Rising Waveform]
R_fixture = 50.000
V_fixture = 1.800
V_fixture_min = 1.710
V_fixture_max = 1.890
|  time   V(typ)   V(min)   V(max)
0s        723.4mV    699.1mV    763.8mV
346ps     723.3mV    699.1mV    766.1mV
431ps     725.6mV    699.4mV    1.091V
549ps     1.135V     695.6mV    1.342V
641ps     1.302V     697.5mV    1.45V
691ps     1.361V     776.3mV    1.495V
798ps     1.454V     1.138V     1.572V
922ps     1.53V      1.312V     1.639V
1.641ns   1.732V     1.626V     1.832V
10ns      1.8V       1.713V     1.892V
[Falling Waveform]
R_fixture = 50.000
V_fixture = 1.800
V_fixture_min = 1.710
V_fixture_max = 1.890
|  time   V(typ)   V(min)   V(max)
0s        1.8V       1.713V     1.892V
742ps     1.798V     1.728V     1.887V
1.325ns   1.676V     1.65V      1.787V
1.855ns   1.492V     1.511V     1.643V
3.17ns    984.9mV    1.081V     1.221V
3.561ns   879.5mV    975.8mV    1.102V
3.999ns   810.6mV    887mV      991mV
4.739ns   760mV      798.1mV    876.7mV
5.725ns   736.8mV    744.6mV    815.2mV
10ns      723.4mV    699.1mV    763.8mV
[Falling Waveform]
R_fixture = 50.000
V_fixture = 0.000
V_fixture_min = 0.000
V_fixture_max = 0.000
|  time   V(typ)   V(min)   V(max)
0s        1.094V     1.023V     1.155V
346ps     1.094V     1.023V     1.149V
446ps     1.084V     1.023V     751.7mV
565ps     684.9mV    1.025V     528.6mV
642ps     530.2mV    1.015V     440.4mV
800ps     358.1mV    587.5mV    318.1mV
915ps     277.3mV    414.5mV    255.3mV
1.562ns   53.6mV     83mV       60.56mV
2.879ns   9.383mV    10.72mV    8.852mV
10ns      101.8uV    -1.565mV   -169.2uV
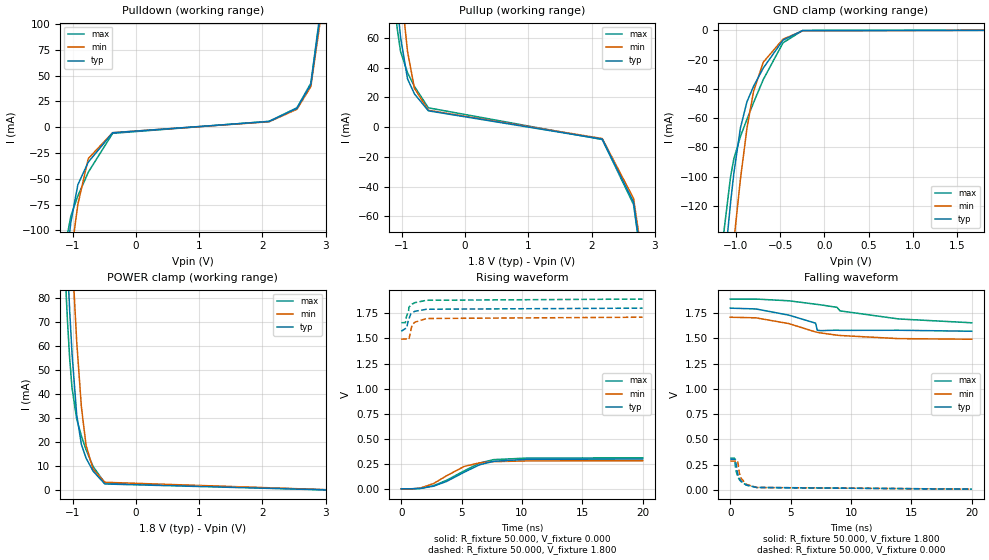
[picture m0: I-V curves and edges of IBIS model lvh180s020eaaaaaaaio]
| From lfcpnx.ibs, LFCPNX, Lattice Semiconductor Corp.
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[Model] lvh180s020eaaaaaaaio
Model_type I/O
Polarity   Non-Inverting
Enable   Active-Low
Vinl =  0.630V
Vinh =  1.170V
Vmeas =  0.900V
Cref =  0.0F
Rref =  1.000M
Vref =  0.0V
C_comp   5.000pF   4.000pF   5.500pF
[Temperature Range]   25.000   0.125k   -40.000
[Voltage Range]   1.800V   1.710V   1.890V
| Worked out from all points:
|   slope of the pulldown table from 0 to 0.27 V, typ, clamps not added: 114 ohm
|   slope of the pullup table from 0 to 0.27 V, typ, clamps not added: 128 ohm
|   GND clamp passes 1 mA (typ) near -0.32 V on its own axis
|   POWER clamp passes 1 mA (typ) near -0.38 V on its own axis
|   rising waveform, R_fixture 50.000, V_fixture 0.000: 20-80 % time 2.97ns typ, 2.5ns min, 2.94ns max; typ from 0.006 V to 0.302 V
|   rising waveform, R_fixture 50.000, V_fixture 1.800: 20-80 % time 445ps typ, 470ps min, 521ps max; typ from 1.57 V to 1.8 V
|   falling waveform, R_fixture 50.000, V_fixture 1.800: 20-80 % time 3.2ns typ, 4.47ns min, 6.51ns max; typ from 1.8 V to 1.57 V
|   falling waveform, R_fixture 50.000, V_fixture 0.000: 20-80 % time 563ps typ, 551ps min, 605ps max; typ from 0.302 V to 0.006 V
[GND_clamp]
|Voltage   I(typ)   I(min)   I(max)
-1.8V     -676.5mA   -711.8mA   -657.4mA
-1.171V   -188.8mA   -241.8mA   -160mA
-1.134V   -163.6mA   -216.3mA   -136.9mA
-1.06V    -117.6mA   -167.3mA   -100mA
-1.023V   -97.67mA   -144.1mA   -87.78mA
-949mV    -66.77mA   -101.8mA   -72.6mA
-875mV    -48.8mA    -66.89mA   -60.78mA
-801mV    -38.33mA   -41.86mA   -49.49mA
-690mV    -25.71mA   -21.72mA   -33.55mA
-468mV    -6.724mA   -6.036mA   -8.541mA
-246mV    -145.3uA   -325.1uA   -81.62uA
1.8V      0A         0A         0A
[POWER_clamp]
|Voltage   I(typ)   I(min)   I(max)
-1.8V     627.7mA    654.9mA    614.1mA
-1.16V    141.5mA    189mA      114.4mA
-1.123V   117.5mA    164.8mA    91.5mA
-1.086V   95.05mA    141.5mA    71.26mA
-1.049V   74.59mA    119.2mA    54.66mA
-1.012V   56.78mA    98.27mA    42.5mA
-938mV    31.33mA    61.69mA    29.59mA
-864mV    19.12mA    34.68mA    22.65mA
-790mV    13.42mA    18.68mA    16.91mA
-679mV    8.018mA    8.826mA    9.955mA
-494mV    2.695mA    3.4mA      3.109mA
3.6V      -185.9uA   -195.7uA   -188.2uA
[Pulldown]
|Voltage   I(typ)   I(min)   I(max)
-1.8V     -596.5mA   -588.3mA   -599.3mA
-1.14V    -149.6mA   -183.8mA   -130.4mA
-1.085V   -118.9mA   -153.6mA   -104mA
-1.03V    -92.1mA    -124.8mA   -85.94mA
-920mV    -55.8mA    -74.97mA   -66.68mA
-755mV    -33.91mA   -30.48mA   -43.69mA
-370mV    -5.454mA   -5.346mA   -6.032mA
2.105V    5.499mA    5.224mA    5.664mA
2.545V    18.24mA    17.32mA    18.78mA
2.765V    41.35mA    39.29mA    42.59mA
2.985V    140.5mA    133.5mA    144.7mA
3.6V      543.9mA    516.7mA    560.2mA
[Pullup]
|Voltage   I(typ)   I(min)   I(max)
-1.8V     556.2mA    580.5mA    544.4mA
-1.185V   144.1mA    185.3mA    121mA
-1.13V    112.6mA    153.6mA    91.2mA
-1.075V   84.2mA     123.5mA    67.08mA
-1.02V    60.53mA    95.7mA     51.03mA
-910mV    32.55mA    51.06mA    36.67mA
-800mV    22.37mA    26.11mA    27.37mA
-580mV    11mA       11.36mA    13.02mA
2.17V     -8.087mA   -7.683mA   -8.329mA
2.665V    -50.59mA   -48.06mA   -52.11mA
2.83V     -100.4mA   -95.4mA    -103.4mA
3.6V      -651.2mA   -618.6mA   -670.7mA
[Ramp]
| variable   typ   min   max
dV/dt_r   0.183/3.011n   0.167/2.520n   0.184/2.968n
dV/dt_f   0.137/4.262n   0.130/5.079n   0.141/7.314n
R_load = 50.000
[Rising Waveform]
R_fixture = 50.000
V_fixture = 0.000
V_fixture_min = 0.000
V_fixture_max = 0.000
|  time   V(typ)   V(min)   V(max)
0s        6.424mV    6.579mV    6.566mV
726ps     5.75mV     2.558mV    6.093mV
1.558ns   9.2mV      13.14mV    9.938mV
2.683ns   32.36mV    58.55mV    37.78mV
3.761ns   79.8mV     135.9mV    90.75mV
5.214ns   170.7mV    228.3mV    184.2mV
6.484ns   244.4mV    263.7mV    261.8mV
7.66ns    279.1mV    275.9mV    295.9mV
10.39ns   298.8mV    283.1mV    311.1mV
20ns      302.2mV    285.1mV    313.5mV
[Rising Waveform]
R_fixture = 50.000
V_fixture = 1.800
V_fixture_min = 1.710
V_fixture_max = 1.890
|  time   V(typ)   V(min)   V(max)
0s        1.571V     1.492V     1.655V
343ps     1.597V     1.493V     1.656V
434ps     1.599V     1.493V     1.717V
606ps     1.687V     1.488V     1.772V
636ps     1.694V     1.49V      1.808V
797ps     1.744V     1.579V     1.831V
888ps     1.753V     1.629V     1.839V
1.116ns   1.768V     1.66V      1.854V
2.096ns   1.789V     1.697V     1.878V
20ns      1.8V       1.71V      1.89V
[Falling Waveform]
R_fixture = 50.000
V_fixture = 1.800
V_fixture_min = 1.710
V_fixture_max = 1.890
|  time   V(typ)   V(min)   V(max)
0s        1.8V       1.71V      1.89V
2.125ns   1.792V     1.704V     1.89V
4.848ns   1.731V     1.647V     1.873V
7.073ns   1.651V     1.564V     1.839V
7.206ns   1.582V     1.561V     1.837V
7.471ns   1.577V     1.555V     1.833V
8.844ns   1.582V     1.532V     1.808V
9.095ns   1.58V      1.529V     1.773V
13.94ns   1.581V     1.498V     1.693V
20ns      1.571V     1.492V     1.655V
[Falling Waveform]
R_fixture = 50.000
V_fixture = 0.000
V_fixture_min = 0.000
V_fixture_max = 0.000
|  time   V(typ)   V(min)   V(max)
0s        302.2mV    285.1mV    313.5mV
336ps     301.7mV    284.8mV    314.3mV
426ps     302.8mV    285.1mV    230.5mV
499ps     242.4mV    284.7mV    178.6mV
615ps     157.8mV    287.5mV    133.4mV
745ps     114.4mV    170.8mV    102.8mV
874ps     88.7mV     118.9mV    82.72mV
1.32ns    47.15mV    54.81mV    47.34mV
2.195ns   22.44mV    23.04mV    23.86mV
20ns      6.424mV    6.579mV    6.566mV
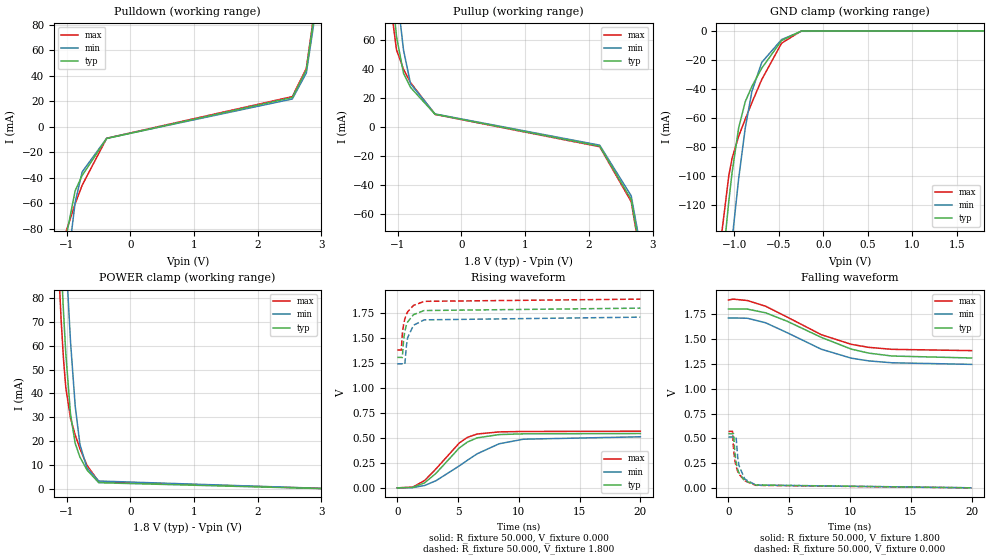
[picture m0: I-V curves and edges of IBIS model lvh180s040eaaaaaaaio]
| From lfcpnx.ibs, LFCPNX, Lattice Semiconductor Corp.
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[Model] lvh180s040eaaaaaaaio
Model_type I/O
Polarity   Non-Inverting
Enable   Active-Low
Vinl =  0.630V
Vinh =  1.170V
Vmeas =  0.900V
Cref =  0.0F
Rref =  1.000M
Vref =  0.0V
C_comp   5.000pF   4.000pF   5.500pF
[Temperature Range]   25.000   0.125k   -40.000
[Voltage Range]   1.800V   1.710V   1.890V
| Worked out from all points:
|   slope of the pulldown table from 0 to 0.27 V, typ, clamps not added: 53.9 ohm
|   slope of the pullup table from 0 to 0.27 V, typ, clamps not added: 67.5 ohm
|   GND clamp passes 1 mA (typ) near -0.32 V on its own axis
|   POWER clamp passes 1 mA (typ) near -0.38 V on its own axis
|   rising waveform, R_fixture 50.000, V_fixture 0.000: 20-80 % time 2.6ns typ, 4.02ns min, 2.54ns max; typ from 0.005 V to 0.547 V
|   rising waveform, R_fixture 50.000, V_fixture 1.800: 20-80 % time 567ps typ, 547ps min, 610ps max; typ from 1.31 V to 1.8 V
|   falling waveform, R_fixture 50.000, V_fixture 1.800: 20-80 % time 5.5ns typ, 5.11ns min, 5.17ns max; typ from 1.8 V to 1.31 V
|   falling waveform, R_fixture 50.000, V_fixture 0.000: 20-80 % time 561ps typ, 549ps min, 603ps max; typ from 0.547 V to 0.005 V
[GND_clamp]
|Voltage   I(typ)   I(min)   I(max)
-1.8V     -676.5mA   -711.8mA   -657.4mA
-1.171V   -188.8mA   -241.8mA   -160mA
-1.134V   -163.6mA   -216.3mA   -136.9mA
-1.06V    -117.6mA   -167.3mA   -100mA
-1.023V   -97.67mA   -144.1mA   -87.78mA
-949mV    -66.77mA   -101.8mA   -72.6mA
-875mV    -48.8mA    -66.89mA   -60.78mA
-801mV    -38.33mA   -41.86mA   -49.49mA
-690mV    -25.71mA   -21.72mA   -33.55mA
-468mV    -6.724mA   -6.036mA   -8.541mA
-246mV    -145.3uA   -325.1uA   -81.62uA
1.8V      0A         0A         0A
[POWER_clamp]
|Voltage   I(typ)   I(min)   I(max)
-1.8V     627.7mA    654.9mA    614.1mA
-1.16V    141.5mA    189mA      114.4mA
-1.123V   117.5mA    164.8mA    91.5mA
-1.086V   95.05mA    141.5mA    71.26mA
-1.049V   74.59mA    119.2mA    54.66mA
-1.012V   56.78mA    98.27mA    42.5mA
-938mV    31.33mA    61.69mA    29.59mA
-864mV    19.12mA    34.68mA    22.65mA
-790mV    13.42mA    18.68mA    16.91mA
-679mV    8.018mA    8.826mA    9.955mA
-494mV    2.695mA    3.4mA      3.109mA
3.6V      -185.9uA   -195.7uA   -188.2uA
[Pulldown]
|Voltage   I(typ)   I(min)   I(max)
-1.8V     -574.7mA   -585.3mA   -571.8mA
-1.195V   -177.7mA   -215.5mA   -156.2mA
-1.14V    -146.2mA   -184.6mA   -126.3mA
-1.03V    -92mA      -126.5mA   -85.59mA
-865mV    -50.11mA   -59.21mA   -60.22mA
-755mV    -38.07mA   -35.27mA   -45.74mA
-370mV    -9.08mA    -8.912mA   -8.864mA
2.545V    23.08mA    21.92mA    23.77mA
2.765V    44.55mA    42.32mA    45.88mA
2.875V    82.67mA    78.54mA    85.15mA
2.985V    139.6mA    132.6mA    143.8mA
3.6V      534.6mA    507.9mA    550.6mA
[Pullup]
|Voltage   I(typ)   I(min)   I(max)
-1.8V     534.8mA    558.2mA    522.8mA
-1.185V   140.5mA    179.8mA    117.9mA
-1.13V    110.8mA    149.6mA    89.9mA
-1.02V    62.15mA    94.7mA     53.03mA
-910mV    36.88mA    52.81mA    39.7mA
-800mV    27.18mA    29.74mA    30.53mA
-415mV    8.734mA    8.939mA    8.611mA
2.17V     -13.2mA    -12.54mA   -13.6mA
2.665V    -49.88mA   -47.38mA   -51.38mA
2.83V     -91.5mA    -86.9mA    -94.2mA
2.885V    -116.6mA   -110.8mA   -120.1mA
3.6V      -573.8mA   -545.1mA   -591mA
[Ramp]
| variable   typ   min   max
dV/dt_r   0.326/2.626n   0.306/4.025n   0.340/2.546n
dV/dt_f   0.295/5.549n   0.279/5.122n   0.305/5.194n
R_load = 50.000
[Rising Waveform]
R_fixture = 50.000
V_fixture = 0.000
V_fixture_min = 0.000
V_fixture_max = 0.000
|  time   V(typ)   V(min)   V(max)
0s        4.711mV    4.874mV    4.402mV
1.268ns   8.571mV    6.603mV    11.56mV
2.257ns   54.86mV    28mV       77.81mV
3.191ns   149.8mV    76.08mV    194.2mV
5.1ns     402.6mV    223.3mV    452.1mV
5.765ns   461.7mV    279.5mV    508.4mV
6.575ns   503.9mV    344.6mV    542.4mV
8.379ns   536.7mV    444.7mV    563.5mV
10.38ns   544.2mV    490.6mV    567.7mV
20ns      547.4mV    514.6mV    570.3mV
[Rising Waveform]
R_fixture = 50.000
V_fixture = 1.800
V_fixture_min = 1.710
V_fixture_max = 1.890
|  time   V(typ)   V(min)   V(max)
0s        1.308V     1.244V     1.382V
334ps     1.308V     1.244V     1.381V
419ps     1.306V     1.244V     1.539V
526ps     1.482V     1.243V     1.639V
627ps     1.57V      1.239V     1.692V
756ps     1.631V     1.424V     1.738V
858ps     1.662V     1.505V     1.763V
1.338ns   1.735V     1.629V     1.827V
2.217ns   1.776V     1.683V     1.868V
20ns      1.8V       1.71V      1.89V
[Falling Waveform]
R_fixture = 50.000
V_fixture = 1.800
V_fixture_min = 1.710
V_fixture_max = 1.890
|  time   V(typ)   V(min)   V(max)
0s        1.8V       1.71V      1.89V
383ps     1.8V       1.71V      1.899V
1.555ns   1.799V     1.707V     1.885V
3.05ns    1.762V     1.662V     1.828V
4.831ns   1.677V     1.562V     1.719V
7.64ns    1.515V     1.396V     1.542V
10.11ns   1.397V     1.306V     1.445V
11.54ns   1.357V     1.279V     1.415V
13.44ns   1.328V     1.26V      1.395V
20ns      1.308V     1.244V     1.382V
[Falling Waveform]
R_fixture = 50.000
V_fixture = 0.000
V_fixture_min = 0.000
V_fixture_max = 0.000
|  time   V(typ)   V(min)   V(max)
0s        547.4mV    514.6mV    570.3mV
333ps     546.9mV    514.4mV    572.5mV
421ps     550.3mV    514.6mV    389.5mV
529ps     358.3mV    514.4mV    279.3mV
629ps     259.3mV    513.9mV    220.8mV
765ps     187.6mV    309.7mV    168.7mV
859ps     155.4mV    230.5mV    143.5mV
1.339ns   76.61mV    93.17mV    75.63mV
2.245ns   33.25mV    32.37mV    29.94mV
20ns      4.711mV    4.874mV    4.402mV
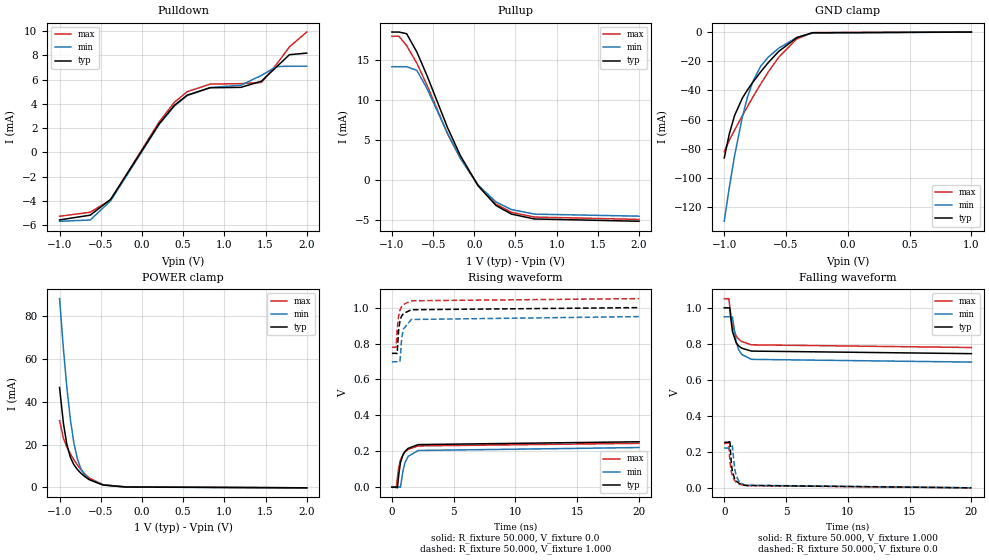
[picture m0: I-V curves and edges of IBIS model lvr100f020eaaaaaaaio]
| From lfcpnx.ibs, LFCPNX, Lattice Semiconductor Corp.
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[Model] lvr100f020eaaaaaaaio
Model_type I/O
Polarity   Non-Inverting
Enable   Active-Low
Vinl =  0.350V
Vinh =  0.650V
Vmeas =  0.500V
Cref =  0.0F
Rref =  1.000M
Vref =  0.0V
C_comp   5.000pF   4.000pF   5.500pF
[Temperature Range]   25.000   0.125k   -40.000
[Voltage Range]   1.000V   0.950V   1.050V
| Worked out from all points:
|   slope of the pulldown table from 0 to 0.15 V, typ, clamps not added: 92.9 ohm
|   slope of the pullup table from 0 to 0.15 V, typ, clamps not added: 72.1 ohm
|   GND clamp passes 1 mA (typ) near -0.32 V on its own axis
|   POWER clamp passes 1 mA (typ) near -0.46 V on its own axis
|   rising waveform, R_fixture 50.000, V_fixture 0.0: 20-80 % time 566ps typ, 582ps min, 605ps max; typ from 0 V to 0.253 V
|   rising waveform, R_fixture 50.000, V_fixture 1.000: 20-80 % time 290ps typ, 322ps min, 320ps max; typ from 0.745 V to 1 V
|   falling waveform, R_fixture 50.000, V_fixture 1.000: 20-80 % time 538ps typ, 561ps min, 601ps max; typ from 1 V to 0.745 V
|   falling waveform, R_fixture 50.000, V_fixture 0.0: 20-80 % time 337ps typ, 355ps min, 356ps max; typ from 0.253 V to 0 V
[Pulldown]
|Voltage   I(typ)   I(min)   I(max)
-1V       -5.55mA    -5.664mA   -5.252mA
-628mV    -5.162mA   -5.559mA   -4.921mA
-380mV    -3.86mA    -3.978mA   -3.898mA
209mV     2.367mA    2.32mA     2.518mA
395mV     3.894mA    3.835mA    4.146mA
550mV     4.724mA    4.688mA    5.009mA
829mV     5.331mA    5.352mA    5.632mA
1.201V    5.365mA    5.537mA    5.669mA
1.449V    5.866mA    6.347mA    5.764mA
1.635V    7.056mA    7.078mA    7.27mA
1.79V     8.055mA    7.107mA    8.699mA
2V        8.184mA    7.107mA    9.919mA
[Pullup]
|Voltage   I(typ)   I(min)   I(max)
-1V       18.53mA    14.19mA    18mA
-914mV    18.53mA    14.19mA    18mA
-821mV    18.32mA    14.19mA    16.83mA
-697mV    16.03mA    13.73mA    14.63mA
-573mV    13.06mA    11.44mA    11.86mA
-325mV    6.568mA    5.855mA    5.79mA
-170mV    3.091mA    2.731mA    2.764mA
47mV      -727.7uA   -628.1uA   -671.9uA
264mV     -3.188mA   -2.748mA   -3.005mA
450mV     -4.257mA   -3.692mA   -4.04mA
729mV     -4.871mA   -4.264mA   -4.632mA
2V        -5.161mA   -4.523mA   -4.928mA
[GND_clamp]
|Voltage   I(typ)   I(min)   I(max)
-1V       -86.39mA   -129.8mA   -82.1mA
-958mV    -69.62mA   -106.1mA   -74.12mA
-916mV    -57.21mA   -84.7mA    -67.22mA
-853mV    -45.26mA   -58.07mA   -57.38mA
-811mV    -39.58mA   -44.43mA   -50.99mA
-769mV    -34.5mA    -34.04mA   -44.75mA
-706mV    -27.42mA   -23.61mA   -35.76mA
-643mV    -20.91mA   -17.14mA   -27.32mA
-559mV    -13.28mA   -11.04mA   -17.29mA
-412mV    -3.804mA   -3.723mA   -4.655mA
-286mV    -477.7uA   -703.7uA   -396.2uA
1V        0A         0A         0A
[POWER_clamp]
|Voltage   I(typ)   I(min)   I(max)
-1V       46.74mA    88.29mA    31.25mA
-953mV    29.96mA    64.69mA    22.99mA
-911mV    20.02mA    46.58mA    18.81mA
-869mV    14.14mA    31.9mA     15.73mA
-827mV    10.71mA    20.96mA    13.03mA
-785mV    8.459mA    13.56mA    10.59mA
-743mV    6.733mA    8.952mA    8.425mA
-701mV    5.305mA    6.142mA    6.561mA
-638mV    3.604mA    3.771mA    4.35mA
-470mV    1.11mA     1.202mA    1.272mA
-197mV    214.8uA    168.4uA    281.4uA
2V        -171.9uA   -171.2uA   -177.1uA
[Ramp]
| variable   typ   min   max
dV/dt_r   0.152/0.569n   0.132/0.588n   0.146/0.610n
dV/dt_f   0.153/0.548n   0.151/0.557n   0.162/0.601n
R_load = 50.000
[Rising Waveform]
R_fixture= 50.000
V_fixture= 0.0
V_fixture_min= 0.0
V_fixture_max= 0.0
|time   V(typ)   V(min)   V(max)
0s        2.62uV     88.27uV    189.2nV
351ps     336.2uV    201.8uV    -2.238mV
449ps     -3.684mV   139.8uV    54.45mV
556ps     69.67mV    486.5uV    111mV
690ps     135.9mV    -708.4uV   150mV
900ps     180.7mV    92.15mV    182.1mV
1.064ns   199.3mV    137.4mV    196.6mV
1.314ns   216.1mV    171.6mV    210.4mV
2.133ns   237.1mV    204.3mV    229.7mV
20ns      252.8mV    220.7mV    244mV
[Rising Waveform]
R_fixture= 50.000
V_fixture= 1.000
V_fixture_min= 0.950
V_fixture_max= 1.050
|time   V(typ)   V(min)   V(max)
0s        745.1mV    698.1mV    779.2mV
336ps     745.4mV    698.3mV    778.6mV
426ps     743.9mV    698.2mV    877.8mV
544ps     874.6mV    697.7mV    955mV
645ps     923.1mV    698.4mV    983.5mV
695ps     936.1mV    734.8mV    992.8mV
785ps     951.9mV    824.9mV    1.005V
925ps     966.5mV    880.4mV    1.017V
1.575ns   988.1mV    933.8mV    1.038V
20ns      999.9mV    949.8mV    1.05V
[Falling Waveform]
R_fixture= 50.000
V_fixture= 1.000
V_fixture_min= 0.950
V_fixture_max= 1.050
|time   V(typ)   V(min)   V(max)
0s        1V         950mV      1.05V
370ps     999.5mV    949.9mV    1.051V
448ps     999.9mV    950mV      1.008V
546ps     933.9mV    949.6mV    947.8mV
663ps     869.4mV    949.3mV    900.7mV
963ps     806.4mV    811.9mV    843.8mV
1.156ns   789.1mV    769.3mV    826.6mV
1.413ns   775.9mV    741.1mV    812.8mV
2.202ns   759.5mV    713.6mV    794.3mV
20ns      745.3mV    698.4mV    779.4mV
[Falling Waveform]
R_fixture= 50.000
V_fixture= 0.0
V_fixture_min= 0.0
V_fixture_max= 0.0
|time   V(typ)   V(min)   V(max)
0s        253mV      221mV      244.2mV
362ps     253.2mV    220.7mV    252.2mV
452ps     265mV      220.8mV    151.8mV
572ps     138mV      223.9mV    88.14mV
660ps     90.94mV    233.1mV    65.89mV
839ps     52.07mV    108.8mV    41.42mV
960ps     39.03mV    66.96mV    32.25mV
1.23ns    23.73mV    32.3mV     20.7mV
1.67ns    13.71mV    14.75mV    12.07mV
20ns      171uV      268.6uV    125.2uV
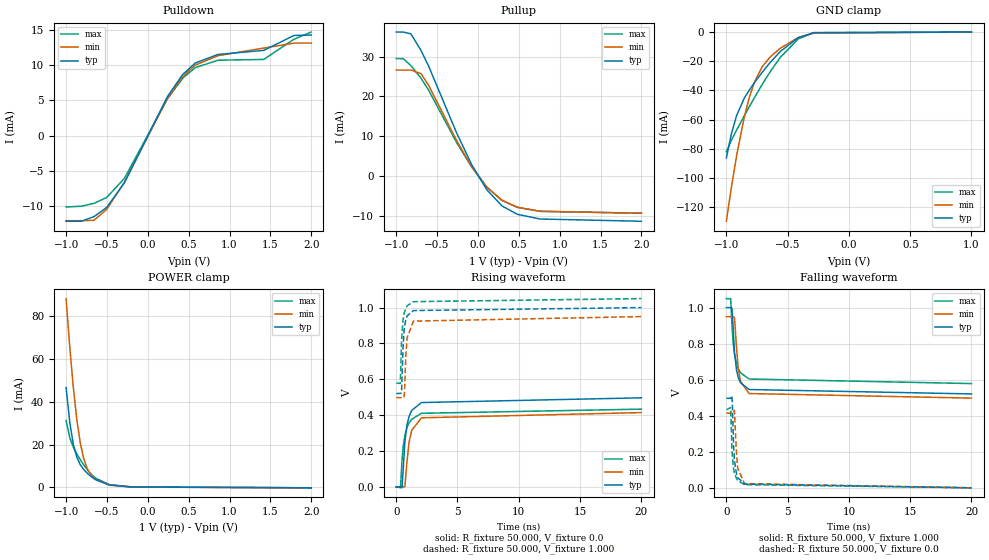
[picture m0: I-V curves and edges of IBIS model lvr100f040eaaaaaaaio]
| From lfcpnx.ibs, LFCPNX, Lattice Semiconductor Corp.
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|Model lvr100f040eaaaaaaaio
[Model] lvr100f040eaaaaaaaio
Model_type I/O
Polarity   Non-Inverting
Enable   Active-Low
Vinl =  0.350V
Vinh =  0.650V
Vmeas =  0.500V
Cref =  0.0F
Rref =  1.000M
Vref =  0.0V
C_comp   5.000pF   4.000pF   5.500pF
[Temperature Range]   25.000   0.125k   -40.000
[Voltage Range]   1.000V   0.950V   1.050V
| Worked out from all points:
|   slope of the pulldown table from 0 to 0.15 V, typ, clamps not added: 43.2 ohm
|   slope of the pullup table from 0 to 0.15 V, typ, clamps not added: 32.9 ohm
|   GND clamp passes 1 mA (typ) near -0.32 V on its own axis
|   POWER clamp passes 1 mA (typ) near -0.46 V on its own axis
|   rising waveform, R_fixture 50.000, V_fixture 0.0: 20-80 % time 503ps typ, 541ps min, 551ps max; typ from 0 V to 0.497 V
|   rising waveform, R_fixture 50.000, V_fixture 1.000: 20-80 % time 212ps typ, 250ps min, 230ps max; typ from 0.521 V to 1 V
|   falling waveform, R_fixture 50.000, V_fixture 1.000: 20-80 % time 409ps typ, 413ps min, 475ps max; typ from 1 V to 0.521 V
|   falling waveform, R_fixture 50.000, V_fixture 0.0: 20-80 % time 234ps typ, 259ps min, 249ps max; typ from 0.497 V to 0 V
[Pulldown]
|Voltage   I(typ)   I(min)   I(max)
-1V       -12.13mA   -12.05mA   -10.11mA
-814mV    -12.13mA   -12.05mA   -9.997mA
-659mV    -11.48mA   -11.99mA   -9.593mA
-504mV    -10.18mA   -10.46mA   -8.772mA
-287mV    -6.697mA   -6.622mA   -6.071mA
240mV     5.521mA    5.297mA    5.207mA
426mV     8.641mA    8.328mA    8.13mA
581mV     10.29mA    9.998mA    9.628mA
860mV     11.5mA     11.32mA    10.68mA
1.418V    12.07mA    12.4mA     10.79mA
1.79V     14.19mA    13.1mA     13.66mA
2V        14.25mA    13.1mA     14.67mA
[Pullup]
|Voltage   I(typ)   I(min)   I(max)
-1V       36.2mA     26.64mA    29.53mA
-914mV    36.2mA     26.64mA    29.5mA
-821mV    35.75mA    26.64mA    27.79mA
-697mV    31.61mA    25.76mA    24.6mA
-604mV    27.66mA    22.82mA    21.61mA
-263mV    10.94mA    9.018mA    8.495mA
-77mV     2.876mA    2.341mA    2.283mA
109mV     -3.469mA   -2.802mA   -2.801mA
295mV     -7.53mA    -6.091mA   -6.147mA
481mV     -9.618mA   -7.835mA   -7.878mA
760mV     -10.81mA   -8.885mA   -8.865mA
2V        -11.38mA   -9.351mA   -9.366mA
[GND_clamp]
|Voltage   I(typ)   I(min)   I(max)
-1V       -86.39mA   -129.8mA   -82.1mA
-958mV    -69.62mA   -106.1mA   -74.12mA
-916mV    -57.21mA   -84.7mA    -67.22mA
-853mV    -45.26mA   -58.07mA   -57.38mA
-811mV    -39.58mA   -44.43mA   -50.99mA
-769mV    -34.5mA    -34.04mA   -44.75mA
-706mV    -27.42mA   -23.61mA   -35.76mA
-643mV    -20.91mA   -17.14mA   -27.32mA
-559mV    -13.28mA   -11.04mA   -17.29mA
-412mV    -3.804mA   -3.723mA   -4.655mA
-286mV    -477.7uA   -703.7uA   -396.2uA
1V        0A         0A         0A
[POWER_clamp]
|Voltage   I(typ)   I(min)   I(max)
-1V       46.74mA    88.29mA    31.25mA
-953mV    29.96mA    64.69mA    22.99mA
-911mV    20.02mA    46.58mA    18.81mA
-869mV    14.14mA    31.9mA     15.73mA
-827mV    10.71mA    20.96mA    13.03mA
-785mV    8.459mA    13.56mA    10.59mA
-743mV    6.733mA    8.952mA    8.425mA
-701mV    5.305mA    6.142mA    6.561mA
-638mV    3.604mA    3.771mA    4.35mA
-470mV    1.11mA     1.202mA    1.272mA
-197mV    214.8uA    168.4uA    281.4uA
2V        -171.9uA   -171.2uA   -177.1uA
[Ramp]
| variable   typ   min   max
dV/dt_r   0.298/0.509n   0.249/0.546n   0.260/0.564n
dV/dt_f   0.287/0.410n   0.271/0.414n   0.283/0.482n
R_load = 50.000
[Rising Waveform]
R_fixture= 50.000
V_fixture= 0.0
V_fixture_min= 0.0
V_fixture_max= 0.0
|time   V(typ)   V(min)   V(max)
0s        1.832uV    62.7uV     140.5nV
351ps     467.7uV    130.8uV    -4.964mV
473ps     -5.581mV   166.1uV    146.6mV
567ps     94.64mV    709.5uV    223.5mV
707ps     250.5mV    -509.2uV   286.4mV
873ps     342.3mV    137.7mV    329mV
1.047ns   392mV      248mV      356.2mV
1.263ns   426.2mV    315mV      377.1mV
2.067ns   470.2mV    385.1mV    410.2mV
20ns      496.6mV    414.2mV    433.4mV
[Rising Waveform]
R_fixture= 50.000
V_fixture= 1.000
V_fixture_min= 0.950
V_fixture_max= 1.050
|time   V(typ)   V(min)   V(max)
0s        520.7mV    497.5mV    578.3mV
336ps     521mV      497.6mV    576.7mV
435ps     524.6mV    497.7mV    810.8mV
555ps     770.3mV    496.5mV    930.7mV
635ps     865.9mV    496.9mV    963.7mV
677ps     893.8mV    529.6mV    975.6mV
786ps     934.1mV    736.1mV    996.5mV
897ps     954.3mV    832.8mV    1.01V
1.407ns   983.4mV    924.4mV    1.033V
20ns      999.8mV    949.8mV    1.05V
[Falling Waveform]
R_fixture= 50.000
V_fixture= 1.000
V_fixture_min= 0.950
V_fixture_max= 1.050
|time   V(typ)   V(min)   V(max)
0s        1V         950mV      1.05V
356ps     999.7mV    949.9mV    1.049V
456ps     998mV      950mV      910.4mV
544ps     903.1mV    949.5mV    815.2mV
667ps     753mV      944.3mV    741.5mV
833ps     652mV      777.1mV    687.3mV
976ps     611.5mV    660.2mV    660.1mV
1.156ns   583.1mV    590.8mV    638.6mV
1.857ns   545.6mV    523.3mV    603.9mV
20ns      521.1mV    497.9mV    578.6mV
[Falling Waveform]
R_fixture= 50.000
V_fixture= 0.0
V_fixture_min= 0.0
V_fixture_max= 0.0
|time   V(typ)   V(min)   V(max)
0s        497mV      414.7mV    433.7mV
356ps     496.8mV    414.3mV    445.8mV
456ps     511.2mV    414.5mV    215.8mV
488ps     471.5mV    414.1mV    174.9mV
586ps     243.2mV    420.8mV    109.5mV
657ps     153.4mV    430.1mV    84.37mV
826ps     77.22mV    194.7mV    51.91mV
936ps     56.21mV    106.3mV    40.57mV
1.486ns   21.38mV    23.66mV    17.65mV
20ns      227.2uV    298.3uV    158.3uV
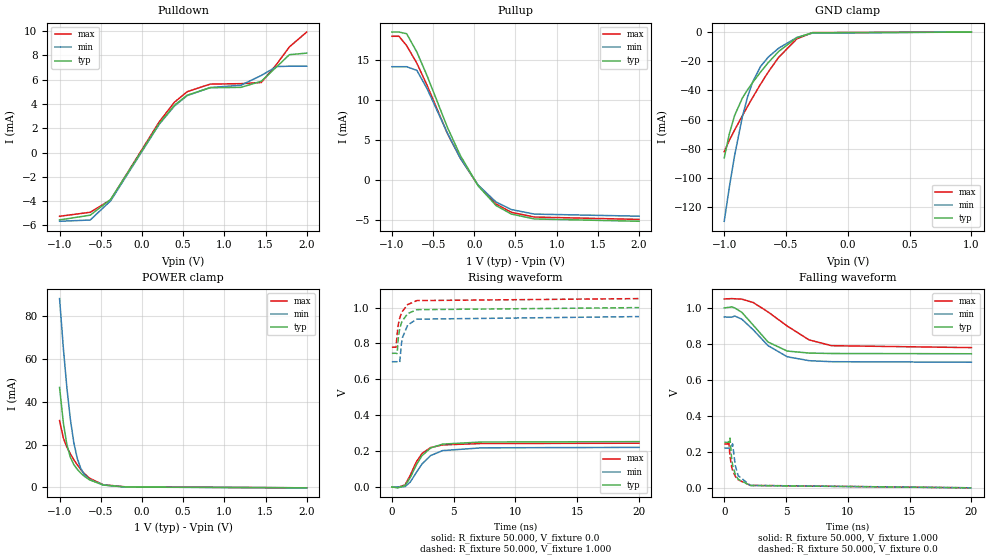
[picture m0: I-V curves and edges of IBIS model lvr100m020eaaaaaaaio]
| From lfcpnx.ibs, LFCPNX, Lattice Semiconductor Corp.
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|Model lvr100m020eaaaaaaaio
[Model] lvr100m020eaaaaaaaio
Model_type I/O
Polarity   Non-Inverting
Enable   Active-Low
Vinl =  0.350V
Vinh =  0.650V
Vmeas =  0.500V
Cref =  0.0F
Rref =  1.000M
Vref =  0.0V
C_comp   5.000pF   4.000pF   5.500pF
[Temperature Range]   25.000   0.125k   -40.000
[Voltage Range]   1.000V   0.950V   1.050V
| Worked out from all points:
|   slope of the pulldown table from 0 to 0.15 V, typ, clamps not added: 92.9 ohm
|   slope of the pullup table from 0 to 0.15 V, typ, clamps not added: 72.1 ohm
|   GND clamp passes 1 mA (typ) near -0.32 V on its own axis
|   POWER clamp passes 1 mA (typ) near -0.46 V on its own axis
|   rising waveform, R_fixture 50.000, V_fixture 0.0: 20-80 % time 1.34ns typ, 1.52ns min, 1.18ns max; typ from 0 V to 0.253 V
|   rising waveform, R_fixture 50.000, V_fixture 1.000: 20-80 % time 559ps typ, 532ps min, 596ps max; typ from 0.745 V to 1 V
|   falling waveform, R_fixture 50.000, V_fixture 1.000: 20-80 % time 2ns typ, 2.35ns min, 3.37ns max; typ from 1 V to 0.745 V
|   falling waveform, R_fixture 50.000, V_fixture 0.0: 20-80 % time 540ps typ, 534ps min, 622ps max; typ from 0.253 V to 0 V
[Pulldown]
|Voltage   I(typ)   I(min)   I(max)
-1V       -5.55mA    -5.663mA   -5.252mA
-628mV    -5.162mA   -5.559mA   -4.921mA
-380mV    -3.86mA    -3.978mA   -3.898mA
209mV     2.367mA    2.32mA     2.518mA
395mV     3.894mA    3.835mA    4.146mA
550mV     4.724mA    4.687mA    5.009mA
829mV     5.331mA    5.352mA    5.632mA
1.201V    5.365mA    5.537mA    5.669mA
1.449V    5.866mA    6.346mA    5.764mA
1.635V    7.056mA    7.077mA    7.27mA
1.79V     8.055mA    7.106mA    8.699mA
2V        8.184mA    7.106mA    9.919mA
[Pullup]
|Voltage   I(typ)   I(min)   I(max)
-1V       18.53mA    14.19mA    18mA
-914mV    18.53mA    14.19mA    18mA
-821mV    18.32mA    14.19mA    16.83mA
-697mV    16.03mA    13.73mA    14.63mA
-573mV    13.06mA    11.44mA    11.86mA
-325mV    6.568mA    5.855mA    5.79mA
-170mV    3.091mA    2.731mA    2.764mA
47mV      -727.7uA   -628.1uA   -671.9uA
264mV     -3.188mA   -2.748mA   -3.005mA
450mV     -4.257mA   -3.692mA   -4.04mA
729mV     -4.871mA   -4.264mA   -4.632mA
2V        -5.161mA   -4.523mA   -4.928mA
[GND_clamp]
|Voltage   I(typ)   I(min)   I(max)
-1V       -86.39mA   -129.8mA   -82.1mA
-958mV    -69.62mA   -106.1mA   -74.12mA
-916mV    -57.21mA   -84.7mA    -67.22mA
-853mV    -45.26mA   -58.07mA   -57.38mA
-811mV    -39.58mA   -44.43mA   -50.99mA
-769mV    -34.5mA    -34.04mA   -44.75mA
-706mV    -27.42mA   -23.61mA   -35.76mA
-643mV    -20.91mA   -17.14mA   -27.32mA
-559mV    -13.28mA   -11.04mA   -17.29mA
-412mV    -3.804mA   -3.723mA   -4.655mA
-286mV    -477.7uA   -703.7uA   -396.2uA
1V        0A         0A         0A
[POWER_clamp]
|Voltage   I(typ)   I(min)   I(max)
-1V       46.74mA    88.29mA    31.25mA
-953mV    29.96mA    64.69mA    22.99mA
-911mV    20.02mA    46.58mA    18.81mA
-869mV    14.14mA    31.9mA     15.73mA
-827mV    10.71mA    20.96mA    13.03mA
-785mV    8.459mA    13.56mA    10.59mA
-743mV    6.733mA    8.952mA    8.425mA
-701mV    5.305mA    6.142mA    6.561mA
-638mV    3.604mA    3.771mA    4.35mA
-470mV    1.11mA     1.202mA    1.272mA
-197mV    214.8uA    168.4uA    281.4uA
2V        -171.9uA   -171.2uA   -177.1uA
[Ramp]
| variable   typ   min   max
dV/dt_r   0.152/1.332n   0.132/1.532n   0.146/1.195n
dV/dt_f   0.153/2.048n   0.151/2.436n   0.162/3.378n
R_load = 50.000
[Rising Waveform]
R_fixture= 50.000
V_fixture= 0.0
V_fixture_min= 0.0
V_fixture_max= 0.0
|time   V(typ)   V(min)   V(max)
0s        2.62uV     88.27uV    189.2nV
483ps     -4.721mV   190.9uV    -2.095mV
1.069ns   8.704mV    2.249mV    11.79mV
1.487ns   52.53mV    27.66mV    65.82mV
1.99ns    124.5mV    82.22mV    141.6mV
2.439ns   174.8mV    128.5mV    186.8mV
3.141ns   217.6mV    175.4mV    220mV
4.099ns   239mV      202.8mV    234.6mV
7.276ns   250.8mV    218.3mV    242.4mV
20ns      252.7mV    220.7mV    244mV
[Rising Waveform]
R_fixture= 50.000
V_fixture= 1.000
V_fixture_min= 0.950
V_fixture_max= 1.050
|time   V(typ)   V(min)   V(max)
0s        745.1mV    698.1mV    779.2mV
336ps     745.5mV    698.3mV    779.3mV
425ps     743.6mV    698.2mV    853.1mV
524ps     834.7mV    698mV      908.9mV
635ps     883.3mV    695.3mV    941.8mV
765ps     913.3mV    793.3mV    966.8mV
845ps     926.3mV    831.1mV    978.4mV
1.284ns   966.6mV    903.1mV    1.017V
2.015ns   988.3mV    935.4mV    1.039V
20ns      999.9mV    949.8mV    1.05V
[Falling Waveform]
R_fixture= 50.000
V_fixture= 1.000
V_fixture_min= 0.950
V_fixture_max= 1.050
|time   V(typ)   V(min)   V(max)
0s        1V         950mV      1.05V
616ps     1.006V     948.9mV    1.052V
851ps     1V         955.1mV    1.051V
1.426ns   975.7mV    937.7mV    1.049V
2.351ns   904.1mV    878.3mV    1.03V
3.544ns   810.7mV    790.6mV    978.1mV
5.1ns     760.4mV    728.7mV    899.3mV
6.875ns   749.3mV    707mV      822.3mV
8.687ns   746.9mV    701.3mV    790.3mV
20ns      745.4mV    698.4mV    779.5mV
[Falling Waveform]
R_fixture= 50.000
V_fixture= 0.0
V_fixture_min= 0.0
V_fixture_max= 0.0
|time   V(typ)   V(min)   V(max)
0s        253mV      221mV      244.2mV
283ps     253mV      220.7mV    243.8mV
362ps     253.1mV    220.7mV    264.8mV
466ps     276.5mV    220.7mV    176.4mV
589ps     171.7mV    228.4mV    120.3mV
676ps     127.5mV    244.5mV    97.75mV
899ps     74.69mV    122.4mV    63.46mV
1.126ns   47.62mV    67.83mV    44.74mV
2.119ns   12.81mV    13.59mV    13.83mV
20ns      175.5uV    270.5uV    127.7uV
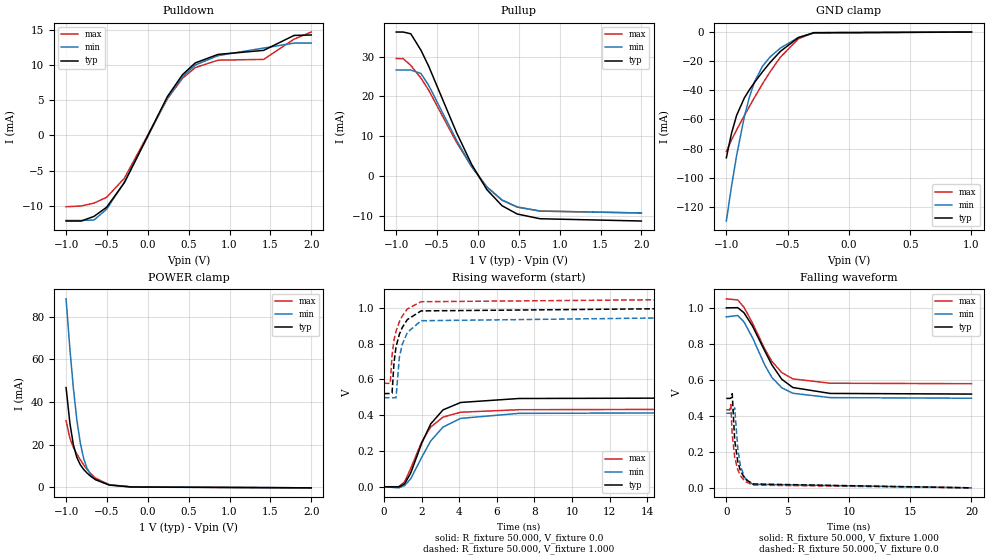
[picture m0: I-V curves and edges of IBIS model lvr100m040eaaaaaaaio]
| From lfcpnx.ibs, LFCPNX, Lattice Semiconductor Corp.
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|Model lvr100m040eaaaaaaaio
[Model] lvr100m040eaaaaaaaio
Model_type I/O
Polarity   Non-Inverting
Enable   Active-Low
Vinl =  0.350V
Vinh =  0.650V
Vmeas =  0.500V
Cref =  0.0F
Rref =  1.000M
Vref =  0.0V
C_comp   5.000pF   4.000pF   5.500pF
[Temperature Range]   25.000   0.125k   -40.000
[Voltage Range]   1.000V   0.950V   1.050V
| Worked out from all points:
|   slope of the pulldown table from 0 to 0.15 V, typ, clamps not added: 43.2 ohm
|   slope of the pullup table from 0 to 0.15 V, typ, clamps not added: 32.9 ohm
|   GND clamp passes 1 mA (typ) near -0.32 V on its own axis
|   POWER clamp passes 1 mA (typ) near -0.46 V on its own axis
|   rising waveform, R_fixture 50.000, V_fixture 0.0: 20-80 % time 1.29ns typ, 1.48ns min, 1.23ns max; typ from 0 V to 0.497 V
|   rising waveform, R_fixture 50.000, V_fixture 1.000: 20-80 % time 558ps typ, 517ps min, 592ps max; typ from 0.521 V to 1 V
|   falling waveform, R_fixture 50.000, V_fixture 1.000: 20-80 % time 2.26ns typ, 2.04ns min, 2.2ns max; typ from 1 V to 0.521 V
|   falling waveform, R_fixture 50.000, V_fixture 0.0: 20-80 % time 553ps typ, 505ps min, 573ps max; typ from 0.497 V to 0 V
[Pulldown]
|Voltage   I(typ)   I(min)   I(max)
-1V       -12.13mA   -12.05mA   -10.11mA
-814mV    -12.13mA   -12.05mA   -9.997mA
-659mV    -11.48mA   -11.99mA   -9.593mA
-504mV    -10.18mA   -10.46mA   -8.772mA
-287mV    -6.697mA   -6.622mA   -6.071mA
240mV     5.521mA    5.297mA    5.207mA
426mV     8.641mA    8.328mA    8.13mA
581mV     10.29mA    9.997mA    9.628mA
860mV     11.5mA     11.32mA    10.68mA
1.418V    12.07mA    12.4mA     10.79mA
1.79V     14.19mA    13.1mA     13.66mA
2V        14.25mA    13.1mA     14.67mA
[Pullup]
|Voltage   I(typ)   I(min)   I(max)
-1V       36.2mA     26.64mA    29.53mA
-914mV    36.2mA     26.64mA    29.5mA
-821mV    35.75mA    26.64mA    27.79mA
-697mV    31.61mA    25.76mA    24.6mA
-604mV    27.66mA    22.82mA    21.61mA
-263mV    10.94mA    9.018mA    8.495mA
-77mV     2.876mA    2.341mA    2.283mA
109mV     -3.469mA   -2.802mA   -2.801mA
295mV     -7.53mA    -6.091mA   -6.147mA
481mV     -9.618mA   -7.835mA   -7.878mA
760mV     -10.81mA   -8.885mA   -8.865mA
2V        -11.38mA   -9.351mA   -9.366mA
[GND_clamp]
|Voltage   I(typ)   I(min)   I(max)
-1V       -86.39mA   -129.8mA   -82.1mA
-958mV    -69.62mA   -106.1mA   -74.12mA
-916mV    -57.21mA   -84.7mA    -67.22mA
-853mV    -45.26mA   -58.07mA   -57.38mA
-811mV    -39.58mA   -44.43mA   -50.99mA
-769mV    -34.5mA    -34.04mA   -44.75mA
-706mV    -27.42mA   -23.61mA   -35.76mA
-643mV    -20.91mA   -17.14mA   -27.32mA
-559mV    -13.28mA   -11.04mA   -17.29mA
-412mV    -3.804mA   -3.723mA   -4.655mA
-286mV    -477.7uA   -703.7uA   -396.2uA
1V        0A         0A         0A
[POWER_clamp]
|Voltage   I(typ)   I(min)   I(max)
-1V       46.74mA    88.29mA    31.25mA
-953mV    29.96mA    64.69mA    22.99mA
-911mV    20.02mA    46.58mA    18.81mA
-869mV    14.14mA    31.9mA     15.73mA
-827mV    10.71mA    20.96mA    13.03mA
-785mV    8.459mA    13.56mA    10.59mA
-743mV    6.733mA    8.952mA    8.425mA
-701mV    5.305mA    6.142mA    6.561mA
-638mV    3.604mA    3.771mA    4.35mA
-470mV    1.11mA     1.202mA    1.272mA
-197mV    214.8uA    168.4uA    281.4uA
2V        -171.9uA   -171.2uA   -177.1uA
[Ramp]
| variable   typ   min   max
dV/dt_r   0.298/1.301n   0.248/1.498n   0.260/1.230n
dV/dt_f   0.287/2.366n   0.271/2.097n   0.283/2.266n
R_load = 50.000
[Rising Waveform]
R_fixture= 50.000
V_fixture= 0.0
V_fixture_min= 0.0
V_fixture_max= 0.0
|time   V(typ)   V(min)   V(max)
0s        1.832uV    62.7uV     140.5nV
787ps     -1.23mV    -6.12mV    409.6uV
1.095ns   16.05mV    6.609mV    27.13mV
1.427ns   77.52mV    45.13mV    103.4mV
2.008ns   243.3mV    164.6mV    251.4mV
2.485ns   351.1mV    255.6mV    333.7mV
3.141ns   429.6mV    333.9mV    389.2mV
4.081ns   471mV      382.1mV    416.5mV
7.169ns   493.2mV    410.1mV    430.6mV
20ns      496.6mV    414.2mV    433.4mV
[Rising Waveform]
R_fixture= 50.000
V_fixture= 1.000
V_fixture_min= 0.950
V_fixture_max= 1.050
|time   V(typ)   V(min)   V(max)
0s        520.7mV    497.5mV    578.3mV
336ps     521.1mV    497.6mV    577.6mV
431ps     522.8mV    497.7mV    734.9mV
534ps     692.7mV    497mV      819.2mV
641ps     781mV      497.3mV    869.3mV
821ps     852.7mV    723.9mV    922.4mV
974ps     889.7mV    796mV      953.7mV
1.243ns   934.3mV    861.9mV    993.6mV
1.971ns   982.7mV    927.8mV    1.034V
20ns      999.8mV    949.8mV    1.05V
[Falling Waveform]
R_fixture= 50.000
V_fixture= 1.000
V_fixture_min= 0.950
V_fixture_max= 1.050
|time   V(typ)   V(min)   V(max)
0s        1V         950mV      1.05V
927ps     1.001V     957.6mV    1.044V
1.433ns   973.6mV    922.5mV    1.004V
2.142ns   898.1mV    833.6mV    914.5mV
3.141ns   760.1mV    681.4mV    771.3mV
3.707ns   684.5mV    614.3mV    703.6mV
4.528ns   603mV      555.7mV    640.3mV
5.426ns   557.5mV    525.6mV    605.5mV
8.468ns   524.7mV    501.4mV    581.4mV
20ns      521.1mV    497.9mV    578.7mV
[Falling Waveform]
R_fixture= 50.000
V_fixture= 0.0
V_fixture_min= 0.0
V_fixture_max= 0.0
|time   V(typ)   V(min)   V(max)
0s        497mV      414.7mV    433.7mV
283ps     497mV      414.4mV    433.2mV
369ps     497.8mV    414.3mV    462.3mV
479ps     523mV      414.1mV    295.8mV
683ps     264.2mV    444.5mV    169.4mV
933ps     145.2mV    218.7mV    101.6mV
1.153ns   94.88mV    121.6mV    67.24mV
1.523ns   49.87mV    54.23mV    36.13mV
2.15ns    21.77mV    19.85mV    15.54mV
20ns      231.5uV    301.4uV    161.9uV
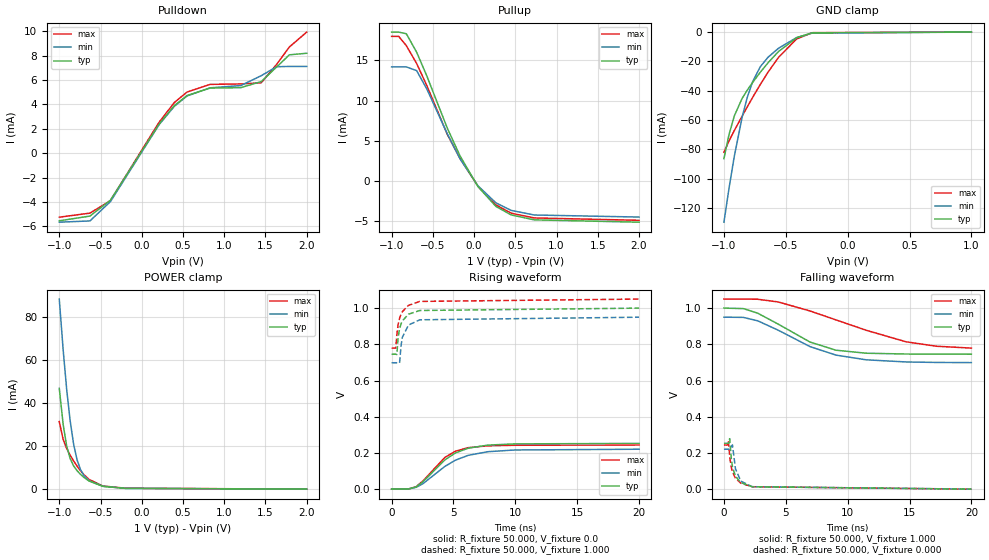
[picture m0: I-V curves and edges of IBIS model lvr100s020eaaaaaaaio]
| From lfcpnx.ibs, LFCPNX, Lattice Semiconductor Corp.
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|Model lvr100s020eaaaaaaaio
[Model] lvr100s020eaaaaaaaio
Model_type I/O
Polarity   Non-Inverting
Enable   Active-Low
Vinl =  0.350V
Vinh =  0.650V
Vmeas =  0.500V
Cref =  0.0F
Rref =  1.000M
Vref =  0.0V
C_comp   5.000pF   4.000pF   5.500pF
[Temperature Range]   25.000   0.125k   -40.000
[Voltage Range]   1.000V   0.950V   1.050V
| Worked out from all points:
|   slope of the pulldown table from 0 to 0.15 V, typ, clamps not added: 92.9 ohm
|   slope of the pullup table from 0 to 0.15 V, typ, clamps not added: 72.1 ohm
|   GND clamp passes 1 mA (typ) near -0.32 V on its own axis
|   POWER clamp passes 1 mA (typ) near -0.46 V on its own axis
|   rising waveform, R_fixture 50.000, V_fixture 0.0: 20-80 % time 2.54ns typ, 2.91ns min, 2.16ns max; typ from 0 V to 0.253 V
|   rising waveform, R_fixture 50.000, V_fixture 1.000: 20-80 % time 580ps typ, 555ps min, 620ps max; typ from 0.745 V to 1 V
|   falling waveform, R_fixture 50.000, V_fixture 1.000: 20-80 % time 4.1ns typ, 4.79ns min, 7.13ns max; typ from 1 V to 0.746 V
|   falling waveform, R_fixture 50.000, V_fixture 0.000: 20-80 % time 577ps typ, 567ps min, 622ps max; typ from 0.253 V to 0 V
[Pulldown]
|Voltage   I(typ)   I(min)   I(max)
-1V       -5.55mA    -5.663mA   -5.252mA
-628mV    -5.162mA   -5.559mA   -4.921mA
-380mV    -3.86mA    -3.977mA   -3.898mA
209mV     2.367mA    2.32mA     2.518mA
395mV     3.894mA    3.835mA    4.146mA
550mV     4.724mA    4.687mA    5.009mA
829mV     5.331mA    5.351mA    5.632mA
1.201V    5.364mA    5.536mA    5.669mA
1.449V    5.866mA    6.346mA    5.764mA
1.635V    7.056mA    7.077mA    7.27mA
1.79V     8.055mA    7.106mA    8.699mA
2V        8.184mA    7.106mA    9.919mA
[Pullup]
|Voltage   I(typ)   I(min)   I(max)
-1V       18.53mA    14.19mA    18mA
-914mV    18.53mA    14.19mA    18mA
-821mV    18.32mA    14.19mA    16.83mA
-697mV    16.03mA    13.73mA    14.63mA
-573mV    13.06mA    11.44mA    11.86mA
-325mV    6.568mA    5.855mA    5.79mA
-170mV    3.091mA    2.731mA    2.764mA
47mV      -727.7uA   -628.1uA   -671.9uA
264mV     -3.188mA   -2.748mA   -3.005mA
450mV     -4.257mA   -3.691mA   -4.04mA
729mV     -4.871mA   -4.264mA   -4.632mA
2V        -5.161mA   -4.522mA   -4.928mA
[GND_clamp]
|Voltage   I(typ)   I(min)   I(max)
-1V       -86.39mA   -129.8mA   -82.1mA
-958mV    -69.62mA   -106.1mA   -74.12mA
-916mV    -57.21mA   -84.7mA    -67.22mA
-853mV    -45.26mA   -58.07mA   -57.38mA
-811mV    -39.58mA   -44.43mA   -50.99mA
-769mV    -34.5mA    -34.04mA   -44.75mA
-706mV    -27.42mA   -23.61mA   -35.76mA
-643mV    -20.91mA   -17.14mA   -27.32mA
-559mV    -13.28mA   -11.04mA   -17.29mA
-412mV    -3.804mA   -3.723mA   -4.655mA
-286mV    -477.7uA   -703.7uA   -396.2uA
1V        0A         0A         0A
[POWER_clamp]
|Voltage   I(typ)   I(min)   I(max)
-1V       46.74mA    88.29mA    31.25mA
-953mV    29.96mA    64.69mA    22.99mA
-911mV    20.02mA    46.58mA    18.81mA
-869mV    14.14mA    31.9mA     15.73mA
-827mV    10.71mA    20.96mA    13.03mA
-785mV    8.459mA    13.56mA    10.59mA
-743mV    6.733mA    8.952mA    8.425mA
-701mV    5.305mA    6.142mA    6.561mA
-638mV    3.604mA    3.771mA    4.35mA
-470mV    1.11mA     1.202mA    1.272mA
-197mV    214.8uA    168.4uA    281.4uA
2V        -171.9uA   -171.2uA   -177.1uA
[Ramp]
| variable   typ   min   max
dV/dt_r   0.152/2.525n   0.132/2.890n   0.146/2.193n
dV/dt_f   0.153/4.124n   0.151/4.817n   0.160/7.147n
R_load = 50.000
[Rising Waveform]
R_fixture= 50.000
V_fixture= 0.0
V_fixture_min= 0.0
V_fixture_max= 0.0
|time   V(typ)   V(min)   V(max)
0s        2.62uV     88.27uV    189.2nV
1.334ns   585.4uV    482.8uV    557.1uV
1.984ns   12.88mV    10.15mV    13.54mV
2.54ns    40.87mV    30.52mV    45.91mV
4.305ns   161.7mV    125.8mV    175.4mV
5.172ns   200.4mV    160.6mV    209.8mV
6.195ns   226.3mV    186.9mV    229.3mV
7.765ns   243.3mV    206.8mV    239.4mV
9.954ns   250.1mV    216.4mV    242.5mV
20ns      252.7mV    220.6mV    243.9mV
[Rising Waveform]
R_fixture= 50.000
V_fixture= 1.000
V_fixture_min= 0.950
V_fixture_max= 1.050
|time   V(typ)   V(min)   V(max)
0s        745.1mV    698.1mV    779.2mV
336ps     745.5mV    698.3mV    779.3mV
425ps     743.5mV    698.2mV    853.1mV
526ps     836.1mV    698mV      909.7mV
642ps     885.6mV    696.5mV    943.5mV
772ps     914.6mV    797.8mV    967.8mV
871ps     929.6mV    839.3mV    980.9mV
1.361ns   966.1mV    906.4mV    1.015V
2.275ns   986.9mV    935.5mV    1.037V
20ns      999.9mV    949.8mV    1.05V
[Falling Waveform]
R_fixture = 50.000
V_fixture = 1.000
V_fixture_min = 0.950
V_fixture_max = 1.050
|  time   V(typ)   V(min)   V(max)
0s        1V         950mV      1.05V
1.567ns   997.4mV    948.8mV    1.05V
2.729ns   972mV      929.9mV    1.049V
4.391ns   911.5mV    877.9mV    1.034V
6.951ns   812.8mV    787.6mV    984.3mV
9.055ns   767.5mV    740.5mV    935mV
11.51ns   750.9mV    714.4mV    877.4mV
14.72ns   746.5mV    702.7mV    814mV
17.16ns   745.8mV    700mV      789.5mV
20ns      745.5mV    699mV      779.2mV
[Falling Waveform]
R_fixture = 50.000
V_fixture = 0.000
V_fixture_min = 0.000
V_fixture_max = 0.000
|  time   V(typ)   V(min)   V(max)
0s        253mV      221mV      244.2mV
283ps     253mV      220.7mV    243.8mV
362ps     253.1mV    220.6mV    266.8mV
464ps     278.9mV    220.7mV    179.4mV
593ps     170.3mV    229.7mV    119.8mV
688ps     124.1mV    244.8mV    95.72mV
928ps     72.14mV    113.5mV    60.68mV
1.363ns   36.23mV    44.69mV    33.1mV
2.279ns   13.58mV    13.79mV    13.55mV
20ns      176.5uV    271.8uV    133uV
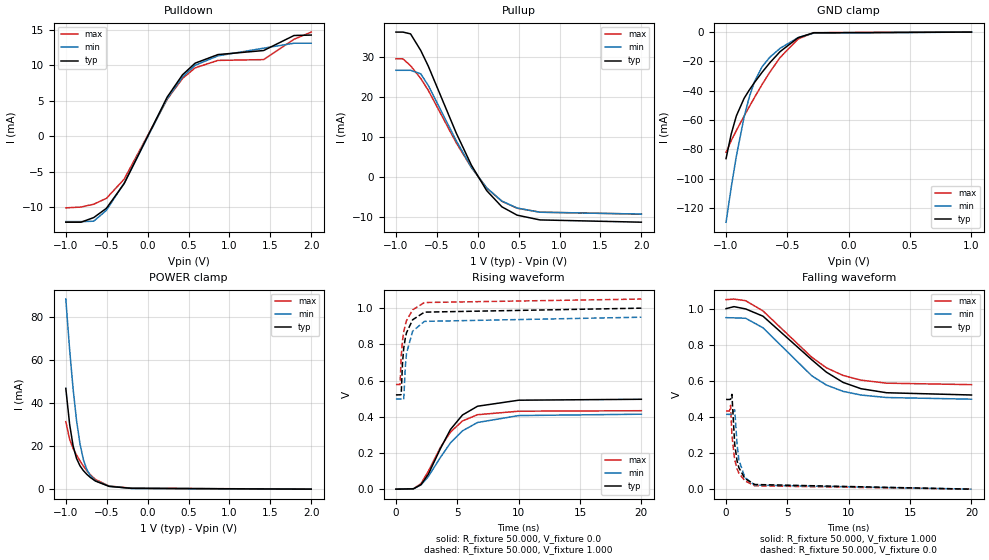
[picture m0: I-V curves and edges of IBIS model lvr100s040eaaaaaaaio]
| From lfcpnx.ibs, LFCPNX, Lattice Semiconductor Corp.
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|Model lvr100s040eaaaaaaaio
[Model] lvr100s040eaaaaaaaio
Model_type I/O
Polarity   Non-Inverting
Enable   Active-Low
Vinl =  0.350V
Vinh =  0.650V
Vmeas =  0.500V
Cref =  0.0F
Rref =  1.000M
Vref =  0.0V
C_comp   5.000pF   4.000pF   5.500pF
[Temperature Range]   25.000   0.125k   -40.000
[Voltage Range]   1.000V   0.950V   1.050V
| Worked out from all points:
|   slope of the pulldown table from 0 to 0.15 V, typ, clamps not added: 43.2 ohm
|   slope of the pullup table from 0 to 0.15 V, typ, clamps not added: 32.9 ohm
|   GND clamp passes 1 mA (typ) near -0.32 V on its own axis
|   POWER clamp passes 1 mA (typ) near -0.46 V on its own axis
|   rising waveform, R_fixture 50.000, V_fixture 0.0: 20-80 % time 2.46ns typ, 2.83ns min, 2.32ns max; typ from 0 V to 0.496 V
|   rising waveform, R_fixture 50.000, V_fixture 1.000: 20-80 % time 580ps typ, 553ps min, 623ps max; typ from 0.521 V to 1 V
|   falling waveform, R_fixture 50.000, V_fixture 1.000: 20-80 % time 4.79ns typ, 4.26ns min, 4.61ns max; typ from 1 V to 0.522 V
|   falling waveform, R_fixture 50.000, V_fixture 0.0: 20-80 % time 578ps typ, 565ps min, 619ps max; typ from 0.497 V to 0 V
[Pulldown]
|Voltage   I(typ)   I(min)   I(max)
-1V       -12.13mA   -12.05mA   -10.11mA
-814mV    -12.13mA   -12.05mA   -9.997mA
-659mV    -11.48mA   -11.99mA   -9.593mA
-504mV    -10.18mA   -10.46mA   -8.772mA
-287mV    -6.697mA   -6.622mA   -6.071mA
240mV     5.521mA    5.297mA    5.207mA
426mV     8.641mA    8.328mA    8.13mA
581mV     10.29mA    9.997mA    9.628mA
860mV     11.5mA     11.32mA    10.68mA
1.418V    12.07mA    12.4mA     10.79mA
1.79V     14.19mA    13.1mA     13.66mA
2V        14.25mA    13.1mA     14.67mA
[Pullup]
|Voltage   I(typ)   I(min)   I(max)
-1V       36.2mA     26.64mA    29.53mA
-914mV    36.2mA     26.64mA    29.5mA
-821mV    35.75mA    26.64mA    27.79mA
-697mV    31.61mA    25.76mA    24.6mA
-604mV    27.66mA    22.82mA    21.61mA
-263mV    10.94mA    9.018mA    8.495mA
-77mV     2.876mA    2.341mA    2.283mA
109mV     -3.469mA   -2.802mA   -2.801mA
295mV     -7.53mA    -6.091mA   -6.147mA
481mV     -9.618mA   -7.835mA   -7.878mA
760mV     -10.81mA   -8.885mA   -8.865mA
2V        -11.38mA   -9.351mA   -9.366mA
[GND_clamp]
|Voltage   I(typ)   I(min)   I(max)
-1V       -86.39mA   -129.8mA   -82.1mA
-958mV    -69.62mA   -106.1mA   -74.12mA
-916mV    -57.21mA   -84.7mA    -67.22mA
-853mV    -45.26mA   -58.07mA   -57.38mA
-811mV    -39.58mA   -44.43mA   -50.99mA
-769mV    -34.5mA    -34.04mA   -44.75mA
-706mV    -27.42mA   -23.61mA   -35.76mA
-643mV    -20.91mA   -17.14mA   -27.32mA
-559mV    -13.28mA   -11.04mA   -17.29mA
-412mV    -3.804mA   -3.723mA   -4.655mA
-286mV    -477.7uA   -703.7uA   -396.2uA
1V        0A         0A         0A
[POWER_clamp]
|Voltage   I(typ)   I(min)   I(max)
-1V       46.74mA    88.29mA    31.25mA
-953mV    29.96mA    64.69mA    22.99mA
-911mV    20.02mA    46.58mA    18.81mA
-869mV    14.14mA    31.9mA     15.73mA
-827mV    10.71mA    20.96mA    13.03mA
-785mV    8.459mA    13.56mA    10.59mA
-743mV    6.733mA    8.952mA    8.425mA
-701mV    5.305mA    6.142mA    6.561mA
-638mV    3.604mA    3.771mA    4.35mA
-470mV    1.11mA     1.202mA    1.272mA
-197mV    214.8uA    168.4uA    281.4uA
2V        -171.9uA   -171.2uA   -177.1uA
[Ramp]
| variable   typ   min   max
dV/dt_r   0.298/2.440n   0.248/2.814n   0.260/2.332n
dV/dt_f   0.287/4.811n   0.271/4.276n   0.283/4.621n
R_load = 50.000
[Rising Waveform]
R_fixture= 50.000
V_fixture= 0.0
V_fixture_min= 0.0
V_fixture_max= 0.0
|time   V(typ)   V(min)   V(max)
0s        1.832uV    62.7uV     140.5nV
1.431ns   2.016mV    2.546mV    2.316mV
2.044ns   25.09mV    23.63mV    30.8mV
2.63ns    81.33mV    68.47mV    97.63mV
3.631ns   224.9mV    176.1mV    231.6mV
4.449ns   330.1mV    256mV      315.7mV
5.423ns   409.6mV    322.1mV    376.7mV
6.654ns   458.2mV    368.3mV    411.3mV
10.01ns   491.4mV    406.5mV    430.6mV
20ns      496.5mV    414.1mV    433.3mV
[Rising Waveform]
R_fixture= 50.000
V_fixture= 1.000
V_fixture_min= 0.950
V_fixture_max= 1.050
|time   V(typ)   V(min)   V(max)
0s        520.7mV    497.5mV    578.3mV
336ps     521.1mV    497.7mV    577.5mV
430ps     522.4mV    497.7mV    733.8mV
534ps     693mV      497mV      819.4mV
633ps     776.9mV    495mV      866.5mV
773ps     838.3mV    682.5mV    910.3mV
864ps     864.4mV    750.4mV    930.7mV
1.363ns   935.7mV    872.4mV    990.3mV
2.324ns   977.8mV    926.8mV    1.031V
20ns      999.8mV    949.8mV    1.05V
[Falling Waveform]
R_fixture= 50.000
V_fixture= 1.000
V_fixture_min= 0.950
V_fixture_max= 1.050
|time   V(typ)   V(min)   V(max)
0s        1V         950mV      1.05V
644ps     1.011V     948.9mV    1.053V
1.595ns   998.4mV    946.7mV    1.044V
3.01ns    958.2mV    894mV      987.3mV
6.99ns    716.5mV    627.8mV    730.4mV
8.167ns   648.7mV    577.2mV    672.7mV
9.538ns   591.4mV    541.8mV    629.9mV
11ns      556.5mV    521.4mV    604mV
13.08ns   534.2mV    507.7mV    587.2mV
20ns      521.7mV    498.5mV    579mV
[Falling Waveform]
R_fixture= 50.000
V_fixture= 0.0
V_fixture_min= 0.0
V_fixture_max= 0.0
|time   V(typ)   V(min)   V(max)
0s        497mV      414.7mV    433.7mV
283ps     497mV      414.4mV    433.2mV
370ps     498mV      414.2mV    464.9mV
478ps     525.2mV    414.1mV    299mV
705ps     248.3mV    440.3mV    162.5mV
898ps     157.1mV    248.4mV    112.6mV
1.045ns   119.2mV    162.7mV    89.06mV
1.536ns   59.47mV    64.2mV     46.33mV
2.335ns   25.98mV    22.73mV    18.79mV
20ns      233.5uV    303.4uV    163.2uV
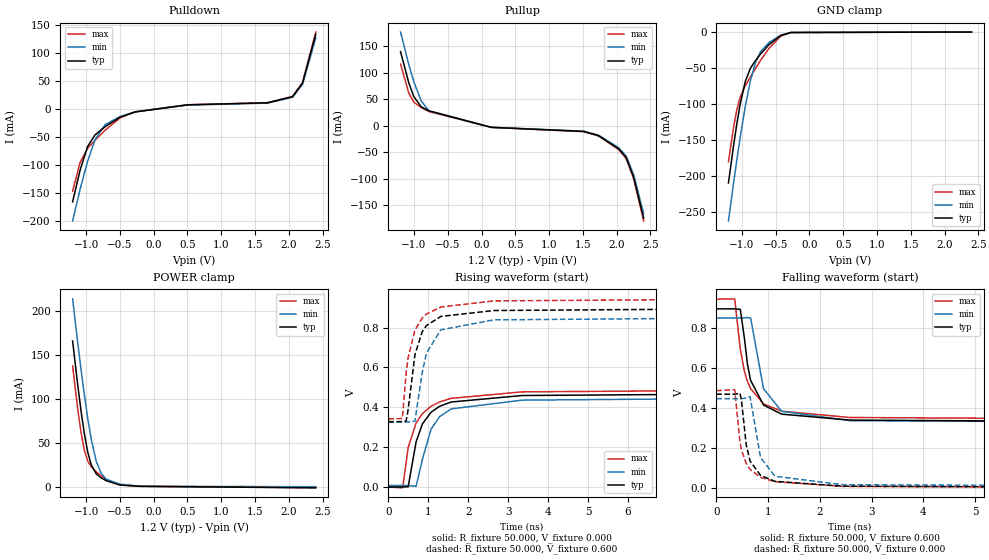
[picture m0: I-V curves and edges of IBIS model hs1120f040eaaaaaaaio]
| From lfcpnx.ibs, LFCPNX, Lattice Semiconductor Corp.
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|Model hs1120f040eaaaaaaaio
[Model] hs1120f040eaaaaaaaio
| Clamp models do not include dynamic input termination. Please refer to
| the hs1120axxxeaaaaaaain model for input termination.
Model_type I/O
Polarity   Non-Inverting
Enable   Active-Low
Vinl =  0.500V
Vinh =  0.700V
Vmeas =  0.600V
Cref =  20.000pF
Rref =  50.000
Vref =  0.600V
C_comp   5.000pF   4.000pF   5.500pF
[Temperature Range]   25.000   0.125k   -40.000
[Voltage Range]   1.200V   1.140V   1.260V
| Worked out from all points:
|   slope of the pulldown table from 0 to 0.18 V, typ, clamps not added: 56.1 ohm
|   slope of the pullup table from 0 to 0.18 V, typ, clamps not added: 46.2 ohm
|   GND clamp passes 1 mA (typ) near -0.31 V on its own axis
|   POWER clamp passes 1 mA (typ) near -0.43 V on its own axis
|   rising waveform, R_fixture 50.000, V_fixture 0.000: 20-80 % time 491ps typ, 502ps min, 533ps max; typ from 0 V to 0.469 V
|   rising waveform, R_fixture 50.000, V_fixture 0.600: 20-80 % time 334ps typ, 368ps min, 358ps max; typ from 0.328 V to 0.896 V
|   falling waveform, R_fixture 50.000, V_fixture 0.600: 20-80 % time 292ps typ, 298ps min, 332ps max; typ from 0.896 V to 0.328 V
|   falling waveform, R_fixture 50.000, V_fixture 0.000: 20-80 % time 221ps typ, 234ps min, 242ps max; typ from 0.469 V to 0 V
[Pulldown]
|Voltage   I(typ)   I(min)   I(max)
-1.2V     -166.4mA   -200.7mA   -147.3mA
-1.089V   -109.6mA   -144mA     -95.8mA
-978mV    -67.28mA   -93.6mA    -70.51mA
-867mV    -46.43mA   -54.86mA   -56.06mA
-719mV    -31.83mA   -28.23mA   -38.18mA
-497mV    -14.71mA   -13.56mA   -16.01mA
-275mV    -5.433mA   -5.348mA   -5.056mA
502mV     7.324mA    6.958mA    7.544mA
1.686V    10.94mA    10.39mA    11.26mA
2.056V    21.9mA     20.8mA     22.55mA
2.204V    46.11mA    43.81mA    47.5mA
2.4V      133.7mA    127mA      137.7mA
[Pullup]
|Voltage   I(typ)   I(min)   I(max)
-1.2V     139.5mA    176.3mA    115.9mA
-1.078V   80.7mA     115.2mA    61.56mA
-1.004V   54.78mA    82.9mA     44.18mA
-893mV    35.43mA    46.5mA     33.93mA
-782mV    27.87mA    28.19mA    26.66mA
143mV     -3.191mA   -3.031mA   -3.287mA
1.512V    -10.93mA   -10.38mA   -11.26mA
1.734V    -18.99mA   -18.04mA   -19.56mA
2.03V     -43.73mA   -41.55mA   -45.05mA
2.141V    -60.18mA   -57.17mA   -61.98mA
2.252V    -97.3mA    -92.4mA    -100.2mA
2.4V      -174.4mA   -165.7mA   -179.6mA
[GND_clamp]
|Voltage   I(typ)   I(min)   I(max)
-1.2V     -209.6mA   -262.4mA   -180.2mA
-1.125V   -158.2mA   -210.5mA   -132.7mA
-1.075V   -127mA     -177.3mA   -107.7mA
-1.025V   -99.59mA   -145.8mA   -90.14mA
-950mV    -68.44mA   -102.9mA   -74.64mA
-875mV    -50.37mA   -67.7mA    -62.38mA
-800mV    -39.61mA   -42.62mA   -50.65mA
-725mV    -30.63mA   -27.35mA   -39.46mA
-600mV    -17.53mA   -14.58mA   -22.59mA
-425mV    -4.657mA   -4.485mA   -5.636mA
-275mV    -627.9uA   -616.8uA   -678.4uA
2.4V      0A         0A         0A
[POWER_clamp]
|Voltage   I(typ)   I(min)   I(max)
-1.2V     166.3mA    214.4mA    137.7mA
-1.125V   116.5mA    164.9mA    89.12mA
-1.075V   86.21mA    133.5mA    61.64mA
-1.025V   59.86mA    104mA      41.12mA
-975mV    39.03mA    77.38mA    28.98mA
-925mV    24.95mA    54.44mA    22.72mA
-850mV    14.48mA    28.92mA    16.81mA
-775mV    9.774mA    14.73mA    11.95mA
-700mV    6.595mA    8.327mA    7.924mA
-500mV    1.71mA     2.674mA    1.891mA
-200mV    207.6uA    329.9uA    277.5uA
2.4V      -1.508mA   -253.4uA   -1.296mA
[Ramp]
| variable   typ   min   max
dV/dt_r   0.279/0.491n   0.263/0.510n   0.300/0.537n
dV/dt_f   0.259/0.471n   0.240/0.448n   0.270/0.541n
R_load = 50.000
[Rising Waveform]
R_fixture = 50.000
V_fixture = 0.000
V_fixture_min = 0.000
V_fixture_max = 0.000
|  time   V(typ)   V(min)   V(max)
0s        33.76uV    7.521mV    -284.2uV
359ps     415.6uV    7.573mV    -4.052mV
496ps     1.346mV    7.665mV    198.3mV
695ps     226.9mV    3.84mV     321.8mV
856ps     317.9mV    142.1mV    369.2mV
1.071ns   375.6mV    290.9mV    405.7mV
1.284ns   405.2mV    353.2mV    427.2mV
1.574ns   426.7mV    392.2mV    445mV
3.35ns    459.3mV    436.1mV    477.6mV
10ns      468.5mV    446.4mV    486.4mV
[Rising Waveform]
R_fixture = 50.000
V_fixture = 0.600
V_fixture_min = 0.571
V_fixture_max = 0.631
|  time   V(typ)   V(min)   V(max)
0s        328.1mV    325.8mV    341.8mV
351ps     328.3mV    325.9mV    344mV
444ps     331mV      325.9mV    569.4mV
488ps     378.7mV    326mV      643.6mV
665ps     663.4mV    330.9mV    786.8mV
845ps     778.3mV    572.6mV    847.3mV
955ps     810.6mV    672.8mV    868.3mV
1.315ns   856.2mV    788.9mV    903.4mV
2.64ns    885.8mV    839mV      934.1mV
10ns      896mV      850.2mV    944.3mV
[Falling Waveform]
R_fixture = 50.000
V_fixture = 0.600
V_fixture_min = 0.571
V_fixture_max = 0.631
|  time   V(typ)   V(min)   V(max)
0s        896mV      850.2mV    944.3mV
356ps     895.9mV    850.1mV    946mV
464ps     893.5mV    850.2mV    694.1mV
543ps     749.4mV    850.3mV    583.5mV
603ps     617.4mV    852.6mV    532.5mV
663ps     537.9mV    850.6mV    496.3mV
913ps     414.3mV    495.9mV    420.1mV
1.263ns   368.7mV    382.7mV    383.5mV
2.583ns   338.9mV    336.3mV    352mV
10ns      328.1mV    325.8mV    341.8mV
[Falling Waveform]
R_fixture = 50.000
V_fixture = 0.000
V_fixture_min = 0.000
V_fixture_max = 0.000
|  time   V(typ)   V(min)   V(max)
0s        468.5mV    446.4mV    486.4mV
356ps     468.5mV    446.1mV    491.2mV
458ps     473.9mV    446.2mV    228.2mV
488ps     433.6mV    446mV      188.2mV
578ps     216mV      449.8mV    122mV
653ps     133.7mV    456.1mV    92.13mV
854ps     62.28mV    152.1mV    52.2mV
1.133ns   32.21mV    57.65mV    30.5mV
2.437ns   8.071mV    15.57mV    6.997mV
10ns      33.76uV    7.521mV    -284.2uV
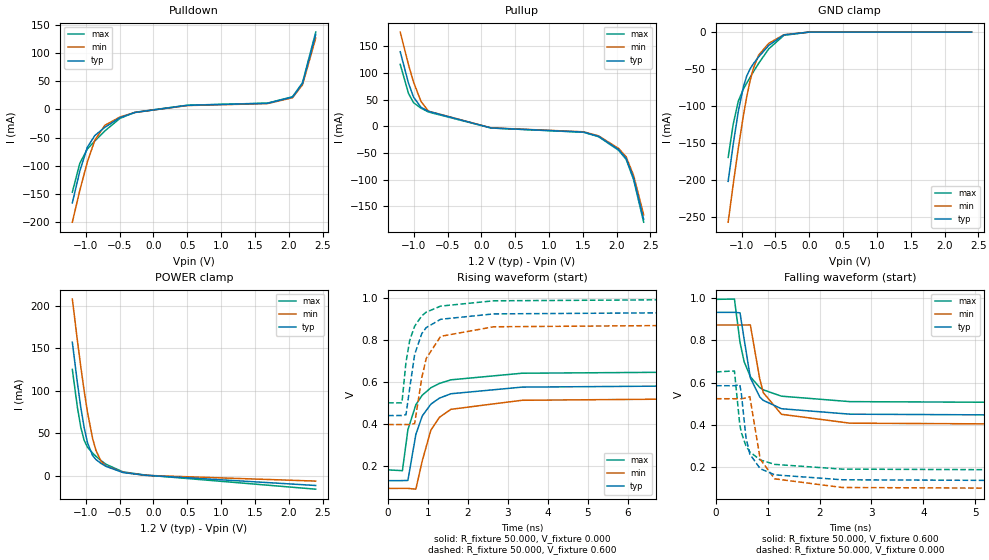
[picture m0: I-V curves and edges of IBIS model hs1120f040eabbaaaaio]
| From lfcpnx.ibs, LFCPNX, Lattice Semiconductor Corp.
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|Model hs1120f040eabbaaaaio
[Model] hs1120f040eabbaaaaio
| Clamp models do not include dynamic input termination. Please refer to
| the hs1120axxxeabbaaaain model for input termination.
Model_type I/O
Polarity   Non-Inverting
Enable   Active-Low
Vinl =  0.500V
Vinh =  0.700V
Vmeas =  0.600V
Cref =  20.000pF
Rref =  50.000
Vref =  0.600V
C_comp   5.000pF   4.000pF   5.500pF
[Temperature Range]   25.000   0.125k   -40.000
[Voltage Range]   1.200V   1.140V   1.260V
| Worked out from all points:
|   slope of the pulldown table from 0 to 0.18 V, typ, clamps not added: 56.1 ohm
|   slope of the pullup table from 0 to 0.18 V, typ, clamps not added: 46.2 ohm
|   GND clamp passes 1 mA (typ) near -0.14 V on its own axis
|   POWER clamp passes 1 mA (typ) near -0.17 V on its own axis
|   rising waveform, R_fixture 50.000, V_fixture 0.000: 20-80 % time 491ps typ, 502ps min, 533ps max; typ from 0.132 V to 0.585 V
|   rising waveform, R_fixture 50.000, V_fixture 0.600: 20-80 % time 334ps typ, 368ps min, 358ps max; typ from 0.441 V to 0.932 V
|   falling waveform, R_fixture 50.000, V_fixture 0.600: 20-80 % time 292ps typ, 298ps min, 332ps max; typ from 0.932 V to 0.441 V
|   falling waveform, R_fixture 50.000, V_fixture 0.000: 20-80 % time 221ps typ, 234ps min, 242ps max; typ from 0.585 V to 0.132 V
[Pulldown]
|Voltage   I(typ)   I(min)   I(max)
-1.2V     -166.4mA   -200.7mA   -147.3mA
-1.089V   -109.6mA   -144mA     -95.8mA
-978mV    -67.28mA   -93.6mA    -70.51mA
-867mV    -46.43mA   -54.86mA   -56.06mA
-719mV    -31.83mA   -28.23mA   -38.18mA
-497mV    -14.71mA   -13.56mA   -16.01mA
-275mV    -5.433mA   -5.348mA   -5.056mA
502mV     7.324mA    6.958mA    7.544mA
1.686V    10.94mA    10.39mA    11.26mA
2.056V    21.9mA     20.8mA     22.55mA
2.204V    46.11mA    43.81mA    47.5mA
2.4V      133.7mA    127mA      137.7mA
[Pullup]
|Voltage   I(typ)   I(min)   I(max)
-1.2V     139.5mA    176.3mA    115.9mA
-1.078V   80.7mA     115.2mA    61.56mA
-1.004V   54.78mA    82.9mA     44.18mA
-893mV    35.43mA    46.5mA     33.93mA
-782mV    27.87mA    28.19mA    26.66mA
143mV     -3.191mA   -3.031mA   -3.287mA
1.512V    -10.93mA   -10.38mA   -11.26mA
1.734V    -18.99mA   -18.04mA   -19.56mA
2.03V     -43.73mA   -41.55mA   -45.05mA
2.141V    -60.18mA   -57.17mA   -61.98mA
2.252V    -97.3mA    -92.4mA    -100.2mA
2.4V      -174.4mA   -165.7mA   -179.6mA
[GND_clamp]
|Voltage   I(typ)   I(min)   I(max)
-1.2V     -201.8mA   -257mA     -169.4mA
-1.125V   -151.4mA   -205.6mA   -124.4mA
-1.05V    -107.4mA   -157mA     -93.36mA
-975mV    -74.07mA   -112.9mA   -77.04mA
-925mV    -59.28mA   -87.24mA   -68.87mA
-875mV    -49.6mA    -65.58mA   -61.06mA
-825mV    -42.58mA   -48.49mA   -53.44mA
-750mV    -33.57mA   -31.23mA   -42.41mA
-600mV    -18.06mA   -15.21mA   -22.68mA
-375mV    -3.74mA    -3.594mA   -4.332mA
0V        0A         0A         0A
2.4V      0A         0A         0A
[POWER_clamp]
|Voltage   I(typ)   I(min)   I(max)
-1.2V     156.9mA    207.6mA    125mA
-1.125V   109.1mA    159mA      80.51mA
-1.075V   80.57mA    128.3mA    57.13mA
-1.025V   56.63mA    99.87mA    41.73mA
-975mV    38.74mA    74.4mA     33.51mA
-900mV    23.86mA    43.88mA    26.68mA
-850mV    19.08mA    29.7mA     22.97mA
-775mV    14.57mA    17.25mA    17.9mA
-700mV    11.09mA    11.42mA    13.53mA
-450mV    3.875mA    4.163mA    4.676mA
-125mV    735.3uA    624.3uA    974.1uA
2.4V      -11.3mA    -6.156mA   -15.63mA
[Ramp]
| variable   typ   min   max
dV/dt_r   0.272/0.491n   0.257/0.510n   0.280/0.537n
dV/dt_f   0.215/0.471n   0.213/0.448n   0.209/0.541n
R_load = 50.000
[Rising Waveform]
R_fixture = 50.000
V_fixture = 0.000
V_fixture_min = 0.000
V_fixture_max = 0.000
|  time   V(typ)   V(min)   V(max)
0s        131.9mV    95.13mV    183mV
359ps     132.2mV    95.18mV    179.4mV
496ps     133.1mV    95.27mV    373.6mV
695ps     351.2mV    91.54mV    492.2mV
856ps     439.2mV    226.5mV    537.7mV
1.071ns   495mV      371.7mV    572.8mV
1.284ns   523.6mV    432.5mV    593.4mV
1.574ns   544.4mV    470.6mV    610.5mV
3.35ns    575.9mV    513.4mV    641.8mV
10ns      584.9mV    523.4mV    650.2mV
[Rising Waveform]
R_fixture = 50.000
V_fixture = 0.600
V_fixture_min = 0.571
V_fixture_max = 0.631
|  time   V(typ)   V(min)   V(max)
0s        440.9mV    398.2mV    501.3mV
347ps     441.1mV    398.2mV    501.2mV
448ps     444.8mV    398.3mV    694mV
543ps     572mV      398mV      798.6mV
665ps     731mV      402.8mV    865.1mV
845ps     830.4mV    621.3mV    914.5mV
955ps     858.4mV    712mV      931.7mV
1.315ns   897.8mV    816.9mV    960.4mV
2.64ns    923.4mV    862.2mV    985.5mV
10ns      932.3mV    872.4mV    993.8mV
[Falling Waveform]
R_fixture = 50.000
V_fixture = 0.600
V_fixture_min = 0.571
V_fixture_max = 0.631
|  time   V(typ)   V(min)   V(max)
0s        932.3mV    872.4mV    993.8mV
356ps     932.2mV    872.3mV    995.2mV
464ps     930.1mV    872.3mV    789.3mV
543ps     805.5mV    872.4mV    698.9mV
663ps     622.4mV    872.7mV    627.6mV
843ps     532.5mV    618.4mV    576.7mV
913ps     515.5mV    552mV      565.3mV
1.263ns   476mV      449.6mV    535.4mV
2.583ns   450.2mV    407.6mV    509.6mV
10ns      440.9mV    398.2mV    501.3mV
[Falling Waveform]
R_fixture = 50.000
V_fixture = 0.000
V_fixture_min = 0.000
V_fixture_max = 0.000
|  time   V(typ)   V(min)   V(max)
0s        584.9mV    523.4mV    650.2mV
356ps     584.8mV    523.2mV    654.9mV
458ps     590mV      523.3mV    402.4mV
488ps     551.1mV    523.1mV    364mV
578ps     340.6mV    526.8mV    300.4mV
653ps     261.1mV    533mV      271.7mV
854ps     192mV      236.2mV    233.4mV
1.133ns   163mV      144.1mV    212.5mV
2.437ns   139.6mV    103mV      190mV
10ns      131.9mV    95.13mV    183mV
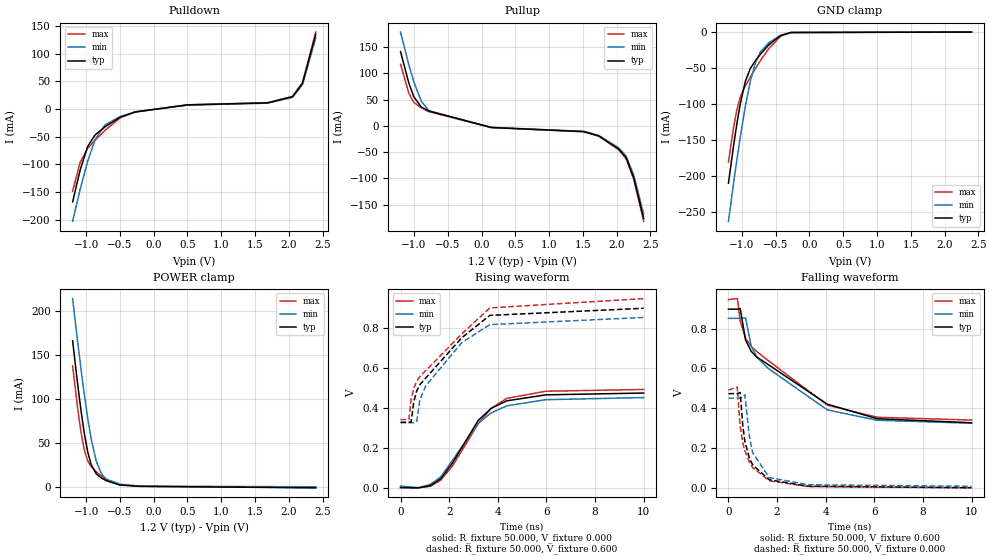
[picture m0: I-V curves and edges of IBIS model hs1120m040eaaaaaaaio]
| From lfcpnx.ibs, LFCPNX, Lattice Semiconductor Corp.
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|Model hs1120m040eaaaaaaaio
[Model] hs1120m040eaaaaaaaio
| Clamp models do not include dynamic input termination. Please refer to
| the hs1120axxxeaaaaaaain model for input termination.
Model_type I/O
Polarity   Non-Inverting
Enable   Active-Low
Vinl =  0.500V
Vinh =  0.700V
Vmeas =  0.600V
Cref =  20.000pF
Rref =  50.000
Vref =  0.600V
C_comp   5.000pF   4.000pF   5.500pF
[Temperature Range]   25.000   0.125k   -40.000
[Voltage Range]   1.200V   1.140V   1.260V
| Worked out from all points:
|   slope of the pulldown table from 0 to 0.18 V, typ, clamps not added: 55.6 ohm
|   slope of the pullup table from 0 to 0.18 V, typ, clamps not added: 45.6 ohm
|   GND clamp passes 1 mA (typ) near -0.31 V on its own axis
|   POWER clamp passes 1 mA (typ) near -0.43 V on its own axis
|   rising waveform, R_fixture 50.000, V_fixture 0.000: 20-80 % time 1.55ns typ, 1.65ns min, 1.61ns max; typ from 0 V to 0.473 V
|   rising waveform, R_fixture 50.000, V_fixture 0.600: 20-80 % time 2.18ns typ, 1.9ns min, 2.43ns max; typ from 0.327 V to 0.898 V
|   falling waveform, R_fixture 50.000, V_fixture 0.600: 20-80 % time 3.14ns typ, 2.57ns min, 2.92ns max; typ from 0.898 V to 0.327 V
|   falling waveform, R_fixture 50.000, V_fixture 0.000: 20-80 % time 556ps typ, 521ps min, 590ps max; typ from 0.473 V to 0 V
[Pulldown]
|Voltage   I(typ)   I(min)   I(max)
-1.2V     -167.5mA   -202.4mA   -148.2mA
-1.089V   -110.4mA   -145.3mA   -96.4mA
-978mV    -67.78mA   -94.4mA    -70.93mA
-867mV    -46.78mA   -55.35mA   -56.4mA
-719mV    -32.07mA   -28.48mA   -38.41mA
-497mV    -14.82mA   -13.68mA   -16.11mA
-275mV    -5.473mA   -5.396mA   -5.087mA
502mV     7.378mA    7.01mA     7.6mA
1.686V    11.02mA    10.47mA    11.35mA
2.056V    22.06mA    20.95mA    22.72mA
2.204V    46.46mA    44.13mA    47.85mA
2.4V      134.7mA    128mA      138.7mA
[Pullup]
|Voltage   I(typ)   I(min)   I(max)
-1.2V     141.2mA    178.5mA    117.3mA
-1.078V   81.8mA     116.6mA    62.3mA
-1.004V   55.44mA    83.9mA     44.71mA
-893mV    35.85mA    47.06mA    34.34mA
-782mV    28.21mA    28.53mA    26.98mA
143mV     -3.229mA   -3.068mA   -3.326mA
1.512V    -11.06mA   -10.51mA   -11.39mA
1.734V    -19.21mA   -18.25mA   -19.79mA
2.03V     -44.26mA   -42.05mA   -45.59mA
2.141V    -60.9mA    -57.86mA   -62.73mA
2.252V    -98.6mA    -93.7mA    -101.6mA
2.4V      -176.5mA   -167.7mA   -181.8mA
[GND_clamp]
|Voltage   I(typ)   I(min)   I(max)
-1.2V     -209.6mA   -262.4mA   -180.2mA
-1.125V   -158.2mA   -210.5mA   -132.7mA
-1.075V   -127mA     -177.3mA   -107.7mA
-1.025V   -99.59mA   -145.8mA   -90.14mA
-950mV    -68.44mA   -102.9mA   -74.64mA
-875mV    -50.37mA   -67.7mA    -62.38mA
-800mV    -39.61mA   -42.62mA   -50.65mA
-725mV    -30.63mA   -27.35mA   -39.46mA
-600mV    -17.53mA   -14.58mA   -22.59mA
-425mV    -4.657mA   -4.485mA   -5.636mA
-275mV    -627.9uA   -616.8uA   -678.4uA
2.4V      0A         0A         0A
[POWER_clamp]
|Voltage   I(typ)   I(min)   I(max)
-1.2V     166.3mA    214.4mA    137.7mA
-1.125V   116.5mA    164.9mA    89.12mA
-1.075V   86.21mA    133.5mA    61.64mA
-1.025V   59.86mA    104mA      41.12mA
-975mV    39.03mA    77.38mA    28.98mA
-925mV    24.95mA    54.44mA    22.72mA
-850mV    14.48mA    28.92mA    16.81mA
-775mV    9.774mA    14.73mA    11.95mA
-700mV    6.595mA    8.327mA    7.924mA
-500mV    1.71mA     2.674mA    1.891mA
-200mV    207.6uA    329.9uA    277.5uA
2.4V      -1.508mA   -253.4uA   -1.296mA
[Ramp]
| variable   typ   min   max
dV/dt_r   0.282/1.576n   0.266/1.700n   0.300/1.665n
dV/dt_f   0.261/3.062n   0.242/2.751n   0.272/3.005n
R_load = 50.000
[Rising Waveform]
R_fixture = 50.000
V_fixture = 0.000
V_fixture_min = 0.000
V_fixture_max = 0.000
|  time   V(typ)   V(min)   V(max)
0s        34.96uV    7.5mV      -291.8uV
724ps     -1.513mV   -612.4uV   -1.329mV
1.225ns   9.198mV    15.37mV    6.435mV
1.649ns   43.34mV    52.79mV    36.16mV
2.136ns   122.8mV    136.1mV    108mV
3.199ns   336.8mV    322.3mV    320.3mV
3.732ns   397mV      374.4mV    397.3mV
4.371ns   434.4mV    409.3mV    446.7mV
5.97ns    464.3mV    440.1mV    482.4mV
10ns      473.4mV    450.6mV    491.4mV
[Rising Waveform]
R_fixture = 50.000
V_fixture = 0.600
V_fixture_min = 0.571
V_fixture_max = 0.631
|  time   V(typ)   V(min)   V(max)
0s        326.9mV    324.7mV    340.5mV
343ps     327.2mV    324.8mV    340.4mV
436ps     327.9mV    324.8mV    441mV
546ps     430.7mV    324.4mV    498mV
665ps     484mV      329.2mV    532.4mV
795ps     515.1mV    440.1mV    556.9mV
1.046ns   549.9mV    511mV      586.3mV
2.515ns   749.9mV    725.6mV    768.9mV
3.671ns   862.4mV    816.2mV    899.9mV
10ns      898.1mV    852.1mV    946.5mV
[Falling Waveform]
R_fixture = 50.000
V_fixture = 0.600
V_fixture_min = 0.571
V_fixture_max = 0.631
|  time   V(typ)   V(min)   V(max)
0s        898.1mV    852.1mV    946.5mV
370ps     898.2mV    851.9mV    951.3mV
484ps     901.1mV    851.9mV    838mV
703ps     743.4mV    854.4mV    751.7mV
935ps     686.1mV    712.6mV    711.4mV
1.173ns   656.8mV    655.8mV    684mV
1.643ns   618.9mV    599.4mV    638.9mV
4.068ns   420.4mV    391.5mV    415.2mV
6.124ns   347.1mV    339.4mV    354.5mV
10ns      326.9mV    324.7mV    340.5mV
[Falling Waveform]
R_fixture = 50.000
V_fixture = 0.000
V_fixture_min = 0.000
V_fixture_max = 0.000
|  time   V(typ)   V(min)   V(max)
0s        473.4mV    450.6mV    491.4mV
362ps     473.6mV    450.3mV    506.1mV
482ps     479.4mV    450.2mV    309.9mV
591ps     312.4mV    457.9mV    225.8mV
673ps     234.6mV    468.1mV    186.4mV
863ps     148.4mV    257.2mV    128.1mV
993ps     115.3mV    177.8mV    102mV
1.683ns   39.8mV     50.93mV    35.01mV
3.281ns   7.769mV    15.31mV    5.789mV
10ns      34.96uV    7.5mV      -291.8uV
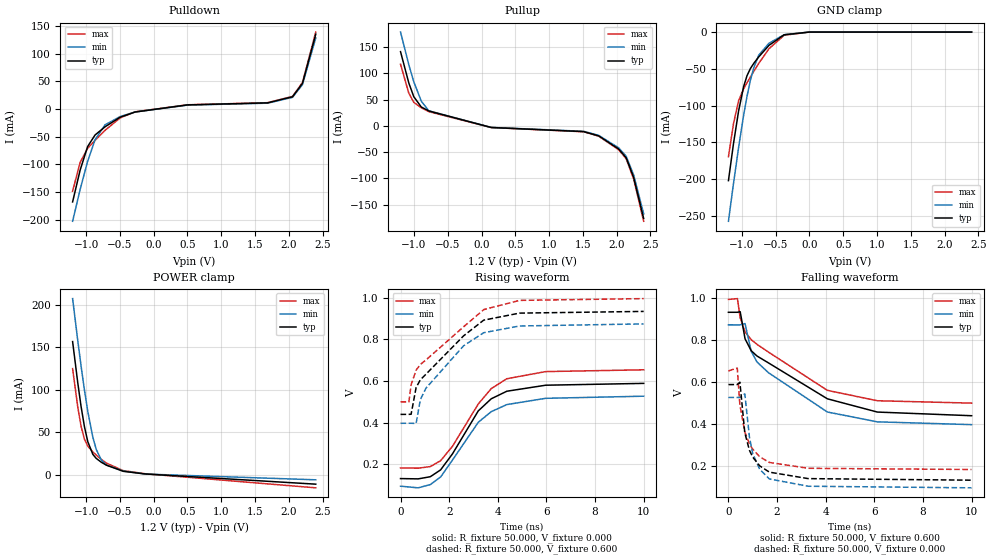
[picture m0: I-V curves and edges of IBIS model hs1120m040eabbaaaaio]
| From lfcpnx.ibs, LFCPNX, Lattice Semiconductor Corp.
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|Model hs1120m040eabbaaaaio
[Model] hs1120m040eabbaaaaio
| Clamp models do not include dynamic input termination. Please refer to
| the hs1120axxxeabbaaaain model for input termination.
Model_type I/O
Polarity   Non-Inverting
Enable   Active-Low
Vinl =  0.500V
Vinh =  0.700V
Vmeas =  0.600V
Cref =  20.000pF
Rref =  50.000
Vref =  0.600V
C_comp   5.000pF   4.000pF   5.500pF
[Temperature Range]   25.000   0.125k   -40.000
[Voltage Range]   1.200V   1.140V   1.260V
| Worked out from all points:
|   slope of the pulldown table from 0 to 0.18 V, typ, clamps not added: 55.6 ohm
|   slope of the pullup table from 0 to 0.18 V, typ, clamps not added: 45.6 ohm
|   GND clamp passes 1 mA (typ) near -0.14 V on its own axis
|   POWER clamp passes 1 mA (typ) near -0.17 V on its own axis
|   rising waveform, R_fixture 50.000, V_fixture 0.000: 20-80 % time 1.55ns typ, 1.65ns min, 1.61ns max; typ from 0.131 V to 0.588 V
|   rising waveform, R_fixture 50.000, V_fixture 0.600: 20-80 % time 2.18ns typ, 1.9ns min, 2.43ns max; typ from 0.439 V to 0.934 V
|   falling waveform, R_fixture 50.000, V_fixture 0.600: 20-80 % time 3.14ns typ, 2.57ns min, 2.92ns max; typ from 0.934 V to 0.439 V
|   falling waveform, R_fixture 50.000, V_fixture 0.000: 20-80 % time 556ps typ, 521ps min, 590ps max; typ from 0.588 V to 0.131 V
[Pulldown]
|Voltage   I(typ)   I(min)   I(max)
-1.2V     -167.5mA   -202.4mA   -148.2mA
-1.089V   -110.4mA   -145.3mA   -96.4mA
-978mV    -67.78mA   -94.4mA    -70.93mA
-867mV    -46.78mA   -55.35mA   -56.4mA
-719mV    -32.07mA   -28.48mA   -38.41mA
-497mV    -14.82mA   -13.68mA   -16.11mA
-275mV    -5.473mA   -5.396mA   -5.087mA
502mV     7.378mA    7.01mA     7.6mA
1.686V    11.02mA    10.47mA    11.35mA
2.056V    22.06mA    20.95mA    22.72mA
2.204V    46.46mA    44.13mA    47.85mA
2.4V      134.7mA    128mA      138.7mA
[Pullup]
|Voltage   I(typ)   I(min)   I(max)
-1.2V     141.2mA    178.5mA    117.3mA
-1.078V   81.8mA     116.6mA    62.3mA
-1.004V   55.44mA    83.9mA     44.71mA
-893mV    35.85mA    47.06mA    34.34mA
-782mV    28.21mA    28.53mA    26.98mA
143mV     -3.229mA   -3.068mA   -3.326mA
1.512V    -11.06mA   -10.51mA   -11.39mA
1.734V    -19.21mA   -18.25mA   -19.79mA
2.03V     -44.26mA   -42.05mA   -45.59mA
2.141V    -60.9mA    -57.86mA   -62.73mA
2.252V    -98.6mA    -93.7mA    -101.6mA
2.4V      -176.5mA   -167.7mA   -181.8mA
[GND_clamp]
|Voltage   I(typ)   I(min)   I(max)
-1.2V     -201.8mA   -257mA     -169.4mA
-1.125V   -151.4mA   -205.6mA   -124.4mA
-1.05V    -107.4mA   -157mA     -93.36mA
-975mV    -74.07mA   -112.9mA   -77.04mA
-925mV    -59.28mA   -87.24mA   -68.87mA
-875mV    -49.6mA    -65.58mA   -61.06mA
-825mV    -42.58mA   -48.49mA   -53.44mA
-750mV    -33.57mA   -31.23mA   -42.41mA
-600mV    -18.06mA   -15.21mA   -22.68mA
-375mV    -3.74mA    -3.594mA   -4.332mA
0V        0A         0A         0A
2.4V      0A         0A         0A
[POWER_clamp]
|Voltage   I(typ)   I(min)   I(max)
-1.2V     156.9mA    207.6mA    125mA
-1.125V   109.1mA    159mA      80.51mA
-1.075V   80.57mA    128.3mA    57.13mA
-1.025V   56.63mA    99.87mA    41.73mA
-975mV    38.74mA    74.4mA     33.51mA
-900mV    23.86mA    43.88mA    26.68mA
-850mV    19.08mA    29.7mA     22.97mA
-775mV    14.57mA    17.25mA    17.9mA
-700mV    11.09mA    11.42mA    13.53mA
-450mV    3.875mA    4.163mA    4.676mA
-125mV    735.3uA    624.3uA    974.1uA
2.4V      -11.3mA    -6.156mA   -15.63mA
[Ramp]
| variable   typ   min   max
dV/dt_r   0.274/1.576n   0.259/1.700n   0.283/1.665n
dV/dt_f   0.217/3.062n   0.214/2.751n   0.211/3.005n
R_load = 50.000
[Rising Waveform]
R_fixture = 50.000
V_fixture = 0.000
V_fixture_min = 0.000
V_fixture_max = 0.000
|  time   V(typ)   V(min)   V(max)
0s        131.4mV    94.82mV    182.4mV
724ps     129.9mV    86.91mV    181.4mV
1.225ns   140.3mV    102.5mV    188.8mV
1.649ns   173.2mV    139mV      217.3mV
2.136ns   249.9mV    220.2mV    286.2mV
3.199ns   456.5mV    401.8mV    489.6mV
3.732ns   514.5mV    452.6mV    563.4mV
4.371ns   550.7mV    486.6mV    610.7mV
5.97ns    579.6mV    516.7mV    645mV
10ns      588.4mV    526.9mV    653.6mV
[Rising Waveform]
R_fixture = 50.000
V_fixture = 0.600
V_fixture_min = 0.571
V_fixture_max = 0.631
|  time   V(typ)   V(min)   V(max)
0s        439.5mV    396.9mV    499.7mV
343ps     439.7mV    396.9mV    499.6mV
436ps     440.3mV    397mV      581.9mV
641ps     568.7mV    396.1mV    651.9mV
815ps     605.5mV    510.4mV    679.1mV
1.046ns   632.5mV    565.4mV    700.7mV
2.593ns   816.5mV    768.7mV    860mV
3.421ns   892mV      831.7mV    942.6mV
4.891ns   925.7mV    863.9mV    986.8mV
10ns      933.9mV    874mV      995.4mV
[Falling Waveform]
R_fixture = 50.000
V_fixture = 0.600
V_fixture_min = 0.571
V_fixture_max = 0.631
|  time   V(typ)   V(min)   V(max)
0s        933.9mV    874mV      995.4mV
370ps     934mV      873.8mV    999.3mV
484ps     936.5mV    873.8mV    906.7mV
683ps     807.2mV    879.9mV    840mV
935ps     750.4mV    747.8mV    803mV
1.173ns   725mV      696.4mV    780.7mV
1.643ns   692.2mV    645.4mV    743.8mV
4.068ns   520.4mV    457.3mV    560.8mV
6.124ns   457mV      410.2mV    511.1mV
10ns      439.5mV    396.9mV    499.7mV
[Falling Waveform]
R_fixture = 50.000
V_fixture = 0.000
V_fixture_min = 0.000
V_fixture_max = 0.000
|  time   V(typ)   V(min)   V(max)
0s        588.4mV    526.9mV    653.6mV
362ps     588.5mV    526.7mV    667.6mV
471ps     599.5mV    526.6mV    491.8mV
673ps     357.8mV    544mV      361.3mV
863ps     274.6mV    338.3mV    305.4mV
993ps     242.7mV    260.9mV    280.4mV
1.283ns   200.1mV    183.7mV    243.5mV
1.683ns   169.8mV    137.2mV    216.2mV
3.281ns   138.9mV    102.4mV    188.2mV
10ns      131.4mV    94.82mV    182.4mV
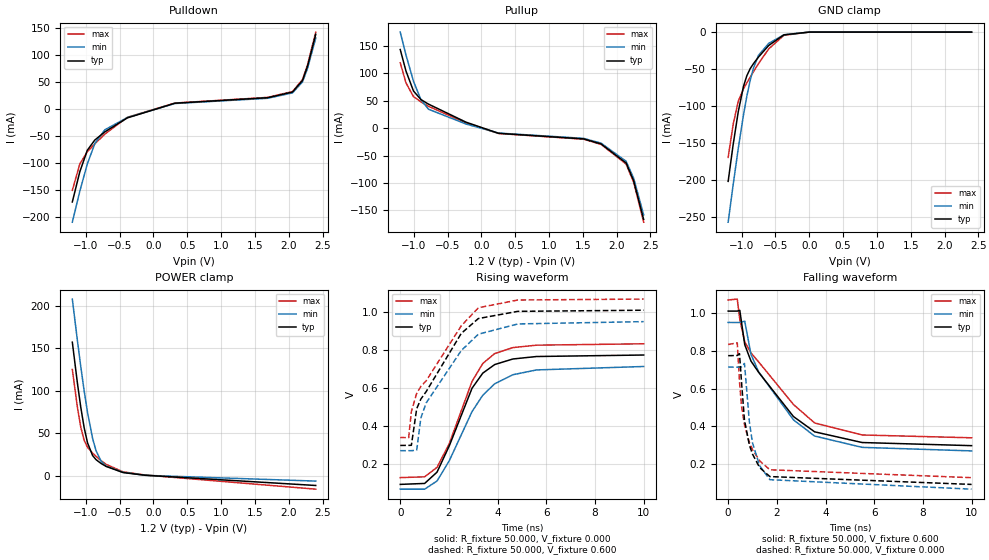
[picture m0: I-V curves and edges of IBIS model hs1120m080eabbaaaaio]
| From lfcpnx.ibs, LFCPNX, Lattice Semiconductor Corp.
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|Model hs1120m080eabbaaaaio
[Model] hs1120m080eabbaaaaio
| Clamp models do not include dynamic input termination. Please refer to
| the hs1120axxxeabbaaaain model for input termination.
Model_type I/O
Polarity   Non-Inverting
Enable   Active-Low
Vinl =  0.500V
Vinh =  0.700V
Vmeas =  0.600V
Cref =  20.000pF
Rref =  50.000
Vref =  0.600V
C_comp   5.000pF   4.000pF   5.500pF
[Temperature Range]   25.000   0.125k   -40.000
[Voltage Range]   1.200V   1.140V   1.260V
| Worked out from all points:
|   slope of the pulldown table from 0 to 0.18 V, typ, clamps not added: 27.3 ohm
|   slope of the pullup table from 0 to 0.18 V, typ, clamps not added: 25.5 ohm
|   GND clamp passes 1 mA (typ) near -0.14 V on its own axis
|   POWER clamp passes 1 mA (typ) near -0.17 V on its own axis
|   rising waveform, R_fixture 50.000, V_fixture 0.000: 20-80 % time 1.33ns typ, 1.61ns min, 1.29ns max; typ from 0.091 V to 0.775 V
|   rising waveform, R_fixture 50.000, V_fixture 0.600: 20-80 % time 1.82ns typ, 1.81ns min, 2.02ns max; typ from 0.297 V to 1.01 V
|   falling waveform, R_fixture 50.000, V_fixture 0.600: 20-80 % time 2.14ns typ, 2.02ns min, 2.37ns max; typ from 1.01 V to 0.297 V
|   falling waveform, R_fixture 50.000, V_fixture 0.000: 20-80 % time 536ps typ, 501ps min, 590ps max; typ from 0.775 V to 0.091 V
[Pulldown]
|Voltage   I(typ)   I(min)   I(max)
-1.2V     -172mA     -209.5mA   -150.5mA
-1.089V   -116mA     -152mA     -101.6mA
-978mV    -76.15mA   -101.5mA   -78.8mA
-867mV    -57.22mA   -63.79mA   -64.4mA
-719mV    -42.17mA   -38.34mA   -46.28mA
-386mV    -16.26mA   -15.56mA   -15.23mA
317mV     10.92mA    10.37mA    11.24mA
1.686V    21.08mA    20.03mA    21.71mA
2.056V    31.59mA    30.01mA    32.54mA
2.204V    53.04mA    50.39mA    54.63mA
2.278V    79.2mA     75.2mA     81.6mA
2.4V      138.5mA    131.6mA    142.7mA
[Pullup]
|Voltage   I(typ)   I(min)   I(max)
-1.2V     143.8mA    175.7mA    119.5mA
-1.115V   104.4mA    133.7mA    82.8mA
-1.004V   67.92mA    85.7mA     57.67mA
-893mV    52.22mA    51.65mA    48.03mA
-782mV    43.96mA    34.65mA    39.94mA
-227mV    10.98mA    7.588mA    9.596mA
254mV     -9.406mA   -8.935mA   -9.688mA
1.512V    -19.59mA   -18.61mA   -20.17mA
1.771V    -28.88mA   -27.43mA   -29.74mA
2.141V    -63.74mA   -60.55mA   -65.65mA
2.252V    -96.2mA    -91.4mA    -99.1mA
2.4V      -166.9mA   -158.6mA   -171.9mA
[GND_clamp]
|Voltage   I(typ)   I(min)   I(max)
-1.2V     -201.8mA   -257mA     -169.4mA
-1.125V   -151.4mA   -205.6mA   -124.4mA
-1.05V    -107.4mA   -157mA     -93.36mA
-975mV    -74.07mA   -112.9mA   -77.04mA
-925mV    -59.28mA   -87.24mA   -68.87mA
-875mV    -49.6mA    -65.58mA   -61.06mA
-825mV    -42.58mA   -48.49mA   -53.44mA
-750mV    -33.57mA   -31.23mA   -42.41mA
-600mV    -18.06mA   -15.21mA   -22.68mA
-375mV    -3.74mA    -3.594mA   -4.332mA
0V        0A         0A         0A
2.4V      0A         0A         0A
[POWER_clamp]
|Voltage   I(typ)   I(min)   I(max)
-1.2V     156.9mA    207.6mA    125mA
-1.125V   109.1mA    159mA      80.51mA
-1.075V   80.57mA    128.3mA    57.13mA
-1.025V   56.63mA    99.87mA    41.73mA
-975mV    38.74mA    74.4mA     33.51mA
-900mV    23.86mA    43.88mA    26.68mA
-850mV    19.08mA    29.7mA     22.97mA
-775mV    14.57mA    17.25mA    17.9mA
-700mV    11.09mA    11.42mA    13.53mA
-450mV    3.875mA    4.163mA    4.676mA
-125mV    735.3uA    624.3uA    974.1uA
2.4V      -11.3mA    -6.156mA   -15.63mA
[Ramp]
| variable   typ   min   max
dV/dt_r   0.411/1.352n   0.383/1.676n   0.425/1.350n
dV/dt_f   0.389/2.309n   0.376/2.319n   0.392/2.482n
R_load = 50.000
[Rising Waveform]
R_fixture = 50.000
V_fixture = 0.000
V_fixture_min = 0.000
V_fixture_max = 0.000
|  time   V(typ)   V(min)   V(max)
0s        90.58mV    65.4mV     126.4mV
1.003ns   95.62mV    65.31mV    130.6mV
1.513ns   155.7mV    108.7mV    180.9mV
2.016ns   295mV      216mV      306.6mV
2.949ns   599.2mV    475.7mV    635.3mV
3.391ns   679.2mV    562.3mV    730.3mV
3.88ns    724.5mV    622.8mV    782.6mV
4.628ns   754mV      670.7mV    814.3mV
5.6ns     767.1mV    696.1mV    827.1mV
10ns      775mV      714.3mV    834.4mV
[Rising Waveform]
R_fixture = 50.000
V_fixture = 0.600
V_fixture_min = 0.571
V_fixture_max = 0.631
|  time   V(typ)   V(min)   V(max)
0s        296.7mV    268.8mV    338.5mV
346ps     297mV      268.9mV    337.8mV
457ps     297.4mV    269mV      476.2mV
676ps     490.9mV    271.3mV    572.6mV
847ps     542.1mV    441.7mV    608.6mV
1.066ns   581.6mV    521.8mV    638.9mV
2.507ns   889.4mV    798.5mV    929.5mV
3.209ns   968mV      885.1mV    1.025V
4.83ns    1.006V     939.4mV    1.066V
10ns      1.012V     951.7mV    1.071V
[Falling Waveform]
R_fixture = 50.000
V_fixture = 0.600
V_fixture_min = 0.571
V_fixture_max = 0.631
|  time   V(typ)   V(min)   V(max)
0s        1.012V     951.7mV    1.071V
374ps     1.012V     951.5mV    1.076V
478ps     1.016V     951.6mV    968.1mV
681ps     833.7mV    958.5mV    849.1mV
938ps     746.2mV    781.8mV    789.3mV
1.25ns    687mV      689.6mV    742.3mV
2.683ns   451.4mV    433.9mV    515.5mV
3.551ns   370.3mV    347.8mV    417.5mV
5.506ns   313.3mV    287.6mV    353.5mV
10ns      296.7mV    268.8mV    338.5mV
[Falling Waveform]
R_fixture = 50.000
V_fixture = 0.000
V_fixture_min = 0.000
V_fixture_max = 0.000
|  time   V(typ)   V(min)   V(max)
0s        775mV      714.3mV    834.4mV
374ps     776mV      713.9mV    843.1mV
466ps     785.7mV    714mV      635.7mV
550ps     632.3mV    715.8mV    506.6mV
670ps     433mV      733.7mV    407.2mV
870ps     300.9mV    424.5mV    314.3mV
1ns       251.9mV    311.5mV    276.2mV
1.294ns   180.1mV    190mV      216mV
1.714ns   132.3mV    115.8mV    168.4mV
10ns      90.58mV    65.4mV     126.4mV
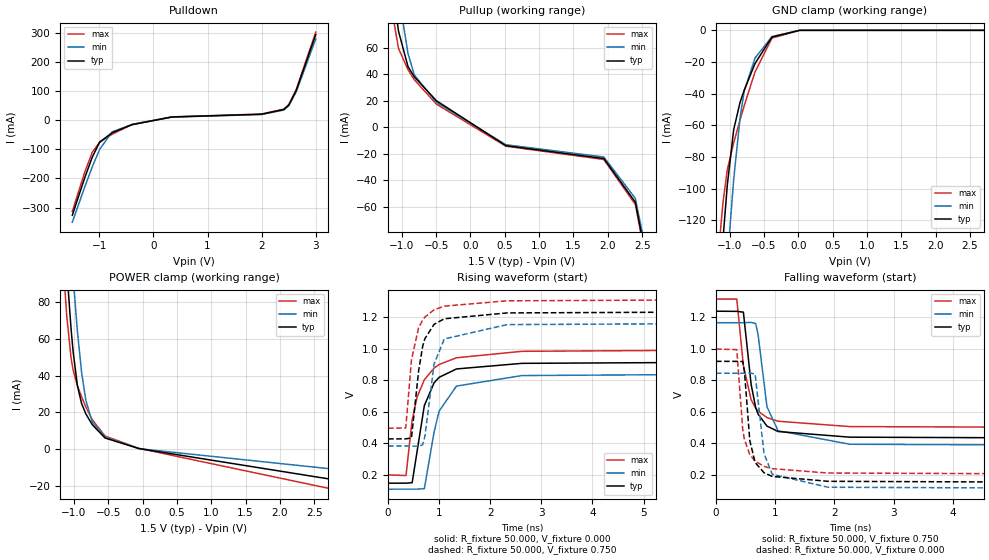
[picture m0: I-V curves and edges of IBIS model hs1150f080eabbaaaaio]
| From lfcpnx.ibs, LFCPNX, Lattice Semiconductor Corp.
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|Model hs1150f080eabbaaaaio
[Model] hs1150f080eabbaaaaio
Model_type I/O
Polarity   Non-Inverting
Enable   Active-Low
Vinl =  0.650V
Vinh =  0.850V
Vmeas =  0.750V
Cref =  30.000pF
Rref =  50.000
Vref =  0.750V
C_comp   5.000pF   4.000pF   5.500pF
[Temperature Range]   25.000   0.125k   -40.000
[Voltage Range]   1.500V   1.430V   1.580V
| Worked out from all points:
|   slope of the pulldown table from 0 to 0.225 V, typ, clamps not added: 29.8 ohm
|   slope of the pullup table from 0 to 0.225 V, typ, clamps not added: 31.2 ohm
|   GND clamp passes 1 mA (typ) near -0.15 V on its own axis
|   POWER clamp passes 1 mA (typ) near -0.17 V on its own axis
|   rising waveform, R_fixture 50.000, V_fixture 0.000: 20-80 % time 311ps typ, 333ps min, 377ps max; typ from 0.147 V to 0.92 V
|   rising waveform, R_fixture 50.000, V_fixture 0.750: 20-80 % time 217ps typ, 245ps min, 234ps max; typ from 0.428 V to 1.24 V
|   falling waveform, R_fixture 50.000, V_fixture 0.750: 20-80 % time 189ps typ, 202ps min, 215ps max; typ from 1.24 V to 0.428 V
|   falling waveform, R_fixture 50.000, V_fixture 0.000: 20-80 % time 135ps typ, 149ps min, 147ps max; typ from 0.92 V to 0.147 V
[Pulldown]
|Voltage   I(typ)   I(min)   I(max)
-1.5V     -326.3mA   -350.1mA   -313mA
-1.27V    -197.3mA   -229.2mA   -178.1mA
-1.132V   -127.3mA   -160.7mA   -110.5mA
-994mV    -75.1mA    -100.1mA   -76mA
-764mV    -43.36mA   -40.34mA   -48.47mA
-396mV    -15.68mA   -14.88mA   -14.84mA
340mV     10.77mA    10.23mA    11.09mA
1.996V    20.21mA    19.2mA     20.82mA
2.41V     36.42mA    34.6mA     37.52mA
2.502V    51.88mA    49.29mA    53.44mA
2.64V     102.4mA    97.3mA     105.5mA
3V        293.1mA    278.4mA    301.9mA
[Pullup]
|Voltage   I(typ)   I(min)   I(max)
-1.5V     294.8mA    323.3mA    276.8mA
-1.186V   128.1mA    161.6mA    106.6mA
-1.14V    107.1mA    140mA      86.9mA
-1.048V   72.31mA    100.2mA    59.29mA
-910mV    45.66mA    55.61mA    43.29mA
-818mV    37.9mA     39.34mA    35.67mA
-496mV    19.91mA    18.64mA    17.36mA
516mV     -13.95mA   -13.25mA   -14.37mA
1.942V    -23.66mA   -22.47mA   -24.37mA
2.402V    -56.58mA   -53.75mA   -58.27mA
2.586V    -105.8mA   -100.5mA   -109mA
3V        -324mA     -307.8mA   -333.7mA
[GND_clamp]
|Voltage   I(typ)   I(min)   I(max)
-1.5V     -423.6mA   -473.4mA   -391.3mA
-1.159V   -170.8mA   -226.4mA   -140.1mA
-1.128V   -150.6mA   -205.4mA   -123mA
-1.097V   -131.5mA   -185mA     -108.4mA
-1.035V   -97.76mA   -145.9mA   -88.03mA
-942mV    -62.68mA   -94.08mA   -70.99mA
-849mV    -45.44mA   -55.18mA   -56.59mA
-787mV    -37.67mA   -38mA      -47.37mA
-632mV    -20.99mA   -17.55mA   -26.32mA
-384mV    -4.202mA   -3.934mA   -4.89mA
19mV      0A         0A         0A
3V        0A         0A         0A
[POWER_clamp]
|Voltage   I(typ)   I(min)   I(max)
-1.5V     377.8mA    420.9mA    350.6mA
-1.166V   135.9mA    186.4mA    106mA
-1.104V   98.02mA    147mA      72.63mA
-1.042V   66.02mA    110.5mA    49.91mA
-1.011V   53.08mA    93.78mA    43.04mA
-949mV    34.63mA    64.31mA    34.62mA
-887mV    24.77mA    41.57mA    28.48mA
-825mV    19.16mA    26.4mA     22.89mA
-732mV    13.32mA    14.81mA    16.07mA
-546mV    6.068mA    6.58mA     7.125mA
-50mV     295.8uA    241.2uA    397.5uA
3V        -17.93mA   -11.75mA   -23.64mA
[Ramp]
| variable   typ   min   max
dV/dt_r   0.464/0.313n   0.441/0.337n   0.479/0.377n
dV/dt_f   0.400/0.334n   0.397/0.332n   0.392/0.414n
R_load = 50.000
[Rising Waveform]
R_fixture = 50.000
V_fixture = 0.000
V_fixture_min = 0.000
V_fixture_max = 0.000
|  time   V(typ)   V(min)   V(max)
0s        146.7mV    108.8mV    199.7mV
351ps     147mV      108.9mV    195.3mV
471ps     149.7mV    108.9mV    546.7mV
569ps     350.8mV    109.2mV    693.9mV
710ps     639.2mV    111.9mV    802.8mV
901ps     783.9mV    472.3mV    877.2mV
1ns       818.6mV    604.6mV    899.9mV
1.339ns   871.6mV    762.9mV    942.5mV
2.62ns    907.1mV    829.6mV    983.5mV
10ns      919.8mV    844.4mV    997.8mV
[Rising Waveform]
R_fixture = 50.000
V_fixture = 0.750
V_fixture_min = 0.713
V_fixture_max = 0.789
|  time   V(typ)   V(min)   V(max)
0s        427.7mV    382.4mV    495.6mV
346ps     427.8mV    382.4mV    497.1mV
458ps     434mV      382.5mV    929.4mV
598ps     860.2mV    380.8mV    1.133V
680ps     1.02V      391mV      1.183V
721ps     1.064V     444.3mV    1.201V
901ps     1.155V     903.4mV    1.247V
1.101ns   1.19V      1.062V     1.27V
2.33ns    1.227V     1.153V     1.304V
10ns      1.238V     1.165V     1.315V
[Falling Waveform]
R_fixture = 50.000
V_fixture = 0.750
V_fixture_min = 0.713
V_fixture_max = 0.789
|  time   V(typ)   V(min)   V(max)
0s        1.238V     1.165V     1.315V
351ps     1.237V     1.165V     1.315V
463ps     1.232V     1.165V     892.4mV
594ps     771.6mV    1.167V     675.7mV
671ps     626mV      1.159V     622.4mV
711ps     585mV      1.09V      603.9mV
861ps     509.1mV    631.6mV    562.9mV
1.049ns   474.5mV    479.6mV    539.8mV
2.261ns   438.7mV    393.7mV    505.9mV
10ns      427.7mV    382.4mV    495.6mV
[Falling Waveform]
R_fixture = 50.000
V_fixture = 0.000
V_fixture_min = 0.000
V_fixture_max = 0.000
|  time   V(typ)   V(min)   V(max)
0s        919.8mV    844.4mV    997.8mV
351ps     919.6mV    844.2mV    994.3mV
451ps     918.7mV    844.3mV    490.7mV
481ps     854.4mV    844.1mV    423.2mV
571ps     416.8mV    846.2mV    328.2mV
661ps     278.1mV    839.3mV    286.4mV
811ps     213.1mV    334.3mV    253.6mV
951ps     189.7mV    203.3mV    238.9mV
1.891ns   158.6mV    121mV      211.2mV
10ns      146.7mV    108.8mV    199.7mV
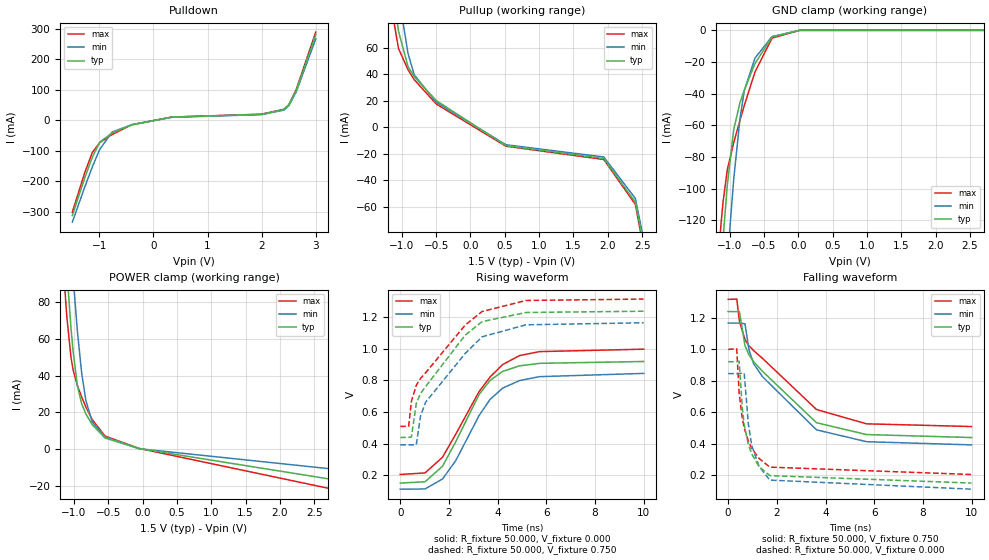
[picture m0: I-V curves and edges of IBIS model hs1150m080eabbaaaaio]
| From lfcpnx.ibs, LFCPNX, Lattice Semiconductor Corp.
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|Model hs1150m080eabbaaaaio
[Model] hs1150m080eabbaaaaio
Model_type I/O
Polarity   Non-Inverting
Enable   Active-Low
Vinl =  0.650V
Vinh =  0.850V
Vmeas =  0.750V
Cref =  30.000pF
Rref =  50.000
Vref =  0.750V
C_comp   5.000pF   4.000pF   5.500pF
[Temperature Range]   25.000   0.125k   -40.000
[Voltage Range]   1.500V   1.430V   1.580V
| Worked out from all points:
|   slope of the pulldown table from 0 to 0.225 V, typ, clamps not added: 31 ohm
|   slope of the pullup table from 0 to 0.225 V, typ, clamps not added: 31.2 ohm
|   GND clamp passes 1 mA (typ) near -0.15 V on its own axis
|   POWER clamp passes 1 mA (typ) near -0.17 V on its own axis
|   rising waveform, R_fixture 50.000, V_fixture 0.000: 20-80 % time 1.56ns typ, 1.65ns min, 1.85ns max; typ from 0.15 V to 0.92 V
|   rising waveform, R_fixture 50.000, V_fixture 0.750: 20-80 % time 2.05ns typ, 2.08ns min, 2.22ns max; typ from 0.439 V to 1.24 V
|   falling waveform, R_fixture 50.000, V_fixture 0.750: 20-80 % time 2.42ns typ, 2.23ns min, 2.7ns max; typ from 1.24 V to 0.439 V
|   falling waveform, R_fixture 50.000, V_fixture 0.000: 20-80 % time 539ps typ, 515ps min, 594ps max; typ from 0.92 V to 0.15 V
[Pulldown]
|Voltage   I(typ)   I(min)   I(max)
-1.5V     -313.3mA   -335mA     -302.1mA
-1.27V    -189.4mA   -219.3mA   -172mA
-1.132V   -122.2mA   -153.9mA   -106.6mA
-994mV    -72.1mA    -95.8mA    -73.4mA
-764mV    -41.63mA   -38.61mA   -46.78mA
-396mV    -15.05mA   -14.24mA   -14.33mA
340mV     10.34mA    9.824mA    10.65mA
1.996V    19.41mA    18.44mA    19.99mA
2.41V     34.97mA    33.22mA    36.02mA
2.502V    49.81mA    47.32mA    51.3mA
2.64V     98.3mA     93.4mA     101.2mA
3V        281.4mA    267.3mA    289.8mA
[Pullup]
|Voltage   I(typ)   I(min)   I(max)
-1.5V     294.8mA    323.3mA    276.8mA
-1.186V   128.1mA    161.6mA    106.6mA
-1.14V    107.1mA    140mA      86.9mA
-1.048V   72.31mA    100.2mA    59.29mA
-910mV    45.66mA    55.61mA    43.29mA
-818mV    37.9mA     39.34mA    35.67mA
-496mV    19.91mA    18.64mA    17.36mA
516mV     -13.95mA   -13.25mA   -14.37mA
1.942V    -23.66mA   -22.47mA   -24.37mA
2.402V    -56.58mA   -53.75mA   -58.27mA
2.586V    -105.8mA   -100.5mA   -109mA
3V        -324mA     -307.8mA   -333.7mA
[GND_clamp]
|Voltage   I(typ)   I(min)   I(max)
-1.5V     -423.6mA   -473.4mA   -391.3mA
-1.159V   -170.8mA   -226.4mA   -140.1mA
-1.128V   -150.6mA   -205.4mA   -123mA
-1.097V   -131.5mA   -185mA     -108.4mA
-1.035V   -97.76mA   -145.9mA   -88.03mA
-942mV    -62.68mA   -94.08mA   -70.99mA
-849mV    -45.44mA   -55.18mA   -56.59mA
-787mV    -37.67mA   -38mA      -47.37mA
-632mV    -20.99mA   -17.55mA   -26.32mA
-384mV    -4.202mA   -3.933mA   -4.89mA
19mV      0A         0A         0A
3V        0A         0A         0A
[POWER_clamp]
|Voltage   I(typ)   I(min)   I(max)
-1.5V     377.8mA    420.9mA    350.6mA
-1.166V   135.9mA    186.4mA    106mA
-1.104V   98.02mA    147mA      72.63mA
-1.042V   66.02mA    110.5mA    49.91mA
-1.011V   53.08mA    93.78mA    43.04mA
-949mV    34.63mA    64.31mA    34.62mA
-887mV    24.77mA    41.57mA    28.48mA
-825mV    19.16mA    26.4mA     22.89mA
-732mV    13.32mA    14.81mA    16.07mA
-546mV    6.068mA    6.58mA     7.125mA
-50mV     295.8uA    241.2uA    397.5uA
3V        -17.93mA   -11.75mA   -23.64mA
[Ramp]
| variable   typ   min   max
dV/dt_r   0.462/1.572n   0.440/1.683n   0.476/1.873n
dV/dt_f   0.386/2.673n   0.384/2.569n   0.378/2.889n
R_load = 50.000
[Rising Waveform]
R_fixture = 50.000
V_fixture = 0.000
V_fixture_min = 0.000
V_fixture_max = 0.000
|  time   V(typ)   V(min)   V(max)
0s        150.2mV    111.5mV    204.5mV
1.018ns   158.2mV    112.8mV    214.3mV
1.738ns   256.7mV    176.2mV    313.8mV
2.281ns   412.1mV    292.3mV    459.7mV
3.238ns   710.4mV    577.6mV    729.1mV
3.69ns    800mV      679.7mV    821.8mV
4.21ns    857.4mV    751.3mV    900.6mV
4.899ns   892mV      799mV      957mV
5.725ns   908.1mV    823.8mV    982.4mV
10ns      919.8mV    844.4mV    997.8mV
[Rising Waveform]
R_fixture = 50.000
V_fixture = 0.750
V_fixture_min = 0.713
V_fixture_max = 0.789
|  time   V(typ)   V(min)   V(max)
0s        438.9mV    392.3mV    508.6mV
346ps     439.2mV    392.3mV    509.6mV
458ps     441.9mV    392.4mV    667mV
661ps     655mV      393mV      769.4mV
831ps     716.3mV    572.1mV    812.3mV
1.039ns   760.5mV    661.2mV    847.6mV
2.672ns   1.087V     971.3mV    1.151V
3.361ns   1.172V     1.076V     1.236V
5.167ns   1.23V      1.152V     1.306V
10ns      1.238V     1.165V     1.315V
[Falling Waveform]
R_fixture = 50.000
V_fixture = 0.750
V_fixture_min = 0.713
V_fixture_max = 0.789
|  time   V(typ)   V(min)   V(max)
0s        1.238V     1.165V     1.315V
356ps     1.237V     1.165V     1.317V
461ps     1.239V     1.165V     1.177V
691ps     1.022V     1.16V      1.06V
851ps     964mV      998.6mV    1.022V
1.051ns   919.2mV    905.5mV    989.7mV
1.412ns   858.6mV    824.6mV    940.7mV
3.629ns   532.9mV    487.8mV    616.6mV
5.685ns   457.8mV    412.5mV    525.9mV
10ns      438.9mV    392.3mV    508.6mV
[Falling Waveform]
R_fixture = 50.000
V_fixture = 0.000
V_fixture_min = 0.000
V_fixture_max = 0.000
|  time   V(typ)   V(min)   V(max)
0s        919.8mV    844.4mV    997.8mV
351ps     919.5mV    844.2mV    1.002V
451ps     922.9mV    844.3mV    724mV
581ps     627.1mV    848mV      559.5mV
660ps     518mV      846.1mV    500.1mV
831ps     394mV      524mV      415.5mV
971ps     334.1mV    387.5mV    370.8mV
1.271ns   254.3mV    255.9mV    306.1mV
1.711ns   197.3mV    169mV      251.2mV
10ns      150.2mV    111.5mV    204.5mV
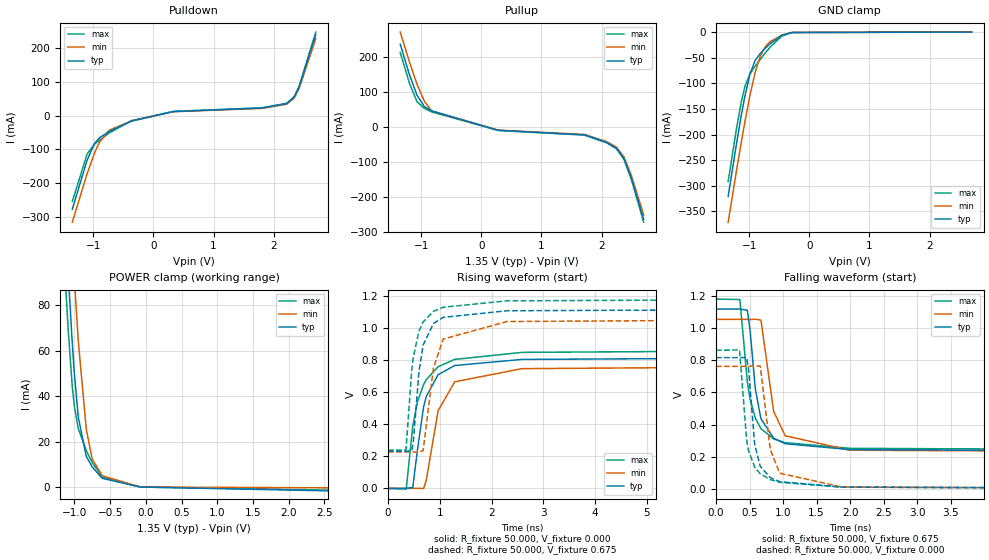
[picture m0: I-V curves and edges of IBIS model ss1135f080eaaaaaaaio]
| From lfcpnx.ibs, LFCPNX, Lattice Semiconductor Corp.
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|Model ss1135f080eaaaaaaaio
[Model] ss1135f080eaaaaaaaio
| Clamp models do not include dynamic input termination. Please refer to
| the ss1135axxxeaaaaaaain model for input termination.
Model_type I/O
Polarity   Non-Inverting
Enable   Active-Low
Vinl =  0.575V
Vinh =  0.775V
Vmeas =  0.675V
Cref =  30.000pF
Rref =  50.000
Vref =  0.675V
C_comp   5.000pF   4.000pF   5.500pF
[Temperature Range]   25.000   0.125k   -40.000
[Voltage Range]   1.350V   1.280V   1.420V
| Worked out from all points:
|   slope of the pulldown table from 0 to 0.203 V, typ, clamps not added: 25.7 ohm
|   slope of the pullup table from 0 to 0.203 V, typ, clamps not added: 25.7 ohm
|   GND clamp passes 1 mA (typ) near -0.31 V on its own axis
|   POWER clamp passes 1 mA (typ) near -0.43 V on its own axis
|   rising waveform, R_fixture 50.000, V_fixture 0.000: 20-80 % time 296ps typ, 349ps min, 353ps max; typ from 0 V to 0.816 V
|   rising waveform, R_fixture 50.000, V_fixture 0.675: 20-80 % time 203ps typ, 247ps min, 220ps max; typ from 0.231 V to 1.12 V
|   falling waveform, R_fixture 50.000, V_fixture 0.675: 20-80 % time 177ps typ, 194ps min, 200ps max; typ from 1.12 V to 0.231 V
|   falling waveform, R_fixture 50.000, V_fixture 0.000: 20-80 % time 134ps typ, 152ps min, 147ps max; typ from 0.816 V to 0 V
[Pulldown]
|Voltage   I(typ)   I(min)   I(max)
-1.35V    -277.3mA   -315.7mA   -254.1mA
-1.104V   -131.8mA   -172.2mA   -113.9mA
-981mV    -82.52mA   -110.9mA   -84.53mA
-899mV    -65.62mA   -78.8mA    -73.06mA
-735mV    -46.86mA   -43.22mA   -51.4mA
-366mV    -16.29mA   -15.7mA    -15.06mA
331mV     12.13mA    11.52mA    12.49mA
1.807V    22.48mA    21.36mA    23.16mA
2.217V    35.47mA    33.7mA     36.54mA
2.34V     54.25mA    51.54mA    55.88mA
2.422V    83.69mA    79.5mA     86.2mA
2.7V      240.2mA    228.2mA    247.4mA
[Pullup]
|Voltage   I(typ)   I(min)   I(max)
-1.35V    235.7mA    270.5mA    212.2mA
-1.195V   147.7mA    184mA      123.1mA
-1.072V   90.3mA     122mA      71.84mA
-949mV    57.71mA    72.88mA    52.16mA
-826mV    45.48mA    44.73mA    42.17mA
281mV     -10.4mA    -9.876mA   -10.71mA
1.716V    -23.3mA    -22.14mA   -24mA
2.085V    -44.85mA   -42.61mA   -46.19mA
2.249V    -61.62mA   -58.54mA   -63.47mA
2.372V    -90.7mA    -86.2mA    -93.4mA
2.495V    -146.2mA   -138.9mA   -150.6mA
2.7V      -265mA     -251.7mA   -273mA
[GND_clamp]
|Voltage   I(typ)   I(min)   I(max)
-1.35V    -320.9mA   -371mA     -291.7mA
-1.21V    -216.8mA   -269.5mA   -187.2mA
-1.126V   -159mA     -211.3mA   -133.3mA
-1.07V    -124.2mA   -174.2mA   -105.6mA
-986mV    -81.78mA   -122.8mA   -81.18mA
-902mV    -55.61mA   -79.36mA   -66.72mA
-818mV    -41.95mA   -47.73mA   -53.44mA
-734mV    -31.67mA   -28.77mA   -40.78mA
-650mV    -22.47mA   -18.69mA   -29.01mA
-454mV    -6.221mA   -5.753mA   -7.69mA
-286mV    -734.4uA   -759.2uA   -785.5uA
2.7V      0A         0A         0A
[POWER_clamp]
|Voltage   I(typ)   I(min)   I(max)
-1.35V    276.5mA    320.5mA    251mA
-1.142V   128.3mA    176.6mA    100.9mA
-1.114V   110.5mA    158.5mA    83.9mA
-1.086V   93.5mA     140.9mA    68.53mA
-1.03V    63.21mA    107.6mA    44.18mA
-1.002V   50.42mA    92.11mA    35.83mA
-946mV    30.82mA    64.28mA    25.76mA
-834mV    13.57mA    25.52mA    16.1mA
-750mV    8.839mA    12.31mA    10.8mA
-610mV    3.896mA    5.035mA    4.505mA
-78mV     75.17uA    92.3uA     98.29uA
2.7V      -1.695mA   -291.3uA   -1.333mA
[Ramp]
| variable   typ   min   max
dV/dt_r   0.489/0.296n   0.478/0.346n   0.530/0.355n
dV/dt_f   0.497/0.285n   0.462/0.289n   0.541/0.351n
R_load = 50.000
[Rising Waveform]
R_fixture = 50.000
V_fixture = 0.000
V_fixture_min = 0.000
V_fixture_max = 0.000
|  time   V(typ)   V(min)   V(max)
0s        16.67uV    -12.65uV   -188.5uV
351ps     414.8uV    13.65uV    -5.011mV
477ps     5.224mV    99.7uV     387.5mV
567ps     237.6mV    453uV      538.8mV
686ps     507.1mV    -1.03mV    646.8mV
737ps     571.5mV    48.72mV    677.3mV
967ps     708.6mV    483.9mV    758mV
1.287ns   765.6mV    664mV      803.7mV
2.587ns   803.9mV    746.2mV    847.7mV
10ns      816.4mV    762.3mV    861.8mV
[Rising Waveform]
R_fixture = 50.000
V_fixture = 0.675
V_fixture_min = 0.642
V_fixture_max = 0.710
|  time   V(typ)   V(min)   V(max)
0s        230.8mV    226.7mV    238.6mV
346ps     231mV      226.8mV    238.8mV
457ps     234.2mV    226.8mV    735.4mV
487ps     286.5mV    226.9mV    817.6mV
597ps     727.9mV    225mV      980.2mV
677ps     892.7mV    235.4mV    1.037V
877ps     1.028V     750mV      1.103V
1.065ns   1.066V     930.6mV    1.129V
2.298ns   1.107V     1.04V      1.169V
10ns      1.118V     1.054V     1.18V
[Falling Waveform]
R_fixture = 50.000
V_fixture = 0.675
V_fixture_min = 0.642
V_fixture_max = 0.710
|  time   V(typ)   V(min)   V(max)
0s        1.118V     1.054V     1.18V
356ps     1.118V     1.054V     1.177V
467ps     1.111V     1.054V     670.1mV
507ps     992.8mV    1.053V     561.2mV
587ps     621mV      1.055V     439.8mV
671ps     436.6mV    1.049V     375.3mV
860ps     316.3mV    483.1mV    312.1mV
1.033ns   282.1mV    331.2mV    288.5mV
1.997ns   245.4mV    241.5mV    253.2mV
10ns      230.8mV    226.7mV    238.6mV
[Falling Waveform]
R_fixture = 50.000
V_fixture = 0.000
V_fixture_min = 0.000
V_fixture_max = 0.000
|  time   V(typ)   V(min)   V(max)
0s        816.4mV    762.3mV    861.8mV
351ps     816.2mV    762.1mV    864.3mV
457ps     817.3mV    762.2mV    306.2mV
487ps     739.6mV    761.9mV    236.1mV
577ps     276.8mV    765.7mV    136.7mV
661ps     141.2mV    763.5mV    94.76mV
810ps     71.42mV    245mV      58.83mV
951ps     46.05mV    99mV       42.49mV
1.883ns   12.74mV    12.86mV    12.38mV
10ns      16.67uV    -12.65uV   -188.5uV
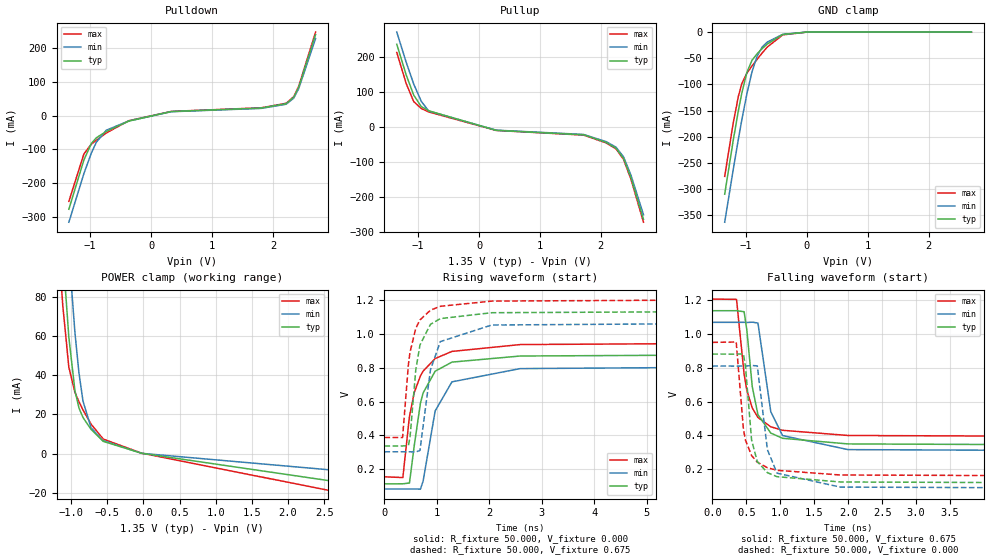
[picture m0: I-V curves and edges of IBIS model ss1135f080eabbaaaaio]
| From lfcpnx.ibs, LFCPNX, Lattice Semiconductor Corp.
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|Model ss1135f080eabbaaaaio
[Model] ss1135f080eabbaaaaio
| Clamp models do not include dynamic input termination. Please refer to
| the ss1135axxxeabbaaaain model for input termination.
Model_type I/O
Polarity   Non-Inverting
Enable   Active-Low
Vinl =  0.575V
Vinh =  0.775V
Vmeas =  0.675V
Cref =  30.000pF
Rref =  50.000
Vref =  0.675V
C_comp   5.000pF   4.000pF   5.500pF
[Temperature Range]   25.000   0.125k   -40.000
[Voltage Range]   1.350V   1.280V   1.420V
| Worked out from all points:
|   slope of the pulldown table from 0 to 0.203 V, typ, clamps not added: 25.7 ohm
|   slope of the pullup table from 0 to 0.203 V, typ, clamps not added: 25.7 ohm
|   GND clamp passes 1 mA (typ) near -0.15 V on its own axis
|   POWER clamp passes 1 mA (typ) near -0.17 V on its own axis
|   rising waveform, R_fixture 50.000, V_fixture 0.000: 20-80 % time 296ps typ, 349ps min, 353ps max; typ from 0.111 V to 0.882 V
|   rising waveform, R_fixture 50.000, V_fixture 0.675: 20-80 % time 203ps typ, 247ps min, 221ps max; typ from 0.336 V to 1.14 V
|   falling waveform, R_fixture 50.000, V_fixture 0.675: 20-80 % time 177ps typ, 194ps min, 200ps max; typ from 1.14 V to 0.336 V
|   falling waveform, R_fixture 50.000, V_fixture 0.000: 20-80 % time 134ps typ, 152ps min, 147ps max; typ from 0.882 V to 0.111 V
[Pulldown]
|Voltage   I(typ)   I(min)   I(max)
-1.35V    -277.3mA   -315.7mA   -254.1mA
-1.104V   -131.8mA   -172.2mA   -113.9mA
-981mV    -82.52mA   -110.9mA   -84.53mA
-899mV    -65.62mA   -78.8mA    -73.06mA
-735mV    -46.86mA   -43.22mA   -51.4mA
-366mV    -16.29mA   -15.7mA    -15.06mA
331mV     12.13mA    11.52mA    12.49mA
1.807V    22.48mA    21.36mA    23.16mA
2.217V    35.47mA    33.7mA     36.54mA
2.34V     54.25mA    51.54mA    55.88mA
2.422V    83.69mA    79.5mA     86.2mA
2.7V      240.2mA    228.2mA    247.4mA
[Pullup]
|Voltage   I(typ)   I(min)   I(max)
-1.35V    235.7mA    270.5mA    212.2mA
-1.195V   147.7mA    184mA      123.1mA
-1.072V   90.3mA     122mA      71.84mA
-949mV    57.71mA    72.88mA    52.16mA
-826mV    45.48mA    44.73mA    42.17mA
281mV     -10.4mA    -9.876mA   -10.71mA
1.716V    -23.3mA    -22.14mA   -24mA
2.085V    -44.85mA   -42.61mA   -46.19mA
2.249V    -61.62mA   -58.54mA   -63.47mA
2.372V    -90.7mA    -86.2mA    -93.4mA
2.495V    -146.2mA   -138.9mA   -150.6mA
2.7V      -265mA     -251.7mA   -273mA
[GND_clamp]
|Voltage   I(typ)   I(min)   I(max)
-1.35V    -309.8mA   -363.4mA   -275.8mA
-1.21V    -207.1mA   -262.8mA   -173.9mA
-1.126V   -150.5mA   -205.1mA   -123.2mA
-1.07V    -117mA     -168.5mA   -98.8mA
-986mV    -77.25mA   -118.1mA   -78.4mA
-902mV    -53.89mA   -76.04mA   -64.81mA
-818mV    -41.42mA   -46.02mA   -52mA
-734mV    -31.56mA   -28.41mA   -39.82mA
-650mV    -22.69mA   -19.03mA   -28.57mA
-398mV    -4.585mA   -4.332mA   -5.35mA
-6mV      -40.55uA   -29.88uA   -52.89uA
2.7V      0A         0A         0A
[POWER_clamp]
|Voltage   I(typ)   I(min)   I(max)
-1.35V    264.6mA    312.3mA    234.2mA
-1.17V    138mA      188.5mA    107.5mA
-1.142V   120.1mA    170.4mA    90.88mA
-1.114V   103.1mA    152.7mA    75.88mA
-1.03V    59.59mA    103.2mA    44.19mA
-946mV    32.22mA    62.05mA    31.33mA
-890mV    23.29mA    41.28mA    26.5mA
-834mV    18.42mA    26.8mA     22.3mA
-722mV    12.33mA    13.1mA     15mA
-554mV    6.226mA    6.542mA    7.404mA
-22mV     128.8uA    103.1uA    167.9uA
2.7V      -14.6mA    -8.747mA   -19.86mA
[Ramp]
| variable   typ   min   max
dV/dt_r   0.462/0.296n   0.438/0.346n   0.479/0.355n
dV/dt_f   0.432/0.285n   0.420/0.289n   0.430/0.351n
R_load = 50.000
[Rising Waveform]
R_fixture = 50.000
V_fixture = 0.000
V_fixture_min = 0.000
V_fixture_max = 0.000
|  time   V(typ)   V(min)   V(max)
0s        111.4mV    80.78mV    153.2mV
351ps     111.7mV    80.81mV    148.7mV
477ps     116.3mV    80.89mV    512mV
567ps     335.5mV    81.23mV    652mV
686ps     589.9mV    79.81mV    752mV
737ps     650.6mV    127.5mV    780.3mV
967ps     780mV      544.2mV    855mV
1.287ns   833.8mV    716.7mV    897.3mV
2.587ns   870mV      795.3mV    938mV
10ns      881.8mV    810.8mV    951.1mV
[Rising Waveform]
R_fixture = 50.000
V_fixture = 0.675
V_fixture_min = 0.642
V_fixture_max = 0.710
|  time   V(typ)   V(min)   V(max)
0s        335.9mV    301.6mV    386.3mV
346ps     336.1mV    301.7mV    386.6mV
457ps     339mV      301.7mV    820.3mV
487ps     386.3mV    301.8mV    892.1mV
597ps     786.1mV    300mV      1.034V
677ps     935.4mV    309.7mV    1.084V
877ps     1.058V     787.6mV    1.142V
1.065ns   1.092V     955.4mV    1.165V
2.045ns   1.127V     1.054V     1.196V
10ns      1.139V     1.07V      1.208V
[Falling Waveform]
R_fixture = 50.000
V_fixture = 0.675
V_fixture_min = 0.642
V_fixture_max = 0.710
|  time   V(typ)   V(min)   V(max)
0s        1.139V     1.07V      1.208V
356ps     1.139V     1.07V      1.206V
467ps     1.133V     1.07V      763.3mV
507ps     1.026V     1.069V     668.1mV
587ps     689.3mV    1.071V     562.1mV
671ps     522.3mV    1.066V     505.8mV
860ps     413.4mV    539.8mV    450.5mV
1.033ns   382.4mV    398.6mV    429.9mV
1.997ns   349.1mV    315.3mV    399.1mV
10ns      335.9mV    301.6mV    386.3mV
[Falling Waveform]
R_fixture = 50.000
V_fixture = 0.000
V_fixture_min = 0.000
V_fixture_max = 0.000
|  time   V(typ)   V(min)   V(max)
0s        881.8mV    810.8mV    951.1mV
351ps     881.6mV    810.6mV    953.4mV
457ps     882.6mV    810.7mV    436.8mV
487ps     809.3mV    810.4mV    371.9mV
577ps     372.6mV    814mV      279.9mV
661ps     244.6mV    811.9mV    241.1mV
810ps     178.7mV    315.4mV    207.8mV
951ps     154.8mV    175.6mV    192.7mV
1.883ns   123.4mV    93.11mV    164.8mV
10ns      111.4mV    80.78mV    153.2mV
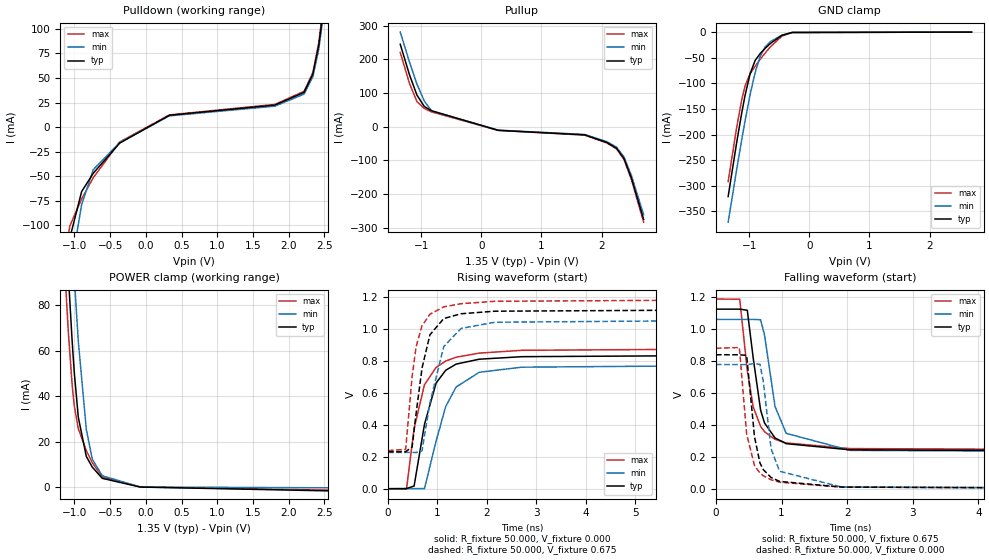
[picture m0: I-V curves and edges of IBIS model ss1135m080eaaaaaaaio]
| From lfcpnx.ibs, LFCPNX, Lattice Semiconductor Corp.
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|Model ss1135m080eaaaaaaaio
[Model] ss1135m080eaaaaaaaio
| Clamp models do not include dynamic input termination. Please refer to
| the ss1135axxxeaaaaaaain model for input termination.
Model_type I/O
Polarity   Non-Inverting
Enable   Active-Low
Vinl =  0.575V
Vinh =  0.775V
Vmeas =  0.675V
Cref =  30.000pF
Rref =  50.000
Vref =  0.675V
C_comp   5.000pF   4.000pF   5.500pF
[Temperature Range]   25.000   0.125k   -40.000
[Voltage Range]   1.350V   1.280V   1.420V
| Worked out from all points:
|   slope of the pulldown table from 0 to 0.203 V, typ, clamps not added: 25.7 ohm
|   slope of the pullup table from 0 to 0.203 V, typ, clamps not added: 24.7 ohm
|   GND clamp passes 1 mA (typ) near -0.31 V on its own axis
|   POWER clamp passes 1 mA (typ) near -0.43 V on its own axis
|   rising waveform, R_fixture 50.000, V_fixture 0.000: 20-80 % time 372ps typ, 469ps min, 375ps max; typ from 0 V to 0.839 V
|   rising waveform, R_fixture 50.000, V_fixture 0.675: 20-80 % time 282ps typ, 359ps min, 247ps max; typ from 0.231 V to 1.12 V
|   falling waveform, R_fixture 50.000, V_fixture 0.675: 20-80 % time 206ps typ, 235ps min, 218ps max; typ from 1.12 V to 0.231 V
|   falling waveform, R_fixture 50.000, V_fixture 0.000: 20-80 % time 150ps typ, 172ps min, 158ps max; typ from 0.839 V to 0 V
[Pulldown]
|Voltage   I(typ)   I(min)   I(max)
-1.35V    -276.8mA   -315.1mA   -253.5mA
-1.186V   -176.1mA   -217.7mA   -152.5mA
-1.063V   -112.3mA   -150.2mA   -100.2mA
-899mV    -65.48mA   -78.63mA   -72.91mA
-735mV    -46.76mA   -43.13mA   -51.29mA
-366mV    -16.25mA   -15.67mA   -15.03mA
331mV     12.1mA     11.5mA     12.46mA
1.807V    22.43mA    21.31mA    23.1mA
2.217V    35.4mA     33.63mA    36.46mA
2.34V     54.13mA    51.43mA    55.76mA
2.422V    83.51mA    79.33mA    86.01mA
2.7V      239.7mA    227.7mA    246.9mA
[Pullup]
|Voltage   I(typ)   I(min)   I(max)
-1.35V    245mA      281.2mA    220.6mA
-1.195V   153.6mA    191.3mA    127.9mA
-1.072V   93.9mA     126.8mA    74.67mA
-949mV    59.98mA    75.75mA    54.22mA
-826mV    47.27mA    46.49mA    43.83mA
281mV     -10.8mA    -10.26mA   -11.13mA
1.716V    -24.22mA   -23.01mA   -24.95mA
2.085V    -46.61mA   -44.28mA   -48.01mA
2.249V    -64.05mA   -60.85mA   -65.97mA
2.372V    -94.3mA    -89.6mA    -97.1mA
2.495V    -151.9mA   -144.3mA   -156.5mA
2.7V      -275.5mA   -261.7mA   -283.8mA
[GND_clamp]
|Voltage   I(typ)   I(min)   I(max)
-1.35V    -320.9mA   -371mA     -291.7mA
-1.21V    -216.8mA   -269.5mA   -187.2mA
-1.126V   -159mA     -211.3mA   -133.3mA
-1.07V    -124.2mA   -174.2mA   -105.6mA
-986mV    -81.78mA   -122.8mA   -81.18mA
-902mV    -55.61mA   -79.36mA   -66.72mA
-818mV    -41.95mA   -47.73mA   -53.44mA
-734mV    -31.67mA   -28.77mA   -40.78mA
-650mV    -22.47mA   -18.69mA   -29.01mA
-454mV    -6.221mA   -5.753mA   -7.69mA
-286mV    -734.4uA   -759.2uA   -785.5uA
2.7V      0A         0A         0A
[POWER_clamp]
|Voltage   I(typ)   I(min)   I(max)
-1.35V    276.5mA    320.5mA    251mA
-1.142V   128.3mA    176.6mA    100.9mA
-1.114V   110.5mA    158.5mA    83.9mA
-1.086V   93.5mA     140.9mA    68.53mA
-1.03V    63.21mA    107.6mA    44.18mA
-1.002V   50.42mA    92.11mA    35.83mA
-946mV    30.82mA    64.28mA    25.76mA
-834mV    13.57mA    25.52mA    16.1mA
-750mV    8.839mA    12.31mA    10.8mA
-610mV    3.896mA    5.035mA    4.505mA
-78mV     75.17uA    92.3uA     98.29uA
2.7V      -1.695mA   -291.3uA   -1.333mA
[Ramp]
| variable   typ   min   max
dV/dt_r   0.499/0.378n   0.478/0.470n   0.530/0.381n
dV/dt_f   0.497/0.328n   0.462/0.353n   0.541/0.374n
R_load = 50.000
[Rising Waveform]
R_fixture = 50.000
V_fixture = 0.000
V_fixture_min = 0.000
V_fixture_max = 0.000
|  time   V(typ)   V(min)   V(max)
0s        18.55uV    -11.93uV   -186.3uV
373ps     721.7uV    12.09uV    -3.003mV
527ps     16.52mV    405.1uV    377.5mV
737ps     402.6mV    737.9uV    650.9mV
972ps     661mV      297mV      758.9mV
1.166ns   741.2mV    514mV      798.9mV
1.377ns   779.8mV    636.3mV    822.9mV
1.847ns   810.6mV    728.9mV    848.7mV
2.71ns    826.4mV    760.6mV    866.2mV
10ns      839.2mV    778.1mV    879.8mV
[Rising Waveform]
R_fixture = 50.000
V_fixture = 0.675
V_fixture_min = 0.642
V_fixture_max = 0.710
|  time   V(typ)   V(min)   V(max)
0s        231.1mV    227.1mV    238.9mV
356ps     231.4mV    227.1mV    245.6mV
487ps     261mV      227.2mV    703.9mV
567ps     469.4mV    226.4mV    888mV
687ps     754.4mV    236.8mV    1.02V
847ps     963.2mV    538.3mV    1.092V
1.127ns   1.065V     889.5mV    1.138V
1.477ns   1.095V     1.003V     1.158V
2.157ns   1.111V     1.042V     1.173V
10ns      1.124V     1.06V      1.187V
[Falling Waveform]
R_fixture = 50.000
V_fixture = 0.675
V_fixture_min = 0.642
V_fixture_max = 0.710
|  time   V(typ)   V(min)   V(max)
0s        1.124V     1.06V      1.187V
362ps     1.124V     1.06V      1.186V
477ps     1.117V     1.06V      739.4mV
567ps     819.5mV    1.06V      513.6mV
680ps     492.9mV    1.058V     391.5mV
740ps     412.8mV    961.8mV    358.3mV
900ps     319.7mV    515.5mV    311.1mV
1.07ns    284mV      348.5mV    288.5mV
2.04ns    245.7mV    242.2mV    253.4mV
10ns      231.1mV    227.1mV    238.9mV
[Falling Waveform]
R_fixture = 50.000
V_fixture = 0.000
V_fixture_min = 0.000
V_fixture_max = 0.000
|  time   V(typ)   V(min)   V(max)
0s        839.2mV    778.1mV    879.8mV
356ps     839mV      777.8mV    884.3mV
467ps     835.5mV    777.8mV    344mV
587ps     326.4mV    783.7mV    147.1mV
670ps     163.5mV    779.2mV    100.7mV
720ps     122.3mV    675.4mV    83.55mV
840ps     72.5mV     251.1mV    58.19mV
970ps     48.08mV    111.2mV    43.23mV
1.917ns   12.94mV    13.07mV    12.41mV
10ns      18.55uV    -11.93uV   -186.3uV
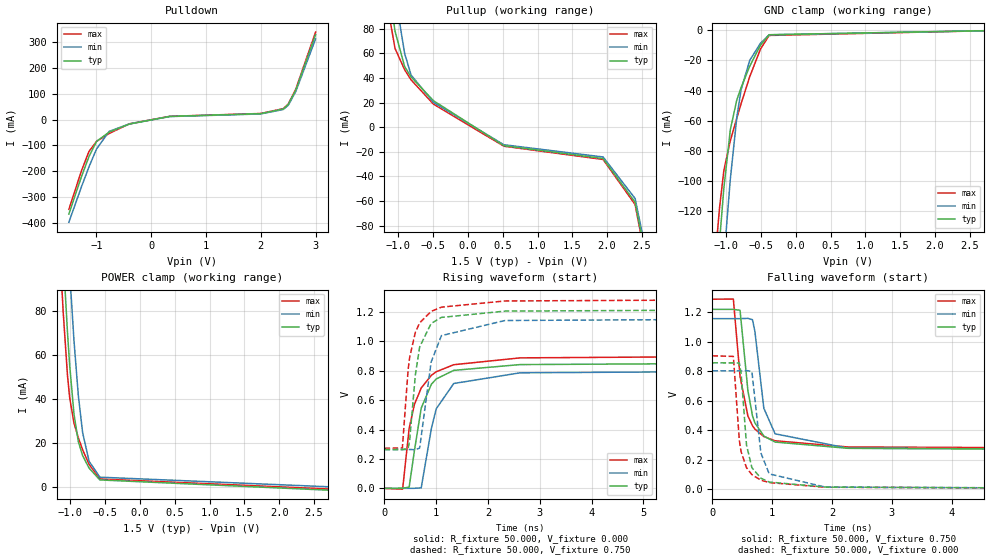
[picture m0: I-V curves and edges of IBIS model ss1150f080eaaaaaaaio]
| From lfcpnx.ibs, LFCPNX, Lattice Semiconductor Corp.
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|Model ss1150f080eaaaaaaaio
[Model] ss1150f080eaaaaaaaio
| Clamp models do not include dynamic input termination. Please refer to
| the ss1150axxxeaaaaaaain model for input termination.
Model_type I/O
Polarity   Non-Inverting
Enable   Active-Low
Vinl =  0.650V
Vinh =  0.850V
Vmeas =  0.750V
Cref =  30.000pF
Rref =  50.000
Vref =  0.750V
C_comp   5.000pF   4.000pF   5.500pF
[Temperature Range]   25.000   0.125k   -40.000
[Voltage Range]   1.500V   1.430V   1.580V
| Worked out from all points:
|   slope of the pulldown table from 0 to 0.225 V, typ, clamps not added: 26.6 ohm
|   slope of the pullup table from 0 to 0.225 V, typ, clamps not added: 28.9 ohm
|   GND clamp passes 1 mA (typ) near -0.31 V on its own axis
|   POWER clamp passes 1 mA (typ) near -0.43 V on its own axis
|   rising waveform, R_fixture 50.000, V_fixture 0.000: 20-80 % time 310ps typ, 333ps min, 377ps max; typ from 0 V to 0.857 V
|   rising waveform, R_fixture 50.000, V_fixture 0.750: 20-80 % time 217ps typ, 245ps min, 234ps max; typ from 0.264 V to 1.22 V
|   falling waveform, R_fixture 50.000, V_fixture 0.750: 20-80 % time 189ps typ, 202ps min, 215ps max; typ from 1.22 V to 0.264 V
|   falling waveform, R_fixture 50.000, V_fixture 0.000: 20-80 % time 135ps typ, 149ps min, 147ps max; typ from 0.857 V to 0 V
[Pulldown]
|Voltage   I(typ)   I(min)   I(max)
-1.5V     -365.1mA   -396.5mA   -347.3mA
-1.27V    -220.7mA   -259.6mA   -197.7mA
-1.132V   -142.4mA   -182mA     -122.7mA
-994mV    -84mA      -113.3mA   -84.4mA
-764mV    -48.51mA   -45.68mA   -53.79mA
-396mV    -17.54mA   -16.85mA   -16.47mA
340mV     12.05mA    11.45mA    12.41mA
1.996V    22.61mA    21.48mA    23.29mA
2.41V     40.75mA    38.71mA    41.97mA
2.502V    58.04mA    55.14mA    59.78mA
2.64V     114.5mA    108.8mA    117.9mA
3V        327.9mA    311.5mA    337.7mA
[Pullup]
|Voltage   I(typ)   I(min)   I(max)
-1.5V     318.1mA    348.8mA    298.7mA
-1.186V   138.2mA    174.4mA    115mA
-1.14V    115.6mA    151mA      93.7mA
-1.048V   78.01mA    108.2mA    63.97mA
-910mV    49.26mA    59.99mA    46.7mA
-818mV    40.89mA    42.44mA    38.48mA
-496mV    21.49mA    20.11mA    18.73mA
516mV     -15.05mA   -14.3mA    -15.5mA
1.942V    -25.52mA   -24.25mA   -26.29mA
2.402V    -61.04mA   -57.99mA   -62.87mA
2.586V    -114.2mA   -108.5mA   -117.6mA
3V        -349.5mA   -332mA     -360mA
[GND_clamp]
|Voltage   I(typ)   I(min)   I(max)
-1.5V     -437.6mA   -483.1mA   -411.3mA
-1.159V   -181.2mA   -234mA     -153.2mA
-1.128V   -160.4mA   -212.8mA   -134.5mA
-1.097V   -140.5mA   -192mA     -117.9mA
-1.035V   -104.9mA   -152.2mA   -93.08mA
-942mV    -66.01mA   -98.88mA   -73.31mA
-849mV    -46.26mA   -57.94mA   -58.29mA
-787mV    -38.01mA   -39.4mA    -48.69mA
-663mV    -23.84mA   -19.92mA   -30.76mA
-508mV    -9.791mA   -8.549mA   -12.41mA
-384mV    -2.92mA    -2.99mA    -3.392mA
3V        0A         0A         0A
[POWER_clamp]
|Voltage   I(typ)   I(min)   I(max)
-1.5V     391.5mA    430.3mA    369.8mA
-1.166V   144.9mA    193mA      117.4mA
-1.135V   124.5mA    172.6mA    97.69mA
-1.104V   105.1mA    152.8mA    79.63mA
-1.042V   70.22mA    115.2mA    50.64mA
-1.011V   55.5mA     97.74mA    40.7mA
-949mV    33.19mA    66.57mA    29.05mA
-887mV    20.7mA     41.83mA    22.48mA
-825mV    14.31mA    24.76mA    16.96mA
-732mV    8.589mA    11.69mA    10.31mA
-577mV    3.202mA    4.456mA    3.639mA
3V        -1.88mA    -305.7uA   -1.33mA
[Ramp]
| variable   typ   min   max
dV/dt_r   0.514/0.312n   0.482/0.337n   0.561/0.377n
dV/dt_f   0.527/0.334n   0.492/0.332n   0.584/0.414n
R_load = 50.000
[Rising Waveform]
R_fixture = 50.000
V_fixture = 0.000
V_fixture_min = 0.000
V_fixture_max = 0.000
|  time   V(typ)   V(min)   V(max)
0s        67.51uV    -31.65uV   -689.5uV
351ps     416uV      -5.961uV   -5.694mV
477ps     8.113mV    68.44uV    407.6mV
578ps     254.8mV    158.9uV    570.8mV
710ps     546.3mV    3.429mV    683.6mV
907ps     709.3mV    408.9mV    769.8mV
1ns       744.8mV    541.8mV    793.7mV
1.338ns   803.4mV    713.9mV    841.9mV
2.62ns    842.8mV    786.7mV    888.5mV
10ns      856.8mV    802.9mV    904.7mV
[Rising Waveform]
R_fixture = 50.000
V_fixture = 0.750
V_fixture_min = 0.713
V_fixture_max = 0.789
|  time   V(typ)   V(min)   V(max)
0s        263.8mV    264.4mV    273mV
346ps     263.9mV    264.5mV    274.9mV
457ps     270.5mV    264.6mV    808mV
487ps     327.7mV    264.6mV    892.3mV
597ps     772.3mV    262.7mV    1.063V
680ps     963.2mV    274.3mV    1.127V
901ps     1.123V     859.5mV    1.205V
1.1ns     1.164V     1.04V      1.234V
2.328ns   1.207V     1.143V     1.276V
10ns      1.22V      1.157V     1.289V
[Falling Waveform]
R_fixture = 50.000
V_fixture = 0.750
V_fixture_min = 0.713
V_fixture_max = 0.789
|  time   V(typ)   V(min)   V(max)
0s        1.22V      1.157V     1.289V
351ps     1.22V      1.157V     1.29V
463ps     1.214V     1.157V     764.9mV
594ps     669.4mV    1.159V     496.3mV
671ps     497.7mV    1.15V      430.2mV
711ps     449.4mV    1.071V     407.3mV
861ps     359.9mV    548.1mV    356.5mV
1.049ns   319mV      375.2mV    327.8mV
2.269ns   276.7mV    277.3mV    285.7mV
10ns      263.8mV    264.4mV    273mV
[Falling Waveform]
R_fixture = 50.000
V_fixture = 0.000
V_fixture_min = 0.000
V_fixture_max = 0.000
|  time   V(typ)   V(min)   V(max)
0s        856.8mV    802.9mV    904.7mV
351ps     856.6mV    802.7mV    900.6mV
451ps     855.6mV    802.8mV    329.2mV
481ps     784.1mV    802.6mV    252.7mV
571ps     299.1mV    804.9mV    145.1mV
661ps     145.6mV    797.3mV    97.64mV
811ps     73.69mV    245.7mV    60.47mV
951ps     47.78mV    102.9mV    43.76mV
1.891ns   13.3mV     13.28mV    12.38mV
10ns      67.51uV    -31.65uV   -689.5uV
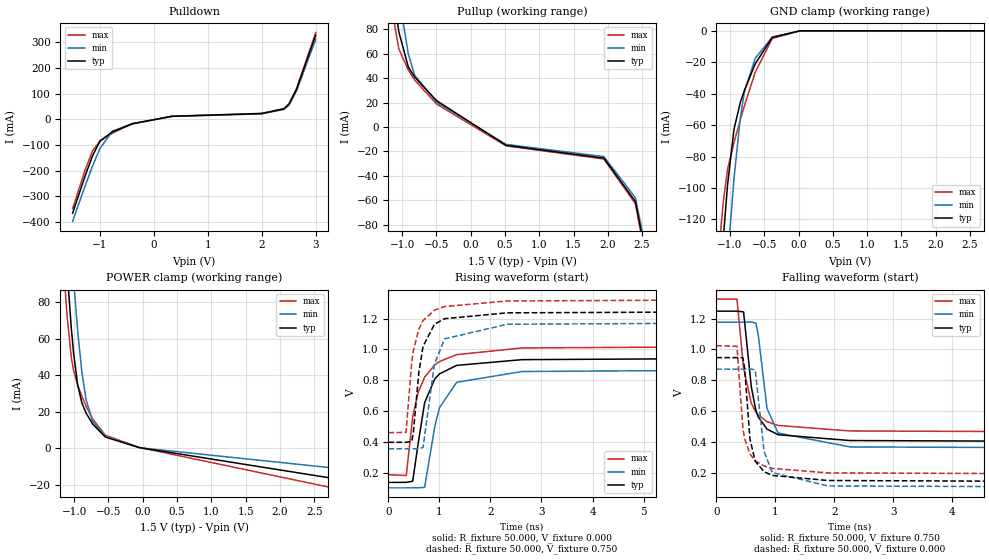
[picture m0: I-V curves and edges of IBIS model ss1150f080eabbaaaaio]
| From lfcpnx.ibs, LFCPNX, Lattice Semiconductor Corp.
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|Model ss1150f080eabbaaaaio
[Model] ss1150f080eabbaaaaio
| Clamp models do not include dynamic input termination. Please refer to
| the ss1150axxxeabbaaaain model for input termination.
Model_type I/O
Polarity   Non-Inverting
Enable   Active-Low
Vinl =  0.650V
Vinh =  0.850V
Vmeas =  0.750V
Cref =  30.000pF
Rref =  50.000
Vref =  0.750V
C_comp   5.000pF   4.000pF   5.500pF
[Temperature Range]   25.000   0.125k   -40.000
[Voltage Range]   1.500V   1.430V   1.580V
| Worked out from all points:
|   slope of the pulldown table from 0 to 0.225 V, typ, clamps not added: 26.6 ohm
|   slope of the pullup table from 0 to 0.225 V, typ, clamps not added: 28.9 ohm
|   GND clamp passes 1 mA (typ) near -0.15 V on its own axis
|   POWER clamp passes 1 mA (typ) near -0.17 V on its own axis
|   rising waveform, R_fixture 50.000, V_fixture 0.000: 20-80 % time 310ps typ, 333ps min, 377ps max; typ from 0.137 V to 0.947 V
|   rising waveform, R_fixture 50.000, V_fixture 0.750: 20-80 % time 217ps typ, 245ps min, 234ps max; typ from 0.397 V to 1.25 V
|   falling waveform, R_fixture 50.000, V_fixture 0.750: 20-80 % time 189ps typ, 202ps min, 215ps max; typ from 1.25 V to 0.397 V
|   falling waveform, R_fixture 50.000, V_fixture 0.000: 20-80 % time 135ps typ, 149ps min, 147ps max; typ from 0.947 V to 0.137 V
[Pulldown]
|Voltage   I(typ)   I(min)   I(max)
-1.5V     -365.1mA   -396.5mA   -347.3mA
-1.27V    -220.7mA   -259.6mA   -197.7mA
-1.132V   -142.4mA   -182mA     -122.7mA
-994mV    -84mA      -113.3mA   -84.4mA
-764mV    -48.51mA   -45.68mA   -53.79mA
-396mV    -17.54mA   -16.85mA   -16.47mA
340mV     12.05mA    11.45mA    12.41mA
1.996V    22.61mA    21.48mA    23.29mA
2.41V     40.75mA    38.71mA    41.97mA
2.502V    58.04mA    55.14mA    59.78mA
2.64V     114.5mA    108.8mA    117.9mA
3V        327.9mA    311.5mA    337.7mA
[Pullup]
|Voltage   I(typ)   I(min)   I(max)
-1.5V     318.1mA    348.8mA    298.7mA
-1.186V   138.2mA    174.4mA    115mA
-1.14V    115.6mA    151mA      93.7mA
-1.048V   78.01mA    108.2mA    63.97mA
-910mV    49.26mA    59.99mA    46.7mA
-818mV    40.89mA    42.44mA    38.48mA
-496mV    21.49mA    20.11mA    18.73mA
516mV     -15.05mA   -14.3mA    -15.5mA
1.942V    -25.52mA   -24.25mA   -26.29mA
2.402V    -61.04mA   -57.99mA   -62.87mA
2.586V    -114.2mA   -108.5mA   -117.6mA
3V        -349.5mA   -332mA     -360mA
[GND_clamp]
|Voltage   I(typ)   I(min)   I(max)
-1.5V     -423.6mA   -473.4mA   -391.3mA
-1.159V   -170.8mA   -226.4mA   -140.1mA
-1.128V   -150.6mA   -205.4mA   -123mA
-1.097V   -131.5mA   -185mA     -108.4mA
-1.035V   -97.76mA   -145.9mA   -88.03mA
-942mV    -62.68mA   -94.08mA   -70.99mA
-849mV    -45.44mA   -55.18mA   -56.59mA
-787mV    -37.67mA   -38mA      -47.37mA
-632mV    -20.99mA   -17.55mA   -26.32mA
-384mV    -4.202mA   -3.933mA   -4.89mA
19mV      0A         0A         0A
3V        0A         0A         0A
[POWER_clamp]
|Voltage   I(typ)   I(min)   I(max)
-1.5V     377.8mA    420.9mA    350.6mA
-1.166V   135.9mA    186.4mA    106mA
-1.104V   98.02mA    147mA      72.63mA
-1.042V   66.02mA    110.5mA    49.91mA
-1.011V   53.08mA    93.78mA    43.04mA
-949mV    34.63mA    64.31mA    34.62mA
-887mV    24.77mA    41.57mA    28.48mA
-825mV    19.16mA    26.4mA     22.89mA
-732mV    13.32mA    14.81mA    16.07mA
-546mV    6.068mA    6.58mA     7.125mA
-50mV     295.8uA    241.2uA    397.5uA
3V        -17.94mA   -11.75mA   -23.63mA
[Ramp]
| variable   typ   min   max
dV/dt_r   0.486/0.312n   0.462/0.337n   0.503/0.377n
dV/dt_f   0.439/0.334n   0.434/0.332n   0.432/0.414n
R_load = 50.000
[Rising Waveform]
R_fixture = 50.000
V_fixture = 0.000
V_fixture_min = 0.000
V_fixture_max = 0.000
|  time   V(typ)   V(min)   V(max)
0s        137.1mV    101.8mV    186.9mV
351ps     137.5mV    101.8mV    182.3mV
477ps     144.7mV    101.9mV    564.7mV
578ps     378mV      102mV      715.7mV
710ps     653.7mV    105.1mV    820.1mV
907ps     807.8mV    494.3mV    899.8mV
1ns       841.4mV    621.9mV    921.9mV
1.338ns   896.8mV    787.1mV    966.5mV
2.62ns    934.1mV    857mV      1.01V
10ns      947.3mV    872.6mV    1.025V
[Rising Waveform]
R_fixture = 50.000
V_fixture = 0.750
V_fixture_min = 0.713
V_fixture_max = 0.789
|  time   V(typ)   V(min)   V(max)
0s        397.5mV    355.8mV    460.3mV
346ps     397.6mV    355.8mV    461.9mV
457ps     403.5mV    355.9mV    916.3mV
487ps     454.4mV    355.9mV    988.1mV
597ps     850.4mV    354.2mV    1.133V
680ps     1.02V      364.9mV    1.188V
901ps     1.163V     903.1mV    1.255V
1.1ns     1.2V       1.069V     1.279V
2.328ns   1.238V     1.164V     1.315V
10ns      1.249V     1.177V     1.327V
[Falling Waveform]
R_fixture = 50.000
V_fixture = 0.750
V_fixture_min = 0.713
V_fixture_max = 0.789
|  time   V(typ)   V(min)   V(max)
0s        1.249V     1.177V     1.327V
351ps     1.249V     1.177V     1.327V
463ps     1.244V     1.177V     879.6mV
594ps     758.8mV    1.179V     650.7mV
671ps     605.9mV    1.171V     594.3mV
711ps     562.8mV    1.098V     574.8mV
861ps     483.1mV    616.7mV    531.5mV
1.049ns   446.7mV    457.7mV    507mV
2.269ns   409mV      367.6mV    471.1mV
10ns      397.5mV    355.8mV    460.3mV
[Falling Waveform]
R_fixture = 50.000
V_fixture = 0.000
V_fixture_min = 0.000
V_fixture_max = 0.000
|  time   V(typ)   V(min)   V(max)
0s        947.3mV    872.6mV    1.025V
351ps     947.1mV    872.4mV    1.021V
451ps     946.2mV    872.5mV    492.2mV
481ps     878.6mV    872.3mV    421.4mV
571ps     419.9mV    874.5mV    321.8mV
661ps     274.8mV    867.2mV    277.9mV
811ps     206.8mV    337.7mV    243.5mV
951ps     182.3mV    200.7mV    228.1mV
1.891ns   149.6mV    114.6mV    199mV
10ns      137.1mV    101.8mV    186.9mV
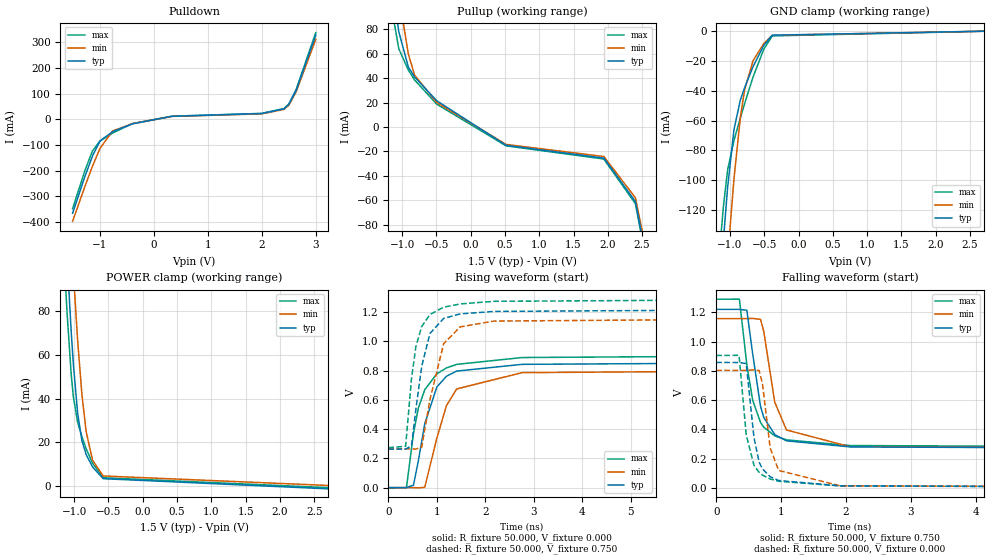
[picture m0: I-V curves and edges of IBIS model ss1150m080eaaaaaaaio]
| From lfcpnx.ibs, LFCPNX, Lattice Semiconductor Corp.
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|Model ss1150m080eaaaaaaaio
[Model] ss1150m080eaaaaaaaio
| Clamp models do not include dynamic input termination. Please refer to
| the ss1150axxxeaaaaaaain model for input termination.
Model_type I/O
Polarity   Non-Inverting
Enable   Active-Low
Vinl =  0.650V
Vinh =  0.850V
Vmeas =  0.750V
Cref =  30.000pF
Rref =  50.000
Vref =  0.750V
C_comp   5.000pF   4.000pF   5.500pF
[Temperature Range]   25.000   0.125k   -40.000
[Voltage Range]   1.500V   1.430V   1.580V
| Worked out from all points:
|   slope of the pulldown table from 0 to 0.225 V, typ, clamps not added: 26.6 ohm
|   slope of the pullup table from 0 to 0.225 V, typ, clamps not added: 28.9 ohm
|   GND clamp passes 1 mA (typ) near -0.31 V on its own axis
|   POWER clamp passes 1 mA (typ) near -0.43 V on its own axis
|   rising waveform, R_fixture 50.000, V_fixture 0.000: 20-80 % time 383ps typ, 445ps min, 399ps max; typ from 0 V to 0.857 V
|   rising waveform, R_fixture 50.000, V_fixture 0.750: 20-80 % time 290ps typ, 355ps min, 260ps max; typ from 0.264 V to 1.22 V
|   falling waveform, R_fixture 50.000, V_fixture 0.750: 20-80 % time 220ps typ, 248ps min, 235ps max; typ from 1.22 V to 0.264 V
|   falling waveform, R_fixture 50.000, V_fixture 0.000: 20-80 % time 153ps typ, 173ps min, 159ps max; typ from 0.857 V to 0 V
[Pulldown]
|Voltage   I(typ)   I(min)   I(max)
-1.5V     -365.1mA   -396.5mA   -347.3mA
-1.27V    -220.7mA   -259.6mA   -197.7mA
-1.132V   -142.4mA   -182mA     -122.7mA
-994mV    -84mA      -113.3mA   -84.4mA
-764mV    -48.51mA   -45.68mA   -53.79mA
-396mV    -17.54mA   -16.85mA   -16.47mA
340mV     12.05mA    11.45mA    12.41mA
1.996V    22.61mA    21.48mA    23.29mA
2.41V     40.75mA    38.71mA    41.97mA
2.502V    58.04mA    55.14mA    59.78mA
2.64V     114.5mA    108.8mA    117.9mA
3V        327.9mA    311.5mA    337.7mA
[Pullup]
|Voltage   I(typ)   I(min)   I(max)
-1.5V     318.1mA    348.8mA    298.7mA
-1.186V   138.2mA    174.4mA    115mA
-1.14V    115.6mA    151mA      93.7mA
-1.048V   78.01mA    108.2mA    63.97mA
-910mV    49.26mA    59.99mA    46.7mA
-818mV    40.89mA    42.44mA    38.48mA
-496mV    21.49mA    20.11mA    18.73mA
516mV     -15.05mA   -14.3mA    -15.5mA
1.942V    -25.52mA   -24.25mA   -26.29mA
2.402V    -61.04mA   -57.99mA   -62.87mA
2.586V    -114.2mA   -108.5mA   -117.6mA
3V        -349.5mA   -332mA     -360mA
[GND_clamp]
|Voltage   I(typ)   I(min)   I(max)
-1.5V     -437.6mA   -483.1mA   -411.3mA
-1.159V   -181.2mA   -234mA     -153.2mA
-1.128V   -160.4mA   -212.8mA   -134.5mA
-1.097V   -140.5mA   -192mA     -117.9mA
-1.035V   -104.9mA   -152.2mA   -93.08mA
-942mV    -66.01mA   -98.88mA   -73.31mA
-849mV    -46.26mA   -57.94mA   -58.29mA
-787mV    -38.01mA   -39.4mA    -48.69mA
-663mV    -23.84mA   -19.92mA   -30.76mA
-508mV    -9.791mA   -8.549mA   -12.41mA
-384mV    -2.92mA    -2.99mA    -3.392mA
3V        0A         0A         0A
[POWER_clamp]
|Voltage   I(typ)   I(min)   I(max)
-1.5V     391.5mA    430.3mA    369.8mA
-1.166V   144.9mA    193mA      117.4mA
-1.135V   124.5mA    172.6mA    97.69mA
-1.104V   105.1mA    152.8mA    79.63mA
-1.042V   70.22mA    115.2mA    50.64mA
-1.011V   55.5mA     97.74mA    40.7mA
-949mV    33.19mA    66.57mA    29.05mA
-887mV    20.7mA     41.83mA    22.48mA
-825mV    14.31mA    24.76mA    16.96mA
-732mV    8.589mA    11.69mA    10.31mA
-577mV    3.202mA    4.456mA    3.639mA
3V        -1.88mA    -305.7uA   -1.33mA
[Ramp]
| variable   typ   min   max
dV/dt_r   0.514/0.391n   0.482/0.443n   0.561/0.398n
dV/dt_f   0.527/0.375n   0.492/0.402n   0.584/0.438n
R_load = 50.000
[Rising Waveform]
R_fixture = 50.000
V_fixture = 0.000
V_fixture_min = 0.000
V_fixture_max = 0.000
|  time   V(typ)   V(min)   V(max)
0s        67.51uV    -31.65uV   -689.5uV
373ps     667.6uV    -8.468uV   -1.033mV
518ps     16.51mV    264.5uV    369.7mV
618ps     182mV      -1.566mV   542.9mV
751ps     436.5mV    2.144mV    669.5mV
1.001ns   688.6mV    338.9mV    778.8mV
1.198ns   761.3mV    560mV      818.4mV
1.41ns    796.9mV    674.5mV    842.8mV
2.76ns    843.1mV    786.2mV    889.6mV
10ns      856.8mV    802.9mV    904.7mV
[Rising Waveform]
R_fixture = 50.000
V_fixture = 0.750
V_fixture_min = 0.713
V_fixture_max = 0.789
|  time   V(typ)   V(min)   V(max)
0s        263.8mV    264.4mV    273mV
356ps     263.9mV    264.5mV    282.9mV
478ps     286.4mV    264.6mV    746mV
568ps     536.9mV    263.5mV    964.6mV
688ps     830mV      276.9mV    1.102V
858ps     1.054V     602mV      1.184V
1.141ns   1.157V     984.6mV    1.234V
1.481ns   1.188V     1.099V     1.256V
2.178ns   1.205V     1.139V     1.274V
10ns      1.22V      1.157V     1.289V
[Falling Waveform]
R_fixture = 50.000
V_fixture = 0.750
V_fixture_min = 0.713
V_fixture_max = 0.789
|  time   V(typ)   V(min)   V(max)
0s        1.22V      1.157V     1.289V
356ps     1.22V      1.157V     1.29V
471ps     1.214V     1.157V     841.8mV
561ps     915.3mV    1.158V     598.1mV
681ps     558.7mV    1.152V     447.5mV
732ps     480.6mV    1.069V     414mV
901ps     363.3mV    584.9mV    354.7mV
1.082ns   321mV      395.1mV    327.5mV
2.061ns   279.5mV    280.7mV    288.8mV
10ns      263.8mV    264.4mV    273mV
[Falling Waveform]
R_fixture = 50.000
V_fixture = 0.000
V_fixture_min = 0.000
V_fixture_max = 0.000
|  time   V(typ)   V(min)   V(max)
0s        856.8mV    802.9mV    904.7mV
351ps     856.5mV    802.7mV    905.7mV
461ps     849.2mV    802.7mV    363.5mV
581ps     343mV      806.3mV    153.1mV
661ps     174.2mV    801.6mV    105.4mV
711ps     129.1mV    713.1mV    86.98mV
831ps     75.47mV    271.3mV    60.09mV
961ps     49.69mV    118.2mV    44.37mV
1.91ns    13.29mV    13.42mV    12.33mV
10ns      67.51uV    -31.65uV   -689.5uV
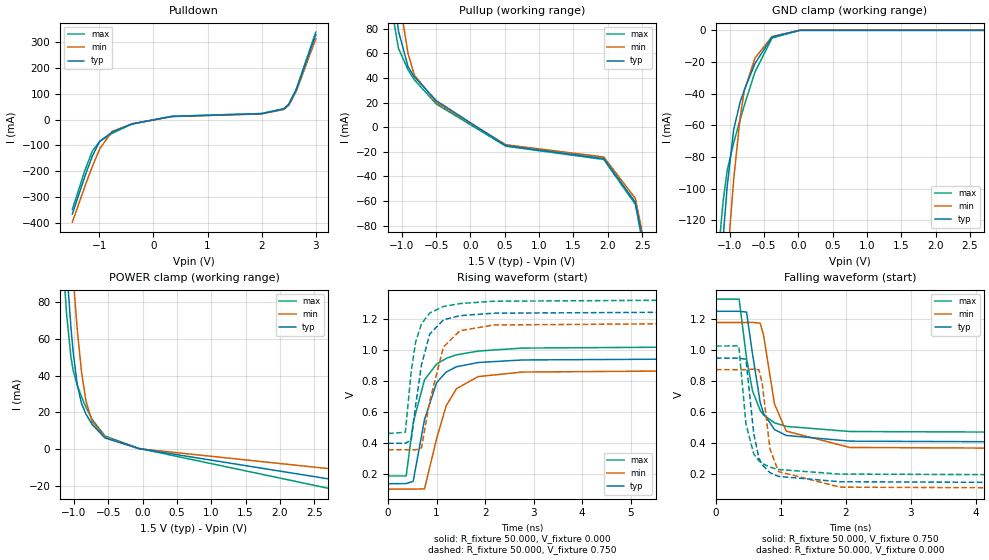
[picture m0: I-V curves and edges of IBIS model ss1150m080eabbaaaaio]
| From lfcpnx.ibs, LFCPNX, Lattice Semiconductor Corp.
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|Model ss1150m080eabbaaaaio
[Model] ss1150m080eabbaaaaio
| Clamp models do not include dynamic input termination. Please refer to
| the ss1150axxxeabbaaaain model for input termination.
Model_type I/O
Polarity   Non-Inverting
Enable   Active-Low
Vinl =  0.650V
Vinh =  0.850V
Vmeas =  0.750V
Cref =  30.000pF
Rref =  50.000
Vref =  0.750V
C_comp   5.000pF   4.000pF   5.500pF
[Temperature Range]   25.000   0.125k   -40.000
[Voltage Range]   1.500V   1.430V   1.580V
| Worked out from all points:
|   slope of the pulldown table from 0 to 0.225 V, typ, clamps not added: 26.6 ohm
|   slope of the pullup table from 0 to 0.225 V, typ, clamps not added: 28.9 ohm
|   GND clamp passes 1 mA (typ) near -0.15 V on its own axis
|   POWER clamp passes 1 mA (typ) near -0.17 V on its own axis
|   rising waveform, R_fixture 50.000, V_fixture 0.000: 20-80 % time 383ps typ, 445ps min, 399ps max; typ from 0.137 V to 0.947 V
|   rising waveform, R_fixture 50.000, V_fixture 0.750: 20-80 % time 290ps typ, 355ps min, 260ps max; typ from 0.397 V to 1.25 V
|   falling waveform, R_fixture 50.000, V_fixture 0.750: 20-80 % time 220ps typ, 248ps min, 235ps max; typ from 1.25 V to 0.397 V
|   falling waveform, R_fixture 50.000, V_fixture 0.000: 20-80 % time 153ps typ, 173ps min, 159ps max; typ from 0.947 V to 0.137 V
[Pulldown]
|Voltage   I(typ)   I(min)   I(max)
-1.5V     -365.1mA   -396.5mA   -347.3mA
-1.27V    -220.7mA   -259.6mA   -197.7mA
-1.132V   -142.4mA   -182mA     -122.7mA
-994mV    -84mA      -113.3mA   -84.4mA
-764mV    -48.51mA   -45.68mA   -53.79mA
-396mV    -17.54mA   -16.85mA   -16.47mA
340mV     12.05mA    11.45mA    12.41mA
1.996V    22.61mA    21.48mA    23.29mA
2.41V     40.75mA    38.71mA    41.97mA
2.502V    58.04mA    55.14mA    59.78mA
2.64V     114.5mA    108.8mA    117.9mA
3V        327.9mA    311.5mA    337.7mA
[Pullup]
|Voltage   I(typ)   I(min)   I(max)
-1.5V     318.1mA    348.8mA    298.7mA
-1.186V   138.2mA    174.4mA    115mA
-1.14V    115.6mA    151mA      93.7mA
-1.048V   78.01mA    108.2mA    63.97mA
-910mV    49.26mA    59.99mA    46.7mA
-818mV    40.89mA    42.44mA    38.48mA
-496mV    21.49mA    20.11mA    18.73mA
516mV     -15.05mA   -14.3mA    -15.5mA
1.942V    -25.52mA   -24.25mA   -26.29mA
2.402V    -61.04mA   -57.99mA   -62.87mA
2.586V    -114.2mA   -108.5mA   -117.6mA
3V        -349.5mA   -332mA     -360mA
[GND_clamp]
|Voltage   I(typ)   I(min)   I(max)
-1.5V     -423.6mA   -473.4mA   -391.3mA
-1.159V   -170.8mA   -226.4mA   -140.1mA
-1.128V   -150.6mA   -205.4mA   -123mA
-1.097V   -131.5mA   -185mA     -108.4mA
-1.035V   -97.76mA   -145.9mA   -88.03mA
-942mV    -62.68mA   -94.08mA   -70.99mA
-849mV    -45.44mA   -55.18mA   -56.59mA
-787mV    -37.67mA   -38mA      -47.37mA
-632mV    -20.99mA   -17.55mA   -26.32mA
-384mV    -4.202mA   -3.933mA   -4.89mA
19mV      0A         0A         0A
3V        0A         0A         0A
[POWER_clamp]
|Voltage   I(typ)   I(min)   I(max)
-1.5V     377.8mA    420.9mA    350.6mA
-1.166V   135.9mA    186.4mA    106mA
-1.104V   98.02mA    147mA      72.63mA
-1.042V   66.02mA    110.5mA    49.91mA
-1.011V   53.08mA    93.78mA    43.04mA
-949mV    34.63mA    64.31mA    34.62mA
-887mV    24.77mA    41.57mA    28.48mA
-825mV    19.16mA    26.4mA     22.89mA
-732mV    13.32mA    14.81mA    16.07mA
-546mV    6.068mA    6.58mA     7.125mA
-50mV     295.8uA    241.2uA    397.5uA
3V        -17.94mA   -11.75mA   -23.63mA
[Ramp]
| variable   typ   min   max
dV/dt_r   0.486/0.391n   0.462/0.443n   0.503/0.398n
dV/dt_f   0.439/0.375n   0.434/0.402n   0.432/0.438n
R_load = 50.000
[Rising Waveform]
R_fixture = 50.000
V_fixture = 0.000
V_fixture_min = 0.000
V_fixture_max = 0.000
|  time   V(typ)   V(min)   V(max)
0s        137.1mV    101.8mV    186.9mV
373ps     137.7mV    101.8mV    186.6mV
518ps     152.7mV    102.1mV    529.6mV
751ps     549.9mV    103.9mV    807mV
1.001ns   788.2mV    427.1mV    908.1mV
1.198ns   857mV      639.4mV    944.8mV
1.41ns    890.7mV    749.3mV    967.4mV
1.858ns   918.1mV    827.4mV    991.9mV
2.76ns    934.4mV    856.6mV    1.011V
10ns      947.3mV    872.6mV    1.025V
[Rising Waveform]
R_fixture = 50.000
V_fixture = 0.750
V_fixture_min = 0.713
V_fixture_max = 0.789
|  time   V(typ)   V(min)   V(max)
0s        397.5mV    355.8mV    460.3mV
356ps     397.6mV    355.8mV    468.7mV
478ps     417.6mV    355.9mV    863.5mV
568ps     640.8mV    355mV      1.05V
688ps     901.9mV    367.2mV    1.167V
858ps     1.101V     666.3mV    1.237V
1.141ns   1.193V     1.018V     1.279V
1.481ns   1.22V      1.123V     1.298V
2.178ns   1.236V     1.16V      1.313V
10ns      1.249V     1.177V     1.327V
[Falling Waveform]
R_fixture = 50.000
V_fixture = 0.750
V_fixture_min = 0.713
V_fixture_max = 0.789
|  time   V(typ)   V(min)   V(max)
0s        1.249V     1.177V     1.327V
356ps     1.249V     1.177V     1.328V
471ps     1.244V     1.177V     945.2mV
561ps     977.8mV    1.178V     737.4mV
681ps     660.2mV    1.172V     609mV
732ps     590.6mV    1.096V     580.5mV
901ps     486.2mV    650.6mV    529.9mV
1.082ns   448.4mV    476mV      506.7mV
2.061ns   411.5mV    370.8mV    473.8mV
10ns      397.5mV    355.8mV    460.3mV
[Falling Waveform]
R_fixture = 50.000
V_fixture = 0.000
V_fixture_min = 0.000
V_fixture_max = 0.000
|  time   V(typ)   V(min)   V(max)
0s        947.3mV    872.6mV    1.025V
351ps     947mV      872.4mV    1.026V
461ps     940.1mV    872.4mV    523.9mV
581ps     461.4mV    875.9mV    329.2mV
661ps     301.8mV    871.3mV    285mV
711ps     259.1mV    786.4mV    268mV
831ps     208.4mV    362.3mV    243.2mV
961ps     184.1mV    215.3mV    228.6mV
1.91ns    149.6mV    114.7mV    199mV
10ns      137.1mV    101.8mV    186.9mV
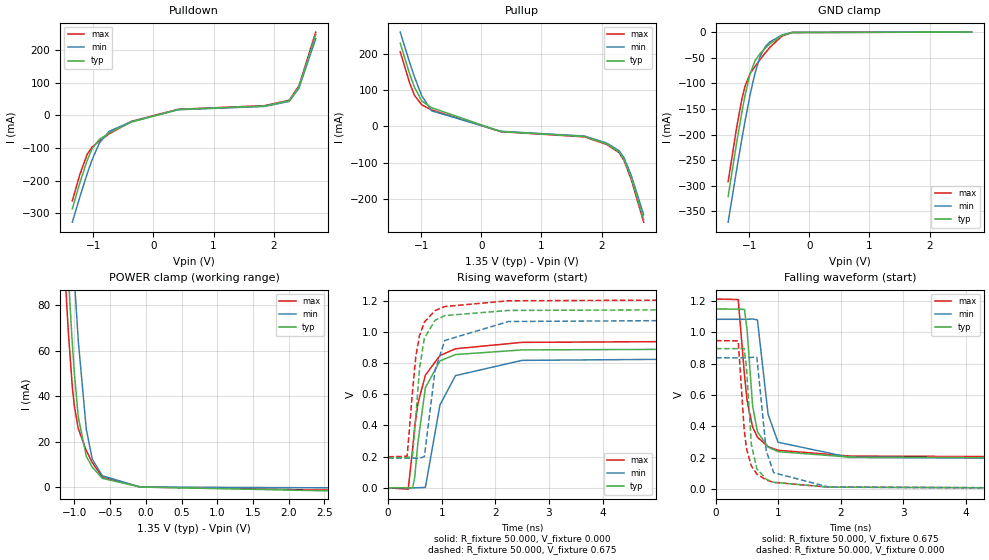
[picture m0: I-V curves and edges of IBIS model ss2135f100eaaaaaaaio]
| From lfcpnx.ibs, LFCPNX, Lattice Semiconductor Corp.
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|Model ss2135f100eaaaaaaaio
[Model] ss2135f100eaaaaaaaio
| Clamp models do not include dynamic input termination. Please refer to
| the ss1135axxxeaaaaaaain model for input termination.
Model_type I/O
Polarity   Non-Inverting
Enable   Active-Low
Vinl =  0.575V
Vinh =  0.775V
Vmeas =  0.675V
Cref =  30.000pF
Rref =  50.000
Vref =  0.675V
C_comp   5.000pF   4.000pF   5.500pF
[Temperature Range]   25.000   0.125k   -40.000
[Voltage Range]   1.350V   1.280V   1.420V
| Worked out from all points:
|   slope of the pulldown table from 0 to 0.203 V, typ, clamps not added: 20.1 ohm
|   slope of the pullup table from 0 to 0.203 V, typ, clamps not added: 21.4 ohm
|   GND clamp passes 1 mA (typ) near -0.31 V on its own axis
|   POWER clamp passes 1 mA (typ) near -0.43 V on its own axis
|   rising waveform, R_fixture 50.000, V_fixture 0.000: 20-80 % time 235ps typ, 348ps min, 299ps max; typ from 0 V to 0.895 V
|   rising waveform, R_fixture 50.000, V_fixture 0.675: 20-80 % time 170ps typ, 248ps min, 200ps max; typ from 0.193 V to 1.15 V
|   falling waveform, R_fixture 50.000, V_fixture 0.675: 20-80 % time 141ps typ, 170ps min, 173ps max; typ from 1.15 V to 0.193 V
|   falling waveform, R_fixture 50.000, V_fixture 0.000: 20-80 % time 112ps typ, 136ps min, 130ps max; typ from 0.895 V to 0 V
[Pulldown]
|Voltage   I(typ)   I(min)   I(max)
-1.35V    -286.4mA   -327.1mA   -261.6mA
-1.227V   -208mA     -251mA     -182mA
-1.104V   -138.2mA   -179.4mA   -119.2mA
-1.022V   -102.3mA   -136.2mA   -96.9mA
-899mV    -72.91mA   -84.21mA   -78.45mA
-735mV    -53.57mA   -48.43mA   -56.12mA
-366mV    -20.38mA   -18.73mA   -17.94mA
413mV     18.42mA    17.5mA     18.98mA
1.848V    29.15mA    27.69mA    30.02mA
2.258V    45.11mA    42.86mA    46.47mA
2.422V    88.6mA     84.2mA     91.3mA
2.7V      248.1mA    235.7mA    255.5mA
[Pullup]
|Voltage   I(typ)   I(min)   I(max)
-1.35V    230.2mA    261mA      206.2mA
-1.195V   146.2mA    177.5mA    121mA
-1.113V   108.3mA    136.7mA    85.9mA
-990mV    70.2mA     84.2mA     59.58mA
-826mV    51.79mA    43.14mA    45.63mA
322mV     -13.96mA   -13.26mA   -14.38mA
1.716V    -27.9mA    -26.5mA    -28.74mA
2.085V    -48.27mA   -45.86mA   -49.72mA
2.29V     -70.2mA    -66.69mA   -72.31mA
2.372V    -90.7mA    -86.2mA    -93.4mA
2.495V    -142.9mA   -135.8mA   -147.2mA
2.7V      -257mA     -244.2mA   -264.7mA
[GND_clamp]
|Voltage   I(typ)   I(min)   I(max)
-1.35V    -320.9mA   -371mA     -291.7mA
-1.21V    -216.8mA   -269.5mA   -187.2mA
-1.126V   -159mA     -211.3mA   -133.3mA
-1.07V    -124.2mA   -174.2mA   -105.6mA
-986mV    -81.78mA   -122.8mA   -81.18mA
-902mV    -55.61mA   -79.36mA   -66.72mA
-818mV    -41.95mA   -47.73mA   -53.44mA
-734mV    -31.67mA   -28.77mA   -40.78mA
-650mV    -22.47mA   -18.69mA   -29.01mA
-454mV    -6.221mA   -5.753mA   -7.69mA
-286mV    -734.4uA   -759.2uA   -785.5uA
2.7V      0A         0A         0A
[POWER_clamp]
|Voltage   I(typ)   I(min)   I(max)
-1.35V    276.5mA    320.5mA    251mA
-1.142V   128.3mA    176.6mA    100.9mA
-1.114V   110.5mA    158.5mA    83.9mA
-1.086V   93.5mA     140.9mA    68.53mA
-1.03V    63.21mA    107.6mA    44.18mA
-1.002V   50.42mA    92.11mA    35.83mA
-946mV    30.82mA    64.28mA    25.76mA
-834mV    13.57mA    25.52mA    16.1mA
-750mV    8.839mA    12.31mA    10.8mA
-610mV    3.896mA    5.035mA    4.505mA
-78mV     75.17uA    92.3uA     98.29uA
2.7V      -1.695mA   -291.3uA   -1.333mA
[Ramp]
| variable   typ   min   max
dV/dt_r   0.536/0.235n   0.478/0.348n   0.577/0.306n
dV/dt_f   0.557/0.206n   0.536/0.244n   0.586/0.289n
R_load = 50.000
[Rising Waveform]
R_fixture = 50.000
V_fixture = 0.000
V_fixture_min = 0.000
V_fixture_max = 0.000
|  time   V(typ)   V(min)   V(max)
0s        17.43uV    -116.7uV   -307.5uV
376ps     629.6uV    -98.94uV   -8.673mV
458ps     -566.9uV   -58.82uV   251.2mV
497ps     66.57mV    102.3uV    390.4mV
557ps     291.2mV    498.2uV    541.1mV
696ps     642.3mV    2.407mV    722.6mV
968ps     813.9mV    531.9mV    848.8mV
1.257ns   855.1mV    719.7mV    892.1mV
2.497ns   884.7mV    817.7mV    933.2mV
10ns      895.1mV    836.6mV    946.3mV
[Rising Waveform]
R_fixture = 50.000
V_fixture = 0.675
V_fixture_min = 0.642
V_fixture_max = 0.710
|  time   V(typ)   V(min)   V(max)
0s        192.9mV    190.2mV    198.9mV
356ps     193.2mV    190.2mV    202.9mV
456ps     204mV      190.3mV    619.2mV
518ps     459.3mV    190.2mV    845.4mV
587ps     767.6mV    188.8mV    977.4mV
677ps     959.8mV    200mV      1.063V
877ps     1.075V     754.5mV    1.137V
1.057ns   1.105V     945.2mV    1.163V
2.247ns   1.138V     1.067V     1.2V
10ns      1.148V     1.082V     1.211V
[Falling Waveform]
R_fixture = 50.000
V_fixture = 0.675
V_fixture_min = 0.642
V_fixture_max = 0.710
|  time   V(typ)   V(min)   V(max)
0s        1.148V     1.082V     1.211V
356ps     1.147V     1.082V     1.208V
457ps     1.145V     1.082V     722.7mV
498ps     1.014V     1.082V     562.4mV
587ps     529.3mV    1.084V     394.9mV
664ps     365mV      1.078V     331.2mV
834ps     267.9mV    477.3mV    270.7mV
994ps     238.7mV    298.7mV    247.7mV
2.144ns   204mV      201.9mV    210.5mV
10ns      192.9mV    190.2mV    198.9mV
[Falling Waveform]
R_fixture = 50.000
V_fixture = 0.000
V_fixture_min = 0.000
V_fixture_max = 0.000
|  time   V(typ)   V(min)   V(max)
0s        895.1mV    836.6mV    946.3mV
356ps     895mV      836.3mV    944.3mV
451ps     896.7mV    836.5mV    385.4mV
487ps     779.3mV    836.2mV    260.3mV
567ps     283.5mV    839.2mV    147.5mV
654ps     129.2mV    841mV      96.57mV
805ps     63.26mV    244.2mV    57.58mV
924ps     43.19mV    104.7mV    43.02mV
1.804ns   12.3mV     13.08mV    12.75mV
10ns      17.43uV    -116.7uV   -307.5uV
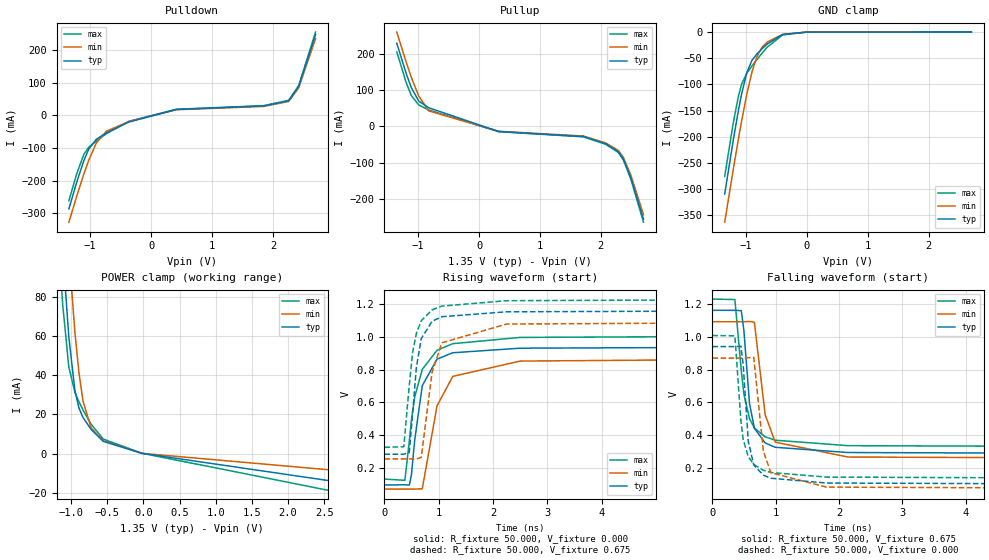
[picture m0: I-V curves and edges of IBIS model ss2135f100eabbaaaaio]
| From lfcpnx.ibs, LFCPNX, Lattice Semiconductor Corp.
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|Model ss2135f100eabbaaaaio
[Model] ss2135f100eabbaaaaio
| Clamp models do not include dynamic input termination. Please refer to
| the ss1135axxxeabbaaaain model for input termination.
Model_type I/O
Polarity   Non-Inverting
Enable   Active-Low
Vinl =  0.575V
Vinh =  0.775V
Vmeas =  0.675V
Cref =  30.000pF
Rref =  50.000
Vref =  0.675V
C_comp   5.000pF   4.000pF   5.500pF
[Temperature Range]   25.000   0.125k   -40.000
[Voltage Range]   1.350V   1.280V   1.420V
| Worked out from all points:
|   slope of the pulldown table from 0 to 0.203 V, typ, clamps not added: 20.1 ohm
|   slope of the pullup table from 0 to 0.203 V, typ, clamps not added: 21.4 ohm
|   GND clamp passes 1 mA (typ) near -0.15 V on its own axis
|   POWER clamp passes 1 mA (typ) near -0.17 V on its own axis
|   rising waveform, R_fixture 50.000, V_fixture 0.000: 20-80 % time 235ps typ, 348ps min, 299ps max; typ from 0.095 V to 0.942 V
|   rising waveform, R_fixture 50.000, V_fixture 0.675: 20-80 % time 170ps typ, 248ps min, 200ps max; typ from 0.283 V to 1.16 V
|   falling waveform, R_fixture 50.000, V_fixture 0.675: 20-80 % time 141ps typ, 170ps min, 173ps max; typ from 1.16 V to 0.283 V
|   falling waveform, R_fixture 50.000, V_fixture 0.000: 20-80 % time 112ps typ, 136ps min, 130ps max; typ from 0.942 V to 0.095 V
[Pulldown]
|Voltage   I(typ)   I(min)   I(max)
-1.35V    -286.4mA   -327.1mA   -261.6mA
-1.227V   -208mA     -251mA     -182mA
-1.104V   -138.2mA   -179.4mA   -119.2mA
-1.022V   -102.3mA   -136.2mA   -96.9mA
-899mV    -72.91mA   -84.21mA   -78.45mA
-735mV    -53.57mA   -48.43mA   -56.12mA
-366mV    -20.38mA   -18.73mA   -17.94mA
413mV     18.42mA    17.5mA     18.98mA
1.848V    29.15mA    27.69mA    30.02mA
2.258V    45.11mA    42.86mA    46.47mA
2.422V    88.6mA     84.2mA     91.3mA
2.7V      248.1mA    235.7mA    255.5mA
[Pullup]
|Voltage   I(typ)   I(min)   I(max)
-1.35V    230.2mA    261mA      206.2mA
-1.195V   146.2mA    177.5mA    121mA
-1.113V   108.3mA    136.7mA    85.9mA
-990mV    70.2mA     84.2mA     59.58mA
-826mV    51.79mA    43.14mA    45.63mA
322mV     -13.96mA   -13.26mA   -14.38mA
1.716V    -27.9mA    -26.5mA    -28.74mA
2.085V    -48.27mA   -45.86mA   -49.72mA
2.29V     -70.2mA    -66.69mA   -72.31mA
2.372V    -90.7mA    -86.2mA    -93.4mA
2.495V    -142.9mA   -135.8mA   -147.2mA
2.7V      -257mA     -244.2mA   -264.7mA
[GND_clamp]
|Voltage   I(typ)   I(min)   I(max)
-1.35V    -309.8mA   -363.4mA   -275.8mA
-1.21V    -207.1mA   -262.8mA   -173.9mA
-1.126V   -150.5mA   -205.1mA   -123.2mA
-1.07V    -117mA     -168.5mA   -98.8mA
-986mV    -77.25mA   -118.1mA   -78.4mA
-902mV    -53.89mA   -76.04mA   -64.81mA
-818mV    -41.42mA   -46.02mA   -52mA
-734mV    -31.56mA   -28.41mA   -39.82mA
-650mV    -22.69mA   -19.03mA   -28.57mA
-398mV    -4.585mA   -4.332mA   -5.35mA
-6mV      -40.55uA   -29.88uA   -52.89uA
2.7V      0A         0A         0A
[POWER_clamp]
|Voltage   I(typ)   I(min)   I(max)
-1.35V    264.6mA    312.3mA    234.2mA
-1.17V    138mA      188.5mA    107.5mA
-1.142V   120.1mA    170.4mA    90.88mA
-1.114V   103.1mA    152.7mA    75.88mA
-1.03V    59.59mA    103.2mA    44.19mA
-946mV    32.22mA    62.05mA    31.33mA
-890mV    23.29mA    41.28mA    26.5mA
-834mV    18.42mA    26.8mA     22.3mA
-722mV    12.33mA    13.1mA     15mA
-554mV    6.226mA    6.542mA    7.404mA
-22mV     128.8uA    103.1uA    167.9uA
2.7V      -14.6mA    -8.747mA   -19.86mA
[Ramp]
| variable   typ   min   max
dV/dt_r   0.508/0.235n   0.478/0.348n   0.528/0.306n
dV/dt_f   0.502/0.206n   0.483/0.244n   0.509/0.289n
R_load = 50.000
[Rising Waveform]
R_fixture = 50.000
V_fixture = 0.000
V_fixture_min = 0.000
V_fixture_max = 0.000
|  time   V(typ)   V(min)   V(max)
0s        94.9mV     68.91mV    130.7mV
376ps     95.48mV    68.93mV    122.9mV
458ps     94.35mV    68.97mV    364.4mV
497ps     157.9mV    69.12mV    493.7mV
557ps     370.5mV    69.5mV     633.7mV
696ps     702.8mV    71.33mV    802.4mV
968ps     865.2mV    579.2mV    919.6mV
1.257ns   904.2mV    759.4mV    959.8mV
2.497ns   932.2mV    853.3mV    998.1mV
10ns      942.1mV    871.5mV    1.01V
[Rising Waveform]
R_fixture = 50.000
V_fixture = 0.675
V_fixture_min = 0.642
V_fixture_max = 0.710
|  time   V(typ)   V(min)   V(max)
0s        283mV      254.5mV    325mV
356ps     283.2mV    254.6mV    328.6mV
456ps     293.2mV    254.7mV    702mV
518ps     528.8mV    254.6mV    904.9mV
587ps     813.2mV    253.3mV    1.023V
677ps     990.5mV    263.8mV    1.1V
877ps     1.097V     785.9mV    1.167V
1.057ns   1.125V     965.3mV    1.19V
2.247ns   1.155V     1.08V      1.223V
10ns      1.164V     1.094V     1.233V
[Falling Waveform]
R_fixture = 50.000
V_fixture = 0.675
V_fixture_min = 0.642
V_fixture_max = 0.710
|  time   V(typ)   V(min)   V(max)
0s        1.164V     1.094V     1.233V
356ps     1.164V     1.094V     1.23V
457ps     1.162V     1.094V     794.9mV
498ps     1.041V     1.094V     651.1mV
587ps     593.3mV    1.096V     500.8mV
664ps     441.7mV    1.091V     443.6mV
834ps     352.1mV    524.9mV    389.3mV
994ps     325.3mV    356.8mV    368.7mV
2.144ns   293.2mV    265.6mV    335.3mV
10ns      283mV      254.5mV    325mV
[Falling Waveform]
R_fixture = 50.000
V_fixture = 0.000
V_fixture_min = 0.000
V_fixture_max = 0.000
|  time   V(typ)   V(min)   V(max)
0s        942.1mV    871.5mV    1.01V
356ps     941.9mV    871.2mV    1.008V
451ps     943.6mV    871.4mV    489.1mV
487ps     832.5mV    871.1mV    372.8mV
567ps     363.2mV    874mV      268mV
654ps     217.1mV    875.7mV    220.7mV
805ps     154.8mV    303.2mV    184.5mV
924ps     135.8mV    169.5mV    170.9mV
1.804ns   106.5mV    81.57mV    142.8mV
10ns      94.9mV     68.91mV    130.7mV
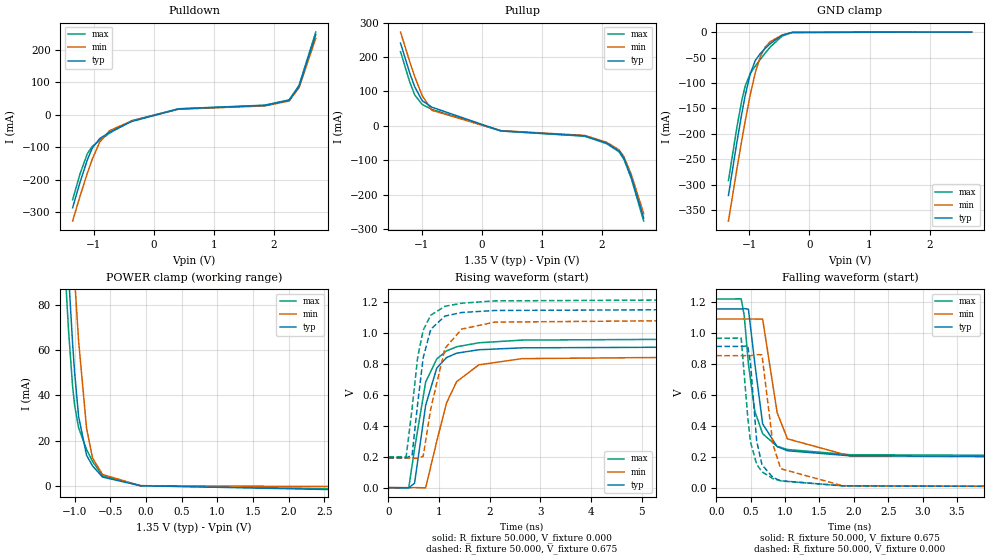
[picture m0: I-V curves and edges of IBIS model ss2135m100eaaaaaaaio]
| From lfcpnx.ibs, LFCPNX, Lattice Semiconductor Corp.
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|Model ss2135m100eaaaaaaaio
[Model] ss2135m100eaaaaaaaio
| Clamp models do not include dynamic input termination. Please refer to
| the ss1135axxxeaaaaaaain model for input termination.
Model_type I/O
Polarity   Non-Inverting
Enable   Active-Low
Vinl =  0.575V
Vinh =  0.775V
Vmeas =  0.675V
Cref =  30.000pF
Rref =  50.000
Vref =  0.675V
C_comp   5.000pF   4.000pF   5.500pF
[Temperature Range]   25.000   0.125k   -40.000
[Voltage Range]   1.350V   1.280V   1.420V
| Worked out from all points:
|   slope of the pulldown table from 0 to 0.203 V, typ, clamps not added: 20.1 ohm
|   slope of the pullup table from 0 to 0.203 V, typ, clamps not added: 20.5 ohm
|   GND clamp passes 1 mA (typ) near -0.31 V on its own axis
|   POWER clamp passes 1 mA (typ) near -0.43 V on its own axis
|   rising waveform, R_fixture 50.000, V_fixture 0.000: 20-80 % time 305ps typ, 469ps min, 344ps max; typ from 0 V to 0.912 V
|   rising waveform, R_fixture 50.000, V_fixture 0.675: 20-80 % time 238ps typ, 359ps min, 252ps max; typ from 0.193 V to 1.15 V
|   falling waveform, R_fixture 50.000, V_fixture 0.675: 20-80 % time 163ps typ, 206ps min, 191ps max; typ from 1.15 V to 0.193 V
|   falling waveform, R_fixture 50.000, V_fixture 0.000: 20-80 % time 126ps typ, 153ps min, 140ps max; typ from 0.912 V to 0 V
[Pulldown]
|Voltage   I(typ)   I(min)   I(max)
-1.35V    -286.4mA   -327.1mA   -261.6mA
-1.227V   -208mA     -251mA     -182mA
-1.104V   -138.2mA   -179.4mA   -119.2mA
-1.022V   -102.3mA   -136.2mA   -96.9mA
-899mV    -72.91mA   -84.21mA   -78.45mA
-735mV    -53.57mA   -48.43mA   -56.12mA
-366mV    -20.38mA   -18.73mA   -17.94mA
413mV     18.42mA    17.5mA     18.98mA
1.848V    29.15mA    27.69mA    30.02mA
2.258V    45.11mA    42.86mA    46.47mA
2.422V    88.6mA     84.2mA     91.3mA
2.7V      248.1mA    235.7mA    255.5mA
[Pullup]
|Voltage   I(typ)   I(min)   I(max)
-1.35V    240.6mA    272.8mA    215.6mA
-1.195V   152.8mA    185.5mA    126.5mA
-1.113V   113.2mA    142.9mA    89.8mA
-990mV    73.38mA    88mA       62.28mA
-826mV    54.13mA    45.1mA     47.69mA
322mV     -14.59mA   -13.86mA   -15.03mA
1.716V    -29.16mA   -27.7mA    -30.04mA
2.085V    -50.46mA   -47.93mA   -51.97mA
2.29V     -73.38mA   -69.71mA   -75.58mA
2.372V    -94.8mA    -90.1mA    -97.6mA
2.495V    -149.4mA   -141.9mA   -153.9mA
2.7V      -268.6mA   -255.2mA   -276.7mA
[GND_clamp]
|Voltage   I(typ)   I(min)   I(max)
-1.35V    -320.9mA   -371mA     -291.7mA
-1.21V    -216.8mA   -269.5mA   -187.2mA
-1.126V   -159mA     -211.3mA   -133.3mA
-1.07V    -124.2mA   -174.2mA   -105.6mA
-986mV    -81.78mA   -122.8mA   -81.18mA
-902mV    -55.61mA   -79.36mA   -66.72mA
-818mV    -41.95mA   -47.73mA   -53.44mA
-734mV    -31.67mA   -28.77mA   -40.78mA
-650mV    -22.47mA   -18.69mA   -29.01mA
-454mV    -6.221mA   -5.753mA   -7.69mA
-286mV    -734.4uA   -759.2uA   -785.5uA
2.7V      0A         0A         0A
[POWER_clamp]
|Voltage   I(typ)   I(min)   I(max)
-1.35V    276.5mA    320.5mA    251mA
-1.142V   128.3mA    176.6mA    100.9mA
-1.114V   110.5mA    158.5mA    83.9mA
-1.086V   93.5mA     140.9mA    68.53mA
-1.03V    63.21mA    107.6mA    44.18mA
-1.002V   50.42mA    92.11mA    35.83mA
-946mV    30.82mA    64.28mA    25.76mA
-834mV    13.57mA    25.52mA    16.1mA
-750mV    8.839mA    12.31mA    10.8mA
-610mV    3.896mA    5.035mA    4.505mA
-78mV     75.17uA    92.3uA     98.29uA
2.7V      -1.695mA   -291.3uA   -1.333mA
[Ramp]
| variable   typ   min   max
dV/dt_r   0.547/0.305n   0.511/0.481n   0.577/0.348n
dV/dt_f   0.557/0.239n   0.536/0.297n   0.586/0.316n
R_load = 50.000
[Rising Waveform]
R_fixture = 50.000
V_fixture = 0.000
V_fixture_min = 0.000
V_fixture_max = 0.000
|  time   V(typ)   V(min)   V(max)
0s        17.43uV    -116.7uV   -307.5uV
402ps     -1.127mV   -148.3uV   -1.195mV
517ps     28.51mV    285.3uV    249.7mV
736ps     531.1mV    -1.49mV    681mV
956ps     771.8mV    300.2mV    830.8mV
1.147ns   838.9mV    545.4mV    882.1mV
1.347ns   867.5mV    683.6mV    908.7mV
1.787ns   889.7mV    792.4mV    934.7mV
2.64ns    901.9mV    832.3mV    951.9mV
10ns      912.3mV    852.6mV    964.5mV
[Rising Waveform]
R_fixture = 50.000
V_fixture = 0.675
V_fixture_min = 0.642
V_fixture_max = 0.710
|  time   V(typ)   V(min)   V(max)
0s        192.9mV    190.2mV    198.9mV
351ps     193.3mV    190.2mV    199.5mV
467ps     205.5mV    190.3mV    506.1mV
578ps     541.1mV    189.1mV    839.5mV
687ps     837.8mV    201.8mV    1.016V
837ps     1.022V     509.8mV    1.113V
1.117ns   1.107V     898.5mV    1.17V
1.447ns   1.13V      1.023V     1.19V
2.099ns   1.143V     1.068V     1.205V
10ns      1.154V     1.089V     1.218V
[Falling Waveform]
R_fixture = 50.000
V_fixture = 0.675
V_fixture_min = 0.642
V_fixture_max = 0.710
|  time   V(typ)   V(min)   V(max)
0s        1.154V     1.089V     1.218V
362ps     1.154V     1.089V     1.219V
406ps     1.156V     1.089V     1.112V
467ps     1.153V     1.089V     798.7mV
559ps     805.6mV    1.089V     495.9mV
674ps     412.6mV    1.088V     348.9mV
884ps     266.2mV    486.2mV    267.8mV
1.034ns   239mV      315.9mV    247.1mV
1.944ns   206.4mV    205.3mV    213.4mV
10ns      192.9mV    190.2mV    198.9mV
[Falling Waveform]
R_fixture = 50.000
V_fixture = 0.000
V_fixture_min = 0.000
V_fixture_max = 0.000
|  time   V(typ)   V(min)   V(max)
0s        912.3mV    852.6mV    964.5mV
362ps     912.3mV    852.3mV    966.2mV
457ps     915.4mV    852.4mV    457.7mV
497ps     804.6mV    852mV      296.1mV
587ps     302.3mV    858.8mV    152.3mV
664ps     148.6mV    858mV      103.3mV
824ps     66.19mV    279.5mV    58.85mV
937ps     45.42mV    122.9mV    44.45mV
1.839ns   12.37mV    13.28mV    12.75mV
10ns      17.43uV    -116.7uV   -307.5uV
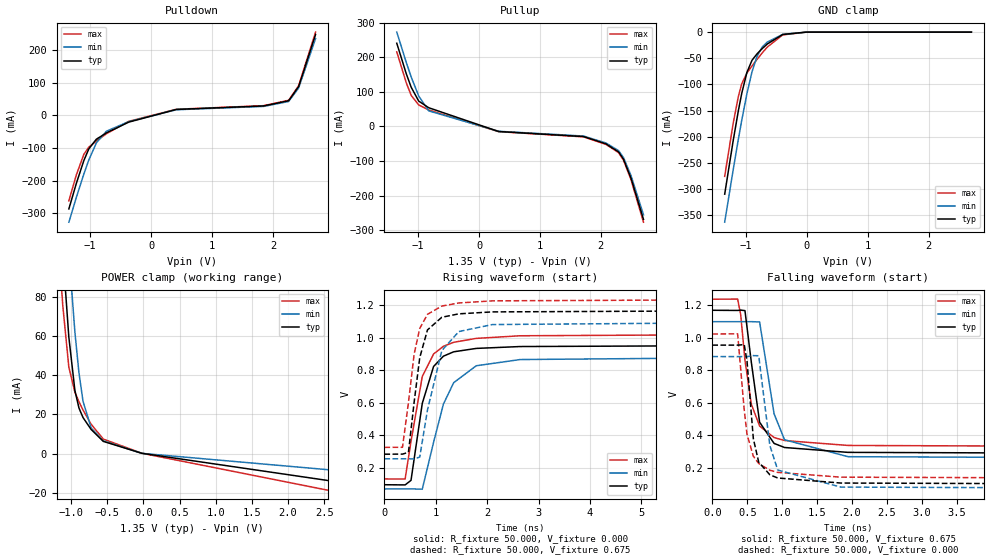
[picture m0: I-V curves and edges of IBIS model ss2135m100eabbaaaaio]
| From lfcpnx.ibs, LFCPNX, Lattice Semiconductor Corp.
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|Model ss2135m100eabbaaaaio
[Model] ss2135m100eabbaaaaio
| Clamp models do not include dynamic input termination. Please refer to
| the ss1135axxxeabbaaaain model for input termination.
Model_type I/O
Polarity   Non-Inverting
Enable   Active-Low
Vinl =  0.575V
Vinh =  0.775V
Vmeas =  0.675V
Cref =  30.000pF
Rref =  50.000
Vref =  0.675V
C_comp   5.000pF   4.000pF   5.500pF
[Temperature Range]   25.000   0.125k   -40.000
[Voltage Range]   1.350V   1.280V   1.420V
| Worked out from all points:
|   slope of the pulldown table from 0 to 0.203 V, typ, clamps not added: 20.1 ohm
|   slope of the pullup table from 0 to 0.203 V, typ, clamps not added: 20.5 ohm
|   GND clamp passes 1 mA (typ) near -0.15 V on its own axis
|   POWER clamp passes 1 mA (typ) near -0.17 V on its own axis
|   rising waveform, R_fixture 50.000, V_fixture 0.000: 20-80 % time 305ps typ, 469ps min, 344ps max; typ from 0.095 V to 0.956 V
|   rising waveform, R_fixture 50.000, V_fixture 0.675: 20-80 % time 238ps typ, 359ps min, 252ps max; typ from 0.283 V to 1.17 V
|   falling waveform, R_fixture 50.000, V_fixture 0.675: 20-80 % time 163ps typ, 206ps min, 191ps max; typ from 1.17 V to 0.283 V
|   falling waveform, R_fixture 50.000, V_fixture 0.000: 20-80 % time 126ps typ, 153ps min, 140ps max; typ from 0.956 V to 0.095 V
[Pulldown]
|Voltage   I(typ)   I(min)   I(max)
-1.35V    -286.4mA   -327.1mA   -261.6mA
-1.227V   -208mA     -251mA     -182mA
-1.104V   -138.2mA   -179.4mA   -119.2mA
-1.022V   -102.3mA   -136.2mA   -96.9mA
-899mV    -72.91mA   -84.21mA   -78.45mA
-735mV    -53.57mA   -48.43mA   -56.12mA
-366mV    -20.38mA   -18.73mA   -17.94mA
413mV     18.42mA    17.5mA     18.98mA
1.848V    29.15mA    27.69mA    30.02mA
2.258V    45.11mA    42.86mA    46.47mA
2.422V    88.6mA     84.2mA     91.3mA
2.7V      248.1mA    235.7mA    255.5mA
[Pullup]
|Voltage   I(typ)   I(min)   I(max)
-1.35V    240.6mA    272.8mA    215.6mA
-1.195V   152.8mA    185.5mA    126.5mA
-1.113V   113.2mA    142.9mA    89.8mA
-990mV    73.38mA    88mA       62.28mA
-826mV    54.13mA    45.1mA     47.69mA
322mV     -14.59mA   -13.86mA   -15.03mA
1.716V    -29.16mA   -27.7mA    -30.04mA
2.085V    -50.46mA   -47.93mA   -51.97mA
2.29V     -73.38mA   -69.71mA   -75.58mA
2.372V    -94.8mA    -90.1mA    -97.6mA
2.495V    -149.4mA   -141.9mA   -153.9mA
2.7V      -268.6mA   -255.2mA   -276.7mA
[GND_clamp]
|Voltage   I(typ)   I(min)   I(max)
-1.35V    -309.8mA   -363.4mA   -275.8mA
-1.21V    -207.1mA   -262.8mA   -173.9mA
-1.126V   -150.5mA   -205.1mA   -123.2mA
-1.07V    -117mA     -168.5mA   -98.8mA
-986mV    -77.25mA   -118.1mA   -78.4mA
-902mV    -53.89mA   -76.04mA   -64.81mA
-818mV    -41.42mA   -46.02mA   -52mA
-734mV    -31.56mA   -28.41mA   -39.82mA
-650mV    -22.69mA   -19.03mA   -28.57mA
-398mV    -4.585mA   -4.332mA   -5.35mA
-6mV      -40.55uA   -29.87uA   -52.89uA
2.7V      0A         0A         0A
[POWER_clamp]
|Voltage   I(typ)   I(min)   I(max)
-1.35V    264.6mA    312.3mA    234.2mA
-1.17V    138mA      188.5mA    107.5mA
-1.142V   120.1mA    170.4mA    90.88mA
-1.114V   103.1mA    152.7mA    75.88mA
-1.03V    59.59mA    103.2mA    44.19mA
-946mV    32.22mA    62.05mA    31.33mA
-890mV    23.29mA    41.28mA    26.5mA
-834mV    18.42mA    26.8mA     22.3mA
-722mV    12.33mA    13.1mA     15mA
-554mV    6.226mA    6.542mA    7.404mA
-22mV     128.8uA    103.1uA    167.9uA
2.7V      -14.6mA    -8.747mA   -19.86mA
[Ramp]
| variable   typ   min   max
dV/dt_r   0.516/0.305n   0.478/0.481n   0.536/0.348n
dV/dt_f   0.502/0.239n   0.483/0.297n   0.509/0.316n
R_load = 50.000
[Rising Waveform]
R_fixture = 50.000
V_fixture = 0.000
V_fixture_min = 0.000
V_fixture_max = 0.000
|  time   V(typ)   V(min)   V(max)
0s        94.9mV     68.91mV    130.7mV
402ps     93.82mV    68.88mV    129.9mV
517ps     121.8mV    69.3mV     362mV
736ps     595.9mV    67.6mV     761.1mV
956ps     823mV      356.3mV    899.7mV
1.147ns   886.3mV    591mV      947.2mV
1.347ns   913.3mV    723.3mV    971.8mV
1.787ns   934.2mV    827.4mV    995.9mV
2.64ns    945.7mV    865.6mV    1.012V
10ns      955.5mV    885mV      1.024V
[Rising Waveform]
R_fixture = 50.000
V_fixture = 0.675
V_fixture_min = 0.642
V_fixture_max = 0.710
|  time   V(typ)   V(min)   V(max)
0s        283mV      254.5mV    325mV
351ps     283.3mV    254.6mV    325.5mV
467ps     294.6mV    254.7mV    600.3mV
578ps     604mV      253.5mV    899.2mV
687ps     877.6mV    265.5mV    1.057V
837ps     1.048V     555.4mV    1.144V
1.117ns   1.126V     921.2mV    1.195V
1.447ns   1.147V     1.038V     1.214V
2.099ns   1.159V     1.081V     1.227V
10ns      1.17V      1.1V       1.238V
[Falling Waveform]
R_fixture = 50.000
V_fixture = 0.675
V_fixture_min = 0.642
V_fixture_max = 0.710
|  time   V(typ)   V(min)   V(max)
0s        1.17V      1.1V       1.238V
362ps     1.169V     1.1V       1.239V
406ps     1.171V     1.1V       1.143V
467ps     1.168V     1.1V       862.6mV
559ps     847.9mV    1.1V       591.2mV
677ps     480.8mV    1.098V     457.4mV
884ps     350.6mV    533.2mV    386.7mV
1.034ns   325.4mV    372.9mV    368.2mV
1.944ns   295.4mV    268.8mV    338mV
10ns      283mV      254.5mV    325mV
[Falling Waveform]
R_fixture = 50.000
V_fixture = 0.000
V_fixture_min = 0.000
V_fixture_max = 0.000
|  time   V(typ)   V(min)   V(max)
0s        955.5mV    885mV      1.024V
362ps     955.5mV    884.7mV    1.025V
457ps     958.5mV    884.9mV    554.5mV
497ps     854mV      884.4mV    405mV
587ps     380mV      890.9mV    271.9mV
664ps     235.1mV    890.2mV    226.6mV
824ps     157.3mV    336.5mV    185.4mV
937ps     137.7mV    186.6mV    172.1mV
1.839ns   106.6mV    81.73mV    142.8mV
10ns      94.9mV     68.91mV    130.7mV
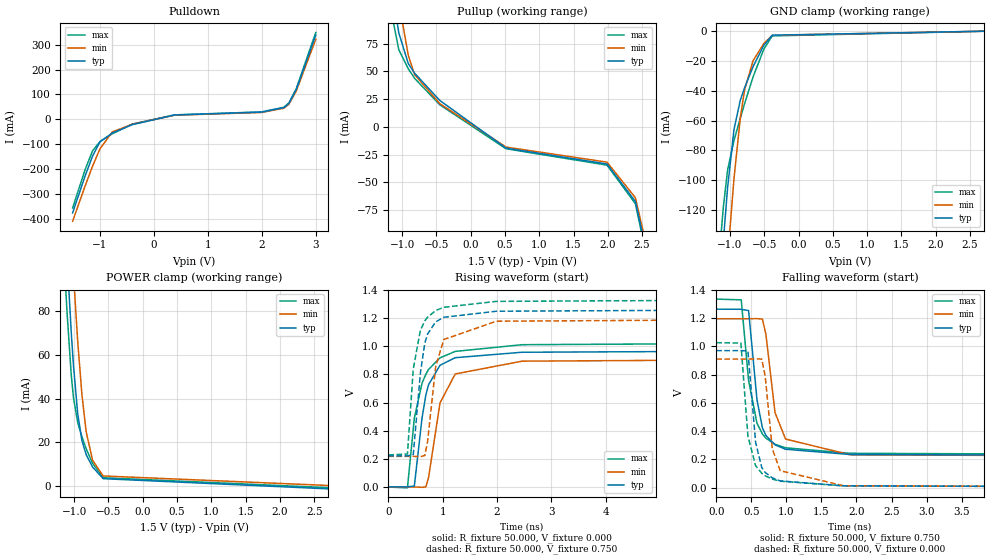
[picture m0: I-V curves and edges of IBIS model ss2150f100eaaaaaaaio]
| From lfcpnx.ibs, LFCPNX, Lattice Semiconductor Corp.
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|Model ss2150f100eaaaaaaaio
[Model] ss2150f100eaaaaaaaio
| Clamp models do not include dynamic input termination. Please refer to
| the ss1150axxxeaaaaaaain model for input termination.
Model_type I/O
Polarity   Non-Inverting
Enable   Active-Low
Vinl =  0.650V
Vinh =  0.850V
Vmeas =  0.750V
Cref =  30.000pF
Rref =  50.000
Vref =  0.750V
C_comp   5.000pF   4.000pF   5.500pF
[Temperature Range]   25.000   0.125k   -40.000
[Voltage Range]   1.500V   1.430V   1.580V
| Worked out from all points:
|   slope of the pulldown table from 0 to 0.225 V, typ, clamps not added: 20.8 ohm
|   slope of the pullup table from 0 to 0.225 V, typ, clamps not added: 22.9 ohm
|   GND clamp passes 1 mA (typ) near -0.31 V on its own axis
|   POWER clamp passes 1 mA (typ) near -0.43 V on its own axis
|   rising waveform, R_fixture 50.000, V_fixture 0.000: 20-80 % time 248ps typ, 294ps min, 311ps max; typ from 0 V to 0.97 V
|   rising waveform, R_fixture 50.000, V_fixture 0.750: 20-80 % time 181ps typ, 219ps min, 199ps max; typ from 0.22 V to 1.26 V
|   falling waveform, R_fixture 50.000, V_fixture 0.750: 20-80 % time 146ps typ, 176ps min, 187ps max; typ from 1.26 V to 0.22 V
|   falling waveform, R_fixture 50.000, V_fixture 0.000: 20-80 % time 111ps typ, 134ps min, 132ps max; typ from 0.97 V to 0 V
[Pulldown]
|Voltage   I(typ)   I(min)   I(max)
-1.5V     -377mA     -410.6mA   -356.7mA
-1.27V    -228.9mA   -269.3mA   -203.8mA
-1.132V   -149mA     -189.6mA   -127.7mA
-994mV    -90.7mA    -119.2mA   -89.9mA
-764mV    -55.28mA   -50.83mA   -58.49mA
-396mV    -21.84mA   -20.02mA   -19.45mA
386mV     17.08mA    16.22mA    17.59mA
1.996V    28.64mA    27.2mA     29.5mA
2.41V     46.69mA    44.35mA    48.09mA
2.502V    63.37mA    60.2mA     65.27mA
2.64V     119.9mA    113.9mA    123.5mA
3V        338.5mA    321.6mA    348.7mA
[Pullup]
|Voltage   I(typ)   I(min)   I(max)
-1.5V     326.9mA    357.8mA    306.3mA
-1.186V   144.3mA    180mA      119.7mA
-1.14V    121.6mA    156.3mA    98.4mA
-1.048V   84.7mA     113mA      69.57mA
-910mV    57.19mA    64.68mA    52.41mA
-818mV    48.47mA    47.23mA    43.81mA
-450mV    23.85mA    20.99mA    19.98mA
516mV     -19.1mA    -18.14mA   -19.67mA
1.988V    -33.41mA   -31.74mA   -34.41mA
2.402V    -67.17mA   -63.81mA   -69.18mA
2.586V    -119.1mA   -113.1mA   -122.7mA
3V        -358.2mA   -340.3mA   -368.9mA
[GND_clamp]
|Voltage   I(typ)   I(min)   I(max)
-1.5V     -437.6mA   -483.1mA   -411.3mA
-1.159V   -181.2mA   -234mA     -153.2mA
-1.128V   -160.4mA   -212.8mA   -134.5mA
-1.097V   -140.5mA   -192mA     -117.9mA
-1.035V   -104.9mA   -152.2mA   -93.08mA
-942mV    -66.01mA   -98.88mA   -73.31mA
-849mV    -46.26mA   -57.94mA   -58.29mA
-787mV    -38.01mA   -39.4mA    -48.69mA
-663mV    -23.84mA   -19.92mA   -30.76mA
-508mV    -9.791mA   -8.549mA   -12.41mA
-384mV    -2.92mA    -2.99mA    -3.392mA
3V        0A         0A         0A
[POWER_clamp]
|Voltage   I(typ)   I(min)   I(max)
-1.5V     391.5mA    430.3mA    369.8mA
-1.166V   144.9mA    193mA      117.4mA
-1.135V   124.5mA    172.6mA    97.69mA
-1.104V   105.1mA    152.8mA    79.63mA
-1.042V   70.22mA    115.2mA    50.64mA
-1.011V   55.5mA     97.74mA    40.7mA
-949mV    33.19mA    66.57mA    29.05mA
-887mV    20.7mA     41.83mA    22.48mA
-825mV    14.31mA    24.76mA    16.96mA
-732mV    8.589mA    11.69mA    10.31mA
-577mV    3.202mA    4.456mA    3.639mA
3V        -1.88mA    -305.7uA   -1.33mA
[Ramp]
| variable   typ   min   max
dV/dt_r   0.582/0.251n   0.573/0.299n   0.619/0.317n
dV/dt_f   0.604/0.235n   0.592/0.273n   0.640/0.344n
R_load = 50.000
[Rising Waveform]
R_fixture = 50.000
V_fixture = 0.000
V_fixture_min = 0.000
V_fixture_max = 0.000
|  time   V(typ)   V(min)   V(max)
0s        68.2uV     -446.1uV   -1.15mV
351ps     528.8uV    -427.9uV   -6.788mV
478ps     6.14mV     -325uV     489.3mV
618ps     485.2mV    -3.105mV   736mV
690ps     654.5mV    -232.7uV   801.6mV
740ps     727.2mV    68.19mV    835.2mV
950ps     864.8mV    597mV      917.7mV
1.23ns    918.7mV    803mV      963.4mV
2.46ns    957.4mV    893.9mV    1.011V
10ns      970.5mV    910.7mV    1.027V
[Rising Waveform]
R_fixture = 50.000
V_fixture = 0.750
V_fixture_min = 0.713
V_fixture_max = 0.789
|  time   V(typ)   V(min)   V(max)
0s        220mV      216.6mV    227.2mV
351ps     220.3mV    216.6mV    233.8mV
458ps     229.4mV    216.7mV    838.4mV
588ps     806mV      215.1mV    1.112V
670ps     1.022V     222.9mV    1.18V
720ps     1.086V     317.9mV    1.206V
870ps     1.173V     854.5mV    1.254V
1.02ns    1.206V     1.048V     1.277V
1.988ns   1.249V     1.178V     1.319V
10ns      1.264V     1.196V     1.335V
[Falling Waveform]
R_fixture = 50.000
V_fixture = 0.750
V_fixture_min = 0.713
V_fixture_max = 0.789
|  time   V(typ)   V(min)   V(max)
0s        1.264V     1.196V     1.335V
356ps     1.263V     1.196V     1.33V
461ps     1.254V     1.196V     757.9mV
581ps     621.5mV    1.197V     455.6mV
658ps     424.4mV    1.194V     380.4mV
708ps     369.8mV    1.086V     350.9mV
838ps     303.3mV    531.7mV    306.9mV
988ps     272.2mV    344.4mV    282.5mV
1.908ns   235.1mV    232.9mV    243.5mV
10ns      220mV      216.6mV    227.2mV
[Falling Waveform]
R_fixture = 50.000
V_fixture = 0.000
V_fixture_min = 0.000
V_fixture_max = 0.000
|  time   V(typ)   V(min)   V(max)
0s        970.5mV    910.7mV    1.027V
351ps     970.3mV    910.5mV    1.024V
451ps     967.8mV    910.6mV    366.8mV
561ps     320.8mV    912.2mV    155.8mV
649ps     142.1mV    910.7mV    101.7mV
698ps     107.7mV    789.4mV    83.97mV
799ps     69.39mV    275.9mV    60.82mV
911ps     48.09mV    120.6mV    46.07mV
1.818ns   13.21mV    13.55mV    12.71mV
10ns      68.2uV     -446.1uV   -1.15mV
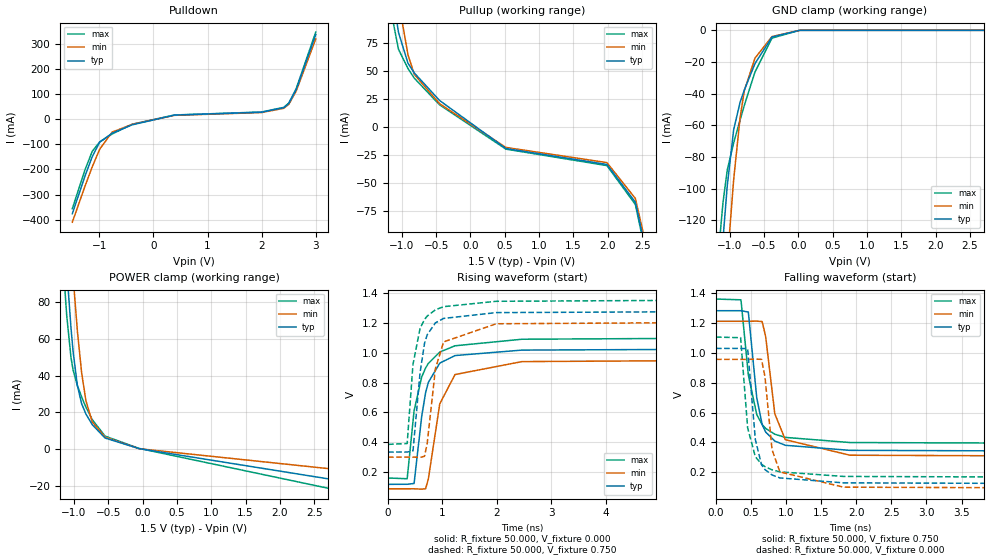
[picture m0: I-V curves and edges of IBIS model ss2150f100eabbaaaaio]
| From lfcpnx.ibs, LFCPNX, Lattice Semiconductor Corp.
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|Model ss2150f100eabbaaaaio
[Model] ss2150f100eabbaaaaio
| Clamp models do not include dynamic input termination. Please refer to
| the ss1150axxxeabbaaaain model for input termination.
Model_type I/O
Polarity   Non-Inverting
Enable   Active-Low
Vinl =  0.650V
Vinh =  0.850V
Vmeas =  0.750V
Cref =  30.000pF
Rref =  50.000
Vref =  0.750V
C_comp   5.000pF   4.000pF   5.500pF
[Temperature Range]   25.000   0.125k   -40.000
[Voltage Range]   1.500V   1.430V   1.580V
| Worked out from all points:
|   slope of the pulldown table from 0 to 0.225 V, typ, clamps not added: 20.8 ohm
|   slope of the pullup table from 0 to 0.225 V, typ, clamps not added: 22.9 ohm
|   GND clamp passes 1 mA (typ) near -0.15 V on its own axis
|   POWER clamp passes 1 mA (typ) near -0.17 V on its own axis
|   rising waveform, R_fixture 50.000, V_fixture 0.000: 20-80 % time 248ps typ, 294ps min, 311ps max; typ from 0.117 V to 1.03 V
|   rising waveform, R_fixture 50.000, V_fixture 0.750: 20-80 % time 181ps typ, 219ps min, 199ps max; typ from 0.334 V to 1.28 V
|   falling waveform, R_fixture 50.000, V_fixture 0.750: 20-80 % time 146ps typ, 176ps min, 187ps max; typ from 1.28 V to 0.334 V
|   falling waveform, R_fixture 50.000, V_fixture 0.000: 20-80 % time 111ps typ, 134ps min, 132ps max; typ from 1.03 V to 0.117 V
[Pulldown]
|Voltage   I(typ)   I(min)   I(max)
-1.5V     -377mA     -410.6mA   -356.7mA
-1.27V    -228.9mA   -269.3mA   -203.8mA
-1.132V   -149mA     -189.6mA   -127.7mA
-994mV    -90.7mA    -119.2mA   -89.9mA
-764mV    -55.28mA   -50.83mA   -58.49mA
-396mV    -21.84mA   -20.02mA   -19.45mA
386mV     17.08mA    16.22mA    17.59mA
1.996V    28.64mA    27.2mA     29.5mA
2.41V     46.69mA    44.35mA    48.09mA
2.502V    63.37mA    60.2mA     65.27mA
2.64V     119.9mA    113.9mA    123.5mA
3V        338.5mA    321.6mA    348.7mA
[Pullup]
|Voltage   I(typ)   I(min)   I(max)
-1.5V     326.9mA    357.8mA    306.3mA
-1.186V   144.3mA    180mA      119.7mA
-1.14V    121.6mA    156.3mA    98.4mA
-1.048V   84.7mA     113mA      69.57mA
-910mV    57.19mA    64.68mA    52.41mA
-818mV    48.47mA    47.23mA    43.81mA
-450mV    23.85mA    20.99mA    19.98mA
516mV     -19.1mA    -18.14mA   -19.67mA
1.988V    -33.41mA   -31.74mA   -34.41mA
2.402V    -67.17mA   -63.81mA   -69.18mA
2.586V    -119.1mA   -113.1mA   -122.7mA
3V        -358.2mA   -340.3mA   -368.9mA
[GND_clamp]
|Voltage   I(typ)   I(min)   I(max)
-1.5V     -423.6mA   -473.4mA   -391.3mA
-1.159V   -170.8mA   -226.4mA   -140.1mA
-1.128V   -150.6mA   -205.4mA   -123mA
-1.097V   -131.5mA   -185mA     -108.4mA
-1.035V   -97.76mA   -145.9mA   -88.03mA
-942mV    -62.68mA   -94.08mA   -70.99mA
-849mV    -45.44mA   -55.18mA   -56.59mA
-787mV    -37.67mA   -38mA      -47.37mA
-632mV    -20.99mA   -17.55mA   -26.32mA
-384mV    -4.202mA   -3.933mA   -4.89mA
19mV      0A         0A         0A
3V        0A         0A         0A
[POWER_clamp]
|Voltage   I(typ)   I(min)   I(max)
-1.5V     377.8mA    420.9mA    350.6mA
-1.166V   135.9mA    186.4mA    106mA
-1.104V   98.02mA    147mA      72.63mA
-1.042V   66.02mA    110.5mA    49.91mA
-1.011V   53.08mA    93.78mA    43.04mA
-949mV    34.63mA    64.31mA    34.62mA
-887mV    24.77mA    41.57mA    28.48mA
-825mV    19.16mA    26.4mA     22.89mA
-732mV    13.32mA    14.81mA    16.07mA
-546mV    6.068mA    6.58mA     7.125mA
-50mV     295.8uA    241.2uA    397.5uA
3V        -17.94mA   -11.75mA   -23.63mA
[Ramp]
| variable   typ   min   max
dV/dt_r   0.548/0.251n   0.522/0.299n   0.568/0.317n
dV/dt_f   0.528/0.235n   0.514/0.273n   0.529/0.344n
R_load = 50.000
[Rising Waveform]
R_fixture = 50.000
V_fixture = 0.000
V_fixture_min = 0.000
V_fixture_max = 0.000
|  time   V(typ)   V(min)   V(max)
0s        116.9mV    86.91mV    159.5mV
351ps     117.3mV    86.93mV    154.4mV
478ps     122.6mV    87.03mV    611.2mV
618ps     573.9mV    84.37mV    838.5mV
690ps     733.4mV    87.12mV    898.9mV
740ps     801.9mV    152.5mV    929.8mV
950ps     931.5mV    657.9mV    1.006V
1.23ns    982.3mV    854.7mV    1.048V
2.46ns    1.019V     941.7mV    1.092V
10ns      1.031V     957.7mV    1.107V
[Rising Waveform]
R_fixture = 50.000
V_fixture = 0.750
V_fixture_min = 0.713
V_fixture_max = 0.789
|  time   V(typ)   V(min)   V(max)
0s        333.7mV    299.5mV    385.4mV
351ps     333.9mV    299.6mV    391.3mV
458ps     342.2mV    299.7mV    924mV
588ps     867.6mV    298.1mV    1.165V
670ps     1.065V     305.4mV    1.225V
720ps     1.123V     394mV      1.248V
870ps     1.202V     894.2mV    1.29V
1.02ns    1.232V     1.074V     1.311V
1.988ns   1.271V     1.196V     1.347V
10ns      1.284V     1.213V     1.362V
[Falling Waveform]
R_fixture = 50.000
V_fixture = 0.750
V_fixture_min = 0.713
V_fixture_max = 0.789
|  time   V(typ)   V(min)   V(max)
0s        1.284V     1.213V     1.362V
356ps     1.284V     1.213V     1.357V
461ps     1.275V     1.213V     853.1mV
581ps     699.5mV    1.214V     586.7mV
658ps     519.9mV    1.211V     520.5mV
708ps     470.1mV    1.11V      494.4mV
838ps     409.6mV    593.3mV    455.6mV
988ps     381.2mV    418.7mV    434.2mV
1.908ns   347.4mV    314.7mV    399.8mV
10ns      333.7mV    299.5mV    385.4mV
[Falling Waveform]
R_fixture = 50.000
V_fixture = 0.000
V_fixture_min = 0.000
V_fixture_max = 0.000
|  time   V(typ)   V(min)   V(max)
0s        1.031V     957.7mV    1.107V
351ps     1.031V     957.5mV    1.103V
451ps     1.029V     957.6mV    498.4mV
561ps     419.1mV    959.1mV    304.1mV
649ps     250.7mV    957.7mV    254.3mV
698ps     218.3mV    841.8mV    237.9mV
799ps     182.2mV    351.1mV    216.6mV
911ps     162.2mV    202.6mV    203mV
1.818ns   129.3mV    100.3mV    172.3mV
10ns      116.9mV    86.91mV    159.5mV
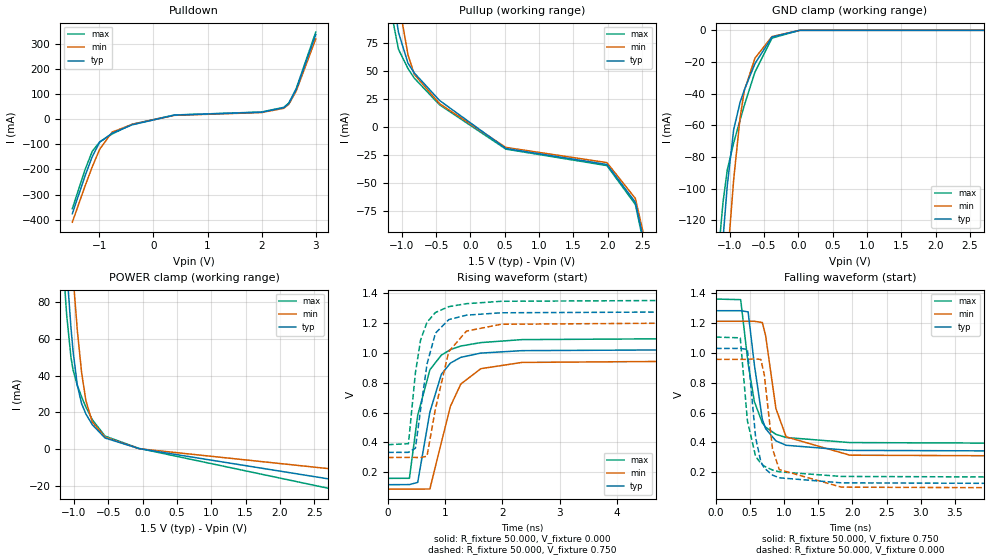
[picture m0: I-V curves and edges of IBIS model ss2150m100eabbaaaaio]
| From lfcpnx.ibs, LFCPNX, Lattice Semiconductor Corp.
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|Model ss2150m100eabbaaaaio
[Model] ss2150m100eabbaaaaio
| Clamp models do not include dynamic input termination. Please refer to
| the ss1150axxxeabbaaaain model for input termination.
Model_type I/O
Polarity   Non-Inverting
Enable   Active-Low
Vinl =  0.650V
Vinh =  0.850V
Vmeas =  0.750V
Cref =  30.000pF
Rref =  50.000
Vref =  0.750V
C_comp   5.000pF   4.000pF   5.500pF
[Temperature Range]   25.000   0.125k   -40.000
[Voltage Range]   1.500V   1.430V   1.580V
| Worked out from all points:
|   slope of the pulldown table from 0 to 0.225 V, typ, clamps not added: 20.8 ohm
|   slope of the pullup table from 0 to 0.225 V, typ, clamps not added: 22.9 ohm
|   GND clamp passes 1 mA (typ) near -0.15 V on its own axis
|   POWER clamp passes 1 mA (typ) near -0.17 V on its own axis
|   rising waveform, R_fixture 50.000, V_fixture 0.000: 20-80 % time 316ps typ, 400ps min, 332ps max; typ from 0.117 V to 1.03 V
|   rising waveform, R_fixture 50.000, V_fixture 0.750: 20-80 % time 250ps typ, 316ps min, 223ps max; typ from 0.334 V to 1.28 V
|   falling waveform, R_fixture 50.000, V_fixture 0.750: 20-80 % time 173ps typ, 218ps min, 209ps max; typ from 1.28 V to 0.334 V
|   falling waveform, R_fixture 50.000, V_fixture 0.000: 20-80 % time 126ps typ, 156ps min, 146ps max; typ from 1.03 V to 0.117 V
[Pulldown]
|Voltage   I(typ)   I(min)   I(max)
-1.5V     -377mA     -410.6mA   -356.7mA
-1.27V    -228.9mA   -269.3mA   -203.8mA
-1.132V   -149mA     -189.6mA   -127.7mA
-994mV    -90.7mA    -119.2mA   -89.9mA
-764mV    -55.28mA   -50.83mA   -58.49mA
-396mV    -21.84mA   -20.02mA   -19.45mA
386mV     17.08mA    16.22mA    17.59mA
1.996V    28.64mA    27.2mA     29.5mA
2.41V     46.69mA    44.35mA    48.09mA
2.502V    63.37mA    60.2mA     65.27mA
2.64V     119.9mA    113.9mA    123.5mA
3V        338.5mA    321.6mA    348.7mA
[Pullup]
|Voltage   I(typ)   I(min)   I(max)
-1.5V     326.9mA    357.8mA    306.3mA
-1.186V   144.3mA    180mA      119.7mA
-1.14V    121.6mA    156.3mA    98.4mA
-1.048V   84.7mA     113mA      69.57mA
-910mV    57.19mA    64.68mA    52.41mA
-818mV    48.47mA    47.23mA    43.81mA
-450mV    23.85mA    20.99mA    19.98mA
516mV     -19.1mA    -18.14mA   -19.67mA
1.988V    -33.41mA   -31.74mA   -34.41mA
2.402V    -67.17mA   -63.81mA   -69.18mA
2.586V    -119.1mA   -113.1mA   -122.7mA
3V        -358.2mA   -340.3mA   -368.9mA
[GND_clamp]
|Voltage   I(typ)   I(min)   I(max)
-1.5V     -423.6mA   -473.4mA   -391.3mA
-1.159V   -170.8mA   -226.4mA   -140.1mA
-1.128V   -150.6mA   -205.4mA   -123mA
-1.097V   -131.5mA   -185mA     -108.4mA
-1.035V   -97.76mA   -145.9mA   -88.03mA
-942mV    -62.68mA   -94.08mA   -70.99mA
-849mV    -45.44mA   -55.18mA   -56.59mA
-787mV    -37.67mA   -38mA      -47.37mA
-632mV    -20.99mA   -17.55mA   -26.32mA
-384mV    -4.202mA   -3.933mA   -4.89mA
19mV      0A         0A         0A
3V        0A         0A         0A
[POWER_clamp]
|Voltage   I(typ)   I(min)   I(max)
-1.5V     377.8mA    420.9mA    350.6mA
-1.166V   135.9mA    186.4mA    106mA
-1.104V   98.02mA    147mA      72.63mA
-1.042V   66.02mA    110.5mA    49.91mA
-1.011V   53.08mA    93.78mA    43.04mA
-949mV    34.63mA    64.31mA    34.62mA
-887mV    24.77mA    41.57mA    28.48mA
-825mV    19.16mA    26.4mA     22.89mA
-732mV    13.32mA    14.81mA    16.07mA
-546mV    6.068mA    6.58mA     7.125mA
-50mV     295.8uA    241.2uA    397.5uA
3V        -17.94mA   -11.75mA   -23.63mA
[Ramp]
| variable   typ   min   max
dV/dt_r   0.548/0.321n   0.522/0.405n   0.568/0.337n
dV/dt_f   0.528/0.272n   0.514/0.336n   0.529/0.366n
R_load = 50.000
[Rising Waveform]
R_fixture = 50.000
V_fixture = 0.000
V_fixture_min = 0.000
V_fixture_max = 0.000
|  time   V(typ)   V(min)   V(max)
0s        116.9mV    86.91mV    159.5mV
373ps     117.6mV    86.93mV    159.9mV
518ps     132.4mV    87.26mV    582.8mV
731ps     604.3mV    88.31mV    887.9mV
931ps     857.2mV    400.1mV    985.8mV
1.09ns    932.6mV    642.9mV    1.023V
1.271ns   971.1mV    791.9mV    1.047V
1.621ns   999.6mV    895mV      1.07V
2.34ns    1.016V     937mV      1.09V
10ns      1.031V     957.7mV    1.107V
[Rising Waveform]
R_fixture = 50.000
V_fixture = 0.750
V_fixture_min = 0.713
V_fixture_max = 0.789
|  time   V(typ)   V(min)   V(max)
0s        333.7mV    299.5mV    385.4mV
356ps     333.9mV    299.6mV    391.9mV
478ps     361.9mV    299.7mV    867.5mV
568ps     619mV      298.8mV    1.087V
680ps     925mV      308mV      1.206V
828ps     1.133V     625.5mV    1.272V
1.06ns    1.224V     1.009V     1.311V
1.369ns   1.254V     1.147V     1.331V
1.978ns   1.27V      1.193V     1.347V
10ns      1.284V     1.213V     1.362V
[Falling Waveform]
R_fixture = 50.000
V_fixture = 0.750
V_fixture_min = 0.713
V_fixture_max = 0.789
|  time   V(typ)   V(min)   V(max)
0s        1.284V     1.213V     1.362V
362ps     1.284V     1.213V     1.358V
471ps     1.276V     1.213V     928.7mV
562ps     923mV      1.213V     674.6mV
679ps     555.3mV    1.205V     531.9mV
728ps     492.6mV    1.115V     502.6mV
878ps     410.7mV    628.2mV    454.8mV
1.028ns   381.3mV    437.7mV    433.5mV
1.962ns   347.1mV    314.9mV    399.4mV
10ns      333.7mV    299.5mV    385.4mV
[Falling Waveform]
R_fixture = 50.000
V_fixture = 0.000
V_fixture_min = 0.000
V_fixture_max = 0.000
|  time   V(typ)   V(min)   V(max)
0s        1.031V     957.7mV    1.107V
356ps     1.031V     957.5mV    1.102V
461ps     1.024V     957.5mV    543.9mV
581ps     432.8mV    961.3mV    306.6mV
658ps     269.7mV    956.3mV    259.5mV
708ps     228.6mV    853.9mV    241.2mV
828ps     181.4mV    357.4mV    215.2mV
928ps     163.1mV    218mV      203.2mV
1.838ns   129.3mV    100.4mV    172.3mV
10ns      116.9mV    86.91mV    159.5mV
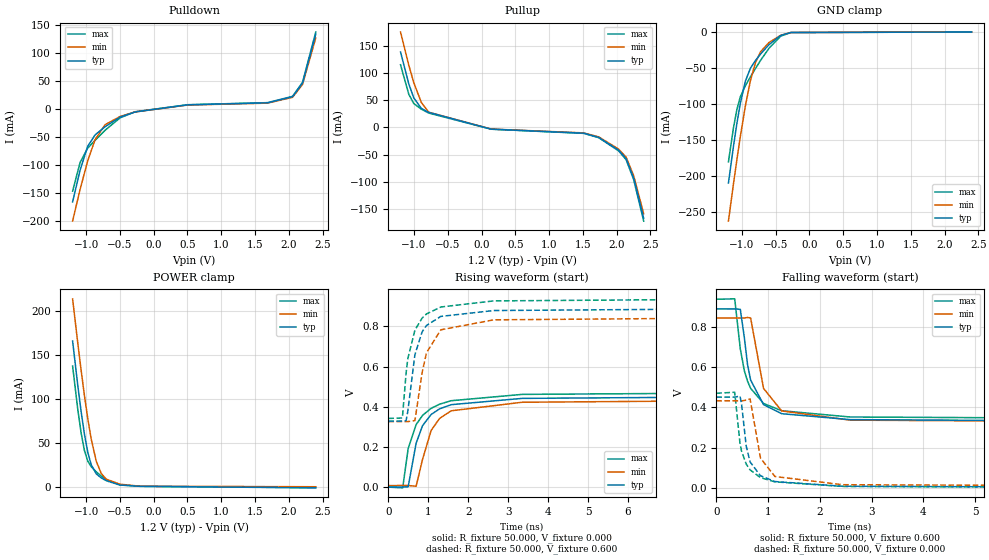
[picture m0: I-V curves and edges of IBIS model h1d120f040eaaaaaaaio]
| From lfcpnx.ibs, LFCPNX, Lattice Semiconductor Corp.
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[Model] h1d120f040eaaaaaaaio
Model_type I/O
Polarity   Non-Inverting
Enable   Active-Low
Vinl =  0.500V
Vinh =  0.700V
Vmeas =  0.600V
Cref =  20.000pF
Rref =  50.000
Vref =  0.600V
C_comp   5.000pF   4.000pF   5.500pF
[Temperature Range]   25.000   0.125k   -40.000
[Voltage Range]   1.200V   1.140V   1.260V
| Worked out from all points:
|   slope of the pulldown table from 0 to 0.18 V, typ, clamps not added: 56.1 ohm
|   slope of the pullup table from 0 to 0.18 V, typ, clamps not added: 47.9 ohm
|   GND clamp passes 1 mA (typ) near -0.31 V on its own axis
|   POWER clamp passes 1 mA (typ) near -0.43 V on its own axis
|   rising waveform, R_fixture 50.000, V_fixture 0.000: 20-80 % time 491ps typ, 502ps min, 533ps max; typ from 0 V to 0.451 V
|   rising waveform, R_fixture 50.000, V_fixture 0.600: 20-80 % time 334ps typ, 368ps min, 358ps max; typ from 0.328 V to 0.889 V
|   falling waveform, R_fixture 50.000, V_fixture 0.600: 20-80 % time 292ps typ, 298ps min, 332ps max; typ from 0.889 V to 0.328 V
|   falling waveform, R_fixture 50.000, V_fixture 0.000: 20-80 % time 221ps typ, 234ps min, 242ps max; typ from 0.451 V to 0 V
[Pulldown]
|Voltage   I(typ)   I(min)   I(max)
-1.2V     -166.4mA   -200.7mA   -147.3mA
-1.089V   -109.6mA   -144mA     -95.8mA
-978mV    -67.28mA   -93.6mA    -70.51mA
-867mV    -46.43mA   -54.86mA   -56.06mA
-719mV    -31.83mA   -28.23mA   -38.18mA
-497mV    -14.71mA   -13.56mA   -16.01mA
-275mV    -5.433mA   -5.348mA   -5.056mA
502mV     7.324mA    6.958mA    7.544mA
1.686V    10.94mA    10.39mA    11.26mA
2.056V    21.9mA     20.8mA     22.55mA
2.204V    46.11mA    43.81mA    47.5mA
2.4V      133.7mA    127mA      137.7mA
[Pullup]
|Voltage   I(typ)   I(min)   I(max)
-1.2V     139.5mA    176.3mA    115.9mA
-1.078V   80.7mA     115.2mA    61.56mA
-1.004V   54.78mA    82.9mA     44.18mA
-893mV    35.43mA    46.5mA     33.93mA
-782mV    27.87mA    28.19mA    26.66mA
143mV     -3.068mA   -2.915mA   -3.16mA
1.512V    -10.51mA   -9.984mA   -10.82mA
1.734V    -18.26mA   -17.34mA   -18.8mA
2.03V     -42.05mA   -39.95mA   -43.31mA
2.141V    -57.86mA   -54.97mA   -59.6mA
2.252V    -93.6mA    -88.9mA    -96.4mA
2.4V      -167.7mA   -159.3mA   -172.7mA
[GND_clamp]
|Voltage   I(typ)   I(min)   I(max)
-1.2V     -209.6mA   -262.4mA   -180.2mA
-1.125V   -158.2mA   -210.5mA   -132.7mA
-1.075V   -127mA     -177.3mA   -107.7mA
-1.025V   -99.59mA   -145.8mA   -90.14mA
-950mV    -68.44mA   -102.9mA   -74.64mA
-875mV    -50.37mA   -67.7mA    -62.38mA
-800mV    -39.61mA   -42.62mA   -50.65mA
-725mV    -30.63mA   -27.35mA   -39.46mA
-600mV    -17.53mA   -14.58mA   -22.59mA
-425mV    -4.657mA   -4.485mA   -5.636mA
-275mV    -627.9uA   -616.8uA   -678.4uA
2.4V      0A         0A         0A
[POWER_clamp]
|Voltage   I(typ)   I(min)   I(max)
-1.2V     166.3mA    214.4mA    137.7mA
-1.125V   116.5mA    164.9mA    89.12mA
-1.075V   86.21mA    133.5mA    61.64mA
-1.025V   59.86mA    104mA      41.12mA
-975mV    39.03mA    77.38mA    28.98mA
-925mV    24.95mA    54.44mA    22.72mA
-850mV    14.48mA    28.92mA    16.81mA
-775mV    9.774mA    14.73mA    11.95mA
-700mV    6.595mA    8.327mA    7.924mA
-500mV    1.71mA     2.674mA    1.891mA
-200mV    207.6uA    329.9uA    277.5uA
2.4V      -1.508mA   -253.4uA   -1.296mA
[Ramp]
| variable   typ   min   max
dV/dt_r   0.270/0.491n   0.255/0.510n   0.282/0.537n
dV/dt_f   0.259/0.471n   0.240/0.448n   0.270/0.541n
R_load = 50.000
[Rising Waveform]
R_fixture = 50.000
V_fixture = 0.000
V_fixture_min = 0.000
V_fixture_max = 0.000
|  time   V(typ)   V(min)   V(max)
0s        33.76uV    7.521mV    -284.2uV
359ps     415.6uV    7.573mV    -3.926mV
496ps     1.294mV    7.666mV    191.6mV
695ps     218.2mV    3.953mV    311mV
856ps     305.7mV    137.7mV    356.8mV
1.071ns   361.2mV    281.8mV    392.1mV
1.284ns   389.6mV    342.1mV    412.8mV
1.574ns   410.3mV    379.8mV    430mV
3.35ns    441.6mV    422.3mV    461.5mV
10ns      450.5mV    432.2mV    470mV
[Rising Waveform]
R_fixture = 50.000
V_fixture = 0.600
V_fixture_min = 0.571
V_fixture_max = 0.631
|  time   V(typ)   V(min)   V(max)
0s        328.1mV    325.8mV    341.8mV
351ps     328.3mV    325.9mV    344mV
444ps     330.9mV    325.9mV    566.7mV
488ps     378.1mV    326mV      640.1mV
665ps     659.3mV    330.9mV    781.6mV
845ps     772.9mV    569.6mV    841.3mV
955ps     804.8mV    668.7mV    862.1mV
1.315ns   849.9mV    783.3mV    896.7mV
2.64ns    879.1mV    832.8mV    927.1mV
10ns      889.2mV    843.9mV    937.2mV
[Falling Waveform]
R_fixture = 50.000
V_fixture = 0.600
V_fixture_min = 0.571
V_fixture_max = 0.631
|  time   V(typ)   V(min)   V(max)
0s        889.2mV    843.9mV    937.2mV
356ps     889.1mV    843.8mV    938.9mV
464ps     886.8mV    843.8mV    690mV
543ps     744.4mV    844mV      580.7mV
603ps     613.9mV    846.3mV    530.3mV
663ps     535.4mV    844.3mV    494.5mV
913ps     413.3mV    493.9mV    419.2mV
1.263ns   368.2mV    382mV      383mV
2.583ns   338.8mV    336.2mV    351.9mV
10ns      328.1mV    325.8mV    341.8mV
[Falling Waveform]
R_fixture = 50.000
V_fixture = 0.000
V_fixture_min = 0.000
V_fixture_max = 0.000
|  time   V(typ)   V(min)   V(max)
0s        450.5mV    432.2mV    470mV
356ps     450.5mV    432mV      474.7mV
458ps     455.7mV    432.1mV    220.5mV
488ps     416.9mV    431.8mV    181.9mV
578ps     207.6mV    435.6mV    117.9mV
653ps     128.6mV    441.7mV    89.02mV
854ps     59.89mV    147.4mV    50.44mV
1.133ns   30.98mV    56.03mV    29.47mV
2.437ns   7.761mV    15.3mV     6.751mV
10ns      33.76uV    7.521mV    -284.2uV
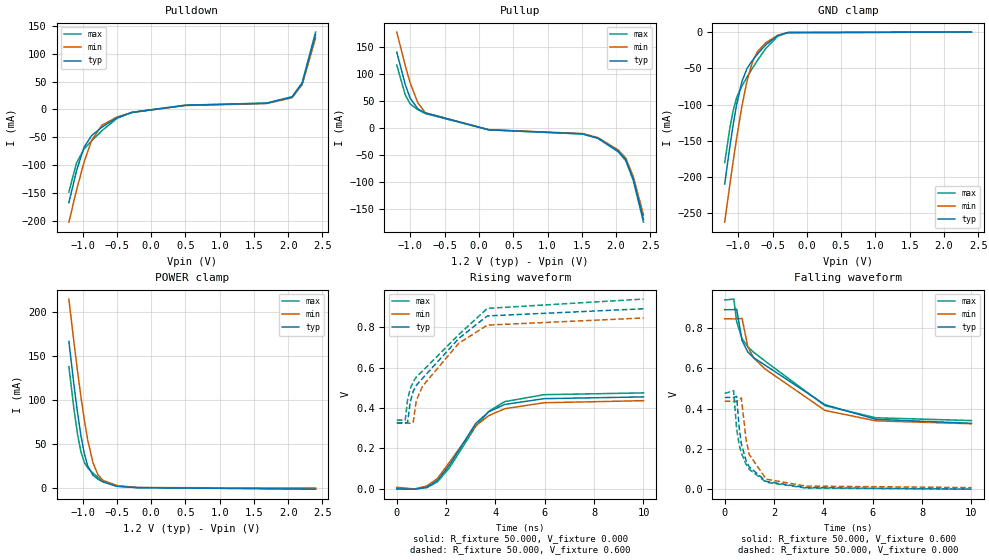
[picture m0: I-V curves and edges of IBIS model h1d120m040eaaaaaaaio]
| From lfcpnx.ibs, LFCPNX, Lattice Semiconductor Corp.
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[Model] h1d120m040eaaaaaaaio
Model_type I/O
Polarity   Non-Inverting
Enable   Active-Low
Vinl =  0.500V
Vinh =  0.700V
Vmeas =  0.600V
Cref =  20.000pF
Rref =  50.000
Vref =  0.600V
C_comp   5.000pF   4.000pF   5.500pF
[Temperature Range]   25.000   0.125k   -40.000
[Voltage Range]   1.200V   1.140V   1.260V
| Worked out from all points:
|   slope of the pulldown table from 0 to 0.18 V, typ, clamps not added: 55.6 ohm
|   slope of the pullup table from 0 to 0.18 V, typ, clamps not added: 47.4 ohm
|   GND clamp passes 1 mA (typ) near -0.31 V on its own axis
|   POWER clamp passes 1 mA (typ) near -0.43 V on its own axis
|   rising waveform, R_fixture 50.000, V_fixture 0.000: 20-80 % time 1.55ns typ, 1.65ns min, 1.61ns max; typ from 0 V to 0.455 V
|   rising waveform, R_fixture 50.000, V_fixture 0.600: 20-80 % time 2.18ns typ, 1.9ns min, 2.43ns max; typ from 0.327 V to 0.891 V
|   falling waveform, R_fixture 50.000, V_fixture 0.600: 20-80 % time 3.14ns typ, 2.57ns min, 2.92ns max; typ from 0.891 V to 0.327 V
|   falling waveform, R_fixture 50.000, V_fixture 0.000: 20-80 % time 556ps typ, 521ps min, 590ps max; typ from 0.455 V to 0 V
[Pulldown]
|Voltage   I(typ)   I(min)   I(max)
-1.2V     -167.5mA   -202.4mA   -148.2mA
-1.089V   -110.4mA   -145.3mA   -96.4mA
-978mV    -67.78mA   -94.4mA    -70.93mA
-867mV    -46.78mA   -55.35mA   -56.4mA
-719mV    -32.07mA   -28.48mA   -38.41mA
-497mV    -14.82mA   -13.68mA   -16.11mA
-275mV    -5.473mA   -5.396mA   -5.087mA
502mV     7.378mA    7.01mA     7.6mA
1.686V    11.02mA    10.47mA    11.35mA
2.056V    22.06mA    20.95mA    22.72mA
2.204V    46.46mA    44.13mA    47.85mA
2.4V      134.7mA    128mA      138.7mA
[Pullup]
|Voltage   I(typ)   I(min)   I(max)
-1.2V     141.2mA    178.5mA    117.3mA
-1.078V   81.8mA     116.6mA    62.3mA
-1.004V   55.44mA    83.9mA     44.71mA
-893mV    35.85mA    47.06mA    34.34mA
-782mV    28.21mA    28.53mA    26.98mA
143mV     -3.105mA   -2.95mA    -3.198mA
1.512V    -10.64mA   -10.1mA    -10.95mA
1.734V    -18.48mA   -17.55mA   -19.03mA
2.03V     -42.56mA   -40.43mA   -43.83mA
2.141V    -58.56mA   -55.63mA   -60.32mA
2.252V    -94.8mA    -90.1mA    -97.6mA
2.4V      -169.7mA   -161.2mA   -174.8mA
[GND_clamp]
|Voltage   I(typ)   I(min)   I(max)
-1.2V     -209.6mA   -262.4mA   -180.2mA
-1.125V   -158.2mA   -210.5mA   -132.7mA
-1.075V   -127mA     -177.3mA   -107.7mA
-1.025V   -99.59mA   -145.8mA   -90.14mA
-950mV    -68.44mA   -102.9mA   -74.64mA
-875mV    -50.37mA   -67.7mA    -62.38mA
-800mV    -39.61mA   -42.62mA   -50.65mA
-725mV    -30.63mA   -27.35mA   -39.46mA
-600mV    -17.53mA   -14.58mA   -22.59mA
-425mV    -4.657mA   -4.485mA   -5.636mA
-275mV    -627.9uA   -616.8uA   -678.4uA
2.4V      0A         0A         0A
[POWER_clamp]
|Voltage   I(typ)   I(min)   I(max)
-1.2V     166.3mA    214.4mA    137.7mA
-1.125V   116.5mA    164.9mA    89.12mA
-1.075V   86.21mA    133.5mA    61.64mA
-1.025V   59.86mA    104mA      41.12mA
-975mV    39.03mA    77.38mA    28.98mA
-925mV    24.95mA    54.44mA    22.72mA
-850mV    14.48mA    28.92mA    16.81mA
-775mV    9.774mA    14.73mA    11.95mA
-700mV    6.595mA    8.327mA    7.924mA
-500mV    1.71mA     2.674mA    1.891mA
-200mV    207.6uA    329.9uA    277.5uA
2.4V      -1.508mA   -253.4uA   -1.296mA
[Ramp]
| variable   typ   min   max
dV/dt_r   0.273/1.576n   0.257/1.700n   0.285/1.665n
dV/dt_f   0.261/3.062n   0.242/2.751n   0.272/3.005n
R_load = 50.000
[Rising Waveform]
R_fixture = 50.000
V_fixture = 0.000
V_fixture_min = 0.000
V_fixture_max = 0.000
|  time   V(typ)   V(min)   V(max)
0s        34.96uV    7.5mV      -291.8uV
724ps     -1.455mV   -359.9uV   -1.334mV
1.225ns   8.844mV    15.12mV    6.208mV
1.649ns   41.67mV    51.34mV    34.93mV
2.136ns   118.1mV    132mV      104.4mV
3.199ns   323.9mV    312.2mV    309.5mV
3.732ns   381.7mV    362.7mV    384mV
4.371ns   417.7mV    396.5mV    431.7mV
5.97ns    446.5mV    426.3mV    466.2mV
10ns      455.2mV    436.5mV    475mV
[Rising Waveform]
R_fixture = 50.000
V_fixture = 0.600
V_fixture_min = 0.571
V_fixture_max = 0.631
|  time   V(typ)   V(min)   V(max)
0s        326.9mV    324.7mV    340.5mV
343ps     327.2mV    324.8mV    340.4mV
436ps     327.9mV    324.8mV    439.8mV
546ps     429.5mV    324.4mV    496.1mV
665ps     482.1mV    329.1mV    530.1mV
795ps     512.8mV    438.7mV    554.3mV
1.046ns   547.2mV    508.8mV    583.4mV
2.515ns   744.8mV    720.8mV    763.9mV
3.671ns   856mV      810.4mV    893.3mV
10ns      891.3mV    845.8mV    939.4mV
[Falling Waveform]
R_fixture = 50.000
V_fixture = 0.600
V_fixture_min = 0.571
V_fixture_max = 0.631
|  time   V(typ)   V(min)   V(max)
0s        891.3mV    845.8mV    939.4mV
370ps     891.4mV    845.7mV    944.1mV
484ps     894.2mV    845.7mV    832.2mV
703ps     738.4mV    848.1mV    746.9mV
935ps     681.8mV    708mV      707mV
1.173ns   652.8mV    651.9mV    680mV
1.643ns   615.4mV    596.1mV    635.4mV
4.068ns   419.3mV    390.7mV    414.3mV
6.124ns   346.9mV    339.2mV    354.3mV
10ns      326.9mV    324.7mV    340.5mV
[Falling Waveform]
R_fixture = 50.000
V_fixture = 0.000
V_fixture_min = 0.000
V_fixture_max = 0.000
|  time   V(typ)   V(min)   V(max)
0s        455.2mV    436.5mV    475mV
362ps     455.4mV    436.2mV    489.1mV
482ps     460.9mV    436.1mV    299.5mV
591ps     300.4mV    443.6mV    218.2mV
673ps     225.6mV    453.4mV    180.1mV
863ps     142.7mV    249.2mV    123.7mV
993ps     110.8mV    172.3mV    98.57mV
1.683ns   38.27mV    49.54mV    33.83mV
3.281ns   7.47mV     15.06mV    5.584mV
10ns      34.96uV    7.5mV      -291.8uV
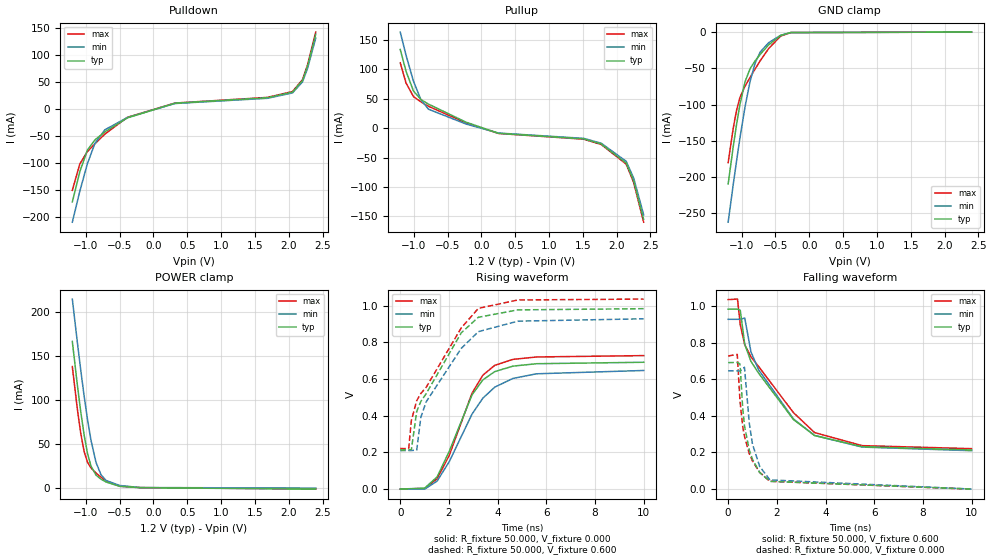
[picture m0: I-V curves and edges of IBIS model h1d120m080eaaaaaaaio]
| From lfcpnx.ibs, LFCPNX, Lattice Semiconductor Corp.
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[Model] h1d120m080eaaaaaaaio
Model_type I/O
Polarity   Non-Inverting
Enable   Active-Low
Vinl =  0.500V
Vinh =  0.700V
Vmeas =  0.600V
Cref =  20.000pF
Rref =  50.000
Vref =  0.600V
C_comp   5.000pF   4.000pF   5.500pF
[Temperature Range]   25.000   0.125k   -40.000
[Voltage Range]   1.200V   1.140V   1.260V
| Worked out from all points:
|   slope of the pulldown table from 0 to 0.18 V, typ, clamps not added: 27.3 ohm
|   slope of the pullup table from 0 to 0.18 V, typ, clamps not added: 27.4 ohm
|   GND clamp passes 1 mA (typ) near -0.31 V on its own axis
|   POWER clamp passes 1 mA (typ) near -0.43 V on its own axis
|   rising waveform, R_fixture 50.000, V_fixture 0.000: 20-80 % time 1.33ns typ, 1.61ns min, 1.29ns max; typ from 0 V to 0.691 V
|   rising waveform, R_fixture 50.000, V_fixture 0.600: 20-80 % time 1.82ns typ, 1.81ns min, 2.02ns max; typ from 0.214 V to 0.984 V
|   falling waveform, R_fixture 50.000, V_fixture 0.600: 20-80 % time 2.14ns typ, 2.02ns min, 2.37ns max; typ from 0.984 V to 0.214 V
|   falling waveform, R_fixture 50.000, V_fixture 0.000: 20-80 % time 536ps typ, 501ps min, 590ps max; typ from 0.691 V to 0 V
[Pulldown]
|Voltage   I(typ)   I(min)   I(max)
-1.2V     -172mA     -209.5mA   -150.5mA
-1.089V   -116mA     -152mA     -101.6mA
-978mV    -76.15mA   -101.5mA   -78.8mA
-867mV    -57.22mA   -63.79mA   -64.4mA
-719mV    -42.17mA   -38.34mA   -46.28mA
-386mV    -16.26mA   -15.56mA   -15.23mA
317mV     10.92mA    10.37mA    11.24mA
1.686V    21.08mA    20.03mA    21.71mA
2.056V    31.59mA    30.01mA    32.54mA
2.204V    53.04mA    50.39mA    54.63mA
2.278V    79.2mA     75.2mA     81.6mA
2.4V      138.5mA    131.6mA    142.7mA
[Pullup]
|Voltage   I(typ)   I(min)   I(max)
-1.2V     133.6mA    163.2mA    111mA
-1.115V   97mA       124.2mA    76.9mA
-1.004V   63.07mA    79.6mA     53.56mA
-893mV    48.5mA     47.96mA    44.6mA
-782mV    40.83mA    32.18mA    37.09mA
-227mV    10.19mA    7.046mA    8.911mA
254mV     -8.734mA   -8.298mA   -8.996mA
1.512V    -18.19mA   -17.28mA   -18.73mA
1.771V    -26.82mA   -25.48mA   -27.62mA
2.141V    -59.19mA   -56.23mA   -60.97mA
2.252V    -89.3mA    -84.8mA    -92mA
2.4V      -155mA     -147.2mA   -159.7mA
[GND_clamp]
|Voltage   I(typ)   I(min)   I(max)
-1.2V     -209.6mA   -262.4mA   -180.2mA
-1.125V   -158.2mA   -210.5mA   -132.7mA
-1.075V   -127mA     -177.3mA   -107.7mA
-1.025V   -99.59mA   -145.8mA   -90.14mA
-950mV    -68.44mA   -102.9mA   -74.64mA
-875mV    -50.37mA   -67.7mA    -62.38mA
-800mV    -39.61mA   -42.62mA   -50.65mA
-725mV    -30.63mA   -27.35mA   -39.46mA
-600mV    -17.53mA   -14.58mA   -22.59mA
-425mV    -4.657mA   -4.485mA   -5.636mA
-275mV    -627.9uA   -616.8uA   -678.4uA
2.4V      0A         0A         0A
[POWER_clamp]
|Voltage   I(typ)   I(min)   I(max)
-1.2V     166.3mA    214.4mA    137.7mA
-1.125V   116.5mA    164.9mA    89.12mA
-1.075V   86.21mA    133.5mA    61.64mA
-1.025V   59.86mA    104mA      41.12mA
-975mV    39.03mA    77.38mA    28.98mA
-925mV    24.95mA    54.44mA    22.72mA
-850mV    14.48mA    28.92mA    16.81mA
-775mV    9.774mA    14.73mA    11.95mA
-700mV    6.595mA    8.327mA    7.924mA
-500mV    1.71mA     2.674mA    1.891mA
-200mV    207.6uA    329.9uA    277.5uA
2.4V      -1.508mA   -253.4uA   -1.296mA
[Ramp]
| variable   typ   min   max
dV/dt_r   0.414/1.352n   0.383/1.676n   0.437/1.350n
dV/dt_f   0.437/2.309n   0.407/2.319n   0.461/2.482n
R_load = 50.000
[Rising Waveform]
R_fixture = 50.000
V_fixture = 0.000
V_fixture_min = 0.000
V_fixture_max = 0.000
|  time   V(typ)   V(min)   V(max)
0s        41.32uV    -87.13uV   -556.9uV
1.003ns   5.132mV    -174.6uV   3.755mV
1.513ns   65.86mV    43.06mV    55.56mV
2.016ns   206.6mV    150.1mV    184.9mV
2.949ns   513.8mV    408.8mV    522.9mV
3.391ns   594.7mV    495.1mV    620.6mV
3.88ns    640.4mV    555.5mV    674.5mV
4.628ns   670.2mV    603.2mV    707.1mV
5.6ns     683.5mV    628.5mV    720.3mV
10ns      691.4mV    646.6mV    727.7mV
[Rising Waveform]
R_fixture = 50.000
V_fixture = 0.600
V_fixture_min = 0.571
V_fixture_max = 0.631
|  time   V(typ)   V(min)   V(max)
0s        213.6mV    209.8mV    220.9mV
346ps     214mV      209.8mV    220.1mV
457ps     214.4mV    210mV      374.1mV
676ps     422.8mV    212.4mV    481.4mV
847ps     477.9mV    391.7mV    521.5mV
1.066ns   520.5mV    476mV      555.2mV
2.507ns   852mV      767.2mV    878.8mV
3.209ns   936.6mV    858.3mV    985.2mV
4.83ns    977mV      915.5mV    1.031V
10ns      983.6mV    928.4mV    1.036V
[Falling Waveform]
R_fixture = 50.000
V_fixture = 0.600
V_fixture_min = 0.571
V_fixture_max = 0.631
|  time   V(typ)   V(min)   V(max)
0s        983.6mV    928.4mV    1.036V
384ps     983.9mV    928.2mV    1.039V
498ps     978mV      928.1mV    898.4mV
681ps     792mV      935.6mV    789.3mV
938ps     697.8mV    749.6mV    722.7mV
1.25ns    634mV      652.5mV    670.4mV
2.683ns   380.2mV    383.5mV    417.9mV
3.551ns   292.9mV    292.9mV    308.8mV
5.506ns   231.6mV    229.6mV    237.5mV
10ns      213.6mV    209.8mV    220.9mV
[Falling Waveform]
R_fixture = 50.000
V_fixture = 0.000
V_fixture_min = 0.000
V_fixture_max = 0.000
|  time   V(typ)   V(min)   V(max)
0s        691.4mV    646.6mV    727.7mV
374ps     692.4mV    646.3mV    736.7mV
486ps     684.1mV    646mV      482.3mV
596ps     446.4mV    656.7mV    344.6mV
670ps     345.9mV    665.9mV    288.3mV
870ps     212.5mV    357.8mV    192.8mV
1ns       163mV      245.2mV    153.6mV
1.294ns   90.52mV    124.1mV    91.65mV
1.714ns   42.19mV    50.15mV    42.64mV
10ns      41.32uV    -87.13uV   -556.9uV
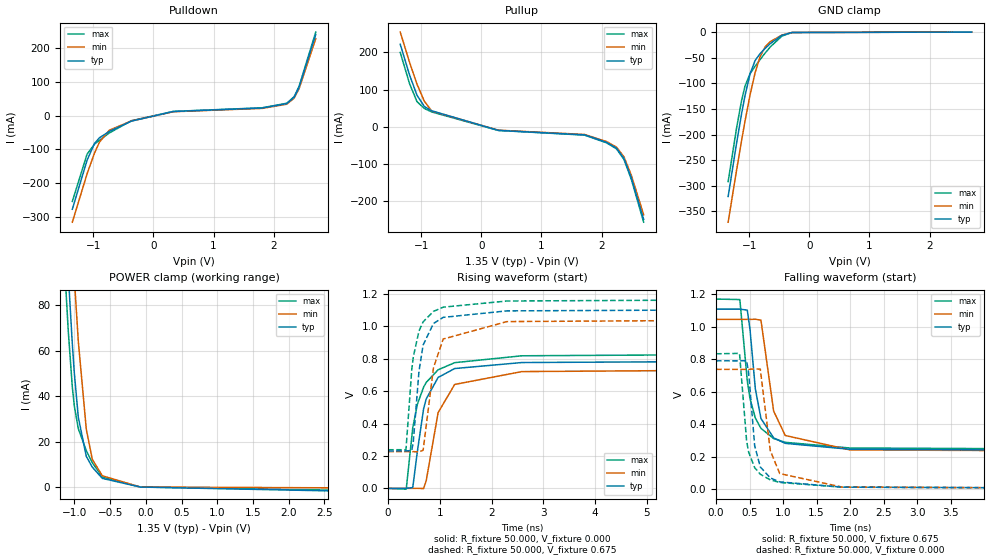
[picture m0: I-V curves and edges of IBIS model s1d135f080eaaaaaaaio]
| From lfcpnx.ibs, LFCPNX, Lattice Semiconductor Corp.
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[Model] s1d135f080eaaaaaaaio
Model_type I/O
Polarity   Non-Inverting
Enable   Active-Low
Vinl =  0.575V
Vinh =  0.775V
Vmeas =  0.675V
Cref =  30.000pF
Rref =  50.000
Vref =  0.675V
C_comp   5.000pF   4.000pF   5.500pF
[Temperature Range]   25.000   0.125k   -40.000
[Voltage Range]   1.350V   1.280V   1.420V
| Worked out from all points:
|   slope of the pulldown table from 0 to 0.203 V, typ, clamps not added: 25.7 ohm
|   slope of the pullup table from 0 to 0.203 V, typ, clamps not added: 27.3 ohm
|   GND clamp passes 1 mA (typ) near -0.31 V on its own axis
|   POWER clamp passes 1 mA (typ) near -0.43 V on its own axis
|   rising waveform, R_fixture 50.000, V_fixture 0.000: 20-80 % time 296ps typ, 349ps min, 353ps max; typ from 0 V to 0.789 V
|   rising waveform, R_fixture 50.000, V_fixture 0.675: 20-80 % time 203ps typ, 247ps min, 220ps max; typ from 0.231 V to 1.11 V
|   falling waveform, R_fixture 50.000, V_fixture 0.675: 20-80 % time 177ps typ, 194ps min, 200ps max; typ from 1.11 V to 0.231 V
|   falling waveform, R_fixture 50.000, V_fixture 0.000: 20-80 % time 134ps typ, 152ps min, 147ps max; typ from 0.789 V to 0 V
[Pulldown]
|Voltage   I(typ)   I(min)   I(max)
-1.35V    -277.3mA   -315.7mA   -254.1mA
-1.104V   -131.8mA   -172.2mA   -113.9mA
-981mV    -82.52mA   -110.9mA   -84.53mA
-899mV    -65.62mA   -78.8mA    -73.06mA
-735mV    -46.86mA   -43.22mA   -51.4mA
-366mV    -16.29mA   -15.7mA    -15.06mA
331mV     12.13mA    11.52mA    12.49mA
1.807V    22.48mA    21.36mA    23.16mA
2.217V    35.47mA    33.7mA     36.54mA
2.34V     54.25mA    51.54mA    55.88mA
2.422V    83.69mA    79.5mA     86.2mA
2.7V      240.2mA    228.2mA    247.4mA
[Pullup]
|Voltage   I(typ)   I(min)   I(max)
-1.35V    221.7mA    254.5mA    199.7mA
-1.195V   139mA      173.1mA    115.8mA
-1.072V   84.9mA     114.8mA    67.58mA
-949mV    54.29mA    68.56mA    49.07mA
-826mV    42.79mA    42.08mA    39.67mA
281mV     -9.779mA   -9.29mA    -10.07mA
1.716V    -21.92mA   -20.82mA   -22.58mA
2.085V    -42.19mA   -40.08mA   -43.46mA
2.249V    -57.97mA   -55.07mA   -59.71mA
2.372V    -85.3mA    -81mA      -87.9mA
2.495V    -137.5mA   -130.6mA   -141.6mA
2.7V      -249.3mA   -236.8mA   -256.8mA
[GND_clamp]
|Voltage   I(typ)   I(min)   I(max)
-1.35V    -320.9mA   -371mA     -291.7mA
-1.21V    -216.8mA   -269.5mA   -187.2mA
-1.126V   -159mA     -211.3mA   -133.3mA
-1.07V    -124.2mA   -174.2mA   -105.6mA
-986mV    -81.78mA   -122.8mA   -81.18mA
-902mV    -55.61mA   -79.36mA   -66.72mA
-818mV    -41.95mA   -47.73mA   -53.44mA
-734mV    -31.67mA   -28.77mA   -40.78mA
-650mV    -22.47mA   -18.69mA   -29.01mA
-454mV    -6.221mA   -5.753mA   -7.69mA
-286mV    -734.4uA   -759.2uA   -785.5uA
2.7V      0A         0A         0A
[POWER_clamp]
|Voltage   I(typ)   I(min)   I(max)
-1.35V    276.5mA    320.5mA    251mA
-1.142V   128.3mA    176.6mA    100.9mA
-1.114V   110.5mA    158.5mA    83.9mA
-1.086V   93.5mA     140.9mA    68.53mA
-1.03V    63.21mA    107.6mA    44.18mA
-1.002V   50.42mA    92.11mA    35.83mA
-946mV    30.82mA    64.28mA    25.76mA
-834mV    13.57mA    25.52mA    16.1mA
-750mV    8.839mA    12.31mA    10.8mA
-610mV    3.896mA    5.035mA    4.505mA
-78mV     75.17uA    92.3uA     98.29uA
2.7V      -1.695mA   -291.3uA   -1.333mA
[Ramp]
| variable   typ   min   max
dV/dt_r   0.473/0.296n   0.442/0.346n   0.499/0.355n
dV/dt_f   0.497/0.285n   0.462/0.289n   0.541/0.351n
R_load = 50.000
[Rising Waveform]
R_fixture = 50.000
V_fixture = 0.000
V_fixture_min = 0.000
V_fixture_max = 0.000
|  time   V(typ)   V(min)   V(max)
0s        16.67uV    -12.65uV   -188.5uV
351ps     401.5uV    12.77uV    -4.847mV
477ps     5.05mV     95.93uV    374.3mV
567ps     229.6mV    437.4uV    520.4mV
686ps     490.2mV    -996.2uV   624.7mV
737ps     552.4mV    47.09mV    654.3mV
967ps     684.9mV    467.7mV    732.2mV
1.287ns   740mV      641.8mV    776.3mV
2.587ns   777.1mV    721.2mV    818.8mV
10ns      789.2mV    736.8mV    832.4mV
[Rising Waveform]
R_fixture = 50.000
V_fixture = 0.675
V_fixture_min = 0.642
V_fixture_max = 0.710
|  time   V(typ)   V(min)   V(max)
0s        230.8mV    226.7mV    238.6mV
346ps     231mV      226.8mV    238.8mV
457ps     234.1mV    226.8mV    729.6mV
487ps     285.8mV    226.9mV    810.8mV
597ps     722.2mV    225mV      971.5mV
677ps     885mV      235.3mV    1.028V
877ps     1.018V     743.7mV    1.093V
1.065ns   1.056V     922.2mV    1.119V
2.298ns   1.096V     1.03V      1.157V
10ns      1.107V     1.044V     1.169V
[Falling Waveform]
R_fixture = 50.000
V_fixture = 0.675
V_fixture_min = 0.642
V_fixture_max = 0.710
|  time   V(typ)   V(min)   V(max)
0s        1.107V     1.044V     1.169V
356ps     1.107V     1.044V     1.166V
467ps     1.101V     1.044V     665mV
507ps     983.9mV    1.044V     557.4mV
587ps     616.4mV    1.045V     437.4mV
671ps     434.2mV    1.039V     373.7mV
860ps     315.3mV    480.1mV    311.2mV
1.033ns   281.5mV    329.9mV    287.9mV
1.997ns   245.2mV    241.3mV    253mV
10ns      230.8mV    226.7mV    238.6mV
[Falling Waveform]
R_fixture = 50.000
V_fixture = 0.000
V_fixture_min = 0.000
V_fixture_max = 0.000
|  time   V(typ)   V(min)   V(max)
0s        789.2mV    736.8mV    832.4mV
351ps     788.9mV    736.5mV    834.8mV
457ps     790mV      736.6mV    295.8mV
487ps     714.9mV    736.4mV    228.1mV
577ps     267.6mV    740mV      132.1mV
661ps     136.5mV    737.9mV    91.52mV
810ps     69.03mV    236.8mV    56.82mV
951ps     44.52mV    95.67mV    41.03mV
1.883ns   12.32mV    12.43mV    11.95mV
10ns      16.67uV    -12.65uV   -188.5uV
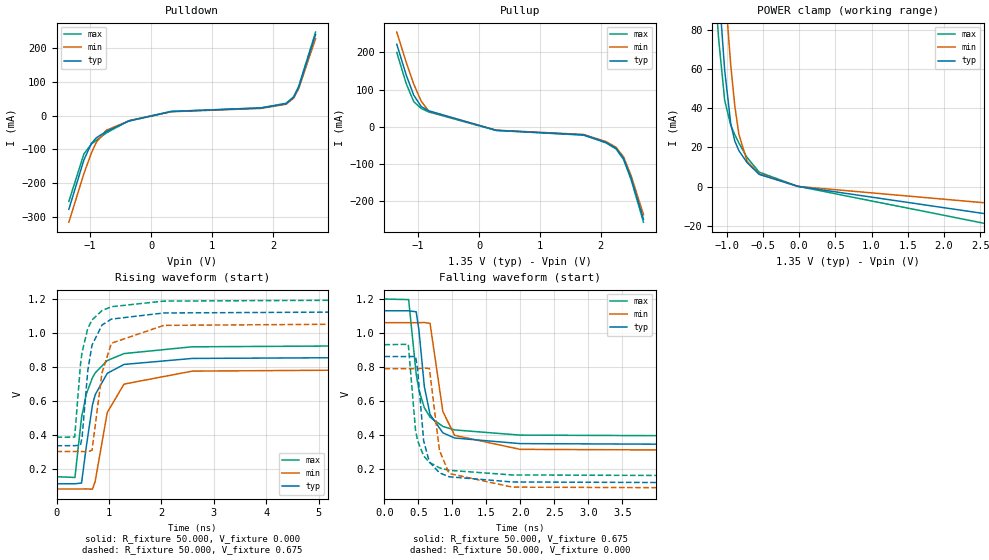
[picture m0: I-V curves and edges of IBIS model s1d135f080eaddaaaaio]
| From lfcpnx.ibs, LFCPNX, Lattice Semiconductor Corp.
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[Model] s1d135f080eaddaaaaio
Model_type I/O
Polarity   Non-Inverting
Enable   Active-Low
Vinl =  0.575V
Vinh =  0.775V
Vmeas =  0.675V
Cref =  30.000pF
Rref =  50.000
Vref =  0.675V
C_comp   5.000pF   4.000pF   5.500pF
[Temperature Range]   25.000   0.125k   -40.000
[Voltage Range]   1.350V   1.280V   1.420V
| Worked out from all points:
|   slope of the pulldown table from 0 to 0.203 V, typ, clamps not added: 25.7 ohm
|   slope of the pullup table from 0 to 0.203 V, typ, clamps not added: 27.3 ohm
|   POWER clamp passes 1 mA (typ) near -0.17 V on its own axis
|   rising waveform, R_fixture 50.000, V_fixture 0.000: 20-80 % time 296ps typ, 349ps min, 353ps max; typ from 0.111 V to 0.862 V
|   rising waveform, R_fixture 50.000, V_fixture 0.675: 20-80 % time 203ps typ, 247ps min, 220ps max; typ from 0.336 V to 1.13 V
|   falling waveform, R_fixture 50.000, V_fixture 0.675: 20-80 % time 177ps typ, 194ps min, 201ps max; typ from 1.13 V to 0.336 V
|   falling waveform, R_fixture 50.000, V_fixture 0.000: 20-80 % time 134ps typ, 152ps min, 147ps max; typ from 0.862 V to 0.111 V
[Pulldown]
|Voltage   I(typ)   I(min)   I(max)
-1.35V    -277.3mA   -315.7mA   -254.1mA
-1.104V   -131.8mA   -172.2mA   -113.9mA
-981mV    -82.52mA   -110.9mA   -84.53mA
-899mV    -65.62mA   -78.8mA    -73.06mA
-735mV    -46.86mA   -43.22mA   -51.4mA
-366mV    -16.29mA   -15.7mA    -15.06mA
331mV     12.13mA    11.52mA    12.49mA
1.807V    22.48mA    21.36mA    23.16mA
2.217V    35.47mA    33.7mA     36.54mA
2.34V     54.25mA    51.54mA    55.88mA
2.422V    83.69mA    79.5mA     86.2mA
2.7V      240.2mA    228.2mA    247.4mA
[Pullup]
|Voltage   I(typ)   I(min)   I(max)
-1.35V    221.7mA    254.5mA    199.7mA
-1.195V   139mA      173.1mA    115.8mA
-1.072V   84.9mA     114.8mA    67.58mA
-949mV    54.29mA    68.56mA    49.07mA
-826mV    42.79mA    42.08mA    39.67mA
281mV     -9.779mA   -9.29mA    -10.07mA
1.716V    -21.92mA   -20.82mA   -22.58mA
2.085V    -42.19mA   -40.08mA   -43.46mA
2.249V    -57.97mA   -55.07mA   -59.71mA
2.372V    -85.3mA    -81mA      -87.9mA
2.495V    -137.5mA   -130.6mA   -141.6mA
2.7V      -249.3mA   -236.8mA   -256.8mA
[POWER_clamp]
|Voltage   I(typ)   I(min)   I(max)
-1.35V    264.6mA    312.3mA    234.2mA
-1.17V    138mA      188.5mA    107.5mA
-1.142V   120.1mA    170.4mA    90.88mA
-1.114V   103.1mA    152.7mA    75.88mA
-1.03V    59.59mA    103.2mA    44.19mA
-946mV    32.22mA    62.05mA    31.33mA
-890mV    23.29mA    41.28mA    26.5mA
-834mV    18.42mA    26.8mA     22.3mA
-722mV    12.33mA    13.1mA     15mA
-554mV    6.226mA    6.542mA    7.404mA
-22mV     128.8uA    103.1uA    167.9uA
2.7V      -14.6mA    -8.747mA   -19.86mA
[Ramp]
| variable   typ   min   max
dV/dt_r   0.450/0.296n   0.426/0.346n   0.467/0.355n
dV/dt_f   0.432/0.285n   0.420/0.289n   0.430/0.351n
R_load = 50.000
[Rising Waveform]
R_fixture = 50.000
V_fixture = 0.000
V_fixture_min = 0.000
V_fixture_max = 0.000
|  time   V(typ)   V(min)   V(max)
0s        111.4mV    80.78mV    153.2mV
351ps     111.7mV    80.81mV    148.8mV
477ps     116.1mV    80.89mV    503.1mV
567ps     329.6mV    81.21mV    639.7mV
686ps     577.4mV    79.83mV    737.3mV
737ps     636.5mV    126.2mV    764.8mV
967ps     762.5mV    531.3mV    837.7mV
1.287ns   814.9mV    699mV      878.9mV
2.587ns   850.1mV    775.4mV    918.7mV
10ns      861.6mV    790.5mV    931.4mV
[Rising Waveform]
R_fixture = 50.000
V_fixture = 0.675
V_fixture_min = 0.642
V_fixture_max = 0.710
|  time   V(typ)   V(min)   V(max)
0s        335.9mV    301.6mV    386.3mV
346ps     336.1mV    301.7mV    386.6mV
457ps     338.9mV    301.7mV    815.9mV
487ps     385.8mV    301.8mV    887mV
597ps     781.4mV    300mV      1.028V
677ps     929mV      309.6mV    1.077V
867ps     1.047V     765.2mV    1.132V
1.047ns   1.082V     939.8mV    1.155V
2.045ns   1.118V     1.045V     1.188V
10ns      1.131V     1.061V     1.2V
[Falling Waveform]
R_fixture = 50.000
V_fixture = 0.675
V_fixture_min = 0.642
V_fixture_max = 0.710
|  time   V(typ)   V(min)   V(max)
0s        1.131V     1.061V     1.2V
356ps     1.131V     1.061V     1.197V
467ps     1.125V     1.061V     759.4mV
507ps     1.019V     1.061V     665.3mV
587ps     685.5mV    1.062V     560.3mV
671ps     520.3mV    1.057V     504.6mV
860ps     412.5mV    537.1mV    449.9mV
1.033ns   381.9mV    397.6mV    429.5mV
1.997ns   349mV      315.2mV    399mV
10ns      335.9mV    301.6mV    386.3mV
[Falling Waveform]
R_fixture = 50.000
V_fixture = 0.000
V_fixture_min = 0.000
V_fixture_max = 0.000
|  time   V(typ)   V(min)   V(max)
0s        861.6mV    790.5mV    931.4mV
351ps     861.4mV    790.3mV    933.6mV
457ps     862.4mV    790.3mV    429.8mV
487ps     791mV      790.1mV    366.5mV
577ps     365.8mV    793.6mV    276.8mV
661ps     241.1mV    791.6mV    238.9mV
810ps     177mV      308.9mV    206.5mV
951ps     153.7mV    173mV      191.7mV
1.883ns   123.1mV    92.76mV    164.5mV
10ns      111.4mV    80.78mV    153.2mV
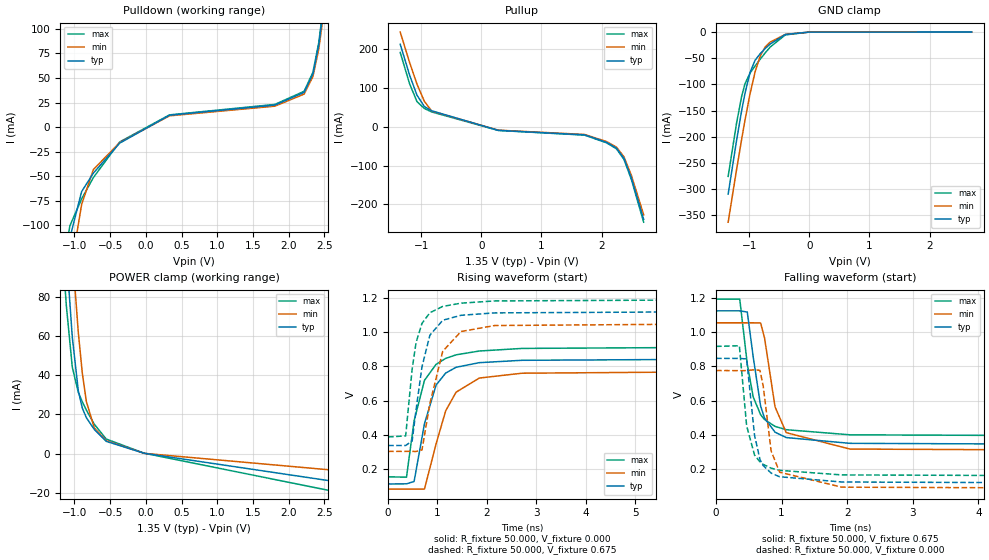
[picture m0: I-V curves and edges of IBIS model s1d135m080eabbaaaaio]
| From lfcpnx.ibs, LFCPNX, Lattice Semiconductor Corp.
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|Model s1d135m080eabbaaaaio
[Model] s1d135m080eabbaaaaio
Model_type I/O
Polarity   Non-Inverting
Enable   Active-Low
Vinl =  0.575V
Vinh =  0.775V
Vmeas =  0.675V
Cref =  30.000pF
Rref =  50.000
Vref =  0.675V
C_comp   5.000pF   4.000pF   5.500pF
[Temperature Range]   25.000   0.125k   -40.000
[Voltage Range]   1.350V   1.280V   1.420V
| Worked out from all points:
|   slope of the pulldown table from 0 to 0.203 V, typ, clamps not added: 25.7 ohm
|   slope of the pullup table from 0 to 0.203 V, typ, clamps not added: 28.6 ohm
|   GND clamp passes 1 mA (typ) near -0.15 V on its own axis
|   POWER clamp passes 1 mA (typ) near -0.17 V on its own axis
|   rising waveform, R_fixture 50.000, V_fixture 0.000: 20-80 % time 372ps typ, 469ps min, 375ps max; typ from 0.112 V to 0.847 V
|   rising waveform, R_fixture 50.000, V_fixture 0.675: 20-80 % time 282ps typ, 359ps min, 247ps max; typ from 0.336 V to 1.12 V
|   falling waveform, R_fixture 50.000, V_fixture 0.675: 20-80 % time 206ps typ, 235ps min, 218ps max; typ from 1.12 V to 0.336 V
|   falling waveform, R_fixture 50.000, V_fixture 0.000: 20-80 % time 150ps typ, 172ps min, 158ps max; typ from 0.847 V to 0.112 V
[Pulldown]
|Voltage   I(typ)   I(min)   I(max)
-1.35V    -276.8mA   -315.1mA   -253.5mA
-1.186V   -176.1mA   -217.7mA   -152.5mA
-1.063V   -112.3mA   -150.2mA   -100.2mA
-899mV    -65.48mA   -78.63mA   -72.91mA
-735mV    -46.76mA   -43.13mA   -51.29mA
-366mV    -16.25mA   -15.67mA   -15.03mA
331mV     12.1mA     11.5mA     12.46mA
1.807V    22.43mA    21.31mA    23.1mA
2.217V    35.4mA     33.63mA    36.46mA
2.34V     54.13mA    51.43mA    55.76mA
2.422V    83.51mA    79.33mA    86.01mA
2.7V      239.7mA    227.7mA    246.9mA
[Pullup]
|Voltage   I(typ)   I(min)   I(max)
-1.35V    212.2mA    243.6mA    191mA
-1.195V   133.1mA    165.7mA    110.8mA
-1.072V   81.3mA     109.8mA    64.67mA
-949mV    51.95mA    65.61mA    46.96mA
-826mV    40.94mA    40.27mA    37.96mA
281mV     -9.358mA   -8.89mA    -9.639mA
1.716V    -20.98mA   -19.93mA   -21.61mA
2.085V    -40.37mA   -38.35mA   -41.58mA
2.249V    -55.47mA   -52.7mA    -57.14mA
2.372V    -81.6mA    -77.5mA    -84mA
2.495V    -131.6mA   -125mA     -135.5mA
2.7V      -238.6mA   -226.7mA   -245.8mA
[GND_clamp]
|Voltage   I(typ)   I(min)   I(max)
-1.35V    -309.8mA   -363.4mA   -275.8mA
-1.21V    -207.1mA   -262.8mA   -173.9mA
-1.126V   -150.5mA   -205.1mA   -123.2mA
-1.07V    -117mA     -168.5mA   -98.8mA
-986mV    -77.25mA   -118.1mA   -78.4mA
-902mV    -53.89mA   -76.04mA   -64.81mA
-818mV    -41.42mA   -46.02mA   -52mA
-734mV    -31.56mA   -28.41mA   -39.82mA
-650mV    -22.69mA   -19.03mA   -28.57mA
-398mV    -4.585mA   -4.332mA   -5.35mA
-6mV      -40.55uA   -29.87uA   -52.89uA
2.7V      0A         0A         0A
[POWER_clamp]
|Voltage   I(typ)   I(min)   I(max)
-1.35V    264.6mA    312.3mA    234.2mA
-1.17V    138mA      188.5mA    107.5mA
-1.142V   120.1mA    170.4mA    90.88mA
-1.114V   103.1mA    152.7mA    75.88mA
-1.03V    59.59mA    103.2mA    44.19mA
-946mV    32.22mA    62.05mA    31.33mA
-890mV    23.29mA    41.28mA    26.5mA
-834mV    18.42mA    26.8mA     22.3mA
-722mV    12.33mA    13.1mA     15mA
-554mV    6.226mA    6.542mA    7.404mA
-22mV     128.8uA    103.1uA    167.9uA
2.7V      -14.6mA    -8.747mA   -19.86mA
[Ramp]
| variable   typ   min   max
dV/dt_r   0.441/0.378n   0.417/0.470n   0.458/0.381n
dV/dt_f   0.431/0.328n   0.419/0.353n   0.430/0.374n
R_load = 50.000
[Rising Waveform]
R_fixture = 50.000
V_fixture = 0.000
V_fixture_min = 0.000
V_fixture_max = 0.000
|  time   V(typ)   V(min)   V(max)
0s        111.5mV    80.89mV    153.4mV
373ps     112.1mV    80.91mV    150.9mV
527ps     126mV      81.26mV    481mV
737ps     464.2mV    81.56mV    718.2mV
972ps     690.5mV    346mV      811.9mV
1.166ns   760.8mV    539.7mV    846.6mV
1.377ns   794.6mV    648.8mV    867.4mV
1.847ns   821.6mV    731.5mV    889.8mV
2.71ns    835.4mV    759.8mV    905mV
10ns      846.7mV    775.4mV    916.8mV
[Rising Waveform]
R_fixture = 50.000
V_fixture = 0.675
V_fixture_min = 0.642
V_fixture_max = 0.710
|  time   V(typ)   V(min)   V(max)
0s        336.4mV    302.1mV    386.9mV
356ps     336.6mV    302.1mV    392.6mV
487ps     362.7mV    302.2mV    783mV
567ps     546.7mV    301.5mV    939.8mV
687ps     798.2mV    310.9mV    1.052V
847ps     982.5mV    583.4mV    1.114V
1.107ns   1.07V      888.6mV    1.151V
1.477ns   1.099V     1.004V     1.17V
2.157ns   1.113V     1.039V     1.183V
10ns      1.125V     1.055V     1.194V
[Falling Waveform]
R_fixture = 50.000
V_fixture = 0.675
V_fixture_min = 0.642
V_fixture_max = 0.710
|  time   V(typ)   V(min)   V(max)
0s        1.125V     1.055V     1.194V
362ps     1.125V     1.055V     1.194V
477ps     1.118V     1.055V     813.2mV
567ps     855.7mV    1.055V     620.9mV
680ps     567.4mV    1.054V     516.9mV
740ps     496.7mV    966.4mV    488.6mV
900ps     414.6mV    562.8mV    448.4mV
1.07ns    383mV      411.9mV    429.1mV
2.04ns    349.3mV    315.7mV    399.2mV
10ns      336.4mV    302.1mV    386.9mV
[Falling Waveform]
R_fixture = 50.000
V_fixture = 0.000
V_fixture_min = 0.000
V_fixture_max = 0.000
|  time   V(typ)   V(min)   V(max)
0s        846.7mV    775.4mV    916.8mV
356ps     846.5mV    775.2mV    920.6mV
467ps     843.4mV    775.2mV    452mV
587ps     397.5mV    780.4mV    281.2mV
670ps     254.7mV    776.4mV    240.9mV
720ps     218.7mV    683.8mV    226mV
840ps     175mV      305mV      204mV
970ps     153.6mV    180.1mV    191mV
1.917ns   122.8mV    92.57mV    164.3mV
10ns      111.5mV    80.89mV    153.4mV
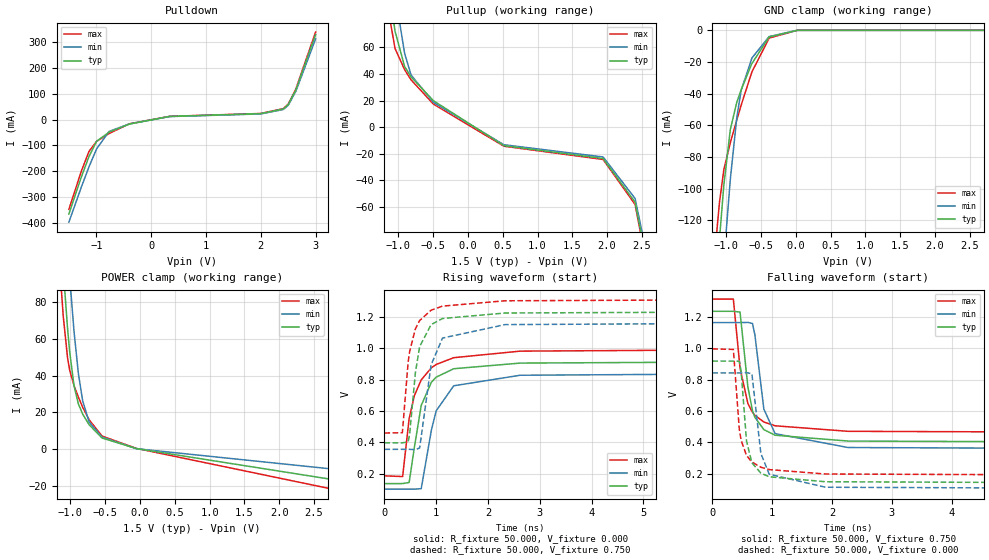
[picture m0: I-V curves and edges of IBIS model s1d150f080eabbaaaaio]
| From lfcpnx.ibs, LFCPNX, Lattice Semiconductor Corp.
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[Model] s1d150f080eabbaaaaio
Model_type I/O
Polarity   Non-Inverting
Enable   Active-Low
Vinl =  0.650V
Vinh =  0.850V
Vmeas =  0.750V
Cref =  30.000pF
Rref =  50.000
Vref =  0.750V
C_comp   5.000pF   4.000pF   5.500pF
[Temperature Range]   25.000   0.125k   -40.000
[Voltage Range]   1.500V   1.430V   1.580V
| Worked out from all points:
|   slope of the pulldown table from 0 to 0.225 V, typ, clamps not added: 26.6 ohm
|   slope of the pullup table from 0 to 0.225 V, typ, clamps not added: 31.3 ohm
|   GND clamp passes 1 mA (typ) near -0.15 V on its own axis
|   POWER clamp passes 1 mA (typ) near -0.17 V on its own axis
|   rising waveform, R_fixture 50.000, V_fixture 0.000: 20-80 % time 310ps typ, 333ps min, 377ps max; typ from 0.137 V to 0.919 V
|   rising waveform, R_fixture 50.000, V_fixture 0.750: 20-80 % time 216ps typ, 245ps min, 234ps max; typ from 0.397 V to 1.24 V
|   falling waveform, R_fixture 50.000, V_fixture 0.750: 20-80 % time 189ps typ, 202ps min, 215ps max; typ from 1.24 V to 0.397 V
|   falling waveform, R_fixture 50.000, V_fixture 0.000: 20-80 % time 135ps typ, 149ps min, 147ps max; typ from 0.919 V to 0.137 V
[Pulldown]
|Voltage   I(typ)   I(min)   I(max)
-1.5V     -365.1mA   -396.5mA   -347.3mA
-1.27V    -220.7mA   -259.6mA   -197.7mA
-1.132V   -142.4mA   -182mA     -122.7mA
-994mV    -84mA      -113.3mA   -84.4mA
-764mV    -48.51mA   -45.68mA   -53.79mA
-396mV    -17.54mA   -16.85mA   -16.47mA
340mV     12.05mA    11.45mA    12.41mA
1.996V    22.61mA    21.48mA    23.29mA
2.41V     40.75mA    38.71mA    41.97mA
2.502V    58.04mA    55.14mA    59.78mA
2.64V     114.5mA    108.8mA    117.9mA
3V        327.9mA    311.5mA    337.7mA
[Pullup]
|Voltage   I(typ)   I(min)   I(max)
-1.5V     294.3mA    322.7mA    276.4mA
-1.186V   127.8mA    161.3mA    106.4mA
-1.14V    106.9mA    139.7mA    86.7mA
-1.048V   72.18mA    100.1mA    59.18mA
-910mV    45.57mA    55.51mA    43.21mA
-818mV    37.83mA    39.27mA    35.6mA
-496mV    19.88mA    18.61mA    17.33mA
516mV     -13.92mA   -13.23mA   -14.34mA
1.942V    -23.61mA   -22.43mA   -24.32mA
2.402V    -56.47mA   -53.65mA   -58.17mA
2.586V    -105.6mA   -100.3mA   -108.8mA
3V        -323.4mA   -307.2mA   -333.1mA
[GND_clamp]
|Voltage   I(typ)   I(min)   I(max)
-1.5V     -423.6mA   -473.4mA   -391.3mA
-1.159V   -170.8mA   -226.4mA   -140.1mA
-1.128V   -150.6mA   -205.4mA   -123mA
-1.097V   -131.5mA   -185mA     -108.4mA
-1.035V   -97.76mA   -145.9mA   -88.03mA
-942mV    -62.68mA   -94.08mA   -70.99mA
-849mV    -45.44mA   -55.18mA   -56.59mA
-787mV    -37.67mA   -38mA      -47.37mA
-632mV    -20.99mA   -17.55mA   -26.32mA
-384mV    -4.202mA   -3.933mA   -4.89mA
19mV      0A         0A         0A
3V        0A         0A         0A
[POWER_clamp]
|Voltage   I(typ)   I(min)   I(max)
-1.5V     377.8mA    420.9mA    350.6mA
-1.166V   135.9mA    186.4mA    106mA
-1.104V   98.02mA    147mA      72.63mA
-1.042V   66.02mA    110.5mA    49.91mA
-1.011V   53.08mA    93.78mA    43.04mA
-949mV    34.63mA    64.31mA    34.62mA
-887mV    24.77mA    41.57mA    28.48mA
-825mV    19.16mA    26.4mA     22.89mA
-732mV    13.32mA    14.81mA    16.07mA
-546mV    6.068mA    6.58mA     7.125mA
-50mV     295.8uA    241.2uA    397.5uA
3V        -17.94mA   -11.75mA   -23.63mA
[Ramp]
| variable   typ   min   max
dV/dt_r   0.469/0.312n   0.445/0.337n   0.486/0.377n
dV/dt_f   0.439/0.334n   0.434/0.332n   0.432/0.414n
R_load = 50.000
[Rising Waveform]
R_fixture = 50.000
V_fixture = 0.000
V_fixture_min = 0.000
V_fixture_max = 0.000
|  time   V(typ)   V(min)   V(max)
0s        137.1mV    101.8mV    186.9mV
351ps     137.5mV    101.8mV    182.4mV
477ps     144.5mV    101.9mV    552.3mV
578ps     369.6mV    102mV      698.4mV
710ps     635.8mV    105mV      799.3mV
907ps     784.5mV    479.6mV    876.4mV
1ns       816.9mV    602.5mV    897.8mV
1.338ns   870.4mV    761.5mV    940.9mV
2.62ns    906.4mV    828.8mV    982.7mV
10ns      919.1mV    843.7mV    997.1mV
[Rising Waveform]
R_fixture = 50.000
V_fixture = 0.750
V_fixture_min = 0.713
V_fixture_max = 0.789
|  time   V(typ)   V(min)   V(max)
0s        397.5mV    355.8mV    460.3mV
346ps     397.6mV    355.8mV    461.9mV
457ps     403.4mV    355.9mV    910mV
487ps     453.6mV    355.9mV    980.8mV
597ps     844.1mV    354.2mV    1.124V
680ps     1.012V     364.7mV    1.178V
901ps     1.152V     895mV      1.244V
1.121ns   1.191V     1.066V     1.27V
2.328ns   1.226V     1.152V     1.304V
10ns      1.237V     1.165V     1.315V
[Falling Waveform]
R_fixture = 50.000
V_fixture = 0.750
V_fixture_min = 0.713
V_fixture_max = 0.789
|  time   V(typ)   V(min)   V(max)
0s        1.237V     1.165V     1.315V
351ps     1.237V     1.165V     1.315V
463ps     1.232V     1.165V     873.8mV
594ps     753.7mV    1.166V     648mV
671ps     602.9mV    1.159V     592.4mV
711ps     560.5mV    1.087V     573.2mV
861ps     481.9mV    612.8mV    530.5mV
1.049ns   446mV      456.2mV    506.3mV
2.269ns   408.8mV    367.5mV    471mV
10ns      397.5mV    355.8mV    460.3mV
[Falling Waveform]
R_fixture = 50.000
V_fixture = 0.000
V_fixture_min = 0.000
V_fixture_max = 0.000
|  time   V(typ)   V(min)   V(max)
0s        919.1mV    843.7mV    997.1mV
351ps     918.9mV    843.6mV    993.5mV
451ps     918mV      843.7mV    482.1mV
481ps     852.8mV    843.5mV    413.7mV
571ps     410.1mV    845.6mV    317.3mV
661ps     270mV      838.6mV    274.9mV
811ps     204.3mV    328.9mV    241.7mV
951ps     180.7mV    197mV      226.7mV
1.891ns   149.2mV    114.1mV    198.6mV
10ns      137.1mV    101.8mV    186.9mV
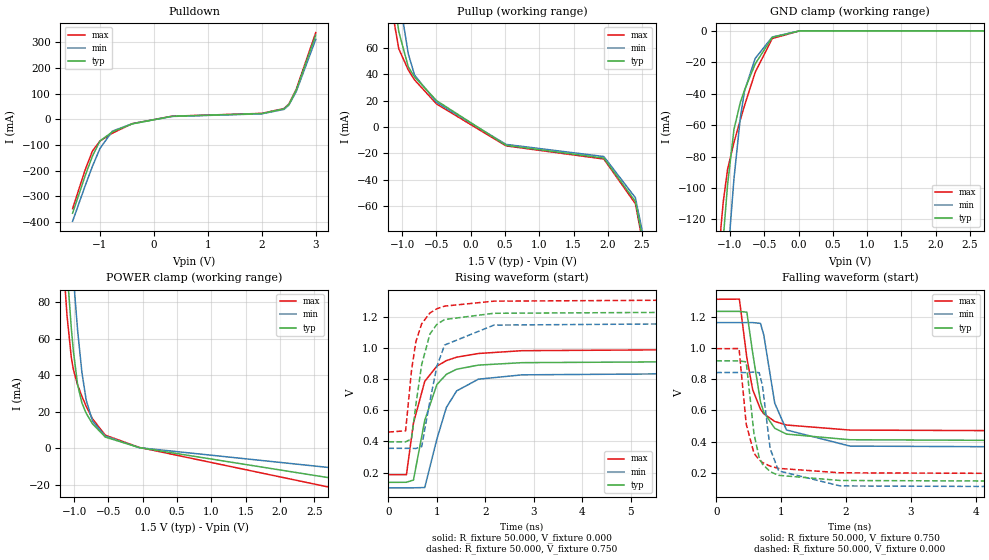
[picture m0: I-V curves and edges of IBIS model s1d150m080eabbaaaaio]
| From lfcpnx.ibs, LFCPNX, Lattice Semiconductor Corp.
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[Model] s1d150m080eabbaaaaio
Model_type I/O
Polarity   Non-Inverting
Enable   Active-Low
Vinl =  0.650V
Vinh =  0.850V
Vmeas =  0.750V
Cref =  30.000pF
Rref =  50.000
Vref =  0.750V
C_comp   5.000pF   4.000pF   5.500pF
[Temperature Range]   25.000   0.125k   -40.000
[Voltage Range]   1.500V   1.430V   1.580V
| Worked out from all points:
|   slope of the pulldown table from 0 to 0.225 V, typ, clamps not added: 26.6 ohm
|   slope of the pullup table from 0 to 0.225 V, typ, clamps not added: 31.3 ohm
|   GND clamp passes 1 mA (typ) near -0.15 V on its own axis
|   POWER clamp passes 1 mA (typ) near -0.17 V on its own axis
|   rising waveform, R_fixture 50.000, V_fixture 0.000: 20-80 % time 383ps typ, 445ps min, 399ps max; typ from 0.137 V to 0.919 V
|   rising waveform, R_fixture 50.000, V_fixture 0.750: 20-80 % time 290ps typ, 355ps min, 260ps max; typ from 0.397 V to 1.24 V
|   falling waveform, R_fixture 50.000, V_fixture 0.750: 20-80 % time 220ps typ, 248ps min, 235ps max; typ from 1.24 V to 0.397 V
|   falling waveform, R_fixture 50.000, V_fixture 0.000: 20-80 % time 153ps typ, 173ps min, 159ps max; typ from 0.919 V to 0.137 V
[Pulldown]
|Voltage   I(typ)   I(min)   I(max)
-1.5V     -365.1mA   -396.5mA   -347.3mA
-1.27V    -220.7mA   -259.6mA   -197.7mA
-1.132V   -142.4mA   -182mA     -122.7mA
-994mV    -84mA      -113.3mA   -84.4mA
-764mV    -48.51mA   -45.68mA   -53.79mA
-396mV    -17.54mA   -16.85mA   -16.47mA
340mV     12.05mA    11.45mA    12.41mA
1.996V    22.61mA    21.48mA    23.29mA
2.41V     40.75mA    38.71mA    41.97mA
2.502V    58.04mA    55.14mA    59.78mA
2.64V     114.5mA    108.8mA    117.9mA
3V        327.9mA    311.5mA    337.7mA
[Pullup]
|Voltage   I(typ)   I(min)   I(max)
-1.5V     294.3mA    322.7mA    276.4mA
-1.186V   127.8mA    161.3mA    106.4mA
-1.14V    106.9mA    139.7mA    86.7mA
-1.048V   72.18mA    100.1mA    59.18mA
-910mV    45.57mA    55.51mA    43.21mA
-818mV    37.83mA    39.27mA    35.6mA
-496mV    19.88mA    18.61mA    17.33mA
516mV     -13.92mA   -13.23mA   -14.34mA
1.942V    -23.61mA   -22.43mA   -24.32mA
2.402V    -56.47mA   -53.65mA   -58.17mA
2.586V    -105.6mA   -100.3mA   -108.8mA
3V        -323.4mA   -307.2mA   -333.1mA
[GND_clamp]
|Voltage   I(typ)   I(min)   I(max)
-1.5V     -423.6mA   -473.4mA   -391.3mA
-1.159V   -170.8mA   -226.4mA   -140.1mA
-1.128V   -150.6mA   -205.4mA   -123mA
-1.097V   -131.5mA   -185mA     -108.4mA
-1.035V   -97.76mA   -145.9mA   -88.03mA
-942mV    -62.68mA   -94.08mA   -70.99mA
-849mV    -45.44mA   -55.18mA   -56.59mA
-787mV    -37.67mA   -38mA      -47.37mA
-632mV    -20.99mA   -17.55mA   -26.32mA
-384mV    -4.202mA   -3.933mA   -4.89mA
19mV      0A         0A         0A
3V        0A         0A         0A
[POWER_clamp]
|Voltage   I(typ)   I(min)   I(max)
-1.5V     377.8mA    420.9mA    350.6mA
-1.166V   135.9mA    186.4mA    106mA
-1.104V   98.02mA    147mA      72.63mA
-1.042V   66.02mA    110.5mA    49.91mA
-1.011V   53.08mA    93.78mA    43.04mA
-949mV    34.63mA    64.31mA    34.62mA
-887mV    24.77mA    41.57mA    28.48mA
-825mV    19.16mA    26.4mA     22.89mA
-732mV    13.32mA    14.81mA    16.07mA
-546mV    6.068mA    6.58mA     7.125mA
-50mV     295.8uA    241.2uA    397.5uA
3V        -17.94mA   -11.75mA   -23.63mA
[Ramp]
| variable   typ   min   max
dV/dt_r   0.469/0.391n   0.445/0.443n   0.486/0.398n
dV/dt_f   0.439/0.375n   0.434/0.402n   0.432/0.438n
R_load = 50.000
[Rising Waveform]
R_fixture = 50.000
V_fixture = 0.000
V_fixture_min = 0.000
V_fixture_max = 0.000
|  time   V(typ)   V(min)   V(max)
0s        137.1mV    101.8mV    186.9mV
373ps     137.7mV    101.8mV    186.6mV
518ps     152.1mV    102.1mV    518.4mV
751ps     535.5mV    103.8mV    786.7mV
1.001ns   765.6mV    415mV      884.5mV
1.198ns   832mV      619.3mV    919.9mV
1.41ns    864.4mV    725.1mV    941.8mV
1.858ns   890.9mV    800.3mV    965.5mV
2.76ns    906.6mV    828.3mV    983.6mV
10ns      919.1mV    843.7mV    997.1mV
[Rising Waveform]
R_fixture = 50.000
V_fixture = 0.750
V_fixture_min = 0.713
V_fixture_max = 0.789
|  time   V(typ)   V(min)   V(max)
0s        397.5mV    355.8mV    460.3mV
356ps     397.6mV    355.8mV    468.6mV
478ps     417.3mV    355.9mV    857.9mV
568ps     637.3mV    355mV      1.042V
688ps     894.8mV    367mV      1.157V
858ps     1.091V     661.7mV    1.226V
1.001ns   1.153V     882.9mV    1.253V
1.161ns   1.184V     1.02V      1.27V
2.178ns   1.224V     1.148V     1.302V
10ns      1.237V     1.165V     1.315V
[Falling Waveform]
R_fixture = 50.000
V_fixture = 0.750
V_fixture_min = 0.713
V_fixture_max = 0.789
|  time   V(typ)   V(min)   V(max)
0s        1.237V     1.165V     1.315V
356ps     1.237V     1.165V     1.316V
471ps     1.232V     1.165V     938.5mV
561ps     969.6mV    1.165V     733.6mV
681ps     656.5mV    1.16V      607mV
732ps     587.9mV    1.085V     578.8mV
901ps     484.9mV    646.2mV    529mV
1.082ns   447.7mV    474.2mV    506.1mV
2.061ns   411.3mV    370.5mV    473.6mV
10ns      397.5mV    355.8mV    460.3mV
[Falling Waveform]
R_fixture = 50.000
V_fixture = 0.000
V_fixture_min = 0.000
V_fixture_max = 0.000
|  time   V(typ)   V(min)   V(max)
0s        919.1mV    843.7mV    997.1mV
351ps     918.9mV    843.6mV    998mV
461ps     912.2mV    843.6mV    512.9mV
581ps     450.1mV    846.9mV    324.6mV
661ps     296mV      842.5mV    281.8mV
711ps     254.9mV    760.8mV    265.4mV
831ps     206mV      352.5mV    241.3mV
961ps     182.4mV    211mV      227.2mV
1.91ns    149.2mV    114.2mV    198.6mV
10ns      137.1mV    101.8mV    186.9mV
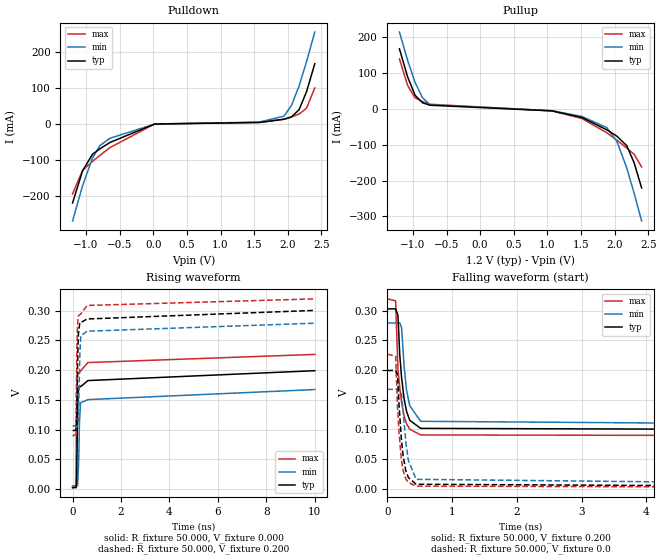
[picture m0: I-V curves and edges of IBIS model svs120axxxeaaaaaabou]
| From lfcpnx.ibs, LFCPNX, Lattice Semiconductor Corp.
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|Model svs120axxxeaaaaaabou
[Model] svs120axxxeaaaaaabou
Model_type Output
Polarity   Non-Inverting
Enable   Active-High
Vmeas =  0.200V
Cref =  3.000pF
Rref =  50.000
Vref =  0.200V
C_comp   5.000pF   4.000pF   5.500pF
[Temperature Range]   25.000   0.125k   -40.000
[Voltage Range]   1.200V   1.140V   1.260V
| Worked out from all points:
|   slope of the pulldown table from 0 to 0.18 V, typ, clamps not added: 57.4 ohm
|   slope of the pullup table from 0 to 0.18 V, typ, clamps not added: 88.6 kohm
|   rising waveform, R_fixture 50.000, V_fixture 0.000: 20-80 % time 51.1ps typ, 61.7ps min, 44.4ps max; typ from 0.003 V to 0.199 V
|   rising waveform, R_fixture 50.000, V_fixture 0.200: 20-80 % time 58.1ps typ, 63.9ps min, 52.5ps max; typ from 0.099 V to 0.301 V
|   falling waveform, R_fixture 50.000, V_fixture 0.200: 20-80 % time 102ps typ, 105ps min, 93.1ps max; typ from 0.303 V to 0.098 V
|   falling waveform, R_fixture 50.000, V_fixture 0.0: 20-80 % time 90.3ps typ, 105ps min, 77.4ps max; typ from 0.199 V to 0.002 V
[Pulldown]
|Voltage   I(typ)   I(min)   I(max)
-1.2V     -219.9mA   -270.1mA   -194.6mA
-1.052V   -130.4mA   -172.2mA   -128.9mA
-904mV    -83.86mA   -94.42mA   -103.8mA
-793mV    -68.69mA   -59.73mA   -86.93mA
-645mV    -51.05mA   -39.33mA   -65.36mA
21mV      442.1uA    232.5uA    626.3uA
1.575V    4.768mA    5.81mA     4.837mA
1.945V    13.86mA    22.66mA    13.8mA
2.056V    20.43mA    53.27mA    20.19mA
2.167V    40.51mA    106.9mA    28.21mA
2.278V    90.69mA    174.6mA    44.6mA
2.4V      168.5mA    257mA      101mA
[Pullup]
|Voltage   I(typ)   I(min)   I(max)
-1.2V     167.4mA    214.4mA    139.4mA
-1.078V   89.03mA    135.2mA    65.07mA
-967mV    37.88mA    73.46mA    30.68mA
-856mV    16.93mA    30.67mA    20.25mA
-745mV    10.2mA     11.76mA    12.96mA
1.068V    -5.578mA   -5.057mA   -5.564mA
1.512V    -23.95mA   -21.07mA   -26.87mA
1.882V    -58.41mA   -52.2mA    -66.53mA
2.03V     -75.85mA   -89.8mA    -87.11mA
2.178V    -102.5mA   -164.3mA   -109.1mA
2.289V    -150.7mA   -235.5mA   -126.9mA
2.4V      -220.6mA   -312.8mA   -162.1mA
[Ramp]
| variable   typ   min   max
dV/dt_r   0.116/51.114p   95.821m/61.675p   0.133/44.661p
dV/dt_f   0.120/31.082p   0.121/0.104n   0.136/25.085p
R_load = 50.000
[Rising Waveform]
R_fixture = 50.000
V_fixture = 0.000
V_fixture_min = 0.000
V_fixture_max = 0.000
|  time   V(typ)   V(min)   V(max)
0s        2.65mV     5.421mV    2.208mV
135ps     2.598mV    5.413mV    6.249mV
144ps     2.525mV    5.423mV    28.03mV
168ps     13.79mV    5.461mV    138.6mV
208ps     131.1mV    5.673mV    191.5mV
249ps     170.7mV    42.36mV    195.6mV
286ps     173.8mV    113.1mV    196.2mV
329ps     172.2mV    145.2mV    198.7mV
635ps     182.6mV    150.6mV    212.9mV
10ns      199.2mV    167.5mV    226.6mV
[Rising Waveform]
R_fixture = 50.000
V_fixture = 0.200
V_fixture_min = 0.191
V_fixture_max = 0.211
|  time   V(typ)   V(min)   V(max)
0s        98.67mV    106.5mV    89.54mV
138ps     98.72mV    106.5mV    92.21mV
179ps     123.6mV    106.5mV    237.2mV
202ps     198.8mV    106.4mV    271.8mV
225ps     242.1mV    108.8mV    286.5mV
247ps     264.1mV    127.7mV    291.6mV
302ps     280.5mV    227.7mV    293.5mV
340ps     280.2mV    258.1mV    294.7mV
602ps     286.2mV    265.6mV    308.9mV
10ns      300.6mV    279.1mV    320mV
[Falling Waveform]
R_fixture= 50.000
V_fixture= 0.200
V_fixture_min= 0.191
V_fixture_max= 0.211
|time   V(typ)   V(min)   V(max)
0s        302.7mV    278.9mV    319.6mV
128ps     302.8mV    278.9mV    316.3mV
164ps     292mV      279mV      201mV
191ps     227.2mV    279.3mV    170.9mV
220ps     186.8mV    271.2mV    145.6mV
261ps     150.2mV    203.5mV    121.7mV
296ps     130.7mV    166.6mV    109.7mV
346ps     115.3mV    139.9mV    100.3mV
514ps     101.7mV    113.6mV    90.64mV
10ns      98.47mV    106.1mV    88.84mV
[Falling Waveform]
R_fixture= 50.000
V_fixture= 0.0
V_fixture_min= 0.0
V_fixture_max= 0.0
|time   V(typ)   V(min)   V(max)
0s        199mV      167.4mV    226.5mV
128ps     199.2mV    167.4mV    223.1mV
158ps     192.3mV    167.4mV    136.8mV
181ps     140.6mV    167.7mV    93.98mV
217ps     83.36mV    161.9mV    49.53mV
244ps     55.26mV    129.6mV    31.19mV
285ps     30.81mV    79.23mV    16.91mV
325ps     18.96mV    47.6mV     10.63mV
445ps     7.665mV    15.98mV    4.528mV
10ns      2.182mV    5.074mV    1.619mV
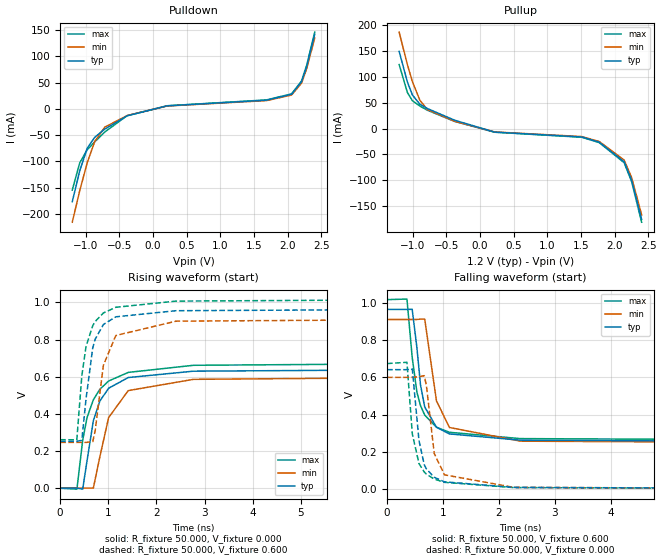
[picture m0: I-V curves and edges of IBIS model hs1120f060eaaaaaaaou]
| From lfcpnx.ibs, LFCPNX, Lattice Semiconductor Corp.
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[Model] hs1120f060eaaaaaaaou
Model_type Output
Polarity   Non-Inverting
Enable   Active-High
Vmeas =  0.600V
Cref =  20.000pF
Rref =  50.000
Vref =  0.600V
C_comp   5.000pF   4.000pF   5.500pF
[Temperature Range]   25.000   0.125k   -40.000
[Voltage Range]   1.200V   1.140V   1.260V
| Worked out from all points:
|   slope of the pulldown table from 0 to 0.18 V, typ, clamps not added: 35.1 ohm
|   slope of the pullup table from 0 to 0.18 V, typ, clamps not added: 30.6 ohm
|   rising waveform, R_fixture 50.000, V_fixture 0.000: 20-80 % time 376ps typ, 418ps min, 434ps max; typ from 0 V to 0.642 V
|   rising waveform, R_fixture 50.000, V_fixture 0.600: 20-80 % time 250ps typ, 286ps min, 267ps max; typ from 0.252 V to 0.966 V
|   falling waveform, R_fixture 50.000, V_fixture 0.600: 20-80 % time 216ps typ, 241ps min, 239ps max; typ from 0.966 V to 0.252 V
|   falling waveform, R_fixture 50.000, V_fixture 0.000: 20-80 % time 168ps typ, 190ps min, 180ps max; typ from 0.642 V to 0 V
[Pulldown]
|Voltage   I(typ)   I(min)   I(max)
-1.2V     -176.8mA   -216mA     -154.7mA
-1.089V   -117.8mA   -155.8mA   -102.7mA
-978mV    -74.86mA   -102.5mA   -77.86mA
-867mV    -54.12mA   -62.29mA   -62.9mA
-719mV    -38.65mA   -34.84mA   -44.2mA
-386mV    -13.21mA   -12.68mA   -12.84mA
206mV     5.817mA    5.526mA    5.991mA
1.686V    16.69mA    15.86mA    17.19mA
2.056V    27.9mA     26.51mA    28.74mA
2.204V    51.75mA    49.16mA    53.3mA
2.278V    79.92mA    75.92mA    82.32mA
2.4V      142.2mA    135.1mA    146.5mA
[Pullup]
|Voltage   I(typ)   I(min)   I(max)
-1.2V     148.6mA    185.8mA    123.2mA
-1.078V   89.8mA     123.3mA    69.62mA
-1.004V   64.82mA    90.6mA     53.68mA
-893mV    46.86mA    54.62mA    43.4mA
-782mV    38.6mA     36.64mA    35.35mA
-375mV    15.99mA    14.1mA     13.66mA
217mV     -6.872mA   -6.529mA   -7.078mA
1.512V    -16.26mA   -15.45mA   -16.75mA
1.771V    -26.34mA   -25.03mA   -27.13mA
2.141V    -63.95mA   -60.75mA   -65.87mA
2.252V    -99.5mA    -94.5mA    -102.5mA
2.4V      -175.1mA   -166.3mA   -180.4mA
[Ramp]
| variable   typ   min   max
dV/dt_r   0.385/0.380n   0.360/0.415n   0.416/0.443n
dV/dt_f   0.378/0.342n   0.353/0.352n   0.398/0.399n
R_load = 50.000
[Rising Waveform]
R_fixture = 50.000
V_fixture = 0.000
V_fixture_min = 0.000
V_fixture_max = 0.000
|  time   V(typ)   V(min)   V(max)
0s        38.01uV    -68.44uV   -338.6uV
348ps     446.8uV    -36.73uV   -5.283mV
468ps     -5.148mV   -7.08uV    257.7mV
558ps     146.9mV    419.4uV    379.8mV
689ps     362.5mV    294.3uV    475.5mV
825ps     469.1mV    169.3mV    532.5mV
1.007ns   538.1mV    380.3mV    577mV
1.415ns   595.7mV    525.3mV    623.3mV
2.77ns    629.8mV    585.9mV    661.5mV
10ns      641.8mV    600.5mV    674.5mV
[Rising Waveform]
R_fixture = 50.000
V_fixture = 0.600
V_fixture_min = 0.571
V_fixture_max = 0.631
|  time   V(typ)   V(min)   V(max)
0s        251.8mV    246.4mV    261mV
346ps     252.1mV    246.5mV    260.3mV
450ps     258.1mV    246.5mV    604.1mV
538ps     481.4mV    246.5mV    763.6mV
677ps     755.2mV    250.3mV    874.6mV
727ps     801.6mV    309mV      897mV
898ps     881.1mV    661.8mV    943.2mV
1.157ns   922.5mV    822mV      973.8mV
2.407ns   955.3mV    899mV      1.007V
10ns      965.5mV    911.3mV    1.018V
[Falling Waveform]
R_fixture = 50.000
V_fixture = 0.600
V_fixture_min = 0.571
V_fixture_max = 0.631
|  time   V(typ)   V(min)   V(max)
0s        965.5mV    911.3mV    1.018V
356ps     965.3mV    911.2mV    1.021V
450ps     965.9mV    911.3mV    707.8mV
534ps     759.8mV    911.3mV    520.6mV
598ps     560.8mV    913.5mV    448.9mV
674ps     441mV      913.2mV    397.6mV
884ps     332.3mV    473.8mV    332.4mV
1.115ns   296.5mV    331.1mV    305.3mV
2.384ns   262.8mV    257.6mV    271.3mV
10ns      251.8mV    246.4mV    261mV
[Falling Waveform]
R_fixture = 50.000
V_fixture = 0.000
V_fixture_min = 0.000
V_fixture_max = 0.000
|  time   V(typ)   V(min)   V(max)
0s        641.8mV    600.5mV    674.5mV
356ps     641.6mV    600.3mV    681.2mV
452ps     645.2mV    600.4mV    296.6mV
571ps     261.2mV    603.7mV    137.1mV
665ps     131.7mV    609.5mV    92.33mV
704ps     108.4mV    556.4mV    80.49mV
844ps     63.55mV    191.2mV    53.71mV
1.027ns   38.9mV     76.65mV    36.38mV
2.267ns   9.245mV    9.343mV    8.133mV
10ns      38.01uV    -68.44uV   -338.6uV
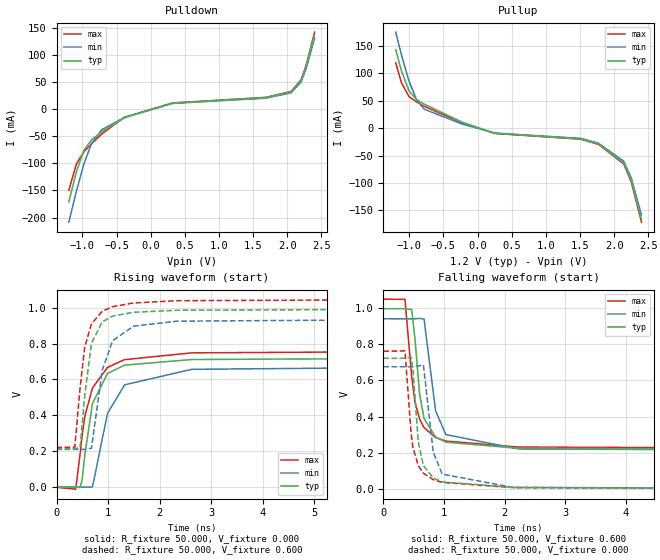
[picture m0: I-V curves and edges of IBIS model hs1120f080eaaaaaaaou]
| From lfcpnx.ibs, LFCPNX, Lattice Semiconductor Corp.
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[Model] hs1120f080eaaaaaaaou
Model_type Output
Polarity   Non-Inverting
Enable   Active-High
Vmeas =  0.600V
Cref =  20.000pF
Rref =  50.000
Vref =  0.600V
C_comp   5.000pF   4.000pF   5.500pF
[Temperature Range]   25.000   0.125k   -40.000
[Voltage Range]   1.200V   1.140V   1.260V
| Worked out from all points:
|   slope of the pulldown table from 0 to 0.18 V, typ, clamps not added: 27.4 ohm
|   slope of the pullup table from 0 to 0.18 V, typ, clamps not added: 25.5 ohm
|   rising waveform, R_fixture 50.000, V_fixture 0.000: 20-80 % time 298ps typ, 419ps min, 351ps max; typ from 0 V to 0.722 V
|   rising waveform, R_fixture 50.000, V_fixture 0.600: 20-80 % time 202ps typ, 289ps min, 226ps max; typ from 0.214 V to 0.995 V
|   falling waveform, R_fixture 50.000, V_fixture 0.600: 20-80 % time 171ps typ, 190ps min, 188ps max; typ from 0.995 V to 0.214 V
|   falling waveform, R_fixture 50.000, V_fixture 0.000: 20-80 % time 137ps typ, 156ps min, 148ps max; typ from 0.722 V to 0 V
[Pulldown]
|Voltage   I(typ)   I(min)   I(max)
-1.2V     -171mA     -208.4mA   -149.8mA
-1.089V   -115.3mA   -151.3mA   -101.1mA
-978mV    -75.7mA    -101mA     -78.43mA
-867mV    -56.88mA   -63.48mA   -64.1mA
-719mV    -41.92mA   -38.16mA   -46.06mA
-386mV    -16.16mA   -15.49mA   -15.15mA
317mV     10.85mA    10.31mA    11.18mA
1.686V    20.95mA    19.91mA    21.58mA
2.056V    31.4mA     29.83mA    32.34mA
2.204V    52.73mA    50.09mA    54.31mA
2.278V    78.8mA     74.9mA     81.2mA
2.4V      137.6mA    130.7mA    141.7mA
[Pullup]
|Voltage   I(typ)   I(min)   I(max)
-1.2V     143.8mA    175.7mA    119.5mA
-1.115V   104.4mA    133.7mA    82.8mA
-1.004V   67.92mA    85.7mA     57.67mA
-893mV    52.22mA    51.65mA    48.03mA
-782mV    43.96mA    34.65mA    39.94mA
-227mV    10.98mA    7.588mA    9.596mA
254mV     -9.406mA   -8.935mA   -9.688mA
1.512V    -19.59mA   -18.61mA   -20.17mA
1.771V    -28.88mA   -27.43mA   -29.74mA
2.141V    -63.74mA   -60.55mA   -65.65mA
2.252V    -96.2mA    -91.4mA    -99.1mA
2.4V      -166.9mA   -158.6mA   -171.9mA
[Ramp]
| variable   typ   min   max
dV/dt_r   0.433/0.301n   0.405/0.423n   0.456/0.357n
dV/dt_f   0.437/0.249n   0.409/0.265n   0.461/0.295n
R_load = 50.000
[Rising Waveform]
R_fixture = 50.000
V_fixture = 0.000
V_fixture_min = 0.000
V_fixture_max = 0.000
|  time   V(typ)   V(min)   V(max)
0s        40.32uV    -81.06uV   -549.4uV
371ps     705.5uV    -70.99uV   -10.95mV
457ps     -1.74mV    -42uV      185.4mV
497ps     43.63mV    115.3uV    291.5mV
554ps     191mV      508.7uV    401.6mV
697ps     466.4mV    1.405mV    552.3mV
987ps     633.2mV    409.8mV    667.2mV
1.317ns   680mV      570mV      710.4mV
2.62ns    711.2mV    656.6mV    748.4mV
10ns      721.6mV    674.9mV    760.1mV
[Rising Waveform]
R_fixture = 50.000
V_fixture = 0.600
V_fixture_min = 0.571
V_fixture_max = 0.631
|  time   V(typ)   V(min)   V(max)
0s        214.5mV    210.7mV    221.8mV
354ps     214.8mV    210.7mV    223.1mV
457ps     220.4mV    210.8mV    555.9mV
547ps     511.6mV    210.6mV    779.6mV
677ps     802.2mV    216.9mV    909.4mV
886ps     920.7mV    651.5mV    980.4mV
1.087ns   953.3mV    816.4mV    1.006V
1.496ns   974.3mV    897.4mV    1.026V
2.337ns   985.6mV    924.9mV    1.039V
10ns      994.7mV    939.2mV    1.048V
[Falling Waveform]
R_fixture = 50.000
V_fixture = 0.600
V_fixture_min = 0.571
V_fixture_max = 0.631
|  time   V(typ)   V(min)   V(max)
0s        994.7mV    939.2mV    1.048V
356ps     994.6mV    939mV      1.046V
467ps     990.4mV    939.1mV    619.4mV
520ps     831.6mV    938.9mV    482mV
598ps     521.7mV    941.5mV    385.7mV
671ps     389mV      937.5mV    339.1mV
860ps     287.2mV    432.9mV    284.8mV
1.03ns    258.7mV    300.7mV    264.8mV
2.23ns    224.8mV    221.1mV    231.8mV
10ns      214.5mV    210.7mV    221.8mV
[Falling Waveform]
R_fixture = 50.000
V_fixture = 0.000
V_fixture_min = 0.000
V_fixture_max = 0.000
|  time   V(typ)   V(min)   V(max)
0s        721.6mV    674.9mV    760.1mV
356ps     721.5mV    674.7mV    762mV
456ps     728.3mV    674.8mV    311.9mV
486ps     663.9mV    674.4mV    231.4mV
576ps     259.8mV    679.2mV    128.1mV
660ps     128.9mV    685.5mV    87.57mV
822ps     61.44mV    203.8mV    51.62mV
970ps     39.3mV     82.15mV    36.64mV
2.142ns   9.116mV    9.038mV    8.143mV
10ns      40.32uV    -81.06uV   -549.4uV
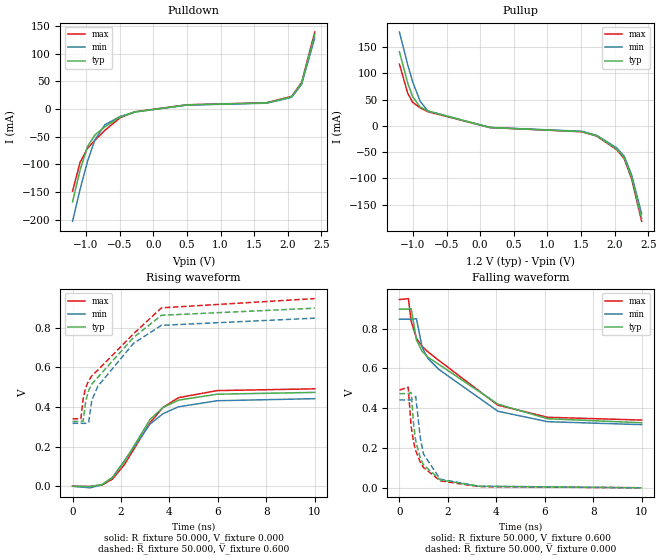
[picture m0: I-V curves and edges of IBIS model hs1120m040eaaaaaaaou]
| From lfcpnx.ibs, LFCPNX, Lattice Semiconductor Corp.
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[Model] hs1120m040eaaaaaaaou
Model_type Output
Polarity   Non-Inverting
Enable   Active-High
Vmeas =  0.600V
Cref =  20.000pF
Rref =  50.000
Vref =  0.600V
C_comp   5.000pF   4.000pF   5.500pF
[Temperature Range]   25.000   0.125k   -40.000
[Voltage Range]   1.200V   1.140V   1.260V
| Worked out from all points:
|   slope of the pulldown table from 0 to 0.18 V, typ, clamps not added: 55.6 ohm
|   slope of the pullup table from 0 to 0.18 V, typ, clamps not added: 45.6 ohm
|   rising waveform, R_fixture 50.000, V_fixture 0.000: 20-80 % time 1.55ns typ, 1.65ns min, 1.61ns max; typ from 0 V to 0.473 V
|   rising waveform, R_fixture 50.000, V_fixture 0.600: 20-80 % time 2.18ns typ, 1.9ns min, 2.43ns max; typ from 0.327 V to 0.898 V
|   falling waveform, R_fixture 50.000, V_fixture 0.600: 20-80 % time 3.14ns typ, 2.57ns min, 2.92ns max; typ from 0.898 V to 0.327 V
|   falling waveform, R_fixture 50.000, V_fixture 0.000: 20-80 % time 556ps typ, 521ps min, 590ps max; typ from 0.473 V to 0 V
[Pulldown]
|Voltage   I(typ)   I(min)   I(max)
-1.2V     -167.5mA   -202.4mA   -148.2mA
-1.089V   -110.4mA   -145.3mA   -96.4mA
-978mV    -67.78mA   -94.4mA    -70.93mA
-867mV    -46.78mA   -55.35mA   -56.4mA
-719mV    -32.07mA   -28.48mA   -38.41mA
-497mV    -14.82mA   -13.68mA   -16.11mA
-275mV    -5.473mA   -5.396mA   -5.087mA
502mV     7.378mA    7.01mA     7.6mA
1.686V    11.02mA    10.47mA    11.35mA
2.056V    22.06mA    20.95mA    22.72mA
2.204V    46.46mA    44.13mA    47.85mA
2.4V      134.7mA    128mA      138.7mA
[Pullup]
|Voltage   I(typ)   I(min)   I(max)
-1.2V     141.2mA    178.5mA    117.3mA
-1.078V   81.8mA     116.6mA    62.3mA
-1.004V   55.44mA    83.9mA     44.71mA
-893mV    35.85mA    47.06mA    34.34mA
-782mV    28.21mA    28.53mA    26.98mA
143mV     -3.229mA   -3.068mA   -3.326mA
1.512V    -11.06mA   -10.51mA   -11.39mA
1.734V    -19.21mA   -18.25mA   -19.79mA
2.03V     -44.26mA   -42.05mA   -45.59mA
2.141V    -60.9mA    -57.86mA   -62.73mA
2.252V    -98.6mA    -93.7mA    -101.6mA
2.4V      -176.5mA   -167.7mA   -181.8mA
[Ramp]
| variable   typ   min   max
dV/dt_r   0.282/1.576n   0.265/1.700n   0.300/1.665n
dV/dt_f   0.262/3.062n   0.246/2.751n   0.274/3.005n
R_load = 50.000
[Rising Waveform]
R_fixture = 50.000
V_fixture = 0.000
V_fixture_min = 0.000
V_fixture_max = 0.000
|  time   V(typ)   V(min)   V(max)
0s        34.96uV    37.11uV    -291.8uV
724ps     -1.513mV   -8.051mV   -1.329mV
1.225ns   9.198mV    7.885mV    6.435mV
1.649ns   43.34mV    45.19mV    36.16mV
2.136ns   122.8mV    128.2mV    108mV
3.199ns   336.8mV    313.8mV    320.3mV
3.732ns   397mV      365.8mV    397.3mV
4.371ns   434.4mV    400.6mV    446.7mV
5.97ns    464.3mV    431.3mV    482.4mV
10ns      473.4mV    441.8mV    491.4mV
[Rising Waveform]
R_fixture = 50.000
V_fixture = 0.600
V_fixture_min = 0.571
V_fixture_max = 0.631
|  time   V(typ)   V(min)   V(max)
0s        326.9mV    317.5mV    340.5mV
343ps     327.2mV    317.6mV    340.4mV
436ps     327.9mV    317.6mV    441mV
546ps     430.7mV    317.2mV    498mV
665ps     484mV      322mV      532.4mV
795ps     515.1mV    433.6mV    556.9mV
1.046ns   549.9mV    504.9mV    586.3mV
2.515ns   749.9mV    720.6mV    768.9mV
3.671ns   862.4mV    811.7mV    899.9mV
10ns      898.1mV    847.8mV    946.5mV
[Falling Waveform]
R_fixture = 50.000
V_fixture = 0.600
V_fixture_min = 0.571
V_fixture_max = 0.631
|  time   V(typ)   V(min)   V(max)
0s        898.1mV    847.8mV    946.5mV
370ps     898.2mV    847.6mV    951.3mV
484ps     901.1mV    847.6mV    838mV
703ps     743.4mV    850.1mV    751.7mV
935ps     686.1mV    707.6mV    711.4mV
1.173ns   656.8mV    650.4mV    684mV
1.643ns   618.9mV    593.7mV    638.9mV
4.068ns   420.4mV    384.7mV    415.2mV
6.124ns   347.1mV    332.3mV    354.5mV
10ns      326.9mV    317.5mV    340.5mV
[Falling Waveform]
R_fixture = 50.000
V_fixture = 0.000
V_fixture_min = 0.000
V_fixture_max = 0.000
|  time   V(typ)   V(min)   V(max)
0s        473.4mV    441.8mV    491.4mV
362ps     473.6mV    441.5mV    506.1mV
482ps     479.4mV    441.4mV    309.9mV
591ps     312.4mV    449.1mV    225.8mV
673ps     234.6mV    459.2mV    186.4mV
863ps     148.4mV    249mV      128.1mV
993ps     115.3mV    169.8mV    102mV
1.683ns   39.8mV     43.34mV    35.01mV
3.281ns   7.769mV    7.824mV    5.789mV
10ns      34.96uV    37.11uV    -291.8uV
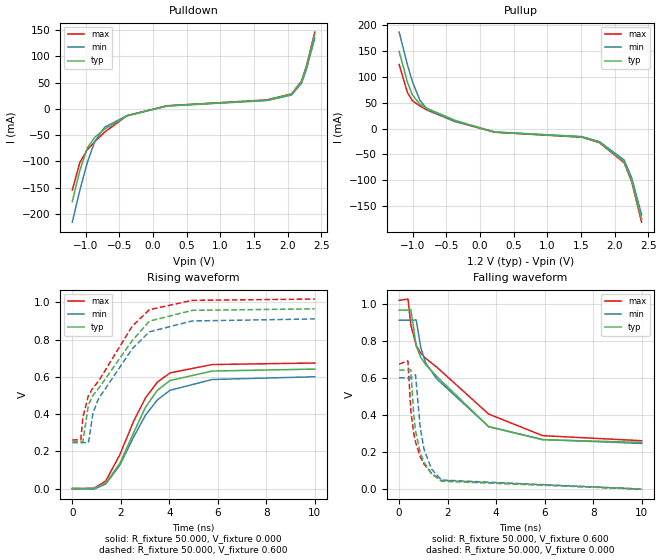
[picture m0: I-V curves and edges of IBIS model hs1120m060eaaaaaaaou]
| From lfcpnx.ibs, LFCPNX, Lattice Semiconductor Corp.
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[Model] hs1120m060eaaaaaaaou
Model_type Output
Polarity   Non-Inverting
Enable   Active-High
Vmeas =  0.600V
Cref =  20.000pF
Rref =  50.000
Vref =  0.600V
C_comp   5.000pF   4.000pF   5.500pF
[Temperature Range]   25.000   0.125k   -40.000
[Voltage Range]   1.200V   1.140V   1.260V
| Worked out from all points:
|   slope of the pulldown table from 0 to 0.18 V, typ, clamps not added: 35.1 ohm
|   slope of the pullup table from 0 to 0.18 V, typ, clamps not added: 30.6 ohm
|   rising waveform, R_fixture 50.000, V_fixture 0.000: 20-80 % time 1.48ns typ, 1.61ns min, 1.49ns max; typ from 0 V to 0.642 V
|   rising waveform, R_fixture 50.000, V_fixture 0.600: 20-80 % time 2.05ns typ, 1.82ns min, 1.97ns max; typ from 0.252 V to 0.966 V
|   falling waveform, R_fixture 50.000, V_fixture 0.600: 20-80 % time 2.44ns typ, 2.28ns min, 3.11ns max; typ from 0.966 V to 0.252 V
|   falling waveform, R_fixture 50.000, V_fixture 0.000: 20-80 % time 545ps typ, 512ps min, 602ps max; typ from 0.642 V to 0 V
[Pulldown]
|Voltage   I(typ)   I(min)   I(max)
-1.2V     -176.8mA   -216mA     -154.7mA
-1.089V   -117.8mA   -155.8mA   -102.7mA
-978mV    -74.86mA   -102.5mA   -77.86mA
-867mV    -54.12mA   -62.29mA   -62.9mA
-719mV    -38.65mA   -34.84mA   -44.2mA
-386mV    -13.21mA   -12.68mA   -12.84mA
206mV     5.817mA    5.526mA    5.991mA
1.686V    16.69mA    15.86mA    17.19mA
2.056V    27.9mA     26.51mA    28.74mA
2.204V    51.75mA    49.16mA    53.3mA
2.278V    79.92mA    75.92mA    82.32mA
2.4V      142.2mA    135.1mA    146.5mA
[Pullup]
|Voltage   I(typ)   I(min)   I(max)
-1.2V     148.6mA    185.8mA    123.2mA
-1.078V   89.8mA     123.3mA    69.62mA
-1.004V   64.82mA    90.6mA     53.68mA
-893mV    46.86mA    54.62mA    43.4mA
-782mV    38.6mA     36.64mA    35.35mA
-375mV    15.99mA    14.1mA     13.66mA
217mV     -6.872mA   -6.529mA   -7.078mA
1.512V    -16.26mA   -15.45mA   -16.75mA
1.771V    -26.34mA   -25.03mA   -27.13mA
2.141V    -63.95mA   -60.75mA   -65.87mA
2.252V    -99.5mA    -94.5mA    -102.5mA
2.4V      -175.1mA   -166.3mA   -180.4mA
[Ramp]
| variable   typ   min   max
dV/dt_r   0.385/1.519n   0.360/1.674n   0.415/1.500n
dV/dt_f   0.378/2.594n   0.353/2.666n   0.398/3.146n
R_load = 50.000
[Rising Waveform]
R_fixture = 50.000
V_fixture = 0.000
V_fixture_min = 0.000
V_fixture_max = 0.000
|  time   V(typ)   V(min)   V(max)
0s        38.01uV    -69.62uV   -338.6uV
896ps     225.6uV    -3.373mV   1.266mV
1.378ns   29.19mV    24.01mV    40.33mV
1.957ns   133.6mV    124.9mV    180.5mV
2.527ns   299mV      276mV      360.5mV
3.018ns   436.4mV    394.2mV    486.8mV
3.511ns   527.9mV    476.3mV    571.9mV
4.031ns   580.3mV    527.9mV    621.2mV
5.773ns   631.3mV    585.9mV    666.2mV
10ns      641.8mV    600.5mV    674.5mV
[Rising Waveform]
R_fixture = 50.000
V_fixture = 0.600
V_fixture_min = 0.571
V_fixture_max = 0.631
|  time   V(typ)   V(min)   V(max)
0s        251.8mV    246.4mV    261mV
351ps     252.2mV    246.5mV    262.4mV
438ps     252.7mV    246.5mV    382.4mV
666ps     449.5mV    245.8mV    499.3mV
856ps     501mV      406.9mV    541.9mV
1.076ns   535.9mV    481mV      575.2mV
2.474ns   794.9mV    750.9mV    872.5mV
3.179ns   899.3mV    841.9mV    960.9mV
4.941ns   957.4mV    900.2mV    1.011V
10ns      965.5mV    911.3mV    1.018V
[Falling Waveform]
R_fixture = 50.000
V_fixture = 0.600
V_fixture_min = 0.571
V_fixture_max = 0.631
|  time   V(typ)   V(min)   V(max)
0s        965.5mV    911.3mV    1.018V
365ps     965.3mV    911.2mV    1.025V
482ps     968.5mV    911.2mV    884.7mV
704ps     772.2mV    912.4mV    774.7mV
894ps     709.5mV    761.7mV    732.7mV
1.094ns   671.3mV    681mV      705.3mV
1.544ns   608.9mV    595.1mV    658.7mV
3.691ns   336.8mV    337mV      404.7mV
5.913ns   266.4mV    267.4mV    288.3mV
10ns      251.8mV    246.4mV    261mV
[Falling Waveform]
R_fixture = 50.000
V_fixture = 0.000
V_fixture_min = 0.000
V_fixture_max = 0.000
|  time   V(typ)   V(min)   V(max)
0s        641.8mV    600.5mV    674.5mV
362ps     641.8mV    600.3mV    691.9mV
481ps     643.7mV    600mV      425.2mV
591ps     419.8mV    608.8mV    309.1mV
674ps     315mV      617mV      254.5mV
871ps     196.4mV    331.3mV    173.5mV
1.026ns   145.1mV    214.2mV    134.7mV
1.341ns   82.29mV    107.3mV    84.18mV
1.744ns   42.45mV    48.95mV    45.91mV
10ns      38.01uV    -69.62uV   -338.6uV
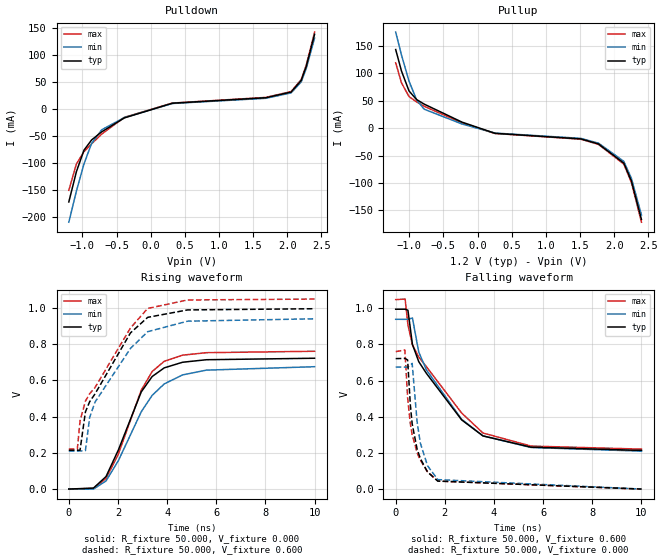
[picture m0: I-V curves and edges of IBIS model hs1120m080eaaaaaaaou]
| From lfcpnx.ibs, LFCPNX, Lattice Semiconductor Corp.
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[Model] hs1120m080eaaaaaaaou
Model_type Output
Polarity   Non-Inverting
Enable   Active-High
Vmeas =  0.600V
Cref =  20.000pF
Rref =  50.000
Vref =  0.600V
C_comp   5.000pF   4.000pF   5.500pF
[Temperature Range]   25.000   0.125k   -40.000
[Voltage Range]   1.200V   1.140V   1.260V
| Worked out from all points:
|   slope of the pulldown table from 0 to 0.18 V, typ, clamps not added: 27.3 ohm
|   slope of the pullup table from 0 to 0.18 V, typ, clamps not added: 25.5 ohm
|   rising waveform, R_fixture 50.000, V_fixture 0.000: 20-80 % time 1.33ns typ, 1.61ns min, 1.29ns max; typ from 0 V to 0.722 V
|   rising waveform, R_fixture 50.000, V_fixture 0.600: 20-80 % time 1.82ns typ, 1.81ns min, 2.02ns max; typ from 0.214 V to 0.995 V
|   falling waveform, R_fixture 50.000, V_fixture 0.600: 20-80 % time 2.14ns typ, 2.02ns min, 2.37ns max; typ from 0.995 V to 0.214 V
|   falling waveform, R_fixture 50.000, V_fixture 0.000: 20-80 % time 536ps typ, 501ps min, 590ps max; typ from 0.722 V to 0 V
[Pulldown]
|Voltage   I(typ)   I(min)   I(max)
-1.2V     -172mA     -209.5mA   -150.5mA
-1.089V   -116mA     -152mA     -101.6mA
-978mV    -76.15mA   -101.5mA   -78.8mA
-867mV    -57.22mA   -63.79mA   -64.4mA
-719mV    -42.17mA   -38.34mA   -46.28mA
-386mV    -16.26mA   -15.56mA   -15.23mA
317mV     10.92mA    10.37mA    11.24mA
1.686V    21.08mA    20.03mA    21.71mA
2.056V    31.59mA    30.01mA    32.54mA
2.204V    53.04mA    50.39mA    54.63mA
2.278V    79.2mA     75.2mA     81.6mA
2.4V      138.5mA    131.6mA    142.7mA
[Pullup]
|Voltage   I(typ)   I(min)   I(max)
-1.2V     143.8mA    175.7mA    119.5mA
-1.115V   104.4mA    133.7mA    82.8mA
-1.004V   67.92mA    85.7mA     57.67mA
-893mV    52.22mA    51.65mA    48.03mA
-782mV    43.96mA    34.65mA    39.94mA
-227mV    10.98mA    7.588mA    9.596mA
254mV     -9.406mA   -8.935mA   -9.688mA
1.512V    -19.59mA   -18.61mA   -20.17mA
1.771V    -28.88mA   -27.43mA   -29.74mA
2.141V    -63.74mA   -60.55mA   -65.65mA
2.252V    -96.2mA    -91.4mA    -99.1mA
2.4V      -166.9mA   -158.6mA   -171.9mA
[Ramp]
| variable   typ   min   max
dV/dt_r   0.433/1.352n   0.405/1.676n   0.456/1.350n
dV/dt_f   0.438/2.309n   0.410/2.319n   0.463/2.482n
R_load = 50.000
[Rising Waveform]
R_fixture = 50.000
V_fixture = 0.000
V_fixture_min = 0.000
V_fixture_max = 0.000
|  time   V(typ)   V(min)   V(max)
0s        41.32uV    -87.13uV   -556.9uV
1.003ns   5.354mV    -178.5uV   3.946mV
1.513ns   68.74mV    44.95mV    58.05mV
2.016ns   215.6mV    156.6mV    193.1mV
2.949ns   536.3mV    426.7mV    546.2mV
3.391ns   620.7mV    516.8mV    648.2mV
3.88ns    668.4mV    579.8mV    704.5mV
4.628ns   699.5mV    629.6mV    738.5mV
5.6ns     713.4mV    656mV      752.3mV
10ns      721.6mV    674.9mV    760.1mV
[Rising Waveform]
R_fixture = 50.000
V_fixture = 0.600
V_fixture_min = 0.571
V_fixture_max = 0.631
|  time   V(typ)   V(min)   V(max)
0s        213.6mV    209.8mV    220.9mV
346ps     214mV      209.8mV    220.1mV
457ps     214.4mV    210mV      376.4mV
676ps     425.8mV    212.5mV    485.2mV
847ps     481.7mV    394.4mV    525.9mV
1.066ns   524.9mV    479.9mV    560.1mV
2.507ns   861.2mV    775.5mV    888.4mV
3.209ns   947.1mV    868mV      996.4mV
4.83ns    988.1mV    926mV      1.043V
10ns      994.7mV    939.2mV    1.048V
[Falling Waveform]
R_fixture = 50.000
V_fixture = 0.600
V_fixture_min = 0.571
V_fixture_max = 0.631
|  time   V(typ)   V(min)   V(max)
0s        994.7mV    939.2mV    1.048V
384ps     995mV      939mV      1.051V
498ps     989.1mV    938.8mV    908.3mV
681ps     800.4mV    946.4mV    797.5mV
938ps     704.8mV    757.7mV    730mV
1.25ns    640.1mV    659.2mV    676.9mV
2.683ns   382.7mV    386.1mV    420.8mV
3.551ns   294mV      294.2mV    310.1mV
5.506ns   231.8mV    229.9mV    237.8mV
10ns      213.6mV    209.8mV    220.9mV
[Falling Waveform]
R_fixture = 50.000
V_fixture = 0.000
V_fixture_min = 0.000
V_fixture_max = 0.000
|  time   V(typ)   V(min)   V(max)
0s        721.6mV    674.9mV    760.1mV
374ps     722.7mV    674.6mV    769.4mV
486ps     713.9mV    674.3mV    503.7mV
596ps     465.9mV    685.5mV    359.9mV
670ps     361.1mV    695.1mV    301.1mV
870ps     221.8mV    373.4mV    201.4mV
1ns       170.1mV    255.9mV    160.4mV
1.294ns   94.47mV    129.5mV    95.75mV
1.714ns   44.03mV    52.35mV    44.56mV
10ns      41.32uV    -87.13uV   -556.9uV
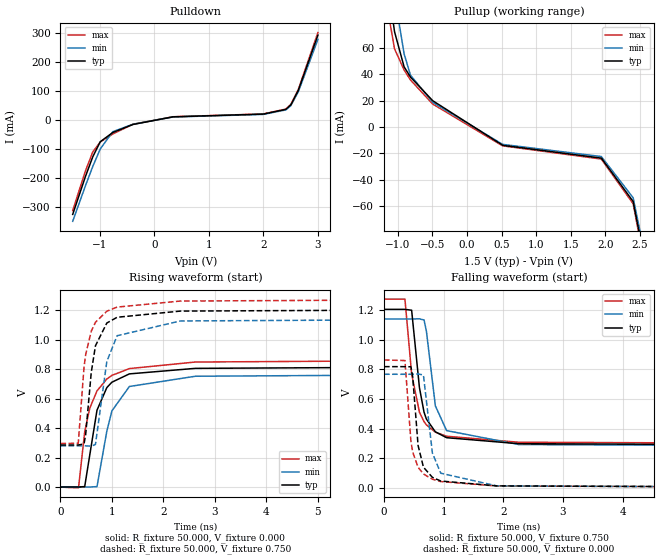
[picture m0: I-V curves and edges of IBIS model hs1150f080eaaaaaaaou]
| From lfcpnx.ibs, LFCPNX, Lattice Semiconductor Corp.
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[Model] hs1150f080eaaaaaaaou
Model_type Output
Polarity   Non-Inverting
Enable   Active-High
Vmeas =  0.750V
Cref =  30.000pF
Rref =  50.000
Vref =  0.750V
C_comp   5.000pF   4.000pF   5.500pF
[Temperature Range]   25.000   0.125k   -40.000
[Voltage Range]   1.500V   1.430V   1.580V
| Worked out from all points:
|   slope of the pulldown table from 0 to 0.225 V, typ, clamps not added: 29.8 ohm
|   slope of the pullup table from 0 to 0.225 V, typ, clamps not added: 31.2 ohm
|   rising waveform, R_fixture 50.000, V_fixture 0.000: 20-80 % time 311ps typ, 333ps min, 377ps max; typ from 0 V to 0.818 V
|   rising waveform, R_fixture 50.000, V_fixture 0.750: 20-80 % time 217ps typ, 245ps min, 234ps max; typ from 0.285 V to 1.21 V
|   falling waveform, R_fixture 50.000, V_fixture 0.750: 20-80 % time 189ps typ, 202ps min, 215ps max; typ from 1.21 V to 0.285 V
|   falling waveform, R_fixture 50.000, V_fixture 0.000: 20-80 % time 135ps typ, 149ps min, 147ps max; typ from 0.818 V to 0 V
[Pulldown]
|Voltage   I(typ)   I(min)   I(max)
-1.5V     -326.3mA   -350.1mA   -313mA
-1.27V    -197.3mA   -229.2mA   -178.1mA
-1.132V   -127.3mA   -160.7mA   -110.5mA
-994mV    -75.1mA    -100.1mA   -76mA
-764mV    -43.36mA   -40.34mA   -48.47mA
-396mV    -15.68mA   -14.88mA   -14.84mA
340mV     10.77mA    10.23mA    11.09mA
1.996V    20.21mA    19.2mA     20.82mA
2.41V     36.42mA    34.6mA     37.52mA
2.502V    51.88mA    49.29mA    53.44mA
2.64V     102.4mA    97.3mA     105.5mA
3V        293.1mA    278.4mA    301.9mA
[Pullup]
|Voltage   I(typ)   I(min)   I(max)
-1.5V     294.8mA    323.3mA    276.8mA
-1.186V   128.1mA    161.6mA    106.6mA
-1.14V    107.1mA    140mA      86.9mA
-1.048V   72.31mA    100.2mA    59.29mA
-910mV    45.66mA    55.61mA    43.29mA
-818mV    37.9mA     39.34mA    35.67mA
-496mV    19.91mA    18.64mA    17.36mA
516mV     -13.95mA   -13.25mA   -14.37mA
1.942V    -23.66mA   -22.47mA   -24.37mA
2.402V    -56.58mA   -53.75mA   -58.27mA
2.586V    -105.8mA   -100.5mA   -109mA
3V        -324mA     -307.8mA   -333.7mA
[Ramp]
| variable   typ   min   max
dV/dt_r   0.491/0.313n   0.460/0.337n   0.518/0.377n
dV/dt_f   0.491/0.334n   0.462/0.332n   0.516/0.414n
R_load = 50.000
[Rising Waveform]
R_fixture = 50.000
V_fixture = 0.000
V_fixture_min = 0.000
V_fixture_max = 0.000
|  time   V(typ)   V(min)   V(max)
0s        64.49uV    -114.4uV   -607.3uV
351ps     396.9uV    -89.81uV   -5.412mV
471ps     3.212mV    -35.29uV   374.9mV
569ps     216mV      225.7uV    534.2mV
710ps     521.2mV    3.09mV     652.1mV
901ps     674.3mV    378.8mV    732.5mV
1ns       711mV      516.6mV    757.1mV
1.339ns   767.2mV    681.7mV    803.2mV
2.62ns    804.7mV    751.2mV    847.6mV
10ns      818.1mV    766.6mV    863mV
[Rising Waveform]
R_fixture = 50.000
V_fixture = 0.750
V_fixture_min = 0.713
V_fixture_max = 0.789
|  time   V(typ)   V(min)   V(max)
0s        285mV      279.2mV    295.2mV
346ps     285.2mV    279.2mV    297mV
458ps     292.3mV    279.3mV    813.2mV
490ps     356mV      279.3mV    897.8mV
598ps     776.4mV    277.4mV    1.056V
680ps     957.7mV    288.7mV    1.117V
901ps     1.112V     851.9mV    1.192V
1.101ns   1.151V     1.026V     1.22V
2.33ns    1.193V     1.126V     1.261V
10ns      1.205V     1.14V      1.274V
[Falling Waveform]
R_fixture = 50.000
V_fixture = 0.750
V_fixture_min = 0.713
V_fixture_max = 0.789
|  time   V(typ)   V(min)   V(max)
0s        1.205V     1.14V      1.274V
351ps     1.205V     1.14V      1.274V
463ps     1.199V     1.14V      769mV
594ps     675.8mV    1.141V     510.3mV
671ps     510.4mV    1.133V     446.6mV
711ps     463.8mV    1.057V     424.6mV
861ps     377.6mV    553.1mV    375.6mV
1.049ns   338.2mV    386.1mV    348mV
2.261ns   297.6mV    291.7mV    307.5mV
10ns      285mV      279.2mV    295.2mV
[Falling Waveform]
R_fixture = 50.000
V_fixture = 0.000
V_fixture_min = 0.000
V_fixture_max = 0.000
|  time   V(typ)   V(min)   V(max)
0s        818.1mV    766.6mV    863mV
351ps     817.9mV    766.5mV    859.2mV
451ps     817mV      766.6mV    314.3mV
481ps     748.9mV    766.4mV    241.2mV
571ps     285.9mV    768.6mV    138.5mV
661ps     139.1mV    761.3mV    93.22mV
811ps     70.38mV    234.9mV    57.74mV
951ps     45.63mV    98.31mV    41.8mV
1.891ns   12.7mV     12.6mV     11.86mV
10ns      64.49uV    -114.4uV   -607.3uV
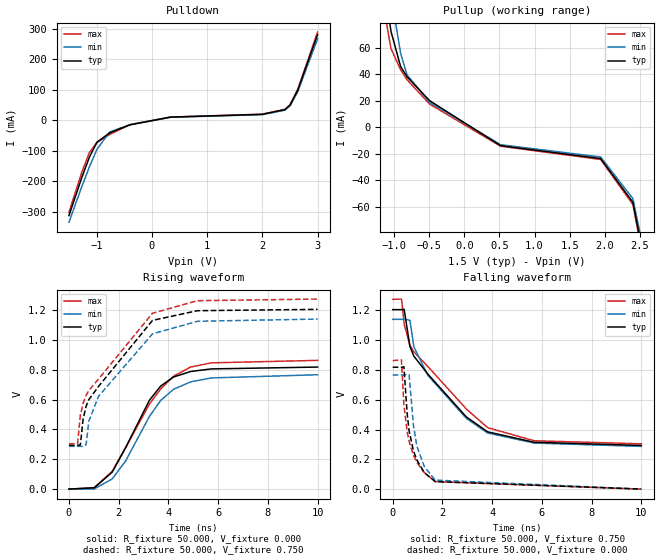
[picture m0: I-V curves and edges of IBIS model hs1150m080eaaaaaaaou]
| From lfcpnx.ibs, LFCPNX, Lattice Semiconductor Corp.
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[Model] hs1150m080eaaaaaaaou
Model_type Output
Polarity   Non-Inverting
Enable   Active-High
Vmeas =  0.750V
Cref =  30.000pF
Rref =  50.000
Vref =  0.750V
C_comp   5.000pF   4.000pF   5.500pF
[Temperature Range]   25.000   0.125k   -40.000
[Voltage Range]   1.500V   1.430V   1.580V
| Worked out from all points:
|   slope of the pulldown table from 0 to 0.225 V, typ, clamps not added: 31 ohm
|   slope of the pullup table from 0 to 0.225 V, typ, clamps not added: 31.2 ohm
|   rising waveform, R_fixture 50.000, V_fixture 0.000: 20-80 % time 1.56ns typ, 1.65ns min, 1.85ns max; typ from 0 V to 0.818 V
|   rising waveform, R_fixture 50.000, V_fixture 0.750: 20-80 % time 2.05ns typ, 2.08ns min, 2.22ns max; typ from 0.293 V to 1.21 V
|   falling waveform, R_fixture 50.000, V_fixture 0.750: 20-80 % time 2.42ns typ, 2.23ns min, 2.7ns max; typ from 1.21 V to 0.293 V
|   falling waveform, R_fixture 50.000, V_fixture 0.000: 20-80 % time 539ps typ, 515ps min, 594ps max; typ from 0.818 V to 0 V
[Pulldown]
|Voltage   I(typ)   I(min)   I(max)
-1.5V     -313.3mA   -335mA     -302.1mA
-1.27V    -189.4mA   -219.3mA   -172mA
-1.132V   -122.2mA   -153.9mA   -106.6mA
-994mV    -72.1mA    -95.8mA    -73.4mA
-764mV    -41.63mA   -38.61mA   -46.78mA
-396mV    -15.05mA   -14.24mA   -14.33mA
340mV     10.34mA    9.824mA    10.65mA
1.996V    19.41mA    18.44mA    19.99mA
2.41V     34.97mA    33.22mA    36.02mA
2.502V    49.81mA    47.32mA    51.3mA
2.64V     98.3mA     93.4mA     101.2mA
3V        281.4mA    267.3mA    289.8mA
[Pullup]
|Voltage   I(typ)   I(min)   I(max)
-1.5V     294.8mA    323.3mA    276.8mA
-1.186V   128.1mA    161.6mA    106.6mA
-1.14V    107.1mA    140mA      86.9mA
-1.048V   72.31mA    100.2mA    59.29mA
-910mV    45.66mA    55.61mA    43.29mA
-818mV    37.9mA     39.34mA    35.67mA
-496mV    19.91mA    18.64mA    17.36mA
516mV     -13.95mA   -13.25mA   -14.37mA
1.942V    -23.66mA   -22.47mA   -24.37mA
2.402V    -56.58mA   -53.75mA   -58.27mA
2.586V    -105.8mA   -100.5mA   -109mA
3V        -324mA     -307.8mA   -333.7mA
[Ramp]
| variable   typ   min   max
dV/dt_r   0.491/1.572n   0.460/1.683n   0.518/1.873n
dV/dt_f   0.477/2.673n   0.448/2.569n   0.500/2.889n
R_load = 50.000
[Rising Waveform]
R_fixture = 50.000
V_fixture = 0.000
V_fixture_min = 0.000
V_fixture_max = 0.000
|  time   V(typ)   V(min)   V(max)
0s        63.87uV    -134.3uV   -561.9uV
1.018ns   8.594mV    1.238mV    10.1mV
1.738ns   113.3mV    67.64mV    118.5mV
2.281ns   278.5mV    189mV      277.3mV
3.238ns   595.6mV    487.6mV    570.5mV
3.69ns    690.8mV    594.4mV    671.4mV
4.21ns    751.8mV    669.3mV    757.2mV
4.899ns   788.5mV    719.2mV    818.6mV
5.725ns   805.7mV    745.1mV    846.3mV
10ns      818.1mV    766.6mV    863mV
[Rising Waveform]
R_fixture = 50.000
V_fixture = 0.750
V_fixture_min = 0.713
V_fixture_max = 0.789
|  time   V(typ)   V(min)   V(max)
0s        292.9mV    286.7mV    303.8mV
346ps     293.1mV    286.8mV    305mV
458ps     296.3mV    286.9mV    494.2mV
569ps     468.1mV    285.7mV    575.4mV
690ps     555.1mV    298.5mV    628.1mV
801ps     600.2mV    456.2mV    661.5mV
1.19ns    688.4mV    622mV      737.7mV
3.361ns   1.131V     1.041V     1.179V
5.167ns   1.196V     1.125V     1.263V
10ns      1.205V     1.14V      1.274V
[Falling Waveform]
R_fixture = 50.000
V_fixture = 0.750
V_fixture_min = 0.713
V_fixture_max = 0.789
|  time   V(typ)   V(min)   V(max)
0s        1.205V     1.14V      1.274V
356ps     1.205V     1.14V      1.276V
461ps     1.207V     1.14V      1.108V
691ps     958.5mV    1.134V     967.1mV
851ps     892.7mV    955.8mV    921.4mV
1.412ns   772.3mV    763.8mV    823.5mV
2.967ns   483.7mV    473.5mV    536.8mV
3.819ns   384.4mV    376.7mV    412.5mV
5.685ns   314.4mV    309mV      324.6mV
10ns      292.9mV    286.7mV    303.8mV
[Falling Waveform]
R_fixture = 50.000
V_fixture = 0.000
V_fixture_min = 0.000
V_fixture_max = 0.000
|  time   V(typ)   V(min)   V(max)
0s        818.1mV    766.6mV    863mV
351ps     817.8mV    766.4mV    867.5mV
451ps     821.4mV    766.6mV    565mV
581ps     507mV      770.5mV    385.9mV
660ps     391mV      768.4mV    321.2mV
831ps     259.2mV    431.5mV    229.1mV
971ps     195.6mV    288.7mV    180.5mV
1.271ns   110.7mV    151mV      110.1mV
1.711ns   50.09mV    60.08mV    50.36mV
10ns      63.87uV    -134.3uV   -561.9uV
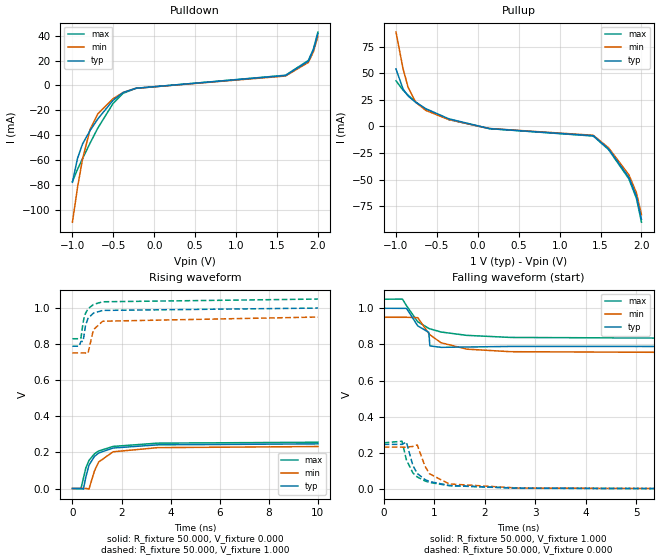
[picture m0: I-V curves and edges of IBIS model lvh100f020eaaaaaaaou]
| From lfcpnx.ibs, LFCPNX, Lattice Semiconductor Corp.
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[Model] lvh100f020eaaaaaaaou
Model_type Output
Polarity   Non-Inverting
Enable   Active-High
Vmeas =  0.500V
Cref =  0.0F
Rref =  1.000M
Vref =  0.0V
C_comp   5.000pF   4.000pF   5.500pF
[Temperature Range]   25.000   0.125k   -40.000
[Voltage Range]   1.000V   0.950V   1.050V
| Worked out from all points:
|   slope of the pulldown table from 0 to 0.15 V, typ, clamps not added: 112 ohm
|   slope of the pullup table from 0 to 0.15 V, typ, clamps not added: 70.6 ohm
|   rising waveform, R_fixture 50.000, V_fixture 0.000: 20-80 % time 556ps typ, 572ps min, 594ps max; typ from 0 V to 0.248 V
|   rising waveform, R_fixture 50.000, V_fixture 1.000: 20-80 % time 262ps typ, 317ps min, 313ps max; typ from 0.789 V to 1 V
|   falling waveform, R_fixture 50.000, V_fixture 1.000: 20-80 % time 367ps typ, 552ps min, 590ps max; typ from 1 V to 0.789 V
|   falling waveform, R_fixture 50.000, V_fixture 0.000: 20-80 % time 330ps typ, 348ps min, 350ps max; typ from 0.248 V to 0 V
[Pulldown]
|Voltage   I(typ)   I(min)   I(max)
-1V       -77.67mA   -109.7mA   -77.1mA
-938mV    -58.53mA   -81.92mA   -67.33mA
-876mV    -46.89mA   -58.86mA   -58.63mA
-783mV    -36mA      -35.1mA    -46.09mA
-690mV    -26.86mA   -22.73mA   -34.26mA
-504mV    -11.96mA   -10.67mA   -14.5mA
-380mV    -5.675mA   -5.627mA   -6.286mA
-225mV    -2.256mA   -2.289mA   -2.368mA
1.604V    7.952mA    7.555mA    8.191mA
1.883V    19.44mA    18.47mA    20.03mA
1.945V    28.4mA     26.98mA    29.25mA
2V        41.56mA    39.48mA    42.8mA
[Pullup]
|Voltage   I(typ)   I(min)   I(max)
-1V       54.04mA    88.72mA    42.94mA
-914mV    35.21mA    54.31mA    34.1mA
-852mV    28.59mA    36.79mA    29.36mA
-759mV    22.7mA     22.67mA    23.02mA
-635mV    16.68mA    15.09mA    16.17mA
-356mV    7.228mA    6.497mA    6.54mA
140mV     -2.013mA   -1.912mA   -2.073mA
1.411V    -8.732mA   -8.296mA   -8.994mA
1.597V    -21.07mA   -20.01mA   -21.7mA
1.845V    -47.73mA   -45.34mA   -49.16mA
1.938V    -65.56mA   -62.28mA   -67.52mA
2V        -87.4mA    -83.03mA   -90.02mA
[Ramp]
| variable   typ   min   max
dV/dt_r   0.151/0.565n   0.139/0.577n   0.154/0.602n
dV/dt_f   0.127/0.532n   0.119/0.548n   0.132/0.585n
R_load = 50.000
[Rising Waveform]
R_fixture = 50.000
V_fixture = 0.000
V_fixture_min = 0.000
V_fixture_max = 0.000
|  time   V(typ)   V(min)   V(max)
0s        323.7uV    575.5uV    483.4uV
345ps     590.7uV    682.6uV    -2.324mV
446ps     -3.402mV   610.5uV    56.83mV
548ps     64.2mV     926.7uV    115.2mV
675ps     129.9mV    -2.501mV   155.9mV
895ps     177.8mV    96.72mV    192.2mV
1.065ns   196.6mV    146.6mV    207.9mV
1.656ns   224.6mV    203.7mV    233.5mV
3.469ns   242.2mV    226.6mV    251.6mV
10ns      247.8mV    232.9mV    256.6mV
[Rising Waveform]
R_fixture = 50.000
V_fixture = 1.000
V_fixture_min = 0.950
V_fixture_max = 1.050
|  time   V(typ)   V(min)   V(max)
0s        788.6mV    751.4mV    830.1mV
273ps     788.8mV    751.6mV    830.2mV
346ps     815mV      751.5mV    832.2mV
430ps     815.3mV    751.5mV    915.4mV
465ps     842.3mV    751.5mV    940.6mV
534ps     904.5mV    751.2mV    971.2mV
635ps     943mV      750.3mV    995.8mV
855ps     972mV      880mV      1.02V
1.234ns   987.1mV    927.3mV    1.035V
10ns      1V         950.4mV    1.05V
[Falling Waveform]
R_fixture = 50.000
V_fixture = 1.000
V_fixture_min = 0.950
V_fixture_max = 1.050
|  time   V(typ)   V(min)   V(max)
0s        1V         950.4mV    1.05V
370ps     999.8mV    950.3mV    1.051V
452ps     999.5mV    950.4mV    1.014V
673ps     903mV      948.2mV    925.6mV
893ps     866.8mV    860.3mV    888.8mV
914ps     792.1mV    853.9mV    886.5mV
1.134ns   784.2mV    809.6mV    869mV
1.641ns   786mV      774.2mV    850.4mV
2.514ns   789.3mV    760.1mV    838.9mV
10ns      788.6mV    751.4mV    830.1mV
[Falling Waveform]
R_fixture = 50.000
V_fixture = 0.000
V_fixture_min = 0.000
V_fixture_max = 0.000
|  time   V(typ)   V(min)   V(max)
0s        247.8mV    232.9mV    256.6mV
362ps     248mV      232.6mV    265.2mV
449ps     260.2mV    232.7mV    162.4mV
577ps     131.3mV    236.5mV    90.26mV
664ps     87.05mV    244.9mV    67.78mV
814ps     53.79mV    129.6mV    45.68mV
904ps     42.82mV    85.98mV    37.55mV
1.297ns   20.74mV    29.1mV     19.73mV
2.673ns   5.86mV     6.316mV    5.238mV
10ns      323.7uV    575.5uV    483.4uV
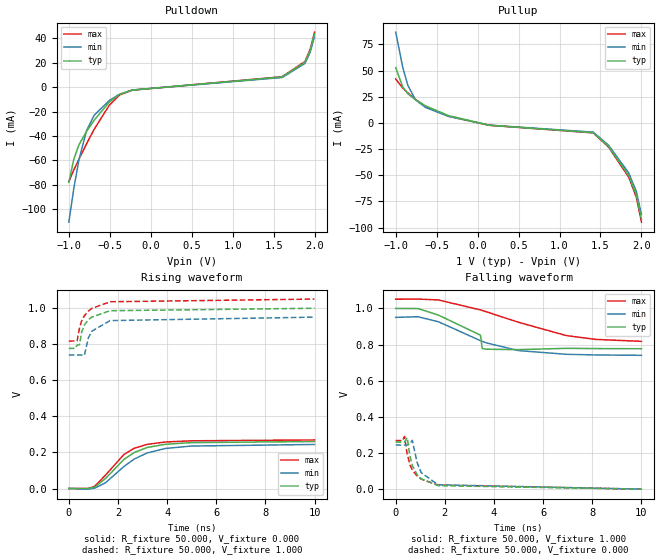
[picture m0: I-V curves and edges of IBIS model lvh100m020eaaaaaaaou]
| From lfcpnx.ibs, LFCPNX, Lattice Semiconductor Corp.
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[Model] lvh100m020eaaaaaaaou
Model_type Output
Polarity   Non-Inverting
Enable   Active-High
Vmeas =  0.500V
Cref =  0.0F
Rref =  1.000M
Vref =  0.0V
C_comp   5.000pF   4.000pF   5.500pF
[Temperature Range]   25.000   0.125k   -40.000
[Voltage Range]   1.000V   0.950V   1.050V
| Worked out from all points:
|   slope of the pulldown table from 0 to 0.15 V, typ, clamps not added: 107 ohm
|   slope of the pullup table from 0 to 0.15 V, typ, clamps not added: 67.4 ohm
|   rising waveform, R_fixture 50.000, V_fixture 0.000: 20-80 % time 1.33ns typ, 1.5ns min, 1.17ns max; typ from 0 V to 0.261 V
|   rising waveform, R_fixture 50.000, V_fixture 1.000: 20-80 % time 518ps typ, 523ps min, 586ps max; typ from 0.777 V to 1 V
|   falling waveform, R_fixture 50.000, V_fixture 1.000: 20-80 % time 1.62ns typ, 2.32ns min, 3.3ns max; typ from 1 V to 0.777 V
|   falling waveform, R_fixture 50.000, V_fixture 0.000: 20-80 % time 532ps typ, 525ps min, 613ps max; typ from 0.261 V to 0 V
[Pulldown]
|Voltage   I(typ)   I(min)   I(max)
-1V       -78.05mA   -110.7mA   -77.47mA
-938mV    -58.82mA   -82.64mA   -67.66mA
-876mV    -47.13mA   -59.37mA   -58.92mA
-783mV    -36.18mA   -35.41mA   -46.31mA
-690mV    -27mA      -22.92mA   -34.43mA
-504mV    -12.02mA   -10.77mA   -14.57mA
-380mV    -5.703mA   -5.676mA   -6.316mA
-225mV    -2.268mA   -2.309mA   -2.379mA
1.604V    8.407mA    7.987mA    8.659mA
1.883V    20.55mA    19.53mA    21.17mA
1.945V    30.02mA    28.52mA    30.92mA
2V        43.93mA    41.74mA    45.25mA
[Pullup]
|Voltage   I(typ)   I(min)   I(max)
-1V       52.89mA    86.84mA    42.03mA
-914mV    34.47mA    53.16mA    33.37mA
-852mV    27.99mA    36.01mA    28.73mA
-759mV    22.22mA    22.19mA    22.53mA
-635mV    16.33mA    14.77mA    15.82mA
-356mV    7.075mA    6.36mA     6.402mA
140mV     -2.119mA   -2.013mA   -2.182mA
1.411V    -9.193mA   -8.733mA   -9.468mA
1.597V    -22.18mA   -21.07mA   -22.84mA
1.845V    -50.24mA   -47.73mA   -51.75mA
1.938V    -69.01mA   -65.56mA   -71.08mA
2V        -92.01mA   -87.41mA   -94.77mA
[Ramp]
| variable   typ   min   max
dV/dt_r   0.151/1.333n   0.146/1.513n   0.161/1.189n
dV/dt_f   0.134/2.036n   0.126/2.409n   0.140/3.308n
R_load = 50.000
[Rising Waveform]
R_fixture = 50.000
V_fixture = 0.000
V_fixture_min = 0.000
V_fixture_max = 0.000
|  time   V(typ)   V(min)   V(max)
0s        313.9uV    469.5uV    371.9uV
784ps     -193.6uV   -3.391mV   558.8uV
1.055ns   8.654mV    2.522mV    12.51mV
1.485ns   54.86mV    31.17mV    73.38mV
2.244ns   161.7mV    122.6mV    189mV
2.662ns   199.9mV    163.7mV    223.2mV
3.189ns   227.7mV    197.7mV    245.3mV
3.933ns   245.6mV    222.4mV    258.3mV
4.991ns   254.8mV    235.8mV    264.8mV
10ns      261.1mV    244.5mV    269.5mV
[Rising Waveform]
R_fixture = 50.000
V_fixture = 1.000
V_fixture_min = 0.950
V_fixture_max = 1.050
|  time   V(typ)   V(min)   V(max)
0s        777.2mV    740.8mV    818.1mV
263ps     777.4mV    741mV      818.4mV
336ps     795.9mV    740.9mV    818.4mV
435ps     797.8mV    740.9mV    890mV
519ps     865.9mV    740.8mV    929mV
632ps     906.9mV    738.3mV    958.4mV
795ps     935.9mV    835.5mV    984.4mV
934ps     951.3mV    872.5mV    999.2mV
1.681ns   986.4mV    931.6mV    1.036V
10ns      1V         950.7mV    1.051V
[Falling Waveform]
R_fixture = 50.000
V_fixture = 1.000
V_fixture_min = 0.950
V_fixture_max = 1.050
|  time   V(typ)   V(min)   V(max)
0s        1V         950.7mV    1.051V
904ps     999.6mV    954.3mV    1.052V
1.744ns   963mV      926.3mV    1.047V
3.45ns    852.1mV    821.7mV    991.9mV
3.522ns   778.6mV    817.9mV    988.8mV
3.691ns   774.5mV    809.6mV    981.6mV
5ns       772.3mV    766.8mV    923.4mV
6.944ns   779.5mV    746.4mV    850mV
8.137ns   778.1mV    742.8mV    828.8mV
10ns      777.2mV    740.8mV    818.1mV
[Falling Waveform]
R_fixture = 50.000
V_fixture = 0.000
V_fixture_min = 0.000
V_fixture_max = 0.000
|  time   V(typ)   V(min)   V(max)
0s        261.1mV    244.5mV    269.5mV
283ps     261.1mV    244.1mV    269.1mV
362ps     261.2mV    244.1mV    292.3mV
466ps     285.3mV    244.2mV    194.5mV
586ps     179.4mV    252mV      133mV
676ps     131mV      270.6mV    107mV
874ps     80.49mV    146.7mV    72.42mV
1.036ns   57.55mV    91.97mV    55.7mV
1.724ns   19.94mV    24.62mV    23.25mV
10ns      313.9uV    469.5uV    371.9uV
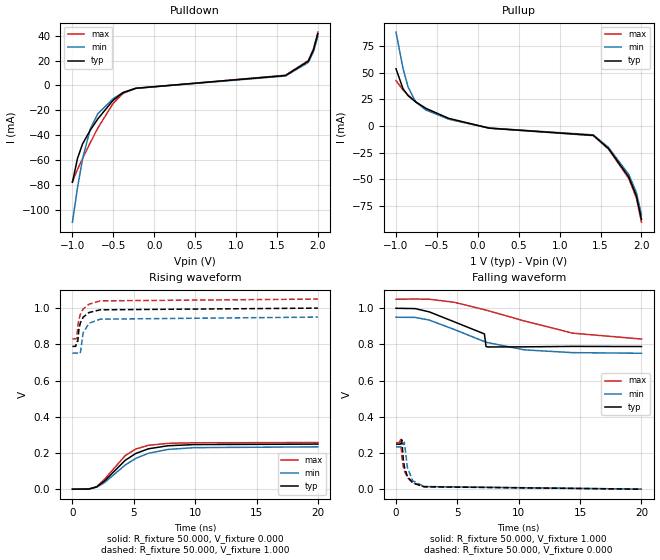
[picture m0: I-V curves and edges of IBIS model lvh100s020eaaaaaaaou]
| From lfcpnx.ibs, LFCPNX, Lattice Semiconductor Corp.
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[Model] lvh100s020eaaaaaaaou
Model_type Output
Polarity   Non-Inverting
Enable   Active-High
Vmeas =  0.500V
Cref =  0.0F
Rref =  1.000M
Vref =  0.0V
C_comp   5.000pF   4.000pF   5.500pF
[Temperature Range]   25.000   0.125k   -40.000
[Voltage Range]   1.000V   0.950V   1.050V
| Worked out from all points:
|   slope of the pulldown table from 0 to 0.15 V, typ, clamps not added: 112 ohm
|   slope of the pullup table from 0 to 0.15 V, typ, clamps not added: 70.3 ohm
|   rising waveform, R_fixture 50.000, V_fixture 0.000: 20-80 % time 2.54ns typ, 2.91ns min, 2.16ns max; typ from 0 V to 0.249 V
|   rising waveform, R_fixture 50.000, V_fixture 1.000: 20-80 % time 513ps typ, 548ps min, 614ps max; typ from 0.789 V to 1 V
|   falling waveform, R_fixture 50.000, V_fixture 1.000: 20-80 % time 3.64ns typ, 4.79ns min, 7.14ns max; typ from 1 V to 0.789 V
|   falling waveform, R_fixture 50.000, V_fixture 0.000: 20-80 % time 571ps typ, 561ps min, 616ps max; typ from 0.249 V to 0 V
[Pulldown]
|Voltage   I(typ)   I(min)   I(max)
-1V       -77.67mA   -109.7mA   -77.1mA
-938mV    -58.53mA   -81.92mA   -67.33mA
-876mV    -46.89mA   -58.86mA   -58.63mA
-783mV    -36mA      -35.1mA    -46.09mA
-690mV    -26.86mA   -22.73mA   -34.26mA
-504mV    -11.96mA   -10.67mA   -14.5mA
-380mV    -5.675mA   -5.626mA   -6.286mA
-225mV    -2.256mA   -2.289mA   -2.368mA
1.604V    7.952mA    7.554mA    8.191mA
1.883V    19.44mA    18.47mA    20.03mA
1.945V    28.4mA     26.98mA    29.25mA
2V        41.56mA    39.48mA    42.8mA
[Pullup]
|Voltage   I(typ)   I(min)   I(max)
-1V       53.82mA    88.35mA    42.77mA
-914mV    35.07mA    54.09mA    33.96mA
-852mV    28.48mA    36.64mA    29.23mA
-759mV    22.61mA    22.58mA    22.92mA
-635mV    16.61mA    15.03mA    16.1mA
-356mV    7.199mA    6.471mA    6.513mA
140mV     -2.023mA   -1.922mA   -2.084mA
1.411V    -8.779mA   -8.34mA    -9.042mA
1.597V    -21.18mA   -20.12mA   -21.81mA
1.845V    -47.98mA   -45.58mA   -49.42mA
1.938V    -65.9mA    -62.61mA   -67.88mA
2V        -87.86mA   -83.47mA   -90.5mA
[Ramp]
| variable   typ   min   max
dV/dt_r   0.152/2.514n   0.140/2.889n   0.154/2.208n
dV/dt_f   0.127/4.122n   0.119/4.816n   0.132/7.146n
R_load = 50.000
[Rising Waveform]
R_fixture = 50.000
V_fixture = 0.000
V_fixture_min = 0.000
V_fixture_max = 0.000
|  time   V(typ)   V(min)   V(max)
0s        323.7uV    575.3uV    483.4uV
1.325ns   818.3uV    899.7uV    996uV
1.979ns   12.95mV    11.18mV    14.72mV
2.6ns     44.62mV    35.98mV    54.11mV
4.301ns   159.6mV    133.7mV    185.7mV
5.159ns   197.4mV    170.3mV    221.7mV
6.191ns   223.2mV    198.4mV    242.5mV
7.787ns   240.1mV    219.7mV    253.2mV
9.95ns    246.6mV    229.6mV    256.5mV
20ns      249.2mV    234.1mV    257.9mV
[Rising Waveform]
R_fixture = 50.000
V_fixture = 1.000
V_fixture_min = 0.950
V_fixture_max = 1.050
|  time   V(typ)   V(min)   V(max)
0s        788.6mV    751.4mV    830.1mV
263ps     788.8mV    751.7mV    830.3mV
346ps     815.1mV    751.5mV    832.5mV
433ps     816mV      751.5mV    896.9mV
523ps     880.6mV    751.3mV    936.4mV
640ps     917.4mV    750mV      964.5mV
869ps     949.5mV    863.3mV    994.9mV
1.353ns   975.7mV    916.2mV    1.022V
2.264ns   990.7mV    939.1mV    1.04V
20ns      1V         950.5mV    1.05V
[Falling Waveform]
R_fixture = 50.000
V_fixture = 1.000
V_fixture_min = 0.950
V_fixture_max = 1.050
|  time   V(typ)   V(min)   V(max)
0s        1V         950.5mV    1.05V
1.564ns   998.3mV    949.5mV    1.051V
2.71ns    980.2mV    934.9mV    1.05V
4.681ns   927.1mV    884.7mV    1.034V
7.205ns   858.2mV    815.9mV    992.4mV
7.335ns   788.9mV    813.1mV    989.9mV
7.465ns   786.3mV    810.4mV    987.5mV
10.47ns   786.9mV    770.2mV    929.7mV
14.39ns   789.4mV    754.9mV    862.5mV
20ns      788.6mV    751.4mV    830.1mV
[Falling Waveform]
R_fixture = 50.000
V_fixture = 0.000
V_fixture_min = 0.000
V_fixture_max = 0.000
|  time   V(typ)   V(min)   V(max)
0s        249.2mV    234.1mV    257.9mV
283ps     249.1mV    233.7mV    257.5mV
369ps     249.9mV    233.7mV    280.8mV
470ps     273.4mV    233.7mV    184.9mV
593ps     168mV      243.2mV    126mV
684ps     123.2mV    260.2mV    101.4mV
929ps     70.38mV    119.6mV    63.7mV
1.36ns    35.66mV    47.32mV    35.13mV
2.274ns   13.52mV    14.86mV    14.63mV
20ns      323.7uV    575.3uV    483.4uV
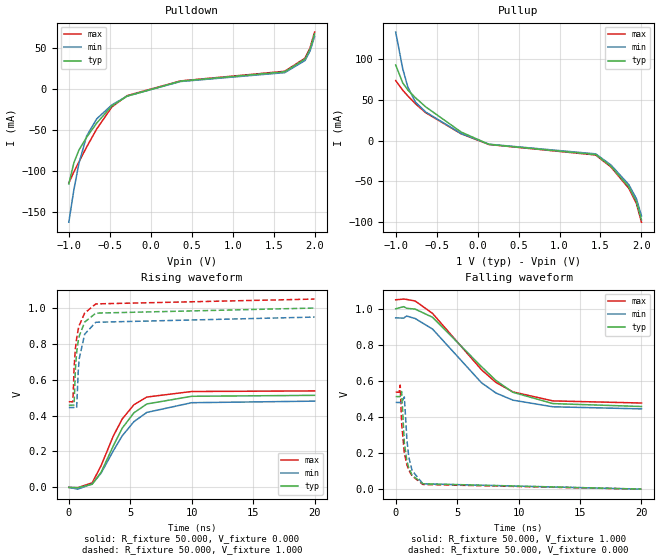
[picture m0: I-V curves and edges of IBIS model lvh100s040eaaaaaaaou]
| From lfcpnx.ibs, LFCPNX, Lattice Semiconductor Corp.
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[Model] lvh100s040eaaaaaaaou
Model_type Output
Polarity   Non-Inverting
Enable   Active-High
Vmeas =  0.500V
Cref =  0.0F
Rref =  1.000M
Vref =  0.0V
C_comp   5.000pF   4.000pF   5.500pF
[Temperature Range]   25.000   0.125k   -40.000
[Voltage Range]   1.000V   0.950V   1.050V
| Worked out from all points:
|   slope of the pulldown table from 0 to 0.15 V, typ, clamps not added: 35.4 ohm
|   slope of the pullup table from 0 to 0.15 V, typ, clamps not added: 30.4 ohm
|   rising waveform, R_fixture 50.000, V_fixture 0.000: 20-80 % time 2.46ns typ, 2.83ns min, 2.32ns max; typ from 0 V to 0.513 V
|   rising waveform, R_fixture 50.000, V_fixture 1.000: 20-80 % time 572ps typ, 545ps min, 614ps max; typ from 0.458 V to 1 V
|   falling waveform, R_fixture 50.000, V_fixture 1.000: 20-80 % time 4.79ns typ, 4.26ns min, 4.61ns max; typ from 1 V to 0.458 V
|   falling waveform, R_fixture 50.000, V_fixture 0.000: 20-80 % time 570ps typ, 558ps min, 612ps max; typ from 0.513 V to 0 V
[Pulldown]
|Voltage   I(typ)   I(min)   I(max)
-1V       -115.6mA   -162mA     -114.4mA
-938mV    -89.86mA   -122.5mA   -100.9mA
-876mV    -74.31mA   -90.37mA   -88.63mA
-783mV    -59mA      -57.52mA   -70.87mA
-659mV    -41.64mA   -36.46mA   -48.76mA
-473mV    -20.76mA   -19.54mA   -21.98mA
-287mV    -8.973mA   -8.905mA   -8.289mA
364mV     9.225mA    8.764mA    9.502mA
1.635V    20.55mA    19.53mA    21.17mA
1.883V    36mA       34.2mA     37.08mA
1.945V    48.34mA    45.92mA    49.79mA
2V        66.76mA    63.42mA    68.76mA
[Pullup]
|Voltage   I(typ)   I(min)   I(max)
-1V       93.11mA    133.6mA    73.95mA
-914mV    71.08mA    88.51mA    62.13mA
-852mV    62.37mA    66mA       55.11mA
-759mV    52.81mA    47.45mA    45.45mA
-635mV    41.68mA    35.34mA    34.45mA
-201mV    10.63mA    8.725mA    8.452mA
140mV     -4.601mA   -4.371mA   -4.739mA
1.442V    -17.12mA   -16.26mA   -17.63mA
1.628V    -31.55mA   -29.97mA   -32.49mA
1.845V    -56.85mA   -54.01mA   -58.56mA
1.938V    -75.02mA   -71.27mA   -77.27mA
2V        -97.38mA   -92.51mA   -100.3mA
[Ramp]
| variable   typ   min   max
dV/dt_r   0.298/2.439n   0.288/2.812n   0.323/2.332n
dV/dt_f   0.324/4.811n   0.303/4.274n   0.344/4.620n
R_load = 50.000
[Rising Waveform]
R_fixture = 50.000
V_fixture = 0.000
V_fixture_min = 0.000
V_fixture_max = 0.000
|  time   V(typ)   V(min)   V(max)
0s        21.02uV    46.25uV    -261.1uV
725ps     -1.99mV    -10.14mV   -1.692mV
1.901ns   17.25mV    19.16mV    25.13mV
2.62ns    83.21mV    78.68mV    119.8mV
3.624ns   231.9mV    204mV      286.8mV
4.351ns   330.5mV    287.8mV    381.7mV
5.3ns     415.8mV    366.5mV    460.9mV
6.35ns    465mV      417.9mV    503.6mV
9.999ns   507.8mV    472mV      534.5mV
20ns      513.1mV    480.8mV    537.8mV
[Rising Waveform]
R_fixture = 50.000
V_fixture = 1.000
V_fixture_min = 0.950
V_fixture_max = 1.050
|  time   V(typ)   V(min)   V(max)
0s        458.1mV    445mV      477.5mV
336ps     458.5mV    445.1mV    477.1mV
426ps     458.9mV    445.2mV    662.5mV
538ps     660.8mV    444.1mV    775mV
636ps     751.3mV    443.4mV    831mV
768ps     817mV      647mV      881.4mV
845ps     843.1mV    716.6mV    902.8mV
1.288ns   921.4mV    853.9mV    971.7mV
2.195ns   971.5mV    920.6mV    1.023V
20ns      999.9mV    949.6mV    1.05V
[Falling Waveform]
R_fixture = 50.000
V_fixture = 1.000
V_fixture_min = 0.950
V_fixture_max = 1.050
|  time   V(typ)   V(min)   V(max)
0s        999.9mV    949.6mV    1.05V
643ps     1.012V     948.4mV    1.054V
894ps     1.003V     959.8mV    1.052V
1.591ns   998.1mV    946mV      1.043V
3.003ns   952.8mV    887.4mV    974.1mV
6.985ns   679mV      589.6mV    661.7mV
8.166ns   601.9mV    532.8mV    591.3mV
9.535ns   537.1mV    493.4mV    539.3mV
12.79ns   474.3mV    456.6mV    489.2mV
20ns      458.1mV    445mV      477.5mV
[Falling Waveform]
R_fixture = 50.000
V_fixture = 0.000
V_fixture_min = 0.000
V_fixture_max = 0.000
|  time   V(typ)   V(min)   V(max)
0s        513.1mV    480.8mV    537.8mV
283ps     513mV      480.5mV    537.2mV
370ps     514mV      480.3mV    576.8mV
482ps     541.2mV    480mV      364.8mV
704ps     256.5mV    511.2mV    200mV
914ps     155.3mV    272.5mV    134.3mV
1.072ns   115.9mV    175.7mV    104.8mV
1.334ns   78.05mV    103.3mV    73.14mV
2.214ns   29.68mV    29.4mV     25.84mV
20ns      21.02uV    46.25uV    -261.1uV
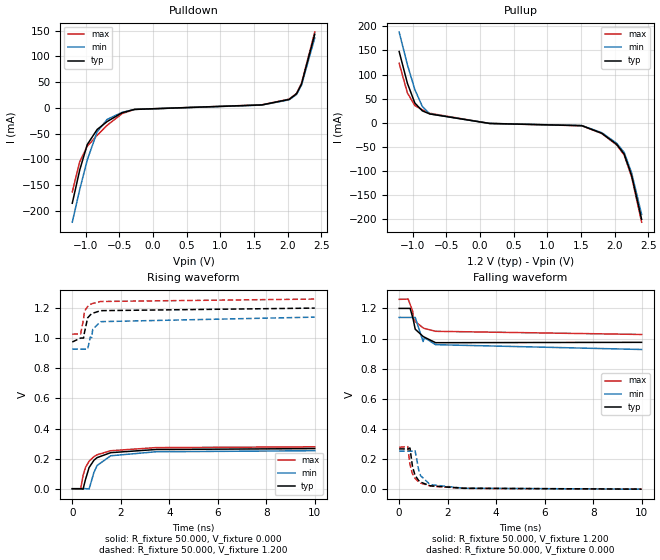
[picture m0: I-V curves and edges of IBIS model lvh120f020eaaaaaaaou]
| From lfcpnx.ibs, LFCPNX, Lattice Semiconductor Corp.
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[Model] lvh120f020eaaaaaaaou
Model_type Output
Polarity   Non-Inverting
Enable   Active-High
Vmeas =  0.600V
Cref =  0.0F
Rref =  1.000M
Vref =  0.0V
C_comp   5.000pF   4.000pF   5.500pF
[Temperature Range]   25.000   0.125k   -40.000
[Voltage Range]   1.200V   1.140V   1.260V
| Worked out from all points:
|   slope of the pulldown table from 0 to 0.18 V, typ, clamps not added: 111 ohm
|   slope of the pullup table from 0 to 0.18 V, typ, clamps not added: 83.3 ohm
|   rising waveform, R_fixture 50.000, V_fixture 0.000: 20-80 % time 558ps typ, 540ps min, 580ps max; typ from 0 V to 0.267 V
|   rising waveform, R_fixture 50.000, V_fixture 1.200: 20-80 % time 257ps typ, 328ps min, 261ps max; typ from 0.975 V to 1.2 V
|   falling waveform, R_fixture 50.000, V_fixture 1.200: 20-80 % time 384ps typ, 574ps min, 478ps max; typ from 1.2 V to 0.975 V
|   falling waveform, R_fixture 50.000, V_fixture 0.000: 20-80 % time 333ps typ, 335ps min, 346ps max; typ from 0.268 V to 0 V
[Pulldown]
|Voltage   I(typ)   I(min)   I(max)
-1.2V     -185.3mA   -222.1mA   -163.3mA
-1.089V   -120.6mA   -158.4mA   -104.5mA
-978mV    -71.42mA   -101.4mA   -74.7mA
-830mV    -41.93mA   -46.38mA   -53.32mA
-682mV    -26.66mA   -22.43mA   -33.9mA
-460mV    -9.51mA    -8.803mA   -11.2mA
-275mV    -3.015mA   -3.114mA   -3.102mA
1.612V    5.611mA    5.331mA    5.78mA
2.019V    16.35mA    15.54mA    16.84mA
2.13V     27.3mA     25.94mA    28.12mA
2.204V    46.58mA    44.25mA    47.97mA
2.4V      142.8mA    135.7mA    147.1mA
[Pullup]
|Voltage   I(typ)   I(min)   I(max)
-1.2V     147.9mA    188.3mA    123.4mA
-1.078V   81.98mA    120.7mA    61.86mA
-967mV    40.71mA    68.74mA    35.5mA
-856mV    24.43mA    33.62mA    26.44mA
-745mV    18mA       18.14mA    19.39mA
143mV     -1.765mA   -1.677mA   -1.818mA
1.512V    -6.404mA   -6.084mA   -6.596mA
1.808V    -22.05mA   -20.95mA   -22.71mA
2.03V     -45.24mA   -42.98mA   -46.59mA
2.141V    -65.38mA   -62.11mA   -67.34mA
2.252V    -110.3mA   -104.8mA   -113.6mA
2.4V      -201.2mA   -191.1mA   -207.2mA
[Ramp]
| variable   typ   min   max
dV/dt_r   0.168/0.561n   0.149/0.547n   0.166/0.579n
dV/dt_f   0.135/0.556n   0.128/0.571n   0.140/0.621n
R_load = 50.000
[Rising Waveform]
R_fixture = 50.000
V_fixture = 0.000
V_fixture_min = 0.000
V_fixture_max = 0.000
|  time   V(typ)   V(min)   V(max)
0s        7.053uV    234.5uV    296.9uV
346ps     204.4uV    345.1uV    -1.855mV
445ps     -2.867mV   283.6uV    87.23mV
543ps     60.12mV    460.6uV    140.8mV
694ps     140.9mV    -1.314mV   182.9mV
895ps     189.7mV    108.8mV    213.4mV
1.024ns   206.7mV    154.4mV    225.6mV
1.584ns   239.6mV    218.9mV    252.5mV
3.44ns    260.5mV    245.6mV    273.1mV
10ns      266.7mV    252.5mV    278.5mV
[Rising Waveform]
R_fixture = 50.000
V_fixture = 1.200
V_fixture_min = 1.140
V_fixture_max = 1.260
|  time   V(typ)   V(min)   V(max)
0s        974.8mV    927.3mV    1.027V
343ps     1.001V     927.5mV    1.028V
467ps     1.001V     927.5mV    1.128V
498ps     1.034V     927.4mV    1.179V
634ps     1.135V     927.3mV    1.21V
745ps     1.155V     1.008V     1.224V
798ps     1.162V     1.003V     1.228V
844ps     1.166V     1.06V      1.231V
1.173ns   1.183V     1.11V      1.244V
10ns      1.2V       1.14V      1.26V
[Falling Waveform]
R_fixture = 50.000
V_fixture = 1.200
V_fixture_min = 1.140
V_fixture_max = 1.260
|  time   V(typ)   V(min)   V(max)
0s        1.2V       1.14V      1.26V
370ps     1.2V       1.14V      1.262V
454ps     1.2V       1.14V      1.226V
564ps     1.136V     1.14V      1.179V
574ps     1.131V     1.14V      1.136V
663ps     1.062V     1.14V      1.113V
985ps     1.014V     980mV      1.071V
1.043ns   1.009V     1.006V     1.067V
1.503ns   972.4mV    959.3mV    1.048V
10ns      974.8mV    927.3mV    1.027V
[Falling Waveform]
R_fixture = 50.000
V_fixture = 0.000
V_fixture_min = 0.000
V_fixture_max = 0.000
|  time   V(typ)   V(min)   V(max)
0s        267.5mV    252.5mV    278.5mV
356ps     267.3mV    252.2mV    282.6mV
446ps     273.4mV    252.4mV    163mV
548ps     152.4mV    253mV      102.4mV
653ps     93.21mV    259.8mV    72.11mV
803ps     57.79mV    130.7mV    48.65mV
883ps     47.07mV    89.97mV    40.84mV
1.278ns   22.55mV    30.48mV    21.24mV
2.673ns   6.391mV    6.288mV    5.393mV
10ns      464uV      234.5uV    296.9uV
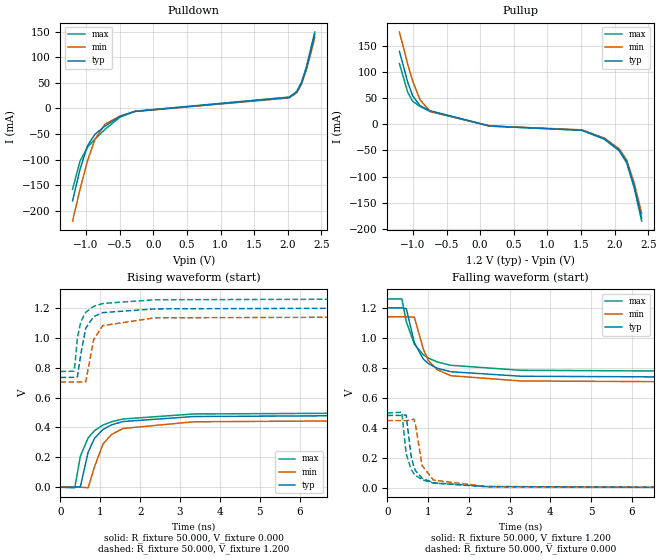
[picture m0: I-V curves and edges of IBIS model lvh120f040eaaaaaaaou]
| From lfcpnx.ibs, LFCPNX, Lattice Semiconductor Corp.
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[Model] lvh120f040eaaaaaaaou
Model_type Output
Polarity   Non-Inverting
Enable   Active-High
Vmeas =  0.600V
Cref =  0.0F
Rref =  1.000M
Vref =  0.0V
C_comp   5.000pF   4.000pF   5.500pF
[Temperature Range]   25.000   0.125k   -40.000
[Voltage Range]   1.200V   1.140V   1.260V
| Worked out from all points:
|   slope of the pulldown table from 0 to 0.18 V, typ, clamps not added: 51.8 ohm
|   slope of the pullup table from 0 to 0.18 V, typ, clamps not added: 44.8 ohm
|   rising waveform, R_fixture 50.000, V_fixture 0.000: 20-80 % time 490ps typ, 501ps min, 533ps max; typ from 0 V to 0.483 V
|   rising waveform, R_fixture 50.000, V_fixture 1.200: 20-80 % time 229ps typ, 250ps min, 235ps max; typ from 0.735 V to 1.2 V
|   falling waveform, R_fixture 50.000, V_fixture 1.200: 20-80 % time 467ps typ, 449ps min, 541ps max; typ from 1.2 V to 0.735 V
|   falling waveform, R_fixture 50.000, V_fixture 0.000: 20-80 % time 221ps typ, 234ps min, 242ps max; typ from 0.483 V to 0 V
[Pulldown]
|Voltage   I(typ)   I(min)   I(max)
-1.2V     -180.2mA   -219.5mA   -157.6mA
-1.089V   -118.7mA   -157.5mA   -102.6mA
-978mV    -72.85mA   -102.3mA   -75.46mA
-867mV    -50.28mA   -60.01mA   -59.99mA
-719mV    -34.47mA   -30.88mA   -40.86mA
-497mV    -15.93mA   -14.83mA   -17.14mA
-275mV    -5.882mA   -5.851mA   -5.411mA
2.019V    21.52mA    20.44mA    22.16mA
2.13V     31.72mA    30.13mA    32.67mA
2.204V    49.93mA    47.44mA    51.43mA
2.278V    79.85mA    75.86mA    82.25mA
2.4V      144.7mA    137.5mA    149mA
[Pullup]
|Voltage   I(typ)   I(min)   I(max)
-1.2V     139.7mA    176.6mA    116.1mA
-1.078V   80.9mA     115.4mA    61.64mA
-1.004V   54.85mA    83mA       44.23mA
-893mV    35.47mA    46.56mA    33.97mA
-745mV    25.91mA    25.06mA    24.48mA
143mV     -3.287mA   -3.123mA   -3.386mA
1.512V    -11.26mA   -10.7mA    -11.6mA
1.845V    -27.67mA   -26.29mA   -28.5mA
2.067V    -49.35mA   -46.88mA   -50.83mA
2.178V    -71.98mA   -68.38mA   -74.14mA
2.289V    -118mA     -112.1mA   -121.5mA
2.4V      -179.7mA   -170.7mA   -185.1mA
[Ramp]
| variable   typ   min   max
dV/dt_r   0.287/0.491n   0.269/0.509n   0.300/0.541n
dV/dt_f   0.279/0.468n   0.262/0.448n   0.307/0.541n
R_load = 50.000
[Rising Waveform]
R_fixture = 50.000
V_fixture = 0.000
V_fixture_min = 0.000
V_fixture_max = 0.000
|  time   V(typ)   V(min)   V(max)
0s        32.99uV    76.35uV    -346.6uV
359ps     414.7uV    128.5uV    -4.174mV
500ps     4.128mV    232uV      208mV
695ps     234.3mV    -3.626mV   330.2mV
855ps     327.4mV    137.3mV    378.6mV
1.07ns    386.9mV    289.6mV    416.1mV
1.281ns   417.1mV    352.8mV    438mV
1.571ns   439.4mV    392.9mV    456.4mV
3.343ns   473mV      437.8mV    490mV
10ns      482.6mV    448.3mV    499mV
[Rising Waveform]
R_fixture = 50.000
V_fixture = 1.200
V_fixture_min = 1.140
V_fixture_max = 1.260
|  time   V(typ)   V(min)   V(max)
0s        734.7mV    703.5mV    774.3mV
336ps     734.9mV    703.6mV    775.8mV
359ps     734.2mV    703.6mV    807.6mV
426ps     738.8mV    703.6mV    1V
509ps     888mV      703.3mV    1.107V
635ps     1.064V     705.9mV    1.17V
832ps     1.141V     985.4mV    1.21V
1.06ns    1.168V     1.081V     1.229V
2.365ns   1.193V     1.133V     1.254V
10ns      1.2V       1.14V      1.26V
[Falling Waveform]
R_fixture = 50.000
V_fixture = 1.200
V_fixture_min = 1.140
V_fixture_max = 1.260
|  time   V(typ)   V(min)   V(max)
0s        1.2V       1.14V      1.26V
356ps     1.2V       1.14V      1.26V
467ps     1.194V     1.14V      1.107V
663ps     967.7mV    1.138V     957.8mV
883ps     858.5mV    925.3mV    888mV
1.007ns   828.6mV    849.2mV    865.3mV
1.223ns   797.6mV    787.8mV    839.6mV
1.557ns   774mV      747.6mV    817.1mV
3.271ns   744.2mV    712.5mV    783.7mV
10ns      734.7mV    703.5mV    774.3mV
[Falling Waveform]
R_fixture = 50.000
V_fixture = 0.000
V_fixture_min = 0.000
V_fixture_max = 0.000
|  time   V(typ)   V(min)   V(max)
0s        482.6mV    448.3mV    499mV
356ps     482.5mV    448.1mV    503.9mV
461ps     486.2mV    448.1mV    229.4mV
581ps     217.1mV    452.2mV    123.6mV
653ps     137.7mV    458.3mV    94.43mV
693ps     113.8mV    419.2mV    82.8mV
854ps     64.13mV    147.6mV    53.48mV
1.133ns   33.17mV    51.25mV    31.22mV
2.433ns   8.337mV    8.301mV    7.134mV
10ns      32.99uV    76.35uV    -346.6uV
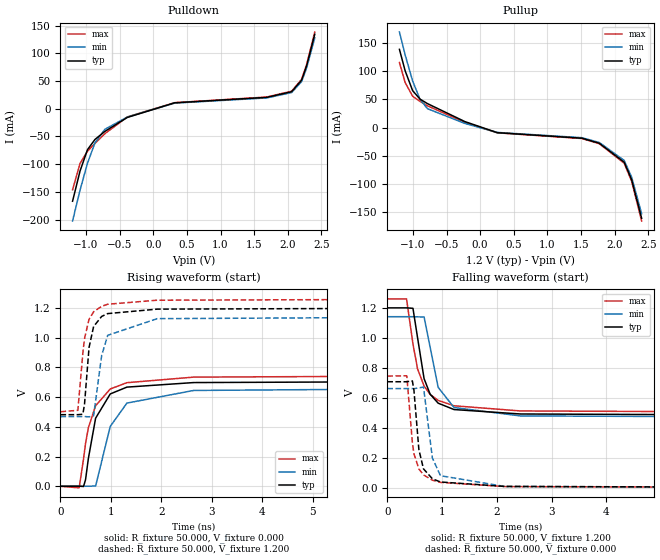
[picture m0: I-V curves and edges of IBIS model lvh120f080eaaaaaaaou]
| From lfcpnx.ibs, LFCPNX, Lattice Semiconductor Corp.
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[Model] lvh120f080eaaaaaaaou
Model_type Output
Polarity   Non-Inverting
Enable   Active-High
Vmeas =  0.600V
Cref =  0.0F
Rref =  1.000M
Vref =  0.0V
C_comp   5.000pF   4.000pF   5.500pF
[Temperature Range]   25.000   0.125k   -40.000
[Voltage Range]   1.200V   1.140V   1.260V
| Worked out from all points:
|   slope of the pulldown table from 0 to 0.18 V, typ, clamps not added: 28.1 ohm
|   slope of the pullup table from 0 to 0.18 V, typ, clamps not added: 26.4 ohm
|   rising waveform, R_fixture 50.000, V_fixture 0.000: 20-80 % time 298ps typ, 418ps min, 351ps max; typ from 0 V to 0.707 V
|   rising waveform, R_fixture 50.000, V_fixture 1.200: 20-80 % time 145ps typ, 201ps min, 165ps max; typ from 0.481 V to 1.2 V
|   falling waveform, R_fixture 50.000, V_fixture 1.200: 20-80 % time 247ps typ, 262ps min, 297ps max; typ from 1.2 V to 0.481 V
|   falling waveform, R_fixture 50.000, V_fixture 0.000: 20-80 % time 137ps typ, 156ps min, 148ps max; typ from 0.707 V to 0 V
[Pulldown]
|Voltage   I(typ)   I(min)   I(max)
-1.2V     -166.9mA   -202.6mA   -146.3mA
-1.089V   -112.5mA   -147.1mA   -98.8mA
-978mV    -73.85mA   -98.2mA    -76.62mA
-867mV    -55.49mA   -61.71mA   -62.62mA
-719mV    -40.9mA    -37.09mA   -45mA
-386mV    -15.77mA   -15.06mA   -14.81mA
317mV     10.59mA    10.06mA    10.91mA
1.686V    20.44mA    19.42mA    21.06mA
2.056V    30.64mA    29.1mA     31.55mA
2.204V    51.44mA    48.87mA    52.99mA
2.278V    76.9mA     73.1mA     79.2mA
2.4V      134.3mA    127.6mA    138.3mA
[Pullup]
|Voltage   I(typ)   I(min)   I(max)
-1.2V     138.9mA    169.7mA    115.5mA
-1.115V   100.8mA    129.1mA    80mA
-1.004V   65.58mA    82.7mA     55.68mA
-893mV    50.42mA    49.87mA    46.37mA
-782mV    42.45mA    33.45mA    38.57mA
-227mV    10.6mA     7.326mA    9.265mA
254mV     -9.081mA   -8.627mA   -9.354mA
1.512V    -18.91mA   -17.97mA   -19.48mA
1.771V    -27.88mA   -26.49mA   -28.72mA
2.141V    -61.54mA   -58.46mA   -63.39mA
2.252V    -92.9mA    -88.3mA    -95.7mA
2.4V      -161.2mA   -153.1mA   -166mA
[Ramp]
| variable   typ   min   max
dV/dt_r   0.424/0.301n   0.383/0.422n   0.447/0.351n
dV/dt_f   0.431/0.249n   0.403/0.264n   0.456/0.295n
R_load = 50.000
[Rising Waveform]
R_fixture = 50.000
V_fixture = 0.000
V_fixture_min = 0.000
V_fixture_max = 0.000
|  time   V(typ)   V(min)   V(max)
0s        40.99uV    -102.1uV   -537uV
371ps     692.1uV    -94.63uV   -10.71mV
457ps     -1.61mV    -66.19uV   182.6mV
497ps     43.23mV    87.82uV    286.5mV
554ps     188.2mV    472.8uV    394.3mV
697ps     457.9mV    1.512mV    541.7mV
987ps     620.8mV    402.7mV    654.1mV
1.317ns   666.6mV    559.2mV    696.4mV
2.64ns    697.2mV    644.1mV    733.8mV
10ns      707.3mV    661.8mV    745.1mV
[Rising Waveform]
R_fixture = 50.000
V_fixture = 1.200
V_fixture_min = 1.140
V_fixture_max = 1.260
|  time   V(typ)   V(min)   V(max)
0s        481.2mV    468.3mV    500.9mV
345ps     481.3mV    468.4mV    510.7mV
444ps     484.1mV    468.5mV    895.9mV
477ps     552.1mV    468.5mV    993.8mV
567ps     933.7mV    466.7mV    1.123V
657ps     1.074V     473.5mV    1.173V
817ps     1.142V     879.9mV    1.21V
937ps     1.161V     1.015V     1.224V
1.918ns   1.191V     1.127V     1.251V
10ns      1.2V       1.141V     1.26V
[Falling Waveform]
R_fixture = 50.000
V_fixture = 1.200
V_fixture_min = 1.140
V_fixture_max = 1.260
|  time   V(typ)   V(min)   V(max)
0s        1.2V       1.141V     1.26V
351ps     1.2V       1.141V     1.26V
468ps     1.197V     1.141V     959.3mV
552ps     1.001V     1.14V      793.1mV
671ps     727.8mV    1.139V     678.7mV
782ps     623.9mV    936.6mV    622.7mV
928ps     564.3mV    669.7mV    582.5mV
1.218ns   521.7mV    535.1mV    546.8mV
2.432ns   492.1mV    479.2mV    512.4mV
10ns      481.2mV    468.3mV    500.9mV
[Falling Waveform]
R_fixture = 50.000
V_fixture = 0.000
V_fixture_min = 0.000
V_fixture_max = 0.000
|  time   V(typ)   V(min)   V(max)
0s        707.3mV    661.8mV    745.1mV
356ps     707.1mV    661.5mV    746.8mV
457ps     712.9mV    661.6mV    302.1mV
486ps     650.5mV    661.3mV    226.7mV
576ps     254.8mV    665.9mV    125.6mV
660ps     126.3mV    672.1mV    85.82mV
822ps     60.22mV    199.6mV    50.59mV
970ps     38.53mV    80.47mV    35.92mV
2.141ns   8.943mV    8.847mV    7.991mV
10ns      40.99uV    -102.1uV   -537uV
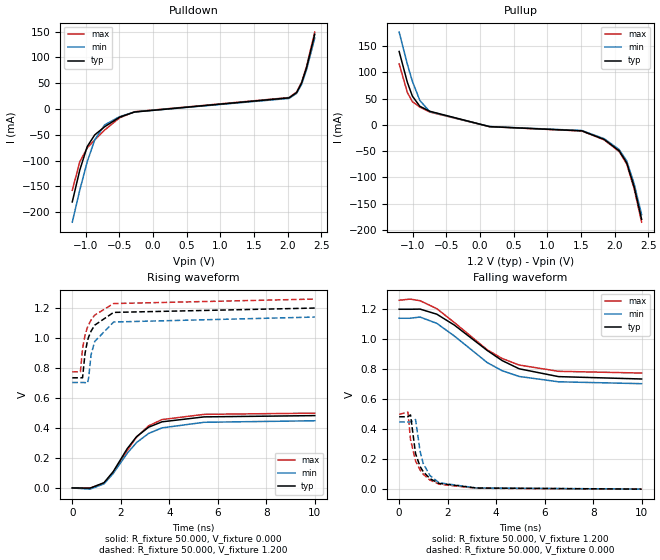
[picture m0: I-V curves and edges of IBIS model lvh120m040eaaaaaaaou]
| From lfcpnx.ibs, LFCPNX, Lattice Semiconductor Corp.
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[Model] lvh120m040eaaaaaaaou
Model_type Output
Polarity   Non-Inverting
Enable   Active-High
Vmeas =  0.600V
Cref =  0.0F
Rref =  1.000M
Vref =  0.0V
C_comp   5.000pF   4.000pF   5.500pF
[Temperature Range]   25.000   0.125k   -40.000
[Voltage Range]   1.200V   1.140V   1.260V
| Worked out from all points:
|   slope of the pulldown table from 0 to 0.18 V, typ, clamps not added: 51.8 ohm
|   slope of the pullup table from 0 to 0.18 V, typ, clamps not added: 44.8 ohm
|   rising waveform, R_fixture 50.000, V_fixture 0.000: 20-80 % time 1.33ns typ, 1.44ns min, 1.34ns max; typ from 0 V to 0.483 V
|   rising waveform, R_fixture 50.000, V_fixture 1.200: 20-80 % time 551ps typ, 510ps min, 599ps max; typ from 0.735 V to 1.2 V
|   falling waveform, R_fixture 50.000, V_fixture 1.200: 20-80 % time 2.42ns typ, 2.2ns min, 2.36ns max; typ from 1.2 V to 0.735 V
|   falling waveform, R_fixture 50.000, V_fixture 0.000: 20-80 % time 543ps typ, 498ps min, 567ps max; typ from 0.483 V to 0 V
[Pulldown]
|Voltage   I(typ)   I(min)   I(max)
-1.2V     -180.2mA   -219.5mA   -157.6mA
-1.089V   -118.7mA   -157.5mA   -102.6mA
-978mV    -72.85mA   -102.3mA   -75.46mA
-867mV    -50.28mA   -60.01mA   -59.99mA
-719mV    -34.47mA   -30.88mA   -40.86mA
-497mV    -15.93mA   -14.83mA   -17.14mA
-275mV    -5.882mA   -5.85mA    -5.411mA
2.019V    21.52mA    20.44mA    22.16mA
2.13V     31.72mA    30.13mA    32.67mA
2.204V    49.93mA    47.44mA    51.43mA
2.278V    79.85mA    75.86mA    82.25mA
2.4V      144.7mA    137.5mA    149mA
[Pullup]
|Voltage   I(typ)   I(min)   I(max)
-1.2V     139.7mA    176.6mA    116.1mA
-1.078V   80.9mA     115.4mA    61.64mA
-1.004V   54.85mA    83mA       44.23mA
-893mV    35.47mA    46.56mA    33.97mA
-745mV    25.91mA    25.06mA    24.48mA
143mV     -3.287mA   -3.123mA   -3.386mA
1.512V    -11.26mA   -10.7mA    -11.6mA
1.845V    -27.67mA   -26.29mA   -28.5mA
2.067V    -49.35mA   -46.88mA   -50.83mA
2.178V    -71.98mA   -68.38mA   -74.14mA
2.289V    -118mA     -112.1mA   -121.5mA
2.4V      -179.7mA   -170.7mA   -185.1mA
[Ramp]
| variable   typ   min   max
dV/dt_r   0.287/1.340n   0.269/1.463n   0.300/1.363n
dV/dt_f   0.279/2.515n   0.262/2.303n   0.307/2.448n
R_load = 50.000
[Rising Waveform]
R_fixture = 50.000
V_fixture = 0.000
V_fixture_min = 0.000
V_fixture_max = 0.000
|  time   V(typ)   V(min)   V(max)
0s        32.99uV    76.35uV    -346.6uV
735ps     -1.145mV   -8.077mV   -1.032mV
1.308ns   35.06mV    27.44mV    31.58mV
1.688ns   109mV      96.62mV    100.9mV
2.268ns   262.7mV    231.7mV    250.1mV
2.65ns    341.9mV    302.7mV    339.1mV
3.15ns    405.4mV    363.7mV    414.6mV
3.7ns     441.1mV    400.8mV    456.2mV
5.44ns    474.1mV    438.1mV    491mV
10ns      482.6mV    448.3mV    499mV
[Rising Waveform]
R_fixture = 50.000
V_fixture = 1.200
V_fixture_min = 1.140
V_fixture_max = 1.260
|  time   V(typ)   V(min)   V(max)
0s        734.7mV    703.5mV    774.3mV
336ps     735mV      703.6mV    774.4mV
423ps     734.9mV    703.6mV    929.2mV
528ps     899.7mV    702.8mV    1.021V
625ps     981.2mV    699.6mV    1.071V
675ps     1.007V     734.3mV    1.089V
775ps     1.046V     889.1mV    1.12V
925ps     1.086V     976.9mV    1.153V
1.704ns   1.171V     1.107V     1.23V
10ns      1.2V       1.14V      1.26V
[Falling Waveform]
R_fixture = 50.000
V_fixture = 1.200
V_fixture_min = 1.140
V_fixture_max = 1.260
|  time   V(typ)   V(min)   V(max)
0s        1.2V       1.14V      1.26V
450ps     1.2V       1.14V      1.268V
863ps     1.201V     1.148V     1.257V
1.553ns   1.167V     1.106V     1.204V
2.28ns    1.094V     1.021V     1.111V
3.635ns   924.8mV    844mV      929.4mV
4.244ns   857.9mV    790.2mV    871.8mV
4.948ns   802.9mV    751.6mV    827.9mV
6.57ns    750.6mV    716.1mV    786mV
10ns      734.7mV    703.5mV    774.3mV
[Falling Waveform]
R_fixture = 50.000
V_fixture = 0.000
V_fixture_min = 0.000
V_fixture_max = 0.000
|  time   V(typ)   V(min)   V(max)
0s        482.6mV    448.3mV    499mV
362ps     482.8mV    448mV      513.6mV
468ps     495.1mV    448.1mV    331.1mV
677ps     236.2mV    464.4mV    187.3mV
863ps     151mV      252.3mV    127.9mV
993ps     116.4mV    171.2mV    99.52mV
1.269ns   69.99mV    90.59mV    60.37mV
1.643ns   38.22mV    42.62mV    32.93mV
3.193ns   7.396mV    7.507mV    5.49mV
10ns      32.99uV    76.35uV    -346.6uV
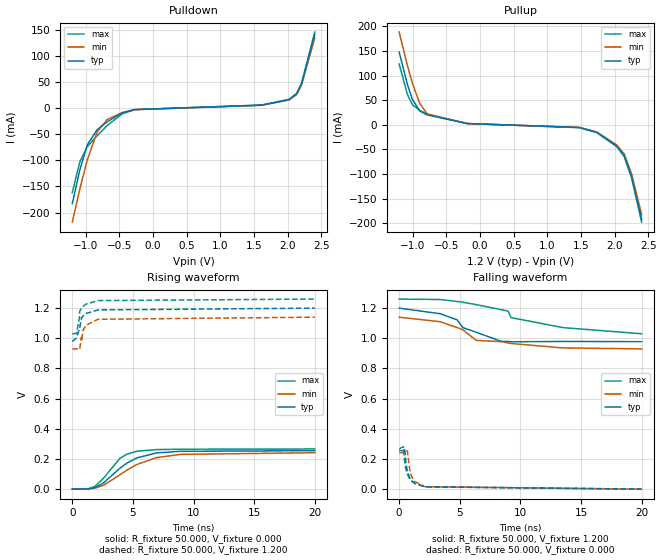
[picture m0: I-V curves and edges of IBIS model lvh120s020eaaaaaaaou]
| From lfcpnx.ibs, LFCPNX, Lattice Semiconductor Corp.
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[Model] lvh120s020eaaaaaaaou
Model_type Output
Polarity   Non-Inverting
Enable   Active-High
Vmeas =  0.600V
Cref =  0.0F
Rref =  1.000M
Vref =  0.0V
C_comp   5.000pF   4.000pF   5.500pF
[Temperature Range]   25.000   0.125k   -40.000
[Voltage Range]   1.200V   1.140V   1.260V
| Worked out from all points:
|   slope of the pulldown table from 0 to 0.18 V, typ, clamps not added: 113 ohm
|   slope of the pullup table from 0 to 0.18 V, typ, clamps not added: 87.1 ohm
|   rising waveform, R_fixture 50.000, V_fixture 0.000: 20-80 % time 2.51ns typ, 3.16ns min, 1.7ns max; typ from 0 V to 0.255 V
|   rising waveform, R_fixture 50.000, V_fixture 1.200: 20-80 % time 477ps typ, 547ps min, 497ps max; typ from 0.978 V to 1.2 V
|   falling waveform, R_fixture 50.000, V_fixture 1.200: 20-80 % time 3.39ns typ, 4.96ns min, 6.19ns max; typ from 1.2 V to 0.978 V
|   falling waveform, R_fixture 50.000, V_fixture 0.000: 20-80 % time 571ps typ, 549ps min, 610ps max; typ from 0.255 V to 0 V
[Pulldown]
|Voltage   I(typ)   I(min)   I(max)
-1.2V     -182.9mA   -218.3mA   -161.8mA
-1.089V   -119mA     -155.7mA   -103.5mA
-978mV    -70.5mA    -99.7mA    -73.97mA
-830mV    -41.39mA   -45.59mA   -52.8mA
-682mV    -26.31mA   -22.05mA   -33.57mA
-460mV    -9.387mA   -8.653mA   -11.09mA
-275mV    -2.976mA   -3.061mA   -3.072mA
1.612V    5.539mA    5.262mA    5.705mA
2.019V    16.14mA    15.34mA    16.63mA
2.13V     26.95mA    25.6mA     27.76mA
2.204V    45.98mA    43.68mA    47.36mA
2.4V      141mA      133.9mA    145.2mA
[Pullup]
|Voltage   I(typ)   I(min)   I(max)
-1.2V     147.9mA    188.3mA    123.4mA
-1.078V   81.98mA    120.7mA    61.86mA
-1.004V   51.59mA    84.61mA    40.82mA
-893mV    27.85mA    43mA       29.06mA
-782mV    19.86mA    21.61mA    21.61mA
-190mV    2.572mA    2.372mA    2.456mA
1.475V    -5.673mA   -5.39mA    -5.843mA
1.734V    -15.38mA   -14.62mA   -15.85mA
2.03V     -43.2mA    -41.04mA   -44.5mA
2.141V    -62.44mA   -59.32mA   -64.31mA
2.252V    -105.4mA   -100.1mA   -108.6mA
2.4V      -192.2mA   -182.6mA   -198mA
[Ramp]
| variable   typ   min   max
dV/dt_r   0.154/2.498n   0.150/3.174n   0.167/1.768n
dV/dt_f   0.133/4.209n   0.126/4.974n   0.138/7.255n
R_load = 50.000
[Rising Waveform]
R_fixture = 50.000
V_fixture = 0.000
V_fixture_min = 0.000
V_fixture_max = 0.000
|  time   V(typ)   V(min)   V(max)
0s        7.053uV    222uV      303.3uV
1.275ns   742.8uV    480.9uV    1.889mV
1.87ns    9.927mV    6.01mV     18.34mV
2.578ns   41.84mV    25.93mV    72.63mV
3.911ns   137.7mV    93.84mV    202.9mV
4.49ns    172.1mV    125.2mV    231.9mV
5.33ns    207.7mV    163.8mV    251.4mV
6.945ns   240.1mV    208.9mV    262.2mV
8.925ns   251.1mV    230.7mV    264.8mV
20ns      255.1mV    241.6mV    266.4mV
[Rising Waveform]
R_fixture = 50.000
V_fixture = 1.200
V_fixture_min = 1.140
V_fixture_max = 1.260
|  time   V(typ)   V(min)   V(max)
0s        977.7mV    930mV      1.03V
345ps     1.004V     930.1mV    1.032V
595ps     1.065V     926.4mV    1.137V
605ps     1.067V     926mV      1.177V
755ps     1.133V     1.005V     1.2V
785ps     1.137V     983mV      1.203V
866ps     1.146V     1.048V     1.21V
1.114ns   1.164V     1.086V     1.226V
2.124ns   1.188V     1.126V     1.25V
20ns      1.2V       1.14V      1.26V
[Falling Waveform]
R_fixture = 50.000
V_fixture = 1.200
V_fixture_min = 1.140
V_fixture_max = 1.260
|  time   V(typ)   V(min)   V(max)
0s        1.2V       1.14V      1.26V
3.379ns   1.163V     1.11V      1.257V
4.781ns   1.122V     1.071V     1.244V
5.25ns    1.071V     1.057V     1.239V
6.351ns   1.04V      986.3mV    1.223V
8.448ns   979.3mV    977.6mV    1.189V
8.98ns    979.3mV    969.2mV    1.18V
9.239ns   976.7mV    965.6mV    1.137V
13.5ns    979.2mV    936.2mV    1.071V
20ns      977.7mV    930mV      1.03V
[Falling Waveform]
R_fixture = 50.000
V_fixture = 0.000
V_fixture_min = 0.000
V_fixture_max = 0.000
|  time   V(typ)   V(min)   V(max)
0s        255.5mV    241.6mV    266.4mV
356ps     255mV      241.4mV    281.8mV
454ps     270.6mV    241.6mV    181.4mV
562ps     175.5mV    243.3mV    130mV
673ps     121.7mV    255mV      100.1mV
874ps     76.33mV    126.8mV    68.23mV
1.043ns   56.01mV    81.69mV    52.34mV
1.273ns   39.46mV    51.93mV    38.55mV
2.123ns   15.32mV    16.52mV    16.47mV
20ns      169.3uV    222uV      303.3uV
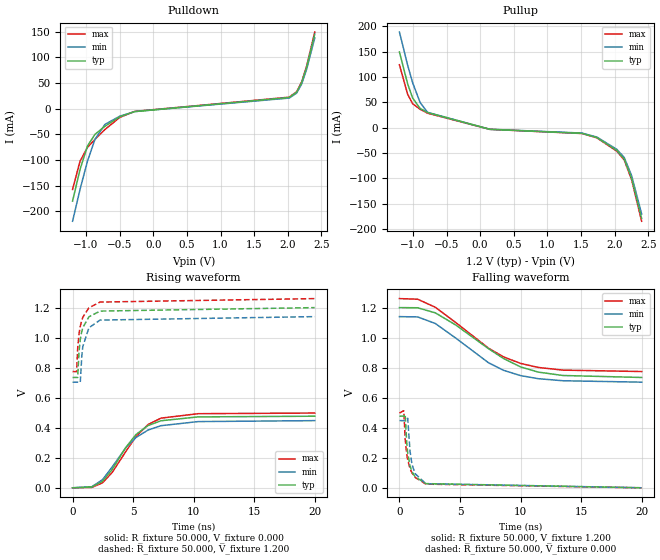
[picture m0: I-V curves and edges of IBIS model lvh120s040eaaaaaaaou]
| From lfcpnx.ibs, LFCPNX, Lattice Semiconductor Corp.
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[Model] lvh120s040eaaaaaaaou
Model_type Output
Polarity   Non-Inverting
Enable   Active-High
Vmeas =  0.600V
Cref =  0.0F
Rref =  1.000M
Vref =  0.0V
C_comp   5.000pF   4.000pF   5.500pF
[Temperature Range]   25.000   0.125k   -40.000
[Voltage Range]   1.200V   1.140V   1.260V
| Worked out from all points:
|   slope of the pulldown table from 0 to 0.18 V, typ, clamps not added: 51.8 ohm
|   slope of the pullup table from 0 to 0.18 V, typ, clamps not added: 44.9 ohm
|   rising waveform, R_fixture 50.000, V_fixture 0.000: 20-80 % time 2.56ns typ, 2.79ns min, 2.63ns max; typ from 0 V to 0.477 V
|   rising waveform, R_fixture 50.000, V_fixture 1.200: 20-80 % time 569ps typ, 545ps min, 614ps max; typ from 0.735 V to 1.2 V
|   falling waveform, R_fixture 50.000, V_fixture 1.200: 20-80 % time 5.14ns typ, 4.6ns min, 4.94ns max; typ from 1.2 V to 0.735 V
|   falling waveform, R_fixture 50.000, V_fixture 0.000: 20-80 % time 563ps typ, 547ps min, 607ps max; typ from 0.477 V to 0 V
[Pulldown]
|Voltage   I(typ)   I(min)   I(max)
-1.2V     -180.2mA   -219.5mA   -157.6mA
-1.089V   -118.7mA   -157.5mA   -102.6mA
-978mV    -72.85mA   -102.3mA   -75.46mA
-867mV    -50.28mA   -60.01mA   -59.99mA
-719mV    -34.47mA   -30.88mA   -40.86mA
-497mV    -15.93mA   -14.83mA   -17.14mA
-275mV    -5.882mA   -5.85mA    -5.411mA
2.019V    21.52mA    20.44mA    22.16mA
2.13V     31.72mA    30.13mA    32.67mA
2.204V    49.93mA    47.44mA    51.43mA
2.278V    79.85mA    75.86mA    82.25mA
2.4V      144.7mA    137.5mA    149mA
[Pullup]
|Voltage   I(typ)   I(min)   I(max)
-1.2V     149.1mA    188.4mA    123.9mA
-1.078V   86.3mA     123.1mA    65.77mA
-1.004V   58.53mA    88.6mA     47.2mA
-893mV    37.85mA    49.68mA    36.25mA
-782mV    29.77mA    30.11mA    28.48mA
143mV     -3.278mA   -3.114mA   -3.376mA
1.512V    -11.23mA   -10.67mA   -11.56mA
1.734V    -19.5mA    -18.53mA   -20.09mA
2.03V     -44.92mA   -42.68mA   -46.27mA
2.141V    -61.82mA   -58.73mA   -63.67mA
2.252V    -100mA     -95mA      -103mA
2.4V      -179.1mA   -170.1mA   -184.5mA
[Ramp]
| variable   typ   min   max
dV/dt_r   0.286/2.573n   0.268/2.778n   0.301/2.658n
dV/dt_f   0.279/5.201n   0.262/4.617n   0.292/4.965n
R_load = 50.000
[Rising Waveform]
R_fixture = 50.000
V_fixture = 0.000
V_fixture_min = 0.000
V_fixture_max = 0.000
|  time   V(typ)   V(min)   V(max)
0s        34.41uV    76.35uV    -346.6uV
1.585ns   5.047mV    6.746mV    2.381mV
2.478ns   43.7mV     54.34mV    33.16mV
3.275ns   122mV      139mV      102.5mV
4.391ns   268.1mV    265.9mV    240.8mV
5.23ns    354.1mV    334.4mV    340.6mV
6.234ns   414.6mV    384.6mV    421.3mV
7.305ns   446.4mV    413.5mV    463.9mV
10.37ns   472.1mV    440.9mV    493.5mV
20ns      476.8mV    447.3mV    497.8mV
[Rising Waveform]
R_fixture = 50.000
V_fixture = 1.200
V_fixture_min = 1.140
V_fixture_max = 1.260
|  time   V(typ)   V(min)   V(max)
0s        734.7mV    703.5mV    774.3mV
333ps     735mV      703.6mV    772.9mV
423ps     734.6mV    703.6mV    928.9mV
534ps     906.9mV    702.5mV    1.025V
635ps     987mV      701.9mV    1.074V
765ps     1.043V     878.5mV    1.117V
847ps     1.067V     941mV      1.136V
1.354ns   1.139V     1.066V     1.199V
2.273ns   1.177V     1.117V     1.237V
20ns      1.2V       1.14V      1.26V
[Falling Waveform]
R_fixture = 50.000
V_fixture = 1.200
V_fixture_min = 1.140
V_fixture_max = 1.260
|  time   V(typ)   V(min)   V(max)
0s        1.2V       1.14V      1.26V
1.506ns   1.199V     1.138V     1.256V
2.969ns   1.165V     1.094V     1.202V
4.673ns   1.083V     995.6mV    1.099V
7.353ns   926.7mV    832.9mV    929.9mV
8.594ns   861mV      782.5mV    871.8mV
10.01ns   804.8mV    746.9mV    828.2mV
11.47ns   770.4mV    726.6mV    801.4mV
13.5ns    747.9mV    712.9mV    783.6mV
20ns      734.7mV    703.5mV    774.3mV
[Falling Waveform]
R_fixture = 50.000
V_fixture = 0.000
V_fixture_min = 0.000
V_fixture_max = 0.000
|  time   V(typ)   V(min)   V(max)
0s        476.8mV    447.3mV    497.8mV
362ps     477mV      447mV      513.6mV
473ps     488.5mV    447mV      325.3mV
603ps     300.3mV    457.5mV    222.6mV
683ps     230.1mV    462.9mV    185.2mV
874ps     146.5mV    243.6mV    128.2mV
1.033ns   108.8mV    157.5mV    99.34mV
1.294ns   73.11mV    94.18mV    69.39mV
2.183ns   27.79mV    27.08mV    24.3mV
20ns      34.41uV    76.35uV    -346.6uV
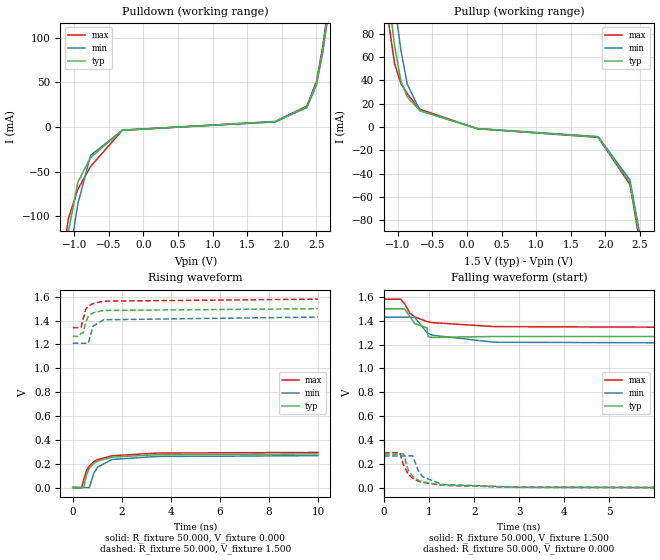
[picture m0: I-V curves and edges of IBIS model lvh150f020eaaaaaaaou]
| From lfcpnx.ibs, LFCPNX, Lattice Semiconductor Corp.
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[Model] lvh150f020eaaaaaaaou
Model_type Output
Polarity   Non-Inverting
Enable   Active-High
Vmeas =  0.750V
Cref =  0.0F
Rref =  1.000M
Vref =  0.0V
C_comp   5.000pF   4.000pF   5.500pF
[Temperature Range]   25.000   0.125k   -40.000
[Voltage Range]   1.500V   1.430V   1.580V
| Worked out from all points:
|   slope of the pulldown table from 0 to 0.225 V, typ, clamps not added: 112 ohm
|   slope of the pullup table from 0 to 0.225 V, typ, clamps not added: 106 ohm
|   rising waveform, R_fixture 50.000, V_fixture 0.000: 20-80 % time 537ps typ, 524ps min, 586ps max; typ from 0 V to 0.282 V
|   rising waveform, R_fixture 50.000, V_fixture 1.500: 20-80 % time 266ps typ, 292ps min, 317ps max; typ from 1.27 V to 1.5 V
|   falling waveform, R_fixture 50.000, V_fixture 1.500: 20-80 % time 428ps typ, 519ps min, 533ps max; typ from 1.5 V to 1.27 V
|   falling waveform, R_fixture 50.000, V_fixture 0.000: 20-80 % time 325ps typ, 334ps min, 346ps max; typ from 0.283 V to 0.001 V
[Pulldown]
|Voltage   I(typ)   I(min)   I(max)
-1.5V     -381.2mA   -398.5mA   -369.5mA
-1.224V   -198.4mA   -231.2mA   -177.7mA
-1.086V   -117.9mA   -153.6mA   -102.9mA
-948mV    -61.75mA   -86mA      -69.76mA
-764mV    -34.4mA    -31.77mA   -44.22mA
-304mV    -3.563mA   -3.619mA   -3.717mA
1.904V    5.917mA    5.621mA    6.094mA
2.364V    22.82mA    21.68mA    23.51mA
2.502V    49.56mA    47.08mA    51.05mA
2.594V    88.3mA     83.9mA     90.9mA
2.732V    165.2mA    156.9mA    170.2mA
3V        335.7mA    318.9mA    345.8mA
[Pullup]
|Voltage   I(typ)   I(min)   I(max)
-1.5V     341.5mA    374.7mA    322.6mA
-1.186V   141.4mA    182mA      117.9mA
-1.14V    115.3mA    155.9mA    92.8mA
-1.048V   69.93mA    107mA      54.61mA
-956mV    39.5mA     65.87mA    37.33mA
-864mV    25.74mA    36.76mA    28.41mA
-680mV    13.85mA    14.01mA    15.12mA
148mV     -1.462mA   -1.389mA   -1.506mA
1.896V    -8.693mA   -8.258mA   -8.954mA
2.356V    -47.92mA   -45.52mA   -49.35mA
2.586V    -126.5mA   -120.2mA   -130.3mA
3V        -409.3mA   -388.8mA   -421.6mA
[Ramp]
| variable   typ   min   max
dV/dt_r   0.170/0.547n   0.160/0.521n   0.173/0.588n
dV/dt_f   0.139/0.556n   0.132/0.590n   0.144/0.634n
R_load = 50.000
[Rising Waveform]
R_fixture = 50.000
V_fixture = 0.000
V_fixture_min = 0.000
V_fixture_max = 0.000
|  time   V(typ)   V(min)   V(max)
0s        31.62uV    250.9uV    321.7uV
361ps     290.4uV    336.5uV    -1.051mV
444ps     -2.472mV   298uV      61.88mV
558ps     104.9mV    451.9uV    140.6mV
676ps     161mV      -768.5uV   181.2mV
856ps     202.3mV    116.4mV    216.2mV
1.008ns   222.2mV    171mV      234.2mV
1.608ns   255.6mV    235.7mV    266.9mV
3.442ns   275.8mV    260.4mV    289mV
10ns      282.2mV    267.5mV    294.9mV
[Rising Waveform]
R_fixture = 50.000
V_fixture = 1.500
V_fixture_min = 1.430
V_fixture_max = 1.580
|  time   V(typ)   V(min)   V(max)
0s        1.268V     1.21V      1.341V
258ps     1.268V     1.211V     1.341V
346ps     1.295V     1.21V      1.344V
434ps     1.298V     1.21V      1.422V
507ps     1.367V     1.21V      1.461V
517ps     1.374V     1.21V      1.491V
636ps     1.439V     1.211V     1.52V
827ps     1.465V     1.353V     1.543V
1.266ns   1.485V     1.407V     1.563V
10ns      1.5V       1.43V      1.58V
[Falling Waveform]
R_fixture = 50.000
V_fixture = 1.500
V_fixture_min = 1.430
V_fixture_max = 1.580
|  time   V(typ)   V(min)   V(max)
0s        1.5V       1.43V      1.58V
369ps     1.5V       1.43V      1.581V
457ps     1.5V       1.43V      1.542V
577ps     1.433V     1.43V      1.462V
684ps     1.377V     1.427V     1.432V
955ps     1.34V      1.3V       1.393V
980ps     1.267V     1.295V     1.391V
1.067ns   1.261V     1.279V     1.384V
2.446ns   1.268V     1.22V      1.351V
10ns      1.268V     1.21V      1.341V
[Falling Waveform]
R_fixture = 50.000
V_fixture = 0.000
V_fixture_min = 0.000
V_fixture_max = 0.000
|  time   V(typ)   V(min)   V(max)
0s        283.1mV    267.5mV    294.9mV
346ps     282.8mV    267.3mV    295.5mV
433ps     285.2mV    267.4mV    192.2mV
536ps     150.1mV    267.7mV    115.4mV
635ps     95.67mV    269.5mV    81.45mV
765ps     63.31mV    140.6mV    56.75mV
855ps     50.11mV    93.42mV    46.08mV
1.295ns   22.48mV    29.17mV    22.02mV
2.993ns   5.449mV    5.395mV    4.536mV
10ns      522.2uV    250.9uV    321.7uV
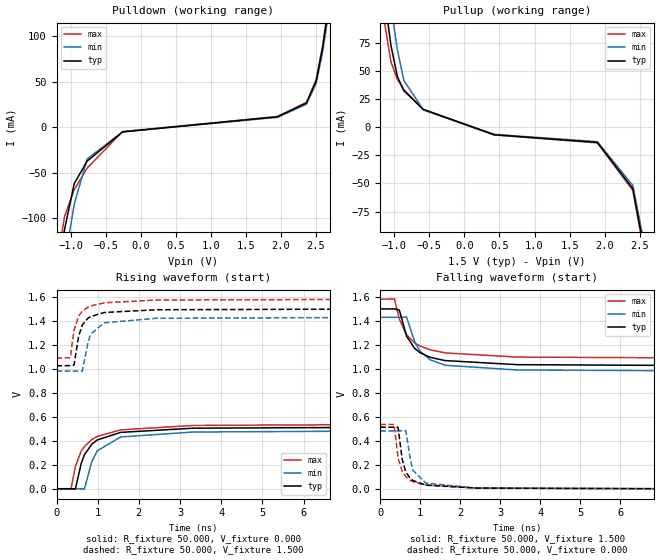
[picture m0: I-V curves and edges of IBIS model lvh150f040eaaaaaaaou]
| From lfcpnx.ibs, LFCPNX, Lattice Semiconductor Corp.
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[Model] lvh150f040eaaaaaaaou
Model_type Output
Polarity   Non-Inverting
Enable   Active-High
Vmeas =  0.750V
Cref =  0.0F
Rref =  1.000M
Vref =  0.0V
C_comp   5.000pF   4.000pF   5.500pF
[Temperature Range]   25.000   0.125k   -40.000
[Voltage Range]   1.500V   1.430V   1.580V
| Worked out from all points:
|   slope of the pulldown table from 0 to 0.225 V, typ, clamps not added: 54.8 ohm
|   slope of the pullup table from 0 to 0.225 V, typ, clamps not added: 56 ohm
|   rising waveform, R_fixture 50.000, V_fixture 0.000: 20-80 % time 484ps typ, 460ps min, 544ps max; typ from 0 V to 0.515 V
|   rising waveform, R_fixture 50.000, V_fixture 1.500: 20-80 % time 234ps typ, 239ps min, 259ps max; typ from 1.02 V to 1.5 V
|   falling waveform, R_fixture 50.000, V_fixture 1.500: 20-80 % time 536ps typ, 520ps min, 594ps max; typ from 1.5 V to 1.02 V
|   falling waveform, R_fixture 50.000, V_fixture 0.000: 20-80 % time 220ps typ, 226ps min, 243ps max; typ from 0.515 V to 0 V
[Pulldown]
|Voltage   I(typ)   I(min)   I(max)
-1.5V     -358.2mA   -381.8mA   -344.9mA
-1.224V   -187.6mA   -222.6mA   -167mA
-1.086V   -112.9mA   -148.8mA   -98.5mA
-948mV    -62.28mA   -85.2mA    -69.02mA
-764mV    -37.5mA    -35.09mA   -45.15mA
-258mV    -5.249mA   -5.157mA   -4.87mA
1.95V     11.37mA    10.8mA     11.71mA
2.364V    26.55mA    25.22mA    27.35mA
2.502V    50.62mA    48.08mA    52.13mA
2.594V    86.8mA     82.5mA     89.4mA
2.732V    159.4mA    151.4mA    164.2mA
3V        321.9mA    305.8mA    331.6mA
[Pullup]
|Voltage   I(typ)   I(min)   I(max)
-1.5V     334.2mA    366.8mA    315.2mA
-1.186V   140.5mA    179.9mA    117.2mA
-1.14V    115.6mA    154.7mA    93.3mA
-1.048V   72.68mA    107.9mA    57.95mA
-956mV    44.92mA    68.74mA    42.37mA
-864mV    32.38mA    41.6mA     33.55mA
-588mV    15.88mA    15.55mA    15.32mA
424mV     -6.746mA   -6.408mA   -6.948mA
1.896V    -13.58mA   -12.9mA    -13.99mA
2.402V    -54.62mA   -51.89mA   -56.26mA
2.586V    -116.3mA   -110.5mA   -119.8mA
3V        -369.7mA   -351.2mA   -380.8mA
[Ramp]
| variable   typ   min   max
dV/dt_r   0.309/0.493n   0.291/0.462n   0.332/0.551n
dV/dt_f   0.285/0.532n   0.269/0.520n   0.295/0.596n
R_load = 50.000
[Rising Waveform]
R_fixture = 50.000
V_fixture = 0.000
V_fixture_min = 0.000
V_fixture_max = 0.000
|  time   V(typ)   V(min)   V(max)
0s        60.93uV    93.6uV     -360.8uV
351ps     323.9uV    151.1uV    -3.396mV
457ps     -2.723mV   137uV      185.4mV
597ps     207.2mV    -426.7uV   311.8mV
677ps     283.8mV    -1.221mV   352.1mV
856ps     371.2mV    225.2mV    409.6mV
988ps     406.6mV    316.3mV    436.1mV
1.557ns   469.8mV    431.5mV    490.6mV
3.321ns   504.8mV    473.1mV    527.9mV
10ns      515.5mV    484.4mV    538.2mV
[Rising Waveform]
R_fixture = 50.000
V_fixture = 1.500
V_fixture_min = 1.430
V_fixture_max = 1.580
|  time   V(typ)   V(min)   V(max)
0s        1.025V     981.1mV    1.089V
336ps     1.026V     981.2mV    1.092V
424ps     1.03V      981.2mV    1.321V
537ps     1.271V     979.8mV    1.439V
627ps     1.366V     981.7mV    1.48V
766ps     1.422V     1.223V     1.514V
827ps     1.435V     1.288V     1.523V
1.156ns   1.469V     1.383V     1.55V
2.427ns   1.492V     1.421V     1.573V
10ns      1.5V       1.43V      1.581V
[Falling Waveform]
R_fixture = 50.000
V_fixture = 1.500
V_fixture_min = 1.430
V_fixture_max = 1.580
|  time   V(typ)   V(min)   V(max)
0s        1.5V       1.43V      1.581V
356ps     1.5V       1.43V      1.582V
477ps     1.489V     1.43V      1.414V
657ps     1.273V     1.432V     1.285V
857ps     1.172V     1.229V     1.218V
987ps     1.137V     1.15V      1.192V
1.246ns   1.097V     1.076V     1.16V
1.619ns   1.07V      1.031V     1.134V
3.416ns   1.036V     991.7mV    1.099V
10ns      1.025V     981.1mV    1.089V
[Falling Waveform]
R_fixture = 50.000
V_fixture = 0.000
V_fixture_min = 0.000
V_fixture_max = 0.000
|  time   V(typ)   V(min)   V(max)
0s        515.5mV    484.4mV    538.2mV
346ps     515.2mV    484.1mV    538.8mV
444ps     515.5mV    484.3mV    259.1mV
547ps     248.8mV    485.2mV    147.5mV
637ps     141.8mV    487.1mV    103.8mV
757ps     86.82mV    235.1mV    71.64mV
817ps     71.31mV    156.4mV    61.33mV
1.137ns   33.57mV    50.02mV    32.85mV
2.407ns   8.947mV    8.867mV    7.836mV
10ns      60.93uV    93.6uV     -360.8uV
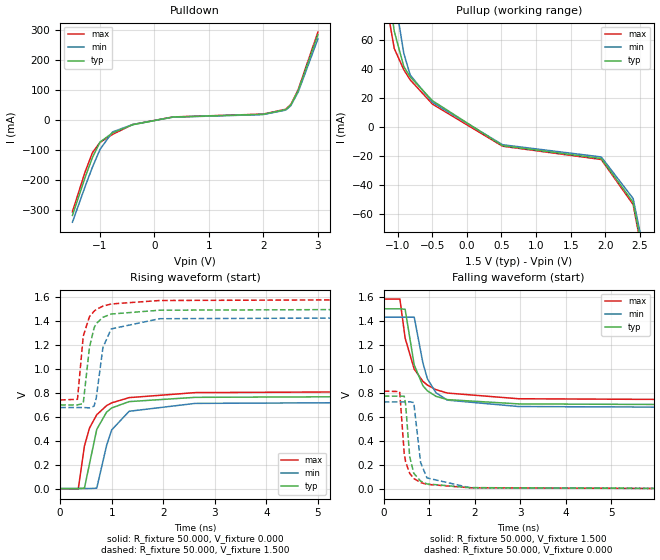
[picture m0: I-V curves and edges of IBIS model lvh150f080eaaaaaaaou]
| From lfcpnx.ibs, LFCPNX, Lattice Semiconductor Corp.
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[Model] lvh150f080eaaaaaaaou
Model_type Output
Polarity   Non-Inverting
Enable   Active-High
Vmeas =  0.750V
Cref =  0.0F
Rref =  1.000M
Vref =  0.0V
C_comp   5.000pF   4.000pF   5.500pF
[Temperature Range]   25.000   0.125k   -40.000
[Voltage Range]   1.500V   1.430V   1.580V
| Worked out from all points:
|   slope of the pulldown table from 0 to 0.225 V, typ, clamps not added: 30.7 ohm
|   slope of the pullup table from 0 to 0.225 V, typ, clamps not added: 34 ohm
|   rising waveform, R_fixture 50.000, V_fixture 0.000: 20-80 % time 311ps typ, 333ps min, 377ps max; typ from 0 V to 0.774 V
|   rising waveform, R_fixture 50.000, V_fixture 1.500: 20-80 % time 163ps typ, 184ps min, 167ps max; typ from 0.698 V to 1.5 V
|   falling waveform, R_fixture 50.000, V_fixture 1.500: 20-80 % time 328ps typ, 329ps min, 417ps max; typ from 1.5 V to 0.698 V
|   falling waveform, R_fixture 50.000, V_fixture 0.000: 20-80 % time 135ps typ, 149ps min, 147ps max; typ from 0.774 V to 0 V
[Pulldown]
|Voltage   I(typ)   I(min)   I(max)
-1.5V     -317.3mA   -339.9mA   -305.2mA
-1.27V    -191.9mA   -222.5mA   -173.7mA
-1.132V   -123.7mA   -156.1mA   -107.8mA
-994mV    -73mA      -97.2mA    -74.1mA
-764mV    -42.16mA   -39.16mA   -47.27mA
-396mV    -15.24mA   -14.44mA   -14.48mA
340mV     10.47mA    9.95mA     10.79mA
1.996V    19.65mA    18.67mA    20.24mA
2.41V     35.42mA    33.65mA    36.48mA
2.502V    50.45mA    47.92mA    51.96mA
2.64V     99.5mA     94.5mA     102.5mA
3V        285mA      270.7mA    293.5mA
[Pullup]
|Voltage   I(typ)   I(min)   I(max)
-1.5V     270.5mA    296.8mA    254.1mA
-1.186V   117.5mA    148.3mA    97.8mA
-1.14V    98.3mA     128.5mA    79.7mA
-1.048V   66.37mA    92mA       54.42mA
-910mV    41.91mA    51.04mA    39.73mA
-818mV    34.79mA    36.11mA    32.74mA
-496mV    18.28mA    17.11mA    15.93mA
516mV     -12.8mA    -12.16mA   -13.19mA
1.942V    -21.71mA   -20.63mA   -22.37mA
2.402V    -51.93mA   -49.34mA   -53.49mA
2.586V    -97.2mA    -92.3mA    -100.1mA
3V        -297.4mA   -282.5mA   -306.3mA
[Ramp]
| variable   typ   min   max
dV/dt_r   0.464/0.312n   0.435/0.337n   0.489/0.376n
dV/dt_f   0.481/0.334n   0.452/0.332n   0.505/0.414n
R_load = 50.000
[Rising Waveform]
R_fixture = 50.000
V_fixture = 0.000
V_fixture_min = 0.000
V_fixture_max = 0.000
|  time   V(typ)   V(min)   V(max)
0s        65.26uV    -124.3uV   -579.3uV
351ps     378.8uV    -101.1uV   -5.088mV
471ps     3.114mV    -49.57uV   354.4mV
569ps     205.1mV    196.5uV    504.7mV
710ps     493.4mV    3.001mV    615.9mV
901ps     637.9mV    359.1mV    691.9mV
1ns       672.5mV    489.2mV    715.1mV
1.339ns   725.5mV    644.9mV    758.6mV
2.62ns    761mV      710.5mV    800.5mV
10ns      773.6mV    725.1mV    815.1mV
[Rising Waveform]
R_fixture = 50.000
V_fixture = 1.500
V_fixture_min = 1.430
V_fixture_max = 1.580
|  time   V(typ)   V(min)   V(max)
0s        697.7mV    676mV      739.1mV
336ps     697.8mV    676.1mV    744.6mV
448ps     710.1mV    676.2mV    1.271V
568ps     1.175V     673.4mV    1.434V
659ps     1.342V     687.9mV    1.48V
701ps     1.376V     757.7mV    1.494V
830ps     1.429V     1.177V     1.522V
990ps     1.456V     1.332V     1.54V
1.928ns   1.488V     1.417V     1.569V
10ns      1.5V       1.43V      1.581V
[Falling Waveform]
R_fixture = 50.000
V_fixture = 1.500
V_fixture_min = 1.430
V_fixture_max = 1.580
|  time   V(typ)   V(min)   V(max)
0s        1.5V       1.43V      1.581V
356ps     1.5V       1.43V      1.581V
471ps     1.496V     1.43V      1.256V
671ps     1.032V     1.43V      998.2mV
862ps     860.2mV    1.049V     896.3mV
961ps     817.2mV    917.2mV    865.3mV
1.151ns   771.6mV    800.7mV    827mV
1.401ns   744.4mV    740.1mV    799mV
2.969ns   708.7mV    686.9mV    751.6mV
10ns      697.7mV    676mV      739.1mV
[Falling Waveform]
R_fixture = 50.000
V_fixture = 0.000
V_fixture_min = 0.000
V_fixture_max = 0.000
|  time   V(typ)   V(min)   V(max)
0s        773.6mV    725.1mV    815.1mV
351ps     773.5mV    724.9mV    811.4mV
451ps     772.6mV    725mV      296.6mV
481ps     708.1mV    724.8mV    227.7mV
571ps     270.1mV    726.9mV    130.7mV
661ps     131.5mV    720mV      88.01mV
811ps     66.54mV    221.8mV    54.52mV
951ps     43.14mV    92.89mV    39.46mV
1.891ns   12.01mV    11.9mV     11.2mV
10ns      65.26uV    -124.3uV   -579.3uV
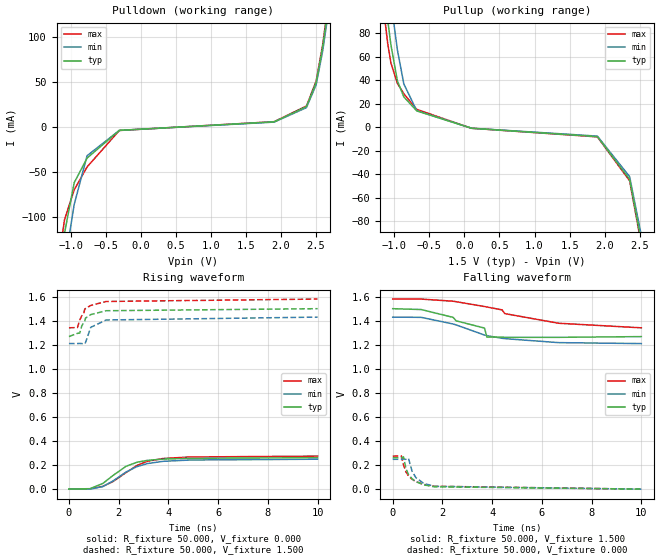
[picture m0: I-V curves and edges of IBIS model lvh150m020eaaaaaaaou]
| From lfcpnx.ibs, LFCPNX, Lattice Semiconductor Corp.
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[Model] lvh150m020eaaaaaaaou
Model_type Output
Polarity   Non-Inverting
Enable   Active-High
Vmeas =  0.750V
Cref =  0.0F
Rref =  1.000M
Vref =  0.0V
C_comp   5.000pF   4.000pF   5.500pF
[Temperature Range]   25.000   0.125k   -40.000
[Voltage Range]   1.500V   1.430V   1.580V
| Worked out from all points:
|   slope of the pulldown table from 0 to 0.225 V, typ, clamps not added: 112 ohm
|   slope of the pullup table from 0 to 0.225 V, typ, clamps not added: 114 ohm
|   rising waveform, R_fixture 50.000, V_fixture 0.000: 20-80 % time 1.11ns typ, 1.27ns min, 1.27ns max; typ from 0 V to 0.261 V
|   rising waveform, R_fixture 50.000, V_fixture 1.500: 20-80 % time 441ps typ, 458ps min, 522ps max; typ from 1.27 V to 1.5 V
|   falling waveform, R_fixture 50.000, V_fixture 1.500: 20-80 % time 1.72ns typ, 2.2ns min, 3.06ns max; typ from 1.5 V to 1.27 V
|   falling waveform, R_fixture 50.000, V_fixture 0.000: 20-80 % time 533ps typ, 522ps min, 603ps max; typ from 0.262 V to 0.001 V
[Pulldown]
|Voltage   I(typ)   I(min)   I(max)
-1.5V     -381.2mA   -398.5mA   -369.5mA
-1.224V   -198.4mA   -231.2mA   -177.7mA
-1.086V   -117.9mA   -153.6mA   -102.9mA
-948mV    -61.75mA   -86mA      -69.76mA
-764mV    -34.4mA    -31.77mA   -44.22mA
-304mV    -3.563mA   -3.619mA   -3.717mA
1.904V    5.917mA    5.621mA    6.094mA
2.364V    22.82mA    21.68mA    23.51mA
2.502V    49.56mA    47.08mA    51.05mA
2.594V    88.3mA     83.9mA     90.9mA
2.732V    165.2mA    156.9mA    170.2mA
3V        335.7mA    318.9mA    345.8mA
[Pullup]
|Voltage   I(typ)   I(min)   I(max)
-1.5V     341.5mA    374.7mA    322.6mA
-1.186V   141.4mA    182mA      117.9mA
-1.094V   91.2mA     130.7mA    71.23mA
-1.048V   69.93mA    107mA      54.61mA
-956mV    39.5mA     65.87mA    37.33mA
-864mV    25.74mA    36.76mA    28.41mA
-680mV    13.85mA    14.01mA    15.12mA
102mV     -952.9uA   -905.3uA   -981.5uA
1.896V    -8.049mA   -7.647mA   -8.291mA
2.356V    -44.37mA   -42.15mA   -45.7mA
2.586V    -117.1mA   -111.2mA   -120.6mA
3V        -379mA     -360mA     -390.4mA
[Ramp]
| variable   typ   min   max
dV/dt_r   0.158/1.150n   0.149/1.295n   0.164/1.302n
dV/dt_f   0.139/2.117n   0.132/2.528n   0.144/3.392n
R_load = 50.000
[Rising Waveform]
R_fixture = 50.000
V_fixture = 0.000
V_fixture_min = 0.000
V_fixture_max = 0.000
|  time   V(typ)   V(min)   V(max)
0s        31.62uV    250.9uV    321.7uV
848ps     3.182mV    -860.3uV   1.504mV
1.367ns   47.24mV    21.15mV    22.57mV
1.777ns   113.8mV    68.19mV    63.11mV
2.297ns   189.3mV    141.8mV    137.1mV
2.729ns   222.7mV    186.2mV    195.6mV
3.16ns    238.7mV    212.3mV    231.2mV
3.781ns   249.1mV    230.6mV    254.2mV
4.868ns   255.8mV    241.5mV    266.8mV
10ns      261.1mV    248.4mV    273.7mV
[Rising Waveform]
R_fixture = 50.000
V_fixture = 1.500
V_fixture_min = 1.430
V_fixture_max = 1.580
|  time   V(typ)   V(min)   V(max)
0s        1.268V     1.21V      1.341V
343ps     1.295V     1.21V      1.343V
434ps     1.297V     1.211V     1.406V
517ps     1.357V     1.21V      1.441V
596ps     1.385V     1.207V     1.461V
636ps     1.394V     1.208V     1.496V
666ps     1.422V     1.218V     1.501V
877ps     1.451V     1.345V     1.527V
1.496ns   1.483V     1.406V     1.56V
10ns      1.5V       1.43V      1.58V
[Falling Waveform]
R_fixture = 50.000
V_fixture = 1.500
V_fixture_min = 1.430
V_fixture_max = 1.580
|  time   V(typ)   V(min)   V(max)
0s        1.5V       1.43V      1.58V
1.145ns   1.493V     1.428V     1.58V
2.427ns   1.428V     1.373V     1.562V
2.554ns   1.399V     1.365V     1.558V
3.691ns   1.339V     1.281V     1.518V
3.79ns    1.264V     1.276V     1.514V
4.401ns   1.264V     1.254V     1.49V
4.511ns   1.262V     1.251V     1.459V
6.674ns   1.262V     1.218V     1.379V
10ns      1.268V     1.21V      1.341V
[Falling Waveform]
R_fixture = 50.000
V_fixture = 0.000
V_fixture_min = 0.000
V_fixture_max = 0.000
|  time   V(typ)   V(min)   V(max)
0s        262.1mV    248.4mV    273.7mV
346ps     261.7mV    248.2mV    277.8mV
433ps     269.3mV    248.4mV    203.1mV
537ps     168.7mV    248.5mV    142mV
635ps     122.8mV    255.9mV    110.9mV
779ps     86.87mV    149.6mV    82.23mV
934ps     63.01mV    95.05mV    62.77mV
1.249ns   35.92mV    48.45mV    40.15mV
1.666ns   20.22mV    23.85mV    24.29mV
10ns      532.5uV    250.9uV    321.7uV
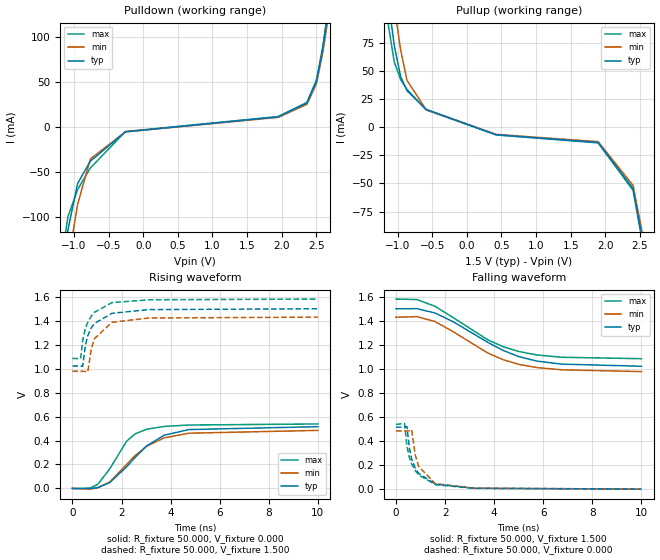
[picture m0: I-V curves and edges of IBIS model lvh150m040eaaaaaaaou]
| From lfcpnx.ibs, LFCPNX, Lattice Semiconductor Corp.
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[Model] lvh150m040eaaaaaaaou
Model_type Output
Polarity   Non-Inverting
Enable   Active-High
Vmeas =  0.750V
Cref =  0.0F
Rref =  1.000M
Vref =  0.0V
C_comp   5.000pF   4.000pF   5.500pF
[Temperature Range]   25.000   0.125k   -40.000
[Voltage Range]   1.500V   1.430V   1.580V
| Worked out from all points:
|   slope of the pulldown table from 0 to 0.225 V, typ, clamps not added: 54.3 ohm
|   slope of the pullup table from 0 to 0.225 V, typ, clamps not added: 56 ohm
|   rising waveform, R_fixture 50.000, V_fixture 0.000: 20-80 % time 1.57ns typ, 1.57ns min, 1.04ns max; typ from 0 V to 0.515 V
|   rising waveform, R_fixture 50.000, V_fixture 1.500: 20-80 % time 551ps typ, 511ps min, 560ps max; typ from 1.02 V to 1.5 V
|   falling waveform, R_fixture 50.000, V_fixture 1.500: 20-80 % time 2.57ns typ, 2.39ns min, 2.45ns max; typ from 1.5 V to 1.02 V
|   falling waveform, R_fixture 50.000, V_fixture 0.000: 20-80 % time 546ps typ, 508ps min, 573ps max; typ from 0.515 V to 0 V
[Pulldown]
|Voltage   I(typ)   I(min)   I(max)
-1.5V     -361.3mA   -385.8mA   -347.6mA
-1.224V   -189.2mA   -224.9mA   -168.3mA
-1.086V   -113.8mA   -150.3mA   -99.3mA
-948mV    -62.81mA   -86.1mA    -69.57mA
-764mV    -37.82mA   -35.45mA   -45.51mA
-258mV    -5.294mA   -5.21mA    -4.909mA
1.95V     11.47mA    10.89mA    11.81mA
2.364V    26.78mA    25.44mA    27.58mA
2.502V    51.05mA    48.49mA    52.58mA
2.594V    87.5mA     83.1mA     90.1mA
2.732V    160.8mA    152.8mA    165.6mA
3V        324.7mA    308.5mA    334.4mA
[Pullup]
|Voltage   I(typ)   I(min)   I(max)
-1.5V     334.2mA    366.8mA    315.2mA
-1.186V   140.5mA    179.9mA    117.2mA
-1.14V    115.6mA    154.7mA    93.3mA
-1.048V   72.68mA    107.9mA    57.95mA
-956mV    44.92mA    68.74mA    42.37mA
-864mV    32.38mA    41.6mA     33.55mA
-588mV    15.88mA    15.55mA    15.32mA
424mV     -6.746mA   -6.408mA   -6.948mA
1.896V    -13.58mA   -12.9mA    -13.99mA
2.402V    -54.62mA   -51.89mA   -56.26mA
2.586V    -116.3mA   -110.5mA   -119.8mA
3V        -369.7mA   -351.2mA   -380.8mA
[Ramp]
| variable   typ   min   max
dV/dt_r   0.309/1.614n   0.291/1.589n   0.332/1.100n
dV/dt_f   0.287/2.626n   0.271/2.486n   0.297/2.547n
R_load = 50.000
[Rising Waveform]
R_fixture = 50.000
V_fixture = 0.000
V_fixture_min = 0.000
V_fixture_max = 0.000
|  time   V(typ)   V(min)   V(max)
0s        60.93uV    103.7uV    -366.5uV
696ps     -1.299mV   -6.339mV   1.551mV
1.029ns   6.351mV    4.766mV    33.07mV
1.517ns   48.14mV    53.5mV     162.4mV
2.208ns   180.2mV    200.2mV    394.2mV
2.548ns   257.7mV    273mV      454.5mV
3.025ns   355mV      352.7mV    494.5mV
3.738ns   444.3mV    422mV      517.6mV
4.745ns   491.2mV    461mV      529.2mV
10ns      515.5mV    484.4mV    538.2mV
[Rising Waveform]
R_fixture = 50.000
V_fixture = 1.500
V_fixture_min = 1.430
V_fixture_max = 1.580
|  time   V(typ)   V(min)   V(max)
0s        1.022V     977.5mV    1.085V
333ps     1.022V     977.6mV    1.084V
419ps     1.02V      977.7mV    1.238V
527ps     1.192V     976.5mV    1.336V
626ps     1.276V     972.9mV    1.388V
768ps     1.34V      1.166V     1.438V
898ps     1.377V     1.251V     1.471V
1.607ns   1.462V     1.387V     1.551V
3.111ns   1.493V     1.423V     1.575V
10ns      1.5V       1.43V      1.581V
[Falling Waveform]
R_fixture = 50.000
V_fixture = 1.500
V_fixture_min = 1.430
V_fixture_max = 1.580
|  time   V(typ)   V(min)   V(max)
0s        1.5V       1.43V      1.581V
849ps     1.501V     1.435V     1.577V
1.578ns   1.466V     1.395V     1.522V
2.327ns   1.393V     1.31V      1.427V
3.739ns   1.221V     1.132V     1.242V
4.371ns   1.153V     1.076V     1.184V
5.02ns    1.101V     1.037V     1.144V
5.743ns   1.065V     1.011V     1.116V
6.735ns   1.04V      992.7mV    1.097V
10ns      1.022V     977.5mV    1.085V
[Falling Waveform]
R_fixture = 50.000
V_fixture = 0.000
V_fixture_min = 0.000
V_fixture_max = 0.000
|  time   V(typ)   V(min)   V(max)
0s        515.5mV    484.4mV    538.2mV
346ps     515mV      484.1mV    546.9mV
444ps     521.3mV    484.3mV    360mV
547ps     341.2mV    485.4mV    261.5mV
637ps     250.5mV    494mV      210.2mV
787ps     173.3mV    281.8mV    153.7mV
927ps     130.4mV    186.5mV    117.6mV
1.607ns   41.35mV    45.59mV    36.8mV
3.169ns   7.893mV    8.004mV    5.984mV
10ns      60.93uV    103.7uV    -366.5uV
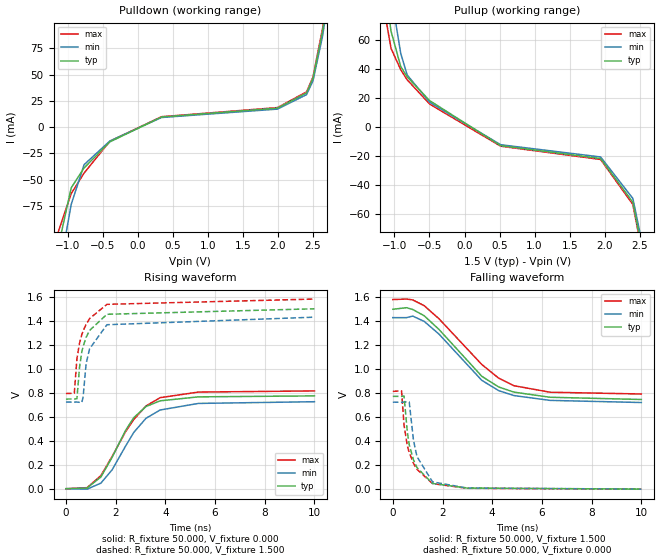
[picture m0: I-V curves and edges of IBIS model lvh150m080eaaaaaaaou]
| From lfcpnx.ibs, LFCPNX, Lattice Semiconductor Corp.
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[Model] lvh150m080eaaaaaaaou
Model_type Output
Polarity   Non-Inverting
Enable   Active-High
Vmeas =  0.750V
Cref =  0.0F
Rref =  1.000M
Vref =  0.0V
C_comp   5.000pF   4.000pF   5.500pF
[Temperature Range]   25.000   0.125k   -40.000
[Voltage Range]   1.500V   1.430V   1.580V
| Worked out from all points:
|   slope of the pulldown table from 0 to 0.225 V, typ, clamps not added: 33.4 ohm
|   slope of the pullup table from 0 to 0.225 V, typ, clamps not added: 34 ohm
|   rising waveform, R_fixture 50.000, V_fixture 0.000: 20-80 % time 1.25ns typ, 1.36ns min, 1.45ns max; typ from 0 V to 0.774 V
|   rising waveform, R_fixture 50.000, V_fixture 1.500: 20-80 % time 538ps typ, 516ps min, 582ps max; typ from 0.747 V to 1.5 V
|   falling waveform, R_fixture 50.000, V_fixture 1.500: 20-80 % time 2.08ns typ, 1.99ns min, 2.24ns max; typ from 1.5 V to 0.747 V
|   falling waveform, R_fixture 50.000, V_fixture 0.000: 20-80 % time 512ps typ, 486ps min, 572ps max; typ from 0.774 V to 0 V
[Pulldown]
|Voltage   I(typ)   I(min)   I(max)
-1.5V     -291.6mA   -309.8mA   -281.8mA
-1.27V    -176.2mA   -202.8mA   -160.3mA
-1.132V   -113.7mA   -142.2mA   -99.4mA
-948mV    -57.73mA   -73.5mA    -63.19mA
-764mV    -38.74mA   -35.69mA   -43.63mA
-396mV    -14.01mA   -13.16mA   -13.36mA
340mV     9.623mA    9.142mA    9.912mA
1.996V    18.06mA    17.15mA    18.6mA
2.41V     32.54mA    30.91mA    33.52mA
2.502V    46.35mA    44.03mA    47.74mA
2.64V     91.5mA     86.9mA     94.2mA
3V        261.8mA    248.7mA    269.7mA
[Pullup]
|Voltage   I(typ)   I(min)   I(max)
-1.5V     270.5mA    296.8mA    254.1mA
-1.186V   117.5mA    148.3mA    97.8mA
-1.14V    98.3mA     128.5mA    79.7mA
-1.048V   66.37mA    92mA       54.42mA
-910mV    41.91mA    51.04mA    39.73mA
-818mV    34.79mA    36.11mA    32.74mA
-496mV    18.28mA    17.11mA    15.93mA
516mV     -12.8mA    -12.16mA   -13.19mA
1.942V    -21.71mA   -20.63mA   -22.37mA
2.402V    -51.93mA   -49.34mA   -53.49mA
2.586V    -97.2mA    -92.3mA    -100.1mA
3V        -297.4mA   -282.5mA   -306.3mA
[Ramp]
| variable   typ   min   max
dV/dt_r   0.464/1.261n   0.435/1.390n   0.489/1.464n
dV/dt_f   0.452/2.122n   0.425/2.007n   0.473/2.313n
R_load = 50.000
[Rising Waveform]
R_fixture = 50.000
V_fixture = 0.000
V_fixture_min = 0.000
V_fixture_max = 0.000
|  time   V(typ)   V(min)   V(max)
0s        61.38uV    -174.3uV   -531.3uV
851ps     5.413mV    -4.128mV   8.531mV
1.408ns   97.84mV    46.58mV    108.8mV
1.861ns   262.8mV    158.2mV    270.1mV
2.4ns     486.5mV    355.3mV    474.9mV
2.729ns   592mV      469.2mV    576.4mV
3.221ns   685mV      586.9mV    689.4mV
3.79ns    732.4mV    656.1mV    758.8mV
5.33ns    765.6mV    710.8mV    805.5mV
10ns      773.6mV    725.1mV    815.1mV
[Rising Waveform]
R_fixture = 50.000
V_fixture = 1.500
V_fixture_min = 1.430
V_fixture_max = 1.580
|  time   V(typ)   V(min)   V(max)
0s        747.4mV    722.1mV    793.2mV
336ps     747.7mV    722.2mV    795.9mV
441ps     750.2mV    722.4mV    1.083V
548ps     1.016V     720.1mV    1.215V
640ps     1.142V     719.9mV    1.285V
691ps     1.186V     764.9mV    1.315V
811ps     1.261V     1.042V     1.37V
950ps     1.319V     1.166V     1.418V
1.648ns   1.454V     1.367V     1.537V
10ns      1.5V       1.43V      1.581V
[Falling Waveform]
R_fixture = 50.000
V_fixture = 1.500
V_fixture_min = 1.430
V_fixture_max = 1.580
|  time   V(typ)   V(min)   V(max)
0s        1.5V       1.43V      1.581V
551ps     1.513V     1.43V      1.585V
801ps     1.498V     1.443V     1.578V
1.261ns   1.446V     1.399V     1.53V
1.861ns   1.331V     1.292V     1.42V
3.581ns   940.8mV    907mV      1.039V
4.259ns   851.7mV    821.4mV    925.5mV
4.871ns   808.9mV    780.2mV    862.4mV
6.33ns    766mV      739.9mV    807.9mV
10ns      747.4mV    722.1mV    793.2mV
[Falling Waveform]
R_fixture = 50.000
V_fixture = 0.000
V_fixture_min = 0.000
V_fixture_max = 0.000
|  time   V(typ)   V(min)   V(max)
0s        773.6mV    725.1mV    815.1mV
351ps     773.3mV    724.9mV    819.3mV
451ps     776.7mV    725mV      533.5mV
581ps     479.4mV    728.7mV    364.5mV
660ps     369.7mV    726.7mV    303.4mV
831ps     243.5mV    407.8mV    214.9mV
971ps     179.4mV    271.2mV    165mV
1.599ns   46.74mV    60.12mV    45.76mV
2.989ns   8.515mV    8.987mV    6.874mV
10ns      61.38uV    -174.3uV   -531.3uV
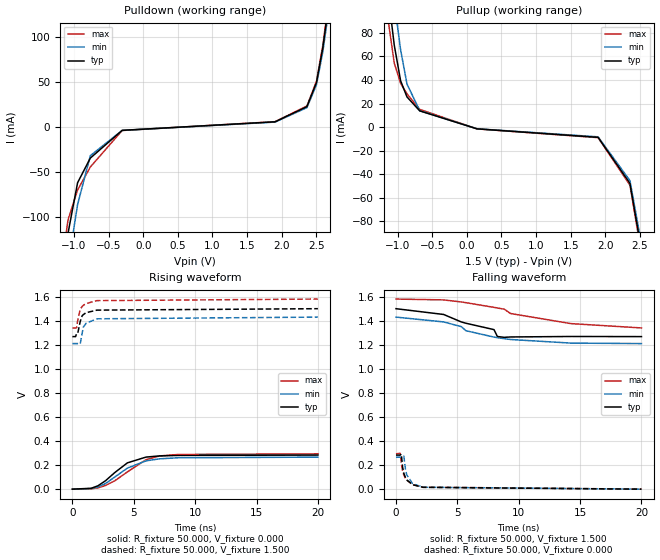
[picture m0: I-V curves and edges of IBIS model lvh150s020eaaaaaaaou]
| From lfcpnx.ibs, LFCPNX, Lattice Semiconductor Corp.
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[Model] lvh150s020eaaaaaaaou
Model_type Output
Polarity   Non-Inverting
Enable   Active-High
Vmeas =  0.750V
Cref =  0.0F
Rref =  1.000M
Vref =  0.0V
C_comp   5.000pF   4.000pF   5.500pF
[Temperature Range]   25.000   0.125k   -40.000
[Voltage Range]   1.500V   1.430V   1.580V
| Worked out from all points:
|   slope of the pulldown table from 0 to 0.225 V, typ, clamps not added: 112 ohm
|   slope of the pullup table from 0 to 0.225 V, typ, clamps not added: 106 ohm
|   rising waveform, R_fixture 50.000, V_fixture 0.000: 20-80 % time 2.1ns typ, 2.46ns min, 2.5ns max; typ from 0 V to 0.283 V
|   rising waveform, R_fixture 50.000, V_fixture 1.500: 20-80 % time 456ps typ, 481ps min, 536ps max; typ from 1.27 V to 1.5 V
|   falling waveform, R_fixture 50.000, V_fixture 1.500: 20-80 % time 4.21ns typ, 4.55ns min, 6.63ns max; typ from 1.5 V to 1.27 V
|   falling waveform, R_fixture 50.000, V_fixture 0.000: 20-80 % time 562ps typ, 549ps min, 607ps max; typ from 0.283 V to 0 V
[Pulldown]
|Voltage   I(typ)   I(min)   I(max)
-1.5V     -382mA     -398.8mA   -370.9mA
-1.224V   -198.8mA   -231.5mA   -178.5mA
-1.086V   -118.1mA   -153.7mA   -103.3mA
-948mV    -61.9mA    -86.2mA    -70.06mA
-764mV    -34.48mA   -31.79mA   -44.41mA
-304mV    -3.572mA   -3.622mA   -3.733mA
1.904V    5.931mA    5.634mA    6.109mA
2.364V    22.88mA    21.73mA    23.56mA
2.502V    49.68mA    47.19mA    51.17mA
2.594V    88.6mA     84.2mA     91.3mA
2.778V    193.8mA    184.1mA    199.6mA
3V        336.4mA    319.6mA    346.5mA
[Pullup]
|Voltage   I(typ)   I(min)   I(max)
-1.5V     340.1mA    373.1mA    321.3mA
-1.186V   140.8mA    181.2mA    117.4mA
-1.14V    114.9mA    155.2mA    92.3mA
-1.048V   69.63mA    106.6mA    54.37mA
-956mV    39.33mA    65.59mA    37.17mA
-864mV    25.63mA    36.6mA     28.29mA
-680mV    13.8mA     13.95mA    15.05mA
148mV     -1.455mA   -1.383mA   -1.499mA
1.896V    -8.656mA   -8.223mA   -8.916mA
2.356V    -47.71mA   -45.33mA   -49.14mA
2.586V    -125.9mA   -119.6mA   -129.7mA
3V        -407.5mA   -387.1mA   -419.7mA
[Ramp]
| variable   typ   min   max
dV/dt_r   0.170/2.142n   0.160/2.452n   0.173/2.555n
dV/dt_f   0.139/4.252n   0.132/5.059n   0.144/7.304n
R_load = 50.000
[Rising Waveform]
R_fixture = 50.000
V_fixture = 0.000
V_fixture_min = 0.000
V_fixture_max = 0.000
|  time   V(typ)   V(min)   V(max)
0s        58.69uV    245.2uV    330uV
1.528ns   7.462mV    4.832mV    2.736mV
2.087ns   28.53mV    18.35mV    11.04mV
2.681ns   68.97mV    46.25mV    29.72mV
3.448ns   137.8mV    100.7mV    69.54mV
4.48ns    218.8mV    175.2mV    143.7mV
6.001ns   266.8mV    235.5mV    245.7mV
7.104ns   276.4mV    252.2mV    276.1mV
8.605ns   280.6mV    261mV      288.4mV
20ns      283.4mV    266.4mV    293.7mV
[Rising Waveform]
R_fixture = 50.000
V_fixture = 1.500
V_fixture_min = 1.430
V_fixture_max = 1.580
|  time   V(typ)   V(min)   V(max)
0s        1.268V     1.21V      1.34V
257ps     1.268V     1.21V      1.34V
343ps     1.294V     1.21V      1.342V
434ps     1.296V     1.21V      1.405V
636ps     1.394V     1.208V     1.495V
797ps     1.442V     1.299V     1.519V
888ps     1.451V     1.347V     1.528V
1.116ns   1.467V     1.379V     1.543V
1.996ns   1.488V     1.416V     1.567V
20ns      1.5V       1.43V      1.58V
[Falling Waveform]
R_fixture = 50.000
V_fixture = 1.500
V_fixture_min = 1.430
V_fixture_max = 1.580
|  time   V(typ)   V(min)   V(max)
0s        1.5V       1.43V      1.58V
3.881ns   1.452V     1.39V      1.573V
5.316ns   1.39V      1.351V     1.556V
5.699ns   1.379V     1.317V     1.55V
7.986ns   1.326V     1.264V     1.511V
8.258ns   1.269V     1.259V     1.506V
8.815ns   1.262V     1.251V     1.496V
9.329ns   1.265V     1.244V     1.46V
14.25ns   1.269V     1.214V     1.376V
20ns      1.268V     1.21V      1.34V
[Falling Waveform]
R_fixture = 50.000
V_fixture = 0.000
V_fixture_min = 0.000
V_fixture_max = 0.000
|  time   V(typ)   V(min)   V(max)
0s        283.4mV    266.4mV    293.7mV
346ps     283mV      266.1mV    298.5mV
433ps     292mV      266.4mV    218.4mV
537ps     182.9mV    266.5mV    152.8mV
635ps     133mV      275.3mV    119.4mV
775ps     95.05mV    163.6mV    89.26mV
877ps     77.32mV    118.8mV    74.35mV
1.355ns   37.05mV    45.74mV    38.31mV
2.206ns   15.15mV    16.14mV    16.87mV
20ns      58.69uV    245.2uV    330uV
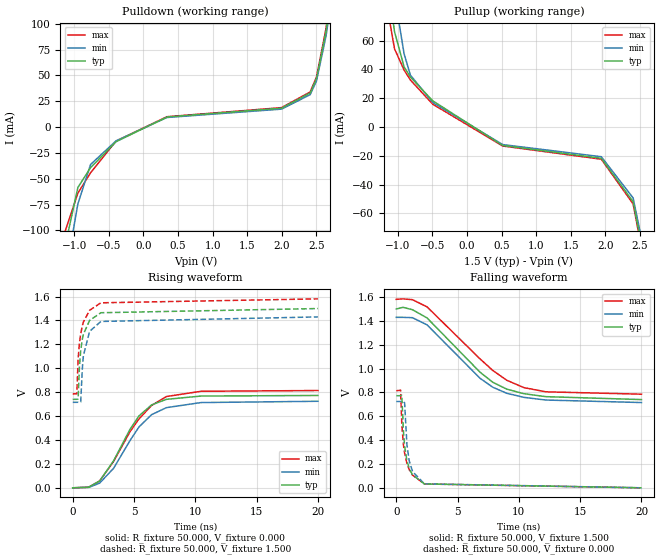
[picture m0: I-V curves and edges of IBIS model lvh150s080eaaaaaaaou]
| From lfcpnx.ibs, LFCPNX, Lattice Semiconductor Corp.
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[Model] lvh150s080eaaaaaaaou
Model_type Output
Polarity   Non-Inverting
Enable   Active-High
Vmeas =  0.750V
Cref =  0.0F
Rref =  1.000M
Vref =  0.0V
C_comp   5.000pF   4.000pF   5.500pF
[Temperature Range]   25.000   0.125k   -40.000
[Voltage Range]   1.500V   1.430V   1.580V
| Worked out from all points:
|   slope of the pulldown table from 0 to 0.225 V, typ, clamps not added: 32.9 ohm
|   slope of the pullup table from 0 to 0.225 V, typ, clamps not added: 34.1 ohm
|   rising waveform, R_fixture 50.000, V_fixture 0.000: 20-80 % time 2.61ns typ, 2.82ns min, 3.04ns max; typ from 0 V to 0.773 V
|   rising waveform, R_fixture 50.000, V_fixture 1.500: 20-80 % time 568ps typ, 545ps min, 610ps max; typ from 0.74 V to 1.5 V
|   falling waveform, R_fixture 50.000, V_fixture 1.500: 20-80 % time 4.42ns typ, 4.22ns min, 4.78ns max; typ from 1.5 V to 0.74 V
|   falling waveform, R_fixture 50.000, V_fixture 0.000: 20-80 % time 555ps typ, 545ps min, 601ps max; typ from 0.773 V to 0 V
[Pulldown]
|Voltage   I(typ)   I(min)   I(max)
-1.5V     -295.2mA   -313.9mA   -285.3mA
-1.27V    -178.5mA   -205.5mA   -162.4mA
-1.132V   -115.1mA   -144.2mA   -100.7mA
-948mV    -58.46mA   -74.4mA    -63.98mA
-764mV    -39.23mA   -36.17mA   -44.18mA
-396mV    -14.18mA   -13.34mA   -13.53mA
340mV     9.745mA    9.257mA    10.04mA
1.996V    18.29mA    17.37mA    18.83mA
2.41V     32.95mA    31.31mA    33.94mA
2.502V    46.94mA    44.59mA    48.34mA
2.64V     92.7mA     88.1mA     95.5mA
3V        265.2mA    251.9mA    273.2mA
[Pullup]
|Voltage   I(typ)   I(min)   I(max)
-1.5V     270mA      296.1mA    253.6mA
-1.186V   117.3mA    148mA      97.6mA
-1.14V    98.1mA     128.2mA    79.5mA
-1.048V   66.23mA    91.8mA     54.31mA
-910mV    41.82mA    50.94mA    39.65mA
-818mV    34.72mA    36.03mA    32.67mA
-496mV    18.24mA    17.08mA    15.9mA
516mV     -12.78mA   -12.14mA   -13.16mA
1.942V    -21.67mA   -20.59mA   -22.32mA
2.402V    -51.82mA   -49.23mA   -53.38mA
2.586V    -97mA      -92.1mA    -99.9mA
3V        -296.8mA   -282mA     -305.7mA
[Ramp]
| variable   typ   min   max
dV/dt_r   0.463/2.622n   0.435/2.853n   0.489/3.051n
dV/dt_f   0.456/4.427n   0.429/4.230n   0.477/4.797n
R_load = 50.000
[Rising Waveform]
R_fixture = 50.000
V_fixture = 0.000
V_fixture_min = 0.000
V_fixture_max = 0.000
|  time   V(typ)   V(min)   V(max)
0s        63.14uV    -168.1uV   -533.4uV
1.299ns   5.08mV     2.829mV    4.614mV
2.198ns   57mV       39.15mV    57.13mV
3.331ns   225.1mV    162.6mV    220mV
4.67ns    488.7mV    394.6mV    468.8mV
5.406ns   601.6mV    509.4mV    576.9mV
6.434ns   693.7mV    612.1mV    689.1mV
7.64ns    740.2mV    670.7mV    763.7mV
10.46ns   767.6mV    713.2mV    807.7mV
20ns      772.6mV    724mV      813.9mV
[Rising Waveform]
R_fixture = 50.000
V_fixture = 1.500
V_fixture_min = 1.430
V_fixture_max = 1.580
|  time   V(typ)   V(min)   V(max)
0s        740.1mV    715.2mV    785.3mV
336ps     740.4mV    715.2mV    787.6mV
441ps     742.7mV    715.5mV    1.078V
549ps     1.014V     713mV      1.212V
651ps     1.149V     717mV      1.288V
791ps     1.247V     1.006V     1.358V
871ps     1.284V     1.105V     1.387V
1.378ns   1.401V     1.309V     1.485V
2.299ns   1.465V     1.392V     1.548V
20ns      1.5V       1.43V      1.581V
[Falling Waveform]
R_fixture = 50.000
V_fixture = 1.500
V_fixture_min = 1.430
V_fixture_max = 1.580
|  time   V(typ)   V(min)   V(max)
0s        1.5V       1.43V      1.581V
551ps     1.514V     1.43V      1.585V
1.32ns    1.494V     1.427V     1.578V
2.51ns    1.425V     1.367V     1.518V
6.835ns   969.3mV    918.5mV    1.081V
7.875ns   885.1mV    843.5mV    984.2mV
9.007ns   827.8mV    793.2mV    902.5mV
10.4ns    789.6mV    758.8mV    840.5mV
12.2ns    764.5mV    736.2mV    805.1mV
20ns      740.1mV    715.2mV    785.3mV
[Falling Waveform]
R_fixture = 50.000
V_fixture = 0.000
V_fixture_min = 0.000
V_fixture_max = 0.000
|  time   V(typ)   V(min)   V(max)
0s        772.6mV    724mV      813.9mV
351ps     772.3mV    723.9mV    818.9mV
451ps     776.2mV    724mV      533.2mV
580ps     481.2mV    727.6mV    365.2mV
681ps     349mV      711mV      289.9mV
871ps     226mV      357.1mV    202.1mV
1.06ns    160.2mV    225.1mV    150.5mV
1.331ns   107.5mV    135.6mV    105.8mV
2.299ns   32.04mV    33.15mV    31.74mV
20ns      63.14uV    -168.1uV   -533.4uV
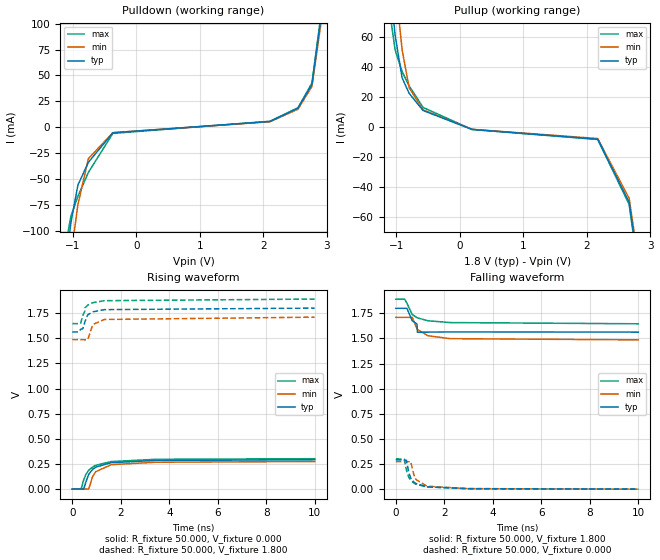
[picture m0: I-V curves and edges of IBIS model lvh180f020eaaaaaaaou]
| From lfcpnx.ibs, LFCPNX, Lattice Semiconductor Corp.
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[Model] lvh180f020eaaaaaaaou
Model_type Output
Polarity   Non-Inverting
Enable   Active-High
Vmeas =  0.900V
Cref =  0.0F
Rref =  1.000M
Vref =  0.0V
C_comp   5.000pF   4.000pF   5.500pF
[Temperature Range]   25.000   0.125k   -40.000
[Voltage Range]   1.800V   1.710V   1.890V
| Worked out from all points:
|   slope of the pulldown table from 0 to 0.27 V, typ, clamps not added: 114 ohm
|   slope of the pullup table from 0 to 0.27 V, typ, clamps not added: 129 ohm
|   rising waveform, R_fixture 50.000, V_fixture 0.000: 20-80 % time 548ps typ, 506ps min, 585ps max; typ from 0 V to 0.291 V
|   rising waveform, R_fixture 50.000, V_fixture 1.800: 20-80 % time 293ps typ, 299ps min, 312ps max; typ from 1.56 V to 1.8 V
|   falling waveform, R_fixture 50.000, V_fixture 1.800: 20-80 % time 341ps typ, 512ps min, 523ps max; typ from 1.8 V to 1.56 V
|   falling waveform, R_fixture 50.000, V_fixture 0.000: 20-80 % time 329ps typ, 334ps min, 346ps max; typ from 0.291 V to 0 V
[Pulldown]
|Voltage   I(typ)   I(min)   I(max)
-1.8V     -596.9mA   -586.3mA   -599.1mA
-1.14V    -149.8mA   -183.1mA   -130.3mA
-1.085V   -119mA     -153mA     -104.1mA
-1.03V    -92.1mA    -124.4mA   -85.91mA
-920mV    -55.83mA   -74.71mA   -66.66mA
-755mV    -33.93mA   -30.38mA   -43.67mA
-370mV    -5.457mA   -5.328mA   -6.03mA
2.105V    5.503mA    5.228mA    5.668mA
2.545V    18.25mA    17.33mA    18.79mA
2.765V    41.38mA    39.31mA    42.62mA
2.985V    140.5mA    133.5mA    144.7mA
3.6V      544.2mA    517mA      560.5mA
[Pullup]
|Voltage   I(typ)   I(min)   I(max)
-1.8V     561.9mA    586.2mA    549.8mA
-1.185V   145.6mA    187.1mA    122.3mA
-1.075V   85.04mA    124.6mA    67.76mA
-1.02V    61.14mA    96.8mA     51.55mA
-910mV    32.88mA    51.58mA    37.04mA
-800mV    22.6mA     26.38mA    27.65mA
-580mV    11.11mA    11.48mA    13.15mA
190mV     -1.523mA   -1.447mA   -1.569mA
2.17V     -8.019mA   -7.618mA   -8.259mA
2.665V    -50.16mA   -47.66mA   -51.67mA
2.83V     -99.5mA    -94.5mA    -102.5mA
3.6V      -645.6mA   -613.3mA   -665mA
[Ramp]
| variable   typ   min   max
dV/dt_r   0.182/0.563n   0.164/0.513n   0.181/0.586n
dV/dt_f   0.142/0.572n   0.134/0.594n   0.146/0.636n
R_load = 50.000
[Rising Waveform]
R_fixture = 50.000
V_fixture = 0.000
V_fixture_min = 0.000
V_fixture_max = 0.000
|  time   V(typ)   V(min)   V(max)
0s        158.4uV    383.4uV    409.4uV
364ps     409.7uV    466.2uV    -139.3uV
467ps     -1.24mV    441.9uV    87.24mV
558ps     67.37mV    565.5uV    145.3mV
677ps     146.1mV    -979.1uV   186.5mV
837ps     195.4mV    123.4mV    218.9mV
966ps     217.8mV    172.4mV    235.7mV
1.607ns   262.2mV    242.3mV    273.3mV
3.441ns   284.5mV    266.7mV    295.8mV
10ns      291.4mV    274mV      301.9mV
[Rising Waveform]
R_fixture = 50.000
V_fixture = 1.800
V_fixture_min = 1.710
V_fixture_max = 1.890
|  time   V(typ)   V(min)   V(max)
0s        1.563V     1.486V     1.646V
257ps     1.563V     1.486V     1.646V
346ps     1.59V      1.486V     1.649V
435ps     1.595V     1.486V     1.728V
517ps     1.661V     1.485V     1.769V
527ps     1.667V     1.485V     1.804V
636ps     1.733V     1.486V     1.83V
846ps     1.763V     1.637V     1.854V
1.328ns   1.785V     1.687V     1.874V
10ns      1.8V       1.71V      1.89V
[Falling Waveform]
R_fixture = 50.000
V_fixture = 1.800
V_fixture_min = 1.710
V_fixture_max = 1.890
|  time   V(typ)   V(min)   V(max)
0s        1.8V       1.71V      1.89V
362ps     1.8V       1.71V      1.892V
457ps     1.8V       1.71V      1.851V
675ps     1.676V     1.71V      1.739V
875ps     1.644V     1.595V     1.707V
887ps     1.563V     1.591V     1.705V
900ps     1.561V     1.588V     1.704V
1.325ns   1.563V     1.527V     1.676V
2.238ns   1.565V     1.498V     1.658V
10ns      1.563V     1.486V     1.646V
[Falling Waveform]
R_fixture = 50.000
V_fixture = 0.000
V_fixture_min = 0.000
V_fixture_max = 0.000
|  time   V(typ)   V(min)   V(max)
0s        291.4mV    274mV      301.9mV
346ps     291.1mV    273.8mV    298.8mV
433ps     288.7mV    273.9mV    192.1mV
537ps     164.2mV    274.2mV    115.9mV
615ps     111.1mV    273.2mV    87.8mV
745ps     70.62mV    140.8mV    60.49mV
829ps     55.91mV    96.08mV    49.52mV
1.285ns   23.32mV    29.72mV    22.78mV
2.98ns    5.273mV    5.49mV     4.753mV
10ns      158.4uV    383.4uV    409.4uV
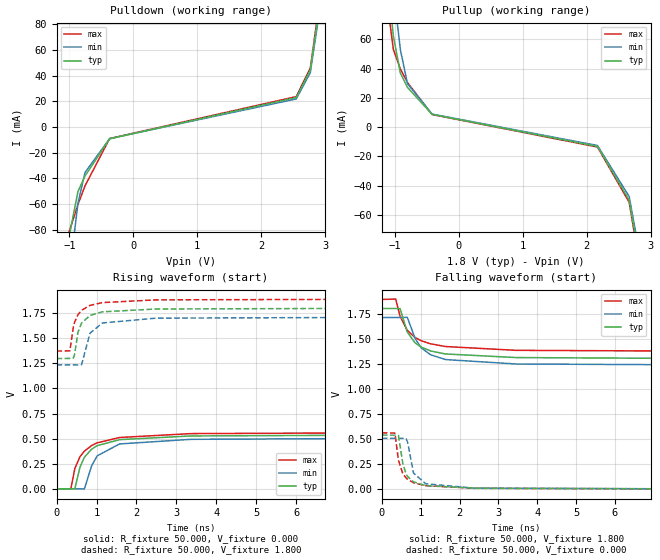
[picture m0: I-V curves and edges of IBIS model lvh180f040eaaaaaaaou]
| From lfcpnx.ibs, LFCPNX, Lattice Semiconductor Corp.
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[Model] lvh180f040eaaaaaaaou
Model_type Output
Polarity   Non-Inverting
Enable   Active-High
Vmeas =  0.900V
Cref =  0.0F
Rref =  1.000M
Vref =  0.0V
C_comp   5.000pF   4.000pF   5.500pF
[Temperature Range]   25.000   0.125k   -40.000
[Voltage Range]   1.800V   1.710V   1.890V
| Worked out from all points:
|   slope of the pulldown table from 0 to 0.27 V, typ, clamps not added: 53.8 ohm
|   slope of the pullup table from 0 to 0.27 V, typ, clamps not added: 67.5 ohm
|   rising waveform, R_fixture 50.000, V_fixture 0.000: 20-80 % time 499ps typ, 474ps min, 552ps max; typ from 0 V to 0.538 V
|   rising waveform, R_fixture 50.000, V_fixture 1.800: 20-80 % time 258ps typ, 275ps min, 277ps max; typ from 1.3 V to 1.8 V
|   falling waveform, R_fixture 50.000, V_fixture 1.800: 20-80 % time 562ps typ, 554ps min, 607ps max; typ from 1.8 V to 1.3 V
|   falling waveform, R_fixture 50.000, V_fixture 0.000: 20-80 % time 224ps typ, 229ps min, 243ps max; typ from 0.538 V to 0 V
[Pulldown]
|Voltage   I(typ)   I(min)   I(max)
-1.8V     -575.4mA   -586.4mA   -572mA
-1.195V   -177.9mA   -215.9mA   -156.2mA
-1.14V    -146.3mA   -184.9mA   -126.3mA
-1.03V    -92.1mA    -126.8mA   -85.63mA
-865mV    -50.17mA   -59.32mA   -60.26mA
-755mV    -38.12mA   -35.34mA   -45.76mA
-370mV    -9.091mA   -8.929mA   -8.869mA
2.545V    23.1mA     21.95mA    23.8mA
2.765V    44.6mA     42.37mA    45.94mA
2.875V    82.77mA    78.63mA    85.25mA
2.985V    139.6mA    132.6mA    143.8mA
3.6V      535.2mA    508.4mA    551.3mA
[Pullup]
|Voltage   I(typ)   I(min)   I(max)
-1.8V     534.2mA    557.6mA    522.2mA
-1.185V   140.4mA    179.7mA    117.9mA
-1.13V    110.7mA    149.4mA    89.8mA
-1.02V    62.09mA    94.5mA     52.97mA
-910mV    36.84mA    52.76mA    39.66mA
-800mV    27.16mA    29.72mA    30.5mA
-415mV    8.725mA    8.931mA    8.602mA
2.17V     -13.19mA   -12.53mA   -13.58mA
2.665V    -49.83mA   -47.34mA   -51.32mA
2.83V     -91.4mA    -86.8mA    -94.1mA
2.885V    -116.5mA   -110.7mA   -120mA
3.6V      -573.4mA   -544.7mA   -590.6mA
[Ramp]
| variable   typ   min   max
dV/dt_r   0.323/0.504n   0.303/0.476n   0.337/0.552n
dV/dt_f   0.301/0.559n   0.285/0.556n   0.326/0.601n
R_load = 50.000
[Rising Waveform]
R_fixture = 50.000
V_fixture = 0.000
V_fixture_min = 0.000
V_fixture_max = 0.000
|  time   V(typ)   V(min)   V(max)
0s        138uV      252.8uV    -315.2uV
356ps     397.4uV    307.8uV    -2.794mV
457ps     -246.8uV   296.4uV    201.9mV
587ps     216.6mV    167.4uV    320.7mV
696ps     314.7mV    -1.264mV   375.6mV
877ps     395.1mV    228.1mV    431.4mV
1.016ns   430mV      328.5mV    458.4mV
1.577ns   490.3mV    447.6mV    511.6mV
3.362ns   527mV      493.4mV    550.4mV
10ns      538.5mV    505.9mV    561.2mV
[Rising Waveform]
R_fixture = 50.000
V_fixture = 1.800
V_fixture_min = 1.710
V_fixture_max = 1.890
|  time   V(typ)   V(min)   V(max)
0s        1.298V     1.235V     1.372V
334ps     1.299V     1.235V     1.375V
419ps     1.301V     1.235V     1.606V
451ps     1.338V     1.235V     1.659V
537ps     1.56V      1.233V     1.735V
626ps     1.651V     1.236V     1.778V
837ps     1.727V     1.55V      1.827V
1.148ns   1.763V     1.652V     1.855V
2.488ns   1.791V     1.7V       1.882V
10ns      1.8V       1.71V      1.89V
[Falling Waveform]
R_fixture = 50.000
V_fixture = 1.800
V_fixture_min = 1.710
V_fixture_max = 1.890
|  time   V(typ)   V(min)   V(max)
0s        1.8V       1.71V      1.89V
356ps     1.8V       1.71V      1.894V
469ps     1.798V     1.71V      1.723V
655ps     1.565V     1.712V     1.582V
855ps     1.458V     1.502V     1.511V
1.015ns   1.415V     1.407V     1.478V
1.255ns   1.377V     1.339V     1.448V
1.639ns   1.347V     1.291V     1.421V
3.459ns   1.311V     1.247V     1.383V
10ns      1.298V     1.235V     1.372V
[Falling Waveform]
R_fixture = 50.000
V_fixture = 0.000
V_fixture_min = 0.000
V_fixture_max = 0.000
|  time   V(typ)   V(min)   V(max)
0s        538.5mV    505.9mV    561.2mV
336ps     538.1mV    505.6mV    558.8mV
428ps     534.1mV    505.8mV    287.8mV
539ps     256.1mV    506mV      154.7mV
625ps     150.4mV    504mV      110.2mV
665ps     124.8mV    466.4mV    96.23mV
815ps     72.53mV    160.1mV    63.15mV
1.129ns   34.86mV    53.29mV    34.33mV
2.395ns   9.422mV    9.32mV     8.275mV
10ns      138uV      252.8uV    -315.2uV
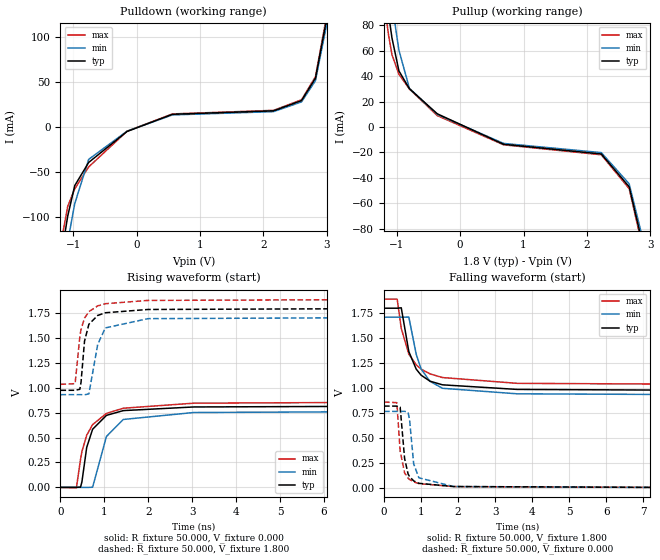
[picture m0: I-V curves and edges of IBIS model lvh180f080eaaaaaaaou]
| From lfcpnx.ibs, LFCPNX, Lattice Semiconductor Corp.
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[Model] lvh180f080eaaaaaaaou
Model_type Output
Polarity   Non-Inverting
Enable   Active-High
Vmeas =  0.900V
Cref =  0.0F
Rref =  1.000M
Vref =  0.0V
C_comp   5.000pF   4.000pF   5.500pF
[Temperature Range]   25.000   0.125k   -40.000
[Voltage Range]   1.800V   1.710V   1.890V
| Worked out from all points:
|   slope of the pulldown table from 0 to 0.27 V, typ, clamps not added: 32.7 ohm
|   slope of the pullup table from 0 to 0.27 V, typ, clamps not added: 41.7 ohm
|   rising waveform, R_fixture 50.000, V_fixture 0.000: 20-80 % time 322ps typ, 360ps min, 428ps max; typ from 0 V to 0.819 V
|   rising waveform, R_fixture 50.000, V_fixture 1.800: 20-80 % time 159ps typ, 221ps min, 193ps max; typ from 0.975 V to 1.8 V
|   falling waveform, R_fixture 50.000, V_fixture 1.800: 20-80 % time 435ps typ, 422ps min, 527ps max; typ from 1.8 V to 0.975 V
|   falling waveform, R_fixture 50.000, V_fixture 0.000: 20-80 % time 141ps typ, 150ps min, 148ps max; typ from 0.819 V to 0 V
[Pulldown]
|Voltage   I(typ)   I(min)   I(max)
-1.8V     -467.8mA   -473.5mA   -468.7mA
-1.195V   -147.3mA   -176.6mA   -130.8mA
-1.085V   -99.4mA    -128.3mA   -88.6mA
-975mV    -65.56mA   -85.7mA    -69.21mA
-755mV    -39.63mA   -36.22mA   -44.64mA
-150mV    -5.086mA   -4.689mA   -4.763mA
565mV     14.1mA     13.39mA    14.52mA
2.16V     17.98mA    17.08mA    18.52mA
2.6V      29.41mA    27.94mA    30.29mA
2.82V     54.39mA    51.67mA    56.02mA
2.985V    116mA      110.2mA    119.5mA
3.6V      435mA      413.3mA    448.1mA
[Pullup]
|Voltage   I(typ)   I(min)   I(max)
-1.8V     412.2mA    430.3mA    402mA
-1.185V   111.7mA    141.3mA    93.5mA
-1.13V    89.5mA     118.4mA    72.8mA
-1.075V   70.1mA     96.9mA     56.9mA
-965mV    44.06mA    60.4mA     41.47mA
-800mV    30.07mA    30.39mA    29.87mA
-360mV    10.32mA    9.758mA    8.902mA
685mV     -13.65mA   -12.97mA   -14.06mA
2.225V    -21.26mA   -20.2mA    -21.9mA
2.665V    -47.14mA   -44.79mA   -48.56mA
2.885V    -93.9mA    -89.2mA    -96.7mA
3.6V      -441.5mA   -419.4mA   -454.7mA
[Ramp]
| variable   typ   min   max
dV/dt_r   0.491/0.321n   0.460/0.360n   0.516/0.430n
dV/dt_f   0.495/0.436n   0.467/0.425n   0.514/0.532n
R_load = 50.000
[Rising Waveform]
R_fixture = 50.000
V_fixture = 0.000
V_fixture_min = 0.000
V_fixture_max = 0.000
|  time   V(typ)   V(min)   V(max)
0s        110.4uV    -89.57uV   -490.2uV
363ps     451.2uV    -69.02uV   -4.801mV
458ps     2.872mV    -48.08uV   283.4mV
489ps     56.15mV    17.34uV    360.7mV
598ps     401.8mV    -508uV     523.9mV
732ps     583.9mV    1.32mV     630mV
1.047ns   723.3mV    511.5mV    743.2mV
1.431ns   771.2mV    682.2mV    795.1mV
3.033ns   807.8mV    752.1mV    845.8mV
10ns      819.1mV    766.1mV    859.6mV
[Rising Waveform]
R_fixture = 50.000
V_fixture = 1.800
V_fixture_min = 1.710
V_fixture_max = 1.890
|  time   V(typ)   V(min)   V(max)
0s        975.1mV    931.3mV    1.035V
334ps     975.3mV    931.4mV    1.042V
441ps     985.1mV    931.6mV    1.512V
468ps     1.053V     931.5mV    1.586V
548ps     1.469V     929.1mV    1.7V
648ps     1.639V     940.4mV    1.766V
848ps     1.727V     1.436V     1.823V
1.022ns   1.754V     1.602V     1.845V
1.992ns   1.787V     1.695V     1.878V
10ns      1.8V       1.71V      1.891V
[Falling Waveform]
R_fixture = 50.000
V_fixture = 1.800
V_fixture_min = 1.710
V_fixture_max = 1.890
|  time   V(typ)   V(min)   V(max)
0s        1.8V       1.71V      1.891V
356ps     1.8V       1.71V      1.891V
466ps     1.804V     1.71V      1.597V
670ps     1.365V     1.711V     1.34V
870ps     1.189V     1.338V     1.232V
1.001ns   1.129V     1.192V     1.19V
1.24ns    1.069V     1.067V     1.142V
1.579ns   1.032V     997.4mV    1.105V
3.597ns   986.1mV    942.1mV    1.047V
10ns      975.1mV    931.3mV    1.035V
[Falling Waveform]
R_fixture = 50.000
V_fixture = 0.000
V_fixture_min = 0.000
V_fixture_max = 0.000
|  time   V(typ)   V(min)   V(max)
0s        819.1mV    766.1mV    859.6mV
346ps     818.9mV    765.9mV    853.4mV
436ps     808.9mV    766mV      368.7mV
556ps     294mV      766.8mV    149.7mV
650ps     138.7mV    755mV      96.98mV
691ps     110.9mV    681.1mV    83.1mV
800ps     69.68mV    242mV      59.19mV
941ps     45.03mV    100.2mV    42.48mV
1.876ns   12.77mV    12.66mV    12.15mV
10ns      110.4uV    -89.57uV   -490.2uV
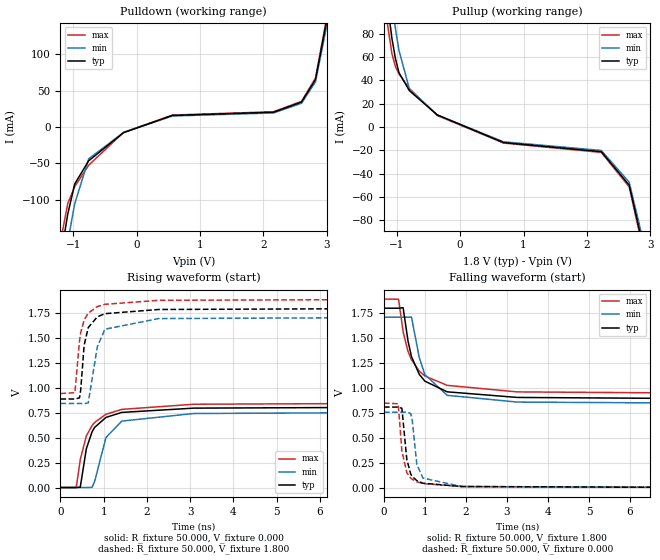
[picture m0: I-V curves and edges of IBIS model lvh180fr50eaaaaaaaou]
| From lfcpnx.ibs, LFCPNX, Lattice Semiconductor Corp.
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[Model] lvh180fr50eaaaaaaaou
Model_type Output
Polarity   Non-Inverting
Enable   Active-High
Vmeas =  0.900V
Cref =  0.0F
Rref =  1.000M
Vref =  0.0V
C_comp   5.000pF   4.000pF   5.500pF
[Temperature Range]   25.000   0.125k   -40.000
[Voltage Range]   1.800V   1.710V   1.890V
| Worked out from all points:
|   slope of the pulldown table from 0 to 0.27 V, typ, clamps not added: 29.1 ohm
|   slope of the pullup table from 0 to 0.27 V, typ, clamps not added: 42.2 ohm
|   rising waveform, R_fixture 50.000, V_fixture 0.000: 20-80 % time 356ps typ, 375ps min, 428ps max; typ from 0 V to 0.809 V
|   rising waveform, R_fixture 50.000, V_fixture 1.800: 20-80 % time 172ps typ, 228ps min, 192ps max; typ from 0.888 V to 1.8 V
|   falling waveform, R_fixture 50.000, V_fixture 1.800: 20-80 % time 458ps typ, 431ps min, 538ps max; typ from 1.8 V to 0.888 V
|   falling waveform, R_fixture 50.000, V_fixture 0.000: 20-80 % time 145ps typ, 152ps min, 153ps max; typ from 0.809 V to 0 V
[Pulldown]
|Voltage   I(typ)   I(min)   I(max)
-1.8V     -567.1mA   -586mA     -558.7mA
-1.195V   -178.1mA   -218.3mA   -155.6mA
-1.085V   -119.7mA   -158.2mA   -105.2mA
-975mV    -78.23mA   -105.4mA   -81.84mA
-755mV    -46.51mA   -43.76mA   -52.55mA
-205mV    -7.828mA   -7.588mA   -7.437mA
565mV     15.8mA     15.01mA    16.28mA
2.16V     20.23mA    19.22mA    20.83mA
2.6V      34.17mA    32.47mA    35.2mA
2.82V     64.99mA    61.74mA    66.94mA
2.985V    140.2mA    133.2mA    144.4mA
3.6V      527.4mA    501mA      543.2mA
[Pullup]
|Voltage   I(typ)   I(min)   I(max)
-1.8V     453.6mA    473.7mA    442.9mA
-1.185V   122.1mA    155.2mA    102.9mA
-1.075V   75.9mA     106.3mA    62.67mA
-1.02V    58.64mA    84.5mA     51.83mA
-965mV    46.63mA    65.88mA    45.68mA
-800mV    31.1mA     32.59mA    32.9mA
-360mV    10.31mA    10.26mA    9.806mA
685mV     -13.45mA   -12.78mA   -13.85mA
2.225V    -21.23mA   -20.17mA   -21.87mA
2.665V    -49.94mA   -47.45mA   -51.44mA
2.885V    -102.4mA   -97.3mA    -105.5mA
3.6V      -485.9mA   -461.6mA   -500.5mA
[Ramp]
| variable   typ   min   max
dV/dt_r   0.485/0.355n   0.454/0.374n   0.510/0.428n
dV/dt_f   0.547/0.463n   0.516/0.435n   0.569/0.543n
R_load = 50.000
[Rising Waveform]
R_fixture = 50.000
V_fixture = 0.000
V_fixture_min = 0.000
V_fixture_max = 0.000
|  time   V(typ)   V(min)   V(max)
0s        116.5uV    208uV      -364.2uV
364ps     481.2uV    230.9uV    -3.525mV
458ps     2.746mV    250.8uV    280.3mV
599ps     389.2mV    -238.4uV   518.6mV
732ps     560.7mV    1.923mV    622.4mV
792ps     603.9mV    63.45mV    653.7mV
1.052ns   703.6mV    501.8mV    735.1mV
1.418ns   753.8mV    666.6mV    784.2mV
3.08ns    796.8mV    742.8mV    835.8mV
10ns      809.3mV    757.1mV    848.9mV
[Rising Waveform]
R_fixture = 50.000
V_fixture = 1.800
V_fixture_min = 1.710
V_fixture_max = 1.890
|  time   V(typ)   V(min)   V(max)
0s        888.3mV    843.3mV    942.9mV
334ps     888.5mV    843.4mV    952mV
441ps     900.2mV    843.7mV    1.474V
468ps     978.1mV    843.6mV    1.555V
548ps     1.428V     840.6mV    1.681V
642ps     1.605V     849.5mV    1.75V
852ps     1.713V     1.412V     1.816V
1.028ns   1.745V     1.589V     1.839V
2.271ns   1.787V     1.696V     1.879V
10ns      1.8V       1.71V      1.891V
[Falling Waveform]
R_fixture = 50.000
V_fixture = 1.800
V_fixture_min = 1.710
V_fixture_max = 1.890
|  time   V(typ)   V(min)   V(max)
0s        1.8V       1.71V      1.891V
356ps     1.8V       1.71V      1.89V
466ps     1.805V     1.71V      1.564V
586ps     1.471V     1.71V      1.366V
670ps     1.315V     1.711V     1.284V
860ps     1.137V     1.306V     1.17V
996ps     1.069V     1.135V     1.121V
1.54ns    962mV      927.2mV    1.027V
3.25ns    905.8mV    859.3mV    961.3mV
10ns      888.3mV    843.3mV    942.9mV
[Falling Waveform]
R_fixture = 50.000
V_fixture = 0.000
V_fixture_min = 0.000
V_fixture_max = 0.000
|  time   V(typ)   V(min)   V(max)
0s        809.3mV    757.1mV    848.9mV
346ps     809.1mV    757mV      842.7mV
436ps     797.7mV    757.1mV    370mV
556ps     283.9mV    758mV      152.6mV
650ps     139.9mV    745.5mV    99.27mV
690ps     113.6mV    672.6mV    85.43mV
800ps     72.19mV    236.3mV    60.73mV
950ps     46.06mV    97.29mV    42.83mV
1.896ns   13.18mV    13.11mV    12.29mV
10ns      116.5uV    208uV      -364.2uV
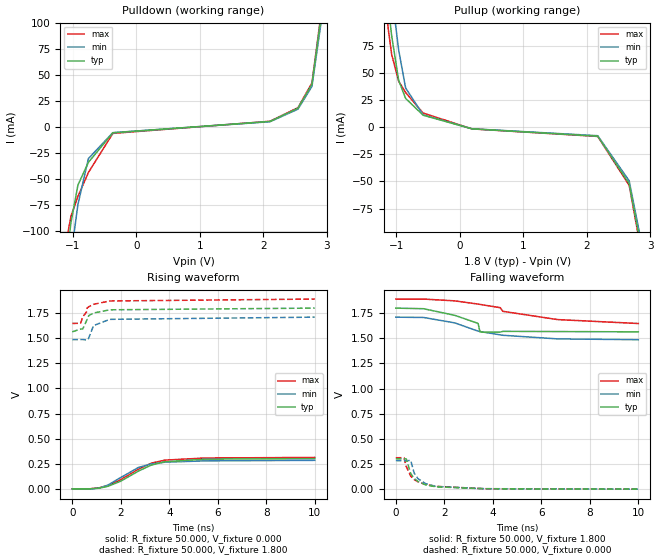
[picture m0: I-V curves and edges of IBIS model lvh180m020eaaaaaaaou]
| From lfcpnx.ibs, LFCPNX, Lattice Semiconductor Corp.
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[Model] lvh180m020eaaaaaaaou
Model_type Output
Polarity   Non-Inverting
Enable   Active-High
Vmeas =  0.900V
Cref =  0.0F
Rref =  1.000M
Vref =  0.0V
C_comp   5.000pF   4.000pF   5.500pF
[Temperature Range]   25.000   0.125k   -40.000
[Voltage Range]   1.800V   1.710V   1.890V
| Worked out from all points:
|   slope of the pulldown table from 0 to 0.27 V, typ, clamps not added: 114 ohm
|   slope of the pullup table from 0 to 0.27 V, typ, clamps not added: 125 ohm
|   rising waveform, R_fixture 50.000, V_fixture 0.000: 20-80 % time 1.46ns typ, 1.27ns min, 1.44ns max; typ from 0 V to 0.302 V
|   rising waveform, R_fixture 50.000, V_fixture 1.800: 20-80 % time 438ps typ, 449ps min, 506ps max; typ from 1.56 V to 1.8 V
|   falling waveform, R_fixture 50.000, V_fixture 1.800: 20-80 % time 1.41ns typ, 2.17ns min, 3ns max; typ from 1.8 V to 1.56 V
|   falling waveform, R_fixture 50.000, V_fixture 0.000: 20-80 % time 534ps typ, 526ps min, 602ps max; typ from 0.302 V to 0 V
[Pulldown]
|Voltage   I(typ)   I(min)   I(max)
-1.8V     -594.7mA   -582.9mA   -597.6mA
-1.14V    -149.2mA   -182.1mA   -130mA
-1.085V   -118.6mA   -152.1mA   -103.8mA
-1.03V    -91.8mA    -123.7mA   -85.71mA
-920mV    -55.62mA   -74.28mA   -66.5mA
-755mV    -33.8mA    -30.2mA    -43.57mA
-370mV    -5.436mA   -5.297mA   -6.016mA
2.105V    5.482mA    5.208mA    5.646mA
2.545V    18.18mA    17.27mA    18.72mA
2.765V    41.22mA    39.16mA    42.46mA
2.985V    140mA      133mA      144.2mA
3.6V      542.1mA    515mA      558.4mA
[Pullup]
|Voltage   I(typ)   I(min)   I(max)
-1.8V     556.2mA    580.5mA    544.4mA
-1.185V   144.1mA    185.3mA    121mA
-1.13V    112.6mA    153.6mA    91.2mA
-1.075V   84.2mA     123.5mA    67.08mA
-965mV    43.2mA     71.23mA    42.26mA
-855mV    26.46mA    36.03mA    31.86mA
-580mV    11mA       11.36mA    13.02mA
190mV     -1.578mA   -1.499mA   -1.625mA
2.17V     -8.31mA    -7.894mA   -8.559mA
2.665V    -51.98mA   -49.38mA   -53.54mA
2.83V     -103.2mA   -98mA      -106.3mA
3.6V      -669.1mA   -635.6mA   -689.2mA
[Ramp]
| variable   typ   min   max
dV/dt_r   0.182/1.489n   0.170/1.294n   0.187/1.457n
dV/dt_f   0.142/2.108n   0.134/2.538n   0.146/3.399n
R_load = 50.000
[Rising Waveform]
R_fixture = 50.000
V_fixture = 0.000
V_fixture_min = 0.000
V_fixture_max = 0.000
|  time   V(typ)   V(min)   V(max)
0s        157uV      372.7uV    411.8uV
736ps     -226.4uV   -3.538mV   571.1uV
1.127ns   6.967mV    8.833mV    10.95mV
1.467ns   24.81mV    36.87mV    33.65mV
1.988ns   75.06mV    111.2mV    90.49mV
2.731ns   177mV      212.8mV    195.6mV
3.259ns   236.6mV    248.3mV    255.6mV
3.821ns   269.8mV    265.1mV    285.7mV
5.476ns   295.3mV    278.5mV    306.9mV
10ns      302mV      283.6mV    312.5mV
[Rising Waveform]
R_fixture = 50.000
V_fixture = 1.800
V_fixture_min = 1.710
V_fixture_max = 1.890
|  time   V(typ)   V(min)   V(max)
0s        1.564V     1.486V     1.647V
343ps     1.591V     1.487V     1.649V
434ps     1.593V     1.487V     1.712V
606ps     1.684V     1.482V     1.768V
616ps     1.686V     1.482V     1.802V
636ps     1.69V      1.485V     1.806V
677ps     1.725V     1.501V     1.813V
877ps     1.751V     1.626V     1.838V
1.548ns   1.783V     1.688V     1.871V
10ns      1.8V       1.71V      1.89V
[Falling Waveform]
R_fixture = 50.000
V_fixture = 1.800
V_fixture_min = 1.710
V_fixture_max = 1.890
|  time   V(typ)   V(min)   V(max)
0s        1.8V       1.71V      1.89V
1.145ns   1.794V     1.707V     1.89V
2.434ns   1.728V     1.653V     1.872V
3.392ns   1.648V     1.571V     1.84V
3.469ns   1.565V     1.568V     1.837V
3.543ns   1.561V     1.564V     1.834V
4.309ns   1.562V     1.534V     1.804V
4.414ns   1.569V     1.53V      1.768V
6.674ns   1.567V     1.494V     1.686V
10ns      1.564V     1.486V     1.647V
[Falling Waveform]
R_fixture = 50.000
V_fixture = 0.000
V_fixture_min = 0.000
V_fixture_max = 0.000
|  time   V(typ)   V(min)   V(max)
0s        302mV      283.6mV    312.5mV
336ps     301.6mV    283.3mV    313.2mV
428ps     302.1mV    283.6mV    226mV
615ps     154.5mV    285.7mV    129.1mV
755ps     107.4mV    160.9mV    96.09mV
905ps     77.75mV    106.1mV    73.67mV
1.23ns    42.69mV    54.72mV    46.31mV
1.655ns   23.37mV    26.98mV    27.89mV
3.661ns   4.184mV    4.849mV    4.557mV
10ns      157uV      372.7uV    411.8uV
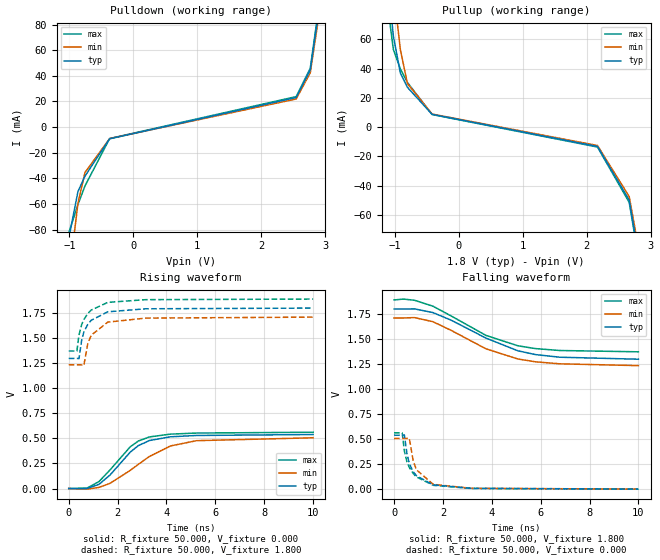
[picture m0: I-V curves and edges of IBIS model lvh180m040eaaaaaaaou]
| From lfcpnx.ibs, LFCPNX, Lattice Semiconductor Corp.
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[Model] lvh180m040eaaaaaaaou
Model_type Output
Polarity   Non-Inverting
Enable   Active-High
Vmeas =  0.900V
Cref =  0.0F
Rref =  1.000M
Vref =  0.0V
C_comp   5.000pF   4.000pF   5.500pF
[Temperature Range]   25.000   0.125k   -40.000
[Voltage Range]   1.800V   1.710V   1.890V
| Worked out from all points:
|   slope of the pulldown table from 0 to 0.27 V, typ, clamps not added: 53.8 ohm
|   slope of the pullup table from 0 to 0.27 V, typ, clamps not added: 67.5 ohm
|   rising waveform, R_fixture 50.000, V_fixture 0.000: 20-80 % time 1.29ns typ, 1.9ns min, 1.26ns max; typ from 0 V to 0.539 V
|   rising waveform, R_fixture 50.000, V_fixture 1.800: 20-80 % time 534ps typ, 527ps min, 561ps max; typ from 1.3 V to 1.8 V
|   falling waveform, R_fixture 50.000, V_fixture 1.800: 20-80 % time 2.61ns typ, 2.46ns min, 2.48ns max; typ from 1.8 V to 1.3 V
|   falling waveform, R_fixture 50.000, V_fixture 0.000: 20-80 % time 550ps typ, 515ps min, 575ps max; typ from 0.539 V to 0 V
[Pulldown]
|Voltage   I(typ)   I(min)   I(max)
-1.8V     -575.9mA   -586.4mA   -572.6mA
-1.195V   -178.2mA   -215.9mA   -156.4mA
-1.14V    -146.4mA   -184.9mA   -126.5mA
-1.03V    -92.1mA    -126.8mA   -85.71mA
-865mV    -50.21mA   -59.31mA   -60.31mA
-755mV    -38.15mA   -35.33mA   -45.8mA
-370mV    -9.1mA     -8.928mA   -8.877mA
2.545V    23.12mA    21.97mA    23.82mA
2.765V    44.64mA    42.41mA    45.98mA
2.875V    82.85mA    78.7mA     85.33mA
2.985V    139.8mA    132.8mA    144mA
3.6V      535.8mA    509mA      551.9mA
[Pullup]
|Voltage   I(typ)   I(min)   I(max)
-1.8V     534.8mA    558.2mA    522.8mA
-1.185V   140.5mA    179.8mA    117.9mA
-1.13V    110.8mA    149.6mA    89.9mA
-1.02V    62.15mA    94.7mA     53.03mA
-910mV    36.88mA    52.81mA    39.7mA
-800mV    27.18mA    29.74mA    30.53mA
-415mV    8.734mA    8.94mA     8.611mA
2.17V     -13.2mA    -12.54mA   -13.6mA
2.665V    -49.88mA   -47.38mA   -51.38mA
2.83V     -91.5mA    -86.9mA    -94.2mA
2.885V    -116.6mA   -110.8mA   -120.1mA
3.6V      -573.8mA   -545.1mA   -591mA
[Ramp]
| variable   typ   min   max
dV/dt_r   0.323/1.324n   0.304/1.932n   0.337/1.278n
dV/dt_f   0.301/2.656n   0.285/2.535n   0.325/2.563n
R_load = 50.000
[Rising Waveform]
R_fixture = 50.000
V_fixture = 0.000
V_fixture_min = 0.000
V_fixture_max = 0.000
|  time   V(typ)   V(min)   V(max)
0s        137.9uV    246.6uV    -315.7uV
746ps     671.7uV    -6.163mV   4.262mV
1.237ns   41.61mV    11.49mV    69.44mV
1.687ns   134.2mV    51.63mV    185mV
2.516ns   363.3mV    181mV      416.1mV
2.85ns    428.1mV    241.5mV    474.3mV
3.3ns     479mV      320.3mV    514.8mV
4.161ns   516.1mV    424.9mV    542.8mV
5.234ns   529.4mV    477.7mV    553.6mV
10ns      539mV      506.3mV    561.7mV
[Rising Waveform]
R_fixture = 50.000
V_fixture = 1.800
V_fixture_min = 1.710
V_fixture_max = 1.890
|  time   V(typ)   V(min)   V(max)
0s        1.298V     1.234V     1.372V
333ps     1.298V     1.235V     1.371V
419ps     1.296V     1.235V     1.532V
528ps     1.479V     1.233V     1.635V
616ps     1.559V     1.226V     1.684V
776ps     1.636V     1.442V     1.744V
917ps     1.678V     1.529V     1.78V
1.597ns   1.763V     1.66V      1.857V
3.148ns   1.793V     1.7V       1.884V
10ns      1.8V       1.71V      1.89V
[Falling Waveform]
R_fixture = 50.000
V_fixture = 1.800
V_fixture_min = 1.710
V_fixture_max = 1.890
|  time   V(typ)   V(min)   V(max)
0s        1.8V       1.71V      1.89V
383ps     1.8V       1.71V      1.899V
835ps     1.801V     1.714V     1.887V
1.59ns    1.764V     1.673V     1.828V
2.338ns   1.688V     1.586V     1.73V
3.761ns   1.509V     1.402V     1.536V
5.07ns    1.382V     1.3V       1.432V
5.794ns   1.344V     1.272V     1.404V
6.786ns   1.318V     1.252V     1.385V
10ns      1.298V     1.234V     1.372V
[Falling Waveform]
R_fixture = 50.000
V_fixture = 0.000
V_fixture_min = 0.000
V_fixture_max = 0.000
|  time   V(typ)   V(min)   V(max)
0s        539mV      506.3mV    561.7mV
333ps     538.5mV    506.1mV    563.6mV
421ps     541.5mV    506.3mV    381.9mV
529ps     350.9mV    506.1mV    272.5mV
625ps     255.5mV    507mV      216.2mV
785ps     173.7mV    280.4mV    155.7mV
919ps     133mV      192.7mV    121.1mV
1.604ns   42.62mV    47.83mV    38.08mV
3.154ns   8.336mV    8.5mV      6.322mV
10ns      137.9uV    246.6uV    -315.7uV
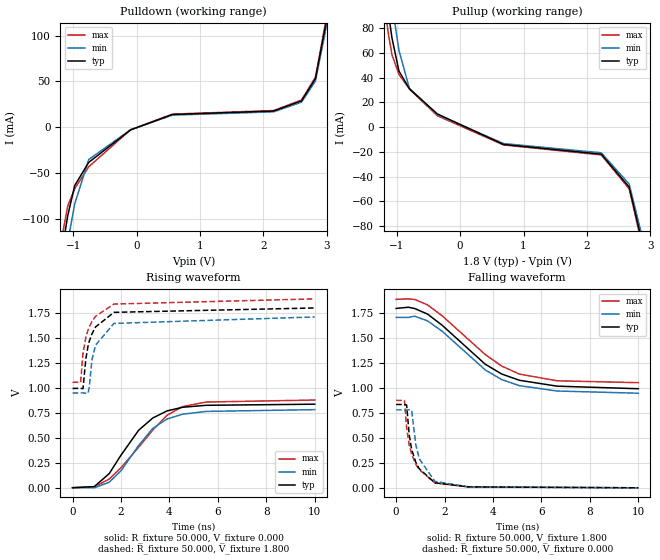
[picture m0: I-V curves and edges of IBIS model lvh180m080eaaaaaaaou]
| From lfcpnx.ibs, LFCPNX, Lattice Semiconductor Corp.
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[Model] lvh180m080eaaaaaaaou
Model_type Output
Polarity   Non-Inverting
Enable   Active-High
Vmeas =  0.900V
Cref =  0.0F
Rref =  1.000M
Vref =  0.0V
C_comp   5.000pF   4.000pF   5.500pF
[Temperature Range]   25.000   0.125k   -40.000
[Voltage Range]   1.800V   1.710V   1.890V
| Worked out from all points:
|   slope of the pulldown table from 0 to 0.27 V, typ, clamps not added: 33.5 ohm
|   slope of the pullup table from 0 to 0.27 V, typ, clamps not added: 40.5 ohm
|   rising waveform, R_fixture 50.000, V_fixture 0.000: 20-80 % time 1.56ns typ, 1.52ns min, 1.89ns max; typ from 0 V to 0.836 V
|   rising waveform, R_fixture 50.000, V_fixture 1.800: 20-80 % time 531ps typ, 527ps min, 592ps max; typ from 0.994 V to 1.8 V
|   falling waveform, R_fixture 50.000, V_fixture 1.800: 20-80 % time 2.38ns typ, 2.27ns min, 2.45ns max; typ from 1.8 V to 0.994 V
|   falling waveform, R_fixture 50.000, V_fixture 0.000: 20-80 % time 525ps typ, 497ps min, 574ps max; typ from 0.836 V to 0 V
[Pulldown]
|Voltage   I(typ)   I(min)   I(max)
-1.8V     -455.8mA   -464.1mA   -455.9mA
-1.195V   -143.5mA   -173.1mA   -127.2mA
-1.085V   -96.8mA    -125.7mA   -86.3mA
-975mV    -63.89mA   -84mA      -67.31mA
-755mV    -38.62mA   -35.5mA    -43.42mA
-95mV     -3.13mA    -2.89mA    -2.938mA
565mV     13.74mA    13.05mA    14.15mA
2.16V     17.52mA    16.65mA    18.05mA
2.6V      28.66mA    27.23mA    29.52mA
2.82V     53mA       50.35mA    54.59mA
2.985V    113.1mA    107.4mA    116.5mA
3.6V      423.8mA    402.6mA    436.5mA
[Pullup]
|Voltage   I(typ)   I(min)   I(max)
-1.8V     423.8mA    442.4mA    413.3mA
-1.185V   114.8mA    145.2mA    96mA
-1.13V    92.1mA     121.8mA    74.8mA
-1.075V   72.1mA     99.6mA     58.48mA
-965mV    45.28mA    62.08mA    42.62mA
-800mV    30.91mA    31.23mA    30.7mA
-360mV    10.61mA    10.03mA    9.151mA
685mV     -14.03mA   -13.33mA   -14.45mA
2.225V    -21.86mA   -20.76mA   -22.51mA
2.665V    -48.46mA   -46.04mA   -49.91mA
2.885V    -96.4mA    -91.6mA    -99.3mA
3.6V      -453.8mA   -431.1mA   -467.4mA
[Ramp]
| variable   typ   min   max
dV/dt_r   0.502/1.570n   0.469/1.567n   0.527/1.928n
dV/dt_f   0.483/2.463n   0.457/2.370n   0.502/2.551n
R_load = 50.000
[Rising Waveform]
R_fixture = 50.000
V_fixture = 0.000
V_fixture_min = 0.000
V_fixture_max = 0.000
|  time   V(typ)   V(min)   V(max)
0s        109.1uV    -50.23uV   -498.6uV
899ps     11.2mV     -1.538mV   7.638mV
1.512ns   140.7mV    54.59mV    86.45mV
2.002ns   326.5mV    170.7mV    200.6mV
2.729ns   575.5mV    422.6mV    405.1mV
3.311ns   697.6mV    593.1mV    577.4mV
3.898ns   768.8mV    687.7mV    724.1mV
4.541ns   805.3mV    735.7mV    812.7mV
5.52ns    825.2mV    764mV      857.8mV
10ns      836.2mV    781.8mV    877.9mV
[Rising Waveform]
R_fixture = 50.000
V_fixture = 1.800
V_fixture_min = 1.710
V_fixture_max = 1.890
|  time   V(typ)   V(min)   V(max)
0s        994.1mV    949mV      1.055V
333ps     994.5mV    949.2mV    1.056V
431ps     991.7mV    949.3mV    1.347V
548ps     1.289V     946mV      1.504V
639ps     1.419V     945.7mV    1.578V
692ps     1.468V     1.008V     1.611V
798ps     1.539V     1.278V     1.663V
951ps     1.61V      1.428V     1.717V
1.709ns   1.756V     1.645V     1.839V
10ns      1.8V       1.71V      1.891V
[Falling Waveform]
R_fixture = 50.000
V_fixture = 1.800
V_fixture_min = 1.710
V_fixture_max = 1.890
|  time   V(typ)   V(min)   V(max)
0s        1.8V       1.71V      1.891V
502ps     1.812V     1.71V      1.896V
770ps     1.799V     1.722V     1.89V
1.298ns   1.743V     1.675V     1.836V
1.901ns   1.631V     1.571V     1.726V
3.68ns    1.24V      1.183V     1.337V
4.358ns   1.142V     1.086V     1.222V
5.09ns    1.079V     1.025V     1.141V
6.644ns   1.02V      971.4mV    1.074V
10ns      994.1mV    949mV      1.055V
[Falling Waveform]
R_fixture = 50.000
V_fixture = 0.000
V_fixture_min = 0.000
V_fixture_max = 0.000
|  time   V(typ)   V(min)   V(max)
0s        836.2mV    781.8mV    877.9mV
343ps     835.8mV    781.6mV    875.5mV
433ps     831.4mV    781.8mV    603.2mV
541ps     530.8mV    782.1mV    428.2mV
641ps     384.7mV    776.9mV    336.1mV
811ps     256.9mV    436.4mV    237.8mV
951ps     191.8mV    293.2mV    183.4mV
1.599ns   49.92mV    64.81mV    49.67mV
2.989ns   9.162mV    9.755mV    7.477mV
10ns      109.1uV    -50.23uV   -498.6uV
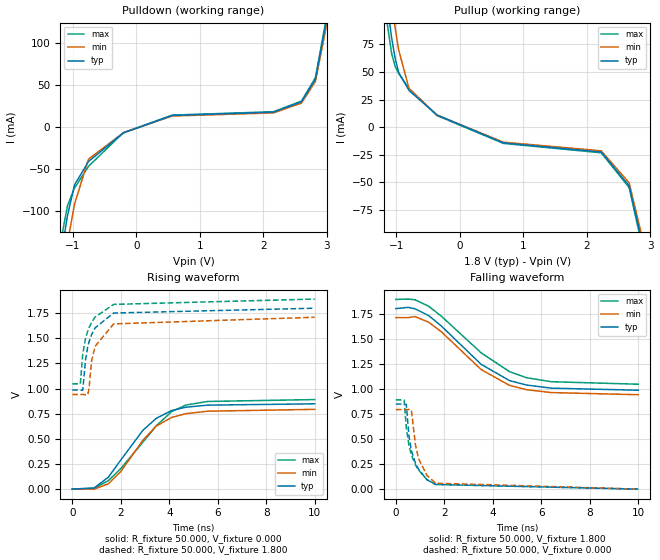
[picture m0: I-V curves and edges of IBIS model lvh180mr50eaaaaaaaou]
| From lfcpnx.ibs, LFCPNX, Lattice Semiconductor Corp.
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[Model] lvh180mr50eaaaaaaaou
Model_type Output
Polarity   Non-Inverting
Enable   Active-High
Vmeas =  0.900V
Cref =  0.0F
Rref =  1.000M
Vref =  0.0V
C_comp   5.000pF   4.000pF   5.500pF
[Temperature Range]   25.000   0.125k   -40.000
[Voltage Range]   1.800V   1.710V   1.890V
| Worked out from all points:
|   slope of the pulldown table from 0 to 0.27 V, typ, clamps not added: 33.1 ohm
|   slope of the pullup table from 0 to 0.27 V, typ, clamps not added: 39.6 ohm
|   rising waveform, R_fixture 50.000, V_fixture 0.000: 20-80 % time 1.67ns typ, 1.56ns min, 1.89ns max; typ from 0 V to 0.848 V
|   rising waveform, R_fixture 50.000, V_fixture 1.800: 20-80 % time 535ps typ, 526ps min, 591ps max; typ from 0.986 V to 1.8 V
|   falling waveform, R_fixture 50.000, V_fixture 1.800: 20-80 % time 2.26ns typ, 2.18ns min, 2.46ns max; typ from 1.8 V to 0.986 V
|   falling waveform, R_fixture 50.000, V_fixture 0.000: 20-80 % time 522ps typ, 494ps min, 574ps max; typ from 0.848 V to 0 V
[Pulldown]
|Voltage   I(typ)   I(min)   I(max)
-1.8V     -499.1mA   -510.8mA   -495.9mA
-1.195V   -156.8mA   -190.3mA   -138.1mA
-1.085V   -105.4mA   -137.9mA   -93.5mA
-975mV    -68.84mA   -91.9mA    -72.63mA
-755mV    -40.93mA   -38.14mA   -46.64mA
-205mV    -6.889mA   -6.613mA   -6.6mA
565mV     13.91mA    13.21mA    14.32mA
2.16V     17.8mA     16.91mA    18.33mA
2.6V      30.07mA    28.57mA    30.98mA
2.82V     57.19mA    54.33mA    58.91mA
2.985V    123.3mA    117.1mA    127mA
3.6V      464mA      440.8mA    477.9mA
[Pullup]
|Voltage   I(typ)   I(min)   I(max)
-1.8V     483.2mA    504.5mA    471.7mA
-1.185V   130mA      165.3mA    109.6mA
-1.075V   80.9mA     113.2mA    66.76mA
-1.02V    62.46mA    90.1mA     55.21mA
-965mV    49.67mA    70.17mA    48.65mA
-800mV    33.13mA    34.71mA    35.04mA
-360mV    10.98mA    10.93mA    10.45mA
685mV     -14.32mA   -13.61mA   -14.75mA
2.225V    -22.62mA   -21.49mA   -23.3mA
2.665V    -53.2mA    -50.54mA   -54.79mA
2.885V    -109mA     -103.5mA   -112.3mA
3.6V      -517.6mA   -491.7mA   -533.1mA
[Ramp]
| variable   typ   min   max
dV/dt_r   0.509/1.671n   0.476/1.607n   0.535/1.927n
dV/dt_f   0.488/2.308n   0.461/2.265n   0.507/2.476n
R_load = 50.000
[Rising Waveform]
R_fixture = 50.000
V_fixture = 0.000
V_fixture_min = 0.000
V_fixture_max = 0.000
|  time   V(typ)   V(min)   V(max)
0s        106.1uV    133.8uV    -290.9uV
899ps     9.928mV    -1.141mV   8.012mV
1.492ns   119.2mV    52.98mV    83.96mV
2.011ns   292.2mV    177.2mV    206.1mV
2.915ns   585.7mV    486.6mV    467.6mV
3.459ns   702.8mV    625.8mV    628.1mV
4.095ns   781.2mV    712.3mV    770.5mV
4.679ns   814.6mV    749.9mV    835.6mV
5.581ns   835.1mV    774.9mV    871.8mV
10ns      848.4mV    793.3mV    890.8mV
[Rising Waveform]
R_fixture = 50.000
V_fixture = 1.800
V_fixture_min = 1.710
V_fixture_max = 1.890
|  time   V(typ)   V(min)   V(max)
0s        986mV      941.4mV    1.046V
333ps     986.5mV    941.4mV    1.048V
431ps     982.8mV    941.8mV    1.342V
548ps     1.288V     938.1mV    1.5V
639ps     1.417V     937.6mV    1.574V
692ps     1.466V     1.004V     1.607V
792ps     1.534V     1.269V     1.657V
942ps     1.605V     1.421V     1.712V
1.708ns   1.752V     1.644V     1.838V
10ns      1.8V       1.71V      1.891V
[Falling Waveform]
R_fixture = 50.000
V_fixture = 1.800
V_fixture_min = 1.710
V_fixture_max = 1.890
|  time   V(typ)   V(min)   V(max)
0s        1.8V       1.71V      1.891V
512ps     1.812V     1.71V      1.895V
791ps     1.798V     1.72V      1.888V
1.35ns    1.731V     1.665V     1.824V
1.873ns   1.627V     1.57V      1.725V
3.519ns   1.244V     1.192V     1.359V
4.69ns    1.082V     1.034V     1.171V
5.39ns    1.038V     991.5mV    1.111V
6.404ns   1.007V     962.7mV    1.071V
10ns      986mV      941.4mV    1.046V
[Falling Waveform]
R_fixture = 50.000
V_fixture = 0.000
V_fixture_min = 0.000
V_fixture_max = 0.000
|  time   V(typ)   V(min)   V(max)
0s        848.4mV    793.3mV    890.8mV
343ps     847.9mV    793.2mV    888.4mV
432ps     843.6mV    793.3mV    614.7mV
542ps     526.7mV    793.7mV    433.5mV
641ps     385.3mV    788mV      341.2mV
811ps     258.1mV    437.2mV    241.4mV
941ps     196.5mV    301.9mV    189.6mV
1.281ns   93.32mV    137.7mV    95.71mV
1.641ns   46.25mV    59.3mV     47.12mV
10ns      106.1uV    133.8uV    -290.9uV
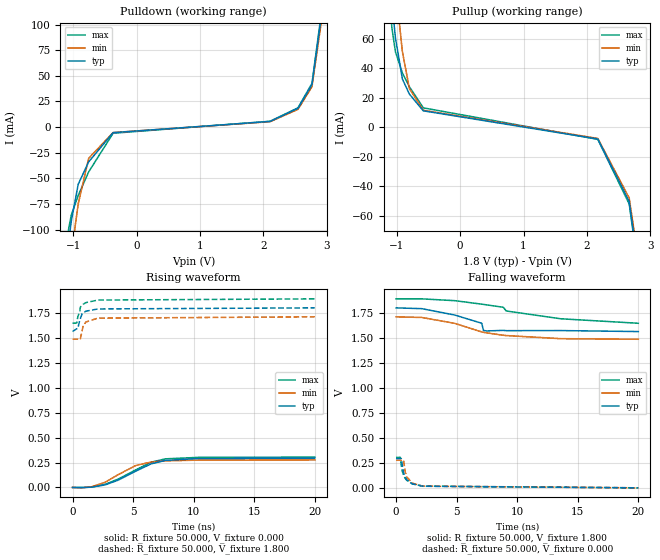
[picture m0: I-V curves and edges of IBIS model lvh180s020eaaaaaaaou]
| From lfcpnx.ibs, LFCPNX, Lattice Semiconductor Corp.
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[Model] lvh180s020eaaaaaaaou
Model_type Output
Polarity   Non-Inverting
Enable   Active-High
Vmeas =  0.900V
Cref =  0.0F
Rref =  1.000M
Vref =  0.0V
C_comp   5.000pF   4.000pF   5.500pF
[Temperature Range]   25.000   0.125k   -40.000
[Voltage Range]   1.800V   1.710V   1.890V
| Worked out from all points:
|   slope of the pulldown table from 0 to 0.27 V, typ, clamps not added: 114 ohm
|   slope of the pullup table from 0 to 0.27 V, typ, clamps not added: 128 ohm
|   rising waveform, R_fixture 50.000, V_fixture 0.000: 20-80 % time 2.97ns typ, 2.5ns min, 2.94ns max; typ from 0 V to 0.294 V
|   rising waveform, R_fixture 50.000, V_fixture 1.800: 20-80 % time 445ps typ, 470ps min, 521ps max; typ from 1.56 V to 1.8 V
|   falling waveform, R_fixture 50.000, V_fixture 1.800: 20-80 % time 3.2ns typ, 4.48ns min, 6.51ns max; typ from 1.8 V to 1.56 V
|   falling waveform, R_fixture 50.000, V_fixture 0.000: 20-80 % time 563ps typ, 551ps min, 605ps max; typ from 0.294 V to 0 V
[Pulldown]
|Voltage   I(typ)   I(min)   I(max)
-1.8V     -596.5mA   -588.3mA   -599.3mA
-1.14V    -149.6mA   -183.8mA   -130.4mA
-1.085V   -118.9mA   -153.6mA   -104mA
-1.03V    -92.1mA    -124.8mA   -85.94mA
-920mV    -55.8mA    -74.97mA   -66.68mA
-755mV    -33.91mA   -30.48mA   -43.69mA
-370mV    -5.454mA   -5.346mA   -6.032mA
2.105V    5.499mA    5.224mA    5.664mA
2.545V    18.24mA    17.32mA    18.78mA
2.765V    41.35mA    39.29mA    42.59mA
2.985V    140.5mA    133.5mA    144.7mA
3.6V      543.9mA    516.7mA    560.2mA
[Pullup]
|Voltage   I(typ)   I(min)   I(max)
-1.8V     556.2mA    580.5mA    544.4mA
-1.185V   144.1mA    185.3mA    121mA
-1.13V    112.6mA    153.6mA    91.2mA
-1.075V   84.2mA     123.5mA    67.08mA
-1.02V    60.53mA    95.7mA     51.03mA
-910mV    32.55mA    51.06mA    36.67mA
-800mV    22.37mA    26.11mA    27.37mA
-580mV    11mA       11.36mA    13.02mA
2.17V     -8.087mA   -7.683mA   -8.329mA
2.665V    -50.59mA   -48.06mA   -52.11mA
2.83V     -100.4mA   -95.4mA    -103.4mA
3.6V      -651.2mA   -618.6mA   -670.7mA
[Ramp]
| variable   typ   min   max
dV/dt_r   0.183/3.011n   0.165/2.520n   0.182/2.968n
dV/dt_f   0.142/4.262n   0.134/5.079n   0.146/7.314n
R_load = 50.000
[Rising Waveform]
R_fixture = 50.000
V_fixture = 0.000
V_fixture_min = 0.000
V_fixture_max = 0.000
|  time   V(typ)   V(min)   V(max)
0s        158.1uV    395uV      413.5uV
726ps     -510.9uV   -3.587mV   -55uV
1.558ns   2.916mV    6.894mV    3.753mV
2.683ns   25.92mV    51.87mV    31.32mV
3.761ns   73.04mV    128.5mV    83.78mV
5.214ns   163.3mV    219.9mV    176.3mV
6.484ns   236.5mV    255.1mV    253.2mV
7.66ns    271mV      267.1mV    287mV
10.39ns   290.6mV    274.3mV    301.9mV
20ns      293.9mV    276.2mV    304.3mV
[Rising Waveform]
R_fixture = 50.000
V_fixture = 1.800
V_fixture_min = 1.710
V_fixture_max = 1.890
|  time   V(typ)   V(min)   V(max)
0s        1.563V     1.486V     1.646V
343ps     1.59V      1.486V     1.648V
434ps     1.592V     1.486V     1.711V
606ps     1.683V     1.481V     1.768V
636ps     1.69V      1.483V     1.805V
786ps     1.74V      1.571V     1.827V
888ps     1.751V     1.627V     1.837V
1.116ns   1.767V     1.659V     1.853V
2.096ns   1.789V     1.697V     1.878V
20ns      1.8V       1.71V      1.89V
[Falling Waveform]
R_fixture = 50.000
V_fixture = 1.800
V_fixture_min = 1.710
V_fixture_max = 1.890
|  time   V(typ)   V(min)   V(max)
0s        1.8V       1.71V      1.89V
2.125ns   1.792V     1.704V     1.89V
4.848ns   1.728V     1.645V     1.872V
7.073ns   1.646V     1.559V     1.837V
7.206ns   1.575V     1.556V     1.835V
7.471ns   1.569V     1.55V      1.83V
8.844ns   1.575V     1.526V     1.806V
9.095ns   1.572V     1.523V     1.769V
13.58ns   1.573V     1.492V     1.691V
20ns      1.563V     1.486V     1.646V
[Falling Waveform]
R_fixture = 50.000
V_fixture = 0.000
V_fixture_min = 0.000
V_fixture_max = 0.000
|  time   V(typ)   V(min)   V(max)
0s        293.9mV    276.2mV    304.3mV
336ps     293.5mV    276mV      305.2mV
426ps     294.6mV    276.2mV    222.2mV
499ps     234.5mV    275.8mV    170.8mV
615ps     150.6mV    278.7mV    126mV
745ps     107.4mV    163.1mV    95.67mV
874ps     81.88mV    111.6mV    75.83mV
1.32ns    40.61mV    48.16mV    40.8mV
2.195ns   16.06mV    16.7mV     17.54mV
20ns      158.1uV    395uV      413.5uV
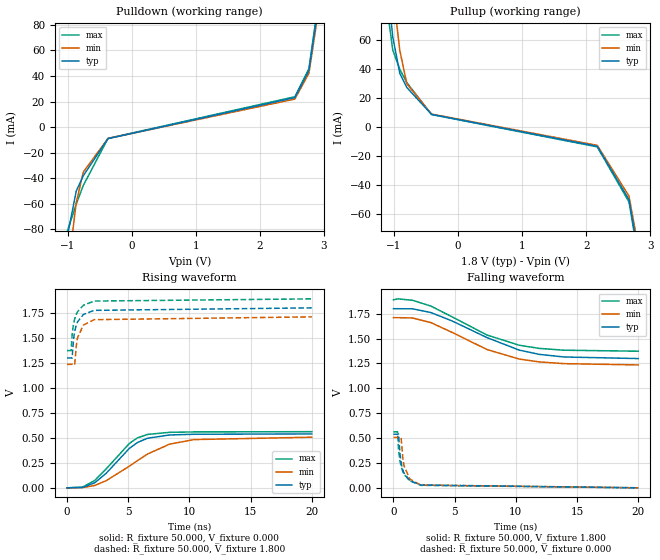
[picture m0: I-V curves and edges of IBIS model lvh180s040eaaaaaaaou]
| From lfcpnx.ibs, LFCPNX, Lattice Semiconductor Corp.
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[Model] lvh180s040eaaaaaaaou
Model_type Output
Polarity   Non-Inverting
Enable   Active-High
Vmeas =  0.900V
Cref =  0.0F
Rref =  1.000M
Vref =  0.0V
C_comp   5.000pF   4.000pF   5.500pF
[Temperature Range]   25.000   0.125k   -40.000
[Voltage Range]   1.800V   1.710V   1.890V
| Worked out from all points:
|   slope of the pulldown table from 0 to 0.27 V, typ, clamps not added: 53.9 ohm
|   slope of the pullup table from 0 to 0.27 V, typ, clamps not added: 67.5 ohm
|   rising waveform, R_fixture 50.000, V_fixture 0.000: 20-80 % time 2.6ns typ, 4.02ns min, 2.54ns max; typ from 0 V to 0.539 V
|   rising waveform, R_fixture 50.000, V_fixture 1.800: 20-80 % time 567ps typ, 547ps min, 610ps max; typ from 1.3 V to 1.8 V
|   falling waveform, R_fixture 50.000, V_fixture 1.800: 20-80 % time 5.5ns typ, 5.11ns min, 5.17ns max; typ from 1.8 V to 1.3 V
|   falling waveform, R_fixture 50.000, V_fixture 0.000: 20-80 % time 561ps typ, 549ps min, 603ps max; typ from 0.539 V to 0 V
[Pulldown]
|Voltage   I(typ)   I(min)   I(max)
-1.8V     -574.7mA   -585.3mA   -571.8mA
-1.195V   -177.7mA   -215.5mA   -156.2mA
-1.14V    -146.2mA   -184.6mA   -126.3mA
-1.03V    -92mA      -126.5mA   -85.59mA
-865mV    -50.11mA   -59.21mA   -60.22mA
-755mV    -38.07mA   -35.27mA   -45.74mA
-370mV    -9.08mA    -8.912mA   -8.864mA
2.545V    23.08mA    21.92mA    23.77mA
2.765V    44.55mA    42.32mA    45.88mA
2.875V    82.67mA    78.54mA    85.15mA
2.985V    139.6mA    132.6mA    143.8mA
3.6V      534.6mA    507.9mA    550.6mA
[Pullup]
|Voltage   I(typ)   I(min)   I(max)
-1.8V     534.8mA    558.2mA    522.8mA
-1.185V   140.5mA    179.8mA    117.9mA
-1.13V    110.8mA    149.6mA    89.9mA
-1.02V    62.15mA    94.7mA     53.03mA
-910mV    36.88mA    52.81mA    39.7mA
-800mV    27.18mA    29.74mA    30.53mA
-415mV    8.734mA    8.939mA    8.611mA
2.17V     -13.2mA    -12.54mA   -13.6mA
2.665V    -49.88mA   -47.38mA   -51.38mA
2.83V     -91.5mA    -86.9mA    -94.2mA
2.885V    -116.6mA   -110.8mA   -120.1mA
3.6V      -573.8mA   -545.1mA   -591mA
[Ramp]
| variable   typ   min   max
dV/dt_r   0.323/2.626n   0.304/4.025n   0.337/2.546n
dV/dt_f   0.300/5.549n   0.285/5.122n   0.326/5.194n
R_load = 50.000
[Rising Waveform]
R_fixture = 50.000
V_fixture = 0.000
V_fixture_min = 0.000
V_fixture_max = 0.000
|  time   V(typ)   V(min)   V(max)
0s        136.7uV    246.4uV    -312.5uV
1.268ns   3.97mV     1.963mV    6.796mV
2.257ns   49.93mV    23.2mV     72.59mV
3.191ns   144.2mV    70.94mV    188.2mV
5.1ns     395.2mV    217.1mV    444.3mV
5.765ns   453.9mV    272.9mV    500.2mV
6.575ns   495.8mV    337.5mV    534mV
8.379ns   528.4mV    436.9mV    555mV
10.38ns   535.8mV    482.5mV    559.1mV
20ns      539mV      506.3mV    561.7mV
[Rising Waveform]
R_fixture = 50.000
V_fixture = 1.800
V_fixture_min = 1.710
V_fixture_max = 1.890
|  time   V(typ)   V(min)   V(max)
0s        1.299V     1.235V     1.373V
334ps     1.299V     1.235V     1.372V
419ps     1.297V     1.236V     1.533V
526ps     1.477V     1.234V     1.634V
627ps     1.566V     1.23V      1.689V
756ps     1.628V     1.419V     1.735V
858ps     1.66V      1.501V     1.761V
1.338ns   1.734V     1.628V     1.826V
2.217ns   1.775V     1.682V     1.868V
20ns      1.8V       1.71V      1.89V
[Falling Waveform]
R_fixture = 50.000
V_fixture = 1.800
V_fixture_min = 1.710
V_fixture_max = 1.890
|  time   V(typ)   V(min)   V(max)
0s        1.8V       1.71V      1.89V
383ps     1.8V       1.71V      1.899V
1.555ns   1.799V     1.707V     1.885V
3.05ns    1.762V     1.661V     1.827V
4.831ns   1.675V     1.56V      1.716V
7.64ns    1.51V      1.39V      1.536V
10.28ns   1.384V     1.294V     1.433V
11.93ns   1.341V     1.265V     1.401V
13.94ns   1.315V     1.248V     1.383V
20ns      1.299V     1.235V     1.373V
[Falling Waveform]
R_fixture = 50.000
V_fixture = 0.000
V_fixture_min = 0.000
V_fixture_max = 0.000
|  time   V(typ)   V(min)   V(max)
0s        539mV      506.3mV    561.7mV
333ps     538.5mV    506.1mV    563.9mV
421ps     541.9mV    506.3mV    382.1mV
529ps     351.3mV    506.1mV    272.7mV
629ps     252.9mV    505.6mV    214.6mV
765ps     181.7mV    302.8mV    162.9mV
859ps     149.8mV    224.2mV    137.9mV
1.339ns   71.53mV    87.91mV    70.43mV
2.245ns   28.47mV    27.54mV    25.06mV
20ns      136.7uV    246.4uV    -312.5uV
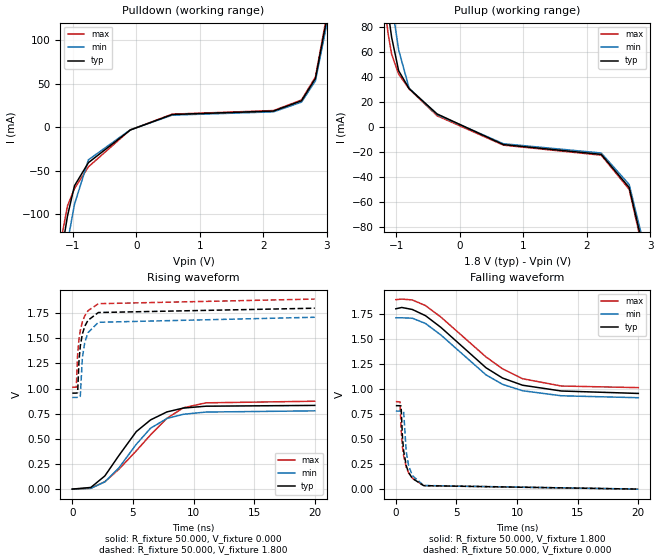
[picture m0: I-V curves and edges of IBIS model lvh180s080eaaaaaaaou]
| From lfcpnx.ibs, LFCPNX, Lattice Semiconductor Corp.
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[Model] lvh180s080eaaaaaaaou
Model_type Output
Polarity   Non-Inverting
Enable   Active-High
Vmeas =  0.900V
Cref =  0.0F
Rref =  1.000M
Vref =  0.0V
C_comp   5.000pF   4.000pF   5.500pF
[Temperature Range]   25.000   0.125k   -40.000
[Voltage Range]   1.800V   1.710V   1.890V
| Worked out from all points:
|   slope of the pulldown table from 0 to 0.27 V, typ, clamps not added: 31.8 ohm
|   slope of the pullup table from 0 to 0.27 V, typ, clamps not added: 40.7 ohm
|   rising waveform, R_fixture 50.000, V_fixture 0.000: 20-80 % time 3.27ns typ, 3.18ns min, 4.11ns max; typ from 0 V to 0.833 V
|   rising waveform, R_fixture 50.000, V_fixture 1.800: 20-80 % time 567ps typ, 549ps min, 610ps max; typ from 0.955 V to 1.8 V
|   falling waveform, R_fixture 50.000, V_fixture 1.800: 20-80 % time 5ns typ, 4.77ns min, 5.23ns max; typ from 1.8 V to 0.955 V
|   falling waveform, R_fixture 50.000, V_fixture 0.000: 20-80 % time 555ps typ, 548ps min, 599ps max; typ from 0.833 V to 0 V
[Pulldown]
|Voltage   I(typ)   I(min)   I(max)
-1.8V     -480.5mA   -490mA     -478mA
-1.195V   -151.2mA   -182.8mA   -133.3mA
-1.085V   -102.1mA   -132.8mA   -90.4mA
-975mV    -67.35mA   -88.7mA    -70.58mA
-755mV    -40.72mA   -37.48mA   -45.52mA
-95mV     -3.299mA   -3.052mA   -3.081mA
565mV     14.48mA    13.76mA    14.92mA
2.16V     18.47mA    17.55mA    19.03mA
2.6V      30.21mA    28.7mA     31.12mA
2.82V     55.87mA    53.08mA    57.55mA
2.985V    119.2mA    113.2mA    122.8mA
3.6V      446.7mA    424.4mA    460.1mA
[Pullup]
|Voltage   I(typ)   I(min)   I(max)
-1.8V     421.6mA    440.1mA    411.1mA
-1.185V   114.2mA    144.4mA    95.5mA
-1.13V    91.6mA     121.1mA    74.4mA
-1.075V   71.7mA     99.1mA     58.18mA
-965mV    45.05mA    61.76mA    42.4mA
-800mV    30.75mA    31.07mA    30.54mA
-360mV    10.55mA    9.977mA    9.103mA
685mV     -13.96mA   -13.26mA   -14.37mA
2.225V    -21.74mA   -20.66mA   -22.4mA
2.665V    -48.21mA   -45.8mA    -49.65mA
2.885V    -95.9mA    -91.1mA    -98.8mA
3.6V      -451.4mA   -428.8mA   -464.9mA
[Ramp]
| variable   typ   min   max
dV/dt_r   0.500/3.285n   0.467/3.227n   0.525/4.120n
dV/dt_f   0.507/5.030n   0.479/4.778n   0.527/5.240n
R_load = 50.000
[Rising Waveform]
R_fixture = 50.000
V_fixture = 0.000
V_fixture_min = 0.000
V_fixture_max = 0.000
|  time   V(typ)   V(min)   V(max)
0s        110.8uV    -40.77uV   -545.9uV
1.528ns   16.44mV    7.919mV    8.43mV
2.684ns   130.7mV    71.74mV    73.52mV
3.829ns   331.5mV    208.8mV    195.5mV
5.28ns    572.3mV    446mV      380.9mV
6.454ns   688.4mV    605.6mV    539.4mV
7.806ns   768.1mV    702.6mV    704.4mV
9.159ns   806.4mV    744.5mV    808.8mV
11.02ns   825mV      766.7mV    858.4mV
20ns      832.9mV    778.8mV    874.5mV
[Rising Waveform]
R_fixture = 50.000
V_fixture = 1.800
V_fixture_min = 1.710
V_fixture_max = 1.890
|  time   V(typ)   V(min)   V(max)
0s        954.9mV    912.3mV    1.013V
333ps     955.3mV    912.5mV    1.014V
441ps     959mV      912.8mV    1.339V
548ps     1.264V     909mV      1.484V
662ps     1.424V     924.7mV    1.577V
831ps     1.542V     1.306V     1.663V
1.031ns   1.621V     1.46V      1.725V
1.299ns   1.68V      1.557V     1.775V
2.149ns   1.757V     1.66V      1.845V
20ns      1.8V       1.71V      1.891V
[Falling Waveform]
R_fixture = 50.000
V_fixture = 1.800
V_fixture_min = 1.710
V_fixture_max = 1.890
|  time   V(typ)   V(min)   V(max)
0s        1.8V       1.71V      1.891V
491ps     1.813V     1.71V      1.897V
1.36ns    1.793V     1.706V     1.888V
2.449ns   1.731V     1.653V     1.832V
3.699ns   1.616V     1.54V      1.719V
7.44ns    1.211V     1.14V      1.319V
8.797ns   1.109V     1.046V     1.201V
10.45ns   1.037V     981.9mV    1.102V
13.65ns   979.3mV    931.7mV    1.029V
20ns      954.9mV    912.3mV    1.013V
[Falling Waveform]
R_fixture = 50.000
V_fixture = 0.000
V_fixture_min = 0.000
V_fixture_max = 0.000
|  time   V(typ)   V(min)   V(max)
0s        832.9mV    778.8mV    874.5mV
346ps     832.5mV    778.6mV    869.9mV
432ps     829.6mV    778.8mV    603.6mV
541ps     529mV      779.1mV    426.8mV
642ps     382.4mV    773.6mV    334.4mV
861ps     232.4mV    370.4mV    218.2mV
1.052ns   165.5mV    236.5mV    161.9mV
1.362ns   107mV      135mV      108.7mV
2.3ns     34.55mV    35.98mV    34.45mV
20ns      110.8uV    -40.77uV   -545.9uV
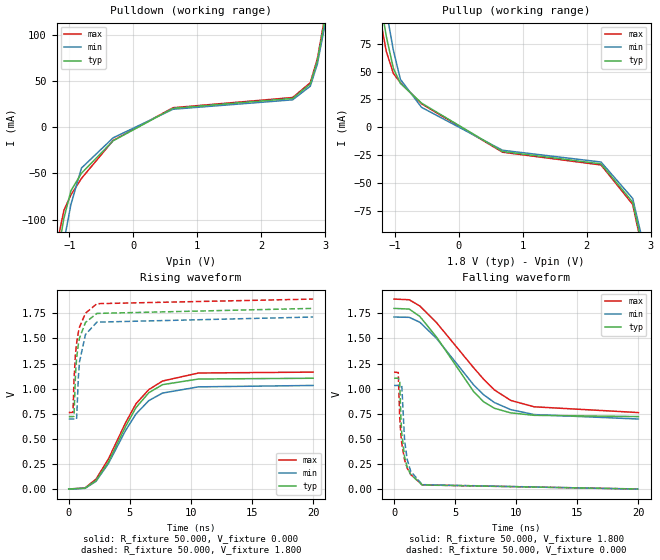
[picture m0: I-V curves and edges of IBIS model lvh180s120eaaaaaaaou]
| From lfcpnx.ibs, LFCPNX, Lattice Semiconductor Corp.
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[Model] lvh180s120eaaaaaaaou
Model_type Output
Polarity   Non-Inverting
Enable   Active-High
Vmeas =  0.900V
Cref =  0.0F
Rref =  1.000M
Vref =  0.0V
C_comp   5.000pF   4.000pF   5.500pF
[Temperature Range]   25.000   0.125k   -40.000
[Voltage Range]   1.800V   1.710V   1.890V
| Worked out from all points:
|   slope of the pulldown table from 0 to 0.27 V, typ, clamps not added: 23.9 ohm
|   slope of the pullup table from 0 to 0.27 V, typ, clamps not added: 26.5 ohm
|   rising waveform, R_fixture 50.000, V_fixture 0.000: 20-80 % time 2.91ns typ, 3.03ns min, 3.08ns max; typ from 0 V to 1.1 V
|   rising waveform, R_fixture 50.000, V_fixture 1.800: 20-80 % time 567ps typ, 548ps min, 609ps max; typ from 0.722 V to 1.8 V
|   falling waveform, R_fixture 50.000, V_fixture 1.800: 20-80 % time 3.69ns typ, 4.32ns min, 4.79ns max; typ from 1.8 V to 0.722 V
|   falling waveform, R_fixture 50.000, V_fixture 0.000: 20-80 % time 553ps typ, 548ps min, 598ps max; typ from 1.1 V to 0 V
[Pulldown]
|Voltage   I(typ)   I(min)   I(max)
-1.8V     -446.5mA   -453mA     -445.9mA
-1.195V   -143mA     -169.9mA   -127.2mA
-1.085V   -98.6mA    -123.8mA   -89.9mA
-975mV    -68.8mA    -83.6mA    -73.2mA
-810mV    -49.78mA   -44.19mA   -55.42mA
-315mV    -14.76mA   -11.51mA   -14.36mA
620mV     20.37mA    19.36mA    20.99mA
2.49V     31.09mA    29.54mA    32.02mA
2.765V    46.6mA     44.27mA    48mA
2.875V    71.6mA     68mA       73.7mA
2.985V    112.9mA    107.3mA    116.3mA
3.6V      415mA      394.2mA    427.4mA
[Pullup]
|Voltage   I(typ)   I(min)   I(max)
-1.8V     361.7mA    376.4mA    352.5mA
-1.24V    121.1mA    145.2mA    105mA
-1.185V   100.5mA    124.5mA    85mA
-1.13V    81.5mA     104.6mA    68mA
-1.02V    52.93mA    69.1mA     48.27mA
-910mV    39.34mA    42.93mA    39.98mA
-580mV    21.62mA    17.79mA    21.03mA
685mV     -21.87mA   -20.77mA   -22.52mA
2.225V    -33.01mA   -31.36mA   -34mA
2.72V     -67.47mA   -64.1mA    -69.5mA
2.885V    -110.3mA   -104.8mA   -113.6mA
3.6V      -501mA     -475.9mA   -516mA
[Ramp]
| variable   typ   min   max
dV/dt_r   0.662/2.926n   0.645/3.041n   0.699/3.099n
dV/dt_f   0.648/3.715n   0.610/4.333n   0.679/4.805n
R_load = 50.000
[Rising Waveform]
R_fixture = 50.000
V_fixture = 0.000
V_fixture_min = 0.000
V_fixture_max = 0.000
|  time   V(typ)   V(min)   V(max)
0s        101.1uV    -1.567mV   -180.2uV
1.327ns   9.022mV    6.225mV    10.62mV
2.228ns   83.43mV    76.17mV    97.6mV
3.249ns   269.4mV    254.4mV    299.2mV
4.64ns    620.6mV    580.7mV    657.4mV
5.504ns   811.3mV    747.8mV    850mV
6.551ns   959.2mV    880.8mV    990.6mV
7.673ns   1.04V      956mV      1.076V
10.61ns   1.096V     1.018V     1.156V
20ns      1.104V     1.032V     1.165V
[Rising Waveform]
R_fixture = 50.000
V_fixture = 1.800
V_fixture_min = 1.710
V_fixture_max = 1.890
|  time   V(typ)   V(min)   V(max)
0s        721.7mV    697.4mV    761.9mV
346ps     721.6mV    697.5mV    763.9mV
431ps     723.4mV    697.8mV    1.089V
549ps     1.134V     693.9mV    1.342V
642ps     1.302V     695.8mV    1.451V
791ps     1.447V     1.121V     1.565V
881ps     1.505V     1.267V     1.613V
1.369ns   1.66V      1.54V      1.752V
2.303ns   1.75V      1.663V     1.847V
20ns      1.8V       1.714V     1.893V
[Falling Waveform]
R_fixture = 50.000
V_fixture = 1.800
V_fixture_min = 1.710
V_fixture_max = 1.890
|  time   V(typ)   V(min)   V(max)
0s        1.8V       1.714V     1.893V
1.245ns   1.793V     1.711V     1.886V
2.108ns   1.72V      1.662V     1.824V
3.47ns    1.515V     1.502V     1.659V
6.51ns    971.5mV    1.038V     1.209V
7.325ns   869.4mV    939.8mV    1.095V
8.215ns   804.3mV    861.7mV    987.3mV
9.549ns   758.8mV    791.2mV    882.8mV
11.47ns   734.5mV    742mV      819.2mV
20ns      721.7mV    697.4mV    761.9mV
[Falling Waveform]
R_fixture = 50.000
V_fixture = 0.000
V_fixture_min = 0.000
V_fixture_max = 0.000
|  time   V(typ)   V(min)   V(max)
0s        1.104V     1.032V     1.165V
344ps     1.104V     1.032V     1.161V
464ps     1.066V     1.032V     711.4mV
554ps     723.7mV    1.033V     548.4mV
632ps     550.7mV    1.031V     454.5mV
862ps     319.4mV    483.5mV    289.3mV
1.075ns   217.7mV    296mV      208.2mV
1.361ns   144.9mV    176.8mV    144.9mV
2.305ns   39.98mV    43.45mV    41mV
20ns      101.1uV    -1.567mV   -180.2uV
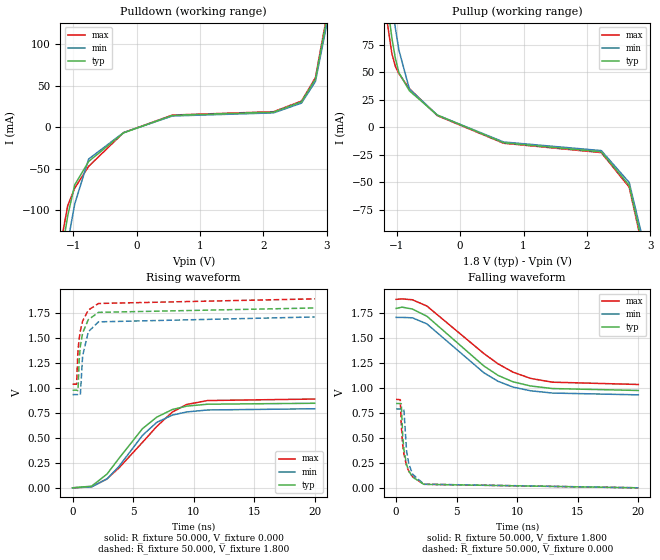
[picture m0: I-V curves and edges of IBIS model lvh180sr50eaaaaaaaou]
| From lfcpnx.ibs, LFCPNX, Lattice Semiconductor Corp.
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[Model] lvh180sr50eaaaaaaaou
Model_type Output
Polarity   Non-Inverting
Enable   Active-High
Vmeas =  0.900V
Cref =  0.0F
Rref =  1.000M
Vref =  0.0V
C_comp   5.000pF   4.000pF   5.500pF
[Temperature Range]   25.000   0.125k   -40.000
[Voltage Range]   1.800V   1.710V   1.890V
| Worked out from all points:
|   slope of the pulldown table from 0 to 0.27 V, typ, clamps not added: 32.7 ohm
|   slope of the pullup table from 0 to 0.27 V, typ, clamps not added: 39.8 ohm
|   rising waveform, R_fixture 50.000, V_fixture 0.000: 20-80 % time 3.53ns typ, 3.26ns min, 4.11ns max; typ from 0 V to 0.846 V
|   rising waveform, R_fixture 50.000, V_fixture 1.800: 20-80 % time 567ps typ, 549ps min, 610ps max; typ from 0.977 V to 1.8 V
|   falling waveform, R_fixture 50.000, V_fixture 1.800: 20-80 % time 4.76ns typ, 4.57ns min, 5.22ns max; typ from 1.8 V to 0.977 V
|   falling waveform, R_fixture 50.000, V_fixture 0.000: 20-80 % time 555ps typ, 547ps min, 599ps max; typ from 0.846 V to 0 V
[Pulldown]
|Voltage   I(typ)   I(min)   I(max)
-1.8V     -505.2mA   -515.5mA   -503.2mA
-1.195V   -158.7mA   -192mA     -140.2mA
-1.085V   -106.7mA   -139.2mA   -94.7mA
-975mV    -69.7mA    -92.7mA    -73.71mA
-755mV    -41.44mA   -38.5mA    -47.33mA
-205mV    -6.974mA   -6.675mA   -6.699mA
565mV     14.08mA    13.38mA    14.5mA
2.16V     18.02mA    17.12mA    18.56mA
2.6V      30.45mA    28.93mA    31.36mA
2.82V     57.91mA    55.01mA    59.64mA
2.985V    124.9mA    118.7mA    128.6mA
3.6V      469.8mA    446.3mA    483.9mA
[Pullup]
|Voltage   I(typ)   I(min)   I(max)
-1.8V     481.4mA    502.8mA    470.1mA
-1.185V   129.6mA    164.8mA    109.2mA
-1.075V   80.6mA     112.8mA    66.53mA
-1.02V    62.25mA    89.7mA     55.02mA
-965mV    49.5mA     69.93mA    48.49mA
-800mV    33.02mA    34.6mA     34.93mA
-360mV    10.94mA    10.9mA     10.41mA
685mV     -14.28mA   -13.56mA   -14.7mA
2.225V    -22.54mA   -21.41mA   -23.22mA
2.665V    -53.02mA   -50.37mA   -54.61mA
2.885V    -108.6mA   -103.2mA   -111.9mA
3.6V      -515.8mA   -490mA     -531.3mA
[Ramp]
| variable   typ   min   max
dV/dt_r   0.508/3.546n   0.475/3.296n   0.533/4.120n
dV/dt_f   0.494/4.772n   0.466/4.589n   0.512/5.233n
R_load = 50.000
[Rising Waveform]
R_fixture = 50.000
V_fixture = 0.000
V_fixture_min = 0.000
V_fixture_max = 0.000
|  time   V(typ)   V(min)   V(max)
0s        114.2uV    114.8uV    -276uV
1.569ns   16.32mV    9.391mV    9.99mV
2.839ns   136.8mV    88.57mV    88.99mV
3.828ns   294.2mV    213.2mV    198.7mV
5.77ns    591.5mV    524.3mV    454.6mV
6.945ns   706.9mV    654.8mV    613.1mV
8.246ns   784mV      728.1mV    759mV
9.428ns   817.7mV    759.3mV    834.2mV
11.14ns   836.8mV    778.9mV    873.5mV
20ns      846.3mV    791.3mV    888.5mV
[Rising Waveform]
R_fixture = 50.000
V_fixture = 1.800
V_fixture_min = 1.710
V_fixture_max = 1.890
|  time   V(typ)   V(min)   V(max)
0s        976.9mV    932.9mV    1.037V
333ps     977.3mV    933mV      1.037V
429ps     972.1mV    933.2mV    1.331V
468ps     1.028V     933.5mV    1.399V
548ps     1.282V     929.4mV    1.495V
642ps     1.416V     929.6mV    1.571V
832ps     1.55V      1.321V     1.669V
1.298ns   1.683V     1.561V     1.778V
2.142ns   1.756V     1.661V     1.845V
20ns      1.8V       1.71V      1.891V
[Falling Waveform]
R_fixture = 50.000
V_fixture = 1.800
V_fixture_min = 1.710
V_fixture_max = 1.890
|  time   V(typ)   V(min)   V(max)
0s        1.8V       1.71V      1.891V
491ps     1.813V     1.71V      1.896V
1.341ns   1.794V     1.706V     1.887V
2.541ns   1.722V     1.645V     1.824V
7.24ns    1.223V     1.155V     1.348V
8.416ns   1.128V     1.069V     1.244V
9.645ns   1.064V     1.011V     1.161V
11.1ns    1.022V     973.6mV    1.098V
12.9ns    996.1mV    951mV      1.06V
20ns      976.9mV    932.9mV    1.037V
[Falling Waveform]
R_fixture = 50.000
V_fixture = 0.000
V_fixture_min = 0.000
V_fixture_max = 0.000
|  time   V(typ)   V(min)   V(max)
0s        846.3mV    791.3mV    888.5mV
346ps     845.9mV    791.2mV    883.9mV
429ps     844mV      791.3mV    621.2mV
542ps     525.6mV    791.8mV    432.6mV
641ps     384.6mV    786.2mV    340.7mV
861ps     234.3mV    371.9mV    221.9mV
1.051ns   167.4mV    239mV      164.9mV
1.362ns   108.1mV    136.4mV    110.7mV
2.291ns   34.92mV    36.74mV    35.54mV
20ns      114.2uV    114.8uV    -276uV
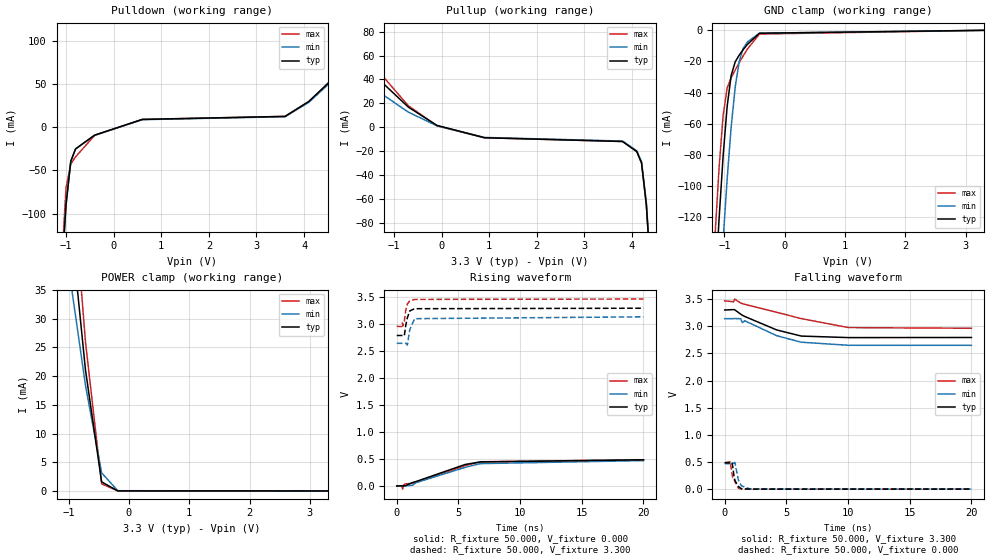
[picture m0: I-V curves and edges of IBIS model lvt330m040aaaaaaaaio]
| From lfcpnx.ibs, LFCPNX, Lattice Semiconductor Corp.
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[Model] lvt330m040aaaaaaaaio
Model_type I/O
Polarity   Non-Inverting
Enable   Active-Low
Vinl =  0.800V
Vinh =  2.000V
Vmeas =  1.650V
Cref =  0.0F
Rref =  1.000M
Vref =  0.0V
C_comp   5.000pF   4.000pF   5.500pF
[Temperature Range]   25.000   0.125k   -40.000
[Voltage Range]   3.300V   3.140V   3.470V
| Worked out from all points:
|   slope of the pulldown table from 0 to 0.495 V, typ, clamps not added: 60 ohm
|   slope of the pullup table from 0 to 0.495 V, typ, clamps not added: 80.9 ohm
|   GND clamp passes 1 mA (typ) near -0.37 V on its own axis
|   POWER clamp passes 1 mA (typ) near -0.42 V on its own axis
|   rising waveform, R_fixture 50.000, V_fixture 0.000: 20-80 % time 3.62ns typ, 4.08ns min, 3.75ns max; typ from 0.001 V to 0.486 V
|   rising waveform, R_fixture 50.000, V_fixture 3.300: 20-80 % time 269ps typ, 326ps min, 227ps max; typ from 2.79 V to 3.3 V
|   falling waveform, R_fixture 50.000, V_fixture 3.300: 20-80 % time 3.22ns typ, 3.34ns min, 5.31ns max; typ from 3.3 V to 2.79 V
|   falling waveform, R_fixture 50.000, V_fixture 0.000: 20-80 % time 246ps typ, 279ps min, 343ps max; typ from 0.486 V to 0.001 V
[GND_clamp]
|Voltage   I(typ)   I(min)   I(max)
-3.3V     -1.887A    -1.873A    -1.902A
-1.156V   -166.9mA   -224mA     -132.1mA
-1.089V   -121.5mA   -178.4mA   -88.64mA
-1.022V   -81.05mA   -135.2mA   -54.94mA
-955mV    -48.98mA   -95.79mA   -37.15mA
-888mV    -28.98mA   -62.05mA   -30.42mA
-821mV    -20.23mA   -36.35mA   -25.49mA
-754mV    -15.89mA   -19.89mA   -20.81mA
-687mV    -12.34mA   -11.44mA   -16.31mA
-620mV    -9.094mA   -7.515mA   -12.09mA
-419mV    -1.869mA   -1.836mA   -2.383mA
3.3V      0A         0A         0A
[POWER_clamp]
|Voltage   I(typ)   I(min)   I(max)
-3.3V     170.3mA    115.9mA    227.4mA
-2.998V   139.6mA    100.3mA    196.3mA
-2.797V   125.9mA    92.2mA     179.4mA
-2.596V   123.5mA    86.45mA    171.5mA
-1.993V   123.5mA    84.93mA    171.5mA
-1.792V   123.5mA    84.93mA    159.6mA
-1.658V   116.4mA    83.68mA    147.1mA
-1.457V   98.28mA    72.65mA    124.1mA
-720mV    21.08mA    18.41mA    25.96mA
-452mV    1.573mA    3.148mA    1.229mA
-184mV    5.589uA    37.85uA    1.612uA
3.3V      0A         0A         0A
[Pulldown]
|Voltage   I(typ)   I(min)   I(max)
-3.3V     -2.819A    -2.819A    -3.761A
-1.1V     -176.5mA   -176.5mA   -165mA
-1V       -89.5mA    -89.5mA    -70.05mA
-900mV    -39.31mA   -39.31mA   -42.55mA
-800mV    -25.23mA   -25.23mA   -34.36mA
-400mV    -9.281mA   -9.281mA   -9.631mA
600mV     8.924mA    8.657mA    8.924mA
3.6V      12.44mA    12.06mA    12.44mA
4.1V      29.71mA    28.82mA    29.71mA
5.4V      97.6mA     94.7mA     97.6mA
6.2V      121.3mA    117.7mA    121.3mA
6.6V      164mA      159.1mA    164mA
[Pullup]
|Voltage   I(typ)   I(min)   I(max)
-3.3V     110.4mA    68.4mA     141.5mA
-3V       86.9mA     61.1mA     119mA
-2V       65.6mA     48.08mA    78mA
-700mV    16.85mA    12.61mA    17.99mA
-100mV    1.523mA    1.127mA    1.159mA
900mV     -8.882mA   -8.615mA   -8.882mA
3.8V      -12.02mA   -11.66mA   -12.02mA
4.1V      -20.44mA   -19.83mA   -20.44mA
4.2V      -30.01mA   -29.11mA   -30.01mA
4.3V      -64.8mA    -62.9mA    -64.8mA
4.4V      -126.2mA   -122.4mA   -126.2mA
6.6V      -1.999A    -1.939A    -1.999A
[Ramp]
| variable   typ   min   max
dV/dt_r   0.291/3.630n   0.281/4.128n   0.291/3.751n
dV/dt_f   0.304/3.227n   0.294/3.363n   0.304/5.309n
R_load = 50.000
[Rising Waveform]
R_fixture = 50.000
V_fixture = 0.000
V_fixture_min = 0.000
V_fixture_max = 0.000
|  time   V(typ)   V(min)   V(max)
0s        707.6uV    2.066mV    707.6uV
395ps     812.5uV    1.6mV      3.345mV
474ps     936.2uV    2.007mV    -59.93mV
548ps     1.773mV    2.163mV    16.5mV
701ps     4.777mV    2.221mV    38.87mV
1.28ns    63.91mV    13.73mV    48.64mV
1.536ns   79.95mV    59.15mV    63.07mV
5.53ns    397.5mV    344.2mV    374.1mV
6.77ns    446mV      414.4mV    448.6mV
20ns      485.6mV    470.7mV    486mV
[Rising Waveform]
R_fixture = 50.000
V_fixture = 3.300
V_fixture_min = 3.140
V_fixture_max = 3.470
|  time   V(typ)   V(min)   V(max)
0s        2.794V     2.649V     2.964V
403ps     2.794V     2.648V     2.959V
455ps     2.794V     2.649V     3.029V
510ps     2.794V     2.649V     2.975V
612ps     2.788V     2.65V      3.064V
729ps     2.986V     2.65V      3.267V
856ps     3.123V     2.617V     3.378V
1.056ns   3.251V     2.904V     3.437V
1.446ns   3.291V     3.106V     3.464V
20ns      3.3V       3.14V      3.47V
[Falling Waveform]
R_fixture = 50.000
V_fixture = 3.300
V_fixture_min = 3.140
V_fixture_max = 3.470
|  time   V(typ)   V(min)   V(max)
0s        3.3V       3.14V      3.47V
717ps     3.308V     3.141V     3.452V
807ps     3.305V     3.143V     3.502V
1.296ns   3.224V     3.14V      3.429V
1.436ns   3.203V     3.067V     3.418V
1.626ns   3.181V     3.102V     3.406V
4.216ns   2.933V     2.827V     3.257V
6.209ns   2.82V      2.707V     3.142V
10.05ns   2.792V     2.65V      2.976V
20ns      2.794V     2.649V     2.964V
[Falling Waveform]
R_fixture = 50.000
V_fixture = 0.000
V_fixture_min = 0.000
V_fixture_max = 0.000
|  time   V(typ)   V(min)   V(max)
0s        485.6mV    470.7mV    486mV
441ps     485.3mV    470.2mV    505.8mV
581ps     501.1mV    470mV      302.4mV
650ps     416.3mV    470.8mV    211.5mV
747ps     251mV      484.1mV    208.3mV
826ps     159.8mV    491.6mV    135.2mV
1.111ns   47.66mV    162.6mV    16.66mV
1.356ns   7.024mV    60.88mV    1.871mV
2.096ns   153.2uV    1.54mV     -954.3uV
20ns      707.6uV    2.066mV    707.6uV
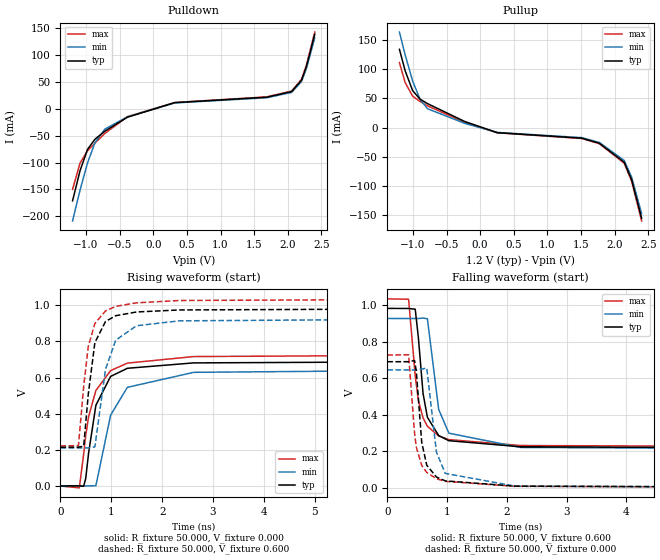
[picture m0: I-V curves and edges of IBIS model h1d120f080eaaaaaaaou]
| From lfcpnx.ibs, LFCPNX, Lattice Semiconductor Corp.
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[Model] h1d120f080eaaaaaaaou
Model_type Output
Polarity   Non-Inverting
Enable   Active-High
Vmeas =  0.600V
Cref =  20.000pF
Rref =  50.000
Vref =  0.600V
C_comp   5.000pF   4.000pF   5.500pF
[Temperature Range]   25.000   0.125k   -40.000
[Voltage Range]   1.200V   1.140V   1.260V
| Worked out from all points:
|   slope of the pulldown table from 0 to 0.18 V, typ, clamps not added: 27.4 ohm
|   slope of the pullup table from 0 to 0.18 V, typ, clamps not added: 27.4 ohm
|   rising waveform, R_fixture 50.000, V_fixture 0.000: 20-80 % time 298ps typ, 419ps min, 351ps max; typ from 0 V to 0.691 V
|   rising waveform, R_fixture 50.000, V_fixture 0.600: 20-80 % time 202ps typ, 289ps min, 226ps max; typ from 0.214 V to 0.984 V
|   falling waveform, R_fixture 50.000, V_fixture 0.600: 20-80 % time 171ps typ, 190ps min, 188ps max; typ from 0.984 V to 0.214 V
|   falling waveform, R_fixture 50.000, V_fixture 0.000: 20-80 % time 137ps typ, 156ps min, 148ps max; typ from 0.691 V to 0 V
[Pulldown]
|Voltage   I(typ)   I(min)   I(max)
-1.2V     -171mA     -208.4mA   -149.8mA
-1.089V   -115.3mA   -151.3mA   -101.1mA
-978mV    -75.7mA    -101mA     -78.43mA
-867mV    -56.88mA   -63.48mA   -64.1mA
-719mV    -41.92mA   -38.16mA   -46.06mA
-386mV    -16.16mA   -15.49mA   -15.15mA
317mV     10.85mA    10.31mA    11.18mA
1.686V    20.95mA    19.91mA    21.58mA
2.056V    31.4mA     29.83mA    32.34mA
2.204V    52.73mA    50.09mA    54.31mA
2.278V    78.8mA     74.9mA     81.2mA
2.4V      137.6mA    130.7mA    141.7mA
[Pullup]
|Voltage   I(typ)   I(min)   I(max)
-1.2V     133.6mA    163.2mA    111mA
-1.115V   97mA       124.2mA    76.9mA
-1.004V   63.07mA    79.6mA     53.56mA
-893mV    48.5mA     47.96mA    44.6mA
-782mV    40.83mA    32.18mA    37.09mA
-227mV    10.19mA    7.046mA    8.911mA
254mV     -8.734mA   -8.298mA   -8.996mA
1.512V    -18.19mA   -17.28mA   -18.74mA
1.771V    -26.82mA   -25.48mA   -27.62mA
2.141V    -59.19mA   -56.23mA   -60.97mA
2.252V    -89.3mA    -84.8mA    -92mA
2.4V      -155mA     -147.2mA   -159.7mA
[Ramp]
| variable   typ   min   max
dV/dt_r   0.415/0.301n   0.383/0.423n   0.437/0.357n
dV/dt_f   0.437/0.249n   0.409/0.265n   0.461/0.295n
R_load = 50.000
[Rising Waveform]
R_fixture = 50.000
V_fixture = 0.000
V_fixture_min = 0.000
V_fixture_max = 0.000
|  time   V(typ)   V(min)   V(max)
0s        40.32uV    -81.06uV   -549.4uV
371ps     677.7uV    -71.41uV   -10.51mV
457ps     -1.665mV   -43.63uV   177.4mV
497ps     41.8mV     107.1uV    279.1mV
554ps     183mV      484uV      384.5mV
697ps     446.9mV    1.342mV    528.8mV
987ps     606.7mV    392.6mV    638.8mV
1.317ns   651.6mV    546.1mV    680.2mV
2.62ns    681.4mV    629.1mV    716.5mV
10ns      691.4mV    646.6mV    727.7mV
[Rising Waveform]
R_fixture = 50.000
V_fixture = 0.600
V_fixture_min = 0.571
V_fixture_max = 0.631
|  time   V(typ)   V(min)   V(max)
0s        214.5mV    210.7mV    221.8mV
354ps     214.8mV    210.7mV    223.1mV
457ps     220.3mV    210.8mV    551.1mV
547ps     507.3mV    210.6mV    771.6mV
677ps     793.8mV    216.8mV    899.5mV
886ps     910.6mV    645mV      969.5mV
1.087ns   942.7mV    807.5mV    994.5mV
1.496ns   963.4mV    887.2mV    1.014V
2.337ns   974.6mV    914.3mV    1.027V
10ns      983.6mV    928.4mV    1.036V
[Falling Waveform]
R_fixture = 50.000
V_fixture = 0.600
V_fixture_min = 0.571
V_fixture_max = 0.631
|  time   V(typ)   V(min)   V(max)
0s        983.6mV    928.4mV    1.036V
356ps     983.4mV    928.3mV    1.034V
467ps     979.3mV    928.3mV    613.7mV
520ps     822.7mV    928.2mV    478.2mV
598ps     517.3mV    930.7mV    383.3mV
671ps     386.5mV    926.8mV    337.4mV
860ps     286.1mV    429.6mV    283.9mV
1.03ns    258.1mV    299.3mV    264.2mV
2.23ns    224.7mV    220.9mV    231.6mV
10ns      214.5mV    210.7mV    221.8mV
[Falling Waveform]
R_fixture = 50.000
V_fixture = 0.000
V_fixture_min = 0.000
V_fixture_max = 0.000
|  time   V(typ)   V(min)   V(max)
0s        691.4mV    646.6mV    727.7mV
356ps     691.3mV    646.4mV    729.5mV
456ps     697.8mV    646.5mV    298.6mV
486ps     636.1mV    646.2mV    221.5mV
576ps     249mV      650.7mV    122.6mV
660ps     123.5mV    656.8mV    83.82mV
822ps     58.87mV    195.3mV    49.4mV
970ps     37.66mV    78.71mV    35.06mV
2.142ns   8.736mV    8.656mV    7.773mV
10ns      40.32uV    -81.06uV   -549.4uV
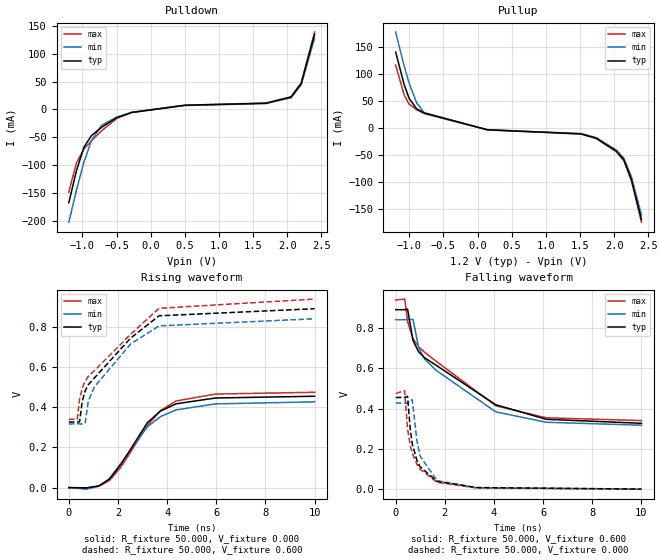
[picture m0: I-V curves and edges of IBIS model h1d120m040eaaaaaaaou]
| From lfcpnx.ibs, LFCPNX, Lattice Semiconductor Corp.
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[Model] h1d120m040eaaaaaaaou
Model_type Output
Polarity   Non-Inverting
Enable   Active-High
Vmeas =  0.600V
Cref =  20.000pF
Rref =  50.000
Vref =  0.600V
C_comp   5.000pF   4.000pF   5.500pF
[Temperature Range]   25.000   0.125k   -40.000
[Voltage Range]   1.200V   1.140V   1.260V
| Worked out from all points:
|   slope of the pulldown table from 0 to 0.18 V, typ, clamps not added: 55.6 ohm
|   slope of the pullup table from 0 to 0.18 V, typ, clamps not added: 47.4 ohm
|   rising waveform, R_fixture 50.000, V_fixture 0.000: 20-80 % time 1.55ns typ, 1.65ns min, 1.61ns max; typ from 0 V to 0.455 V
|   rising waveform, R_fixture 50.000, V_fixture 0.600: 20-80 % time 2.18ns typ, 1.9ns min, 2.43ns max; typ from 0.327 V to 0.891 V
|   falling waveform, R_fixture 50.000, V_fixture 0.600: 20-80 % time 3.14ns typ, 2.57ns min, 2.92ns max; typ from 0.891 V to 0.327 V
|   falling waveform, R_fixture 50.000, V_fixture 0.000: 20-80 % time 556ps typ, 521ps min, 590ps max; typ from 0.455 V to 0 V
[Pulldown]
|Voltage   I(typ)   I(min)   I(max)
-1.2V     -167.5mA   -202.4mA   -148.2mA
-1.089V   -110.4mA   -145.3mA   -96.4mA
-978mV    -67.78mA   -94.4mA    -70.93mA
-867mV    -46.78mA   -55.35mA   -56.4mA
-719mV    -32.07mA   -28.48mA   -38.41mA
-497mV    -14.82mA   -13.68mA   -16.11mA
-275mV    -5.473mA   -5.396mA   -5.087mA
502mV     7.378mA    7.01mA     7.6mA
1.686V    11.02mA    10.47mA    11.35mA
2.056V    22.06mA    20.95mA    22.72mA
2.204V    46.46mA    44.13mA    47.85mA
2.4V      134.7mA    128mA      138.7mA
[Pullup]
|Voltage   I(typ)   I(min)   I(max)
-1.2V     141.2mA    178.5mA    117.3mA
-1.078V   81.8mA     116.6mA    62.3mA
-1.004V   55.44mA    83.9mA     44.71mA
-893mV    35.85mA    47.06mA    34.34mA
-782mV    28.21mA    28.53mA    26.98mA
143mV     -3.105mA   -2.95mA    -3.198mA
1.512V    -10.64mA   -10.1mA    -10.95mA
1.734V    -18.48mA   -17.55mA   -19.03mA
2.03V     -42.56mA   -40.43mA   -43.83mA
2.141V    -58.56mA   -55.63mA   -60.32mA
2.252V    -94.8mA    -90.1mA    -97.6mA
2.4V      -169.7mA   -161.2mA   -174.8mA
[Ramp]
| variable   typ   min   max
dV/dt_r   0.273/1.576n   0.256/1.700n   0.300/1.665n
dV/dt_f   0.262/3.062n   0.246/2.751n   0.274/3.005n
R_load = 50.000
[Rising Waveform]
R_fixture = 50.000
V_fixture = 0.000
V_fixture_min = 0.000
V_fixture_max = 0.000
|  time   V(typ)   V(min)   V(max)
0s        34.96uV    37.11uV    -291.8uV
724ps     -1.455mV   -7.791mV   -1.334mV
1.225ns   8.844mV    7.621mV    6.208mV
1.649ns   41.67mV    43.7mV     34.93mV
2.136ns   118.1mV    124mV      104.4mV
3.199ns   323.9mV    303.5mV    309.5mV
3.732ns   381.7mV    353.8mV    384mV
4.371ns   417.7mV    387.4mV    431.7mV
5.97ns    446.5mV    417.1mV    466.2mV
10ns      455.2mV    427.3mV    475mV
[Rising Waveform]
R_fixture = 50.000
V_fixture = 0.600
V_fixture_min = 0.571
V_fixture_max = 0.631
|  time   V(typ)   V(min)   V(max)
0s        326.9mV    317.5mV    340.5mV
343ps     327.2mV    317.6mV    340.4mV
436ps     327.9mV    317.6mV    439.8mV
546ps     429.5mV    317.2mV    496.1mV
665ps     482.1mV    321.9mV    530.1mV
795ps     512.8mV    432.1mV    554.3mV
1.046ns   547.2mV    502.6mV    583.4mV
2.515ns   744.8mV    715.6mV    763.9mV
3.671ns   856mV      805.7mV    893.3mV
10ns      891.3mV    841.3mV    939.4mV
[Falling Waveform]
R_fixture = 50.000
V_fixture = 0.600
V_fixture_min = 0.571
V_fixture_max = 0.631
|  time   V(typ)   V(min)   V(max)
0s        891.3mV    841.3mV    939.4mV
370ps     891.4mV    841.1mV    944.1mV
484ps     894.2mV    841.1mV    832.2mV
703ps     738.4mV    843.6mV    746.9mV
935ps     681.8mV    702.8mV    707mV
1.173ns   652.8mV    646.4mV    680mV
1.643ns   615.4mV    590.3mV    635.4mV
4.068ns   419.3mV    383.9mV    414.3mV
6.124ns   346.9mV    332.1mV    354.3mV
10ns      326.9mV    317.5mV    340.5mV
[Falling Waveform]
R_fixture = 50.000
V_fixture = 0.000
V_fixture_min = 0.000
V_fixture_max = 0.000
|  time   V(typ)   V(min)   V(max)
0s        455.2mV    427.3mV    475mV
362ps     455.4mV    427mV      489.1mV
482ps     460.9mV    426.9mV    299.5mV
591ps     300.4mV    434.3mV    218.2mV
673ps     225.6mV    444.1mV    180.1mV
863ps     142.7mV    240.8mV    123.7mV
993ps     110.8mV    164.2mV    98.57mV
1.683ns   38.27mV    41.91mV    33.83mV
3.281ns   7.47mV     7.562mV    5.584mV
10ns      34.96uV    37.11uV    -291.8uV
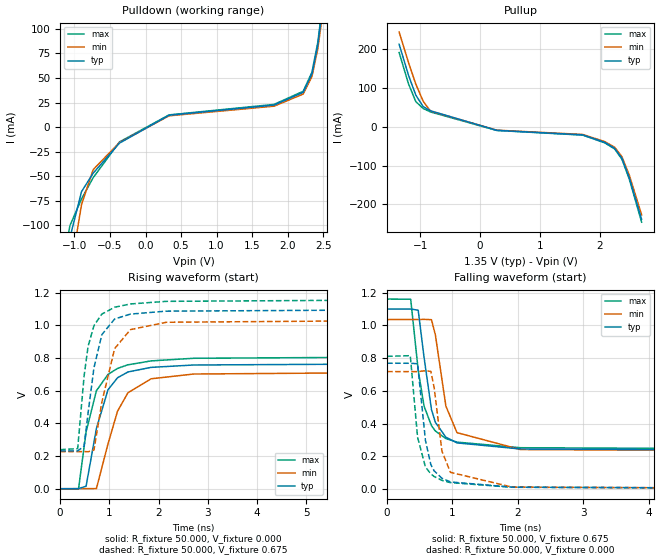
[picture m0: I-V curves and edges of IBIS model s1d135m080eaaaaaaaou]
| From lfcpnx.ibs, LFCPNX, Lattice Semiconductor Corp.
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[Model] s1d135m080eaaaaaaaou
Model_type Output
Polarity   Non-Inverting
Enable   Active-High
Vmeas =  0.675V
Cref =  30.000pF
Rref =  50.000
Vref =  0.675V
C_comp   5.000pF   4.000pF   5.500pF
[Temperature Range]   25.000   0.125k   -40.000
[Voltage Range]   1.350V   1.280V   1.420V
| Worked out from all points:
|   slope of the pulldown table from 0 to 0.203 V, typ, clamps not added: 25.7 ohm
|   slope of the pullup table from 0 to 0.203 V, typ, clamps not added: 28.6 ohm
|   rising waveform, R_fixture 50.000, V_fixture 0.000: 20-80 % time 372ps typ, 469ps min, 375ps max; typ from 0 V to 0.769 V
|   rising waveform, R_fixture 50.000, V_fixture 0.675: 20-80 % time 282ps typ, 359ps min, 247ps max; typ from 0.231 V to 1.1 V
|   falling waveform, R_fixture 50.000, V_fixture 0.675: 20-80 % time 206ps typ, 235ps min, 218ps max; typ from 1.1 V to 0.231 V
|   falling waveform, R_fixture 50.000, V_fixture 0.000: 20-80 % time 150ps typ, 172ps min, 158ps max; typ from 0.769 V to 0 V
[Pulldown]
|Voltage   I(typ)   I(min)   I(max)
-1.35V    -276.8mA   -315.1mA   -253.5mA
-1.186V   -176.1mA   -217.7mA   -152.5mA
-1.063V   -112.3mA   -150.2mA   -100.2mA
-899mV    -65.48mA   -78.63mA   -72.91mA
-735mV    -46.76mA   -43.13mA   -51.29mA
-366mV    -16.25mA   -15.67mA   -15.03mA
331mV     12.1mA     11.5mA     12.46mA
1.807V    22.43mA    21.31mA    23.1mA
2.217V    35.4mA     33.63mA    36.46mA
2.34V     54.13mA    51.43mA    55.76mA
2.422V    83.51mA    79.33mA    86.01mA
2.7V      239.7mA    227.7mA    246.9mA
[Pullup]
|Voltage   I(typ)   I(min)   I(max)
-1.35V    212.2mA    243.6mA    191mA
-1.195V   133.1mA    165.7mA    110.8mA
-1.072V   81.3mA     109.8mA    64.67mA
-949mV    51.95mA    65.61mA    46.96mA
-826mV    40.94mA    40.27mA    37.96mA
281mV     -9.358mA   -8.89mA    -9.639mA
1.716V    -20.98mA   -19.93mA   -21.61mA
2.085V    -40.37mA   -38.35mA   -41.58mA
2.249V    -55.47mA   -52.7mA    -57.14mA
2.372V    -81.6mA    -77.5mA    -84mA
2.495V    -131.6mA   -125mA     -135.5mA
2.7V      -238.6mA   -226.7mA   -245.8mA
[Ramp]
| variable   typ   min   max
dV/dt_r   0.461/0.378n   0.431/0.470n   0.487/0.381n
dV/dt_f   0.498/0.328n   0.465/0.353n   0.541/0.374n
R_load = 50.000
[Rising Waveform]
R_fixture = 50.000
V_fixture = 0.000
V_fixture_min = 0.000
V_fixture_max = 0.000
|  time   V(typ)   V(min)   V(max)
0s        18.69uV    -11.93uV   -186.3uV
373ps     663.1uV    10.24uV    -2.783mV
527ps     15.14mV    373uV      348mV
737ps     369mV      680.1uV    600.1mV
972ps     605.7mV    274.1mV    699.6mV
1.166ns   679.2mV    474.4mV    736.5mV
1.377ns   714.6mV    587.3mV    758.6mV
1.847ns   742.8mV    672.8mV    782.4mV
2.71ns    757.3mV    702.1mV    798.5mV
10ns      769mV      718.1mV    811.1mV
[Rising Waveform]
R_fixture = 50.000
V_fixture = 0.675
V_fixture_min = 0.642
V_fixture_max = 0.710
|  time   V(typ)   V(min)   V(max)
0s        231.1mV    227.1mV    238.9mV
356ps     231.4mV    227.1mV    245.5mV
487ps     260.2mV    227.2mV    691.2mV
567ps     462.9mV    226.4mV    870.3mV
687ps     740.1mV    236.5mV    998.6mV
847ps     943.1mV    529.6mV    1.069V
1.107ns   1.039V     857.6mV    1.111V
1.427ns   1.069V     973.8mV    1.131V
2.157ns   1.087V     1.019V     1.147V
10ns      1.1V       1.036V     1.161V
[Falling Waveform]
R_fixture = 50.000
V_fixture = 0.675
V_fixture_min = 0.642
V_fixture_max = 0.710
|  time   V(typ)   V(min)   V(max)
0s        1.1V       1.036V     1.161V
362ps     1.1V       1.036V     1.16V
477ps     1.093V     1.036V     725.7mV
567ps     803.4mV    1.037V     506.1mV
680ps     485.7mV    1.035V     387.3mV
740ps     407.8mV    941.3mV    355mV
900ps     317.3mV    507.4mV    309.2mV
1.07ns    282.5mV    345.1mV    287.1mV
2.04ns    245.3mV    241.8mV    253mV
10ns      231.1mV    227.1mV    238.9mV
[Falling Waveform]
R_fixture = 50.000
V_fixture = 0.000
V_fixture_min = 0.000
V_fixture_max = 0.000
|  time   V(typ)   V(min)   V(max)
0s        769mV      718.1mV    811.1mV
356ps     768.9mV    717.9mV    815.2mV
467ps     765.7mV    717.9mV    317.1mV
587ps     299.2mV    723.3mV    135.6mV
670ps     149.8mV    719.2mV    92.85mV
720ps     112.1mV    623.4mV    77.01mV
840ps     66.44mV    231.8mV    53.63mV
970ps     44.06mV    102.6mV    39.83mV
1.917ns   11.86mV    12.06mV    11.43mV
10ns      18.69uV    -11.93uV   -186.3uV
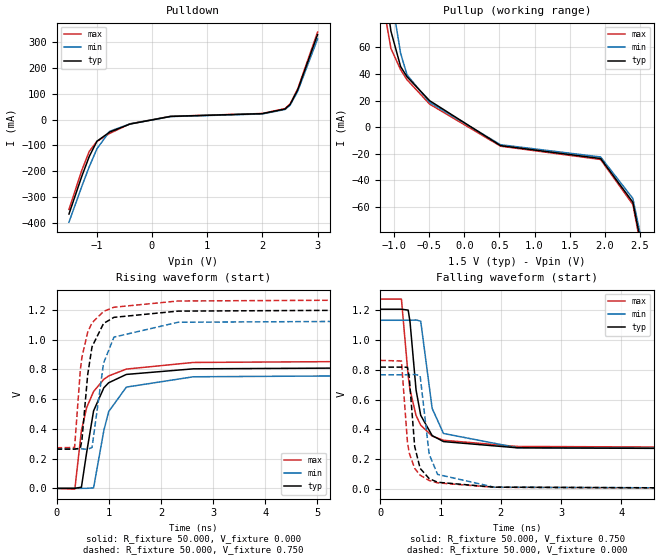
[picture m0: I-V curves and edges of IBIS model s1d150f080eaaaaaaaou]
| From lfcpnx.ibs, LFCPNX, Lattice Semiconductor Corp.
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[Model] s1d150f080eaaaaaaaou
Model_type Output
Polarity   Non-Inverting
Enable   Active-High
Vmeas =  0.750V
Cref =  30.000pF
Rref =  50.000
Vref =  0.750V
C_comp   5.000pF   4.000pF   5.500pF
[Temperature Range]   25.000   0.125k   -40.000
[Voltage Range]   1.500V   1.430V   1.580V
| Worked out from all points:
|   slope of the pulldown table from 0 to 0.225 V, typ, clamps not added: 26.6 ohm
|   slope of the pullup table from 0 to 0.225 V, typ, clamps not added: 31.3 ohm
|   rising waveform, R_fixture 50.000, V_fixture 0.000: 20-80 % time 310ps typ, 333ps min, 377ps max; typ from 0 V to 0.817 V
|   rising waveform, R_fixture 50.000, V_fixture 0.750: 20-80 % time 217ps typ, 245ps min, 234ps max; typ from 0.264 V to 1.21 V
|   falling waveform, R_fixture 50.000, V_fixture 0.750: 20-80 % time 189ps typ, 202ps min, 215ps max; typ from 1.21 V to 0.264 V
|   falling waveform, R_fixture 50.000, V_fixture 0.000: 20-80 % time 135ps typ, 149ps min, 147ps max; typ from 0.817 V to 0 V
[Pulldown]
|Voltage   I(typ)   I(min)   I(max)
-1.5V     -365.1mA   -396.5mA   -347.3mA
-1.27V    -220.7mA   -259.6mA   -197.7mA
-1.132V   -142.4mA   -182mA     -122.7mA
-994mV    -84mA      -113.3mA   -84.4mA
-764mV    -48.51mA   -45.68mA   -53.79mA
-396mV    -17.54mA   -16.85mA   -16.47mA
340mV     12.05mA    11.45mA    12.41mA
1.996V    22.61mA    21.48mA    23.29mA
2.41V     40.75mA    38.71mA    41.97mA
2.502V    58.04mA    55.14mA    59.78mA
2.64V     114.5mA    108.8mA    117.9mA
3V        327.9mA    311.5mA    337.7mA
[Pullup]
|Voltage   I(typ)   I(min)   I(max)
-1.5V     294.3mA    322.7mA    276.4mA
-1.186V   127.8mA    161.3mA    106.4mA
-1.14V    106.9mA    139.7mA    86.7mA
-1.048V   72.18mA    100.1mA    59.18mA
-910mV    45.57mA    55.51mA    43.21mA
-818mV    37.83mA    39.27mA    35.6mA
-496mV    19.88mA    18.61mA    17.33mA
516mV     -13.92mA   -13.23mA   -14.34mA
1.942V    -23.61mA   -22.43mA   -24.32mA
2.402V    -56.47mA   -53.65mA   -58.17mA
2.586V    -105.6mA   -100.3mA   -108.8mA
3V        -323.4mA   -307.2mA   -333.1mA
[Ramp]
| variable   typ   min   max
dV/dt_r   0.490/0.312n   0.459/0.337n   0.518/0.377n
dV/dt_f   0.529/0.334n   0.497/0.332n   0.584/0.414n
R_load = 50.000
[Rising Waveform]
R_fixture = 50.000
V_fixture = 0.000
V_fixture_min = 0.000
V_fixture_max = 0.000
|  time   V(typ)   V(min)   V(max)
0s        67.51uV    -31.65uV   -689.5uV
351ps     399.9uV    -7.148uV   -5.458mV
477ps     7.741mV    63.82uV    388.3mV
578ps     243mV      150.1uV    543.9mV
710ps     521.1mV    3.269mV    651.4mV
907ps     676.5mV    390mV      733.4mV
1ns       710.3mV    516.7mV    756.2mV
1.338ns   766.2mV    680.9mV    802.2mV
2.62ns    803.8mV    750.3mV    846.6mV
10ns      817.1mV    765.8mV    862mV
[Rising Waveform]
R_fixture = 50.000
V_fixture = 0.750
V_fixture_min = 0.713
V_fixture_max = 0.789
|  time   V(typ)   V(min)   V(max)
0s        263.8mV    265.1mV    273mV
346ps     263.9mV    265.1mV    274.8mV
457ps     270.4mV    265.2mV    799.5mV
487ps     326.6mV    265.2mV    882.4mV
597ps     764.2mV    263.3mV    1.05V
680ps     952.1mV    274.6mV    1.113V
901ps     1.109V     842.2mV    1.19V
1.1ns     1.15V      1.017V     1.218V
2.328ns   1.192V     1.117V     1.26V
10ns      1.205V     1.131V     1.273V
[Falling Waveform]
R_fixture = 50.000
V_fixture = 0.750
V_fixture_min = 0.713
V_fixture_max = 0.789
|  time   V(typ)   V(min)   V(max)
0s        1.205V     1.131V     1.273V
351ps     1.205V     1.131V     1.273V
463ps     1.199V     1.131V     757.1mV
494ps     1.119V     1.131V     663.9mV
594ps     663mV      1.133V     492.8mV
671ps     494mV      1.125V     427.7mV
861ps     358.3mV    540.2mV    355.1mV
1.049ns   318.1mV    372.5mV    326.9mV
2.269ns   276.5mV    277.5mV    285.5mV
10ns      263.8mV    265.1mV    273mV
[Falling Waveform]
R_fixture = 50.000
V_fixture = 0.000
V_fixture_min = 0.000
V_fixture_max = 0.000
|  time   V(typ)   V(min)   V(max)
0s        817.1mV    765.8mV    862mV
351ps     817mV      765.6mV    858.2mV
451ps     816mV      765.7mV    313.6mV
481ps     747.9mV    765.5mV    240.8mV
571ps     285.3mV    767.7mV    138.2mV
661ps     138.9mV    760.4mV    93.01mV
811ps     70.28mV    234.4mV    57.59mV
951ps     45.57mV    98.19mV    41.66mV
1.891ns   12.68mV    12.67mV    11.77mV
10ns      67.51uV    -31.65uV   -689.5uV
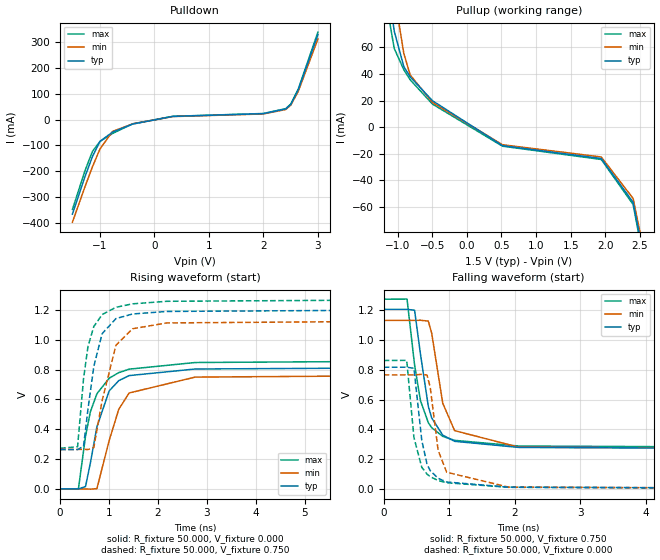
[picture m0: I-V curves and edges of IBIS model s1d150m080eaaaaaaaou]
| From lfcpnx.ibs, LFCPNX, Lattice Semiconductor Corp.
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[Model] s1d150m080eaaaaaaaou
Model_type Output
Polarity   Non-Inverting
Enable   Active-High
Vmeas =  0.750V
Cref =  30.000pF
Rref =  50.000
Vref =  0.750V
C_comp   5.000pF   4.000pF   5.500pF
[Temperature Range]   25.000   0.125k   -40.000
[Voltage Range]   1.500V   1.430V   1.580V
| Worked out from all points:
|   slope of the pulldown table from 0 to 0.225 V, typ, clamps not added: 26.6 ohm
|   slope of the pullup table from 0 to 0.225 V, typ, clamps not added: 31.3 ohm
|   rising waveform, R_fixture 50.000, V_fixture 0.000: 20-80 % time 383ps typ, 445ps min, 399ps max; typ from 0 V to 0.817 V
|   rising waveform, R_fixture 50.000, V_fixture 0.750: 20-80 % time 290ps typ, 355ps min, 260ps max; typ from 0.264 V to 1.21 V
|   falling waveform, R_fixture 50.000, V_fixture 0.750: 20-80 % time 220ps typ, 248ps min, 235ps max; typ from 1.21 V to 0.264 V
|   falling waveform, R_fixture 50.000, V_fixture 0.000: 20-80 % time 153ps typ, 173ps min, 159ps max; typ from 0.817 V to 0 V
[Pulldown]
|Voltage   I(typ)   I(min)   I(max)
-1.5V     -365.1mA   -396.5mA   -347.3mA
-1.27V    -220.7mA   -259.6mA   -197.7mA
-1.132V   -142.4mA   -182mA     -122.7mA
-994mV    -84mA      -113.3mA   -84.4mA
-764mV    -48.51mA   -45.68mA   -53.79mA
-396mV    -17.54mA   -16.85mA   -16.47mA
340mV     12.05mA    11.45mA    12.41mA
1.996V    22.61mA    21.48mA    23.29mA
2.41V     40.75mA    38.71mA    41.97mA
2.502V    58.04mA    55.14mA    59.78mA
2.64V     114.5mA    108.8mA    117.9mA
3V        327.9mA    311.5mA    337.7mA
[Pullup]
|Voltage   I(typ)   I(min)   I(max)
-1.5V     294.3mA    322.7mA    276.4mA
-1.186V   127.8mA    161.3mA    106.4mA
-1.14V    106.9mA    139.7mA    86.7mA
-1.048V   72.18mA    100.1mA    59.18mA
-910mV    45.57mA    55.51mA    43.21mA
-818mV    37.83mA    39.27mA    35.6mA
-496mV    19.88mA    18.61mA    17.33mA
516mV     -13.92mA   -13.23mA   -14.34mA
1.942V    -23.61mA   -22.43mA   -24.32mA
2.402V    -56.47mA   -53.65mA   -58.17mA
2.586V    -105.6mA   -100.3mA   -108.8mA
3V        -323.4mA   -307.2mA   -333.1mA
[Ramp]
| variable   typ   min   max
dV/dt_r   0.490/0.391n   0.459/0.443n   0.518/0.398n
dV/dt_f   0.529/0.375n   0.497/0.402n   0.584/0.438n
R_load = 50.000
[Rising Waveform]
R_fixture = 50.000
V_fixture = 0.000
V_fixture_min = 0.000
V_fixture_max = 0.000
|  time   V(typ)   V(min)   V(max)
0s        67.51uV    -31.65uV   -689.5uV
373ps     639.9uV    -9.539uV   -1.017mV
518ps     15.75mV    250.8uV    352.2mV
618ps     173.6mV    -1.495mV   517.3mV
751ps     416.3mV    2.044mV    637.9mV
1.001ns   656.7mV    323.2mV    742mV
1.198ns   726.1mV    534.1mV    779.8mV
1.41ns    760mV      643.3mV    803.1mV
2.76ns    804.1mV    749.8mV    847.6mV
10ns      817.1mV    765.8mV    862mV
[Rising Waveform]
R_fixture = 50.000
V_fixture = 0.750
V_fixture_min = 0.713
V_fixture_max = 0.789
|  time   V(typ)   V(min)   V(max)
0s        263.8mV    265.1mV    273mV
356ps     263.9mV    265.1mV    282.7mV
478ps     286mV      265.2mV    738.4mV
568ps     532.6mV    264.2mV    953.6mV
688ps     821mV      277.1mV    1.089V
858ps     1.041V     592.5mV    1.169V
1.141ns   1.142V     963.7mV    1.218V
1.481ns   1.173V     1.074V     1.241V
2.178ns   1.19V      1.113V     1.258V
10ns      1.205V     1.131V     1.273V
[Falling Waveform]
R_fixture = 50.000
V_fixture = 0.750
V_fixture_min = 0.713
V_fixture_max = 0.789
|  time   V(typ)   V(min)   V(max)
0s        1.205V     1.131V     1.273V
356ps     1.205V     1.131V     1.274V
471ps     1.199V     1.131V     832.8mV
561ps     904.9mV    1.132V     592.9mV
681ps     554mV      1.126V     444.7mV
732ps     477.1mV    1.046V     411.8mV
901ps     361.7mV    575.9mV    353.4mV
1.082ns   320.1mV    391.8mV    326.6mV
2.061ns   279.3mV    280.8mV    288.6mV
10ns      263.8mV    265.1mV    273mV
[Falling Waveform]
R_fixture = 50.000
V_fixture = 0.000
V_fixture_min = 0.000
V_fixture_max = 0.000
|  time   V(typ)   V(min)   V(max)
0s        817.1mV    765.8mV    862mV
351ps     816.9mV    765.6mV    863mV
461ps     809.9mV    765.6mV    346.4mV
581ps     327.1mV    769mV      145.9mV
661ps     166.1mV    764.5mV    100.4mV
711ps     123.1mV    680.2mV    82.85mV
831ps     71.99mV    258.8mV    57.22mV
961ps     47.39mV    112.7mV    42.24mV
1.91ns    12.68mV    12.8mV     11.72mV
10ns      67.51uV    -31.65uV   -689.5uV
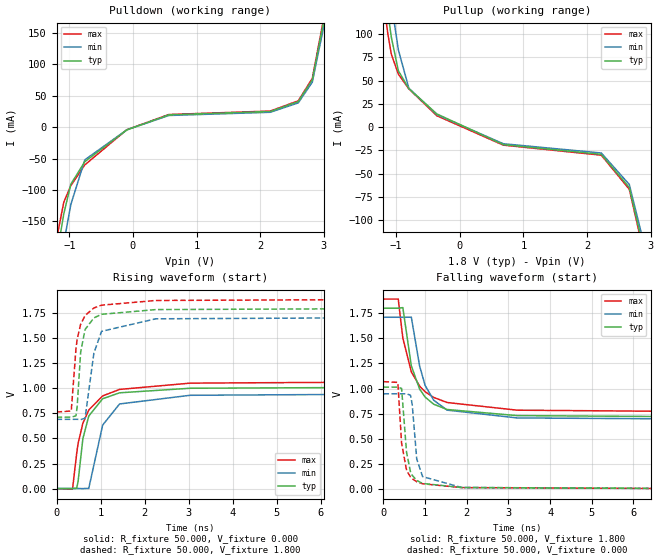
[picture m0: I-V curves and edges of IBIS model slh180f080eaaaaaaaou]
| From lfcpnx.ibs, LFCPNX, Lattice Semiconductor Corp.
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[Model] slh180f080eaaaaaaaou
Model_type Output
Polarity   Non-Inverting
Enable   Active-High
Vmeas =  0.900V
Cref =  0.0F
Rref =  1.000M
Vref =  0.0V
C_comp   5.000pF   4.000pF   5.500pF
[Temperature Range]   25.000   0.125k   -40.000
[Voltage Range]   1.800V   1.710V   1.890V
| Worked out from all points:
|   slope of the pulldown table from 0 to 0.27 V, typ, clamps not added: 23.6 ohm
|   slope of the pullup table from 0 to 0.27 V, typ, clamps not added: 30.3 ohm
|   rising waveform, R_fixture 50.000, V_fixture 0.000: 20-80 % time 322ps typ, 360ps min, 428ps max; typ from 0 V to 1.01 V
|   rising waveform, R_fixture 50.000, V_fixture 1.800: 20-80 % time 159ps typ, 221ps min, 193ps max; typ from 0.713 V to 1.8 V
|   falling waveform, R_fixture 50.000, V_fixture 1.800: 20-80 % time 435ps typ, 422ps min, 527ps max; typ from 1.8 V to 0.713 V
|   falling waveform, R_fixture 50.000, V_fixture 0.000: 20-80 % time 141ps typ, 150ps min, 148ps max; typ from 1.01 V to 0 V
[Pulldown]
|Voltage   I(typ)   I(min)   I(max)
-1.8V     -648.3mA   -680.5mA   -631mA
-1.195V   -204.1mA   -253.8mA   -176mA
-1.085V   -137.7mA   -184.3mA   -119.3mA
-975mV    -90.87mA   -123.2mA   -93.17mA
-755mV    -54.94mA   -52.05mA   -60.1mA
-95mV     -4.452mA   -4.238mA   -4.067mA
565mV     19.54mA    18.56mA    20.12mA
2.16V     24.92mA    23.68mA    25.67mA
2.6V      40.77mA    38.73mA    41.99mA
2.82V     75.39mA    71.62mA    77.65mA
2.985V    160.8mA    152.8mA    165.6mA
3.6V      602.8mA    572.7mA    620.9mA
[Pullup]
|Voltage   I(typ)   I(min)   I(max)
-1.8V     566.5mA    591.4mA    552.5mA
-1.185V   153.5mA    194.1mA    128.4mA
-1.13V    123mA      162.7mA    100mA
-1.075V   96.4mA     133.2mA    78.19mA
-965mV    60.54mA    83mA       56.98mA
-800mV    41.32mA    41.76mA    41.05mA
-360mV    14.18mA    13.41mA    12.23mA
685mV     -18.76mA   -17.82mA   -19.32mA
2.225V    -29.22mA   -27.76mA   -30.1mA
2.665V    -64.79mA   -61.55mA   -66.73mA
2.885V    -128.8mA   -122.4mA   -132.7mA
3.6V      -606.7mA   -576.4mA   -624.9mA
[Ramp]
| variable   typ   min   max
dV/dt_r   0.609/0.321n   0.591/0.360n   0.642/0.430n
dV/dt_f   0.668/0.436n   0.627/0.425n   0.677/0.532n
R_load = 50.000
[Rising Waveform]
R_fixture = 50.000
V_fixture = 0.000
V_fixture_min = 0.000
V_fixture_max = 0.000
|  time   V(typ)   V(min)   V(max)
0s        123.1uV    170.5uV    -772.3uV
363ps     572.1uV    196uV      -6.129mV
458ps     3.571mV    221.9uV    352.5mV
489ps     69.58mV    302.8uV    448.7mV
598ps     497.8mV    -338.5uV   651.7mV
732ps     723.5mV    1.915mV    783.8mV
1.047ns   896.2mV    633.1mV    924.6mV
1.431ns   955.5mV    844.2mV    989.2mV
3.033ns   1.001V     930.7mV    1.052V
10ns      1.015V     948mV      1.069V
[Rising Waveform]
R_fixture = 50.000
V_fixture = 1.800
V_fixture_min = 1.710
V_fixture_max = 1.890
|  time   V(typ)   V(min)   V(max)
0s        712.5mV    690.6mV    763.7mV
334ps     712.7mV    690.7mV    774mV
441ps     725.7mV    691mV      1.392V
468ps     814.6mV    691mV      1.489V
548ps     1.363V     687.7mV    1.64V
648ps     1.587V     702.5mV    1.727V
848ps     1.703V     1.351V     1.802V
1.022ns   1.739V     1.569V     1.83V
2.253ns   1.786V     1.694V     1.877V
10ns      1.8V       1.71V      1.891V
[Falling Waveform]
R_fixture = 50.000
V_fixture = 1.800
V_fixture_min = 1.710
V_fixture_max = 1.890
|  time   V(typ)   V(min)   V(max)
0s        1.8V       1.71V      1.891V
356ps     1.8V       1.71V      1.891V
466ps     1.806V     1.71V      1.503V
670ps     1.226V     1.711V     1.166V
870ps     994.5mV    1.223V     1.024V
1.001ns   915.8mV    1.032V     968.8mV
1.206ns   844.8mV    884.7mV    912.4mV
1.529ns   792.1mV    785.6mV    861.7mV
3.206ns   731.3mV    708.2mV    785.2mV
10ns      712.5mV    690.6mV    763.7mV
[Falling Waveform]
R_fixture = 50.000
V_fixture = 0.000
V_fixture_min = 0.000
V_fixture_max = 0.000
|  time   V(typ)   V(min)   V(max)
0s        1.015V     948mV      1.069V
346ps     1.015V     947.9mV    1.062V
436ps     1.002V     948mV      458.6mV
556ps     364.3mV    949mV      186.1mV
650ps     171.9mV    934.4mV    120.5mV
691ps     137.4mV    842.9mV    103.2mV
800ps     86.32mV    299.7mV    73.49mV
941ps     55.78mV    124.3mV    52.7mV
1.876ns   15.81mV    15.94mV    14.95mV
10ns      123.1uV    170.5uV    -772.3uV
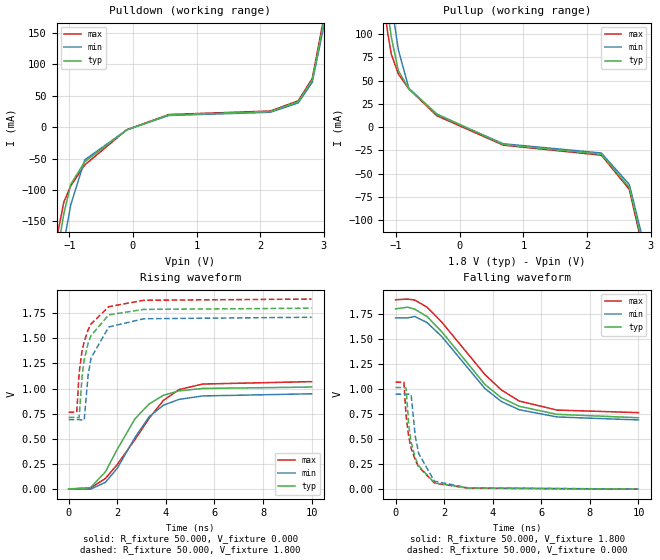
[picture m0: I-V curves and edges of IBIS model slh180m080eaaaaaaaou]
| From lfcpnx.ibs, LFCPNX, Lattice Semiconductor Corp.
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[Model] slh180m080eaaaaaaaou
Model_type Output
Polarity   Non-Inverting
Enable   Active-High
Vmeas =  0.900V
Cref =  0.0F
Rref =  1.000M
Vref =  0.0V
C_comp   5.000pF   4.000pF   5.500pF
[Temperature Range]   25.000   0.125k   -40.000
[Voltage Range]   1.800V   1.710V   1.890V
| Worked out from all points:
|   slope of the pulldown table from 0 to 0.27 V, typ, clamps not added: 23.6 ohm
|   slope of the pullup table from 0 to 0.27 V, typ, clamps not added: 30.3 ohm
|   rising waveform, R_fixture 50.000, V_fixture 0.000: 20-80 % time 1.56ns typ, 1.52ns min, 1.89ns max; typ from 0 V to 1.01 V
|   rising waveform, R_fixture 50.000, V_fixture 1.800: 20-80 % time 531ps typ, 527ps min, 592ps max; typ from 0.713 V to 1.8 V
|   falling waveform, R_fixture 50.000, V_fixture 1.800: 20-80 % time 2.38ns typ, 2.27ns min, 2.45ns max; typ from 1.8 V to 0.713 V
|   falling waveform, R_fixture 50.000, V_fixture 0.000: 20-80 % time 525ps typ, 497ps min, 574ps max; typ from 1.01 V to 0 V
[Pulldown]
|Voltage   I(typ)   I(min)   I(max)
-1.8V     -648.3mA   -680.5mA   -631mA
-1.195V   -204.1mA   -253.8mA   -176mA
-1.085V   -137.7mA   -184.3mA   -119.3mA
-975mV    -90.87mA   -123.2mA   -93.17mA
-755mV    -54.94mA   -52.05mA   -60.1mA
-95mV     -4.452mA   -4.238mA   -4.067mA
565mV     19.54mA    18.56mA    20.12mA
2.16V     24.92mA    23.68mA    25.67mA
2.6V      40.77mA    38.73mA    41.99mA
2.82V     75.39mA    71.62mA    77.65mA
2.985V    160.8mA    152.8mA    165.6mA
3.6V      602.8mA    572.7mA    620.9mA
[Pullup]
|Voltage   I(typ)   I(min)   I(max)
-1.8V     566.5mA    591.4mA    552.5mA
-1.185V   153.5mA    194.1mA    128.4mA
-1.13V    123mA      162.7mA    100mA
-1.075V   96.4mA     133.2mA    78.19mA
-965mV    60.54mA    83mA       56.98mA
-800mV    41.32mA    41.76mA    41.05mA
-360mV    14.18mA    13.41mA    12.23mA
685mV     -18.76mA   -17.82mA   -19.32mA
2.225V    -29.22mA   -27.76mA   -30.1mA
2.665V    -64.79mA   -61.55mA   -66.73mA
2.885V    -128.8mA   -122.4mA   -132.7mA
3.6V      -606.7mA   -576.4mA   -624.9mA
[Ramp]
| variable   typ   min   max
dV/dt_r   0.609/1.570n   0.591/1.567n   0.642/1.928n
dV/dt_f   0.666/2.463n   0.624/2.370n   0.677/2.551n
R_load = 50.000
[Rising Waveform]
R_fixture = 50.000
V_fixture = 0.000
V_fixture_min = 0.000
V_fixture_max = 0.000
|  time   V(typ)   V(min)   V(max)
0s        123.1uV    170.5uV    -772.3uV
899ps     13.6mV     -1.633mV   9.144mV
1.512ns   170.7mV    66.41mV    105.2mV
2.002ns   396.2mV    207.2mV    244.2mV
2.729ns   698.5mV    512.6mV    493.4mV
3.311ns   846.6mV    719.3mV    703.3mV
3.898ns   932.9mV    833.9mV    882mV
4.541ns   977.2mV    892.1mV    990mV
5.52ns    1.001V     926.5mV    1.045V
10ns      1.015V     948mV      1.069V
[Rising Waveform]
R_fixture = 50.000
V_fixture = 1.800
V_fixture_min = 1.710
V_fixture_max = 1.890
|  time   V(typ)   V(min)   V(max)
0s        712.5mV    690.6mV    763.7mV
333ps     713mV      690.7mV    765.4mV
431ps     709.2mV    691mV      1.157V
548ps     1.111V     686.6mV    1.369V
639ps     1.286V     686.3mV    1.468V
798ps     1.448V     1.131V     1.583V
922ps     1.528V     1.306V     1.644V
1.65ns    1.734V     1.613V     1.815V
3.085ns   1.788V     1.695V     1.879V
10ns      1.8V       1.71V      1.891V
[Falling Waveform]
R_fixture = 50.000
V_fixture = 1.800
V_fixture_min = 1.710
V_fixture_max = 1.890
|  time   V(typ)   V(min)   V(max)
0s        1.8V       1.71V      1.891V
502ps     1.817V     1.71V      1.898V
791ps     1.797V     1.724V     1.888V
1.298ns   1.723V     1.663V     1.817V
1.901ns   1.572V     1.524V     1.668V
3.68ns    1.045V     1.004V     1.144V
4.358ns   912.2mV    874.7mV    989.5mV
5.09ns    827mV      792.6mV    879.6mV
6.644ns   746.8mV    720.6mV    789.3mV
10ns      712.5mV    690.6mV    763.7mV
[Falling Waveform]
R_fixture = 50.000
V_fixture = 0.000
V_fixture_min = 0.000
V_fixture_max = 0.000
|  time   V(typ)   V(min)   V(max)
0s        1.015V     948mV      1.069V
343ps     1.014V     947.9mV    1.067V
433ps     1.009V     948mV      734.7mV
541ps     644.2mV    948.4mV    521.5mV
641ps     466.8mV    942.2mV    409.4mV
811ps     311.7mV    529.3mV    289.6mV
951ps     232.8mV    355.7mV    223.3mV
1.599ns   60.58mV    78.8mV     60.35mV
2.989ns   11.11mV    12.06mV    8.945mV
10ns      123.1uV    170.5uV    -772.3uV
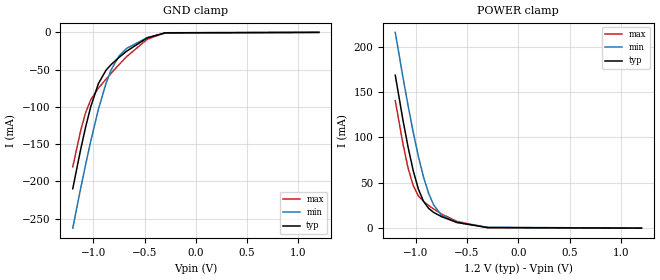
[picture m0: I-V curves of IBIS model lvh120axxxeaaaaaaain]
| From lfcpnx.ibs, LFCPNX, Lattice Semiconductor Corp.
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|Model lvh120axxxeaaaaaaain
[Model] lvh120axxxeaaaaaaain
Model_type Input
Polarity   Non-Inverting
Enable   Active-High
Vinl =  0.420V
Vinh =  0.780V
C_comp   5.000pF   4.000pF   5.500pF
[Temperature Range]   25.000   0.125k   -40.000
[Voltage Range]   1.200V   1.140V   1.260V
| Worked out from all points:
|   GND clamp passes 1 mA (typ) near -0.32 V on its own axis
|   POWER clamp passes 1 mA (typ) near -0.35 V on its own axis
[GND_clamp]
|Voltage   I(typ)   I(min)   I(max)
-1.2V     -209.9mA   -262.8mA   -180.5mA
-1.125V   -158.5mA   -210.9mA   -133mA
-1.075V   -127.3mA   -177.7mA   -108mA
-1.025V   -99.9mA    -146.2mA   -90.46mA
-950mV    -68.74mA   -103.2mA   -74.94mA
-875mV    -50.65mA   -68.09mA   -62.66mA
-825mV    -43.12mA   -50.2mA    -54.78mA
-750mV    -33.76mA   -31.89mA   -43.36mA
-675mV    -25.29mA   -21.5mA    -32.59mA
-475mV    -7.493mA   -7.049mA   -9.35mA
-300mV    -592.7uA   -1.061mA   -520.5uA
1.2V      0A         0A         0A
[POWER_clamp]
|Voltage   I(typ)   I(min)   I(max)
-1.2V     168.6mA    215.8mA    140.6mA
-1.125V   119.2mA    166.4mA    92.84mA
-1.075V   89.27mA    135mA      66.22mA
-1.025V   63.41mA    105.7mA    46.84mA
-975mV    43.18mA    79.24mA    35.57mA
-925mV    29.63mA    56.5mA     29.42mA
-875mV    21.83mA    38.4mA     24.98mA
-825mV    17.29mA    25.43mA    21.03mA
-750mV    12.75mA    14.37mA    15.67mA
-600mV    6.313mA    6.272mA    7.453mA
-300mV    596.6uA    938.1uA    529.7uA
1.2V      0A         0A         0A
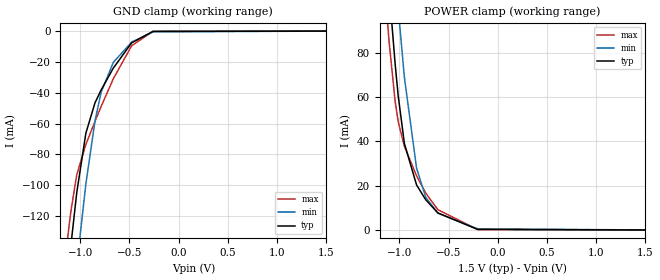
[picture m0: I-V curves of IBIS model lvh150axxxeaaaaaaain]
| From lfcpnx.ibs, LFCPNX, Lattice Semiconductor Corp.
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|Model lvh150axxxeaaaaaaain
[Model] lvh150axxxeaaaaaaain
Model_type Input
Polarity   Non-Inverting
Enable   Active-High
Vinl =  0.375V
Vinh =  1.125V
C_comp   5.000pF   4.000pF   5.500pF
[Temperature Range]   25.000   0.125k   -40.000
[Voltage Range]   1.500V   1.430V   1.580V
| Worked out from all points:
|   GND clamp passes 1 mA (typ) near -0.32 V on its own axis
|   POWER clamp passes 1 mA (typ) near -0.31 V on its own axis
[GND_clamp]
|Voltage   I(typ)   I(min)   I(max)
-1.5V     -437.9mA   -483.5mA   -411.6mA
-1.159V   -181.5mA   -234.4mA   -153.5mA
-1.128V   -160.7mA   -213.1mA   -134.8mA
-1.097V   -140.8mA   -192.4mA   -118.2mA
-1.035V   -105.1mA   -152.5mA   -93.37mA
-942mV    -66.27mA   -99.23mA   -73.57mA
-849mV    -46.5mA    -58.3mA    -58.53mA
-787mV    -38.22mA   -39.77mA   -48.92mA
-663mV    -24mA      -20.29mA   -30.94mA
-477mV    -7.625mA   -7.144mA   -9.524mA
-260mV    -205.9uA   -520.9uA   -132.8uA
1.5V      0A         0A         0A
[POWER_clamp]
|Voltage   I(typ)   I(min)   I(max)
-1.5V     394mA      431.9mA    372.6mA
-1.166V   148.2mA    194.8mA    121.7mA
-1.135V   128mA      174.5mA    102.5mA
-1.104V   108.8mA    154.7mA    85.14mA
-1.042V   74.73mA    117.3mA    57.91mA
-1.011V   60.48mA    99.98mA    48.83mA
-949mV    39.16mA    69.14mA    37.82mA
-825mV    20.35mA    27.97mA    24.48mA
-732mV    13.69mA    14.79mA    16.68mA
-608mV    7.674mA    7.602mA    9.15mA
-205mV    265.4uA    515.5uA    203.6uA
1.5V      0A         0A         0A
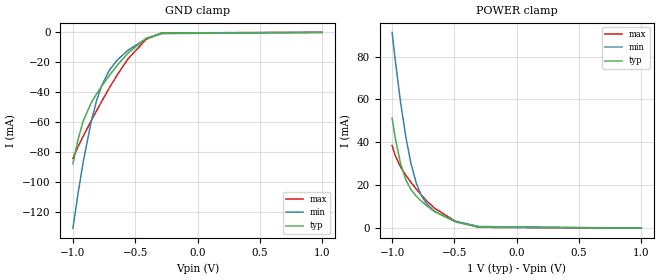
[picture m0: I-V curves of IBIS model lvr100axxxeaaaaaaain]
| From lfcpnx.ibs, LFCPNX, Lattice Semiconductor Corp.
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|Model lvr100axxxeaaaaaaain
[Model] lvr100axxxeaaaaaaain
Model_type Input
Polarity   Non-Inverting
Enable   Active-High
Vinl =  0.350V
Vinh =  0.650V
C_comp   5.000pF   4.000pF   5.500pF
[Temperature Range]   25.000   0.125k   -40.000
[Voltage Range]   1.000V   0.950V   1.050V
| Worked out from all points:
|   GND clamp passes 1 mA (typ) near -0.32 V on its own axis
|   POWER clamp passes 1 mA (typ) near -0.37 V on its own axis
[GND_clamp]
|Voltage   I(typ)   I(min)   I(max)
-1V       -87.97mA   -131mA     -84.36mA
-958mV    -71.36mA   -107.4mA   -76.32mA
-916mV    -59.06mA   -86.06mA   -69.27mA
-853mV    -47.09mA   -59.56mA   -59.17mA
-811mV    -41.26mA   -45.98mA   -52.6mA
-769mV    -36.02mA   -35.6mA    -46.2mA
-706mV    -28.69mA   -25.09mA   -36.94mA
-643mV    -21.92mA   -18.43mA   -28.26mA
-559mV    -13.95mA   -12.02mA   -17.87mA
-412mV    -3.913mA   -4.186mA   -4.633mA
-286mV    -419.8uA   -841.9uA   -337.6uA
1V        0A         0A         0A
[POWER_clamp]
|Voltage   I(typ)   I(min)   I(max)
-1V       51.31mA    91.27mA    38.52mA
-974mV    41.77mA    78.02mA    33.75mA
-932mV    29.97mA    58.67mA    28.49mA
-890mV    22.53mA    42.53mA    24.69mA
-848mV    17.98mA    29.96mA    21.34mA
-806mV    14.9mA     21mA       18.22mA
-764mV    12.49mA    15.08mA    15.32mA
-722mV    10.41mA    11.26mA    12.68mA
-659mV    7.731mA    7.774mA    9.264mA
-491mV    2.875mA    3.182mA    3.183mA
-302mV    447.2uA    770.3uA    371.6uA
1V        0A         0A         0A
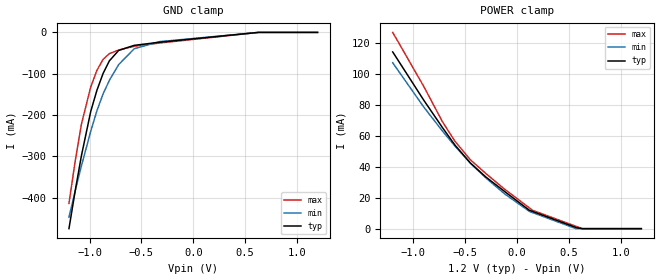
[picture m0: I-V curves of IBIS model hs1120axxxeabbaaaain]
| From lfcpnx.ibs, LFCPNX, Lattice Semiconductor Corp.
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|   Model   hs1120axxxeabbaaaain
[Model] hs1120axxxeabbaaaain
Model_type   Input
Polarity   Non-Inverting
Vinl   =   0.575V
Vinh   =   0.775V
C_comp  4.460pF 4.394pF 4.558pF
[Model Spec]
| Input threshold voltage corners
Vinl   0.4580V   0.428V   0.491V
Vinh   0.742V   0.712V   0.776V
[Receiver Thresholds]
Vth   =  0.6V
Vth_min  =  0.588V
Vth_max  =  0.612V
Vinh_ac  =  0.160V
Vinh_dc  =  0.090V
Vinl_ac  = -0.160V
Vinl_dc  = -0.090V
Tslew_ac =  5.000ns |Not specified, so set to high value"
[Temperature Range]   25   125   -40
[Voltage Range] 1.2000V 1.140V  1.260V
[GND_clamp]
|Voltage   I(typ)  I(min)  I(max)
-1.2V     -474.7mA   -447.2mA   -413.8mA
-1.14V    -383.5mA   -383.7mA   -311.6mA
-1.08V    -298.6mA   -323.3mA   -222.6mA
-990mV    -191.4mA   -239.4mA   -132.2mA
-930mV    -139.9mA   -189.4mA   -91.66mA
-870mV    -99.08mA   -148.5mA   -65.13mA
-810mV    -68.87mA   -116.1mA   -51.43mA
-720mV    -43.57mA   -77.8mA    -42.63mA
-570mV    -31.35mA   -39.57mA   -33.54mA
-330mV    -23.88mA   -22.45mA   -25.82mA
630mV     0A         0A         0A
1.2V      0A         0A         0A
[POWER_clamp]
|Voltage   I(typ)  I(min)  I(max)
-1.2V     114mA      107mA      126.6mA
-900mV    82.84mA    78.43mA    91.72mA
-720mV    65.22mA    62.99mA    68.99mA
-600mV    53.97mA    53.36mA    56.47mA
-450mV    42.35mA    42.2mA     44.42mA
-300mV    33.27mA    32.7mA     35.53mA
-120mV    23.99mA    22.47mA    25.44mA
120mV     11.84mA    11.1mA     13.36mA
150mV     11.1mA     10.36mA    11.84mA
570mV     740uA      0A         1.48mA
630mV     0A         0A         0A
1.2V      0A         0A         0A
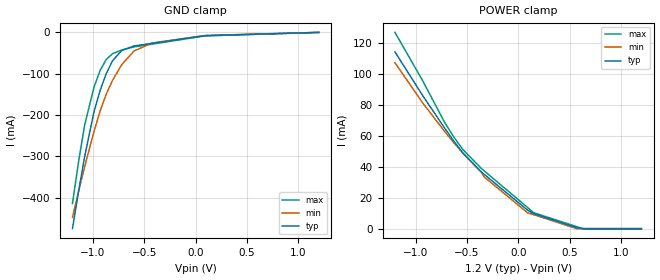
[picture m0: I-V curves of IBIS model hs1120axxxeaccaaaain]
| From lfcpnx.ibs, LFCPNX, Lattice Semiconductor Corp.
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|   Model   hs1120axxxeaccaaaain
[Model] hs1120axxxeaccaaaain
Model_type   Input
Polarity   Non-Inverting
Vinl   =   0.575V
Vinh   =   0.775V
C_comp  4.460pF 4.394pF 4.558pF
[Model Spec]
| Input threshold voltage corners
Vinl   0.4580V   0.428V   0.491V
Vinh   0.742V   0.712V   0.776V
[Receiver Thresholds]
Vth   =  0.6V
Vth_min  =  0.588V
Vth_max  =  0.612V
Vinh_ac  =  0.160V
Vinh_dc  =  0.090V
Vinl_ac  = -0.160V
Vinl_dc  = -0.090V
Tslew_ac =  5.000ns |Not specified, so set to high value"
[Temperature Range]   25   125   -40
[Voltage Range] 1.2000V 1.140V  1.260V
[GND_clamp]
|Voltage   I(typ)  I(min)  I(max)
-1.2V     -474.7mA   -447.2mA   -413.8mA
-1.14V    -383.5mA   -383.7mA   -311.6mA
-1.08V    -298.6mA   -323.3mA   -222.6mA
-990mV    -191.4mA   -239.4mA   -132.2mA
-930mV    -139.9mA   -189.4mA   -91.66mA
-870mV    -99.08mA   -148.5mA   -65.13mA
-810mV    -68.87mA   -116.1mA   -51.43mA
-720mV    -43.57mA   -77.8mA    -42.63mA
-600mV    -32.73mA   -44.71mA   -35.05mA
-420mV    -26.34mA   -25.47mA   -28.26mA
90mV      -7.963mA   -7.474mA   -8.452mA
1.2V      0A         0A         0A
[POWER_clamp]
|Voltage   I(typ)  I(min)  I(max)
-1.2V     114mA      107mA      126.6mA
-930mV    85.81mA    81.12mA    95.36mA
-720mV    65.22mA    62.99mA    68.99mA
-630mV    56.64mA    55.72mA    59.37mA
-540mV    48.95mA    48.74mA    51.14mA
-360mV    36.71mA    36.3mA     38.92mA
-330mV    34.96mA    33.27mA    37.21mA
90mV      12.02mA    10.31mA    13.73mA
150mV     9.664mA    9.02mA     10.31mA
570mV     644uA      0A         1.289mA
630mV     0A         0A         0A
1.2V      0A         0A         0A
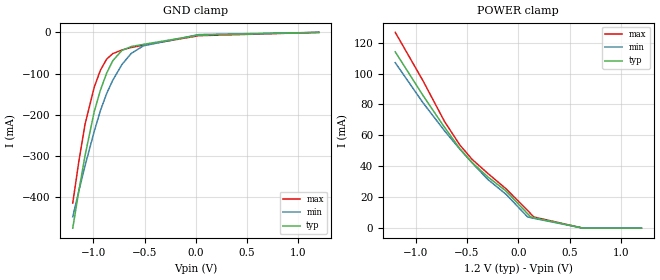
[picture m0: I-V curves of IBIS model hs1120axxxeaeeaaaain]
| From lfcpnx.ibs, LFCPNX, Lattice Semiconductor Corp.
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|   Model   hs1120axxxeaeeaaaain
[Model] hs1120axxxeaeeaaaain
Model_type   Input
Polarity   Non-Inverting
Vinl   =   0.575V
Vinh   =   0.775V
C_comp  4.460pF 4.394pF 4.558pF
[Model Spec]
| Input threshold voltage corners
Vinl   0.4580V   0.428V   0.491V
Vinh   0.742V   0.712V   0.776V
[Receiver Thresholds]
Vth   =  0.6V
Vth_min  =  0.588V
Vth_max  =  0.612V
Vinh_ac  =  0.160V
Vinh_dc  =  0.090V
Vinl_ac  = -0.160V
Vinl_dc  = -0.090V
Tslew_ac =  5.000ns |Not specified, so set to high value"
[Temperature Range]   25   125   -40
[Voltage Range] 1.2000V 1.140V  1.260V
[GND_clamp]
|Voltage   I(typ)  I(min)  I(max)
-1.2V     -474.7mA   -447.2mA   -413.8mA
-1.14V    -383.5mA   -383.7mA   -311.6mA
-1.08V    -298.6mA   -323.3mA   -222.6mA
-990mV    -191.4mA   -239.4mA   -132.2mA
-930mV    -139.9mA   -189.4mA   -91.66mA
-870mV    -99.08mA   -148.5mA   -65.13mA
-810mV    -68.87mA   -116.1mA   -51.43mA
-720mV    -43.57mA   -77.8mA    -42.63mA
-630mV    -34.39mA   -51.05mA   -36.73mA
-510mV    -29.07mA   -32.44mA   -31.03mA
30mV      -6.681mA   -5.341mA   -8.021mA
1.2V      0A         0A         0A
[POWER_clamp]
|Voltage   I(typ)  I(min)  I(max)
-1.2V     114mA      107mA      126.6mA
-930mV    85.81mA    81.12mA    95.36mA
-720mV    65.22mA    62.99mA    68.99mA
-570mV    51.4mA     51.03mA    53.73mA
-450mV    42.35mA    42.2mA     44.42mA
-300mV    33.27mA    31.62mA    35.53mA
-120mV    23.99mA    21.9mA     25.44mA
90mV      9.339mA    7.246mA    11.43mA
120mV     7.246mA    6.793mA    9.339mA
150mV     6.793mA    6.34mA     7.246mA
630mV     0A         0A         0A
1.2V      0A         0A         0A
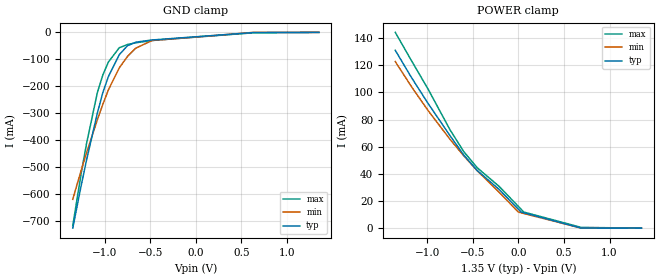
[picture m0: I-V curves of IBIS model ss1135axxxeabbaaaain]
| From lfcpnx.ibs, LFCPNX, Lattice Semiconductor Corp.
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|   Model   ss1135axxxeabbaaaain
[Model] ss1135axxxeabbaaaain
Model_type   Input
Polarity   Non-Inverting
Vinl   =   0.575V
Vinh   =   0.775V
C_comp  4.460pF 4.394pF 4.558pF
[Model Spec]
| Input threshold voltage corners
Vinl  0.5750V  0.5375V  0.6125V
Vinh  0.9250V  0.8875V  0.9625V
[Receiver Thresholds]
Vth  =  0.750V
Vth_min  =  0.735V
Vth_max  =  0.765V
Vinh_ac  =  0.175V
Vinh_dc  =  0.100V
Vinl_ac  = -0.175V
Vinl_dc  = -0.100V
Tslew_ac =  5.000ns |Not specified, so set to high value"
[Temperature Range]   25   125   -40
[Voltage Range] 1.350V  1.280V  1.420V
[GND_clamp]
|Voltage   I(typ)  I(min)  I(max)
-1.35V    -724.9mA   -618.2mA   -716.2mA
-1.26V    -571.4mA   -513.7mA   -527.1mA
-1.2V     -474.7mA   -447.2mA   -413.8mA
-1.08V    -298.6mA   -323.3mA   -222.6mA
-1.02V    -223mA     -266.4mA   -157.5mA
-960mV    -164.2mA   -213.6mA   -110.3mA
-840mV    -82.59mA   -131.5mA   -56.94mA
-750mV    -49.56mA   -89.29mA   -44.95mA
-660mV    -36.49mA   -58.68mA   -38.56mA
-480mV    -28.1mA    -30.1mA    -30.01mA
630mV     -787uA     -94.3uA    -1.574mA
1.35V     0A         0A         0A
[POWER_clamp]
|Voltage   I(typ)  I(min)  I(max)
-1.35V    131mA      122.7mA    144.2mA
-1.17V    110.7mA    104mA      123.1mA
-990mV    91.84mA    86.61mA    102.4mA
-750mV    68.17mA    65.48mA    72.52mA
-600mV    53.97mA    53.36mA    56.47mA
-450mV    42.35mA    42.2mA     44.42mA
-210mV    28.45mA    26.37mA    30.71mA
0V        13.92mA    11.84mA    15.99mA
30mV      11.84mA    11.31mA    13.92mA
60mV      11.31mA    10.77mA    11.84mA
690mV     0A         0A         538uA
1.35V     0A         0A         0A
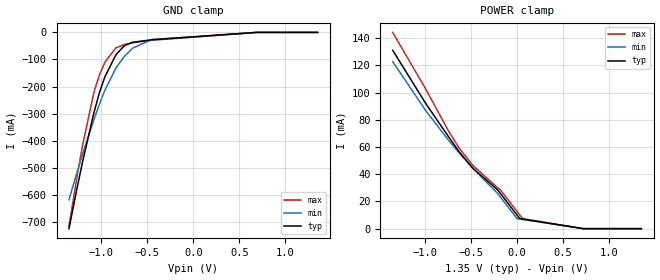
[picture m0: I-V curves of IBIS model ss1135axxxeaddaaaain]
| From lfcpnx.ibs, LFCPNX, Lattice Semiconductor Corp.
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|   Model   ss1135axxxeaddaaaain
[Model] ss1135axxxeaddaaaain
Model_type   Input
Polarity   Non-Inverting
Vinl   =   0.575V
Vinh   =   0.775V
C_comp  4.460pF 4.394pF 4.558pF
[Model Spec]
| Input threshold voltage corners
Vinl  0.5750V  0.5375V  0.6125V
Vinh  0.9250V  0.8875V  0.9625V
[Receiver Thresholds]
Vth  =  0.750V
Vth_min  =  0.735V
Vth_max  =  0.765V
Vinh_ac  =  0.175V
Vinh_dc  =  0.100V
Vinl_ac  = -0.175V
Vinl_dc  = -0.100V
Tslew_ac =  5.000ns |Not specified, so set to high value"
[Temperature Range]   25   125   -40
[Voltage Range] 1.350V  1.280V  1.420V
[GND_clamp]
|Voltage   I(typ)  I(min)  I(max)
-1.35V    -724.9mA   -618.2mA   -716.2mA
-1.26V    -571.4mA   -513.7mA   -527.1mA
-1.2V     -474.7mA   -447.2mA   -413.8mA
-1.08V    -298.6mA   -323.3mA   -222.6mA
-1.02V    -223mA     -266.4mA   -157.5mA
-960mV    -164.2mA   -213.6mA   -110.3mA
-840mV    -82.59mA   -131.5mA   -56.94mA
-750mV    -49.56mA   -89.29mA   -44.95mA
-660mV    -36.49mA   -58.68mA   -38.56mA
-450mV    -27.19mA   -26.34mA   -29.1mA
690mV     0A         0A         0A
1.35V     0A         0A         0A
[POWER_clamp]
|Voltage   I(typ)  I(min)  I(max)
-1.35V    131mA      122.7mA    144.2mA
-990mV    91.84mA    86.61mA    102.4mA
-750mV    68.17mA    65.48mA    72.52mA
-630mV    56.64mA    55.72mA    59.37mA
-480mV    44.42mA    44.31mA    46.48mA
-210mV    28.45mA    25.82mA    30.01mA
-180mV    25.82mA    23.19mA    28.45mA
0V        10.04mA    7.407mA    12.67mA
30mV      7.407mA    7.07mA     10.04mA
60mV      7.07mA     6.733mA    7.407mA
720mV     0A         0A         0A
1.35V     0A         0A         0A
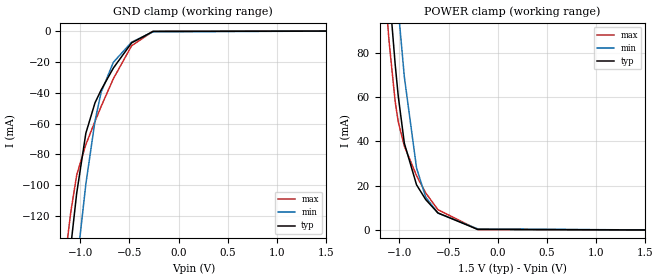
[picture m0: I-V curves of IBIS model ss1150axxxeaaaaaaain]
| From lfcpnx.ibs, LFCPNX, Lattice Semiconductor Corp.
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|Model ss1150axxxeaaaaaaain
[Model] ss1150axxxeaaaaaaain
Model_type Input
Polarity   Non-Inverting
Enable   Active-High
Vinl =  0.650V
Vinh =  0.850V
C_comp   5.000pF   4.000pF   5.500pF
[Temperature Range]   25.000   0.125k   -40.000
[Voltage Range]   1.500V   1.430V   1.580V
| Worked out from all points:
|   GND clamp passes 1 mA (typ) near -0.32 V on its own axis
|   POWER clamp passes 1 mA (typ) near -0.31 V on its own axis
[GND_clamp]
|Voltage   I(typ)   I(min)   I(max)
-1.5V     -437.9mA   -483.5mA   -411.6mA
-1.159V   -181.5mA   -234.4mA   -153.5mA
-1.128V   -160.7mA   -213.1mA   -134.8mA
-1.097V   -140.8mA   -192.4mA   -118.3mA
-1.035V   -105.2mA   -152.5mA   -93.38mA
-942mV    -66.28mA   -99.24mA   -73.59mA
-849mV    -46.51mA   -58.31mA   -58.54mA
-787mV    -38.23mA   -39.78mA   -48.93mA
-663mV    -24.01mA   -20.29mA   -30.95mA
-477mV    -7.627mA   -7.147mA   -9.526mA
-260mV    -205.9uA   -520.9uA   -132.8uA
1.5V      0A         0A         0A
[POWER_clamp]
|Voltage   I(typ)   I(min)   I(max)
-1.5V     394mA      431.9mA    372.6mA
-1.166V   148.2mA    194.8mA    121.8mA
-1.135V   128mA      174.5mA    102.6mA
-1.104V   108.9mA    154.7mA    85.19mA
-1.042V   74.77mA    117.3mA    57.98mA
-1.011V   60.53mA    100mA      48.91mA
-949mV    39.21mA    69.17mA    37.91mA
-825mV    20.41mA    28.01mA    24.55mA
-732mV    13.74mA    14.83mA    16.73mA
-608mV    7.699mA    7.627mA    9.178mA
-205mV    265.4uA    515.7uA    203.6uA
1.5V      0A         0A         0A
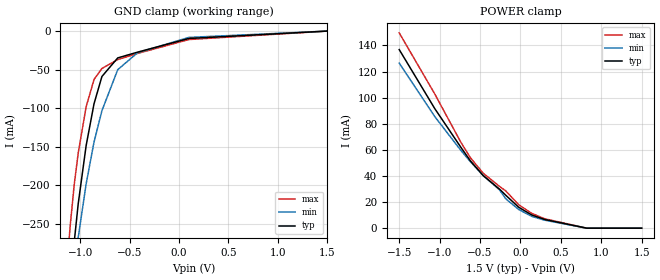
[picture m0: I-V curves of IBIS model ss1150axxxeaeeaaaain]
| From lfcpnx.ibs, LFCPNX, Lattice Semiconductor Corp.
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|   Model   ss1150axxxeaeeaaaain
[Model] ss1150axxxeaeeaaaain
Model_type   Input
Polarity   Non-Inverting
Vinl   =   0.650V
Vinh   =   0.850V
C_comp  4.383pF 4.308pF 4.470pF
[Model Spec]
| Input threshold voltage corners
Vinl  0.5750V  0.5375V  0.6125V
Vinh  0.9250V  0.8875V  0.9625V
[Receiver Thresholds]
Vth  =  0.750V
Vth_min  =  0.735V
Vth_max  =  0.765V
Vinh_ac  =  0.175V
Vinh_dc  =  0.100V
Vinl_ac  = -0.175V
Vinl_dc  = -0.100V
Tslew_ac =  5.000ns |Not specified, so set to high value"
[Temperature Range]   25   0.125k  -40
[Voltage Range] 1.500V  1.430V  1.580V
[GND_clamp]
|Voltage   I(typ)  I(min)  I(max)
-1.5V     -999.5mA   -804.2mA   -1.074A
-1.14V    -384.5mA   -384.9mA   -312.4mA
-1.1V     -327.1mA   -344.3mA   -250.9mA
-1.06V    -273mA     -305.2mA   -198.7mA
-1.02V    -224mA     -267.7mA   -158.2mA
-940mV    -148.7mA   -198.5mA   -98.27mA
-860mV    -94.3mA    -143.9mA   -62.84mA
-780mV    -58.91mA   -103.3mA   -48.5mA
-620mV    -34.81mA   -50.08mA   -36.95mA
-420mV    -27.36mA   -28.19mA   -29.06mA
100mV     -9.586mA   -8.204mA   -10.97mA
1.5V      0A         0A         0A
[POWER_clamp]
|Voltage   I(typ)  I(min)  I(max)
-1.5V     136.8mA    126.4mA    149.6mA
-1.06V    91.57mA    85.46mA    102.8mA
-740mV    62.22mA    59.81mA    66.12mA
-620mV    51.61mA    51.02mA    54mA
-460mV    40.23mA    40.21mA    42.05mA
-260mV    29.96mA    29.4mA     32.05mA
-180mV    25.12mA    22.42mA    28.46mA
-20mV     15.95mA    14.24mA    17.87mA
140mV     10.13mA    9.042mA    11.35mA
300mV     6.651mA    6.097mA    7.206mA
820mV     0A         0A         0A
1.5V      0A         0A         0A
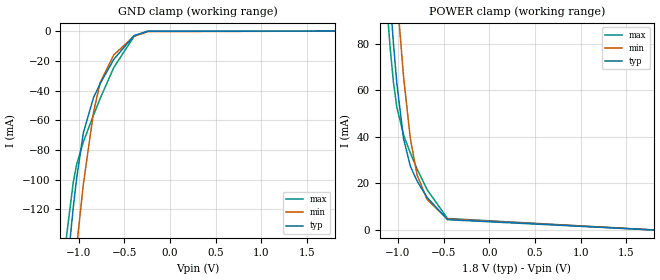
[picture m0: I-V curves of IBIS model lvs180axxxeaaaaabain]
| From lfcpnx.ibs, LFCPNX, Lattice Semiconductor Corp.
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|Model lvs180axxxeaaaaabain
[Model] lvs180axxxeaaaaabain
Model_type Input
Polarity   Non-Inverting
Enable   Active-High
Vinl =  1.150V
Vinh =  1.350V
C_comp   5.000pF   4.000pF   5.500pF
[Temperature Range]   25.000   0.125k   -40.000
[Voltage Range]   1.800V   1.710V   1.890V
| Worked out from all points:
|   GND clamp passes 1 mA (typ) near -0.33 V on its own axis
|   POWER clamp passes 1 mA (typ) near -0.27 V on its own axis
[GND_clamp]
|Voltage   I(typ)   I(min)   I(max)
-1.8V     -677.4mA   -712.9mA   -658.2mA
-1.171V   -189.8mA   -242.8mA   -161.2mA
-1.134V   -164.7mA   -217.3mA   -138.3mA
-1.06V    -118.8mA   -168.3mA   -101.8mA
-1.023V   -99.02mA   -145.2mA   -89.73mA
-949mV    -68.35mA   -102.9mA   -74.49mA
-838mV    -44.67mA   -54.45mA   -56.51mA
-764mV    -35.17mA   -34.51mA   -45.15mA
-616mV    -18.97mA   -15.98mA   -24.45mA
-394mV    -3.014mA   -3.398mA   -3.479mA
-246mV    -125.3uA   -370.9uA   -72.52uA
1.8V      0A         0A         0A
[POWER_clamp]
|Voltage   I(typ)   I(min)   I(max)
-1.8V     630.6mA    657.5mA    617.1mA
-1.16V    145.6mA    191.8mA    119.8mA
-1.123V   121.9mA    167.8mA    97.77mA
-1.086V   99.96mA    144.6mA    78.71mA
-1.049V   80.13mA    122.5mA    63.55mA
-1.012V   63.07mA    101.7mA    52.79mA
-938mV    39.18mA    65.73mA    40.83mA
-864mV    27.4mA     39.31mA    33.08mA
-790mV    20.99mA    23.56mA    26.19mA
-679mV    13.9mA     13.03mA    17.21mA
-457mV    4.419mA    4.712mA    4.931mA
1.8V      0A         0A         0A
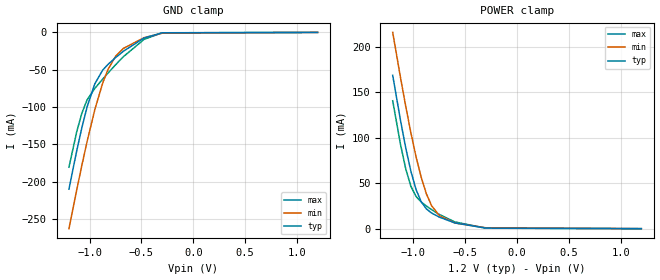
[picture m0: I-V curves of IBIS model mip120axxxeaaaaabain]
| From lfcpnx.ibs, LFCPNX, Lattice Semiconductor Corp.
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|Model mip120axxxeaaaaabain
[Model] mip120axxxeaaaaabain
Model_type Input
Polarity   Non-Inverting
Enable   Active-High
Vinl =  0.0V
Vinh =  0.400V
C_comp   5.000pF   4.000pF   5.500pF
[Temperature Range]   25.000   0.125k   -40.000
[Voltage Range]   1.200V   1.140V   1.260V
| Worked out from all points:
|   GND clamp passes 1 mA (typ) near -0.32 V on its own axis
|   POWER clamp passes 1 mA (typ) near -0.35 V on its own axis
[GND_clamp]
|Voltage   I(typ)   I(min)   I(max)
-1.2V     -209.9mA   -262.8mA   -180.5mA
-1.125V   -158.5mA   -210.9mA   -133mA
-1.075V   -127.3mA   -177.7mA   -108mA
-1.025V   -99.89mA   -146.2mA   -90.44mA
-950mV    -68.72mA   -103.2mA   -74.92mA
-875mV    -50.63mA   -68.08mA   -62.64mA
-825mV    -43.11mA   -50.19mA   -54.76mA
-750mV    -33.74mA   -31.88mA   -43.35mA
-675mV    -25.28mA   -21.49mA   -32.58mA
-475mV    -7.489mA   -7.044mA   -9.346mA
-300mV    -592.6uA   -1.06mA    -520.4uA
1.2V      0A         0A         0A
[POWER_clamp]
|Voltage   I(typ)   I(min)   I(max)
-1.2V     168.6mA    215.8mA    140.6mA
-1.125V   119.2mA    166.3mA    92.77mA
-1.075V   89.22mA    135mA      66.13mA
-1.025V   63.34mA    105.7mA    46.72mA
-975mV    43.11mA    79.19mA    35.44mA
-925mV    29.55mA    56.45mA    29.3mA
-875mV    21.75mA    38.35mA    24.89mA
-825mV    17.22mA    25.37mA    20.95mA
-750mV    12.7mA     14.33mA    15.61mA
-600mV    6.289mA    6.246mA    7.426mA
-300mV    596.2uA    936.5uA    529.6uA
1.2V      0A         0A         0A
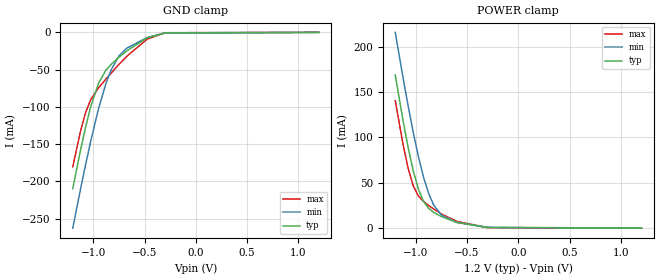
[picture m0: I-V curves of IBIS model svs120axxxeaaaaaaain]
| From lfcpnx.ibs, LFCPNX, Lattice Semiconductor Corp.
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|Model svs120axxxeaaaaaaain
[Model] svs120axxxeaaaaaaain
Model_type Input
Polarity   Non-Inverting
Enable   Active-High
Vinl =  0.0V
Vinh =  0.400V
C_comp   5.000pF   4.000pF   5.500pF
[Temperature Range]   25.000   0.125k   -40.000
[Voltage Range]   1.200V   1.140V   1.260V
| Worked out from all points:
|   GND clamp passes 1 mA (typ) near -0.33 V on its own axis
|   POWER clamp passes 1 mA (typ) near -0.35 V on its own axis
[GND_clamp]
|Voltage   I(typ)   I(min)   I(max)
-1.2V     -209.8mA   -262.7mA   -180.4mA
-1.125V   -158.4mA   -210.8mA   -132.9mA
-1.075V   -127.2mA   -177.7mA   -107.8mA
-1.025V   -99.77mA   -146.1mA   -90.21mA
-950mV    -68.55mA   -103.2mA   -74.65mA
-875mV    -50.41mA   -67.97mA   -62.36mA
-825mV    -42.87mA   -50.06mA   -54.48mA
-750mV    -33.5mA    -31.72mA   -43.05mA
-675mV    -25.04mA   -21.32mA   -32.28mA
-475mV    -7.31mA    -6.9mA     -9.116mA
-300mV    -565uA     -1.02mA    -493.8uA
1.2V      0A         0A         0A
[POWER_clamp]
|Voltage   I(typ)   I(min)   I(max)
-1.2V     168.6mA    215.7mA    140.5mA
-1.125V   119.2mA    166.3mA    92.77mA
-1.075V   89.22mA    135mA      66.15mA
-1.025V   63.36mA    105.7mA    46.77mA
-975mV    43.14mA    79.2mA     35.53mA
-925mV    29.6mA     56.47mA    29.4mA
-875mV    21.82mA    38.38mA    24.97mA
-825mV    17.28mA    25.41mA    21.03mA
-750mV    12.75mA    14.37mA    15.67mA
-600mV    6.312mA    6.271mA    7.453mA
-300mV    596.5uA    937.9uA    529.7uA
1.2V      0A         0A         0A
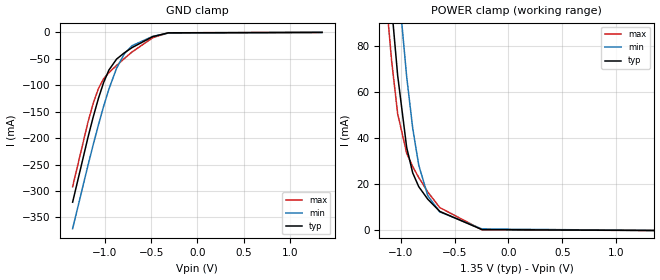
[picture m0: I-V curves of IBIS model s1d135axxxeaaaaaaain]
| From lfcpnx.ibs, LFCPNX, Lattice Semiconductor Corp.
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|Model s1d135axxxeaaaaaaain
[Model] s1d135axxxeaaaaaaain
Model_type Input
Polarity   Non-Inverting
Enable   Active-High
Vinl =  0.575V
Vinh =  0.775V
C_comp   5.000pF   4.000pF   5.500pF
[Temperature Range]   25.000   0.125k   -40.000
[Voltage Range]   1.350V   1.280V   1.420V
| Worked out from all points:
|   GND clamp passes 1 mA (typ) near -0.32 V on its own axis
|   POWER clamp passes 1 mA (typ) near -0.33 V on its own axis
[GND_clamp]
|Voltage   I(typ)   I(min)   I(max)
-1.35V    -321.3mA   -371.4mA   -292mA
-1.182V   -197.3mA   -250.2mA   -168.4mA
-1.126V   -159.3mA   -211.7mA   -133.6mA
-1.07V    -124.5mA   -174.6mA   -105.9mA
-1.014V   -94.57mA   -139.6mA   -87.62mA
-958mV    -71.45mA   -107.6mA   -76.32mA
-874mV    -50.48mA   -67.76mA   -62.5mA
-790mV    -38.6mA    -40.5mA    -49.38mA
-706mV    -28.69mA   -25.12mA   -36.95mA
-482mV    -7.963mA   -7.428mA   -9.973mA
-314mV    -812.3uA   -1.332mA   -765.1uA
1.35V     0A         0A         0A
[POWER_clamp]
|Voltage   I(typ)   I(min)   I(max)
-1.35V    278.9mA    322mA      253.6mA
-1.142V   131.3mA    178.3mA    104.8mA
-1.114V   113.6mA    160.2mA    88.35mA
-1.086V   96.89mA    142.7mA    73.55mA
-1.03V    67.21mA    109.5mA    50.61mA
-946mV    35.94mA    66.57mA    33.43mA
-890mV    24.94mA    44.31mA    27.67mA
-834mV    18.98mA    28.3mA     22.94mA
-750mV    13.54mA    15.07mA    16.67mA
-638mV    8.242mA    8.047mA    9.899mA
-246mV    370.8uA    657.1uA    302.1uA
1.35V     0A         0A         0A
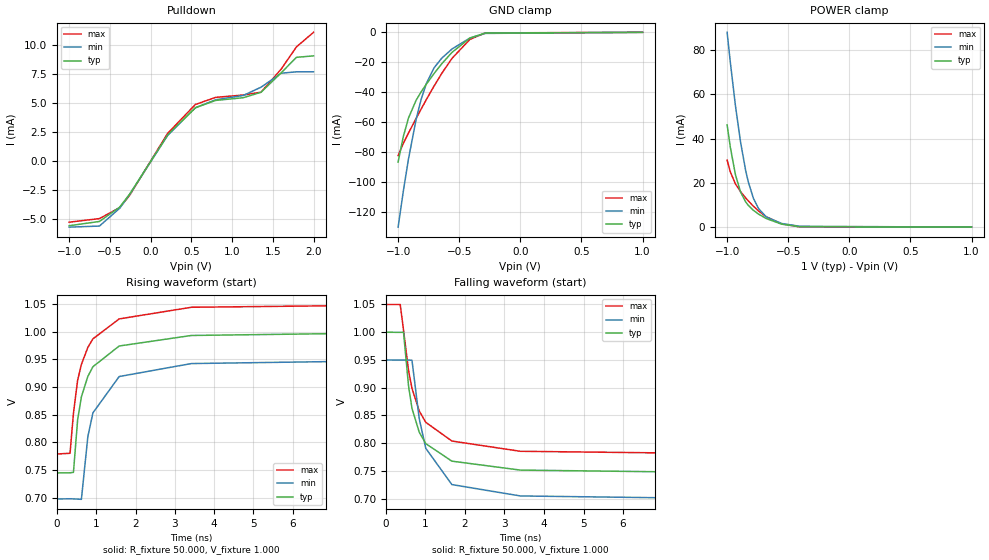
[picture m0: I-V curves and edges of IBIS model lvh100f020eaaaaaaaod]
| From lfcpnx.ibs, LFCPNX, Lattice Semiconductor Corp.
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|Model lvh100f020eaaaaaaaod
[Model] lvh100f020eaaaaaaaod
Model_type I/O_open_drain
Polarity   Non-Inverting
Enable   Active-Low
Vinl =  0.350V
Vinh =  0.650V
Vmeas =  0.500V
Cref =  0.0F
Rref = 10.00k
Vref = 1.00V
C_comp   5.000pF   4.000pF   5.500pF
[Temperature Range]   25.000   0.125k   -40.000
[Voltage Range]   1.000V   0.950V   1.050V
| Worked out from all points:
|   slope of the pulldown table from 0 to 0.15 V, typ, clamps not added: 92.9 ohm
|   GND clamp passes 1 mA (typ) near -0.32 V on its own axis
|   POWER clamp passes 1 mA (typ) near -0.52 V on its own axis
|   rising waveform, R_fixture 50.000, V_fixture 1.000: 20-80 % time 562ps typ, 538ps min, 603ps max; typ from 0.745 V to 0.999 V
|   falling waveform, R_fixture 50.000, V_fixture 1.000: 20-80 % time 524ps typ, 539ps min, 591ps max; typ from 1 V to 0.746 V
[Pulldown]
|Voltage   I(typ)   I(min)   I(max)
-1V       -5.616mA   -5.738mA   -5.31mA
-628mV    -5.247mA   -5.643mA   -5.001mA
-380mV    -4.016mA   -4.114mA   -4.062mA
-256mV    -2.883mA   -2.911mA   -2.984mA
209mV     2.198mA    2.165mA    2.342mA
550mV     4.558mA    4.544mA    4.833mA
798mV     5.182mA    5.237mA    5.444mA
1.139V    5.416mA    5.612mA    5.65mA
1.356V    5.887mA    6.323mA    5.894mA
1.604V    7.569mA    7.525mA    7.891mA
1.79V     8.897mA    7.647mA    9.791mA
2V        9.019mA    7.647mA    11.05mA
[GND_clamp]
|Voltage   I(typ)   I(min)   I(max)
-1V       -86.52mA   -130mA     -82.22mA
-958mV    -69.74mA   -106.3mA   -74.23mA
-916mV    -57.32mA   -84.85mA   -67.33mA
-853mV    -45.37mA   -58.2mA    -57.49mA
-811mV    -39.68mA   -44.56mA   -51.1mA
-769mV    -34.6mA    -34.16mA   -44.86mA
-706mV    -27.51mA   -23.72mA   -35.86mA
-643mV    -20.99mA   -17.24mA   -27.42mA
-559mV    -13.35mA   -11.12mA   -17.36mA
-412mV    -3.828mA   -3.766mA   -4.677mA
-286mV    -480.6uA   -718.1uA   -398.8uA
1V        0A         0A         0A
[POWER_clamp]
|Voltage   I(typ)   I(min)   I(max)
-1V       46.2mA     88mA       30.29mA
-974mV    36.18mA    74.56mA    25.01mA
-932mV    23.68mA    54.88mA    19.52mA
-890mV    15.87mA    38.38mA    16.03mA
-848mV    11.37mA    25.5mA     13.19mA
-827mV    9.86mA     20.48mA    11.88mA
-785mV    7.615mA    13.04mA    9.467mA
-743mV    5.907mA    8.409mA    7.326mA
-680mV    3.893mA    4.633mA    4.691mA
-554mV    1.362mA    1.661mA    1.475mA
-407mV    200.4uA    401.3uA    146.8uA
1V        0A         0A         13.43nA
[Ramp]
| variable   typ   min   max
dV/dt_r   0.152/0.565n   0.151/0.541n   0.162/0.600n
dV/dt_f   0.152/0.524n   0.151/0.539n   0.162/0.598n
R_load = 50.000
[Rising Waveform]
R_fixture= 50.000
V_fixture= 1.000
V_fixture_min= 0.950
V_fixture_max= 1.050
|time   V(typ)   V(min)   V(max)
0s        745.1mV    698.1mV    779.2mV
334ps     745.3mV    698.3mV    780.5mV
421ps     746.1mV    698.2mV    852.7mV
527ps     840.8mV    697.8mV    912.2mV
623ps     882.5mV    697.4mV    940.9mV
787ps     919.2mV    810.5mV    971.5mV
916ps     936.7mV    853.4mV    987mV
1.584ns   974.1mV    919mV      1.023V
3.419ns   993.1mV    942.4mV    1.044V
10ns      999.2mV    949.1mV    1.049V
[Falling Waveform]
R_fixture= 50.000
V_fixture= 1.000
V_fixture_min= 0.950
V_fixture_max= 1.050
|time   V(typ)   V(min)   V(max)
0s        1V         950mV      1.05V
362ps     999.8mV    949.8mV    1.05V
446ps     1V         949.9mV    1.004V
573ps     903mV      949.9mV    930.9mV
660ps     862.7mV    949.4mV    898.8mV
843ps     819.9mV    844.2mV    858.2mV
1.009ns   799.2mV    790.7mV    837.6mV
1.669ns   767.6mV    725.4mV    803.9mV
3.401ns   751.5mV    704.9mV    785.4mV
10ns      745.8mV    698.8mV    780mV
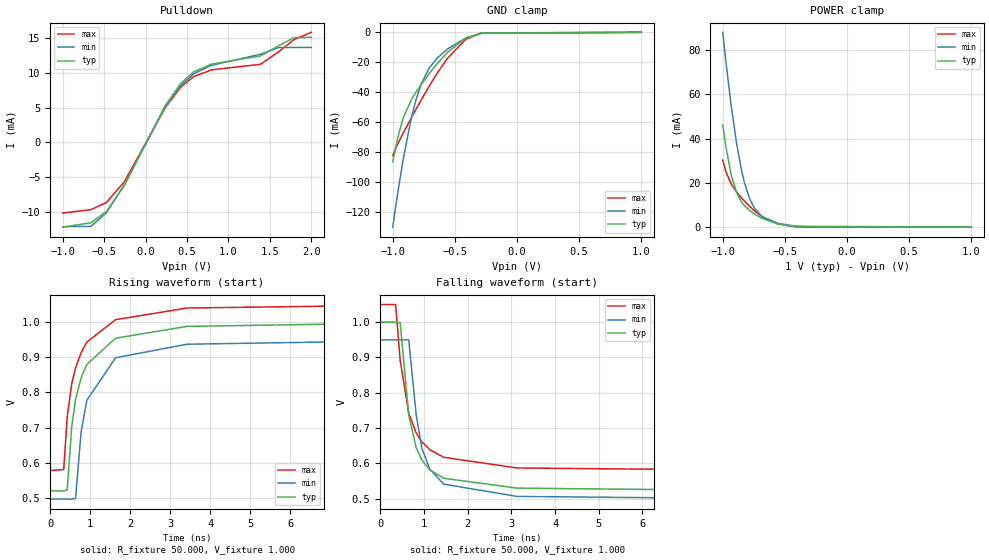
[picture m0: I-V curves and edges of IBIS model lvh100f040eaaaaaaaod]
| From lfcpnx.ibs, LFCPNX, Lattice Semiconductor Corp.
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|Model lvh100f040eaaaaaaaod
[Model] lvh100f040eaaaaaaaod
Model_type I/O_open_drain
Polarity   Non-Inverting
Enable   Active-Low
Vinl =  0.350V
Vinh =  0.650V
Vmeas =  0.500V
Cref =  0.0F
Rref = 10.00k
Vref = 1.00V
C_comp   5.000pF   4.000pF   5.500pF
[Temperature Range]   25.000   0.125k   -40.000
[Voltage Range]   1.000V   0.950V   1.050V
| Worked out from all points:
|   slope of the pulldown table from 0 to 0.15 V, typ, clamps not added: 43.2 ohm
|   GND clamp passes 1 mA (typ) near -0.32 V on its own axis
|   POWER clamp passes 1 mA (typ) near -0.52 V on its own axis
|   rising waveform, R_fixture 50.000, V_fixture 1.000: 20-80 % time 561ps typ, 534ps min, 605ps max; typ from 0.521 V to 0.998 V
|   falling waveform, R_fixture 50.000, V_fixture 1.000: 20-80 % time 396ps typ, 381ps min, 468ps max; typ from 1 V to 0.522 V
[Pulldown]
|Voltage   I(typ)   I(min)   I(max)
-1V       -12.19mA   -12.13mA   -10.17mA
-659mV    -11.56mA   -12.07mA   -9.669mA
-473mV    -9.945mA   -10.13mA   -8.653mA
-256mV    -6.19mA    -6.09mA    -5.656mA
240mV     5.352mA    5.142mA    5.031mA
426mV     8.473mA    8.177mA    7.953mA
581mV     10.13mA    9.857mA    9.453mA
798mV     11.25mA    11.08mA    10.42mA
1.387V    12.41mA    12.66mA    11.22mA
1.604V    13.86mA    13.61mA    12.99mA
1.79V     15.04mA    13.64mA    14.75mA
2V        15.1mA     13.64mA    15.81mA
[GND_clamp]
|Voltage   I(typ)   I(min)   I(max)
-1V       -86.52mA   -130mA     -82.22mA
-958mV    -69.74mA   -106.3mA   -74.23mA
-916mV    -57.32mA   -84.85mA   -67.33mA
-853mV    -45.37mA   -58.2mA    -57.49mA
-811mV    -39.68mA   -44.56mA   -51.1mA
-769mV    -34.6mA    -34.16mA   -44.86mA
-706mV    -27.51mA   -23.72mA   -35.86mA
-643mV    -20.99mA   -17.24mA   -27.42mA
-559mV    -13.35mA   -11.12mA   -17.36mA
-412mV    -3.828mA   -3.766mA   -4.677mA
-286mV    -480.6uA   -718.1uA   -398.8uA
1V        0A         0A         0A
[POWER_clamp]
|Voltage   I(typ)   I(min)   I(max)
-1V       46.2mA     88mA       30.29mA
-974mV    36.18mA    74.56mA    25.01mA
-932mV    23.68mA    54.88mA    19.52mA
-890mV    15.87mA    38.38mA    16.03mA
-848mV    11.37mA    25.5mA     13.19mA
-827mV    9.86mA     20.48mA    11.88mA
-785mV    7.615mA    13.04mA    9.467mA
-743mV    5.907mA    8.409mA    7.326mA
-680mV    3.893mA    4.633mA    4.691mA
-554mV    1.362mA    1.661mA    1.475mA
-407mV    200.4uA    401.3uA    146.8uA
1V        0A         0A         13.43nA
[Ramp]
| variable   typ   min   max
dV/dt_r   0.287/0.575n   0.271/0.535n   0.282/0.609n
dV/dt_f   0.287/0.394n   0.271/0.381n   0.282/0.470n
R_load = 50.000
[Rising Waveform]
R_fixture= 50.000
V_fixture= 1.000
V_fixture_min= 0.950
V_fixture_max= 1.050
|time   V(typ)   V(min)   V(max)
0s        520.7mV    497.5mV    578.3mV
336ps     520.8mV    497.6mV    581.1mV
423ps     523.6mV    497.6mV    730.2mV
536ps     701.8mV    496.7mV    823.9mV
632ps     780mV      499.6mV    869.2mV
772ps     841.1mV    688.3mV    912.9mV
914ps     879.1mV    777.3mV    942.3mV
1.633ns   953.3mV    898mV      1.006V
3.421ns   987mV      936.4mV    1.039V
10ns      998.5mV    948.4mV    1.049V
[Falling Waveform]
R_fixture= 50.000
V_fixture= 1.000
V_fixture_min= 0.950
V_fixture_max= 1.050
|time   V(typ)   V(min)   V(max)
0s        1V         950mV      1.05V
351ps     999.8mV    949.8mV    1.05V
456ps     998.2mV    949.9mV    891.3mV
651ps     737mV      949.9mV    742.4mV
821ps     645mV      738.3mV    686.5mV
952ps     609.9mV    643mV      661.3mV
1.136ns   581.7mV    583.5mV    638.8mV
1.452ns   558.1mV    541.5mV    617.5mV
3.129ns   530.2mV    506.8mV    587.3mV
10ns      521.7mV    498.5mV    579.3mV
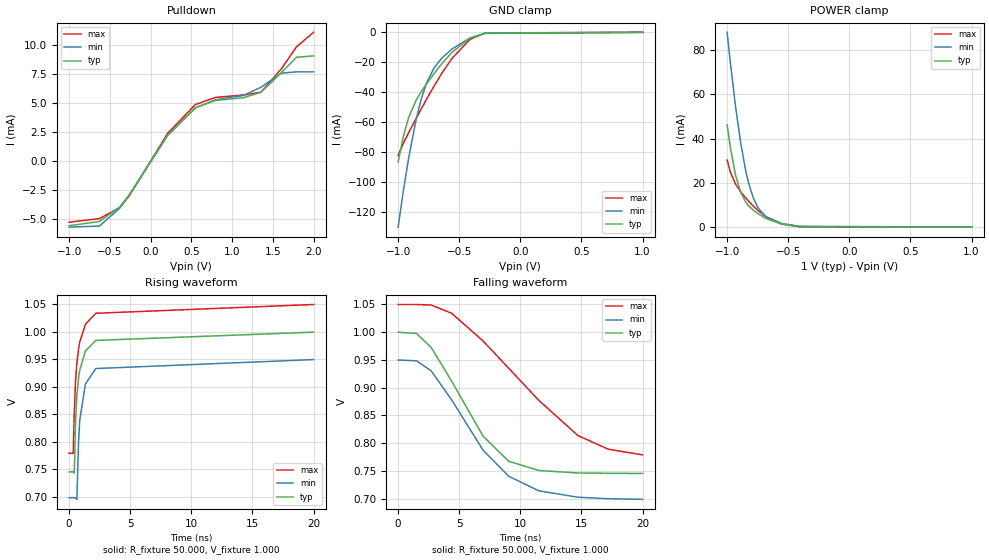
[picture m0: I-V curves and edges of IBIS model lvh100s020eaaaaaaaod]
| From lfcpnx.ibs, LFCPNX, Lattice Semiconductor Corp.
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[Model] lvh100s020eaaaaaaaod
Model_type I/O_open_drain
Polarity   Non-Inverting
Enable   Active-Low
Vinl =  0.350V
Vinh =  0.650V
Vmeas =  0.500V
Cref =  0.0F
Rref = 10.00k
Vref = 1.00V
C_comp   5.000pF   4.000pF   5.500pF
[Temperature Range]   25.000   0.125k   -40.000
[Voltage Range]   1.000V   0.950V   1.050V
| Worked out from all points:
|   slope of the pulldown table from 0 to 0.15 V, typ, clamps not added: 92.9 ohm
|   GND clamp passes 1 mA (typ) near -0.32 V on its own axis
|   POWER clamp passes 1 mA (typ) near -0.52 V on its own axis
|   rising waveform, R_fixture 50.000, V_fixture 1.000: 20-80 % time 568ps typ, 544ps min, 610ps max; typ from 0.745 V to 1 V
|   falling waveform, R_fixture 50.000, V_fixture 1.000: 20-80 % time 4.1ns typ, 4.79ns min, 7.13ns max; typ from 1 V to 0.746 V
[Pulldown]
|Voltage   I(typ)   I(min)   I(max)
-1V       -5.616mA   -5.738mA   -5.31mA
-628mV    -5.247mA   -5.642mA   -5.001mA
-380mV    -4.016mA   -4.113mA   -4.062mA
-256mV    -2.883mA   -2.911mA   -2.984mA
209mV     2.198mA    2.165mA    2.342mA
550mV     4.558mA    4.543mA    4.833mA
798mV     5.181mA    5.236mA    5.444mA
1.139V    5.416mA    5.611mA    5.65mA
1.356V    5.887mA    6.322mA    5.894mA
1.604V    7.569mA    7.524mA    7.891mA
1.79V     8.897mA    7.646mA    9.791mA
2V        9.019mA    7.646mA    11.05mA
[GND_clamp]
|Voltage   I(typ)   I(min)   I(max)
-1V       -86.52mA   -130mA     -82.22mA
-958mV    -69.74mA   -106.3mA   -74.23mA
-916mV    -57.32mA   -84.85mA   -67.33mA
-853mV    -45.37mA   -58.2mA    -57.49mA
-811mV    -39.68mA   -44.56mA   -51.1mA
-769mV    -34.6mA    -34.16mA   -44.86mA
-706mV    -27.51mA   -23.72mA   -35.86mA
-643mV    -20.99mA   -17.24mA   -27.42mA
-559mV    -13.35mA   -11.12mA   -17.36mA
-412mV    -3.828mA   -3.766mA   -4.677mA
-286mV    -480.6uA   -718.1uA   -398.8uA
1V        0A         0A         0A
[POWER_clamp]
|Voltage   I(typ)   I(min)   I(max)
-1V       46.2mA     88mA       30.29mA
-974mV    36.18mA    74.56mA    25.01mA
-932mV    23.68mA    54.88mA    19.52mA
-890mV    15.87mA    38.38mA    16.03mA
-848mV    11.37mA    25.5mA     13.19mA
-827mV    9.86mA     20.48mA    11.88mA
-785mV    7.615mA    13.04mA    9.467mA
-743mV    5.907mA    8.409mA    7.326mA
-680mV    3.893mA    4.633mA    4.691mA
-554mV    1.362mA    1.661mA    1.475mA
-407mV    200.4uA    401.3uA    146.8uA
1V        0A         0A         13.43nA
[Ramp]
| variable   typ   min   max
dV/dt_r   0.153/0.566n   0.151/0.545n   0.162/0.619n
dV/dt_f   0.153/4.124n   0.151/4.817n   0.160/7.145n
R_load = 50.000
[Rising Waveform]
R_fixture= 50.000
V_fixture= 1.000
V_fixture_min= 0.950
V_fixture_max= 1.050
|time   V(typ)   V(min)   V(max)
0s        745.1mV    698.1mV    779.2mV
334ps     745.4mV    698.3mV    779.1mV
423ps     743.3mV    698.3mV    852.7mV
524ps     836.1mV    697.9mV    910.2mV
634ps     884.4mV    695.3mV    943mV
772ps     915.9mV    799mV      968.9mV
865ps     930mV      838.6mV    981.2mV
1.332ns   965.4mV    905.2mV    1.014V
2.182ns   984.6mV    933.4mV    1.034V
20ns      999.7mV    949.7mV    1.05V
[Falling Waveform]
R_fixture = 50.000
V_fixture = 1.000
V_fixture_min = 0.950
V_fixture_max = 1.050
|  time   V(typ)   V(min)   V(max)
0s        1V         950mV      1.05V
1.508ns   997.8mV    948.5mV    1.05V
2.71ns    972.5mV    930.3mV    1.049V
4.391ns   911.4mV    877.8mV    1.034V
6.947ns   812.8mV    787.6mV    984.4mV
9.049ns   767.5mV    740.5mV    935.1mV
11.51ns   750.9mV    714.3mV    877.3mV
14.71ns   746.4mV    702.7mV    813.9mV
17.19ns   745.8mV    700mV      789.2mV
20ns      745.5mV    698.9mV    779mV
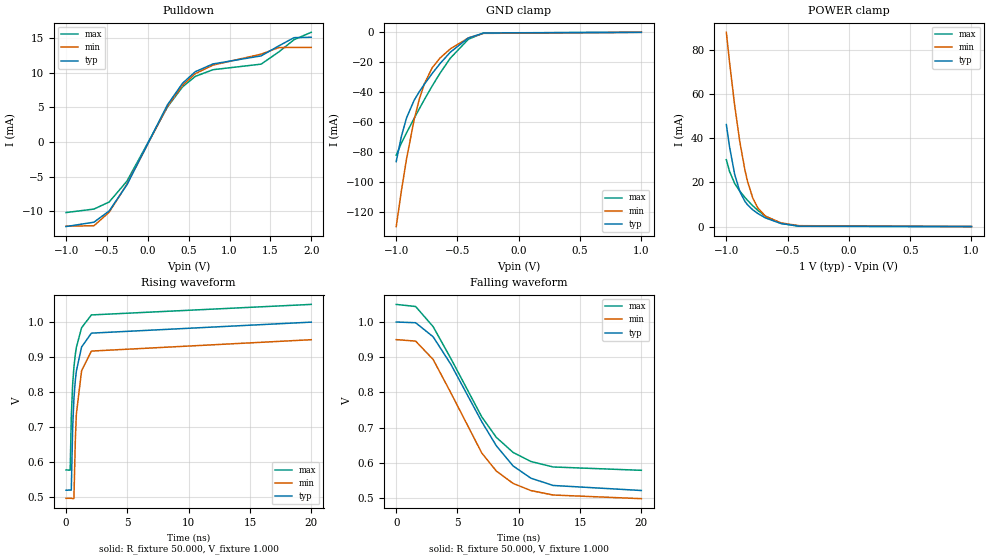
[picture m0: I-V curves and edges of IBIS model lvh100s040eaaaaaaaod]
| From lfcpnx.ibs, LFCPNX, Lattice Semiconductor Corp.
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|Model lvh100s040eaaaaaaaod
[Model] lvh100s040eaaaaaaaod
Model_type I/O_open_drain
Polarity   Non-Inverting
Enable   Active-Low
Vinl =  0.350V
Vinh =  0.650V
Vmeas =  0.500V
Cref =  0.0F
Rref = 10.00k
Vref = 1.00V
C_comp   5.000pF   4.000pF   5.500pF
[Temperature Range]   25.000   0.125k   -40.000
[Voltage Range]   1.000V   0.950V   1.050V
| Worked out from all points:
|   slope of the pulldown table from 0 to 0.15 V, typ, clamps not added: 43.2 ohm
|   GND clamp passes 1 mA (typ) near -0.32 V on its own axis
|   POWER clamp passes 1 mA (typ) near -0.52 V on its own axis
|   rising waveform, R_fixture 50.000, V_fixture 1.000: 20-80 % time 567ps typ, 541ps min, 611ps max; typ from 0.521 V to 1 V
|   falling waveform, R_fixture 50.000, V_fixture 1.000: 20-80 % time 4.79ns typ, 4.26ns min, 4.61ns max; typ from 1 V to 0.522 V
[Pulldown]
|Voltage   I(typ)   I(min)   I(max)
-1V       -12.19mA   -12.13mA   -10.17mA
-659mV    -11.56mA   -12.07mA   -9.669mA
-473mV    -9.945mA   -10.13mA   -8.653mA
-256mV    -6.19mA    -6.09mA    -5.656mA
240mV     5.352mA    5.142mA    5.031mA
426mV     8.473mA    8.176mA    7.953mA
581mV     10.13mA    9.856mA    9.453mA
798mV     11.25mA    11.08mA    10.42mA
1.387V    12.41mA    12.66mA    11.22mA
1.604V    13.86mA    13.61mA    12.99mA
1.79V     15.04mA    13.63mA    14.75mA
2V        15.1mA     13.63mA    15.81mA
[GND_clamp]
|Voltage   I(typ)   I(min)   I(max)
-1V       -86.52mA   -130mA     -82.22mA
-958mV    -69.74mA   -106.3mA   -74.23mA
-916mV    -57.32mA   -84.85mA   -67.33mA
-853mV    -45.37mA   -58.2mA    -57.49mA
-811mV    -39.68mA   -44.56mA   -51.1mA
-769mV    -34.6mA    -34.16mA   -44.86mA
-706mV    -27.51mA   -23.72mA   -35.86mA
-643mV    -20.99mA   -17.24mA   -27.42mA
-559mV    -13.35mA   -11.12mA   -17.36mA
-412mV    -3.828mA   -3.766mA   -4.677mA
-286mV    -480.6uA   -718.1uA   -398.8uA
1V        0A         0A         0A
[POWER_clamp]
|Voltage   I(typ)   I(min)   I(max)
-1V       46.2mA     88mA       30.29mA
-974mV    36.18mA    74.56mA    25.01mA
-932mV    23.68mA    54.88mA    19.52mA
-890mV    15.87mA    38.38mA    16.03mA
-848mV    11.37mA    25.5mA     13.19mA
-827mV    9.86mA     20.48mA    11.88mA
-785mV    7.615mA    13.04mA    9.467mA
-743mV    5.907mA    8.409mA    7.326mA
-680mV    3.893mA    4.633mA    4.691mA
-554mV    1.362mA    1.661mA    1.475mA
-407mV    200.4uA    401.3uA    146.8uA
1V        0A         0A         13.43nA
[Ramp]
| variable   typ   min   max
dV/dt_r   0.287/0.581n   0.271/0.544n   0.283/0.622n
dV/dt_f   0.287/4.810n   0.271/4.274n   0.283/4.620n
R_load = 50.000
[Rising Waveform]
R_fixture= 50.000
V_fixture= 1.000
V_fixture_min= 0.950
V_fixture_max= 1.050
|time   V(typ)   V(min)   V(max)
0s        520.7mV    497.5mV    578.3mV
336ps     520.9mV    497.6mV    577.8mV
425ps     521mV      497.7mV    729.3mV
536ps     697.6mV    496.5mV    822.2mV
639ps     782mV      497.1mV    870.8mV
760ps     835.8mV    669.2mV    909.1mV
839ps     860.1mV    737.6mV    927.6mV
1.264ns   928.6mV    860.9mV    983.5mV
2.065ns   968.1mV    917mV      1.02V
20ns      999.5mV    949.4mV    1.05V
[Falling Waveform]
R_fixture= 50.000
V_fixture= 1.000
V_fixture_min= 0.950
V_fixture_max= 1.050
|time   V(typ)   V(min)   V(max)
0s        1V         950mV      1.05V
1.584ns   998mV      945.8mV    1.044V
3.011ns   958.1mV    893.8mV    987mV
4.471ns   879.2mV    798.1mV    895.5mV
6.985ns   716.7mV    627.8mV    730.4mV
8.165ns   648.8mV    577.1mV    672.6mV
9.535ns   591.4mV    541.8mV    629.8mV
10.99ns   556.6mV    521.5mV    604mV
12.8ns    536mV      508.9mV    588.5mV
20ns      521.7mV    498.5mV    579mV
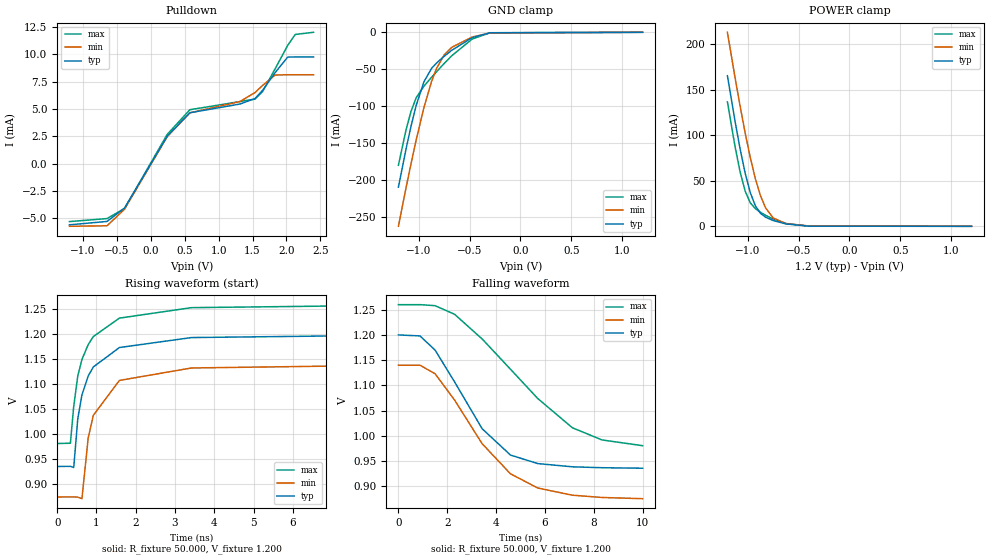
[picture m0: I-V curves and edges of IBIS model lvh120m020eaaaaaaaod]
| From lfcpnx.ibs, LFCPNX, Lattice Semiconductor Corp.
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|Model lvh120m020eaaaaaaaod
[Model] lvh120m020eaaaaaaaod
Model_type I/O_open_drain
Polarity   Non-Inverting
Enable   Active-Low
Vinl =  0.420V
Vinh =  0.780V
Vmeas =  0.600V
Cref =  0.0F
Rref = 10.00k
Vref = 1.20V
C_comp   5.000pF   4.000pF   5.500pF
[Temperature Range]   25.000   0.125k   -40.000
[Voltage Range]   1.200V   1.140V   1.260V
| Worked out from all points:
|   slope of the pulldown table from 0 to 0.18 V, typ, clamps not added: 94 ohm
|   GND clamp passes 1 mA (typ) near -0.32 V on its own axis
|   POWER clamp passes 1 mA (typ) near -0.52 V on its own axis
|   rising waveform, R_fixture 50.000, V_fixture 1.200: 20-80 % time 563ps typ, 540ps min, 604ps max; typ from 0.934 V to 1.2 V
|   falling waveform, R_fixture 50.000, V_fixture 1.200: 20-80 % time 2.04ns typ, 2.4ns min, 3.35ns max; typ from 1.2 V to 0.936 V
[Pulldown]
|Voltage   I(typ)   I(min)   I(max)
-1.2V     -5.608mA   -5.742mA   -5.31mA
-645mV    -5.297mA   -5.694mA   -5.035mA
-386mV    -4.061mA   -4.167mA   -4.101mA
243mV     2.515mA    2.475mA    2.681mA
576mV     4.658mA    4.649mA    4.935mA
1.316V    5.459mA    5.687mA    5.687mA
1.538V    5.969mA    6.515mA    5.909mA
1.649V    6.717mA    7.16mA     6.597mA
1.834V    8.34mA     8.115mA    8.689mA
2.019V    9.759mA    8.14mA     10.83mA
2.13V     9.771mA    8.14mA     11.83mA
2.4V      9.771mA    8.14mA     12.03mA
[GND_clamp]
|Voltage   I(typ)   I(min)   I(max)
-1.2V     -209mA     -261.9mA   -179.5mA
-1.125V   -157.5mA   -210mA     -131.6mA
-1.075V   -126.2mA   -176.8mA   -106.3mA
-1.025V   -98.56mA   -145.2mA   -88.4mA
-950mV    -67.09mA   -102.1mA   -72.88mA
-875mV    -48.89mA   -66.78mA   -60.89mA
-825mV    -41.48mA   -48.8mA    -53.21mA
-750mV    -32.4mA    -30.46mA   -42.1mA
-675mV    -24.23mA   -20.21mA   -31.63mA
-475mV    -7.203mA   -6.436mA   -9.167mA
-300mV    -677.3uA   -914.6uA   -623uA
1.2V      0A         0A         0A
[POWER_clamp]
|Voltage   I(typ)   I(min)   I(max)
-1.2V     165.4mA    213.1mA    136.7mA
-1.125V   115.4mA    163.4mA    87.64mA
-1.075V   84.86mA    131.9mA    59.66mA
-1.025V   58.17mA    102.3mA    38.48mA
-975mV    36.94mA    75.43mA    25.77mA
-925mV    22.46mA    52.22mA    19.37mA
-875mV    14.3mA     33.64mA    15.4mA
-825mV    10.01mA    20.29mA    12.13mA
-750mV    6.361mA    9.194mA    7.944mA
-625mV    2.629mA    2.993mA    3.055mA
-400mV    177.2uA    370.3uA    125.2uA
1.2V      0A         0A         15.62nA
[Ramp]
| variable   typ   min   max
dV/dt_r   0.159/0.561n   0.159/0.541n   0.167/0.596n
dV/dt_f   0.159/2.059n   0.159/2.486n   0.165/3.372n
R_load = 50.000
[Rising Waveform]
R_fixture= 50.000
V_fixture= 1.200
V_fixture_min= 1.140
V_fixture_max= 1.260
|time   V(typ)   V(min)   V(max)
0s        934.4mV    873.2mV    980.5mV
336ps     934.7mV    873.4mV    981mV
421ps     932.3mV    873.4mV    1.055V
524ps     1.03V      872.9mV    1.116V
630ps     1.078V     869.8mV    1.149V
790ps     1.116V     991.9mV    1.179V
920ps     1.134V     1.037V     1.195V
1.584ns   1.173V     1.107V     1.232V
3.42ns    1.193V     1.132V     1.253V
10ns      1.199V     1.139V     1.259V
[Falling Waveform]
R_fixture = 50.000
V_fixture = 1.200
V_fixture_min = 1.140
V_fixture_max = 1.260
|  time   V(typ)   V(min)   V(max)
0s        1.2V       1.14V      1.26V
882ps     1.198V     1.14V      1.26V
1.502ns   1.17V      1.123V     1.258V
2.299ns   1.107V     1.071V     1.241V
3.43ns    1.014V     984.3mV    1.192V
4.59ns    961.8mV    924.6mV    1.132V
5.706ns   944.9mV    896.5mV    1.074V
7.124ns   938.5mV    882.2mV    1.016V
8.336ns   936.7mV    877.7mV    991.8mV
10ns      935.7mV    875.3mV    980.4mV
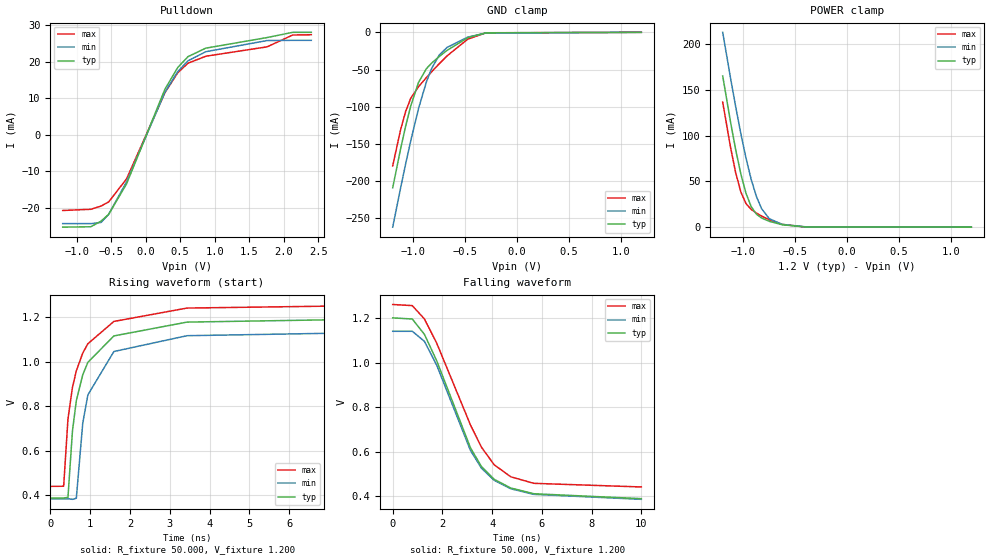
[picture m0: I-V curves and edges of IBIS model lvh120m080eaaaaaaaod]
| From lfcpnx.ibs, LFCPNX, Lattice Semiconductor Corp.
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|Model lvh120m080eaaaaaaaod
[Model] lvh120m080eaaaaaaaod
Model_type I/O_open_drain
Polarity   Non-Inverting
Enable   Active-Low
Vinl =  0.420V
Vinh =  0.780V
Vmeas =  0.600V
Cref =  0.0F
Rref = 10.00k
Vref = 1.20V
C_comp   5.000pF   4.000pF   5.500pF
[Temperature Range]   25.000   0.125k   -40.000
[Voltage Range]   1.200V   1.140V   1.260V
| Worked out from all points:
|   slope of the pulldown table from 0 to 0.18 V, typ, clamps not added: 21.5 ohm
|   GND clamp passes 1 mA (typ) near -0.32 V on its own axis
|   POWER clamp passes 1 mA (typ) near -0.52 V on its own axis
|   rising waveform, R_fixture 50.000, V_fixture 1.200: 20-80 % time 560ps typ, 534ps min, 603ps max; typ from 0.388 V to 1.2 V
|   falling waveform, R_fixture 50.000, V_fixture 1.200: 20-80 % time 1.8ns typ, 1.73ns min, 1.92ns max; typ from 1.2 V to 0.39 V
[Pulldown]
|Voltage   I(typ)   I(min)   I(max)
-1.2V     -25.27mA   -24.31mA   -20.71mA
-793mV    -25.16mA   -24.31mA   -20.38mA
-645mV    -23.63mA   -23.98mA   -19.5mA
-534mV    -21.74mA   -21.76mA   -18.36mA
-275mV    -13.41mA   -12.84mA   -12.04mA
280mV     12.47mA    11.65mA    11.52mA
465mV     18.4mA     17.28mA    16.96mA
613mV     21.38mA    20.24mA    19.58mA
872mV     23.72mA    22.75mA    21.51mA
1.76V     26.62mA    25.8mA     24.08mA
2.13V     28.05mA    25.86mA    27.31mA
2.4V      28.05mA    25.86mA    27.39mA
[GND_clamp]
|Voltage   I(typ)   I(min)   I(max)
-1.2V     -209mA     -261.9mA   -179.5mA
-1.125V   -157.5mA   -210mA     -131.6mA
-1.075V   -126.2mA   -176.8mA   -106.3mA
-1.025V   -98.56mA   -145.2mA   -88.4mA
-950mV    -67.09mA   -102.1mA   -72.88mA
-875mV    -48.89mA   -66.78mA   -60.89mA
-825mV    -41.48mA   -48.8mA    -53.21mA
-750mV    -32.4mA    -30.46mA   -42.1mA
-675mV    -24.23mA   -20.21mA   -31.63mA
-475mV    -7.203mA   -6.436mA   -9.167mA
-300mV    -677.3uA   -914.6uA   -623uA
1.2V      0A         0A         0A
[POWER_clamp]
|Voltage   I(typ)   I(min)   I(max)
-1.2V     165.4mA    213.1mA    136.7mA
-1.125V   115.4mA    163.4mA    87.64mA
-1.075V   84.86mA    131.9mA    59.66mA
-1.025V   58.17mA    102.3mA    38.48mA
-975mV    36.94mA    75.43mA    25.77mA
-925mV    22.46mA    52.22mA    19.37mA
-875mV    14.3mA     33.64mA    15.4mA
-825mV    10.01mA    20.29mA    12.13mA
-750mV    6.361mA    9.194mA    7.944mA
-625mV    2.629mA    2.993mA    3.055mA
-400mV    177.2uA    370.3uA    125.2uA
1.2V      0A         0A         15.62nA
[Ramp]
| variable   typ   min   max
dV/dt_r   0.485/0.568n   0.451/0.540n   0.490/0.609n
dV/dt_f   0.486/1.839n   0.452/1.785n   0.491/1.969n
R_load = 50.000
[Rising Waveform]
R_fixture= 50.000
V_fixture= 1.200
V_fixture_min= 1.140
V_fixture_max= 1.260
|time   V(typ)   V(min)   V(max)
0s        388.3mV    385mV      440.8mV
336ps     388.5mV    385mV      441.5mV
444ps     391.6mV    385.2mV    742.6mV
557ps     689.8mV    382.7mV    885.3mV
654ps     825.3mV    387.6mV    959.1mV
815ps     941.2mV    723.7mV    1.039V
944ps     997.5mV    851.6mV    1.081V
1.597ns   1.116V     1.046V     1.181V
3.433ns   1.178V     1.117V     1.241V
10ns      1.197V     1.137V     1.257V
[Falling Waveform]
R_fixture= 50.000
V_fixture= 1.200
V_fixture_min= 1.140
V_fixture_max= 1.260
|time   V(typ)   V(min)   V(max)
0s        1.2V       1.14V      1.26V
787ps     1.195V     1.14V      1.255V
1.277ns   1.126V     1.095V     1.195V
1.773ns   1.007V     987.3mV    1.086V
3.128ns   617.7mV    606mV      720.2mV
3.57ns    533.7mV    526.5mV    620.6mV
4.079ns   476.8mV    472.3mV    542.1mV
4.749ns   437.7mV    434.2mV    488mV
5.675ns   412.1mV    409.2mV    458.7mV
10ns      390mV      387mV      442.4mV
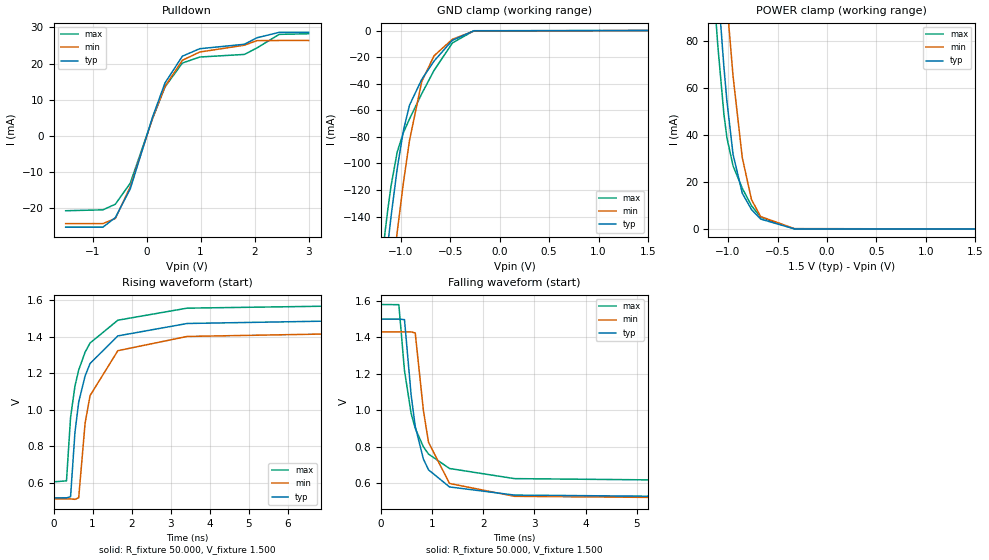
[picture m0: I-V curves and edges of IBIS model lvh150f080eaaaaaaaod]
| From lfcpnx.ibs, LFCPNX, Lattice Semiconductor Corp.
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|Model lvh150f080eaaaaaaaod
[Model] lvh150f080eaaaaaaaod
Model_type I/O_open_drain
Polarity   Non-Inverting
Enable   Active-Low
Vinl =  0.375V
Vinh =  1.125V
Vmeas =  0.750V
Cref =  0.0F
Rref = 10.00k
Vref = 1.50V
C_comp   5.000pF   4.000pF   5.500pF
[Temperature Range]   25.000   0.125k   -40.000
[Voltage Range]   1.500V   1.430V   1.580V
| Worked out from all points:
|   slope of the pulldown table from 0 to 0.225 V, typ, clamps not added: 21.9 ohm
|   GND clamp passes 1 mA (typ) near -0.32 V on its own axis
|   POWER clamp passes 1 mA (typ) near -0.52 V on its own axis
|   rising waveform, R_fixture 50.000, V_fixture 1.500: 20-80 % time 560ps typ, 536ps min, 602ps max; typ from 0.518 V to 1.5 V
|   falling waveform, R_fixture 50.000, V_fixture 1.500: 20-80 % time 332ps typ, 332ps min, 418ps max; typ from 1.5 V to 0.519 V
[Pulldown]
|Voltage   I(typ)   I(min)   I(max)
-1.5V     -25.24mA   -24.26mA   -20.7mA
-810mV    -25.24mA   -24.26mA   -20.45mA
-580mV    -22.61mA   -22.84mA   -18.9mA
-304mV    -14.66mA   -14.09mA   -13.09mA
110mV     5.23mA     4.89mA     4.819mA
340mV     14.65mA    13.69mA    13.54mA
662mV     22.05mA    20.92mA    20.15mA
984mV     24.12mA    23.2mA     21.82mA
1.812V    25.35mA    25.09mA    22.54mA
2.042V    27.14mA    26.35mA    24.32mA
2.456V    28.65mA    26.39mA    28.09mA
3V        28.65mA    26.39mA    28.25mA
[GND_clamp]
|Voltage   I(typ)   I(min)   I(max)
-1.5V     -437.2mA   -482.7mA   -410.9mA
-1.159V   -180.5mA   -233.5mA   -152.3mA
-1.128V   -159.7mA   -212.2mA   -133.5mA
-1.097V   -139.8mA   -191.4mA   -116.7mA
-1.035V   -103.9mA   -151.5mA   -91.38mA
-973mV    -75.39mA   -114.8mA   -76.89mA
-911mV    -56.18mA   -82.75mA   -66.55mA
-787mV    -36.73mA   -38.35mA   -47.52mA
-663mV    -23mA      -19.04mA   -30.03mA
-477mV    -7.329mA   -6.536mA   -9.337mA
-260mV    -229.5uA   -443.2uA   -149.9uA
1.5V      0A         0A         0A
[POWER_clamp]
|Voltage   I(typ)   I(min)   I(max)
-1.5V     391.1mA    429.4mA    369.4mA
-1.166V   144.3mA    192mA      116.6mA
-1.135V   123.8mA    171.6mA    96.78mA
-1.104V   104.3mA    151.7mA    78.55mA
-1.042V   69.26mA    114mA      49.08mA
-1.011V   54.4mA     96.46mA    38.87mA
-949mV    31.75mA    65.09mA    26.88mA
-856mV    15.25mA    30.42mA    17.36mA
-763mV    8.28mA     12.5mA     9.924mA
-670mV    4.203mA    5.276mA    5.014mA
-329mV    38.1uA     141.4uA    15.51uA
1.5V      0A         0A         19.34nA
[Ramp]
| variable   typ   min   max
dV/dt_r   0.587/0.570n   0.549/0.538n   0.583/0.595n
dV/dt_f   0.588/0.336n   0.550/0.338n   0.584/0.420n
R_load = 50.000
[Rising Waveform]
R_fixture= 50.000
V_fixture= 1.500
V_fixture_min= 1.430
V_fixture_max= 1.580
|time   V(typ)   V(min)   V(max)
0s        517.8mV    511.9mV    605.7mV
332ps     518mV      512mV      611.1mV
436ps     524.1mV    512.2mV    958.6mV
549ps     878.5mV    509.9mV    1.131V
644ps     1.042V     518.2mV    1.218V
808ps     1.186V     927.1mV    1.316V
935ps     1.254V     1.078V     1.366V
1.646ns   1.405V     1.324V     1.491V
3.419ns   1.473V     1.402V     1.557V
10ns      1.497V     1.427V     1.577V
[Falling Waveform]
R_fixture= 50.000
V_fixture= 1.500
V_fixture_min= 1.430
V_fixture_max= 1.580
|time   V(typ)   V(min)   V(max)
0s        1.5V       1.43V      1.58V
351ps     1.5V       1.43V      1.579V
461ps     1.497V     1.43V      1.218V
591ps     1.084V     1.43V      983.8mV
671ps     912.8mV    1.424V     902.2mV
831ps     733.5mV    999.1mV    800.5mV
931ps     674.8mV    825.2mV    761mV
1.341ns   581.1mV    600.1mV    682.1mV
2.61ns    536.5mV    529.8mV    626.7mV
10ns      519.2mV    513.3mV    607.4mV
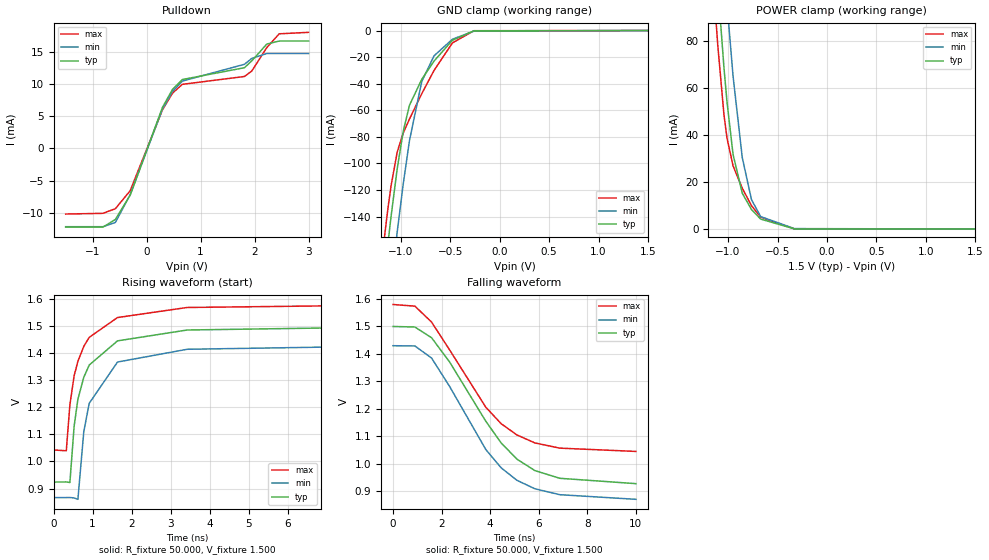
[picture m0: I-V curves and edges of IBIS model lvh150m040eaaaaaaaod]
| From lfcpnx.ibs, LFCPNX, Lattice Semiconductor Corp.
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|Model lvh150m040eaaaaaaaod
[Model] lvh150m040eaaaaaaaod
Model_type I/O_open_drain
Polarity   Non-Inverting
Enable   Active-Low
Vinl =  0.375V
Vinh =  1.125V
Vmeas =  0.750V
Cref =  0.0F
Rref = 10.00k
Vref = 1.50V
C_comp   5.000pF   4.000pF   5.500pF
[Temperature Range]   25.000   0.125k   -40.000
[Voltage Range]   1.500V   1.430V   1.580V
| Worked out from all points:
|   slope of the pulldown table from 0 to 0.225 V, typ, clamps not added: 44.6 ohm
|   GND clamp passes 1 mA (typ) near -0.32 V on its own axis
|   POWER clamp passes 1 mA (typ) near -0.52 V on its own axis
|   rising waveform, R_fixture 50.000, V_fixture 1.500: 20-80 % time 562ps typ, 540ps min, 605ps max; typ from 0.924 V to 1.5 V
|   falling waveform, R_fixture 50.000, V_fixture 1.500: 20-80 % time 2.57ns typ, 2.39ns min, 2.45ns max; typ from 1.5 V to 0.928 V
[Pulldown]
|Voltage   I(typ)   I(min)   I(max)
-1.5V     -12.19mA   -12.12mA   -10.16mA
-810mV    -12.19mA   -12.12mA   -10.05mA
-580mV    -11mA      -11.47mA   -9.337mA
-304mV    -7.22mA    -7.148mA   -6.541mA
294mV     6.375mA    6.117mA    5.995mA
478mV     9.124mA    8.817mA    8.552mA
662mV     10.67mA    10.43mA    9.93mA
1.812V    12.5mA     13.03mA    11.14mA
1.95V     13.58mA    13.95mA    12.01mA
2.226V    16.16mA    14.7mA     15.62mA
2.456V    16.63mA    14.7mA     17.75mA
3V        16.63mA    14.7mA     17.98mA
[GND_clamp]
|Voltage   I(typ)   I(min)   I(max)
-1.5V     -437.2mA   -482.7mA   -410.9mA
-1.159V   -180.5mA   -233.5mA   -152.3mA
-1.128V   -159.7mA   -212.2mA   -133.5mA
-1.097V   -139.8mA   -191.4mA   -116.7mA
-1.035V   -103.9mA   -151.5mA   -91.38mA
-973mV    -75.39mA   -114.8mA   -76.89mA
-911mV    -56.18mA   -82.75mA   -66.55mA
-787mV    -36.73mA   -38.35mA   -47.52mA
-663mV    -23mA      -19.04mA   -30.03mA
-477mV    -7.329mA   -6.536mA   -9.337mA
-260mV    -229.5uA   -443.2uA   -149.9uA
1.5V      0A         0A         0A
[POWER_clamp]
|Voltage   I(typ)   I(min)   I(max)
-1.5V     391.1mA    429.4mA    369.4mA
-1.166V   144.3mA    192mA      116.6mA
-1.135V   123.8mA    171.6mA    96.78mA
-1.104V   104.3mA    151.7mA    78.55mA
-1.042V   69.26mA    114mA      49.08mA
-1.011V   54.4mA     96.46mA    38.87mA
-949mV    31.75mA    65.09mA    26.88mA
-856mV    15.25mA    30.42mA    17.36mA
-763mV    8.28mA     12.5mA     9.924mA
-670mV    4.203mA    5.276mA    5.014mA
-329mV    38.1uA     141.4uA    15.51uA
1.5V      0A         0A         19.34nA
[Ramp]
| variable   typ   min   max
dV/dt_r   0.345/0.575n   0.337/0.546n   0.322/0.607n
dV/dt_f   0.343/2.608n   0.336/2.482n   0.321/2.543n
R_load = 50.000
[Rising Waveform]
R_fixture= 50.000
V_fixture= 1.500
V_fixture_min= 1.430
V_fixture_max= 1.580
|time   V(typ)   V(min)   V(max)
0s        923.7mV    866.5mV    1.042V
327ps     924.2mV    866.7mV    1.039V
419ps     922.1mV    866.8mV    1.209V
527ps     1.129V     865.2mV    1.315V
624ps     1.229V     860.1mV    1.369V
775ps     1.31V      1.11V      1.424V
914ps     1.355V     1.214V     1.457V
1.638ns   1.444V     1.366V     1.53V
3.42ns    1.484V     1.413V     1.567V
10ns      1.498V     1.428V     1.578V
[Falling Waveform]
R_fixture= 50.000
V_fixture= 1.500
V_fixture_min= 1.430
V_fixture_max= 1.580
|time   V(typ)   V(min)   V(max)
0s        1.5V       1.43V      1.58V
900ps     1.498V     1.429V     1.574V
1.587ns   1.459V     1.385V     1.516V
2.327ns   1.371V     1.282V     1.415V
3.819ns   1.155V     1.052V     1.206V
4.451ns   1.076V     985.3mV    1.146V
5.1ns     1.017V     939.9mV    1.105V
5.841ns   975.2mV    909mV      1.076V
6.865ns   947.2mV    887.5mV    1.057V
10ns      927.7mV    870.6mV    1.045V
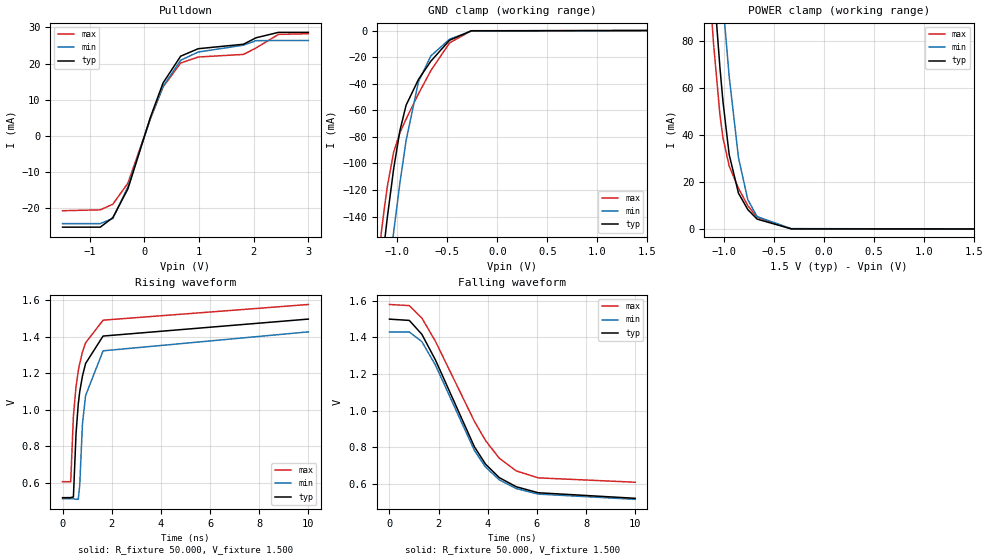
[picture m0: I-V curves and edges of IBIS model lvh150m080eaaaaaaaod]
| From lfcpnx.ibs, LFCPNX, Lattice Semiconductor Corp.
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|Model lvh150m080eaaaaaaaod
[Model] lvh150m080eaaaaaaaod
Model_type I/O_open_drain
Polarity   Non-Inverting
Enable   Active-Low
Vinl =  0.375V
Vinh =  1.125V
Vmeas =  0.750V
Cref =  0.0F
Rref = 10.00k
Vref = 1.50V
C_comp   5.000pF   4.000pF   5.500pF
[Temperature Range]   25.000   0.125k   -40.000
[Voltage Range]   1.500V   1.430V   1.580V
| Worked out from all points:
|   slope of the pulldown table from 0 to 0.225 V, typ, clamps not added: 21.9 ohm
|   GND clamp passes 1 mA (typ) near -0.32 V on its own axis
|   POWER clamp passes 1 mA (typ) near -0.52 V on its own axis
|   rising waveform, R_fixture 50.000, V_fixture 1.500: 20-80 % time 560ps typ, 537ps min, 602ps max; typ from 0.518 V to 1.5 V
|   falling waveform, R_fixture 50.000, V_fixture 1.500: 20-80 % time 2.08ns typ, 1.99ns min, 2.24ns max; typ from 1.5 V to 0.521 V
[Pulldown]
|Voltage   I(typ)   I(min)   I(max)
-1.5V     -25.24mA   -24.26mA   -20.7mA
-810mV    -25.24mA   -24.26mA   -20.45mA
-580mV    -22.61mA   -22.84mA   -18.9mA
-304mV    -14.66mA   -14.09mA   -13.09mA
110mV     5.23mA     4.89mA     4.819mA
340mV     14.65mA    13.69mA    13.54mA
662mV     22.05mA    20.92mA    20.15mA
984mV     24.12mA    23.2mA     21.82mA
1.812V    25.35mA    25.09mA    22.54mA
2.042V    27.14mA    26.35mA    24.32mA
2.456V    28.65mA    26.39mA    28.09mA
3V        28.65mA    26.39mA    28.25mA
[GND_clamp]
|Voltage   I(typ)   I(min)   I(max)
-1.5V     -437.2mA   -482.7mA   -410.9mA
-1.159V   -180.5mA   -233.5mA   -152.3mA
-1.128V   -159.7mA   -212.2mA   -133.5mA
-1.097V   -139.8mA   -191.4mA   -116.7mA
-1.035V   -103.9mA   -151.5mA   -91.38mA
-973mV    -75.39mA   -114.8mA   -76.89mA
-911mV    -56.18mA   -82.75mA   -66.55mA
-787mV    -36.73mA   -38.35mA   -47.52mA
-663mV    -23mA      -19.04mA   -30.03mA
-477mV    -7.329mA   -6.536mA   -9.337mA
-260mV    -229.5uA   -443.2uA   -149.9uA
1.5V      0A         0A         0A
[POWER_clamp]
|Voltage   I(typ)   I(min)   I(max)
-1.5V     391.1mA    429.4mA    369.4mA
-1.166V   144.3mA    192mA      116.6mA
-1.135V   123.8mA    171.6mA    96.78mA
-1.104V   104.3mA    151.7mA    78.55mA
-1.042V   69.26mA    114mA      49.08mA
-1.011V   54.4mA     96.46mA    38.87mA
-949mV    31.75mA    65.09mA    26.88mA
-856mV    15.25mA    30.42mA    17.36mA
-763mV    8.28mA     12.5mA     9.924mA
-670mV    4.203mA    5.276mA    5.014mA
-329mV    38.1uA     141.4uA    15.51uA
1.5V      0A         0A         19.34nA
[Ramp]
| variable   typ   min   max
dV/dt_r   0.587/0.570n   0.549/0.535n   0.583/0.598n
dV/dt_f   0.588/2.113n   0.549/2.010n   0.583/2.308n
R_load = 50.000
[Rising Waveform]
R_fixture= 50.000
V_fixture= 1.500
V_fixture_min= 1.430
V_fixture_max= 1.580
|time   V(typ)   V(min)   V(max)
0s        517.8mV    511.9mV    605.7mV
332ps     518.2mV    512mV      605.4mV
441ps     521.7mV    512.3mV    964mV
548ps     869.1mV    509.2mV    1.127V
639ps     1.032V     508.8mV    1.213V
699ps     1.099V     587.3mV    1.255V
809ps     1.185V     922.3mV    1.316V
938ps     1.254V     1.078V     1.367V
1.648ns   1.404V     1.323V     1.491V
10ns      1.497V     1.427V     1.577V
[Falling Waveform]
R_fixture= 50.000
V_fixture= 1.500
V_fixture_min= 1.430
V_fixture_max= 1.580
|time   V(typ)   V(min)   V(max)
0s        1.5V       1.43V      1.58V
809ps     1.493V     1.43V      1.574V
1.319ns   1.417V     1.377V     1.506V
1.871ns   1.277V     1.249V     1.379V
3.459ns   801.8mV    781.7mV    941mV
3.914ns   707mV      691.4mV    835.8mV
4.469ns   633.8mV    621.6mV    739.8mV
5.16ns    584mV      574.2mV    670.7mV
6.055ns   551.2mV    543.9mV    632.6mV
10ns      520.9mV    515.3mV    608.7mV
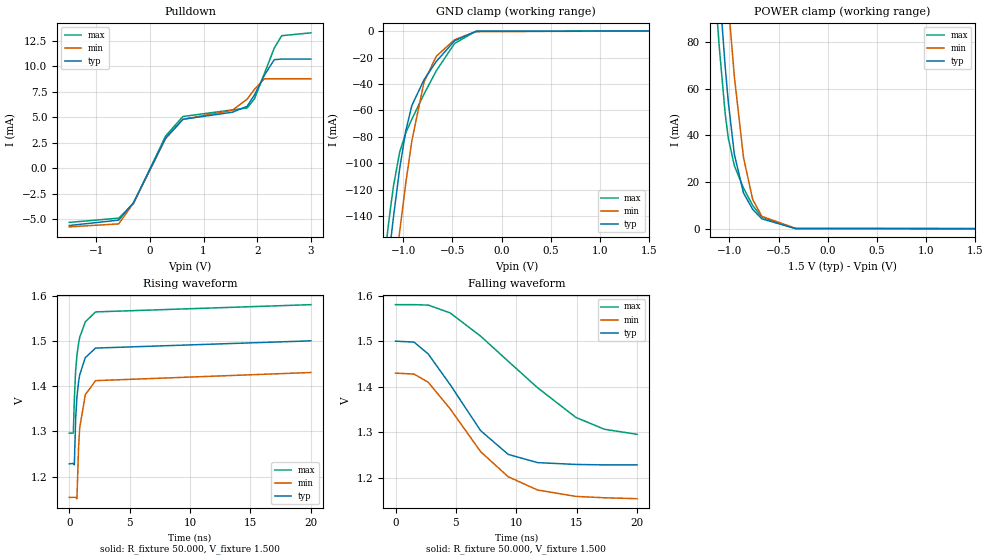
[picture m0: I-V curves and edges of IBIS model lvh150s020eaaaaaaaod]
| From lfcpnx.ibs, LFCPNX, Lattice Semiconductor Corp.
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|Model lvh150s020eaaaaaaaod
[Model] lvh150s020eaaaaaaaod
Model_type I/O_open_drain
Polarity   Non-Inverting
Enable   Active-Low
Vinl =  0.375V
Vinh =  1.125V
Vmeas =  0.750V
Cref =  0.0F
Rref = 10.00k
Vref = 1.50V
C_comp   5.000pF   4.000pF   5.500pF
[Temperature Range]   25.000   0.125k   -40.000
[Voltage Range]   1.500V   1.430V   1.580V
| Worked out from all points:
|   slope of the pulldown table from 0 to 0.225 V, typ, clamps not added: 95.9 ohm
|   GND clamp passes 1 mA (typ) near -0.32 V on its own axis
|   POWER clamp passes 1 mA (typ) near -0.52 V on its own axis
|   rising waveform, R_fixture 50.000, V_fixture 1.500: 20-80 % time 569ps typ, 547ps min, 611ps max; typ from 1.23 V to 1.5 V
|   falling waveform, R_fixture 50.000, V_fixture 1.500: 20-80 % time 4.24ns typ, 5.05ns min, 7.29ns max; typ from 1.5 V to 1.23 V
[Pulldown]
|Voltage   I(typ)   I(min)   I(max)
-1.5V     -5.615mA   -5.746mA   -5.309mA
-580mV    -5.087mA   -5.457mA   -4.892mA
-304mV    -3.36mA    -3.421mA   -3.448mA
294mV     2.96mA     2.906mA    3.158mA
616mV     4.793mA    4.787mA    5.07mA
1.536V    5.487mA    5.681mA    5.715mA
1.812V    6.07mA     6.767mA    5.906mA
1.95V     7.189mA    7.736mA    6.813mA
2.134V    9.124mA    8.77mA     9.275mA
2.318V    10.64mA    8.77mA     11.78mA
2.456V    10.7mA     8.77mA     12.99mA
3V        10.7mA     8.77mA     13.27mA
[GND_clamp]
|Voltage   I(typ)   I(min)   I(max)
-1.5V     -437.2mA   -482.7mA   -410.9mA
-1.159V   -180.5mA   -233.5mA   -152.3mA
-1.128V   -159.7mA   -212.2mA   -133.5mA
-1.097V   -139.8mA   -191.4mA   -116.7mA
-1.035V   -103.9mA   -151.5mA   -91.38mA
-973mV    -75.39mA   -114.8mA   -76.89mA
-911mV    -56.18mA   -82.75mA   -66.55mA
-787mV    -36.73mA   -38.35mA   -47.52mA
-663mV    -23mA      -19.04mA   -30.03mA
-477mV    -7.329mA   -6.536mA   -9.337mA
-260mV    -229.5uA   -443.2uA   -149.9uA
1.5V      0A         0A         0A
[POWER_clamp]
|Voltage   I(typ)   I(min)   I(max)
-1.5V     391.1mA    429.4mA    369.4mA
-1.166V   144.3mA    192mA      116.6mA
-1.135V   123.8mA    171.6mA    96.78mA
-1.104V   104.3mA    151.7mA    78.55mA
-1.042V   69.26mA    114mA      49.08mA
-1.011V   54.4mA     96.46mA    38.87mA
-949mV    31.75mA    65.09mA    26.88mA
-856mV    15.25mA    30.42mA    17.36mA
-763mV    8.28mA     12.5mA     9.924mA
-670mV    4.203mA    5.276mA    5.014mA
-329mV    38.1uA     141.4uA    15.51uA
1.5V      0A         0A         19.34nA
[Ramp]
| variable   typ   min   max
dV/dt_r   0.163/0.574n   0.165/0.548n   0.170/0.619n
dV/dt_f   0.163/4.251n   0.165/5.058n   0.167/7.303n
R_load = 50.000
[Rising Waveform]
R_fixture= 50.000
V_fixture= 1.500
V_fixture_min= 1.430
V_fixture_max= 1.580
|time   V(typ)   V(min)   V(max)
0s        1.228V     1.154V     1.296V
334ps     1.229V     1.154V     1.296V
420ps     1.226V     1.154V     1.371V
527ps     1.328V     1.154V     1.434V
634ps     1.376V     1.151V     1.468V
767ps     1.409V     1.263V     1.494V
864ps     1.425V     1.308V     1.508V
1.328ns   1.463V     1.381V     1.542V
2.177ns   1.484V     1.412V     1.564V
20ns      1.5V       1.43V      1.58V
[Falling Waveform]
R_fixture = 50.000
V_fixture = 1.500
V_fixture_min = 1.430
V_fixture_max = 1.580
|  time   V(typ)   V(min)   V(max)
0s        1.5V       1.43V      1.58V
1.527ns   1.498V     1.428V     1.58V
2.71ns    1.472V     1.41V      1.579V
4.518ns   1.405V     1.352V     1.562V
7.046ns   1.304V     1.258V     1.511V
9.329ns   1.252V     1.203V     1.456V
11.76ns   1.234V     1.174V     1.398V
14.93ns   1.23V      1.16V      1.333V
17.3ns    1.229V     1.157V     1.307V
20ns      1.229V     1.155V     1.296V
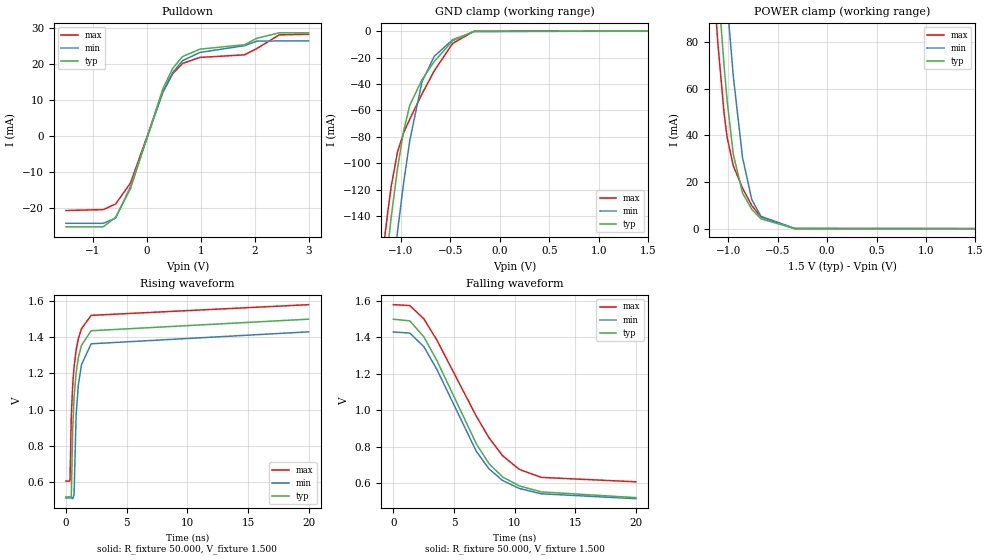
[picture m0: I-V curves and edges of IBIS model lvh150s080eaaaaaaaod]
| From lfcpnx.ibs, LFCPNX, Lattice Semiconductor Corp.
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|Model lvh150s080eaaaaaaaod
[Model] lvh150s080eaaaaaaaod
Model_type I/O_open_drain
Polarity   Non-Inverting
Enable   Active-Low
Vinl =  0.375V
Vinh =  1.125V
Vmeas =  0.750V
Cref =  0.0F
Rref = 10.00k
Vref = 1.50V
C_comp   5.000pF   4.000pF   5.500pF
[Temperature Range]   25.000   0.125k   -40.000
[Voltage Range]   1.500V   1.430V   1.580V
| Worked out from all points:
|   slope of the pulldown table from 0 to 0.225 V, typ, clamps not added: 21.9 ohm
|   GND clamp passes 1 mA (typ) near -0.32 V on its own axis
|   POWER clamp passes 1 mA (typ) near -0.52 V on its own axis
|   rising waveform, R_fixture 50.000, V_fixture 1.500: 20-80 % time 566ps typ, 542ps min, 609ps max; typ from 0.518 V to 1.5 V
|   falling waveform, R_fixture 50.000, V_fixture 1.500: 20-80 % time 4.42ns typ, 4.22ns min, 4.78ns max; typ from 1.5 V to 0.52 V
[Pulldown]
|Voltage   I(typ)   I(min)   I(max)
-1.5V     -25.24mA   -24.26mA   -20.7mA
-810mV    -25.24mA   -24.26mA   -20.45mA
-580mV    -22.61mA   -22.84mA   -18.9mA
-304mV    -14.66mA   -14.09mA   -13.09mA
294mV     12.99mA    12.14mA    12.01mA
478mV     18.73mA    17.59mA    17.25mA
662mV     22.05mA    20.92mA    20.15mA
984mV     24.12mA    23.2mA     21.82mA
1.812V    25.35mA    25.08mA    22.54mA
2.042V    27.14mA    26.35mA    24.32mA
2.456V    28.65mA    26.39mA    28.09mA
3V        28.65mA    26.39mA    28.25mA
[GND_clamp]
|Voltage   I(typ)   I(min)   I(max)
-1.5V     -437.2mA   -482.7mA   -410.9mA
-1.159V   -180.5mA   -233.5mA   -152.3mA
-1.128V   -159.7mA   -212.2mA   -133.5mA
-1.097V   -139.8mA   -191.4mA   -116.7mA
-1.035V   -103.9mA   -151.5mA   -91.38mA
-973mV    -75.39mA   -114.8mA   -76.89mA
-911mV    -56.18mA   -82.75mA   -66.55mA
-787mV    -36.73mA   -38.35mA   -47.52mA
-663mV    -23mA      -19.04mA   -30.03mA
-477mV    -7.329mA   -6.536mA   -9.337mA
-260mV    -229.5uA   -443.2uA   -149.9uA
1.5V      0A         0A         0A
[POWER_clamp]
|Voltage   I(typ)   I(min)   I(max)
-1.5V     391.1mA    429.4mA    369.4mA
-1.166V   144.3mA    192mA      116.6mA
-1.135V   123.8mA    171.6mA    96.78mA
-1.104V   104.3mA    151.7mA    78.55mA
-1.042V   69.26mA    114mA      49.08mA
-1.011V   54.4mA     96.46mA    38.87mA
-949mV    31.75mA    65.09mA    26.88mA
-856mV    15.25mA    30.42mA    17.36mA
-763mV    8.28mA     12.5mA     9.924mA
-670mV    4.203mA    5.276mA    5.014mA
-329mV    38.1uA     141.4uA    15.51uA
1.5V      0A         0A         19.34nA
[Ramp]
| variable   typ   min   max
dV/dt_r   0.589/0.575n   0.550/0.543n   0.584/0.606n
dV/dt_f   0.588/4.428n   0.550/4.230n   0.584/4.795n
R_load = 50.000
[Rising Waveform]
R_fixture= 50.000
V_fixture= 1.500
V_fixture_min= 1.430
V_fixture_max= 1.580
|time   V(typ)   V(min)   V(max)
0s        517.8mV    512mV      605.7mV
332ps     518.2mV    512mV      604.9mV
441ps     521.1mV    512.3mV    963.6mV
558ps     893.4mV    508mV      1.138V
668ps     1.066V     529.3mV    1.234V
839ps     1.203V     970.8mV    1.329V
1.019ns   1.286V     1.135V     1.391V
1.278ns   1.354V     1.247V     1.446V
2.078ns   1.435V     1.363V     1.52V
20ns      1.499V     1.429V     1.579V
[Falling Waveform]
R_fixture= 50.000
V_fixture= 1.500
V_fixture_min= 1.430
V_fixture_max= 1.580
|time   V(typ)   V(min)   V(max)
0s        1.5V       1.43V      1.58V
1.361ns   1.491V     1.424V     1.575V
2.52ns    1.403V     1.349V     1.502V
3.601ns   1.272V     1.223V     1.384V
6.841ns   815.8mV    774.4mV    967.4mV
7.887ns   706.5mV    678mV      848.8mV
9.015ns   633mV      613.9mV    749.6mV
10.4ns    583.9mV    570.1mV    674.4mV
12.21ns   551.4mV    541mV      631.1mV
20ns      520mV      514.2mV    606.9mV
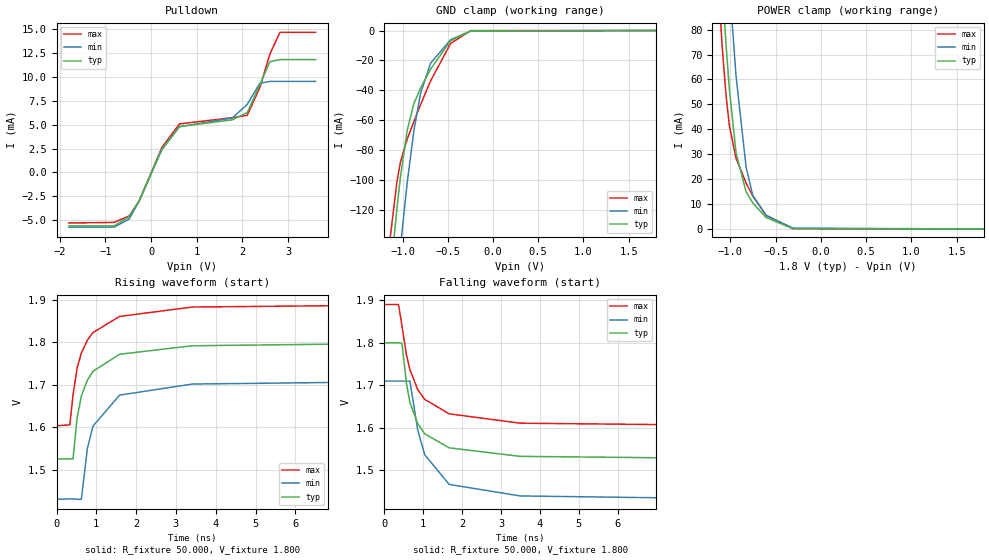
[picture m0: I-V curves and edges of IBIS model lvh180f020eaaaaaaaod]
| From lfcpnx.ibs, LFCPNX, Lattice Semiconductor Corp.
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|Model lvh180f020eaaaaaaaod
[Model] lvh180f020eaaaaaaaod
Model_type I/O_open_drain
Polarity   Non-Inverting
Enable   Active-Low
Vinl =  0.630V
Vinh =  1.170V
Vmeas =  0.900V
Cref =  0.0F
Rref = 10.00k
Vref = 1.80V
C_comp   5.000pF   4.000pF   5.500pF
[Temperature Range]   25.000   0.125k   -40.000
[Voltage Range]   1.800V   1.710V   1.890V
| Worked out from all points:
|   slope of the pulldown table from 0 to 0.27 V, typ, clamps not added: 98.1 ohm
|   GND clamp passes 1 mA (typ) near -0.32 V on its own axis
|   POWER clamp passes 1 mA (typ) near -0.43 V on its own axis
|   rising waveform, R_fixture 50.000, V_fixture 1.800: 20-80 % time 563ps typ, 540ps min, 606ps max; typ from 1.53 V to 1.8 V
|   falling waveform, R_fixture 50.000, V_fixture 1.800: 20-80 % time 567ps typ, 602ps min, 628ps max; typ from 1.8 V to 1.53 V
[Pulldown]
|Voltage   I(typ)   I(min)   I(max)
-1.8V     -5.618mA   -5.75mA    -5.31mA
-810mV    -5.618mA   -5.75mA    -5.255mA
-480mV    -4.649mA   -4.903mA   -4.571mA
-260mV    -2.928mA   -2.986mA   -3.027mA
235mV     2.438mA    2.374mA    2.602mA
620mV     4.802mA    4.782mA    5.082mA
1.775V    5.508mA    5.697mA    5.735mA
2.105V    6.268mA    7.133mA    5.986mA
2.38V     9.179mA    9.341mA    8.89mA
2.6V      11.62mA    9.54mA     12.42mA
2.82V     11.83mA    9.54mA     14.69mA
3.6V      11.83mA    9.54mA     14.69mA
[GND_clamp]
|Voltage   I(typ)   I(min)   I(max)
-1.8V     -676.7mA   -712.1mA   -657.6mA
-1.171V   -189mA     -242mA     -160.2mA
-1.134V   -163.8mA   -216.5mA   -137.1mA
-1.06V    -117.7mA   -167.5mA   -100.2mA
-1.023V   -97.81mA   -144.4mA   -87.91mA
-949mV    -66.9mA    -102mA     -72.72mA
-875mV    -48.92mA   -67.07mA   -60.9mA
-801mV    -38.44mA   -42.02mA   -49.6mA
-690mV    -25.81mA   -21.85mA   -33.66mA
-468mV    -6.772mA   -6.113mA   -8.592mA
-246mV    -147uA     -341.6uA   -82.49uA
1.8V      0A         0A         0A
[POWER_clamp]
|Voltage   I(typ)   I(min)   I(max)
-1.8V     627.5mA    654.7mA    613.8mA
-1.16V    141.1mA    188.7mA    113.9mA
-1.123V   117.1mA    164.5mA    90.87mA
-1.086V   94.57mA    141.2mA    70.51mA
-1.049V   74.05mA    118.9mA    53.75mA
-1.012V   56.15mA    97.91mA    41.41mA
-938mV    30.5mA     61.25mA    28.31mA
-827mV    14.89mA    24.78mA    18.4mA
-753mV    10.44mA    13.47mA    13.13mA
-605mV    4.561mA    5.42mA     5.44mA
-309mV    119.4uA    340.4uA    111.1uA
1.8V      0A         0A         16.69nA
[Ramp]
| variable   typ   min   max
dV/dt_r   0.164/0.569n   0.167/0.545n   0.171/0.616n
dV/dt_f   0.164/0.567n   0.167/0.604n   0.171/0.634n
R_load = 50.000
[Rising Waveform]
R_fixture= 50.000
V_fixture= 1.800
V_fixture_min= 1.710
V_fixture_max= 1.890
|time   V(typ)   V(min)   V(max)
0s        1.526V     1.431V     1.604V
334ps     1.526V     1.432V     1.606V
414ps     1.526V     1.432V     1.676V
517ps     1.622V     1.431V     1.74V
624ps     1.674V     1.431V     1.775V
774ps     1.711V     1.55V      1.805V
915ps     1.732V     1.603V     1.823V
1.585ns   1.772V     1.676V     1.861V
3.409ns   1.792V     1.702V     1.883V
10ns      1.799V     1.709V     1.889V
[Falling Waveform]
R_fixture= 50.000
V_fixture= 1.800
V_fixture_min= 1.710
V_fixture_max= 1.890
|time   V(typ)   V(min)   V(max)
0s        1.8V       1.71V      1.89V
362ps     1.8V       1.71V      1.89V
450ps     1.799V     1.71V      1.84V
567ps     1.704V     1.71V      1.771V
655ps     1.66V      1.71V      1.737V
855ps     1.61V      1.595V     1.69V
1.035ns   1.586V     1.537V     1.667V
1.665ns   1.553V     1.467V     1.633V
3.489ns   1.533V     1.44V      1.611V
10ns      1.527V     1.432V     1.605V
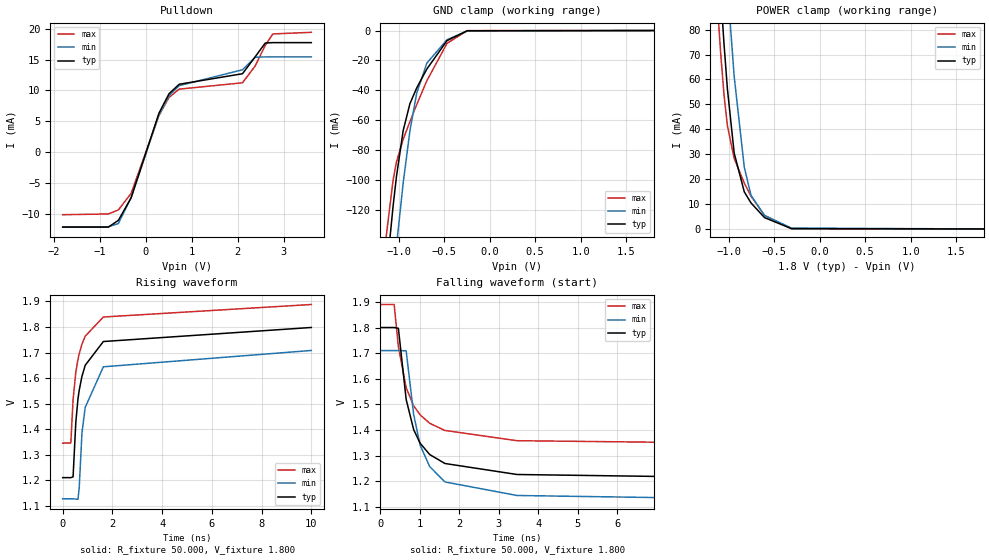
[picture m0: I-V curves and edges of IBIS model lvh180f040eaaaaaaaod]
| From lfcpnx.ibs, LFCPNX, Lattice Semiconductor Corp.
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|Model lvh180f040eaaaaaaaod
[Model] lvh180f040eaaaaaaaod
Model_type I/O_open_drain
Polarity   Non-Inverting
Enable   Active-Low
Vinl =  0.630V
Vinh =  1.170V
Vmeas =  0.900V
Cref =  0.0F
Rref = 10.00k
Vref = 1.80V
C_comp   5.000pF   4.000pF   5.500pF
[Temperature Range]   25.000   0.125k   -40.000
[Voltage Range]   1.800V   1.710V   1.890V
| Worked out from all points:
|   slope of the pulldown table from 0 to 0.27 V, typ, clamps not added: 45.6 ohm
|   GND clamp passes 1 mA (typ) near -0.32 V on its own axis
|   POWER clamp passes 1 mA (typ) near -0.43 V on its own axis
|   rising waveform, R_fixture 50.000, V_fixture 1.800: 20-80 % time 562ps typ, 540ps min, 606ps max; typ from 1.21 V to 1.8 V
|   falling waveform, R_fixture 50.000, V_fixture 1.800: 20-80 % time 562ps typ, 556ps min, 607ps max; typ from 1.8 V to 1.21 V
[Pulldown]
|Voltage   I(typ)   I(min)   I(max)
-1.8V     -12.19mA   -12.13mA   -10.17mA
-810mV    -12.19mA   -12.13mA   -10.05mA
-590mV    -11.08mA   -11.59mA   -9.387mA
-315mV    -7.449mA   -7.397mA   -6.726mA
290mV     6.299mA    6.027mA    5.926mA
510mV     9.472mA    9.154mA    8.87mA
730mV     11mA       10.78mA    10.21mA
2.105V    12.71mA    13.35mA    11.24mA
2.38V     15.45mA    15.39mA    13.97mA
2.6V      17.7mA     15.44mA    17.33mA
2.765V    17.76mA    15.44mA    19.17mA
3.6V      17.76mA    15.44mA    19.43mA
[GND_clamp]
|Voltage   I(typ)   I(min)   I(max)
-1.8V     -676.7mA   -712.1mA   -657.6mA
-1.171V   -189mA     -242mA     -160.2mA
-1.134V   -163.8mA   -216.5mA   -137.1mA
-1.06V    -117.7mA   -167.5mA   -100.2mA
-1.023V   -97.81mA   -144.4mA   -87.91mA
-949mV    -66.9mA    -102mA     -72.72mA
-875mV    -48.92mA   -67.07mA   -60.9mA
-801mV    -38.44mA   -42.02mA   -49.6mA
-690mV    -25.81mA   -21.85mA   -33.66mA
-468mV    -6.772mA   -6.113mA   -8.592mA
-246mV    -147uA     -341.6uA   -82.49uA
1.8V      0A         0A         0A
[POWER_clamp]
|Voltage   I(typ)   I(min)   I(max)
-1.8V     627.5mA    654.7mA    613.8mA
-1.16V    141.1mA    188.7mA    113.9mA
-1.123V   117.1mA    164.5mA    90.87mA
-1.086V   94.57mA    141.2mA    70.51mA
-1.049V   74.05mA    118.9mA    53.75mA
-1.012V   56.15mA    97.91mA    41.41mA
-938mV    30.5mA     61.25mA    28.31mA
-827mV    14.89mA    24.78mA    18.4mA
-753mV    10.44mA    13.47mA    13.13mA
-605mV    4.561mA    5.42mA     5.44mA
-309mV    119.4uA    340.4uA    111.1uA
1.8V      0A         0A         16.69nA
[Ramp]
| variable   typ   min   max
dV/dt_r   0.353/0.575n   0.348/0.546n   0.326/0.608n
dV/dt_f   0.353/0.559n   0.348/0.554n   0.326/0.605n
R_load = 50.000
[Rising Waveform]
R_fixture= 50.000
V_fixture= 1.800
V_fixture_min= 1.710
V_fixture_max= 1.890
|time   V(typ)   V(min)   V(max)
0s        1.21V      1.127V     1.345V
327ps     1.21V      1.127V     1.346V
417ps     1.213V     1.127V     1.515V
527ps     1.427V     1.126V     1.623V
614ps     1.518V     1.125V     1.673V
664ps     1.552V     1.17V      1.695V
775ps     1.607V     1.386V     1.733V
905ps     1.65V      1.485V     1.764V
1.635ns   1.743V     1.644V     1.839V
10ns      1.798V     1.708V     1.888V
[Falling Waveform]
R_fixture= 50.000
V_fixture= 1.800
V_fixture_min= 1.710
V_fixture_max= 1.890
|time   V(typ)   V(min)   V(max)
0s        1.8V       1.71V      1.89V
351ps     1.8V       1.71V      1.89V
458ps     1.797V     1.71V      1.725V
655ps     1.519V     1.709V     1.565V
845ps     1.401V     1.46V      1.494V
1.009ns   1.348V     1.34V      1.459V
1.25ns    1.304V     1.257V     1.426V
1.635ns   1.269V     1.197V     1.398V
3.459ns   1.226V     1.144V     1.358V
10ns      1.212V     1.129V     1.347V
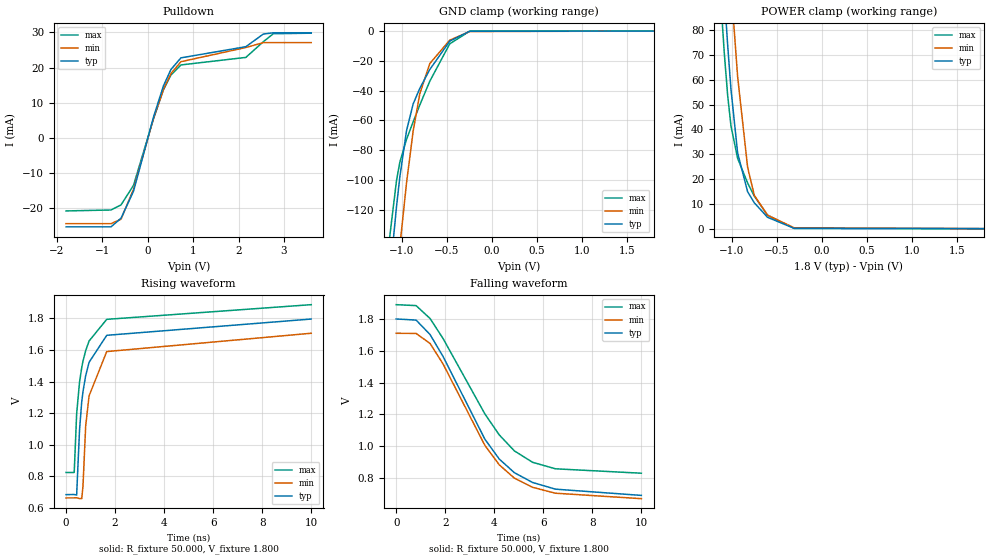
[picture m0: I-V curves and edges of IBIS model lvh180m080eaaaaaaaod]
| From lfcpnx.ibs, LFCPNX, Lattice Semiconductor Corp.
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|Model lvh180m080eaaaaaaaod
[Model] lvh180m080eaaaaaaaod
Model_type I/O_open_drain
Polarity   Non-Inverting
Enable   Active-Low
Vinl =  0.630V
Vinh =  1.170V
Vmeas =  0.900V
Cref =  0.0F
Rref = 10.00k
Vref = 1.80V
C_comp   5.000pF   4.000pF   5.500pF
[Temperature Range]   25.000   0.125k   -40.000
[Voltage Range]   1.800V   1.710V   1.890V
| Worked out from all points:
|   slope of the pulldown table from 0 to 0.27 V, typ, clamps not added: 22.4 ohm
|   GND clamp passes 1 mA (typ) near -0.32 V on its own axis
|   POWER clamp passes 1 mA (typ) near -0.43 V on its own axis
|   rising waveform, R_fixture 50.000, V_fixture 1.800: 20-80 % time 560ps typ, 542ps min, 603ps max; typ from 0.685 V to 1.8 V
|   falling waveform, R_fixture 50.000, V_fixture 1.800: 20-80 % time 2.38ns typ, 2.27ns min, 2.45ns max; typ from 1.8 V to 0.69 V
[Pulldown]
|Voltage   I(typ)   I(min)   I(max)
-1.8V     -25.24mA   -24.33mA   -20.72mA
-810mV    -25.24mA   -24.33mA   -20.45mA
-590mV    -22.79mA   -23.07mA   -19.01mA
-315mV    -15.13mA   -14.57mA   -13.46mA
125mV     5.915mA    5.512mA    5.455mA
345mV     14.82mA    13.83mA    13.7mA
510mV     19.47mA    18.3mA     17.91mA
730mV     22.76mA    21.67mA    20.75mA
2.16V     25.93mA    25.7mA     22.89mA
2.545V    29.53mA    27.09mA    27.35mA
2.765V    29.87mA    27.09mA    29.62mA
3.6V      29.87mA    27.09mA    29.77mA
[GND_clamp]
|Voltage   I(typ)   I(min)   I(max)
-1.8V     -676.7mA   -712.1mA   -657.6mA
-1.171V   -189mA     -242mA     -160.2mA
-1.134V   -163.8mA   -216.5mA   -137.1mA
-1.06V    -117.7mA   -167.5mA   -100.2mA
-1.023V   -97.81mA   -144.4mA   -87.91mA
-949mV    -66.9mA    -102mA     -72.72mA
-875mV    -48.92mA   -67.07mA   -60.9mA
-801mV    -38.44mA   -42.02mA   -49.6mA
-690mV    -25.81mA   -21.85mA   -33.66mA
-468mV    -6.772mA   -6.113mA   -8.592mA
-246mV    -147uA     -341.6uA   -82.49uA
1.8V      0A         0A         0A
[POWER_clamp]
|Voltage   I(typ)   I(min)   I(max)
-1.8V     627.5mA    654.7mA    613.8mA
-1.16V    141.1mA    188.7mA    113.9mA
-1.123V   117.1mA    164.5mA    90.87mA
-1.086V   94.57mA    141.2mA    70.51mA
-1.049V   74.05mA    118.9mA    53.75mA
-1.012V   56.15mA    97.91mA    41.41mA
-938mV    30.5mA     61.25mA    28.31mA
-827mV    14.89mA    24.78mA    18.4mA
-753mV    10.44mA    13.47mA    13.13mA
-605mV    4.561mA    5.42mA     5.44mA
-309mV    119.4uA    340.4uA    111.1uA
1.8V      0A         0A         16.69nA
[Ramp]
| variable   typ   min   max
dV/dt_r   0.667/0.570n   0.626/0.539n   0.637/0.600n
dV/dt_f   0.666/2.461n   0.624/2.367n   0.636/2.552n
R_load = 50.000
[Rising Waveform]
R_fixture= 50.000
V_fixture= 1.800
V_fixture_min= 1.710
V_fixture_max= 1.890
|time   V(typ)   V(min)   V(max)
0s        684.6mV    663.7mV    824.7mV
332ps     685mV      663.8mV    824.7mV
431ps     681.2mV    664.2mV    1.196V
548ps     1.093V     659.5mV    1.396V
638ps     1.271V     658.7mV    1.488V
689ps     1.336V     736.2mV    1.529V
799ps     1.437V     1.118V     1.596V
938ps     1.522V     1.31V      1.657V
1.658ns   1.693V     1.59V      1.794V
10ns      1.796V     1.706V     1.887V
[Falling Waveform]
R_fixture= 50.000
V_fixture= 1.800
V_fixture_min= 1.710
V_fixture_max= 1.890
|time   V(typ)   V(min)   V(max)
0s        1.8V       1.71V      1.89V
811ps     1.793V     1.709V     1.884V
1.381ns   1.702V     1.646V     1.803V
1.911ns   1.564V     1.517V     1.677V
3.616ns   1.044V     1.005V     1.203V
4.201ns   919.3mV    882.8mV    1.071V
4.82ns    833mV      798.9mV    970.2mV
5.563ns   771.5mV    740.9mV    898.4mV
6.495ns   729.4mV    703.9mV    857.4mV
10ns      690.1mV    669.5mV    829.7mV
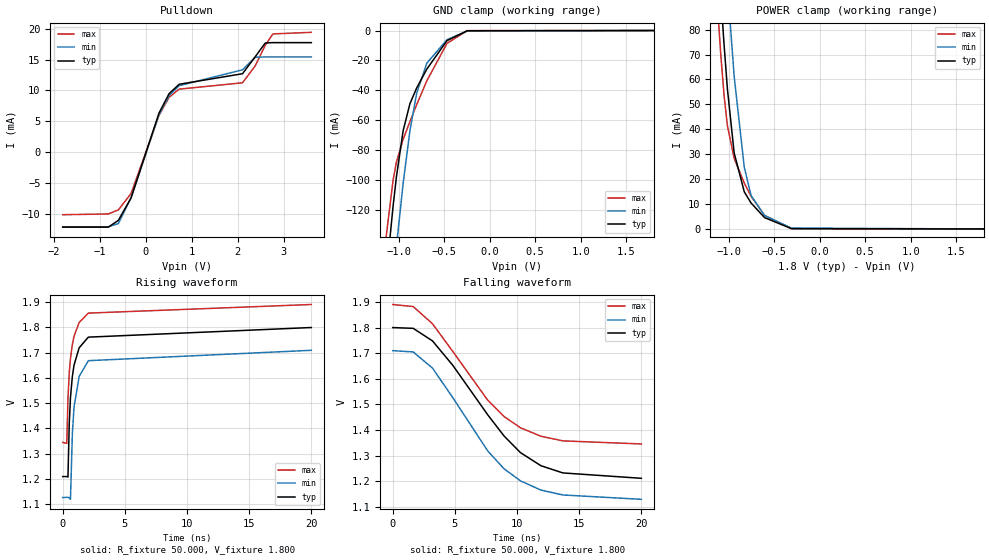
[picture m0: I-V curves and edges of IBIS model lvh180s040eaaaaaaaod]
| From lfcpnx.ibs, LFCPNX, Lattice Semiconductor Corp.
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|Model lvh180s040eaaaaaaaod
[Model] lvh180s040eaaaaaaaod
Model_type I/O_open_drain
Polarity   Non-Inverting
Enable   Active-Low
Vinl =  0.630V
Vinh =  1.170V
Vmeas =  0.900V
Cref =  0.0F
Rref = 10.00k
Vref = 1.80V
C_comp   5.000pF   4.000pF   5.500pF
[Temperature Range]   25.000   0.125k   -40.000
[Voltage Range]   1.800V   1.710V   1.890V
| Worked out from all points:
|   slope of the pulldown table from 0 to 0.27 V, typ, clamps not added: 45.6 ohm
|   GND clamp passes 1 mA (typ) near -0.32 V on its own axis
|   POWER clamp passes 1 mA (typ) near -0.43 V on its own axis
|   rising waveform, R_fixture 50.000, V_fixture 1.800: 20-80 % time 568ps typ, 547ps min, 613ps max; typ from 1.21 V to 1.8 V
|   falling waveform, R_fixture 50.000, V_fixture 1.800: 20-80 % time 5.5ns typ, 5.11ns min, 5.18ns max; typ from 1.8 V to 1.21 V
[Pulldown]
|Voltage   I(typ)   I(min)   I(max)
-1.8V     -12.19mA   -12.13mA   -10.17mA
-810mV    -12.19mA   -12.13mA   -10.05mA
-590mV    -11.08mA   -11.59mA   -9.387mA
-315mV    -7.449mA   -7.396mA   -6.726mA
290mV     6.299mA    6.027mA    5.926mA
510mV     9.472mA    9.153mA    8.87mA
730mV     11mA       10.77mA    10.21mA
2.105V    12.71mA    13.35mA    11.24mA
2.38V     15.45mA    15.39mA    13.97mA
2.6V      17.7mA     15.44mA    17.33mA
2.765V    17.76mA    15.44mA    19.17mA
3.6V      17.76mA    15.44mA    19.43mA
[GND_clamp]
|Voltage   I(typ)   I(min)   I(max)
-1.8V     -676.7mA   -712.1mA   -657.6mA
-1.171V   -189mA     -242mA     -160.2mA
-1.134V   -163.8mA   -216.5mA   -137.1mA
-1.06V    -117.7mA   -167.5mA   -100.2mA
-1.023V   -97.81mA   -144.4mA   -87.91mA
-949mV    -66.9mA    -102mA     -72.72mA
-875mV    -48.92mA   -67.07mA   -60.9mA
-801mV    -38.44mA   -42.02mA   -49.6mA
-690mV    -25.81mA   -21.85mA   -33.66mA
-468mV    -6.772mA   -6.113mA   -8.592mA
-246mV    -147uA     -341.6uA   -82.49uA
1.8V      0A         0A         0A
[POWER_clamp]
|Voltage   I(typ)   I(min)   I(max)
-1.8V     627.5mA    654.7mA    613.8mA
-1.16V    141.1mA    188.7mA    113.9mA
-1.123V   117.1mA    164.5mA    90.87mA
-1.086V   94.57mA    141.2mA    70.51mA
-1.049V   74.05mA    118.9mA    53.75mA
-1.012V   56.15mA    97.91mA    41.41mA
-938mV    30.5mA     61.25mA    28.31mA
-827mV    14.89mA    24.78mA    18.4mA
-753mV    10.44mA    13.47mA    13.13mA
-605mV    4.561mA    5.42mA     5.44mA
-309mV    119.4uA    340.4uA    111.1uA
1.8V      0A         0A         16.69nA
[Ramp]
| variable   typ   min   max
dV/dt_r   0.354/0.580n   0.349/0.553n   0.327/0.616n
dV/dt_f   0.353/5.548n   0.348/5.120n   0.326/5.194n
R_load = 50.000
[Rising Waveform]
R_fixture= 50.000
V_fixture= 1.800
V_fixture_min= 1.710
V_fixture_max= 1.890
|time   V(typ)   V(min)   V(max)
0s        1.21V      1.127V     1.345V
327ps     1.21V      1.128V     1.341V
421ps     1.208V     1.128V     1.516V
528ps     1.422V     1.126V     1.622V
625ps     1.523V     1.12V      1.677V
777ps     1.606V     1.381V     1.732V
914ps     1.651V     1.486V     1.765V
1.324ns   1.719V     1.606V     1.819V
2.064ns   1.761V     1.668V     1.856V
20ns      1.799V     1.709V     1.89V
[Falling Waveform]
R_fixture= 50.000
V_fixture= 1.800
V_fixture_min= 1.710
V_fixture_max= 1.890
|time   V(typ)   V(min)   V(max)
0s        1.8V       1.71V      1.89V
1.647ns   1.797V     1.705V     1.882V
3.199ns   1.748V     1.642V     1.815V
4.83ns    1.653V     1.527V     1.707V
7.64ns    1.46V      1.319V     1.517V
8.959ns   1.377V     1.249V     1.453V
10.28ns   1.312V     1.202V     1.409V
11.93ns   1.261V     1.166V     1.376V
13.69ns   1.233V     1.147V     1.358V
20ns      1.212V     1.13V      1.346V
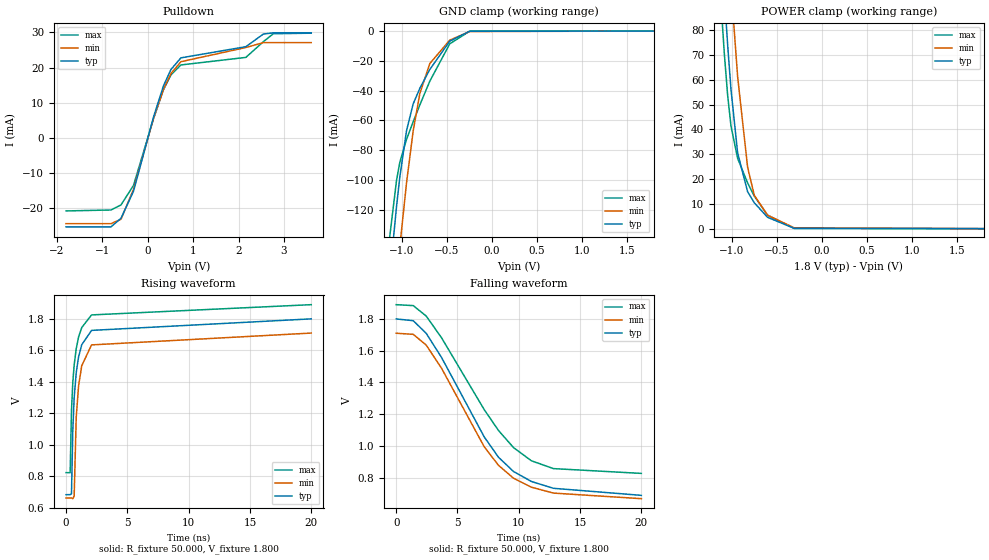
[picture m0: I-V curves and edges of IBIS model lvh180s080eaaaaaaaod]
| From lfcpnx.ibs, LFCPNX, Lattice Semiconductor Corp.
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|Model lvh180s080eaaaaaaaod
[Model] lvh180s080eaaaaaaaod
Model_type I/O_open_drain
Polarity   Non-Inverting
Enable   Active-Low
Vinl =  0.630V
Vinh =  1.170V
Vmeas =  0.900V
Cref =  0.0F
Rref = 10.00k
Vref = 1.80V
C_comp   5.000pF   4.000pF   5.500pF
[Temperature Range]   25.000   0.125k   -40.000
[Voltage Range]   1.800V   1.710V   1.890V
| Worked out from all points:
|   slope of the pulldown table from 0 to 0.27 V, typ, clamps not added: 22.4 ohm
|   GND clamp passes 1 mA (typ) near -0.32 V on its own axis
|   POWER clamp passes 1 mA (typ) near -0.43 V on its own axis
|   rising waveform, R_fixture 50.000, V_fixture 1.800: 20-80 % time 566ps typ, 547ps min, 609ps max; typ from 0.685 V to 1.8 V
|   falling waveform, R_fixture 50.000, V_fixture 1.800: 20-80 % time 5ns typ, 4.76ns min, 5.23ns max; typ from 1.8 V to 0.689 V
[Pulldown]
|Voltage   I(typ)   I(min)   I(max)
-1.8V     -25.24mA   -24.33mA   -20.72mA
-810mV    -25.24mA   -24.33mA   -20.45mA
-590mV    -22.79mA   -23.07mA   -19.01mA
-315mV    -15.13mA   -14.57mA   -13.46mA
125mV     5.915mA    5.512mA    5.455mA
345mV     14.82mA    13.83mA    13.7mA
510mV     19.47mA    18.3mA     17.91mA
730mV     22.76mA    21.67mA    20.75mA
2.16V     25.93mA    25.7mA     22.89mA
2.545V    29.52mA    27.09mA    27.35mA
2.765V    29.87mA    27.09mA    29.62mA
3.6V      29.87mA    27.09mA    29.77mA
[GND_clamp]
|Voltage   I(typ)   I(min)   I(max)
-1.8V     -676.7mA   -712.1mA   -657.6mA
-1.171V   -189mA     -242mA     -160.2mA
-1.134V   -163.8mA   -216.5mA   -137.1mA
-1.06V    -117.7mA   -167.5mA   -100.2mA
-1.023V   -97.81mA   -144.4mA   -87.91mA
-949mV    -66.9mA    -102mA     -72.72mA
-875mV    -48.92mA   -67.07mA   -60.9mA
-801mV    -38.44mA   -42.02mA   -49.6mA
-690mV    -25.81mA   -21.85mA   -33.66mA
-468mV    -6.772mA   -6.113mA   -8.592mA
-246mV    -147uA     -341.6uA   -82.49uA
1.8V      0A         0A         0A
[POWER_clamp]
|Voltage   I(typ)   I(min)   I(max)
-1.8V     627.5mA    654.7mA    613.8mA
-1.16V    141.1mA    188.7mA    113.9mA
-1.123V   117.1mA    164.5mA    90.87mA
-1.086V   94.57mA    141.2mA    70.51mA
-1.049V   74.05mA    118.9mA    53.75mA
-1.012V   56.15mA    97.91mA    41.41mA
-938mV    30.5mA     61.25mA    28.31mA
-827mV    14.89mA    24.78mA    18.4mA
-753mV    10.44mA    13.47mA    13.13mA
-605mV    4.561mA    5.42mA     5.44mA
-309mV    119.4uA    340.4uA    111.1uA
1.8V      0A         0A         16.69nA
[Ramp]
| variable   typ   min   max
dV/dt_r   0.669/0.575n   0.627/0.547n   0.639/0.608n
dV/dt_f   0.667/5.027n   0.626/4.778n   0.638/5.239n
R_load = 50.000
[Rising Waveform]
R_fixture= 50.000
V_fixture= 1.800
V_fixture_min= 1.710
V_fixture_max= 1.890
|time   V(typ)   V(min)   V(max)
0s        684.6mV    663.7mV    824.7mV
332ps     685.1mV    663.9mV    824mV
441ps     689.9mV    664.3mV    1.22V
548ps     1.092V     659.4mV    1.396V
659ps     1.299V     676.1mV    1.506V
829ps     1.458V     1.176V     1.611V
1.019ns   1.558V     1.374V     1.684V
1.278ns   1.635V     1.502V     1.744V
2.078ns   1.726V     1.634V     1.824V
20ns      1.799V     1.709V     1.889V
[Falling Waveform]
R_fixture= 50.000
V_fixture= 1.800
V_fixture_min= 1.710
V_fixture_max= 1.890
|time   V(typ)   V(min)   V(max)
0s        1.8V       1.71V      1.89V
1.389ns   1.789V     1.703V     1.884V
2.451ns   1.709V     1.635V     1.818V
3.701ns   1.557V     1.489V     1.681V
7.185ns   1.056V     994mV      1.228V
8.347ns   928.4mV    877.5mV    1.097V
9.575ns   838.5mV    796.2mV    989.1mV
11.03ns   775.9mV    739.7mV    906.2mV
12.83ns   732.9mV    702.7mV    857mV
20ns      688.5mV    667.5mV    826.8mV
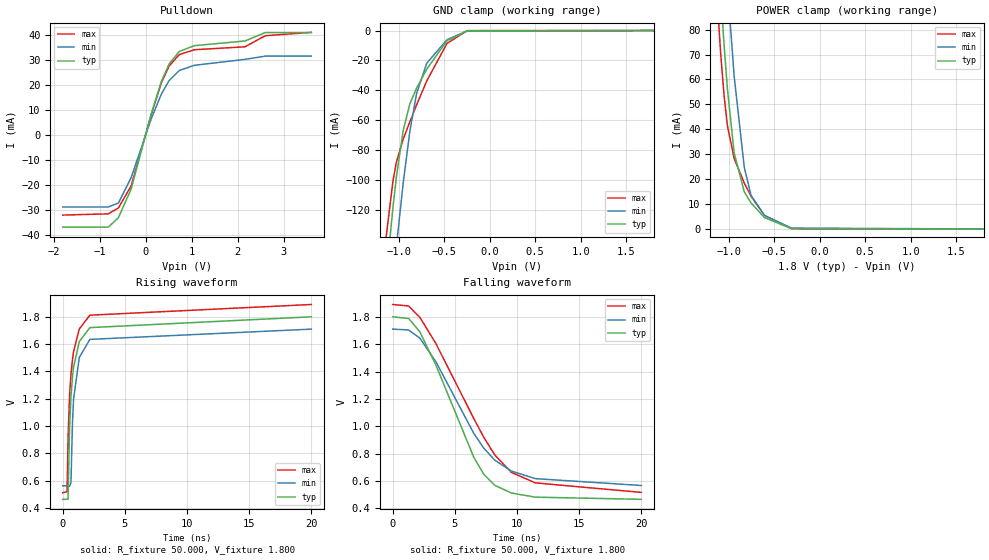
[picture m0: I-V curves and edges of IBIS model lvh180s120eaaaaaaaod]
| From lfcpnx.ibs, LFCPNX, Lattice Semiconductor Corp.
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|Model lvh180s120eaaaaaaaod
[Model] lvh180s120eaaaaaaaod
Model_type I/O_open_drain
Polarity   Non-Inverting
Enable   Active-Low
Vinl =  0.630V
Vinh =  1.170V
Vmeas =  0.900V
Cref =  0.0F
Rref = 10.00k
Vref = 1.80V
C_comp   5.000pF   4.000pF   5.500pF
[Temperature Range]   25.000   0.125k   -40.000
[Voltage Range]   1.800V   1.710V   1.890V
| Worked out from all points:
|   slope of the pulldown table from 0 to 0.27 V, typ, clamps not added: 15.5 ohm
|   GND clamp passes 1 mA (typ) near -0.32 V on its own axis
|   POWER clamp passes 1 mA (typ) near -0.43 V on its own axis
|   rising waveform, R_fixture 50.000, V_fixture 1.800: 20-80 % time 565ps typ, 547ps min, 607ps max; typ from 0.466 V to 1.8 V
|   falling waveform, R_fixture 50.000, V_fixture 1.800: 20-80 % time 3.69ns typ, 4.32ns min, 4.79ns max; typ from 1.8 V to 0.466 V
[Pulldown]
|Voltage   I(typ)   I(min)   I(max)
-1.8V     -36.87mA   -28.82mA   -32.04mA
-810mV    -36.87mA   -28.82mA   -31.56mA
-590mV    -33.09mA   -27.25mA   -29.2mA
-315mV    -21.73mA   -17.15mA   -20.43mA
125mV     8.495mA    6.498mA    8.256mA
345mV     21.39mA    16.33mA    20.85mA
510mV     28.26mA    21.64mA    27.44mA
730mV     33.25mA    25.68mA    32mA
1.06V     35.61mA    27.76mA    33.98mA
2.16V     37.47mA    30.13mA    35.15mA
2.6V      40.84mA    31.43mA    39.57mA
3.6V      40.84mA    31.43mA    40.93mA
[GND_clamp]
|Voltage   I(typ)   I(min)   I(max)
-1.8V     -676.7mA   -712.1mA   -657.6mA
-1.171V   -189mA     -242mA     -160.2mA
-1.134V   -163.8mA   -216.5mA   -137.1mA
-1.06V    -117.7mA   -167.5mA   -100.2mA
-1.023V   -97.81mA   -144.4mA   -87.91mA
-949mV    -66.9mA    -102mA     -72.72mA
-875mV    -48.92mA   -67.07mA   -60.9mA
-801mV    -38.44mA   -42.02mA   -49.6mA
-690mV    -25.81mA   -21.85mA   -33.66mA
-468mV    -6.772mA   -6.113mA   -8.592mA
-246mV    -147uA     -341.6uA   -82.49uA
1.8V      0A         0A         0A
[POWER_clamp]
|Voltage   I(typ)   I(min)   I(max)
-1.8V     627.5mA    654.7mA    613.8mA
-1.16V    141.1mA    188.7mA    113.9mA
-1.123V   117.1mA    164.5mA    90.87mA
-1.086V   94.57mA    141.2mA    70.51mA
-1.049V   74.05mA    118.9mA    53.75mA
-1.012V   56.15mA    97.91mA    41.41mA
-938mV    30.5mA     61.25mA    28.31mA
-827mV    14.89mA    24.78mA    18.4mA
-753mV    10.44mA    13.47mA    13.13mA
-605mV    4.561mA    5.42mA     5.44mA
-309mV    119.4uA    340.4uA    111.1uA
1.8V      0A         0A         16.69nA
[Ramp]
| variable   typ   min   max
dV/dt_r   0.800/0.565n   0.687/0.548n   0.825/0.614n
dV/dt_f   0.800/3.715n   0.686/4.333n   0.824/4.806n
R_load = 50.000
[Rising Waveform]
R_fixture= 50.000
V_fixture= 1.800
V_fixture_min= 1.710
V_fixture_max= 1.890
|time   V(typ)   V(min)   V(max)
0s        465.6mV    563.7mV    513.1mV
351ps     465mV      563.7mV    520.4mV
431ps     467.7mV    564.1mV    911.6mV
549ps     975.2mV    559.5mV    1.219V
665ps     1.219V     587.5mV    1.378V
785ps     1.358V     1.025V     1.486V
876ps     1.431V     1.2V       1.546V
1.335ns   1.618V     1.502V     1.71V
2.185ns   1.72V      1.634V     1.811V
20ns      1.799V     1.709V     1.889V
[Falling Waveform]
R_fixture= 50.000
V_fixture= 1.800
V_fixture_min= 1.710
V_fixture_max= 1.890
|time   V(typ)   V(min)   V(max)
0s        1.8V       1.71V      1.89V
1.281ns   1.788V     1.704V     1.879V
2.186ns   1.69V      1.644V     1.796V
3.472ns   1.448V     1.472V     1.605V
6.509ns   776.4mV    950.5mV    1.059V
7.325ns   649.6mV    840.3mV    920.2mV
8.215ns   568.8mV    752.4mV    789.9mV
9.547ns   512.4mV    673.1mV    663.6mV
11.47ns   482.3mV    617.7mV    586.6mV
20ns      466.4mV    567.5mV    517mV
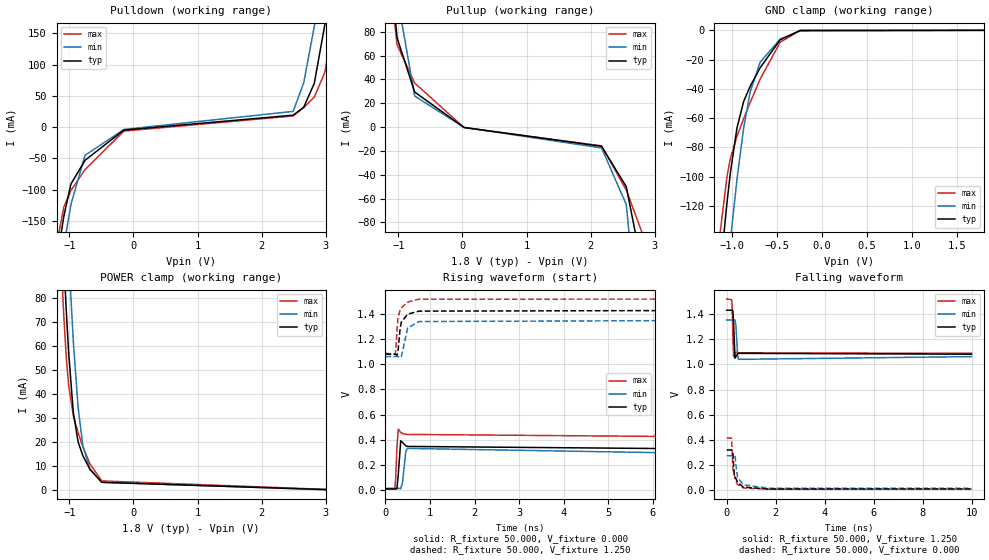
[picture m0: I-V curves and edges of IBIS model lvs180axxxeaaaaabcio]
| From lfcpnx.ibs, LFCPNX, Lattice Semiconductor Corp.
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|Model lvs180axxxeaaaaabcio
[Model] lvs180axxxeaaaaabcio
Model_type I/O
Polarity   Non-Inverting
Enable   Active-Low
Vinl =  1.150V
Vinh =  1.350V
Vmeas =  1.250V
Cref =  3.000pF
Rref =  50.000
Vref =  1.250V
C_comp   5.000pF   4.000pF   5.500pF
[Temperature Range]   25.000   0.125k   -40.000
[Voltage Range]   1.800V   1.710V   1.890V
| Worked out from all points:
|   slope of the pulldown table from 0 to 0.27 V, typ, clamps not added: 142 ohm
|   slope of the pullup table from 0 to 0.27 V, typ, clamps not added: 91.7 ohm
|   GND clamp passes 1 mA (typ) near -0.33 V on its own axis
|   POWER clamp passes 1 mA (typ) near -0.30 V on its own axis
|   rising waveform, R_fixture 50.000, V_fixture 0.000: 20-80 % time 32.3ps typ, 44ps min, 28.4ps max; typ from 0.008 V to 0.319 V
|   rising waveform, R_fixture 50.000, V_fixture 1.250: 20-80 % time 88.9ps typ, 100ps min, 87.7ps max; typ from 1.08 V to 1.43 V
|   falling waveform, R_fixture 50.000, V_fixture 1.250: 20-80 % time 37.5ps typ, 51.3ps min, 31.9ps max; typ from 1.43 V to 1.08 V
|   falling waveform, R_fixture 50.000, V_fixture 0.000: 20-80 % time 155ps typ, 200ps min, 132ps max; typ from 0.319 V to 0.008 V
[Pulldown]
|Voltage   I(typ)   I(min)   I(max)
-1.8V     -681.2mA   -716.3mA   -662.4mA
-1.195V   -212.7mA   -264mA     -185.8mA
-1.085V   -141.9mA   -189.7mA   -127.6mA
-975mV    -90.96mA   -123.8mA   -101.3mA
-755mV    -53.04mA   -45.02mA   -67.87mA
-150mV    -4.68mA    -3.708mA   -6.333mA
2.49V     19.13mA    25.2mA     17.88mA
2.655V    31.84mA    70.95mA    31.23mA
2.82V     70.16mA    161mA      48.03mA
2.985V    164.3mA    271.4mA    87.85mA
3.15V     282.5mA    389.7mA    190.9mA
3.6V      631.9mA    726.6mA    545.1mA
[Pullup]
|Voltage   I(typ)   I(min)   I(max)
-1.8V     633.7mA    660.1mA    620.6mA
-1.35V    284.7mA    326.6mA    260.5mA
-1.24V    204.9mA    249.2mA    179.6mA
-1.02V    75.12mA    110.9mA    69.42mA
-745mV    29.49mA    26.13mA    37.05mA
25mV      -288.8uA   -173.9uA   -376.6uA
2.17V     -16.09mA   -17.47mA   -15.69mA
2.555V    -49.99mA   -64.93mA   -52.72mA
2.885V    -139.9mA   -249mA     -100.7mA
2.995V    -211.2mA   -327mA     -132.9mA
3.16V     -332.6mA   -448.7mA   -236.3mA
3.6V      -680.1mA   -784.7mA   -587mA
[GND_clamp]
|Voltage   I(typ)   I(min)   I(max)
-1.8V     -676.5mA   -711.8mA   -657.4mA
-1.171V   -188.7mA   -241.8mA   -159.9mA
-1.134V   -163.6mA   -216.3mA   -136.8mA
-1.06V    -117.5mA   -167.3mA   -99.83mA
-1.023V   -97.55mA   -144.1mA   -87.53mA
-949mV    -66.6mA    -101.7mA   -72.31mA
-875mV    -48.59mA   -66.87mA   -60.47mA
-801mV    -38.1mA    -41.83mA   -49.17mA
-690mV    -25.46mA   -21.69mA   -33.22mA
-468mV    -6.481mA   -6.03mA    -8.185mA
-246mV    -123.8uA   -342.5uA   -71.29uA
1.8V      0A         0A         0A
[POWER_clamp]
|Voltage   I(typ)   I(min)   I(max)
-1.8V     628.2mA    655.1mA    614.5mA
-1.16V    142.1mA    189.1mA    115.1mA
-1.123V   118.1mA    164.9mA    92.31mA
-1.086V   95.71mA    141.6mA    72.22mA
-1.049V   75.33mA    119.3mA    55.8mA
-1.012V   57.61mA    98.32mA    43.83mA
-938mV    32.37mA    61.71mA    31.08mA
-864mV    20.22mA    34.67mA    24.05mA
-790mV    14.43mA    18.62mA    18.17mA
-679mV    8.837mA    8.698mA    10.99mA
-494mV    3.348mA    3.38mA     3.939mA
3.6V      -190.6uA   -231.6uA   -189.2uA
[Ramp]
| variable   typ   min   max
dV/dt_r   0.188/32.395p   0.158/43.981p   0.247/28.489p
dV/dt_f   0.116/26.621p   0.085/33.641p   0.160/23.531p
R_load = 50.000
[Rising Waveform]
R_fixture = 50.000
V_fixture = 0.000
V_fixture_min = 0.000
V_fixture_max = 0.000
|time   V(typ)   V(min)   V(max)
0s        8.342mV    13.24mV    7.401mV
208ps     8.509mV    13.24mV    6.184mV
227ps     6.151mV    13.23mV    83.93mV
256ps     10.09mV    13.21mV    332.7mV
287ps     123.4mV    13.35mV    483.8mV
342ps     391.3mV    8.68mV     458.1mV
382ps     378.2mV    58.92mV    449.6mV
454ps     352.7mV    299.6mV    443.1mV
488ps     346.4mV    330.8mV    442.3mV
10ns      318.6mV    273.4mV    414.9mV
[Rising Waveform]
R_fixture = 50.000
V_fixture = 1.250
V_fixture_min = 1.188
V_fixture_max = 1.313
|  time   V(typ)   V(min)   V(max)
0s        1.081V     1.062V     1.088V
219ps     1.08V      1.062V     1.081V
234ps     1.077V     1.062V     1.126V
261ps     1.073V     1.062V     1.288V
282ps     1.108V     1.062V     1.373V
325ps     1.271V     1.059V     1.43V
354ps     1.335V     1.056V     1.449V
498ps     1.4V       1.29V      1.496V
756ps     1.424V     1.341V     1.519V
10ns      1.431V     1.353V     1.52V
[Falling Waveform]
R_fixture = 50.000
V_fixture = 1.250
V_fixture_min = 1.188
V_fixture_max = 1.313
|  time   V(typ)   V(min)   V(max)
0s        1.431V     1.353V     1.52V
207ps     1.431V     1.353V     1.515V
228ps     1.431V     1.353V     1.423V
254ps     1.424V     1.353V     1.21V
282ps     1.327V     1.353V     1.063V
339ps     1.049V     1.354V     1.091V
374ps     1.061V     1.315V     1.097V
448ps     1.085V     1.076V     1.095V
477ps     1.088V     1.04V      1.092V
10ns      1.081V     1.062V     1.088V
[Falling Waveform]
R_fixture = 50.000
V_fixture = 0.000
V_fixture_min = 0.000
V_fixture_max = 0.000
|  time   V(typ)   V(min)   V(max)
0s        318.6mV    273.4mV    414.9mV
198ps     318.7mV    273.4mV    412mV
255ps     289.1mV    273.4mV    161.2mV
309ps     123.9mV    273.8mV    125.2mV
345ps     100.5mV    263.6mV    92.33mV
378ps     92.67mV    198.5mV    70.36mV
445ps     59.16mV    97.72mV    43.53mV
689ps     23.01mV    40.95mV    15.59mV
1.699ns   7.829mV    14.93mV    6.731mV
10ns      8.342mV    13.24mV    7.401mV
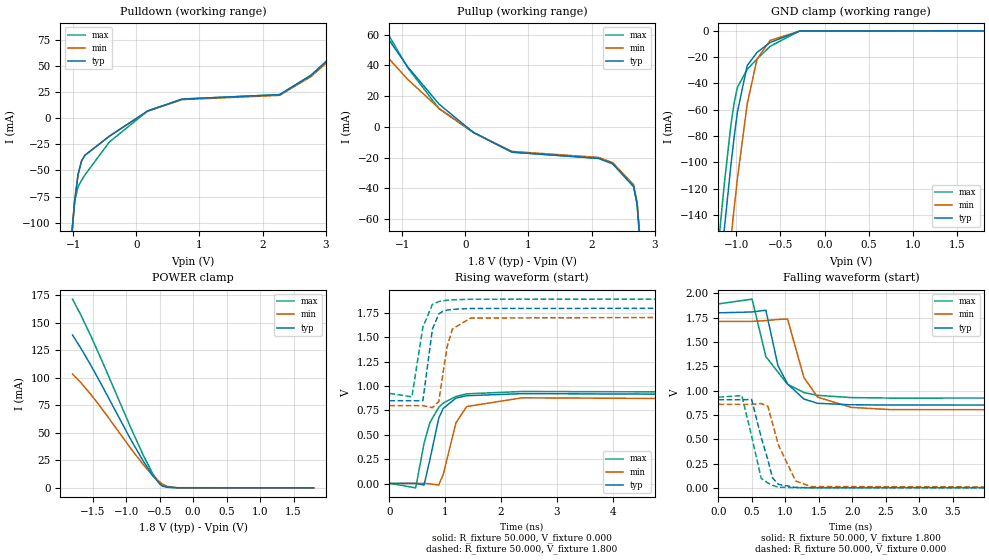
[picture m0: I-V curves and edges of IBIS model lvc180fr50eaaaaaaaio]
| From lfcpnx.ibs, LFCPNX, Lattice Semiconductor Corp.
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[Model] lvc180fr50eaaaaaaaio
Model_type I/O
Polarity   Non-Inverting
Enable   Active-Low
Vinl =  0.630V
Vinh =  1.170V
Vmeas =  0.900V
Cref =  0.0F
Rref =  1.000M
Vref =  0.0V
C_comp   5.000pF   4.000pF   5.500pF
[Temperature Range]   25.000   0.125k   -40.000
[Voltage Range]   1.800V   1.710V   1.890V
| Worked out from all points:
|   slope of the pulldown table from 0 to 0.27 V, typ, clamps not added: 27 ohm
|   slope of the pullup table from 0 to 0.27 V, typ, clamps not added: 36.9 ohm
|   GND clamp passes 1 mA (typ) near -0.37 V on its own axis
|   POWER clamp passes 1 mA (typ) near -0.42 V on its own axis
|   rising waveform, R_fixture 50.000, V_fixture 0.000: 20-80 % time 217ps typ, 243ps min, 285ps max; typ from 0 V to 0.906 V
|   rising waveform, R_fixture 50.000, V_fixture 1.800: 20-80 % time 128ps typ, 165ps min, 157ps max; typ from 0.849 V to 1.8 V
|   falling waveform, R_fixture 50.000, V_fixture 1.800: 20-80 % time 309ps typ, 273ps min, 374ps max; typ from 1.8 V to 0.849 V
|   falling waveform, R_fixture 50.000, V_fixture 0.000: 20-80 % time 209ps typ, 278ps min, 184ps max; typ from 0.906 V to 0 V
[GND_clamp]
|Voltage   I(typ)   I(min)   I(max)
-1.8V     -665.5mA   -701.9mA   -644.7mA
-1.208V   -203.2mA   -259.3mA   -168.6mA
-1.171V   -176.5mA   -233.3mA   -141.8mA
-1.134V   -150.7mA   -207.7mA   -116.3mA
-1.06V    -102.3mA   -158.3mA   -71.8mA
-1.023V   -80.78mA   -134.8mA   -54.83mA
-986mV    -61.78mA   -112.4mA   -42.93mA
-875mV    -26.33mA   -55.53mA   -29.29mA
-764mV    -16.38mA   -21.41mA   -21.4mA
-616mV    -8.858mA   -7.288mA   -11.79mA
-283mV    -142.7uA   -287uA     -113.6uA
1.8V      0A         0A         0A
[POWER_clamp]
|Voltage   I(typ)   I(min)   I(max)
-1.8V     138.7mA    103.3mA    171.3mA
-1.678V   127mA      95.65mA    157.2mA
-1.53V    111.7mA    85.11mA    138.4mA
-1.345V   91.17mA    70.52mA    113.2mA
-938mV    44.71mA    36.47mA    55.67mA
-753mV    25.22mA    21.78mA    30.82mA
-605mV    11.26mA    11.4mA     13.08mA
-494mV    3.49mA     5.157mA    3.227mA
-457mV    1.898mA    3.519mA    1.512mA
-383mV    542.5uA    1.315mA    536.2uA
-235mV    73.61uA    152.3uA    57.83uA
1.8V      0A         0A         0A
[Pulldown]
|Voltage   I(typ)   I(min)   I(max)
-1.8V     -1A        -1A        -1.545A
-1.03V    -118.1mA   -118.1mA   -117.7mA
-975mV    -79.04mA   -79.04mA   -79.65mA
-920mV    -53.51mA   -53.51mA   -65.53mA
-865mV    -40.67mA   -40.67mA   -59.28mA
-810mV    -35.31mA   -35.31mA   -54.01mA
-425mV    -17.19mA   -17.19mA   -22.72mA
180mV     6.979mA    6.77mA     6.979mA
730mV     18.36mA    17.81mA    18.36mA
2.27V     22.59mA    21.91mA    22.59mA
2.765V    41.03mA    39.8mA     41.03mA
3.6V      86.9mA     84.3mA     86.9mA
[Pullup]
|Voltage   I(typ)   I(min)   I(max)
-1.8V     91.5mA     70.91mA    100.9mA
-1.68V    84.4mA     65.64mA    92.4mA
-910mV    39.09mA    30.91mA    38.48mA
-415mV    14.81mA    12.09mA    11.85mA
135mV     -3.76mA    -3.647mA   -3.76mA
740mV     -16.41mA   -15.92mA   -16.41mA
2.115V    -20.46mA   -19.85mA   -20.46mA
2.335V    -23.98mA   -23.26mA   -23.98mA
2.665V    -38.74mA   -37.57mA   -38.74mA
2.72V     -49.95mA   -48.45mA   -49.95mA
2.83V     -107.4mA   -104.1mA   -107.4mA
3.6V      -902.3mA   -875.2mA   -902.3mA
[Ramp]
| variable   typ   min   max
dV/dt_r   0.544/0.217n   0.538/0.245n   0.562/0.284n
dV/dt_f   0.570/0.306n   0.533/0.274n   0.579/0.376n
R_load = 50.000
[Rising Waveform]
R_fixture = 50.000
V_fixture = 0.000
V_fixture_min = 0.000
V_fixture_max = 0.000
|  time   V(typ)   V(min)   V(max)
0s        63.45uV    1.064mV    2.375mV
470ps     954.4uV    1.018mV    -44.69mV
620ps     -16.03mV   1.294mV    412.5mV
724ps     241.9mV    -3.245mV   624.3mV
883ps     669.4mV    -15.57mV   780.9mV
964ps     770.8mV    93.41mV    825.5mV
1.193ns   876.5mV    623.8mV    894mV
1.384ns   901mV      789.7mV    920.2mV
2.378ns   922mV      879.3mV    944.3mV
10ns      906.4mV    859.4mV    932.6mV
[Rising Waveform]
R_fixture = 50.000
V_fixture = 1.800
V_fixture_min = 1.710
V_fixture_max = 1.890
|  time   V(typ)   V(min)   V(max)
0s        849.2mV    799.3mV    925.4mV
402ps     849.3mV    798.8mV    889.2mV
599ps     849.7mV    799.5mV    1.605V
770ps     1.584V     778.3mV    1.838V
884ps     1.739V     842.1mV    1.867V
953ps     1.766V     1.105V     1.875V
1.034ns   1.78V      1.405V     1.88V
1.13ns    1.787V     1.586V     1.885V
1.454ns   1.796V     1.698V     1.891V
10ns      1.8V       1.712V     1.892V
[Falling Waveform]
R_fixture = 50.000
V_fixture = 1.800
V_fixture_min = 1.710
V_fixture_max = 1.890
|  time   V(typ)   V(min)   V(max)
0s        1.8V       1.712V     1.892V
502ps     1.809V     1.712V     1.941V
708ps     1.827V     1.72V      1.35V
888ps     1.258V     1.732V     1.191V
1.032ns   1.069V     1.736V     1.065V
1.277ns   913.1mV    1.134V     980.4mV
1.481ns   869.7mV    933mV      951.6mV
1.982ns   854.4mV    827.7mV    928.5mV
2.571ns   851.8mV    804.9mV    923.5mV
10ns      849.2mV    799.3mV    925.4mV
[Falling Waveform]
R_fixture = 50.000
V_fixture = 0.000
V_fixture_min = 0.000
V_fixture_max = 0.000
|  time   V(typ)   V(min)   V(max)
0s        906.4mV    859.4mV    932.6mV
349ps     906.1mV    859.1mV    949mV
495ps     908.8mV    859.3mV    532.2mV
638ps     519.4mV    867mV      97.75mV
738ps     288.3mV    838.3mV    49.97mV
807ps     102.6mV    665mV      26.3mV
897ps     35.63mV    438.4mV    6.536mV
1.152ns   4.924mV    71.64mV    1.986mV
1.381ns   439.3uV    13.69mV    1.784mV
10ns      63.45uV    1.064mV    2.375mV
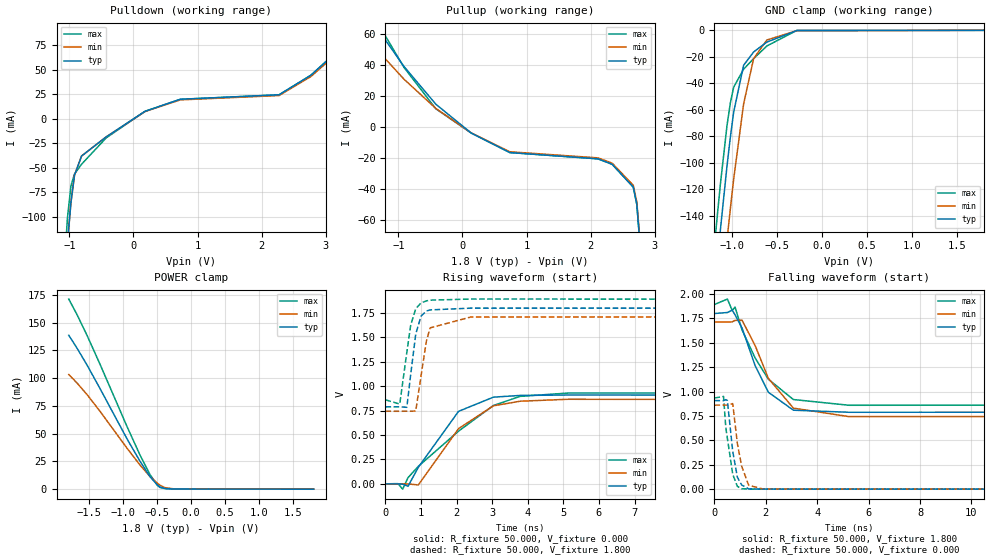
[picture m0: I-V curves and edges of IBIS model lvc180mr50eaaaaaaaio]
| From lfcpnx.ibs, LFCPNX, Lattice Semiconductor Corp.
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[Model] lvc180mr50eaaaaaaaio
Model_type I/O
Polarity   Non-Inverting
Enable   Active-Low
Vinl =  0.630V
Vinh =  1.170V
Vmeas =  0.900V
Cref =  0.0F
Rref =  1.000M
Vref =  0.0V
C_comp   5.000pF   4.000pF   5.500pF
[Temperature Range]   25.000   0.125k   -40.000
[Voltage Range]   1.800V   1.710V   1.890V
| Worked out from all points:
|   slope of the pulldown table from 0 to 0.27 V, typ, clamps not added: 25 ohm
|   slope of the pullup table from 0 to 0.27 V, typ, clamps not added: 36.8 ohm
|   GND clamp passes 1 mA (typ) near -0.37 V on its own axis
|   POWER clamp passes 1 mA (typ) near -0.42 V on its own axis
|   rising waveform, R_fixture 50.000, V_fixture 0.000: 20-80 % time 1.06ns typ, 1.16ns min, 1.83ns max; typ from 0 V to 0.908 V
|   rising waveform, R_fixture 50.000, V_fixture 1.800: 20-80 % time 213ps typ, 239ps min, 242ps max; typ from 0.789 V to 1.8 V
|   falling waveform, R_fixture 50.000, V_fixture 1.800: 20-80 % time 952ps typ, 1.14ns min, 1.28ns max; typ from 1.8 V to 0.789 V
|   falling waveform, R_fixture 50.000, V_fixture 0.000: 20-80 % time 275ps typ, 309ps min, 268ps max; typ from 0.908 V to 0 V
[GND_clamp]
|Voltage   I(typ)   I(min)   I(max)
-1.8V     -665.5mA   -701.9mA   -644.7mA
-1.208V   -203.2mA   -259.3mA   -168.6mA
-1.171V   -176.5mA   -233.3mA   -141.8mA
-1.134V   -150.7mA   -207.7mA   -116.3mA
-1.06V    -102.3mA   -158.3mA   -71.8mA
-1.023V   -80.78mA   -134.8mA   -54.83mA
-986mV    -61.78mA   -112.4mA   -42.93mA
-875mV    -26.33mA   -55.53mA   -29.29mA
-764mV    -16.38mA   -21.41mA   -21.4mA
-616mV    -8.858mA   -7.288mA   -11.79mA
-283mV    -142.7uA   -287uA     -113.6uA
1.8V      0A         0A         0A
[POWER_clamp]
|Voltage   I(typ)   I(min)   I(max)
-1.8V     138.7mA    103.3mA    171.3mA
-1.678V   127mA      95.65mA    157.2mA
-1.53V    111.7mA    85.11mA    138.4mA
-1.345V   91.17mA    70.52mA    113.2mA
-938mV    44.71mA    36.47mA    55.67mA
-753mV    25.22mA    21.78mA    30.82mA
-605mV    11.26mA    11.4mA     13.08mA
-494mV    3.49mA     5.157mA    3.227mA
-457mV    1.898mA    3.519mA    1.512mA
-383mV    542.5uA    1.315mA    536.2uA
-235mV    73.61uA    152.3uA    57.83uA
1.8V      0A         0A         0A
[Pulldown]
|Voltage   I(typ)   I(min)   I(max)
-1.8V     -1.08A     -1.08A     -1.33A
-1.085V   -180.2mA   -180.2mA   -157.9mA
-1.03V    -127.4mA   -127.4mA   -101.4mA
-975mV    -85.32mA   -85.32mA   -68.58mA
-920mV    -57.77mA   -57.77mA   -56.42mA
-810mV    -38.12mA   -38.12mA   -46.5mA
-425mV    -18.55mA   -18.55mA   -19.56mA
180mV     7.533mA    7.307mA    7.533mA
730mV     19.82mA    19.22mA    19.82mA
2.27V     24.38mA    23.65mA    24.38mA
2.765V    44.29mA    42.96mA    44.29mA
3.6V      93.7mA     90.9mA     93.7mA
[Pullup]
|Voltage   I(typ)   I(min)   I(max)
-1.8V     91.7mA     71.06mA    101.1mA
-1.68V    84.6mA     65.78mA    92.6mA
-910mV    39.18mA    30.97mA    38.56mA
-415mV    14.85mA    12.12mA    11.88mA
135mV     -3.768mA   -3.655mA   -3.768mA
740mV     -16.45mA   -15.95mA   -16.45mA
2.115V    -20.51mA   -19.89mA   -20.51mA
2.335V    -24.03mA   -23.31mA   -24.03mA
2.665V    -38.82mA   -37.65mA   -38.82mA
2.72V     -50.05mA   -48.55mA   -50.05mA
2.83V     -107.6mA   -104.4mA   -107.6mA
3.6V      -904.1mA   -877mA     -904.1mA
[Ramp]
| variable   typ   min   max
dV/dt_r   0.545/1.065n   0.534/1.163n   0.561/1.834n
dV/dt_f   0.606/0.953n   0.580/1.135n   0.618/1.276n
R_load = 50.000
[Rising Waveform]
R_fixture = 50.000
V_fixture = 0.000
V_fixture_min = 0.000
V_fixture_max = 0.000
|  time   V(typ)   V(min)   V(max)
0s        66.03uV    -537.3uV   750.2uV
351ps     55.17uV    -847.1uV   2.815mV
482ps     -2.662mV   -559.9uV   -53.92mV
634ps     -24.22mV   -254.3uV   64.41mV
923ps     170.2mV    -10.71mV   179.9mV
2.054ns   743.3mV    566.5mV    540.6mV
3.033ns   888.4mV    799.5mV    803.1mV
3.784ns   906mV      846.9mV    896.4mV
5.13ns    910.3mV    866.7mV    930.5mV
20ns      907.7mV    860.6mV    934mV
[Rising Waveform]
R_fixture = 50.000
V_fixture = 1.800
V_fixture_min = 1.710
V_fixture_max = 1.890
|  time   V(typ)   V(min)   V(max)
0s        789.2mV    744.2mV    861.1mV
401ps     789.4mV    743.7mV    817.5mV
600ps     784.3mV    744.4mV    1.349V
709ps     1.122V     744.2mV    1.627V
850ps     1.534V     746.1mV    1.794V
1ns       1.719V     1.108V     1.854V
1.149ns   1.77V      1.462V     1.874V
1.254ns   1.782V     1.598V     1.882V
2.396ns   1.8V       1.709V     1.893V
20ns      1.8V       1.712V     1.892V
[Falling Waveform]
R_fixture = 50.000
V_fixture = 1.800
V_fixture_min = 1.710
V_fixture_max = 1.890
|  time   V(typ)   V(min)   V(max)
0s        1.8V       1.712V     1.892V
504ps     1.81V      1.712V     1.948V
692ps     1.835V     1.715V     1.831V
802ps     1.786V     1.729V     1.866V
1.072ns   1.653V     1.732V     1.633V
1.581ns   1.267V     1.473V     1.345V
2.099ns   992.8mV    1.135V     1.126V
3.072ns   808.8mV    829.8mV    918.1mV
5.24ns    787.6mV    743.1mV    859.4mV
20ns      789.2mV    744.2mV    861.1mV
[Falling Waveform]
R_fixture = 50.000
V_fixture = 0.000
V_fixture_min = 0.000
V_fixture_max = 0.000
|  time   V(typ)   V(min)   V(max)
0s        907.7mV    860.6mV    934mV
354ps     907.3mV    860.3mV    949.9mV
441ps     917.2mV    860.5mV    632.7mV
502ps     908.7mV    860.4mV    523.3mV
711ps     387.4mV    876.7mV    152.5mV
892ps     122.2mV    467.1mV    28.09mV
1.056ns   43.58mV    237.8mV    4.226mV
1.332ns   2.023mV    39.32mV    539uV
1.892ns   180.7uV    825.2uV    304uV
20ns      66.03uV    -537.3uV   750.2uV
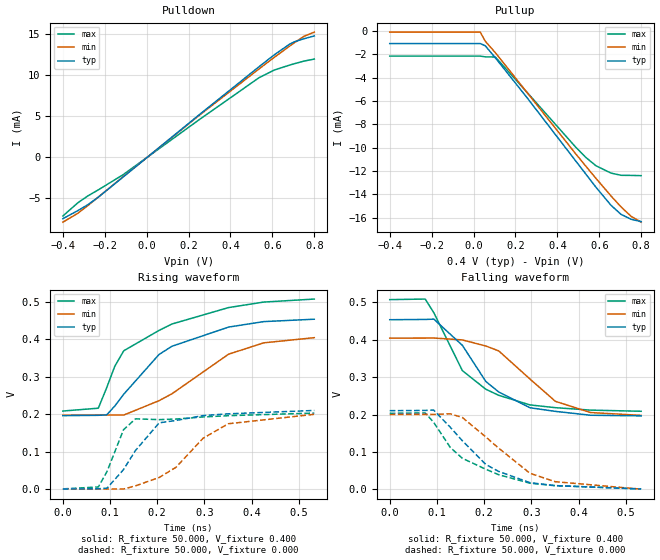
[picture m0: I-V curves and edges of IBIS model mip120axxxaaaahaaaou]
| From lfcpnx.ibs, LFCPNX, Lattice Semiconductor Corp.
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|   Model mip120axxxaaaahaaaou
[Model] mip120axxxaaaahaaaou
Model_type Output
Polarity   Non-Inverting
Vmeas =  0.1V
Cref =  2pF
Rref =  50
Rref_diff = 100
Vref =  0.0V
C_comp   3.2004pF   3.1599pF   3.2762pF
[Temperature Range]   25   -40   125
[Voltage Range]   0.4   0.4   0.4
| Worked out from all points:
|   slope of the pulldown table from 0 to 0.06 V, typ, clamps not added: 47.7 ohm
|   slope of the pullup table from 0 to 0.06 V, typ, clamps not added: 221 ohm
|   rising waveform, R_fixture 50.000, V_fixture 0.400: 20-80 % time 140ps typ, 150ps min, 153ps max; typ from 0.196 V to 0.454 V
|   falling waveform, R_fixture 50.000, V_fixture 0.400: 20-80 % time 101ps typ, 105ps min, 100ps max; typ from 0.454 V to 0.196 V
|   rising waveform, R_fixture 50.000, V_fixture 0.000: 20-80 % time 74.2ps typ, 114ps min, 40.3ps max; typ from 0.001 V to 0.21 V
|   falling waveform, R_fixture 50.000, V_fixture 0.000: 20-80 % time 112ps typ, 119ps min, 125ps max; typ from 0.21 V to 0.001 V
[Pulldown]
|Voltage   I(typ)   I(min)   I(max)
-400mV    -7.472mA   -7.898mA   -7.143mA
-328mV    -6.481mA   -6.8mA     -5.524mA
-280mV    -5.754mA   -5.86mA    -4.682mA
-232mV    -4.873mA   -4.861mA   -3.976mA
-112mV    -2.385mA   -2.349mA   -2.101mA
248mV     5.144mA    5.07mA     4.551mA
536mV     11.05mA    10.79mA    9.714mA
608mV     12.49mA    12.18mA    10.64mA
680mV     13.77mA    13.53mA    11.24mA
704mV     14.09mA    13.97mA    11.42mA
752mV     14.48mA    14.78mA    11.75mA
800mV     14.81mA    15.28mA    11.99mA
[Pullup]
|Voltage   I(typ)   I(min)   I(max)
-400mV    -1.07mA    -85.09uA   -2.143mA
32mV      -1.07mA    -85.09uA   -2.143mA
56mV      -1.256mA   -870.3uA   -2.209mA
104mV     -2.292mA   -1.847mA   -2.223mA
248mV     -5.54mA    -5.1mA     -5.102mA
488mV     -11.14mA   -10.53mA   -9.955mA
536mV     -12.26mA   -11.58mA   -10.83mA
584mV     -13.38mA   -12.62mA   -11.54mA
656mV     -14.93mA   -14.13mA   -12.17mA
704mV     -15.71mA   -15.07mA   -12.36mA
752mV     -16.13mA   -15.88mA   -12.37mA
800mV     -16.33mA   -16.38mA   -12.39mA
[Ramp]
| variable   typ   min   max
dV/dt_r   1.2535E-01/7.7189E-11   1.2119E-01/1.2212E-10   1.1983E-01/4.2641E-11
dV/dt_f   0.154/1.2162E-10   1.2119E-01/1.3189E-10   0.179/1.3427E-10
R_load = 50.000
[Rising Waveform]
R_fixture = 50.000
V_fixture = 0.400
|  time   V(typ)   V(min)   V(max)
0s        196.4mV    197.7mV    208.7mV
75.18ps   197.3mV    197.9mV    216.3mV
92.94ps   198.6mV    198mV      271mV
110.1ps   222.1mV    198.1mV    328.3mV
129.1ps   253.7mV    198mV      369.4mV
203.6ps   359.2mV    236.2mV    423.5mV
230.9ps   381.3mV    254.5mV    440.6mV
351.1ps   432.5mV    360.2mV    484.5mV
425.6ps   447.1mV    390.5mV    499.2mV
532.8ps   453.5mV    404.3mV    507.2mV
[Falling Waveform]
R_fixture = 50.000
V_fixture = 0.400
|  time   V(typ)   V(min)   V(max)
0s        453.5mV    404.3mV    507.2mV
75.18ps   454.2mV    404.4mV    508.7mV
93.54ps   455mV      404.5mV    471.9mV
153.9ps   385mV      399.5mV    317.4mV
203.6ps   288.4mV    383.2mV    267.6mV
230.9ps   260.3mV    370.2mV    251.4mV
297.2ps   218.1mV    294.8mV    225.7mV
351.1ps   208.4mV    235.2mV    218.3mV
425.6ps   198.1mV    205.3mV    211.8mV
532.8ps   196.4mV    197.7mV    208.7mV
[Rising waveform]
R_fixture = 50.000
V_fixture = 0.000
|  time   V(typ)   V(min)   V(max)
0s        713.8uV    439.9uV    1.247mV
75.18ps   1.485mV    658.1uV    6.285mV
93.54ps   3.073mV    768.1uV    47.31mV
128.5ps   52.51mV    766.4uV    158.8mV
153.9ps   103.6mV    9.271mV    187.9mV
204.2ps   177.3mV    31.65mV    185.8mV
239.8ps   183.6mV    58.82mV    187.4mV
297.2ps   196.6mV    136.2mV    192.9mV
350.5ps   201.3mV    174.8mV    196.3mV
532.8ps   210.3mV    200mV      203.3mV
[Falling waveform]
R_fixture = 50.000
V_fixture = 0.000
|  time   V(typ)   V(min)   V(max)
0s        210.3mV    200mV      203.3mV
75.18ps   210.9mV    200.2mV    204.3mV
92.94ps   212mV      200.2mV    179.4mV
128.5ps   165.7mV    201.9mV    111.7mV
153.9ps   129.9mV    192mV      82.99mV
203.6ps   66.45mV    140mV      53.7mV
230.9ps   47.86mV    109.9mV    39.08mV
297.2ps   17.76mV    42.89mV    16.32mV
350.5ps   10.03mV    20.43mV    9.729mV
532.8ps   713.8uV    439.9uV    1.247mV
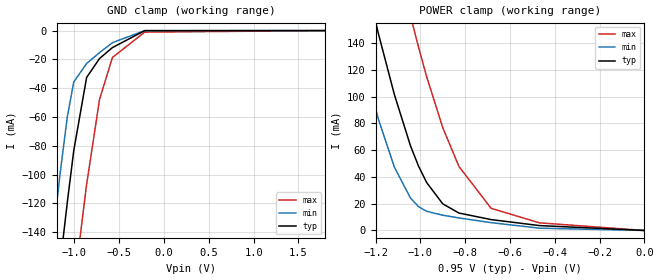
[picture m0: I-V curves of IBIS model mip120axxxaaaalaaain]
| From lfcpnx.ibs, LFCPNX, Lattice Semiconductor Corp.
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[Model] mip120axxxaaaalaaain
Model_type Input
Polarity   Non-Inverting
Vinl =  0.55V
Vinh =  0.88V
C_comp   3.2004pF   3.1599pF   3.2762pF
[Temperature Range]   25   -40   125
[Voltage Range]   0.95   0.825   1.05
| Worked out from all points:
|   GND clamp passes 1 mA (typ) near -0.32 V on its own axis
|   POWER clamp passes 1 mA (typ) near -0.36 V on its own axis
[GND_clamp]
|Voltage   I(typ)   I(min)   I(max)
-1.8V     -541.6mA   -473.8mA   -642.6mA
-1.368V   -281.6mA   -215.9mA   -383.1mA
-1.296V   -239.4mA   -174.3mA   -340.5mA
-1.224V   -198.1mA   -133.9mA   -298.6mA
-1.152V   -158mA     -95.27mA   -257.6mA
-1.08V    -119.5mA   -60.16mA   -217.6mA
-1.008V   -83.46mA   -35.69mA   -178.9mA
-864mV    -32.53mA   -22.87mA   -106.8mA
-720mV    -19.4mA    -15.3mA    -47.86mA
-576mV    -11.8mA    -8.394mA   -18.68mA
-216mV    -52.13uA   -951.7nA   -1.076mA
1.8V      4.546uA    1.815uA    11.27uA
[POWER_clamp]
|Voltage   I(typ)   I(min)   I(max)
-1.8V     618.5mA    525.6mA    759.2mA
-1.296V   224mA      152.5mA    346.5mA
-1.188V   147.3mA    83.47mA    263.2mA
-1.116V   101.4mA    47.2mA     210.1mA
-1.044V   63.07mA    24.15mA    160.1mA
-1.008V   47.94mA    17.75mA    136.7mA
-972mV    35.78mA    14.27mA    114.8mA
-900mV    19.85mA    11.39mA    76.71mA
-828mV    13mA       9.358mA    47.78mA
-684mV    8.111mA    5.821mA    16.52mA
-468mV    3.631mA    1.691mA    5.684mA
0V        -4.546uA   -1.344uA   -15.24uA
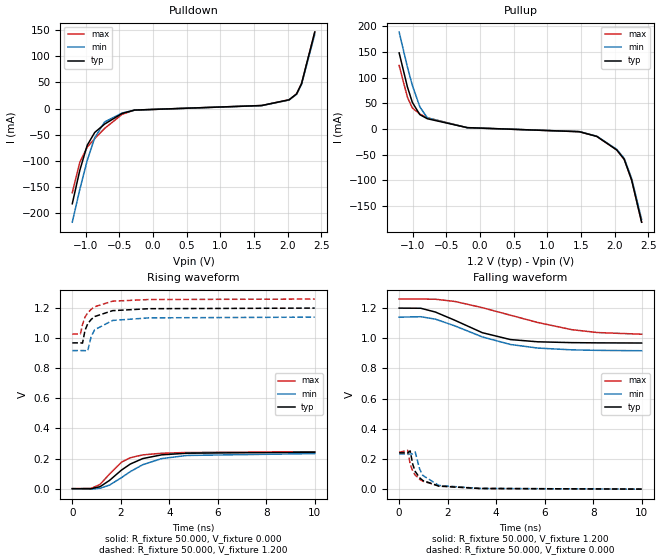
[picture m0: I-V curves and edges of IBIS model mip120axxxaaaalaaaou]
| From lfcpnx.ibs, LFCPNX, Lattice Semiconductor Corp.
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|   Model mip120axxxaaaalaaaou
[Model] mip120axxxaaaalaaaou
Model_type Output
Polarity   Non-Inverting
Enable   Active-High
Vmeas =  0.600V
Cref =  0.0F
Rref =  1.000M
Vref =  0.0V
C_comp   5.000pF   4.000pF   5.500pF
[Temperature Range]   25.000   0.125k   -40.000
[Voltage Range]   1.200V   1.140V   1.260V
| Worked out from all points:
|   slope of the pulldown table from 0 to 0.18 V, typ, clamps not added: 108 ohm
|   slope of the pullup table from 0 to 0.18 V, typ, clamps not added: 92.2 ohm
|   rising waveform, R_fixture 50.000, V_fixture 0.000: 20-80 % time 1.31ns typ, 1.57ns min, 962ps max; typ from 0 V to 0.243 V
|   rising waveform, R_fixture 50.000, V_fixture 1.200: 20-80 % time 547ps typ, 530ps min, 570ps max; typ from 0.969 V to 1.2 V
|   falling waveform, R_fixture 50.000, V_fixture 1.200: 20-80 % time 2.04ns typ, 2.4ns min, 3.35ns max; typ from 1.2 V to 0.969 V
|   falling waveform, R_fixture 50.000, V_fixture 0.000: 20-80 % time 536ps typ, 516ps min, 606ps max; typ from 0.241 V to 0 V
[Pulldown]
|Voltage   I(typ)   I(min)   I(max)
-1.2V     -182.9mA   -218.3mA   -161.8mA
-1.089V   -119mA     -155.7mA   -103.5mA
-978mV    -70.5mA    -99.7mA    -73.97mA
-867mV    -45.98mA   -56.14mA   -57.88mA
-719mV    -29.83mA   -25.74mA   -38.17mA
-460mV    -9.387mA   -8.653mA   -11.09mA
-275mV    -2.976mA   -3.061mA   -3.072mA
1.612V    5.767mA    5.594mA    5.767mA
2.019V    16.81mA    16.3mA     16.81mA
2.13V     28.06mA    27.22mA    28.06mA
2.204V    47.87mA    46.44mA    47.87mA
2.4V      146.8mA    142.4mA    146.8mA
[Pullup]
|Voltage   I(typ)   I(min)   I(max)
-1.2V     147.9mA    188.3mA    123.4mA
-1.078V   81.98mA    120.7mA    61.86mA
-1.004V   51.59mA    84.61mA    40.82mA
-893mV    27.85mA    43mA       29.06mA
-782mV    19.86mA    21.61mA    21.61mA
-190mV    2.572mA    2.372mA    2.456mA
1.475V    -5.352mA   -5.192mA   -5.352mA
1.734V    -14.51mA   -14.08mA   -14.51mA
2.03V     -40.75mA   -39.53mA   -40.75mA
2.141V    -58.9mA    -57.14mA   -58.9mA
2.252V    -99.4mA    -96.4mA    -99.4mA
2.4V      -181.3mA   -175.9mA   -181.3mA
[Ramp]
| variable   typ   min   max
dV/dt_r   0.146/1.318n   0.140/1.595n   0.147/1.021n
dV/dt_f   0.139/2.068n   0.134/2.485n   0.139/3.372n
R_load = 50.000
[Rising Waveform]
R_fixture = 50.000
V_fixture = 0.000
V_fixture_min = 0.000
V_fixture_max = 0.000
|  time   V(typ)   V(min)   V(max)
0s        24.31uV    46.35uV    271.1uV
775ps     -82.64uV   -3.224mV   1.66mV
1.145ns   13.1mV     3.017mV    28.57mV
1.534ns   54.87mV    23.79mV    96.75mV
2.029ns   123.5mV    73.33mV    176.2mV
2.39ns    163.5mV    113mV      205.5mV
2.903ns   199.9mV    159.2mV    224.4mV
3.684ns   224.8mV    199.8mV    235.4mV
4.731ns   235.7mV    220.8mV    240.6mV
10ns      242.6mV    233.2mV    244.8mV
[Rising Waveform]
R_fixture = 50.000
V_fixture = 1.200
V_fixture_min = 1.140
V_fixture_max = 1.260
|  time   V(typ)   V(min)   V(max)
0s        968.7mV    917.6mV    1.027V
336ps     969mV      917.7mV    1.028V
423ps     967.3mV    917.7mV    1.091V
525ps     1.052V     917.4mV    1.14V
635ps     1.095V     915.3mV    1.168V
781ps     1.125V     1.012V     1.192V
925ps     1.144V     1.056V     1.209V
1.664ns   1.183V     1.118V     1.246V
3.169ns   1.196V     1.135V     1.257V
10ns      1.2V       1.14V      1.26V
[Falling Waveform]
R_fixture = 50.000
V_fixture = 1.200
V_fixture_min = 1.140
V_fixture_max = 1.260
|  time   V(typ)   V(min)   V(max)
0s        1.2V       1.14V      1.26V
894ps     1.199V     1.143V     1.26V
1.493ns   1.174V     1.127V     1.259V
2.303ns   1.119V     1.082V     1.244V
3.43ns    1.037V     1.009V     1.203V
4.59ns    991.6mV    959mV      1.153V
5.708ns   976.8mV    935.3mV    1.105V
7.125ns   971.2mV    923.4mV    1.057V
8.184ns   969.7mV    919.9mV    1.038V
10ns      968.7mV    917.6mV    1.027V
[Falling Waveform]
R_fixture = 50.000
V_fixture = 0.000
V_fixture_min = 0.000
V_fixture_max = 0.000
|  time   V(typ)   V(min)   V(max)
0s        241mV      233.2mV    244.8mV
356ps     240.6mV    232.9mV    257.5mV
454ps     253.9mV    233.1mV    165.5mV
563ps     163.9mV    234.8mV    118.4mV
663ps     117.5mV    246.5mV    93.44mV
843ps     75.82mV    134.6mV    65.7mV
973ps     57.74mV    91.45mV    53.01mV
1.633ns   20.14mV    24.92mV    22.64mV
3.31ns    4.661mV    4.911mV    4.541mV
10ns      467.9uV    46.35uV    271.1uV
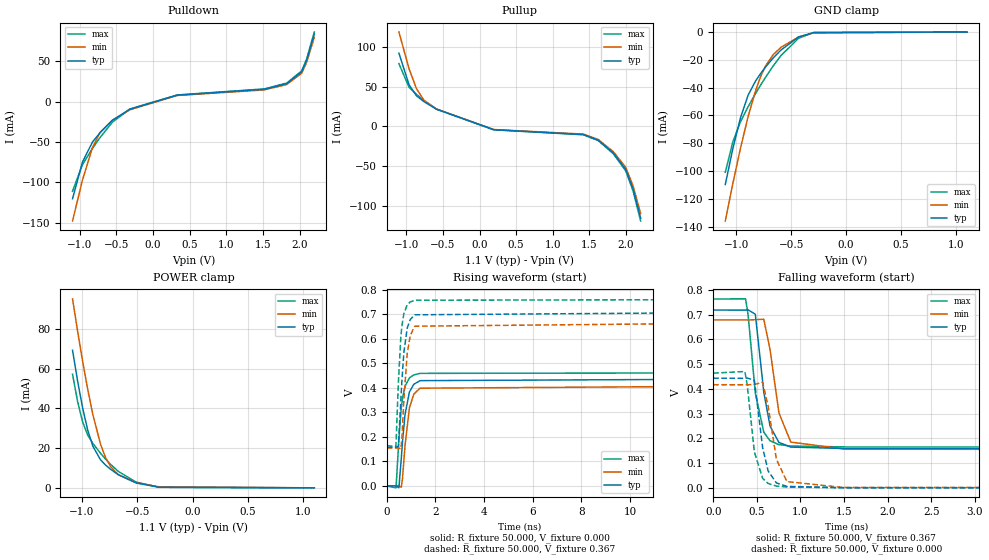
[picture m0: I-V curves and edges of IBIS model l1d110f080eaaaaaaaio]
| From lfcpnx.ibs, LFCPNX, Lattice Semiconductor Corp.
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|   Model l1d110f080eaaaaaaaio
[Model] l1d110f080eaaaaaaaio
| Clamp models do not include dynamic input termination. Please refer to
| the l1d110axxxeaaaaaaain model for input termination.
Model_type I/O
Polarity   Non-Inverting
Enable   Active-Low
Vinl =  0.093V
Vinh =  0.273V
Vmeas =  0.183V
Cref =  30.000pF
Rref =  50.000
Vref =  0.183V
C_comp   5.000pF   4.000pF   5.500pF
[Temperature Range]   25.000   0.125k   -40.000
[Voltage Range]   1.100V   1.050V   1.160V
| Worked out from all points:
|   slope of the pulldown table from 0 to 0.165 V, typ, clamps not added: 37.8 ohm
|   slope of the pullup table from 0 to 0.165 V, typ, clamps not added: 43.3 ohm
|   GND clamp passes 1 mA (typ) near -0.34 V on its own axis
|   POWER clamp passes 1 mA (typ) near -0.40 V on its own axis
|   rising waveform, R_fixture 50.000, V_fixture 0.000: 20-80 % time 271ps typ, 275ps min, 221ps max; typ from 0 V to 0.443 V
|   rising waveform, R_fixture 50.000, V_fixture 0.367: 20-80 % time 233ps typ, 229ps min, 183ps max; typ from 0.158 V to 0.719 V
|   falling waveform, R_fixture 50.000, V_fixture 0.367: 20-80 % time 120ps typ, 137ps min, 114ps max; typ from 0.719 V to 0.158 V
|   falling waveform, R_fixture 50.000, V_fixture 0.000: 20-80 % time 108ps typ, 122ps min, 101ps max; typ from 0.444 V to 0 V
[GND_clamp]
|Voltage   I(typ)   I(min)   I(max)
-1.1V     -109.7mA   -136mA     -100.9mA
-1.031V   -83.8mA    -108.9mA   -78.96mA
-962mV    -61.77mA   -83.67mA   -64.53mA
-893mV    -45.54mA   -61.02mA   -53.87mA
-824mV    -35.15mA   -42.04mA   -44.15mA
-778mV    -29.8mA    -31.96mA   -38.11mA
-732mV    -24.99mA   -24.15mA   -32.36mA
-663mV    -18.58mA   -16.21mA   -24.28mA
-594mV    -12.99mA   -11.04mA   -16.99mA
-433mV    -3.55mA    -3.535mA   -4.455mA
-295mV    -346.2uA   -626.8uA   -308.3uA
1.1V      0A         0A         0A
[POWER_clamp]
|Voltage   I(typ)   I(min)   I(max)
-1.085V   69.26mA    95.18mA    57.25mA
-1.039V   53.71mA    78.84mA    43.39mA
-993mV    40.01mA    63.46mA    33.04mA
-947mV    28.89mA    49.34mA    26.51mA
-901mV    20.94mA    36.82mA    22.35mA
-832mV    14.13mA    21.98mA    17.41mA
-786mV    11.43mA    15.15mA    14.47mA
-740mV    9.291mA    10.59mA    11.78mA
-671mV    6.617mA    6.611mA    8.279mA
-510mV    2.46mA     2.588mA    2.889mA
-303mV    307uA      515.1uA    269.4uA
1.1V      0A         0A         0A
[Pulldown]
|Voltage   I(typ)   I(min)   I(max)
-1.1V     -120.2mA   -147.9mA   -111mA
-964mV    -74.71mA   -96.95mA   -77.92mA
-828mV    -50.08mA   -56.99mA   -57.91mA
-726mV    -38.61mA   -38.36mA   -44.61mA
-556mV    -23.1mA    -22.88mA   -25.4mA
-318mV    -9.291mA   -10.08mA   -9.131mA
328mV     8.086mA    7.682mA    8.329mA
1.518V    15.38mA    14.61mA    15.84mA
1.824V    22.41mA    21.29mA    23.08mA
2.028V    37.16mA    35.3mA     38.27mA
2.096V    51.35mA    48.78mA    52.89mA
2.2V      83.82mA    79.63mA    86.33mA
[Pullup]
|Voltage   I(typ)   I(min)   I(max)
-1.1V     92.03mA    118.6mA    78.8mA
-962mV    52.27mA    72.44mA    49.17mA
-860mV    38.29mA    47.22mA    40.05mA
-758mV    30.99mA    32.71mA    32.28mA
-588mV    21.43mA    21.64mA    21.65mA
194mV     -4.357mA   -4.139mA   -4.488mA
1.418V    -10.41mA   -9.889mA   -10.72mA
1.622V    -17.58mA   -16.7mA    -18.11mA
1.826V    -33.59mA   -31.91mA   -34.6mA
1.996V    -54.41mA   -51.69mA   -56.04mA
2.098V    -79.59mA   -75.61mA   -81.98mA
2.2V      -115.8mA   -110mA     -119.3mA
[Ramp]
| variable   typ   min   max
dV/dt_r   0.266/0.270n   0.263/0.274n   0.283/0.220n
dV/dt_f   0.342/0.171n   0.336/0.185n   0.359/0.170n
R_load = 50.000
[Rising Waveform]
R_fixture = 50.000
V_fixture = 0.000
V_fixture_min = 0.000
V_fixture_max = 0.000
|  time   V(typ)   V(min)   V(max)
0s        2.857uV    475.2uV    -82.95uV
379ps     425.2uV    457.3uV    -7.682mV
496ps     -7.492mV   1.308mV    191.5mV
593ps     109.4mV    -5.527mV   318.2mV
644ps     180.9mV    30.89mV    358.1mV
748ps     291.4mV    164.4mV    406.7mV
928ps     383.2mV    318mV      441.1mV
1.107ns   414.9mV    374.8mV    453.2mV
1.367ns   429.9mV    399.1mV    459.6mV
30ns      443.4mV    417mV      463.8mV
[Rising Waveform]
R_fixture = 50.000
V_fixture = 0.367
V_fixture_min = 0.350
V_fixture_max = 0.386
|  time   V(typ)   V(min)   V(max)
0s        157.8mV    154.8mV    164.8mV
374ps     158.1mV    154.8mV    161.1mV
474ps     161.5mV    155.3mV    419.1mV
576ps     348mV      151mV      607.8mV
618ps     426.7mV    191.7mV    651.5mV
702ps     546.2mV    353.9mV    704mV
838ps     644.3mV    539.7mV    739.4mV
964ps     679.6mV    614.7mV    751.3mV
1.147ns   698.7mV    652.2mV    758.1mV
30ns      719mV      679.1mV    763.7mV
[Falling Waveform]
R_fixture = 50.000
V_fixture = 0.367
V_fixture_min = 0.350
V_fixture_max = 0.386
|  time   V(typ)   V(min)   V(max)
0s        719mV      679.1mV    763.7mV
371ps     718.6mV    679mV      764.2mV
400ps     719.8mV    678.9mV    700.6mV
483ps     702.3mV    680.1mV    383.5mV
580ps     387.1mV    681.9mV    225.1mV
652ps     249.3mV    559mV      190.2mV
754ps     183.6mV    302.7mV    174.6mV
890ps     164.8mV    184.9mV    169.1mV
1.525ns   158.8mV    155.9mV    165.3mV
30ns      157.8mV    154.8mV    164.8mV
[Falling Waveform]
R_fixture = 50.000
V_fixture = 0.000
V_fixture_min = 0.000
V_fixture_max = 0.000
|  time   V(typ)   V(min)   V(max)
0s        443.5mV    417mV      463.8mV
363ps     442.8mV    416.8mV    470.4mV
390ps     444.1mV    416.7mV    416.6mV
472ps     434.6mV    418mV      145.5mV
567ps     162.3mV    426.6mV    38.24mV
630ps     68.31mV    329.8mV    17.58mV
725ps     19.72mV    115.1mV    7.035mV
845ps     5.753mV    25.22mV    3.319mV
1.49ns    755.3uV    1.339mV    293.7uV
30ns      4.276uV    475.2uV    -82.95uV
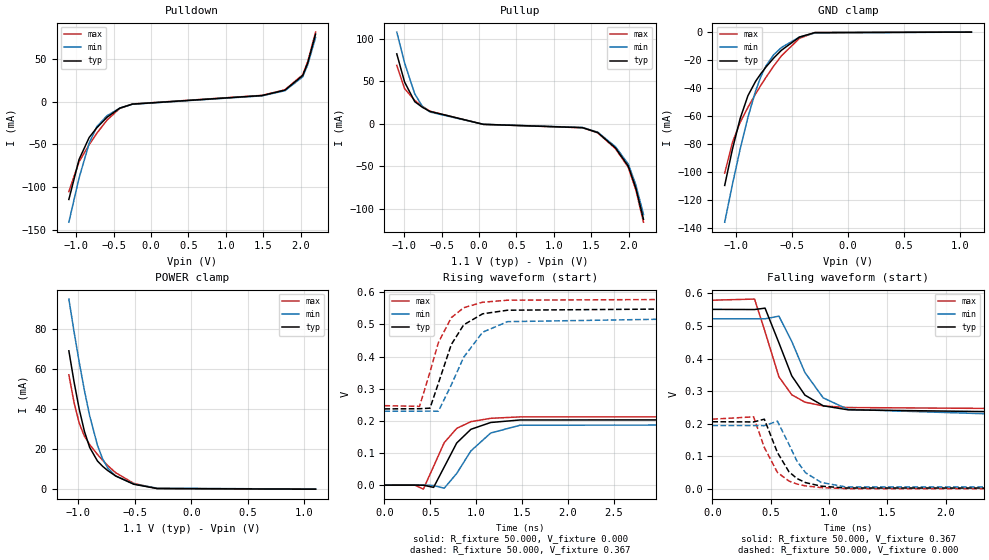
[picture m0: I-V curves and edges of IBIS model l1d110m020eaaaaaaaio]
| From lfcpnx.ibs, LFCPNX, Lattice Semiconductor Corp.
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|   Model l1d110m020eaaaaaaaio
[Model] l1d110m020eaaaaaaaio
| Clamp models do not include dynamic input termination. Please refer to
| the l1d110axxxeaaaaaaain model for input termination.
Model_type I/O
Polarity   Non-Inverting
Enable   Active-Low
Vinl =  0.093V
Vinh =  0.273V
Vmeas =  0.183V
Cref =  30.000pF
Rref =  50.000
Vref =  0.183V
C_comp   5.000pF   4.000pF   5.500pF
[Temperature Range]   25.000   0.125k   -40.000
[Voltage Range]   1.100V   1.050V   1.160V
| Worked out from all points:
|   slope of the pulldown table from 0 to 0.165 V, typ, clamps not added: 88.9 ohm
|   slope of the pullup table from 0 to 0.165 V, typ, clamps not added: 97.1 ohm
|   GND clamp passes 1 mA (typ) near -0.34 V on its own axis
|   POWER clamp passes 1 mA (typ) near -0.40 V on its own axis
|   rising waveform, R_fixture 50.000, V_fixture 0.000: 20-80 % time 270ps typ, 329ps min, 249ps max; typ from 0 V to 0.206 V
|   rising waveform, R_fixture 50.000, V_fixture 0.367: 20-80 % time 261ps typ, 328ps min, 243ps max; typ from 0.237 V to 0.551 V
|   falling waveform, R_fixture 50.000, V_fixture 0.367: 20-80 % time 233ps typ, 256ps min, 189ps max; typ from 0.551 V to 0.237 V
|   falling waveform, R_fixture 50.000, V_fixture 0.000: 20-80 % time 192ps typ, 199ps min, 174ps max; typ from 0.206 V to 0 V
[GND_clamp]
|Voltage   I(typ)   I(min)   I(max)
-1.1V     -109.7mA   -136mA     -100.9mA
-1.031V   -83.8mA    -108.9mA   -78.96mA
-962mV    -61.77mA   -83.67mA   -64.53mA
-893mV    -45.54mA   -61.02mA   -53.87mA
-824mV    -35.15mA   -42.04mA   -44.15mA
-778mV    -29.8mA    -31.96mA   -38.11mA
-732mV    -24.99mA   -24.15mA   -32.36mA
-663mV    -18.58mA   -16.21mA   -24.28mA
-594mV    -12.99mA   -11.04mA   -16.99mA
-433mV    -3.55mA    -3.535mA   -4.455mA
-295mV    -346.2uA   -626.8uA   -308.3uA
1.1V      0A         0A         0A
[POWER_clamp]
|Voltage   I(typ)   I(min)   I(max)
-1.085V   69.26mA    95.18mA    57.25mA
-1.039V   53.71mA    78.84mA    43.39mA
-993mV    40.01mA    63.46mA    33.04mA
-947mV    28.89mA    49.34mA    26.51mA
-901mV    20.94mA    36.82mA    22.35mA
-832mV    14.13mA    21.98mA    17.41mA
-786mV    11.43mA    15.15mA    14.47mA
-740mV    9.291mA    10.59mA    11.78mA
-671mV    6.617mA    6.611mA    8.279mA
-510mV    2.46mA     2.588mA    2.889mA
-303mV    307uA      515.1uA    269.4uA
1.1V      0A         0A         0A
[Pulldown]
|Voltage   I(typ)   I(min)   I(max)
-1.1V     -114.2mA   -140.7mA   -105.1mA
-964mV    -67.68mA   -89.34mA   -70.29mA
-828mV    -41.92mA   -48.54mA   -50.2mA
-726mV    -30.58mA   -29.27mA   -37.04mA
-590mV    -18.42mA   -16.59mA   -21.71mA
-420mV    -7.732mA   -7.771mA   -8.109mA
-250mV    -3.069mA   -3.175mA   -2.868mA
1.484V    6.95mA     6.603mA    7.159mA
1.79V     13.25mA    12.58mA    13.64mA
2.028V    30.31mA    28.79mA    31.22mA
2.096V    45.32mA    43.06mA    46.68mA
2.2V      78.56mA    74.63mA    80.92mA
[Pullup]
|Voltage   I(typ)   I(min)   I(max)
-1.1V     82.28mA    107.9mA    68.76mA
-996mV    49.24mA    71.8mA     41.39mA
-860mV    26.07mA    35.32mA    27.55mA
-758mV    19.43mA    20.46mA    20.54mA
-656mV    14.57mA    13.85mA    14.74mA
58mV      -657.6uA   -624.7uA   -677.3uA
1.384V    -4.554mA   -4.326mA   -4.691mA
1.588V    -10.36mA   -9.842mA   -10.67mA
1.826V    -28.5mA    -27.08mA   -29.36mA
1.996V    -49.79mA   -47.3mA    -51.28mA
2.098V    -75.72mA   -71.94mA   -77.99mA
2.2V      -112.4mA   -106.8mA   -115.8mA
[Ramp]
| variable   typ   min   max
dV/dt_r   0.124/0.269n   0.114/0.327n   0.129/0.248n
dV/dt_f   0.174/0.289n   0.165/0.324n   0.182/0.248n
R_load = 50.000
[Rising Waveform]
R_fixture = 50.000
V_fixture = 0.000
V_fixture_min = 0.000
V_fixture_max = 0.000
|  time   V(typ)   V(min)   V(max)
0s        4.368uV    140.6uV    -171.7uV
328ps     44.14uV    227uV      593.3uV
424ps     -341.4uV   251.8uV    -12.62mV
536ps     -7.011mV   -1.378mV   58.27mV
652ps     56.38mV    -9.657mV   132.2mV
788ps     131mV      36.2mV     176.5mV
943ps     173.7mV    106.5mV    197.5mV
1.159ns   194.9mV    162.1mV    207.9mV
1.48ns    202.7mV    186.4mV    212.3mV
30ns      206.5mV    194.9mV    214.3mV
[Rising Waveform]
R_fixture = 50.000
V_fixture = 0.367
V_fixture_min = 0.350
V_fixture_max = 0.386
|  time   V(typ)   V(min)   V(max)
0s        237.2mV    230mV      247.3mV
383ps     237.7mV    230.1mV    245.1mV
497ps     239.5mV    230.3mV    352.1mV
589ps     317.6mV    230mV      444mV
729ps     437.4mV    311.8mV    521mV
864ps     498.7mV    397.9mV    552mV
1.071ns   533.1mV    475.9mV    569.1mV
1.343ns   544.3mV    508.7mV    575.5mV
4.21ns    550.4mV    521.6mV    579mV
30ns      550.8mV    522.1mV    579mV
[Falling Waveform]
R_fixture = 50.000
V_fixture = 0.367
V_fixture_min = 0.350
V_fixture_max = 0.386
|  time   V(typ)   V(min)   V(max)
0s        550.9mV    522.1mV    579mV
362ps     550.4mV    522mV      582.5mV
452ps     554.7mV    521.9mV    482.3mV
571ps     448.1mV    530.2mV    344.1mV
681ps     347.2mV    452.7mV    289.2mV
794ps     288.1mV    357.3mV    266.5mV
951ps     255.4mV    279.6mV    254.9mV
1.164ns   243mV      244.3mV    250mV
2.38ns    237.4mV    230.5mV    247.3mV
30ns      237.2mV    230mV      247.3mV
[Falling Waveform]
R_fixture = 50.000
V_fixture = 0.000
V_fixture_min = 0.000
V_fixture_max = 0.000
|  time   V(typ)   V(min)   V(max)
0s        206.5mV    194.9mV    214.3mV
354ps     205.9mV    194.7mV    221.5mV
446ps     214.3mV    194.5mV    127.5mV
558ps     112.2mV    208.2mV    51.08mV
657ps     53.18mV    137.3mV    24.7mV
725ps     32.61mV    86.16mV    15.66mV
799ps     19.9mV     50.33mV    9.862mV
934ps     9.052mV    20.36mV    4.558mV
1.141ns   3.41mV     6.835mV    1.578mV
30ns      4.882uV    140.6uV    -171.7uV
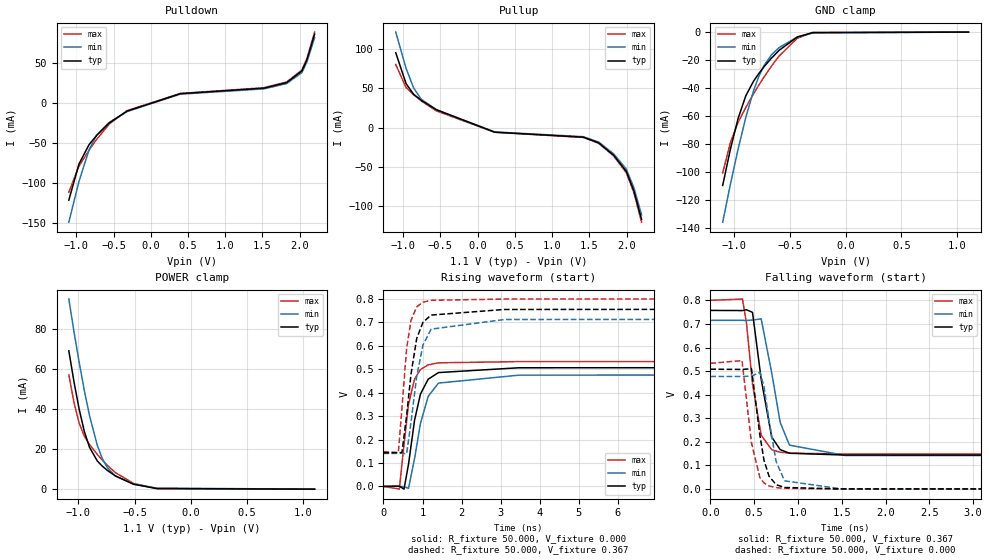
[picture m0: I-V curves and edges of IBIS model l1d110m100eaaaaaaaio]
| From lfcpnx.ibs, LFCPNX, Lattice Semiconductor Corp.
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|   Model l1d110m100eaaaaaaaio
[Model] l1d110m100eaaaaaaaio
| Clamp models do not include dynamic input termination. Please refer to
| the l1d110axxxeaaaaaaain model for input termination.
Model_type I/O
Polarity   Non-Inverting
Enable   Active-Low
Vinl =  0.093V
Vinh =  0.273V
Vmeas =  0.183V
Cref =  30.000pF
Rref =  50.000
Vref =  0.183V
C_comp   5.000pF   4.000pF   5.500pF
[Temperature Range]   25.000   0.125k   -40.000
[Voltage Range]   1.100V   1.050V   1.160V
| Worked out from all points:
|   slope of the pulldown table from 0 to 0.165 V, typ, clamps not added: 32.2 ohm
|   slope of the pullup table from 0 to 0.165 V, typ, clamps not added: 36.7 ohm
|   GND clamp passes 1 mA (typ) near -0.34 V on its own axis
|   POWER clamp passes 1 mA (typ) near -0.40 V on its own axis
|   rising waveform, R_fixture 50.000, V_fixture 0.000: 20-80 % time 326ps typ, 365ps min, 244ps max; typ from 0 V to 0.508 V
|   rising waveform, R_fixture 50.000, V_fixture 0.367: 20-80 % time 286ps typ, 312ps min, 206ps max; typ from 0.143 V to 0.757 V
|   falling waveform, R_fixture 50.000, V_fixture 0.367: 20-80 % time 134ps typ, 157ps min, 123ps max; typ from 0.757 V to 0.143 V
|   falling waveform, R_fixture 50.000, V_fixture 0.000: 20-80 % time 114ps typ, 131ps min, 106ps max; typ from 0.508 V to 0 V
[GND_clamp]
|Voltage   I(typ)   I(min)   I(max)
-1.1V     -109.7mA   -136mA     -100.9mA
-1.031V   -83.8mA    -108.9mA   -78.96mA
-962mV    -61.77mA   -83.67mA   -64.53mA
-893mV    -45.54mA   -61.02mA   -53.87mA
-824mV    -35.15mA   -42.04mA   -44.15mA
-778mV    -29.8mA    -31.96mA   -38.11mA
-732mV    -24.99mA   -24.15mA   -32.36mA
-663mV    -18.58mA   -16.21mA   -24.28mA
-594mV    -12.99mA   -11.04mA   -16.99mA
-433mV    -3.55mA    -3.535mA   -4.455mA
-295mV    -346.2uA   -626.8uA   -308.3uA
1.1V      0A         0A         0A
[POWER_clamp]
|Voltage   I(typ)   I(min)   I(max)
-1.085V   69.26mA    95.18mA    57.25mA
-1.039V   53.71mA    78.84mA    43.39mA
-993mV    40.01mA    63.46mA    33.04mA
-947mV    28.89mA    49.34mA    26.51mA
-901mV    20.94mA    36.82mA    22.35mA
-832mV    14.13mA    21.98mA    17.41mA
-786mV    11.43mA    15.15mA    14.47mA
-740mV    9.291mA    10.59mA    11.78mA
-671mV    6.617mA    6.611mA    8.279mA
-510mV    2.46mA     2.588mA    2.889mA
-303mV    307uA      515.1uA    269.4uA
1.1V      0A         0A         0A
[Pulldown]
|Voltage   I(typ)   I(min)   I(max)
-1.1V     -122.1mA   -149.6mA   -112.3mA
-964mV    -76.94mA   -98.78mA   -79.46mA
-828mV    -52.63mA   -59.02mA   -59.47mA
-726mV    -41.11mA   -40.51mA   -46.12mA
-556mV    -25.32mA   -24.84mA   -26.8mA
-318mV    -10.78mA   -11.34mA   -10.12mA
396mV     11.02mA    10.47mA    11.35mA
1.518V    17.95mA    17.05mA    18.49mA
1.824V    24.9mA     23.66mA    25.65mA
2.028V    39.34mA    37.38mA    40.52mA
2.096V    53.27mA    50.61mA    54.87mA
2.2V      85.49mA    81.21mA    88.05mA
[Pullup]
|Voltage   I(typ)   I(min)   I(max)
-1.1V     95.25mA    121.5mA    80.27mA
-962mV    56.01mA    75.48mA    51mA
-860mV    42.29mA    50.45mA    41.82mA
-758mV    34.74mA    36.01mA    33.93mA
-554mV    22.7mA     22.63mA    21.2mA
228mV     -5.849mA   -5.557mA   -6.025mA
1.418V    -12.2mA    -11.59mA   -12.57mA
1.622V    -19.29mA   -18.33mA   -19.87mA
1.826V    -35.25mA   -33.48mA   -36.3mA
1.996V    -55.91mA   -53.12mA   -57.59mA
2.098V    -80.86mA   -76.81mA   -83.28mA
2.2V      -116.9mA   -111.1mA   -120.4mA
[Ramp]
| variable   typ   min   max
dV/dt_r   0.305/0.325n   0.296/0.364n   0.320/0.244n
dV/dt_f   0.375/0.190n   0.361/0.214n   0.385/0.177n
R_load = 50.000
[Rising Waveform]
R_fixture = 50.000
V_fixture = 0.000
V_fixture_min = 0.000
V_fixture_max = 0.000
|  time   V(typ)   V(min)   V(max)
0s        2.583uV    349.1uV    -317.2uV
406ps     1.081mV    375.2uV    -11.29mV
526ps     -11.91mV   -1.366mV   178.3mV
642ps     95.52mV    -8.399mV   350.7mV
795ps     281.9mV    118.5mV    458.2mV
946ps     393.9mV    268.5mV    499.1mV
1.145ns   457.8mV    384.6mV    519mV
1.408ns   486.1mV    441.1mV    527.8mV
3.46ns    506.6mV    475mV      533mV
30ns      508.2mV    477.4mV    533mV
[Rising Waveform]
R_fixture = 50.000
V_fixture = 0.367
V_fixture_min = 0.350
V_fixture_max = 0.386
|  time   V(typ)   V(min)   V(max)
0s        143.3mV    140.9mV    148.2mV
381ps     143.8mV    140.9mV    144.6mV
473ps     144.4mV    141.7mV    333.6mV
592ps     301.7mV    138.7mV    588.4mV
706ps     481mV      275.4mV    709.6mV
851ps     631.9mV    469.5mV    766.9mV
1.011ns   701mV      604mV      786.7mV
1.219ns   731.7mV    671.6mV    794.7mV
3.094ns   755.7mV    712.8mV    800.1mV
30ns      757.2mV    715.2mV    800.1mV
[Falling Waveform]
R_fixture = 50.000
V_fixture = 0.367
V_fixture_min = 0.350
V_fixture_max = 0.386
|  time   V(typ)   V(min)   V(max)
0s        757.3mV    715.2mV    800.1mV
366ps     756.6mV    715.2mV    805.4mV
411ps     760.3mV    714.9mV    706.2mV
481ps     749mV      716.4mV    444.8mV
580ps     465.8mV    721.4mV    228.4mV
700ps     220.6mV    493.1mV    166.9mV
797ps     167.3mV    282.6mV    156.2mV
903ps     151.9mV    186.3mV    152.5mV
1.544ns   144.2mV    142.2mV    148.7mV
30ns      143.3mV    140.9mV    148.2mV
[Falling Waveform]
R_fixture = 50.000
V_fixture = 0.000
V_fixture_min = 0.000
V_fixture_max = 0.000
|  time   V(typ)   V(min)   V(max)
0s        508.2mV    477.4mV    533mV
361ps     507.1mV    477.3mV    544.7mV
469ps     510.2mV    478.6mV    196.5mV
565ps     229.2mV    495.2mV    48.68mV
612ps     122.2mV    435.1mV    25.93mV
670ps     54.37mV    289.8mV    13.13mV
751ps     18.67mV    116.4mV    6.237mV
847ps     6.735mV    34.97mV    3.362mV
1.488ns   791.4uV    1.296mV    89.8uV
30ns      3.916uV    349.1uV    -317.2uV
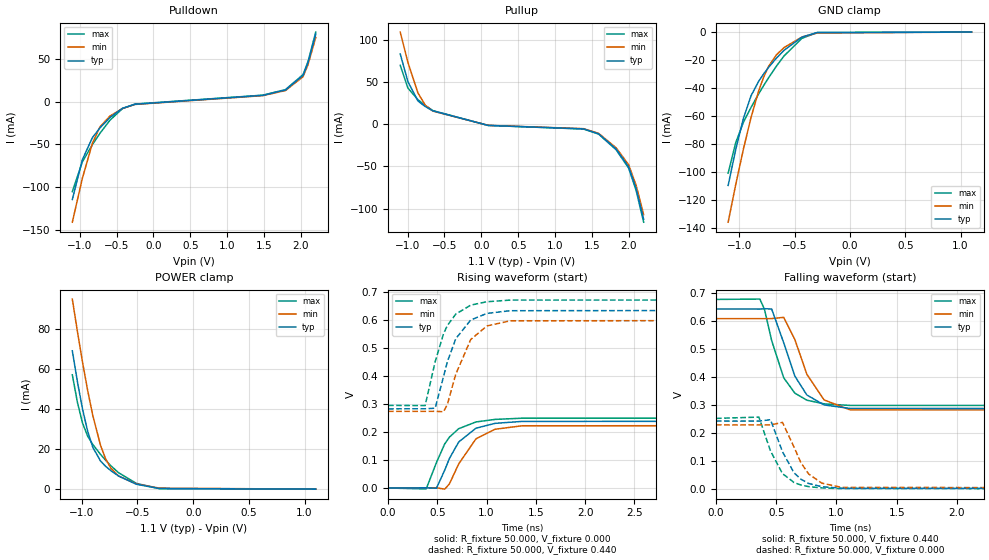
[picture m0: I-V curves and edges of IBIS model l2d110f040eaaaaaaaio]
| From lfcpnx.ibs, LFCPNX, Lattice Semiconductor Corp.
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|   Model l2d110f040eaaaaaaaio
[Model] l2d110f040eaaaaaaaio
| Clamp models do not include dynamic input termination. Please refer to
| the l2d110axxxeaaaaaaain model for input termination.
Model_type I/O
Polarity   Non-Inverting
Enable   Active-Low
Vinl =  0.130V
Vinh =  0.310V
Vmeas =  0.220V
Cref =  30.000pF
Rref =  50.000
Vref =  0.220V
C_comp   5.000pF   4.000pF   5.500pF
[Temperature Range]   25.000   0.125k   -40.000
[Voltage Range]   1.100V   1.050V   1.160V
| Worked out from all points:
|   slope of the pulldown table from 0 to 0.165 V, typ, clamps not added: 85.8 ohm
|   slope of the pullup table from 0 to 0.165 V, typ, clamps not added: 82.8 ohm
|   GND clamp passes 1 mA (typ) near -0.34 V on its own axis
|   POWER clamp passes 1 mA (typ) near -0.40 V on its own axis
|   rising waveform, R_fixture 50.000, V_fixture 0.000: 20-80 % time 239ps typ, 253ps min, 224ps max; typ from 0 V to 0.242 V
|   rising waveform, R_fixture 50.000, V_fixture 0.440: 20-80 % time 214ps typ, 224ps min, 204ps max; typ from 0.283 V to 0.641 V
|   falling waveform, R_fixture 50.000, V_fixture 0.440: 20-80 % time 186ps typ, 196ps min, 170ps max; typ from 0.641 V to 0.283 V
|   falling waveform, R_fixture 50.000, V_fixture 0.000: 20-80 % time 166ps typ, 169ps min, 156ps max; typ from 0.242 V to 0 V
[GND_clamp]
|Voltage   I(typ)   I(min)   I(max)
-1.1V     -109.7mA   -136mA     -100.9mA
-1.031V   -83.8mA    -108.9mA   -78.96mA
-962mV    -61.77mA   -83.67mA   -64.53mA
-893mV    -45.54mA   -61.02mA   -53.87mA
-824mV    -35.15mA   -42.04mA   -44.15mA
-778mV    -29.8mA    -31.96mA   -38.11mA
-732mV    -24.99mA   -24.15mA   -32.36mA
-663mV    -18.58mA   -16.21mA   -24.28mA
-594mV    -12.99mA   -11.04mA   -16.99mA
-433mV    -3.55mA    -3.535mA   -4.455mA
-295mV    -346.2uA   -626.8uA   -308.3uA
1.1V      0A         0A         0A
[POWER_clamp]
|Voltage   I(typ)   I(min)   I(max)
-1.085V   69.26mA    95.18mA    57.25mA
-1.039V   53.71mA    78.84mA    43.39mA
-993mV    40.01mA    63.46mA    33.04mA
-947mV    28.89mA    49.34mA    26.51mA
-901mV    20.94mA    36.82mA    22.35mA
-832mV    14.13mA    21.98mA    17.41mA
-786mV    11.43mA    15.15mA    14.47mA
-740mV    9.291mA    10.59mA    11.78mA
-671mV    6.617mA    6.611mA    8.279mA
-510mV    2.46mA     2.588mA    2.889mA
-303mV    307uA      515.1uA    269.4uA
1.1V      0A         0A         0A
[Pulldown]
|Voltage   I(typ)   I(min)   I(max)
-1.1V     -114.4mA   -140.9mA   -105.2mA
-964mV    -67.9mA    -89.61mA   -70.41mA
-828mV    -42.17mA   -48.86mA   -50.32mA
-726mV    -30.81mA   -29.63mA   -37.15mA
-590mV    -18.63mA   -16.95mA   -21.81mA
-420mV    -7.901mA   -8.077mA   -8.192mA
-250mV    -3.175mA   -3.376mA   -2.921mA
1.484V    7.256mA    6.893mA    7.474mA
1.79V     13.54mA    12.87mA    13.95mA
2.028V    30.56mA    29.03mA    31.48mA
2.096V    45.55mA    43.27mA    46.91mA
2.2V      78.76mA    74.82mA    81.12mA
[Pullup]
|Voltage   I(typ)   I(min)   I(max)
-1.1V     83.67mA    109.7mA    70.22mA
-996mV    50.77mA    73.67mA    43.16mA
-860mV    27.81mA    37.34mA    29.4mA
-758mV    21.07mA    22.54mA    22.29mA
-656mV    16.05mA    15.8mA     16.35mA
92mV      -1.187mA   -1.128mA   -1.223mA
1.384V    -5.333mA   -5.066mA   -5.493mA
1.588V    -11.11mA   -10.55mA   -11.44mA
1.826V    -29.22mA   -27.75mA   -30.09mA
1.996V    -50.43mA   -47.91mA   -51.95mA
2.098V    -76.26mA   -72.45mA   -78.55mA
2.2V      -112.8mA   -107.2mA   -116.2mA
[Ramp]
| variable   typ   min   max
dV/dt_r   0.145/0.239n   0.142/0.252n   0.151/0.223n
dV/dt_f   0.181/0.229n   0.173/0.241n   0.189/0.217n
R_load = 50.000
[Rising Waveform]
R_fixture = 50.000
V_fixture = 0.000
V_fixture_min = 0.000
V_fixture_max = 0.000
|  time   V(typ)   V(min)   V(max)
0s        4.31uV     240uV      -223.7uV
387ps     453uV      258.9uV    -3.52mV
491ps     -950.2uV   691.1uV    90.71mV
575ps     63.71mV    -4.335mV   157.4mV
623ps     105.5mV    14.77mV    181.9mV
717ps     164.3mV    86mV       211.9mV
892ps     213.6mV    175.6mV    236mV
1.086ns   231mV      209.9mV    245.1mV
1.359ns   237.9mV    222.2mV    249.4mV
30ns      242.3mV    228.6mV    251.8mV
[Rising Waveform]
R_fixture = 50.000
V_fixture = 0.440
V_fixture_min = 0.419
V_fixture_max = 0.463
|  time   V(typ)   V(min)   V(max)
0s        282.8mV    273.9mV    295.1mV
376ps     283.1mV    273.9mV    294.6mV
478ps     285.2mV    274.1mV    451.2mV
563ps     398.3mV    272.5mV    551.6mV
602ps     451.3mV    298.9mV    580.8mV
687ps     533.4mV    406.6mV    621.6mV
839ps     600.6mV    530.8mV    653.7mV
1.004ns   624.2mV    579.4mV    665.9mV
1.241ns   633.8mV    597.6mV    671.7mV
30ns      641.3mV    607.1mV    675.4mV
[Falling Waveform]
R_fixture = 50.000
V_fixture = 0.440
V_fixture_min = 0.419
V_fixture_max = 0.463
|  time   V(typ)   V(min)   V(max)
0s        641.4mV    607.1mV    675.4mV
364ps     641.1mV    606.9mV    676.7mV
402ps     642.4mV    606.8mV    640.7mV
462ps     641.3mV    607.2mV    528.9mV
562ps     520.9mV    611.6mV    396.4mV
654ps     402.7mV    533.2mV    341.9mV
754ps     335.2mV    409.1mV    316.6mV
897ps     299.7mV    317.5mV    303.5mV
1.111ns   287.3mV    282.4mV    298mV
30ns      282.8mV    273.9mV    295.1mV
[Falling Waveform]
R_fixture = 50.000
V_fixture = 0.000
V_fixture_min = 0.000
V_fixture_max = 0.000
|  time   V(typ)   V(min)   V(max)
0s        242.4mV    228.6mV    251.8mV
356ps     242mV      228.4mV    256.4mV
452ps     247.2mV    228.6mV    136.3mV
552ps     132.7mV    237.5mV    55.01mV
648ps     57.95mV    149.4mV    23.42mV
705ps     35.1mV     93.66mV    14.54mV
770ps     20.05mV    53.63mV    8.781mV
878ps     8.462mV    21.28mV    4.218mV
1.047ns   2.921mV    5.735mV    1.685mV
30ns      5.241uV    240uV      -223.7uV
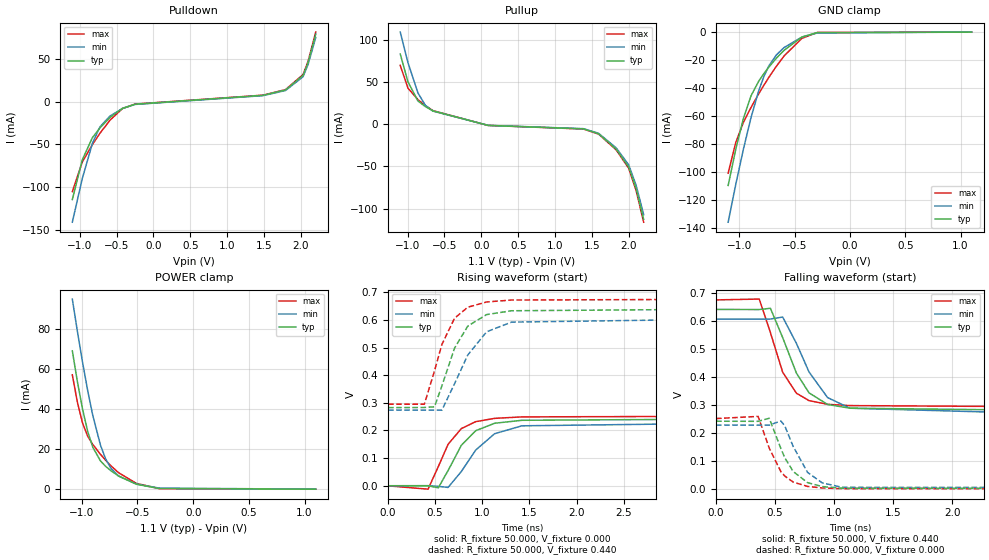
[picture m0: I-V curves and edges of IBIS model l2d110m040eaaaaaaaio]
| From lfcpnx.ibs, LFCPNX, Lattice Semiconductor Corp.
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|   Model l2d110m040eaaaaaaaio
[Model] l2d110m040eaaaaaaaio
| Clamp models do not include dynamic input termination. Please refer to
| the l2d110axxxeaaaaaaain model for input termination.
Model_type I/O
Polarity   Non-Inverting
Enable   Active-Low
Vinl =  0.130V
Vinh =  0.310V
Vmeas =  0.220V
Cref =  30.000pF
Rref =  50.000
Vref =  0.220V
C_comp   5.000pF   4.000pF   5.500pF
[Temperature Range]   25.000   0.125k   -40.000
[Voltage Range]   1.100V   1.050V   1.160V
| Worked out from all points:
|   slope of the pulldown table from 0 to 0.165 V, typ, clamps not added: 85.8 ohm
|   slope of the pullup table from 0 to 0.165 V, typ, clamps not added: 82.8 ohm
|   GND clamp passes 1 mA (typ) near -0.34 V on its own axis
|   POWER clamp passes 1 mA (typ) near -0.40 V on its own axis
|   rising waveform, R_fixture 50.000, V_fixture 0.000: 20-80 % time 279ps typ, 336ps min, 245ps max; typ from 0 V to 0.242 V
|   rising waveform, R_fixture 50.000, V_fixture 0.440: 20-80 % time 260ps typ, 318ps min, 231ps max; typ from 0.283 V to 0.641 V
|   falling waveform, R_fixture 50.000, V_fixture 0.440: 20-80 % time 226ps typ, 250ps min, 187ps max; typ from 0.641 V to 0.283 V
|   falling waveform, R_fixture 50.000, V_fixture 0.000: 20-80 % time 179ps typ, 184ps min, 163ps max; typ from 0.242 V to 0 V
[GND_clamp]
|Voltage   I(typ)   I(min)   I(max)
-1.1V     -109.7mA   -136mA     -100.9mA
-1.031V   -83.8mA    -108.9mA   -78.96mA
-962mV    -61.77mA   -83.67mA   -64.53mA
-893mV    -45.54mA   -61.02mA   -53.87mA
-824mV    -35.15mA   -42.04mA   -44.15mA
-778mV    -29.8mA    -31.96mA   -38.11mA
-732mV    -24.99mA   -24.15mA   -32.36mA
-663mV    -18.58mA   -16.21mA   -24.28mA
-594mV    -12.99mA   -11.04mA   -16.99mA
-433mV    -3.55mA    -3.535mA   -4.455mA
-295mV    -346.2uA   -626.8uA   -308.3uA
1.1V      0A         0A         0A
[POWER_clamp]
|Voltage   I(typ)   I(min)   I(max)
-1.085V   69.26mA    95.18mA    57.25mA
-1.039V   53.71mA    78.84mA    43.39mA
-993mV    40.01mA    63.46mA    33.04mA
-947mV    28.89mA    49.34mA    26.51mA
-901mV    20.94mA    36.82mA    22.35mA
-832mV    14.13mA    21.98mA    17.41mA
-786mV    11.43mA    15.15mA    14.47mA
-740mV    9.291mA    10.59mA    11.78mA
-671mV    6.617mA    6.611mA    8.279mA
-510mV    2.46mA     2.588mA    2.889mA
-303mV    307uA      515.1uA    269.4uA
1.1V      0A         0A         0A
[Pulldown]
|Voltage   I(typ)   I(min)   I(max)
-1.1V     -114.4mA   -140.9mA   -105.2mA
-964mV    -67.9mA    -89.61mA   -70.41mA
-828mV    -42.17mA   -48.86mA   -50.32mA
-726mV    -30.81mA   -29.63mA   -37.15mA
-590mV    -18.63mA   -16.95mA   -21.81mA
-420mV    -7.901mA   -8.076mA   -8.192mA
-250mV    -3.175mA   -3.376mA   -2.921mA
1.484V    7.256mA    6.893mA    7.474mA
1.79V     13.54mA    12.87mA    13.95mA
2.028V    30.56mA    29.03mA    31.48mA
2.096V    45.55mA    43.27mA    46.91mA
2.2V      78.76mA    74.82mA    81.12mA
[Pullup]
|Voltage   I(typ)   I(min)   I(max)
-1.1V     83.67mA    109.7mA    70.22mA
-996mV    50.77mA    73.67mA    43.16mA
-860mV    27.81mA    37.34mA    29.4mA
-758mV    21.07mA    22.54mA    22.29mA
-656mV    16.05mA    15.8mA     16.35mA
92mV      -1.187mA   -1.128mA   -1.223mA
1.384V    -5.333mA   -5.066mA   -5.493mA
1.588V    -11.11mA   -10.55mA   -11.44mA
1.826V    -29.22mA   -27.75mA   -30.09mA
1.996V    -50.43mA   -47.91mA   -51.95mA
2.098V    -76.26mA   -72.45mA   -78.55mA
2.2V      -112.8mA   -107.2mA   -116.2mA
[Ramp]
| variable   typ   min   max
dV/dt_r   0.145/0.278n   0.142/0.335n   0.151/0.244n
dV/dt_f   0.181/0.273n   0.173/0.309n   0.189/0.233n
R_load = 50.000
[Rising Waveform]
R_fixture = 50.000
V_fixture = 0.000
V_fixture_min = 0.000
V_fixture_max = 0.000
|  time   V(typ)   V(min)   V(max)
0s        4.31uV     240uV      -223.7uV
424ps     54.97uV    389.6uV    -12.23mV
533ps     -7.26mV    -2.01mV    69.24mV
637ps     55.07mV    -5.907mV   150.1mV
778ps     146.6mV    51.79mV    207mV
930ps     199.2mV    129.2mV    231.9mV
1.131ns   226.2mV    188.4mV    243.9mV
1.421ns   236.9mV    216.9mV    249.2mV
4.105ns   242.2mV    228.2mV    251.8mV
30ns      242.3mV    228.6mV    251.8mV
[Rising Waveform]
R_fixture = 50.000
V_fixture = 0.440
V_fixture_min = 0.419
V_fixture_max = 0.463
|  time   V(typ)   V(min)   V(max)
0s        282.8mV    273.9mV    295.1mV
385ps     283.2mV    273.9mV    295.1mV
493ps     285.8mV    273.7mV    415.8mV
571ps     361mV      273.4mV    511mV
706ps     498.3mV    369.5mV    606.3mV
846ps     577.6mV    473.1mV    645.9mV
1.046ns   619.3mV    557mV      664.9mV
1.31ns    633.1mV    592mV      671.9mV
4.375ns   640.7mV    606.4mV    675.4mV
30ns      641.3mV    607.1mV    675.4mV
[Falling Waveform]
R_fixture = 50.000
V_fixture = 0.440
V_fixture_min = 0.419
V_fixture_max = 0.463
|  time   V(typ)   V(min)   V(max)
0s        641.4mV    607.1mV    675.4mV
366ps     641mV      607mV      678.4mV
461ps     645.5mV    607.1mV    558.5mV
565ps     540.8mV    614.2mV    417.3mV
681ps     414.3mV    520.4mV    342.4mV
788ps     343.7mV    418.2mV    315.9mV
945ps     302.2mV    326.8mV    302.6mV
1.134ns   288.8mV    288.8mV    298.1mV
2.366ns   283.1mV    274.4mV    295.1mV
30ns      282.8mV    273.9mV    295.1mV
[Falling Waveform]
R_fixture = 50.000
V_fixture = 0.000
V_fixture_min = 0.000
V_fixture_max = 0.000
|  time   V(typ)   V(min)   V(max)
0s        242.4mV    228.6mV    251.8mV
357ps     241.9mV    228.4mV    259.5mV
451ps     252.9mV    228.4mV    146.4mV
550ps     144.4mV    243.2mV    61.94mV
583ps     111.8mV    225.5mV    46.29mV
654ps     62.77mV    152.1mV    25.07mV
776ps     23.08mV    59.5mV     9.48mV
899ps     9.033mV    22.4mV     4.117mV
1.069ns   3.153mV    6.452mV    1.633mV
30ns      5.248uV    240uV      -223.7uV
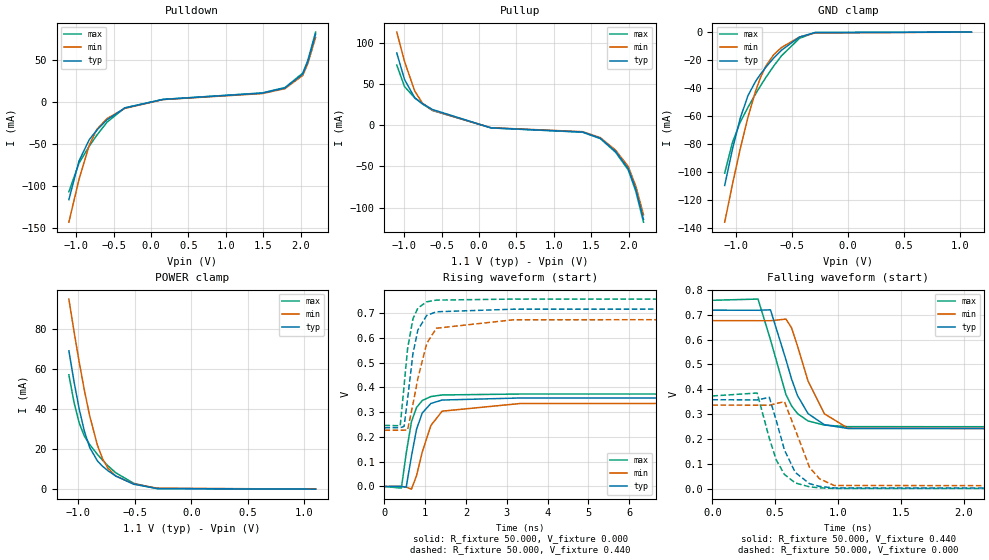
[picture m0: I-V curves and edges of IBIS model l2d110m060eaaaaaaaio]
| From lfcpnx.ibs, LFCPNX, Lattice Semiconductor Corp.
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|   Model l2d110m060eaaaaaaaio
[Model] l2d110m060eaaaaaaaio
| Clamp models do not include dynamic input termination. Please refer to
| the l2d110axxxeaaaaaaain model for input termination.
Model_type I/O
Polarity   Non-Inverting
Enable   Active-Low
Vinl =  0.130V
Vinh =  0.310V
Vmeas =  0.220V
Cref =  30.000pF
Rref =  50.000
Vref =  0.220V
C_comp   5.000pF   4.000pF   5.500pF
[Temperature Range]   25.000   0.125k   -40.000
[Voltage Range]   1.100V   1.050V   1.160V
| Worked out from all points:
|   slope of the pulldown table from 0 to 0.165 V, typ, clamps not added: 56.9 ohm
|   slope of the pullup table from 0 to 0.165 V, typ, clamps not added: 54.8 ohm
|   GND clamp passes 1 mA (typ) near -0.34 V on its own axis
|   POWER clamp passes 1 mA (typ) near -0.40 V on its own axis
|   rising waveform, R_fixture 50.000, V_fixture 0.000: 20-80 % time 280ps typ, 393ps min, 241ps max; typ from 0 V to 0.358 V
|   rising waveform, R_fixture 50.000, V_fixture 0.440: 20-80 % time 247ps typ, 375ps min, 211ps max; typ from 0.237 V to 0.718 V
|   falling waveform, R_fixture 50.000, V_fixture 0.440: 20-80 % time 187ps typ, 199ps min, 178ps max; typ from 0.718 V to 0.237 V
|   falling waveform, R_fixture 50.000, V_fixture 0.000: 20-80 % time 150ps typ, 159ps min, 144ps max; typ from 0.358 V to 0 V
[GND_clamp]
|Voltage   I(typ)   I(min)   I(max)
-1.1V     -109.7mA   -136mA     -100.9mA
-1.031V   -83.8mA    -108.9mA   -78.96mA
-962mV    -61.77mA   -83.67mA   -64.53mA
-893mV    -45.54mA   -61.02mA   -53.87mA
-824mV    -35.15mA   -42.04mA   -44.15mA
-778mV    -29.8mA    -31.96mA   -38.11mA
-732mV    -24.99mA   -24.15mA   -32.36mA
-663mV    -18.58mA   -16.21mA   -24.28mA
-594mV    -12.99mA   -11.04mA   -16.99mA
-433mV    -3.55mA    -3.535mA   -4.455mA
-295mV    -346.2uA   -626.8uA   -308.3uA
1.1V      0A         0A         0A
[POWER_clamp]
|Voltage   I(typ)   I(min)   I(max)
-1.085V   69.26mA    95.18mA    57.25mA
-1.039V   53.71mA    78.84mA    43.39mA
-993mV    40.01mA    63.46mA    33.04mA
-947mV    28.89mA    49.34mA    26.51mA
-901mV    20.94mA    36.82mA    22.35mA
-832mV    14.13mA    21.98mA    17.41mA
-786mV    11.43mA    15.15mA    14.47mA
-740mV    9.291mA    10.59mA    11.78mA
-671mV    6.617mA    6.611mA    8.279mA
-510mV    2.46mA     2.588mA    2.889mA
-303mV    307uA      515.1uA    269.4uA
1.1V      0A         0A         0A
[Pulldown]
|Voltage   I(typ)   I(min)   I(max)
-1.1V     -116.7mA   -143.6mA   -107.3mA
-964mV    -70.53mA   -92.37mA   -73.1mA
-828mV    -45.26mA   -51.9mA    -53.07mA
-726mV    -33.87mA   -32.89mA   -39.87mA
-590mV    -21.5mA    -20.06mA   -24.4mA
-352mV    -7.468mA   -7.88mA    -7.179mA
158mV     2.785mA    2.646mA    2.868mA
1.484V    10.27mA    9.758mA    10.58mA
1.79V     16.47mA    15.65mA    16.97mA
2.028V    33.09mA    31.44mA    34.09mA
2.096V    47.77mA    45.38mA    49.21mA
2.2V      80.7mA     76.67mA    83.12mA
[Pullup]
|Voltage   I(typ)   I(min)   I(max)
-1.1V     88.32mA    113.8mA    73.62mA
-996mV    55.91mA    77.94mA    47.29mA
-860mV    33.67mA    41.95mA    33.68mA
-758mV    26.63mA    27.31mA    26.33mA
-622mV    19.41mA    18.58mA    18.27mA
160mV     -2.933mA   -2.787mA   -3.021mA
1.384V    -7.973mA   -7.574mA   -8.212mA
1.622V    -15.55mA   -14.77mA   -16.02mA
1.826V    -31.64mA   -30.06mA   -32.59mA
1.996V    -52.63mA   -50mA      -54.21mA
2.098V    -78.1mA    -74.2mA    -80.45mA
2.2V      -114.5mA   -108.8mA   -117.9mA
[Ramp]
| variable   typ   min   max
dV/dt_r   0.215/0.279n   0.202/0.393n   0.224/0.240n
dV/dt_f   0.254/0.246n   0.247/0.268n   0.267/0.238n
R_load = 50.000
[Rising Waveform]
R_fixture = 50.000
V_fixture = 0.000
V_fixture_min = 0.000
V_fixture_max = 0.000
|  time   V(typ)   V(min)   V(max)
0s        3.587uV    95.7uV     -232.6uV
415ps     99.39uV    155.3uV    -6.462mV
533ps     -3.06mV    -2.387mV   133.2mV
663ps     122.3mV    -10.87mV   261.9mV
787ps     231mV      43.47mV    319mV
928ps     297.3mV    139.9mV    347.4mV
1.14ns    335.5mV    246.6mV    363.4mV
1.414ns   349.3mV    304.3mV    369.8mV
3.328ns   357.6mV    335.2mV    373.6mV
30ns      358.4mV    336.9mV    373.6mV
[Rising Waveform]
R_fixture = 50.000
V_fixture = 0.440
V_fixture_min = 0.419
V_fixture_max = 0.463
|  time   V(typ)   V(min)   V(max)
0s        237.2mV    227.2mV    246.7mV
387ps     237.8mV    227.2mV    245.4mV
481ps     242.6mV    227.6mV    406mV
567ps     353.4mV    228.1mV    556.3mV
699ps     536.7mV    332.3mV    677.6mV
820ps     632.4mV    436.8mV    721.2mV
1.036ns   691.2mV    577.7mV    746.1mV
1.273ns   705.9mV    639.4mV    753.1mV
3.164ns   716.4mV    673.6mV    757.3mV
30ns      717.7mV    675.6mV    757.3mV
[Falling Waveform]
R_fixture = 50.000
V_fixture = 0.440
V_fixture_min = 0.419
V_fixture_max = 0.463
|  time   V(typ)   V(min)   V(max)
0s        717.7mV    675.7mV    757.3mV
363ps     717.3mV    675.4mV    762.2mV
462ps     719.1mV    675.4mV    599.4mV
585ps     519.2mV    681.8mV    379.4mV
629ps     442.6mV    647.6mV    334.5mV
677ps     375.2mV    573.8mV    302.8mV
761ps     302.5mV    433.4mV    273.3mV
891ps     258.4mV    302mV      256.7mV
1.079ns   243mV      244mV      250.4mV
30ns      237.2mV    227.2mV    246.7mV
[Falling Waveform]
R_fixture = 50.000
V_fixture = 0.000
V_fixture_min = 0.000
V_fixture_max = 0.000
|  time   V(typ)   V(min)   V(max)
0s        358.5mV    337mV      373.6mV
356ps     357.7mV    336.5mV    385.4mV
453ps     367.9mV    336.3mV    203.6mV
508ps     275.3mV    343.2mV    117mV
573ps     157.3mV    350.8mV    59mV
659ps     66.84mV    238.6mV    24.73mV
773ps     21.8mV     87.07mV    9.096mV
852ps     10.84mV    41.35mV    5.172mV
969ps     4.693mV    14.49mV    2.647mV
30ns      5.304uV    102.2uV    -232.6uV
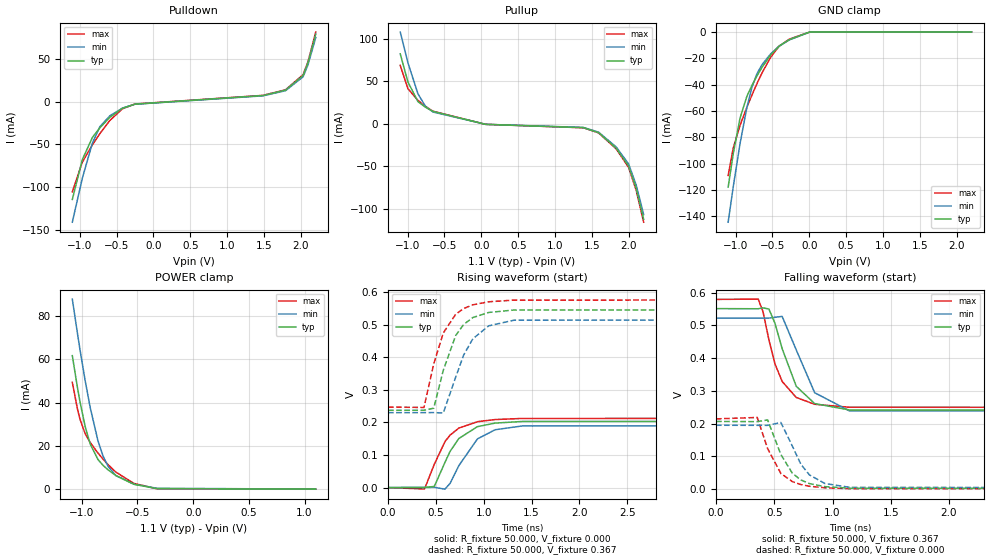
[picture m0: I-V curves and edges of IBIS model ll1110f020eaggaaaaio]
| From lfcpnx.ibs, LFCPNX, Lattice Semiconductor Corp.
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|   Model ll1110f020eaggaaaaio
[Model] ll1110f020eaggaaaaio
| Clamp models do not include dynamic input termination. Please refer to
| the ll1110axxxeaggaaaain model for input termination.
Model_type I/O
Polarity   Non-Inverting
Enable   Active-Low
Vinl =  0.093V
Vinh =  0.273V
Vmeas =  0.183V
Cref =  30.000pF
Rref =  50.000
Vref =  0.183V
C_comp   5.000pF   4.000pF   5.500pF
[Temperature Range]   25.000   0.125k   -40.000
[Voltage Range]   1.100V   1.050V   1.160V
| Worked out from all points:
|   slope of the pulldown table from 0 to 0.165 V, typ, clamps not added: 88.9 ohm
|   slope of the pullup table from 0 to 0.165 V, typ, clamps not added: 97.1 ohm
|   GND clamp passes 1 mA (typ) near -0.05 V on its own axis
|   POWER clamp passes 1 mA (typ) near -0.44 V on its own axis
|   rising waveform, R_fixture 50.000, V_fixture 0.000: 20-80 % time 246ps typ, 269ps min, 235ps max; typ from 0 V to 0.206 V
|   rising waveform, R_fixture 50.000, V_fixture 0.367: 20-80 % time 223ps typ, 248ps min, 218ps max; typ from 0.237 V to 0.551 V
|   falling waveform, R_fixture 50.000, V_fixture 0.367: 20-80 % time 193ps typ, 204ps min, 172ps max; typ from 0.551 V to 0.237 V
|   falling waveform, R_fixture 50.000, V_fixture 0.000: 20-80 % time 180ps typ, 187ps min, 167ps max; typ from 0.206 V to 0 V
[GND_clamp]
|Voltage   I(typ)   I(min)   I(max)
-1.1V     -117.8mA   -144.4mA   -108.9mA
-1.031V   -92.39mA   -117.5mA   -88.07mA
-939mV    -65.35mA   -84.74mA   -70.87mA
-847mV    -48.93mA   -57.47mA   -57.24mA
-778mV    -40.53mA   -42.1mA    -47.86mA
-709mV    -33.25mA   -31.59mA   -39.07mA
-640mV    -26.73mA   -24.69mA   -30.91mA
-525mV    -17.44mA   -16.67mA   -19.2mA
-410mV    -10.6mA    -10.77mA   -10.78mA
-272mV    -5.792mA   -5.969mA   -5.355mA
4mV       0A         0A         0A
2.2V      0A         0A         0A
[POWER_clamp]
|Voltage   I(typ)   I(min)   I(max)
-1.085V   61.74mA    87.92mA    49.38mA
-1.039V   46.98mA    72.04mA    37.07mA
-1.016V   40.35mA    64.47mA    32.31mA
-970mV    29.02mA    50.27mA    25.66mA
-924mV    20.79mA    37.6mA     21.51mA
-855mV    13.71mA    22.38mA    16.7mA
-809mV    10.99mA    15.25mA    13.85mA
-763mV    8.879mA    10.44mA    11.25mA
-694mV    6.274mA    6.278mA    7.853mA
-533mV    2.248mA    2.293mA    2.647mA
-326mV    216.7uA    380.5uA    177.7uA
1.1V      -16.31uA   -2.388uA   -25.69uA
[Pulldown]
|Voltage   I(typ)   I(min)   I(max)
-1.1V     -114.2mA   -140.7mA   -105.3mA
-964mV    -67.68mA   -89.34mA   -70.58mA
-828mV    -41.93mA   -48.55mA   -50.51mA
-726mV    -30.58mA   -29.28mA   -37.35mA
-590mV    -18.43mA   -16.59mA   -22.02mA
-420mV    -7.735mA   -7.773mA   -8.423mA
-250mV    -3.069mA   -3.175mA   -2.889mA
1.484V    6.95mA     6.603mA    7.159mA
1.79V     13.25mA    12.58mA    13.64mA
2.028V    30.31mA    28.79mA    31.22mA
2.096V    45.32mA    43.06mA    46.68mA
2.2V      78.56mA    74.63mA    80.92mA
[Pullup]
|Voltage   I(typ)   I(min)   I(max)
-1.1V     82.28mA    107.9mA    68.73mA
-996mV    49.24mA    71.8mA     41.37mA
-860mV    26.07mA    35.32mA    27.54mA
-758mV    19.43mA    20.46mA    20.55mA
-656mV    14.57mA    13.85mA    14.74mA
58mV      -657.6uA   -624.7uA   -677.3uA
1.384V    -4.554mA   -4.327mA   -4.691mA
1.588V    -10.36mA   -9.846mA   -10.68mA
1.826V    -28.51mA   -27.09mA   -29.37mA
1.996V    -49.8mA    -47.31mA   -51.29mA
2.098V    -75.73mA   -71.94mA   -78mA
2.2V      -112.4mA   -106.8mA   -115.8mA
[Ramp]
| variable   typ   min   max
dV/dt_r   0.124/0.245n   0.114/0.268n   0.128/0.234n
dV/dt_f   0.174/0.243n   0.165/0.255n   0.181/0.231n
R_load = 50.000
[Rising Waveform]
R_fixture = 50.000
V_fixture = 0.000
V_fixture_min = 0.000
V_fixture_max = 0.000
|  time   V(typ)   V(min)   V(max)
0s        4.368uV    140.6uV    -171.7uV
381ps     471.9uV    160.5uV    -4.343mV
483ps     3.413mV    784.2uV    71.43mV
594ps     77.12mV    -4.916mV   140.9mV
648ps     111.2mV    12.79mV    161.1mV
739ps     150.6mV    67.12mV    182.6mV
934ps     187.2mV    149.5mV    202.4mV
1.119ns   198mV      177.6mV    208.9mV
1.399ns   203mV      189.2mV    212.3mV
30ns      206.5mV    194.9mV    214.3mV
[Rising Waveform]
R_fixture = 50.000
V_fixture = 0.367
V_fixture_min = 0.350
V_fixture_max = 0.386
|  time   V(typ)   V(min)   V(max)
0s        237.2mV    230mV      247.3mV
375ps     237.5mV    230.1mV    246mV
477ps     243.7mV    230.3mV    379.7mV
577ps     360.2mV    229.1mV    474.9mV
707ps     467.4mV    339.5mV    532.5mV
791ps     501.3mV    407.8mV    550.1mV
886ps     522.2mV    457mV      561.4mV
1.052ns   537.9mV    496.8mV    570.6mV
1.315ns   545.3mV    514mV      575.8mV
30ns      550.8mV    522.1mV    579mV
[Falling Waveform]
R_fixture = 50.000
V_fixture = 0.367
V_fixture_min = 0.350
V_fixture_max = 0.386
|  time   V(typ)   V(min)   V(max)
0s        550.9mV    522.1mV    579mV
362ps     550.5mV    522mV      580.1mV
403ps     553.4mV    521.9mV    542.4mV
454ps     549.7mV    522mV      456.2mV
506ps     506.4mV    524.6mV    382.6mV
568ps     428.6mV    527mV      328.5mV
689ps     313.8mV    424.7mV    279.7mV
847ps     261mV      294.2mV    258.9mV
1.144ns   241.7mV    239.1mV    249.9mV
30ns      237.2mV    230mV      247.3mV
[Falling Waveform]
R_fixture = 50.000
V_fixture = 0.000
V_fixture_min = 0.000
V_fixture_max = 0.000
|  time   V(typ)   V(min)   V(max)
0s        206.5mV    194.9mV    214.3mV
354ps     206mV      194.7mV    218.7mV
443ps     211.1mV    194.6mV    124mV
557ps     105.4mV    203.3mV    47.52mV
656ps     48.08mV    130.9mV    22.79mV
729ps     27.86mV    75.62mV    13.88mV
802ps     16.86mV    43.37mV    8.735mV
935ps     7.561mV    17.07mV    4.023mV
1.149ns   2.705mV    5.373mV    1.329mV
30ns      4.886uV    140.6uV    -171.7uV
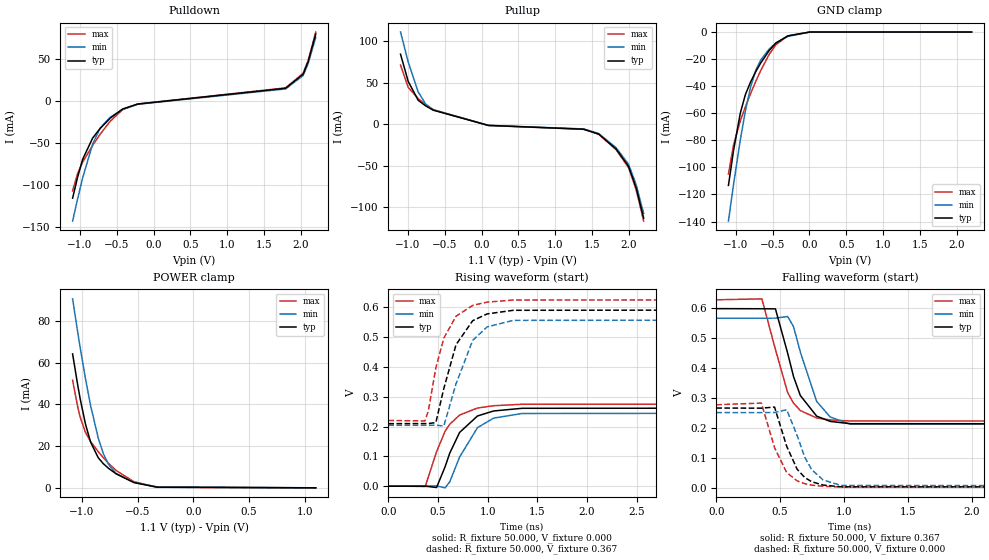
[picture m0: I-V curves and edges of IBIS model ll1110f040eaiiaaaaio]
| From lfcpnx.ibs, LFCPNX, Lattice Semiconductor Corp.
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|   Model ll1110f040eaiiaaaaio
[Model] ll1110f040eaiiaaaaio
| Clamp models do not include dynamic input termination. Please refer to
| the ll1110axxxeaiiaaaain model for input termination.
Model_type I/O
Polarity   Non-Inverting
Enable   Active-Low
Vinl =  0.093V
Vinh =  0.273V
Vmeas =  0.183V
Cref =  30.000pF
Rref =  50.000
Vref =  0.183V
C_comp   5.000pF   4.000pF   5.500pF
[Temperature Range]   25.000   0.125k   -40.000
[Voltage Range]   1.100V   1.050V   1.160V
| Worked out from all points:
|   slope of the pulldown table from 0 to 0.165 V, typ, clamps not added: 65.6 ohm
|   slope of the pullup table from 0 to 0.165 V, typ, clamps not added: 75 ohm
|   GND clamp passes 1 mA (typ) near -0.11 V on its own axis
|   POWER clamp passes 1 mA (typ) near -0.42 V on its own axis
|   rising waveform, R_fixture 50.000, V_fixture 0.000: 20-80 % time 239ps typ, 251ps min, 222ps max; typ from 0 V to 0.266 V
|   rising waveform, R_fixture 50.000, V_fixture 0.367: 20-80 % time 220ps typ, 227ps min, 201ps max; typ from 0.21 V to 0.598 V
|   falling waveform, R_fixture 50.000, V_fixture 0.367: 20-80 % time 161ps typ, 168ps min, 155ps max; typ from 0.598 V to 0.21 V
|   falling waveform, R_fixture 50.000, V_fixture 0.000: 20-80 % time 146ps typ, 152ps min, 142ps max; typ from 0.266 V to 0 V
[GND_clamp]
|Voltage   I(typ)   I(min)   I(max)
-1.1V     -113.3mA   -139.6mA   -104.8mA
-1.031V   -87.61mA   -112.7mA   -83.35mA
-939mV    -59.89mA   -79.66mA   -65.63mA
-870mV    -46.21mA   -58.29mA   -55.27mA
-801mV    -37.06mA   -41.02mA   -45.69mA
-732mV    -29.55mA   -28.66mA   -36.81mA
-663mV    -22.96mA   -20.75mA   -28.54mA
-548mV    -13.71mA   -12.59mA   -16.61mA
-456mV    -8.106mA   -8.062mA   -9.359mA
-295mV    -2.884mA   -3.249mA   -2.796mA
4mV       0A         0A         0A
2.2V      0A         0A         0A
[POWER_clamp]
|Voltage   I(typ)   I(min)   I(max)
-1.085V   64.25mA    90.66mA    51.57mA
-1.039V   49.25mA    74.63mA    38.81mA
-1.016V   42.45mA    66.98mA    33.78mA
-970mV    30.73mA    52.57mA    26.67mA
-924mV    22.04mA    39.64mA    22.28mA
-855mV    14.46mA    23.93mA    17.37mA
-809mV    11.59mA    16.44mA    14.47mA
-763mV    9.405mA    11.32mA    11.82mA
-694mV    6.715mA    6.853mA    8.328mA
-533mV    2.507mA    2.594mA    2.916mA
-326mV    306.4uA    502.5uA    259.1uA
1.1V      -3.028uA   0A         -8.363uA
[Pulldown]
|Voltage   I(typ)   I(min)   I(max)
-1.1V     -115.7mA   -142.9mA   -107mA
-1.032V   -90.64mA   -116.4mA   -86.27mA
-964mV    -69.46mA   -91.65mA   -72.75mA
-828mV    -44.01mA   -51.11mA   -52.68mA
-726mV    -32.65mA   -32.03mA   -39.47mA
-590mV    -20.36mA   -19.24mA   -24.02mA
-420mV    -9.347mA   -9.893mA   -10.12mA
-216mV    -3.518mA   -3.804mA   -3.44mA
1.79V     15.26mA    14.5mA     15.72mA
2.028V    32.04mA    30.44mA    33mA
2.096V    46.85mA    44.51mA    48.26mA
2.2V      79.9mA     75.9mA     82.29mA
[Pullup]
|Voltage   I(typ)   I(min)   I(max)
-1.1V     84.59mA    111.3mA    71.4mA
-996mV    51.79mA    75.29mA    44.61mA
-860mV    28.98mA    39.08mA    30.92mA
-758mV    22.19mA    24.35mA    23.73mA
-656mV    17.06mA    17.48mA    17.67mA
92mV      -1.311mA   -1.245mA   -1.35mA
1.384V    -5.864mA   -5.57mA    -6.04mA
1.588V    -11.62mA   -11.04mA   -11.97mA
1.826V    -29.71mA   -28.23mA   -30.6mA
1.996V    -50.89mA   -48.34mA   -52.41mA
2.098V    -76.64mA   -72.81mA   -78.94mA
2.2V      -113.2mA   -107.5mA   -116.6mA
[Ramp]
| variable   typ   min   max
dV/dt_r   0.160/0.239n   0.150/0.250n   0.165/0.221n
dV/dt_f   0.226/0.217n   0.211/0.222n   0.234/0.213n
R_load = 50.000
[Rising Waveform]
R_fixture = 50.000
V_fixture = 0.000
V_fixture_min = 0.000
V_fixture_max = 0.000
|  time   V(typ)   V(min)   V(max)
0s        3.84uV     405.9uV    737.5uV
371ps     263.3uV    401.9uV    -728.1uV
485ps     -4.314mV   1.107mV    115.6mV
571ps     65.25mV    -5.4mV     184.3mV
618ps     111mV      14.97mV    207.9mV
717ps     180.3mV    97.83mV    238.5mV
897ps     235.4mV    196.3mV    262mV
1.059ns   252.1mV    228.2mV    269.7mV
1.346ns   261.1mV    243.7mV    274.7mV
30ns      266.4mV    251.2mV    277.3mV
[Rising Waveform]
R_fixture = 50.000
V_fixture = 0.367
V_fixture_min = 0.350
V_fixture_max = 0.386
|  time   V(typ)   V(min)   V(max)
0s        209.7mV    204.2mV    220.3mV
369ps     209.9mV    204.2mV    218.8mV
404ps     210mV      204.3mV    255.2mV
478ps     213.3mV    204.7mV    396.8mV
558ps     327.1mV    201.6mV    496mV
681ps     474.2mV    343.2mV    569.6mV
849ps     554.7mV    488.9mV    605.8mV
994ps     577.3mV    533.9mV    616.9mV
1.258ns   589.4mV    555.6mV    623.8mV
30ns      598.1mV    566.2mV    627.7mV
[Falling Waveform]
R_fixture = 50.000
V_fixture = 0.367
V_fixture_min = 0.350
V_fixture_max = 0.386
|  time   V(typ)   V(min)   V(max)
0s        598.2mV    566.2mV    627.7mV
357ps     597.8mV    566.1mV    630.8mV
463ps     597.5mV    566.5mV    461.9mV
559ps     449.2mV    571.9mV    317.8mV
605ps     371.1mV    538mV      282.5mV
658ps     308.2mV    453.4mV    258mV
786ps     239.3mV    288.5mV    233.2mV
892ps     221.8mV    236.5mV    226.6mV
1.047ns   214.2mV    213mV      223.2mV
30ns      209.7mV    204.2mV    220.3mV
[Falling Waveform]
R_fixture = 50.000
V_fixture = 0.000
V_fixture_min = 0.000
V_fixture_max = 0.000
|  time   V(typ)   V(min)   V(max)
0s        266.4mV    251.2mV    277.3mV
353ps     266mV      251.1mV    283mV
456ps     269.7mV    251.5mV    134.2mV
551ps     138.9mV    260.9mV    51.25mV
633ps     62.22mV    174.8mV    23.26mV
693ps     34.36mV    101.8mV    13.83mV
747ps     20.45mV    60.76mV    9.152mV
836ps     9.26mV     26.37mV    5.254mV
978ps     3.398mV    7.871mV    2.869mV
30ns      4.861uV    405.9uV    737.5uV
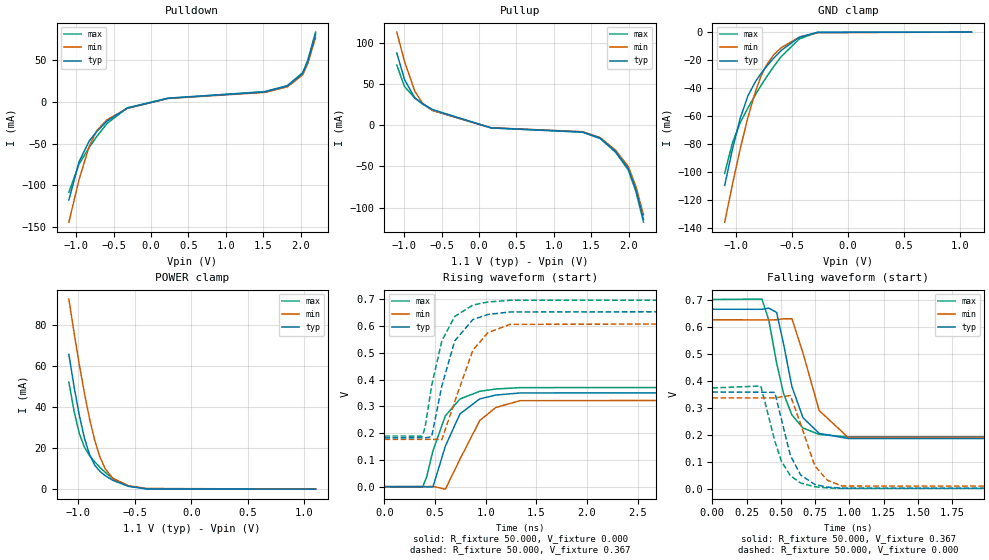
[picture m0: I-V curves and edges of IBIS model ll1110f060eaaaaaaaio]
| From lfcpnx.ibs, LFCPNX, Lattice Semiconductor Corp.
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|   Model ll1110f060eaaaaaaaio
[Model] ll1110f060eaaaaaaaio
| Clamp models do not include dynamic input termination. Please refer to
| the ll1110axxxeaaaaaaain model for input termination.
Model_type I/O
Polarity   Non-Inverting
Enable   Active-Low
Vinl =  0.093V
Vinh =  0.273V
Vmeas =  0.183V
Cref =  30.000pF
Rref =  50.000
Vref =  0.183V
C_comp   5.000pF   4.000pF   5.500pF
[Temperature Range]   25.000   0.125k   -40.000
[Voltage Range]   1.100V   1.050V   1.160V
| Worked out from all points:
|   slope of the pulldown table from 0 to 0.165 V, typ, clamps not added: 49 ohm
|   slope of the pullup table from 0 to 0.165 V, typ, clamps not added: 54.8 ohm
|   GND clamp passes 1 mA (typ) near -0.34 V on its own axis
|   POWER clamp passes 1 mA (typ) near -0.53 V on its own axis
|   rising waveform, R_fixture 50.000, V_fixture 0.000: 20-80 % time 236ps typ, 288ps min, 222ps max; typ from 0 V to 0.358 V
|   rising waveform, R_fixture 50.000, V_fixture 0.367: 20-80 % time 208ps typ, 260ps min, 196ps max; typ from 0.182 V to 0.665 V
|   falling waveform, R_fixture 50.000, V_fixture 0.367: 20-80 % time 138ps typ, 157ps min, 141ps max; typ from 0.665 V to 0.182 V
|   falling waveform, R_fixture 50.000, V_fixture 0.000: 20-80 % time 123ps typ, 141ps min, 129ps max; typ from 0.358 V to 0 V
[GND_clamp]
|Voltage   I(typ)   I(min)   I(max)
-1.1V     -109.7mA   -136mA     -101.1mA
-1.031V   -83.83mA   -108.9mA   -79.25mA
-962mV    -61.81mA   -83.69mA   -64.88mA
-893mV    -45.59mA   -61.04mA   -54.23mA
-824mV    -35.2mA    -42.07mA   -44.52mA
-778mV    -29.85mA   -31.99mA   -38.47mA
-732mV    -25.04mA   -24.18mA   -32.73mA
-663mV    -18.63mA   -16.24mA   -24.64mA
-594mV    -13.03mA   -11.06mA   -17.35mA
-433mV    -3.573mA   -3.549mA   -4.801mA
-272mV    -185.6uA   -413.4uA   -195.8uA
1.1V      0A         0A         0A
[POWER_clamp]
|Voltage   I(typ)   I(min)   I(max)
-1.085V   65.46mA    92.38mA    52.09mA
-1.039V   49.83mA    76.06mA    37.92mA
-993mV    36.02mA    60.7mA     27.13mA
-947mV    24.74mA    46.56mA    20.34mA
-901mV    16.65mA    34.03mA    16.28mA
-855mV    11.62mA    23.53mA    13.22mA
-809mV    8.607mA    15.46mA    10.54mA
-763mV    6.559mA    9.886mA    8.161mA
-694mV    4.241mA    5.164mA    5.156mA
-556mV    1.362mA    1.666mA    1.473mA
-395mV    157uA      339.2uA    107.6uA
1.1V      0A         0A         466pA
[Pulldown]
|Voltage   I(typ)   I(min)   I(max)
-1.1V     -117.9mA   -144.6mA   -108.6mA
-964mV    -71.92mA   -93.46mA   -74.75mA
-828mV    -46.86mA   -53.12mA   -54.68mA
-726mV    -35.44mA   -34.2mA    -41.42mA
-590mV    -22.93mA   -21.33mA   -25.83mA
-318mV    -7.319mA   -7.58mA    -6.947mA
226mV     4.511mA    4.285mA    4.646mA
1.518V    12.17mA    11.56mA    12.54mA
1.824V    19.3mA     18.33mA    19.88mA
2.028V    34.44mA    32.71mA    35.47mA
2.096V    48.95mA    46.51mA    50.42mA
2.2V      81.73mA    77.65mA    84.19mA
[Pullup]
|Voltage   I(typ)   I(min)   I(max)
-1.1V     88.32mA    113.8mA    73.59mA
-996mV    55.91mA    77.94mA    47.28mA
-860mV    33.67mA    41.95mA    33.68mA
-758mV    26.63mA    27.31mA    26.33mA
-622mV    19.41mA    18.58mA    18.27mA
160mV     -2.933mA   -2.787mA   -3.021mA
1.384V    -7.973mA   -7.575mA   -8.213mA
1.622V    -15.55mA   -14.78mA   -16.02mA
1.826V    -31.65mA   -30.06mA   -32.6mA
1.996V    -52.64mA   -50.01mA   -54.22mA
2.098V    -78.11mA   -74.21mA   -80.45mA
2.2V      -114.5mA   -108.8mA   -117.9mA
[Ramp]
| variable   typ   min   max
dV/dt_r   0.215/0.235n   0.202/0.287n   0.224/0.221n
dV/dt_f   0.287/0.196n   0.272/0.215n   0.302/0.199n
R_load = 50.000
[Rising Waveform]
R_fixture = 50.000
V_fixture = 0.000
V_fixture_min = 0.000
V_fixture_max = 0.000
|  time   V(typ)   V(min)   V(max)
0s        3.319uV    89.43uV    -354uV
376ps     368.8uV    76.18uV    -2.368mV
417ps     -1.007mV   173.4uV    36.21mV
479ps     -1.102mV   836.7uV    134.1mV
602ps     151.6mV    -9.516mV   264.9mV
746ps     271.7mV    102.7mV    327.2mV
941ps     327.6mV    246.7mV    356.1mV
1.1ns     342mV      295.7mV    364.6mV
1.34ns    349.8mV    321mV      369.8mV
30ns      358.4mV    336.9mV    373.6mV
[Rising Waveform]
R_fixture = 50.000
V_fixture = 0.367
V_fixture_min = 0.350
V_fixture_max = 0.386
|  time   V(typ)   V(min)   V(max)
0s        182.2mV    176.5mV    189mV
375ps     182.5mV    176.5mV    188.9mV
403ps     182.5mV    176.6mV    225mV
466ps     186mV      176.9mV    377.2mV
567ps     376.2mV    175.2mV    544.5mV
694ps     544.1mV    317.9mV    635.6mV
873ps     624mV      509.3mV    678.1mV
1.022ns   642.9mV    575.1mV    689.6mV
1.24ns    652.3mV    606.1mV    695.9mV
30ns      664.6mV    625.4mV    700.5mV
[Falling Waveform]
R_fixture = 50.000
V_fixture = 0.367
V_fixture_min = 0.350
V_fixture_max = 0.386
|  time   V(typ)   V(min)   V(max)
0s        664.6mV    625.5mV    700.5mV
362ps     664.3mV    625.2mV    702.1mV
412ps     668.6mV    625mV      624.6mV
469ps     652.8mV    625.5mV    466.6mV
520ps     535.9mV    629.3mV    352.9mV
581ps     378.5mV    629.4mV    273.7mV
662ps     263.4mV    502.5mV    225.7mV
780ps     205.8mV    290.1mV    201.9mV
991ps     186.9mV    191mV      192.7mV
30ns      182.2mV    176.5mV    189mV
[Falling Waveform]
R_fixture = 50.000
V_fixture = 0.000
V_fixture_min = 0.000
V_fixture_max = 0.000
|  time   V(typ)   V(min)   V(max)
0s        358.5mV    337mV      373.6mV
354ps     358mV      336.6mV    380.9mV
456ps     357.3mV    336.7mV    177.6mV
506ps     254.2mV    341.1mV    101.1mV
570ps     123.8mV    345.8mV    49.21mV
645ps     51.69mV    239.9mV    22.23mV
748ps     16.92mV    85.8mV     8.613mV
839ps     7.322mV    32.84mV    4.385mV
946ps     3.525mV    11.31mV    2.335mV
30ns      4.909uV    95.64uV    -354uV
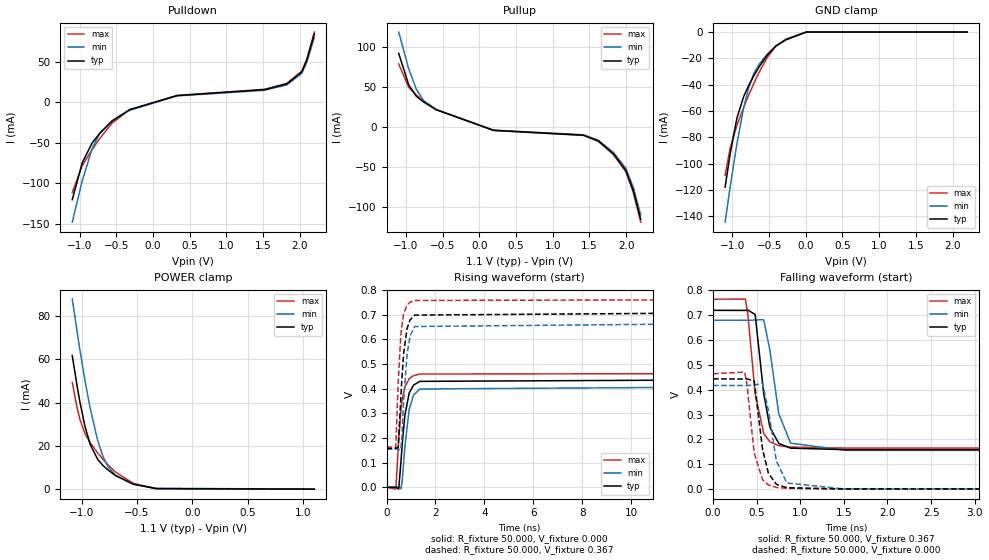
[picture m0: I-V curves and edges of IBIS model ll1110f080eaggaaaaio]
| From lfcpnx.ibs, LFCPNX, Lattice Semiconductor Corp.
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|   Model ll1110f080eaggaaaaio
[Model] ll1110f080eaggaaaaio
| Clamp models do not include dynamic input termination. Please refer to
| the ll1110axxxeaggaaaain model for input termination.
Model_type I/O
Polarity   Non-Inverting
Enable   Active-Low
Vinl =  0.093V
Vinh =  0.273V
Vmeas =  0.183V
Cref =  30.000pF
Rref =  50.000
Vref =  0.183V
C_comp   5.000pF   4.000pF   5.500pF
[Temperature Range]   25.000   0.125k   -40.000
[Voltage Range]   1.100V   1.050V   1.160V
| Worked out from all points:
|   slope of the pulldown table from 0 to 0.165 V, typ, clamps not added: 37.8 ohm
|   slope of the pullup table from 0 to 0.165 V, typ, clamps not added: 43.3 ohm
|   GND clamp passes 1 mA (typ) near -0.05 V on its own axis
|   POWER clamp passes 1 mA (typ) near -0.44 V on its own axis
|   rising waveform, R_fixture 50.000, V_fixture 0.000: 20-80 % time 271ps typ, 275ps min, 221ps max; typ from 0 V to 0.443 V
|   rising waveform, R_fixture 50.000, V_fixture 0.367: 20-80 % time 233ps typ, 229ps min, 183ps max; typ from 0.158 V to 0.719 V
|   falling waveform, R_fixture 50.000, V_fixture 0.367: 20-80 % time 120ps typ, 137ps min, 113ps max; typ from 0.719 V to 0.158 V
|   falling waveform, R_fixture 50.000, V_fixture 0.000: 20-80 % time 108ps typ, 122ps min, 101ps max; typ from 0.444 V to 0 V
[GND_clamp]
|Voltage   I(typ)   I(min)   I(max)
-1.1V     -117.8mA   -144.4mA   -108.9mA
-1.031V   -92.39mA   -117.5mA   -88.07mA
-939mV    -65.35mA   -84.74mA   -70.87mA
-847mV    -48.93mA   -57.47mA   -57.24mA
-778mV    -40.53mA   -42.1mA    -47.86mA
-709mV    -33.25mA   -31.59mA   -39.07mA
-640mV    -26.73mA   -24.69mA   -30.91mA
-525mV    -17.44mA   -16.67mA   -19.2mA
-410mV    -10.6mA    -10.77mA   -10.78mA
-272mV    -5.792mA   -5.969mA   -5.355mA
4mV       0A         0A         0A
2.2V      0A         0A         0A
[POWER_clamp]
|Voltage   I(typ)   I(min)   I(max)
-1.085V   61.74mA    87.92mA    49.38mA
-1.039V   46.98mA    72.04mA    37.07mA
-1.016V   40.35mA    64.47mA    32.31mA
-970mV    29.02mA    50.27mA    25.66mA
-924mV    20.79mA    37.6mA     21.51mA
-855mV    13.71mA    22.38mA    16.7mA
-809mV    10.99mA    15.25mA    13.85mA
-763mV    8.879mA    10.44mA    11.25mA
-694mV    6.274mA    6.278mA    7.853mA
-533mV    2.248mA    2.293mA    2.647mA
-326mV    216.7uA    380.5uA    177.7uA
1.1V      -16.31uA   -2.388uA   -25.69uA
[Pulldown]
|Voltage   I(typ)   I(min)   I(max)
-1.1V     -120.2mA   -147.9mA   -111.3mA
-964mV    -74.72mA   -96.95mA   -78.22mA
-828mV    -50.09mA   -57mA      -58.22mA
-726mV    -38.62mA   -38.37mA   -44.92mA
-556mV    -23.11mA   -22.89mA   -25.72mA
-318mV    -9.291mA   -10.08mA   -9.314mA
328mV     8.086mA    7.682mA    8.329mA
1.518V    15.38mA    14.61mA    15.84mA
1.824V    22.41mA    21.29mA    23.08mA
2.028V    37.16mA    35.3mA     38.27mA
2.096V    51.35mA    48.78mA    52.89mA
2.2V      83.82mA    79.63mA    86.33mA
[Pullup]
|Voltage   I(typ)   I(min)   I(max)
-1.1V     92.03mA    118.6mA    78.77mA
-962mV    52.27mA    72.44mA    49.16mA
-860mV    38.29mA    47.22mA    40.04mA
-758mV    30.99mA    32.71mA    32.28mA
-588mV    21.43mA    21.64mA    21.65mA
194mV     -4.357mA   -4.139mA   -4.488mA
1.418V    -10.41mA   -9.89mA    -10.72mA
1.622V    -17.58mA   -16.71mA   -18.11mA
1.826V    -33.6mA    -31.92mA   -34.61mA
1.996V    -54.42mA   -51.7mA    -56.05mA
2.098V    -79.6mA    -75.62mA   -81.99mA
2.2V      -115.8mA   -110mA     -119.3mA
[Ramp]
| variable   typ   min   max
dV/dt_r   0.266/0.270n   0.249/0.274n   0.283/0.220n
dV/dt_f   0.342/0.171n   0.336/0.185n   0.359/0.170n
R_load = 50.000
[Rising Waveform]
R_fixture = 50.000
V_fixture = 0.000
V_fixture_min = 0.000
V_fixture_max = 0.000
|  time   V(typ)   V(min)   V(max)
0s        2.857uV    475.2uV    -82.95uV
379ps     425.3uV    457.1uV    -7.591mV
496ps     -7.491mV   1.308mV    191.9mV
593ps     109.5mV    -5.526mV   318.3mV
644ps     180.9mV    30.9mV     358.2mV
748ps     291.4mV    164.4mV    406.7mV
927ps     382.9mV    317.5mV    440.9mV
1.104ns   414.6mV    374.2mV    453mV
1.362ns   429.8mV    398.9mV    459.5mV
30ns      443.4mV    417mV      463.8mV
[Rising Waveform]
R_fixture = 50.000
V_fixture = 0.367
V_fixture_min = 0.350
V_fixture_max = 0.386
|  time   V(typ)   V(min)   V(max)
0s        157.8mV    154.8mV    164.8mV
373ps     158.1mV    154.8mV    160.5mV
474ps     161.5mV    155.3mV    419.6mV
576ps     348mV      151mV      608mV
618ps     426.7mV    191.7mV    651.6mV
701ps     545.1mV    352mV      703.6mV
838ps     644.3mV    539.7mV    739.4mV
962ps     679.2mV    614mV      751.2mV
1.148ns   698.7mV    652.3mV    758.1mV
30ns      719mV      679.1mV    763.7mV
[Falling Waveform]
R_fixture = 50.000
V_fixture = 0.367
V_fixture_min = 0.350
V_fixture_max = 0.386
|  time   V(typ)   V(min)   V(max)
0s        719mV      679.1mV    763.7mV
371ps     718.6mV    679mV      764.3mV
400ps     719.8mV    678.9mV    701.2mV
483ps     702.3mV    680.1mV    383.9mV
581ps     384.4mV    681.4mV    224.5mV
652ps     249.3mV    559mV      190.3mV
754ps     183.6mV    302.7mV    174.6mV
890ps     164.8mV    184.9mV    169.2mV
1.526ns   158.8mV    155.9mV    165.3mV
30ns      157.8mV    154.8mV    164.8mV
[Falling Waveform]
R_fixture = 50.000
V_fixture = 0.000
V_fixture_min = 0.000
V_fixture_max = 0.000
|  time   V(typ)   V(min)   V(max)
0s        443.5mV    417mV      463.8mV
363ps     442.8mV    416.8mV    470.6mV
387ps     443.8mV    416.8mV    426.1mV
472ps     434.6mV    418mV      145.8mV
568ps     160.1mV    426.1mV    37.86mV
635ps     63.8mV     316.5mV    16.69mV
726ps     19.49mV    113.6mV    7.009mV
847ps     5.663mV    24.6mV     3.302mV
1.493ns   749.8uV    1.334mV    292.3uV
30ns      4.272uV    475.2uV    -82.95uV
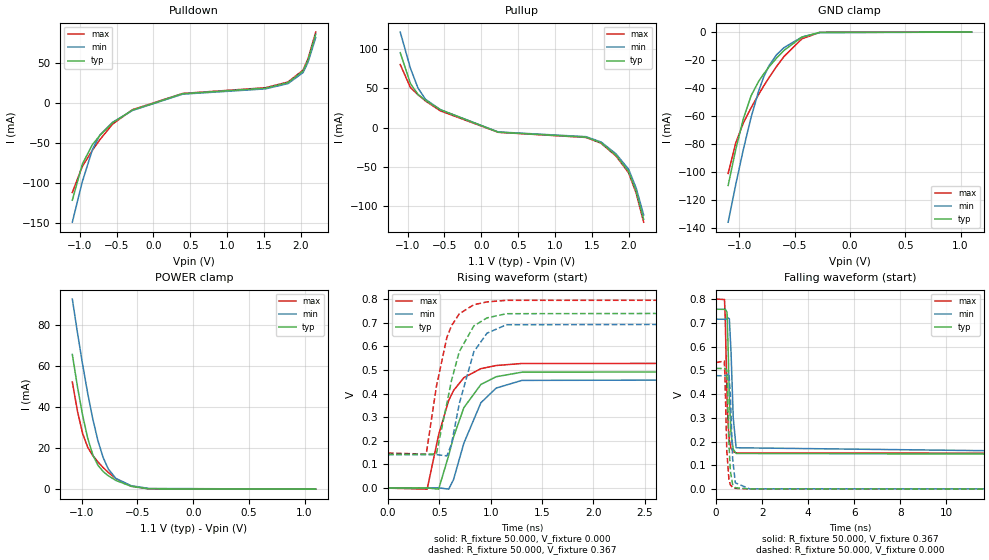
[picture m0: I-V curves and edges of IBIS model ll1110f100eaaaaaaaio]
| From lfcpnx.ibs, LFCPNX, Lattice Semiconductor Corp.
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|   Model ll1110f100eaaaaaaaio
[Model] ll1110f100eaaaaaaaio
| Clamp models do not include dynamic input termination. Please refer to
| the ll1110axxxeaaaaaaain model for input termination.
Model_type I/O
Polarity   Non-Inverting
Enable   Active-Low
Vinl =  0.093V
Vinh =  0.273V
Vmeas =  0.183V
Cref =  30.000pF
Rref =  50.000
Vref =  0.183V
C_comp   5.000pF   4.000pF   5.500pF
[Temperature Range]   25.000   0.125k   -40.000
[Voltage Range]   1.100V   1.050V   1.160V
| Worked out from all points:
|   slope of the pulldown table from 0 to 0.165 V, typ, clamps not added: 32.2 ohm
|   slope of the pullup table from 0 to 0.165 V, typ, clamps not added: 36.7 ohm
|   GND clamp passes 1 mA (typ) near -0.34 V on its own axis
|   POWER clamp passes 1 mA (typ) near -0.53 V on its own axis
|   rising waveform, R_fixture 50.000, V_fixture 0.000: 20-80 % time 260ps typ, 263ps min, 217ps max; typ from 0 V to 0.508 V
|   rising waveform, R_fixture 50.000, V_fixture 0.367: 20-80 % time 215ps typ, 213ps min, 177ps max; typ from 0.143 V to 0.757 V
|   falling waveform, R_fixture 50.000, V_fixture 0.367: 20-80 % time 114ps typ, 130ps min, 108ps max; typ from 0.757 V to 0.143 V
|   falling waveform, R_fixture 50.000, V_fixture 0.000: 20-80 % time 102ps typ, 116ps min, 96.1ps max; typ from 0.508 V to 0 V
[GND_clamp]
|Voltage   I(typ)   I(min)   I(max)
-1.1V     -109.7mA   -136mA     -101.1mA
-1.031V   -83.83mA   -108.9mA   -79.25mA
-962mV    -61.81mA   -83.69mA   -64.88mA
-893mV    -45.59mA   -61.04mA   -54.23mA
-824mV    -35.2mA    -42.07mA   -44.52mA
-778mV    -29.85mA   -31.99mA   -38.47mA
-732mV    -25.04mA   -24.18mA   -32.73mA
-663mV    -18.63mA   -16.24mA   -24.64mA
-594mV    -13.03mA   -11.06mA   -17.35mA
-433mV    -3.573mA   -3.549mA   -4.801mA
-272mV    -185.6uA   -413.4uA   -195.8uA
1.1V      0A         0A         0A
[POWER_clamp]
|Voltage   I(typ)   I(min)   I(max)
-1.085V   65.46mA    92.38mA    52.09mA
-1.039V   49.83mA    76.06mA    37.92mA
-993mV    36.02mA    60.7mA     27.13mA
-947mV    24.74mA    46.56mA    20.34mA
-901mV    16.65mA    34.03mA    16.28mA
-855mV    11.62mA    23.53mA    13.22mA
-809mV    8.607mA    15.46mA    10.54mA
-763mV    6.559mA    9.886mA    8.161mA
-694mV    4.241mA    5.164mA    5.156mA
-556mV    1.362mA    1.666mA    1.473mA
-395mV    157uA      339.2uA    107.6uA
1.1V      0A         0A         466pA
[Pulldown]
|Voltage   I(typ)   I(min)   I(max)
-1.1V     -122.1mA   -149.6mA   -112.5mA
-964mV    -76.95mA   -98.79mA   -79.76mA
-828mV    -52.64mA   -59.02mA   -59.78mA
-726mV    -41.12mA   -40.52mA   -46.43mA
-556mV    -25.33mA   -24.85mA   -27.11mA
-284mV    -9.46mA    -9.911mA   -8.919mA
396mV     11.02mA    10.47mA    11.35mA
1.518V    17.95mA    17.05mA    18.49mA
1.824V    24.9mA     23.66mA    25.65mA
2.028V    39.34mA    37.38mA    40.52mA
2.096V    53.27mA    50.61mA    54.87mA
2.2V      85.49mA    81.21mA    88.05mA
[Pullup]
|Voltage   I(typ)   I(min)   I(max)
-1.1V     95.25mA    121.5mA    80.24mA
-962mV    56.01mA    75.48mA    50.98mA
-860mV    42.29mA    50.45mA    41.81mA
-758mV    34.74mA    36.01mA    33.93mA
-554mV    22.7mA     22.63mA    21.2mA
228mV     -5.849mA   -5.557mA   -6.025mA
1.418V    -12.2mA    -11.59mA   -12.57mA
1.622V    -19.3mA    -18.33mA   -19.88mA
1.826V    -35.25mA   -33.49mA   -36.31mA
1.996V    -55.92mA   -53.13mA   -57.6mA
2.098V    -80.86mA   -76.82mA   -83.29mA
2.2V      -116.9mA   -111.1mA   -120.4mA
[Ramp]
| variable   typ   min   max
dV/dt_r   0.305/0.260n   0.296/0.262n   0.320/0.216n
dV/dt_f   0.375/0.159n   0.361/0.171n   0.385/0.158n
R_load = 50.000
[Rising Waveform]
R_fixture = 50.000
V_fixture = 0.000
V_fixture_min = 0.000
V_fixture_max = 0.000
|  time   V(typ)   V(min)   V(max)
0s        2.583uV    349.1uV    -317.2uV
381ps     570.2uV    318.1uV    -4.423mV
493ps     -4.517mV   1.178mV    225.6mV
591ps     138.5mV    -4.605mV   371.1mV
638ps     216mV      35.91mV    413mV
739ps     340.6mV    190.3mV    467.6mV
905ps     438.7mV    361.4mV    505.6mV
1.054ns   471.4mV    423.3mV    518.8mV
1.305ns   490.6mV    455.9mV    527.4mV
30ns      508.2mV    477.4mV    533mV
[Rising Waveform]
R_fixture = 50.000
V_fixture = 0.367
V_fixture_min = 0.350
V_fixture_max = 0.386
|  time   V(typ)   V(min)   V(max)
0s        143.3mV    140.9mV    148.2mV
372ps     143.6mV    140.9mV    143.8mV
471ps     144.9mV    141.6mV    429.7mV
573ps     358mV      136.3mV    637.3mV
617ps     453.3mV    184.7mV    686.2mV
694ps     577.5mV    356.9mV    737.6mV
836ps     686.4mV    577.1mV    776.2mV
964ps     720.4mV    655.5mV    788.1mV
1.153ns   738.1mV    691.3mV    794.7mV
30ns      757.2mV    715.2mV    800.1mV
[Falling Waveform]
R_fixture = 50.000
V_fixture = 0.367
V_fixture_min = 0.350
V_fixture_max = 0.386
|  time   V(typ)   V(min)   V(max)
0s        757.3mV    715.2mV    800.1mV
369ps     756.8mV    715.1mV    798.2mV
401ps     758.3mV    715mV      721mV
479ps     744.4mV    716mV      385.2mV
524ps     602.6mV    721.4mV    272.8mV
580ps     385.4mV    716.6mV    205.1mV
652ps     233mV      579mV      171.4mV
749ps     167.8mV    299.5mV    157.4mV
874ps     150.1mV    174mV      152.6mV
30ns      143.3mV    140.9mV    148.2mV
[Falling Waveform]
R_fixture = 50.000
V_fixture = 0.000
V_fixture_min = 0.000
V_fixture_max = 0.000
|  time   V(typ)   V(min)   V(max)
0s        508.2mV    477.4mV    533mV
360ps     507.4mV    477.3mV    538.8mV
387ps     508.7mV    477.2mV    478.8mV
470ps     500.5mV    478.5mV    160.1mV
562ps     191.3mV    488.5mV    40.44mV
625ps     75.28mV    388.3mV    17.82mV
721ps     19.47mV    129.4mV    6.853mV
839ps     5.514mV    26.4mV     3.227mV
1.452ns   821uV      1.283mV    123.7uV
30ns      3.899uV    349.1uV    -317.2uV
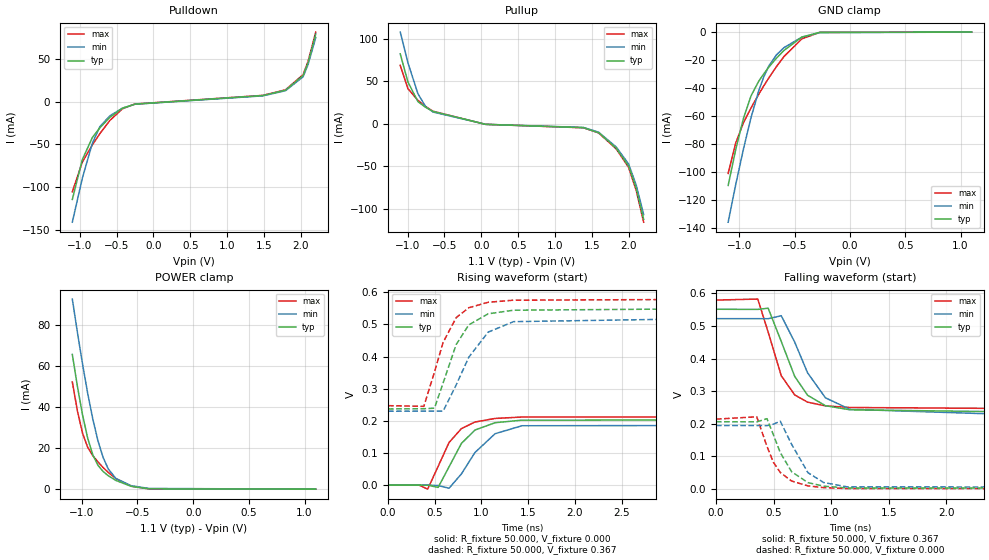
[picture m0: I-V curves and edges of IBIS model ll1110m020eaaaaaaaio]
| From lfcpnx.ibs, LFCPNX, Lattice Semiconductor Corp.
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|   Model ll1110m020eaaaaaaaio
[Model] ll1110m020eaaaaaaaio
| Clamp models do not include dynamic input termination. Please refer to
| the ll1110axxxeaaaaaaain model for input termination.
Model_type I/O
Polarity   Non-Inverting
Enable   Active-Low
Vinl =  0.093V
Vinh =  0.273V
Vmeas =  0.183V
Cref =  30.000pF
Rref =  50.000
Vref =  0.183V
C_comp   5.000pF   4.000pF   5.500pF
[Temperature Range]   25.000   0.125k   -40.000
[Voltage Range]   1.100V   1.050V   1.160V
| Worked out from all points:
|   slope of the pulldown table from 0 to 0.165 V, typ, clamps not added: 88.9 ohm
|   slope of the pullup table from 0 to 0.165 V, typ, clamps not added: 97.1 ohm
|   GND clamp passes 1 mA (typ) near -0.34 V on its own axis
|   POWER clamp passes 1 mA (typ) near -0.53 V on its own axis
|   rising waveform, R_fixture 50.000, V_fixture 0.000: 20-80 % time 270ps typ, 329ps min, 249ps max; typ from 0 V to 0.206 V
|   rising waveform, R_fixture 50.000, V_fixture 0.367: 20-80 % time 261ps typ, 328ps min, 243ps max; typ from 0.237 V to 0.551 V
|   falling waveform, R_fixture 50.000, V_fixture 0.367: 20-80 % time 233ps typ, 256ps min, 189ps max; typ from 0.551 V to 0.237 V
|   falling waveform, R_fixture 50.000, V_fixture 0.000: 20-80 % time 192ps typ, 199ps min, 174ps max; typ from 0.206 V to 0 V
[GND_clamp]
|Voltage   I(typ)   I(min)   I(max)
-1.1V     -109.7mA   -136mA     -101.1mA
-1.031V   -83.83mA   -108.9mA   -79.25mA
-962mV    -61.81mA   -83.69mA   -64.88mA
-893mV    -45.59mA   -61.04mA   -54.23mA
-824mV    -35.2mA    -42.07mA   -44.52mA
-778mV    -29.85mA   -31.99mA   -38.47mA
-732mV    -25.04mA   -24.18mA   -32.73mA
-663mV    -18.63mA   -16.24mA   -24.64mA
-594mV    -13.03mA   -11.06mA   -17.35mA
-433mV    -3.573mA   -3.549mA   -4.801mA
-272mV    -185.6uA   -413.4uA   -195.8uA
1.1V      0A         0A         0A
[POWER_clamp]
|Voltage   I(typ)   I(min)   I(max)
-1.085V   65.46mA    92.38mA    52.09mA
-1.039V   49.83mA    76.06mA    37.92mA
-993mV    36.02mA    60.7mA     27.13mA
-947mV    24.74mA    46.56mA    20.34mA
-901mV    16.65mA    34.03mA    16.28mA
-855mV    11.62mA    23.53mA    13.22mA
-809mV    8.607mA    15.46mA    10.54mA
-763mV    6.559mA    9.886mA    8.161mA
-694mV    4.241mA    5.164mA    5.156mA
-556mV    1.362mA    1.666mA    1.473mA
-395mV    157uA      339.2uA    107.6uA
1.1V      0A         0A         466pA
[Pulldown]
|Voltage   I(typ)   I(min)   I(max)
-1.1V     -114.2mA   -140.7mA   -105.3mA
-964mV    -67.68mA   -89.34mA   -70.58mA
-828mV    -41.93mA   -48.55mA   -50.51mA
-726mV    -30.58mA   -29.28mA   -37.35mA
-590mV    -18.43mA   -16.59mA   -22.02mA
-420mV    -7.735mA   -7.773mA   -8.423mA
-250mV    -3.069mA   -3.175mA   -2.889mA
1.484V    6.95mA     6.603mA    7.159mA
1.79V     13.25mA    12.58mA    13.64mA
2.028V    30.31mA    28.79mA    31.22mA
2.096V    45.32mA    43.06mA    46.68mA
2.2V      78.56mA    74.63mA    80.92mA
[Pullup]
|Voltage   I(typ)   I(min)   I(max)
-1.1V     82.28mA    107.9mA    68.73mA
-996mV    49.24mA    71.8mA     41.37mA
-860mV    26.07mA    35.32mA    27.54mA
-758mV    19.43mA    20.46mA    20.55mA
-656mV    14.57mA    13.85mA    14.74mA
58mV      -657.6uA   -624.7uA   -677.3uA
1.384V    -4.554mA   -4.327mA   -4.691mA
1.588V    -10.36mA   -9.846mA   -10.68mA
1.826V    -28.51mA   -27.09mA   -29.37mA
1.996V    -49.8mA    -47.31mA   -51.29mA
2.098V    -75.73mA   -71.94mA   -78mA
2.2V      -112.4mA   -106.8mA   -115.8mA
[Ramp]
| variable   typ   min   max
dV/dt_r   0.124/0.269n   0.114/0.328n   0.129/0.248n
dV/dt_f   0.174/0.289n   0.165/0.324n   0.182/0.248n
R_load = 50.000
[Rising Waveform]
R_fixture = 50.000
V_fixture = 0.000
V_fixture_min = 0.000
V_fixture_max = 0.000
|  time   V(typ)   V(min)   V(max)
0s        4.368uV    140.6uV    -171.7uV
328ps     43.82uV    226.7uV    585.6uV
424ps     -341.1uV   251.7uV    -12.56mV
536ps     -6.971mV   -1.378mV   58.47mV
653ps     57.14mV    -9.526mV   132.8mV
785ps     129.8mV    34.89mV    175.9mV
930ps     171.4mV    101.5mV    196.4mV
1.145ns   194.2mV    159.9mV    207.5mV
1.433ns   202.2mV    184.8mV    211.9mV
30ns      206.5mV    194.9mV    214.3mV
[Rising Waveform]
R_fixture = 50.000
V_fixture = 0.367
V_fixture_min = 0.350
V_fixture_max = 0.386
|  time   V(typ)   V(min)   V(max)
0s        237.2mV    230mV      247.3mV
383ps     237.7mV    230.1mV    245.1mV
497ps     239.5mV    230.3mV    352.3mV
589ps     317.7mV    230mV      444.2mV
729ps     437.5mV    311.9mV    521.1mV
864ps     498.7mV    398mV      552mV
1.071ns   533.1mV    476mV      569mV
1.343ns   544.3mV    508.7mV    575.5mV
4.204ns   550.4mV    521.6mV    579mV
30ns      550.8mV    522.1mV    579mV
[Falling Waveform]
R_fixture = 50.000
V_fixture = 0.367
V_fixture_min = 0.350
V_fixture_max = 0.386
|  time   V(typ)   V(min)   V(max)
0s        550.9mV    522.1mV    579mV
363ps     550.4mV    522mV      582.1mV
453ps     554.2mV    521.9mV    481.1mV
567ps     452.3mV    531.1mV    347.3mV
684ps     345.1mV    450mV      288.4mV
796ps     287.4mV    355.9mV    266.3mV
951ps     255.4mV    279.6mV    254.9mV
1.163ns   243mV      244.4mV    250mV
2.377ns   237.4mV    230.5mV    247.3mV
30ns      237.2mV    230mV      247.3mV
[Falling Waveform]
R_fixture = 50.000
V_fixture = 0.000
V_fixture_min = 0.000
V_fixture_max = 0.000
|  time   V(typ)   V(min)   V(max)
0s        206.5mV    194.9mV    214.3mV
354ps     205.9mV    194.7mV    221.5mV
443ps     215.7mV    194.4mV    130.9mV
499ps     166mV      198.8mV    82.1mV
558ps     112.2mV    208.2mV    51.16mV
657ps     53.18mV    137.3mV    24.74mV
799ps     19.9mV     50.33mV    9.884mV
935ps     9.003mV    20.24mV    4.547mV
1.141ns   3.409mV    6.833mV    1.585mV
30ns      4.881uV    140.6uV    -171.7uV
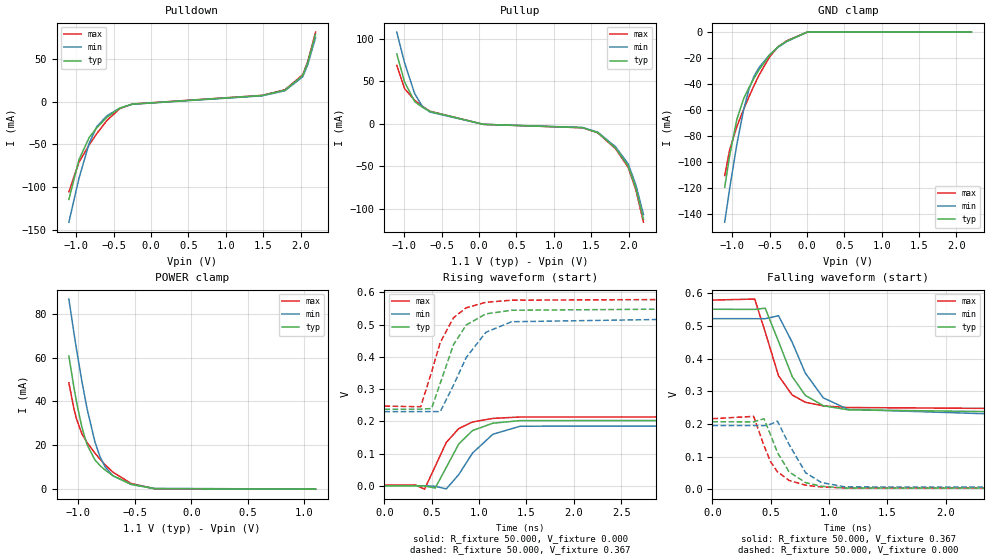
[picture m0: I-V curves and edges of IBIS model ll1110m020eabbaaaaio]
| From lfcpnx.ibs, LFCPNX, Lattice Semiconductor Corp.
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|   Model ll1110m020eabbaaaaio
[Model] ll1110m020eabbaaaaio
| Clamp models do not include dynamic input termination. Please refer to
| the ll1110axxxeabbaaaain model for input termination.
Model_type I/O
Polarity   Non-Inverting
Enable   Active-Low
Vinl =  0.093V
Vinh =  0.273V
Vmeas =  0.183V
Cref =  30.000pF
Rref =  50.000
Vref =  0.183V
C_comp   5.000pF   4.000pF   5.500pF
[Temperature Range]   25.000   0.125k   -40.000
[Voltage Range]   1.100V   1.050V   1.160V
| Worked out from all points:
|   slope of the pulldown table from 0 to 0.165 V, typ, clamps not added: 88.9 ohm
|   slope of the pullup table from 0 to 0.165 V, typ, clamps not added: 97.1 ohm
|   GND clamp passes 1 mA (typ) near -0.04 V on its own axis
|   POWER clamp passes 1 mA (typ) near -0.45 V on its own axis
|   rising waveform, R_fixture 50.000, V_fixture 0.000: 20-80 % time 270ps typ, 329ps min, 249ps max; typ from 0 V to 0.206 V
|   rising waveform, R_fixture 50.000, V_fixture 0.367: 20-80 % time 261ps typ, 328ps min, 243ps max; typ from 0.237 V to 0.551 V
|   falling waveform, R_fixture 50.000, V_fixture 0.367: 20-80 % time 233ps typ, 256ps min, 189ps max; typ from 0.551 V to 0.237 V
|   falling waveform, R_fixture 50.000, V_fixture 0.000: 20-80 % time 192ps typ, 199ps min, 174ps max; typ from 0.206 V to 0 V
[GND_clamp]
|Voltage   I(typ)   I(min)   I(max)
-1.1V     -119.6mA   -146.5mA   -110.6mA
-1.031V   -94.37mA   -119.6mA   -90.12mA
-939mV    -67.61mA   -86.97mA   -73.15mA
-847mV    -51.42mA   -59.87mA   -59.55mA
-778mV    -43.02mA   -44.64mA   -50.18mA
-709mV    -35.68mA   -34.21mA   -41.36mA
-640mV    -29.08mA   -27.27mA   -33.15mA
-502mV    -17.94mA   -17.61mA   -19.3mA
-387mV    -11.32mA   -11.67mA   -11.39mA
-272mV    -7.089mA   -7.328mA   -6.742mA
4mV       0A         0A         0A
2.2V      0A         0A         0A
[POWER_clamp]
|Voltage   I(typ)   I(min)   I(max)
-1.085V   60.71mA    86.73mA    48.54mA
-1.039V   46.06mA    70.92mA    36.41mA
-1.016V   39.49mA    63.39mA    31.77mA
-970mV    28.33mA    49.28mA    25.3mA
-924mV    20.28mA    36.72mA    21.23mA
-855mV    13.4mA     21.73mA    16.47mA
-809mV    10.74mA    14.75mA    13.64mA
-763mV    8.663mA    10.07mA    11.05mA
-694mV    6.094mA    6.035mA    7.687mA
-533mV    2.142mA    2.166mA    2.559mA
-326mV    180.6uA    329.6uA    155.6uA
1.1V      -23.7uA    -6.491uA   -29.42uA
[Pulldown]
|Voltage   I(typ)   I(min)   I(max)
-1.1V     -114.2mA   -140.7mA   -105.3mA
-964mV    -67.68mA   -89.34mA   -70.58mA
-828mV    -41.93mA   -48.55mA   -50.51mA
-726mV    -30.58mA   -29.28mA   -37.35mA
-590mV    -18.43mA   -16.59mA   -22.02mA
-420mV    -7.735mA   -7.773mA   -8.423mA
-250mV    -3.069mA   -3.175mA   -2.889mA
1.484V    6.95mA     6.603mA    7.159mA
1.79V     13.25mA    12.58mA    13.64mA
2.028V    30.31mA    28.79mA    31.22mA
2.096V    45.32mA    43.06mA    46.68mA
2.2V      78.56mA    74.63mA    80.92mA
[Pullup]
|Voltage   I(typ)   I(min)   I(max)
-1.1V     82.28mA    107.9mA    68.73mA
-996mV    49.24mA    71.8mA     41.37mA
-860mV    26.07mA    35.32mA    27.54mA
-758mV    19.43mA    20.46mA    20.55mA
-656mV    14.57mA    13.85mA    14.74mA
58mV      -657.6uA   -624.7uA   -677.3uA
1.384V    -4.554mA   -4.327mA   -4.691mA
1.588V    -10.36mA   -9.846mA   -10.68mA
1.826V    -28.51mA   -27.09mA   -29.37mA
1.996V    -49.8mA    -47.31mA   -51.29mA
2.098V    -75.73mA   -71.94mA   -78mA
2.2V      -112.4mA   -106.8mA   -115.8mA
[Ramp]
| variable   typ   min   max
dV/dt_r   0.124/0.269n   0.114/0.328n   0.128/0.248n
dV/dt_f   0.174/0.289n   0.165/0.324n   0.181/0.248n
R_load = 50.000
[Rising Waveform]
R_fixture = 50.000
V_fixture = 0.000
V_fixture_min = 0.000
V_fixture_max = 0.000
|  time   V(typ)   V(min)   V(max)
0s        4.368uV    140.6uV    2.014mV
328ps     43.82uV    226.7uV    2.769mV
424ps     -341.1uV   251.7uV    -10.34mV
536ps     -6.971mV   -1.378mV   60.45mV
653ps     57.14mV    -9.526mV   134.5mV
785ps     129.8mV    34.89mV    177.5mV
930ps     171.4mV    101.5mV    197.9mV
1.145ns   194.2mV    159.9mV    209mV
1.433ns   202.2mV    184.8mV    213.4mV
30ns      206.5mV    194.9mV    215.8mV
[Rising Waveform]
R_fixture = 50.000
V_fixture = 0.367
V_fixture_min = 0.350
V_fixture_max = 0.386
|  time   V(typ)   V(min)   V(max)
0s        237.2mV    230mV      247.3mV
383ps     237.7mV    230.1mV    245.1mV
497ps     239.5mV    230.3mV    352.3mV
589ps     317.7mV    230mV      444.2mV
729ps     437.5mV    311.9mV    521.1mV
864ps     498.7mV    398mV      552mV
1.071ns   533.1mV    476mV      569mV
1.343ns   544.3mV    508.7mV    575.5mV
4.204ns   550.4mV    521.6mV    579mV
30ns      550.8mV    522.1mV    579mV
[Falling Waveform]
R_fixture = 50.000
V_fixture = 0.367
V_fixture_min = 0.350
V_fixture_max = 0.386
|  time   V(typ)   V(min)   V(max)
0s        550.9mV    522.1mV    579mV
363ps     550.4mV    522mV      582.1mV
453ps     554.2mV    521.9mV    481.1mV
567ps     452.3mV    531.1mV    347.3mV
684ps     345.1mV    450mV      288.4mV
796ps     287.4mV    355.9mV    266.3mV
951ps     255.4mV    279.6mV    254.9mV
1.163ns   243mV      244.4mV    250mV
2.377ns   237.4mV    230.5mV    247.3mV
30ns      237.2mV    230mV      247.3mV
[Falling Waveform]
R_fixture = 50.000
V_fixture = 0.000
V_fixture_min = 0.000
V_fixture_max = 0.000
|  time   V(typ)   V(min)   V(max)
0s        206.5mV    194.9mV    215.8mV
354ps     205.9mV    194.7mV    222.9mV
443ps     215.7mV    194.4mV    132.6mV
499ps     166mV      198.8mV    83.99mV
558ps     112.2mV    208.2mV    53.17mV
657ps     53.18mV    137.3mV    26.84mV
799ps     19.9mV     50.33mV    12.03mV
935ps     9.003mV    20.24mV    6.716mV
1.141ns   3.409mV    6.833mV    3.764mV
30ns      4.881uV    140.6uV    2.014mV
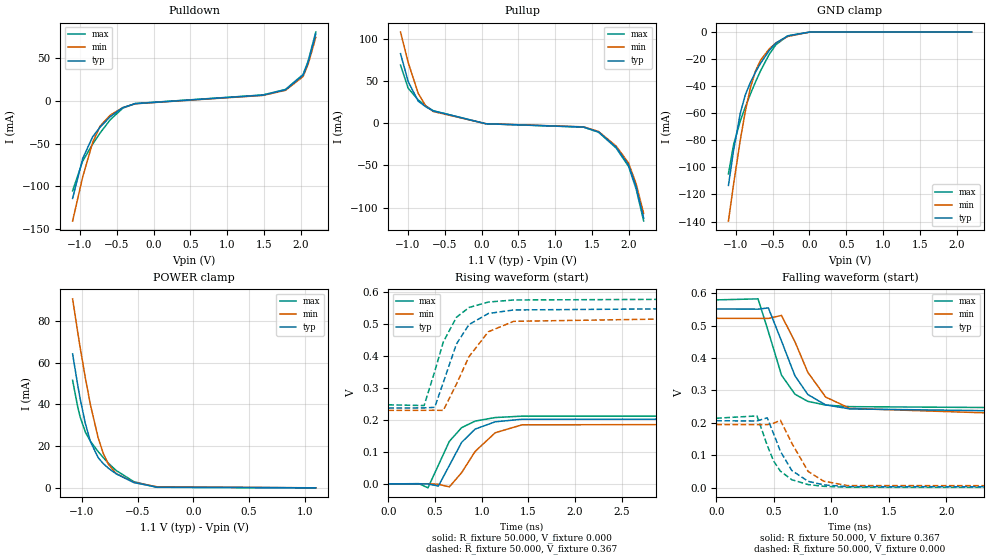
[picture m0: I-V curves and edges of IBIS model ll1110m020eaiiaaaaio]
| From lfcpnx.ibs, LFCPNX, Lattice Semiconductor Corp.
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|   Model ll1110m020eaiiaaaaio
[Model] ll1110m020eaiiaaaaio
| Clamp models do not include dynamic input termination. Please refer to
| the ll1110axxxeaiiaaaain model for input termination.
Model_type I/O
Polarity   Non-Inverting
Enable   Active-Low
Vinl =  0.093V
Vinh =  0.273V
Vmeas =  0.183V
Cref =  30.000pF
Rref =  50.000
Vref =  0.183V
C_comp   5.000pF   4.000pF   5.500pF
[Temperature Range]   25.000   0.125k   -40.000
[Voltage Range]   1.100V   1.050V   1.160V
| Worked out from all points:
|   slope of the pulldown table from 0 to 0.165 V, typ, clamps not added: 88.9 ohm
|   slope of the pullup table from 0 to 0.165 V, typ, clamps not added: 97.1 ohm
|   GND clamp passes 1 mA (typ) near -0.11 V on its own axis
|   POWER clamp passes 1 mA (typ) near -0.42 V on its own axis
|   rising waveform, R_fixture 50.000, V_fixture 0.000: 20-80 % time 270ps typ, 329ps min, 249ps max; typ from 0 V to 0.206 V
|   rising waveform, R_fixture 50.000, V_fixture 0.367: 20-80 % time 261ps typ, 328ps min, 243ps max; typ from 0.237 V to 0.551 V
|   falling waveform, R_fixture 50.000, V_fixture 0.367: 20-80 % time 233ps typ, 256ps min, 189ps max; typ from 0.551 V to 0.237 V
|   falling waveform, R_fixture 50.000, V_fixture 0.000: 20-80 % time 192ps typ, 199ps min, 174ps max; typ from 0.206 V to 0 V
[GND_clamp]
|Voltage   I(typ)   I(min)   I(max)
-1.1V     -113.3mA   -139.6mA   -104.8mA
-1.031V   -87.61mA   -112.7mA   -83.35mA
-939mV    -59.89mA   -79.66mA   -65.63mA
-870mV    -46.21mA   -58.29mA   -55.27mA
-801mV    -37.06mA   -41.02mA   -45.69mA
-732mV    -29.55mA   -28.66mA   -36.81mA
-663mV    -22.96mA   -20.75mA   -28.54mA
-548mV    -13.71mA   -12.59mA   -16.61mA
-456mV    -8.106mA   -8.062mA   -9.359mA
-295mV    -2.884mA   -3.249mA   -2.796mA
4mV       0A         0A         0A
2.2V      0A         0A         0A
[POWER_clamp]
|Voltage   I(typ)   I(min)   I(max)
-1.085V   64.25mA    90.66mA    51.57mA
-1.039V   49.25mA    74.63mA    38.81mA
-1.016V   42.45mA    66.98mA    33.78mA
-970mV    30.73mA    52.57mA    26.67mA
-924mV    22.04mA    39.64mA    22.28mA
-855mV    14.46mA    23.93mA    17.37mA
-809mV    11.59mA    16.44mA    14.47mA
-763mV    9.405mA    11.32mA    11.82mA
-694mV    6.715mA    6.853mA    8.328mA
-533mV    2.507mA    2.594mA    2.916mA
-326mV    306.4uA    502.5uA    259.1uA
1.1V      -3.028uA   0A         -8.363uA
[Pulldown]
|Voltage   I(typ)   I(min)   I(max)
-1.1V     -114.2mA   -140.7mA   -105.3mA
-964mV    -67.68mA   -89.34mA   -70.58mA
-828mV    -41.93mA   -48.55mA   -50.51mA
-726mV    -30.58mA   -29.28mA   -37.35mA
-590mV    -18.43mA   -16.59mA   -22.02mA
-420mV    -7.735mA   -7.773mA   -8.423mA
-250mV    -3.069mA   -3.175mA   -2.889mA
1.484V    6.95mA     6.603mA    7.159mA
1.79V     13.25mA    12.58mA    13.64mA
2.028V    30.31mA    28.79mA    31.22mA
2.096V    45.32mA    43.06mA    46.68mA
2.2V      78.56mA    74.63mA    80.92mA
[Pullup]
|Voltage   I(typ)   I(min)   I(max)
-1.1V     82.28mA    107.9mA    68.73mA
-996mV    49.24mA    71.8mA     41.37mA
-860mV    26.07mA    35.32mA    27.54mA
-758mV    19.43mA    20.46mA    20.55mA
-656mV    14.57mA    13.85mA    14.74mA
58mV      -657.6uA   -624.7uA   -677.3uA
1.384V    -4.554mA   -4.327mA   -4.691mA
1.588V    -10.36mA   -9.846mA   -10.68mA
1.826V    -28.51mA   -27.09mA   -29.37mA
1.996V    -49.8mA    -47.31mA   -51.29mA
2.098V    -75.73mA   -71.94mA   -78mA
2.2V      -112.4mA   -106.8mA   -115.8mA
[Ramp]
| variable   typ   min   max
dV/dt_r   0.124/0.269n   0.114/0.328n   0.128/0.248n
dV/dt_f   0.174/0.289n   0.165/0.324n   0.181/0.248n
R_load = 50.000
[Rising Waveform]
R_fixture = 50.000
V_fixture = 0.000
V_fixture_min = 0.000
V_fixture_max = 0.000
|  time   V(typ)   V(min)   V(max)
0s        4.368uV    140.6uV    -171.7uV
328ps     43.82uV    226.7uV    585.6uV
424ps     -341.1uV   251.7uV    -12.56mV
536ps     -6.971mV   -1.378mV   58.47mV
653ps     57.14mV    -9.526mV   132.8mV
785ps     129.8mV    34.89mV    175.9mV
930ps     171.4mV    101.5mV    196.4mV
1.145ns   194.2mV    159.9mV    207.5mV
1.433ns   202.2mV    184.8mV    211.9mV
30ns      206.5mV    194.9mV    214.3mV
[Rising Waveform]
R_fixture = 50.000
V_fixture = 0.367
V_fixture_min = 0.350
V_fixture_max = 0.386
|  time   V(typ)   V(min)   V(max)
0s        237.2mV    230mV      247.3mV
383ps     237.7mV    230.1mV    245.1mV
497ps     239.5mV    230.3mV    352.3mV
589ps     317.7mV    230mV      444.2mV
729ps     437.5mV    311.9mV    521.1mV
864ps     498.7mV    398mV      552mV
1.071ns   533.1mV    476mV      569mV
1.343ns   544.3mV    508.7mV    575.5mV
4.204ns   550.4mV    521.6mV    579mV
30ns      550.8mV    522.1mV    579mV
[Falling Waveform]
R_fixture = 50.000
V_fixture = 0.367
V_fixture_min = 0.350
V_fixture_max = 0.386
|  time   V(typ)   V(min)   V(max)
0s        550.9mV    522.1mV    579mV
363ps     550.4mV    522mV      582.1mV
453ps     554.2mV    521.9mV    481.1mV
567ps     452.3mV    531.1mV    347.3mV
684ps     345.1mV    450mV      288.4mV
796ps     287.4mV    355.9mV    266.3mV
951ps     255.4mV    279.6mV    254.9mV
1.163ns   243mV      244.4mV    250mV
2.377ns   237.4mV    230.5mV    247.3mV
30ns      237.2mV    230mV      247.3mV
[Falling Waveform]
R_fixture = 50.000
V_fixture = 0.000
V_fixture_min = 0.000
V_fixture_max = 0.000
|  time   V(typ)   V(min)   V(max)
0s        206.5mV    194.9mV    214.3mV
354ps     205.9mV    194.7mV    221.5mV
443ps     215.7mV    194.4mV    130.9mV
499ps     166mV      198.8mV    82.1mV
558ps     112.2mV    208.2mV    51.16mV
657ps     53.18mV    137.3mV    24.74mV
799ps     19.9mV     50.33mV    9.884mV
935ps     9.003mV    20.24mV    4.547mV
1.141ns   3.409mV    6.833mV    1.585mV
30ns      4.881uV    140.6uV    -171.7uV
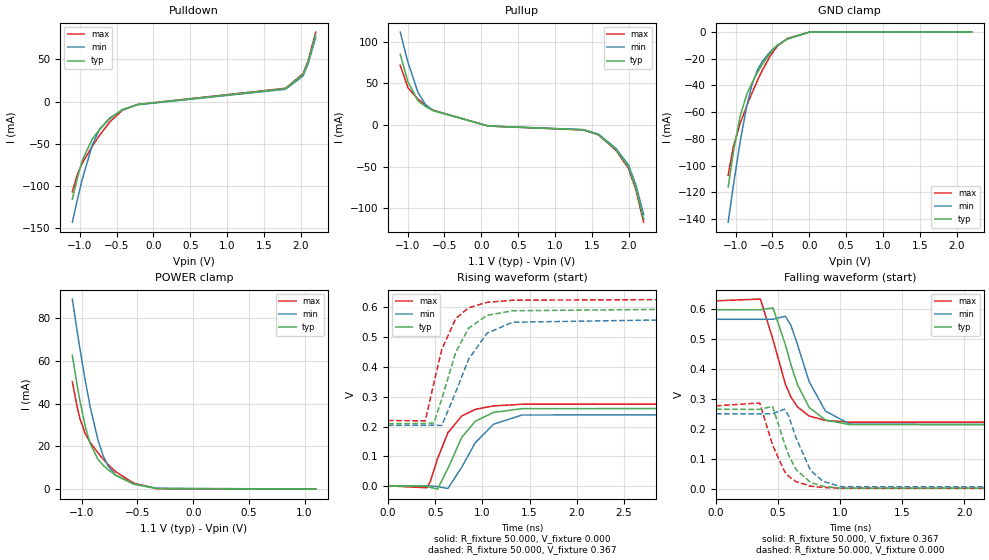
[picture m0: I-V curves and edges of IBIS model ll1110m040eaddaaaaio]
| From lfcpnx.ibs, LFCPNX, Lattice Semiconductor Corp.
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|   Model ll1110m040eaddaaaaio
[Model] ll1110m040eaddaaaaio
| Clamp models do not include dynamic input termination. Please refer to
| the ll1110axxxeaddaaaain model for input termination.
Model_type I/O
Polarity   Non-Inverting
Enable   Active-Low
Vinl =  0.093V
Vinh =  0.273V
Vmeas =  0.183V
Cref =  30.000pF
Rref =  50.000
Vref =  0.183V
C_comp   5.000pF   4.000pF   5.500pF
[Temperature Range]   25.000   0.125k   -40.000
[Voltage Range]   1.100V   1.050V   1.160V
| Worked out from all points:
|   slope of the pulldown table from 0 to 0.165 V, typ, clamps not added: 65.6 ohm
|   slope of the pullup table from 0 to 0.165 V, typ, clamps not added: 75 ohm
|   GND clamp passes 1 mA (typ) near -0.06 V on its own axis
|   POWER clamp passes 1 mA (typ) near -0.43 V on its own axis
|   rising waveform, R_fixture 50.000, V_fixture 0.000: 20-80 % time 279ps typ, 326ps min, 242ps max; typ from 0 V to 0.266 V
|   rising waveform, R_fixture 50.000, V_fixture 0.367: 20-80 % time 267ps typ, 313ps min, 224ps max; typ from 0.21 V to 0.598 V
|   falling waveform, R_fixture 50.000, V_fixture 0.367: 20-80 % time 193ps typ, 202ps min, 182ps max; typ from 0.598 V to 0.21 V
|   falling waveform, R_fixture 50.000, V_fixture 0.000: 20-80 % time 160ps typ, 164ps min, 154ps max; typ from 0.266 V to 0 V
[GND_clamp]
|Voltage   I(typ)   I(min)   I(max)
-1.1V     -116mA     -142.4mA   -107.2mA
-1.031V   -90.5mA    -115.5mA   -86.13mA
-939mV    -63.19mA   -82.59mA   -68.73mA
-847mV    -46.53mA   -55.17mA   -55.12mA
-778mV    -38.13mA   -39.66mA   -45.77mA
-709mV    -30.88mA   -29.05mA   -37.03mA
-640mV    -24.44mA   -22.18mA   -28.93mA
-525mV    -15.35mA   -14.4mA    -17.37mA
-433mV    -9.872mA   -9.815mA   -10.5mA
-295mV    -5.007mA   -5.179mA   -4.736mA
4mV       0A         0A         0A
2.2V      0A         0A         0A
[POWER_clamp]
|Voltage   I(typ)   I(min)   I(max)
-1.085V   62.71mA    89.06mA    50.33mA
-1.039V   47.85mA    73.11mA    37.83mA
-1.016V   41.15mA    65.51mA    32.96mA
-970mV    29.67mA    51.22mA    26.11mA
-924mV    21.26mA    38.44mA    21.86mA
-855mV    13.99mA    23.02mA    17.01mA
-809mV    11.21mA    15.73mA    14.14mA
-763mV    9.072mA    10.79mA    11.51mA
-694mV    6.435mA    6.507mA    8.075mA
-533mV    2.341mA    2.411mA    2.776mA
-326mV    246.9uA    426.9uA    220.2uA
1.1V      -11.15uA   -501.4nA   -14.12uA
[Pulldown]
|Voltage   I(typ)   I(min)   I(max)
-1.1V     -115.7mA   -142.9mA   -107mA
-1.032V   -90.64mA   -116.4mA   -86.27mA
-964mV    -69.46mA   -91.65mA   -72.75mA
-828mV    -44.01mA   -51.11mA   -52.68mA
-726mV    -32.65mA   -32.03mA   -39.47mA
-590mV    -20.36mA   -19.24mA   -24.02mA
-420mV    -9.347mA   -9.893mA   -10.12mA
-216mV    -3.518mA   -3.804mA   -3.44mA
1.79V     15.26mA    14.5mA     15.72mA
2.028V    32.04mA    30.44mA    33mA
2.096V    46.85mA    44.51mA    48.26mA
2.2V      79.9mA     75.9mA     82.29mA
[Pullup]
|Voltage   I(typ)   I(min)   I(max)
-1.1V     84.59mA    111.3mA    71.4mA
-996mV    51.79mA    75.29mA    44.61mA
-860mV    28.98mA    39.08mA    30.92mA
-758mV    22.19mA    24.35mA    23.73mA
-656mV    17.06mA    17.48mA    17.67mA
92mV      -1.311mA   -1.245mA   -1.35mA
1.384V    -5.864mA   -5.57mA    -6.04mA
1.588V    -11.62mA   -11.04mA   -11.97mA
1.826V    -29.71mA   -28.23mA   -30.6mA
1.996V    -50.89mA   -48.34mA   -52.41mA
2.098V    -76.64mA   -72.81mA   -78.94mA
2.2V      -113.2mA   -107.5mA   -116.6mA
[Ramp]
| variable   typ   min   max
dV/dt_r   0.160/0.278n   0.150/0.326n   0.165/0.241n
dV/dt_f   0.226/0.257n   0.211/0.270n   0.234/0.242n
R_load = 50.000
[Rising Waveform]
R_fixture = 50.000
V_fixture = 0.000
V_fixture_min = 0.000
V_fixture_max = 0.000
|  time   V(typ)   V(min)   V(max)
0s        3.84uV     405.9uV    1.234mV
411ps     776.4uV    466.7uV    -5.167mV
448ps     -4.019mV   782.4uV    15.6mV
524ps     -9.917mV   -1.198mV   91.93mV
634ps     59.23mV    -7.726mV   179.4mV
781ps     163.8mV    63.94mV    235.6mV
924ps     218mV      145.6mV    257.7mV
1.117ns   247.4mV    207.7mV    269.3mV
1.419ns   260.2mV    238.8mV    274.9mV
30ns      266.4mV    251.2mV    277.6mV
[Rising Waveform]
R_fixture = 50.000
V_fixture = 0.367
V_fixture_min = 0.350
V_fixture_max = 0.386
|  time   V(typ)   V(min)   V(max)
0s        209.7mV    204.2mV    220.3mV
394ps     210.2mV    204.3mV    219.1mV
486ps     212.1mV    204.7mV    346.4mV
570ps     293.4mV    203.6mV    459.6mV
718ps     450mV      316.3mV    562.5mV
854ps     529.8mV    426.2mV    598.5mV
1.048ns   572.9mV    513mV      616.6mV
1.319ns   588.5mV    550mV      623.9mV
4.479ns   597.5mV    565.4mV    627.7mV
30ns      598.1mV    566.2mV    627.7mV
[Falling Waveform]
R_fixture = 50.000
V_fixture = 0.367
V_fixture_min = 0.350
V_fixture_max = 0.386
|  time   V(typ)   V(min)   V(max)
0s        598.2mV    566.2mV    627.7mV
358ps     597.8mV    566.1mV    633.6mV
459ps     604.4mV    566.3mV    499mV
559ps     482.3mV    576.2mV    350.4mV
603ps     416.4mV    547.2mV    307.8mV
656ps     348.9mV    482.7mV    274.3mV
751ps     272.5mV    358.1mV    243.8mV
882ps     230.6mV    260.3mV    229.1mV
1.079ns   215.1mV    216.6mV    223.3mV
30ns      209.7mV    204.2mV    220.3mV
[Falling Waveform]
R_fixture = 50.000
V_fixture = 0.000
V_fixture_min = 0.000
V_fixture_max = 0.000
|  time   V(typ)   V(min)   V(max)
0s        266.4mV    251.2mV    277.6mV
353ps     265.9mV    251.1mV    287.4mV
456ps     275.8mV    251.4mV    146.8mV
552ps     152.4mV    266.7mV    59.21mV
586ps     112.9mV    244mV      42.89mV
646ps     65.18mV    170.3mV    24.89mV
762ps     22.32mV    62.81mV    10.06mV
862ps     9.507mV    26.09mV    5.643mV
1.009ns   3.468mV    8.182mV    3.262mV
30ns      4.863uV    405.9uV    1.234mV
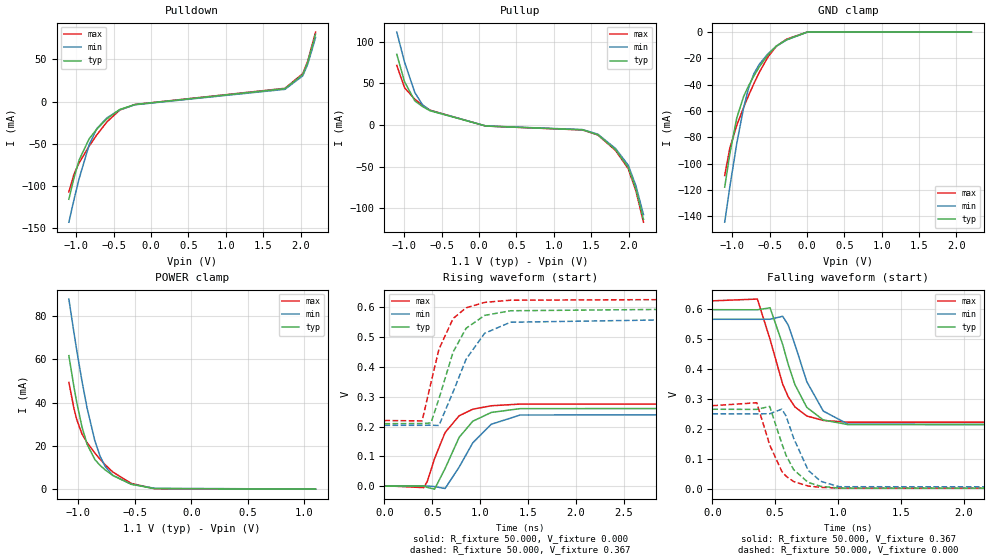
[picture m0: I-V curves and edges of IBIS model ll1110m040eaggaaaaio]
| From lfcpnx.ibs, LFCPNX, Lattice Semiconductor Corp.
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|   Model ll1110m040eaggaaaaio
[Model] ll1110m040eaggaaaaio
| Clamp models do not include dynamic input termination. Please refer to
| the ll1110axxxeaggaaaain model for input termination.
Model_type I/O
Polarity   Non-Inverting
Enable   Active-Low
Vinl =  0.093V
Vinh =  0.273V
Vmeas =  0.183V
Cref =  30.000pF
Rref =  50.000
Vref =  0.183V
C_comp   5.000pF   4.000pF   5.500pF
[Temperature Range]   25.000   0.125k   -40.000
[Voltage Range]   1.100V   1.050V   1.160V
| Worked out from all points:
|   slope of the pulldown table from 0 to 0.165 V, typ, clamps not added: 65.6 ohm
|   slope of the pullup table from 0 to 0.165 V, typ, clamps not added: 75 ohm
|   GND clamp passes 1 mA (typ) near -0.05 V on its own axis
|   POWER clamp passes 1 mA (typ) near -0.44 V on its own axis
|   rising waveform, R_fixture 50.000, V_fixture 0.000: 20-80 % time 279ps typ, 326ps min, 242ps max; typ from 0 V to 0.266 V
|   rising waveform, R_fixture 50.000, V_fixture 0.367: 20-80 % time 267ps typ, 313ps min, 224ps max; typ from 0.21 V to 0.598 V
|   falling waveform, R_fixture 50.000, V_fixture 0.367: 20-80 % time 193ps typ, 202ps min, 182ps max; typ from 0.598 V to 0.21 V
|   falling waveform, R_fixture 50.000, V_fixture 0.000: 20-80 % time 160ps typ, 164ps min, 154ps max; typ from 0.266 V to 0 V
[GND_clamp]
|Voltage   I(typ)   I(min)   I(max)
-1.1V     -117.8mA   -144.4mA   -108.9mA
-1.031V   -92.39mA   -117.5mA   -88.07mA
-939mV    -65.35mA   -84.74mA   -70.87mA
-847mV    -48.93mA   -57.47mA   -57.24mA
-778mV    -40.53mA   -42.1mA    -47.86mA
-709mV    -33.25mA   -31.59mA   -39.07mA
-640mV    -26.73mA   -24.69mA   -30.91mA
-525mV    -17.44mA   -16.67mA   -19.2mA
-410mV    -10.6mA    -10.77mA   -10.78mA
-272mV    -5.792mA   -5.969mA   -5.355mA
4mV       0A         0A         0A
2.2V      0A         0A         0A
[POWER_clamp]
|Voltage   I(typ)   I(min)   I(max)
-1.085V   61.74mA    87.92mA    49.38mA
-1.039V   46.98mA    72.04mA    37.07mA
-1.016V   40.35mA    64.47mA    32.31mA
-970mV    29.02mA    50.27mA    25.66mA
-924mV    20.79mA    37.6mA     21.51mA
-855mV    13.71mA    22.38mA    16.7mA
-809mV    10.99mA    15.25mA    13.85mA
-763mV    8.879mA    10.44mA    11.25mA
-694mV    6.274mA    6.278mA    7.853mA
-533mV    2.248mA    2.293mA    2.647mA
-326mV    216.7uA    380.5uA    177.7uA
1.1V      -16.31uA   -2.388uA   -25.69uA
[Pulldown]
|Voltage   I(typ)   I(min)   I(max)
-1.1V     -115.7mA   -142.9mA   -107mA
-1.032V   -90.64mA   -116.4mA   -86.27mA
-964mV    -69.46mA   -91.65mA   -72.75mA
-828mV    -44.01mA   -51.11mA   -52.68mA
-726mV    -32.65mA   -32.03mA   -39.47mA
-590mV    -20.36mA   -19.24mA   -24.02mA
-420mV    -9.347mA   -9.893mA   -10.12mA
-216mV    -3.518mA   -3.804mA   -3.44mA
1.79V     15.26mA    14.5mA     15.72mA
2.028V    32.04mA    30.44mA    33mA
2.096V    46.85mA    44.51mA    48.26mA
2.2V      79.9mA     75.9mA     82.29mA
[Pullup]
|Voltage   I(typ)   I(min)   I(max)
-1.1V     84.59mA    111.3mA    71.4mA
-996mV    51.79mA    75.29mA    44.61mA
-860mV    28.98mA    39.08mA    30.92mA
-758mV    22.19mA    24.35mA    23.73mA
-656mV    17.06mA    17.48mA    17.67mA
92mV      -1.311mA   -1.245mA   -1.35mA
1.384V    -5.864mA   -5.57mA    -6.04mA
1.588V    -11.62mA   -11.04mA   -11.97mA
1.826V    -29.71mA   -28.23mA   -30.6mA
1.996V    -50.89mA   -48.34mA   -52.41mA
2.098V    -76.64mA   -72.81mA   -78.94mA
2.2V      -113.2mA   -107.5mA   -116.6mA
[Ramp]
| variable   typ   min   max
dV/dt_r   0.160/0.278n   0.150/0.326n   0.165/0.241n
dV/dt_f   0.226/0.257n   0.211/0.270n   0.234/0.242n
R_load = 50.000
[Rising Waveform]
R_fixture = 50.000
V_fixture = 0.000
V_fixture_min = 0.000
V_fixture_max = 0.000
|  time   V(typ)   V(min)   V(max)
0s        3.84uV     405.9uV    1.645mV
411ps     776.4uV    466.7uV    -4.759mV
448ps     -4.019mV   782.4uV    16.02mV
524ps     -9.917mV   -1.198mV   92.39mV
634ps     59.23mV    -7.726mV   179.9mV
781ps     163.8mV    63.94mV    236.2mV
924ps     218mV      145.6mV    258.3mV
1.117ns   247.4mV    207.7mV    269.8mV
1.419ns   260.2mV    238.8mV    275.5mV
30ns      266.4mV    251.2mV    278.2mV
[Rising Waveform]
R_fixture = 50.000
V_fixture = 0.367
V_fixture_min = 0.350
V_fixture_max = 0.386
|  time   V(typ)   V(min)   V(max)
0s        209.7mV    204.2mV    220.3mV
394ps     210.2mV    204.3mV    219.1mV
486ps     212.1mV    204.7mV    346.4mV
570ps     293.4mV    203.6mV    459.6mV
718ps     450mV      316.3mV    562.5mV
854ps     529.8mV    426.2mV    598.5mV
1.048ns   572.9mV    513mV      616.6mV
1.319ns   588.5mV    550mV      623.9mV
4.479ns   597.5mV    565.4mV    627.7mV
30ns      598.1mV    566.2mV    627.7mV
[Falling Waveform]
R_fixture = 50.000
V_fixture = 0.367
V_fixture_min = 0.350
V_fixture_max = 0.386
|  time   V(typ)   V(min)   V(max)
0s        598.2mV    566.2mV    627.7mV
358ps     597.8mV    566.1mV    633.6mV
459ps     604.4mV    566.3mV    499mV
559ps     482.3mV    576.2mV    350.4mV
603ps     416.4mV    547.2mV    307.8mV
656ps     348.9mV    482.7mV    274.3mV
751ps     272.5mV    358.1mV    243.8mV
882ps     230.6mV    260.3mV    229.1mV
1.079ns   215.1mV    216.6mV    223.3mV
30ns      209.7mV    204.2mV    220.3mV
[Falling Waveform]
R_fixture = 50.000
V_fixture = 0.000
V_fixture_min = 0.000
V_fixture_max = 0.000
|  time   V(typ)   V(min)   V(max)
0s        266.4mV    251.2mV    278.2mV
353ps     265.9mV    251.1mV    288mV
456ps     275.8mV    251.4mV    147.3mV
552ps     152.4mV    266.7mV    59.65mV
586ps     112.9mV    244mV      43.32mV
646ps     65.18mV    170.3mV    25.31mV
762ps     22.32mV    62.81mV    10.48mV
862ps     9.507mV    26.09mV    6.056mV
1.009ns   3.468mV    8.182mV    3.674mV
30ns      4.863uV    405.9uV    1.645mV
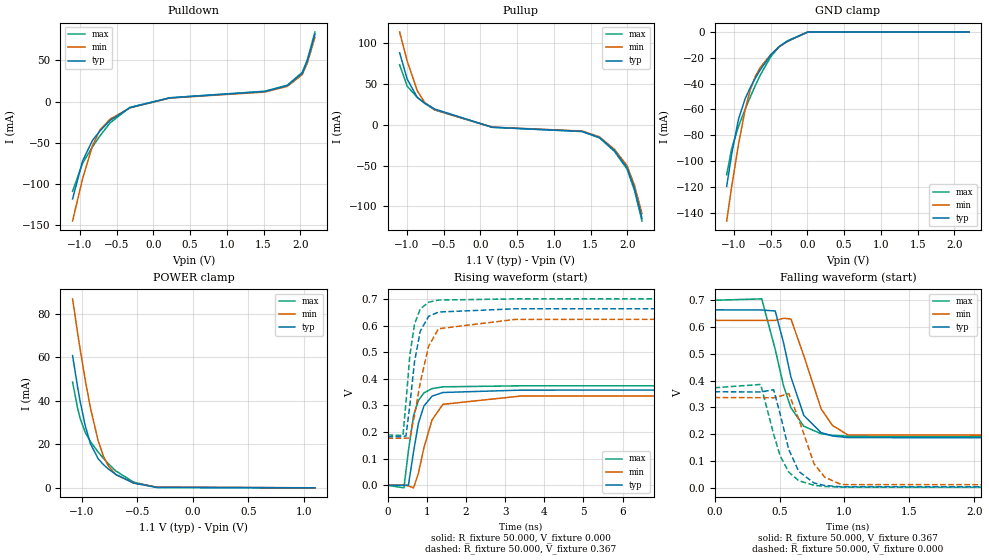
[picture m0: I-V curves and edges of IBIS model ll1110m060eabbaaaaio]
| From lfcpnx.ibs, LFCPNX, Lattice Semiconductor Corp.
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|   Model ll1110m060eabbaaaaio
[Model] ll1110m060eabbaaaaio
| Clamp models do not include dynamic input termination. Please refer to
| the ll1110axxxeabbaaaain model for input termination.
Model_type I/O
Polarity   Non-Inverting
Enable   Active-Low
Vinl =  0.093V
Vinh =  0.273V
Vmeas =  0.183V
Cref =  30.000pF
Rref =  50.000
Vref =  0.183V
C_comp   5.000pF   4.000pF   5.500pF
[Temperature Range]   25.000   0.125k   -40.000
[Voltage Range]   1.100V   1.050V   1.160V
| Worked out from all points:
|   slope of the pulldown table from 0 to 0.165 V, typ, clamps not added: 49 ohm
|   slope of the pullup table from 0 to 0.165 V, typ, clamps not added: 54.8 ohm
|   GND clamp passes 1 mA (typ) near -0.04 V on its own axis
|   POWER clamp passes 1 mA (typ) near -0.45 V on its own axis
|   rising waveform, R_fixture 50.000, V_fixture 0.000: 20-80 % time 282ps typ, 395ps min, 239ps max; typ from 0 V to 0.358 V
|   rising waveform, R_fixture 50.000, V_fixture 0.367: 20-80 % time 261ps typ, 387ps min, 217ps max; typ from 0.182 V to 0.665 V
|   falling waveform, R_fixture 50.000, V_fixture 0.367: 20-80 % time 159ps typ, 189ps min, 164ps max; typ from 0.665 V to 0.182 V
|   falling waveform, R_fixture 50.000, V_fixture 0.000: 20-80 % time 134ps typ, 153ps min, 141ps max; typ from 0.358 V to 0 V
[GND_clamp]
|Voltage   I(typ)   I(min)   I(max)
-1.1V     -119.6mA   -146.5mA   -110.6mA
-1.031V   -94.37mA   -119.6mA   -90.12mA
-939mV    -67.61mA   -86.97mA   -73.15mA
-847mV    -51.42mA   -59.87mA   -59.55mA
-778mV    -43.02mA   -44.64mA   -50.18mA
-709mV    -35.68mA   -34.21mA   -41.36mA
-640mV    -29.08mA   -27.27mA   -33.15mA
-502mV    -17.94mA   -17.61mA   -19.3mA
-387mV    -11.32mA   -11.67mA   -11.39mA
-272mV    -7.089mA   -7.328mA   -6.742mA
4mV       0A         0A         0A
2.2V      0A         0A         0A
[POWER_clamp]
|Voltage   I(typ)   I(min)   I(max)
-1.085V   60.71mA    86.73mA    48.54mA
-1.039V   46.06mA    70.92mA    36.41mA
-1.016V   39.49mA    63.39mA    31.77mA
-970mV    28.33mA    49.28mA    25.3mA
-924mV    20.28mA    36.72mA    21.23mA
-855mV    13.4mA     21.73mA    16.47mA
-809mV    10.74mA    14.75mA    13.64mA
-763mV    8.663mA    10.07mA    11.05mA
-694mV    6.094mA    6.035mA    7.687mA
-533mV    2.142mA    2.166mA    2.559mA
-326mV    180.6uA    329.6uA    155.6uA
1.1V      -23.7uA    -6.491uA   -29.42uA
[Pulldown]
|Voltage   I(typ)   I(min)   I(max)
-1.1V     -117.9mA   -144.6mA   -108.6mA
-964mV    -71.92mA   -93.46mA   -74.75mA
-828mV    -46.86mA   -53.12mA   -54.68mA
-726mV    -35.44mA   -34.2mA    -41.42mA
-590mV    -22.93mA   -21.33mA   -25.83mA
-318mV    -7.319mA   -7.58mA    -6.947mA
226mV     4.511mA    4.285mA    4.646mA
1.518V    12.17mA    11.56mA    12.54mA
1.824V    19.3mA     18.33mA    19.88mA
2.028V    34.44mA    32.71mA    35.47mA
2.096V    48.95mA    46.51mA    50.42mA
2.2V      81.73mA    77.65mA    84.19mA
[Pullup]
|Voltage   I(typ)   I(min)   I(max)
-1.1V     88.32mA    113.8mA    73.59mA
-996mV    55.91mA    77.94mA    47.28mA
-860mV    33.67mA    41.95mA    33.68mA
-758mV    26.63mA    27.31mA    26.33mA
-622mV    19.41mA    18.58mA    18.27mA
160mV     -2.933mA   -2.787mA   -3.021mA
1.384V    -7.973mA   -7.575mA   -8.213mA
1.622V    -15.55mA   -14.78mA   -16.02mA
1.826V    -31.65mA   -30.06mA   -32.6mA
1.996V    -52.64mA   -50.01mA   -54.22mA
2.098V    -78.11mA   -74.21mA   -80.45mA
2.2V      -114.5mA   -108.8mA   -117.9mA
[Ramp]
| variable   typ   min   max
dV/dt_r   0.215/0.281n   0.202/0.394n   0.224/0.238n
dV/dt_f   0.287/0.224n   0.272/0.270n   0.302/0.225n
R_load = 50.000
[Rising Waveform]
R_fixture = 50.000
V_fixture = 0.000
V_fixture_min = 0.000
V_fixture_max = 0.000
|  time   V(typ)   V(min)   V(max)
0s        3.319uV    89.43uV    -354uV
419ps     -298uV     178.8uV    -9.939mV
534ps     213.6uV    -2.945mV   130mV
665ps     125.9mV    -10.01mV   261.4mV
788ps     232.4mV    44.6mV     318.4mV
929ps     297.7mV    140.6mV    347.1mV
1.136ns   334.6mV    245.1mV    363mV
1.413ns   348.5mV    304mV      369.8mV
3.401ns   357.4mV    335.2mV    373.6mV
30ns      358.4mV    336.9mV    373.6mV
[Rising Waveform]
R_fixture = 50.000
V_fixture = 0.367
V_fixture_min = 0.350
V_fixture_max = 0.386
|  time   V(typ)   V(min)   V(max)
0s        182.2mV    176.5mV    189mV
395ps     182.9mV    176.6mV    186.8mV
472ps     185.5mV    176.9mV    312.9mV
570ps     301.3mV    177.2mV    488.8mV
690ps     464.4mV    263.3mV    606mV
835ps     578.7mV    385.2mV    662.5mV
1.049ns   634.8mV    522.8mV    688mV
1.302ns   651mV      588.2mV    696mV
3.262ns   663.2mV    623.3mV    700.5mV
30ns      664.6mV    625.4mV    700.5mV
[Falling Waveform]
R_fixture = 50.000
V_fixture = 0.367
V_fixture_min = 0.350
V_fixture_max = 0.386
|  time   V(typ)   V(min)   V(max)
0s        664.6mV    625.5mV    700.5mV
363ps     664.2mV    625.1mV    705.7mV
467ps     660.4mV    625.3mV    516.8mV
532ps     539.5mV    633.2mV    379mV
588ps     413.4mV    630.6mV    298.4mV
687ps     270.3mV    493.2mV    229.8mV
820ps     206mV      294.9mV    201.9mV
907ps     193.5mV    232.9mV    196.1mV
1.026ns   187.3mV    197.5mV    192.7mV
30ns      182.2mV    176.5mV    189mV
[Falling Waveform]
R_fixture = 50.000
V_fixture = 0.000
V_fixture_min = 0.000
V_fixture_max = 0.000
|  time   V(typ)   V(min)   V(max)
0s        358.5mV    337mV      373.6mV
355ps     357.9mV    336.5mV    386mV
455ps     366mV      336.3mV    199.7mV
505ps     275.2mV    342.5mV    118.8mV
571ps     143.2mV    351.8mV    58.48mV
648ps     61.06mV    256.7mV    26.38mV
766ps     17.62mV    88.96mV    9.028mV
849ps     8.308mV    39.17mV    4.858mV
976ps     3.5mV      11.9mV     2.254mV
30ns      4.904uV    95.63uV    -354uV
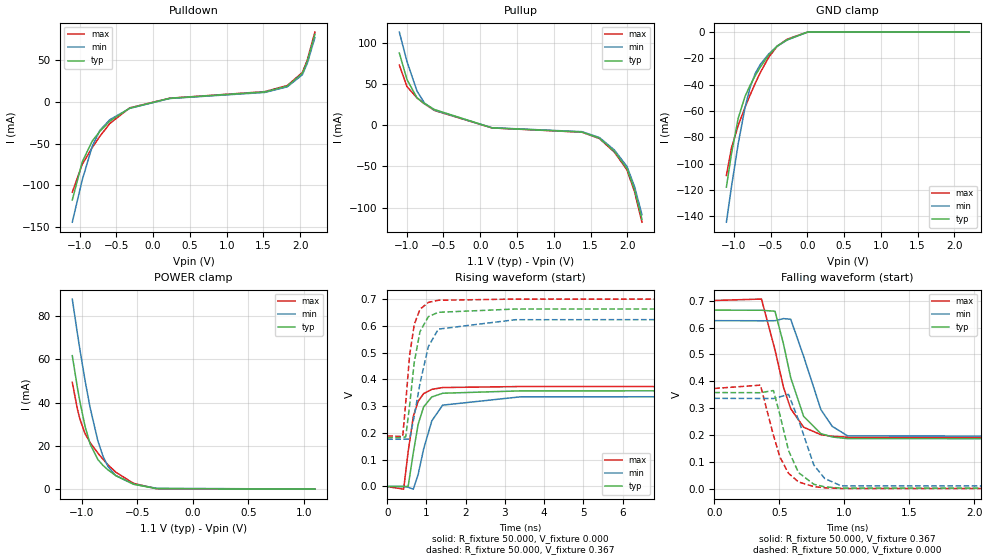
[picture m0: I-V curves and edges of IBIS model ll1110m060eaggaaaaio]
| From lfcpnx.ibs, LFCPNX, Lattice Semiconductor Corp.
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|   Model ll1110m060eaggaaaaio
[Model] ll1110m060eaggaaaaio
| Clamp models do not include dynamic input termination. Please refer to
| the ll1110axxxeaggaaaain model for input termination.
Model_type I/O
Polarity   Non-Inverting
Enable   Active-Low
Vinl =  0.093V
Vinh =  0.273V
Vmeas =  0.183V
Cref =  30.000pF
Rref =  50.000
Vref =  0.183V
C_comp   5.000pF   4.000pF   5.500pF
[Temperature Range]   25.000   0.125k   -40.000
[Voltage Range]   1.100V   1.050V   1.160V
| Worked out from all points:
|   slope of the pulldown table from 0 to 0.165 V, typ, clamps not added: 49 ohm
|   slope of the pullup table from 0 to 0.165 V, typ, clamps not added: 54.8 ohm
|   GND clamp passes 1 mA (typ) near -0.05 V on its own axis
|   POWER clamp passes 1 mA (typ) near -0.44 V on its own axis
|   rising waveform, R_fixture 50.000, V_fixture 0.000: 20-80 % time 282ps typ, 395ps min, 239ps max; typ from 0 V to 0.358 V
|   rising waveform, R_fixture 50.000, V_fixture 0.367: 20-80 % time 261ps typ, 387ps min, 217ps max; typ from 0.182 V to 0.665 V
|   falling waveform, R_fixture 50.000, V_fixture 0.367: 20-80 % time 159ps typ, 189ps min, 164ps max; typ from 0.665 V to 0.182 V
|   falling waveform, R_fixture 50.000, V_fixture 0.000: 20-80 % time 134ps typ, 153ps min, 141ps max; typ from 0.358 V to 0 V
[GND_clamp]
|Voltage   I(typ)   I(min)   I(max)
-1.1V     -117.8mA   -144.4mA   -108.9mA
-1.031V   -92.39mA   -117.5mA   -88.07mA
-939mV    -65.35mA   -84.74mA   -70.87mA
-847mV    -48.93mA   -57.47mA   -57.24mA
-778mV    -40.53mA   -42.1mA    -47.86mA
-709mV    -33.25mA   -31.59mA   -39.07mA
-640mV    -26.73mA   -24.69mA   -30.91mA
-525mV    -17.44mA   -16.67mA   -19.2mA
-410mV    -10.6mA    -10.77mA   -10.78mA
-272mV    -5.792mA   -5.969mA   -5.355mA
4mV       0A         0A         0A
2.2V      0A         0A         0A
[POWER_clamp]
|Voltage   I(typ)   I(min)   I(max)
-1.085V   61.74mA    87.92mA    49.38mA
-1.039V   46.98mA    72.04mA    37.07mA
-1.016V   40.35mA    64.47mA    32.31mA
-970mV    29.02mA    50.27mA    25.66mA
-924mV    20.79mA    37.6mA     21.51mA
-855mV    13.71mA    22.38mA    16.7mA
-809mV    10.99mA    15.25mA    13.85mA
-763mV    8.879mA    10.44mA    11.25mA
-694mV    6.274mA    6.278mA    7.853mA
-533mV    2.248mA    2.293mA    2.647mA
-326mV    216.7uA    380.5uA    177.7uA
1.1V      -16.31uA   -2.388uA   -25.69uA
[Pulldown]
|Voltage   I(typ)   I(min)   I(max)
-1.1V     -117.9mA   -144.6mA   -108.6mA
-964mV    -71.92mA   -93.46mA   -74.75mA
-828mV    -46.86mA   -53.12mA   -54.68mA
-726mV    -35.44mA   -34.2mA    -41.42mA
-590mV    -22.93mA   -21.33mA   -25.83mA
-318mV    -7.319mA   -7.58mA    -6.947mA
226mV     4.511mA    4.285mA    4.646mA
1.518V    12.17mA    11.56mA    12.54mA
1.824V    19.3mA     18.33mA    19.88mA
2.028V    34.44mA    32.71mA    35.47mA
2.096V    48.95mA    46.51mA    50.42mA
2.2V      81.73mA    77.65mA    84.19mA
[Pullup]
|Voltage   I(typ)   I(min)   I(max)
-1.1V     88.32mA    113.8mA    73.59mA
-996mV    55.91mA    77.94mA    47.28mA
-860mV    33.67mA    41.95mA    33.68mA
-758mV    26.63mA    27.31mA    26.33mA
-622mV    19.41mA    18.58mA    18.27mA
160mV     -2.933mA   -2.787mA   -3.021mA
1.384V    -7.973mA   -7.575mA   -8.213mA
1.622V    -15.55mA   -14.78mA   -16.02mA
1.826V    -31.65mA   -30.06mA   -32.6mA
1.996V    -52.64mA   -50.01mA   -54.22mA
2.098V    -78.11mA   -74.21mA   -80.45mA
2.2V      -114.5mA   -108.8mA   -117.9mA
[Ramp]
| variable   typ   min   max
dV/dt_r   0.215/0.281n   0.202/0.394n   0.224/0.238n
dV/dt_f   0.287/0.224n   0.272/0.270n   0.302/0.225n
R_load = 50.000
[Rising Waveform]
R_fixture = 50.000
V_fixture = 0.000
V_fixture_min = 0.000
V_fixture_max = 0.000
|  time   V(typ)   V(min)   V(max)
0s        3.319uV    89.43uV    -354uV
419ps     -298uV     178.8uV    -9.939mV
534ps     213.6uV    -2.945mV   130mV
665ps     125.9mV    -10.01mV   261.4mV
788ps     232.4mV    44.6mV     318.4mV
929ps     297.7mV    140.6mV    347.1mV
1.136ns   334.6mV    245.1mV    363mV
1.413ns   348.5mV    304mV      369.8mV
3.401ns   357.4mV    335.2mV    373.6mV
30ns      358.4mV    336.9mV    373.6mV
[Rising Waveform]
R_fixture = 50.000
V_fixture = 0.367
V_fixture_min = 0.350
V_fixture_max = 0.386
|  time   V(typ)   V(min)   V(max)
0s        182.2mV    176.5mV    189mV
395ps     182.9mV    176.6mV    186.8mV
472ps     185.5mV    176.9mV    312.9mV
570ps     301.3mV    177.2mV    488.8mV
690ps     464.4mV    263.3mV    606mV
835ps     578.7mV    385.2mV    662.5mV
1.049ns   634.8mV    522.8mV    688mV
1.302ns   651mV      588.2mV    696mV
3.262ns   663.2mV    623.3mV    700.5mV
30ns      664.6mV    625.4mV    700.5mV
[Falling Waveform]
R_fixture = 50.000
V_fixture = 0.367
V_fixture_min = 0.350
V_fixture_max = 0.386
|  time   V(typ)   V(min)   V(max)
0s        664.6mV    625.5mV    700.5mV
363ps     664.2mV    625.1mV    705.7mV
467ps     660.4mV    625.3mV    516.8mV
532ps     539.5mV    633.2mV    379mV
588ps     413.4mV    630.6mV    298.4mV
687ps     270.3mV    493.2mV    229.8mV
820ps     206mV      294.9mV    201.9mV
907ps     193.5mV    232.9mV    196.1mV
1.026ns   187.3mV    197.5mV    192.7mV
30ns      182.2mV    176.5mV    189mV
[Falling Waveform]
R_fixture = 50.000
V_fixture = 0.000
V_fixture_min = 0.000
V_fixture_max = 0.000
|  time   V(typ)   V(min)   V(max)
0s        358.5mV    337mV      373.6mV
355ps     357.9mV    336.5mV    386mV
455ps     366mV      336.3mV    199.7mV
505ps     275.2mV    342.5mV    118.8mV
571ps     143.2mV    351.8mV    58.48mV
648ps     61.06mV    256.7mV    26.38mV
766ps     17.62mV    88.96mV    9.028mV
849ps     8.308mV    39.17mV    4.858mV
976ps     3.5mV      11.9mV     2.254mV
30ns      4.904uV    95.63uV    -354uV
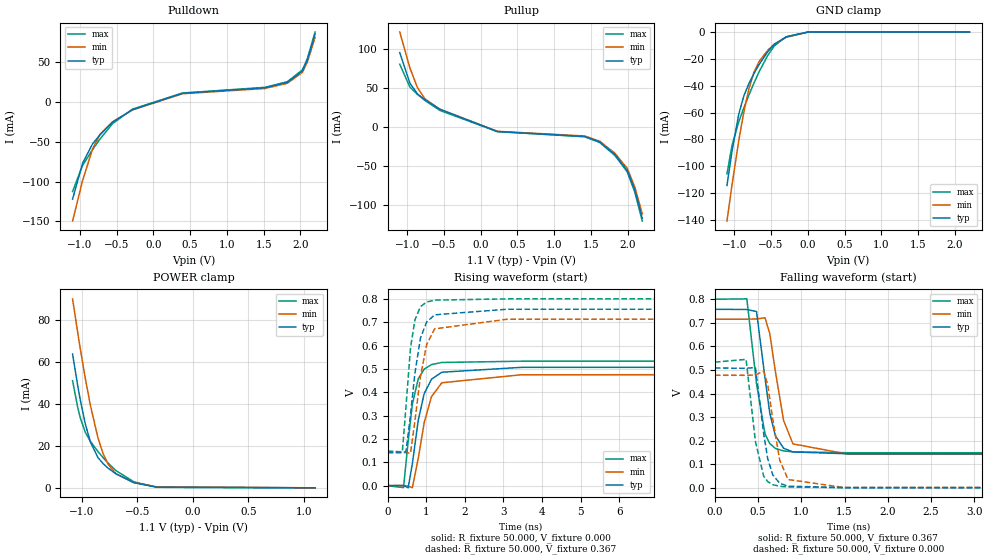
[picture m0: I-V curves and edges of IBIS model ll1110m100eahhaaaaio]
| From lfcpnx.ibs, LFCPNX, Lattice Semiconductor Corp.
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|   Model ll1110m100eahhaaaaio
[Model] ll1110m100eahhaaaaio
| Clamp models do not include dynamic input termination. Please refer to
| the ll1110axxxeahhaaaain model for input termination.
Model_type I/O
Polarity   Non-Inverting
Enable   Active-Low
Vinl =  0.093V
Vinh =  0.273V
Vmeas =  0.183V
Cref =  30.000pF
Rref =  50.000
Vref =  0.183V
C_comp   5.000pF   4.000pF   5.500pF
[Temperature Range]   25.000   0.125k   -40.000
[Voltage Range]   1.100V   1.050V   1.160V
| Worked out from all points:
|   slope of the pulldown table from 0 to 0.165 V, typ, clamps not added: 32.2 ohm
|   slope of the pullup table from 0 to 0.165 V, typ, clamps not added: 36.7 ohm
|   GND clamp passes 1 mA (typ) near -0.09 V on its own axis
|   POWER clamp passes 1 mA (typ) near -0.43 V on its own axis
|   rising waveform, R_fixture 50.000, V_fixture 0.000: 20-80 % time 326ps typ, 364ps min, 244ps max; typ from 0 V to 0.508 V
|   rising waveform, R_fixture 50.000, V_fixture 0.367: 20-80 % time 286ps typ, 312ps min, 206ps max; typ from 0.143 V to 0.757 V
|   falling waveform, R_fixture 50.000, V_fixture 0.367: 20-80 % time 134ps typ, 157ps min, 123ps max; typ from 0.757 V to 0.143 V
|   falling waveform, R_fixture 50.000, V_fixture 0.000: 20-80 % time 114ps typ, 131ps min, 106ps max; typ from 0.508 V to 0 V
[GND_clamp]
|Voltage   I(typ)   I(min)   I(max)
-1.1V     -114.2mA   -140.7mA   -105.6mA
-1.031V   -88.59mA   -113.7mA   -84.35mA
-939mV    -61.01mA   -80.73mA   -66.75mA
-870mV    -47.45mA   -59.42mA   -56.41mA
-801mV    -38.33mA   -42.21mA   -46.83mA
-732mV    -30.8mA    -29.9mA    -37.93mA
-663mV    -24.18mA   -22.01mA   -29.65mA
-548mV    -14.83mA   -13.74mA   -17.67mA
-456mV    -9.123mA   -9.074mA   -10.34mA
-295mV    -3.613mA   -3.95mA    -3.534mA
4mV       0A         0A         0A
2.2V      0A         0A         0A
[POWER_clamp]
|Voltage   I(typ)   I(min)   I(max)
-1.085V   63.74mA    90.06mA    51.09mA
-1.039V   48.78mA    74.06mA    38.42mA
-1.016V   42.02mA    66.43mA    33.46mA
-970mV    30.38mA    52.06mA    26.44mA
-924mV    21.79mA    39.19mA    22.11mA
-855mV    14.31mA    23.58mA    17.22mA
-809mV    11.47mA    16.17mA    14.33mA
-763mV    9.3mA      11.11mA    11.69mA
-694mV    6.627mA    6.717mA    8.221mA
-533mV    2.456mA    2.52mA     2.855mA
-326mV    289uA      471.4uA    239.4uA
1.1V      -4.623uA   0A         -12.27uA
[Pulldown]
|Voltage   I(typ)   I(min)   I(max)
-1.1V     -122.1mA   -149.6mA   -112.5mA
-964mV    -76.95mA   -98.79mA   -79.76mA
-828mV    -52.64mA   -59.02mA   -59.78mA
-726mV    -41.12mA   -40.52mA   -46.43mA
-556mV    -25.33mA   -24.85mA   -27.11mA
-284mV    -9.46mA    -9.911mA   -8.919mA
396mV     11.02mA    10.47mA    11.35mA
1.518V    17.95mA    17.05mA    18.49mA
1.824V    24.9mA     23.66mA    25.65mA
2.028V    39.34mA    37.38mA    40.52mA
2.096V    53.27mA    50.61mA    54.87mA
2.2V      85.49mA    81.21mA    88.05mA
[Pullup]
|Voltage   I(typ)   I(min)   I(max)
-1.1V     95.25mA    121.5mA    80.24mA
-962mV    56.01mA    75.48mA    50.98mA
-860mV    42.29mA    50.45mA    41.81mA
-758mV    34.74mA    36.01mA    33.93mA
-554mV    22.7mA     22.63mA    21.2mA
228mV     -5.849mA   -5.557mA   -6.025mA
1.418V    -12.2mA    -11.59mA   -12.57mA
1.622V    -19.3mA    -18.33mA   -19.88mA
1.826V    -35.25mA   -33.49mA   -36.31mA
1.996V    -55.92mA   -53.13mA   -57.6mA
2.098V    -80.86mA   -76.82mA   -83.29mA
2.2V      -116.9mA   -111.1mA   -120.4mA
[Ramp]
| variable   typ   min   max
dV/dt_r   0.305/0.325n   0.296/0.364n   0.320/0.244n
dV/dt_f   0.375/0.190n   0.361/0.214n   0.385/0.177n
R_load = 50.000
[Rising Waveform]
R_fixture = 50.000
V_fixture = 0.000
V_fixture_min = 0.000
V_fixture_max = 0.000
|  time   V(typ)   V(min)   V(max)
0s        2.583uV    349.1uV    -317.2uV
411ps     782.3uV    401.2uV    -8.457mV
532ps     -9.448mV   -2.402mV   190mV
641ps     94.45mV    -8.663mV   349.8mV
794ps     280.9mV    117.8mV    457.9mV
946ps     393.9mV    268.8mV    499.1mV
1.135ns   455.9mV    380.9mV    518.4mV
1.404ns   485.9mV    440.7mV    527.7mV
3.457ns   506.6mV    474.9mV    533mV
30ns      508.2mV    477.4mV    533mV
[Rising Waveform]
R_fixture = 50.000
V_fixture = 0.367
V_fixture_min = 0.350
V_fixture_max = 0.386
|  time   V(typ)   V(min)   V(max)
0s        143.3mV    140.9mV    148.2mV
381ps     143.8mV    140.9mV    144.8mV
473ps     144.4mV    141.7mV    334.3mV
592ps     301.8mV    138.7mV    588.8mV
706ps     481.2mV    275.6mV    709.7mV
850ps     631.3mV    468.7mV    766.7mV
1.011ns   701mV      604.2mV    786.7mV
1.219ns   731.7mV    671.7mV    794.7mV
3.095ns   755.7mV    712.8mV    800.1mV
30ns      757.2mV    715.2mV    800.1mV
[Falling Waveform]
R_fixture = 50.000
V_fixture = 0.367
V_fixture_min = 0.350
V_fixture_max = 0.386
|  time   V(typ)   V(min)   V(max)
0s        757.3mV    715.2mV    800.1mV
370ps     756.6mV    715.2mV    801.6mV
482ps     747.7mV    716.5mV    441.8mV
580ps     465.8mV    721.4mV    228.6mV
635ps     317.6mV    654.6mV    187.7mV
700ps     220.5mV    493.1mV    167mV
795ps     167.8mV    285.5mV    156.4mV
903ps     151.9mV    186.3mV    152.5mV
1.542ns   144.2mV    142.2mV    148.7mV
30ns      143.3mV    140.9mV    148.2mV
[Falling Waveform]
R_fixture = 50.000
V_fixture = 0.000
V_fixture_min = 0.000
V_fixture_max = 0.000
|  time   V(typ)   V(min)   V(max)
0s        508.2mV    477.4mV    533mV
361ps     507.1mV    477.3mV    544.8mV
469ps     510.2mV    478.6mV    196.9mV
565ps     229.2mV    495.2mV    48.83mV
612ps     122.2mV    435.1mV    26.02mV
670ps     54.37mV    289.8mV    13.18mV
751ps     18.67mV    116.4mV    6.264mV
847ps     6.731mV    34.97mV    3.378mV
1.486ns   793.8uV    1.298mV    94.39uV
30ns      3.911uV    349.1uV    -317.2uV
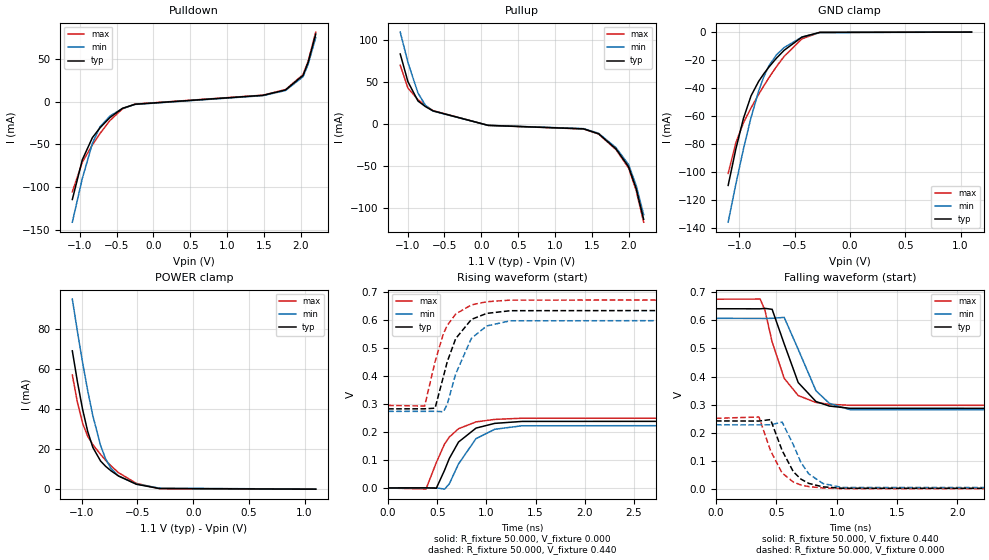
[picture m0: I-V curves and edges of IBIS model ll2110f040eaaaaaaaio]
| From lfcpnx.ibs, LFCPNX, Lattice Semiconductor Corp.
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|   Model ll2110f040eaaaaaaaio
[Model] ll2110f040eaaaaaaaio
| Clamp models do not include dynamic input termination. Please refer to
| the ll2110axxxeaaaaaaain model for input termination.
Model_type I/O
Polarity   Non-Inverting
Enable   Active-Low
Vinl =  0.130V
Vinh =  0.310V
Vmeas =  0.220V
Cref =  30.000pF
Rref =  50.000
Vref =  0.220V
C_comp   5.000pF   4.000pF   5.500pF
[Temperature Range]   25.000   0.125k   -40.000
[Voltage Range]   1.100V   1.050V   1.160V
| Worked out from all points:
|   slope of the pulldown table from 0 to 0.165 V, typ, clamps not added: 85.8 ohm
|   slope of the pullup table from 0 to 0.165 V, typ, clamps not added: 82.8 ohm
|   GND clamp passes 1 mA (typ) near -0.34 V on its own axis
|   POWER clamp passes 1 mA (typ) near -0.40 V on its own axis
|   rising waveform, R_fixture 50.000, V_fixture 0.000: 20-80 % time 239ps typ, 253ps min, 225ps max; typ from 0 V to 0.242 V
|   rising waveform, R_fixture 50.000, V_fixture 0.440: 20-80 % time 214ps typ, 225ps min, 204ps max; typ from 0.283 V to 0.641 V
|   falling waveform, R_fixture 50.000, V_fixture 0.440: 20-80 % time 186ps typ, 196ps min, 170ps max; typ from 0.641 V to 0.283 V
|   falling waveform, R_fixture 50.000, V_fixture 0.000: 20-80 % time 166ps typ, 169ps min, 156ps max; typ from 0.242 V to 0 V
[GND_clamp]
|Voltage   I(typ)   I(min)   I(max)
-1.1V     -109.7mA   -136mA     -101.1mA
-1.031V   -83.84mA   -109mA     -79.26mA
-962mV    -61.81mA   -83.69mA   -64.88mA
-893mV    -45.59mA   -61.04mA   -54.23mA
-824mV    -35.2mA    -42.07mA   -44.52mA
-778mV    -29.85mA   -31.99mA   -38.47mA
-732mV    -25.04mA   -24.18mA   -32.73mA
-663mV    -18.63mA   -16.24mA   -24.64mA
-594mV    -13.03mA   -11.07mA   -17.35mA
-433mV    -3.573mA   -3.553mA   -4.801mA
-272mV    -185.8uA   -416.9uA   -195.8uA
1.1V      0A         0A         0A
[POWER_clamp]
|Voltage   I(typ)   I(min)   I(max)
-1.085V   69.26mA    95.18mA    57.22mA
-1.039V   53.71mA    78.84mA    43.37mA
-993mV    40.01mA    63.46mA    33.02mA
-947mV    28.89mA    49.34mA    26.5mA
-901mV    20.94mA    36.82mA    22.34mA
-832mV    14.13mA    21.98mA    17.41mA
-786mV    11.43mA    15.15mA    14.47mA
-740mV    9.291mA    10.59mA    11.78mA
-671mV    6.617mA    6.611mA    8.279mA
-510mV    2.46mA     2.588mA    2.889mA
-303mV    307uA      515.1uA    269.4uA
1.1V      0A         0A         0A
[Pulldown]
|Voltage   I(typ)   I(min)   I(max)
-1.1V     -114.4mA   -140.9mA   -105.4mA
-964mV    -67.9mA    -89.62mA   -70.71mA
-828mV    -42.18mA   -48.87mA   -50.63mA
-726mV    -30.82mA   -29.64mA   -37.47mA
-590mV    -18.64mA   -16.95mA   -22.13mA
-420mV    -7.903mA   -8.079mA   -8.505mA
-250mV    -3.175mA   -3.376mA   -2.942mA
1.484V    7.256mA    6.893mA    7.474mA
1.79V     13.54mA    12.87mA    13.95mA
2.028V    30.56mA    29.03mA    31.48mA
2.096V    45.55mA    43.27mA    46.91mA
2.2V      78.76mA    74.82mA    81.12mA
[Pullup]
|Voltage   I(typ)   I(min)   I(max)
-1.1V     83.67mA    109.7mA    70.19mA
-996mV    50.77mA    73.67mA    43.14mA
-860mV    27.81mA    37.34mA    29.4mA
-758mV    21.07mA    22.54mA    22.29mA
-656mV    16.05mA    15.8mA     16.35mA
92mV      -1.187mA   -1.128mA   -1.223mA
1.384V    -5.333mA   -5.066mA   -5.493mA
1.588V    -11.11mA   -10.55mA   -11.44mA
1.826V    -29.22mA   -27.76mA   -30.1mA
1.996V    -50.44mA   -47.92mA   -51.96mA
2.098V    -76.27mA   -72.46mA   -78.56mA
2.2V      -112.9mA   -107.3mA   -116.3mA
[Ramp]
| variable   typ   min   max
dV/dt_r   0.145/0.238n   0.142/0.252n   0.151/0.224n
dV/dt_f   0.181/0.229n   0.173/0.241n   0.189/0.218n
R_load = 50.000
[Rising Waveform]
R_fixture = 50.000
V_fixture = 0.000
V_fixture_min = 0.000
V_fixture_max = 0.000
|  time   V(typ)   V(min)   V(max)
0s        4.31uV     240uV      -223.7uV
386ps     434.5uV    257.1uV    -3.764mV
491ps     -949.5uV   691.2uV    90.92mV
575ps     63.72mV    -4.337mV   157.5mV
623ps     105.5mV    14.78mV    182mV
717ps     164.3mV    86.02mV    211.9mV
895ps     214.1mV    176.5mV    236.2mV
1.085ns   230.9mV    209.8mV    245.1mV
1.362ns   237.9mV    222.3mV    249.4mV
30ns      242.3mV    228.6mV    251.8mV
[Rising Waveform]
R_fixture = 50.000
V_fixture = 0.440
V_fixture_min = 0.419
V_fixture_max = 0.463
|  time   V(typ)   V(min)   V(max)
0s        282.8mV    273.9mV    295.1mV
372ps     283mV      273.9mV    292.8mV
478ps     285.2mV    274.1mV    451.5mV
563ps     398.3mV    272.5mV    551.7mV
602ps     451.3mV    298.9mV    580.9mV
688ps     534.1mV    407.8mV    622mV
848ps     602.7mV    535.1mV    654.7mV
1.003ns   624.1mV    579.2mV    665.8mV
1.243ns   633.8mV    597.6mV    671.7mV
30ns      641.3mV    607.1mV    675.4mV
[Falling Waveform]
R_fixture = 50.000
V_fixture = 0.440
V_fixture_min = 0.419
V_fixture_max = 0.463
|  time   V(typ)   V(min)   V(max)
0s        641.4mV    607.1mV    675.4mV
366ps     641.1mV    607mV      675.8mV
405ps     642.7mV    606.8mV    636.4mV
465ps     639.4mV    607.3mV    523.7mV
565ps     516.4mV    610.7mV    394mV
681ps     378.9mV    497mV      332.8mV
828ps     311.5mV    349.8mV    308mV
939ps     295.3mV    305mV      301.7mV
1.109ns   287.4mV    282.5mV    298.1mV
30ns      282.8mV    273.9mV    295.1mV
[Falling Waveform]
R_fixture = 50.000
V_fixture = 0.000
V_fixture_min = 0.000
V_fixture_max = 0.000
|  time   V(typ)   V(min)   V(max)
0s        242.4mV    228.6mV    251.8mV
356ps     242mV      228.4mV    256.4mV
452ps     247.2mV    228.6mV    136.5mV
548ps     137.2mV    238.3mV    57.16mV
641ps     61.64mV    157.4mV    24.94mV
704ps     35.41mV    94.47mV    14.7mV
769ps     20.23mV    54.11mV    8.873mV
885ps     8.037mV    20.05mV    4.055mV
1.043ns   2.979mV    5.895mV    1.726mV
30ns      5.243uV    240uV      -223.7uV
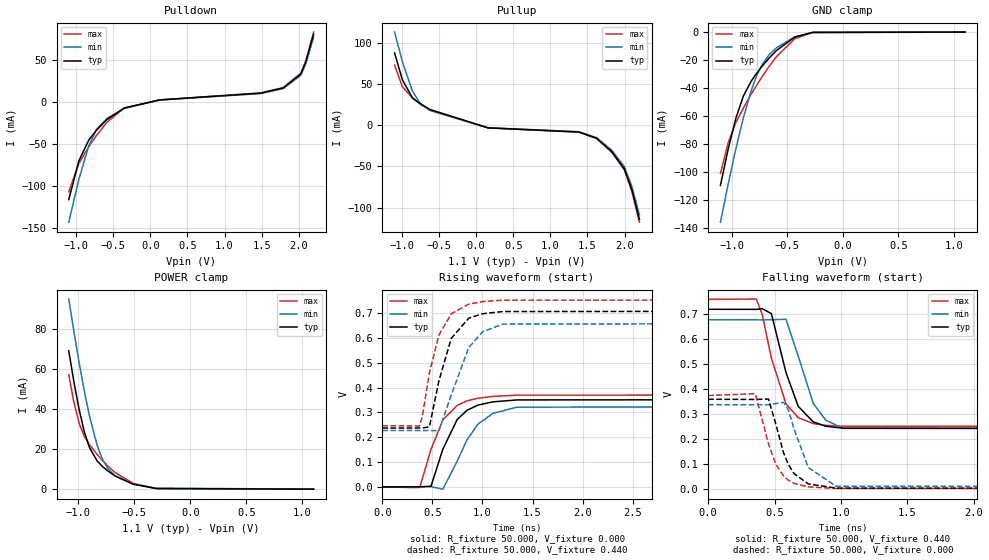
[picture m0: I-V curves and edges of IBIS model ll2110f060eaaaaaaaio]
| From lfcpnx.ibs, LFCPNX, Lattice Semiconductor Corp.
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|   Model ll2110f060eaaaaaaaio
[Model] ll2110f060eaaaaaaaio
| Clamp models do not include dynamic input termination. Please refer to
| the ll2110axxxeaaaaaaain model for input termination.
Model_type I/O
Polarity   Non-Inverting
Enable   Active-Low
Vinl =  0.130V
Vinh =  0.310V
Vmeas =  0.220V
Cref =  30.000pF
Rref =  50.000
Vref =  0.220V
C_comp   5.000pF   4.000pF   5.500pF
[Temperature Range]   25.000   0.125k   -40.000
[Voltage Range]   1.100V   1.050V   1.160V
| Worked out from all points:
|   slope of the pulldown table from 0 to 0.165 V, typ, clamps not added: 56.9 ohm
|   slope of the pullup table from 0 to 0.165 V, typ, clamps not added: 54.8 ohm
|   GND clamp passes 1 mA (typ) near -0.34 V on its own axis
|   POWER clamp passes 1 mA (typ) near -0.40 V on its own axis
|   rising waveform, R_fixture 50.000, V_fixture 0.000: 20-80 % time 235ps typ, 288ps min, 221ps max; typ from 0 V to 0.358 V
|   rising waveform, R_fixture 50.000, V_fixture 0.440: 20-80 % time 197ps typ, 252ps min, 187ps max; typ from 0.237 V to 0.718 V
|   falling waveform, R_fixture 50.000, V_fixture 0.440: 20-80 % time 156ps typ, 166ps min, 152ps max; typ from 0.718 V to 0.237 V
|   falling waveform, R_fixture 50.000, V_fixture 0.000: 20-80 % time 136ps typ, 147ps min, 132ps max; typ from 0.358 V to 0 V
[GND_clamp]
|Voltage   I(typ)   I(min)   I(max)
-1.1V     -109.7mA   -136mA     -101.1mA
-1.031V   -83.84mA   -109mA     -79.26mA
-962mV    -61.81mA   -83.69mA   -64.88mA
-893mV    -45.59mA   -61.04mA   -54.23mA
-824mV    -35.2mA    -42.07mA   -44.52mA
-778mV    -29.85mA   -31.99mA   -38.47mA
-732mV    -25.04mA   -24.18mA   -32.73mA
-663mV    -18.63mA   -16.24mA   -24.64mA
-594mV    -13.03mA   -11.07mA   -17.35mA
-433mV    -3.573mA   -3.553mA   -4.801mA
-272mV    -185.8uA   -416.9uA   -195.8uA
1.1V      0A         0A         0A
[POWER_clamp]
|Voltage   I(typ)   I(min)   I(max)
-1.085V   69.26mA    95.18mA    57.22mA
-1.039V   53.71mA    78.84mA    43.37mA
-993mV    40.01mA    63.46mA    33.02mA
-947mV    28.89mA    49.34mA    26.5mA
-901mV    20.94mA    36.82mA    22.34mA
-832mV    14.13mA    21.98mA    17.41mA
-786mV    11.43mA    15.15mA    14.47mA
-740mV    9.291mA    10.59mA    11.78mA
-671mV    6.617mA    6.611mA    8.279mA
-510mV    2.46mA     2.588mA    2.889mA
-303mV    307uA      515.1uA    269.4uA
1.1V      0A         0A         0A
[Pulldown]
|Voltage   I(typ)   I(min)   I(max)
-1.1V     -116.7mA   -143.6mA   -107.5mA
-964mV    -70.54mA   -92.38mA   -73.4mA
-828mV    -45.27mA   -51.91mA   -53.38mA
-726mV    -33.88mA   -32.9mA    -40.18mA
-590mV    -21.5mA    -20.07mA   -24.71mA
-352mV    -7.469mA   -7.881mA   -7.447mA
124mV     2.209mA    2.099mA    2.275mA
1.484V    10.27mA    9.758mA    10.58mA
1.79V     16.47mA    15.65mA    16.97mA
2.028V    33.09mA    31.44mA    34.09mA
2.096V    47.77mA    45.38mA    49.21mA
2.2V      80.7mA     76.67mA    83.12mA
[Pullup]
|Voltage   I(typ)   I(min)   I(max)
-1.1V     88.32mA    113.8mA    73.59mA
-996mV    55.91mA    77.94mA    47.28mA
-860mV    33.67mA    41.95mA    33.68mA
-758mV    26.63mA    27.31mA    26.33mA
-622mV    19.41mA    18.58mA    18.27mA
160mV     -2.933mA   -2.787mA   -3.021mA
1.384V    -7.973mA   -7.575mA   -8.213mA
1.622V    -15.55mA   -14.78mA   -16.02mA
1.826V    -31.65mA   -30.06mA   -32.6mA
1.996V    -52.64mA   -50.01mA   -54.22mA
2.098V    -78.11mA   -74.21mA   -80.45mA
2.2V      -114.5mA   -108.8mA   -117.9mA
[Ramp]
| variable   typ   min   max
dV/dt_r   0.215/0.234n   0.202/0.287n   0.224/0.220n
dV/dt_f   0.254/0.208n   0.247/0.220n   0.267/0.210n
R_load = 50.000
[Rising Waveform]
R_fixture = 50.000
V_fixture = 0.000
V_fixture_min = 0.000
V_fixture_max = 0.000
|  time   V(typ)   V(min)   V(max)
0s        3.587uV    95.7uV     -232.6uV
373ps     422.4uV    90.78uV    -2.977mV
486ps     2.762mV    902.7uV    151.5mV
604ps     151.8mV    -9.152mV   269.6mV
747ps     271.5mV    103.1mV    328.7mV
846ps     308.9mV    190.1mV    346.8mV
956ps     330mV      253.2mV    357.6mV
1.105ns   342.9mV    296.6mV    364.9mV
1.345ns   350.7mV    321.4mV    369.9mV
30ns      358.4mV    336.9mV    373.6mV
[Rising Waveform]
R_fixture = 50.000
V_fixture = 0.440
V_fixture_min = 0.419
V_fixture_max = 0.463
|  time   V(typ)   V(min)   V(max)
0s        237.2mV    227.2mV    246.7mV
371ps     237.5mV    227.2mV    245.4mV
399ps     237.5mV    227.2mV    283.3mV
470ps     242.2mV    227.5mV    460mV
565ps     427.5mV    226.3mV    612.1mV
688ps     598.5mV    370mV      697.6mV
862ps     680mV      561.1mV    736.9mV
1.001ns   698.2mV    625.2mV    747.1mV
1.203ns   707mV      656.3mV    752.8mV
30ns      717.7mV    675.6mV    757.3mV
[Falling Waveform]
R_fixture = 50.000
V_fixture = 0.440
V_fixture_min = 0.419
V_fixture_max = 0.463
|  time   V(typ)   V(min)   V(max)
0s        717.7mV    675.7mV    757.3mV
363ps     717.4mV    675.5mV    758.5mV
407ps     720.2mV    675.3mV    696.9mV
476ps     700.3mV    675.9mV    522.2mV
586ps     465mV      677.8mV    340mV
678ps     330.4mV    530.7mV    285mV
791ps     268.3mV    342.7mV    261.6mV
885ps     251mV      275.3mV    254.6mV
1.014ns   243mV      242.4mV    250.8mV
30ns      237.2mV    227.2mV    246.7mV
[Falling Waveform]
R_fixture = 50.000
V_fixture = 0.000
V_fixture_min = 0.000
V_fixture_max = 0.000
|  time   V(typ)   V(min)   V(max)
0s        358.5mV    337mV      373.6mV
354ps     357.9mV    336.6mV    380.9mV
454ps     359.5mV    336.6mV    181.6mV
508ps     262.1mV    341.4mV    100.3mV
567ps     145.5mV    346.5mV    52.55mV
604ps     97.92mV    316.7mV    35.55mV
647ps     61.67mV    239.1mV    23.08mV
754ps     20.53mV    86.01mV    8.972mV
964ps     3.981mV    11.41mV    2.479mV
30ns      5.297uV    102.2uV    -232.6uV
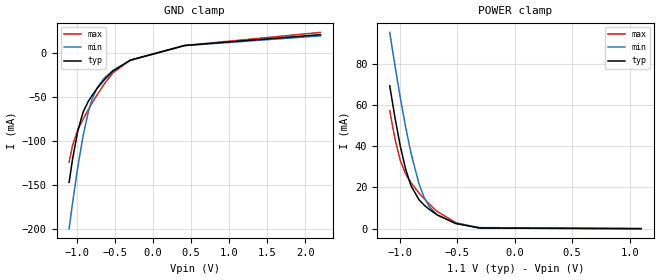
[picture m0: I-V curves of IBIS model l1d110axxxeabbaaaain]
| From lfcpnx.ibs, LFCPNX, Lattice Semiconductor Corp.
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|   Model l1d110axxxeabbaaaain
[Model] l1d110axxxeabbaaaain
Model_type Input
Polarity   Non-Inverting
Enable   Active-High
Vinl =  0.093V
Vinh =  0.273V
C_comp   5.000pF   4.000pF   5.500pF
[Temperature Range]   25.000   0.125k   -40.000
[Voltage Range]   1.100V   1.050V   1.160V
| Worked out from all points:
|   GND clamp passes 1 mA (typ) near -0.04 V on its own axis
|   POWER clamp passes 1 mA (typ) near -0.40 V on its own axis
[GND_clamp]
|Voltage   I(typ)   I(min)   I(max)
-1.1V     -146.6mA   -199.2mA   -123.5mA
-1.054V   -120mA     -169.6mA   -104.4mA
-985mV    -87.79mA   -128.7mA   -86.87mA
-916mV    -66.68mA   -93.48mA   -74.83mA
-847mV    -54.38mA   -66.12mA   -63.82mA
-801mV    -48.17mA   -52.69mA   -56.91mA
-732mV    -39.91mA   -38.94mA   -47.08mA
-640mV    -30.23mA   -28.26mA   -34.99mA
-525mV    -20.04mA   -19.45mA   -22.15mA
-295mV    -7.653mA   -8.019mA   -7.614mA
418mV     8.958mA    8.771mA    8.96mA
2.2V      21.23mA    19.87mA    23.8mA
[POWER_clamp]
|Voltage   I(typ)   I(min)   I(max)
-1.085V   69.26mA    95.18mA    57.25mA
-1.039V   53.71mA    78.84mA    43.39mA
-993mV    40.01mA    63.46mA    33.04mA
-947mV    28.89mA    49.34mA    26.51mA
-901mV    20.94mA    36.82mA    22.35mA
-832mV    14.13mA    21.98mA    17.41mA
-786mV    11.43mA    15.15mA    14.47mA
-740mV    9.291mA    10.59mA    11.78mA
-671mV    6.617mA    6.611mA    8.279mA
-510mV    2.46mA     2.588mA    2.889mA
-303mV    307uA      515.1uA    269.4uA
1.1V      0A         0A         0A
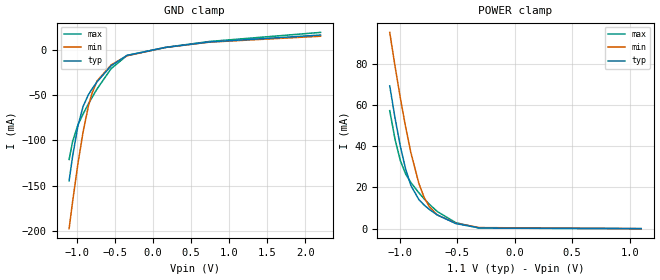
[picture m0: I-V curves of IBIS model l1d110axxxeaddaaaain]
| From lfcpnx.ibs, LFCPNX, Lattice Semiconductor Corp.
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|   Model l1d110axxxeaddaaaain
[Model] l1d110axxxeaddaaaain
Model_type Input
Polarity   Non-Inverting
Enable   Active-High
Vinl =  0.093V
Vinh =  0.273V
C_comp   5.000pF   4.000pF   5.500pF
[Temperature Range]   25.000   0.125k   -40.000
[Voltage Range]   1.100V   1.050V   1.160V
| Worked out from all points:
|   GND clamp passes 1 mA (typ) near -0.06 V on its own axis
|   POWER clamp passes 1 mA (typ) near -0.40 V on its own axis
[GND_clamp]
|Voltage   I(typ)   I(min)   I(max)
-1.1V     -144.4mA   -197.1mA   -120.9mA
-1.054V   -117.4mA   -167.4mA   -101.2mA
-985mV    -84.32mA   -126mA     -82.88mA
-916mV    -62.36mA   -90.29mA   -70.74mA
-847mV    -49.66mA   -62.29mA   -59.74mA
-801mV    -43.44mA   -48.46mA   -52.84mA
-732mV    -35.26mA   -34.32mA   -43.09mA
-548mV    -17.74mA   -16.69mA   -20.8mA
-341mV    -6.257mA   -6.702mA   -6.5mA
165mV     2.502mA    2.468mA    2.54mA
740mV     8.519mA    8.312mA    9.049mA
2.2V      16.15mA    14.83mA    19.05mA
[POWER_clamp]
|Voltage   I(typ)   I(min)   I(max)
-1.085V   69.26mA    95.18mA    57.25mA
-1.039V   53.71mA    78.84mA    43.39mA
-993mV    40.01mA    63.46mA    33.04mA
-947mV    28.89mA    49.34mA    26.51mA
-901mV    20.94mA    36.82mA    22.35mA
-832mV    14.13mA    21.98mA    17.41mA
-786mV    11.43mA    15.15mA    14.47mA
-740mV    9.291mA    10.59mA    11.78mA
-671mV    6.617mA    6.611mA    8.279mA
-510mV    2.46mA     2.588mA    2.889mA
-303mV    307uA      515.1uA    269.4uA
1.1V      0A         0A         0A
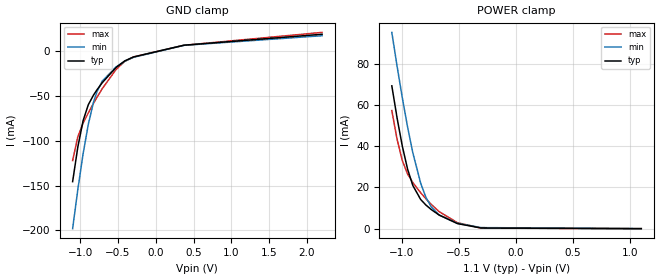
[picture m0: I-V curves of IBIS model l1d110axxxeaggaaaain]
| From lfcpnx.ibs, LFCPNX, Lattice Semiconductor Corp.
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|   Model l1d110axxxeaggaaaain
[Model] l1d110axxxeaggaaaain
Model_type Input
Polarity   Non-Inverting
Enable   Active-High
Vinl =  0.093V
Vinh =  0.273V
C_comp   5.000pF   4.000pF   5.500pF
[Temperature Range]   25.000   0.125k   -40.000
[Voltage Range]   1.100V   1.050V   1.160V
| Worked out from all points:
|   GND clamp passes 1 mA (typ) near -0.05 V on its own axis
|   POWER clamp passes 1 mA (typ) near -0.40 V on its own axis
[GND_clamp]
|Voltage   I(typ)   I(min)   I(max)
-1.1V     -145.6mA   -198.1mA   -122.1mA
-1.031V   -106.8mA   -154.3mA   -95.4mA
-962mV    -77.74mA   -114.8mA   -80.49mA
-893mV    -59.78mA   -81.74mA   -68.92mA
-824mV    -48.95mA   -56.95mA   -58.17mA
-778mV    -43.08mA   -45.18mA   -51.44mA
-709mV    -35.17mA   -33.42mA   -41.86mA
-525mV    -18.07mA   -17.42mA   -20.27mA
-410mV    -10.74mA   -11.12mA   -11.22mA
-295mV    -6.338mA   -6.743mA   -6.34mA
372mV     6.739mA    6.63mA     6.7mA
2.2V      19.02mA    17.38mA    21.08mA
[POWER_clamp]
|Voltage   I(typ)   I(min)   I(max)
-1.085V   69.26mA    95.18mA    57.25mA
-1.039V   53.71mA    78.84mA    43.39mA
-993mV    40.01mA    63.46mA    33.04mA
-947mV    28.89mA    49.34mA    26.51mA
-901mV    20.94mA    36.82mA    22.35mA
-832mV    14.13mA    21.98mA    17.41mA
-786mV    11.43mA    15.15mA    14.47mA
-740mV    9.291mA    10.59mA    11.78mA
-671mV    6.617mA    6.611mA    8.279mA
-510mV    2.46mA     2.588mA    2.889mA
-303mV    307uA      515.1uA    269.4uA
1.1V      0A         0A         0A
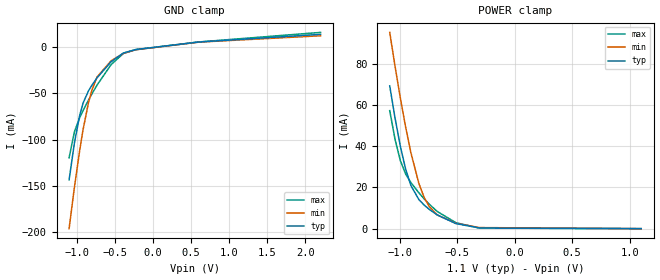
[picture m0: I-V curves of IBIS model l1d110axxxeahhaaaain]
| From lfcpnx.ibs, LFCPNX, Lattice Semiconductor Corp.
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|   Model l1d110axxxeahhaaaain
[Model] l1d110axxxeahhaaaain
Model_type Input
Polarity   Non-Inverting
Enable   Active-High
Vinl =  0.093V
Vinh =  0.273V
C_comp   5.000pF   4.000pF   5.500pF
[Temperature Range]   25.000   0.125k   -40.000
[Voltage Range]   1.100V   1.050V   1.160V
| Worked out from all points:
|   GND clamp passes 1 mA (typ) near -0.09 V on its own axis
|   POWER clamp passes 1 mA (typ) near -0.40 V on its own axis
[GND_clamp]
|Voltage   I(typ)   I(min)   I(max)
-1.1V     -143.4mA   -196.1mA   -119.5mA
-1.031V   -103.9mA   -151.9mA   -91.68mA
-962mV    -73.95mA   -112mA     -76.24mA
-916mV    -60.31mA   -88.75mA   -68.38mA
-847mV    -47.39mA   -60.43mA   -57.4mA
-801mV    -41.14mA   -46.4mA    -50.52mA
-732mV    -32.98mA   -32.07mA   -40.81mA
-548mV    -15.67mA   -14.59mA   -18.74mA
-387mV    -6.241mA   -6.701mA   -6.743mA
-226mV    -2.551mA   -2.778mA   -2.691mA
602mV     5.577mA    5.46mA     5.653mA
2.2V      13.88mA    12.35mA    15.98mA
[POWER_clamp]
|Voltage   I(typ)   I(min)   I(max)
-1.085V   69.26mA    95.18mA    57.25mA
-1.039V   53.71mA    78.84mA    43.39mA
-993mV    40.01mA    63.46mA    33.04mA
-947mV    28.89mA    49.34mA    26.51mA
-901mV    20.94mA    36.82mA    22.35mA
-832mV    14.13mA    21.98mA    17.41mA
-786mV    11.43mA    15.15mA    14.47mA
-740mV    9.291mA    10.59mA    11.78mA
-671mV    6.617mA    6.611mA    8.279mA
-510mV    2.46mA     2.588mA    2.889mA
-303mV    307uA      515.1uA    269.4uA
1.1V      0A         0A         0A
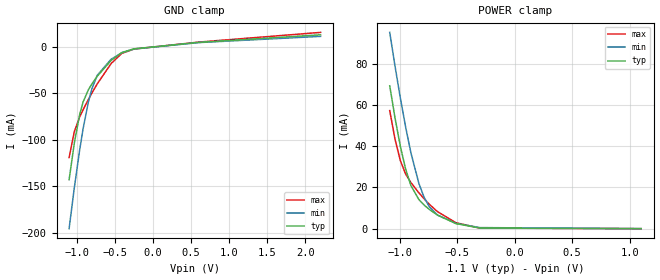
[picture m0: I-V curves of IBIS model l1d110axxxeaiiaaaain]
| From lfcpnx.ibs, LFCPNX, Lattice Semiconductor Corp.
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|   Model l1d110axxxeaiiaaaain
[Model] l1d110axxxeaiiaaaain
Model_type Input
Polarity   Non-Inverting
Enable   Active-High
Vinl =  0.093V
Vinh =  0.273V
C_comp   5.000pF   4.000pF   5.500pF
[Temperature Range]   25.000   0.125k   -40.000
[Voltage Range]   1.100V   1.050V   1.160V
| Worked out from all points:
|   GND clamp passes 1 mA (typ) near -0.11 V on its own axis
|   POWER clamp passes 1 mA (typ) near -0.40 V on its own axis
[GND_clamp]
|Voltage   I(typ)   I(min)   I(max)
-1.1V     -142.9mA   -195.5mA   -119.1mA
-1.031V   -103.3mA   -151.3mA   -91.14mA
-962mV    -73.11mA   -111.3mA   -75.59mA
-916mV    -59.32mA   -87.94mA   -67.71mA
-847mV    -46.29mA   -59.45mA   -56.71mA
-801mV    -40.03mA   -45.31mA   -49.82mA
-732mV    -31.87mA   -30.85mA   -40.1mA
-548mV    -14.66mA   -13.41mA   -18.03mA
-410mV    -6.325mA   -6.583mA   -7.251mA
-249mV    -2.284mA   -2.512mA   -2.531mA
602mV     4.628mA    4.436mA    4.981mA
2.2V      12.78mA    11.12mA    15.38mA
[POWER_clamp]
|Voltage   I(typ)   I(min)   I(max)
-1.085V   69.26mA    95.18mA    57.25mA
-1.039V   53.71mA    78.84mA    43.39mA
-993mV    40.01mA    63.46mA    33.04mA
-947mV    28.89mA    49.34mA    26.51mA
-901mV    20.94mA    36.82mA    22.35mA
-832mV    14.13mA    21.98mA    17.41mA
-786mV    11.43mA    15.15mA    14.47mA
-740mV    9.291mA    10.59mA    11.78mA
-671mV    6.617mA    6.611mA    8.279mA
-510mV    2.46mA     2.588mA    2.889mA
-303mV    307uA      515.1uA    269.4uA
1.1V      0A         0A         0A
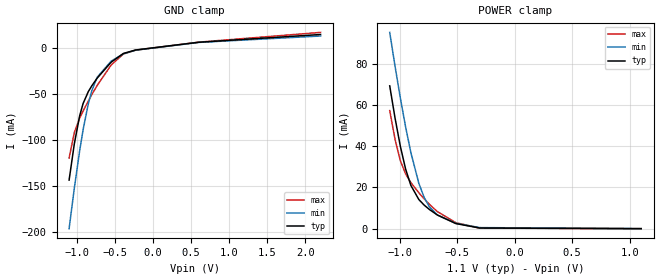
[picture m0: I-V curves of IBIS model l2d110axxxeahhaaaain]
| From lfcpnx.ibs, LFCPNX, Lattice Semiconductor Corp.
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|   Model l2d110axxxeahhaaaain
[Model] l2d110axxxeahhaaaain
Model_type Input
Polarity   Non-Inverting
Enable   Active-High
Vinl =  0.130V
Vinh =  0.310V
C_comp   5.000pF   4.000pF   5.500pF
[Temperature Range]   25.000   0.125k   -40.000
[Voltage Range]   1.100V   1.050V   1.160V
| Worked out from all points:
|   GND clamp passes 1 mA (typ) near -0.09 V on its own axis
|   POWER clamp passes 1 mA (typ) near -0.40 V on its own axis
[GND_clamp]
|Voltage   I(typ)   I(min)   I(max)
-1.1V     -143.5mA   -196.1mA   -119.6mA
-1.031V   -104mA     -152mA     -91.92mA
-962mV    -74.11mA   -112.1mA   -76.5mA
-916mV    -60.49mA   -88.83mA   -68.64mA
-847mV    -47.58mA   -60.54mA   -57.65mA
-801mV    -41.33mA   -46.52mA   -50.77mA
-732mV    -33.16mA   -32.19mA   -41.05mA
-548mV    -15.82mA   -14.7mA    -18.94mA
-387mV    -6.357mA   -6.786mA   -6.902mA
-226mV    -2.62mA    -2.829mA   -2.788mA
602mV     5.726mA    5.57mA     5.875mA
2.2V      14.14mA    12.52mA    16.42mA
[POWER_clamp]
|Voltage   I(typ)   I(min)   I(max)
-1.085V   69.26mA    95.18mA    57.25mA
-1.039V   53.71mA    78.84mA    43.39mA
-993mV    40.01mA    63.46mA    33.04mA
-947mV    28.89mA    49.34mA    26.51mA
-901mV    20.94mA    36.82mA    22.35mA
-832mV    14.13mA    21.98mA    17.41mA
-786mV    11.43mA    15.15mA    14.47mA
-740mV    9.291mA    10.59mA    11.78mA
-671mV    6.617mA    6.611mA    8.279mA
-510mV    2.46mA     2.588mA    2.889mA
-303mV    307uA      515.1uA    269.4uA
1.1V      0A         0A         0A
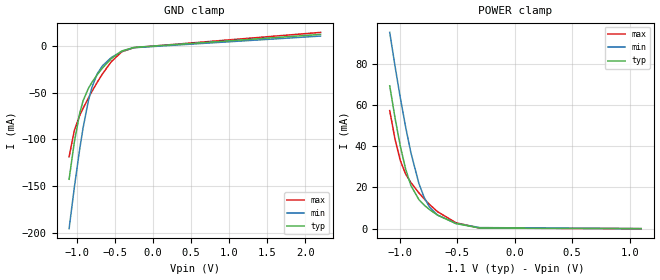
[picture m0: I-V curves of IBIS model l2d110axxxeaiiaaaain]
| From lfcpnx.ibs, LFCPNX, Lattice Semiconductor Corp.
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|   Model l2d110axxxeaiiaaaain
[Model] l2d110axxxeaiiaaaain
Model_type Input
Polarity   Non-Inverting
Enable   Active-High
Vinl =  0.130V
Vinh =  0.310V
C_comp   5.000pF   4.000pF   5.500pF
[Temperature Range]   25.000   0.125k   -40.000
[Voltage Range]   1.100V   1.050V   1.160V
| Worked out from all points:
|   GND clamp passes 1 mA (typ) near -0.14 V on its own axis
|   POWER clamp passes 1 mA (typ) near -0.40 V on its own axis
[GND_clamp]
|Voltage   I(typ)   I(min)   I(max)
-1.1V     -142.5mA   -195.2mA   -118.5mA
-1.031V   -102.8mA   -151mA     -90.32mA
-962mV    -72.52mA   -110.9mA   -74.65mA
-916mV    -58.64mA   -87.44mA   -66.77mA
-847mV    -45.53mA   -58.85mA   -55.78mA
-801mV    -39.25mA   -44.65mA   -48.91mA
-732mV    -31.1mA    -30.14mA   -39.22mA
-663mV    -23.95mA   -21.53mA   -30.22mA
-548mV    -13.93mA   -12.77mA   -17.25mA
-410mV    -5.696mA   -6.07mA    -6.598mA
-249mV    -1.861mA   -2.189mA   -2.104mA
2.2V      12.01mA    10.25mA    14.16mA
[POWER_clamp]
|Voltage   I(typ)   I(min)   I(max)
-1.085V   69.26mA    95.18mA    57.25mA
-1.039V   53.71mA    78.84mA    43.39mA
-993mV    40.01mA    63.46mA    33.04mA
-947mV    28.89mA    49.34mA    26.51mA
-901mV    20.94mA    36.82mA    22.35mA
-832mV    14.13mA    21.98mA    17.41mA
-786mV    11.43mA    15.15mA    14.47mA
-740mV    9.291mA    10.59mA    11.78mA
-671mV    6.617mA    6.611mA    8.279mA
-510mV    2.46mA     2.588mA    2.889mA
-303mV    307uA      515.1uA    269.4uA
1.1V      0A         0A         0A
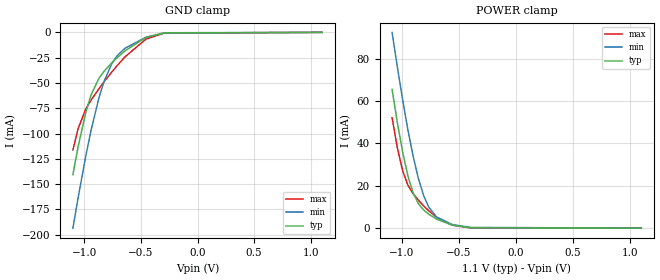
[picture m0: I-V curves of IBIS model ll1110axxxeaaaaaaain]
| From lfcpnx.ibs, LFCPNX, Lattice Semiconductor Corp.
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|   Model ll1110axxxeaaaaaaain
[Model] ll1110axxxeaaaaaaain
Model_type Input
Polarity   Non-Inverting
Enable   Active-High
Vinl =  0.093V
Vinh =  0.273V
C_comp   5.000pF   4.000pF   5.500pF
[Temperature Range]   25.000   0.125k   -40.000
[Voltage Range]   1.100V   1.050V   1.160V
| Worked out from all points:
|   GND clamp passes 1 mA (typ) near -0.34 V on its own axis
|   POWER clamp passes 1 mA (typ) near -0.53 V on its own axis
[GND_clamp]
|Voltage   I(typ)   I(min)   I(max)
-1.1V     -140.6mA   -193.5mA   -116.2mA
-1.054V   -113mA     -163.5mA   -95.13mA
-985mV    -78.54mA   -121.5mA   -75.37mA
-939mV    -61.62mA   -96.4mA    -66.89mA
-870mV    -45.34mA   -64.57mA   -55.73mA
-824mV    -38.37mA   -48.06mA   -48.74mA
-755mV    -29.9mA    -30.55mA   -38.95mA
-709mV    -24.92mA   -23.02mA   -32.81mA
-640mV    -18.24mA   -15.67mA   -24.22mA
-456mV    -5.015mA   -4.831mA   -6.737mA
-295mV    -407.6uA   -731.8uA   -747.2uA
1.1V      -10.82nA   0A         0A
[POWER_clamp]
|Voltage   I(typ)   I(min)   I(max)
-1.085V   65.46mA    92.38mA    52.09mA
-1.039V   49.83mA    76.06mA    37.92mA
-993mV    36.02mA    60.7mA     27.13mA
-947mV    24.74mA    46.56mA    20.34mA
-901mV    16.65mA    34.03mA    16.28mA
-855mV    11.62mA    23.53mA    13.22mA
-809mV    8.607mA    15.46mA    10.54mA
-763mV    6.559mA    9.886mA    8.161mA
-694mV    4.241mA    5.164mA    5.156mA
-556mV    1.362mA    1.666mA    1.473mA
-395mV    157uA      339.2uA    107.6uA
1.1V      0A         0A         466pA
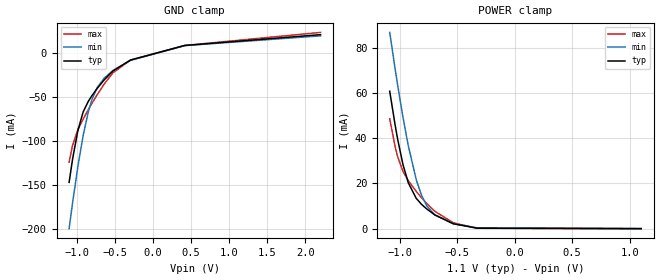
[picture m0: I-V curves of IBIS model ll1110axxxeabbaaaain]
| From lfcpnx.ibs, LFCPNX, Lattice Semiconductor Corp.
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|   Model ll1110axxxeabbaaaain
[Model] ll1110axxxeabbaaaain
Model_type Input
Polarity   Non-Inverting
Enable   Active-High
Vinl =  0.093V
Vinh =  0.273V
C_comp   5.000pF   4.000pF   5.500pF
[Temperature Range]   25.000   0.125k   -40.000
[Voltage Range]   1.100V   1.050V   1.160V
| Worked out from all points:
|   GND clamp passes 1 mA (typ) near -0.04 V on its own axis
|   POWER clamp passes 1 mA (typ) near -0.45 V on its own axis
[GND_clamp]
|Voltage   I(typ)   I(min)   I(max)
-1.1V     -146.6mA   -199.2mA   -123.5mA
-1.054V   -120mA     -169.6mA   -104.4mA
-985mV    -87.79mA   -128.7mA   -86.87mA
-916mV    -66.68mA   -93.48mA   -74.83mA
-847mV    -54.38mA   -66.12mA   -63.82mA
-801mV    -48.17mA   -52.69mA   -56.91mA
-732mV    -39.91mA   -38.94mA   -47.08mA
-640mV    -30.23mA   -28.26mA   -34.99mA
-525mV    -20.04mA   -19.45mA   -22.15mA
-295mV    -7.653mA   -8.019mA   -7.614mA
418mV     8.958mA    8.771mA    8.96mA
2.2V      21.23mA    19.87mA    23.8mA
[POWER_clamp]
|Voltage   I(typ)   I(min)   I(max)
-1.085V   60.71mA    86.73mA    48.54mA
-1.039V   46.06mA    70.92mA    36.41mA
-1.016V   39.49mA    63.39mA    31.77mA
-970mV    28.33mA    49.28mA    25.3mA
-924mV    20.28mA    36.72mA    21.23mA
-855mV    13.4mA     21.73mA    16.47mA
-809mV    10.74mA    14.75mA    13.64mA
-763mV    8.663mA    10.07mA    11.05mA
-694mV    6.094mA    6.035mA    7.687mA
-533mV    2.142mA    2.166mA    2.559mA
-326mV    180.6uA    329.6uA    155.6uA
1.1V      -23.7uA    -6.491uA   -29.42uA
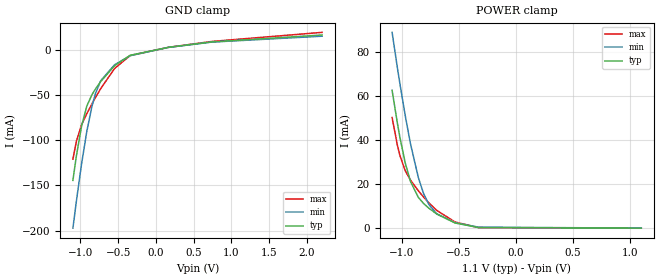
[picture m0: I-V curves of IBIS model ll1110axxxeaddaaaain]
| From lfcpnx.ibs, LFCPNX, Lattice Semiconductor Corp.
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|   Model ll1110axxxeaddaaaain
[Model] ll1110axxxeaddaaaain
Model_type Input
Polarity   Non-Inverting
Enable   Active-High
Vinl =  0.093V
Vinh =  0.273V
C_comp   5.000pF   4.000pF   5.500pF
[Temperature Range]   25.000   0.125k   -40.000
[Voltage Range]   1.100V   1.050V   1.160V
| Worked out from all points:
|   GND clamp passes 1 mA (typ) near -0.06 V on its own axis
|   POWER clamp passes 1 mA (typ) near -0.43 V on its own axis
[GND_clamp]
|Voltage   I(typ)   I(min)   I(max)
-1.1V     -144.4mA   -197.1mA   -120.9mA
-1.054V   -117.4mA   -167.4mA   -101.2mA
-985mV    -84.32mA   -126mA     -82.88mA
-916mV    -62.36mA   -90.29mA   -70.74mA
-847mV    -49.66mA   -62.29mA   -59.74mA
-801mV    -43.44mA   -48.46mA   -52.84mA
-732mV    -35.26mA   -34.32mA   -43.09mA
-548mV    -17.74mA   -16.69mA   -20.8mA
-341mV    -6.257mA   -6.702mA   -6.5mA
165mV     2.502mA    2.468mA    2.54mA
740mV     8.519mA    8.312mA    9.049mA
2.2V      16.15mA    14.83mA    19.05mA
[POWER_clamp]
|Voltage   I(typ)   I(min)   I(max)
-1.085V   62.71mA    89.06mA    50.33mA
-1.039V   47.85mA    73.11mA    37.83mA
-1.016V   41.15mA    65.51mA    32.96mA
-970mV    29.67mA    51.22mA    26.11mA
-924mV    21.26mA    38.44mA    21.86mA
-855mV    13.99mA    23.02mA    17.01mA
-809mV    11.21mA    15.73mA    14.14mA
-763mV    9.072mA    10.79mA    11.51mA
-694mV    6.435mA    6.507mA    8.075mA
-533mV    2.341mA    2.411mA    2.776mA
-326mV    246.9uA    426.9uA    220.2uA
1.1V      -11.15uA   -501.4nA   -14.12uA
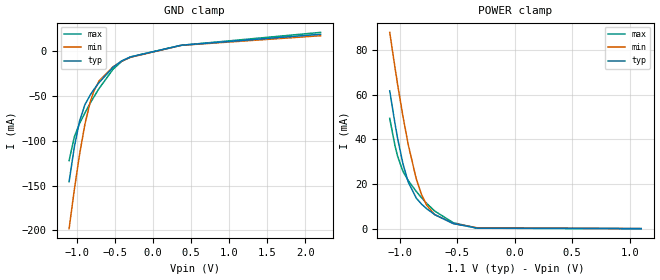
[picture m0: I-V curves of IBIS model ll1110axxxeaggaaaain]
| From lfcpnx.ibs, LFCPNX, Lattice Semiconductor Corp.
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|   Model ll1110axxxeaggaaaain
[Model] ll1110axxxeaggaaaain
Model_type Input
Polarity   Non-Inverting
Enable   Active-High
Vinl =  0.093V
Vinh =  0.273V
C_comp   5.000pF   4.000pF   5.500pF
[Temperature Range]   25.000   0.125k   -40.000
[Voltage Range]   1.100V   1.050V   1.160V
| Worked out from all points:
|   GND clamp passes 1 mA (typ) near -0.05 V on its own axis
|   POWER clamp passes 1 mA (typ) near -0.44 V on its own axis
[GND_clamp]
|Voltage   I(typ)   I(min)   I(max)
-1.1V     -145.6mA   -198.1mA   -122.1mA
-1.031V   -106.8mA   -154.3mA   -95.4mA
-962mV    -77.74mA   -114.8mA   -80.49mA
-893mV    -59.78mA   -81.74mA   -68.92mA
-824mV    -48.95mA   -56.95mA   -58.17mA
-778mV    -43.08mA   -45.18mA   -51.44mA
-709mV    -35.17mA   -33.42mA   -41.86mA
-525mV    -18.07mA   -17.42mA   -20.27mA
-410mV    -10.74mA   -11.12mA   -11.22mA
-295mV    -6.338mA   -6.743mA   -6.34mA
372mV     6.739mA    6.63mA     6.7mA
2.2V      19.02mA    17.38mA    21.08mA
[POWER_clamp]
|Voltage   I(typ)   I(min)   I(max)
-1.085V   61.74mA    87.92mA    49.38mA
-1.039V   46.98mA    72.04mA    37.07mA
-1.016V   40.35mA    64.47mA    32.31mA
-970mV    29.02mA    50.27mA    25.66mA
-924mV    20.79mA    37.6mA     21.51mA
-855mV    13.71mA    22.38mA    16.7mA
-809mV    10.99mA    15.25mA    13.85mA
-763mV    8.879mA    10.44mA    11.25mA
-694mV    6.274mA    6.278mA    7.853mA
-533mV    2.248mA    2.293mA    2.647mA
-326mV    216.7uA    380.5uA    177.7uA
1.1V      -16.31uA   -2.388uA   -25.69uA
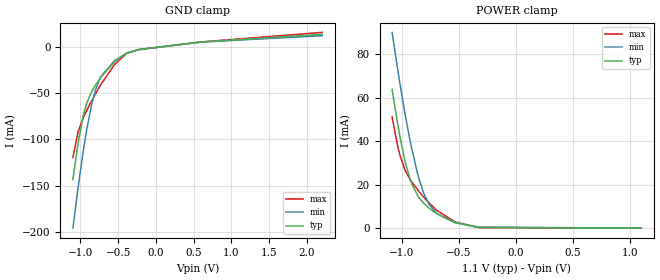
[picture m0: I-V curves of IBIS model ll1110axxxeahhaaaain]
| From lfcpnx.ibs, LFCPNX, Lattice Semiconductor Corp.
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|   Model ll1110axxxeahhaaaain
[Model] ll1110axxxeahhaaaain
Model_type Input
Polarity   Non-Inverting
Enable   Active-High
Vinl =  0.093V
Vinh =  0.273V
C_comp   5.000pF   4.000pF   5.500pF
[Temperature Range]   25.000   0.125k   -40.000
[Voltage Range]   1.100V   1.050V   1.160V
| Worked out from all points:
|   GND clamp passes 1 mA (typ) near -0.09 V on its own axis
|   POWER clamp passes 1 mA (typ) near -0.43 V on its own axis
[GND_clamp]
|Voltage   I(typ)   I(min)   I(max)
-1.1V     -143.4mA   -196.1mA   -119.5mA
-1.031V   -103.9mA   -151.9mA   -91.68mA
-962mV    -73.95mA   -112mA     -76.24mA
-916mV    -60.31mA   -88.75mA   -68.38mA
-847mV    -47.39mA   -60.43mA   -57.4mA
-801mV    -41.14mA   -46.4mA    -50.52mA
-732mV    -32.98mA   -32.07mA   -40.81mA
-548mV    -15.67mA   -14.59mA   -18.74mA
-387mV    -6.241mA   -6.701mA   -6.743mA
-226mV    -2.551mA   -2.778mA   -2.691mA
602mV     5.577mA    5.46mA     5.653mA
2.2V      13.88mA    12.35mA    15.98mA
[POWER_clamp]
|Voltage   I(typ)   I(min)   I(max)
-1.085V   63.74mA    90.06mA    51.09mA
-1.039V   48.78mA    74.06mA    38.42mA
-1.016V   42.02mA    66.43mA    33.46mA
-970mV    30.38mA    52.06mA    26.44mA
-924mV    21.79mA    39.19mA    22.11mA
-855mV    14.31mA    23.58mA    17.22mA
-809mV    11.47mA    16.17mA    14.33mA
-763mV    9.3mA      11.11mA    11.69mA
-694mV    6.627mA    6.717mA    8.221mA
-533mV    2.456mA    2.52mA     2.855mA
-326mV    289uA      471.4uA    239.4uA
1.1V      -4.623uA   0A         -12.27uA
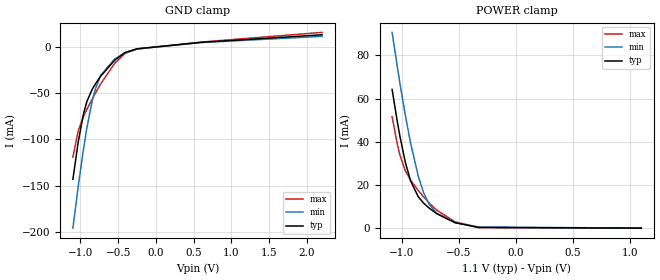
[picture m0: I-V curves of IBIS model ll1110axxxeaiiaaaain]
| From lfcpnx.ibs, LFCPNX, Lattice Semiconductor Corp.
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|   Model ll1110axxxeaiiaaaain
[Model] ll1110axxxeaiiaaaain
Model_type Input
Polarity   Non-Inverting
Enable   Active-High
Vinl =  0.093V
Vinh =  0.273V
C_comp   5.000pF   4.000pF   5.500pF
[Temperature Range]   25.000   0.125k   -40.000
[Voltage Range]   1.100V   1.050V   1.160V
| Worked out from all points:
|   GND clamp passes 1 mA (typ) near -0.11 V on its own axis
|   POWER clamp passes 1 mA (typ) near -0.42 V on its own axis
[GND_clamp]
|Voltage   I(typ)   I(min)   I(max)
-1.1V     -142.9mA   -195.5mA   -119.1mA
-1.031V   -103.3mA   -151.3mA   -91.14mA
-962mV    -73.11mA   -111.3mA   -75.59mA
-916mV    -59.32mA   -87.94mA   -67.71mA
-847mV    -46.29mA   -59.45mA   -56.71mA
-801mV    -40.03mA   -45.31mA   -49.82mA
-732mV    -31.87mA   -30.85mA   -40.1mA
-548mV    -14.66mA   -13.41mA   -18.03mA
-410mV    -6.325mA   -6.583mA   -7.251mA
-249mV    -2.284mA   -2.512mA   -2.531mA
602mV     4.628mA    4.436mA    4.981mA
2.2V      12.78mA    11.12mA    15.38mA
[POWER_clamp]
|Voltage   I(typ)   I(min)   I(max)
-1.085V   64.25mA    90.66mA    51.57mA
-1.039V   49.25mA    74.63mA    38.81mA
-1.016V   42.45mA    66.98mA    33.78mA
-970mV    30.73mA    52.57mA    26.67mA
-924mV    22.04mA    39.64mA    22.28mA
-855mV    14.46mA    23.93mA    17.37mA
-809mV    11.59mA    16.44mA    14.47mA
-763mV    9.405mA    11.32mA    11.82mA
-694mV    6.715mA    6.853mA    8.328mA
-533mV    2.507mA    2.594mA    2.916mA
-326mV    306.4uA    502.5uA    259.1uA
1.1V      -3.028uA   0A         -8.363uA
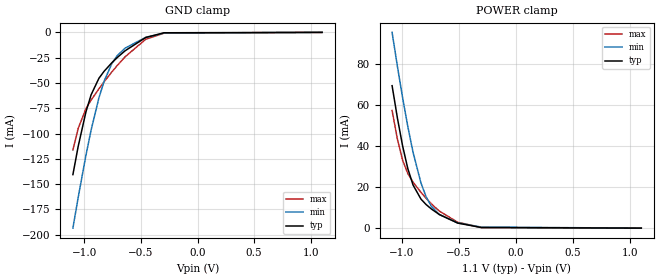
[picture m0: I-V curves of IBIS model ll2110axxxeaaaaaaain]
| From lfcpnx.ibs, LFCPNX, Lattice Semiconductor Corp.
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|   Model ll2110axxxeaaaaaaain
[Model] ll2110axxxeaaaaaaain
Model_type Input
Polarity   Non-Inverting
Enable   Active-High
Vinl =  0.130V
Vinh =  0.310V
C_comp   5.000pF   4.000pF   5.500pF
[Temperature Range]   25.000   0.125k   -40.000
[Voltage Range]   1.100V   1.050V   1.160V
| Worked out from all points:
|   GND clamp passes 1 mA (typ) near -0.34 V on its own axis
|   POWER clamp passes 1 mA (typ) near -0.40 V on its own axis
[GND_clamp]
|Voltage   I(typ)   I(min)   I(max)
-1.1V     -140.6mA   -193.5mA   -116.2mA
-1.054V   -113mA     -163.5mA   -95.13mA
-985mV    -78.54mA   -121.5mA   -75.37mA
-939mV    -61.62mA   -96.4mA    -66.89mA
-870mV    -45.34mA   -64.57mA   -55.73mA
-824mV    -38.37mA   -48.06mA   -48.74mA
-755mV    -29.9mA    -30.55mA   -38.95mA
-709mV    -24.92mA   -23.02mA   -32.81mA
-640mV    -18.24mA   -15.67mA   -24.22mA
-456mV    -5.015mA   -4.831mA   -6.737mA
-295mV    -407.6uA   -731.8uA   -747.2uA
1.1V      -10.82nA   0A         0A
[POWER_clamp]
|Voltage   I(typ)   I(min)   I(max)
-1.085V   69.26mA    95.18mA    57.22mA
-1.039V   53.71mA    78.84mA    43.37mA
-993mV    40.01mA    63.46mA    33.02mA
-947mV    28.89mA    49.34mA    26.5mA
-901mV    20.94mA    36.82mA    22.34mA
-832mV    14.13mA    21.98mA    17.41mA
-786mV    11.43mA    15.15mA    14.47mA
-740mV    9.291mA    10.59mA    11.78mA
-671mV    6.617mA    6.611mA    8.279mA
-510mV    2.46mA     2.588mA    2.889mA
-303mV    307uA      515.1uA    269.4uA
1.1V      0A         0A         0A
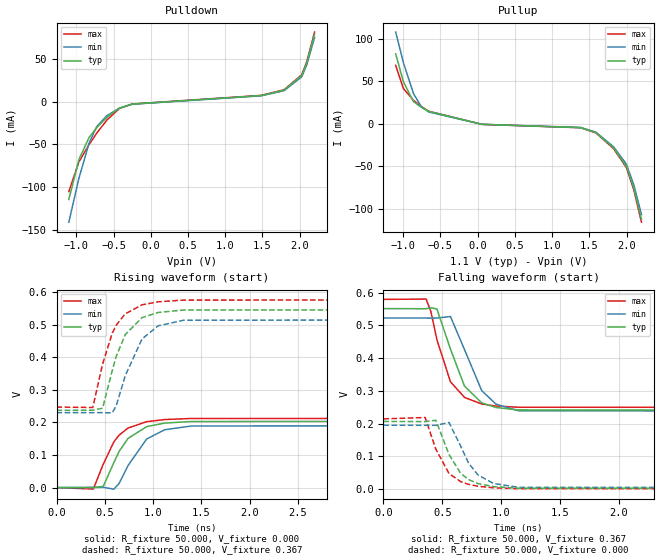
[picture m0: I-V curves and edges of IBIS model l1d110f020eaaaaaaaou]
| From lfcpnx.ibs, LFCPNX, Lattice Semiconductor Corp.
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|   Model l1d110f020eaaaaaaaou
[Model] l1d110f020eaaaaaaaou
Model_type Output
Polarity   Non-Inverting
Enable   Active-High
Vmeas =  0.183V
Cref =  30.000pF
Rref =  50.000
Vref =  0.183V
C_comp   5.000pF   4.000pF   5.500pF
[Temperature Range]   25.000   0.125k   -40.000
[Voltage Range]   1.100V   1.050V   1.160V
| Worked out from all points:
|   slope of the pulldown table from 0 to 0.165 V, typ, clamps not added: 88.9 ohm
|   slope of the pullup table from 0 to 0.165 V, typ, clamps not added: 97.1 ohm
|   rising waveform, R_fixture 50.000, V_fixture 0.000: 20-80 % time 246ps typ, 269ps min, 235ps max; typ from 0 V to 0.206 V
|   rising waveform, R_fixture 50.000, V_fixture 0.367: 20-80 % time 223ps typ, 248ps min, 218ps max; typ from 0.237 V to 0.551 V
|   falling waveform, R_fixture 50.000, V_fixture 0.367: 20-80 % time 193ps typ, 204ps min, 172ps max; typ from 0.551 V to 0.237 V
|   falling waveform, R_fixture 50.000, V_fixture 0.000: 20-80 % time 180ps typ, 187ps min, 167ps max; typ from 0.206 V to 0 V
[Pulldown]
|Voltage   I(typ)   I(min)   I(max)
-1.1V     -114.2mA   -140.7mA   -105.1mA
-964mV    -67.68mA   -89.34mA   -70.29mA
-828mV    -41.92mA   -48.54mA   -50.2mA
-726mV    -30.58mA   -29.27mA   -37.04mA
-590mV    -18.42mA   -16.59mA   -21.71mA
-420mV    -7.732mA   -7.771mA   -8.109mA
-250mV    -3.069mA   -3.175mA   -2.868mA
1.484V    6.95mA     6.603mA    7.159mA
1.79V     13.25mA    12.58mA    13.64mA
2.028V    30.31mA    28.79mA    31.22mA
2.096V    45.32mA    43.06mA    46.68mA
2.2V      78.56mA    74.63mA    80.92mA
[Pullup]
|Voltage   I(typ)   I(min)   I(max)
-1.1V     82.28mA    107.9mA    68.76mA
-996mV    49.24mA    71.8mA     41.39mA
-860mV    26.07mA    35.32mA    27.55mA
-758mV    19.43mA    20.46mA    20.54mA
-656mV    14.57mA    13.85mA    14.74mA
58mV      -657.6uA   -624.7uA   -677.3uA
1.384V    -4.554mA   -4.326mA   -4.691mA
1.588V    -10.36mA   -9.842mA   -10.67mA
1.826V    -28.5mA    -27.08mA   -29.36mA
1.996V    -49.79mA   -47.3mA    -51.28mA
2.098V    -75.72mA   -71.94mA   -77.99mA
2.2V      -112.4mA   -106.8mA   -115.8mA
[Ramp]
| variable   typ   min   max
dV/dt_r   0.124/0.245n   0.114/0.268n   0.129/0.234n
dV/dt_f   0.174/0.243n   0.165/0.255n   0.182/0.231n
R_load = 50.000
[Rising Waveform]
R_fixture = 50.000
V_fixture = 0.000
V_fixture_min = 0.000
V_fixture_max = 0.000
|  time   V(typ)   V(min)   V(max)
0s        4.368uV    140.6uV    -171.7uV
381ps     472uV      160.8uV    -4.385mV
483ps     3.41mV     784.1uV    71.26mV
594ps     77.11mV    -4.915mV   140.9mV
648ps     111.2mV    12.78mV    161.1mV
740ps     151mV      67.71mV    182.8mV
933ps     187.2mV    149.2mV    202.4mV
1.12ns    198.1mV    177.7mV    208.9mV
1.399ns   203mV      189.2mV    212.3mV
30ns      206.5mV    194.9mV    214.3mV
[Rising Waveform]
R_fixture = 50.000
V_fixture = 0.367
V_fixture_min = 0.350
V_fixture_max = 0.386
|  time   V(typ)   V(min)   V(max)
0s        237.2mV    230mV      247.3mV
375ps     237.5mV    230.1mV    245.9mV
477ps     243.7mV    230.3mV    379.4mV
577ps     360.2mV    229.1mV    474.8mV
619ps     404.2mV    252.4mV    499.3mV
712ps     470mV      344.2mV    533.8mV
885ps     522mV      456.6mV    561.3mV
1.051ns   537.8mV    496.7mV    570.6mV
1.315ns   545.3mV    514mV      575.8mV
30ns      550.8mV    522.1mV    579mV
[Falling Waveform]
R_fixture = 50.000
V_fixture = 0.367
V_fixture_min = 0.350
V_fixture_max = 0.386
|  time   V(typ)   V(min)   V(max)
0s        550.9mV    522.1mV    579mV
362ps     550.5mV    522mV      580mV
403ps     553.4mV    521.9mV    542.2mV
454ps     549.7mV    522mV      455.9mV
569ps     427.3mV    526.8mV    327.7mV
688ps     314.4mV    425.8mV    279.9mV
834ps     263.2mV    300.7mV    259.8mV
955ps     249.1mV    259.4mV    253.6mV
1.144ns   241.7mV    239.1mV    249.9mV
30ns      237.2mV    230mV      247.3mV
[Falling Waveform]
R_fixture = 50.000
V_fixture = 0.000
V_fixture_min = 0.000
V_fixture_max = 0.000
|  time   V(typ)   V(min)   V(max)
0s        206.5mV    194.9mV    214.3mV
354ps     206mV      194.7mV    218.6mV
445ps     210.1mV    194.6mV    121.7mV
557ps     105.4mV    203.3mV    47.44mV
656ps     48.08mV    130.9mV    22.74mV
723ps     29.09mV    79.19mV    14.41mV
802ps     16.85mV    43.36mV    8.714mV
935ps     7.561mV    17.07mV    4.012mV
1.147ns   2.729mV    5.422mV    1.336mV
30ns      4.893uV    140.6uV    -171.7uV
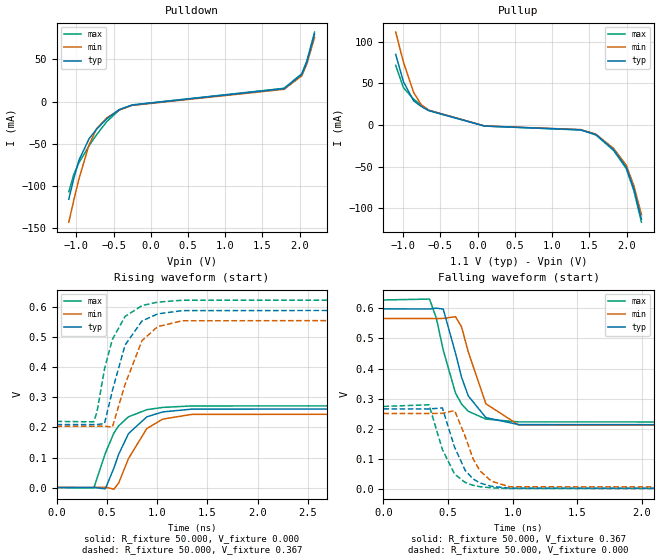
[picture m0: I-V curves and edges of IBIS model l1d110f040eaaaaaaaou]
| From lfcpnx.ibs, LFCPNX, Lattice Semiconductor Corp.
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|   Model l1d110f040eaaaaaaaou
[Model] l1d110f040eaaaaaaaou
Model_type Output
Polarity   Non-Inverting
Enable   Active-High
Vmeas =  0.183V
Cref =  30.000pF
Rref =  50.000
Vref =  0.183V
C_comp   5.000pF   4.000pF   5.500pF
[Temperature Range]   25.000   0.125k   -40.000
[Voltage Range]   1.100V   1.050V   1.160V
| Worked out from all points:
|   slope of the pulldown table from 0 to 0.165 V, typ, clamps not added: 65.6 ohm
|   slope of the pullup table from 0 to 0.165 V, typ, clamps not added: 75 ohm
|   rising waveform, R_fixture 50.000, V_fixture 0.000: 20-80 % time 239ps typ, 251ps min, 222ps max; typ from 0 V to 0.266 V
|   rising waveform, R_fixture 50.000, V_fixture 0.367: 20-80 % time 220ps typ, 227ps min, 201ps max; typ from 0.21 V to 0.598 V
|   falling waveform, R_fixture 50.000, V_fixture 0.367: 20-80 % time 161ps typ, 168ps min, 155ps max; typ from 0.598 V to 0.21 V
|   falling waveform, R_fixture 50.000, V_fixture 0.000: 20-80 % time 146ps typ, 152ps min, 142ps max; typ from 0.266 V to 0 V
[Pulldown]
|Voltage   I(typ)   I(min)   I(max)
-1.1V     -115.7mA   -142.9mA   -106.8mA
-1.032V   -90.63mA   -116.4mA   -86.01mA
-964mV    -69.45mA   -91.65mA   -72.45mA
-828mV    -44mA      -51.1mA    -52.37mA
-726mV    -32.64mA   -32.03mA   -39.16mA
-590mV    -20.35mA   -19.23mA   -23.7mA
-420mV    -9.344mA   -9.89mA    -9.81mA
-250mV    -4.118mA   -4.516mA   -3.997mA
1.79V     15.26mA    14.5mA     15.72mA
2.028V    32.04mA    30.44mA    33mA
2.096V    46.85mA    44.51mA    48.26mA
2.2V      79.9mA     75.9mA     82.29mA
[Pullup]
|Voltage   I(typ)   I(min)   I(max)
-1.1V     84.59mA    111.3mA    71.43mA
-996mV    51.79mA    75.29mA    44.63mA
-860mV    28.98mA    39.08mA    30.92mA
-758mV    22.19mA    24.35mA    23.73mA
-656mV    17.06mA    17.48mA    17.67mA
92mV      -1.311mA   -1.245mA   -1.35mA
1.384V    -5.864mA   -5.57mA    -6.039mA
1.588V    -11.61mA   -11.03mA   -11.96mA
1.826V    -29.7mA    -28.22mA   -30.59mA
1.996V    -50.88mA   -48.33mA   -52.4mA
2.098V    -76.63mA   -72.8mA    -78.93mA
2.2V      -113.2mA   -107.5mA   -116.6mA
[Ramp]
| variable   typ   min   max
dV/dt_r   0.160/0.239n   0.150/0.250n   0.165/0.221n
dV/dt_f   0.226/0.217n   0.211/0.222n   0.234/0.213n
R_load = 50.000
[Rising Waveform]
R_fixture = 50.000
V_fixture = 0.000
V_fixture_min = 0.000
V_fixture_max = 0.000
|  time   V(typ)   V(min)   V(max)
0s        3.84uV     405.9uV    388.1nV
371ps     263.4uV    402.1uV    -1.53mV
485ps     -4.315mV   1.107mV    113.8mV
571ps     65.24mV    -5.397mV   182.1mV
618ps     111mV      14.97mV    205.5mV
716ps     179.8mV    96.98mV    235.7mV
898ps     235.5mV    196.6mV    259.3mV
1.057ns   251.9mV    228mV      266.9mV
1.344ns   261.1mV    243.6mV    271.8mV
30ns      266.4mV    251.2mV    274.5mV
[Rising Waveform]
R_fixture = 50.000
V_fixture = 0.367
V_fixture_min = 0.350
V_fixture_max = 0.386
|  time   V(typ)   V(min)   V(max)
0s        209.7mV    204.2mV    220.3mV
369ps     209.9mV    204.2mV    218.8mV
401ps     210.1mV    204.3mV    249.9mV
477ps     212.7mV    204.7mV    394.8mV
555ps     322.4mV    200.8mV    493.1mV
681ps     474.2mV    343.2mV    569.6mV
850ps     554.9mV    489.4mV    605.9mV
1.005ns   578.3mV    535.8mV    617.4mV
1.249ns   589.2mV    555.3mV    623.7mV
30ns      598.1mV    566.2mV    627.7mV
[Falling Waveform]
R_fixture = 50.000
V_fixture = 0.367
V_fixture_min = 0.350
V_fixture_max = 0.386
|  time   V(typ)   V(min)   V(max)
0s        598.2mV    566.2mV    627.7mV
357ps     597.8mV    566.1mV    630.7mV
410ps     600.5mV    565.9mV    566.9mV
463ps     597.5mV    566.5mV    461.5mV
558ps     451mV      572.2mV    318.6mV
605ps     371.1mV    538mV      282.4mV
657ps     309.1mV    455.1mV    258.3mV
793ps     237.5mV    283.3mV    232.5mV
1.046ns   214.2mV    213.1mV    223.2mV
30ns      209.7mV    204.2mV    220.3mV
[Falling Waveform]
R_fixture = 50.000
V_fixture = 0.000
V_fixture_min = 0.000
V_fixture_max = 0.000
|  time   V(typ)   V(min)   V(max)
0s        266.4mV    251.2mV    274.5mV
353ps     266mV      251.1mV    280mV
456ps     269.7mV    251.5mV    132.2mV
551ps     138.9mV    260.9mV    50.03mV
633ps     62.21mV    174.8mV    22.3mV
693ps     34.35mV    101.8mV    12.95mV
747ps     20.44mV    60.75mV    8.319mV
836ps     9.259mV    26.37mV    4.467mV
977ps     3.419mV    7.929mV    2.119mV
30ns      4.856uV    405.9uV    3.956uV
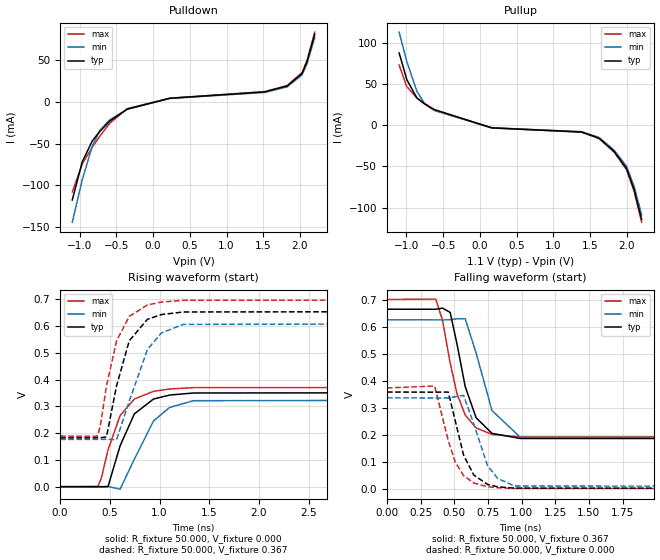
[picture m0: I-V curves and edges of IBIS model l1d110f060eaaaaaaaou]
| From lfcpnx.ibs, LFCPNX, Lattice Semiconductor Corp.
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|   Model l1d110f060eaaaaaaaou
[Model] l1d110f060eaaaaaaaou
Model_type Output
Polarity   Non-Inverting
Enable   Active-High
Vmeas =  0.183V
Cref =  30.000pF
Rref =  50.000
Vref =  0.183V
C_comp   5.000pF   4.000pF   5.500pF
[Temperature Range]   25.000   0.125k   -40.000
[Voltage Range]   1.100V   1.050V   1.160V
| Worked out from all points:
|   slope of the pulldown table from 0 to 0.165 V, typ, clamps not added: 49 ohm
|   slope of the pullup table from 0 to 0.165 V, typ, clamps not added: 54.8 ohm
|   rising waveform, R_fixture 50.000, V_fixture 0.000: 20-80 % time 236ps typ, 288ps min, 221ps max; typ from 0 V to 0.358 V
|   rising waveform, R_fixture 50.000, V_fixture 0.367: 20-80 % time 208ps typ, 260ps min, 196ps max; typ from 0.182 V to 0.665 V
|   falling waveform, R_fixture 50.000, V_fixture 0.367: 20-80 % time 138ps typ, 157ps min, 141ps max; typ from 0.665 V to 0.182 V
|   falling waveform, R_fixture 50.000, V_fixture 0.000: 20-80 % time 123ps typ, 140ps min, 129ps max; typ from 0.358 V to 0 V
[Pulldown]
|Voltage   I(typ)   I(min)   I(max)
-1.1V     -117.9mA   -144.6mA   -108.3mA
-964mV    -71.92mA   -93.45mA   -74.45mA
-828mV    -46.85mA   -53.11mA   -54.37mA
-726mV    -35.43mA   -34.2mA    -41.11mA
-590mV    -22.92mA   -21.33mA   -25.52mA
-352mV    -8.486mA   -8.765mA   -7.975mA
226mV     4.511mA    4.285mA    4.646mA
1.518V    12.17mA    11.56mA    12.54mA
1.824V    19.3mA     18.33mA    19.88mA
2.028V    34.44mA    32.71mA    35.47mA
2.096V    48.95mA    46.51mA    50.42mA
2.2V      81.73mA    77.65mA    84.19mA
[Pullup]
|Voltage   I(typ)   I(min)   I(max)
-1.1V     88.32mA    113.8mA    73.62mA
-996mV    55.91mA    77.94mA    47.29mA
-860mV    33.67mA    41.95mA    33.68mA
-758mV    26.63mA    27.31mA    26.33mA
-622mV    19.41mA    18.58mA    18.27mA
160mV     -2.933mA   -2.787mA   -3.021mA
1.384V    -7.973mA   -7.574mA   -8.212mA
1.622V    -15.55mA   -14.77mA   -16.02mA
1.826V    -31.64mA   -30.06mA   -32.59mA
1.996V    -52.63mA   -50mA      -54.21mA
2.098V    -78.1mA    -74.2mA    -80.45mA
2.2V      -114.5mA   -108.8mA   -117.9mA
[Ramp]
| variable   typ   min   max
dV/dt_r   0.215/0.235n   0.202/0.287n   0.224/0.221n
dV/dt_f   0.287/0.196n   0.272/0.215n   0.302/0.199n
R_load = 50.000
[Rising Waveform]
R_fixture = 50.000
V_fixture = 0.000
V_fixture_min = 0.000
V_fixture_max = 0.000
|  time   V(typ)   V(min)   V(max)
0s        3.319uV    89.43uV    -354uV
377ps     388.7uV    76.7uV     -1.991mV
415ps     -650.5uV   164.5uV    33.22mV
481ps     141.8uV    853.7uV    136.8mV
603ps     152.8mV    -9.314mV   265.5mV
746ps     271.7mV    102.6mV    327.1mV
938ps     327.1mV    245.2mV    355.9mV
1.101ns   342.1mV    295.9mV    364.7mV
1.341ns   349.8mV    321mV      369.8mV
30ns      358.4mV    336.9mV    373.6mV
[Rising Waveform]
R_fixture = 50.000
V_fixture = 0.367
V_fixture_min = 0.350
V_fixture_max = 0.386
|  time   V(typ)   V(min)   V(max)
0s        182.2mV    176.5mV    189mV
375ps     182.5mV    176.5mV    188.8mV
403ps     182.5mV    176.6mV    224.6mV
466ps     186mV      176.9mV    376.7mV
567ps     376.2mV    175.2mV    544.3mV
695ps     544.9mV    319.3mV    636mV
878ps     625mV      512.6mV    678.7mV
1.019ns   642.7mV    574.3mV    689.4mV
1.238ns   652.3mV    605.9mV    695.8mV
30ns      664.6mV    625.4mV    700.5mV
[Falling Waveform]
R_fixture = 50.000
V_fixture = 0.367
V_fixture_min = 0.350
V_fixture_max = 0.386
|  time   V(typ)   V(min)   V(max)
0s        664.6mV    625.5mV    700.5mV
362ps     664.3mV    625.2mV    702mV
412ps     668.6mV    625mV      624.3mV
469ps     652.8mV    625.5mV    466.2mV
520ps     535.9mV    629.3mV    352.6mV
581ps     378.5mV    629.4mV    273.6mV
662ps     263.4mV    502.5mV    225.6mV
780ps     205.8mV    290.1mV    201.9mV
991ps     186.9mV    191mV      192.7mV
30ns      182.2mV    176.5mV    189mV
[Falling Waveform]
R_fixture = 50.000
V_fixture = 0.000
V_fixture_min = 0.000
V_fixture_max = 0.000
|  time   V(typ)   V(min)   V(max)
0s        358.5mV    337mV      373.6mV
354ps     358mV      336.6mV    380.8mV
455ps     358.4mV    336.6mV    179.3mV
506ps     254.2mV    341.1mV    100.9mV
569ps     125.2mV    346.1mV    49.64mV
645ps     51.68mV    239.9mV    22.17mV
747ps     17.09mV    86.7mV     8.644mV
821ps     8.512mV    39.64mV    4.935mV
946ps     3.527mV    11.31mV    2.322mV
30ns      4.91uV     95.64uV    -354uV
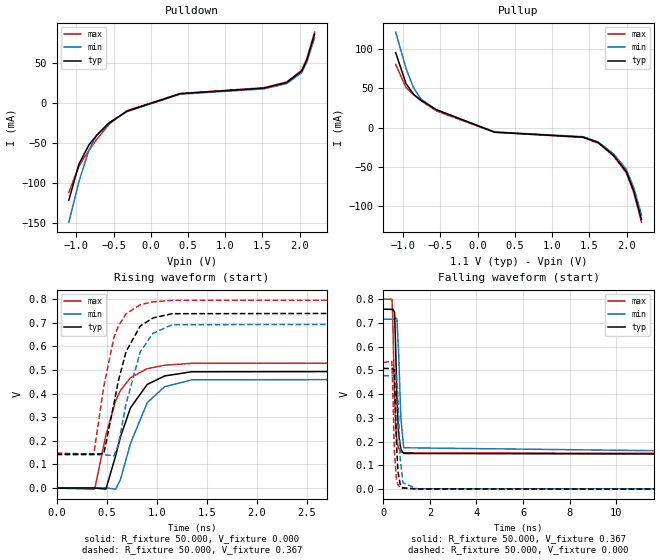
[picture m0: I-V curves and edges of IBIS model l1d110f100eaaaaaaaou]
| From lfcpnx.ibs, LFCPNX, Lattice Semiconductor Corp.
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|   Model l1d110f100eaaaaaaaou
[Model] l1d110f100eaaaaaaaou
Model_type Output
Polarity   Non-Inverting
Enable   Active-High
Vmeas =  0.183V
Cref =  30.000pF
Rref =  50.000
Vref =  0.183V
C_comp   5.000pF   4.000pF   5.500pF
[Temperature Range]   25.000   0.125k   -40.000
[Voltage Range]   1.100V   1.050V   1.160V
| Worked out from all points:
|   slope of the pulldown table from 0 to 0.165 V, typ, clamps not added: 32.2 ohm
|   slope of the pullup table from 0 to 0.165 V, typ, clamps not added: 36.7 ohm
|   rising waveform, R_fixture 50.000, V_fixture 0.000: 20-80 % time 260ps typ, 263ps min, 217ps max; typ from 0 V to 0.508 V
|   rising waveform, R_fixture 50.000, V_fixture 0.367: 20-80 % time 215ps typ, 213ps min, 177ps max; typ from 0.143 V to 0.757 V
|   falling waveform, R_fixture 50.000, V_fixture 0.367: 20-80 % time 114ps typ, 130ps min, 108ps max; typ from 0.757 V to 0.143 V
|   falling waveform, R_fixture 50.000, V_fixture 0.000: 20-80 % time 102ps typ, 116ps min, 96.1ps max; typ from 0.508 V to 0 V
[Pulldown]
|Voltage   I(typ)   I(min)   I(max)
-1.1V     -122.1mA   -149.6mA   -112.3mA
-964mV    -76.94mA   -98.78mA   -79.46mA
-828mV    -52.63mA   -59.02mA   -59.47mA
-726mV    -41.11mA   -40.51mA   -46.12mA
-556mV    -25.32mA   -24.84mA   -26.8mA
-318mV    -10.78mA   -11.34mA   -10.12mA
396mV     11.02mA    10.47mA    11.35mA
1.518V    17.95mA    17.05mA    18.49mA
1.824V    24.9mA     23.66mA    25.65mA
2.028V    39.34mA    37.38mA    40.52mA
2.096V    53.27mA    50.61mA    54.87mA
2.2V      85.49mA    81.21mA    88.05mA
[Pullup]
|Voltage   I(typ)   I(min)   I(max)
-1.1V     95.25mA    121.5mA    80.27mA
-962mV    56.01mA    75.48mA    51mA
-860mV    42.29mA    50.45mA    41.82mA
-758mV    34.74mA    36.01mA    33.93mA
-554mV    22.7mA     22.63mA    21.2mA
228mV     -5.849mA   -5.557mA   -6.025mA
1.418V    -12.2mA    -11.59mA   -12.57mA
1.622V    -19.29mA   -18.33mA   -19.87mA
1.826V    -35.25mA   -33.48mA   -36.3mA
1.996V    -55.91mA   -53.12mA   -57.59mA
2.098V    -80.86mA   -76.81mA   -83.28mA
2.2V      -116.9mA   -111.1mA   -120.4mA
[Ramp]
| variable   typ   min   max
dV/dt_r   0.305/0.260n   0.296/0.262n   0.320/0.216n
dV/dt_f   0.375/0.159n   0.361/0.171n   0.385/0.158n
R_load = 50.000
[Rising Waveform]
R_fixture = 50.000
V_fixture = 0.000
V_fixture_min = 0.000
V_fixture_max = 0.000
|  time   V(typ)   V(min)   V(max)
0s        2.583uV    349.1uV    -317.2uV
381ps     570.1uV    318.3uV    -4.584mV
493ps     -4.519mV   1.177mV    225.2mV
591ps     138.5mV    -4.6mV     370.9mV
639ps     217.5mV    37.15mV    413.7mV
738ps     339.7mV    188.8mV    467.2mV
905ps     438.7mV    361.4mV    505.6mV
1.079ns   474.6mV    429.1mV    520.1mV
1.349ns   492.3mV    458.2mV    528.2mV
30ns      508.2mV    477.4mV    533mV
[Rising Waveform]
R_fixture = 50.000
V_fixture = 0.367
V_fixture_min = 0.350
V_fixture_max = 0.386
|  time   V(typ)   V(min)   V(max)
0s        143.3mV    140.9mV    148.2mV
372ps     143.6mV    140.9mV    143.7mV
472ps     145.8mV    141.6mV    431.9mV
573ps     358mV      136.3mV    637mV
617ps     453.3mV    184.7mV    686.1mV
694ps     577.5mV    356.9mV    737.6mV
836ps     686.4mV    577.1mV    776.2mV
963ps     720.2mV    655.1mV    788.1mV
1.153ns   738.1mV    691.3mV    794.7mV
30ns      757.2mV    715.2mV    800.1mV
[Falling Waveform]
R_fixture = 50.000
V_fixture = 0.367
V_fixture_min = 0.350
V_fixture_max = 0.386
|  time   V(typ)   V(min)   V(max)
0s        757.3mV    715.2mV    800.1mV
368ps     756.8mV    715.1mV    799.1mV
400ps     758.2mV    715mV      724.3mV
479ps     744.4mV    716mV      384.7mV
524ps     602.6mV    721.4mV    272.4mV
580ps     385.4mV    716.6mV    204.9mV
652ps     233mV      579mV      171.3mV
749ps     167.8mV    299.5mV    157.4mV
874ps     150.1mV    174mV      152.6mV
30ns      143.3mV    140.9mV    148.2mV
[Falling Waveform]
R_fixture = 50.000
V_fixture = 0.000
V_fixture_min = 0.000
V_fixture_max = 0.000
|  time   V(typ)   V(min)   V(max)
0s        508.2mV    477.4mV    533mV
360ps     507.4mV    477.3mV    538.7mV
387ps     508.7mV    477.2mV    478.3mV
470ps     500.5mV    478.5mV    159.8mV
562ps     191.2mV    488.5mV    40.3mV
625ps     75.27mV    388.3mV    17.75mV
721ps     19.46mV    129.4mV    6.822mV
839ps     5.515mV    26.39mV    3.213mV
1.452ns   822.1uV    1.284mV    121.5uV
30ns      3.899uV    349.1uV    -317.2uV
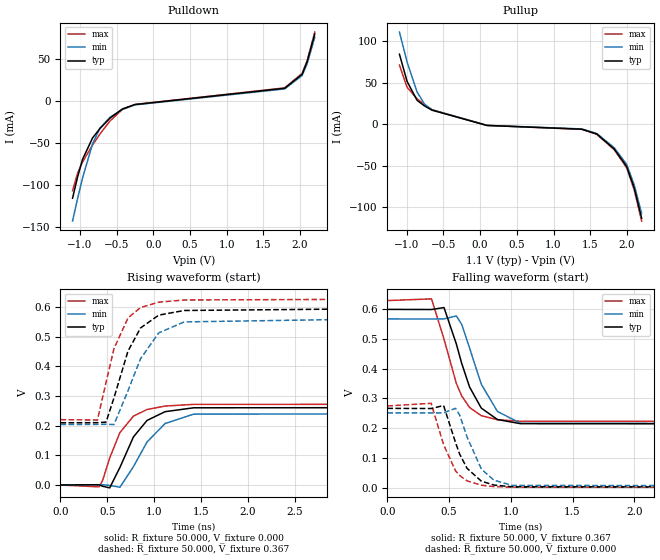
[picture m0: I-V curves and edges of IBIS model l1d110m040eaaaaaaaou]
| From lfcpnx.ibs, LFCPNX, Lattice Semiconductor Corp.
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|   Model l1d110m040eaaaaaaaou
[Model] l1d110m040eaaaaaaaou
Model_type Output
Polarity   Non-Inverting
Enable   Active-High
Vmeas =  0.183V
Cref =  30.000pF
Rref =  50.000
Vref =  0.183V
C_comp   5.000pF   4.000pF   5.500pF
[Temperature Range]   25.000   0.125k   -40.000
[Voltage Range]   1.100V   1.050V   1.160V
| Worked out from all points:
|   slope of the pulldown table from 0 to 0.165 V, typ, clamps not added: 65.6 ohm
|   slope of the pullup table from 0 to 0.165 V, typ, clamps not added: 75 ohm
|   rising waveform, R_fixture 50.000, V_fixture 0.000: 20-80 % time 279ps typ, 326ps min, 242ps max; typ from 0 V to 0.266 V
|   rising waveform, R_fixture 50.000, V_fixture 0.367: 20-80 % time 267ps typ, 314ps min, 224ps max; typ from 0.21 V to 0.598 V
|   falling waveform, R_fixture 50.000, V_fixture 0.367: 20-80 % time 193ps typ, 202ps min, 182ps max; typ from 0.598 V to 0.21 V
|   falling waveform, R_fixture 50.000, V_fixture 0.000: 20-80 % time 160ps typ, 164ps min, 154ps max; typ from 0.266 V to 0 V
[Pulldown]
|Voltage   I(typ)   I(min)   I(max)
-1.1V     -115.7mA   -142.9mA   -106.8mA
-1.032V   -90.63mA   -116.4mA   -86.01mA
-964mV    -69.45mA   -91.65mA   -72.45mA
-828mV    -44mA      -51.1mA    -52.37mA
-726mV    -32.64mA   -32.03mA   -39.16mA
-590mV    -20.35mA   -19.23mA   -23.7mA
-420mV    -9.344mA   -9.89mA    -9.81mA
-250mV    -4.118mA   -4.516mA   -3.997mA
1.79V     15.26mA    14.5mA     15.72mA
2.028V    32.04mA    30.44mA    33mA
2.096V    46.85mA    44.51mA    48.26mA
2.2V      79.9mA     75.9mA     82.29mA
[Pullup]
|Voltage   I(typ)   I(min)   I(max)
-1.1V     84.59mA    111.3mA    71.43mA
-996mV    51.79mA    75.29mA    44.63mA
-860mV    28.98mA    39.08mA    30.92mA
-758mV    22.19mA    24.35mA    23.73mA
-656mV    17.06mA    17.48mA    17.67mA
92mV      -1.311mA   -1.245mA   -1.35mA
1.384V    -5.864mA   -5.57mA    -6.039mA
1.588V    -11.61mA   -11.03mA   -11.96mA
1.826V    -29.7mA    -28.22mA   -30.59mA
1.996V    -50.88mA   -48.33mA   -52.4mA
2.098V    -76.63mA   -72.8mA    -78.93mA
2.2V      -113.2mA   -107.5mA   -116.6mA
[Ramp]
| variable   typ   min   max
dV/dt_r   0.160/0.278n   0.150/0.326n   0.165/0.241n
dV/dt_f   0.226/0.257n   0.211/0.271n   0.234/0.242n
R_load = 50.000
[Rising Waveform]
R_fixture = 50.000
V_fixture = 0.000
V_fixture_min = 0.000
V_fixture_max = 0.000
|  time   V(typ)   V(min)   V(max)
0s        3.84uV     405.9uV    388.1nV
411ps     776.1uV    466.9uV    -6.426mV
449ps     -4.197mV   797.4uV    14.87mV
525ps     -9.702mV   -1.336mV   90.79mV
634ps     59.12mV    -7.759mV   176.8mV
778ps     162.1mV    61.81mV    232.1mV
923ps     217.7mV    145mV      254.6mV
1.116ns   247.3mV    207.4mV    266.2mV
1.42ns    260.3mV    238.9mV    271.8mV
30ns      266.4mV    251.2mV    274.5mV
[Rising Waveform]
R_fixture = 50.000
V_fixture = 0.367
V_fixture_min = 0.350
V_fixture_max = 0.386
|  time   V(typ)   V(min)   V(max)
0s        209.7mV    204.2mV    220.3mV
394ps     210.2mV    204.3mV    219mV
486ps     212.1mV    204.7mV    346mV
571ps     294.4mV    203.9mV    460.4mV
720ps     451.6mV    317.9mV    563.3mV
854ps     529.7mV    426mV      598.5mV
1.048ns   572.9mV    513mV      616.6mV
1.319ns   588.5mV    550mV      623.9mV
4.473ns   597.5mV    565.4mV    627.7mV
30ns      598.1mV    566.2mV    627.7mV
[Falling Waveform]
R_fixture = 50.000
V_fixture = 0.367
V_fixture_min = 0.350
V_fixture_max = 0.386
|  time   V(typ)   V(min)   V(max)
0s        598.2mV    566.2mV    627.7mV
358ps     597.8mV    566.1mV    633.5mV
459ps     604.4mV    566.3mV    498.7mV
559ps     482.3mV    576.2mV    350.2mV
602ps     417.8mV    548.2mV    308.5mV
666ps     338.2mV    468.8mV    269.5mV
761ps     267.3mV    347.4mV    241.9mV
892ps     229mV      256mV      228.5mV
1.079ns   215.1mV    216.6mV    223.3mV
30ns      209.7mV    204.2mV    220.3mV
[Falling Waveform]
R_fixture = 50.000
V_fixture = 0.000
V_fixture_min = 0.000
V_fixture_max = 0.000
|  time   V(typ)   V(min)   V(max)
0s        266.4mV    251.2mV    274.5mV
355ps     265.9mV    251.1mV    283.3mV
456ps     275.8mV    251.4mV    144.4mV
552ps     152.3mV    266.7mV    57.47mV
586ps     112.9mV    244mV      41.29mV
646ps     65.18mV    170.3mV    23.44mV
762ps     22.32mV    62.8mV     8.744mV
862ps     9.508mV    26.09mV    4.367mV
1.011ns   3.432mV    8.068mV    1.992mV
30ns      4.861uV    405.9uV    3.944uV
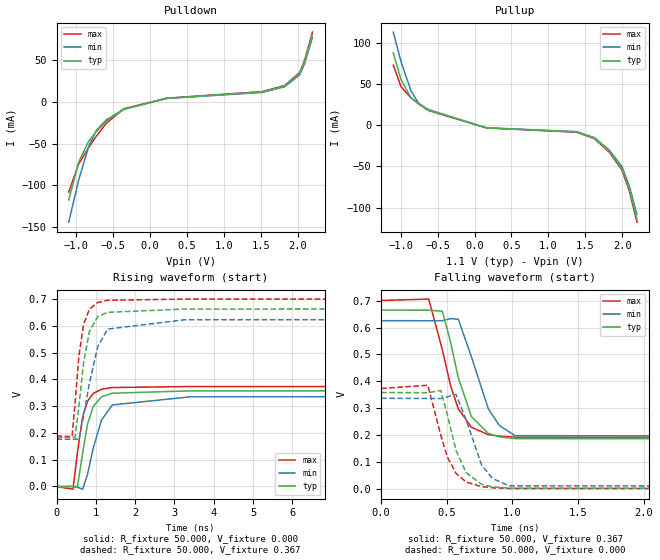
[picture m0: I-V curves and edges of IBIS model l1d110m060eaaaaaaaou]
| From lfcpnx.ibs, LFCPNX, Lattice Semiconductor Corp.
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|   Model l1d110m060eaaaaaaaou
[Model] l1d110m060eaaaaaaaou
Model_type Output
Polarity   Non-Inverting
Enable   Active-High
Vmeas =  0.183V
Cref =  30.000pF
Rref =  50.000
Vref =  0.183V
C_comp   5.000pF   4.000pF   5.500pF
[Temperature Range]   25.000   0.125k   -40.000
[Voltage Range]   1.100V   1.050V   1.160V
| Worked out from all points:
|   slope of the pulldown table from 0 to 0.165 V, typ, clamps not added: 49 ohm
|   slope of the pullup table from 0 to 0.165 V, typ, clamps not added: 54.8 ohm
|   rising waveform, R_fixture 50.000, V_fixture 0.000: 20-80 % time 282ps typ, 395ps min, 239ps max; typ from 0 V to 0.358 V
|   rising waveform, R_fixture 50.000, V_fixture 0.367: 20-80 % time 261ps typ, 388ps min, 217ps max; typ from 0.182 V to 0.665 V
|   falling waveform, R_fixture 50.000, V_fixture 0.367: 20-80 % time 159ps typ, 189ps min, 164ps max; typ from 0.665 V to 0.182 V
|   falling waveform, R_fixture 50.000, V_fixture 0.000: 20-80 % time 134ps typ, 153ps min, 141ps max; typ from 0.358 V to 0 V
[Pulldown]
|Voltage   I(typ)   I(min)   I(max)
-1.1V     -117.9mA   -144.6mA   -108.3mA
-964mV    -71.92mA   -93.45mA   -74.45mA
-828mV    -46.85mA   -53.11mA   -54.37mA
-726mV    -35.43mA   -34.2mA    -41.11mA
-590mV    -22.92mA   -21.33mA   -25.52mA
-352mV    -8.486mA   -8.765mA   -7.975mA
226mV     4.511mA    4.285mA    4.646mA
1.518V    12.17mA    11.56mA    12.54mA
1.824V    19.3mA     18.33mA    19.88mA
2.028V    34.44mA    32.71mA    35.47mA
2.096V    48.95mA    46.51mA    50.42mA
2.2V      81.73mA    77.65mA    84.19mA
[Pullup]
|Voltage   I(typ)   I(min)   I(max)
-1.1V     88.32mA    113.8mA    73.62mA
-996mV    55.91mA    77.94mA    47.29mA
-860mV    33.67mA    41.95mA    33.68mA
-758mV    26.63mA    27.31mA    26.33mA
-622mV    19.41mA    18.58mA    18.27mA
160mV     -2.933mA   -2.787mA   -3.021mA
1.384V    -7.973mA   -7.574mA   -8.212mA
1.622V    -15.55mA   -14.77mA   -16.02mA
1.826V    -31.64mA   -30.06mA   -32.59mA
1.996V    -52.63mA   -50mA      -54.21mA
2.098V    -78.1mA    -74.2mA    -80.45mA
2.2V      -114.5mA   -108.8mA   -117.9mA
[Ramp]
| variable   typ   min   max
dV/dt_r   0.215/0.281n   0.202/0.394n   0.224/0.238n
dV/dt_f   0.287/0.224n   0.272/0.270n   0.302/0.225n
R_load = 50.000
[Rising Waveform]
R_fixture = 50.000
V_fixture = 0.000
V_fixture_min = 0.000
V_fixture_max = 0.000
|  time   V(typ)   V(min)   V(max)
0s        3.319uV    89.43uV    -354uV
419ps     -298.7uV   178.9uV    -10.06mV
534ps     136.7uV    -2.946mV   129.6mV
665ps     125.7mV    -10.04mV   261.2mV
789ps     232.9mV    45.12mV    318.7mV
933ps     298.9mV    143.1mV    347.7mV
1.145ns   335.4mV    248.2mV    363.4mV
1.42ns    348.6mV    304.8mV    369.9mV
3.411ns   357.4mV    335.2mV    373.6mV
30ns      358.4mV    336.9mV    373.6mV
[Rising Waveform]
R_fixture = 50.000
V_fixture = 0.367
V_fixture_min = 0.350
V_fixture_max = 0.386
|  time   V(typ)   V(min)   V(max)
0s        182.2mV    176.5mV    189mV
395ps     182.9mV    176.6mV    186.7mV
472ps     185.5mV    176.9mV    312.4mV
570ps     301.2mV    177.2mV    488.4mV
690ps     464.2mV    263.3mV    605.9mV
835ps     578.6mV    385.1mV    662.4mV
1.049ns   634.8mV    522.8mV    688mV
1.302ns   651mV      588.2mV    696mV
3.264ns   663.2mV    623.3mV    700.5mV
30ns      664.6mV    625.4mV    700.5mV
[Falling Waveform]
R_fixture = 50.000
V_fixture = 0.367
V_fixture_min = 0.350
V_fixture_max = 0.386
|  time   V(typ)   V(min)   V(max)
0s        664.6mV    625.5mV    700.5mV
363ps     664.2mV    625.1mV    705.6mV
467ps     660.4mV    625.3mV    516.5mV
531ps     541.8mV    633mV      380.5mV
588ps     413.4mV    630.6mV    298.2mV
688ps     269.5mV    491.3mV    229.4mV
816ps     206.9mV    298.9mV    202.3mV
902ps     193.9mV    235.5mV    196.3mV
1.021ns   187.4mV    198.4mV    192.8mV
30ns      182.2mV    176.5mV    189mV
[Falling Waveform]
R_fixture = 50.000
V_fixture = 0.000
V_fixture_min = 0.000
V_fixture_max = 0.000
|  time   V(typ)   V(min)   V(max)
0s        358.5mV    337mV      373.6mV
356ps     357.9mV    336.5mV    385.4mV
455ps     366mV      336.3mV    199.4mV
505ps     275.2mV    342.5mV    118.6mV
571ps     143.1mV    351.8mV    58.36mV
648ps     61.05mV    256.6mV    26.31mV
766ps     17.62mV    88.96mV    8.998mV
849ps     8.31mV     39.17mV    4.837mV
977ps     3.483mV    11.8mV     2.231mV
30ns      4.906uV    95.64uV    -354uV
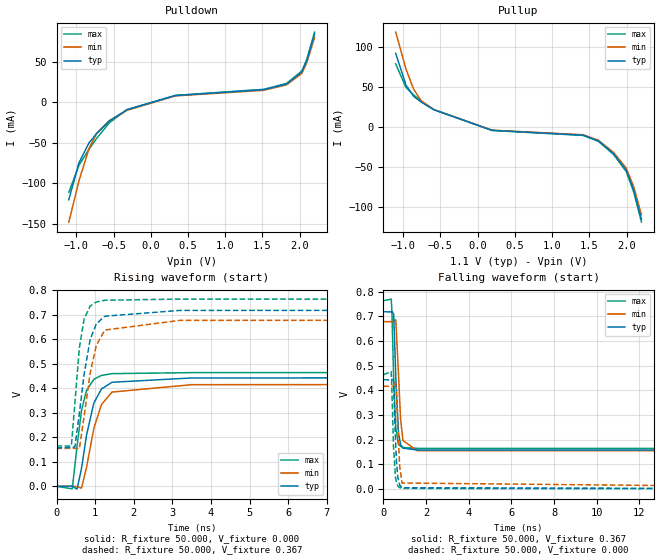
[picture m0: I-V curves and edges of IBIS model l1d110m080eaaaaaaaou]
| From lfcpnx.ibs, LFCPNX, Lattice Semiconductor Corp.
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|   Model l1d110m080eaaaaaaaou
[Model] l1d110m080eaaaaaaaou
Model_type Output
Polarity   Non-Inverting
Enable   Active-High
Vmeas =  0.183V
Cref =  30.000pF
Rref =  50.000
Vref =  0.183V
C_comp   5.000pF   4.000pF   5.500pF
[Temperature Range]   25.000   0.125k   -40.000
[Voltage Range]   1.100V   1.050V   1.160V
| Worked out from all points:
|   slope of the pulldown table from 0 to 0.165 V, typ, clamps not added: 37.8 ohm
|   slope of the pullup table from 0 to 0.165 V, typ, clamps not added: 43.3 ohm
|   rising waveform, R_fixture 50.000, V_fixture 0.000: 20-80 % time 341ps typ, 380ps min, 244ps max; typ from 0 V to 0.443 V
|   rising waveform, R_fixture 50.000, V_fixture 0.367: 20-80 % time 315ps typ, 336ps min, 209ps max; typ from 0.158 V to 0.719 V
|   falling waveform, R_fixture 50.000, V_fixture 0.367: 20-80 % time 139ps typ, 165ps min, 127ps max; typ from 0.719 V to 0.158 V
|   falling waveform, R_fixture 50.000, V_fixture 0.000: 20-80 % time 118ps typ, 136ps min, 109ps max; typ from 0.444 V to 0 V
[Pulldown]
|Voltage   I(typ)   I(min)   I(max)
-1.1V     -120.2mA   -147.9mA   -111mA
-964mV    -74.71mA   -96.95mA   -77.92mA
-828mV    -50.08mA   -56.99mA   -57.91mA
-726mV    -38.61mA   -38.36mA   -44.61mA
-556mV    -23.1mA    -22.88mA   -25.4mA
-318mV    -9.291mA   -10.08mA   -9.131mA
328mV     8.086mA    7.682mA    8.329mA
1.518V    15.38mA    14.61mA    15.84mA
1.824V    22.41mA    21.29mA    23.08mA
2.028V    37.16mA    35.3mA     38.27mA
2.096V    51.35mA    48.78mA    52.89mA
2.2V      83.82mA    79.63mA    86.33mA
[Pullup]
|Voltage   I(typ)   I(min)   I(max)
-1.1V     92.03mA    118.6mA    78.8mA
-962mV    52.27mA    72.44mA    49.17mA
-860mV    38.29mA    47.22mA    40.05mA
-758mV    30.99mA    32.71mA    32.28mA
-588mV    21.43mA    21.64mA    21.65mA
194mV     -4.357mA   -4.139mA   -4.488mA
1.418V    -10.41mA   -9.889mA   -10.72mA
1.622V    -17.58mA   -16.7mA    -18.11mA
1.826V    -33.59mA   -31.91mA   -34.6mA
1.996V    -54.41mA   -51.69mA   -56.04mA
2.098V    -79.59mA   -75.61mA   -81.98mA
2.2V      -115.8mA   -110mA     -119.3mA
[Ramp]
| variable   typ   min   max
dV/dt_r   0.266/0.341n   0.263/0.380n   0.283/0.243n
dV/dt_f   0.342/0.200n   0.336/0.232n   0.359/0.188n
R_load = 50.000
[Rising Waveform]
R_fixture = 50.000
V_fixture = 0.000
V_fixture_min = 0.000
V_fixture_max = 0.000
|  time   V(typ)   V(min)   V(max)
0s        2.857uV    475.2uV    -82.95uV
407ps     977.1uV    495.3uV    -9.979mV
531ps     -11.41mV   -1.292mV   162.8mV
646ps     72.25mV    -7.101mV   308.9mV
775ps     207.4mV    75.84mV    390.6mV
966ps     339.5mV    236.4mV    436.6mV
1.164ns   397.2mV    333.6mV    452.3mV
1.437ns   424.4mV    384.5mV    459.6mV
3.501ns   442.1mV    414.6mV    463.8mV
30ns      443.4mV    417mV      463.8mV
[Rising Waveform]
R_fixture = 50.000
V_fixture = 0.367
V_fixture_min = 0.350
V_fixture_max = 0.386
|  time   V(typ)   V(min)   V(max)
0s        157.8mV    154.8mV    164.8mV
383ps     158.3mV    154.8mV    164.4mV
475ps     161.3mV    155.4mV    338.4mV
591ps     296.2mV    153.6mV    565.2mV
713ps     455.4mV    283.2mV    681.8mV
871ps     598.7mV    462mV      735mV
1.031ns   662.6mV    575mV      751.6mV
1.249ns   693.9mV    637.3mV    758.9mV
3.197ns   717.4mV    676.8mV    763.7mV
30ns      719mV      679.1mV    763.7mV
[Falling Waveform]
R_fixture = 50.000
V_fixture = 0.367
V_fixture_min = 0.350
V_fixture_max = 0.386
|  time   V(typ)   V(min)   V(max)
0s        719mV      679.1mV    763.7mV
369ps     718.4mV    679.1mV    770.5mV
404ps     720.6mV    678.9mV    705.3mV
484ps     708.2mV    680.4mV    438.3mV
581ps     453.6mV    686.3mV    246.6mV
706ps     229.8mV    468.2mV    184.1mV
804ps     181.4mV    285.4mV    173.1mV
916ps     166.1mV    197.2mV    169.1mV
1.584ns   158.7mV    156mV      165.3mV
30ns      157.8mV    154.8mV    164.8mV
[Falling Waveform]
R_fixture = 50.000
V_fixture = 0.000
V_fixture_min = 0.000
V_fixture_max = 0.000
|  time   V(typ)   V(min)   V(max)
0s        443.5mV    417mV      463.8mV
364ps     442.5mV    416.9mV    476.5mV
394ps     444.8mV    416.7mV    416mV
471ps     442.9mV    418.2mV    175.9mV
566ps     200.3mV    435mV      47.68mV
615ps     108.2mV    379.1mV    25.53mV
677ps     48.24mV    240.7mV    12.76mV
768ps     15.88mV    88.77mV    5.808mV
876ps     5.628mV    24.82mV    3.082mV
30ns      4.288uV    475.2uV    -82.95uV
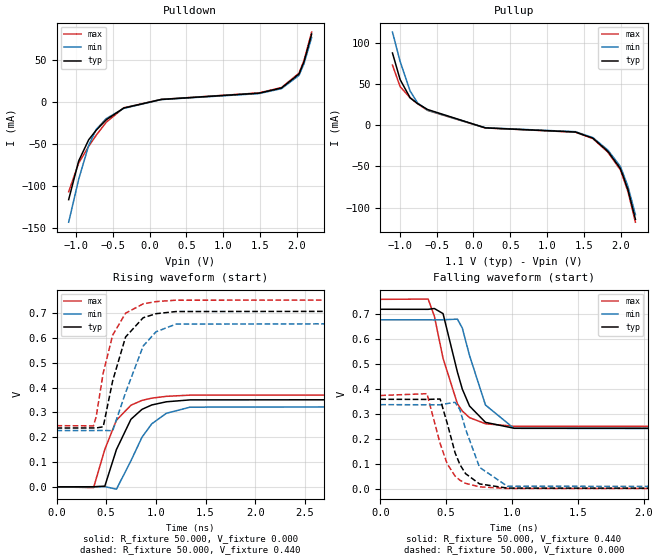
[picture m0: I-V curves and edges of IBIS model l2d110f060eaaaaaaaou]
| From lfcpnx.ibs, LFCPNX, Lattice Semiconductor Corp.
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|   Model l2d110f060eaaaaaaaou
[Model] l2d110f060eaaaaaaaou
Model_type Output
Polarity   Non-Inverting
Enable   Active-High
Vmeas =  0.220V
Cref =  30.000pF
Rref =  50.000
Vref =  0.220V
C_comp   5.000pF   4.000pF   5.500pF
[Temperature Range]   25.000   0.125k   -40.000
[Voltage Range]   1.100V   1.050V   1.160V
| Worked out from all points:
|   slope of the pulldown table from 0 to 0.165 V, typ, clamps not added: 56.9 ohm
|   slope of the pullup table from 0 to 0.165 V, typ, clamps not added: 54.8 ohm
|   rising waveform, R_fixture 50.000, V_fixture 0.000: 20-80 % time 235ps typ, 288ps min, 221ps max; typ from 0 V to 0.358 V
|   rising waveform, R_fixture 50.000, V_fixture 0.440: 20-80 % time 197ps typ, 252ps min, 187ps max; typ from 0.237 V to 0.718 V
|   falling waveform, R_fixture 50.000, V_fixture 0.440: 20-80 % time 156ps typ, 166ps min, 152ps max; typ from 0.718 V to 0.237 V
|   falling waveform, R_fixture 50.000, V_fixture 0.000: 20-80 % time 136ps typ, 147ps min, 132ps max; typ from 0.358 V to 0 V
[Pulldown]
|Voltage   I(typ)   I(min)   I(max)
-1.1V     -116.7mA   -143.6mA   -107.3mA
-964mV    -70.53mA   -92.37mA   -73.1mA
-828mV    -45.26mA   -51.9mA    -53.07mA
-726mV    -33.87mA   -32.89mA   -39.87mA
-590mV    -21.5mA    -20.06mA   -24.4mA
-352mV    -7.468mA   -7.88mA    -7.179mA
158mV     2.785mA    2.646mA    2.868mA
1.484V    10.27mA    9.758mA    10.58mA
1.79V     16.47mA    15.65mA    16.97mA
2.028V    33.09mA    31.44mA    34.09mA
2.096V    47.77mA    45.38mA    49.21mA
2.2V      80.7mA     76.67mA    83.12mA
[Pullup]
|Voltage   I(typ)   I(min)   I(max)
-1.1V     88.32mA    113.8mA    73.62mA
-996mV    55.91mA    77.94mA    47.29mA
-860mV    33.67mA    41.95mA    33.68mA
-758mV    26.63mA    27.31mA    26.33mA
-622mV    19.41mA    18.58mA    18.27mA
160mV     -2.933mA   -2.787mA   -3.021mA
1.384V    -7.973mA   -7.574mA   -8.212mA
1.622V    -15.55mA   -14.77mA   -16.02mA
1.826V    -31.64mA   -30.06mA   -32.59mA
1.996V    -52.63mA   -50mA      -54.21mA
2.098V    -78.1mA    -74.2mA    -80.45mA
2.2V      -114.5mA   -108.8mA   -117.9mA
[Ramp]
| variable   typ   min   max
dV/dt_r   0.215/0.234n   0.202/0.287n   0.224/0.220n
dV/dt_f   0.254/0.208n   0.247/0.220n   0.267/0.210n
R_load = 50.000
[Rising Waveform]
R_fixture = 50.000
V_fixture = 0.000
V_fixture_min = 0.000
V_fixture_max = 0.000
|  time   V(typ)   V(min)   V(max)
0s        3.587uV    95.7uV     -232.6uV
373ps     422.4uV    91uV       -3.07mV
486ps     2.76mV     902.5uV    151.2mV
603ps     150.5mV    -9.357mV   268.8mV
749ps     272.5mV    105mV      329.1mV
860ps     312.5mV    200.1mV    348.6mV
958ps     330.2mV    254mV      357.7mV
1.105ns   343mV      296.6mV    365mV
1.345ns   350.7mV    321.4mV    369.9mV
30ns      358.4mV    336.9mV    373.6mV
[Rising Waveform]
R_fixture = 50.000
V_fixture = 0.440
V_fixture_min = 0.419
V_fixture_max = 0.463
|  time   V(typ)   V(min)   V(max)
0s        237.2mV    227.2mV    246.7mV
372ps     237.5mV    227.2mV    245.9mV
399ps     237.5mV    227.2mV    282.8mV
470ps     242.2mV    227.5mV    459.5mV
565ps     427.5mV    226.3mV    611.9mV
695ps     604.4mV    380mV      700.3mV
872ps     682mV      567.9mV    738mV
1.001ns   698.2mV    625.2mV    747.1mV
1.203ns   707mV      656.3mV    752.8mV
30ns      717.7mV    675.6mV    757.3mV
[Falling Waveform]
R_fixture = 50.000
V_fixture = 0.440
V_fixture_min = 0.419
V_fixture_max = 0.463
|  time   V(typ)   V(min)   V(max)
0s        717.7mV    675.7mV    757.3mV
363ps     717.4mV    675.5mV    758.4mV
410ps     720.7mV    675.3mV    690.4mV
476ps     700.3mV    675.9mV    521.8mV
585ps     467mV      678.2mV    340.7mV
622ps     399.3mV    642.6mV    311.8mV
677ps     331.4mV    532.9mV    285.2mV
798ps     266.4mV    335.5mV    260.8mV
1.014ns   243mV      242.4mV    250.8mV
30ns      237.2mV    227.2mV    246.7mV
[Falling Waveform]
R_fixture = 50.000
V_fixture = 0.000
V_fixture_min = 0.000
V_fixture_max = 0.000
|  time   V(typ)   V(min)   V(max)
0s        358.5mV    337mV      373.6mV
354ps     357.9mV    336.6mV    380.8mV
454ps     359.5mV    336.6mV    181.4mV
508ps     262.1mV    341.4mV    100.1mV
567ps     145.5mV    346.5mV    52.43mV
604ps     97.91mV    316.7mV    35.46mV
647ps     61.66mV    239.1mV    23.01mV
753ps     20.72mV    86.87mV    9.01mV
964ps     3.983mV    11.4mV     2.467mV
30ns      5.3uV      102.2uV    -232.6uV
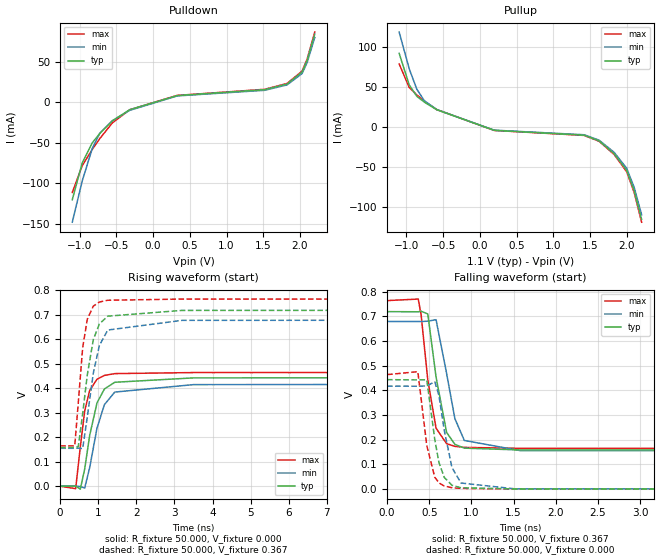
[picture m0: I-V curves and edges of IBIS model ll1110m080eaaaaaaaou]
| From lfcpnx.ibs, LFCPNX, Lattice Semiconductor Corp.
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|   Model ll1110m080eaaaaaaaou
[Model] ll1110m080eaaaaaaaou
Model_type Output
Polarity   Non-Inverting
Enable   Active-High
Vmeas =  0.183V
Cref =  30.000pF
Rref =  50.000
Vref =  0.183V
C_comp   5.000pF   4.000pF   5.500pF
[Temperature Range]   25.000   0.125k   -40.000
[Voltage Range]   1.100V   1.050V   1.160V
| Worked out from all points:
|   slope of the pulldown table from 0 to 0.165 V, typ, clamps not added: 37.8 ohm
|   slope of the pullup table from 0 to 0.165 V, typ, clamps not added: 43.3 ohm
|   rising waveform, R_fixture 50.000, V_fixture 0.000: 20-80 % time 341ps typ, 380ps min, 244ps max; typ from 0 V to 0.443 V
|   rising waveform, R_fixture 50.000, V_fixture 0.367: 20-80 % time 315ps typ, 336ps min, 209ps max; typ from 0.158 V to 0.719 V
|   falling waveform, R_fixture 50.000, V_fixture 0.367: 20-80 % time 139ps typ, 165ps min, 127ps max; typ from 0.719 V to 0.158 V
|   falling waveform, R_fixture 50.000, V_fixture 0.000: 20-80 % time 118ps typ, 136ps min, 109ps max; typ from 0.444 V to 0 V
[Pulldown]
|Voltage   I(typ)   I(min)   I(max)
-1.1V     -120.2mA   -147.9mA   -111.3mA
-964mV    -74.72mA   -96.95mA   -78.22mA
-828mV    -50.09mA   -57mA      -58.22mA
-726mV    -38.62mA   -38.37mA   -44.92mA
-556mV    -23.11mA   -22.89mA   -25.72mA
-318mV    -9.291mA   -10.08mA   -9.314mA
328mV     8.086mA    7.682mA    8.329mA
1.518V    15.38mA    14.61mA    15.84mA
1.824V    22.41mA    21.29mA    23.08mA
2.028V    37.16mA    35.3mA     38.27mA
2.096V    51.35mA    48.78mA    52.89mA
2.2V      83.82mA    79.63mA    86.33mA
[Pullup]
|Voltage   I(typ)   I(min)   I(max)
-1.1V     92.03mA    118.6mA    78.77mA
-962mV    52.27mA    72.44mA    49.16mA
-860mV    38.29mA    47.22mA    40.04mA
-758mV    30.99mA    32.71mA    32.28mA
-588mV    21.43mA    21.64mA    21.65mA
194mV     -4.357mA   -4.139mA   -4.488mA
1.418V    -10.41mA   -9.89mA    -10.72mA
1.622V    -17.58mA   -16.71mA   -18.11mA
1.826V    -33.6mA    -31.92mA   -34.61mA
1.996V    -54.42mA   -51.7mA    -56.05mA
2.098V    -79.6mA    -75.62mA   -81.99mA
2.2V      -115.8mA   -110mA     -119.3mA
[Ramp]
| variable   typ   min   max
dV/dt_r   0.266/0.341n   0.263/0.380n   0.283/0.243n
dV/dt_f   0.342/0.200n   0.336/0.232n   0.359/0.188n
R_load = 50.000
[Rising Waveform]
R_fixture = 50.000
V_fixture = 0.000
V_fixture_min = 0.000
V_fixture_max = 0.000
|  time   V(typ)   V(min)   V(max)
0s        2.857uV    475.2uV    -82.95uV
407ps     977.7uV    495.2uV    -9.882mV
529ps     -11.98mV   -992.7uV   160.1mV
644ps     70.3mV     -7.572mV   307.3mV
775ps     207.5mV    76.09mV    390.7mV
967ps     340mV      237.2mV    436.7mV
1.162ns   396.9mV    333mV      452.2mV
1.434ns   424.2mV    384.2mV    459.5mV
3.5ns     442.1mV    414.6mV    463.8mV
30ns      443.4mV    417mV      463.8mV
[Rising Waveform]
R_fixture = 50.000
V_fixture = 0.367
V_fixture_min = 0.350
V_fixture_max = 0.386
|  time   V(typ)   V(min)   V(max)
0s        157.8mV    154.8mV    164.8mV
383ps     158.3mV    154.8mV    164.6mV
475ps     161.3mV    155.4mV    339mV
591ps     296.3mV    153.6mV    565.5mV
712ps     454.3mV    282.1mV    681.3mV
871ps     598.7mV    462.3mV    735mV
1.03ns    662.4mV    574.6mV    751.6mV
1.249ns   693.9mV    637.3mV    758.9mV
3.197ns   717.4mV    676.8mV    763.7mV
30ns      719mV      679.1mV    763.7mV
[Falling Waveform]
R_fixture = 50.000
V_fixture = 0.367
V_fixture_min = 0.350
V_fixture_max = 0.386
|  time   V(typ)   V(min)   V(max)
0s        719mV      679.1mV    763.7mV
370ps     718.4mV    679.1mV    769.9mV
404ps     720.6mV    678.9mV    705.7mV
483ps     709.5mV    680.4mV    441.9mV
581ps     453.6mV    686.3mV    246.8mV
706ps     229.8mV    468.2mV    184.2mV
804ps     181.4mV    285.4mV    173.2mV
916ps     166.1mV    197.2mV    169.1mV
1.58ns    158.7mV    156mV      165.3mV
30ns      157.8mV    154.8mV    164.8mV
[Falling Waveform]
R_fixture = 50.000
V_fixture = 0.000
V_fixture_min = 0.000
V_fixture_max = 0.000
|  time   V(typ)   V(min)   V(max)
0s        443.5mV    417mV      463.8mV
365ps     442.5mV    416.9mV    475.9mV
471ps     442.9mV    418.1mV    176.3mV
566ps     200.4mV    435mV      47.81mV
615ps     108.2mV    379.1mV    25.62mV
678ps     47.62mV    238.4mV    12.68mV
769ps     15.7mV     87.74mV    5.791mV
876ps     5.624mV    24.82mV    3.095mV
1.511ns   746.7uV    1.363mV    284.8uV
30ns      4.28uV     475.2uV    -82.95uV
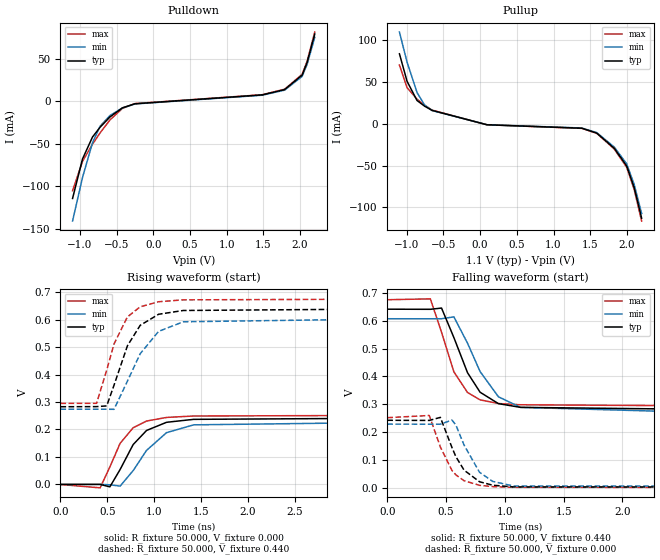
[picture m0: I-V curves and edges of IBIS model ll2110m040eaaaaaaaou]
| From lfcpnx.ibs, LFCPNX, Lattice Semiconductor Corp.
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|   Model ll2110m040eaaaaaaaou
[Model] ll2110m040eaaaaaaaou
Model_type Output
Polarity   Non-Inverting
Enable   Active-High
Vmeas =  0.220V
Cref =  30.000pF
Rref =  50.000
Vref =  0.220V
C_comp   5.000pF   4.000pF   5.500pF
[Temperature Range]   25.000   0.125k   -40.000
[Voltage Range]   1.100V   1.050V   1.160V
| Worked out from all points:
|   slope of the pulldown table from 0 to 0.165 V, typ, clamps not added: 85.8 ohm
|   slope of the pullup table from 0 to 0.165 V, typ, clamps not added: 82.8 ohm
|   rising waveform, R_fixture 50.000, V_fixture 0.000: 20-80 % time 279ps typ, 336ps min, 245ps max; typ from 0 V to 0.242 V
|   rising waveform, R_fixture 50.000, V_fixture 0.440: 20-80 % time 260ps typ, 318ps min, 231ps max; typ from 0.283 V to 0.641 V
|   falling waveform, R_fixture 50.000, V_fixture 0.440: 20-80 % time 226ps typ, 250ps min, 187ps max; typ from 0.641 V to 0.283 V
|   falling waveform, R_fixture 50.000, V_fixture 0.000: 20-80 % time 179ps typ, 184ps min, 164ps max; typ from 0.242 V to 0 V
[Pulldown]
|Voltage   I(typ)   I(min)   I(max)
-1.1V     -114.4mA   -140.9mA   -105.4mA
-964mV    -67.9mA    -89.62mA   -70.71mA
-828mV    -42.18mA   -48.87mA   -50.63mA
-726mV    -30.82mA   -29.64mA   -37.47mA
-590mV    -18.64mA   -16.95mA   -22.13mA
-420mV    -7.903mA   -8.079mA   -8.505mA
-250mV    -3.175mA   -3.376mA   -2.942mA
1.484V    7.256mA    6.893mA    7.474mA
1.79V     13.54mA    12.87mA    13.95mA
2.028V    30.56mA    29.03mA    31.48mA
2.096V    45.55mA    43.27mA    46.91mA
2.2V      78.76mA    74.82mA    81.12mA
[Pullup]
|Voltage   I(typ)   I(min)   I(max)
-1.1V     83.67mA    109.7mA    70.19mA
-996mV    50.77mA    73.67mA    43.14mA
-860mV    27.81mA    37.34mA    29.4mA
-758mV    21.07mA    22.54mA    22.29mA
-656mV    16.05mA    15.8mA     16.35mA
92mV      -1.187mA   -1.128mA   -1.223mA
1.384V    -5.333mA   -5.066mA   -5.493mA
1.588V    -11.11mA   -10.55mA   -11.44mA
1.826V    -29.22mA   -27.76mA   -30.1mA
1.996V    -50.44mA   -47.92mA   -51.96mA
2.098V    -76.27mA   -72.46mA   -78.56mA
2.2V      -112.9mA   -107.3mA   -116.3mA
[Ramp]
| variable   typ   min   max
dV/dt_r   0.145/0.279n   0.142/0.335n   0.151/0.244n
dV/dt_f   0.181/0.273n   0.173/0.309n   0.189/0.233n
R_load = 50.000
[Rising Waveform]
R_fixture = 50.000
V_fixture = 0.000
V_fixture_min = 0.000
V_fixture_max = 0.000
|  time   V(typ)   V(min)   V(max)
0s        4.31uV     240uV      -223.7uV
423ps     149.4uV    383.1uV    -12.4mV
527ps     -8.738mV   -1.37mV    63.87mV
636ps     54.42mV    -6.034mV   149.6mV
775ps     145.1mV    50.3mV     206.3mV
918ps     196.5mV    124.1mV    230.7mV
1.131ns   226.2mV    188.5mV    243.9mV
1.42ns    236.9mV    216.9mV    249.1mV
4.105ns   242.2mV    228.2mV    251.8mV
30ns      242.3mV    228.6mV    251.8mV
[Rising Waveform]
R_fixture = 50.000
V_fixture = 0.440
V_fixture_min = 0.419
V_fixture_max = 0.463
|  time   V(typ)   V(min)   V(max)
0s        282.8mV    273.9mV    295.1mV
385ps     283.2mV    273.9mV    295.2mV
493ps     285.8mV    273.7mV    416.1mV
571ps     361.1mV    273.4mV    511.2mV
714ps     504.7mV    376.1mV    609.8mV
850ps     579.1mV    475.7mV    646.5mV
1.046ns   619.3mV    557.1mV    664.9mV
1.309ns   633.1mV    592mV      671.8mV
4.37ns    640.7mV    606.4mV    675.4mV
30ns      641.3mV    607.1mV    675.4mV
[Falling Waveform]
R_fixture = 50.000
V_fixture = 0.440
V_fixture_min = 0.419
V_fixture_max = 0.463
|  time   V(typ)   V(min)   V(max)
0s        641.4mV    607.1mV    675.4mV
366ps     641mV      607mV      678.5mV
461ps     645.5mV    607.1mV    558.7mV
566ps     539.6mV    613.9mV    416.5mV
682ps     413.4mV    519.4mV    342.2mV
789ps     343.2mV    417.4mV    315.8mV
945ps     302.2mV    326.8mV    302.6mV
1.133ns   288.8mV    288.9mV    298.1mV
2.361ns   283.1mV    274.4mV    295.1mV
30ns      282.8mV    273.9mV    295.1mV
[Falling Waveform]
R_fixture = 50.000
V_fixture = 0.000
V_fixture_min = 0.000
V_fixture_max = 0.000
|  time   V(typ)   V(min)   V(max)
0s        242.4mV    228.6mV    251.8mV
357ps     241.9mV    228.4mV    259.6mV
451ps     252.9mV    228.4mV    146.6mV
550ps     144.4mV    243.2mV    62.04mV
583ps     111.8mV    225.5mV    46.38mV
653ps     63.3mV     153.1mV    25.34mV
784ps     21.66mV    55.86mV    8.964mV
896ps     9.223mV    22.94mV    4.208mV
1.075ns   3.054mV    6.204mV    1.593mV
30ns      5.248uV    240uV      -223.7uV
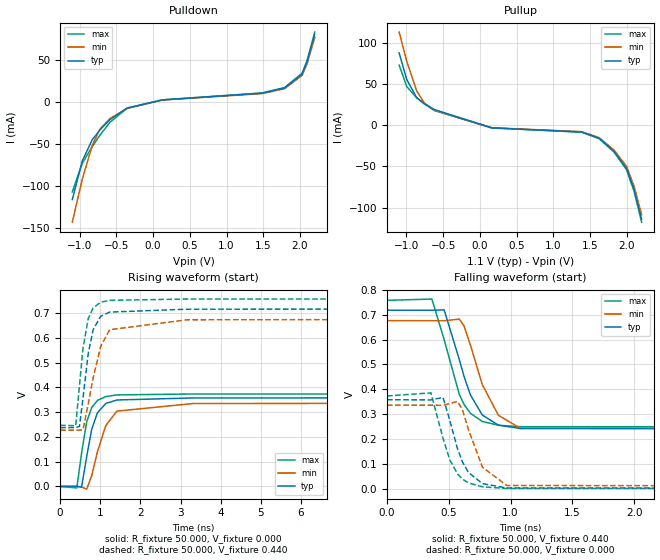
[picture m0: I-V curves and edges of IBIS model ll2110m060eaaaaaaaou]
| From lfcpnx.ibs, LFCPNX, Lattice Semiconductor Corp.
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|   Model ll2110m060eaaaaaaaou
[Model] ll2110m060eaaaaaaaou
Model_type Output
Polarity   Non-Inverting
Enable   Active-High
Vmeas =  0.220V
Cref =  30.000pF
Rref =  50.000
Vref =  0.220V
C_comp   5.000pF   4.000pF   5.500pF
[Temperature Range]   25.000   0.125k   -40.000
[Voltage Range]   1.100V   1.050V   1.160V
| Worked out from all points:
|   slope of the pulldown table from 0 to 0.165 V, typ, clamps not added: 56.9 ohm
|   slope of the pullup table from 0 to 0.165 V, typ, clamps not added: 54.8 ohm
|   rising waveform, R_fixture 50.000, V_fixture 0.000: 20-80 % time 280ps typ, 393ps min, 241ps max; typ from 0 V to 0.358 V
|   rising waveform, R_fixture 50.000, V_fixture 0.440: 20-80 % time 247ps typ, 375ps min, 211ps max; typ from 0.237 V to 0.718 V
|   falling waveform, R_fixture 50.000, V_fixture 0.440: 20-80 % time 187ps typ, 199ps min, 178ps max; typ from 0.718 V to 0.237 V
|   falling waveform, R_fixture 50.000, V_fixture 0.000: 20-80 % time 150ps typ, 159ps min, 144ps max; typ from 0.358 V to 0 V
[Pulldown]
|Voltage   I(typ)   I(min)   I(max)
-1.1V     -116.7mA   -143.6mA   -107.5mA
-964mV    -70.54mA   -92.38mA   -73.4mA
-828mV    -45.27mA   -51.91mA   -53.38mA
-726mV    -33.88mA   -32.9mA    -40.18mA
-590mV    -21.5mA    -20.07mA   -24.71mA
-352mV    -7.469mA   -7.881mA   -7.447mA
124mV     2.209mA    2.099mA    2.275mA
1.484V    10.27mA    9.758mA    10.58mA
1.79V     16.47mA    15.65mA    16.97mA
2.028V    33.09mA    31.44mA    34.09mA
2.096V    47.77mA    45.38mA    49.21mA
2.2V      80.7mA     76.67mA    83.12mA
[Pullup]
|Voltage   I(typ)   I(min)   I(max)
-1.1V     88.32mA    113.8mA    73.59mA
-996mV    55.91mA    77.94mA    47.28mA
-860mV    33.67mA    41.95mA    33.68mA
-758mV    26.63mA    27.31mA    26.33mA
-622mV    19.41mA    18.58mA    18.27mA
160mV     -2.933mA   -2.787mA   -3.021mA
1.384V    -7.973mA   -7.575mA   -8.213mA
1.622V    -15.55mA   -14.78mA   -16.02mA
1.826V    -31.65mA   -30.06mA   -32.6mA
1.996V    -52.64mA   -50.01mA   -54.22mA
2.098V    -78.11mA   -74.21mA   -80.45mA
2.2V      -114.5mA   -108.8mA   -117.9mA
[Ramp]
| variable   typ   min   max
dV/dt_r   0.215/0.279n   0.202/0.393n   0.224/0.240n
dV/dt_f   0.254/0.246n   0.247/0.268n   0.267/0.238n
R_load = 50.000
[Rising Waveform]
R_fixture = 50.000
V_fixture = 0.000
V_fixture_min = 0.000
V_fixture_max = 0.000
|  time   V(typ)   V(min)   V(max)
0s        3.587uV    95.7uV     -232.6uV
415ps     100.2uV    155.2uV    -6.349mV
533ps     -2.986mV   -2.387mV   133.6mV
661ps     120.4mV    -11.24mV   260.7mV
787ps     231.1mV    43.58mV    319mV
928ps     297.4mV    140mV      347.4mV
1.14ns    335.5mV    246.7mV    363.3mV
1.414ns   349.3mV    304.3mV    369.8mV
3.323ns   357.6mV    335.2mV    373.6mV
30ns      358.4mV    336.9mV    373.6mV
[Rising Waveform]
R_fixture = 50.000
V_fixture = 0.440
V_fixture_min = 0.419
V_fixture_max = 0.463
|  time   V(typ)   V(min)   V(max)
0s        237.2mV    227.2mV    246.7mV
387ps     237.8mV    227.2mV    245.5mV
481ps     242.6mV    227.6mV    406.6mV
568ps     355mV      228.4mV    558mV
699ps     536.9mV    332.4mV    677.7mV
820ps     632.5mV    436.9mV    721.2mV
1.009ns   687.7mV    565.4mV    744.5mV
1.234ns   704.6mV    633.5mV    752.4mV
3.16ns    716.4mV    673.6mV    757.3mV
30ns      717.7mV    675.6mV    757.3mV
[Falling Waveform]
R_fixture = 50.000
V_fixture = 0.440
V_fixture_min = 0.419
V_fixture_max = 0.463
|  time   V(typ)   V(min)   V(max)
0s        717.7mV    675.7mV    757.3mV
363ps     717.3mV    675.4mV    762.3mV
462ps     719.1mV    675.4mV    599.7mV
585ps     519.2mV    681.8mV    379.6mV
624ps     450.6mV    653.4mV    338.9mV
675ps     377.6mV    577.3mV    303.9mV
771ps     296.9mV    419.1mV    271.2mV
901ps     256.7mV    296.1mV    256.1mV
1.079ns   243mV      244mV      250.4mV
30ns      237.2mV    227.2mV    246.7mV
[Falling Waveform]
R_fixture = 50.000
V_fixture = 0.000
V_fixture_min = 0.000
V_fixture_max = 0.000
|  time   V(typ)   V(min)   V(max)
0s        358.5mV    337mV      373.6mV
355ps     357.7mV    336.5mV    386mV
453ps     367.9mV    336.3mV    203.9mV
508ps     275.4mV    343.2mV    117.2mV
570ps     161.9mV    351.9mV    61.01mV
610ps     109.4mV    318.9mV    40.33mV
659ps     66.84mV    238.6mV    24.8mV
772ps     21.98mV    87.9mV     9.199mV
969ps     4.689mV    14.49mV    2.659mV
30ns      5.291uV    102.2uV    -232.6uV
